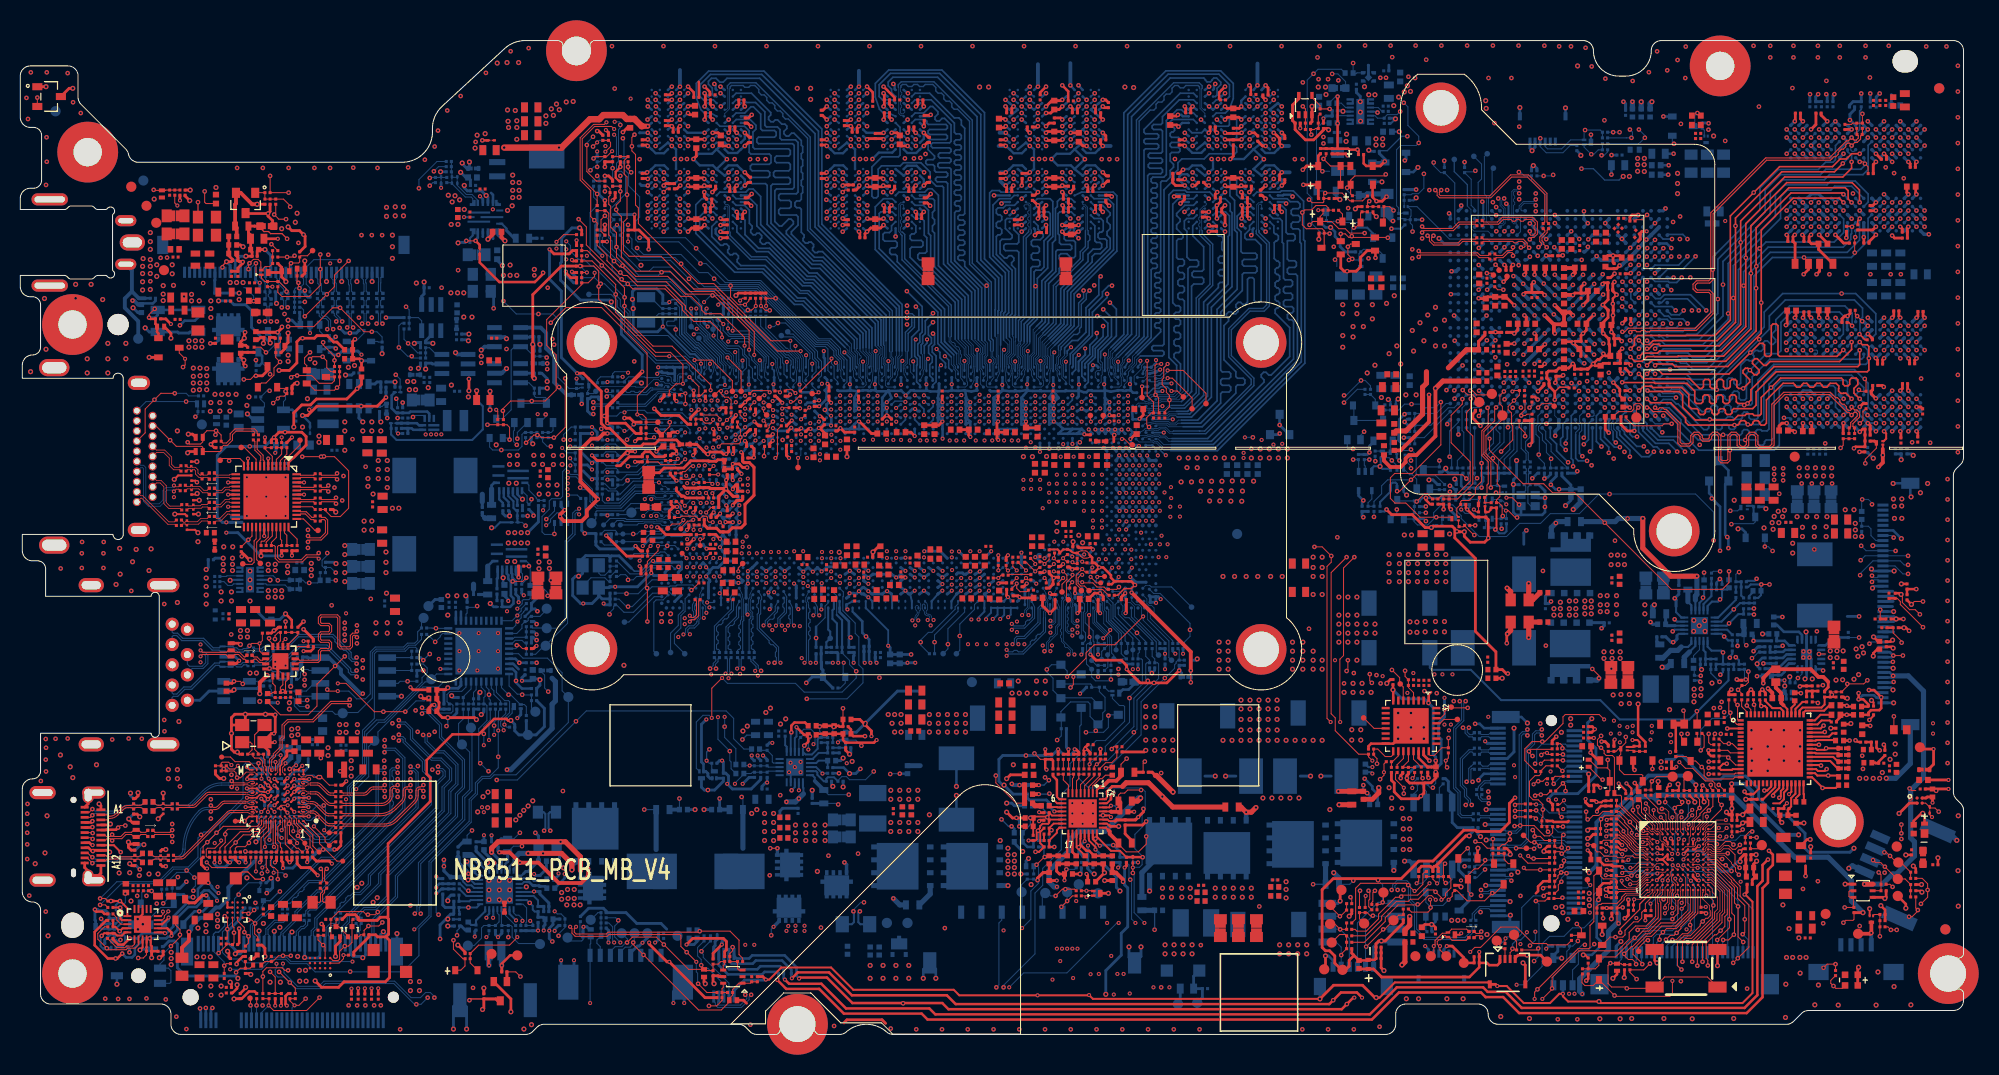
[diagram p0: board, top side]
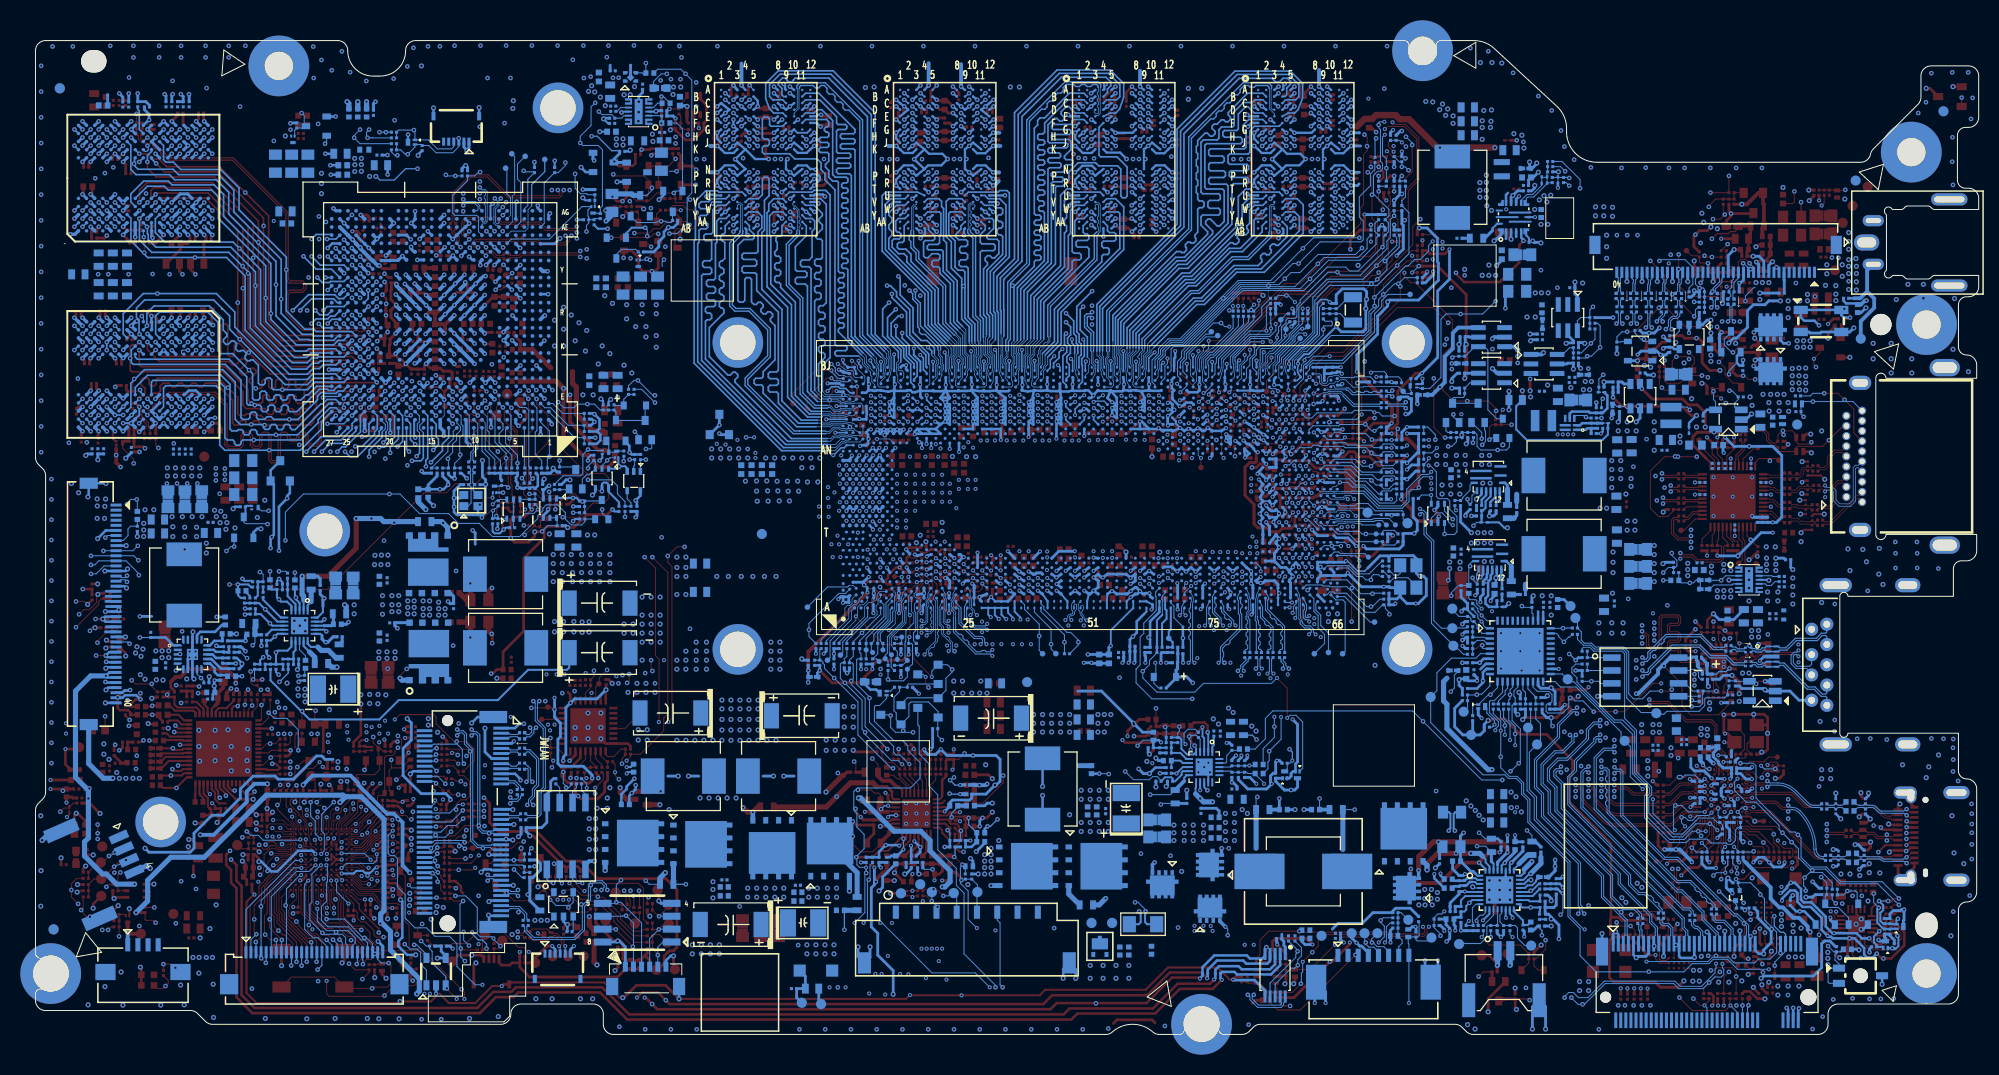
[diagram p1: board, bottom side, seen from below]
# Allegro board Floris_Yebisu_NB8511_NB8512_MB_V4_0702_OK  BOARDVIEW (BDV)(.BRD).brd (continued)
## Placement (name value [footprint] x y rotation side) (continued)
PR634  0201WMF1002TCE~~MCR006YRTF1002~~WR02X1002FAL~~RC0201FR-0710KL  [R0201]  101.22 19.12 0 bottom
PR635  res  [R0402]  99.44 22.81 0 top
PR636  0402WGJ0000TCE+0402WGJ0000TJE~~RC1005J000CS~~RC0402JR-070RL+RC0402JR-130RL~~RM04JTN0  [R0402_0D65]  101.09 22.55 0 top
PR637  0402WGJ0101TCE~~RC0402JR-07100RL~~RM04JTN101~~RC1005J101CS  [R0402]  99.5 21.35 180 top
PR638  0402WGJ0000TCE+0402WGJ0000TJE~~RC1005J000CS~~RC0402JR-070RL+RC0402JR-130RL~~RM04JTN0  [R0402_0D65]  99.5 20.52 180 top
PR639  0603WAF220KT5E~~RC0603FR-072R2L  [R0603]  131.32 23.31 270 top
PR640  res  [R0402]  107.69 15.57 270 top
PR641  res  [R0402]  105.92 17.22 270 top
PR642  res  [R0402]  107.69 17.22 270 top
PR643  0402WGF6800TCE~~RC0402FR-07680RL~~RM04FTN6800  [R0402]  105.03 17.22 90 top
PR644  0603WAF220KT5E~~RC0603FR-072R2L  [R0603]  110.62 12.9 90 bottom
PR645  res  [R0402]  101.47 15.57 270 top
PR646  res  [R0402]  102.36 17.22 270 top
PR647  res  [R0402]  101.47 17.22 270 top
PR648  0402WGF6800TCE~~RC0402FR-07680RL~~RM04FTN6800  [R0402]  104.14 17.22 90 top
PR649  0201WMJ0000TCE+0201WMJ0000TJE~~MCR006YRTJ000~~RC0201JR-070RL+RC0201JR-130RL~~WR02X000PAL  [R0201]  105.41 25.92 270 top
PR650  0402WGF1002TCE~~RM04FTN1002~~RC0402FR-0710KL  [R0402]  99.44 23.7 180 top
PR651  0402WGF2001TCE~~RC1005F202CS~~RC0402FR-072KL~~RM04FTN2001  [R0402]  99.44 24.58 180 top
PR652  0201WMF3302TCE+0201WMF3302TEE~~MCR006YRTF3302~~RC0201FR-0733KL~~WR02X3302FAL  [R0201]  99.74 24.61 0 bottom
PR653  0201WGF1302TCE~~RC0201FR-0713KL  [R0201]  99.57 23.7 0 bottom
PR654  MCR006YRTF1003~~RC0201FR-07100KL~~WR02X1003FAL~~0201WMF1003TCE+0201WMF1003TEE  [R0201]  109.73 17.22 270 bottom
PR655  0201WMJ0101TCE~~MCR006YRTJ101~~RC0201JR_07100RL~~WR02X101 JAL  [R0201]  107.03 27.4 90 top
PR656  0201WMJ0000TCE+0201WMJ0000TJE~~MCR006YRTJ000~~RC0201JR-070RL+RC0201JR-130RL~~WR02X000PAL  [R0201]  105.92 25.92 270 top
PR657  0201WMJ0000TCE+0201WMJ0000TJE~~MCR006YRTJ000~~RC0201JR-070RL+RC0201JR-130RL~~WR02X000PAL  [R0201]  106.42 25.92 270 top
PR658  0201WMF430JTCE~~RC0201FR-0743RL  [R0201]  106.02 27.4 90 top
PR659  SHUNT_LOCAL  [SHUNT_0201]  109.73 17.22 90 top
PR660  0201WMJ0000TCE+0201WMJ0000TJE~~MCR006YRTJ000~~RC0201JR-070RL+RC0201JR-130RL~~WR02X000PAL  [R0201]  101.85 25.92 270 top
PR661  0201WMF1100TCE~~RC0201FR-07110RL  [R0201]  108.41 28.37 0 top
PR662  0201WMJ0000TCE+0201WMJ0000TJE~~MCR006YRTJ000~~RC0201JR-070RL+RC0201JR-130RL~~WR02X000PAL  [R0201]  101.22 19.76 180 top
PR663  0201WMJ0000TCE+0201WMJ0000TJE~~MCR006YRTJ000~~RC0201JR-070RL+RC0201JR-130RL~~WR02X000PAL  [R0201]  101.22 18.49 180 bottom
PR664  0201WMJ0000TCE+0201WMJ0000TJE~~MCR006YRTJ000~~RC0201JR-070RL+RC0201JR-130RL~~WR02X000PAL  [R0201]  100.18 19.12 180 bottom
PR702  0201WMJ0000TCE+0201WMJ0000TJE~~MCR006YRTJ000~~RC0201JR-070RL+RC0201JR-130RL~~WR02X000PAL  [R0201]  42.06 84.25 270 bottom
PR703  SHUNT_LOCAL  [SHUNT_0201]  43.1 84.25 270 bottom
PR704  0603WAJ047JT5E~~RC0603JR-074R7L  [R0603]  49.53 78.51 0 bottom
PR705  0201WMJ0104TCE+0201WMJ0104TEE~~MCR006YRTJ104~~RC0201JR-07100KL~~WR02X104JAL  [R0201]  40.94 84.25 270 bottom
PR706  SHUNT_LOCAL  [SHUNT_0201]  41.5 84.25 270 bottom
PR707  SHUNT_LOCAL  [SHUNT_0201]  42.57 84.25 270 bottom
PR708  0201WMJ0000TCE+0201WMJ0000TJE~~MCR006YRTJ000~~RC0201JR-070RL+RC0201JR-130RL~~WR02X000PAL  [R0201]  42.26 86.08 0 bottom
PR709  0201WMJ0000TCE+0201WMJ0000TJE~~MCR006YRTJ000~~RC0201JR-070RL+RC0201JR-130RL~~WR02X000PAL  [R0201]  42.26 85.57 0 bottom
PR712  0201WMJ0104TCE~~MCR006YRTJ104~~RC0201JR-07100KL~~WR02X104JAL  [R0201]  42.26 85.06 180 bottom
PR814  0603WAJ010JT5E~~RC1608J1R0CS~~RC0603JR-071RL~~RM06JTN1R0  [R0603]  153.26 50.57 180 bottom
PR815  0603WAJ010JT5E~~RC1608J1R0CS~~RC0603JR-071RL~~RM06JTN1R0  [R0603]  164.46 44.52 90 bottom
PR816  0603WAF220KT5E~~RC0603FR-072R2L  [R0603]  161.67 41.48 180 bottom
PR817  0603WAF220KT5E~~RC0603FR-072R2L  [R0603]  170.6 40.52 0 bottom
PR818  0201WMJ0474TCE+0201WMJ0474TEE~~MCR006YRTJ474~~RC0201JR-07470KL~~WR02X474 JAL  [R0201]  169.1 39.41 0 bottom
PR819  0402WGJ0000TCE+0402WGJ0000TJE~~RC1005J000CS~~RC0402JR-070RL+RC0402JR-130RL~~RM04JTN0  [R0402_0D65]  165.02 36.5 90 bottom
PR820  0402WGJ0000TCE+0402WGJ0000TJE~~RC1005J000CS~~RC0402JR-070RL+RC0402JR-130RL~~RM04JTN0  [R0402_0D65]  166.06 44.42 270 bottom
PR821  0201WMF1002TCE~~MCR006YRTF1002~~WR02X1002FAL~~RC0201FR-0710KL  [R0201]  165.11 35.16 270 bottom
PR822  0201WMJ0104TCE~~MCR006YRTJ104~~RC0201JR-07100KL~~WR02X104JAL  [R0201]  167.04 44.41 180 bottom
PR823  0402WGJ0000TCE+0402WGJ0000TJE~~RC1005J000CS~~RC0402JR-070RL+RC0402JR-130RL~~RM04JTN0  [R0402_0D65]  168.52 44.44 270 bottom
PR824  RC0201FR-0720K5L~#~0201WMF2052TCE  [R0201]  170.21 41.98 180 bottom
PR825  0201WMJ0000TJE~#~RC0201JR-130RL~#~MCR006YRTJ000~#~RC0201JR-070RL~#~RC0201JR-070RL/RC0201JR-130RL~#~RC0201JR-130RL/RC0201JR-070RL~#~WR02X000PAL  [R0201]  169.98 44.64 0 bottom
PR826  RC0201FR-074K32L~#~0201WMF4321TEE~#~RC-01W4321FT  [R0201]  169.96 42.79 90 bottom
PR827  RC0201FR-07100RL~~WR02X1000FAL~~0201WMF1000TCE~~MCR006YRTF1000  [R0201]  168.47 36.25 270 bottom
PR828  RC0402FR-07309RL~#~0402WGF3090TCE  [R0402]  171.28 43.74 180 bottom
PR829  0201WMJ0000TJE~#~RC0201JR-130RL~#~MCR006YRTJ000~#~RC0201JR-070RL~#~RC0201JR-070RL/RC0201JR-130RL~#~RC0201JR-130RL/RC0201JR-070RL~#~WR02X000PAL  [R0201]  169.2 44.38 90 bottom
PR830  0201WMF6191TCE~#~RC0201FR-076K19L~#~WR02X6191FAL~#~0201WMF6191TCE+0201WMF6191TEE~#~MCR006YRTF6191  [R0201]  169.2 43.34 270 bottom
PR833  RC0805FR-071R5L~~0805W8F150KT5E~~RM10FTN1R50  [R0805]  147.88 42.85 180 top
PR835  0201WMJ0000TCE+0201WMJ0000TJE~~MCR006YRTJ000~~RC0201JR-070RL+RC0201JR-130RL~~WR02X000PAL  [R0201]  166.8 45.24 90 bottom
PR836  RC0201FR-07100RL~~WR02X1000FAL~~0201WMF1000TCE~~MCR006YRTF1000  [R0201]  169.1 38.85 0 bottom
PR837  0201WMJ0000TCE+0201WMJ0000TJE~~MCR006YRTJ000~~RC0201JR-070RL+RC0201JR-130RL~~WR02X000PAL  [R0201]  168.85 38.06 90 bottom
PR838  0201WMJ0000TCE+0201WMJ0000TJE~~MCR006YRTJ000~~RC0201JR-070RL+RC0201JR-130RL~~WR02X000PAL  [R0201]  169.25 36.51 180 bottom
PR839  RC0201FR-0716K5L~#~0201WMF1652TCE+0201WMF1652TEE  [R0201]  170.51 42.79 270 bottom
PR848  0603WAJ010JT5E~~RC1608J1R0CS~~RC0603JR-071RL~~RM06JTN1R0  [R0603]  163.45 36.57 180 bottom
PR849  0603WAJ010JT5E~~RC1608J1R0CS~~RC0603JR-071RL~~RM06JTN1R0  [R0603]  161.7 37.8 90 bottom
PR850  RC0805FR-071R5L~~0805W8F150KT5E~~RM10FTN1R50  [R0805]  147.88 40.66 180 top
PR852  0201WMF1503TCE+0201WMF1503TEE~~WR02X1503FAL~~MCR006YRTF1503~~RC0201FR-07150KL  [R0201]  165.95 36.49 0 bottom
PR859  0201WMJ0513TCE~~MCR006YRTJ513~~RC0201JR-0751KL~~WR02X513JAL  [R0201]  166.72 36.76 270 bottom
PR860  RC0201FR-07100RL~~WR02X1000FAL~~0201WMF1000TCE~~MCR006YRTF1000  [R0201]  167.93 36.25 90 bottom
PR861  0201WMJ0513TCE~~MCR006YRTJ513~~RC0201JR-0751KL~~WR02X513JAL  [R0201]  169.25 35.98 0 bottom
PR901  MCR006YRTF1003~~RC0201FR-07100KL~~WR02X1003FAL~~0201WMF1003TCE  [R0201]  68.45 26.74 0 bottom
PR902  MCR006YRTF1003~~RC0201FR-07100KL~~WR02X1003FAL~~0201WMF1003TCE  [R0201]  69.34 25.51 90 bottom
PR903  0201WMJ0105TCE~~MCR006YRTJ105~~RC0201JR-071ML~~WR02X105JAL  [R0201]  50.95 63.73 180 bottom
PR904  0201WMJ0000TCE+0201WMJ0000TJE~~MCR006YRTJ000~~RC0201JR-070RL+RC0201JR-130RL~~WR02X000PAL  [R0201]  39.72 66.7 0 bottom
PR905  0402WGJ0000TCE+0402WGJ0000TJE~~RC1005J000CS~~RC0402JR-070RL+RC0402JR-130RL~~RM04JTN0  [R0402_0D65]  43.08 71.55 270 bottom
PR906  0201WMJ0000TCE+0201WMJ0000TJE~~MCR006YRTJ000~~RC0201JR-070RL+RC0201JR-130RL~~WR02X000PAL  [R0201]  47.09 60.37 270 top
PR907  0201WMJ0103TCE+0201WMJ0103TJE~~MCR006YRTJ103~~RC0201JR-0710KL~~WR02X103JAL  [R0201]  50.7 67.13 90 bottom
PR909  0201WMJ0000TCE+0201WMJ0000TJE~~MCR006YRTJ000~~RC0201JR-070RL+RC0201JR-130RL~~WR02X000PAL  [R0201]  38.1 70.13 0 bottom
PR910  0201WMJ0000TCE+0201WMJ0000TJE~~MCR006YRTJ000~~RC0201JR-070RL+RC0201JR-130RL~~WR02X000PAL  [R0201]  50.95 59.1 90 bottom
PR911  SHUNT_LOCAL  [SHUNT_0402]  27.46 43.91 90 bottom
PR912  0201WMJ0000TCE+0201WMJ0000TJE~~MCR006YRTJ000~~RC0201JR-070RL+RC0201JR-130RL~~WR02X000PAL  [R0201]  29.84 45.54 180 bottom
PR913  0402WGJ0000TCE+0402WGJ0000TJE~~RC1005J000CS~~RC0402JR-070RL+RC0402JR-130RL~~RM04JTN0  [R0402_0D65]  29.97 44.78 180 bottom
PR914  0201WMJ0104TCE~~MCR006YRTJ104~~RC0201JR-07100KL~~WR02X104JAL  [R0201]  30.1 46.3 270 bottom
PR915  SHUNT_LOCAL  [SHUNT_0402]  27.46 44.8 90 bottom
PR916  0201WMJ0000TCE+0201WMJ0000TJE~~MCR006YRTJ000~~RC0201JR-070RL+RC0201JR-130RL~~WR02X000PAL  [R0201]  49.83 59.1 90 bottom
PR917  0201WMJ0000TCE+0201WMJ0000TJE~~MCR006YRTJ000~~RC0201JR-070RL+RC0201JR-130RL~~WR02X000PAL  [R0201]  47.65 60.37 270 top
PR918  0201WMJ0000TCE+0201WMJ0000TJE~~MCR006YRTJ000~~RC0201JR-070RL+RC0201JR-130RL~~WR02X000PAL  [R0201]  52.07 59.1 90 bottom
PR919  0201WMJ0000TCE+0201WMJ0000TJE~~MCR006YRTJ000~~RC0201JR-070RL+RC0201JR-130RL~~WR02X000PAL  [R0201]  51.51 59.1 90 bottom
PR920  0201WMJ0000TCE+0201WMJ0000TJE~~MCR006YRTJ000~~RC0201JR-070RL+RC0201JR-130RL~~WR02X000PAL  [R0201]  39.72 67.21 0 bottom
PR921  0201WMJ0000TCE+0201WMJ0000TJE~~MCR006YRTJ000~~RC0201JR-070RL+RC0201JR-130RL~~WR02X000PAL  [R0201]  38.1 69.57 0 bottom
PR930  SHUNT_LOCAL  [SHUNT_0201]  188.31 22.15 90 top
PR1012  0201WMJ0104TCE~~MCR006YRTJ104~~RC0201JR-07100KL~~WR02X104JAL  [R0201]  13.59 70.56 0 top
PR1013  0201WMJ0104TCE~~MCR006YRTJ104~~RC0201JR-07100KL~~WR02X104JAL  [R0201]  15.24 14.42 0 bottom
PR1101  0402WGJ0000TCE+0402WGJ0000TJE~~RC1005J000CS~~RC0402JR-070RL+RC0402JR-130RL~~RM04JTN0  [R0402_0D65]  172.31 35.33 0 bottom
PR1102  0201WMF1002TCE~~MCR006YRTF1002~~WR02X1002FAL~~RC0201FR-0710KL  [R0201]  172.33 37.12 180 bottom
PR1103  0201WMF1002TCE~~MCR006YRTF1002~~WR02X1002FAL~~RC0201FR-0710KL  [R0201]  173.19 36.87 90 bottom
PR1104  0402WGJ0000TCE+0402WGJ0000TJE~~RC1005J000CS~~RC0402JR-070RL+RC0402JR-130RL~~RM04JTN0  [R0402_0D65]  172.85 39.49 180 bottom
PR1105  0201WMF1002TCE~~MCR006YRTF1002~~WR02X1002FAL~~RC0201FR-0710KL  [R0201]  174.79 34.67 180 bottom
PR1107  0201WMF1002TCE~~MCR006YRTF1002~~WR02X1002FAL~~RC0201FR-0710KL  [R0201]  171.82 36.06 180 bottom
PR1108  RC0201FR-0716KL~~0201WMF1602TCE+0201WMF1602TEE  [R0201]  173.1 37.98 270 bottom
PR1109  MCR006YRTF2002~~RC0201FR-0720KL~~0201WMF2002TCE+0201WMF2002TEE~~WR02X2002FAL  [R0201]  172.32 38.23 0 bottom
PR1111  0201WMF1002TCE~~MCR006YRTF1002~~WR02X1002FAL~~RC0201FR-0710KL  [R0201]  172.61 36.33 270 bottom
PR1150  CC0201KRX5R8BB103+CC0201KRX7R8BB103~~C0201X5R103K250NTA~~0201X103K250NT  [C0201]  171.53 37.97 90 bottom
PR1201  0201WMJ0104TCE~~MCR006YRTJ104~~RC0201JR-07100KL~~WR02X104JAL  [R0201]  129.64 90.56 180 bottom
PR1202  0402WGJ0000TCE+0402WGJ0000TJE~~RC1005J000CS~~RC0402JR-070RL+RC0402JR-130RL~~RM04JTN0  [R0402_0D65]  129.48 89.88 0 bottom
PR1203  0402WGJ0000TCE+0402WGJ0000TJE~~RC1005J000CS~~RC0402JR-070RL+RC0402JR-130RL~~RM04JTN0  [R0402_0D65]  131.06 94.8 0 bottom
PR1204  RC1608J000CS~~RC0603JR-070RL~~RM06JTN0~~0603WAJ0000T5E  [R0603]  132.27 88.11 0 bottom
PR1206  0402WGJ0000TCE+0402WGJ0000TJE~~RC1005J000CS~~RC0402JR-070RL+RC0402JR-130RL~~RM04JTN0  [R0402_0D65]  129.46 91.83 0 bottom
PR1207  SHUNT_LOCAL  [SHUNT_0603]  130.63 93.32 90 bottom
PR6157  0201WMJ0106TCE//RC0201JR-0710ML~~RC0201JR-0710ML  [R0201]  14.02 8.4 90 bottom
PRT501  NCP15XH103F03RC  [R0402_NTC_0D55]  87.5 26.11 90 bottom
PRT601  NCP15WF104F03RC~~SDNT1005X104F4250FTF  [R0402_NTC_0D65]  133.48 22.68 0 bottom
PRT602  NCP15WF104F03RC~~SDNT1005X104F4250FTF  [R0402_NTC_0D65]  132.66 26.26 90 bottom
PSH101  SHUNT_LOCAL  [SHUNT_0402]  47.75 12.11 180 top
PSH104  SHUNT_LOCAL  [SHUNT_0805]  15.31 78.94 0 top
PSH105  SHUNT_LOCAL  [SHUNT_0805]  15.31 80.72 0 top
PSH201  SHUNT_LOCAL  [SHUNT_0805]  51.05 44.27 90 top
PSH202  SHUNT_LOCAL  [SHUNT_0805]  52.83 44.27 90 top
PSH203  SHUNT_LOCAL  [SHUNT_0805]  33.6 46.15 180 bottom
PSH204  SHUNT_LOCAL  [SHUNT_0805]  33.6 47.83 180 bottom
PSH205  SHUNT_LOCAL  [SHUNT_0805]  33.6 44.47 180 bottom
PSH206  SHUNT_LOCAL  [SHUNT_0201]  47.27 42.16 180 bottom
PSH306  SHUNT_LOCAL  [SHUNT_0201]  48.77 50.49 180 bottom
PSH401  SHUNT_LOCAL  [SHUNT_0201]  36.84 60.27 180 bottom
PSH402  SHUNT_LOCAL  [SHUNT_0201]  28.57 59.59 270 bottom
PSH403  SHUNT_LOCAL  [SHUNT_0805]  39.5 62.56 0 bottom
PSH404  SHUNT_LOCAL  [SHUNT_0805]  29.59 65.1 0 bottom
PSH501  SHUNT_LOCAL  [SHUNT_0805]  81.02 21.16 180 bottom
PSH502  SHUNT_LOCAL  [SHUNT_0805]  81.02 19.48 180 bottom
PSH601  SHUNT_LOCAL  [SHUNT_0805]  118.36 10.49 270 top
PSH602  SHUNT_LOCAL  [SHUNT_0805]  120.14 10.49 270 top
PSH603  SHUNT_LOCAL  [SHUNT_0805]  121.92 10.49 270 top
PSH706  LOCAL_SHUNT  [SHUNT_0402]  44.3 85.39 270 bottom
PSH707  SHUNT_LOCAL  [SHUNT_0805]  45.01 76.88 180 bottom
PSH708  SHUNT_LOCAL  [SHUNT_0201]  45.31 77.24 90 top
PSH709  SHUNT_LOCAL  [SHUNT_0201]  46.43 88.16 180 top
PSH806  LOCAL_SHUNT  [SHUNT_0805]  160.32 44.27 270 bottom
PSH807  LOCAL_SHUNT  [SHUNT_0805]  158.55 35.45 270 top
PSH808  LOCAL_SHUNT  [SHUNT_0805]  156.87 35.45 270 top
PSH809  LOCAL_SHUNT  [SHUNT_0805]  162.05 44.27 270 bottom
PSH901  SHUNT_LOCAL  [SHUNT_0402]  50.65 66.16 270 bottom
PSH902  SHUNT_LOCAL  [SHUNT_0402]  39.32 65.05 90 bottom
PSH903  SHUNT_LOCAL  [SHUNT_0402]  54.48 63.07 270 bottom
PSH904  SHUNT_LOCAL  [SHUNT_0402]  43.03 69.67 0 bottom
PSH930  SHUNT_LOCAL  [SHUNT_0402]  187.4 26.11 90 top
PSH1101  LOCAL_SHUNT  [SHUNT_0805]  175.26 52.78 90 bottom
PSH1102  LOCAL_SHUNT  [SHUNT_0805]  176.91 52.78 90 bottom
PSH1103  LOCAL_SHUNT  [SHUNT_0805]  178.88 39.43 270 top
PSH1104  LOCAL_SHUNT  [SHUNT_0805]  178.59 52.78 90 bottom
PTP101  40MIL  [TPAD40-OP]  101.09 13.94 180 bottom
PTP102  40MIL  [TPAD40-OP]  98.75 14.04 180 bottom
PTP103  40MIL  [TPAD40-OP]  103.25 14.04 270 bottom
PTP104  40MIL  [TPC1]  51.26 8.91 180 bottom
PTP105  40MIL  [TPAD40-OP]  106.3 13.92 180 bottom
PTP106  40MIL  [TPAD40-OP]  104.39 14.81 180 bottom
PTP107  40MIL  [TPAD40-OP]  87.5 11 180 bottom
PTP108  40MIL  [TPAD40-OP]  85.47 11 180 bottom
PTP109  40MIL  [TPC1]  44.14 8.76 180 bottom
PU101  BQ25710RSNR  [NB_QFN32_4X4X1]  47.25 14.25 180 bottom
PU201  RT6258BGQUF  [NB_QFN12_3X3X0D6]  48.21 47.29 0 bottom
PU301  RT6258CGQUF  [NB_QFN12_3X3X0D6]  48.36 55.01 0 bottom
PU401  SY8843QWC  [NB_QFN7_1D5X1D5X0D9]  40.33 60.14 0 bottom
PU402  RT8096CHGJ6  [NB_TSOT23_6_3D1X1D7X1]  33.4 62.94 180 bottom
PU501  RT6543A  [NB_QFN20_3X3X0D8]  76.39 26.36 270 bottom
PU601  RT3612  [NB_QFN32_4X4X0D8]  104.77 21.79 270 top
PU701  TPS51487XRJER  [NB_VQFN18_3X3X1]  45.87 80.59 90 bottom
PU802  RT8816AGQW  [NB_QFN20_3X3X0D8]  165.61 40.31 270 bottom
PU901  EM5201BJ-45  [NB_SOT23_6_2D9X1D6X1D45]  48.05 65.2 0 bottom
PU902  G2898KD1U  [NB_TDF14_3X2X0D8]  22.65 44.83 270 bottom
PU903  EM5201BJ-45  [NB_SOT23_6_2D9X1D6X1D45]  42.87 66.11 180 bottom
PU904  EM5201BJ-45  [NB_SOT23_6_2D9X1D6X1D45]  48.05 68.76 0 bottom
PU906  EM5201BJ-45  [NB_SOT23_6_2D9X1D6X1D45]  40.53 70.68 270 bottom
PU910  SGM2578YG/TR  [BGA4_0D9X0D9X0D405_0D5]  187.32 23.06 0 top
PU1101  SY8286A  [NB_QFN20_3X3X0D9_0D45_SY8286]  176.17 37.47 180 bottom
PU1201  G2898KDIU  [NB_TDF14_3X2X0D8]  132.16 91 90 bottom
PU1202  WL2831D10-4/TR  [NB_DFN5_1D2X1D2X0D4]  132.96 94.45 180 bottom
QA1  LBSS139DW1T1G  [NB_SOT363_2X1D25X1D1]  181.74 14.17 270 top
QE2  LMN2500N3T5G  [NB_SOT883_1D05X0D65X0D53]  182.56 11.38 180 top
QE3  LBSS139DW1T1G  [NB_SOT363_2X1D25X1D1]  70.28 5.7 90 top
QE4  2N7002~~2N7002LT1G~~L2N7002LT1G  [SOT-23_3_2D9X1D3X1D11]  154.99 9.78 270 top
QL1  2N7002~~2N7002LT1G~~L2N7002LT1G  [SOT-23_3_2D9X1D3X1D11]  14.65 67.71 90 top
QL4  2N7002~~2N7002LT1G~~L2N7002LT1G  [SOT-23_3_2D9X1D3X1D11]  156.77 25.98 0 top
QL6  2N7002~~2N7002LT1G~~L2N7002LT1G  [SOT-23_3_2D9X1D3X1D11]  160.02 25.98 0 top
QL7  2N7002~~2N7002LT1G~~L2N7002LT1G  [SOT-23_3_2D9X1D3X1D11]  11.89 11.86 0 bottom
QL8  2N7002~~2N7002LT1G~~L2N7002LT1G  [SOT-23_3_2D9X1D3X1D11]  15.14 11.86 0 bottom
QL9  LMN2500N3T5G  [NB_SOT883_1D05X0D65X0D53]  158.17 28.18 90 top
QL10  2N7002~~2N7002LT1G~~L2N7002LT1G  [SOT-23_3_2D9X1D3X1D11]  16.25 12.32 180 top
QS1  LMBT3904LT1G  [NB_SOT-23_3_2D9X1D3X1D11]  167.51 55.57 0 bottom
QS2  LMBT3904LT1G  [NB_SOT-23_3_2D9X1D3X1D11]  124.2 60.14 0 bottom
QT1  WNM2046-3/TR  [DFN1006_3_1X0D6X0D5]  49.02 32.33 270 bottom
QT2  WNM3013-3/TR  [NB_SOT-723_3_1D2X0D8X0D55]  23.98 13.69 90 bottom
QT3  WNM3013-3/TR  [NB_SOT-723_3_1D2X0D8X0D55]  23.37 7.34 270 top
QT4  WNM3013-3/TR  [NB_SOT-723_3_1D2X0D8X0D55]  32.71 10.13 270 top
QT5  WNM3013-3/TR  [NB_SOT-723_3_1D2X0D8X0D55]  31.14 10.13 270 top
QU1  LBSS139DW1T1G  [NB_SOT363_2X1D25X1D1]  53.34 51.38 180 bottom
QU2  LMN2500N3T5G  [NB_SOT883_1D05X0D65X0D53]  55.75 63.95 90 bottom
QU4  LMBT3904LT1G  [NB_SOT-23_3_2D9X1D3X1D11]  107.29 31.52 270 bottom
QU5  LMBT3904LT1G  [NB_SOT-23_3_2D9X1D3X1D11]  103.63 35.51 270 bottom
QU6  LMBT3904LT1G  [NB_SOT-23_3_2D9X1D3X1D11]  103.63 32.2 270 bottom
QU7  WNM2046-3/TR  [DFN1006_3_1X0D6X0D5]  108.05 33.65 90 bottom
QV1  LMN2500N3T5G  [NB_SOT883_1D05X0D65X0D53]  136.66 81.31 0 bottom
QV2  LMN2500N3T5G  [NB_SOT883_1D05X0D65X0D53]  141.51 50.86 90 top
QV3  LBSS139DW1T1G  [NB_SOT363_2X1D25X1D1]  144.52 51.8 180 bottom
QV4  LBSS139DW1T1G  [NB_SOT363_2X1D25X1D1]  135.78 54.83 0 bottom
QV5  LMN2500N3T5G  [NB_SOT883_1D05X0D65X0D53]  144.14 52.26 90 top
QV6  LBSS139DW1T1G  [NB_SOT363_2X1D25X1D1]  140.92 51.89 0 bottom
QV7  2N7002~~2N7002LT1G~~L2N7002LT1G  [SOT-23_3_2D9X1D3X1D11]  134.4 59.56 0 bottom
QV8  LMN2500N3T5G  [NB_SOT883_1D05X0D65X0D53]  134.34 57.19 180 bottom
QV9  LMN2500N3T5G  [NB_SOT883_1D05X0D65X0D53]  132.21 76.05 0 bottom
QV10  LMN2500N3T5G  [NB_SOT883_1D05X0D65X0D53]  170.01 51.95 270 bottom
QV11  2N7002~~2N7002LT1G~~L2N7002LT1G  [SOT-23_3_2D9X1D3X1D11]  132.32 85.02 90 bottom
QV12  2N7002~~2N7002LT1G~~L2N7002LT1G  [SOT-23_3_2D9X1D3X1D11]  134.36 77.54 180 bottom
QV14  2N7002~~2N7002LT1G~~L2N7002LT1G  [SOT-23_3_2D9X1D3X1D11]  135.64 85.98 90 bottom
QV17  LMN2500N3T5G  [NB_SOT883_1D05X0D65X0D53]  166.26 88.26 0 bottom
QV18  2N7002~~2N7002LT1G~~L2N7002LT1G  [SOT-23_3_2D9X1D3X1D11]  132.01 81.71 0 bottom
QV19  2N7002~~2N7002LT1G~~L2N7002LT1G  [SOT-23_3_2D9X1D3X1D11]  163.96 89.57 270 bottom
QV20  2N7002~~2N7002LT1G~~L2N7002LT1G  [SOT-23_3_2D9X1D3X1D11]  128.79 82.14 180 bottom
QV21  LMN2500N3T5G  [NB_SOT883_1D05X0D65X0D53]  183.37 58.33 90 top
QV22  2N7002~~2N7002LT1G~~L2N7002LT1G  [SOT-23_3_2D9X1D3X1D11]  171.11 50 0 bottom
QV23  LMN2500N3T5G  [NB_SOT883_1D05X0D65X0D53]  135.43 57.41 270 bottom
QV24  LMN2500N3T5G  [NB_SOT883_1D05X0D65X0D53]  146.37 53.75 180 bottom
QW2  2N7002~~2N7002LT1G~~L2N7002LT1G  [SOT-23_3_2D9X1D3X1D11]  142.77 16.33 0 top
QW3  2N7002~~2N7002LT1G~~L2N7002LT1G  [SOT-23_3_2D9X1D3X1D11]  146.3 15.82 0 top
QX42  PPMT20V3  [NB_SOT23-3_2D9X1D83X1D2]  22.22 81.99 180 top
R16  0201WMJ0104TCE~~MCR006YRTJ104~~RC0201JR-07100KL~~WR02X104JAL  [R0201]  15.75 83 270 top
R17  0402WGJ0000TCE+0402WGJ0000TJE~~RC1005J000CS~~RC0402JR-070RL+RC0402JR-130RL~~RM04JTN0  [R0402_0D65]  136.95 9.98 0 top
R18  0402WGJ0000TCE+0402WGJ0000TJE~~RC1005J000CS~~RC0402JR-070RL+RC0402JR-130RL~~RM04JTN0  [R0402_0D65]  136.95 9.12 0 top
R19  0201WMJ0000TCE+0201WMJ0000TJE~~MCR006YRTJ000~~RC0201JR-070RL+RC0201JR-130RL~~WR02X000PAL  [R0201]  143.13 9.55 0 top
R20  0201WMJ0000TCE+0201WMJ0000TJE~~MCR006YRTJ000~~RC0201JR-070RL+RC0201JR-130RL~~WR02X000PAL  [R0201]  143.13 10.16 0 top
RA3  WR02X102JAL~~RC0201JR-071KL~~0201WMJ0102TCE+0201WMJ0102TJE~~MCR006YRTJ102  [R0201]  176.73 33.04 270 top
RA4  WR02X102JAL~~RC0201JR-071KL~~0201WMJ0102TCE+0201WMJ0102TJE~~MCR006YRTJ102  [R0201]  176.17 34.11 270 top
RA10  0201WMJ0000TCE+0201WMJ0000TJE~~MCR006YRTJ000~~RC0201JR-070RL+RC0201JR-130RL~~WR02X000PAL  [R0201]  167.28 25.68 0 top
RA11  0201WMF220JTCE~~RC0201FR-0722RL~~RM02FTN220  [R0201]  167.28 26.9 0 top
RA13  0201WMF330JTCE~~MCR006YRTF33R0~~RC0201FR-0733RL~~WR02X33R0FAL  [R0201]  169.77 33.25 270 top
RA16  0201WMJ0104TCE~~MCR006YRTJ104~~RC0201JR-07100KL~~WR02X104JAL  [R0201]  163.27 27.66 270 top
RA17  0402WGJ0000TCE+0402WGJ0000TJE~~RC1005J000CS~~RC0402JR-070RL+RC0402JR-130RL~~RM04JTN0  [R0402_0D65]  185.04 26.24 270 top
RA18  0402WGJ0000TCE+0402WGJ0000TJE~~RC1005J000CS~~RC0402JR-070RL+RC0402JR-130RL~~RM04JTN0  [R0402_0D65]  183.36 38.38 90 top
RA19  0402WGJ0000TCE+0402WGJ0000TJE~~RC1005J000CS~~RC0402JR-070RL+RC0402JR-130RL~~RM04JTN0  [R0402_0D65]  174.37 33.73 180 bottom
RA20  0201WMJ0222TCE+0201WMJ0222TJE~#~WR02X222 JAL~#~0201WMJ0222TJE~#~MCR006YRTJ222~#~RC0201JR-072K2L  [R0201]  178.86 30.81 0 top
RA23  RES  [R0402]  181.2 31.52 0 top
RA24  RES  [R0402]  181.2 32.33 0 top
RA32  RC1608J000CS~~RC0603JR-070RL~~RM06JTN0~~0603WAJ0000T5E  [R0603]  162.38 30.59 0 top
RA33  0805W8J0000T5E~~RC0805JR-070RL~~RM10JTN0  [R0805]  174.09 14.75 90 top
RA36  WR02X102JAL~~RC0201JR-071KL~~0201WMJ0102TCE+0201WMJ0102TJE~~MCR006YRTJ102  [R0201]  177.29 34.11 90 top
RA233  0402WGJ0000TCE+0402WGJ0000TJE~~RC1005J000CS~~RC0402JR-070RL+RC0402JR-130RL~~RM04JTN0  [R0402_0D65]  175.13 21.22 270 top
RA234  0201WMJ0000TCE+0201WMJ0000TJE~~MCR006YRTJ000~~RC0201JR-070RL+RC0201JR-130RL~~WR02X000PAL  [R0201]  167.28 29.13 0 top
RA235  0201WMF220JTCE~~RC0201FR-0722RL~~RM02FTN220  [R0201]  167.28 28.57 0 top
RA236  0201WMJ0222TCE+0201WMJ0222TJE~#~WR02X222 JAL~#~0201WMJ0222TJE~#~MCR006YRTJ222~#~RC0201JR-072K2L  [R0201]  177.95 33.53 270 top
RA237  0201WMJ0222TCE+0201WMJ0222TJE~#~WR02X222 JAL~#~0201WMJ0222TJE~#~MCR006YRTJ222~#~RC0201JR-072K2L  [R0201]  179.07 33.53 90 top
RA238  0201WMJ0203TCE~~MCR006YRTJ203~~RC0201JR-0720KL~~WR02X203JAL  [R0201]  178.51 33.53 90 top
RA239  0201WMJ0104TCE~~MCR006YRTJ104~~RC0201JR-07100KL~~WR02X104JAL  [R0201]  168.5 29.59 0 top
RA240  RC0201FR-07100RL~~WR02X1000FAL~~0201WMF1000TCE~~MCR006YRTF1000  [R0201]  183.89 27.76 270 top
RA241  RC0201FR-07100RL~~WR02X1000FAL~~0201WMF1000TCE~~MCR006YRTF1000  [R0201]  182.81 28.83 180 top
RA242  res  [R0201]  184.91 43.25 270 top
RA243  res  [R0201]  186.08 43.1 90 top
RA244  res  [R0201]  184.25 40.97 180 top
RA245  res  [R0201]  184.96 40.1 180 top
RA246  0201WMJ0103TCE+0201WMJ0103TJE~~MCR006YRTJ103~~RC0201JR-0710KL~~WR02X103JAL  [R0201]  183.77 14.81 180 top
RA247  0201WMJ0104TCE~~MCR006YRTJ104~~RC0201JR-07100KL~~WR02X104JAL  [R0201]  180.85 12.27 90 top
RA248  0201WMJ0000TCE+0201WMJ0000TJE~~MCR006YRTJ000~~RC0201JR-070RL+RC0201JR-130RL~~WR02X000PAL  [R0201]  165.61 29.69 180 top
RB44  0201WMJ0000TCE+0201WMJ0000TJE~~MCR006YRTJ000~~RC0201JR-070RL+RC0201JR-130RL~~WR02X000PAL  [R0201]  26.16 39.9 90 top
RB45  0201WMJ0103TCE+0201WMJ0103TJE~~MCR006YRTJ103~~RC0201JR-0710KL~~WR02X103JAL  [R0201]  25.65 33.47 270 top
RB46  0201WMF2212TCE+0201WMF2212TEE~~MCR006YRTF2212~~RC0201FR-0722K1L~~WR02X2212FAL  [R0201]  26.16 33.47 270 top
RB47  0201WMJ0104TCE~~MCR006YRTJ104~~RC0201JR-07100KL~~WR02X104JAL  [R0201]  26.77 39.9 90 top
RB48  0201WMJ0103TCE+0201WMJ0103TJE~~MCR006YRTJ103~~RC0201JR-0710KL~~WR02X103JAL  [R0201]  28.65 38.78 0 top
RB49  0201WMJ0104TCE~~MCR006YRTJ104~~RC0201JR-07100KL~~WR02X104JAL  [R0201]  24.13 39.57 0 top
RB50  0201WMJ0103TCE+0201WMJ0103TJE~~MCR006YRTJ103~~RC0201JR-0710KL~~WR02X103JAL  [R0201]  28.65 38.25 0 top
RB51  0402WGJ0000TCE+0402WGJ0000TJE~~RC1005J000CS~~RC0402JR-070RL+RC0402JR-130RL~~RM04JTN0  [R0402_0D65]  24.41 33.22 90 top
RB52  0201WMJ0103TCE+0201WMJ0103TJE~~MCR006YRTJ103~~RC0201JR-0710KL~~WR02X103JAL  [R0201]  25.65 39.9 90 top
RB363  0201WMJ0000TCE+0201WMJ0000TJE~~MCR006YRTJ000~~RC0201JR-070RL+RC0201JR-130RL~~WR02X000PAL  [R0201]  22.61 36.79 0 top
RB364  0201WMJ0000TCE+0201WMJ0000TJE~~MCR006YRTJ000~~RC0201JR-070RL+RC0201JR-130RL~~WR02X000PAL  [R0201]  22.61 37.4 0 top
RB373  0402WGJ0000TCE+0402WGJ0000TJE~~RC1005J000CS~~RC0402JR-070RL+RC0402JR-130RL~~RM04JTN0  [R0402_0D65]  181.61 51.18 270 bottom
RD1  0201WMJ0471TCE~~MCR006YRTJ471~~RC0201JR-07470RL~~WR02X471JAL  [R0201]  56.89 81.48 270 bottom
RD2  0201WMJ0000TCE+0201WMJ0000TJE~~MCR006YRTJ000~~RC0201JR-070RL+RC0201JR-130RL~~WR02X000PAL  [R0201]  56.54 83.89 270 bottom
RD3  0201WMF2400TCE~~MCR006YRTF2400~~RC0201FR-07240RL~~WR02X2400FAL  [R0201]  68.27 92.66 0 top
RD4  0201WMF2400TCE~~MCR006YRTF2400~~RC0201FR-07240RL~~WR02X2400FAL  [R0201]  66.67 92.4 0 top
RD5  0201WMF2400TCE~~MCR006YRTF2400~~RC0201FR-07240RL~~WR02X2400FAL  [R0201]  86.49 92.15 0 top
RD6  0201WMF2400TCE~~MCR006YRTF2400~~RC0201FR-07240RL~~WR02X2400FAL  [R0201]  84.07 91.77 270 top
RD7  0201WMF2400TCE~~MCR006YRTF2400~~RC0201FR-07240RL~~WR02X2400FAL  [R0201]  103.6 92.05 0 top
RD8  0201WMF2400TCE~~MCR006YRTF2400~~RC0201FR-07240RL~~WR02X2400FAL  [R0201]  100.58 92.4 270 top
RD9  0201WMF2400TCE~~MCR006YRTF2400~~RC0201FR-07240RL~~WR02X2400FAL  [R0201]  121.61 92.68 0 top
RD10  0201WMF2400TCE~~MCR006YRTF2400~~RC0201FR-07240RL~~WR02X2400FAL  [R0201]  118.62 92.15 0 top
RD11  LR122WF500NT2E~~PA2512FKF7W0R005E~~MFL12KR005FT  [NB_RTC0805]  45.51 73.28 0 bottom
RD12  LR122WF500NT2E~~PA2512FKF7W0R005E~~MFL12KR005FT  [NB_RTC0805]  45.51 74.95 0 bottom
RE1  0201WMJ0103TCE+0201WMJ0103TJE~~MCR006YRTJ103~~RC0201JR-0710KL~~WR02X103JAL  [R0201]  160.83 23.85 90 top
RE2  WR02X102JAL~~RC0201JR-071KL~~0201WMJ0102TCE+0201WMJ0102TJE~~MCR006YRTJ102  [R0201]  160.27 23.85 270 top
RE3  0201WMJ0000TCE+0201WMJ0000TJE~~MCR006YRTJ000~~RC0201JR-070RL+RC0201JR-130RL~~WR02X000PAL  [R0201]  170.38 18.87 180 top
RE4  0201WMJ0000TCE+0201WMJ0000TJE~~MCR006YRTJ000~~RC0201JR-070RL+RC0201JR-130RL~~WR02X000PAL  [R0201]  164.08 23.8 270 top
RE6  0201WMJ0000TCE+0201WMJ0000TJE~~MCR006YRTJ000~~RC0201JR-070RL+RC0201JR-130RL~~WR02X000PAL  [R0201]  157.17 13.48 0 top
RE7  RC1608J000CS~~0603WAJ0000T5E~~RM06JTN0~~RC0603JR-070RL+RC0603JR-130RL  [R0603]  176.07 11.71 0 top
RE8  0201WMJ0000TCE+0201WMJ0000TJE~~MCR006YRTJ000~~RC0201JR-070RL+RC0201JR-130RL~~WR02X000PAL  [R0201]  155.9 18.67 90 top
RE13  0201WMJ0000TCE+0201WMJ0000TJE~~MCR006YRTJ000~~RC0201JR-070RL+RC0201JR-130RL~~WR02X000PAL  [R0201]  183.66 10.61 180 top
RE28  0201WMJ0103TCE+0201WMJ0103TJE~~MCR006YRTJ103~~RC0201JR-0710KL~~WR02X103JAL  [R0201]  140.33 24.97 90 bottom
RE29  0201WMJ0103TCE+0201WMJ0103TJE~~MCR006YRTJ103~~RC0201JR-0710KL~~WR02X103JAL  [R0201]  137.92 15.82 90 top
RE30  0201WMJ0103TCE+0201WMJ0103TJE~~MCR006YRTJ103~~RC0201JR-0710KL~~WR02X103JAL  [R0201]  139.85 15.82 90 top
RE31  0402WGJ0000TCE+0402WGJ0000TJE~~RC1005J000CS~~RC0402JR-070RL+RC0402JR-130RL~~RM04JTN0  [R0402_0D65]  161.59 23.95 90 top
RE32  0201WMJ0000TCE+0201WMJ0000TJE~~MCR006YRTJ000~~RC0201JR-070RL+RC0201JR-130RL~~WR02X000PAL  [R0201]  140.61 15.57 180 top
RE33  0402WGJ0000TCE+0402WGJ0000TJE~~RC1005J000CS~~RC0402JR-070RL+RC0402JR-130RL~~RM04JTN0  [R0402_0D65]  170.56 16.46 180 top
RE34  0201WMJ0000TCE+0201WMJ0000TJE~~MCR006YRTJ000~~RC0201JR-070RL+RC0201JR-130RL~~WR02X000PAL  [R0201]  137.79 24.97 90 bottom
RE35  0201WMJ0000TCE+0201WMJ0000TJE~~MCR006YRTJ000~~RC0201JR-070RL+RC0201JR-130RL~~WR02X000PAL  [R0201]  138.68 15.82 90 top
RE37  0201WMJ0000TCE+0201WMJ0000TJE~~MCR006YRTJ000~~RC0201JR-070RL+RC0201JR-130RL~~WR02X000PAL  [R0201]  138.56 24.71 180 bottom
RE48  0201WMJ0000TCE+0201WMJ0000TJE~~MCR006YRTJ000~~RC0201JR-070RL+RC0201JR-130RL~~WR02X000PAL  [R0201]  186.69 15.39 0 top
RE49  0201WMJ0000TCE+0201WMJ0000TJE~~MCR006YRTJ000~~RC0201JR-070RL+RC0201JR-130RL~~WR02X000PAL  [R0201]  186.69 13.56 0 top
RE50  0201WMJ0103TCE+0201WMJ0103TJE~~MCR006YRTJ103~~RC0201JR-0710KL~~WR02X103JAL  [R0201]  186.69 16 180 top
RE51  0201WMJ0103TCE+0201WMJ0103TJE~~MCR006YRTJ103~~RC0201JR-0710KL~~WR02X103JAL  [R0201]  186.69 14.17 180 top
RE53  RC0201FR-07100RL~~WR02X1000FAL~~0201WMF1000TCE~~MCR006YRTF1000  [R0201]  15.24 83 270 top
RE55  RC0201JR-072K2L~~MCR006YRTJ222~~WR02X222 JAL~~0201WMJ0222TCE+0201WMJ0222TJE  [R0201]  68.32 6.04 90 top
RE56  RC0201JR-072K2L~~MCR006YRTJ222~~WR02X222 JAL~~0201WMJ0222TCE+0201WMJ0222TJE  [R0201]  72.13 5.45 270 top
RE57  RC0201JR-072K2L~~MCR006YRTJ222~~WR02X222 JAL~~0201WMJ0222TCE+0201WMJ0222TJE  [R0201]  68.96 3.63 0 top
RE58  RC0201JR-072K2L~~MCR006YRTJ222~~WR02X222 JAL~~0201WMJ0222TCE+0201WMJ0222TJE  [R0201]  69.72 7.69 0 top
RE59  0402WGJ0000TCE+0402WGJ0000TJE~~RC1005J000CS~~RC0402JR-070RL+RC0402JR-130RL~~RM04JTN0  [R0402_0D65]  66.36 10.28 0 bottom
RE60  0402WGJ0000TCE+0402WGJ0000TJE~~RC1005J000CS~~RC0402JR-070RL+RC0402JR-130RL~~RM04JTN0  [R0402_0D65]  66.36 9.47 0 bottom
RE61  0201WMJ0000TCE+0201WMJ0000TJE~~MCR006YRTJ000~~RC0201JR-070RL+RC0201JR-130RL~~WR02X000PAL  [R0201]  70.99 7.19 180 top
RE62  0201WMJ0000TCE+0201WMJ0000TJE~~MCR006YRTJ000~~RC0201JR-070RL+RC0201JR-130RL~~WR02X000PAL  [R0201]  69.72 7.19 180 top
RE63  0201WMJ0000TCE+0201WMJ0000TJE~~MCR006YRTJ000~~RC0201JR-070RL+RC0201JR-130RL~~WR02X000PAL  [R0201]  68.96 4.14 0 top
RE64  0201WMJ0000TCE+0201WMJ0000TJE~~MCR006YRTJ000~~RC0201JR-070RL+RC0201JR-130RL~~WR02X000PAL  [R0201]  70 4.14 0 top
RE65  0201WMJ0103TCE+0201WMJ0103TJE~~MCR006YRTJ103~~RC0201JR-0710KL~~WR02X103JAL  [R0201]  57.53 12.01 180 bottom
RE67  0201WMJ0000TCE+0201WMJ0000TJE~~MCR006YRTJ000~~RC0201JR-070RL+RC0201JR-130RL~~WR02X000PAL  [R0201]  57.53 11 0 bottom
RE68  0402WGJ0000TCE+0402WGJ0000TJE~~RC1005J000CS~~RC0402JR-070RL+RC0402JR-130RL~~RM04JTN0  [R0402_0D65]  159.61 23.54 270 top
RE69  0201WMJ0103TCE+0201WMJ0103TJE~~MCR006YRTJ103~~RC0201JR-0710KL~~WR02X103JAL  [R0201]  55.24 11.38 270 bottom
RE80  0402WGJ0000TCE+0402WGJ0000TJE~~RC1005J000CS~~RC0402JR-070RL+RC0402JR-130RL~~RM04JTN0  [R0402_0D65]  168.78 23.7 270 top
RE81  0201WMJ0103TCE+0201WMJ0103TJE~~MCR006YRTJ103~~RC0201JR-0710KL~~WR02X103JAL  [R0201]  154.63 7.29 270 top
RE86  0201WMJ0103TCE+0201WMJ0103TJE~~MCR006YRTJ103~~RC0201JR-0710KL~~WR02X103JAL  [R0201]  154.63 6.22 270 top
RE87  0201WMJ0000TCE+0201WMJ0000TJE~~MCR006YRTJ000~~RC0201JR-070RL+RC0201JR-130RL~~WR02X000PAL  [R0201]  154.07 6.22 90 top
RE92  RC0201FR-07100RL~~WR02X1000FAL~~0201WMF1000TCE~~MCR006YRTF1000  [R0201]  152.98 9.52 270 top
RE94  0201WMJ0000TCE+0201WMJ0000TJE~~MCR006YRTJ000~~RC0201JR-070RL+RC0201JR-130RL~~WR02X000PAL  [R0201]  166.37 23.8 270 top
RE95  0201WMJ0104TCE~~MCR006YRTJ104~~RC0201JR-07100KL~~WR02X104JAL  [R0201]  160.27 11.96 270 top
RE96  0201WMJ0000TCE+0201WMJ0000TJE~~MCR006YRTJ000~~RC0201JR-070RL+RC0201JR-130RL~~WR02X000PAL  [R0201]  155.75 11.96 180 top
RE98  0201WMJ0000TCE+0201WMJ0000TJE~~MCR006YRTJ000~~RC0201JR-070RL+RC0201JR-130RL~~WR02X000PAL  [R0201]  157.17 19.66 0 top
RE102  0201WMJ0104TCE~~MCR006YRTJ104~~RC0201JR-07100KL~~WR02X104JAL  [R0201]  157.17 18.49 180 top
RE103  0201WMF430JTCE~~RC0201FR-0743RL  [R0201]  157.17 21.99 180 top
RE104  0201WMJ0000TCE+0201WMJ0000TJE~~MCR006YRTJ000~~RC0201JR-070RL+RC0201JR-130RL~~WR02X000PAL  [R0201]  157.17 17.98 180 top
RE108  0201WMJ0224TCE~~MCR006YRTJ224~~RC0201JR-07220KL~~WR02X224 JAL  [R0201]  163.52 23.8 90 top
RE109  0201WMJ0103TCE+0201WMJ0103TJE~~MCR006YRTJ103~~RC0201JR-0710KL~~WR02X103JAL  [R0201]  157.22 11.96 0 top
RE110  0201WMJ0103TCE+0201WMJ0103TJE~~MCR006YRTJ103~~RC0201JR-0710KL~~WR02X103JAL  [R0201]  165.25 23.8 270 top
RE112  RC0201JR-072K2L~~MCR006YRTJ222~~WR02X222 JAL~~0201WMJ0222TCE+0201WMJ0222TJE  [R0201]  155.6 20.29 180 top
RE113  RC0201JR-072K2L~~MCR006YRTJ222~~WR02X222 JAL~~0201WMJ0222TCE+0201WMJ0222TJE  [R0201]  158.85 12.24 180 top
RE114  0201WMJ0103TCE+0201WMJ0103TJE~~MCR006YRTJ103~~RC0201JR-0710KL~~WR02X103JAL  [R0201]  157.22 12.47 0 top
RE115  0201WMJ0000TCE+0201WMJ0000TJE~~MCR006YRTJ000~~RC0201JR-070RL+RC0201JR-130RL~~WR02X000PAL  [R0201]  167.49 23.8 90 top
RE118  0201WMJ0104TCE~~MCR006YRTJ104~~RC0201JR-07100KL~~WR02X104JAL  [R0201]  157.17 15.03 0 top
RE120  0201WMJ0103TCE+0201WMJ0103TJE~~MCR006YRTJ103~~RC0201JR-0710KL~~WR02X103JAL  [R0201]  162.96 23.8 90 top
RE121  0201WMJ0104TCE~~MCR006YRTJ104~~RC0201JR-07100KL~~WR02X104JAL  [R0201]  162.41 23.8 90 top
RE123  0201WMJ0000TCE+0201WMJ0000TJE~~MCR006YRTJ000~~RC0201JR-070RL+RC0201JR-130RL~~WR02X000PAL  [R0201]  170.38 19.43 0 top
RE125  0201WMJ0000TCE+0201WMJ0000TJE~~MCR006YRTJ000~~RC0201JR-070RL+RC0201JR-130RL~~WR02X000PAL  [R0201]  157.17 20.19 180 top
RE127  0201WMJ0103TCE+0201WMJ0103TJE~~MCR006YRTJ103~~RC0201JR-0710KL~~WR02X103JAL  [R0201]  165.81 23.8 270 top
RE134  RC0201JR-072K2L~~MCR006YRTJ222~~WR02X222 JAL~~0201WMJ0222TCE+0201WMJ0222TJE  [R0201]  170.38 18.31 180 top
RE135  RC0201JR-072K2L~~MCR006YRTJ222~~WR02X222 JAL~~0201WMJ0222TCE+0201WMJ0222TJE  [R0201]  164.64 23.8 270 top
RE138  0201WMJ0104TCE~~MCR006YRTJ104~~RC0201JR-07100KL~~WR02X104JAL  [R0201]  183.66 11.22 0 top
RE139  0201WMJ0104TCE~~MCR006YRTJ104~~RC0201JR-07100KL~~WR02X104JAL  [R0201]  157.17 20.72 0 top
RE447  0201WMJ0103TCE+0201WMJ0103TJE~~MCR006YRTJ103~~RC0201JR-0710KL~~WR02X103JAL  [R0201]  135.23 26.08 90 top
RE451  0201WMJ0000TCE+0201WMJ0000TJE~~MCR006YRTJ000~~RC0201JR-070RL+RC0201JR-130RL~~WR02X000PAL  [R0201]  158.75 6.63 90 top
RE452  0201WMJ0000TCE+0201WMJ0000TJE~~MCR006YRTJ000~~RC0201JR-070RL+RC0201JR-130RL~~WR02X000PAL  [R0201]  169.06 19.99 0 top
RE453  0201WMJ0000TCE+0201WMJ0000TJE~~MCR006YRTJ000~~RC0201JR-070RL+RC0201JR-130RL~~WR02X000PAL  [R0201]  166.93 23.8 270 top
RE454  0201WMJ0000TCE+0201WMJ0000TJE~~MCR006YRTJ000~~RC0201JR-070RL+RC0201JR-130RL~~WR02X000PAL  [R0201]  57.53 11.5 0 bottom
RE455  0201WMJ0000TCE+0201WMJ0000TJE~~MCR006YRTJ000~~RC0201JR-070RL+RC0201JR-130RL~~WR02X000PAL  [R0201]  157.17 15.67 0 top
RE456  0201WMJ0331TCE~~MCR006YRTJ331~~RC0201JR-07330RL~~WR02X331JAL  [R0201]  179.03 6.05 270 top
RE457  0201WMJ0103TCE+0201WMJ0103TJE~~MCR006YRTJ103~~RC0201JR-0710KL~~WR02X103JAL  [R0201]  136.9 26.08 90 top
RE458  0201WMJ0103TCE+0201WMJ0103TJE~~MCR006YRTJ103~~RC0201JR-0710KL~~WR02X103JAL  [R0201]  139.32 15.82 90 top
RE459  0201WMJ0000TCE+0201WMJ0000TJE~~MCR006YRTJ000~~RC0201JR-070RL+RC0201JR-130RL~~WR02X000PAL  [R0201]  168.07 23.82 90 top
RE460  0402WGJ0000TCE+0402WGJ0000TJE~~RC1005J000CS~~RC0402JR-070RL+RC0402JR-130RL~~RM04JTN0  [R0402_0D65]  155.29 17.24 0 top
RE461  0201WMJ0000TCE+0201WMJ0000TJE~~MCR006YRTJ000~~RC0201JR-070RL+RC0201JR-130RL~~WR02X000PAL  [R0201]  157.17 21.26 0 top
RE462  0201WMJ0000TCE+0201WMJ0000TJE~~MCR006YRTJ000~~RC0201JR-070RL+RC0201JR-130RL~~WR02X000PAL  [R0201]  157.78 17.09 0 top
RF1  0402WGJ0000TCE+0402WGJ0000TJE~~RC1005J000CS~~RC0402JR-070RL+RC0402JR-130RL~~RM04JTN0  [R0402_0D65]  145.13 35.13 180 top
RF2  0201WMF499JTCE~~MCR006YRTF49R9~~RC0201FR-0749R9L~~WR02X49R9FAL  [R0201]  137.51 26.08 270 top
RF3  0201WMF499JTCE~~MCR006YRTF49R9~~RC0201FR-0749R9L~~WR02X49R9FAL  [R0201]  135.79 26.08 270 top
RF4  0201WMF499JTCE~~MCR006YRTF49R9~~RC0201FR-0749R9L~~WR02X49R9FAL  [R0201]  138.17 26.11 270 top
RF5  0201WMF499JTCE~~MCR006YRTF49R9~~RC0201FR-0749R9L~~WR02X49R9FAL  [R0201]  140.84 28.01 270 top
RF6  0201WMJ0000TCE+0201WMJ0000TJE~~MCR006YRTJ000~~RC0201JR-070RL+RC0201JR-130RL~~WR02X000PAL  [R0201]  134.97 26.9 180 top
RF7  0201WMJ0000TCE+0201WMJ0000TJE~~MCR006YRTJ000~~RC0201JR-070RL+RC0201JR-130RL~~WR02X000PAL  [R0201]  133.22 27.63 180 top
RF8  0402WGJ0000TCE+0402WGJ0000TJE~~RC1005J000CS~~RC0402JR-070RL+RC0402JR-130RL~~RM04JTN0  [R0402_0D65]  145.14 35.98 180 top
RF9  0201WMJ0472TCE~~MCR006YRTJ472~~RC0201JR-074K7L~~WR02X472JAL  [R0201]  137.16 34.41 0 top
RF10  0201WMJ0472TCE~~MCR006YRTJ472~~RC0201JR-074K7L~~WR02X472JAL  [R0201]  137.16 34.97 180 top
RF11  0402WGJ0000TCE+0402WGJ0000TJE~~RC1005J000CS~~RC0402JR-070RL+RC0402JR-130RL~~RM04JTN0  [R0402_0D65]  139.62 25.98 90 top
RI11  0201WMJ0000TCE+0201WMJ0000TJE~~MCR006YRTJ000~~RC0201JR-070RL+RC0201JR-130RL~~WR02X000PAL  [R0201]  18.9 53.86 0 top
RI12  0201WMJ0000TCE+0201WMJ0000TJE~~MCR006YRTJ000~~RC0201JR-070RL+RC0201JR-130RL~~WR02X000PAL  [R0201]  18.9 53.25 0 top
RI13  0201WMJ0000TCE+0201WMJ0000TJE~~MCR006YRTJ000~~RC0201JR-070RL+RC0201JR-130RL~~WR02X000PAL  [R0201]  18.9 52.46 0 top
RI14  0201WMJ0000TCE+0201WMJ0000TJE~~MCR006YRTJ000~~RC0201JR-070RL+RC0201JR-130RL~~WR02X000PAL  [R0201]  18.9 51.85 0 top
RI23  0201WMJ0000TCE+0201WMJ0000TJE~~MCR006YRTJ000~~RC0201JR-070RL+RC0201JR-130RL~~WR02X000PAL  [R0201]  18.9 51.08 0 top
RI24  0201WMJ0000TCE+0201WMJ0000TJE~~MCR006YRTJ000~~RC0201JR-070RL+RC0201JR-130RL~~WR02X000PAL  [R0201]  18.9 50.47 0 top
RI25  0201WMJ0000TCE+0201WMJ0000TJE~~MCR006YRTJ000~~RC0201JR-070RL+RC0201JR-130RL~~WR02X000PAL  [R0201]  18.9 55.36 0 top
RI26  0201WMJ0000TCE+0201WMJ0000TJE~~MCR006YRTJ000~~RC0201JR-070RL+RC0201JR-130RL~~WR02X000PAL  [R0201]  18.9 54.75 0 top
RI33  0201WMF4991TCE~~RC0201FR-074K99L  [R0201]  27.3 47.95 90 top
RI34  0201WMJ0103TCE+0201WMJ0103TJE~~MCR006YRTJ103~~RC0201JR-0710KL~~WR02X103JAL  [R0201]  27.18 60.73 90 bottom
RI40  0201WMJ0104TCE~~MCR006YRTJ104~~RC0201JR-07100KL~~WR02X104JAL  [R0201]  17.78 61.41 180 bottom
RI60  0201WMJ0000TCE+0201WMJ0000TJE~~MCR006YRTJ000~~RC0201JR-070RL+RC0201JR-130RL~~WR02X000PAL  [R0201]  22.99 58.87 90 top
RI61  0201WMJ0000TCE+0201WMJ0000TJE~~MCR006YRTJ000~~RC0201JR-070RL+RC0201JR-130RL~~WR02X000PAL  [R0201]  23.49 58.87 90 top
RI101  0201WMJ0472TCE~~MCR006YRTJ472~~RC0201JR-074K7L~~WR02X472JAL  [R0201]  24.76 58.11 90 top
RI102  0201WMJ0472TCE~~MCR006YRTJ472~~RC0201JR-074K7L~~WR02X472JAL  [R0201]  24.13 58.11 270 top
RI104  0201WMJ0472TCE~~MCR006YRTJ472~~RC0201JR-074K7L~~WR02X472JAL  [R0201]  21.79 47.85 90 top
RI105  MCR006YRTJ222~~RC0201JR-072K2L~~0201WMJ0222TCE+0201WMJ0222TJE~~WR02X222 JAL  [R0201]  19.56 58.49 180 top
RI106  MCR006YRTJ222~~RC0201JR-072K2L~~0201WMJ0222TCE+0201WMJ0222TJE~~WR02X222 JAL  [R0201]  19.56 57.86 180 top
RI142  MCR006YRTJ222~~RC0201JR-072K2L~~0201WMJ0222TCE+0201WMJ0222TJE~~WR02X222 JAL  [R0201]  25.78 47.95 270 top
RI143  MCR006YRTJ222~~RC0201JR-072K2L~~0201WMJ0222TCE+0201WMJ0222TJE~~WR02X222 JAL  [R0201]  24.76 47.95 270 top
RI144  0201WMJ0000TCE+0201WMJ0000TJE~~MCR006YRTJ000~~RC0201JR-070RL+RC0201JR-130RL~~WR02X000PAL  [R0201]  17.83 62.96 0 bottom
RI145  0201WMJ0103TCE+0201WMJ0103TJE~~MCR006YRTJ103~~RC0201JR-0710KL~~WR02X103JAL  [R0201]  23.47 62.86 0 bottom
RI146  0201WMJ0104TCE~~MCR006YRTJ104~~RC0201JR-07100KL~~WR02X104JAL  [R0201]  30.35 51.76 180 top
RI148  0201WMJ0000TCE+0201WMJ0000TJE~~MCR006YRTJ000~~RC0201JR-070RL+RC0201JR-130RL~~WR02X000PAL  [R0201]  29.34 51.76 180 top
RI149  0201WMJ0472TCE~~MCR006YRTJ472~~RC0201JR-074K7L~~WR02X472JAL  [R0201]  26.29 58.11 270 top
RI151  0201WMJ0472TCE~~MCR006YRTJ472~~RC0201JR-074K7L~~WR02X472JAL  [R0201]  23.75 47.95 270 top
RI152  0201WMJ0472TCE~~MCR006YRTJ472~~RC0201JR-074K7L~~WR02X472JAL  [R0201]  24.26 47.95 270 top
RI153  0201WMJ0000TCE+0201WMJ0000TJE~~MCR006YRTJ000~~RC0201JR-070RL+RC0201JR-130RL~~WR02X000PAL  [R0201]  25.78 58.11 90 top
RI154  0201WMJ0103TCE+0201WMJ0103TJE~~MCR006YRTJ103~~RC0201JR-0710KL~~WR02X103JAL  [R0201]  26.29 47.95 270 top
RI155  0201WMJ0103TCE+0201WMJ0103TJE~~MCR006YRTJ103~~RC0201JR-0710KL~~WR02X103JAL  [R0201]  25.27 58.11 90 top
RI156  res  [R0201]  16.03 54.15 0 top
RI157  res  [R0201]  16.03 53.62 0 top
RI158  res  [R0201]  16.18 52.25 0 top
RI159  res  [R0201]  16.18 51.71 0 top
RI160  res  [R0201]  15.64 50.72 0 top
RI161  res  [R0201]  15.64 50.19 0 top
RI162  res  [R0201]  16.1 56.08 0 top
RI163  res  [R0201]  16.1 55.55 0 top
RL1  0201WMF2004TCE+0201WMF2004TEE~#~RC0201FR-072ML~#~0201WMF2004TCE  [R0201]  160.27 28.17 90 top
RL2  res  [R0201]  159.14 28.17 270 top
RL45  WR02X1002FAL~#~RC0201FR-0710KL~#~0201WMF1002TCE+0201WMF1002TEE~#~0201WMF1002TCE~#~MCR006YRTF1002  [R0201]  157.17 28.17 270 top
RL46  0201WMJ0000TCE+0201WMJ0000TJE~~MCR006YRTJ000~~RC0201JR-070RL+RC0201JR-130RL~~WR02X000PAL  [R0201]  14.2 13.76 180 bottom
RL47  0201WMJ0000TCE+0201WMJ0000TJE~~MCR006YRTJ000~~RC0201JR-070RL+RC0201JR-130RL~~WR02X000PAL  [R0201]  14.2 14.32 180 bottom
RL454  0402WGJ0000TCE+0402WGJ0000TJE~~RC1005J000CS~~RC0402JR-070RL+RC0402JR-130RL~~RM04JTN0  [R0402_0D65]  12.95 8.4 0 bottom
RL455  0201WMJ0000TCE+0201WMJ0000TJE~~MCR006YRTJ000~~RC0201JR-070RL+RC0201JR-130RL~~WR02X000PAL  [R0201]  18.59 12.98 90 bottom
RN1  0805W8J0000T5E~~RC0805JR-070RL~~RM10JTN0  [R0805]  15.95 6.68 270 top
RN3  0201WMJ0103TCE+0201WMJ0103TJE~~MCR006YRTJ103~~RC0201JR-0710KL~~WR02X103JAL  [R0201]  23.32 3.78 90 top
RN4  0201WMJ0000TCE+0201WMJ0000TJE~~MCR006YRTJ000~~RC0201JR-070RL+RC0201JR-130RL~~WR02X000PAL  [R0201]  27.13 3.78 90 top
RN5  0201WMJ0103TCE+0201WMJ0103TJE~~MCR006YRTJ103~~RC0201JR-0710KL~~WR02X103JAL  [R0201]  26.59 3.78 270 top
RN8  0201WMJ0000TCE+0201WMJ0000TJE~~MCR006YRTJ000~~RC0201JR-070RL+RC0201JR-130RL~~WR02X000PAL  [R0201]  23.92 3.78 90 top
RN11  0201WMJ0103TCE+0201WMJ0103TJE~~MCR006YRTJ103~~RC0201JR-0710KL~~WR02X103JAL  [R0201]  20.11 5.76 270 top
RN30  0201WMJ0104TCE~~MCR006YRTJ104~~RC0201JR-07100KL~~WR02X104JAL  [R0201]  25.75 3.78 270 top
RN31  0201WMJ0000TCE+0201WMJ0000TJE~~MCR006YRTJ000~~RC0201JR-070RL+RC0201JR-130RL~~WR02X000PAL  [R0201]  24.53 3.78 90 top
RN33  WR02X102JAL~~RC0201JR-071KL~~0201WMJ0102TCE+0201WMJ0102TJE~~MCR006YRTJ102  [R0201]  25.14 3.78 90 top
RN37  0201WMJ0103TCE+0201WMJ0103TJE~~MCR006YRTJ103~~RC0201JR-0710KL~~WR02X103JAL  [R0201]  20.72 7.24 90 top
RO1  0402WGJ0000TCE+0402WGJ0000TJE~~RC1005J000CS~~RC0402JR-070RL+RC0402JR-130RL~~RM04JTN0  [R0402_0D65]  132.03 6.91 90 top
RO2  0201WMJ0332TCE~~MCR006YRTJ332~~RC0201JR-073K3L~~WR02X332JAL  [R0201]  131.06 8.46 0 top
RO3  0201WMJ0332TCE~~MCR006YRTJ332~~RC0201JR-073K3L~~WR02X332JAL  [R0201]  131.06 12.27 0 top
RO4  0201WMJ0332TCE~~MCR006YRTJ332~~RC0201JR-073K3L~~WR02X332JAL  [R0201]  136.4 11.55 270 top
RO5  0201WMF499JTCE~~MCR006YRTF49R9~~RC0201FR-0749R9L~~WR02X49R9FAL  [R0201]  131.06 9.09 180 top
RO6  0201WMF499JTCE~~MCR006YRTF49R9~~RC0201FR-0749R9L~~WR02X49R9FAL  [R0201]  131.06 12.9 180 top
RO7  0201WMF499JTCE~~MCR006YRTF49R9~~RC0201FR-0749R9L~~WR02X49R9FAL  [R0201]  136.65 12.37 180 top
RO8  0201WMF499JTCE~~MCR006YRTF49R9~~RC0201FR-0749R9L~~WR02X49R9FAL  [R0201]  132.08 12.27 270 top
RO9  0201WMJ0000TCE+0201WMJ0000TJE~~MCR006YRTJ000~~RC0201JR-070RL+RC0201JR-130RL~~WR02X000PAL  [R0201]  132.64 12.27 270 top
RO10  0201WMJ0000TCE+0201WMJ0000TJE~~MCR006YRTJ000~~RC0201JR-070RL+RC0201JR-130RL~~WR02X000PAL  [R0201]  131.06 9.73 180 top
RO11  0201WMF499JTCE~~MCR006YRTF49R9~~RC0201FR-0749R9L~~WR02X49R9FAL  [R0201]  131.06 10.36 180 top
RO12  0201WMF499JTCE~~MCR006YRTF49R9~~RC0201FR-0749R9L~~WR02X49R9FAL  [R0201]  133.55 12.82 0 top
RO13  0201WMJ0000TCE+0201WMJ0000TJE~~MCR006YRTJ000~~RC0201JR-070RL+RC0201JR-130RL~~WR02X000PAL  [R0201]  131.06 11 180 top
RO14  0201WMJ0000TCE+0201WMJ0000TJE~~MCR006YRTJ000~~RC0201JR-070RL+RC0201JR-130RL~~WR02X000PAL  [R0201]  133.55 12.29 0 top
RP12  0201WMF4992TCE~~MCR006YRTF4992~~RC0201FR-0749K9L  [R0201]  58.67 51.25 0 bottom
RP13  0201WMF4992TCE~~MCR006YRTF4992~~RC0201FR-0749K9L  [R0201]  57.02 51.25 180 bottom
RP14  0201WMJ0000TCE+0201WMJ0000TJE~~MCR006YRTJ000~~RC0201JR-070RL+RC0201JR-130RL~~WR02X000PAL  [R0201]  146.43 8.71 270 top
RP15  0201WMJ0000TCE+0201WMJ0000TJE~~MCR006YRTJ000~~RC0201JR-070RL+RC0201JR-130RL~~WR02X000PAL  [R0201]  147.83 8.33 180 top
RS1  0201WMJ0103TCE+0201WMJ0103TJE~~MCR006YRTJ103~~RC0201JR-0710KL~~WR02X103JAL  [R0201]  67.44 9.47 90 bottom
RS2  0201WMJ0103TCE+0201WMJ0103TJE~~MCR006YRTJ103~~RC0201JR-0710KL~~WR02X103JAL  [R0201]  68.07 9.47 90 bottom
RS3  0201WMJ0103TCE+0201WMJ0103TJE~~MCR006YRTJ103~~RC0201JR-0710KL~~WR02X103JAL  [R0201]  152.53 8.71 180 bottom
RT1  0201WMJ0104TCE~~MCR006YRTJ104~~RC0201JR-07100KL~~WR02X104JAL  [R0201]  48.51 30.3 0 bottom
RT2  WR02X102JAL~~RC0201JR-071KL~~0201WMJ0102TCE+0201WMJ0102TJE~~MCR006YRTJ102  [R0201]  50.42 40.97 90 bottom
RT3  0201WMJ0104TCE~~MCR006YRTJ104~~RC0201JR-07100KL~~WR02X104JAL  [R0201]  49.91 31.19 270 bottom
RT4  WR02X102JAL~~RC0201JR-071KL~~0201WMJ0102TCE+0201WMJ0102TJE~~MCR006YRTJ102  [R0201]  49.78 40.97 90 bottom
RT5  0402WGJ0000TCE+0402WGJ0000TJE~~RC1005J000CS~~RC0402JR-070RL+RC0402JR-130RL~~RM04JTN0  [R0402_0D65]  40.69 33.12 0 top
RT6  0402WGJ0000TCE+0402WGJ0000TJE~~RC1005J000CS~~RC0402JR-070RL+RC0402JR-130RL~~RM04JTN0  [R0402_0D65]  40.69 33.98 0 top
RT7  0201WMJ0000TCE+0201WMJ0000TJE~~MCR006YRTJ000~~RC0201JR-070RL+RC0201JR-130RL~~WR02X000PAL  [R0201]  50.16 40.21 180 bottom
RT8  0201WMJ0000TCE+0201WMJ0000TJE~~MCR006YRTJ000~~RC0201JR-070RL+RC0201JR-130RL~~WR02X000PAL  [R0201]  50.16 37.49 180 bottom
RT9  0201WMJ0000TCE+0201WMJ0000TJE~~MCR006YRTJ000~~RC0201JR-070RL+RC0201JR-130RL~~WR02X000PAL  [R0201]  39.83 39.44 180 bottom
RT10  0201WMJ0000TCE+0201WMJ0000TJE~~MCR006YRTJ000~~RC0201JR-070RL+RC0201JR-130RL~~WR02X000PAL  [R0201]  39.83 40.08 180 bottom
RT11  0201WMJ0000TCE+0201WMJ0000TJE~~MCR006YRTJ000~~RC0201JR-070RL+RC0201JR-130RL~~WR02X000PAL  [R0201]  44.19 32.33 90 bottom
RT12  0201WMJ0000TCE+0201WMJ0000TJE~~MCR006YRTJ000~~RC0201JR-070RL+RC0201JR-130RL~~WR02X000PAL  [R0201]  43.69 32.33 90 bottom
RT13  0201WMJ0000TCE+0201WMJ0000TJE~~MCR006YRTJ000~~RC0201JR-070RL+RC0201JR-130RL~~WR02X000PAL  [R0201]  46.35 32.33 270 bottom
RT14  0201WMJ0000TCE+0201WMJ0000TJE~~MCR006YRTJ000~~RC0201JR-070RL+RC0201JR-130RL~~WR02X000PAL  [R0201]  46.86 32.33 270 bottom
RT15  0201WMJ0000TCE+0201WMJ0000TJE~~MCR006YRTJ000~~RC0201JR-070RL+RC0201JR-130RL~~WR02X000PAL  [R0201]  47.37 32.33 270 bottom
RT16  0201WMJ0472TCE~~MCR006YRTJ472~~RC0201JR-074K7L~~WR02X472JAL  [R0201]  45.21 32.33 90 bottom
RT17  0201WMJ0103TCE+0201WMJ0103TJE~~MCR006YRTJ103~~RC0201JR-0710KL~~WR02X103JAL  [R0201]  45.72 32.33 270 bottom
RT18  0201WMJ0472TCE~~MCR006YRTJ472~~RC0201JR-074K7L~~WR02X472JAL  [R0201]  50.67 32.92 180 bottom
RT19  0201WMJ0472TCE~~MCR006YRTJ472~~RC0201JR-074K7L~~WR02X472JAL  [R0201]  44.7 32.33 90 bottom
RT20  0201WMJ0472TCE~~MCR006YRTJ472~~RC0201JR-074K7L~~WR02X472JAL  [R0201]  50.16 39.7 180 bottom
RT21  0201WMJ0472TCE~~MCR006YRTJ472~~RC0201JR-074K7L~~WR02X472JAL  [R0201]  43.05 32.33 90 bottom
RT22  0201WMJ0472TCE~~MCR006YRTJ472~~RC0201JR-074K7L~~WR02X472JAL  [R0201]  50.16 38.05 180 bottom
RT23  0201WMJ0104TCE~~MCR006YRTJ104~~RC0201JR-07100KL~~WR02X104JAL  [R0201]  42.31 32.33 90 bottom
RT24  0201WMF220KTCE~~RC0201FR-072R2L  [R0201]  15.24 22.74 180 bottom
RT25  0201WMF220KTCE~~RC0201FR-072R2L  [R0201]  15.24 22.24 180 bottom
RT26  0201WMF220KTCE~~RC0201FR-072R2L  [R0201]  15.24 22.74 180 top
RT27  0201WMF220KTCE~~RC0201FR-072R2L  [R0201]  15.24 22.24 180 top
RT28  0201WMF220KTCE~~RC0201FR-072R2L  [R0201]  14.86 17.16 180 top
RT29  0201WMF220KTCE~~RC0201FR-072R2L  [R0201]  14.86 17.66 180 top
RT30  0201WMF220KTCE~~RC0201FR-072R2L  [R0201]  14.86 17.16 180 bottom
RT31  0201WMF220KTCE~~RC0201FR-072R2L  [R0201]  14.86 17.66 180 bottom
RT32  0201WMJ0105TCE~~MCR006YRTJ105~~RC0201JR-071ML~~WR02X105JAL  [R0201]  24.26 26.87 0 bottom
RT33  0201WMJ0105TCE~~MCR006YRTJ105~~RC0201JR-071ML~~WR02X105JAL  [R0201]  24.64 27.38 0 bottom
RT34  0201WMJ0000TCE+0201WMJ0000TJE~~MCR006YRTJ000~~RC0201JR-070RL+RC0201JR-130RL~~WR02X000PAL  [R0201]  25.53 21.16 270 bottom
RT35  0201WMJ0000TCE+0201WMJ0000TJE~~MCR006YRTJ000~~RC0201JR-070RL+RC0201JR-130RL~~WR02X000PAL  [R0201]  23.49 21.16 270 bottom
RT36  0201WMJ0000TCE+0201WMJ0000TJE~~MCR006YRTJ000~~RC0201JR-070RL+RC0201JR-130RL~~WR02X000PAL  [R0201]  18.67 17.73 270 top
RT37  0201WMJ0000TCE+0201WMJ0000TJE~~MCR006YRTJ000~~RC0201JR-070RL+RC0201JR-130RL~~WR02X000PAL  [R0201]  24.76 17.73 270 top
RT38  0201WMJ0000TCE+0201WMJ0000TJE~~MCR006YRTJ000~~RC0201JR-070RL+RC0201JR-130RL~~WR02X000PAL  [R0201]  24.76 17.73 270 bottom
RT39  0201WMJ0000TCE+0201WMJ0000TJE~~MCR006YRTJ000~~RC0201JR-070RL+RC0201JR-130RL~~WR02X000PAL  [R0201]  24.26 17.73 270 top
RT40  0201WMJ0000TCE+0201WMJ0000TJE~~MCR006YRTJ000~~RC0201JR-070RL+RC0201JR-130RL~~WR02X000PAL  [R0201]  24.26 17.73 270 bottom
RT41  0201WMJ0000TCE+0201WMJ0000TJE~~MCR006YRTJ000~~RC0201JR-070RL+RC0201JR-130RL~~WR02X000PAL  [R0201]  19.81 26.24 90 top
RT42  0201WMJ0000TCE+0201WMJ0000TJE~~MCR006YRTJ000~~RC0201JR-070RL+RC0201JR-130RL~~WR02X000PAL  [R0201]  20.32 26.24 90 top
RT43  0201WMJ0101TCE~~MCR006YRTJ101~~RC0201JR_07100RL~~WR02X101 JAL  [R0201]  28.83 17.73 90 top
RT44  WF04T4751DTL~~TC0250D4751TCE~~RT0402DRD074K75L  [R0402]  27.07 27.35 180 bottom
RT45  0201WMJ0000TCE+0201WMJ0000TJE~~MCR006YRTJ000~~RC0201JR-070RL+RC0201JR-130RL~~WR02X000PAL  [R0201]  18.03 17.73 90 top
RT46  0201WMJ0472TCE~~MCR006YRTJ472~~RC0201JR-074K7L~~WR02X472JAL  [R0201]  20.19 17.73 270 top
RT47  0201WMJ0472TCE~~MCR006YRTJ472~~RC0201JR-074K7L~~WR02X472JAL  [R0201]  25.27 17.73 270 top
RT48  0201WMJ0472TCE~~MCR006YRTJ472~~RC0201JR-074K7L~~WR02X472JAL  [R0201]  25.27 17.73 270 bottom
RT49  0201WMJ0103TCE+0201WMJ0103TJE~~MCR006YRTJ103~~RC0201JR-0710KL~~WR02X103JAL  [R0201]  21.72 17.73 270 top
RT50  0201WMJ0103TCE+0201WMJ0103TJE~~MCR006YRTJ103~~RC0201JR-0710KL~~WR02X103JAL  [R0201]  21.21 17.73 90 top
RT51  0201WMJ0103TCE+0201WMJ0103TJE~~MCR006YRTJ103~~RC0201JR-0710KL~~WR02X103JAL  [R0201]  19.18 17.73 270 top
RT52  0201WMJ0103TCE+0201WMJ0103TJE~~MCR006YRTJ103~~RC0201JR-0710KL~~WR02X103JAL  [R0201]  19.68 17.73 90 top
RT53  0201WMJ0103TCE+0201WMJ0103TJE~~MCR006YRTJ103~~RC0201JR-0710KL~~WR02X103JAL  [R0201]  20.7 17.73 90 top
RT54  0201WMJ0103TCE+0201WMJ0103TJE~~MCR006YRTJ103~~RC0201JR-0710KL~~WR02X103JAL  [R0201]  22.22 17.73 270 top
RT55  0201WMJ0103TCE+0201WMJ0103TJE~~MCR006YRTJ103~~RC0201JR-0710KL~~WR02X103JAL  [R0201]  23.75 17.73 90 top
RT56  0201WMJ0103TCE+0201WMJ0103TJE~~MCR006YRTJ103~~RC0201JR-0710KL~~WR02X103JAL  [R0201]  19.25 26.24 90 top
RT57  0201WMJ0103TCE+0201WMJ0103TJE~~MCR006YRTJ103~~RC0201JR-0710KL~~WR02X103JAL  [R0201]  23.24 17.73 270 bottom
RT58  0201WMJ0103TCE+0201WMJ0103TJE~~MCR006YRTJ103~~RC0201JR-0710KL~~WR02X103JAL  [R0201]  23.75 17.73 90 bottom
RT59  0201WMJ0103TCE+0201WMJ0103TJE~~MCR006YRTJ103~~RC0201JR-0710KL~~WR02X103JAL  [R0201]  26.8 17.73 270 bottom
RT60  0201WMJ0000TCE+0201WMJ0000TJE~~MCR006YRTJ000~~RC0201JR-070RL+RC0201JR-130RL~~WR02X000PAL  [R0201]  22.73 17.73 90 top
RT61  0201WMJ0103TCE+0201WMJ0103TJE~~MCR006YRTJ103~~RC0201JR-0710KL~~WR02X103JAL  [R0201]  27.3 17.73 90 bottom
RT62  0201WMJ0103TCE+0201WMJ0103TJE~~MCR006YRTJ103~~RC0201JR-0710KL~~WR02X103JAL  [R0201]  26.8 17.73 270 top
RT63  0201WMJ0103TCE+0201WMJ0103TJE~~MCR006YRTJ103~~RC0201JR-0710KL~~WR02X103JAL  [R0201]  27.3 17.73 90 top
RT64  0201WMJ0103TCE+0201WMJ0103TJE~~MCR006YRTJ103~~RC0201JR-0710KL~~WR02X103JAL  [R0201]  26.29 17.73 270 top
RT65  0201WMJ0103TCE+0201WMJ0103TJE~~MCR006YRTJ103~~RC0201JR-0710KL~~WR02X103JAL  [R0201]  25.78 17.73 90 top
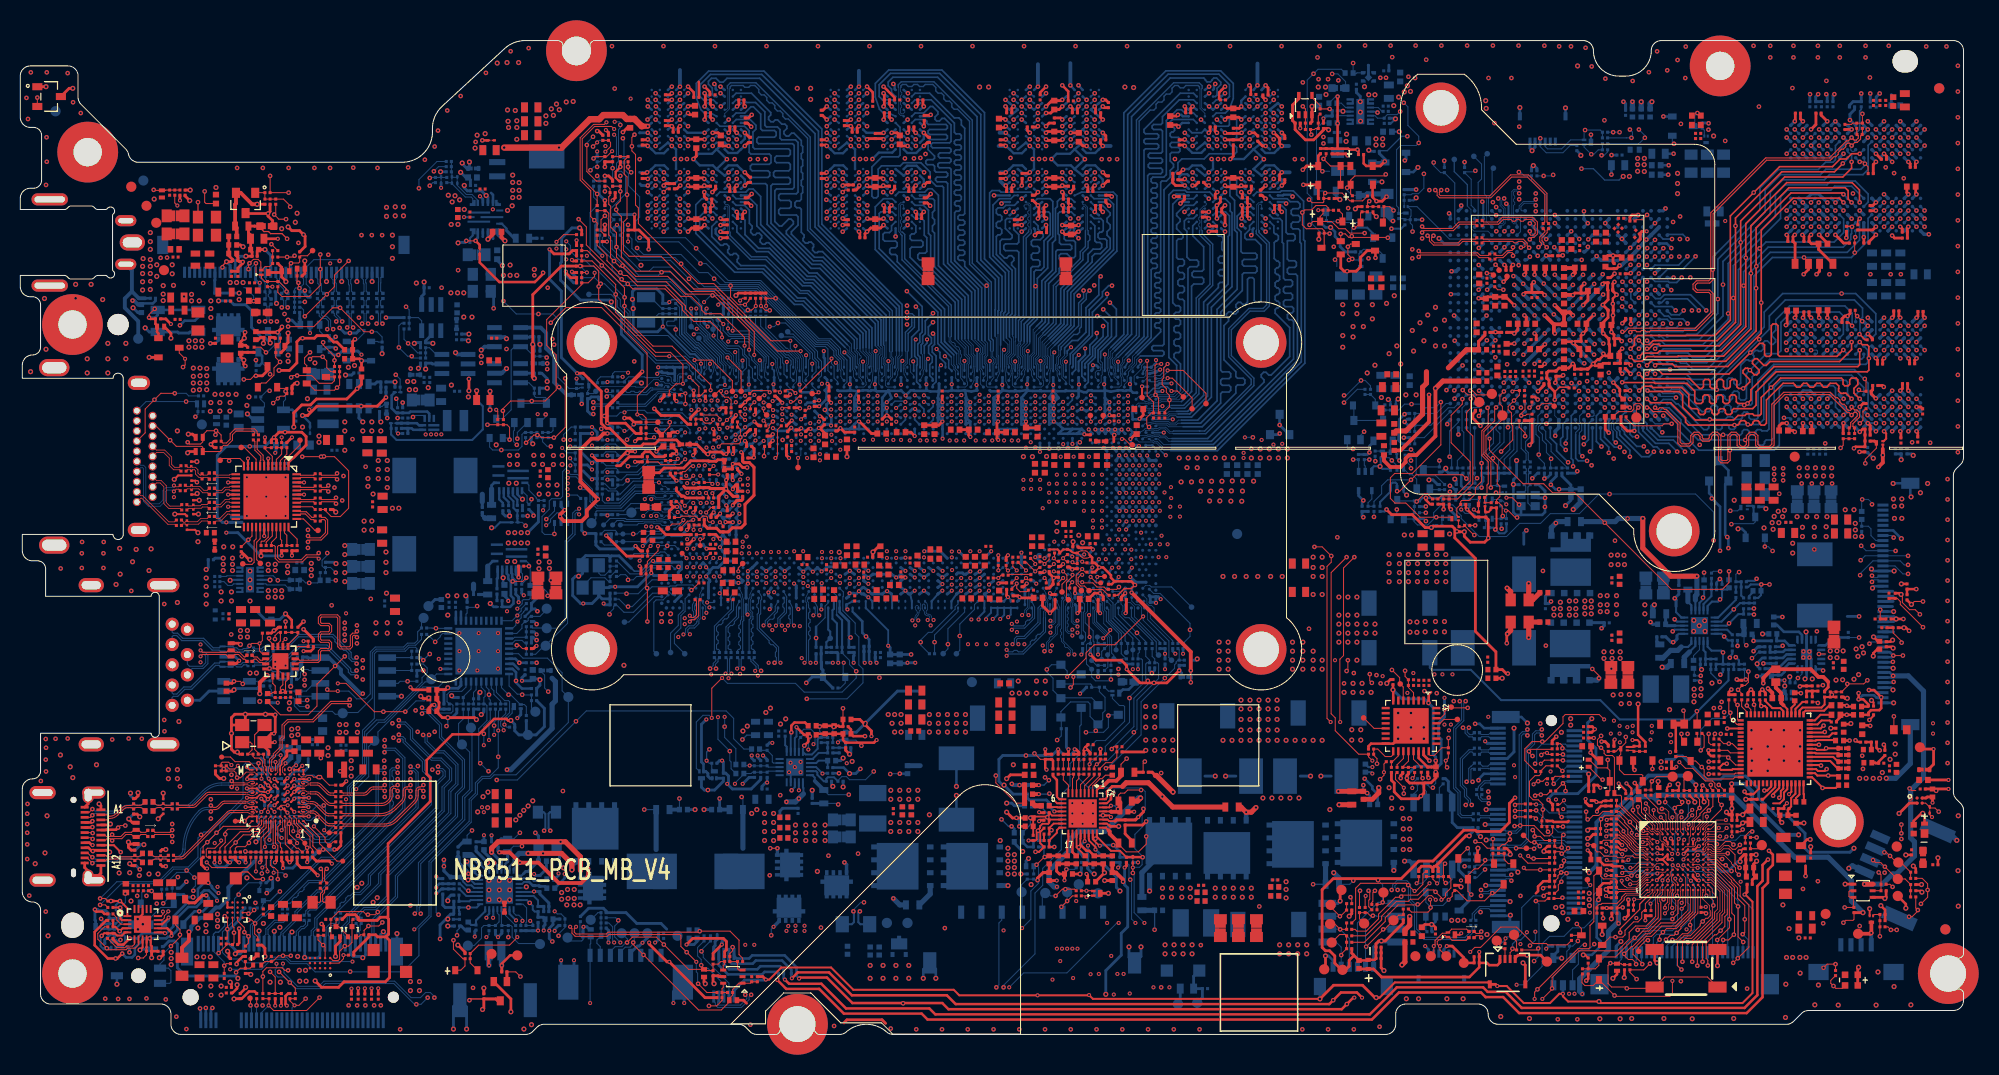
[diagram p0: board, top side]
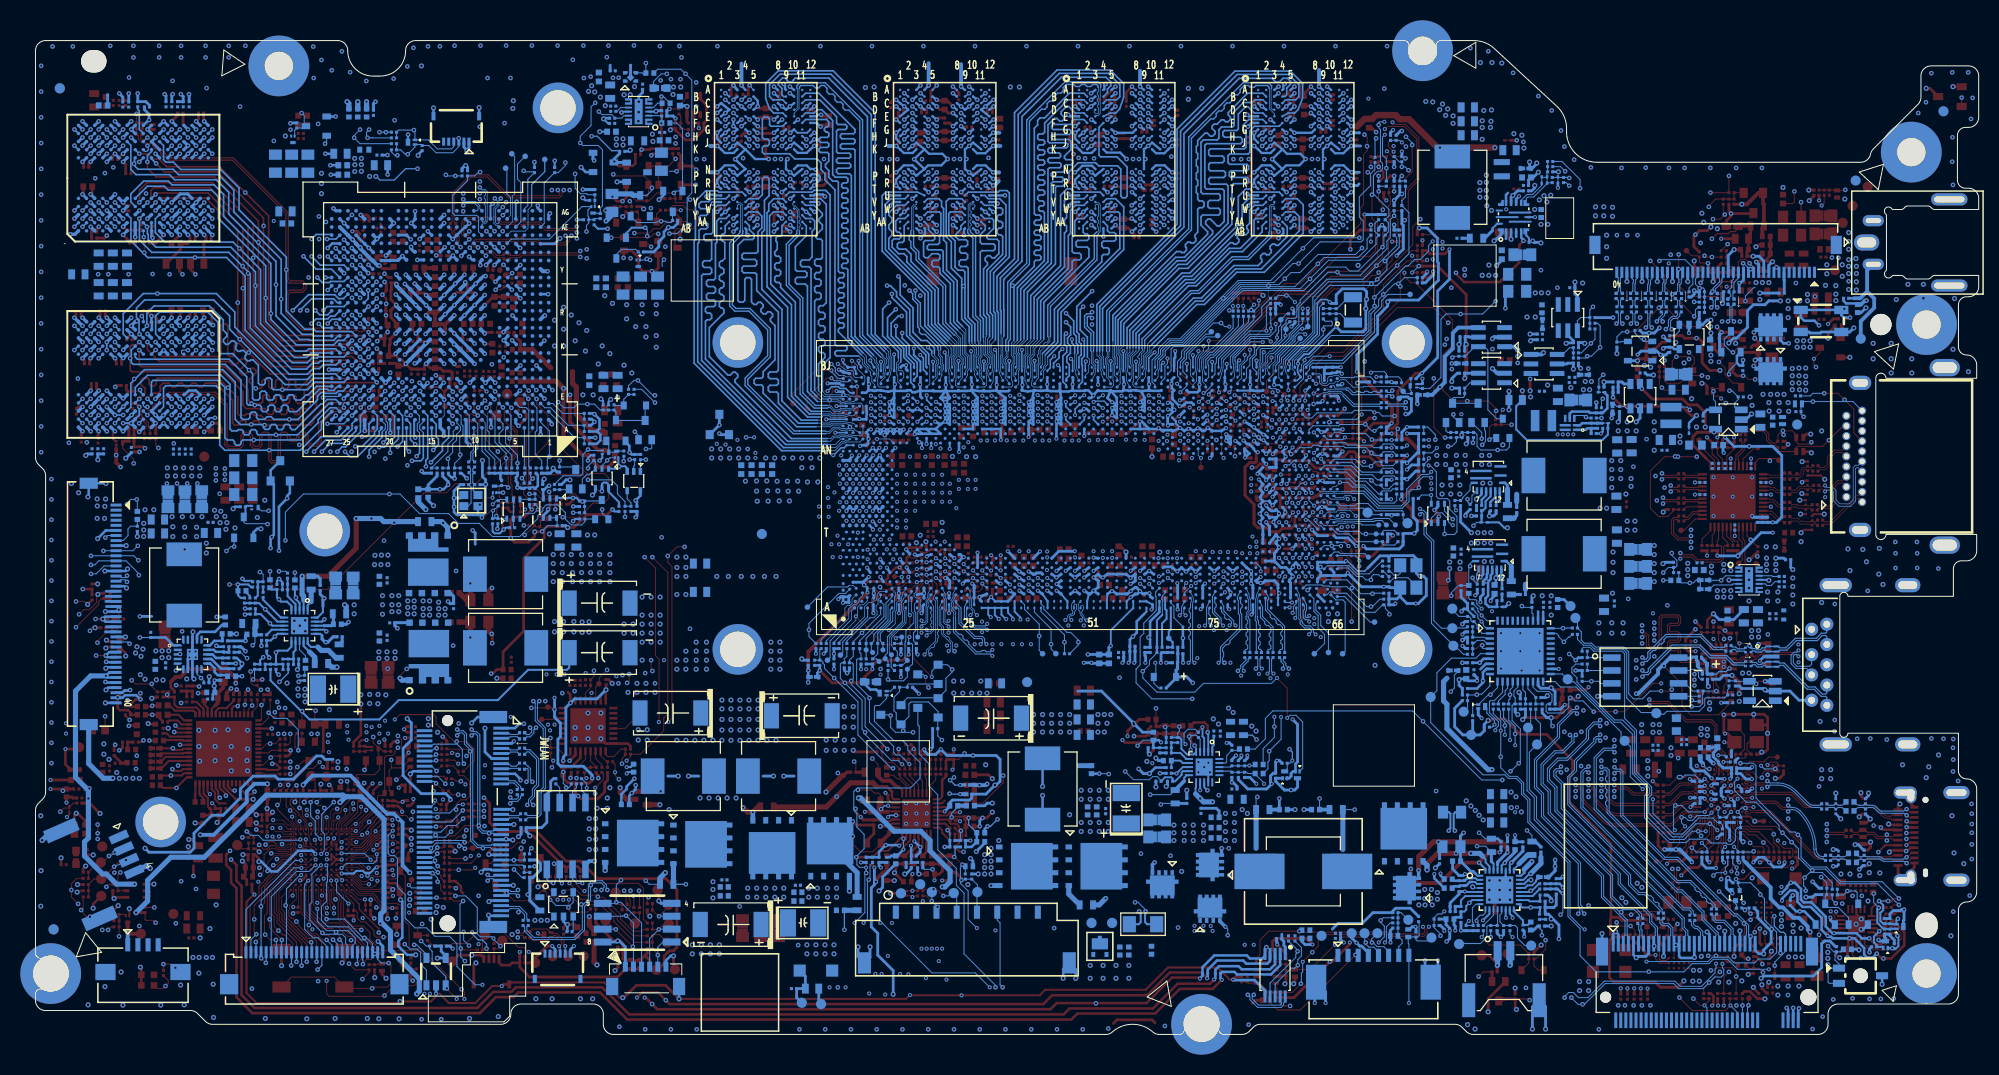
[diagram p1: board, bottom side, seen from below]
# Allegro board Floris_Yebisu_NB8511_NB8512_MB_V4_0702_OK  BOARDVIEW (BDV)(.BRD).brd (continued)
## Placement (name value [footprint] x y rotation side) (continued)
RT66  0201WMJ0000TCE+0201WMJ0000TJE~~MCR006YRTJ000~~RC0201JR-070RL+RC0201JR-130RL~~WR02X000PAL  [R0201]  23.24 17.73 90 top
RT67  0201WMJ0105TCE~~MCR006YRTJ105~~RC0201JR-071ML~~WR02X105JAL  [R0201]  23.21 27.63 0 top
RT68  0201WMJ0000TCE+0201WMJ0000TJE~~MCR006YRTJ000~~RC0201JR-070RL+RC0201JR-130RL~~WR02X000PAL  [R0201]  26.74 35.28 90 bottom
RT69  0201WMJ0000TCE+0201WMJ0000TJE~~MCR006YRTJ000~~RC0201JR-070RL+RC0201JR-130RL~~WR02X000PAL  [R0201]  38.86 37.79 180 bottom
RT70  0201WMJ0000TCE+0201WMJ0000TJE~~MCR006YRTJ000~~RC0201JR-070RL+RC0201JR-130RL~~WR02X000PAL  [R0201]  38.86 36.52 180 bottom
RT71  0201WMJ0000TCE+0201WMJ0000TJE~~MCR006YRTJ000~~RC0201JR-070RL+RC0201JR-130RL~~WR02X000PAL  [R0201]  27.43 33.86 0 bottom
RT72  0201WMJ0000TCE+0201WMJ0000TJE~~MCR006YRTJ000~~RC0201JR-070RL+RC0201JR-130RL~~WR02X000PAL  [R0201]  27.56 33.09 90 bottom
RT73  0201WMJ0000TCE+0201WMJ0000TJE~~MCR006YRTJ000~~RC0201JR-070RL+RC0201JR-130RL~~WR02X000PAL  [R0201]  26.24 35.28 90 bottom
RT74  MCR006YRTJ222~~RC0201JR-072K2L~~0201WMJ0222TCE+0201WMJ0222TJE~~WR02X222 JAL  [R0201]  38.86 37.16 180 bottom
RT75  MCR006YRTJ222~~RC0201JR-072K2L~~0201WMJ0222TCE+0201WMJ0222TJE~~WR02X222 JAL  [R0201]  38.86 35.89 180 bottom
RT76  0201WMJ0332TCE~~MCR006YRTJ332~~RC0201JR-073K3L~~WR02X332JAL  [R0201]  39.11 35.07 270 bottom
RT77  0201WMJ0332TCE~~MCR006YRTJ332~~RC0201JR-073K3L~~WR02X332JAL  [R0201]  27.25 35.28 270 bottom
RT78  0201WMJ0000TCE+0201WMJ0000TJE~~MCR006YRTJ000~~RC0201JR-070RL+RC0201JR-130RL~~WR02X000PAL  [R0201]  25.78 24.97 90 bottom
RT79  0402WGJ0000TCE+0402WGJ0000TJE~~RC1005J000CS~~RC0402JR-070RL+RC0402JR-130RL~~RM04JTN0  [R0402_0D65]  27.05 28.27 180 bottom
RT80  0201WMJ0104TCE~~MCR006YRTJ104~~RC0201JR-07100KL~~WR02X104JAL  [R0201]  24.51 33.47 180 bottom
RT81  RC0402JR-076K8L~~0402WGJ0682TCE~~RC1005J682CS~~RM04JTN682  [R0402]  20.32 34.24 90 top
RT82  0201WMJ0000TCE+0201WMJ0000TJE~~MCR006YRTJ000~~RC0201JR-070RL+RC0201JR-130RL~~WR02X000PAL  [R0201]  24.64 34.62 90 bottom
RT83  0201WMJ0104TCE~~MCR006YRTJ104~~RC0201JR-07100KL~~WR02X104JAL  [R0201]  24 34.62 90 bottom
RT84  0201WMJ0103TCE+0201WMJ0103TJE~~MCR006YRTJ103~~RC0201JR-0710KL~~WR02X103JAL  [R0201]  28.32 17.73 90 top
RT85  0201WMJ0103TCE+0201WMJ0103TJE~~MCR006YRTJ103~~RC0201JR-0710KL~~WR02X103JAL  [R0201]  27.81 17.73 90 top
RT86  0201WMJ0103TCE+0201WMJ0103TJE~~MCR006YRTJ103~~RC0201JR-0710KL~~WR02X103JAL  [R0201]  31.37 19.89 180 top
RT87  0201WMJ0103TCE+0201WMJ0103TJE~~MCR006YRTJ103~~RC0201JR-0710KL~~WR02X103JAL  [R0201]  31.37 19 180 top
RT88  LR122WF500NT2E~~PA2512FKF7W0R005E~~MFL12KR005FT  [NB_RTC0805]  29.72 13.03 180 top
RT89  0201WMJ0000TCE+0201WMJ0000TJE~~MCR006YRTJ000~~RC0201JR-070RL+RC0201JR-130RL~~WR02X000PAL  [R0201]  30.22 14.68 90 top
RT90  0201WMJ0000TCE+0201WMJ0000TJE~~MCR006YRTJ000~~RC0201JR-070RL+RC0201JR-130RL~~WR02X000PAL  [R0201]  29.59 14.68 90 top
RT91  0201WMJ0105TCE~~MCR006YRTJ105~~RC0201JR-071ML~~WR02X105JAL  [R0201]  22.2 8.46 90 top
RT92  0201WMJ0105TCE~~MCR006YRTJ105~~RC0201JR-071ML~~WR02X105JAL  [R0201]  20.06 8.93 0 top
RT93  0201WMF3302TCE+0201WMF3302TEE~~MCR006YRTF3302~~RC0201FR-0733KL~~WR02X3302FAL  [R0201]  23.62 12.47 180 bottom
RT94  RC0201FR-0747KL~~MCR006YRTF473~~WR02X473FAL~~0201WMF4702TCE  [R0201]  21.18 8.86 0 top
RT95  0201WMJ0104TCE~~MCR006YRTJ104~~RC0201JR-07100KL~~WR02X104JAL  [R0201]  23.42 9.07 270 top
RT96  0201WMF3302TCE+0201WMF3302TEE~~MCR006YRTF3302~~RC0201FR-0733KL~~WR02X3302FAL  [R0201]  22.4 12.47 0 bottom
RT97  0201WMJ0104TCE~~MCR006YRTJ104~~RC0201JR-07100KL~~WR02X104JAL  [R0201]  23.98 14.96 180 bottom
RT98  0201WMJ0103TCE+0201WMJ0103TJE~~MCR006YRTJ103~~RC0201JR-0710KL~~WR02X103JAL  [R0201]  32.64 7.82 0 top
RT99  0201WMJ0105TCE~~MCR006YRTJ105~~RC0201JR-071ML~~WR02X105JAL  [R0201]  29.92 10.03 90 top
RT100  0201WMJ0474TCE~~MCR006YRTJ474~~RC0201JR-07470KL~~WR02X474 JAL  [R0201]  22.2 7.44 270 top
RT101  WR02X102JAL~~RC0201JR-071KL~~0201WMJ0102TCE+0201WMJ0102TJE~~MCR006YRTJ102  [R0201]  34.14 9.83 0 top
RT102  0201WMF4992TCE~~MCR006YRTF4992~~RC0201FR-0749K9L  [R0201]  33.07 11.35 0 top
RT103  0201WMJ0000TCE+0201WMJ0000TJE~~MCR006YRTJ000~~RC0201JR-070RL+RC0201JR-130RL~~WR02X000PAL  [R0201]  29.36 10.03 270 top
RT104  0201WMJ0474TCE~~MCR006YRTJ474~~RC0201JR-07470KL~~WR02X474 JAL  [R0201]  22.2 6.27 270 top
RT105  0201WMJ0203TCE~~MCR006YRTJ203~~RC0201JR-0720KL~~WR02X203JAL  [R0201]  24.76 7.44 90 top
RT106  0201WMJ0104TCE~~MCR006YRTJ104~~RC0201JR-07100KL~~WR02X104JAL  [R0201]  30.38 11.35 0 top
RT111  0201WMJ0000TCE+0201WMJ0000TJE~~MCR006YRTJ000~~RC0201JR-070RL+RC0201JR-130RL~~WR02X000PAL  [R0201]  8.89 11.25 0 top
RT112  0201WMJ0000TCE+0201WMJ0000TJE~~MCR006YRTJ000~~RC0201JR-070RL+RC0201JR-130RL~~WR02X000PAL  [R0201]  9.14 9.73 90 top
RT113  0201WMJ0224TCE~~MCR006YRTJ224~~RC0201JR-07220KL~~WR02X224 JAL  [R0201]  11.17 23 90 bottom
RT114  0201WMJ0000TCE+0201WMJ0000TJE~~MCR006YRTJ000~~RC0201JR-070RL+RC0201JR-130RL~~WR02X000PAL  [R0201]  8.89 10.61 0 top
RT115  0201WMJ0224TCE~~MCR006YRTJ224~~RC0201JR-07220KL~~WR02X224 JAL  [R0201]  11.17 21.98 270 bottom
RT116  0201WMJ0000TCE+0201WMJ0000TJE~~MCR006YRTJ000~~RC0201JR-070RL+RC0201JR-130RL~~WR02X000PAL  [R0201]  8.61 9.73 90 top
RT117  0201WMJ0104TCE~~MCR006YRTJ104~~RC0201JR-07100KL~~WR02X104JAL  [R0201]  12.7 8.2 0 top
RT118  0201WMJ0224TCE~~MCR006YRTJ224~~RC0201JR-07220KL~~WR02X224 JAL  [R0201]  11.3 16.9 270 top
RT119  0201WMJ0224TCE~~MCR006YRTJ224~~RC0201JR-07220KL~~WR02X224 JAL  [R0201]  11.3 17.92 90 top
RT120  0201WMJ0000TCE+0201WMJ0000TJE~~MCR006YRTJ000~~RC0201JR-070RL+RC0201JR-130RL~~WR02X000PAL  [R0201]  8.89 13.15 0 top
RT121  0201WMJ0000TCE+0201WMJ0000TJE~~MCR006YRTJ000~~RC0201JR-070RL+RC0201JR-130RL~~WR02X000PAL  [R0201]  8.89 12.52 0 top
RT122  0201WMJ0105TCE~~MCR006YRTJ105~~RC0201JR-071ML~~WR02X105JAL  [R0201]  8.76 11.17 270 bottom
RT123  0201WMJ0105TCE~~MCR006YRTJ105~~RC0201JR-071ML~~WR02X105JAL  [R0201]  8.76 10.13 90 bottom
RT124  0201WMJ0000TCE+0201WMJ0000TJE~~MCR006YRTJ000~~RC0201JR-070RL+RC0201JR-130RL~~WR02X000PAL  [R0201]  12.83 19.52 180 top
RT125  0201WMJ0000TCE+0201WMJ0000TJE~~MCR006YRTJ000~~RC0201JR-070RL+RC0201JR-130RL~~WR02X000PAL  [R0201]  12.83 20.13 180 top
RT126  0201WMJ0103TCE+0201WMJ0103TJE~~MCR006YRTJ103~~RC0201JR-0710KL~~WR02X103JAL  [R0201]  50.16 38.05 180 top
RT127  0201WMJ0472TCE~~MCR006YRTJ472~~RC0201JR-074K7L~~WR02X472JAL  [R0201]  25.27 20.01 90 bottom
RT128  0201WMJ0472TCE~~MCR006YRTJ472~~RC0201JR-074K7L~~WR02X472JAL  [R0201]  23.49 20.14 90 bottom
RT129  0201WMJ0000TCE+0201WMJ0000TJE~~MCR006YRTJ000~~RC0201JR-070RL+RC0201JR-130RL~~WR02X000PAL  [R0201]  47.88 32.33 270 bottom
RT130  0201WMJ0000TCE+0201WMJ0000TJE~~MCR006YRTJ000~~RC0201JR-070RL+RC0201JR-130RL~~WR02X000PAL  [R0201]  27.58 37.21 0 bottom
RT131  0201WMJ0224TCE~~MCR006YRTJ224~~RC0201JR-07220KL~~WR02X224 JAL  [R0201]  11.17 21.98 270 top
RT132  0201WMJ0224TCE~~MCR006YRTJ224~~RC0201JR-07220KL~~WR02X224 JAL  [R0201]  11.17 23 90 top
RT133  0201WMJ0224TCE~~MCR006YRTJ224~~RC0201JR-07220KL~~WR02X224 JAL  [R0201]  11.3 17.92 90 bottom
RT134  0201WMJ0224TCE~~MCR006YRTJ224~~RC0201JR-07220KL~~WR02X224 JAL  [R0201]  11.3 16.9 270 bottom
RT135  0201WMJ0103TCE+0201WMJ0103TJE~~MCR006YRTJ103~~RC0201JR-0710KL~~WR02X103JAL  [R0201]  31.49 11.35 0 top
RU1  RC0201FR-07100RL~~WR02X1000FAL~~0201WMF1000TCE~~MCR006YRTF1000  [R0201]  112.32 61.03 270 top
RU2  RC0201FR-07100RL~~WR02X1000FAL~~0201WMF1000TCE~~MCR006YRTF1000  [R0201]  111.76 61.03 270 top
RU3  RC0201FR-07100RL~~WR02X1000FAL~~0201WMF1000TCE~~MCR006YRTF1000  [R0201]  112.88 61.03 270 top
RU4  RC0201JR-072K2L~~MCR006YRTJ222~~WR02X222 JAL~~0201WMJ0222TCE+0201WMJ0222TJE  [R0201]  69.31 49.81 270 top
RU5  0201WMF1500TCE~~MCR006YRTF1500~~RC0201FR-07150RL  [R0201]  89.91 37.54 180 bottom
RU6  0201WMF1500TCE~~MCR006YRTF1500~~RC0201FR-07150RL  [R0201]  104.77 38.3 90 bottom
RU7  0201WMJ0103TCE+0201WMJ0103TJE~~MCR006YRTJ103~~RC0201JR-0710KL~~WR02X103JAL  [R0201]  76.07 61.8 0 top
RU8  0201WMJ0472TCE~~MCR006YRTJ472~~RC0201JR-074K7L~~WR02X472JAL  [R0201]  67.21 50.77 0 top
RU9  0201WMJ0472TCE~~MCR006YRTJ472~~RC0201JR-074K7L~~WR02X472JAL  [R0201]  67.21 50.24 0 top
RU10  0201WMJ0472TCE~~MCR006YRTJ472~~RC0201JR-074K7L~~WR02X472JAL  [R0201]  57.15 57.1 180 bottom
RU11  0201WMJ0472TCE~~MCR006YRTJ472~~RC0201JR-074K7L~~WR02X472JAL  [R0201]  55.12 74.62 180 top
RU12  0201WMJ0104TCE~~MCR006YRTJ104~~RC0201JR-07100KL~~WR02X104JAL  [R0201]  73.28 60.02 0 top
RU13  0201WMJ0203TCE~~MCR006YRTJ203~~RC0201JR-0720KL~~WR02X203JAL  [R0201]  64.26 50.98 0 top
RU14  0201WMJ0203TCE~~MCR006YRTJ203~~RC0201JR-0720KL~~WR02X203JAL  [R0201]  66.19 50.24 0 top
RU15  0201WMJ0203TCE~~MCR006YRTJ203~~RC0201JR-0720KL~~WR02X203JAL  [R0201]  58.67 57.1 0 bottom
RU16  0201WMJ0203TCE~~MCR006YRTJ203~~RC0201JR-0720KL~~WR02X203JAL  [R0201]  55.12 75.13 0 top
RU17  WR02X102JAL~~RC0201JR-071KL~~0201WMJ0102TCE+0201WMJ0102TJE~~MCR006YRTJ102  [R0201]  114.81 36.65 270 bottom
RU18  0201WMJ0103TCE+0201WMJ0103TJE~~MCR006YRTJ103~~RC0201JR-0710KL~~WR02X103JAL  [R0201]  114.3 36.65 270 bottom
RU19  MCR006YRTF4990~~RC0201FR-07499RL~~WR02X4990FAL~~0201WMF4990TCE  [R0201]  114.17 38.3 90 bottom
RU20  0201WMJ0000TCE+0201WMJ0000TJE~~MCR006YRTJ000~~RC0201JR-070RL+RC0201JR-130RL~~WR02X000PAL  [R0201]  106.93 36.14 270 bottom
RU21  WR02X102JAL~~RC0201JR-071KL~~0201WMJ0102TCE+0201WMJ0102TJE~~MCR006YRTJ102  [R0201]  112.9 38.3 270 bottom
RU22  0201WMJ0510TCE~~MCR006YRTJ510~~RC0201JR-0751RL~~WR02X510JAL  [R0201]  106.3 36.14 270 bottom
RU23  0201WMJ0510TCE~~MCR006YRTJ510~~RC0201JR-0751RL~~WR02X510JAL  [R0201]  109.09 36.78 270 bottom
RU24  0201WMF499JTCE~~MCR006YRTF49R9~~RC0201FR-0749R9L~~WR02X49R9FAL  [R0201]  112.39 38.3 90 bottom
RU25  0201WMJ0000TCE+0201WMJ0000TJE~~MCR006YRTJ000~~RC0201JR-070RL+RC0201JR-130RL~~WR02X000PAL  [R0201]  108.33 38.55 0 bottom
RU26  0201WMF499JTCE~~MCR006YRTF49R9~~RC0201FR-0749R9L~~WR02X49R9FAL  [R0201]  79.3 60.37 90 top
RU27  0201WMJ0510TCE~~MCR006YRTJ510~~RC0201JR-0751RL~~WR02X510JAL  [R0201]  109.73 36.78 90 bottom
RU28  0201WMF499JTCE~~MCR006YRTF49R9~~RC0201FR-0749R9L~~WR02X49R9FAL  [R0201]  58.42 42.36 0 bottom
RU29  0201WMJ0000TCE+0201WMJ0000TJE~~MCR006YRTJ000~~RC0201JR-070RL+RC0201JR-130RL~~WR02X000PAL  [R0201]  109.47 38.55 180 bottom
RU30  0201WMJ0510TCE~~MCR006YRTJ510~~RC0201JR-0751RL~~WR02X510JAL  [R0201]  105.54 38.3 90 bottom
RU31  0201WMJ0000TCE+0201WMJ0000TJE~~MCR006YRTJ000~~RC0201JR-070RL+RC0201JR-130RL~~WR02X000PAL  [R0201]  107.57 36.14 90 bottom
RU32  0201WMJ0103TCE+0201WMJ0103TJE~~MCR006YRTJ103~~RC0201JR-0710KL~~WR02X103JAL  [R0201]  59.94 79.07 90 top
RU33  0201WMJ0000TCE+0201WMJ0000TJE~~MCR006YRTJ000~~RC0201JR-070RL+RC0201JR-130RL~~WR02X000PAL  [R0201]  106.93 38.3 90 bottom
RU34  0201WMJ0510TCE~~MCR006YRTJ510~~RC0201JR-0751RL~~WR02X510JAL  [R0201]  106.3 38.3 270 bottom
RU35  RC0201JR-072K2L~~MCR006YRTJ222~~WR02X222 JAL~~0201WMJ0222TCE+0201WMJ0222TJE  [R0201]  67.46 54.18 270 top
RU36  RC0201JR-072K2L~~MCR006YRTJ222~~WR02X222 JAL~~0201WMJ0222TCE+0201WMJ0222TJE  [R0201]  55.52 52.85 0 bottom
RU37  0201WMF499JTCE~~MCR006YRTF49R9~~RC0201FR-0749R9L~~WR02X49R9FAL  [R0201]  71.5 71.07 90 bottom
RU38  0201WMJ0100TCE~~MCR006YRTJ100~~RC0201JR-0710RL~~WR02X100 JAL  [R0201]  73.53 71.07 90 bottom
RU39  0201WMJ0100TCE~~MCR006YRTJ100~~RC0201JR-0710RL~~WR02X100 JAL  [R0201]  73.02 71.07 90 bottom
RU40  0201WMJ0100TCE~~MCR006YRTJ100~~RC0201JR-0710RL~~WR02X100 JAL  [R0201]  72.52 71.07 90 bottom
RU41  RC0201JR-072K2L~~MCR006YRTJ222~~WR02X222 JAL~~0201WMJ0222TCE+0201WMJ0222TJE  [R0201]  67.61 52.91 180 top
RU42  RC0201JR-072K2L~~MCR006YRTJ222~~WR02X222 JAL~~0201WMJ0222TCE+0201WMJ0222TJE  [R0201]  68.63 52.91 0 top
RU43  0201WMJ0100TCE~~MCR006YRTJ100~~RC0201JR-0710RL~~WR02X100 JAL  [R0201]  72.01 71.07 90 bottom
RU44  0201WMJ0104TCE~~MCR006YRTJ104~~RC0201JR-07100KL~~WR02X104JAL  [R0201]  72.26 61.67 180 top
RU45  RC0201FR-0775KL~~MCR006YRTF7502~~WR02X7502FAL~~0201WMF7502TCE  [R0201]  74.42 63.19 90 top
RU46  RC0201FR-0775KL~~MCR006YRTF7502~~WR02X7502FAL~~0201WMF7502TCE  [R0201]  75.44 63.19 90 top
RU47  0201WMJ0203TCE~~MCR006YRTJ203~~RC0201JR-0720KL~~WR02X203JAL  [R0201]  57.66 86.31 270 bottom
RU48  0201WMJ0472TCE~~MCR006YRTJ472~~RC0201JR-074K7L~~WR02X472JAL  [R0201]  66.93 54.18 270 top
RU49  0201WMJ0472TCE~~MCR006YRTJ472~~RC0201JR-074K7L~~WR02X472JAL  [R0201]  65.25 52.83 90 top
RU50  0201WMJ0472TCE~~MCR006YRTJ472~~RC0201JR-074K7L~~WR02X472JAL  [R0201]  66.37 60.17 180 top
RU51  0201WMJ0104TCE+0201WMJ0104TEE~~MCR006YRTJ104~~RC0201JR-07100KL~~WR02X104JAL  [R0201]  61.47 45.41 180 top
RU52  0201WMJ0104TCE+0201WMJ0104TEE~~MCR006YRTJ104~~RC0201JR-07100KL~~WR02X104JAL  [R0201]  57.45 88.41 90 top
RU53  0201WMJ0104TCE+0201WMJ0104TEE~~MCR006YRTJ104~~RC0201JR-07100KL~~WR02X104JAL  [R0201]  57.45 88.41 90 bottom
RU54  WR02X102JAL~~RC0201JR-071KL~~0201WMJ0102TCE+0201WMJ0102TJE~~MCR006YRTJ102  [R0201]  67.69 49.3 0 top
RU55  0201WMJ0103TCE+0201WMJ0103TJE~~MCR006YRTJ103~~RC0201JR-0710KL~~WR02X103JAL  [R0201]  57.02 48.59 180 bottom
RU56  0201WMJ0103TCE+0201WMJ0103TJE~~MCR006YRTJ103~~RC0201JR-0710KL~~WR02X103JAL  [R0201]  57.02 49.35 180 bottom
RU57  0201WMJ0472TCE~~MCR006YRTJ472~~RC0201JR-074K7L~~WR02X472JAL  [R0201]  56.89 86.31 270 bottom
RU58  0201WMJ0203TCE~~MCR006YRTJ203~~RC0201JR-0720KL~~WR02X203JAL  [R0201]  66.37 60.68 0 top
RU59  0201WMJ0472TCE~~MCR006YRTJ472~~RC0201JR-074K7L~~WR02X472JAL  [R0201]  61.97 46.17 180 top
RU60  0201WMJ0104TCE+0201WMJ0104TEE~~MCR006YRTJ104~~RC0201JR-07100KL~~WR02X104JAL  [R0201]  58.01 88.41 270 top
RU61  0201WMJ0472TCE~~MCR006YRTJ472~~RC0201JR-074K7L~~WR02X472JAL  [R0201]  58.01 88.41 270 bottom
RU62  0201WMJ0203TCE~~MCR006YRTJ203~~RC0201JR-0720KL~~WR02X203JAL  [R0201]  58.55 48.59 0 bottom
RU63  0201WMJ0203TCE~~MCR006YRTJ203~~RC0201JR-0720KL~~WR02X203JAL  [R0201]  58.55 49.35 0 bottom
RU64  0201WMJ0472TCE~~MCR006YRTJ472~~RC0201JR-074K7L~~WR02X472JAL  [R0201]  54.99 59.26 0 bottom
RU65  0201WMF2000TCE~~MCR006YRTF2000~~RC0201FR-072OORL~~WR02X2000FAL  [R0201]  58.67 52.78 180 bottom
RU66  0201WMJ0000TCE+0201WMJ0000TJE~~MCR006YRTJ000~~RC0201JR-070RL+RC0201JR-130RL~~WR02X000PAL  [R0201]  58.67 63.45 180 bottom
RU67  0201WMJ0203TCE~~MCR006YRTJ203~~RC0201JR-0720KL~~WR02X203JAL  [R0201]  54.99 59.89 180 bottom
RU68  0201WMJ0000TCE+0201WMJ0000TJE~~MCR006YRTJ000~~RC0201JR-070RL+RC0201JR-130RL~~WR02X000PAL  [R0201]  58.67 62.94 180 bottom
RU69  0201WMJ0000TCE+0201WMJ0000TJE~~MCR006YRTJ000~~RC0201JR-070RL+RC0201JR-130RL~~WR02X000PAL  [R0201]  58.67 61.8 180 bottom
RU70  0201WMJ0000TCE+0201WMJ0000TJE~~MCR006YRTJ000~~RC0201JR-070RL+RC0201JR-130RL~~WR02X000PAL  [R0201]  58.67 62.3 180 bottom
RU71  0201WMJ0000TCE+0201WMJ0000TJE~~MCR006YRTJ000~~RC0201JR-070RL+RC0201JR-130RL~~WR02X000PAL  [R0201]  143.05 11 90 bottom
RU72  0201WMJ0000TCE+0201WMJ0000TJE~~MCR006YRTJ000~~RC0201JR-070RL+RC0201JR-130RL~~WR02X000PAL  [R0201]  143.56 11 90 bottom
RU73  0201WMF1500TCE~~MCR006YRTF1500~~RC0201FR-07150RL  [R0201]  64.77 63.07 180 top
RU74  0201WMF330JTCE+0201WMF330JTEE~~MCR006YRTF33R0~~RC0201FR-0733RL~~WR02X33R0FAL  [R0201]  65.17 55.09 270 top
RU75  0201WMF330JTCE+0201WMF330JTEE~~MCR006YRTF33R0~~RC0201FR-0733RL~~WR02X33R0FAL  [R0201]  67.97 55.45 270 top
RU76  RC0201FR-07100RL~~WR02X1000FAL~~0201WMF1000TCE~~MCR006YRTF1000  [R0201]  114.68 38.3 90 bottom
RU77  0201WMJ0104TCE~~MCR006YRTJ104~~RC0201JR-07100KL~~WR02X104JAL  [R0201]  54.99 57.35 0 bottom
RU78  0201WMJ0104TCE~~MCR006YRTJ104~~RC0201JR-07100KL~~WR02X104JAL  [R0201]  54.99 56.72 180 bottom
RU79  0201WMJ0103TCE+0201WMJ0103TJE~~MCR006YRTJ103~~RC0201JR-0710KL~~WR02X103JAL  [R0201]  54.99 58.62 0 bottom
RU80  0201WMJ0203TCE~~MCR006YRTJ203~~RC0201JR-0720KL~~WR02X203JAL  [R0201]  54.99 57.99 0 bottom
RU81  0201WMJ0106TCE//RC0201JR-0710ML~~RC0201JR-0710ML  [R0201]  64.01 71.32 90 bottom
RU82  0201WMJ0000TCE+0201WMJ0000TJE~~MCR006YRTJ000~~RC0201JR-070RL+RC0201JR-130RL~~WR02X000PAL  [R0201]  64.64 71.83 270 bottom
RU83  0201WMJ0000TCE+0201WMJ0000TJE~~MCR006YRTJ000~~RC0201JR-070RL+RC0201JR-130RL~~WR02X000PAL  [R0201]  64.64 70.81 90 bottom
RU84  0201WMF330JTCE~~MCR006YRTF33R0~~RC0201FR-0733RL~~WR02X33R0FAL  [R0201]  66.67 70.81 90 bottom
RU85  0201WMJ0000TCE+0201WMJ0000TJE~~MCR006YRTJ000~~RC0201JR-070RL+RC0201JR-130RL~~WR02X000PAL  [R0201]  58.8 45.41 90 bottom
RU86  0201WMJ0000TCE+0201WMJ0000TJE~~MCR006YRTJ000~~RC0201JR-070RL+RC0201JR-130RL~~WR02X000PAL  [R0201]  58.8 46.43 270 bottom
RU87  0201WMF2003TCE~~RC0201FR-07200KL  [R0201]  58.16 45.41 90 bottom
RU88  0201WMF604JTCE~~RC0201FR-0760R4L  [R0201]  58.42 43.51 0 bottom
RU89  0201WMF2702TCE+0201WMF2702TEE~~MCR006YRTF2702~~RC0201FR-0727KL~~WR02X2702FAL  [R0201]  55.12 77.29 180 top
RU90  0201WMJ0103TCE+0201WMJ0103TJE~~MCR006YRTJ103~~RC0201JR-0710KL~~WR02X103JAL  [R0201]  54.86 63.95 270 bottom
RU91  0201WMF2702TCE+0201WMF2702TEE~~MCR006YRTF2702~~RC0201FR-0727KL~~WR02X2702FAL  [R0201]  55.75 64.67 180 bottom
RU92  0201WMJ0472TCE~~MCR006YRTJ472~~RC0201JR-074K7L~~WR02X472JAL  [R0201]  54.99 55.55 180 bottom
RU93  0201WMJ0472TCE~~MCR006YRTJ472~~RC0201JR-074K7L~~WR02X472JAL  [R0201]  54.99 56.18 0 bottom
RU94  0201WMJ0472TCE~~MCR006YRTJ472~~RC0201JR-074K7L~~WR02X472JAL  [R0201]  63.63 56.84 270 top
RU95  0201WMJ0472TCE~~MCR006YRTJ472~~RC0201JR-074K7L~~WR02X472JAL  [R0201]  64.13 56.84 90 top
RU96  0201WMJ0472TCE~~MCR006YRTJ472~~RC0201JR-074K7L~~WR02X472JAL  [R0201]  61.59 56.97 0 top
RU97  0201WMJ0472TCE~~MCR006YRTJ472~~RC0201JR-074K7L~~WR02X472JAL  [R0201]  61.59 56.46 180 top
RU98  0201WMJ0472TCE~~MCR006YRTJ472~~RC0201JR-074K7L~~WR02X472JAL  [R0201]  57.15 54.81 0 bottom
RU99  0201WMJ0472TCE~~MCR006YRTJ472~~RC0201JR-074K7L~~WR02X472JAL  [R0201]  58.67 54.68 180 bottom
RU100  0201WMJ0472TCE~~MCR006YRTJ472~~RC0201JR-074K7L~~WR02X472JAL  [R0201]  58.67 56.46 180 bottom
RU101  0201WMJ0103TCE+0201WMJ0103TJE~~MCR006YRTJ103~~RC0201JR-0710KL~~WR02X103JAL  [R0201]  58.67 59.89 180 bottom
RU102  0201WMJ0472TCE~~MCR006YRTJ472~~RC0201JR-074K7L~~WR02X472JAL  [R0201]  57.15 56.46 0 bottom
RU103  0201WMJ0103TCE+0201WMJ0103TJE~~MCR006YRTJ103~~RC0201JR-0710KL~~WR02X103JAL  [R0201]  55.12 78.86 0 top
RU105  0201WMJ0472TCE~~MCR006YRTJ472~~RC0201JR-074K7L~~WR02X472JAL  [R0201]  57.15 53.79 0 bottom
RU106  0201WMJ0472TCE~~MCR006YRTJ472~~RC0201JR-074K7L~~WR02X472JAL  [R0201]  58.67 53.29 180 bottom
RU107  0201WMJ0472TCE~~MCR006YRTJ472~~RC0201JR-074K7L~~WR02X472JAL  [R0201]  57.15 55.45 0 bottom
RU108  0201WMJ0472TCE~~MCR006YRTJ472~~RC0201JR-074K7L~~WR02X472JAL  [R0201]  58.67 55.45 180 bottom
RU109  0201WMJ0472TCE~~MCR006YRTJ472~~RC0201JR-074K7L~~WR02X472JAL  [R0201]  57.15 54.3 0 bottom
RU110  0201WMJ0472TCE~~MCR006YRTJ472~~RC0201JR-074K7L~~WR02X472JAL  [R0201]  58.67 54.18 180 bottom
RU111  0201WMJ0103TCE+0201WMJ0103TJE~~MCR006YRTJ103~~RC0201JR-0710KL~~WR02X103JAL  [R0201]  57.15 53.29 180 bottom
RU112  0201WMJ0472TCE~~MCR006YRTJ472~~RC0201JR-074K7L~~WR02X472JAL  [R0201]  58.55 80.59 90 bottom
RU113  0201WMJ0203TCE~~MCR006YRTJ203~~RC0201JR-0720KL~~WR02X203JAL  [R0201]  58.55 79.07 270 bottom
RU114  0201WMJ0472TCE~~MCR006YRTJ472~~RC0201JR-074K7L~~WR02X472JAL  [R0201]  59.18 80.59 90 bottom
RU115  0201WMJ0000TCE+0201WMJ0000TJE~~MCR006YRTJ000~~RC0201JR-070RL+RC0201JR-130RL~~WR02X000PAL  [R0201]  58.67 57.86 180 bottom
RU116  0201WMJ0000TCE+0201WMJ0000TJE~~MCR006YRTJ000~~RC0201JR-070RL+RC0201JR-130RL~~WR02X000PAL  [R0201]  57.15 57.86 180 bottom
RU117  0201WMJ0203TCE~~MCR006YRTJ203~~RC0201JR-0720KL~~WR02X203JAL  [R0201]  59.18 79.07 270 bottom
RU118  0201WMJ0472TCE~~MCR006YRTJ472~~RC0201JR-074K7L~~WR02X472JAL  [R0201]  58.42 83.89 90 top
RU119  0201WMJ0103TCE+0201WMJ0103TJE~~MCR006YRTJ103~~RC0201JR-0710KL~~WR02X103JAL  [R0201]  61.47 59.26 180 top
RU120  0201WMJ0103TCE+0201WMJ0103TJE~~MCR006YRTJ103~~RC0201JR-0710KL~~WR02X103JAL  [R0201]  58.67 59.26 180 bottom
RU121  0201WMJ0000TCE+0201WMJ0000TJE~~MCR006YRTJ000~~RC0201JR-070RL+RC0201JR-130RL~~WR02X000PAL  [R0201]  58.67 58.62 180 bottom
RU122  0201WMJ0103TCE+0201WMJ0103TJE~~MCR006YRTJ103~~RC0201JR-0710KL~~WR02X103JAL  [R0201]  61.47 58.75 180 top
RU123  0201WMJ0472TCE~~MCR006YRTJ472~~RC0201JR-074K7L~~WR02X472JAL  [R0201]  58.42 86.31 270 top
RU124  0201WMJ0203TCE~~MCR006YRTJ203~~RC0201JR-0720KL~~WR02X203JAL  [R0201]  59.18 86.31 90 top
RU125  0201WMJ0472TCE~~MCR006YRTJ472~~RC0201JR-074K7L~~WR02X472JAL  [R0201]  59.18 83.89 90 bottom
RU126  0201WMJ0000TCE+0201WMJ0000TJE~~MCR006YRTJ000~~RC0201JR-070RL+RC0201JR-130RL~~WR02X000PAL  [R0201]  76.96 63.19 270 top
RU127  0201WMF330JTCE~~MCR006YRTF33R0~~RC0201FR-0733RL~~WR02X33R0FAL  [R0201]  57.66 83.89 270 top
RU129  0201WMF330JTCE~~MCR006YRTF33R0~~RC0201FR-0733RL~~WR02X33R0FAL  [R0201]  56.89 79.07 270 top
RU130  0201WMJ0000TCE+0201WMJ0000TJE~~MCR006YRTJ000~~RC0201JR-070RL+RC0201JR-130RL~~WR02X000PAL  [R0201]  59.54 86.23 90 bottom
RU131  0201WMF330JTCE~~MCR006YRTF33R0~~RC0201FR-0733RL~~WR02X33R0FAL  [R0201]  58.42 83.89 270 bottom
RU132  0201WMJ0000TCE+0201WMJ0000TJE~~MCR006YRTJ000~~RC0201JR-070RL+RC0201JR-130RL~~WR02X000PAL  [R0201]  59.94 79.07 90 bottom
RU133  0201WMF330JTCE~~MCR006YRTF33R0~~RC0201FR-0733RL~~WR02X33R0FAL  [R0201]  56.89 81.48 270 top
RU134  0201WMF2000TCE~~MCR006YRTF2000~~RC0201FR-072OORL~~WR02X2000FAL  [R0201]  78.31 62.18 90 top
RU135  0201WMF330JTCE~~MCR006YRTF33R0~~RC0201FR-0733RL~~WR02X33R0FAL  [R0201]  69.59 72.59 0 bottom
RU136  0201WMF330JTCE~~MCR006YRTF33R0~~RC0201FR-0733RL~~WR02X33R0FAL  [R0201]  69.04 60.17 0 top
RU137  0201WMF2000TCE~~MCR006YRTF2000~~RC0201FR-072OORL~~WR02X2000FAL  [R0201]  73.66 59.26 270 top
RU138  0201WMF330JTCE~~MCR006YRTF33R0~~RC0201FR-0733RL~~WR02X33R0FAL  [R0201]  70.48 59.89 180 top
RU139  RC0201FR-0771K5L~~0201WMF7152TCE+0201WMF7152TEE  [R0201]  69.59 71.57 0 bottom
RU140  RC0201FR-0775KL~~MCR006YRTF7502~~WR02X7502FAL~~0201WMF7502TCE  [R0201]  69.59 72.08 0 bottom
RU141  0201WMF1130TCE~~RC0201FR-07113RL  [R0201]  58.42 42.92 180 bottom
RU142  RC0201FR-07100RL~~WR02X1000FAL~~0201WMF1000TCE~~MCR006YRTF1000  [R0201]  66.8 42.87 0 top
RU143  0201WMJ0103TCE+0201WMJ0103TJE~~MCR006YRTJ103~~RC0201JR-0710KL~~WR02X103JAL  [R0201]  57.66 86.31 270 top
RU144  0201WMJ0103TCE+0201WMJ0103TJE~~MCR006YRTJ103~~RC0201JR-0710KL~~WR02X103JAL  [R0201]  57.66 83.89 90 bottom
RU145  0201WMJ0203TCE~~MCR006YRTJ203~~RC0201JR-0720KL~~WR02X203JAL  [R0201]  61.62 47.67 180 top
RU146  0201WMJ0103TCE+0201WMJ0103TJE~~MCR006YRTJ103~~RC0201JR-0710KL~~WR02X103JAL  [R0201]  68.32 47.44 180 top
RU147  0201WMJ0103TCE+0201WMJ0103TJE~~MCR006YRTJ103~~RC0201JR-0710KL~~WR02X103JAL  [R0201]  67.18 44.52 180 top
RU150  0201WMJ0472TCE~~MCR006YRTJ472~~RC0201JR-074K7L~~WR02X472JAL  [R0201]  61.62 47.17 0 top
RU151  0201WMJ0000TCE+0201WMJ0000TJE~~MCR006YRTJ000~~RC0201JR-070RL+RC0201JR-130RL~~WR02X000PAL  [R0201]  77.39 61.29 90 top
RU152  0201WMJ0000TCE+0201WMJ0000TJE~~MCR006YRTJ000~~RC0201JR-070RL+RC0201JR-130RL~~WR02X000PAL  [R0201]  58.93 64.59 270 bottom
RU153  0201WMJ0104TCE+0201WMJ0104TEE~~MCR006YRTJ104~~RC0201JR-07100KL~~WR02X104JAL  [R0201]  55.12 74.62 0 bottom
RU154  0201WMJ0472TCE~~MCR006YRTJ472~~RC0201JR-074K7L~~WR02X472JAL  [R0201]  55.12 74.11 180 bottom
RU155  0201WMJ0472TCE+0201WMJ0472TEE~~MCR006YRTJ472~~RC0201JR-074K7L~~WR02X472JAL  [R0201]  55.12 75.77 180 top
RU156  0201WMJ0105TCE~~MCR006YRTJ105~~RC0201JR-071ML~~WR02X105JAL  [R0201]  55.12 76.78 180 top
RU157  0201WMJ0000TCE+0201WMJ0000TJE~~MCR006YRTJ000~~RC0201JR-070RL+RC0201JR-130RL~~WR02X000PAL  [R0201]  80.8 38.17 0 bottom
RU158  0201WMJ0472TCE~~MCR006YRTJ472~~RC0201JR-074K7L~~WR02X472JAL  [R0201]  57.66 79.07 90 top
RU159  0201WMJ0203TCE~~MCR006YRTJ203~~RC0201JR-0720KL~~WR02X203JAL  [R0201]  57.66 81.48 270 bottom
RU160  0201WMJ0104TCE~~MCR006YRTJ104~~RC0201JR-07100KL~~WR02X104JAL  [R0201]  80.01 37.92 90 bottom
RU161  RC0201JR-072K2L~~MCR006YRTJ222~~WR02X222 JAL~~0201WMJ0222TCE+0201WMJ0222TJE  [R0201]  128.27 89.33 0 top
RU162  WR02X102JAL~~RC0201JR-071KL~~0201WMJ0102TCE+0201WMJ0102TJE~~MCR006YRTJ102  [R0201]  79.27 36.65 180 bottom
RU163  0201WMJ0000TCE+0201WMJ0000TJE~~MCR006YRTJ000~~RC0201JR-070RL+RC0201JR-130RL~~WR02X000PAL  [R0201]  128.19 91.01 270 top
RU164  0201WMF604JTCE~~RC0201FR-0760R4L  [R0201]  78.74 38.17 180 bottom
RU165  0201WMJ0104TCE~~MCR006YRTJ104~~RC0201JR-07100KL~~WR02X104JAL  [R0201]  127 89.86 180 top
RU166  0201WMJ0000TCE+0201WMJ0000TJE~~MCR006YRTJ000~~RC0201JR-070RL+RC0201JR-130RL~~WR02X000PAL  [R0201]  80.39 34.16 180 bottom
RU167  0201WMJ0000TCE+0201WMJ0000TJE~~MCR006YRTJ000~~RC0201JR-070RL+RC0201JR-130RL~~WR02X000PAL  [R0201]  127 89.23 0 top
RU169  0201WMJ0104TCE~~MCR006YRTJ104~~RC0201JR-07100KL~~WR02X104JAL  [R0201]  55.12 74.11 0 top
RU170  0201WMJ0104TCE~~MCR006YRTJ104~~RC0201JR-07100KL~~WR02X104JAL  [R0201]  57.15 79.07 270 bottom
RU171  0201WMJ0103TCE+0201WMJ0103TJE~~MCR006YRTJ103~~RC0201JR-0710KL~~WR02X103JAL  [R0201]  68.63 51.97 180 top
RU172  WR02X102JAL~~RC0201JR-071KL~~0201WMJ0102TCE+0201WMJ0102TJE~~MCR006YRTJ102  [R0201]  57.66 79.07 270 bottom
RU173  0201WMJ0104TCE~~MCR006YRTJ104~~RC0201JR-07100KL~~WR02X104JAL  [R0201]  64.44 52.55 180 top
RU174  WR02X102JAL~~RC0201JR-071KL~~0201WMJ0102TCE+0201WMJ0102TJE~~MCR006YRTJ102  [R0201]  47.74 6.17 0 top
RU175  0201WMJ0104TCE~~MCR006YRTJ104~~RC0201JR-07100KL~~WR02X104JAL  [R0201]  67.56 63.19 270 top
RU176  0201WMJ0104TCE~~MCR006YRTJ104~~RC0201JR-07100KL~~WR02X104JAL  [R0201]  58.42 64.59 270 bottom
RU177  0201WMJ0104TCE~~MCR006YRTJ104~~RC0201JR-07100KL~~WR02X104JAL  [R0201]  67.69 70.28 180 bottom
RU178  0201WMJ0104TCE~~MCR006YRTJ104~~RC0201JR-07100KL~~WR02X104JAL  [R0201]  66.17 70.81 90 bottom
RU179  0201WMJ0104TCE~~MCR006YRTJ104~~RC0201JR-07100KL~~WR02X104JAL  [R0201]  67.82 71.07 180 bottom
RU180  0201WMJ0104TCE~~MCR006YRTJ104~~RC0201JR-07100KL~~WR02X104JAL  [R0201]  69.85 61.8 180 top
RU181  0201WMJ0104TCE~~MCR006YRTJ104~~RC0201JR-07100KL~~WR02X104JAL  [R0201]  80.8 37.67 180 bottom
RU182  0201WMF430JTCE~~RC0201FR-0743RL  [R0201]  110.23 36.78 270 bottom
RU183  RC0201FR-07100RL~~WR02X1000FAL~~0201WMF1000TCE~~MCR006YRTF1000  [R0201]  111.89 36.4 270 bottom
RU184  0201WMF560JTCE~~RC0201FR-0756RL~~MCR006YRTF56R0~~WR02X56R0FAL  [R0201]  111.38 36.4 270 bottom
RU185  0201WMJ0000TCE+0201WMJ0000TJE~~MCR006YRTJ000~~RC0201JR-070RL+RC0201JR-130RL~~WR02X000PAL  [R0201]  110.36 38.3 90 bottom
RU186  0201WMJ0000TCE+0201WMJ0000TJE~~MCR006YRTJ000~~RC0201JR-070RL+RC0201JR-130RL~~WR02X000PAL  [R0201]  111.63 38.3 90 bottom
RU187  0201WMJ0000TCE+0201WMJ0000TJE~~MCR006YRTJ000~~RC0201JR-070RL+RC0201JR-130RL~~WR02X000PAL  [R0201]  111 38.3 90 bottom
RU190  0402WGJ0000TCE+0402WGJ0000TJE~~RC1005J000CS~~RC0402JR-070RL+RC0402JR-130RL~~RM04JTN0  [R0402_0D65]  62.36 49.11 90 top
RU191  0402WGJ0000TCE+0402WGJ0000TJE~~RC1005J000CS~~RC0402JR-070RL+RC0402JR-130RL~~RM04JTN0  [R0402_0D65]  63.88 46.43 270 top
RU192  0201WMJ0104TCE~~MCR006YRTJ104~~RC0201JR-07100KL~~WR02X104JAL  [R0201]  68.32 48.33 180 top
RU193  0201WMJ0104TCE~~MCR006YRTJ104~~RC0201JR-07100KL~~WR02X104JAL  [R0201]  73.66 57.99 180 top
RU194  WR02X102JAL~~RC0201JR-071KL~~0201WMJ0102TCE+0201WMJ0102TJE~~MCR006YRTJ102  [R0201]  98.8 44.4 90 top
RU195  WR02X102JAL~~RC0201JR-071KL~~0201WMJ0102TCE+0201WMJ0102TJE~~MCR006YRTJ102  [R0201]  99.06 46.81 270 top
RU196  WR02X102JAL~~RC0201JR-071KL~~0201WMJ0102TCE+0201WMJ0102TJE~~MCR006YRTJ102  [R0201]  100.56 46.86 270 top
RU197  WR02X102JAL~~RC0201JR-071KL~~0201WMJ0102TCE+0201WMJ0102TJE~~MCR006YRTJ102  [R0201]  101.48 45.9 90 top
RU198  WR02X102JAL~~RC0201JR-071KL~~0201WMJ0102TCE+0201WMJ0102TJE~~MCR006YRTJ102  [R0201]  103.3 46.35 90 top
RU199  WR02X102JAL~~RC0201JR-071KL~~0201WMJ0102TCE+0201WMJ0102TJE~~MCR006YRTJ102  [R0201]  102.4 46.4 90 top
RU200  WR02X102JAL~~RC0201JR-071KL~~0201WMJ0102TCE+0201WMJ0102TJE~~MCR006YRTJ102  [R0201]  102.39 45.34 90 top
RU201  WR02X102JAL~~RC0201JR-071KL~~0201WMJ0102TCE+0201WMJ0102TJE~~MCR006YRTJ102  [R0201]  97.53 43.89 0 top
RU202  WR02X102JAL~~RC0201JR-071KL~~0201WMJ0102TCE+0201WMJ0102TJE~~MCR006YRTJ102  [R0201]  96.46 46.5 270 top
RU203  WR02X102JAL~~RC0201JR-071KL~~0201WMJ0102TCE+0201WMJ0102TJE~~MCR006YRTJ102  [R0201]  98.42 46.81 270 top
RU204  WR02X102JAL~~RC0201JR-071KL~~0201WMJ0102TCE+0201WMJ0102TJE~~MCR006YRTJ102  [R0201]  99.64 47.19 270 top
RU205  WR02X102JAL~~RC0201JR-071KL~~0201WMJ0102TCE+0201WMJ0102TJE~~MCR006YRTJ102  [R0201]  97.53 44.52 0 top
RU206  WR02X102JAL~~RC0201JR-071KL~~0201WMJ0102TCE+0201WMJ0102TJE~~MCR006YRTJ102  [R0201]  104.24 46.17 90 top
RU207  WR02X102JAL~~RC0201JR-071KL~~0201WMJ0102TCE+0201WMJ0102TJE~~MCR006YRTJ102  [R0201]  97.89 46.81 270 top
RU208  WR02X102JAL~~RC0201JR-071KL~~0201WMJ0102TCE+0201WMJ0102TJE~~MCR006YRTJ102  [R0201]  95.71 45.01 0 top
RU209  WR02X102JAL~~RC0201JR-071KL~~0201WMJ0102TCE+0201WMJ0102TJE~~MCR006YRTJ102  [R0201]  97.23 46.5 270 top
RU210  0201WMF499JTCE~~MCR006YRTF49R9~~RC0201FR-0749R9L~~WR02X49R9FAL  [R0201]  101.19 44.27 90 top
RU211  0201WMJ0103TCE+0201WMJ0103TJE~~MCR006YRTJ103~~RC0201JR-0710KL~~WR02X103JAL  [R0201]  113.66 38.3 90 bottom
RU212  0201WMJ0510TCE~~MCR006YRTJ510~~RC0201JR-0751RL~~WR02X510JAL  [R0201]  103.76 44.02 180 top
RU213  0201WMJ0103TCE+0201WMJ0103TJE~~MCR006YRTJ103~~RC0201JR-0710KL~~WR02X103JAL  [R0201]  107.64 43.3 0 top
RU214  0201WMJ0103TCE+0201WMJ0103TJE~~MCR006YRTJ103~~RC0201JR-0710KL~~WR02X103JAL  [R0201]  105.46 45.59 0 top
RU215  0201WMJ0103TCE+0201WMJ0103TJE~~MCR006YRTJ103~~RC0201JR-0710KL~~WR02X103JAL  [R0201]  107.31 44.14 90 top
RU216  0201WMJ0103TCE+0201WMJ0103TJE~~MCR006YRTJ103~~RC0201JR-0710KL~~WR02X103JAL  [R0201]  105.46 46.5 0 top
RU217  0201WMJ0510TCE~~MCR006YRTJ510~~RC0201JR-0751RL~~WR02X510JAL  [R0201]  102.11 44.4 0 top
RU218  0201WMJ0000TCE+0201WMJ0000TJE~~MCR006YRTJ000~~RC0201JR-070RL+RC0201JR-130RL~~WR02X000PAL  [R0201]  59.94 86.31 90 top
RU219  0201WMJ0000TCE+0201WMJ0000TJE~~MCR006YRTJ000~~RC0201JR-070RL+RC0201JR-130RL~~WR02X000PAL  [R0201]  44.12 7.47 180 top
RU220  0201WMJ0203TCE~~MCR006YRTJ203~~RC0201JR-0720KL~~WR02X203JAL  [R0201]  44.12 7.97 180 top
RU221  CS02W8F100LTCE  [R0402]  62.99 46.43 270 top
RU222  WR02X102JAL~~RC0201JR-071KL~~0201WMJ0102TCE+0201WMJ0102TJE~~MCR006YRTJ102  [R0201]  66.42 49.28 0 top
RU223  0201WMJ0472TCE~~MCR006YRTJ472~~RC0201JR-074K7L~~WR02X472JAL  [R0201]  64.36 55.34 180 top
RU224  WR02X102JAL~~RC0201JR-071KL~~0201WMJ0102TCE+0201WMJ0102TJE~~MCR006YRTJ102  [R0201]  106.68 34.24 0 bottom
RU225  0201WMJ0103TCE+0201WMJ0103TJE~~MCR006YRTJ103~~RC0201JR-0710KL~~WR02X103JAL  [R0201]  63.75 63.07 180 top
RU226  0201WMJ0104TCE~~MCR006YRTJ104~~RC0201JR-07100KL~~WR02X104JAL  [R0201]  61.47 60.37 0 top
RU227  0201WMJ0104TCE~~MCR006YRTJ104~~RC0201JR-07100KL~~WR02X104JAL  [R0201]  61.47 59.81 0 top
RU228  0201WMJ0000TCE+0201WMJ0000TJE~~MCR006YRTJ000~~RC0201JR-070RL+RC0201JR-130RL~~WR02X000PAL  [R0201]  75.31 60.02 180 top
RU229  0201WMJ0000TCE+0201WMJ0000TJE~~MCR006YRTJ000~~RC0201JR-070RL+RC0201JR-130RL~~WR02X000PAL  [R0201]  67.16 60.91 270 top
RU230  0201WMJ0000TCE+0201WMJ0000TJE~~MCR006YRTJ000~~RC0201JR-070RL+RC0201JR-130RL~~WR02X000PAL  [R0201]  70.74 53.31 270 top
RU231  0201WMJ0000TCE+0201WMJ0000TJE~~MCR006YRTJ000~~RC0201JR-070RL+RC0201JR-130RL~~WR02X000PAL  [R0201]  71.25 53.31 270 top
RU232  0201WMJ0104TCE~~MCR006YRTJ104~~RC0201JR-07100KL~~WR02X104JAL  [R0201]  102.92 30.15 180 bottom
RU233  WR02X102JAL~~RC0201JR-071KL~~0201WMJ0102TCE+0201WMJ0102TJE~~MCR006YRTJ102  [R0201]  99.67 45.08 90 top
RU234  WR02X102JAL~~RC0201JR-071KL~~0201WMJ0102TCE+0201WMJ0102TJE~~MCR006YRTJ102  [R0201]  100.56 45.79 270 top
RU235  WR02X102JAL~~RC0201JR-071KL~~0201WMJ0102TCE+0201WMJ0102TJE~~MCR006YRTJ102  [R0201]  104.24 47.22 90 top
RU236  WR02X102JAL~~RC0201JR-071KL~~0201WMJ0102TCE+0201WMJ0102TJE~~MCR006YRTJ102  [R0201]  99.67 43.81 0 top
RU237  WR02X102JAL~~RC0201JR-071KL~~0201WMJ0102TCE+0201WMJ0102TJE~~MCR006YRTJ102  [R0201]  103.27 47.57 90 top
RU238  WR02X102JAL~~RC0201JR-071KL~~0201WMJ0102TCE+0201WMJ0102TJE~~MCR006YRTJ102  [R0201]  102.26 47.47 0 top
RU239  WR02X102JAL~~RC0201JR-071KL~~0201WMJ0102TCE+0201WMJ0102TJE~~MCR006YRTJ102  [R0201]  97.18 45.29 0 top
RU240  WR02X102JAL~~RC0201JR-071KL~~0201WMJ0102TCE+0201WMJ0102TJE~~MCR006YRTJ102  [R0201]  101.47 47.52 90 top
RV2  0201WMJ0104TCE~~MCR006YRTJ104~~RC0201JR-07100KL~~WR02X104JAL  [R0201]  132.92 51.83 270 bottom
RV3  0201WMJ0000TCE+0201WMJ0000TJE~~MCR006YRTJ000~~RC0201JR-070RL+RC0201JR-130RL~~WR02X000PAL  [R0201]  133.51 51.83 270 bottom
RV4  0201WMF2202TCE+0201WMF2202TEE~~RC0201FR-0722KL~~MCR006YRTF2202~~WR02X2202FAL  [R0201]  128.79 87.1 90 top
RV5  0201WMJ0000TCE+0201WMJ0000TJE~~MCR006YRTJ000~~RC0201JR-070RL+RC0201JR-130RL~~WR02X000PAL  [R0201]  132.23 86.76 0 top
RV6  0201WMJ0000TCE+0201WMJ0000TJE~~MCR006YRTJ000~~RC0201JR-070RL+RC0201JR-130RL~~WR02X000PAL  [R0201]  128.23 87.1 270 top
RV7  0201WMJ0103TCE+0201WMJ0103TJE~~MCR006YRTJ103~~RC0201JR-0710KL~~WR02X103JAL  [R0201]  136.48 83.05 90 bottom
RV9  0201WMJ0103TCE+0201WMJ0103TJE~~MCR006YRTJ103~~RC0201JR-0710KL~~WR02X103JAL  [R0201]  136.56 80.08 270 bottom
RV10  0201WMJ0000TCE+0201WMJ0000TJE~~MCR006YRTJ000~~RC0201JR-070RL+RC0201JR-130RL~~WR02X000PAL  [R0201]  131.38 82.45 90 top
RV11  0201WMJ0000TCE+0201WMJ0000TJE~~MCR006YRTJ000~~RC0201JR-070RL+RC0201JR-130RL~~WR02X000PAL  [R0201]  128.3 82.43 180 top
RV12  0201WMJ0103TCE+0201WMJ0103TJE~~MCR006YRTJ103~~RC0201JR-0710KL~~WR02X103JAL  [R0201]  137.34 80.34 180 bottom
RV13  0201WMJ0000TCE+0201WMJ0000TJE~~MCR006YRTJ000~~RC0201JR-070RL+RC0201JR-130RL~~WR02X000PAL  [R0201]  135.95 80.7 90 bottom
RV15  RC0201FR-075K6L~~0201WMF5601TCE+0201WMF5601TEE  [R0201]  133.41 81.37 270 top
RV16  0201WMF1002TCE~~MCR006YRTF1002~~WR02X1002FAL~~RC0201FR-0710KL  [R0201]  132.86 81.37 90 top
RV17  0201WMJ0000TCE+0201WMJ0000TJE~~MCR006YRTJ000~~RC0201JR-070RL+RC0201JR-130RL~~WR02X000PAL  [R0201]  144.65 49.97 180 bottom
RV18  0201WMJ0000TCE+0201WMJ0000TJE~~MCR006YRTJ000~~RC0201JR-070RL+RC0201JR-130RL~~WR02X000PAL  [R0201]  134.23 81.63 180 top
RV19  RC0201JR-072K2L~~MCR006YRTJ222~~WR02X222 JAL~~0201WMJ0222TCE+0201WMJ0222TJE  [R0201]  142.38 53.57 90 bottom
RV20  RC0201JR-072K2L~~MCR006YRTJ222~~WR02X222 JAL~~0201WMJ0222TCE+0201WMJ0222TJE  [R0201]  146.57 50.61 270 bottom
RV21  0201WMF2491TCE~~RC0201FR-072K49L  [R0201]  159 80.21 0 top
RV22  MCR006YRTF1003~~RC0201FR-07100KL~~WR02X1003FAL~~0201WMF1003TCE+0201WMF1003TEE  [R0201]  128.73 81.28 0 top
RV23  0201WMJ0000TCE+0201WMJ0000TJE~~MCR006YRTJ000~~RC0201JR-070RL+RC0201JR-130RL~~WR02X000PAL  [R0201]  129.77 81.27 0 top
RV24  0201WMJ0000TCE+0201WMJ0000TJE~~MCR006YRTJ000~~RC0201JR-070RL+RC0201JR-130RL~~WR02X000PAL  [R0201]  142.37 52.52 90 bottom
RV25  0201WMJ0103TCE+0201WMJ0103TJE~~MCR006YRTJ103~~RC0201JR-0710KL~~WR02X103JAL  [R0201]  148.1 63.5 0 top
RV26  0201WMJ0000TCE+0201WMJ0000TJE~~MCR006YRTJ000~~RC0201JR-070RL+RC0201JR-130RL~~WR02X000PAL  [R0201]  146 52.37 270 bottom
RV27  0201WMJ0103TCE+0201WMJ0103TJE~~MCR006YRTJ103~~RC0201JR-0710KL~~WR02X103JAL  [R0201]  136.58 56.86 90 bottom
RV28  RC0201JR-072K2L~~MCR006YRTJ222~~WR02X222 JAL~~0201WMJ0222TCE+0201WMJ0222TJE  [R0201]  145.79 55.6 90 bottom
RV29  0201WMJ0103TCE+0201WMJ0103TJE~~MCR006YRTJ103~~RC0201JR-0710KL~~WR02X103JAL  [R0201]  144.12 55.6 270 bottom
RV30  RC0201JR-072K2L~~MCR006YRTJ222~~WR02X222 JAL~~0201WMJ0222TCE+0201WMJ0222TJE  [R0201]  145.24 55.6 90 bottom
RV31  0201WMJ0104TCE~~MCR006YRTJ104~~RC0201JR-07100KL~~WR02X104JAL  [R0201]  145.67 54.38 90 bottom
RV32  0201WMJ0103TCE+0201WMJ0103TJE~~MCR006YRTJ103~~RC0201JR-0710KL~~WR02X103JAL  [R0201]  134.11 51.83 270 bottom
RV33  RC0201JR-072K2L~~MCR006YRTJ222~~WR02X222 JAL~~0201WMJ0222TCE+0201WMJ0222TJE  [R0201]  146.91 55.6 90 bottom
RV34  0201WMJ0103TCE+0201WMJ0103TJE~~MCR006YRTJ103~~RC0201JR-0710KL~~WR02X103JAL  [R0201]  143.47 54.1 270 bottom
RV35  0201WMJ0103TCE+0201WMJ0103TJE~~MCR006YRTJ103~~RC0201JR-0710KL~~WR02X103JAL  [R0201]  145.07 52.18 270 top
RV36  RC0201JR-072K2L~~MCR006YRTJ222~~WR02X222 JAL~~0201WMJ0222TCE+0201WMJ0222TJE  [R0201]  146.35 55.6 90 bottom
RV37  0201WMJ0103TCE+0201WMJ0103TJE~~MCR006YRTJ103~~RC0201JR-0710KL~~WR02X103JAL  [R0201]  144.68 55.6 270 bottom
RV38  0201WMJ0103TCE+0201WMJ0103TJE~~MCR006YRTJ103~~RC0201JR-0710KL~~WR02X103JAL  [R0201]  142.91 54.1 270 bottom
RV40  0201WMJ0000TCE+0201WMJ0000TJE~~MCR006YRTJ000~~RC0201JR-070RL+RC0201JR-130RL~~WR02X000PAL  [R0201]  144.17 52.96 0 top
RV42  0201WMJ0000TCE+0201WMJ0000TJE~~MCR006YRTJ000~~RC0201JR-070RL+RC0201JR-130RL~~WR02X000PAL  [R0201]  143.41 55.6 90 bottom
RV43  0201WMJ0000TCE+0201WMJ0000TJE~~MCR006YRTJ000~~RC0201JR-070RL+RC0201JR-130RL~~WR02X000PAL  [R0201]  140.47 53.97 90 bottom
RV44  0201WMF2003TCE~~RC0201FR-07200KL  [R0201]  139.96 55.7 90 bottom
RV45  0201WMJ0103TCE+0201WMJ0103TJE~~MCR006YRTJ103~~RC0201JR-0710KL~~WR02X103JAL  [R0201]  141.62 53.98 90 bottom
RV46  0201WMJ0103TCE+0201WMJ0103TJE~~MCR006YRTJ103~~RC0201JR-0710KL~~WR02X103JAL  [R0201]  139.95 50.16 180 bottom
RV47  0201WMJ0103TCE+0201WMJ0103TJE~~MCR006YRTJ103~~RC0201JR-0710KL~~WR02X103JAL  [R0201]  141.17 55.6 90 bottom
RV48  0201WMJ0104TCE+0201WMJ0104TEE~~MCR006YRTJ104~~RC0201JR-07100KL~~WR02X104JAL  [R0201]  143.76 61.54 0 top
RV49  RC0201FR-07220KL~~0201WMF0224TCE  [R0201]  135.67 61.82 90 bottom
RV50  0201WMJ0103TCE+0201WMJ0103TJE~~MCR006YRTJ103~~RC0201JR-0710KL~~WR02X103JAL  [R0201]  133.62 57.27 270 bottom
RV51  0402WGJ0000TCE+0402WGJ0000TJE~~RC1005J000CS~~RC0402JR-070RL+RC0402JR-130RL~~RM04JTN0  [R0402_0D65]  144.22 67.52 180 top
RV52  0402WGJ0000TCE+0402WGJ0000TJE~~RC1005J000CS~~RC0402JR-070RL+RC0402JR-130RL~~RM04JTN0  [R0402_0D65]  135.51 57.99 90 top
RV53  0201WMJ0000TCE+0201WMJ0000TJE~~MCR006YRTJ000~~RC0201JR-070RL+RC0201JR-130RL~~WR02X000PAL  [R0201]  144.7 69.23 180 top
RV55  RC0201JR-072K2L~~MCR006YRTJ222~~WR02X222 JAL~~0201WMJ0222TCE+0201WMJ0222TJE  [R0201]  148.35 62.7 270 top
RV56  0201WMJ0103TCE+0201WMJ0103TJE~~MCR006YRTJ103~~RC0201JR-0710KL~~WR02X103JAL  [R0201]  137.74 52.05 0 bottom
RV57  0201WMJ0103TCE+0201WMJ0103TJE~~MCR006YRTJ103~~RC0201JR-0710KL~~WR02X103JAL  [R0201]  148.08 60.53 180 top
RV58  0201WMJ0000TCE+0201WMJ0000TJE~~MCR006YRTJ000~~RC0201JR-070RL+RC0201JR-130RL~~WR02X000PAL  [R0201]  148.92 56.2 90 bottom
RV59  0201WMJ0000TCE+0201WMJ0000TJE~~MCR006YRTJ000~~RC0201JR-070RL+RC0201JR-130RL~~WR02X000PAL  [R0201]  148.34 56.2 270 bottom
RV60  0201WMJ0103TCE+0201WMJ0103TJE~~MCR006YRTJ103~~RC0201JR-0710KL~~WR02X103JAL  [R0201]  149.1 60.91 270 top
RV61  0201WMJ0000TCE+0201WMJ0000TJE~~MCR006YRTJ000~~RC0201JR-070RL+RC0201JR-130RL~~WR02X000PAL  [R0201]  137.74 51.45 0 bottom
RV62  0201WMJ0106TCE//RC0201JR-0710ML~~RC0201JR-0710ML  [R0201]  148.64 55.39 180 bottom
RV63  0201WMJ0103TCE+0201WMJ0103TJE~~MCR006YRTJ103~~RC0201JR-0710KL~~WR02X103JAL  [R0201]  142.44 85.23 90 bottom
RV64  0201WMJ0103TCE+0201WMJ0103TJE~~MCR006YRTJ103~~RC0201JR-0710KL~~WR02X103JAL  [R0201]  149.04 84.91 90 bottom
RV65  0201WMJ0103TCE+0201WMJ0103TJE~~MCR006YRTJ103~~RC0201JR-0710KL~~WR02X103JAL  [R0201]  149.09 62.61 90 top
RV66  40.2R_F  [R0402]  158.08 62.26 90 top
RV67  40.2R_F  [R0402]  156.72 60.91 180 top
RV68  0201WMF604JTCE~~RC0201FR-0760R4L  [R0201]  158.11 60.91 180 top
RV69  0805W8J0240T5E~~RC2012J240CS~~RC0805JR-0724RL~~RM10JTN240  [R0805]  130.3 73.84 270 bottom
RV70  0805W8J0240T5E~~RC2012J240CS~~RC0805JR-0724RL~~RM10JTN240  [R0805]  171.16 53.24 0 bottom
RV71  0805W8J0240T5E~~RC2012J240CS~~RC0805JR-0724RL~~RM10JTN240  [R0805]  129.92 86.05 90 bottom
RV72  0805W8J0240T5E~~RC2012J240CS~~RC0805JR-0724RL~~RM10JTN240  [R0805]  133.7 73.84 270 bottom
RV73  0805W8J0240T5E~~RC2012J240CS~~RC0805JR-0724RL~~RM10JTN240  [R0805]  131.98 73.84 270 bottom
RV74  0805W8J0240T5E~~RC2012J240CS~~RC0805JR-0724RL~~RM10JTN240  [R0805]  171.16 56.59 0 bottom
RV75  0805W8J0240T5E~~RC2012J240CS~~RC0805JR-0724RL~~RM10JTN240  [R0805]  171.16 54.89 0 bottom
RV76  0201WMJ0103TCE+0201WMJ0103TJE~~MCR006YRTJ103~~RC0201JR-0710KL~~WR02X103JAL  [R0201]  131.95 77.16 180 bottom
RV77  0201WMJ0103TCE+0201WMJ0103TJE~~MCR006YRTJ103~~RC0201JR-0710KL~~WR02X103JAL  [R0201]  171.2 52.03 0 bottom
RV78  0201WMJ0103TCE+0201WMJ0103TJE~~MCR006YRTJ103~~RC0201JR-0710KL~~WR02X103JAL  [R0201]  133.78 87.08 180 bottom
RV82  0805W8J0240T5E~~RC2012J240CS~~RC0805JR-0724RL~~RM10JTN240  [R0805]  134.8 81.99 270 bottom
RV83  0805W8J0240T5E~~RC2012J240CS~~RC0805JR-0724RL~~RM10JTN240  [R0805]  167.99 85.86 270 bottom
RV84  0805W8J0240T5E~~RC2012J240CS~~RC0805JR-0724RL~~RM10JTN240  [R0805]  166.38 85.86 270 bottom
RV85  0201WMJ0103TCE+0201WMJ0103TJE~~MCR006YRTJ103~~RC0201JR-0710KL~~WR02X103JAL  [R0201]  165.88 89.62 90 bottom
RV86  0805W8J0240T5E~~RC2012J240CS~~RC0805JR-0724RL~~RM10JTN240  [R0805]  164.78 85.86 270 bottom
RV87  0201WMJ0103TCE+0201WMJ0103TJE~~MCR006YRTJ103~~RC0201JR-0710KL~~WR02X103JAL  [R0201]  128.57 80.26 180 bottom
RV88  0402WGJ0000TCE+0402WGJ0000TJE~~RC1005J000CS~~RC0402JR-070RL+RC0402JR-130RL~~RM04JTN0  [R0402_0D65]  144.24 64.43 180 top
RV89  0201WMJ0000TCE+0201WMJ0000TJE~~MCR006YRTJ000~~RC0201JR-070RL+RC0201JR-130RL~~WR02X000PAL  [R0201]  145.41 73.99 270 top
RV90  0201WMJ0103TCE+0201WMJ0103TJE~~MCR006YRTJ103~~RC0201JR-0710KL~~WR02X103JAL  [R0201]  182.41 68.5 0 top
RV91  0201WMJ0103TCE+0201WMJ0103TJE~~MCR006YRTJ103~~RC0201JR-0710KL~~WR02X103JAL  [R0201]  181.22 79.58 270 top
RV92  0201WMJ0103TCE+0201WMJ0103TJE~~MCR006YRTJ103~~RC0201JR-0710KL~~WR02X103JAL  [R0201]  180.1 79.43 90 top
RV93  0201WMJ0103TCE+0201WMJ0103TJE~~MCR006YRTJ103~~RC0201JR-0710KL~~WR02X103JAL  [R0201]  179.91 70.2 0 top
RV94  0201WMF604JTCE~~RC0201FR-0760R4L  [R0201]  158.01 63.48 180 top
RV95  0201WMF604JTCE~~RC0201FR-0760R4L  [R0201]  158.04 66.17 180 top
RV96  WR02X102JAL~~RC0201JR-071KL~~0201WMJ0102TCE+0201WMJ0102TJE~~MCR006YRTJ102  [R0201]  180.72 71.41 0 top
RV97  WR02X102JAL~~RC0201JR-071KL~~0201WMJ0102TCE+0201WMJ0102TJE~~MCR006YRTJ102  [R0201]  182.29 63.42 180 top
RV98  WR02X102JAL~~RC0201JR-071KL~~0201WMJ0102TCE+0201WMJ0102TJE~~MCR006YRTJ102  [R0201]  182.5 84.88 180 top
RV99  121_0201_1%  [R0201]  182.04 61.96 90 top
RV100  121_0201_1%  [R0201]  181.56 91.73 90 bottom
RV101  0201WMF5490TCE~~RC0201FR-07549RL  [R0201]  181.92 57.7 270 top
RV102  931_0201_1%  [R0201]  182.19 58.51 180 top
RV103  1.33K_0201_1%  [R0201]  182.19 59.1 0 top
RV104  RC0201FR-0740R2L~~0201WMF402JTCE+0201WMF402JTEE  [R0201]  180.35 59 270 top
RV105  0201WMF806JTCE+0201WMF806JTEE~~RC0201FR-0780R6L  [R0201]  180.63 59.81 0 top
RV106  RC0201FR-0740R2L~~0201WMF402JTCE+0201WMF402JTEE  [R0201]  181.12 89.6 90 top
RV107  RC0201FR-0740R2L~~0201WMF402JTCE+0201WMF402JTEE  [R0201]  180.91 59 270 top
RV108  0201WMF806JTCE+0201WMF806JTEE~~RC0201FR-0780R6L  [R0201]  181.4 88.74 0 top
RV109  RC0201FR-0740R2L~~0201WMF402JTCE+0201WMF402JTEE  [R0201]  181.68 89.6 90 top
RV110  0201WMJ0104TCE~~MCR006YRTJ104~~RC0201JR-07100KL~~WR02X104JAL  [R0201]  137.28 61.24 0 bottom
RV111  0201WMJ0104TCE~~MCR006YRTJ104~~RC0201JR-07100KL~~WR02X104JAL  [R0201]  137.28 59.46 0 bottom
RV112  0201WMJ0104TCE~~MCR006YRTJ104~~RC0201JR-07100KL~~WR02X104JAL  [R0201]  140.37 52.54 90 top
RV113  0201WMJ0104TCE~~MCR006YRTJ104~~RC0201JR-07100KL~~WR02X104JAL  [R0201]  137.28 60.68 180 bottom
RV114  0201WMJ0104TCE~~MCR006YRTJ104~~RC0201JR-07100KL~~WR02X104JAL  [R0201]  137.28 60.07 180 bottom
RV115  0201WMJ0104TCE~~MCR006YRTJ104~~RC0201JR-07100KL~~WR02X104JAL  [R0201]  140.92 52.54 270 top
RV116  0201WMJ0104TCE~~MCR006YRTJ104~~RC0201JR-07100KL~~WR02X104JAL  [R0201]  139.82 52.54 90 top
RV117  0201WMJ0104TCE~~MCR006YRTJ104~~RC0201JR-07100KL~~WR02X104JAL  [R0201]  142.29 55.6 90 bottom
RV118  0201WMJ0104TCE~~MCR006YRTJ104~~RC0201JR-07100KL~~WR02X104JAL  [R0201]  137.28 58.24 0 bottom
RV119  0201WMJ0104TCE~~MCR006YRTJ104~~RC0201JR-07100KL~~WR02X104JAL  [R0201]  139.28 52.54 270 top
RV120  0201WMJ0104TCE~~MCR006YRTJ104~~RC0201JR-07100KL~~WR02X104JAL  [R0201]  141.73 55.6 270 bottom
RV121  0201WMJ0104TCE~~MCR006YRTJ104~~RC0201JR-07100KL~~WR02X104JAL  [R0201]  137.28 58.85 180 bottom
RV122  0201WMJ0104TCE~~MCR006YRTJ104~~RC0201JR-07100KL~~WR02X104JAL  [R0201]  152.04 55.6 90 bottom
RV123  0201WMJ0104TCE~~MCR006YRTJ104~~RC0201JR-07100KL~~WR02X104JAL  [R0201]  151.48 55.6 90 bottom
RV124  0201WMJ0104TCE~~MCR006YRTJ104~~RC0201JR-07100KL~~WR02X104JAL  [R0201]  149.76 55.6 90 bottom
RV125  0201WMJ0104TCE~~MCR006YRTJ104~~RC0201JR-07100KL~~WR02X104JAL  [R0201]  152.6 55.6 270 bottom
RV126  0201WMJ0104TCE~~MCR006YRTJ104~~RC0201JR-07100KL~~WR02X104JAL  [R0201]  150.92 55.6 270 bottom
RV127  0201WMJ0104TCE~~MCR006YRTJ104~~RC0201JR-07100KL~~WR02X104JAL  [R0201]  150.32 55.6 270 bottom
RV138  0201WMJ0103TCE+0201WMJ0103TJE~~MCR006YRTJ103~~RC0201JR-0710KL~~WR02X103JAL  [R0201]  142.7 50.2 0 top
RV141  WR02X102JAL~~RC0201JR-071KL~~0201WMJ0102TCE+0201WMJ0102TJE~~MCR006YRTJ102  [R0201]  180.66 78.03 0 top
RV142  0201WMJ0103TCE+0201WMJ0103TJE~~MCR006YRTJ103~~RC0201JR-0710KL~~WR02X103JAL  [R0201]  129.38 87.09 90 top
RV143  0201WMJ0104TCE~~MCR006YRTJ104~~RC0201JR-07100KL~~WR02X104JAL  [R0201]  132.55 56.94 270 bottom
RV147  WR02X103JAL~#~0201WMJ0103TJE~#~MCR006YRTJ103~#~RC0201JR-0710KL  [R0201]  145.59 52.18 270 top
RV244  0201WMJ0000TCE+0201WMJ0000TJE~~MCR006YRTJ000~~RC0201JR-070RL+RC0201JR-130RL~~WR02X000PAL  [R0201]  133.16 63.36 270 bottom
RV245  0201WMJ0000TCE+0201WMJ0000TJE~~MCR006YRTJ000~~RC0201JR-070RL+RC0201JR-130RL~~WR02X000PAL  [R0201]  132.62 63.36 270 bottom
RV248  WR02X103JAL~#~0201WMJ0103TJE~#~MCR006YRTJ103~#~RC0201JR-0710KL  [R0201]  135.13 61.82 90 bottom
RV250  0201WMJ0000TJE~#~RC0201JR-130RL~#~MCR006YRTJ000~#~RC0201JR-070RL~#~RC0201JR-070RL/RC0201JR-130RL~#~RC0201JR-130RL/RC0201JR-070RL~#~WR02X000PAL  [R0201]  134.59 61.82 90 bottom
RV251  0201WMJ0000TCE+0201WMJ0000TJE~~MCR006YRTJ000~~RC0201JR-070RL+RC0201JR-130RL~~WR02X000PAL  [R0201]  142.85 55.6 90 bottom
RW6  0201WMJ0000TCE+0201WMJ0000TJE~~MCR006YRTJ000~~RC0201JR-070RL+RC0201JR-130RL~~WR02X000PAL  [R0201]  151.08 14.55 0 top
RW7  0201WMJ0000TCE+0201WMJ0000TJE~~MCR006YRTJ000~~RC0201JR-070RL+RC0201JR-130RL~~WR02X000PAL  [R0201]  151.08 16.23 0 top
RW8  0201WMJ0000TCE+0201WMJ0000TJE~~MCR006YRTJ000~~RC0201JR-070RL+RC0201JR-130RL~~WR02X000PAL  [R0201]  151.08 19.12 0 top
RW9  0201WMJ0104TCE~~MCR006YRTJ104~~RC0201JR-07100KL~~WR02X104JAL  [R0201]  143.18 17.2 180 bottom
RW10  0201WMF330JTCE+0201WMF330JTEE~~MCR006YRTF33R0~~RC0201FR-0733RL~~WR02X33R0FAL  [R0201]  148.69 22.73 0 top
RW11  0201WMF330JTCE+0201WMF330JTEE~~MCR006YRTF33R0~~RC0201FR-0733RL~~WR02X33R0FAL  [R0201]  151.18 24 0 top
RW12  0201WMJ0000TCE+0201WMJ0000TJE~~MCR006YRTJ000~~RC0201JR-070RL+RC0201JR-130RL~~WR02X000PAL  [R0201]  143.18 17.8 0 bottom
RW13  0201WMF330JTCE+0201WMF330JTEE~~MCR006YRTF33R0~~RC0201FR-0733RL~~WR02X33R0FAL  [R0201]  151.33 27.05 0 top
RW14  0201WMJ0000TCE+0201WMJ0000TJE~~MCR006YRTJ000~~RC0201JR-070RL+RC0201JR-130RL~~WR02X000PAL  [R0201]  151.33 27.61 180 top
RW15  0201WMJ0000TCE+0201WMJ0000TJE~~MCR006YRTJ000~~RC0201JR-070RL+RC0201JR-130RL~~WR02X000PAL  [R0201]  143.66 29.15 180 bottom
RW16  0201WMJ0000TCE+0201WMJ0000TJE~~MCR006YRTJ000~~RC0201JR-070RL+RC0201JR-130RL~~WR02X000PAL  [R0201]  151.33 28.17 180 top
RW18  0201WMJ0000TCE+0201WMJ0000TJE~~MCR006YRTJ000~~RC0201JR-070RL+RC0201JR-130RL~~WR02X000PAL  [R0201]  143.66 29.76 180 bottom
RW21  0201WMJ0000TCE+0201WMJ0000TJE~~MCR006YRTJ000~~RC0201JR-070RL+RC0201JR-130RL~~WR02X000PAL  [R0201]  151.08 16.89 0 top
RW22  0201WMJ0000TCE+0201WMJ0000TJE~~MCR006YRTJ000~~RC0201JR-070RL+RC0201JR-130RL~~WR02X000PAL  [R0201]  151.08 17.45 0 top
RW23  RC0201FR-0775KL~~MCR006YRTF7502~~WR02X7502FAL~~0201WMF7502TCE  [R0201]  141.48 14.45 90 top
RW24  RC1608J000CS~~RC0603JR-070RL~~RM06JTN0~~0603WAJ0000T5E  [R0603]  141.91 12.88 270 bottom
RW25  RC0201FR-0775KL~~MCR006YRTF7502~~WR02X7502FAL~~0201WMF7502TCE  [R0201]  146.35 18.11 270 top
RW26  0201WMJ0000TCE+0201WMJ0000TJE~~MCR006YRTJ000~~RC0201JR-070RL+RC0201JR-130RL~~WR02X000PAL  [R0201]  145.24 18.11 270 top
RW27  0201WMJ0000TCE+0201WMJ0000TJE~~MCR006YRTJ000~~RC0201JR-070RL+RC0201JR-130RL~~WR02X000PAL  [R0201]  145.79 18.11 270 top
RW28  0201WMJ0000TCE+0201WMJ0000TJE~~MCR006YRTJ000~~RC0201JR-070RL+RC0201JR-130RL~~WR02X000PAL  [R0201]  143.64 23.9 270 bottom
RW29  0201WMJ0000TCE+0201WMJ0000TJE~~MCR006YRTJ000~~RC0201JR-070RL+RC0201JR-130RL~~WR02X000PAL  [R0201]  144.14 23.9 270 bottom
RW30  0201WMJ0000TCE+0201WMJ0000TJE~~MCR006YRTJ000~~RC0201JR-070RL+RC0201JR-130RL~~WR02X000PAL  [R0201]  143.66 26.15 180 bottom
RW31  0201WMJ0000TCE+0201WMJ0000TJE~~MCR006YRTJ000~~RC0201JR-070RL+RC0201JR-130RL~~WR02X000PAL  [R0201]  143.66 26.76 180 bottom
RW32  0201WMJ0000TCE+0201WMJ0000TJE~~MCR006YRTJ000~~RC0201JR-070RL+RC0201JR-130RL~~WR02X000PAL  [R0201]  143.66 27.62 180 bottom
RW33  0201WMJ0000TCE+0201WMJ0000TJE~~MCR006YRTJ000~~RC0201JR-070RL+RC0201JR-130RL~~WR02X000PAL  [R0201]  143.66 28.23 180 bottom
RW55  0201WMJ0203TCE~~MCR006YRTJ203~~RC0201JR-0720KL~~WR02X203JAL  [R0201]  151.38 22.68 0 top
RW56  0201WMJ0203TCE~~MCR006YRTJ203~~RC0201JR-0720KL~~WR02X203JAL  [R0201]  151.38 22.15 0 top
RW57  0201WMJ0000TCE+0201WMJ0000TJE~~MCR006YRTJ000~~RC0201JR-070RL+RC0201JR-130RL~~WR02X000PAL  [R0201]  143.18 16.53 0 bottom
RW58  0201WMJ0103TCE+0201WMJ0103TJE~~MCR006YRTJ103~~RC0201JR-0710KL~~WR02X103JAL  [R0201]  151.08 15.67 180 top
RW59  0201WMJ0103TCE+0201WMJ0103TJE~~MCR006YRTJ103~~RC0201JR-0710KL~~WR02X103JAL  [R0201]  151.08 15.11 180 top
RW60  0201WMJ0000TCE+0201WMJ0000TJE~~MCR006YRTJ000~~RC0201JR-070RL+RC0201JR-130RL~~WR02X000PAL  [R0201]  148.69 22.07 0 top
RW61  0201WMJ0000TCE+0201WMJ0000TJE~~MCR006YRTJ000~~RC0201JR-070RL+RC0201JR-130RL~~WR02X000PAL  [R0201]  151.38 20.5 0 top
RW62  0201WMJ0000TCE+0201WMJ0000TJE~~MCR006YRTJ000~~RC0201JR-070RL+RC0201JR-130RL~~WR02X000PAL  [R0201]  148.69 21.46 0 top
RW63  0201WMJ0000TCE+0201WMJ0000TJE~~MCR006YRTJ000~~RC0201JR-070RL+RC0201JR-130RL~~WR02X000PAL  [R0201]  151.33 26.49 0 top
RW64  0201WMJ0000TCE+0201WMJ0000TJE~~MCR006YRTJ000~~RC0201JR-070RL+RC0201JR-130RL~~WR02X000PAL  [R0201]  150.32 20.5 0 top
RW66  0201WMJ0000TCE+0201WMJ0000TJE~~MCR006YRTJ000~~RC0201JR-070RL+RC0201JR-130RL~~WR02X000PAL  [R0201]  149.71 25.93 0 top
RW67  0201WMJ0103TCE+0201WMJ0103TJE~~MCR006YRTJ103~~RC0201JR-0710KL~~WR02X103JAL  [R0201]  150.32 21.05 0 top
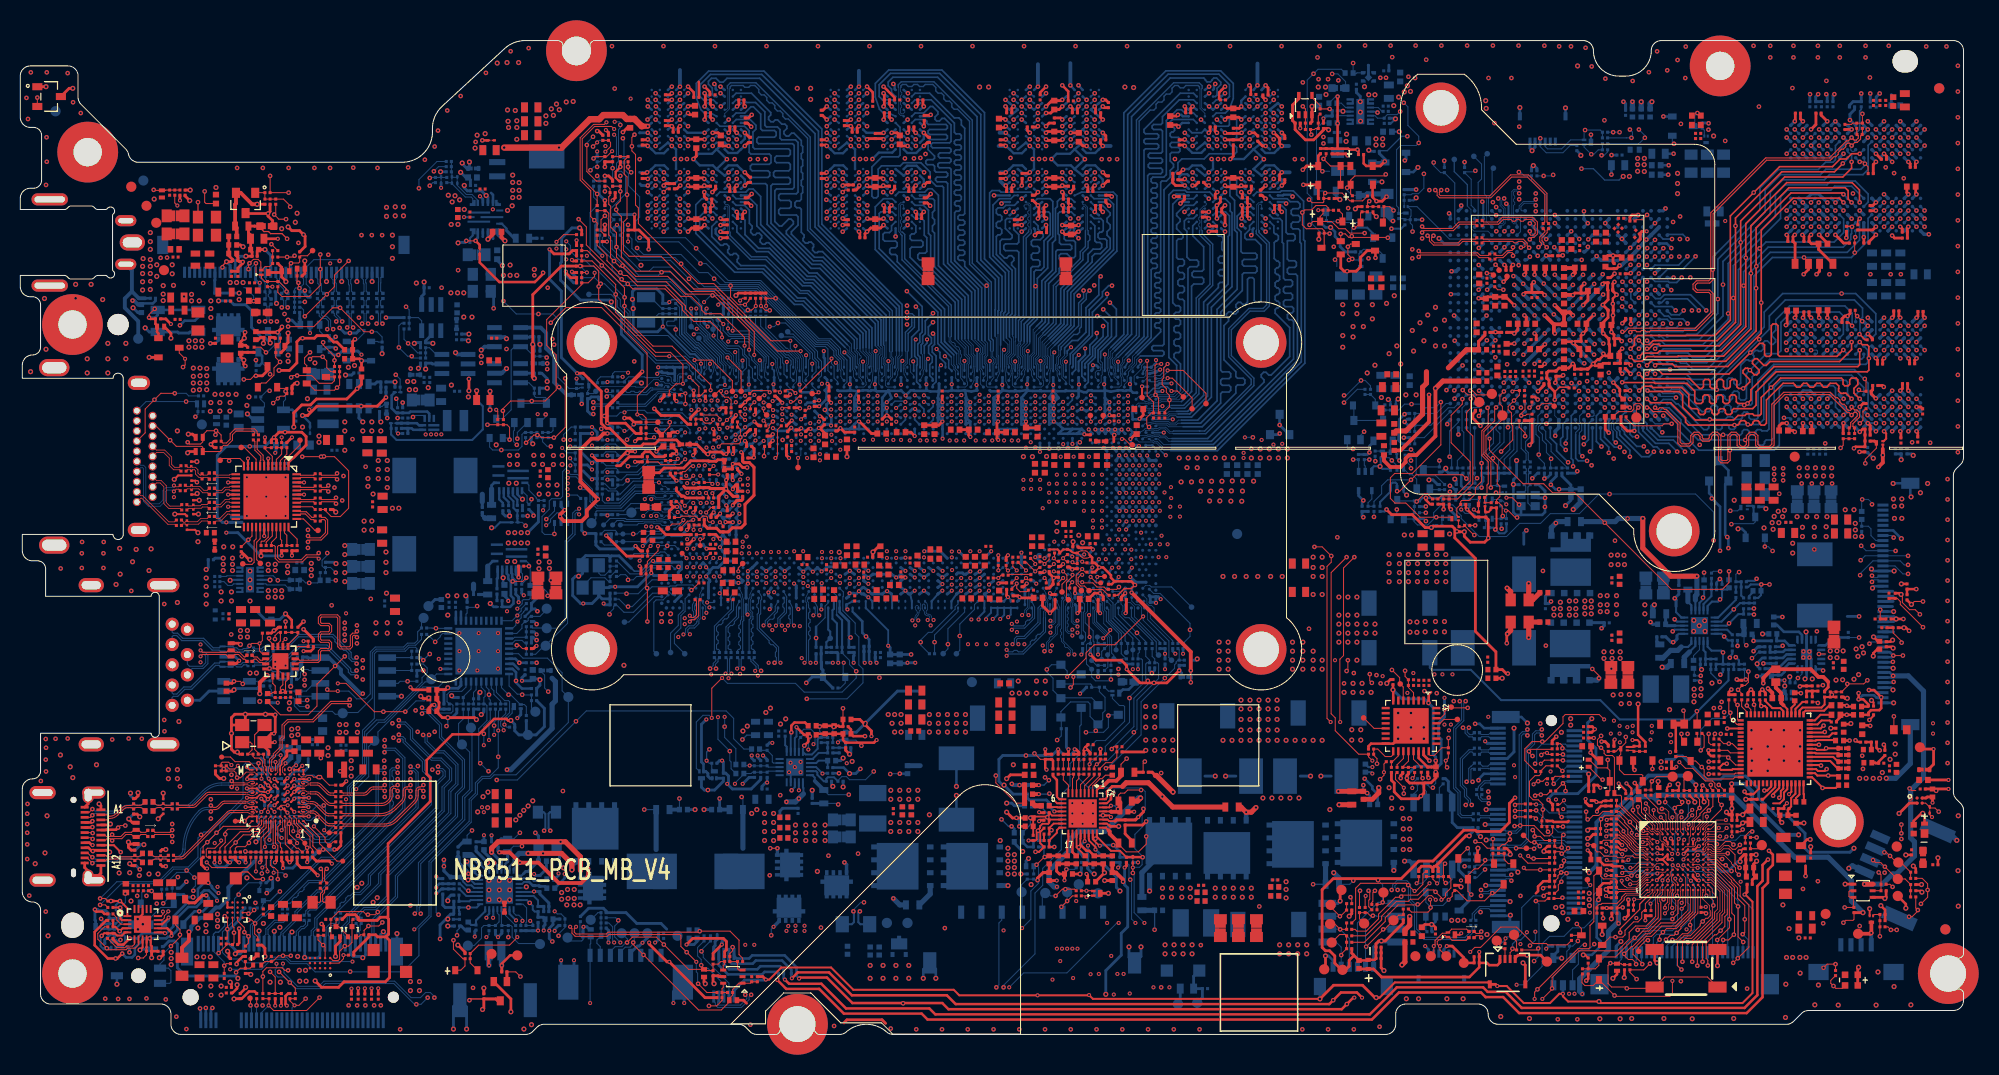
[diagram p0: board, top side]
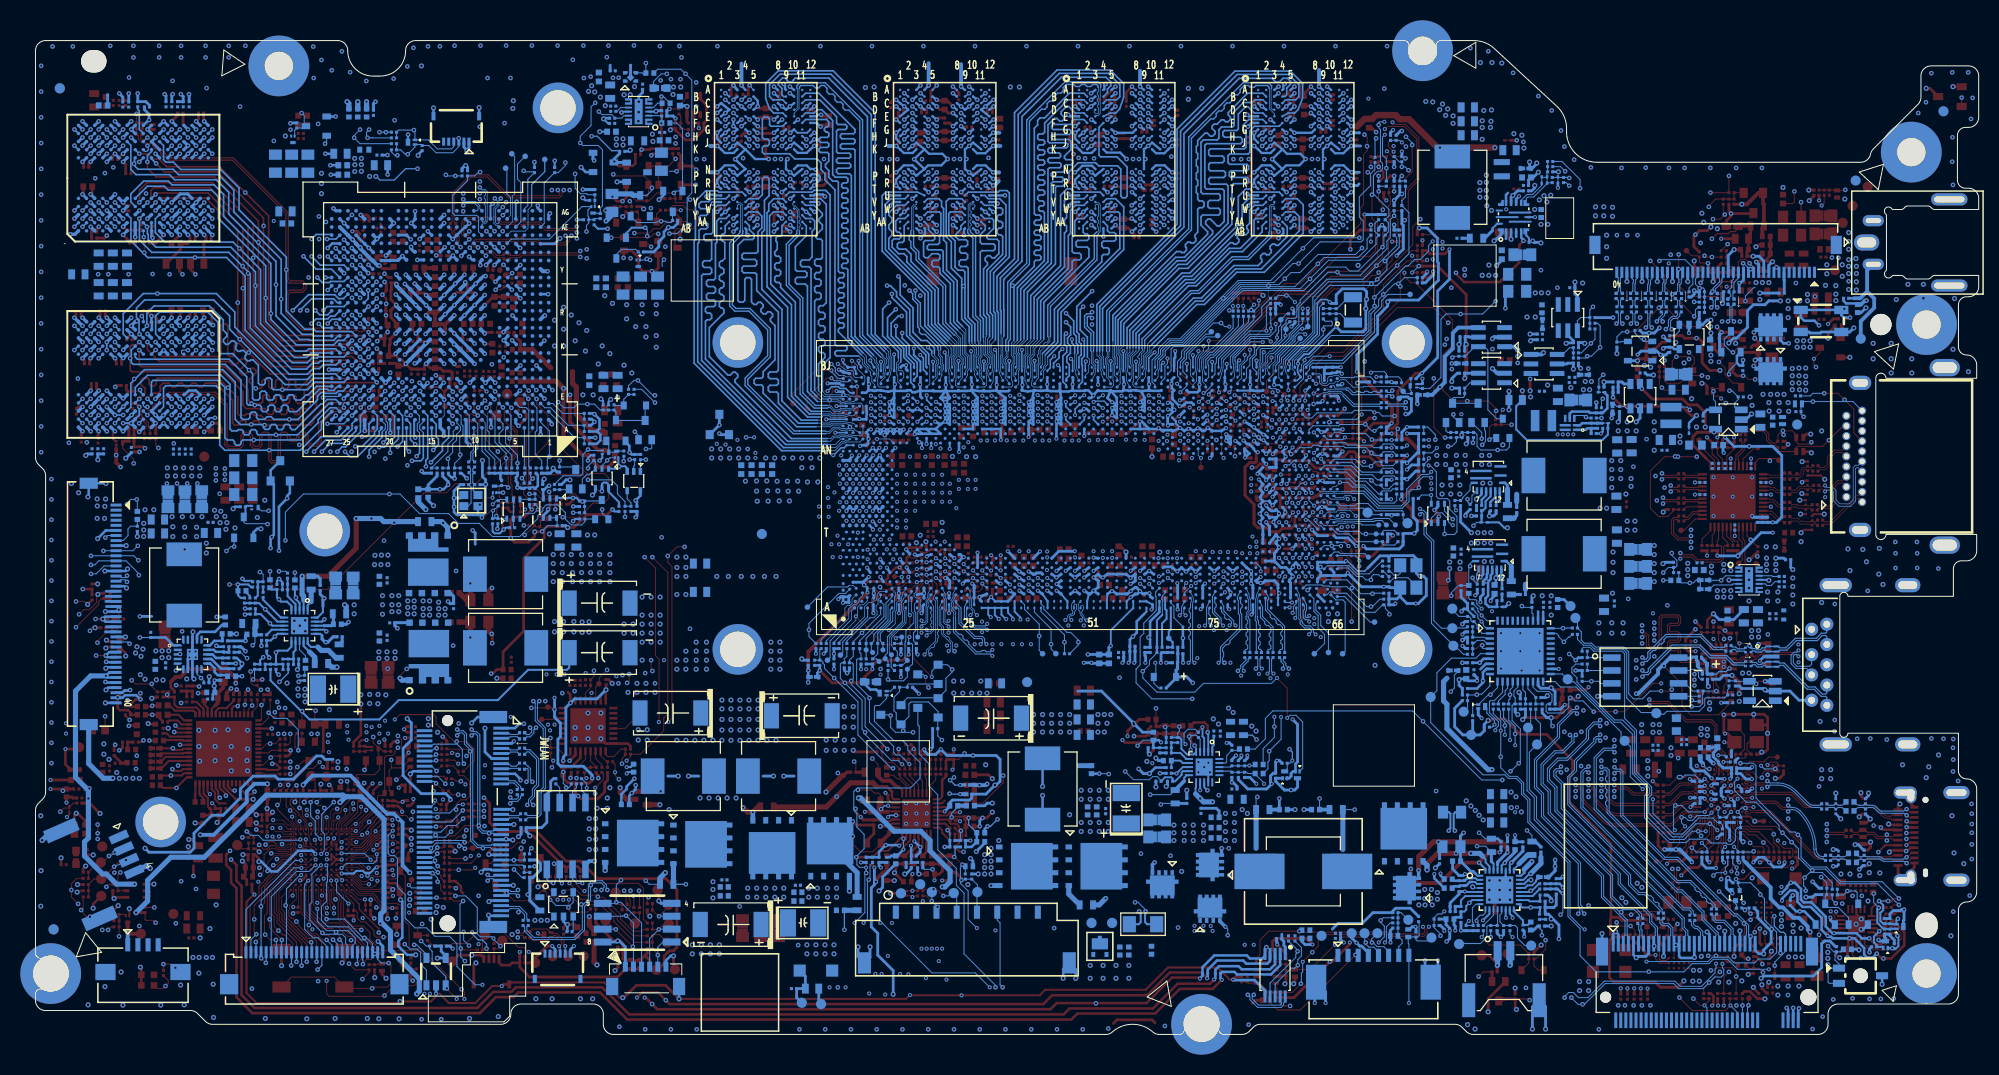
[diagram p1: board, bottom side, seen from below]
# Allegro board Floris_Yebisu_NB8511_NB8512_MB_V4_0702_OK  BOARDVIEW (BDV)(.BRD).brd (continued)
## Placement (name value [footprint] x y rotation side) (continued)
RW68  0201WMJ0000TCE+0201WMJ0000TJE~~MCR006YRTJ000~~RC0201JR-070RL+RC0201JR-130RL~~WR02X000PAL  [R0201]  143.46 15.72 90 bottom
RW69  0201WMJ0104TCE~~MCR006YRTJ104~~RC0201JR-07100KL~~WR02X104JAL  [R0201]  142.9 15.72 270 bottom
RW70  0201WMJ0103TCE+0201WMJ0103TJE~~MCR006YRTJ103~~RC0201JR-0710KL~~WR02X103JAL  [R0201]  138.99 10.13 180 bottom
RW71  0201WMF220JTCE~~RC0201FR-0722RL~~RM02FTN220  [R0201]  150.87 25.22 0 top
RW72  0201WMJ0103TCE+0201WMJ0103TJE~~MCR006YRTJ103~~RC0201JR-0710KL~~WR02X103JAL  [R0201]  152.42 25.45 0 top
RW73  0201WMJ0000TCE+0201WMJ0000TJE~~MCR006YRTJ000~~RC0201JR-070RL+RC0201JR-130RL~~WR02X000PAL  [R0201]  151.05 13.92 0 top
RW74  0201WMJ0000TCE+0201WMJ0000TJE~~MCR006YRTJ000~~RC0201JR-070RL+RC0201JR-130RL~~WR02X000PAL  [R0201]  151 13.41 0 top
RX4  0201WMJ0000TCE+0201WMJ0000TJE~~MCR006YRTJ000~~RC0201JR-070RL+RC0201JR-130RL~~WR02X000PAL  [R0201]  26.39 72.82 90 bottom
RX5  0201WMJ0000TCE+0201WMJ0000TJE~~MCR006YRTJ000~~RC0201JR-070RL+RC0201JR-130RL~~WR02X000PAL  [R0201]  25.78 72.82 90 bottom
RX11  0805W8J0000T5E~~RC0805JR-070RL~~RM10JTN0  [R0805]  17.52 70.3 90 top
RX12  0201WMJ0104TCE~~MCR006YRTJ104~~RC0201JR-07100KL~~WR02X104JAL  [R0201]  30.48 67.51 90 bottom
RX16  0201WMJ0104TCE~~MCR006YRTJ104~~RC0201JR-07100KL~~WR02X104JAL  [R0201]  28.57 72.97 90 bottom
RX17  0201WMJ0103TCE+0201WMJ0103TJE~~MCR006YRTJ103~~RC0201JR-0710KL~~WR02X103JAL  [R0201]  27.3 71.19 0 bottom
RX18  0201WMJ0104TCE~~MCR006YRTJ104~~RC0201JR-07100KL~~WR02X104JAL  [R0201]  27.56 74.8 180 top
RX19  0201WMJ0000TCE+0201WMJ0000TJE~~MCR006YRTJ000~~RC0201JR-070RL+RC0201JR-130RL~~WR02X000PAL  [R0201]  24.74 72.26 90 bottom
RX20  0201WMJ0000TCE+0201WMJ0000TJE~~MCR006YRTJ000~~RC0201JR-070RL+RC0201JR-130RL~~WR02X000PAL  [R0201]  24.13 72.26 90 bottom
RX21  0201WMJ0000TCE+0201WMJ0000TJE~~MCR006YRTJ000~~RC0201JR-070RL+RC0201JR-130RL~~WR02X000PAL  [R0201]  27.3 72.21 180 bottom
RX22  0201WMJ0104TCE~~MCR006YRTJ104~~RC0201JR-07100KL~~WR02X104JAL  [R0201]  27.3 73.23 180 bottom
RX23  0201WMJ0000TCE+0201WMJ0000TJE~~MCR006YRTJ000~~RC0201JR-070RL+RC0201JR-130RL~~WR02X000PAL  [R0201]  24.38 73.99 90 top
RX24  0201WMJ0000TCE+0201WMJ0000TJE~~MCR006YRTJ000~~RC0201JR-070RL+RC0201JR-130RL~~WR02X000PAL  [R0201]  25.14 77.29 180 top
RX25  0201WMJ0000TCE+0201WMJ0000TJE~~MCR006YRTJ000~~RC0201JR-070RL+RC0201JR-130RL~~WR02X000PAL  [R0201]  27.3 71.7 180 bottom
RX105  0201WMJ0000TCE+0201WMJ0000TJE~~MCR006YRTJ000~~RC0201JR-070RL+RC0201JR-130RL~~WR02X000PAL  [R0201]  31.24 64.84 180 top
RX242  0201WMJ0000TCE+0201WMJ0000TJE~~MCR006YRTJ000~~RC0201JR-070RL+RC0201JR-130RL~~WR02X000PAL  [R0201]  32.88 72.82 90 bottom
RX243  0201WMJ0000TCE+0201WMJ0000TJE~~MCR006YRTJ000~~RC0201JR-070RL+RC0201JR-130RL~~WR02X000PAL  [R0201]  32.27 72.82 90 bottom
RX244  0201WMJ0000TCE+0201WMJ0000TJE~~MCR006YRTJ000~~RC0201JR-070RL+RC0201JR-130RL~~WR02X000PAL  [R0201]  31.39 72.82 90 bottom
RX245  0201WMJ0000TCE+0201WMJ0000TJE~~MCR006YRTJ000~~RC0201JR-070RL+RC0201JR-130RL~~WR02X000PAL  [R0201]  30.78 72.82 90 bottom
RX897  0402WGJ0000TCE+0402WGJ0000TJE~~RC1005J000CS~~RC0402JR-070RL+RC0402JR-130RL~~RM04JTN0  [R0402_0D65]  32.38 66.62 0 top
RX898  0201WMJ0000TCE+0201WMJ0000TJE~~MCR006YRTJ000~~RC0201JR-070RL+RC0201JR-130RL~~WR02X000PAL  [R0201]  25.14 76.65 180 top
RX899  0201WMF330JTCE+0201WMF330JTEE~~MCR006YRTF33R0~~RC0201FR-0733RL~~WR02X33R0FAL  [R0201]  25.4 73.99 90 top
RX900  RC1608J000CS~~RC0603JR-070RL~~RM06JTN0~~0603WAJ0000T5E  [R0603]  21.84 79.71 0 top
RX901  RM04JTN471~~0402WGJ0471TCE~~RC1005J471CS~~RC0402JR-07470RL  [R0402]  23.11 77.39 180 top
RX902  0201WMJ0104TCE~~MCR006YRTJ104~~RC0201JR-07100KL~~WR02X104JAL  [R0201]  24.38 83 0 top
RX904  0201WMJ0000TCE+0201WMJ0000TJE~~MCR006YRTJ000~~RC0201JR-070RL+RC0201JR-130RL~~WR02X000PAL  [R0201]  29.31 72.82 90 bottom
RX905  0201WMJ0000TCE+0201WMJ0000TJE~~MCR006YRTJ000~~RC0201JR-070RL+RC0201JR-130RL~~WR02X000PAL  [R0201]  29.92 72.82 90 bottom
RX906  0402WGJ0000TCE+0402WGJ0000TJE~~RC1005J000CS~~RC0402JR-070RL+RC0402JR-130RL~~RM04JTN0  [R0402_0D65]  20.95 77.85 0 top
RX907  0402WGJ0000TCE+0402WGJ0000TJE~~RC1005J000CS~~RC0402JR-070RL+RC0402JR-130RL~~RM04JTN0  [R0402_0D65]  20.95 78.69 0 top
RX908  0201WMJ0103TCE+0201WMJ0103TJE~~MCR006YRTJ103~~RC0201JR-0710KL~~WR02X103JAL  [R0201]  30.48 68.65 270 bottom
RX909  0201WMJ0000TCE+0201WMJ0000TJE~~MCR006YRTJ000~~RC0201JR-070RL+RC0201JR-130RL~~WR02X000PAL  [R0201]  33.73 72.82 90 bottom
RX910  0201WMJ0000TCE+0201WMJ0000TJE~~MCR006YRTJ000~~RC0201JR-070RL+RC0201JR-130RL~~WR02X000PAL  [R0201]  34.34 72.82 90 bottom
RX911  0201WMJ0000TCE+0201WMJ0000TJE~~MCR006YRTJ000~~RC0201JR-070RL+RC0201JR-130RL~~WR02X000PAL  [R0201]  35.76 72.82 90 bottom
RX912  0201WMJ0000TCE+0201WMJ0000TJE~~MCR006YRTJ000~~RC0201JR-070RL+RC0201JR-130RL~~WR02X000PAL  [R0201]  35.15 72.82 90 bottom
RX913  0201WMJ0000TCE+0201WMJ0000TJE~~MCR006YRTJ000~~RC0201JR-070RL+RC0201JR-130RL~~WR02X000PAL  [R0201]  156.29 87.83 180 bottom
RX914  0201WMJ0000TCE+0201WMJ0000TJE~~MCR006YRTJ000~~RC0201JR-070RL+RC0201JR-130RL~~WR02X000PAL  [R0201]  156.29 88.41 180 bottom
RX915  0201WMJ0000TCE+0201WMJ0000TJE~~MCR006YRTJ000~~RC0201JR-070RL+RC0201JR-130RL~~WR02X000PAL  [R0201]  156.29 87.22 180 bottom
RX916  0201WMF330JTCE+0201WMF330JTEE~~MCR006YRTF33R0~~RC0201FR-0733RL~~WR02X33R0FAL  [R0201]  156.29 88.96 180 bottom
RX917  0402WGJ0000TCE+0402WGJ0000TJE~~RC1005J000CS~~RC0402JR-070RL+RC0402JR-130RL~~RM04JTN0  [R0402_0D65]  160.74 90.86 90 bottom
RX918  0402WGJ0000TCE+0402WGJ0000TJE~~RC1005J000CS~~RC0402JR-070RL+RC0402JR-130RL~~RM04JTN0  [R0402_0D65]  159.86 90.86 90 bottom
RX919  0201WMJ0104TCE~~MCR006YRTJ104~~RC0201JR-07100KL~~WR02X104JAL  [R0201]  35.69 68.02 90 bottom
RX920  0201WMJ0103TCE+0201WMJ0103TJE~~MCR006YRTJ103~~RC0201JR-0710KL~~WR02X103JAL  [R0201]  33.65 69.42 180 bottom
RX921  0201WMJ0103TCE+0201WMJ0103TJE~~MCR006YRTJ103~~RC0201JR-0710KL~~WR02X103JAL  [R0201]  27.56 76.91 270 top
RX922  0201WMJ0000TCE+0201WMJ0000TJE~~MCR006YRTJ000~~RC0201JR-070RL+RC0201JR-130RL~~WR02X000PAL  [R0201]  31.24 65.35 0 top
RX923  0201WMJ0000TCE+0201WMJ0000TJE~~MCR006YRTJ000~~RC0201JR-070RL+RC0201JR-130RL~~WR02X000PAL  [R0201]  31.24 65.86 0 top
RX924  0402WGJ0000TCE+0402WGJ0000TJE~~RC1005J000CS~~RC0402JR-070RL+RC0402JR-130RL~~RM04JTN0  [R0402_0D65]  32.38 67.51 180 top
RX925  0402WGJ0000TCE+0402WGJ0000TJE~~RC1005J000CS~~RC0402JR-070RL+RC0402JR-130RL~~RM04JTN0  [R0402_0D65]  33.65 65.22 270 top
RX926  0201WMJ0104TCE~~MCR006YRTJ104~~RC0201JR-07100KL~~WR02X104JAL  [R0201]  25.19 82.12 270 top
SHE1  SHUNT_LOCAL  [SHUNT_0603]  187.65 16.89 180 top
SHE2  SHUNT_LOCAL  [SHUNT_0402]  179.42 26.24 90 top
SHE3  SHUNT_LOCAL  [SHUNT_0402]  179.42 26.9 90 top
SHE4  SHUNT_LOCAL  [SHUNT_0402]  179.42 27.56 90 top
SHE5  SHUNT_LOCAL  [SHUNT_0402]  179.42 28.22 90 top
SHI01  SHUNT_LOCAL  [SHUNT_0402]  19.18 47.83 180 top
SHT1  SHUNT_LOCAL  [SHUNT_0402]  52.2 35.89 90 bottom
SHU1  SHUNT_LOCAL  [SHUNT_0603]  108.71 34.77 270 bottom
SHU2  SHUNT_LOCAL  [SHUNT_0402]  65.15 58.19 90 top
SHU3  SHUNT_LOCAL  [SHUNT_0603]  61.59 52.02 90 top
SHU4  SHUNT_LOCAL  [SHUNT_0805]  61.97 54.68 270 top
SHU5  SHUNT_LOCAL  [SHUNT_0402]  69.44 55.75 180 top
SHU6  SHUNT_LOCAL  [SHUNT_0805]  89.53 75.26 270 top
SHU7  SHUNT_LOCAL  [SHUNT_0805]  103.12 75.26 270 top
SHU8  SHUNT_LOCAL  [SHUNT_0402]  106.98 58.49 270 top
SHU9  SHUNT_LOCAL  [SHUNT_0402]  115.31 35.25 90 bottom
SHX1  SHUNT_LOCAL  [SHUNT_0603]  24.38 71.19 270 top
SHX9  SHUNT_LOCAL  [SHUNT_0603]  24.89 79.7 270 top
SW3  TS43-2JL  [NB_SW4_4D5X3D2X2D6]  15.55 70.35 180 bottom
SW4  DT-1106  [NB_SW3_3D4X3X4]  11.66 5.79 90 bottom
SW5  TSKB-2L  [NB_SW4_5D2X5D2X1D7]  164.29 6.53 180 top
TH1  hole_2d8_6_p  [HOLE_2D8_6_P]  6.65 87 180 bottom
TH5  hole_2d8_6_p  [HOLE_2D8_6_P]  167.65 95.5 180 bottom
TH8  hole_3d5_6_p  [HOLE_3D5_6_P]  76.65 1 0 top
TH10  hole_3d5_6_p  [HOLE_3D5_6_P]  190.15 6 180 bottom
TH12  hole_2d8_6_p  [HOLE_2D8_6_P]  5.15 6 180 bottom
TH13  hole_2d8_6_p  [HOLE_2D8_6_P]  5.15 70 180 bottom
TH14  hole_2d8_6_p  [HOLE_2D8_6_P]  54.85 97 180 bottom
TP1  20MIL  [ICTPAD_C20]  105.66 36.88 180 bottom
TP2  20MIL  [ICTPAD_C20]  108.08 37.92 180 bottom
TP3  20MIL  [ICTPAD_C20]  109.73 37.92 180 bottom
TP4  20MIL  [ICTPAD_C20]  105.66 36.01 180 bottom
TP5  20MIL  [ICTPAD_C20]  106.65 36.98 180 bottom
TP6  20MIL  [ICTPAD_C20]  106.22 39.19 180 bottom
TP7  20MIL  [ICTPAD_C20]  104.65 39.19 180 bottom
TP8  20MIL  [ICTPAD_C20]  108.46 36.78 180 bottom
TP9  20MIL  [ICTPAD_C20]  109.09 37.67 180 bottom
TP10  20MIL  [ICTPAD_C20]  107.85 37.06 180 bottom
TP11  20MIL  [ICTPAD_C20]  107.24 37.44 180 bottom
TP12  20MIL  [ICTPAD_C20]  106.55 44.52 0 top
TP13  20MIL  [ICTPAD_C20]  106.93 45.16 0 top
TP141  40MIL  [CMP_40]  64.82 9.73 180 bottom
TP142  40MIL  [CMP_40]  60.58 9.98 180 bottom
TP143  40MIL  [CMP_40]  59.31 9.98 180 bottom
TP144  40MIL  [CMP_40]  61.85 9.98 180 bottom
TP145  40MIL  [CMP_40]  137.59 7.72 0 top
TP146  40MIL  [CMP_40]  140.64 7.72 0 top
TP147  40MIL  [CMP_40]  139.11 7.72 0 top
TP148  40MIL  [CMP_40]  142.37 7.06 0 top
TP149  40MIL  [CMP_40]  56.26 11.3 180 bottom
TP150  40MIL  [CMP_40]  53.97 9.55 180 bottom
TP151  40MIL  [CMP_40]  178.05 11.88 0 top
TP154  40MIL  [CMP_40]  181.25 9.93 0 top
TP176  20MIL  [TPAD22-OP]  22.65 3.58 0 top
TP177  20MIL  [ICTPAD_C20]  67.05 48.21 0 top
TP178  20MIL  [ICTPAD_C20]  58.42 50.24 180 bottom
TP179  20MIL  [ICTPAD_C20]  59.18 50.24 180 bottom
TP180  20MIL  [ICTPAD_C20]  63.85 49.91 0 top
TP181  20MIL  [ICTPAD_C20]  57.53 50.24 180 bottom
TP182  20MIL  [ICTPAD_C20]  65.15 49.86 0 top
TP183  20MIL  [ICTPAD_C20]  59.43 48.59 180 bottom
TP184  20MIL  [ICTPAD_C20]  59.43 49.35 180 bottom
TP185  20MIL  [ICTPAD_C20]  60.2 47.06 180 bottom
TP186  20MIL  [ICTPAD_C20]  65.28 47.44 0 top
TP188  40MIL  [CMP_40]  49.02 7.8 0 top
TP190  40MIL  [CMP_40]  46.48 7.95 0 top
TP191  40MIL  [CMP_40]  13.41 80.03 0 top
TP192  40MIL  [CMP_40]  12.14 84.2 180 bottom
TP193  40MIL  [CMP_40]  14.17 75.36 0 top
TP194  40MIL  [CMP_40]  11.63 68.6 180 bottom
TP195  40MIL  [CMP_40]  12.44 81.71 0 top
TPE1  40MIL  [TPAD40-OP]  171.75 18.67 0 top
TPE2  40MIL  [TPAD40-OP]  164.46 25.47 0 top
TPE6  40MIL  [TPAD40-OP]  146.18 61.03 0 top
TPE7  40MIL  [TPAD40-OP]  145.13 63.17 0 top
TPE8  40MIL  [TPAD40-OP]  143.89 62.35 0 top
TPE9  40MIL  [TPAD40-OP]  159.38 60.83 0 top
TPE101  40MIL  [TPAD40-OP]  185.07 18.53 0 top
TPE102  40MIL  [TPAD40-OP]  185.22 16.96 0 top
TPE103  40MIL  [TPAD40-OP]  185.17 15.33 0 top
TPE104  40MIL  [TPAD40-OP]  185.17 13.65 0 top
TPE105  20MIL  [TPAD22-OP]  155.19 18.62 90 top
TPE106  20MIL  [TPAD22-OP]  159.61 8.2 0 top
TPF1  20MIL  [TPAD22-OP]  136.09 34.57 270 top
TPF2  20MIL  [TPAD22-OP]  132.48 31.21 270 top
TPF3  20MIL  [TPAD22-OP]  141.73 31.06 270 top
TPF4  20MIL  [TPAD22-OP]  141.12 32.28 270 top
TPI3  20MIL  [TPAD22-OP]  27.58 58.6 180 top
TPI5  20MIL  [TPAD22-OP]  21.79 57.88 180 top
TPI6  20MIL  [TPAD22-OP]  19.71 56.61 180 top
TPI7  20MIL  [TPAD22-OP]  29.36 49.71 180 top
TPI8  20MIL  [TPAD22-OP]  23.67 46.45 180 top
TPI9  20MIL  [TPAD22-OP]  21.94 46.4 180 top
TPP10  40MIL  [TPAD40-OP]  56.34 50.42 180 bottom
TPP11  40MIL  [TPAD40-OP]  60.27 51.46 180 bottom
TPP12  40MIL  [TPAD40-OP]  128.6 6.42 0 top
TPP13  40MIL  [TPAD40-OP]  145.62 9.24 0 top
TPP14  40MIL  [TPAD40-OP]  147.32 9.83 0 top
TPP15  40MIL  [TPAD40-OP]  150.57 7.19 0 top
TPT1  40MIL  [CMP_40]  50.06 29.54 180 bottom
TPT2  40MIL  [CMP_40]  40.26 42.24 180 bottom
TPT3  40MIL  [CMP_40]  50.8 31.82 180 bottom
TPT4  40MIL  [CMP_40]  51.92 41.98 180 bottom
TPT5  40MIL  [CMP_40]  54.05 33.27 180 bottom
TPT6  20MIL  [ICTPAD_C20]  19.86 27.35 180 top
TPT7  20MIL  [ICTPAD_C20]  31.8 17.09 180 top
TPT8  20MIL  [ICTPAD_C20]  29.46 17.98 180 top
TPT9  20MIL  [ICTPAD_C20]  28.07 18.87 0 top
TPT10  20MIL  [ICTPAD_C20]  30.48 19.89 0 top
TPT11  20MIL  [ICTPAD_C20]  26.59 19 0 top
TPT12  20MIL  [ICTPAD_C20]  30.48 18.62 0 top
TPT13  20MIL  [ICTPAD_C20]  21.21 21.03 0 top
TPT14  40MIL  [CMP_40]  51.92 40.05 180 bottom
TPT15  40MIL  [CMP_40]  51.81 38.33 180 bottom
TPT16  40MIL  [CMP_40]  44.45 30.25 180 bottom
TPT17  40MIL  [CMP_40]  43.56 28.6 180 bottom
TPT18  40MIL  [CMP_40]  34.92 28.95 180 bottom
TPT19  40MIL  [CMP_40]  40.54 35.02 180 bottom
TPT20  40MIL  [CMP_40]  31.8 31.67 180 bottom
TPT21  40MIL  [CMP_40]  39.77 41.07 180 bottom
TPU1  20MIL  [TPAD22-OP]  106.81 61.03 0 top
TPU2  20MIL  [TPAD22-OP]  114.7 62.86 0 top
TPU3  20MIL  [TPAD22-OP]  110.63 62.81 0 top
TPU4  20MIL  [TPAD22-OP]  105.54 61.03 0 top
TPU6  20MIL  [TPAD22-OP]  72.87 62.71 0 top
TPU7  20MIL  [TPAD22-OP]  73.84 62 0 top
TPU8  20MIL  [TPAD22-OP]  56.77 63.42 180 bottom
TPU9  20MIL  [TPAD22-OP]  57.15 62.71 180 bottom
TPU10  20MIL  [TPAD22-OP]  75.06 68.91 180 bottom
TPU11  20MIL  [TPAD22-OP]  75.69 69.29 180 bottom
TPU12  20MIL  [TPAD22-OP]  78.1 63.19 0 top
TPU13  20MIL  [TPAD22-OP]  66.17 69.8 180 bottom
TPU14  20MIL  [TPAD22-OP]  68.83 70.48 180 bottom
TPU15  20MIL  [TPAD22-OP]  68.5 63.07 0 top
TPU16  20MIL  [TPAD22-OP]  73.61 61.08 0 top
TPU17  20MIL  [TPAD22-OP]  66.93 68.65 180 bottom
TPU18  20MIL  [TPAD22-OP]  70.23 63.42 0 top
TPU20  20MIL  [TPAD22-OP]  68.32 69.54 180 bottom
TPU21  20MIL  [TPAD22-OP]  62.89 60.37 0 top
TPU22  20MIL  [TPAD22-OP]  56.08 72.97 180 bottom
TPU23  20MIL  [TPAD22-OP]  71.09 63.42 0 top
TPU24  20MIL  [TPAD22-OP]  79.88 39.06 180 bottom
TPU25  20MIL  [TPAD22-OP]  116.94 62.2 0 top
TPU26  20MIL  [TPAD22-OP]  115.57 61.69 0 top
TPU27  20MIL  [TPAD22-OP]  112.27 37.41 180 bottom
TPU28  20MIL  [TPAD22-OP]  113.54 36.9 90 bottom
TPU29  20MIL  [TPAD22-OP]  103.38 42.87 0 top
TPU30  20MIL  [TPAD22-OP]  109.68 58.14 0 top
TPU31  20MIL  [TPAD22-OP]  102.74 43.63 0 top
TPU32  20MIL  [TPAD22-OP]  91.02 37.55 180 bottom
TPU33  20MIL  [TPAD22-OP]  92.33 37.54 180 bottom
TPU34  20MIL  [TPAD22-OP]  76.71 55.9 0 top
TPU35  20MIL  [TPAD22-OP]  71.25 46.43 0 top
TPU36  20MIL  [TPAD22-OP]  59.59 40.66 180 bottom
TPU37  20MIL  [TPAD22-OP]  65.53 37.54 180 bottom
TPU38  20MIL  [TPAD22-OP]  62.74 37.54 180 bottom
TPU39  20MIL  [TPAD22-OP]  64.13 37.67 180 bottom
TPU40  20MIL  [TPAD22-OP]  115.52 42.14 180 bottom
TPU72  20MIL  [TPAD22-OP]  28.83 77.29 0 top
TPU73  20MIL  [TPAD22-OP]  104.65 43.76 0 top
TPU74  20MIL  [TPAD22-OP]  105.41 43.76 0 top
TPV1  20MIL  [TPAD22-OP]  143.36 86.59 180 bottom
TPV2  20MIL  [TPAD22-OP]  144.68 86.84 180 bottom
TPV3  20MIL  [TPAD22-OP]  145.29 85.42 180 bottom
TPV4  20MIL  [TPAD22-OP]  141.43 86.28 180 bottom
TPV5  20MIL  [TPAD22-OP]  151.28 61.95 0 top
TPV6  20MIL  [TPAD22-OP]  146.63 74.75 0 top
TPV7  20MIL  [TPAD22-OP]  145.29 74.88 0 top
TPV8  20MIL  [TPAD22-OP]  145.84 75.36 0 top
TPW1  20MIL  [TPAD22-OP]  148.54 18.36 0 top
TPW2  20MIL  [TPAD22-OP]  148.26 19.63 0 top
TPW3  20MIL  [TPAD22-OP]  154.56 15.26 0 top
TPWC1  40MIL  [TPAD40-OP]  116.08 3.12 180 bottom
TPWC2  40MIL  [TPAD40-OP]  114.17 2.99 180 bottom
UA2  CX8402  [NB_QFN60_7X7X0D9]  173.07 28.17 0 top
UB6  APL3524QBI  [QFN16_3X3X0D65_0D5]  25.65 36.8 90 top
UD1  K4F6E3S4HM-MGCJ  [NB_BGA200_15X10X1D2_0D65]  66.67 86.31 180 bottom
UD2  K4F6E3S4HM-MGCJ  [NB_BGA200_15X10X1D2_0D65]  84.33 86.31 180 bottom
UD3  K4F6E3S4HM-MGCJ  [NB_BGA200_15X10X1D2_0D65]  101.98 86.31 180 bottom
UD4  K4F6E3S4HM-MGCJ  [NB_BGA200_15X10X1D2_0D65]  119.63 86.31 180 bottom
UE1  IT5571  [NB_BGA128_7X7X0D95_0D5]  163.47 17.24 0 top
UE2  XM25QH40BJIGT  [NB_SOP8_5D38X5D33X2D16]  139.32 19.57 180 bottom
UF15  NPCT750AABYX  [NB_QFN32_5X5X0D8_0D5_NPCT75X]  137.16 30.43 270 top
UI1  SGM2576  [NB_SOT23-5_3D7X1D8X1D47]  24.69 60.63 0 bottom
UI2  PS8409A  [NB_QFN48_6X6X0D9_0D4]  24.26 53.03 270 top
UO1  W25Q128JVSIQT  [NB_SOIC-208-8_5D33X5D33X2D16]  132.31 11.02 90 bottom
US1  NCT7719W  [NB_MSOP10_3X31D1]  69.39 5.84 270 bottom
US4  G753T11U  [NB_TSOT23-5_2D9X1D6X0D9]  152.14 6.2 180 bottom
UT1  CYPD5126-40LQXIT  [NB_QFN40_6X6X0D6_0D5]  45.21 37.79 180 bottom
UT2  BB_RETIMER  [NB_BGA105_6X6X0D826]  25.4 23.57 180 top
UT3  W25Q80DVSSIGT  [NB_SOP8_5D38X5D33X2D16]  32.89 35.25 270 bottom
UT4  SGM2576  [NB_SOT23-5_3D7X1D8X1D47]  21.33 33.86 0 bottom
UT5  WS4683C-16/TR  [NB_BGA16_2D05X2D05X0D6_0D5]  21.18 12.27 270 top
UT6  KTS1677EVH-TR  [NB_BGA15_2D56X1D54X0D6_0D5]  29.56 7.03 90 top
UT7  TPD6S300RUKR  [NB_QFN20_3X3X0D8]  12.06 10.87 0 top
UU1  ICL_U_IP_EXT_WW20  [NB_BGA1526_50X25X1D26_ICL_U42]  87.63 53.92 180 bottom
UU2  74AUP1G07GW  [NB_SOT353_2X1D25X1D1]  126.74 91.64 0 top
UV1  74LVC1G08GW  [NB_SOT23-5_2X1D25X1D1]  132.65 54.57 0 bottom
UV2  U_GPU_GB2C_64  [BGA595_23X23X2D1_0D8]  151.74 70.51 0 bottom
UV3  K4G80325FB-HC28  [BGA170_15X12D5X1D2_0D8]  181.01 65.08 270 bottom
UV4  K4G80325FB-HC28  [BGA170_15X12D5X1D2_0D8]  181.01 84.44 90 bottom
UW1  G517F1T13U  [NB_SOT23_5_2D95X1D6X1D4]  139.57 12.82 90 bottom
UX1  G517F1T13U  [NB_SOT23_5_2D95X1D6X1D4]  28.57 68.78 270 bottom
UX2  G517F1T13U  [NB_SOT23_5_2D95X1D6X1D4]  33.4 67.38 0 bottom
VCC_SPIO1  40MIL  [TPAD40-OP]  130.4 6.37 90 top
WIFI_BOSS  4*2.1-M2  [HOLE_3D5_5_T]  179.31 20.95 180 bottom
XT1  X3S025000BI1H-HS  [NB_XTAL4_3D2X2D5X0D8]  22.99 29.66 0 top
YU1  Q13FC1350000200  [XTAL2_3D2X1D5X0D9]  61.72 71.45 90 bottom
YU2  X3S038400BA1H-HS  [XTAL4_3D2X2D5X0D8]  56.26 45.16 270 bottom
YV1  X2V027000BA1HA-HU  [NB_XTAL4_2D05X1D65X0D8]  148.71 52.64 180 bottom

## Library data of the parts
+1.35VGS1 = TESTPAD_CIR: room: PWR-GPU GDDR
+V1P8SX = TP: room: PWR_LOADSWITCH
+V5P0SX_HDMI_F = TESTPAD_CIR: room: HDMI
+VCCIN1 = TESTPAD_CIR: room: PWR_VCCIN
+VCCIN_AUX1 = TESTPAD_CIR: room: PWR_VCCIN_AUX
C8 CE25 = cap: room: HALL
C9 = cap: room: FP
C10 = CAP: room: FP
CA8 CA11-CA18 CA23-CA28 CA31 CA32 CA34-CA38 CA56-CA82 CI103 PC152 = cap: room: CODEC
CB32 CB390 CB392-CB395 CB398 CB399 CB404 = cap: room: USB3P1_AOU
CB33-CB36 CB38 = CAP: room: USB3P1_AOU
CB413 = CAP: room: DB
CB414 CB415 = cap: room: WIRELESS_CHARGER
CD1 CU13 CU33-CU36 CU38 CU39 CU52 CU54 CU67-CU80 CU83-CU94 CU101-CU103 CU114-CU137 CU148 CU149 CU152-CU169 = CAP: room: SOC
CD2-CD9 = CAP: room: LPDDR4-CHA
CD10-CD17 = CAP: room: LPDDR4-CHB
CD18-CD27 CD38-CD43 CD50-CD57 CD66-CD74 CD84-CD88 CD94-CD100 = cap: room: LPDDR4-CHA
CD28-CD37 CD44-CD49 CD58-CD65 CD75-CD83 CD89-CD93 CD101-CD107 PC657-PC659 = cap: room: LPDDR4-CHB
CE7-CE9 = cap: room: KB_BL
CE14 CE37 CE40 CE42 CE376-CE378 = cap: room: EC
CE18 CE26 CE32-CE36 CE38 CE39 CE43 CE46 CE52 CE53 CE374 CE375 = CAP: room: EC
CE19-CE21 = CAP: room: FAN
CE22 = cap: room: FAN
CE23 CE45 CE54 = cap: room: TOUCH_PAD
CE24 CE44 CE55 = CAP: room: TOUCH_PAD
CE373 = cap: room: KB_CONN
CF1-CF3 CF8 CF11 = CAP: room: TPM
CF9 CF10 CF12 = cap: room: TPM
CHK1 = EXC14CE900U: room: FP
CHKB25-CHKB27 = EXC14CE900U: room: USB3P1_AOU
CHKI1 CHKI5-CHKI7 = EXC14CE900U: room: HDMI
CHKW1 = EXC14CE900U: room: WIFI
CHKX1 CHKX2 CHKX5-CHKX9 = EXC14CE900U: room: EDP
CI1 CI61-CI68 CI104 CI106-CI116 CI118 CI119 = CAP: room: HDMI
CI20 CI105 CI117 CI120 = cap: room: HDMI
CL1 CL32 CL33 = cap: room: LOGIC
CLKO1 CSO1 GND_SPIO1 IOO1 IOO2 MISOO1 MOSIO1 VCC_SPIO1 = TP: room: SPI
CN1-CN5 CN7-CN13 CN15 CN16 CN18 CN19 = cap: room: SSD
CN6 CN17 = CAP: room: SSD
CO1 CO2 CP3 = CAP: room: SPI
CP1 = cap: room: DEBUG
CP2 = CAP: room: DEBUG
CPU_BOSS1-CPU_BOSS4 GPU_BOSS1 GPU_BOSS2 WIFI_BOSS = THERM_HOLE: room: BOSS
CS1 CS3 = CAP: room: THERMAL_SENSOR
CS2 CS17 = cap: room: THERMAL_SENSOR
CT1-CT17 CT26-CT29 CT32 CT33 CT38 CT39 CT46 CT51 CT52 CT55 CT56 CT58-CT61 CT66 CT67 CT74-CT78 CT81-CT83 PC150 PC151 PC153 PC180 PC182 = cap: room: TYPEC
CT18-CT25 = cap: signal model: CAP_C0201_C0201X5R224M6R3NTJ~_1_C0201X5R224M6R3NTJ~~GRM033R60J224ME15D~~CC0201MRX5R5BB224; room: TYPEC
CT30 CT31 CT34-CT37 CT40-CT45 CT47 CT48 CT50 CT54 CT72 CT73 CT79 CT80 = CAP: room: TYPEC
CT57 = PSBD1DF40V3H: room: TYPEC
CT62-CT65 CT68-CT71 = cap: signal model: CAP_C0402_XXXXXX__xxxxxx; room: TYPEC
CU1-CU11 CU14-CU32 CU37 CU40-CU51 CU53 CU55-CU66 CU81 CU82 CU95-CU100 CU104-CU113 CU138-CU147 CU150 CU151 CU170 CU171 PC405 PC412 = cap: room: SOC
CV1 CV2 CV5-CV16 CV18-CV20 CV22 CV23 CV26 CV27 CV32 CV43 CV44 CV49-CV51 CV53-CV56 CV61-CV64 CV68-CV85 CV97-CV105 CV108 CV111-CV115 CV192 CV195 CV197-CV199 CV201-CV209 = cap: room: GPU
CV3 CV4 CV17 CV21 CV24 CV25 CV28-CV31 CV33-CV37 CV41 CV42 CV45-CV48 CV52 CV57-CV60 CV86-CV96 CV106 CV107 CV109 CV110 CV116 CV117 CV187 CV193 CV194 CV196 CV200 PC1 = CAP: room: GPU
CV118 CV119 CV124-CV144 CV147-CV169 CV174-CV177 = cap: room: VRAM
CV120-CV123 CV145 CV146 CV170 CV171 CV178 CV179 = CAP: room: VRAM
CW3-CW5 CW9-CW13 = CAP: room: WIFI
CW6 CW8 CW14-CW16 = cap: room: WIFI
CX1-CX3 CX5-CX9 CX13-CX16 CX21 CX22 CX886 CX888-CX892 CX895 CX896 = CAP: room: EDP
CX4 CX10 CX17 CX18 CX284 CX885 CX887 CX893 CX894 CX897 CX898 = cap: room: EDP
DA2 PD907 = LBAT54AWT1G: room: CODEC
DE3 = DIODE SCHOTTKY_5: room: FAN
DE5 = RB500V-40_0: room: EC
DE6 = RB500V-40_1: room: EC
DL2 DL3 = PSBD2FD40V01: room: LOGIC
DO1 = RB521C30: room: SPI
DT1 = RB521C30: room: TYPEC
DU1 DU3 = RB500V-40_0: room: SOC
DU2 = BAT54CW_SOT323-3_0: room: SOC
DV1-DV4 DV6 DV7 DV16 = RB500V-40_0: room: GPU
DV5 DV8 DV11 = LBAT54AWT1G: room: GPU
DV9 DV14 = BAT54CW_SOT323-3_0: room: GPU
DWC1 = SCHOTTKY: room: WIRELESS_CHARGER
DX1 = LBAT54AWT1G: room: EDP
EDB3 EDB5 = ESD9N5BM_2TR: room: USB3P1_AOU
ESD1 = ESD5342N-3_TR: room: FP
ESD2 ESD3 = ESD5342N-3_TR: room: EDP
ESDB25 = ESD5411N: room: USB3P1_AOU
ESDB34 = ESDA6V8UD-10: room: USB3P1_AOU
ESDE4-ESDE7 = ESD5451R_2_TR: room: TOUCH_PAD
ESDE44 = PESDTC5VB_5: room: KB_CONN
ESDE45 = PESDTC5VB_5: room: HALL
ESDI1-ESDI4 = ESD9N5BM_2TR: room: HDMI
ESDI7-ESDI14 ESDT2-ESDT5 ESDT8-ESDT11 = PESD5V0H1BSF: room: TYPEC
ESDL46 = PESDTC5VB_5: room: LOGIC
ESDT1 = ESD5401N-2-TR: room: TYPEC
ESDT6 ESDT7 = ESD5342N-3_TR: room: TYPEC
ESDT12 ESDT13 = ESD9N5BM_2TR: room: TYPEC
ESDX1 ESDX2 = ESD5451R_2_TR: room: EDP
FBA1 FBA5 = bead: room: CODEC
FBA2 = FB: room: CODEC
FBA4 = UPZ1608E181: room: CODEC
FBE2 = bead: room: EC
FBI5 = bead: room: HDMI
FBT2 = bead: room: TYPEC
J1 = ZIF39B_20: room: FP
J3001 = 50208-00601-001: room: SPI
JB8 = MINI USB_5: room: USB3P1_AOU
JDB1 = FPC-50PIN_1: room: DB
JE3 = SPK_1: room: FAN
JE4 = 50503-00801-001: room: TOUCH_PAD
JE7 = 50690-02841-001: room: KB_CONN
JI1 = W-HDMI-CH162-025: room: HDMI
JKBL1 = 51614-00401-002: room: KB_BL
JKBL3 = ZIF39B_20: room: EDP
JP2 = FPC-4PIN_0: room: DEBUG
JRTCU1 = 11255W90-2P-S-5A-HF: room: SOC
JSSD1 = 40-42547-067B1RHF-HQ: room: SSD
JT1 = 40-42500-A1400RHF-HQ_0: room: TYPEC
JW1 = ngff_key-e_0: room: WIFI
JX1 = FPC-50PIN_1: room: EDP
LEDE2 = LTST-C195TBKFKT_0: room: DEBUG
LT1 = ind: room: TYPEC
LT2 = EXC14CE900U: room: TYPEC
LU1 = ind: room: SOC
LV1 LV3 = bead: room: GPU
MR1 = AH1902_1: room: HALL
PBTE1 = TESTPAD_CIR: room: EC
PC101-PC104 PC106-PC115 PC118-PC120 PC122 PC128-PC130 PC134 PC136-PC140 PC143-PC146 PC154 = cap: room: PWR_CHARGER
PC105 PC117 PC121 PC123 PC124 PC127 PC131 PC133 PC141 PC142 PC155 = CAP: room: PWR_CHARGER
PC125 PC126 PC132 PC135 = cap: room: PWR-DCIN
PC201 PC204-PC209 PC211 PC213-PC216 PC220 = cap: room: PWR-3P3VA
PC210 = CAP: room: PWR-3P3VA
PC301 PC302 PC305 PC306 PC309-PC314 PC316-PC319 = cap
PC308 = CAP
PC320 = CAP: room: POWER_5VA
PC401-PC404 PC406 = cap: room: PWR-V1P8A
PC410 PC411 PC413-PC415 = cap: room: PWR-V1P2HDMI
PC501 PC506 PC510 = CAP: room: PWR_VCCIN_AUX
PC502-PC505 PC507-PC509 PC511-PC522 PC530 PC1215 = cap: room: PWR_VCCIN_AUX
PC601-PC603 PC606 PC607 PC609 PC611-PC613 PC615-PC620 PC622-PC631 PC640 PC641 = cap: room: PWR_VCCIN
PC604 PC605 PC608 PC621 = CAP: room: PWR_VCCIN
PC656 PC969-PC972 = cap: room: MS@Power-VCCIO
PC701 PC704 PC705 PC708-PC712 PC714 PC716-PC718 PC720 PC721 PC730 = cap: room: PWR-LPDDR4
PC702 PC703 PC715 PC719 = CAP: room: PWR-LPDDR4
PC818 PC856 = CAP: room: PWR-GPU CORE
PC819-PC825 PC827 PC828 PC830 PC833 PC834 PC836 PC837 PC844 PC855 PC857-PC860 PC863-PC865 PC867 PC868 PC887 PC888 = cap: room: PWR-GPU CORE
PC901-PC903 PC905-PC907 PC909 PC912 PC914 PC916 PC930 PC975-PC978 = cap: room: PWR_LOADSWITCH
PC904 PC908 PC910 PC911 PC913 PC915 PC931 PC932 = CAP: room: PWR_LOADSWITCH
PC1101 PC1102 PR1150 = CAP: room: PWR-GPU GDDR
PC1103-PC1110 PC1120-PC1124 PC11258 = cap: room: PWR-GPU GDDR
PC1150 PR1101-PR1105 PR1107-PR1109 PR1111 = res: room: PWR-GPU GDDR
PC1201 PC1205 PC1209-PC1211 = cap: room: PWR-GPU LOADSWITCH
PC1202-PC1204 PC1208 PC1212-PC1214 = CAP: room: PWR-GPU LOADSWITCH
PCS501 PCS502 = tcap: room: PWR_VCCIN_AUX
PCS601 PCS602 PCS604 PCS606 = tcap: room: PWR_VCCIN
PCS801 PCS802 PCS804 = tcap: room: PWR-GPU CORE
PD904 PD906 = BAT54CW_SOT323-3_0: room: PWR_LOADSWITCH
PDT1 PDT2 = SCHOTTKY: room: TYPEC
PESD104 = ESD5401N-2-TR: room: PWR-DCIN
PESD105 = ESD5451R_2_TR: room: PWR_CHARGER
PESD106 = ESD5342N-3_TR: room: PWR_CHARGER
PESD107 = PTVSHC3N15VU: room: PWR_CHARGER
PFB101 PFB102 = UPZ1608U220-6R0TF: room: PWR-DCIN
PJ101 = CON6_BAT_HDR_2: room: PWR_CHARGER
PJ102 = 30706-11202-001: room: PWR-DCIN
PL101 = L7368_2.2uH_8A_M: room: PWR_CHARGER
PL102 PL201 = ind_0: room: PWR-3P3VA
PL301 = ind_0
PL401 = ind: room: PWR-V1P8A
PL402 = ind: room: PWR-V1P2HDMI
PL501 = IND: room: PWR_VCCIN_AUX
PL601 PL602 = IND: room: PWR_VCCIN
PL701 PL702 = ind: room: PWR-LPDDR4
PL802 PL803 = IND: room: PWR-GPU CORE
PL1101 = ind: room: PWR-GPU GDDR
PQ101 = AONR21357_0: room: PWR_CHARGER
PQ103 = MDV1528URH_2: room: PWR_CHARGER
PQ105 PQ107 PQ108 = AON7534: room: PWR_CHARGER
PQ110 PQ111 = AONR21357_0: room: TYPEC
PQ112 PQ114 = L2N7002LT1G_2N7002LT1G_2N7002: room: TYPEC
PQ501 = PK6D0BA: room: PWR_VCCIN_AUX
PQ502 = PK664BA: room: PWR_VCCIN_AUX
PQ601 PQ604 = PK6D0BA: room: PWR_VCCIN
PQ602 PQ603 = PK664BA: room: PWR_VCCIN
PQ801 PQ802 = AON6982: room: PWR-GPU CORE
PQ901 PQ902 = WNM2046-3-TR: room: PWR_LOADSWITCH
PR1 RV2 RV3 RV5-RV7 RV9-RV13 RV16-RV18 RV21-RV27 RV29 RV31 RV32 RV34 RV35 RV37 RV38 RV40 RV42-RV47 RV49 RV50 RV53 RV56-RV65 RV68-RV78 RV82-RV87 RV89-RV95 RV110-RV127 RV138 RV142 RV143 RV147 RV248 RV250 RV251 = res: room: GPU
PR105 PR107 PR108 PR110-PR112 PR115-PR117 PR120-PR123 PR125 PR126 PR128 PR129 PR131 PR134-PR138 PR160 PR162 PR163 = res: room: PWR_CHARGER
PR106 PR165 = NB_RES_PMR: room: PWR_CHARGER
PR130 PR161 = res: signal model: RES_R0201_0201WMJ0000TCE+0201_1_0201WMJ0000TCE+0201WMJ0000TJE~~MCR006YRTJ000~~RC0201JR-070RL+RC0201JR-130RL~~WR02X000PAL; room: PWR_CHARGER
PR132 PR133 = res: room: PWR-DCIN
PR141 PR166-PR170 PR185-PR187 RT1-RT6 RT16-RT23 RT32 RT33 RT43 RT44 RT46-RT59 RT61-RT65 RT67 RT76 RT77 RT79-RT81 RT83-RT87 RT91-RT102 RT104-RT106 RT113 RT115 RT117-RT119 RT122 RT123 RT126-RT135 = res: room: TYPEC
PR164 PR413 PR911 PR915 PSH101 = SHUNT_LOCAL_3: room: PWR_CHARGER
PR188 PR1012 PR1013 PR6157 RL2 RL45 = res: room: LOGIC
PR201-PR205 = res: room: PWR-3P3VA
PR301 PR302 PR306 = res
PR305 PR307 = res: room: PWR_5VA
PR401-PR404 PR415 = res: room: PWR-V1P8A
PR410-PR412 = res: room: PWR-V1P2HDMI
PR414 PR703 PR706 PR707 PSH201-PSH206 = SHUNT_LOCAL_3: room: PWR-3P3VA
PR501-PR511 PR513-PR532 PR625 = res: room: PWR_VCCIN_AUX
PR601-PR617 PR619 PR620 PR623 PR624 PR626-PR656 PR658 PR661-PR664 = res: room: PWR_VCCIN
PR618 PR621 PR622 = RES: room: PWR_VCCIN
PR657 PR660 = res: room: PWR_VCCIN; signal model: RES_R0201_0201WMJ0000TCE+0201_1_0201WMJ0000TCE+0201WMJ0000TJE~~MCR006YRTJ000~~RC0201JR-070RL+RC0201JR-130RL~~WR02X000PAL
PR659 PR930 = SHUNT_LOCAL_3: room: PWR-3P3VA; signal model: RES_R0201_0201WMJ0000TCE+0201_1_0201WMJ0000TCE+0201WMJ0000TJE~~MCR006YRTJ000~~RC0201JR-070RL+RC0201JR-130RL~~WR02X000PAL
PR702 PR704 PR708 PR709 PR712 = res: room: PWR-LPDDR4
PR705 = RES: room: PWR-LPDDR4
PR814-PR827 PR829 PR830 PR833 PR836 PR848-PR850 PR852 PR859-PR861 = res: room: PWR-GPU CORE
PR828 PR839 = R0402_1.5M_1/16W_F: room: PWR-GPU CORE
PR835 PR837 PR838 = res: signal model: RES_R0201_0201WMJ0000TCE+0201_1_0201WMJ0000TCE+0201WMJ0000TJE~~MCR006YRTJ000~~RC0201JR-070RL+RC0201JR-130RL~~WR02X000PAL; room: PWR-GPU CORE
PR901-PR906 PR909 PR910 PR913 PR914 PR916-PR921 = res: room: PWR_LOADSWITCH
PR907 = res: room: MS@Power-VCCIO
PR912 = res: room: PWR_LOADSWITCH; signal model: RES_R0201_0201WMJ0000TCE+0201_1_0201WMJ0000TCE+0201WMJ0000TJE~~MCR006YRTJ000~~RC0201JR-070RL+RC0201JR-130RL~~WR02X000PAL
PR1201-PR1204 PR1206 = res: room: PWR-GPU LOADSWITCH
PR1207 SHE1 = SHUNT_LOCAL_3: room: FAN
PRT501 = ntc: room: PWR_VCCIN_AUX
PRT601 PRT602 = ntc: room: PWR_VCCIN
PSH104 PSH105 = SHUNT_LOCAL_3: room: PWR-DCIN
PSH306 = SHUNT_LOCAL_3
PSH401 PSH403 = SHUNT_LOCAL_3: room: PWR-V1P8A
PSH402 PSH404 = SHUNT_LOCAL_3: room: PWR-V1P2HDMI
PSH501 PSH502 = SHUNT_LOCAL_3: room: PWR_VCCIN_AUX
PSH601-PSH603 = SHUNT_LOCAL_3: room: PWR_VCCIN
PSH706 = LOCAL_SHUNT_1: room: PWR-LPDDR4
PSH707-PSH709 = SHUNT_LOCAL_3: room: PWR-LPDDR4
PSH806-PSH809 = LOCAL_SHUNT_1: room: PWR-GPU CORE
PSH901-PSH904 PSH930 = SHUNT_LOCAL_3: room: PWR_LOADSWITCH
PSH1101-PSH1104 = LOCAL_SHUNT_1: room: PWR-GPU GDDR
PTP101-PTP109 = TP: room: PWR_CHARGER
PU101 = BQ25700_1: room: PWR_CHARGER
PU201 = RT6258B: room: PWR-3P3VA
PU301 = RT6258C_0
PU401 = SY8843QWC_1: room: PWR-V1P8A
PU402 = RT8096C: room: PWR-V1P2HDMI
PU501 = RT6543A: room: PWR_VCCIN_AUX
PU601 = RT3612: room: PWR_VCCIN
PU701 = TPS51486_0: room: PWR-LPDDR4
PU802 = RT8811A_0: room: PWR-GPU CORE
PU901 PU903 PU904 PU906 = EM5201BJ-45_0: room: PWR_LOADSWITCH
PU902 = G5016KD1U_0: room: PWR_LOADSWITCH
PU910 = SGM2578: room: PWR_LOADSWITCH
PU1101 = SY8286A_1: room: PWR-GPU GDDR
PU1201 = G5016KD1U_0: room: PWR-GPU LOADSWITCH
PU1202 = WL2831: room: PWR-GPU LOADSWITCH
QA1 = WNMD2078_6TR: room: CODEC
QE2 = WNM2046-3_TR: room: KB_BL
QE3 = WNMD2078_6TR: room: TOUCH_PAD
QE4 = L2N7002LT1G_2N7002LT1G_2N7002: room: EC
QL1 QL4 QL6-QL8 QL10 = L2N7002LT1G_2N7002LT1G_2N7002: room: LOGIC
QL9 = WNM2046-3_TR: room: LOGIC
QS1 QS2 = LMBT3904LT1G: room: THERMAL_SENSOR
QT1-QT5 QU7 = WNM2046-3-TR: room: TYPEC
QU1 = WNMD2078_6TR: room: SOC
QU2 = WNM2046-3_TR: room: SOC
QU4-QU6 = LMBT3904LT1G: room: SOC
QV1 QV2 QV5 QV8-QV10 QV17 QV23 QV24 = WNM2046-3_TR: room: GPU
QV3 QV4 QV6 = WNMD2078_6TR: room: GPU
QV7 QV11 QV12 QV14 QV18-QV20 QV22 = L2N7002LT1G_2N7002LT1G_2N7002: room: GPU
QV21 = WNM2046-3_TR: room: VRAM
QW2 QW3 = L2N7002LT1G_2N7002LT1G_2N7002: room: WIFI
QX42 = PPMT20V3: room: EDP
R16 RE53 = res: room: HALL
R17 R18 = RES: room: FP
R19 R20 = res: room: FP
RA3 RA4 RA11 RA13 RA16-RA20 RA32 RA33 RA36 RA233 RA235-RA248 = res: room: CODEC
RA10 RA234 = res: signal model: RES_R0201_0201WMJ0000TCE+0201_1_0201WMJ0000TCE+0201WMJ0000TJE~~MCR006YRTJ000~~RC0201JR-070RL+RC0201JR-130RL~~WR02X000PAL; room: CODEC
RA23 RA24 = RES: room: CODEC
RB44 RB45 RB47-RB50 RB52 = res: room: USB3P1_AOU
RB46 RB51 = RES: room: USB3P1_AOU
RB363 RB364 = res: signal model: RES_R0201_0201WMJ0000TCE+0201_1_0201WMJ0000TCE+0201WMJ0000TJE~~MCR006YRTJ000~~RC0201JR-070RL+RC0201JR-130RL~~WR02X000PAL; room: USB3P1_AOU
RB373 = RES: room: DB
RD1 RD2 RU1-RU3 RU5-RU19 RU21-RU24 RU27 RU30 RU32 RU34 RU38-RU40 RU43 RU44 RU47-RU50 RU54-RU59 RU61-RU65 RU67 RU73 RU76-RU88 RU90 RU92-RU103 RU105-RU127 RU129-RU138 RU141-RU147 RU150-RU152 RU154 RU156-RU160 RU162-RU167 RU169-RU184 RU190-RU209 RU211-RU240 = res: room: SOC
RD3-RD6 = res: room: LPDDR4-CHA
RD7-RD10 = res: room: LPDDR4-CHB
RD11 = NB_RES_PMR: room: LPDDR4
RD12 = NB_RES_PMR: room: LPDDR4X
RE1-RE4 RE6 RE8 RE28-RE30 RE81 RE86 RE87 RE92 RE94-RE96 RE98 RE102-RE104 RE108-RE110 RE114 RE115 RE118 RE120 RE121 RE123 RE125 RE127 RE139 RE452 RE453 RE455 RE458 RE459 RE461 RE462 = res: room: EC
RE7 = RES: room: KB_BL
RE13 RE138 = res: room: KB_BL
RE31 RE33 RE68 RE80 RE112 RE113 RE134 RE135 RE460 = RES: room: EC
RE32 RE34 RE35 RE37 = res: signal model: RES_R0201_0201WMJ0000TCE+0201_1_0201WMJ0000TCE+0201WMJ0000TJE~~MCR006YRTJ000~~RC0201JR-070RL+RC0201JR-130RL~~WR02X000PAL; room: EC
RE48-RE51 = res: room: FAN
RE55-RE60 = RES: room: TOUCH_PAD
RE61-RE65 RE67 RE69 RE454 = res: room: TOUCH_PAD
RE447 RE457 RF1 RF6-RF11 = res: room: TPM
RE451 = res: signal model: RES_R0201_0201WMJ0000TCE+0201_1_0201WMJ0000TCE+0201WMJ0000TJE~~MCR006YRTJ000~~RC0201JR-070RL+RC0201JR-130RL~~WR02X000PAL; room: KB_CONN
RE456 RP12-RP15 = res: room: DEBUG
RF2-RF5 = RES: room: TPM
RI11-RI14 RI23-RI26 RI60 RI61 RI144 RI148 RI153 = res: signal model: RES_R0201_0201WMJ0000TCE+0201_1_0201WMJ0000TCE+0201WMJ0000TJE~~MCR006YRTJ000~~RC0201JR-070RL+RC0201JR-130RL~~WR02X000PAL; room: HDMI
RI33 RI34 RI40 RI101 RI102 RI104 RI145 RI146 RI149 RI151 RI152 RI154-RI163 = res: room: HDMI
RI105 RI106 RI142 RI143 = RES: room: HDMI
RL1 RL454 = RES: room: LOGIC
RL46 RL47 RL455 = res: signal model: RES_R0201_0201WMJ0000TCE+0201_1_0201WMJ0000TCE+0201WMJ0000TJE~~MCR006YRTJ000~~RC0201JR-070RL+RC0201JR-130RL~~WR02X000PAL; room: LOGIC
RN1 RN3-RN5 RN8 RN11 RN30 RN33 RN37 = res: room: SSD
RN31 = res: signal model: RES_R0201_0201WMJ0000TCE+0201_1_0201WMJ0000TCE+0201WMJ0000TJE~~MCR006YRTJ000~~RC0201JR-070RL+RC0201JR-130RL~~WR02X000PAL; room: SSD
RO1 = RES: room: SPI
RO2-RO4 = res: room: SPI
RO5-RO8 RO11 RO12 = RES: signal model: RES_R0201_0201WMF499JTCE~~MCR00_0201WMF499JTCE~~MCR006YRTF49R9~~RC0201FR-0749R9L~~WR02X49R9FAL; room: SPI
RO9 RO10 RO13 RO14 = res: signal model: RES_R0201_0201WMJ0000TCE+0201WM_0201WMJ0000TCE+0201WMJ0000TJE~~MCR006YRTJ000~~RC0201JR-070RL+RC0201JR-130RL~~WR02X000PAL; room: SPI
RS1-RS3 = res: room: THERMAL_SENSOR
RT7-RT15 RT34-RT42 RT45 RT60 RT66 RT68-RT73 RT78 RT82 RT89 RT90 RT103 RT111 RT112 RT114 RT116 RT120 RT121 RT124 RT125 = res: signal model: RES_R0201_0201WMJ0000TCE+0201_1_0201WMJ0000TCE+0201WMJ0000TJE~~MCR006YRTJ000~~RC0201JR-070RL+RC0201JR-130RL~~WR02X000PAL; room: TYPEC
RT24-RT31 = res: signal model: RES_R0201_0201WMF220KTCE~~RC020_0201WMF220KTCE~~RC0201FR-072R2L; room: TYPEC
RT74 RT75 = RES: room: TYPEC
RT88 = NB_RES_PMR: room: TYPEC
RU4 RU26 RU28 RU35-RU37 RU41 RU42 RU45 RU46 RU51-RU53 RU60 RU74 RU75 RU89 RU91 RU139 RU140 RU153 RU155 RU161 RU210 = RES: room: SOC
RU20 RU25 RU29 RU31 RU33 RU66 RU68-RU72 RU185-RU187 = res: signal model: RES_R0201_0201WMJ0000TCE+0201_1_0201WMJ0000TCE+0201WMJ0000TJE~~MCR006YRTJ000~~RC0201JR-070RL+RC0201JR-130RL~~WR02X000PAL; room: SOC
RV4 RV15 RV19 RV20 RV28 RV30 RV33 RV36 RV48 RV51 RV52 RV55 RV88 = RES: room: GPU
RV66 RV67 = R0402_0R_0.0625W_J: room: GPU
RV96-RV98 RV101 RV104-RV109 RV141 = res: room: VRAM
RV99 RV100 RV102 RV103 = R: room: VRAM
RV244 RV245 = res: signal model: RES_R0201_0201WMJ0000TCE+0201_1_0201WMJ0000TCE+0201WMJ0000TJE~~MCR006YRTJ000~~RC0201JR-070RL+RC0201JR-130RL~~WR02X000PAL; room: GPU
RW6-RW9 RW12 RW14-RW16 RW18 RW21 RW22 RW24 RW26 RW27 RW55-RW64 RW66-RW74 = res: room: WIFI
RW10 RW11 RW13 RW23 RW25 = RES: room: WIFI
RW28-RW33 = res: signal model: RES_R0201_0201WMJ0000TCE+0201_1_0201WMJ0000TCE+0201WMJ0000TJE~~MCR006YRTJ000~~RC0201JR-070RL+RC0201JR-130RL~~WR02X000PAL; room: WIFI
RX4 RX5 RX11 RX12 RX16-RX25 RX105 RX898 RX900-RX902 RX908 RX913-RX915 RX919-RX923 RX926 = res: room: EDP
RX242-RX245 RX904 RX905 RX909-RX912 = res: signal model: RES_R0201_0201WMJ0000TCE+0201_1_0201WMJ0000TCE+0201WMJ0000TJE~~MCR006YRTJ000~~RC0201JR-070RL+RC0201JR-130RL~~WR02X000PAL; room: EDP
RX897 RX899 RX906 RX907 RX916-RX918 RX924 RX925 = RES: room: EDP
SHE2-SHE5 = SHUNT_LOCAL_0: room: CODEC
SHI01 = SHUNT_LOCAL_3: room: HDMI
SHT1 = SHUNT_LOCAL_3: room: TYPEC
SHU1 SHU2 SHU5 SHU8 SHU9 = SHUNT_LOCAL_3: room: SOC
SHU3 SHU4 SHU6 SHU7 = SHUNT_LOCAL_0: room: SOC
SHX1 SHX9 = SHUNT_LOCAL_2: room: EDP
SW3-SW5 = TSKB-2L: room: LOGIC
TH1 TH5 TH8 TH10 TH12-TH14 = THERM_HOLE: room: HOLE
TP1-TP13 TP177-TP186 TPU1-TPU4 TPU6-TPU18 TPU20-TPU40 TPU73 TPU74 = TP: room: SOC
TP141-TP144 TP149 TP150 = TP: room: TOUCH_PAD
TP145-TP148 TP188 TP190-TP195 = TP: room: FP
TP151 TP154 = TP: room: KB_BL
TP176 = TP: room: SSD
TPE1 TPE2 TPE105 TPE106 = TP: room: EC
TPE6-TPE9 TPV1-TPV8 = TP: room: GPU
TPE101-TPE104 = TP: room: FAN
TPF1-TPF4 = TP: room: TPM
TPI3 TPI5-TPI9 = TP: room: HDMI
TPP10-TPP15 = TP: room: DEBUG
TPT1-TPT21 = TP: room: TYPEC
TPU72 = TP: room: EDP
TPW1-TPW3 = TP: room: WIFI
TPWC1 TPWC2 = TP: room: WIRELESS_CHARGER
UA2 = ALC880-LQFP48_6: room: CODEC
UB6 = TPS2546RTER_QFN16_4X4: room: USB3P1_AOU
UD1 UD2 = LPDDR4: room: LPDDR4-CHA
UD3 UD4 = LPDDR4: room: LPDDR4-CHB
UE1 = IT8512_4: room: EC
UE2 = W25X10CLSNIG: room: EC
UF15 = TPM SLB9655_1: room: TPM
UI1 = WS4603E-5-TR: room: HDMI
UI2 = PS8203_2: room: HDMI
UO1 = W25Q128JVSIQ: room: SPI
US1 = NCT7719W: room: THERMAL_SENSOR
US4 = G753TO1U: room: THERMAL_SENSOR
UT1 = RTS5400_QFN68_6: room: TYPEC
UT2 = BB_RETIMER_0: room: TYPEC
UT3 = W25Q80JVSSIQ: room: TYPEC
UT4 = WS4603E-5-TR: room: TYPEC
UT5 = NX5P3290_1: room: TYPEC
UT6 = NX20P5090UK_0: room: TYPEC
UT7 = TPD6S300RUKR: room: TYPEC
UU1 = ICL_U_IP_EXT_WW20: room: SOC
UU2 = 74AUP1G07GW: room: SOC
UV1 = MC74VHC1G08DFT2G_SC70-5: room: GPU
UV2 = U_GPU_GB2C_64: room: GPU
UV3 UV4 = H5GQ1H24AFR-T2L_BGA170_8: User Part Number: *; room: VRAM
UW1 = SY6288C20AAC: room: WIFI
UX1 UX2 = SY6288C20AAC: room: EDP
XT1 = CRYSTAL_4: room: TYPEC
YU1 = Q13FC1350000400: room: SOC
YU2 = X3S038400BA1H-HS: room: SOC
YV1 = CRYSTAL_4: room: GPU

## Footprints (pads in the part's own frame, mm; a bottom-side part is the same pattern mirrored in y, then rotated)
B0402_0D55
  rect 0.5x0.6 smd: 1(-0.45,0) 2(0.45,0)
B0603_0D95
  rect 0.76x0.9 smd: 1(-0.635,0) 2(0.635,0)
BGA4_0D9X0D9X0D405_0D5
  round 0.33 smd: A1(-0.25,0.25) A2(0.25,0.25) B1(-0.25,-0.25) B2(0.25,-0.25)
BGA170_15X12D5X1D2_0D8
  round 0.35 smd: A1(-5.2,6.4) A2(-4.4,6.4) A3(-3.6,6.4) A4(-2.8,6.4) A5(-2,6.4) A10(2,6.4) A11(2.8,6.4) A12(3.6,6.4) A13(4.4,6.4) A14(5.2,6.4) B1(-5.2,5.6) B2(-4.4,5.6) B3(-3.6,5.6) B4(-2.8,5.6) B5(-2,5.6) B10(2,5.6) B11(2.8,5.6) B12(3.6,5.6) B13(4.4,5.6) B14(5.2,5.6) C1(-5.2,4.8) C2(-4.4,4.8) C3(-3.6,4.8) C4(-2.8,4.8) C5(-2,4.8) C10(2,4.8) C11(2.8,4.8) C12(3.6,4.8) C13(4.4,4.8) C14(5.2,4.8) D1(-5.2,4) D2(-4.4,4) D3(-3.6,4) D4(-2.8,4) D5(-2,4) D10(2,4) D11(2.8,4) D12(3.6,4) D13(4.4,4) D14(5.2,4) E1(-5.2,3.2) E2(-4.4,3.2) E3(-3.6,3.2) E4(-2.8,3.2) E5(-2,3.2) E10(2,3.2) E11(2.8,3.2) E12(3.6,3.2) E13(4.4,3.2) E14(5.2,3.2) F1(-5.2,2.4) F2(-4.4,2.4) F3(-3.6,2.4) F4(-2.8,2.4) F5(-2,2.4) F10(2,2.4) F11(2.8,2.4) F12(3.6,2.4) F13(4.4,2.4) F14(5.2,2.4) G1(-5.2,1.6) G2(-4.4,1.6) G3(-3.6,1.6) G4(-2.8,1.6) G5(-2,1.6) G10(2,1.6) G11(2.8,1.6) G12(3.6,1.6) G13(4.4,1.6) G14(5.2,1.6) H1(-5.2,0.8) H2(-4.4,0.8) H3(-3.6,0.8) H4(-2.8,0.8) H5(-2,0.8) H10(2,0.8) H11(2.8,0.8) H12(3.6,0.8) H13(4.4,0.8) H14(5.2,0.8) J1(-5.2,0) J2(-4.4,0) J3(-3.6,0) J4(-2.8,0) J5(-2,0) J10(2,0) J11(2.8,0) J12(3.6,0) J13(4.4,0) J14(5.2,0) K1(-5.2,-0.8) K2(-4.4,-0.8) K3(-3.6,-0.8) K4(-2.8,-0.8) K5(-2,-0.8) K10(2,-0.8) K11(2.8,-0.8) K12(3.6,-0.8) K13(4.4,-0.8) K14(5.2,-0.8) L1(-5.2,-1.6) L2(-4.4,-1.6) L3(-3.6,-1.6) L4(-2.8,-1.6) L5(-2,-1.6) L10(2,-1.6) L11(2.8,-1.6) L12(3.6,-1.6) L13(4.4,-1.6) L14(5.2,-1.6) M1(-5.2,-2.4) M2(-4.4,-2.4) M3(-3.6,-2.4) M4(-2.8,-2.4) M5(-2,-2.4) M10(2,-2.4) M11(2.8,-2.4) M12(3.6,-2.4) M13(4.4,-2.4) M14(5.2,-2.4) N1(-5.2,-3.2) N2(-4.4,-3.2) N3(-3.6,-3.2) N4(-2.8,-3.2) N5(-2,-3.2) N10(2,-3.2) N11(2.8,-3.2) N12(3.6,-3.2) N13(4.4,-3.2) N14(5.2,-3.2) P1(-5.2,-4) P2(-4.4,-4) P3(-3.6,-4) P4(-2.8,-4) P5(-2,-4) P10(2,-4) P11(2.8,-4) P12(3.6,-4) P13(4.4,-4) P14(5.2,-4) R1(-5.2,-4.8) R2(-4.4,-4.8) R3(-3.6,-4.8) R4(-2.8,-4.8) R5(-2,-4.8) R10(2,-4.8) R11(2.8,-4.8) R12(3.6,-4.8) R13(4.4,-4.8) R14(5.2,-4.8) T1(-5.2,-5.6) T2(-4.4,-5.6) T3(-3.6,-5.6) T4(-2.8,-5.6) T5(-2,-5.6) T10(2,-5.6) T11(2.8,-5.6) T12(3.6,-5.6) T13(4.4,-5.6) T14(5.2,-5.6) U1(-5.2,-6.4) U2(-4.4,-6.4) U3(-3.6,-6.4) U4(-2.8,-6.4) U5(-2,-6.4) U10(2,-6.4) U11(2.8,-6.4) U12(3.6,-6.4) U13(4.4,-6.4) U14(5.2,-6.4)
BGA595_23X23X2D1_0D8
  round 0.38 smd: A2(-9.9,10.7) A3(-9.1,10.7) A4(-8.3,10.7) A6(-6.6,10.7) A7(-5.8,10.7) A9(-4.12,10.7) A10(-3.32,10.7) A12(-1.64,10.7) A13(-0.84,10.7) A15(0.84,10.7) A16(1.64,10.7) A18(3.32,10.7) A19(4.12,10.7) A21(5.8,10.7) A22(6.6,10.7) A24(8.3,10.7) A25(9.1,10.7) A26(9.9,10.7) AA1(-10.7,-5.8) AA2(-9.9,-5.8) AA3(-9.1,-5.8) AA4(-8.3,-5.8) AA5(-7.5,-5.8) AA6(-6.66,-5.8) AA7(-5.8,-5.8) AA8(-4.96,-5.8) AA9(-4.12,-5.86) AA10(-3.32,-5.86) AA12(-1.64,-5.86) AA13(-0.84,-5.86) AA14(0,-5.86) AA15(0.84,-5.86) AA16(1.64,-5.86) AA18(3.32,-5.86) AA19(4.12,-5.86) AA20(4.96,-5.8) AA21(5.8,-5.8) AA22(6.66,-5.8) AA23(7.5,-5.8) AA24(8.3,-5.8) AA25(9.1,-5.8) AA26(9.9,-5.8) AA27(10.7,-5.8) AB1(-10.7,-6.6) AB2(-9.9,-6.6) AB3(-9.1,-6.6) AB4(-8.3,-6.6) AB5(-7.5,-6.6) AB6(-6.6,-6.6) AB7(-5.8,-6.66) AB8(-4.96,-6.66) AB9(-4.12,-6.66) AB10(-3.32,-6.66) AB11(-2.48,-6.66) AB12(-1.64,-6.66) AB13(-0.84,-6.66) AB14(0,-6.66) AB15(0.84,-6.66) AB16(1.64,-6.66) AB17(2.48,-6.66) AB18(3.32,-6.66) AB19(4.12,-6.66) AB20(4.96,-6.66) AB21(5.8,-6.66) AB22(6.6,-6.6) AB23(7.5,-6.6) AB24(8.3,-6.6) AB25(9.1,-6.6) AB26(9.9,-6.6) AB27(10.7,-6.6) AC2(-9.9,-7.45) AC3(-9.1,-7.45) AC4(-8.3,-7.45) AC5(-7.45,-7.45) AC6(-6.6,-7.5) AC7(-5.8,-7.5) AC8(-4.96,-7.5) AC9(-4.12,-7.5) AC10(-3.32,-7.5) AC11(-2.48,-7.5) AC12(-1.64,-7.5) AC13(-0.84,-7.5) AC14(0,-7.5) AC15(0.84,-7.5) AC16(1.64,-7.5) AC17(2.48,-7.5) AC18(3.32,-7.5) AC19(4.12,-7.5) AC20(4.96,-7.5) AC21(5.8,-7.5) AC22(6.6,-7.5) AC23(7.45,-7.45) AC24(8.3,-7.45) AC25(9.1,-7.45) AC26(9.9,-7.45) AD1(-10.7,-8.3) AD2(-9.9,-8.3) AD3(-9.1,-8.3) AD4(-8.3,-8.3) AD5(-7.45,-8.3) AD6(-6.6,-8.3) AD7(-5.8,-8.3) AD8(-4.96,-8.3) AD9(-4.12,-8.3) AD10(-3.32,-8.3) AD11(-2.48,-8.3) AD12(-1.64,-8.3) AD13(-0.84,-8.3) AD14(0,-8.3) AD15(0.84,-8.3) AD16(1.64,-8.3) AD17(2.48,-8.3) AD18(3.32,-8.3) AD19(4.12,-8.3) AD20(4.96,-8.3) AD21(5.8,-8.3) AD22(6.6,-8.3) AD23(7.45,-8.3) AD24(8.3,-8.3) AD25(9.1,-8.3) AD26(9.9,-8.3) AD27(10.7,-8.3) AE1(-10.7,-9.1) AE2(-9.9,-9.1) AE3(-9.1,-9.1) AE4(-8.3,-9.1) AE5(-7.45,-9.1) AE6(-6.6,-9.1) AE7(-5.8,-9.1) AE8(-4.96,-9.1) AE9(-4.12,-9.1) AE10(-3.32,-9.1) AE11(-2.48,-9.1) AE12(-1.64,-9.1) AE13(-0.84,-9.1) AE14(0,-9.1) AE15(0.84,-9.1) AE16(1.64,-9.1) AE17(2.48,-9.1) AE18(3.32,-9.1) AE19(4.12,-9.1) AE20(4.96,-9.1) AE21(5.8,-9.1) AE22(6.6,-9.1) AE23(7.45,-9.1) AE24(8.3,-9.1) AE25(9.1,-9.1) AE26(9.9,-9.1) AE27(10.7,-9.1) AF1(-10.7,-9.9) AF2(-9.9,-9.9) AF3(-9.1,-9.9) AF4(-8.3,-9.9) AF5(-7.45,-9.9) AF6(-6.6,-9.9) AF7(-5.8,-9.9) AF8(-4.96,-9.9) AF9(-4.12,-9.9) AF10(-3.32,-9.9) AF11(-2.48,-9.9) AF12(-1.64,-9.9) AF13(-0.84,-9.9) AF14(0,-9.9) AF15(0.84,-9.9) AF16(1.64,-9.9) AF17(2.48,-9.9) AF18(3.32,-9.9) AF19(4.12,-9.9) AF20(4.96,-9.9) AF21(5.8,-9.9) AF22(6.6,-9.9) AF23(7.45,-9.9) AF24(8.3,-9.9) AF25(9.1,-9.9) AF26(9.9,-9.9) AF27(10.7,-9.9) AG2(-9.9,-10.7) AG3(-9.1,-10.7) AG4(-8.3,-10.7) AG6(-6.6,-10.7) AG7(-5.8,-10.7) AG9(-4.12,-10.7) AG10(-3.32,-10.7) AG12(-1.64,-10.7) AG13(-0.84,-10.7) AG15(0.84,-10.7) AG16(1.64,-10.7) AG18(3.32,-10.7) AG19(4.12,-10.7) AG21(5.8,-10.7) AG22(6.6,-10.7) AG24(8.3,-10.7) AG25(9.1,-10.7) AG26(9.9,-10.7) B1(-10.7,9.9) B2(-9.9,9.9) B3(-9.1,9.9) B4(-8.3,9.9) B5(-7.45,9.9) B6(-6.6,9.9) B7(-5.8,9.9) B8(-4.96,9.9) B9(-4.12,9.9) B10(-3.32,9.9) B11(-2.48,9.9) B12(-1.64,9.9) B13(-0.84,9.9) B14(0,9.9) B15(0.84,9.9) B16(1.64,9.9) B17(2.48,9.9) B18(3.32,9.9) B19(4.12,9.9) B20(4.96,9.9) B21(5.8,9.9) B22(6.6,9.9) B23(7.45,9.9) B24(8.3,9.9) B25(9.1,9.9) B26(9.9,9.9) B27(10.7,9.9) C1(-10.7,9.1) C2(-9.9,9.1) C3(-9.1,9.1) C4(-8.3,9.1) C5(-7.45,9.1) C6(-6.6,9.1) C7(-5.8,9.1) C8(-4.96,9.1) C9(-4.12,9.1) C10(-3.32,9.1) C11(-2.48,9.1) C12(-1.64,9.1) C13(-0.84,9.1) C14(0,9.1) C15(0.84,9.1) C16(1.64,9.1) C17(2.48,9.1) C18(3.32,9.1) C19(4.12,9.1) C20(4.96,9.1) C21(5.8,9.1) C22(6.6,9.1) C23(7.45,9.1) C24(8.3,9.1) C25(9.1,9.1) C26(9.9,9.1) C27(10.7,9.1) D1(-10.7,8.3) D2(-9.9,8.3) D3(-9.1,8.3) D4(-8.3,8.3) D5(-7.45,8.3) D6(-6.6,8.3) D7(-5.8,8.3) D8(-4.96,8.3) D9(-4.12,8.3) D10(-3.32,8.3) D11(-2.48,8.3) D12(-1.64,8.3) D13(-0.84,8.3) D14(0,8.3) D15(0.84,8.3) D16(1.64,8.3) D17(2.48,8.3) D18(3.32,8.3) D19(4.12,8.3) D20(4.96,8.3) D21(5.8,8.3) D22(6.6,8.3) D23(7.45,8.3) D24(8.3,8.3) D25(9.1,8.3) D26(9.9,8.3) D27(10.7,8.3) E2(-9.9,7.45) E3(-9.1,7.45) E4(-8.3,7.45) E5(-7.45,7.45) E6(-6.6,7.5) E7(-5.8,7.5) E8(-4.96,7.5) E9(-4.12,7.5) E10(-3.32,7.5) E11(-2.48,7.5) E12(-1.64,7.5) E13(-0.84,7.5) E14(0,7.5) E15(0.84,7.5) E16(1.64,7.5) E17(2.48,7.5) E18(3.32,7.5) E19(4.12,7.5) E20(4.96,7.5) E21(5.8,7.5) E22(6.6,7.5) E23(7.45,7.45) E24(8.3,7.45) E25(9.1,7.45) E26(9.9,7.45) F1(-10.7,6.6) F2(-9.9,6.6) F3(-9.1,6.6) F4(-8.3,6.6) F5(-7.5,6.6) F6(-6.6,6.6) F7(-5.8,6.66) F8(-4.96,6.66) F9(-4.12,6.66) F10(-3.32,6.66) F11(-2.48,6.66) F12(-1.64,6.66) F13(-0.84,6.66) F14(0,6.66) F15(0.84,6.66) F16(1.64,6.66) F17(2.48,6.66) F18(3.32,6.66) F19(4.12,6.66) F20(4.96,6.66) F21(5.8,6.66) F22(6.6,6.6) F23(7.5,6.6) F24(8.3,6.6) F25(9.1,6.6) F26(9.9,6.6) F27(10.7,6.6) G1(-10.7,5.8) G2(-9.9,5.8) G3(-9.1,5.8) G4(-8.3,5.8) G5(-7.5,5.8) G6(-6.66,5.8) G7(-5.8,5.8) G8(-4.96,5.8) G9(-4.12,5.86) G10(-3.32,5.86) G12(-1.64,5.86) G13(-0.84,5.86) G14(0,5.86) G15(0.84,5.86) G16(1.64,5.86) G18(3.32,5.86) G19(4.12,5.86) G20(4.96,5.8) G21(5.8,5.8) G22(6.66,5.8) G23(7.5,5.8) G24(8.3,5.8) G25(9.1,5.8) G26(9.9,5.8) G27(10.7,5.8) H2(-9.9,4.96) H3(-9.1,4.96) H4(-8.3,4.96) H5(-7.5,4.96) H6(-6.66,4.96) H22(6.66,4.96) H23(7.5,4.96) H24(8.3,4.96) H25(9.1,4.96) H26(9.9,4.96) J1(-10.7,4.12) J2(-9.9,4.12) J3(-9.1,4.12) J4(-8.3,4.12) J5(-7.5,4.12) J6(-6.66,4.12) J7(-5.86,4.12) J21(5.86,4.12) J22(6.66,4.12) J23(7.5,4.12) J24(8.3,4.12) J25(9.1,4.12) J26(9.9,4.12) J27(10.7,4.12) K1(-10.7,3.32) K2(-9.9,3.32) K3(-9.1,3.32) K4(-8.3,3.32) K5(-7.5,3.32) K6(-6.66,3.32) K7(-5.86,3.32) K21(5.86,3.32) K22(6.66,3.32) K23(7.5,3.32) K24(8.3,3.32) K25(9.1,3.32) K26(9.9,3.32) K27(10.7,3.32) L2(-9.9,2.48) L3(-9.1,2.48) L4(-8.3,2.48) L5(-7.5,2.48) L6(-6.66,2.48) L22(6.66,2.48) L23(7.5,2.48) L24(8.3,2.48) L25(9.1,2.48) L26(9.9,2.48) M1(-10.7,1.64) M2(-9.9,1.64) M3(-9.1,1.64) M4(-8.3,1.64) M5(-7.5,1.64) M6(-6.66,1.64) M7(-5.86,1.64) M21(5.86,1.64) M22(6.66,1.64) M23(7.5,1.64) M24(8.3,1.64) M25(9.1,1.64) M26(9.9,1.64) M27(10.7,1.64) N1(-10.7,0.84) N2(-9.9,0.84) N3(-9.1,0.84) N4(-8.3,0.84) N5(-7.5,0.84) N6(-6.66,0.84) N7(-5.86,0.84) N21(5.86,0.84) N22(6.66,0.84) N23(7.5,0.84) N24(8.3,0.84) N25(9.1,0.84) N26(9.9,0.84) N27(10.7,0.84) P2(-9.9,0) P3(-9.1,0) P4(-8.3,0) P5(-7.5,0) P6(-6.66,0) P22(6.66,0) P23(7.5,0) P24(8.3,0) P25(9.1,0) P26(9.9,0) R1(-10.7,-0.84) R2(-9.9,-0.84) R3(-9.1,-0.84) R4(-8.3,-0.84) R5(-7.5,-0.84) R6(-6.66,-0.84) R7(-5.86,-0.84) R21(5.86,-0.84) R22(6.66,-0.84) R23(7.5,-0.84) R24(8.3,-0.84) R25(9.1,-0.84) R26(9.9,-0.84) R27(10.7,-0.84) T1(-10.7,-1.64) T2(-9.9,-1.64) T3(-9.1,-1.64) T4(-8.3,-1.64) T5(-7.5,-1.64) T6(-6.66,-1.64) T7(-5.86,-1.64) T21(5.86,-1.64) T22(6.66,-1.64) T23(7.5,-1.64) T24(8.3,-1.64) T25(9.1,-1.64) T26(9.9,-1.64) T27(10.7,-1.64) U2(-9.9,-2.48) U3(-9.1,-2.48) U4(-8.3,-2.48) U5(-7.5,-2.48) U6(-6.66,-2.48) U22(6.66,-2.48) U23(7.5,-2.48) U24(8.3,-2.48) U25(9.1,-2.48) U26(9.9,-2.48) V1(-10.7,-3.32) V2(-9.9,-3.32) V3(-9.1,-3.32) V4(-8.3,-3.32) V5(-7.5,-3.32) V6(-6.66,-3.32) V7(-5.86,-3.32) V21(5.86,-3.32) V22(6.66,-3.32) V23(7.5,-3.32) V24(8.3,-3.32) V25(9.1,-3.32) V26(9.9,-3.32) V27(10.7,-3.32) W1(-10.7,-4.12) W2(-9.9,-4.12) W3(-9.1,-4.12) W4(-8.3,-4.12) W5(-7.5,-4.12) W6(-6.66,-4.12) W7(-5.86,-4.12) W21(5.86,-4.12) W22(6.66,-4.12) W23(7.5,-4.12) W24(8.3,-4.12) W25(9.1,-4.12) W26(9.9,-4.12) W27(10.7,-4.12) Y2(-9.9,-4.96) Y3(-9.1,-4.96) Y4(-8.3,-4.96) Y5(-7.5,-4.96) Y6(-6.66,-4.96) Y22(6.66,-4.96) Y23(7.5,-4.96) Y24(8.3,-4.96) Y25(9.1,-4.96) Y26(9.9,-4.96)
  round 0.4 smd: K10(-4,4) K11(-3,4) K12(-2,4) K13(-1,4) K14(0,4) K15(1,4) K16(2,4) K17(3,4) K18(4,4) L10(-4,3) L11(-3,3) L12(-2,3) L13(-1,3) L14(0,3) L15(1,3) L16(2,3) L17(3,3) L18(4,3) M10(-4,2) M11(-3,2) M12(-2,2) M13(-1,2) M14(0,2) M15(1,2) M16(2,2) M17(3,2) M18(4,2) N10(-4,1) N11(-3,1) N12(-2,1) N13(-1,1) N14(0,1) N15(1,1) N16(2,1) N17(3,1) N18(4,1) P10(-4,0) P11(-3,0) P12(-2,0) P13(-1,0) P14(0,0) P15(1,0) P16(2,0) P17(3,0) P18(4,0) R10(-4,-1) R11(-3,-1) R12(-2,-1) R13(-1,-1) R14(0,-1) R15(1,-1) R16(2,-1) R17(3,-1) R18(4,-1) T10(-4,-2) T11(-3,-2) T12(-2,-2) T13(-1,-2) T14(0,-2) T15(1,-2) T16(2,-2) T17(3,-2) T18(4,-2) U10(-4,-3) U11(-3,-3) U12(-2,-3) U13(-1,-3) U14(0,-3) U15(1,-3) U16(2,-3) U17(3,-3) U18(4,-3) V10(-4,-4) V11(-3,-4) V12(-2,-4) V13(-1,-4) V14(0,-4) V15(1,-4) V16(2,-4) V17(3,-4) V18(4,-4)
C0201
  rect 0.305x0.305 smd: 1(-0.254,0) 2(0.254,0)
C0201_0D4
  rect 0.305x0.305 smd: 1(-0.254,0) 2(0.254,0)
C0402
  rect 0.5x0.55 smd: 1(-0.394,0) 2(0.394,0)
C0402_0D6
  rect 0.5x0.55 smd: 1(-0.394,0) 2(0.394,0)
C0402_0D8
  rect 0.575x0.615 smd: 1(-0.437,0) 2(0.437,0)
C0402_0D55
  rect 0.5x0.55 smd: 1(-0.394,0) 2(0.394,0)
C0402_0D65
  rect 0.575x0.615 smd: 1(-0.437,0) 2(0.437,0)
C0603
  rect 0.58x0.89 smd: 1(-0.66,0) 2(0.66,0)
C0603_L
  rect 0.68x0.99 smd: 1(-0.66,0) 2(0.66,0)
CMP_40
  round 1 smd: 1(0,0)
DFN1006_3_1X0D6X0D5
  rect 0.25x0.42 smd: 1(-0.2,-0.34) 2(0.2,-0.34)
  rect 0.7x0.42 smd: 3(0,0.34)
DFN1006_3_1X0D6X0D5_ESD5324N
  rect 0.25x0.45 smd: 1(0.225,-0.34) 2(-0.225,-0.34)
  rect 0.7x0.45 smd: 3(0,0.34)
DIODE_2D75X1D8X1D1
  rect 1.2x1.2 smd: 1(-1.6,0) 2(1.6,0)
EMI_0D85X0D65X0D5
  rect 0.305x0.305 smd: 1(-0.305,0.254) 2(0.305,0.254) 3(0.305,-0.254) 4(-0.305,-0.254)
HOLE_2D8_6_P
  round 6 hole 2.8: 1(0,0)
HOLE_3D5_5_T
  round 5 hole 3.5: 1(0,0)
HOLE_3D5_6_P
  round 6 hole 3.5: 1(0,0)
ICTPAD_C20
  round 0.508 smd: 1(0,0)
L0402
  rect 0.5x0.55 smd: 1(-0.394,0) 2(0.394,0)
L2016_1
  rect 0.6x1.6 smd: 1(-0.7,0) 2(0.7,0)
L2520_1D05
  rect 0.85x2.1 smd: 1(-0.825,0) 2(0.825,0)
NB_B0805_1D05
  rect 0.914x1.422 smd: 1(-1.016,0) 2(1.016,0)
NB_BAT8_21X6D4X2D26_2
  rect 0.6x1.3 smd: 1(-7,2.712) 2(-5,2.712) 3(-3,2.712) 4(-1,2.712) 5(1,2.712) 6(3,2.712) 7(5,2.712) 8(7,2.712)
  rect 1.3x2.1 smd: 9(10.1,-2.288) 10(-10.1,-2.288)
NB_BGA15_2D56X1D54X0D6_0D5
  round 0.25 smd: A1(-0.5,-1) A2(0,-1) A3(0.5,-1) B1(-0.5,-0.5) B2(0,-0.5) B3(0.5,-0.5) C1(-0.5,0) C2(0,0) C3(0.5,0) D1(-0.5,0.5) D2(0,0.5) D3(0.5,0.5) E1(-0.5,1) E2(0,1) E3(0.5,1)
NB_BGA16_2D05X2D05X0D6_0D5
  round 0.25 smd: A1(-0.75,0.75) A2(-0.25,0.75) A3(0.25,0.75) A4(0.75,0.75) B1(-0.75,0.25) B2(-0.25,0.25) B3(0.25,0.25) B4(0.75,0.25) C1(-0.75,-0.25) C2(-0.25,-0.25) C3(0.25,-0.25) C4(0.75,-0.25) D1(-0.75,-0.75) D2(-0.25,-0.75) D3(0.25,-0.75) D4(0.75,-0.75)
NB_BGA105_6X6X0D826
  oval 0.325x0.175 smd: A1(-2.53,2.53) A12(2.53,2.53) B1(-2.53,2.07) B12(2.53,2.07) C1(-2.53,1.61) C12(2.53,1.61) D1(-2.53,1.15) D12(2.53,1.15) E1(-2.53,0.69) E12(2.53,0.69) F1(-2.53,0.23) F12(2.53,0.23) G1(-2.53,-0.23) G12(2.53,-0.23) H1(-2.53,-0.69) H12(2.53,-0.69) J1(-2.53,-1.15) J12(2.53,-1.15) K1(-2.53,-1.61) K12(2.53,-1.61) L1(-2.53,-2.07) L12(2.53,-2.07) M1(-2.53,-2.53) M12(2.53,-2.53)
  oval 0.175x0.325 smd: A2(-2.07,2.53) A3(-1.61,2.53) A4(-1.15,2.53) A5(-0.69,2.53) A6(-0.23,2.53) A7(0.23,2.53) A8(0.69,2.53) A9(1.15,2.53) A10(1.61,2.53) A11(2.07,2.53) M2(-2.07,-2.53) M3(-1.61,-2.53) M4(-1.15,-2.53) M5(-0.69,-2.53) M6(-0.23,-2.53) M7(0.23,-2.53) M8(0.69,-2.53) M9(1.15,-2.53) M10(1.61,-2.53) M11(2.07,-2.53)
  round 0.225 smd: B2(-2.07,2.07) B3(-1.61,2.07) B4(-1.15,2.07) B5(-0.69,2.07) B6(-0.23,2.07) B7(0.23,2.07) B8(0.69,2.07) B9(1.15,2.07) B10(1.61,2.07) B11(2.07,2.07) C2(-2.07,1.61) C3(-1.3,1.3) C5(-0.65,1.3) C6(0,1.3) C7(0.65,1.3) C9(1.3,1.3) C11(2.07,1.61) D2(-2.07,1.15) D11(2.07,1.15) E2(-2.07,0.69) E3(-1.3,0.65) E5(-0.65,0.65) E6(0,0.65) E7(0.65,0.65) E9(1.3,0.65) E11(2.07,0.69) F2(-2.07,0.23) F3(-1.3,0) F5(-0.65,0) F6(0,0) F7(0.65,0) F9(1.3,0) F11(2.07,0.23) G2(-2.07,-0.23) G3(-1.3,-0.65) G5(-0.65,-0.65) G6(0,-0.65) G7(0.65,-0.65) G9(1.3,-0.65) G11(2.07,-0.23) H2(-2.07,-0.69) H11(2.07,-0.69) J2(-2.07,-1.15) J3(-1.3,-1.3) J5(-0.65,-1.3) J6(0,-1.3) J7(0.65,-1.3) J9(1.3,-1.3) J11(2.07,-1.15) K2(-2.07,-1.61) K11(2.07,-1.61) L2(-2.07,-2.07) L3(-1.61,-2.07) L4(-1.15,-2.07) L5(-0.69,-2.07) L6(-0.23,-2.07) L7(0.23,-2.07) L8(0.69,-2.07) L9(1.15,-2.07) L10(1.61,-2.07) L11(2.07,-2.07)
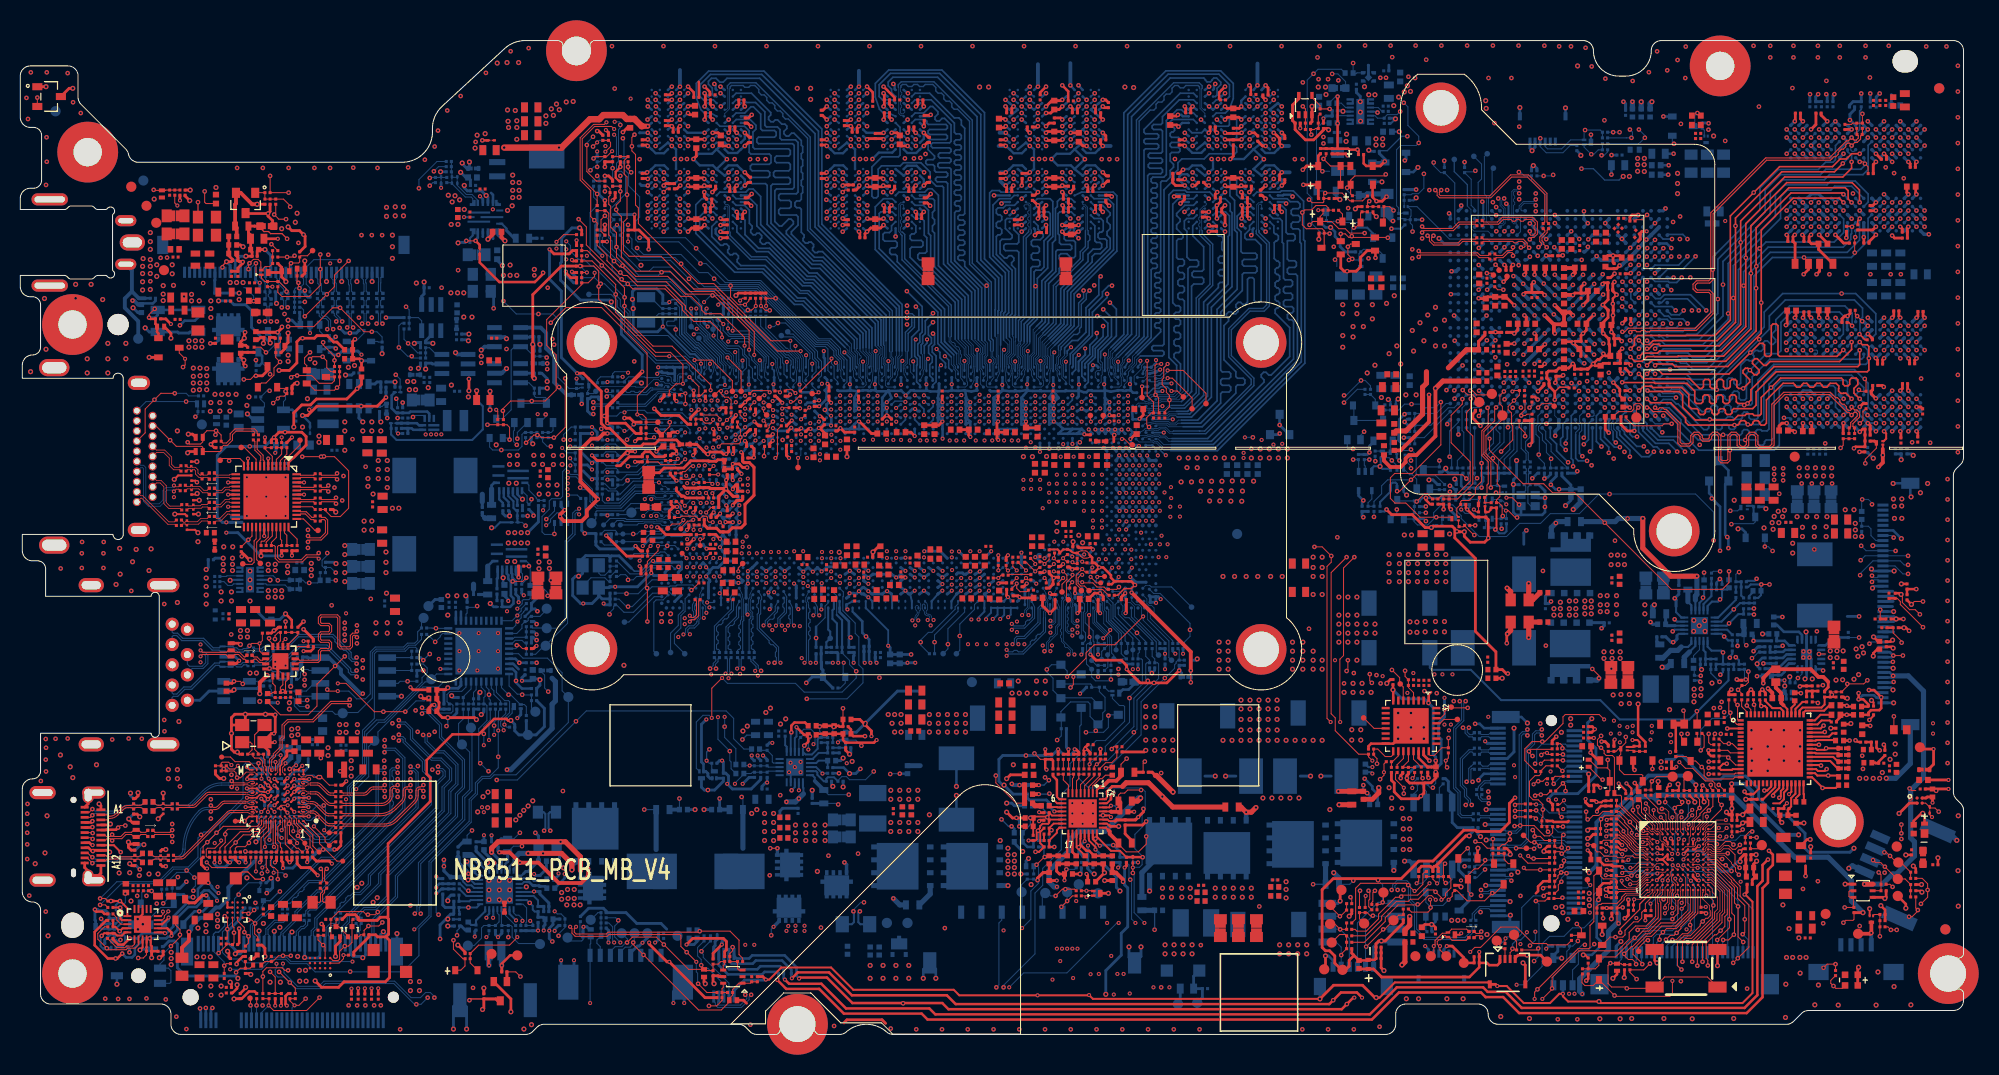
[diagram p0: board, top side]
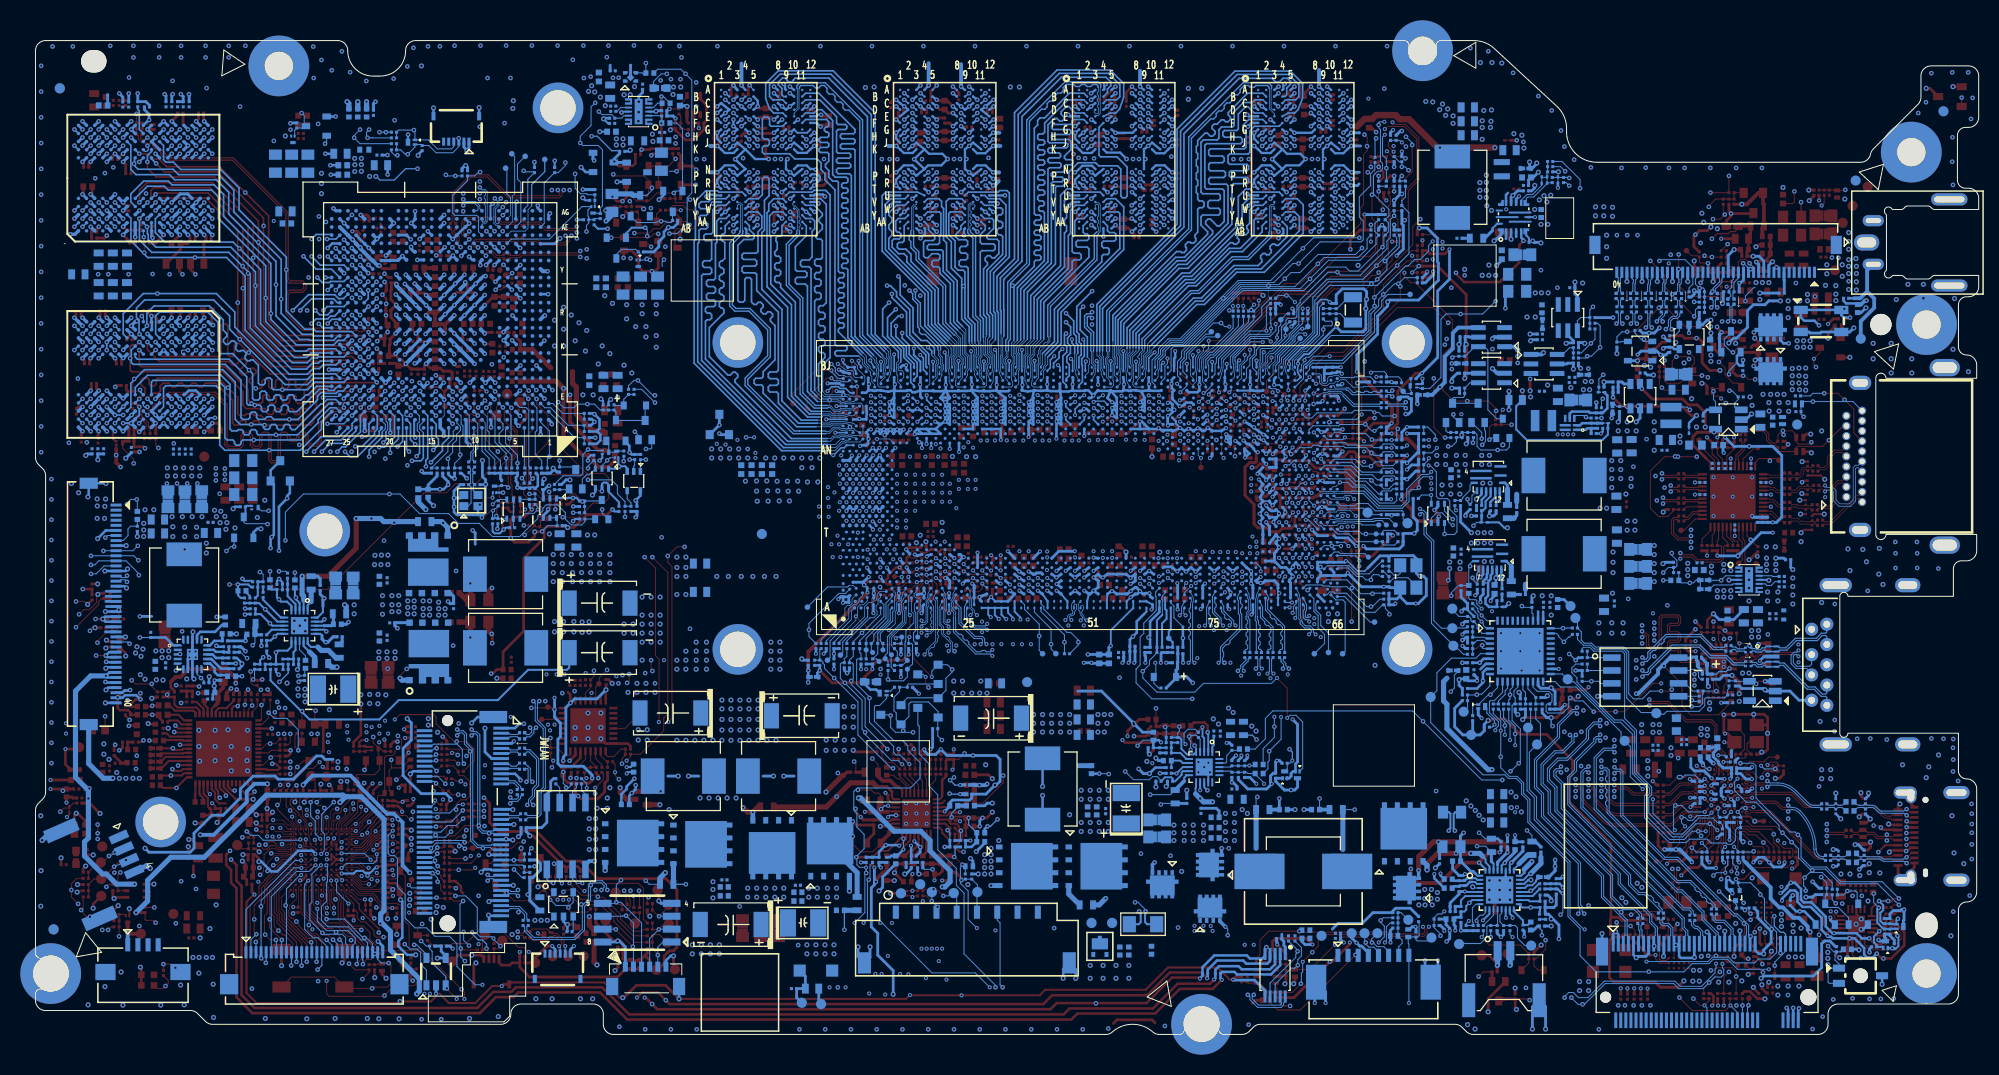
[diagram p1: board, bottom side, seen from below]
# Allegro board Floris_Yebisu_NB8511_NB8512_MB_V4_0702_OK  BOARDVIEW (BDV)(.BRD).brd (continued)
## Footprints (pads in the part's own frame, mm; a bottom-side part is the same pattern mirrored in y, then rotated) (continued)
NB_BGA128_7X7X0D95_0D5
  round 0.25 smd: A1(-3,3) A2(-2.5,3) A3(-2,3) A4(-1.5,3) A5(-1,3) A6(-0.5,3) A7(0,3) A8(0.5,3) A9(1,3) A10(1.5,3) A11(2,3) A12(2.5,3) A13(3,3) B1(-3,2.5) B2(-2.5,2.5) B3(-2,2.5) B4(-1.5,2.5) B5(-1,2.5) B6(-0.5,2.5) B7(0,2.5) B8(0.5,2.5) B9(1,2.5) B10(1.5,2.5) B11(2,2.5) B12(2.5,2.5) B13(3,2.5) C1(-3,2) C2(-2.5,2) C12(2.5,2) C13(3,2) D1(-3,1.5) D2(-2.5,1.5) D4(-1.5,1.5) D5(-1,1.5) D6(-0.5,1.5) D7(0,1.5) D8(0.5,1.5) D9(1,1.5) D10(1.5,1.5) D12(2.5,1.5) D13(3,1.5) E1(-3,1) E2(-2.5,1) E4(-1.5,1) E5(-1,1) E6(-0.5,1) E7(0,1) E8(0.5,1) E9(1,1) E10(1.5,1) E12(2.5,1) E13(3,1) F1(-3,0.5) F2(-2.5,0.5) F4(-1.5,0.5) F5(-1,0.5) F9(1,0.5) F10(1.5,0.5) F12(2.5,0.5) F13(3,0.5) G1(-3,0) G2(-2.5,0) G4(-1.5,0) G5(-1,0) G9(1,0) G10(1.5,0) G12(2.5,0) G13(3,0) H1(-3,-0.5) H2(-2.5,-0.5) H4(-1.5,-0.5) H5(-1,-0.5) H9(1,-0.5) H10(1.5,-0.5) H12(2.5,-0.5) H13(3,-0.5) J1(-3,-1) J2(-2.5,-1) J4(-1.5,-1) J5(-1,-1) J6(-0.5,-1) J7(0,-1) J8(0.5,-1) J9(1,-1) J10(1.5,-1) J12(2.5,-1) J13(3,-1) K1(-3,-1.5) K2(-2.5,-1.5) K4(-1.5,-1.5) K5(-1,-1.5) K6(-0.5,-1.5) K7(0,-1.5) K8(0.5,-1.5) K9(1,-1.5) K10(1.5,-1.5) K12(2.5,-1.5) K13(3,-1.5) L1(-3,-2) L2(-2.5,-2) L12(2.5,-2) L13(3,-2) M1(-3,-2.5) M2(-2.5,-2.5) M3(-2,-2.5) M4(-1.5,-2.5) M5(-1,-2.5) M6(-0.5,-2.5) M7(0,-2.5) M8(0.5,-2.5) M9(1,-2.5) M10(1.5,-2.5) M11(2,-2.5) M12(2.5,-2.5) M13(3,-2.5) N1(-3,-3) N2(-2.5,-3) N3(-2,-3) N4(-1.5,-3) N5(-1,-3) N6(-0.5,-3) N7(0,-3) N8(0.5,-3) N9(1,-3) N10(1.5,-3) N11(2,-3) N12(2.5,-3) N13(3,-3)
NB_BGA200_15X10X1D2_0D65
  round 0.25 smd: A1(-4.4,6.825) A2(-3.6,6.825) A3(-2.8,6.825) A4(-2,6.825) A5(-1.2,6.825) A8(1.2,6.825) A9(2,6.825) A10(2.8,6.825) A11(3.6,6.825) A12(4.4,6.825) AA1(-4.4,-6.175) AA2(-3.6,-6.175) AA3(-2.8,-6.175) AA4(-2,-6.175) AA5(-1.2,-6.175) AA8(1.2,-6.175) AA9(2,-6.175) AA10(2.8,-6.175) AA11(3.6,-6.175) AA12(4.4,-6.175) AB1(-4.4,-6.825) AB2(-3.6,-6.825) AB3(-2.8,-6.825) AB4(-2,-6.825) AB5(-1.2,-6.825) AB8(1.2,-6.825) AB9(2,-6.825) AB10(2.8,-6.825) AB11(3.6,-6.825) AB12(4.4,-6.825) B1(-4.4,6.175) B2(-3.6,6.175) B3(-2.8,6.175) B4(-2,6.175) B5(-1.2,6.175) B8(1.2,6.175) B9(2,6.175) B10(2.8,6.175) B11(3.6,6.175) B12(4.4,6.175) C1(-4.4,5.525) C2(-3.6,5.525) C3(-2.8,5.525) C4(-2,5.525) C5(-1.2,5.525) C8(1.2,5.525) C9(2,5.525) C10(2.8,5.525) C11(3.6,5.525) C12(4.4,5.525) D1(-4.4,4.875) D2(-3.6,4.875) D3(-2.8,4.875) D4(-2,4.875) D5(-1.2,4.875) D8(1.2,4.875) D9(2,4.875) D10(2.8,4.875) D11(3.6,4.875) D12(4.4,4.875) E1(-4.4,4.225) E2(-3.6,4.225) E3(-2.8,4.225) E4(-2,4.225) E5(-1.2,4.225) E8(1.2,4.225) E9(2,4.225) E10(2.8,4.225) E11(3.6,4.225) E12(4.4,4.225) F1(-4.4,3.575) F2(-3.6,3.575) F3(-2.8,3.575) F4(-2,3.575) F5(-1.2,3.575) F8(1.2,3.575) F9(2,3.575) F10(2.8,3.575) F11(3.6,3.575) F12(4.4,3.575) G1(-4.4,2.925) G2(-3.6,2.925) G3(-2.8,2.925) G4(-2,2.925) G5(-1.2,2.925) G8(1.2,2.925) G9(2,2.925) G10(2.8,2.925) G11(3.6,2.925) G12(4.4,2.925) H1(-4.4,2.275) H2(-3.6,2.275) H3(-2.8,2.275) H4(-2,2.275) H5(-1.2,2.275) H8(1.2,2.275) H9(2,2.275) H10(2.8,2.275) H11(3.6,2.275) H12(4.4,2.275) J1(-4.4,1.625) J2(-3.6,1.625) J3(-2.8,1.625) J4(-2,1.625) J5(-1.2,1.625) J8(1.2,1.625) J9(2,1.625) J10(2.8,1.625) J11(3.6,1.625) J12(4.4,1.625) K1(-4.4,0.975) K2(-3.6,0.975) K3(-2.8,0.975) K4(-2,0.975) K5(-1.2,0.975) K8(1.2,0.975) K9(2,0.975) K10(2.8,0.975) K11(3.6,0.975) K12(4.4,0.975) N1(-4.4,-0.975) N2(-3.6,-0.975) N3(-2.8,-0.975) N4(-2,-0.975) N5(-1.2,-0.975) N8(1.2,-0.975) N9(2,-0.975) N10(2.8,-0.975) N11(3.6,-0.975) N12(4.4,-0.975) P1(-4.4,-1.625) P2(-3.6,-1.625) P3(-2.8,-1.625) P4(-2,-1.625) P5(-1.2,-1.625) P8(1.2,-1.625) P9(2,-1.625) P10(2.8,-1.625) P11(3.6,-1.625) P12(4.4,-1.625) R1(-4.4,-2.275) R2(-3.6,-2.275) R3(-2.8,-2.275) R4(-2,-2.275) R5(-1.2,-2.275) R8(1.2,-2.275) R9(2,-2.275) R10(2.8,-2.275) R11(3.6,-2.275) R12(4.4,-2.275) T1(-4.4,-2.925) T2(-3.6,-2.925) T3(-2.8,-2.925) T4(-2,-2.925) T5(-1.2,-2.925) T8(1.2,-2.925) T9(2,-2.925) T10(2.8,-2.925) T11(3.6,-2.925) T12(4.4,-2.925) U1(-4.4,-3.575) U2(-3.6,-3.575) U3(-2.8,-3.575) U4(-2,-3.575) U5(-1.2,-3.575) U8(1.2,-3.575) U9(2,-3.575) U10(2.8,-3.575) U11(3.6,-3.575) U12(4.4,-3.575) V1(-4.4,-4.225) V2(-3.6,-4.225) V3(-2.8,-4.225) V4(-2,-4.225) V5(-1.2,-4.225) V8(1.2,-4.225) V9(2,-4.225) V10(2.8,-4.225) V11(3.6,-4.225) V12(4.4,-4.225) W1(-4.4,-4.875) W2(-3.6,-4.875) W3(-2.8,-4.875) W4(-2,-4.875) W5(-1.2,-4.875) W8(1.2,-4.875) W9(2,-4.875) W10(2.8,-4.875) W11(3.6,-4.875) W12(4.4,-4.875) Y1(-4.4,-5.525) Y2(-3.6,-5.525) Y3(-2.8,-5.525) Y4(-2,-5.525) Y5(-1.2,-5.525) Y8(1.2,-5.525) Y9(2,-5.525) Y10(2.8,-5.525) Y11(3.6,-5.525) Y12(4.4,-5.525)
NB_BGA1526_50X25X1D26_ICL_U42
  round 0.356 smd: A3(-24.365,-10.767) A48(-24.365,11.405) A49(-23.905,11.865) B2(-23.816,-11.309) C1(-23.255,-11.865) DW1(23.905,-11.865) DW2(24.365,-11.405) DW48(24.365,11.405) DW49(23.905,11.865)
  round 0.33 smd: A4(-24.365,-10.117) A47(-24.365,10.755) B3(-23.723,-10.666) B48(-23.737,11.237) C2(-23.172,-11.22) C49(-23.255,11.865) D1(-22.605,-11.865) DE12(17.032,-6.31) DE13(17.032,-5.48) DE15(17.032,-4.65) DE17(17.032,-3.82) DE18(17.032,-2.99) DE20(17.032,-2.16) DE22(17.032,-1.33) DE23(17.032,-0.5) DE26(17.032,0.33) DE28(17.032,1.16) DE29(17.032,1.99) DE31(17.032,2.82) DE33(17.032,3.65) DF12(17.682,-6.31) DF13(17.682,-5.48) DF15(17.682,-4.65) DF17(17.682,-3.82) DF18(17.682,-2.99) DF20(17.682,-2.16) DF22(17.682,-1.33) DF23(17.682,-0.5) DF26(17.682,0.33) DF28(17.682,1.16) DF29(17.682,1.99) DF31(17.682,2.82) DF33(17.682,3.65) DG12(18.332,-6.31) DG13(18.332,-5.48) DG15(18.332,-4.65) DG17(18.332,-3.82) DG18(18.332,-2.99) DG20(18.332,-2.16) DG22(18.332,-1.33) DG23(18.332,-0.5) DG26(18.332,0.33) DG28(18.332,1.16) DG29(18.332,1.99) DG31(18.332,2.82) DG33(18.332,3.65) DU1(23.255,-11.865) DU49(23.255,11.865) DV2(23.737,-11.237) DV48(23.737,11.237) DW3(24.365,-10.755) DW47(24.365,10.755)
  round 0.305 smd: A5(-24.365,-9.467) A7(-24.365,-8.658) A33(-24.365,3.593) A43(-24.365,8.707) A44(-24.365,9.455) A46(-24.365,10.105) AA12(-14.312,-6.127) AA35(-14.311,4.855) AA37(-14.311,5.778) AA45(-14.246,9.59) AA47(-14.246,10.861) AB3(-13.923,-10.893) AB5(-13.923,-9.905) AB6(-13.855,-9.189) AB7(-13.855,-8.539) AB9(-13.855,-7.889) AB10(-13.855,-7.239) AB11(-13.855,-6.589) AB13(-13.855,-5.665) AB34(-13.853,4.393) AB36(-13.853,5.316) AB38(-13.853,6.24) AB39(-13.853,6.89) AB41(-13.853,7.54) AB42(-13.853,8.19) AB43(-13.853,8.84) AB45(-13.626,9.915) AB47(-13.626,10.565) AC3(-13.249,-10.565) AC5(-13.249,-9.915) AC12(-13.397,-6.127) AC35(-13.396,4.855) AC37(-13.396,5.778) AC45(-12.995,9.59) AC46(-12.995,10.241) AD3(-12.686,-10.89) AD4(-12.686,-10.24) AD6(-12.94,-9.189) AD7(-12.94,-8.539) AD9(-12.94,-7.889) AD10(-12.94,-7.239) AD11(-12.94,-6.589) AD34(-12.938,4.393) AD35(-12.481,4.855) AD36(-12.938,5.316) AD37(-12.481,5.778) AD38(-12.938,6.24) AD39(-12.938,6.89) AD41(-12.938,7.54) AD42(-12.938,8.19) AD43(-12.938,8.84) AE3(-12.123,-10.565) AE5(-12.123,-9.915) AE6(-12.025,-9.189) AE7(-12.025,-8.539) AE9(-12.025,-7.889) AE11(-12.025,-6.965) AE36(-12.023,5.316) AE38(-12.023,6.24) AE39(-12.023,6.89) AE41(-12.023,7.54) AE42(-12.023,8.19) AE43(-12.023,8.84) AE45(-12.364,9.915) AE47(-12.364,10.565) AF10(-11.567,-7.427) AF37(-11.566,5.778) AF45(-11.744,9.59) AF47(-11.744,10.861) AG3(-11.449,-10.893) AG5(-11.449,-9.905) AG6(-11.11,-9.189) AG7(-11.11,-8.539) AG9(-11.11,-7.889) AG11(-11.11,-6.965) AG36(-11.108,5.316) AG38(-11.108,6.24) AG39(-11.108,6.89) AG41(-11.108,7.54) AG42(-11.108,8.19) AG43(-11.108,8.84) AG45(-11.124,9.915) AG47(-11.124,10.565) AH10(-10.652,-7.427) AH37(-10.651,5.778) AH45(-10.493,9.59) AH46(-10.493,10.241) AJ3(-10.195,-10.489) AJ5(-10.195,-9.839) AJ6(-10.195,-9.189) AJ7(-10.195,-8.539) AJ9(-10.195,-7.889) AJ11(-10.195,-6.965) AJ36(-10.193,5.316) AJ38(-10.193,6.24) AJ39(-10.193,6.89) AJ41(-10.193,7.54) AJ42(-10.193,8.19) AJ43(-10.193,8.84) AK10(-9.737,-7.427) AK37(-9.736,5.778) AK45(-9.862,9.915) AK47(-9.862,10.565) AL3(-9.28,-10.489) AL5(-9.28,-9.839) AL6(-9.28,-9.189) AL7(-9.28,-8.539) AL9(-9.28,-7.889) AL11(-9.28,-6.965) AL36(-9.278,5.316) AL38(-9.278,6.24) AL39(-9.278,6.89) AL41(-9.278,7.54) AL42(-9.278,8.19) AL43(-9.278,8.84) AL45(-9.242,9.59) AL47(-9.242,10.861) AM10(-8.822,-7.427) AM37(-8.821,5.778) AM45(-8.622,9.915) AM47(-8.622,10.565) AN3(-8.365,-10.489) AN5(-8.365,-9.839) AN6(-8.365,-9.189) AN7(-8.365,-8.539) AN9(-8.365,-7.889) AN11(-8.365,-6.965) AN36(-8.363,5.316) AN38(-8.363,6.24) AN39(-8.363,6.89) AN41(-8.363,7.54) AN42(-8.363,8.19) AN43(-8.363,8.84) AN45(-7.991,9.59) AN46(-7.991,10.241) AP10(-7.907,-7.427) AP37(-7.906,5.778) AR3(-7.45,-10.489) AR5(-7.45,-9.839) AR6(-7.45,-9.189) AR7(-7.45,-8.539) AR9(-7.45,-7.889) AR10(-6.992,-7.427) AR11(-7.45,-6.965) AR36(-7.448,5.316) AR37(-6.991,5.778) AR38(-7.448,6.24) AR39(-7.448,6.89) AR41(-7.448,7.54) AR42(-7.448,8.19) AR43(-7.448,8.84) AR45(-7.36,9.915) AR47(-7.36,10.565) AT3(-6.535,-10.489) AT5(-6.535,-9.839) AT6(-6.535,-9.189) AT7(-6.535,-8.539) AT9(-6.535,-7.889) AT11(-6.535,-6.965) AT36(-6.533,5.316) AT38(-6.533,6.24) AT39(-6.533,6.89) AT41(-6.533,7.54) AT42(-6.533,8.19) AT43(-6.533,8.84) AT45(-6.74,9.59) AT47(-6.74,10.861) AU10(-6.077,-7.427) AU37(-6.076,5.778) AU45(-6.12,9.915) AU47(-6.12,10.565) AV3(-5.62,-10.489) AV5(-5.62,-9.839) AV6(-5.62,-9.189) AV7(-5.62,-8.539) AV9(-5.62,-7.889) AV11(-5.62,-6.965) AV36(-5.618,5.316) AV38(-5.618,6.24) AV39(-5.618,6.89) AV41(-5.618,7.54) AV42(-5.618,8.19) AV43(-5.618,8.84) AV45(-5.489,9.59) AV46(-5.489,10.241) AW10(-5.162,-7.427) AW37(-5.161,5.778) AY3(-4.705,-10.489) AY5(-4.705,-9.839) AY6(-4.705,-9.189) AY7(-4.705,-8.539) AY9(-4.705,-7.889) AY11(-4.705,-6.965) AY36(-4.703,5.316) AY38(-4.703,6.24) AY39(-4.703,6.89) AY41(-4.703,7.54) AY42(-4.703,8.19) AY43(-4.703,8.84) AY45(-4.858,9.915) AY47(-4.858,10.565) B4(-23.723,-10.016) B7(-23.715,-8.658) B33(-23.715,3.593) B43(-23.715,8.707) B45(-23.577,9.956) B47(-23.737,10.587) BA10(-4.247,-7.427) BA37(-4.246,5.778) BA45(-4.238,9.59) BA47(-4.238,10.861) BB3(-3.79,-10.489) BB5(-3.79,-9.839) BB6(-3.79,-9.189) BB7(-3.79,-8.539) BB9(-3.79,-7.889) BB11(-3.79,-6.965) BB36(-3.788,5.316) BB38(-3.788,6.24) BB39(-3.788,6.89) BB41(-3.788,7.54) BB42(-3.788,8.19) BB43(-3.788,8.84) BB45(-3.618,9.915) BB47(-3.618,10.565) BC10(-3.332,-7.427) BC37(-3.331,5.778) BD3(-2.875,-10.489) BD5(-2.875,-9.839) BD6(-2.875,-9.189) BD7(-2.875,-8.539) BD9(-2.875,-7.889) BD11(-2.875,-6.965) BD36(-2.873,5.316) BD38(-2.873,6.24) BD39(-2.873,6.89) BD41(-2.873,7.54) BD42(-2.873,8.19) BD43(-2.873,8.84) BD45(-2.987,9.59) BD46(-2.987,10.241) BE10(-2.417,-7.427) BE37(-2.416,5.778) BE45(-2.356,9.915) BE47(-2.356,10.565) BF3(-1.96,-10.489) BF5(-1.96,-9.839) BF6(-1.96,-9.189) BF7(-1.96,-8.539) BF9(-1.96,-7.889) BF10(-1.502,-7.427) BF11(-1.96,-6.965) BF36(-1.958,5.316) BF37(-1.501,5.778) BF38(-1.958,6.24) BF39(-1.958,6.89) BF41(-1.958,7.54) BF42(-1.958,8.19) BF43(-1.958,8.84) BF45(-1.736,9.59) BF47(-1.736,10.861) BG3(-1.045,-10.489) BG5(-1.045,-9.839) BG6(-1.045,-9.189) BG7(-1.045,-8.539) BG9(-1.045,-7.889) BG11(-1.045,-6.965) BG36(-1.043,5.316) BG38(-1.043,6.24) BG39(-1.043,6.89) BG41(-1.043,7.54) BG42(-1.043,8.19) BG43(-1.043,8.84) BG45(-1.116,9.915) BG47(-1.116,10.565) BH10(-0.587,-7.427) BH37(-0.586,5.778) BJ3(-0.13,-10.489) BJ5(-0.13,-9.839) BJ6(-0.13,-9.189) BJ7(-0.13,-8.539) BJ9(-0.13,-7.889) BJ11(-0.13,-6.965) BJ36(-0.128,5.316) BJ38(-0.128,6.24) BJ39(-0.128,6.89) BJ41(-0.128,7.54) BJ42(-0.128,8.19) BJ43(-0.128,8.84) BJ45(-0.485,9.59) BJ46(-0.485,10.241) BL10(0.328,-7.427) BL37(0.33,5.778) BL45(0.146,9.915) BL47(0.146,10.565) BM3(0.786,-10.489) BM5(0.786,-9.839) BM6(0.786,-9.189) BM7(0.786,-8.539) BM9(0.786,-7.889) BM11(0.786,-6.965) BM36(0.787,5.316) BM38(0.787,6.24) BM39(0.787,6.89) BM41(0.787,7.54) BM42(0.787,8.19) BM43(0.787,8.84) BM45(0.766,9.59) BM47(0.766,10.861) BN10(1.243,-7.427) BN37(1.245,5.778) BN45(1.386,9.915) BN47(1.386,10.565) BP3(1.701,-10.489) BP5(1.701,-9.839) BP6(1.701,-9.189) BP7(1.701,-8.539) BP9(1.701,-7.889) BP11(1.701,-6.965) BP36(1.702,5.316) BP38(1.702,6.24) BP39(1.702,6.89) BP41(1.702,7.54) BP42(1.702,8.19) BP43(1.702,8.84) BR10(2.158,-7.427) BR37(2.16,5.778) BR45(2.017,9.59) BR46(2.017,10.241) BT3(2.616,-10.489) BT5(2.616,-9.839) BT6(2.616,-9.189) BT7(2.616,-8.539) BT9(2.616,-7.889) BT11(2.616,-6.965) BT36(2.617,5.316) BT38(2.617,6.24) BT39(2.617,6.89) BT41(2.617,7.54) BT42(2.617,8.19) BT43(2.617,8.84) BT45(2.648,9.915) BT47(2.648,10.565) BU10(3.073,-7.427) BU37(3.075,5.778) BU45(3.268,9.59) BU47(3.268,10.861) BV3(3.531,-10.489) BV5(3.531,-9.839) BV6(3.531,-9.189) BV7(3.531,-8.539) BV9(3.531,-7.889) BV11(3.531,-6.965) BV36(3.532,5.316) BV38(3.532,6.24) BV39(3.532,6.89) BV41(3.532,7.54) BV42(3.532,8.19) BV43(3.532,8.84) BV45(3.888,9.915) BV47(3.888,10.565) BW3(4.446,-10.489) BW5(4.446,-9.839) BW6(4.446,-9.189) BW7(4.446,-8.539) BW9(4.446,-7.889) BW10(3.988,-7.427) BW11(4.446,-6.965) BW36(4.447,5.316) BW37(3.99,5.778) BW38(4.447,6.24) BW39(4.447,6.89) BW41(4.447,7.54) BW42(4.447,8.19) BW43(4.447,8.84) BY10(4.903,-7.427) BY37(4.905,5.778) BY45(4.519,9.59) BY46(4.519,10.241) C3(-23.079,-10.577) C5(-23.079,-9.927) C6(-23.393,-9.332) C7(-23.065,-8.658) C8(-23.39,-8.095) C9(-23.065,-7.532) C11(-23.393,-6.858) C12(-23.065,-6.184) C13(-23.39,-5.621) C14(-23.065,-5.058) C16(-23.393,-4.384) C33(-23.065,3.593) C34(-23.361,4.176) C35(-23.065,4.795) C38(-23.065,6.077) C39(-23.361,6.73) C40(-23.065,7.383) C43(-23.065,8.707) C44(-23.359,9.336) C47(-23.087,10.479) C48(-23.087,11.234) CA3(5.361,-10.489) CA5(5.361,-9.839) CA6(5.361,-9.189) CA7(5.361,-8.539) CA9(5.361,-7.889) CA11(5.361,-6.965) CA36(5.362,5.316) CA38(5.362,6.24) CA39(5.362,6.89) CA41(5.362,7.54) CA42(5.362,8.19) CA43(5.362,8.84) CA45(5.15,9.915) CA47(5.15,10.565) CB10(5.818,-7.427) CB37(5.82,5.778) CB45(5.77,9.59) CB47(5.77,10.861) CC3(6.149,-10.893) CC5(6.149,-9.905) CC6(6.276,-9.189) CC7(6.276,-8.539) CC9(6.276,-7.889) CC11(6.276,-6.965) CC36(6.277,5.316) CC38(6.277,6.24) CC39(6.277,6.89) CC41(6.277,7.54) CC42(6.277,8.19) CC43(6.277,8.84) CC45(6.39,9.915) CC47(6.39,10.565) CD3(6.823,-10.565) CD5(6.823,-9.915) CD10(6.733,-7.427) CE3(7.386,-10.89) CE4(7.386,-10.24) CE6(7.191,-9.189) CE7(7.191,-8.539) CE9(7.191,-7.889) CE11(7.191,-6.965) CE34(7.192,4.29) CE35(7.192,4.94) CE37(7.192,5.59) CE38(7.192,6.24) CE39(7.192,6.89) CE41(7.192,7.54) CE42(7.192,8.19) CE43(7.192,8.84) CE45(7.021,9.59) CE46(7.021,10.241) CF3(7.949,-10.565) CF5(7.949,-9.915) CF10(7.648,-7.427) CF33(7.65,3.828) CF45(7.652,9.915) CF47(7.652,10.565) CG6(8.106,-9.189) CG7(8.106,-8.539) CG9(8.106,-7.889) CG11(8.106,-6.965) CG32(8.107,3.366) CG34(8.107,4.29) CG35(8.107,4.94) CG37(8.107,5.59) CG38(8.107,6.24) CG39(8.107,6.89) CG41(8.107,7.54) CG42(8.107,8.19) CG43(8.107,8.84) CG45(8.272,9.59) CG47(8.272,10.861) CH3(8.623,-10.893) CH5(8.623,-9.905) CH10(8.563,-7.427) CH33(8.689,3.828) CH45(8.892,9.915) CH47(8.892,10.565) CJ3(9.297,-10.565) CJ5(9.297,-9.915) CJ6(9.021,-9.189) CJ7(9.021,-8.539) CJ9(9.021,-7.889) CJ11(9.021,-6.965) CJ32(9.272,3.366) CJ34(9.272,4.29) CJ35(9.272,4.94) CJ37(9.272,5.59) CJ38(9.272,6.24) CJ39(9.272,6.89) CJ41(9.272,7.54) CJ42(9.272,8.19) CJ43(9.272,8.84) CK3(9.86,-10.89) CK4(9.86,-10.24) CK6(9.936,-9.189) CK7(9.936,-8.539) CK9(9.936,-7.889) CK10(9.478,-7.427) CK11(9.936,-6.965) CK33(9.73,3.828) CK45(9.523,9.59) CK46(9.523,10.241) CL3(10.423,-10.565) CL5(10.423,-9.915) CL10(10.393,-7.427) CL32(10.187,3.366) CL34(10.187,4.29) CL35(10.187,4.94) CL37(10.187,5.59) CL38(10.187,6.24) CL39(10.187,6.89) CL41(10.187,7.54) CL42(10.187,8.19) CL43(10.187,8.84) CL45(10.154,9.915) CL47(10.154,10.565) CM6(10.851,-9.189) CM7(10.851,-8.539) CM9(10.851,-7.889) CM11(10.851,-6.965) CM33(10.645,3.828) CM45(10.774,9.59) CM47(10.774,10.861) CN3(11.097,-10.893) CN5(11.097,-9.905) CN10(11.308,-7.427) CN32(11.102,3.366) CN34(11.102,4.29) CN35(11.102,4.94) CN37(11.102,5.59) CN38(11.102,6.24) CN39(11.102,6.89) CN41(11.102,7.54) CN42(11.102,8.19) CN43(11.102,8.84) CN45(11.394,9.915) CN47(11.394,10.565) CP3(11.771,-10.565) CP5(11.771,-9.915) CP6(11.766,-9.189) CP7(11.766,-8.539) CP9(11.766,-7.889) CP11(11.766,-6.965) CP33(11.56,3.828) CR3(12.334,-10.89) CR4(12.334,-10.24) CR10(12.223,-7.427) CR32(12.017,3.366) CR34(12.017,4.29) CR35(12.017,4.94) CR37(12.017,5.59) CR38(12.017,6.24) CR39(12.017,6.89) CR41(12.017,7.54) CR42(12.017,8.19) CR43(12.017,8.84) CR45(12.025,9.59) CR46(12.025,10.241) CT3(12.897,-10.565) CT5(12.897,-9.915) CT6(12.681,-9.189) CT7(12.681,-8.539) CT9(12.681,-7.889) CT11(12.681,-6.965) CT32(12.932,3.366) CT33(12.475,3.828) CT34(12.932,4.29) CT35(12.932,4.94) CT37(12.932,5.59) CT38(12.932,6.24) CT39(12.932,6.89) CT41(12.932,7.54) CT42(12.932,8.19) CT43(12.932,8.84) CT45(12.656,9.915) CT47(12.656,10.565) CU10(13.138,-7.427) CU33(13.39,3.828) CU45(13.276,9.59) CU47(13.276,10.861) CV3(13.571,-10.893) CV5(13.571,-9.905) CV6(13.596,-9.189) CV7(13.596,-8.539) CV9(13.596,-7.889) CV11(13.596,-6.965) CV32(13.847,3.366) CV34(13.847,4.29) CV35(13.847,4.94) CV37(13.847,5.59) CV38(13.847,6.24) CV39(13.847,6.89) CV41(13.847,7.54) CV42(13.847,8.19) CV43(13.847,8.84) CV45(13.896,9.915) CV47(13.896,10.565) CW3(14.245,-10.565) CW5(14.245,-9.915) CW10(14.053,-7.427) CW33(14.305,3.828) CY3(14.808,-10.89) CY4(14.808,-10.24) CY6(14.511,-9.189) CY7(14.511,-8.539) CY9(14.511,-7.889) CY11(14.511,-6.965) CY32(14.762,3.366) CY34(14.762,4.29) CY35(14.762,4.94) CY37(14.762,5.59) CY38(14.762,6.24) CY39(14.762,6.89) CY41(14.762,7.54) CY42(14.762,8.19) CY43(14.762,8.84) CY45(14.527,9.59) CY46(14.527,10.241) D2(-22.522,-11.22) D4(-22.459,-10.381) D7(-22.415,-8.658) D8(-22.74,-8.095) D9(-22.415,-7.532) D12(-22.415,-6.184) D13(-22.74,-5.621) D14(-22.415,-5.058) D33(-22.415,3.593) D35(-22.415,4.795) D36(-22.741,5.424) D38(-22.415,6.077) D40(-22.415,7.383) D42(-22.741,8.036) D43(-22.415,8.707) D44(-22.492,9.354) D47(-22.545,10.866) D49(-22.605,11.865) DA3(15.371,-10.565) DA5(15.371,-9.915) DA6(15.426,-9.189) DA7(15.426,-8.539) DA9(15.426,-7.889) DA10(14.968,-7.427) DA11(15.426,-6.965) DA33(15.22,3.828) DA45(15.158,9.915) DA47(15.158,10.565) DB10(15.883,-7.427) DB32(15.677,3.366) DB34(15.677,4.29) DB35(15.677,4.94) DB37(15.677,5.59) DB38(15.677,6.24) DB39(15.677,6.89) DB41(15.677,7.54) DB42(15.677,8.19) DB43(15.677,8.84) DB45(15.778,9.59) DB47(15.778,10.861) DC3(16.045,-10.893) DC5(16.045,-9.905) DC6(16.341,-9.189) DC7(16.341,-8.539) DC9(16.341,-7.889) DC11(16.341,-6.965) DC33(16.135,3.828) DC45(16.398,9.915) DC47(16.398,10.565) DD3(16.719,-10.565) DD5(16.719,-9.915) DD34(16.592,4.29) DD35(16.592,4.94) DD37(16.592,5.59) DD38(16.592,6.24) DD39(16.592,6.89) DD41(16.592,7.54) DD42(16.592,8.19) DD43(16.592,8.84) DE3(17.282,-10.89) DE4(17.282,-10.24) DE6(17.256,-9.189) DE7(17.256,-8.539) DE9(17.256,-7.889) DE10(17.256,-7.239) DE45(17.029,9.59) DE46(17.029,10.241) DF3(17.845,-10.565) DF5(17.845,-9.915) DF34(17.507,4.29) DF35(17.507,4.94) DF37(17.507,5.59) DF38(17.507,6.24) DF39(17.507,6.89) DF41(17.507,7.54) DF42(17.507,8.19) DF43(17.507,8.84) DF45(17.66,9.915) DF47(17.66,10.565) DG6(18.171,-9.189) DG7(18.171,-8.539) DG9(18.171,-7.889) DG10(18.171,-7.239) DG34(18.332,4.476) DG36(18.332,5.391) DG38(18.332,6.306) DG40(18.332,7.221) DG42(18.332,8.136) DG44(18.332,9.051) DG47(18.288,10.861) DH3(18.519,-10.893) DH5(18.519,-9.905) DH45(18.871,9.915) DH47(18.871,10.565) DJ3(19.193,-10.565) DJ5(19.193,-9.915) DJ6(18.982,-9.249) DJ8(18.982,-8.334) DJ10(18.982,-7.419) DJ11(18.982,-6.504) DJ13(18.982,-5.589) DJ15(18.982,-4.674) DJ17(18.982,-3.759) DJ19(18.982,-2.844) DJ21(18.982,-1.929) DJ22(18.982,-1.014) DJ24(18.982,-0.099) DJ27(18.982,0.816) DJ29(18.982,1.731) DJ31(18.982,2.646) DJ33(18.982,3.561) DJ34(18.982,4.476) DJ36(18.982,5.391) DJ38(18.982,6.306) DJ40(18.982,7.221) DJ42(18.982,8.136) DJ44(18.982,9.051) DK3(19.756,-10.89) DK4(19.756,-10.24) DK6(19.632,-9.249) DK8(19.632,-8.334) DK10(19.632,-7.419) DK11(19.632,-6.504) DK13(19.632,-5.589) DK15(19.632,-4.674) DK17(19.632,-3.759) DK19(19.632,-2.844) DK21(19.632,-1.929) DK22(19.632,-1.014) DK24(19.632,-0.099) DK27(19.632,0.816) DK29(19.632,1.731) DK31(19.632,2.646) DK33(19.632,3.561) DK34(19.632,4.476) DK36(19.632,5.391) DK38(19.632,6.306) DK40(19.632,7.221) DK42(19.632,8.136) DK44(19.632,9.051) DK46(19.524,10.24) DL3(20.319,-10.565) DL5(20.319,-9.915) DL6(20.282,-9.249) DL8(20.282,-8.334) DL10(20.282,-7.419) DL11(20.282,-6.504) DL13(20.282,-5.589) DL15(20.282,-4.674) DL17(20.282,-3.759) DL19(20.282,-2.844) DL21(20.282,-1.929) DL22(20.282,-1.014) DL24(20.282,-0.099) DL27(20.282,0.816) DL29(20.282,1.731) DL31(20.282,2.646) DL33(20.282,3.561) DL34(20.282,4.476) DL36(20.282,5.391) DL38(20.282,6.306) DL40(20.282,7.221) DL42(20.282,8.136) DL44(20.282,9.051) DL45(20.177,9.915) DL47(20.177,10.565) DN3(20.993,-10.893) DN5(20.993,-9.905) DN6(20.932,-9.249) DN8(20.932,-8.334) DN10(20.932,-7.419) DN11(20.932,-6.504) DN13(20.932,-5.589) DN15(20.932,-4.674) DN17(20.932,-3.759) DN19(20.932,-2.844) DN21(20.932,-1.929) DN22(20.932,-1.014) DN24(20.932,-0.099) DN27(20.932,0.816) DN29(20.932,1.731) DN31(20.932,2.646) DN33(20.932,3.561) DN34(20.932,4.476) DN36(20.932,5.391) DN38(20.932,6.306) DN40(20.932,7.221) DN42(20.932,8.136) DN44(20.932,9.051) DN47(21.305,10.565) DP1(21.667,-11.865) DP3(21.667,-10.565) DP5(21.667,-9.915) DP6(21.582,-9.249) DP8(21.582,-8.334) DP10(21.582,-7.419) DP11(21.582,-6.504) DP13(21.582,-5.589) DP15(21.582,-4.674) DP17(21.582,-3.759) DP19(21.582,-2.844) DP21(21.582,-1.929) DP22(21.582,-1.014) DP24(21.582,-0.099) DP27(21.582,0.816) DP29(21.582,1.731) DP31(21.582,2.646) DP33(21.582,3.561) DP34(21.582,4.476) DP36(21.582,5.391) DP38(21.582,6.306) DP40(21.582,7.221) DP42(21.582,8.136) DP44(21.582,9.051) DP45(21.629,9.915) DR5(22.316,-9.948) DR47(21.955,10.565) DR48(21.955,11.215) DR49(21.955,11.865) DT1(22.605,-11.865) DT2(22.437,-11.237) DT3(22.437,-10.587) DT6(22.415,-9.306) DT7(22.74,-8.67) DT8(22.415,-8.017) DT10(22.415,-7.36) DT11(22.415,-6.703) DT12(22.74,-6.05) DT14(22.415,-5.397) DT15(22.415,-4.74) DT16(22.415,-4.083) DT18(22.74,-3.43) DT19(22.415,-2.777) DT20(22.415,-2.12) DT22(22.415,-1.463) DT23(22.74,-0.81) DT24(22.415,-0.157) DT27(22.415,0.5) DT28(22.415,1.157) DT29(22.74,1.81) DT30(22.415,2.463) DT32(22.415,3.12) DT33(22.415,3.777) DT34(22.74,4.43) DT36(22.415,5.083) DT37(22.415,5.74) DT38(22.415,6.397) DT40(22.74,7.05) DT41(22.415,7.703) DT42(22.415,8.36) DT44(22.416,9.026) DT45(22.48,9.676) DT47(22.527,10.906) DT49(22.605,11.865) DU2(23.087,-11.237) DU3(23.087,-10.587) DU6(23.065,-9.323) DU10(23.39,-7.36) DU15(23.39,-4.74) DU20(23.39,-2.12) DU27(23.39,0.5) DU32(23.39,3.12) DU37(23.39,5.74) DU42(23.39,8.36) DU44(23.066,9.026) DU45(23.13,9.676) DU47(23.084,10.566) DU48(23.087,11.236) DV3(23.737,-10.587) DV4(23.41,-10.023) DV6(23.715,-9.426) DV44(23.716,9.026) DV45(23.733,9.936) DV47(23.734,10.586) DW4(24.365,-10.105) DW6(24.365,-9.426) DW44(24.366,9.026) DW46(24.365,10.105) E1(-21.955,-11.865) E3(-21.994,-10.836) E5(-22.002,-9.87) E6(-22.4,-9.332) E11(-22.4,-6.858) E16(-22.4,-4.384) E34(-22.091,4.176) E36(-22.091,5.424) E39(-22.091,6.73) E42(-22.091,8.036) E46(-22.394,10.226) E48(-22.101,11.43) F6(-21.697,-9.282) F8(-21.697,-8.367) F10(-21.697,-7.452) F11(-21.697,-6.537) F13(-21.697,-5.622) F15(-21.697,-4.707) F17(-21.765,-3.728) F33(-21.765,3.593) F45(-21.874,9.59) F47(-21.89,10.809) G1(-21.379,-11.542) G3(-21.346,-10.893) G5(-21.346,-9.905) G6(-21.047,-9.282) G8(-21.047,-8.367) G10(-21.047,-7.452) G11(-21.047,-6.537) G13(-21.047,-5.622) G15(-21.047,-4.707) G17(-21.115,-3.728) G33(-21.115,3.593) G34(-21.344,4.404) G36(-21.344,5.319) G38(-21.173,6.24) G39(-21.173,6.89) G41(-21.173,7.54) G42(-21.173,8.19) G43(-21.173,8.84) G45(-21.259,9.915) G47(-21.259,10.565) G48(-21.314,11.215) G49(-21.314,11.865) H1(-20.671,-11.865) H3(-20.671,-10.565) H5(-20.671,-9.915) H17(-20.465,-3.728) H33(-20.465,3.593) H34(-20.694,4.404) H36(-20.694,5.319) H45(-20.641,9.59) H46(-20.641,10.24) J3(-20.108,-10.89) J4(-20.108,-10.24) J6(-20.397,-9.282) J8(-20.397,-8.367) J10(-20.397,-7.452) J11(-20.397,-6.537) J13(-20.397,-5.622) J15(-20.397,-4.707) J16(-20.003,-4.185) J18(-20.003,-3.27) J20(-20.003,-2.355) J22(-20.003,-1.44) J23(-20.003,-0.525) J26(-20.003,0.39) J28(-20.003,1.305) J30(-20.003,2.22) J32(-20.003,3.135) J34(-20.044,4.404) J36(-20.044,5.319) J38(-20.258,6.24) J39(-20.258,6.89) J41(-20.258,7.54) J42(-20.258,8.19) J43(-20.258,8.84) J45(-19.988,9.915) J47(-19.988,10.565) K3(-19.545,-10.565) K5(-19.545,-9.915) K6(-19.747,-9.282) K8(-19.747,-8.367) K10(-19.747,-7.452) K11(-19.747,-6.537) K13(-19.747,-5.622) K15(-19.541,-4.643) K17(-19.541,-3.728) K19(-19.541,-2.813) K21(-19.541,-1.898) K23(-19.541,-0.983) K24(-19.541,-0.068) K27(-19.541,0.848) K29(-19.541,1.763) K31(-19.541,2.678) K33(-19.541,3.593) L6(-19.097,-9.282) L8(-19.097,-8.367) L10(-19.097,-7.452) L11(-19.097,-6.537) L13(-19.097,-5.622) L34(-19.394,4.404) L36(-19.394,5.319) L38(-19.343,6.24) L39(-19.343,6.89) L41(-19.343,7.54) L42(-19.343,8.19) L43(-19.343,8.84) L45(-19.335,9.59) L47(-19.335,10.861) M3(-18.871,-10.893) M5(-18.871,-9.905) M6(-18.447,-9.282) M8(-18.447,-8.367) M10(-18.447,-7.452) M11(-18.447,-6.537) M13(-18.447,-5.622) M34(-18.744,4.404) M36(-18.744,5.319) M38(-18.428,6.24) M39(-18.428,6.89) M41(-18.428,7.54) M42(-18.428,8.19) M43(-18.428,8.84) M45(-18.682,9.915) M47(-18.682,10.565) N3(-18.197,-10.565) N5(-18.197,-9.915) N34(-18.094,4.404) N36(-18.094,5.319) N45(-18.029,9.59) N46(-18.029,10.24) P3(-17.634,-10.89) P4(-17.634,-10.24) P6(-17.797,-9.282) P8(-17.797,-8.367) P10(-17.797,-7.452) P11(-17.797,-6.537) P13(-17.797,-5.622) P38(-17.513,6.24) P39(-17.513,6.89) P41(-17.513,7.54) P42(-17.513,8.19) P43(-17.513,8.84) R3(-17.071,-10.565) R5(-17.071,-9.915) R12(-17.057,-6.127) R35(-17.056,4.855) R37(-17.056,5.778) R45(-17.376,9.915) R47(-17.376,10.565) T6(-16.6,-9.189) T7(-16.6,-8.539) T9(-16.6,-7.889) T10(-16.6,-7.239) T11(-16.6,-6.589) T13(-16.6,-5.665) T34(-16.598,4.393) T36(-16.598,5.316) T38(-16.598,6.24) T39(-16.598,6.89) T41(-16.598,7.54) T42(-16.598,8.19) T43(-16.598,8.84) T45(-16.748,9.59) T47(-16.748,10.861) U3(-16.397,-10.893) U5(-16.397,-9.905) U12(-16.142,-6.127) U35(-16.141,4.855) U37(-16.141,5.778) U45(-16.128,9.915) U47(-16.128,10.565) V3(-15.723,-10.565) V5(-15.723,-9.915) V6(-15.685,-9.189) V7(-15.685,-8.539) V9(-15.685,-7.889) V10(-15.685,-7.239) V11(-15.685,-6.589) V13(-15.685,-5.665) V34(-15.683,4.393) V36(-15.683,5.316) V38(-15.683,6.24) V39(-15.683,6.89) V41(-15.683,7.54) V42(-15.683,8.19) V43(-15.683,8.84) V45(-15.497,9.59) V46(-15.497,10.241) W3(-15.16,-10.89) W4(-15.16,-10.24) W12(-15.227,-6.127) W35(-15.226,4.855) W37(-15.226,5.778) Y3(-14.597,-10.565) Y5(-14.597,-9.915) Y6(-14.77,-9.189) Y7(-14.77,-8.539) Y9(-14.77,-7.889) Y10(-14.77,-7.239) Y11(-14.77,-6.589) Y13(-14.77,-5.665) Y34(-14.768,4.393) Y36(-14.768,5.316) Y38(-14.768,6.24) Y39(-14.768,6.89) Y41(-14.768,7.54) Y42(-14.768,8.19) Y43(-14.768,8.84) Y45(-14.866,9.915) Y47(-14.866,10.565)
  oval 0.33x0.254 smd: A9(-24.365,-7.532) A11(-24.043,-6.858) A12(-24.365,-6.184) A14(-24.365,-5.058) A16(-24.043,-4.384) A36(-24.041,5.424) A38(-24.365,6.077) A39(-24.041,6.73) A40(-24.365,7.383) A42(-24.041,8.036) B9(-23.715,-7.532) B12(-23.715,-6.184) B14(-23.715,-5.058) B38(-23.715,6.077) B40(-23.715,7.383) C36(-23.391,5.424) C42(-23.391,8.036) DU7(23.39,-8.67) DU8(23.065,-8.017) DU11(23.065,-6.703) DU12(23.39,-6.05) DU14(23.065,-5.397) DU16(23.065,-4.083) DU18(23.39,-3.43) DU19(23.065,-2.777) DU22(23.065,-1.463) DU23(23.39,-0.81) DU24(23.065,-0.157) DU28(23.065,1.157) DU29(23.39,1.81) DU30(23.065,2.463) DU33(23.065,3.777) DU34(23.39,4.43) DU36(23.065,5.083) DU38(23.065,6.397) DU40(23.39,7.05) DU41(23.065,7.703) DV8(23.715,-8.017) DV11(23.715,-6.703) DV14(23.715,-5.397) DV16(23.715,-4.083) DV19(23.715,-2.777) DV22(23.715,-1.463) DV24(23.715,-0.157) DV28(23.715,1.157) DV30(23.715,2.463) DV33(23.715,3.777) DV36(23.715,5.083) DV38(23.715,6.397) DV41(23.715,7.703) DW7(24.04,-8.67) DW8(24.365,-8.017) DW10(24.04,-7.36) DW11(24.365,-6.703) DW12(24.04,-6.05) DW14(24.365,-5.397) DW15(24.04,-4.74) DW16(24.365,-4.083) DW18(24.04,-3.43) DW19(24.365,-2.777) DW20(24.04,-2.12) DW22(24.365,-1.463) DW23(24.04,-0.81) DW24(24.365,-0.157) DW27(24.04,0.5) DW28(24.365,1.157) DW29(24.04,1.81) DW30(24.365,2.463) DW32(24.04,3.12) DW33(24.365,3.777) DW34(24.04,4.43) DW36(24.365,5.083) DW37(24.04,5.74) DW38(24.365,6.397) DW40(24.04,7.05) DW41(24.365,7.703) DW42(24.04,8.36)
  round 0.406 smd: A17(-24.365,-3.728) A19(-24.365,-2.813) A21(-24.365,-1.898) A23(-24.365,-0.983) A24(-24.365,-0.068) A27(-24.365,0.848) A29(-24.365,1.763) A31(-24.365,2.678) B17(-23.715,-3.728) B19(-23.715,-2.813) B21(-23.715,-1.898) B23(-23.715,-0.983) B24(-23.715,-0.068) B27(-23.715,0.848) B29(-23.715,1.763) B31(-23.715,2.678) C17(-23.065,-3.728) C19(-23.065,-2.813) C21(-23.065,-1.898) C23(-23.065,-0.983) C24(-23.065,-0.068) C27(-23.065,0.848) C29(-23.065,1.763) C31(-23.065,2.678) D17(-22.415,-3.728) D19(-22.415,-2.813) D21(-22.415,-1.898) D23(-22.415,-0.983) D24(-22.415,-0.068) D27(-22.415,0.848) D29(-22.415,1.763) D31(-22.415,2.678) F19(-21.765,-2.813) F21(-21.765,-1.898) F23(-21.765,-0.983) F24(-21.765,-0.068) F27(-21.765,0.848) F29(-21.765,1.763) F31(-21.765,2.678) G19(-21.115,-2.813) G21(-21.115,-1.898) G23(-21.115,-0.983) G24(-21.115,-0.068) G27(-21.115,0.848) G29(-21.115,1.763) G31(-21.115,2.678) H19(-20.465,-2.813) H21(-20.465,-1.898) H23(-20.465,-0.983) H24(-20.465,-0.068) H27(-20.465,0.848) H29(-20.465,1.763) H31(-20.465,2.678)
  oval 0.305x0.203 smd: A34(-24.011,4.176) A35(-24.365,4.795) B35(-23.715,4.795)
  oval 0.203x0.305 smd: AA49(-14.246,11.511) AB48(-13.626,11.215) AB49(-13.626,11.865) AC47(-12.995,10.891) AC49(-12.995,11.541) AE48(-12.364,11.215) AE49(-12.364,11.865) AF49(-11.744,11.511) AG48(-11.124,11.215) AG49(-11.124,11.865) AH1(-10.706,-11.865) AH2(-10.706,-11.215) AH47(-10.493,10.891) AH49(-10.493,11.541) AJ1(-10.056,-11.865) AJ2(-10.056,-11.215) AK48(-9.862,11.215) AK49(-9.862,11.865) AL1(-9.406,-11.865) AL2(-9.406,-11.215) AL49(-9.242,11.511) AM1(-8.756,-11.865) AM2(-8.756,-11.215) AM48(-8.622,11.215) AM49(-8.622,11.865) AN1(-8.106,-11.865) AN2(-8.106,-11.215) AN47(-7.991,10.891) AN49(-7.991,11.541) AR1(-7.456,-11.865) AR2(-7.456,-11.215) AR48(-7.36,11.215) AR49(-7.36,11.865) AT1(-6.806,-11.865) AT2(-6.806,-11.215) AT49(-6.74,11.511) AU1(-6.156,-11.865) AU2(-6.156,-11.215) AU48(-6.12,11.215) AU49(-6.12,11.865) AV1(-5.506,-11.865) AV2(-5.506,-11.215) AV47(-5.489,10.891) AV49(-5.489,11.541) AY1(-4.856,-11.865) AY2(-4.856,-11.215) AY48(-4.858,11.215) AY49(-4.858,11.865) BA1(-4.206,-11.865) BA2(-4.206,-11.215) BA49(-4.238,11.511) BB1(-3.556,-11.865) BB2(-3.556,-11.215) BB48(-3.618,11.215) BB49(-3.618,11.865) BD1(-2.906,-11.865) BD2(-2.906,-11.215) BD47(-2.987,10.891) BD49(-2.987,11.541) BE1(-2.256,-11.865) BE2(-2.256,-11.215) BE48(-2.356,11.215) BE49(-2.356,11.865) BF1(-1.606,-11.865) BF2(-1.606,-11.215) BF49(-1.736,11.511) BG48(-1.116,11.215) BG49(-1.116,11.865) BH1(-0.956,-11.865) BH2(-0.956,-11.215) BJ1(-0.306,-11.865) BJ2(-0.306,-11.215) BJ47(-0.485,10.891) BJ49(-0.485,11.541) BL1(0.344,-11.865) BL2(0.344,-11.215) BL48(0.146,11.215) BL49(0.146,11.865) BM1(0.994,-11.865) BM2(0.994,-11.215) BM49(0.766,11.511) BN48(1.386,11.215) BN49(1.386,11.865) BP1(1.644,-11.865) BP2(1.644,-11.215) BR1(2.294,-11.865) BR2(2.294,-11.215) BR47(2.017,10.891) BR49(2.017,11.541) BT1(2.944,-11.865) BT2(2.944,-11.215) BT48(2.648,11.215) BT49(2.648,11.865) BU49(3.268,11.511) BV1(3.594,-11.865) BV2(3.594,-11.215) BV48(3.888,11.215) BV49(3.888,11.865) BW1(4.244,-11.865) BW2(4.244,-11.215) BY1(4.894,-11.865) BY2(4.894,-11.215) BY47(4.519,10.891) BY49(4.519,11.541) CA48(5.15,11.215) CA49(5.15,11.865) CB1(5.544,-11.865) CB2(5.544,-11.215) CB49(5.77,11.511) CC48(6.39,11.215) CC49(6.39,11.865) CE47(7.021,10.891) CE49(7.021,11.541) CF48(7.652,11.215) CF49(7.652,11.865) CG49(8.272,11.511) CH48(8.892,11.215) CH49(8.892,11.865) CK47(9.523,10.891) CK49(9.523,11.541) CL48(10.154,11.215) CL49(10.154,11.865) CM49(10.774,11.511) CN48(11.394,11.215) CN49(11.394,11.865) CR47(12.025,10.891) CR49(12.025,11.541) CT48(12.656,11.215) CT49(12.656,11.865) CU49(13.276,11.511) CV48(13.896,11.215) CV49(13.896,11.865) CY47(14.527,10.891) CY49(14.527,11.541) DA48(15.158,11.215) DA49(15.158,11.865) DB49(15.778,11.511) DC48(16.398,11.215) DC49(16.398,11.865) DE47(17.029,10.891) DE49(17.029,11.541) DF48(17.66,11.215) DF49(17.66,11.865) T49(-16.748,11.511) U48(-16.128,11.215) U49(-16.128,11.865) V47(-15.497,10.891) V49(-15.497,11.541) Y48(-14.866,11.215) Y49(-14.866,11.865)
  oval 0.254x0.33 smd: AB1(-13.923,-11.543) AC1(-13.249,-11.865) AC2(-13.249,-11.215) AE1(-12.123,-11.865) AE2(-12.123,-11.215) AG1(-11.449,-11.543) CC1(6.149,-11.543) CD1(6.823,-11.865) CD2(6.823,-11.215) CF1(7.949,-11.865) CF2(7.949,-11.215) CH1(8.623,-11.543) CJ1(9.297,-11.865) CJ2(9.297,-11.215) CL1(10.423,-11.865) CL2(10.423,-11.215) CN1(11.097,-11.543) CP1(11.771,-11.865) CP2(11.771,-11.215) CT1(12.897,-11.865) CT2(12.897,-11.215) CV1(13.571,-11.543) CW1(14.245,-11.865) CW2(14.245,-11.215) DA1(15.371,-11.865) DA2(15.371,-11.215) DC1(16.045,-11.543) DD1(16.719,-11.865) DD2(16.719,-11.215) DF1(17.845,-11.865) DF2(17.845,-11.215) DG49(18.288,11.511) DH1(18.519,-11.543) DH48(18.871,11.215) DH49(18.871,11.865) DJ1(19.193,-11.865) DJ2(19.193,-11.215) DK47(19.524,10.89) DK49(19.524,11.54) DL1(20.319,-11.865) DL2(20.319,-11.215) DL48(20.177,11.215) DL49(20.177,11.865) DM47(20.741,10.89) DM49(20.741,11.54) DN1(20.993,-11.543) DN48(21.305,11.215) DN49(21.305,11.865) DP2(21.667,-11.215) H2(-20.671,-11.215) H47(-20.641,10.89) H49(-20.641,11.54) J48(-19.988,11.215) J49(-19.988,11.865) K1(-19.545,-11.865) K2(-19.545,-11.215) L49(-19.335,11.54) M1(-18.871,-11.543) M48(-18.682,11.215) M49(-18.682,11.865) N1(-18.197,-11.865) N2(-18.197,-11.215) N47(-18.029,10.89) N49(-18.029,11.54) R1(-17.071,-11.865) R2(-17.071,-11.215) R48(-17.376,11.215) R49(-17.376,11.865) U1(-16.397,-11.543) V1(-15.723,-11.865) V2(-15.723,-11.215) Y1(-14.597,-11.865) Y2(-14.597,-11.215)
NB_CON2_7D65X5D5X1D9_1D25
  rect 0.8x1.9 smd: 1(-0.625,0) 2(0.625,0)
  rect 1.3x3.35 smd: 3(-3.475,-4.875) 4(3.475,-4.875)
NB_CON4_4X3D05X1_0D5
  rect 0.3x0.8 smd: 1(-0.75,0) 2(-0.25,0) 3(0.25,0) 4(0.75,0)
  rect 0.4x0.8 smd: 5(-1.75,-2.5) 6(1.75,-2.5)
NB_CON4_8D9X5D35X2_1
  rect 0.5x1.301 smd: 1(-1.5,0) 2(-0.5,0) 3(0.5,0) 4(1.5,0)
  rect 2x1.6 smd: 5(-3.7,-2.68) 6(3.7,-2.68)
NB_CON4_10D15X4D5X1D9_1D25
  rect 0.8x1.9 smd: 1(-1.875,0) 2(-0.625,0) 3(0.625,0) 4(1.875,0)
  rect 1.3x3.4 smd: 5(-4.725,-4.95) 6(4.725,-4.95)
NB_CON6_5X3D05X1_0D5
  rect 0.3x0.8 smd: 1(-1.25,0) 2(-0.75,0) 3(-0.25,0) 4(0.25,0) 5(0.75,0) 6(1.25,0)
  rect 0.4x0.8 smd: 7(-2.25,-2.5) 8(2.25,-2.5)
NB_CON6_6D98X2D7X1D8_0D8
  rect 0.5x1 smd: 1(0,0) 2(0.8,0) 3(1.6,0) 4(2.4,0) 5(3.2,0) 6(4,0)
  rect 1.2x1.7 smd: 7(-1.3,-1.95) 8(5.3,-1.95)
NB_CON8_12D7X5D8X3D6_1
  rect 0.5x1.301 smd: 1(-3.5,0) 2(-2.5,0) 3(-1.5,0) 4(-0.5,0) 5(0.5,0) 6(1.5,0) 7(2.5,0) 8(3.5,0)
  rect 2x3.45 smd: 9(-5.65,-2.65) 10(5.65,-2.65)
NB_CON28_17D6X4D9X2_0D5
  rect 0.3x1.2 smd: 1(-6.75,0) 2(-6.25,0) 3(-5.75,0) 4(-5.25,0) 5(-4.75,0) 6(-4.25,0) 7(-3.75,0) 8(-3.25,0) 9(-2.75,0) 10(-2.25,0) 11(-1.75,0) 12(-1.25,0) 13(-0.75,0) 14(-0.25,0) 15(0.25,0) 16(0.75,0) 17(1.25,0) 18(1.75,0) 19(2.25,0) 20(2.75,0) 21(3.25,0) 22(3.75,0) 23(4.25,0) 24(4.75,0) 25(5.25,0) 26(5.75,0) 27(6.25,0) 28(6.75,0)
  rect 1.8x2 smd: 29(-8.4,-3.15) 30(8.4,-3.15)
NB_CON40_24D1X4D5X1D5_0D5
  rect 0.3x1.1 smd: 1(-9.75,1.41) 2(-9.25,1.41) 3(-8.75,1.41) 4(-8.25,1.41) 5(-7.75,1.41) 6(-7.25,1.41) 7(-6.75,1.41) 8(-6.25,1.41) 9(-5.75,1.41) 10(-5.25,1.41) 11(-4.75,1.41) 12(-4.25,1.41) 13(-3.75,1.41) 14(-3.25,1.41) 15(-2.75,1.41) 16(-2.25,1.41) 17(-1.75,1.41) 18(-1.25,1.41) 19(-0.75,1.41) 20(-0.25,1.41) 21(0.25,1.41) 22(0.75,1.41) 23(1.25,1.41) 24(1.75,1.41) 25(2.25,1.41) 26(2.75,1.41) 27(3.25,1.41) 28(3.75,1.41) 29(4.25,1.41) 30(4.75,1.41) 31(5.25,1.41) 32(5.75,1.41) 33(6.25,1.41) 34(6.75,1.41) 35(7.25,1.41) 36(7.75,1.41) 37(8.25,1.41) 38(8.75,1.41) 39(9.25,1.41) 40(9.75,1.41)
  rect 1.1x1.8 smd: 41(-11.9,-1.29) 42(11.9,-1.29)
NB_CT2_7D3X4D3X2
  rect 1.5x2.5 smd: 1(3,0) 2(-3,0)
NB_DC5_12D2X6D8X5D2
  oval 1.6x2.5 hole 1x1.9: 1(0,6.187)
  oval 1.1x2.1 hole 0.5x1.5: 2(2.15,5.537) 3(-2.15,5.537)
  oval 1.2x3.6 hole 0.6x3: 4(4.25,-1.963) 5(-4.25,-1.963)
NB_DFN5_1D2X1D2X0D4
  custom 0.088x0.088 smd: 1(-0.51,-0.437) 2(0.51,-0.437) 3(0.51,0.363) 4(-0.51,0.363)
  custom 0.188x0.188 smd: 5(0,-0.037)
NB_DFN5_5D55X5D2X1
  rect 0.5x0.65 smd: 1(-1.905,-2.75) 2(-0.635,-2.75) 3(0.635,-2.75) 4(1.905,-2.75)
  custom 1.15x1.15 smd: 5(0,0.74)
NB_DIODE2_1D05X0D65X0D55
  rect 0.55x0.65 smd: 1(-0.425,0) 2(0.425,0)
NB_DIODE2_1D7X1D25X1_JX
  rect 0.8x0.6 smd: 1(1.05,0) 2(-1.05,0)
NB_DIODE2_2D5X1D25X1_JX
  rect 0.6x0.8 smd: 1(1.1,0) 2(-1.1,0)
NB_EMI4_0D64X0D57X0D38
  rect 0.3x0.23 smd: 1(-0.275,-0.225) 2(-0.275,0.225) 3(0.275,0.225) 4(0.275,-0.225)
NB_EMI10_2D5X1X0D65
  rect 0.2x0.6 smd: 1(-1.001,-0.399) 2(-0.5,-0.399) 4(0.5,-0.399) 5(1.001,-0.399) 6(1.001,0.399) 7(0.5,0.399) 9(-0.5,0.399) 10(-1.001,0.399)
  rect 0.4x1.4 smd: 3(0,0)
NB_ESD2_1X0D6X0D4_JX
  rect 0.4x0.6 smd: 1(-0.35,0) 2(0.35,0)
NB_ESD3_2D3X2D1X0D65
  rect 0.4x0.5 smd: 1(-0.65,0) 2(0.65,0)
  custom 0.338x0.338 smd: 3(0,-1.175)
NB_FBP1608_2_1D6X0D8X0D55
  rect 0.85x0.76 smd: 1(0.375,0)
  rect 0.41x0.68 smd: 2(-0.595,0)
NB_HDMI23_15X13D85X6D95_CH178
  round 0.8 hole 0.55: 1(-4.5,-1.55) 2(-4,0) 3(-3.5,-1.55) 4(-3,0) 5(-2.5,-1.55) 6(-2,0) 7(-1.5,-1.55) 8(-1,0) 9(-0.5,-1.55) 10(0,0) 11(0.5,-1.55) 12(1,0) 13(1.5,-1.55) 14(2,0) 15(2.5,-1.55) 16(3,0) 17(3.5,-1.55) 18(4,0) 19(4.5,-1.55)
  oval 1.4x2.2 hole 0.8x1.6: 20(-7.25,-1.35) 21(7.25,-1.35)
  oval 1.7x3 hole 1.1x2.4: 22(-8.75,-9.7) 23(8.75,-9.7)
NB_L2_7D3X6D8X3
  rect 2.35x3.5 smd: 1(-3.025,0) 2(3.025,0)
NB_L2_11D5X10D3X3
  rect 4.1x3.5 smd: 1(-4.75,0) 2(4.75,0)
NB_L0603
  rect 0.6x0.95 smd: 1(-0.6,0) 2(0.6,0)
NB_LED4_1D6X1D5X0D55
  rect 0.65x0.65 smd: 1(-0.525,0.625) 2(0.525,0.625) 3(0.525,-0.625) 4(-0.525,-0.625)
NB_MOS10_6X5X0D8
  rect 0.65x0.63 smd: 1(-1.905,-2.835) 2(-0.635,-2.835) 3(0.635,-2.835) 4(1.905,-2.835) 5(1.905,2.835) 6(0.635,2.835) 7(-0.635,2.835) 8(-1.905,2.835) 10(0.6,-1.7)
  rect 4x2.7 smd: 9(0,0.77)
NB_MSOP10_3X31D1
  rect 1.2x0.3 smd: 1(-2.1,1) 2(-2.1,0.5) 3(-2.1,0) 4(-2.1,-0.5) 5(-2.1,-1) 6(2.1,-1) 7(2.1,-0.5) 8(2.1,0) 9(2.1,0.5) 10(2.1,1)
NB_NGFF75_21D9X6D4X2D65_M1
  round 1.1 hole 1.1 unplated: (-10,0)
  round 1.6 hole 1.6 unplated: (10,0)
  rect 0.3x1.55 smd: 1(-9.25,5.275) 2(-9,-2.275) 3(-8.75,5.275) 4(-8.5,-2.275) 5(-8.25,5.275) 6(-8,-2.275) 7(-7.75,5.275) 8(-7.5,-2.275) 9(-7.25,5.275) 10(-7,-2.275) 11(-6.75,5.275) 12(-6.5,-2.275) 13(-6.25,5.275) 14(-6,-2.275) 15(-5.75,5.275) 16(-5.5,-2.275) 17(-5.25,5.275) 18(-5,-2.275) 19(-4.75,5.275) 20(-4.5,-2.275) 21(-4.25,5.275) 22(-4,-2.275) 23(-3.75,5.275) 24(-3.5,-2.275) 25(-3.25,5.275) 26(-3,-2.275) 27(-2.75,5.275) 28(-2.5,-2.275) 29(-2.25,5.275) 30(-2,-2.275) 31(-1.75,5.275) 32(-1.5,-2.275) 33(-1.25,5.275) 34(-1,-2.275) 35(-0.75,5.275) 36(-0.5,-2.275) 37(-0.25,5.275) 38(0,-2.275) 39(0.25,5.275) 40(0.5,-2.275) 41(0.75,5.275) 42(1,-2.275) 43(1.25,5.275) 44(1.5,-2.275) 45(1.75,5.275) 46(2,-2.275) 47(2.25,5.275) 48(2.5,-2.275) 49(2.75,5.275) 50(3,-2.275) 51(3.25,5.275) 52(3.5,-2.275) 53(3.75,5.275) 54(4,-2.275) 55(4.25,5.275) 56(4.5,-2.275) 57(4.75,5.275) 58(5,-2.275) 67(7.25,5.275) 68(7.5,-2.275) 69(7.75,5.275) 70(8,-2.275) 71(8.25,5.275) 72(8.5,-2.275) 73(8.75,5.275) 74(9,-2.275) 75(9.25,5.275)
  rect 1.2x2.75 smd: 76(-10.35,4.5) 77(10.35,4.5)
NB_NGFF75_21D85X6D4X2D3_0D5
  round 1.1 hole 1.1 unplated: (-10,0)
  round 1.6 hole 1.6 unplated: (10,0)
  rect 0.3x1.55 smd: 1(-9.25,5.275) 2(-9,-2.275) 3(-8.75,5.275) 4(-8.5,-2.275) 5(-8.25,5.275) 6(-8,-2.275) 7(-7.75,5.275) 8(-7.5,-2.275) 9(-7.25,5.275) 10(-7,-2.275) 11(-6.75,5.275) 12(-6.5,-2.275) 13(-6.25,5.275) 14(-6,-2.275) 15(-5.75,5.275) 16(-5.5,-2.275) 17(-5.25,5.275) 18(-5,-2.275) 19(-4.75,5.275) 20(-4.5,-2.275) 21(-4.25,5.275) 22(-4,-2.275) 23(-3.75,5.275) 32(-1.5,-2.275) 33(-1.25,5.275) 34(-1,-2.275) 35(-0.75,5.275) 36(-0.5,-2.275) 37(-0.25,5.275) 38(0,-2.275) 39(0.25,5.275) 40(0.5,-2.275) 41(0.75,5.275) 42(1,-2.275) 43(1.25,5.275) 44(1.5,-2.275) 45(1.75,5.275) 46(2,-2.275) 47(2.25,5.275) 48(2.5,-2.275) 49(2.75,5.275) 50(3,-2.275) 51(3.25,5.275) 52(3.5,-2.275) 53(3.75,5.275) 54(4,-2.275) 55(4.25,5.275) 56(4.5,-2.275) 57(4.75,5.275) 58(5,-2.275) 59(5.25,5.275) 60(5.5,-2.275) 61(5.75,5.275) 62(6,-2.275) 63(6.25,5.275) 64(6.5,-2.275) 65(6.75,5.275) 66(7,-2.275) 67(7.25,5.275) 68(7.5,-2.275) 69(7.75,5.275) 70(8,-2.275) 71(8.25,5.275) 72(8.5,-2.275) 73(8.75,5.275) 74(9,-2.275) 75(9.25,5.275)
  rect 1.2x2.75 smd: 76(-10.35,4.5) 77(10.35,4.5)
NB_PCAP3528_2D0
  rect 1.6x2.7 smd: 1(1.5,0) 2(-1.5,0)
NB_QFN7_1D5X1D5X0D9
  rect 0.7x0.25 smd: 1(-0.65,0.525) 2(-0.65,0.075)
  rect 0.25x0.7 smd: 3(-0.45,-0.6) 4(0,-0.6) 5(0.45,-0.6)
  rect 1.1x0.25 smd: 6(0.45,0.075) 7(0.45,0.525)
NB_QFN12_3X3X0D6
  rect 0.7x0.25 smd: 1(-1.4,0.62) 6(1.4,0.62)
  rect 1.2x0.25 smd: 2(-1.2,-0.1) 3(-1.2,-1)
  rect 2.13x0.25 smd: 4(0.735,-0.55) 5(0.735,0.17)
  rect 0.25x0.7 smd: 7(1.125,1.4) 8(0.675,1.4) 9(0.225,1.4) 10(-0.225,1.4) 11(-0.675,1.4) 12(-1.125,1.4)
NB_QFN20_3X3X0D8
  rect 0.8x0.2 smd: 1(-1.5,0.8) 2(-1.5,0.4) 3(-1.5,0) 4(-1.5,-0.4) 5(-1.5,-0.8) 11(1.5,-0.8) 12(1.5,-0.4) 13(1.5,0) 14(1.5,0.4) 15(1.5,0.8)
  rect 0.2x0.8 smd: 6(-0.8,-1.5) 7(-0.4,-1.5) 8(0,-1.5) 9(0.4,-1.5) 10(0.8,-1.5) 16(0.8,1.5) 17(0.4,1.5) 18(0,1.5) 19(-0.4,1.5) 20(-0.8,1.5)
  rect 1.7x1.7 smd: 21(0,0)
NB_QFN20_3X3X0D9_0D45_SY8286
  custom 0.062x0.062 smd: 1(-1.45,0.9) 5(-1.45,-0.9) 6(-0.9,-1.45) 10(0.9,-1.45) 11(1.45,-0.9) 15(1.45,0.9) 16(0.9,1.45) 20(-0.9,1.45)
  rect 0.8x0.25 smd: 2(-1.45,0.45) 3(-1.45,0) 4(-1.45,-0.45) 12(1.45,-0.45) 13(1.45,0) 14(1.45,0.45)
  rect 0.25x0.8 smd: 7(-0.45,-1.45) 8(0,-1.45) 9(0.45,-1.45) 17(0.45,1.45) 18(0,1.45) 19(-0.45,1.45)
  rect 1.1x1.1 smd: 21(0,0)
NB_QFN32_4X4X0D8
  rect 0.8x0.2 smd: 1(-2,1.4) 2(-2,1) 3(-2,0.6) 4(-2,0.2) 5(-2,-0.2) 6(-2,-0.6) 7(-2,-1) 8(-2,-1.4) 17(2,-1.4) 18(2,-1) 19(2,-0.6) 20(2,-0.2) 21(2,0.2) 22(2,0.6) 23(2,1) 24(2,1.4)
  rect 0.2x0.8 smd: 9(-1.4,-2) 10(-1,-2) 11(-0.6,-2) 12(-0.2,-2) 13(0.2,-2) 14(0.6,-2) 15(1,-2) 16(1.4,-2) 25(1.4,2) 26(1,2) 27(0.6,2) 28(0.2,2) 29(-0.2,2) 30(-0.6,2) 31(-1,2) 32(-1.4,2)
  rect 2.8x2.8 smd: 33(0,0)
NB_QFN32_4X4X1
  custom 0.05x0.05 smd: 1(-1.9,1.4) 8(-1.9,-1.4) 9(-1.4,-1.9) 16(1.4,-1.9) 17(1.9,-1.4) 24(1.9,1.4) 25(1.4,1.9) 32(-1.4,1.9)
  rect 0.6x0.2 smd: 2(-1.9,1) 3(-1.9,0.6) 4(-1.9,0.2) 5(-1.9,-0.2) 6(-1.9,-0.6) 7(-1.9,-1) 18(1.9,-1) 19(1.9,-0.6) 20(1.9,-0.2) 21(1.9,0.2) 22(1.9,0.6) 23(1.9,1)
  rect 0.2x0.6 smd: 10(-1,-1.9) 11(-0.6,-1.9) 12(-0.2,-1.9) 13(0.2,-1.9) 14(0.6,-1.9) 15(1,-1.9) 26(1,1.9) 27(0.6,1.9) 28(0.2,1.9) 29(-0.2,1.9) 30(-0.6,1.9) 31(-1,1.9)
  rect 2.7x2.7 smd: 33(0,0)
NB_QFN32_5X5X0D8_0D5_NPCT75X
  rect 0.8x0.25 smd: 1(-2.5,1.75) 2(-2.5,1.25) 3(-2.5,0.75) 4(-2.5,0.25) 5(-2.5,-0.25) 6(-2.5,-0.75) 7(-2.5,-1.25) 8(-2.5,-1.75) 17(2.5,-1.75) 18(2.5,-1.25) 19(2.5,-0.75) 20(2.5,-0.25) 21(2.5,0.25) 22(2.5,0.75) 23(2.5,1.25) 24(2.5,1.75)
  rect 0.25x0.8 smd: 9(-1.75,-2.5) 10(-1.25,-2.5) 11(-0.75,-2.5) 12(-0.25,-2.5) 13(0.25,-2.5) 14(0.75,-2.5) 15(1.25,-2.5) 16(1.75,-2.5) 25(1.75,2.5) 26(1.25,2.5) 27(0.75,2.5) 28(0.25,2.5) 29(-0.25,2.5) 30(-0.75,2.5) 31(-1.25,2.5) 32(-1.75,2.5)
  rect 3.5x3.5 smd: 33(0,0)
NB_QFN40_6X6X0D6_0D5
  rect 0.8x0.25 smd: 1(-3,2.25) 2(-3,1.75) 3(-3,1.25) 4(-3,0.75) 5(-3,0.25) 6(-3,-0.25) 7(-3,-0.75) 8(-3,-1.25) 9(-3,-1.75) 10(-3,-2.25) 21(3,-2.25) 22(3,-1.75) 23(3,-1.25) 24(3,-0.75) 25(3,-0.25) 26(3,0.25) 27(3,0.75) 28(3,1.25) 29(3,1.75) 30(3,2.25)
  rect 0.25x0.8 smd: 11(-2.25,-3) 12(-1.75,-3) 13(-1.25,-3) 14(-0.75,-3) 15(-0.25,-3) 16(0.25,-3) 17(0.75,-3) 18(1.25,-3) 19(1.75,-3) 20(2.25,-3) 31(2.25,3) 32(1.75,3) 33(1.25,3) 34(0.75,3) 35(0.25,3) 36(-0.25,3) 37(-0.75,3) 38(-1.25,3) 39(-1.75,3) 40(-2.25,3)
  rect 4.6x4.6 smd: 41(0,0)
NB_QFN48_6X6X0D9_0D4
  rect 0.85x0.22 smd: 1(-3,2.2) 2(-3,1.8) 3(-3,1.4) 4(-3,1) 5(-3,0.6) 6(-3,0.2) 7(-3,-0.2) 8(-3,-0.6) 9(-3,-1) 10(-3,-1.4) 11(-3,-1.8) 12(-3,-2.2) 25(3,-2.2) 26(3,-1.8) 27(3,-1.4) 28(3,-1) 29(3,-0.6) 30(3,-0.2) 31(3,0.2) 32(3,0.6) 33(3,1) 34(3,1.4) 35(3,1.8) 36(3,2.2)
  rect 0.22x0.85 smd: 13(-2.2,-3) 14(-1.8,-3) 15(-1.4,-3) 16(-1,-3) 17(-0.6,-3) 18(-0.2,-3) 19(0.2,-3) 20(0.6,-3) 21(1,-3) 22(1.4,-3) 23(1.8,-3) 24(2.2,-3) 37(2.2,3) 38(1.8,3) 39(1.4,3) 40(1,3) 41(0.6,3) 42(0.2,3) 43(-0.2,3) 44(-0.6,3) 45(-1,3) 46(-1.4,3) 47(-1.8,3) 48(-2.2,3)
  rect 4.5x4.5 smd: 49(0,0)
NB_QFN60_7X7X0D9
  rect 0.6x0.25 smd: 1(-3.4,2.8) 2(-3.4,2.4) 3(-3.4,2) 4(-3.4,1.6) 5(-3.4,1.2) 6(-3.4,0.8) 7(-3.4,0.4) 8(-3.4,0) 9(-3.4,-0.4) 10(-3.4,-0.8) 11(-3.4,-1.2) 12(-3.4,-1.6) 13(-3.4,-2) 14(-3.4,-2.4) 15(-3.4,-2.8) 31(3.403,-2.8) 32(3.403,-2.4) 33(3.403,-2) 34(3.403,-1.6) 35(3.403,-1.2) 36(3.403,-0.8) 37(3.403,-0.4) 38(3.403,0) 39(3.403,0.4) 40(3.403,0.8) 41(3.403,1.2) 42(3.403,1.6) 43(3.403,2) 44(3.403,2.4) 45(3.403,2.8)
  rect 0.25x0.6 smd: 16(-2.8,-3.4) 17(-2.4,-3.4) 18(-2,-3.4) 19(-1.6,-3.4) 20(-1.2,-3.4) 21(-0.8,-3.4) 22(-0.4,-3.4) 23(0,-3.4) 24(0.4,-3.4) 25(0.8,-3.4) 26(1.2,-3.4) 27(1.6,-3.4) 28(2,-3.4) 29(2.4,-3.4) 30(2.8,-3.4) 46(2.8,3.4) 47(2.4,3.4) 48(2,3.4) 49(1.6,3.4) 50(1.2,3.4) 51(0.8,3.4) 52(0.4,3.4) 53(0,3.4) 54(-0.4,3.4) 55(-0.8,3.4) 56(-1.2,3.4) 57(-1.6,3.4) 58(-2,3.4) 59(-2.4,3.4) 60(-2.8,3.4)
  rect 5.5x5.5 smd: 61(0,0)
NB_RTC0805
  rect 1.016x1.27 smd: 1(-0.889,0) 2(0.889,0)
  rect 0.26x0.26 smd: 3(-0.511,0) 4(0.511,0)
NB_RTC1206_0D9
  rect 1.3x1.6 smd: 1(-1.35,0) 2(1.35,0)
  rect 0.26x0.26 smd: 3(-0.83,0) 4(0.83,0)
NB_SOD962_0D625X0D325X0D32
  rect 0.254x0.254 smd: 1(-0.225,0) 2(0.225,0)
NB_SOD-923_2_0D8X0D6X0D43
  rect 0.4x0.5 smd: 1(-0.45,0) 2(0.45,0)
NB_SOIC-208-8_5D33X5D33X2D16
  rect 0.7x1.75 smd: 1(-1.905,-3.4) 2(-0.635,-3.4) 3(0.635,-3.4) 4(1.905,-3.4) 5(1.905,3.4) 6(0.635,3.4) 7(-0.635,3.4) 8(-1.905,3.4)
NB_SON5_3D1X3D1X0D9
  rect 0.35x0.5 smd: 1(-0.975,-1.4) 2(-0.325,-1.4) 3(0.325,-1.4) 4(0.975,-1.4)
  custom 0.57x0.57 smd: 5(0,0)
NB_SOP8_5D38X5D33X2D16
  rect 0.65x1.75 smd: 1(-1.905,-3.295) 2(-0.635,-3.295) 3(0.635,-3.295) 4(1.905,-3.295) 5(1.905,3.295) 6(0.635,3.295) 7(-0.635,3.295) 8(-1.905,3.295)
NB_SOT23-3_2D9X1D83X1D2
  rect 0.8x1 smd: 1(-0.95,-1.001) 2(0.95,-1.001) 3(0,0.998)
NB_SOT23-5_2X1D25X1D1
  rect 0.35x0.7 smd: 1(-0.65,-0.95) 2(0,-0.95) 3(0.65,-0.95) 4(0.65,0.95) 5(-0.65,0.95)
NB_SOT23-5_3D7X1D8X1D47
  rect 1.27x0.66 smd: 1(-1.27,0.94) 2(-1.27,0) 3(-1.27,-0.965) 4(1.27,-0.965) 5(1.27,0.94)
NB_SOT23_5_2D95X1D6X1D4
  rect 0.8x0.55 smd: 1(-1.2,0.95) 2(-1.2,0) 3(-1.2,-0.95) 4(1.2,-0.95) 5(1.2,0.95)
NB_SOT23_6_2D9X1D6X1D45
  rect 1.45x0.5 smd: 1(-1.289,0.94) 2(-1.289,0) 3(-1.289,-0.94) 4(1.289,-0.94) 5(1.289,0) 6(1.289,0.94)
NB_SOT323_2D4X2D2X1
  rect 0.6x0.8 smd: 1(-0.65,-0.951) 2(0.65,-0.951) 3(0,0.949)
NB_SOT353_2X1D25X1D1
  rect 0.35x0.7 smd: 1(-0.65,-0.95) 2(0,-0.95) 3(0.65,-0.95) 4(0.65,0.95) 5(-0.65,0.95)
NB_SOT363_2X1D25X1D1
  rect 0.3x0.6 smd: 1(-0.65,-0.95) 2(0,-0.95) 3(0.65,-0.95) 4(0.65,0.95) 5(0,0.95) 6(-0.65,0.95)
NB_SOT883_1D05X0D65X0D53
  rect 0.2x0.3 smd: 1(-0.17,-0.32) 2(0.17,-0.32)
  rect 0.54x0.32 smd: 3(0,0.32)
NB_SOT-23_3_2D9X1D3X1D11
  rect 0.8x0.9 smd: 1(0.95,1) 2(-0.95,1) 3(0,-1)
NB_SOT-723_3_1D2X0D8X0D55
  rect 0.5x0.4 smd: 1(0.5,-0.4) 2(0.5,0.4)
  rect 0.5x0.5 smd: 3(-0.5,0)
NB_SW3_3D4X3X4
  round 1.45 hole 1.45 unplated: (0,0)
  rect 0.7x1.2 smd: 1(0.75,2.125) 2(-0.75,2.125) 3(0,-2.125)
NB_SW4_4D5X3D2X2D6
  rect 1.4x0.825 smd: 1(-2,1.088) 2(2,1.088) 3(-2,-1.088) 4(2,-1.088)
NB_SW4_5D2X5D2X1D7
  rect 1.8x1.1 smd: 1(-3.1,1.85) 2(3.1,1.85) 3(-3.1,-1.85) 4(3.1,-1.85)
NB_TDF14_3X2X0D8
  rect 0.2x0.7 smd: 1(-1.2,-1) 2(-0.8,-1) 3(-0.4,-1) 4(0,-1) 5(0.4,-1) 6(0.8,-1) 7(1.2,-1) 8(1.2,1) 9(0.8,1) 10(0.4,1) 11(0,1) 12(-0.4,1) 13(-0.8,1) 14(-1.2,1)
  rect 2.5x0.8 smd: 15(0,0)
NB_TSOT23-5_2D9X1D6X0D9
  rect 0.6x1 smd: 1(-0.95,-1.35) 2(0,-1.35) 3(0.95,-1.35) 4(0.95,1.35) 5(-0.95,1.35)
NB_TSOT23_3_2D92X1D65X0D9
  rect 0.7x1 smd: 1(-0.975,-1.163) 2(0.975,-1.163) 3(0,1.163)
NB_TSOT23_6_3D1X1D7X1
  rect 0.6x1 smd: 1(-0.95,-1.2) 2(0,-1.2) 3(0.95,-1.2) 4(0.95,1.2) 5(0,1.2) 6(-0.95,1.2)
NB_TYPE_C24_8D94X8D45X3D74
  round 0.6 hole 0.6 unplated: (-3.6,-2)
  oval 0.85x0.5 hole 0.85x0.5 unplated: (3.6,-2.001)
  oval 1.2x2.3 hole 0.6x1.9: 1(-4.32,0) 3(4.32,0)
  oval 1.6x1.1 hole 1.25x0.7: 2(-4.07,-0.56) 4(4.07,-0.56)
  oval 1.3x2.6 hole 0.7x2: 5(-4.317,-5.052) 6(4.318,-5.052)
  rect 0.27x0.9 smd: A1(-2.625,0.7) A2(-2.125,0.7) A3(-1.625,0.7) A4(-1.125,0.7) A5(-0.625,0.7) A6(-0.125,0.7) A7(0.375,0.7) A8(0.875,0.7) A9(1.375,0.7) A10(1.875,0.7) A11(2.375,0.7) A12(2.875,0.7)
  rect 0.27x0.8 smd: B1(2.625,-0.9) B2(2.125,-0.9) B3(1.625,-0.9) B4(1.125,-0.9) B5(0.625,-0.9) B6(0.125,-0.9) B7(-0.375,-0.9) B8(-0.875,-0.9) B9(-1.375,-0.9) B10(-1.875,-0.9) B11(-2.375,-0.9) B12(-2.875,-0.9)
NB_USB9_16D37X13D1X7
  round 1.3 hole 0.7: 1(3.5,1.5) 2(1,1.5) 3(-1,1.5) 4(-3.5,1.5) 5(-4,0) 6(-2,0) 7(0,0) 8(2,0) 9(4,0)
  oval 1.4x3.2 hole 0.8x2.6: 10(7.85,-0.88) 11(-7.85,-0.88)
  oval 1.4x2.5 hole 0.8x1.9: 12(7.85,-7.98) 13(-7.85,-7.98)
NB_VQFN18_3X3X1
  custom 0.145x0.145 smd: 1(-1.4,1.25) 6(-1.4,-1.25) 10(1.4,-1.25) 15(1.4,1.25)
  rect 0.6x0.25 smd: 2(-1.4,0.75) 3(-1.4,0.25) 4(-1.4,-0.25) 5(-1.4,-0.75) 11(1.4,-0.75) 12(1.4,-0.25) 13(1.4,0.25) 14(1.4,0.75)
  rect 0.2x2.238 smd: 7(-0.45,-0.646) 9(0.45,-0.646)
  rect 0.2x0.7 smd: 8(0,-1.415) 16(0.65,1.415) 18(-0.65,1.415)
  rect 0.2x2.243 smd: 17(0,0.644)
NB_XTAL4_2D05X1D65X0D8
  rect 0.9x0.8 smd: 1(-0.7,-0.55) 2(0.7,-0.55) 3(0.7,0.55) 4(-0.7,0.55)
NB_XTAL4_3D2X2D5X0D8
  rect 1.4x1.2 smd: 1(-1.1,-0.848) 2(1.1,-0.848) 3(1.1,0.848) 4(-1.1,0.848)
QFN16_3X3X0D65_0D5
  rect 0.3x0.7 smd: 1(-0.76,-1.45) 2(-0.26,-1.45) 3(0.24,-1.45) 4(0.74,-1.45) 9(0.74,1.45) 10(0.24,1.45) 11(-0.26,1.45) 12(-0.76,1.45)
  rect 0.7x0.3 smd: 5(1.45,-0.75) 6(1.45,-0.25) 7(1.45,0.25) 8(1.45,0.75) 13(-1.45,0.75) 14(-1.45,0.25) 15(-1.45,-0.25) 16(-1.45,-0.75)
  rect 1.6x1.6 smd: 17(0,0)
R0201
  rect 0.305x0.305 smd: 1(-0.254,0) 2(0.254,0)
R0402
  rect 0.5x0.55 smd: 1(-0.394,0) 2(0.394,0)
R0402_0D65
  rect 0.5x0.55 smd: 1(-0.394,0) 2(0.394,0)
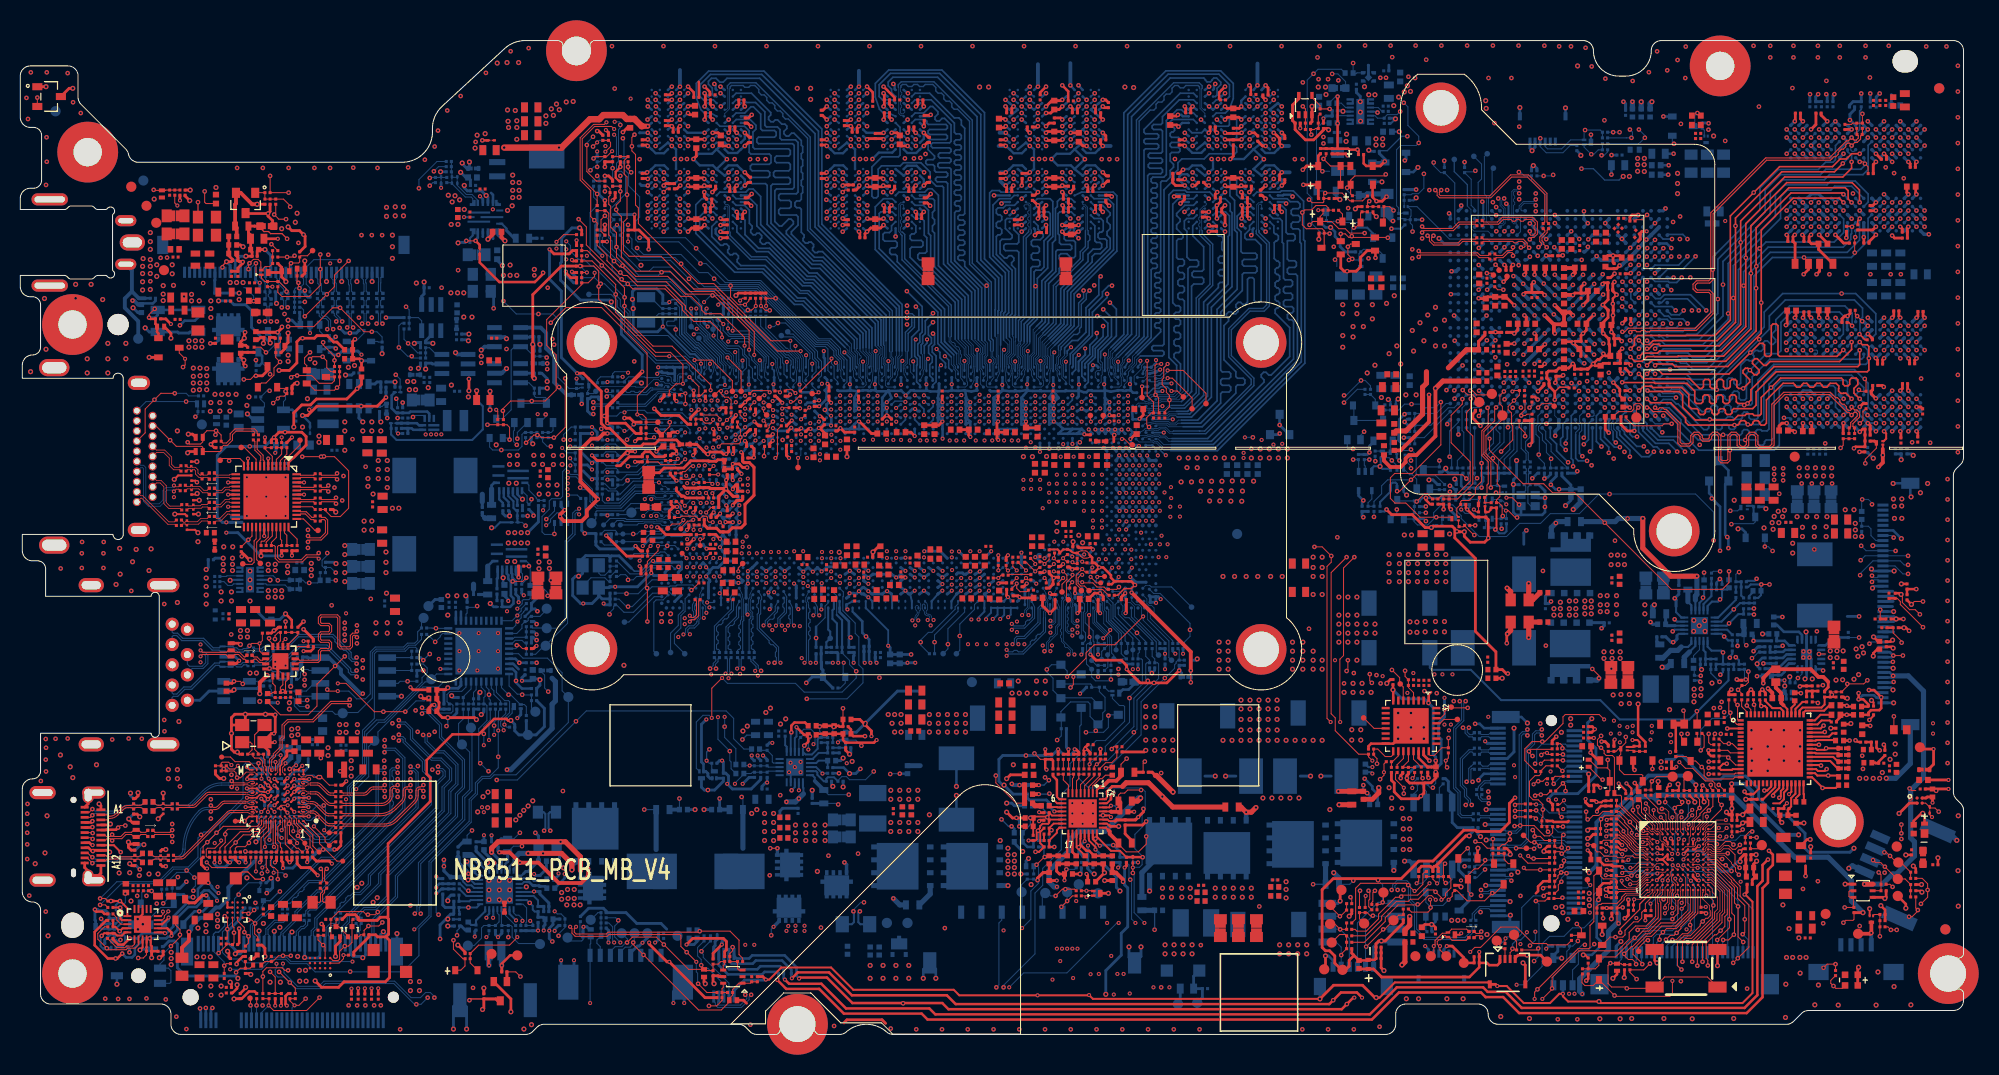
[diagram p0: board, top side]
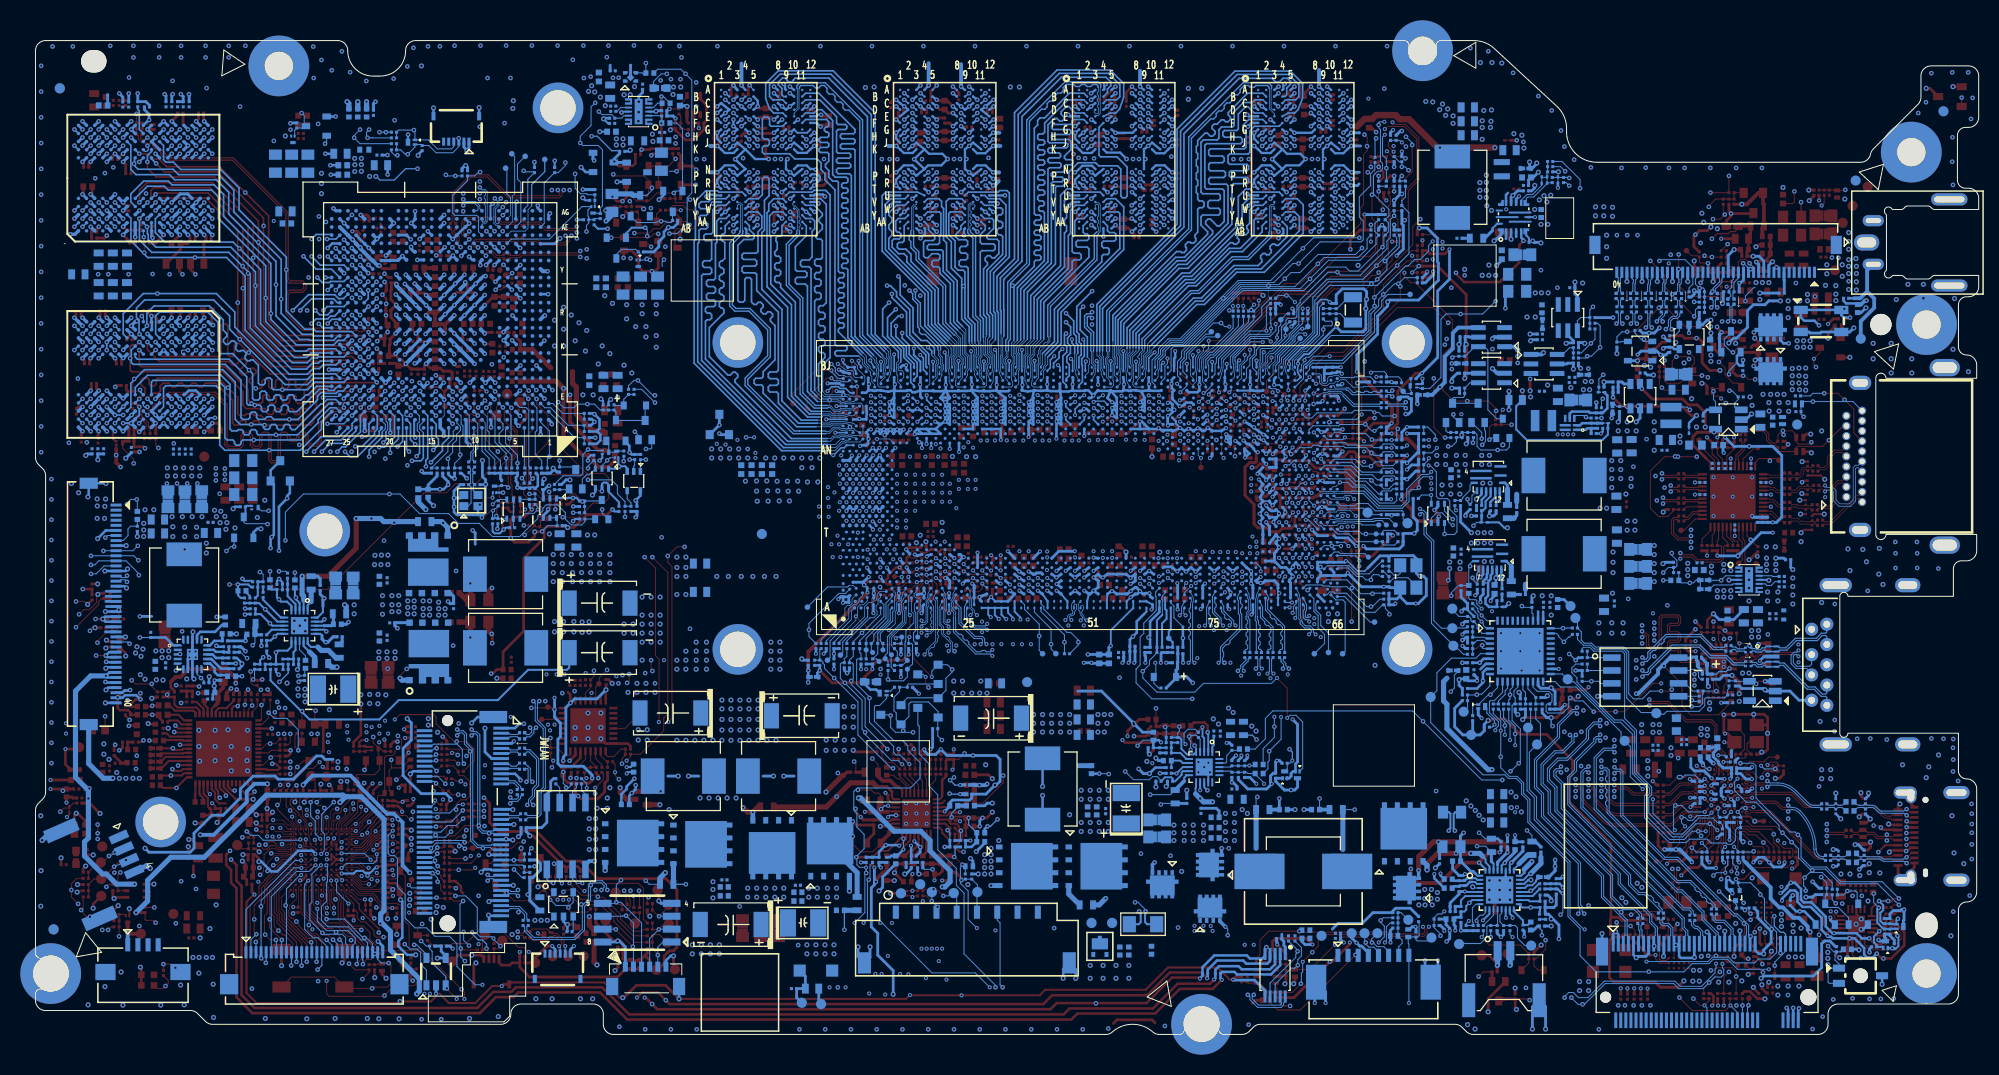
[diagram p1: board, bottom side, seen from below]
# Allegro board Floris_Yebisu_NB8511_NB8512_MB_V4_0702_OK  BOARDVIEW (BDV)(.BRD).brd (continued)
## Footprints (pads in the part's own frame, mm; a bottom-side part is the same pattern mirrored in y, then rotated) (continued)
R0402_NTC_0D55
  rect 0.5x0.55 smd: 1(-0.394,0) 2(0.394,0)
R0402_NTC_0D65
  rect 0.5x0.55 smd: 1(-0.394,0) 2(0.394,0)
R0603
  rect 0.58x0.9 smd: 1(-0.66,0) 2(0.66,0)
R0603_1
  rect 0.58x0.9 smd: 1(-0.66,0) 2(0.66,0)
R0805
  rect 1.016x1.27 smd: 1(-0.889,0) 2(0.889,0)
SHUNT_0201
  custom 0.062x0.062 smd: 1(-0.267,0) 2(0.267,0)
SHUNT_0402
  custom 0.127x0.127 smd: 1(0,0) 2(0,-0.766)
SHUNT_0603
  custom 0.191x0.191 smd: 1(0,0) 2(0,-1.15)
SHUNT_0805
  custom 0.318x0.318 smd: 1(-0.7,0) 2(0.7,0)
SOT-23_3_2D9X1D3X1D11
  rect 0.599x0.851 smd: 1(0.95,1.026) 2(-0.95,1.026) 3(0,-1.026)
SOT-323_3_2X1D25X1
  rect 0.65x0.9 smd: 1(0.65,0.95) 2(-0.65,0.95)
  rect 0.7x0.9 smd: 3(0,-0.95)
TPAD22-OP
  round 0.559 smd: 1(0,0)
TPAD40-OP
  round 1.016 smd: 1(0,0)
TPC1
  round 1 smd: 1(0,0)
TVS2_1D01X0D61X0D4
  rect 0.4x0.6 smd: 1(-0.35,0) 2(0.35,0)
TVS2_1D02X0D585X0D5
  rect 0.4x0.7 smd: 1(-0.35,0) 2(0.35,0)
TVS2_1X0D5X0D6
  rect 0.45x0.6 smd: 1(-0.375,0) 2(0.375,0)
TVS_1X0D6X0D55
  rect 0.4x0.5 smd: 1(-0.45,0) 2(0.45,0)
unnamed
  oval 2.2x2.5 hole 2.2x2.5 unplated: (0,0)
unnamed#2
  round 1.016 smd: 1(0,0)
XTAL2_3D2X1D5X0D9
  rect 1x1.8 smd: 1(-1.25,0) 2(1.25,0)
XTAL4_3D2X2D5X0D8
  rect 1.4x1.2 smd: 1(-1.1,-0.8) 2(1.1,-0.8) 3(1.1,0.8) 4(-1.1,0.8)

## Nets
1.0VGS_EN_N: QV17.1(G) QV19.3 RV85.1
1.35VGS_BOOT: PC1101.1 PU1101.1(BS)
1.35VGS_BYP: PC1108.1 PR1104.1 PU1101.15(BYP)
1.35VGS_EN: PC1107.1 PR1101.2 PU1101.11(EN)
1.35VGS_FB: PC1150.1 PR1108.2 PR1109.2 PU1101.14(FB)
1.35VGS_ILMT: PR1102.1 PR1103.2 PU1101.13(ILMT)
1.35VGS_IN: PC1103.1 PC1104.1 PC1105.1 PC1106.1 PSH1103.2(B[0]) PU1101.2(VIN1) PU1101.3(VIN2) PU1101.4(VIN3) PU1101.5(VIN4)
1.35VGS_MODE: PR1107.1 PR1111.2 PU1101.12(MODE)
1.35VGS_PG: CV199.1 DV11.1(ANODE) PR1105.1 PU1101.9(PG)
1.35VGS_PHASE: PC1101.2 PL1101.1 PU1101.6(LX1) PU1101.19(LX2) PU1101.20(LX3)
1.35VGS_VCC: PC1102.1 PU1101.17(VCC)
1V8_3V3_MAINEN: QV6.2(G1) RV25.1 UV2.F9(GPIO4)
1V8MAINEN_33: DV3.1 DV5.1(ANODE) DV8.1(ANODE) PR1.2 QV6.3(D1) RV45.1
5V_VCC: PC214.1 PU201.9(VCC)
+1.0VGS: CV1.1 CV2.1 CV3.1 CV4.1 CV5.1 CV15.2 CV16.1 CV207.1 CV208.1 PC1203.1 PC1215.1 PU1202.1(VOUT) RV83.2 RV84.2 RV86.2 UV2.AA22(PEX_DVDD_1) UV2.AB23(PEX_DVDD_2) UV2.AC24(PEX_DVDD_3) UV2.AD25(PEX_DVDD_4) UV2.AE26(PEX_DVDD_5) UV2.AE27(PEX_DVDD_6)
+1.0VGS_EN: CV34.1 DV8.3 DV14.2 PR1203.1 QV19.1 RV22.2 RV23.1
+1.35VGS: +1.35VGS1.1(A) CV49.1 CV50.1 CV51.1 CV52.1 CV53.2 CV54.2 CV55.2 CV56.2 CV57.1 CV58.1 CV59.1 CV60.1 CV61.2 CV62.2 CV63.2 CV64.2 CV122.1 CV123.1 CV124.2 CV125.2 CV126.2 CV127.2 CV128.2 CV129.2 CV130.2 CV131.2 CV132.1 CV133.1 CV134.1 CV135.1 CV136.1 CV137.1 CV138.1 CV139.2 CV140.2 CV141.2 CV142.2 CV143.2 CV144.2 CV145.1 CV146.1 CV147.2 CV148.2 CV149.2 CV150.2 CV151.2 CV152.2 CV153.2 CV154.2 CV155.1 CV156.1 CV157.1 CV158.1 CV159.1 CV160.2 CV161.2 CV162.2 CV163.2 CV164.2 CV165.2 CV166.2 CV167.2 CV168.2 CV169.2 CV170.1 CV171.1 CV174.2 CV175.2 CV176.2 CV177.2 CV178.1 CV179.1 PSH1101.2(B[0]) PSH1102.2(B[0]) PSH1104.2(B[0]) RV66.2 RV70.2 RV74.2 RV75.2 RV90.2 RV91.2 RV94.2 RV95.2 RV101.2 RV141.1 UV2.B26(FBVDDQ_01) UV2.C25(FBVDDQ_02) UV2.E23(FBVDDQ_03) UV2.E26(FBVDDQ_04) UV2.F14(FBVDDQ_05) UV2.F21(FBVDDQ_06) UV2.G13(FBVDDQ_07) UV2.G14(FBVDDQ_08) UV2.G15(FBVDDQ_09) UV2.G16(FBVDDQ_10) UV2.G18(FBVDDQ_11) UV2.G19(FBVDDQ_12) UV2.G20(FBVDDQ_13) UV2.G21(FBVDDQ_14) UV2.H24(FBVDDQ_15) UV2.H26(FBVDDQ_16) UV2.J21(FBVDDQ_17) UV2.K21(FBVDDQ_18) UV2.L22(FBVDDQ_19) UV2.L24(FBVDDQ_20) UV2.L26(FBVDDQ_21) UV2.M21(FBVDDQ_22) UV2.N21(FBVDDQ_23) UV2.R21(FBVDDQ_24) UV2.T21(FBVDDQ_25) UV2.V21(FBVDDQ_26) UV2.W21(FBVDDQ_27) UV3.B1(VDDQ1) UV3.B3(VDDQ9) UV3.B12(VDDQ21) UV3.B14(VDDQ31) UV3.C5(VDD5) UV3.C10(VDD7) UV3.D1(VDDQ2) UV3.D3(VDDQ10) UV3.D11(VDD9) UV3.D12(VDDQ22) UV3.D14(VDDQ32) UV3.E5(VDDQ17) UV3.E10(VDDQ19) UV3.F1(VDDQ3) UV3.F3(VDDQ11) UV3.F12(VDDQ23) UV3.F14(VDDQ33) UV3.G1(VDD1) UV3.G2(VDDQ7) UV3.G4(VDD3) UV3.G11(VDD10) UV3.G13(VDDQ29) UV3.G14(VDD13) UV3.H3(VDDQ12) UV3.H12(VDDQ24) UV3.K3(VDDQ13) UV3.K12(VDDQ25) UV3.L1(VDD2) UV3.L2(VDDQ8) UV3.L4(VDD4) UV3.L11(VDD11) UV3.L13(VDDQ30) UV3.L14(VDD14) UV3.M1(VDDQ4) UV3.M3(VDDQ14) UV3.M12(VDDQ26) UV3.M14(VDDQ34) UV3.N5(VDDQ18) UV3.N10(VDDQ20) UV3.P1(VDDQ5) UV3.P3(VDDQ15) UV3.P11(VDD12) UV3.P12(VDDQ27) UV3.P14(VDDQ35) UV3.R5(VDD6) UV3.R10(VDD8) UV3.T1(VDDQ6) UV3.T3(VDDQ16) UV3.T12(VDDQ28) UV3.T14(VDDQ36) UV4.B1(VDDQ1) UV4.B3(VDDQ9) UV4.B12(VDDQ21) UV4.B14(VDDQ31) UV4.C5(VDD5) UV4.C10(VDD7) UV4.D1(VDDQ2) UV4.D3(VDDQ10) UV4.D11(VDD9) UV4.D12(VDDQ22) UV4.D14(VDDQ32) UV4.E5(VDDQ17) UV4.E10(VDDQ19) UV4.F1(VDDQ3) UV4.F3(VDDQ11) UV4.F12(VDDQ23) UV4.F14(VDDQ33) UV4.G1(VDD1) UV4.G2(VDDQ7) UV4.G4(VDD3) UV4.G11(VDD10) UV4.G13(VDDQ29) UV4.G14(VDD13) UV4.H3(VDDQ12) UV4.H12(VDDQ24) UV4.K3(VDDQ13) UV4.K12(VDDQ25) UV4.L1(VDD2) UV4.L2(VDDQ8) UV4.L4(VDD4) UV4.L11(VDD11) UV4.L13(VDDQ30) UV4.L14(VDD14) UV4.M1(VDDQ4) UV4.M3(VDDQ14) UV4.M12(VDDQ26) UV4.M14(VDDQ34) UV4.N5(VDDQ18) UV4.N10(VDDQ20) UV4.P1(VDDQ5) UV4.P3(VDDQ15) UV4.P11(VDD12) UV4.P12(VDDQ27) UV4.P14(VDDQ35) UV4.R5(VDD6) UV4.R10(VDD8) UV4.T1(VDDQ6) UV4.T3(VDDQ16) UV4.T12(VDDQ28) UV4.T14(VDDQ36)
+1.35VGS_OUT: PC1109.1 PC1110.1 PC1120.1 PC1121.1 PC1122.1 PC1123.1 PC1124.1 PC11258.1 PL1101.2 PR1109.1 PR1150.2 PSH1101.1(A[0]) PSH1102.1(A[0]) PSH1104.1(A[0])
+AVCC: CE36.1 CE37.1 FBE2.2 RE33.2 UE1.E9(AVCC)
+V1P0S_VCCST: CU40.1 CU97.1 CU98.1 QU7.3(D) RU21.2 RU24.1 RU162.1 RU182.2 RU183.2 RU184.2 SHU1.2(B[0]) UU1.CB1(VCCST)
+V1P1U_VDDQ: CD2.1 CD6.1 CD10.1 CD14.1 CD18.2 CD19.2 CD20.2 CD21.2 CD22.2 CD23.2 CD24.2 CD25.2 CD26.1 CD27.1 CD28.2 CD29.2 CD30.2 CD31.2 CD32.2 CD33.2 CD34.2 CD35.2 CD36.1 CD37.1 CD66.2 CD67.2 CD68.2 CD69.2 CD70.2 CD71.2 CD72.2 CD73.2 CD74.1 CD75.2 CD76.2 CD77.2 CD78.2 CD79.2 CD80.2 CD81.2 CD82.2 CD83.1 PC708.1 PC709.1 PC710.1 PC711.1 PC712.1 PC714.1 PC715.1 PC906.1 PL701.2 PR905.1 PSH708.1(A[0]) PU701.1(VLDOIN) PU906.2(VIN) RD3.2 RD4.2 RD5.2 RD6.2 RD7.2 RD8.2 RD9.2 RD10.2 RD11.1 SHU6.1(A[0]) SHU7.1(A[0]) UD1.A4(VDD2_24) UD1.A9(VDD2_23) UD1.AB4(VDD2_22) UD1.AB9(VDD2_21) UD1.F5(VDD2_20) UD1.F8(VDD2_19) UD1.G2(ODT_CA_A) UD1.H1(VDD2_18) UD1.H5(VDD2_17) UD1.H8(VDD2_16) UD1.H12(VDD2_15) UD1.K1(VDD2_14) UD1.K3(VDD2_13) UD1.K10(VDD2_12) UD1.K12(VDD2_11) UD1.N1(VDD2_10) UD1.N3(VDD2_9) UD1.N10(VDD2_8) UD1.N12(VDD2_7) UD1.R1(VDD2_6) UD1.R5(VDD2_5) UD1.R8(VDD2_4) UD1.R12(VDD2_3) UD1.T2(ODT_CA_B) UD1.U5(VDD2_2) UD1.U8(VDD2_1) UD2.A4(VDD2_24) UD2.A9(VDD2_23) UD2.AB4(VDD2_22) UD2.AB9(VDD2_21) UD2.F5(VDD2_20) UD2.F8(VDD2_19) UD2.G2(ODT_CA_A) UD2.H1(VDD2_18) UD2.H5(VDD2_17) UD2.H8(VDD2_16) UD2.H12(VDD2_15) UD2.K1(VDD2_14) UD2.K3(VDD2_13) UD2.K10(VDD2_12) UD2.K12(VDD2_11) UD2.N1(VDD2_10) UD2.N3(VDD2_9) UD2.N10(VDD2_8) UD2.N12(VDD2_7) UD2.R1(VDD2_6) UD2.R5(VDD2_5) UD2.R8(VDD2_4) UD2.R12(VDD2_3) UD2.T2(ODT_CA_B) UD2.U5(VDD2_2) UD2.U8(VDD2_1) UD3.A4(VDD2_24) UD3.A9(VDD2_23) UD3.AB4(VDD2_22) UD3.AB9(VDD2_21) UD3.F5(VDD2_20) UD3.F8(VDD2_19) UD3.G2(ODT_CA_A) UD3.H1(VDD2_18) UD3.H5(VDD2_17) UD3.H8(VDD2_16) UD3.H12(VDD2_15) UD3.K1(VDD2_14) UD3.K3(VDD2_13) UD3.K10(VDD2_12) UD3.K12(VDD2_11) UD3.N1(VDD2_10) UD3.N3(VDD2_9) UD3.N10(VDD2_8) UD3.N12(VDD2_7) UD3.R1(VDD2_6) UD3.R5(VDD2_5) UD3.R8(VDD2_4) UD3.R12(VDD2_3) UD3.T2(ODT_CA_B) UD3.U5(VDD2_2) UD3.U8(VDD2_1) UD4.A4(VDD2_24) UD4.A9(VDD2_23) UD4.AB4(VDD2_22) UD4.AB9(VDD2_21) UD4.F5(VDD2_20) UD4.F8(VDD2_19) UD4.G2(ODT_CA_A) UD4.H1(VDD2_18) UD4.H5(VDD2_17) UD4.H8(VDD2_16) UD4.H12(VDD2_15) UD4.K1(VDD2_14) UD4.K3(VDD2_13) UD4.K10(VDD2_12) UD4.K12(VDD2_11) UD4.N1(VDD2_10) UD4.N3(VDD2_9) UD4.N10(VDD2_8) UD4.N12(VDD2_7) UD4.R1(VDD2_6) UD4.R5(VDD2_5) UD4.R8(VDD2_4) UD4.R12(VDD2_3) UD4.T2(ODT_CA_B) UD4.U5(VDD2_2) UD4.U8(VDD2_1)
+V1P2_HDMI: FBI5.1 PC410.1 PC413.1 PC414.1 PC1205.1 PL402.2 PSH402.2(B[0]) PU1202.4(VIN)
+V1P2S_HDMI: CI105.2 CI106.1 CI107.1 CI108.1 CI109.1 CI110.1 CI111.1 CI112.1 CI113.2 CI114.2 CI119.2 FBI5.2 UI2.6(VDD12_1) UI2.11(VDDA12) UI2.15(VDDTX12_1) UI2.18(VDDTX12_2) UI2.30(VDD12_2) UI2.43(VDDRX12_1) UI2.46(VDDRX12_2)
+V1P05A_BYPASS_R: RU192.2 UU1.DJ15(VCC_V1P05EXT_1P05)
+V1P8_AON_EN_N: QV11.1 QV14.3 RV78.1
+V1P8_V3P3_AON: CV17.1 CV36.2 CV109.1 CV110.1 CV111.2 CV112.1 CV204.1 PC1201.1 PC1208.1 PC1212.1 PR1204.1 PU1201.1(IN1_1) PU1201.2(IN1_2) PU1201.8(OUT2_1) PU1201.9(OUT2_2) QV5.1(G) RV9.2 RV17.1 RV19.2 RV20.2 RV25.2 RV28.1 RV29.2 RV30.1 RV31.2 RV33.1 RV34.2 RV35.2 RV36.1 RV37.2 RV38.2 RV55.1 RV71.2 RV110.1 RV111.1 RV112.1 RV116.1 RV117.1 RV118.1 RV122.1 RV123.1 RV124.1 RV147.2 UV1.5(VCC) UV2.G10(1V8_AON_1) UV2.G12(1V8_AON_2)
+V1P8_V3P3_MAIN: CV10.2 CV11.1 CV12.1 CV18.2 CV19.2 CV20.2 CV21.1 CV22.1 CV23.1 CV25.1 CV29.1 CV197.1 CV198.1 CV205.1 CV206.1 LV1.1 LV3.1 PC1202.1 PC1204.1 PR1204.2 PU1201.13(OUT1_1) PU1201.14(OUT1_2) RV7.2 RV82.2 RV88.2 UV2.AA8(PEX_PLL_HVDD_1) UV2.AA9(PEX_PLL_HVDD_2) UV2.AA10(PEX_HVDD_1) UV2.AA12(PEX_HVDD_2) UV2.AA13(PEX_HVDD_3) UV2.AA16(PEX_HVDD_4) UV2.AA18(PEX_HVDD_5) UV2.AA19(PEX_HVDD_6) UV2.AA20(PEX_HVDD_7) UV2.AA21(PEX_HVDD_8) UV2.AB22(PEX_HVDD_9) UV2.AC23(PEX_HVDD_10) UV2.AD24(PEX_HVDD_11) UV2.AE25(PEX_HVDD_12) UV2.AF26(PEX_HVDD_13) UV2.AF27(PEX_HVDD_14)
+V1P8A: PC402.1 PC404.1 PC406.1 PC902.1 PC930.1 PC1214.1 PL401.2 PR501.1 PR502.1 PR1207.2(B[0]) PSH401.2(B[0]) PU903.2(VIN) PU910.A2(VIN) RE460.1 RU64.2 RU77.2 RU79.2 RU80.2 RU92.1 RU94.1 RU96.1 RU98.1 RU102.1 RU105.1 RU107.1 RU109.1 RW55.1 RW56.1 SHU3.1(A[0])
+V1P8A_ESPI: CE38.1 RE460.2 UE1.J5(VCC)
+V1P8SX: +V1P8SX.1 FBA1.1 PSH930.2(B[0]) RA233.2 RA236.1
+V1P8U: CD3.1 CD7.1 CD11.1 CD15.1 CD38.2 CD39.2 CD40.2 CD41.2 CD42.1 CD43.1 CD44.2 CD45.2 CD46.2 CD47.2 CD48.1 CD49.1 CD84.2 CD85.2 CD86.2 CD87.2 CD88.1 CD89.2 CD90.2 CD91.2 CD92.2 CD93.1 PC717.1 PC718.1 PL702.2 PSH709.1(A[0]) UD1.F1(VDD1_8) UD1.F12(VDD1_7) UD1.G4(VDD1_6) UD1.G9(VDD1_5) UD1.T4(VDD1_4) UD1.T9(VDD1_3) UD1.U1(VDD1_2) UD1.U12(VDD1_1) UD2.F1(VDD1_8) UD2.F12(VDD1_7) UD2.G4(VDD1_6) UD2.G9(VDD1_5) UD2.T4(VDD1_4) UD2.T9(VDD1_3) UD2.U1(VDD1_2) UD2.U12(VDD1_1) UD3.F1(VDD1_8) UD3.F12(VDD1_7) UD3.G4(VDD1_6) UD3.G9(VDD1_5) UD3.T4(VDD1_4) UD3.T9(VDD1_3) UD3.U1(VDD1_2) UD3.U12(VDD1_1) UD4.F1(VDD1_8) UD4.F12(VDD1_7) UD4.G4(VDD1_6) UD4.G9(VDD1_5) UD4.T4(VDD1_4) UD4.T9(VDD1_3) UD4.U1(VDD1_2) UD4.U12(VDD1_1)
+V1P8VGS_EN: CV31.1 PR1.1 PR1202.1 QV20.1 RV10.1 RV11.1
+V1P8VGS_EN_N: QV18.1 QV20.3 RV87.1
+V3.3DX_RT_TCP1: FBT2.1 UT4.1(OUT)
+V3P3_CAM_CONN: CX284.1 CX887.1 JX1.11 RX900.2 RX901.2 SHX9.2(B[0])
+V3P3_DISPLAY: RX17.2 SHX1.1(A[0]) UX1.1(OUT)
+V3P3_DISPLAY_CONN: CX3.1 CX4.1 CX10.1 CX14.1 CX15.2 JX1.8 JX1.9 SHX1.2(B[0])
+V3P3_DVDD_IO: CA27.1 CA28.1 CA34.1 CA65.1 CA66.1 CA67.1 FBA5.2 RA239.1 UA2.3(HDA_VDDIO) UA2.13(DVDDIO) UA2.19(DVDDIO3) UA2.55(DVDDIO2)
+V3P3_MIC: CX21.2 CX895.1 JX1.10 RX906.1 RX907.1
+V3P3_MIC_DB: CX892.2 CX896.1 JKBL3.6 RX917.1 RX918.1
+V3P3_TOUCH: CE23.1 CE24.1 JE4.1 RE59.1 RE60.1 RE65.1 RE69.1 TP141.1
+V3P3_TPM: CF1.1 CF2.1 CF8.1 CF9.2 RE447.1 RE457.1 RF1.2 RF8.2 RF9.2 RF11.1 UF15.1(VSB)
+V3P3_TS: CX9.2 JX1.7 RX897.1 RX921.1 UX2.1(OUT)
+V3P3_WLAN: CW3.1 CW4.1 CW5.2 CW6.2 CW11.1 CW12.1 CW13.2 CW14.2 JW1.2(3V3[1]) JW1.4(3V3[2]) JW1.72(3V3[3]) JW1.74(3V3[4]) RW9.2 RW24.2 RW58.2 RW59.2 RW67.2 RW69.2 RW72.2 UW1.1(OUT)
+V3P3A: CE52.1 CE53.1 CP1.1 CP2.1 CT54.1 CU33.1 CX13.1 DO1.2 JDB1.6 JP2.1 LEDE2.3 LEDE2.4 PC913.1 PC969.1 PC970.1 PC971.1 PC972.1 PR137.2 PR203.2 PR302.2 PR411.2 PR508.1 PR511.1 PR654.2 PR901.2 PR902.2 PR907.2 PSH203.2(B[0]) PSH204.2(B[0]) PSH205.2(B[0]) PSH404.1(A[0]) PU901.5(VBIAS) PU902.6(IN2_1) PU902.7(IN2_2) PU903.5(VBIAS) PU904.5(VBIAS) PU906.5(VBIAS) RE57.1 RE58.1 RE60.2 RE80.1 RE109.1 RE110.1 RF8.1 RL45.1 RN37.2 RO1.1 RP12.1 RP13.1 RT6.1 RT20.1 RT22.1 RT46.2 RT47.2 RT48.2 RT49.2 RT51.2 RT54.2 RT73.1 RT80.2 RT95.2 RT126.1 RT127.1 RT128.1 RU155.2 RU161.2 RU220.2 RV32.2 RV46.2 RV248.2 RW23.2 RW24.1 RX906.2 RX917.2 SHU4.1(A[0]) SHU5.2(B[0]) UT4.5(IN) UU2.5(VCC) UW1.5(IN) UX1.5(IN)
+V3P3A_EC: CE14.1 CE18.1 CE26.1 CE32.1 CE33.1 CE34.1 CE35.1 CE39.1 DE6.1 FBE2.1 PQ114.3 PR134.2 PR163.2 QT3.3(D) R16.2 RE28.2 RE29.2 RE30.2 RE31.2 RE33.1 RE80.2 RE81.1 RE102.1 RE108.2 RE118.1 RE120.2 RE127.2 RE134.2 RE135.2 RE139.1 RE458.2 UE1.D4(VSTBY1) UE1.D5(VSTBY2) UE1.D10(VSTBY3) UE1.E4(VSTBY(PLL)) UE1.K4(VSTBY4) UE1.K10(VSTBY5) UE2.8(VCC)
+V3P3A_PCH: CU53.1 CU54.1 RU4.2 RU7.2 RU8.2 RU9.2 RU10.2 RU11.2 RU35.2 RU36.2 RU41.2 RU42.2 RU47.2 RU48.2 RU49.2 RU50.2 RU51.2 RU55.2 RU56.2 RU118.2 RU123.2 RU143.2 RU144.2 RU145.2 RU154.2 RU158.2 RU169.1 RU170.1 RU171.1 RU172.1 RU226.1 RU230.2 SHU4.2(B[0]) UU1.DB34(VCCSPI) UU1.DC33(VCCPRIM_3P3_1) UU1.DF23(VCCPRIM_3P3_2) UU1.DG26(VCCPRIM_3P3_3) UU1.DG28(VCCPRIM_3P3_4)
+V3P3A_SPI_FLASH: CO1.1 CO2.1 CP3.1 DO1.1 J3001.1 RE68.1 RO1.2 RO2.2 RO3.2 RO4.2 RU52.2 RU53.2 UO1.8(VCC) VCC_SPIO1.1
+V3P3A_TCP: DT1.1 RT74.1 RT75.1 RT76.1 RT77.1 RT130.2 UT3.8(VCC)
+V3P3A_VDDD_PD: CT3.1 CT4.1 CT5.1 CT67.1 RT1.2 RT2.1 RT3.2 RT18.1 RT98.2 RT101.2 RT102.2 RT117.2 RT135.2 TPT1.1 UT1.31(VDDD) UT1.32(VDDIO) UT7.10(VPWR)
+V3P3A_VSYS_PD: CT6.1 CT7.1 RT5.2 RT6.2 RT16.1 RT19.1 RT21.1 UT1.19(VSYS)
+V3P3S_SSD1: CN1.1 CN4.1 CN5.1 CN6.1 CN7.1 CN15.1 CN16.1 CN17.1 CN18.1 CN19.1 JSSD1.2(3P3V_2) JSSD1.4(3P3V_4) JSSD1.12(3P3V_12) JSSD1.14(3P3V_14) JSSD1.16(3P3V_16) JSSD1.18(3P3V_18) JSSD1.70(3P3V_70) JSSD1.72(3P3V_72) JSSD1.74(3P3V_74) RN1.2 RN3.2 RN11.2 RN30.2
+V3P3SX: CE52.2 CE53.2 CS1.1 CS3.1 CX885.1 PC915.1 PC1213.1 PR628.2 PR821.2 PR1102.2 PR1104.2 PR1105.2 PR1107.2 PU902.8(OUT2_1) PU902.9(OUT2_2) PU1202.2(BIAS) QE3.2(G1) QE3.5(G1) QU1.2(G1) QU1.5(G1) QW2.1 QX42.2(S) RA32.1 RE50.1 RE51.1 RE55.1 RE56.1 RE59.2 RE112.2 RE113.2 RF1.1 RN1.1 RS1.2 RS2.2 RS3.2 RT57.2 RU32.2 RU101.2 RU103.2 RU111.2 RU112.2 RU114.2 RU119.2 RU120.2 RU227.1 RV15.2 RV27.2 RV45.2 RV49.2 RV56.2 RX900.1 RX907.2 RX918.2 RX924.2 SHI01.1(A[0]) US1.1(VDD) US4.4(VCC)
+V3P3SX_AUD: FBA5.1 RA16.1 RA32.2
+V3P3SX_HDMI: CI104.1 CI115.2 CI116.1 CI118.1 RI101.2 RI142.2 RI143.2 RI151.2 RI152.2 RI154.2 RI155.2 SHI01.2(B[0]) UI2.1(VDD33_1) UI2.24(VDD33_2)
+V5P0_AVDD5: CA32.1 CA56.1 CA57.1 FBA4.1(FB1) UA2.41(AVDD5)
+V5P0_FPS: C9.2 C10.1 J1.6 R17.2 R18.2 TP145.1
+V5P0A: CB34.1 CB35.1 FBA4.2(FB2) JDB1.1 JDB1.2 JDB1.3 JDB1.4 PC310.1 PC311.1 PC312.1 PC313.1 PC314.1 PC316.1 PC317.1 PC716.1 PC720.1 PC909.1 PC910.1 PC1211.1 PL301.2 PR519.2 PR531.2 PR601.2 PR603.1 PSH306.2(B[0]) PSH403.1(A[0]) PSH706.1(A[0]) PU701.13(VCC_5V) PU902.1(IN1_1) PU902.2(IN1_2) PU902.4(VBIAS) PU1201.4(VBIAS) R17.1 RB48.2 RB49.2 RB52.2 RT88.1 RV76.2 RV77.2 RV78.2 RV85.2 RV87.2 SHT1.1(A[0]) UB6.1(IN)
+V5P0A_FAN: CE20.1 CE21.1 DE3.1 JE3.1 SHE1.2(B[0]) TPE101.1
+V5P0A_LX: PC308.2 PL301.1 PU301.2(LX1) PU301.3(LX2)
+V5P0A_TYPEC: CT55.1 CT56.1 CT58.1 CT59.1 RT88.2 RT94.2 UT5.A1(VIN1) UT5.A2(VIN2)
+V5P0A_USB_AOU1: CB32.1 CB33.1 CB390.1 CB393.1 CB395.1 CB398.1 CB399.1 CB404.1 ESDB25.1(-) JB8.1(VBUS) UB6.12(OUT)
+V5P0SX: CE19.1 PC911.1 PR816.2 PU902.13(OUT1_1) PU902.14(OUT1_2) R18.1 RA33.1 RE7.1 RI34.1 RX925.2 SHE1.1(A[0]) UI1.5(IN)
+V5P0SX_AUD: CA11.1 CA12.1 FBA2.1(FB1) RA33.2
+V5P0SX_HDMI: +V5P0SX_HDMI_F.1(A) CI1.1 CI20.1 ESDI1.1 JI1.18(+5V) RI105.2 RI106.2 UI1.1(OUT)
+V5P0SX_KB_BL: CE7.1 CE8.1 JKBL1.2 JKBL1.4 RE7.2 TP151.1
+VBAT: PC106.1 PC143.1 PESD107.3 PJ101.7 PJ101.8 PR165.2 PTP107.1 PTP108.1
+VBAT_R: PC107.1 PQ101.5(D1) PR165.1
+VBATA_BKLT_IN: CX16.1 CX17.1 CX18.1 JX1.1 JX1.2 JX1.3 JX1.4 RX11.2
+VBUS_TYPEC: CT57.1 CT60.1 CT74.1 CT75.1 CT76.1 CT77.1 CT78.1 CT81.1 ESDT1.1 JT1.A4(VBUS1) JT1.A9(VBUS2) JT1.B4(VBUS3) JT1.B9(VBUS4) RT99.2 RT100.1 UT1.22(VBUS) UT5.C2(VBUS1) UT5.D1(VBUS2) UT5.D2(VBUS3) UT6.B2(VBUS1) UT6.C2(VBUS2) UT6.D2(VBUS3) UT6.E1(VBUS4) UT6.E2(VBUS5)
+VBUS_TYPEC1_P1: DWC1.1(C) PC101.1 PC110.1 PC122.1 PC144.1 PC145.1 PC146.1 PDT1.1(C) PDT2.1(C) PQ110.5(D1) PR106.1 PR170.2
+VBUS_TYPEC_PP_HV: PDT1.2(A) PDT2.2(A) UT6.A1(VINT1) UT6.B1(VINT2) UT6.C1(VINT3) UT6.D1(VINT4)
+VBUS_WC: CB414.1 CB415.1 DWC1.2(A) TPWC1.1
+VCC0P9_LC_TCP1: CT37.1 UT2.J3(VCC0P9_LC)
+VCC0P9_LVR_TCP1: CT47.1 CT48.1 UT2.L6(VCC0P9_LVR) UT2.M6(VCC0P9_LVR_SENSE)
+VCC0P9_SVR_TCP1_PHASE: LT1.1 UT2.L1(SVR_IND[1]) UT2.M1(SVR_IND[2])
+VCC0V9_SVR_TCP1: CT38.1 CT39.1 CT40.1 CT41.1 CT42.1 CT43.1 CT44.1 CT45.1 CT46.1 CT82.1 CT83.1 LT1.2 UT2.E3(VCC0P9_SVR_PA_ANA[1]) UT2.E9(VCC0P9_SVR_PB_ANA[1]) UT2.F6(VCC0P9_SVR[1]) UT2.G3(VCC0P9_SVR_PA_ANA[2]) UT2.G6(VCC0P9_SVR[2]) UT2.G9(VCC0P9_SVR_PB_ANA[2])
+VCC1P05_OUT_FET: PC901.1 PC905.1 PU901.2(VIN) PU904.2(VIN) RU222.1 UU1.BY2(VCC1P05_1) UU1.CB2(VCC1P05_2) UU1.CC1(VCC1P05_3)
+VCC1P05_OUT_PCH: UU1.DF29(VCCPRIM_1P05_3) UU1.DF31(VCCPRIM_1P05_4) UU1.DG29(VCCPRIM_1P05_2) UU1.DG31(VCCPRIM_1P05_1)
+VCC1P05_OUT_SFR: CU56.1 CU57.1 UU1.CD1(VCCPLL_2) UU1.CD2(VCCPLL_1)
+VCC1P8A: CU101.1 CU102.1 CU103.1 CU104.1 CU105.1 PSH902.2(B[0]) UU1.BG9(VCC1P8A_1) UU1.BJ9(VCC1P8A_2) UU1.BM9(VCC1P8A_3) UU1.BW1(VCC1P8A_4) UU1.BW2(VCC1P8A_5)
+VCC3P3_ANA_TCP0: CT31.1 UT2.L2(VCC3P3_ANA)
+VCC3P3_LC_TCP1: CT30.1 RT84.1 RT85.1 RT86.1 RT87.1 UT2.E5(VCC3P3_LC)
+VCC3P3_LDO_OUT: CE25.1 DU2.2 MR1.1(VCC) PC215.1 PR1013.2 PU201.11(LDO3) RA247.1 RE1.1 RE31.1 RT5.1
+VCC3V3_SX_TCP1: CT32.1 CT33.1 CT34.1 CT35.1 CT36.1 FBT2.2 RT56.1 RT59.2 RT62.2 RT64.2 RT68.1 RT79.1 UT2.E6(VCC3P3_SX) UT2.J5(VCC3P3_SVR) UT2.M4(VCC_SVR_IN_1) UT2.M5(VCC_SVR_IN_2)
+VCC3V3A_S0_TCP1: CT50.1 CT51.1 CT52.1 RT79.2 UT2.J7(VCC3P3A)
+VCCA_CLKLDO_1P8: CU42.1 LU1.1 RU190.1 RU191.1 RU221.1 UU1.DW15(VCCA_CLKLDO_1P8)
+VCCDPHY_1P24: CU49.1 UU1.DW32(VCCDPHY_1P24)
+VCCDSW_1P05: CU50.1 UU1.DD34(VCCDSW_1P05)
+VCCFPGM: CU58.1 SHU8.2(B[0]) UU1.AB34(VCCSTG_OUT_7) UU1.R35(VCCSTG_OUT_3) UU1.T34(VCCSTG_OUT_5) UU1.U35(VCCSTG_OUT_6) UU1.V34(VCCSTG_OUT_4)
+VCCIN: +VCCIN1.1(A) CU59.1 CU60.1 CU61.1 CU62.1 CU63.1 CU64.1 CU65.1 CU66.1 CU67.1 CU68.1 CU69.1 CU70.1 CU71.1 CU72.1 CU73.1 CU74.1 CU75.1 CU76.1 CU77.1 CU78.1 CU79.1 CU80.1 CU81.1 CU82.1 CU83.1 CU84.1 CU85.1 CU86.1 CU87.1 CU88.1 CU89.1 CU90.1 CU91.1 CU92.1 CU93.1 CU94.1 CU95.1 CU96.1 CU162.1 CU163.1 CU164.1 PC612.2 PC613.2 PC616.2 PC617.2 PCS604.1 PCS606.1 PL601.2 PL602.2 PR630.1 PR641.2 PR643.1 PR646.2 PR648.1 UU1.A19(VCCIN_1) UU1.A21(VCCIN_17) UU1.A23(VCCIN_28) UU1.A24(VCCIN_39) UU1.A27(VCCIN_50) UU1.A29(VCCIN_61) UU1.AA12(VCCIN_72) UU1.AB1(VCCIN_83) UU1.AB13(VCCIN_94) UU1.AC12(VCCIN_2) UU1.B19(VCCIN_8) UU1.B23(VCCIN_9) UU1.B27(VCCIN_10) UU1.B29(VCCIN_11) UU1.BN10(VCCIN_12) UU1.BP9(VCCIN_14) UU1.BP11(VCCIN_13) UU1.BR10(VCCIN_15) UU1.BT9(VCCIN_18) UU1.BT11(VCCIN_16) UU1.BU10(VCCIN_19) UU1.BV9(VCCIN_21) UU1.BV36(VCCIN_20) UU1.BW9(VCCIN_24) UU1.BW10(VCCIN_22) UU1.BW36(VCCIN_23) UU1.BY10(VCCIN_25) UU1.C19(VCCIN_26) UU1.C23(VCCIN_27) UU1.C27(VCCIN_29) UU1.C29(VCCIN_30) UU1.CA9(VCCIN_32) UU1.CA36(VCCIN_31) UU1.CB10(VCCIN_33) UU1.CC9(VCCIN_36) UU1.CC11(VCCIN_34) UU1.CC36(VCCIN_35) UU1.CD10(VCCIN_37) UU1.CE11(VCCIN_38) UU1.CE34(VCCIN_40) UU1.CE35(VCCIN_41) UU1.CF10(VCCIN_42) UU1.CF33(VCCIN_43) UU1.CG11(VCCIN_44) UU1.CG34(VCCIN_45) UU1.CG35(VCCIN_46) UU1.CH10(VCCIN_47) UU1.CJ11(VCCIN_49) UU1.CJ34(VCCIN_51) UU1.CJ35(VCCIN_52) UU1.CK10(VCCIN_53) UU1.CL34(VCCIN_55) UU1.CL35(VCCIN_56) UU1.CN34(VCCIN_57) UU1.CN35(VCCIN_58) UU1.CP33(VCCIN_59) UU1.CR34(VCCIN_60) UU1.CR35(VCCIN_62) UU1.CT33(VCCIN_63) UU1.CT34(VCCIN_64) UU1.CT35(VCCIN_65) UU1.CU33(VCCIN_66) UU1.D19(VCCIN_67) UU1.D21(VCCIN_68) UU1.D23(VCCIN_69) UU1.D24(VCCIN_70) UU1.D27(VCCIN_71) UU1.D29(VCCIN_73) UU1.F19(VCCIN_74) UU1.F21(VCCIN_75) UU1.F23(VCCIN_76) UU1.F24(VCCIN_77) UU1.F27(VCCIN_78) UU1.F29(VCCIN_79) UU1.G1(VCCIN_80) UU1.G19(VCCIN_81) UU1.G23(VCCIN_82) UU1.G27(VCCIN_84) UU1.G29(VCCIN_85) UU1.H19(VCCIN_86) UU1.H23(VCCIN_87) UU1.H27(VCCIN_88) UU1.H29(VCCIN_89) UU1.J18(VCCIN_90) UU1.J20(VCCIN_91) UU1.J22(VCCIN_92) UU1.J23(VCCIN_93) UU1.J26(VCCIN_95) UU1.J28(VCCIN_96) UU1.J30(VCCIN_48) UU1.J32(VCCIN_54) UU1.K17(VCCIN_97) UU1.K19(VCCIN_98) UU1.K21(VCCIN_99) UU1.K23(VCCIN_100) UU1.K24(VCCIN_101) UU1.K27(VCCIN_102) UU1.K29(VCCIN_6) UU1.K31(VCCIN_7) UU1.M1(VCCIN_103) UU1.U1(VCCIN_104) UU1.V13(VCCIN_3) UU1.W12(VCCIN_4) UU1.Y13(VCCIN_5)
+VCCIN_AUX: +VCCIN_AUX1.1(A) CU108.1 CU109.1 CU110.1 CU111.1 CU112.1 CU113.1 CU114.1 CU115.1 CU116.1 CU117.1 CU118.1 CU119.1 CU120.1 CU121.1 CU122.1 CU123.1 CU124.1 CU125.1 CU126.1 CU127.1 CU128.1 CU129.1 CU130.1 CU131.1 CU132.1 CU133.1 CU134.1 CU135.1 CU136.1 CU137.1 CU138.1 CU139.1 CU140.1 CU141.1 CU165.1 CU166.1 CU167.1 PC504.2 PC505.2 PC511.1 PC512.1 PC513.1 PC514.1 PC515.1 PC516.1 PC530.1 PCS502.1 PL501.2 PR515.2 PR517.2 PR518.2 PR520.1 PRT501.2 UU1.AH1(VCCIN_AUX_1) UU1.AJ1(VCCIN_AUX_12) UU1.AL1(VCCIN_AUX_23) UU1.AM1(VCCIN_AUX_31) UU1.AN1(VCCIN_AUX_32) UU1.AT9(VCCIN_AUX_34) UU1.AT11(VCCIN_AUX_33) UU1.AU10(VCCIN_AUX_35) UU1.AV9(VCCIN_AUX_36) UU1.AW10(VCCIN_AUX_2) UU1.AY9(VCCIN_AUX_4) UU1.AY11(VCCIN_AUX_3) UU1.BA10(VCCIN_AUX_5) UU1.BB9(VCCIN_AUX_6) UU1.CH1(VCCIN_AUX_7) UU1.CK11(VCCIN_AUX_8) UU1.CL10(VCCIN_AUX_9) UU1.CM11(VCCIN_AUX_10) UU1.CN1(VCCIN_AUX_11) UU1.CN10(VCCIN_AUX_13) UU1.CP11(VCCIN_AUX_14) UU1.CR10(VCCIN_AUX_15) UU1.CT11(VCCIN_AUX_16) UU1.CU10(VCCIN_AUX_17) UU1.CV1(VCCIN_AUX_18) UU1.CV11(VCCIN_AUX_19) UU1.CW10(VCCIN_AUX_20) UU1.CY11(VCCIN_AUX_21) UU1.DC1(VCCIN_AUX_22) UU1.DC11(VCCIN_AUX_28) UU1.DE12(VCCIN_AUX_29) UU1.DF12(VCCIN_AUX_30) UU1.P13(VCCIN_AUX_24) UU1.R12(VCCIN_AUX_25) UU1.T13(VCCIN_AUX_26) UU1.U12(VCCIN_AUX_27)
+VCCIN_AUX_VCC: PC503.1 PR531.1 PU501.15(PVCC) PU501.16(VCC)
+VCCIN_VIN: PC618.1 PC619.1 PC620.1 PC622.1 PC623.1 PC624.1 PC625.1 PC626.1 PC627.1 PC628.1 PC629.1 PC630.1 PCS601.1 PCS602.1 PQ601.5(D1) PQ604.5(D1) PR602.1 PSH601.1(A[0]) PSH602.1(A[0]) PSH603.1(A[0])
+VCCIO_OUT: RU213.2 RU214.2 RU215.2 RU216.2 RU233.2 RU234.2 RU235.2 RU236.2 RU237.2 RU238.2 RU239.2 RU240.2 UU1.AD7(VCCIO_OUT)
+VCCLDOSTD_OUT_0P85: CU41.1 UU1.DW37(VCCLDOSTD_0P85)
+VCCPGPPR: CU171.1 RU230.1 RU231.1 UU1.DF26(VCCPGPPR)
+VCCPRIM_1P8: CU46.1 CU47.1 CU48.1 LU1.2 RU190.2 RU231.2 SHU3.2(B[0]) UU1.DD35(VCCPRIM_1P8_1) UU1.DF15(VCCPRIM_1P8_2) UU1.DF17(VCCPRIM_1P8_3) UU1.DF18(VCCPRIM_1P8_4) UU1.DF20(VCCPRIM_1P8_5) UU1.DF34(VCCPRIM_1P8_9) UU1.DG17(VCCPRIM_1P8_6) UU1.DG18(VCCPRIM_1P8_7) UU1.DG20(VCCPRIM_1P8_8)
+VCCPRTC_3P3: CU51.1 CU52.1 SHU2.2(B[0]) UU1.DG33(VCCRTC)
+VCCRTC: CU37.1 DU2.3 PR1012.2 PR6157.2 RU89.2 RU91.2 RU156.2 SHU2.1(A[0])
+VCCSFR_OC: CU106.1 CU107.1 PR905.2 PSH904.2(B[0]) UU1.CG38(VCCPLL_OC_1) UU1.CG41(VCCPLL_OC_2) UU1.CG42(VCCPLL_OC_3) UU1.CG49(VCCPLL_OC_4)
+VCCST: PC656.1 PR655.2 PR658.2 PR661.2 PSH901.2(B[0]) SHU1.1(A[0])
+VCCSTG_IO: CU99.1 CU100.1 PSH903.2(B[0]) UU1.BY1(VCCSTG)
+VCCSTG_OUT_FUSE: SHU8.1(A[0]) UU1.F33(VCCSTG_OUT_1) UU1.G33(VCCSTG_OUT_2)
+VCCSTG_OUT_LGC: CU55.1 SHU9.1(A[0]) UU1.E5(VCCSTG_OUT_LGC)
+VCCSTG_TERM: RU17.2 RU18.2 RU23.2 RU27.1 RU30.1 SHU9.2(B[0])
+VDD: CV106.1 CV107.1 CV108.2 CV113.1 CV200.1 CV201.1 CV202.1 RV88.1 UV2.G8(VDD18_1) UV2.G9(VDD18_2)
+VDDQ_CPU: CU142.1 CU143.1 CU144.1 CU145.1 CU146.1 CU147.1 CU148.1 CU149.1 CU150.1 CU151.1 CU152.1 CU153.1 CU154.1 CU155.1 CU156.1 CU157.1 CU158.1 CU159.1 CU160.1 CU161.1 RD1.2 SHU6.2(B[0]) SHU7.2(B[0]) UU1.AA37(VDDQ_1) UU1.AA49(VDDQ_12) UU1.AB36(VDDQ_23) UU1.AC35(VDDQ_34) UU1.AC37(VDDQ_43) UU1.AD35(VDDQ_44) UU1.AD36(VDDQ_45) UU1.AE36(VDDQ_46) UU1.AF49(VDDQ_47) UU1.AG36(VDDQ_2) UU1.AJ36(VDDQ_3) UU1.AL36(VDDQ_4) UU1.AL49(VDDQ_5) UU1.AN36(VDDQ_6) UU1.AP37(VDDQ_7) UU1.AR36(VDDQ_8) UU1.AR37(VDDQ_9) UU1.AT36(VDDQ_10) UU1.AT49(VDDQ_11) UU1.AV36(VDDQ_13) UU1.AW37(VDDQ_14) UU1.AY36(VDDQ_15) UU1.BA37(VDDQ_16) UU1.BA49(VDDQ_17) UU1.BB36(VDDQ_18) UU1.BD36(VDDQ_19) UU1.BE37(VDDQ_20) UU1.BF36(VDDQ_21) UU1.BF37(VDDQ_22) UU1.BF49(VDDQ_24) UU1.BG36(VDDQ_25) UU1.BJ36(VDDQ_26) UU1.BL37(VDDQ_27) UU1.BM49(VDDQ_28) UU1.BN37(VDDQ_29) UU1.BP38(VDDQ_30) UU1.BP39(VDDQ_31) UU1.BR37(VDDQ_32) UU1.BT38(VDDQ_33) UU1.BU37(VDDQ_35) UU1.BU49(VDDQ_36) UU1.CA39(VDDQ_37) UU1.CB49(VDDQ_38) UU1.L38(VDDQ_39) UU1.L49(VDDQ_40) UU1.N36(VDDQ_41) UU1.T49(VDDQ_42)
+VDDQ_LP4X: CD4.1 CD8.1 CD12.1 CD16.1 CD50.2 CD51.2 CD52.2 CD53.2 CD54.2 CD55.2 CD56.1 CD57.1 CD58.2 CD59.2 CD60.2 CD61.2 CD62.2 CD63.2 CD64.1 CD65.1 CD94.2 CD95.2 CD96.2 CD97.2 CD98.2 CD99.2 CD100.1 CD101.2 CD102.2 CD103.2 CD104.2 CD105.2 CD106.2 CD107.1 RD11.2 RD12.2 UD1.AA3(VDDQ_20) UD1.AA5(VDDQ_19) UD1.AA8(VDDQ_18) UD1.AA10(VDDQ_17) UD1.B3(VDDQ_16) UD1.B5(VDDQ_15) UD1.B8(VDDQ_14) UD1.B10(VDDQ_13) UD1.D1(VDDQ_12) UD1.D5(VDDQ_11) UD1.D8(VDDQ_10) UD1.D12(VDDQ_9) UD1.F3(VDDQ_8) UD1.F10(VDDQ_7) UD1.U3(VDDQ_6) UD1.U10(VDDQ_5) UD1.W1(VDDQ_4) UD1.W5(VDDQ_3) UD1.W8(VDDQ_2) UD1.W12(VDDQ_1) UD2.AA3(VDDQ_20) UD2.AA5(VDDQ_19) UD2.AA8(VDDQ_18) UD2.AA10(VDDQ_17) UD2.B3(VDDQ_16) UD2.B5(VDDQ_15) UD2.B8(VDDQ_14) UD2.B10(VDDQ_13) UD2.D1(VDDQ_12) UD2.D5(VDDQ_11) UD2.D8(VDDQ_10) UD2.D12(VDDQ_9) UD2.F3(VDDQ_8) UD2.F10(VDDQ_7) UD2.U3(VDDQ_6) UD2.U10(VDDQ_5) UD2.W1(VDDQ_4) UD2.W5(VDDQ_3) UD2.W8(VDDQ_2) UD2.W12(VDDQ_1) UD3.AA3(VDDQ_20) UD3.AA5(VDDQ_19) UD3.AA8(VDDQ_18) UD3.AA10(VDDQ_17) UD3.B3(VDDQ_16) UD3.B5(VDDQ_15) UD3.B8(VDDQ_14) UD3.B10(VDDQ_13) UD3.D1(VDDQ_12) UD3.D5(VDDQ_11) UD3.D8(VDDQ_10) UD3.D12(VDDQ_9) UD3.F3(VDDQ_8) UD3.F10(VDDQ_7) UD3.U3(VDDQ_6) UD3.U10(VDDQ_5) UD3.W1(VDDQ_4) UD3.W5(VDDQ_3) UD3.W8(VDDQ_2) UD3.W12(VDDQ_1) UD4.AA3(VDDQ_20) UD4.AA5(VDDQ_19) UD4.AA8(VDDQ_18) UD4.AA10(VDDQ_17) UD4.B3(VDDQ_16) UD4.B5(VDDQ_15) UD4.B8(VDDQ_14) UD4.B10(VDDQ_13) UD4.D1(VDDQ_12) UD4.D5(VDDQ_11) UD4.D8(VDDQ_10) UD4.D12(VDDQ_9) UD4.F3(VDDQ_8) UD4.F10(VDDQ_7) UD4.U3(VDDQ_6) UD4.U10(VDDQ_5) UD4.W1(VDDQ_4) UD4.W5(VDDQ_3) UD4.W8(VDDQ_2) UD4.W12(VDDQ_1)
+VDDQ_TX: PSH707.2(B[0]) RD12.1
AGND_CHG: PC103.2 PC104.2 PC112.2 PC113.1 PC114.2 PC115.2 PC117.1 PC118.2 PC119.2 PC127.1 PC128.2 PC133.2 PC154.2 PR112.1 PR117.1 PR121.1 PSH101.1(A[0]) PU101.5(ENZ_OTG) PU101.14(CMPIN) PU101.15(CMPOUT)
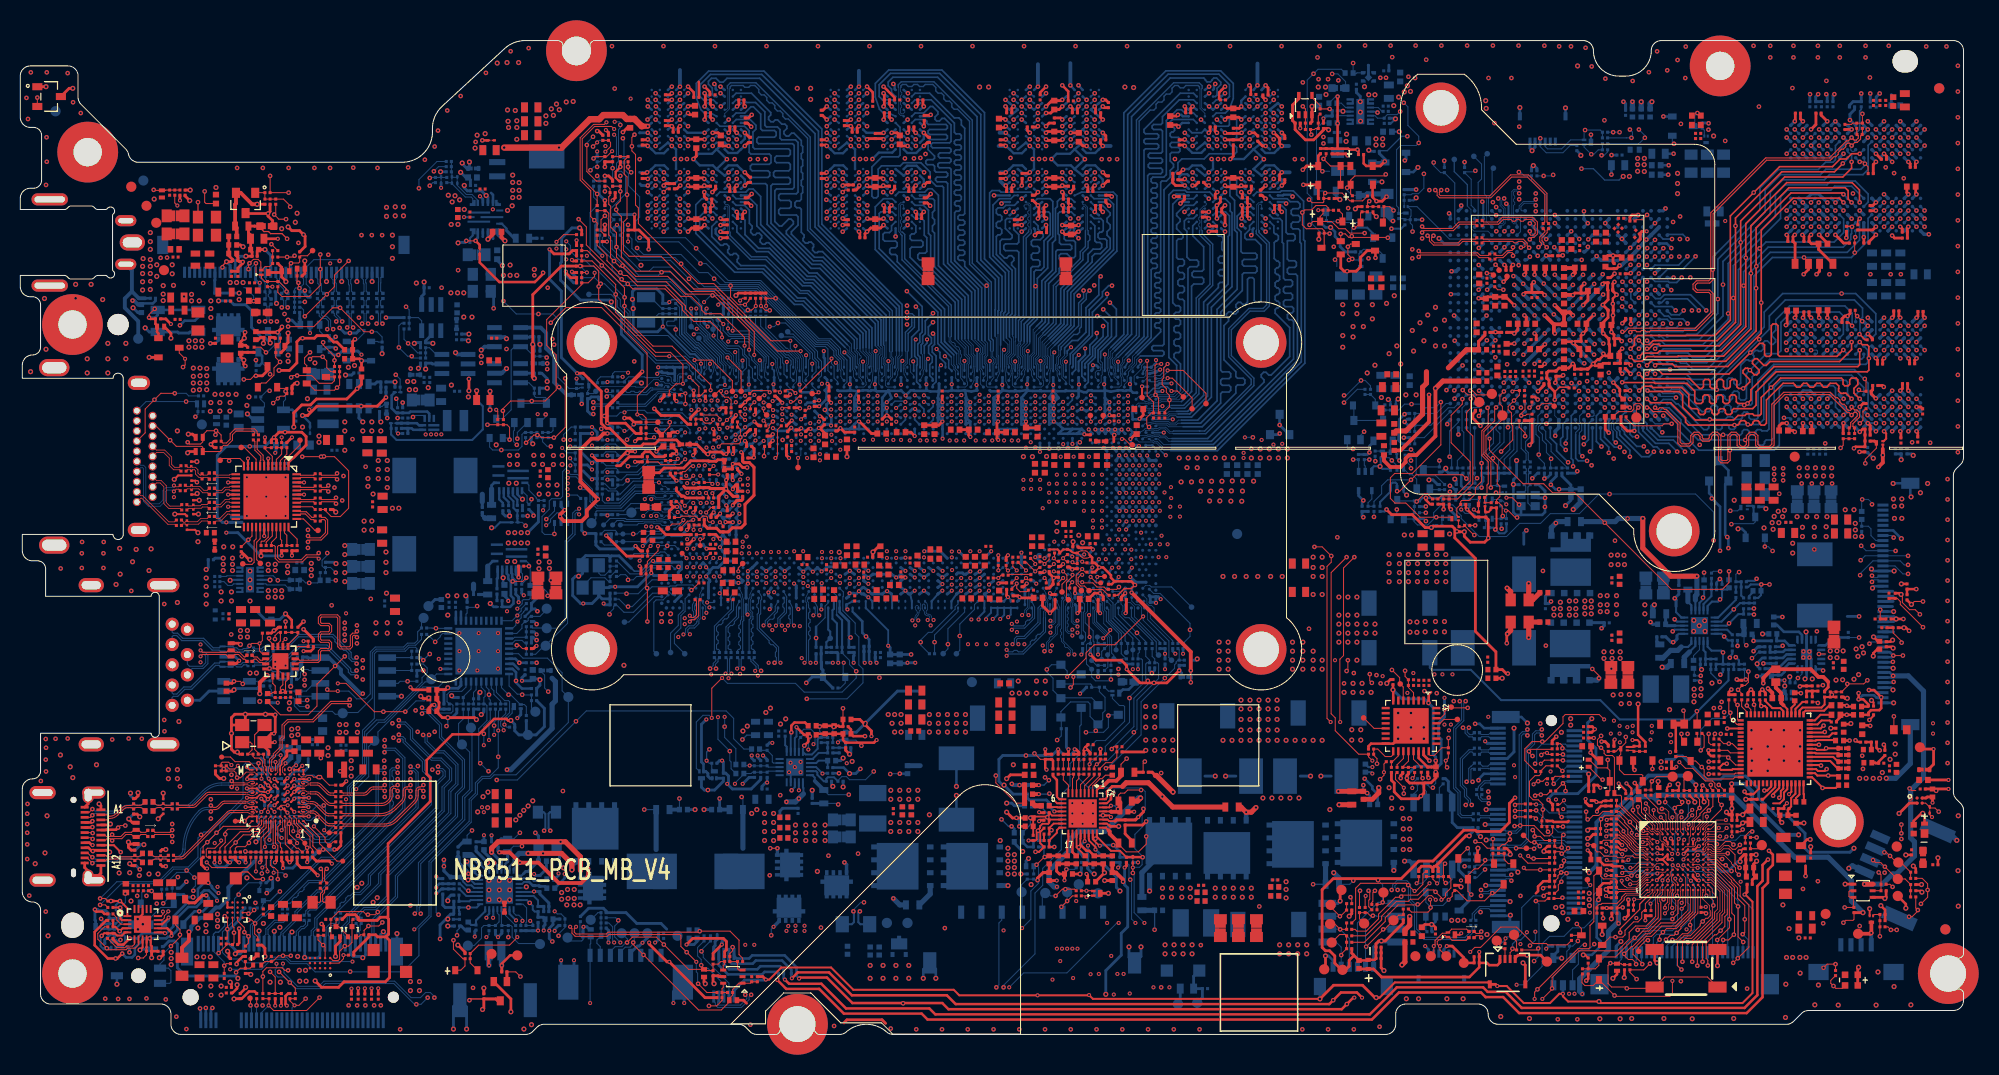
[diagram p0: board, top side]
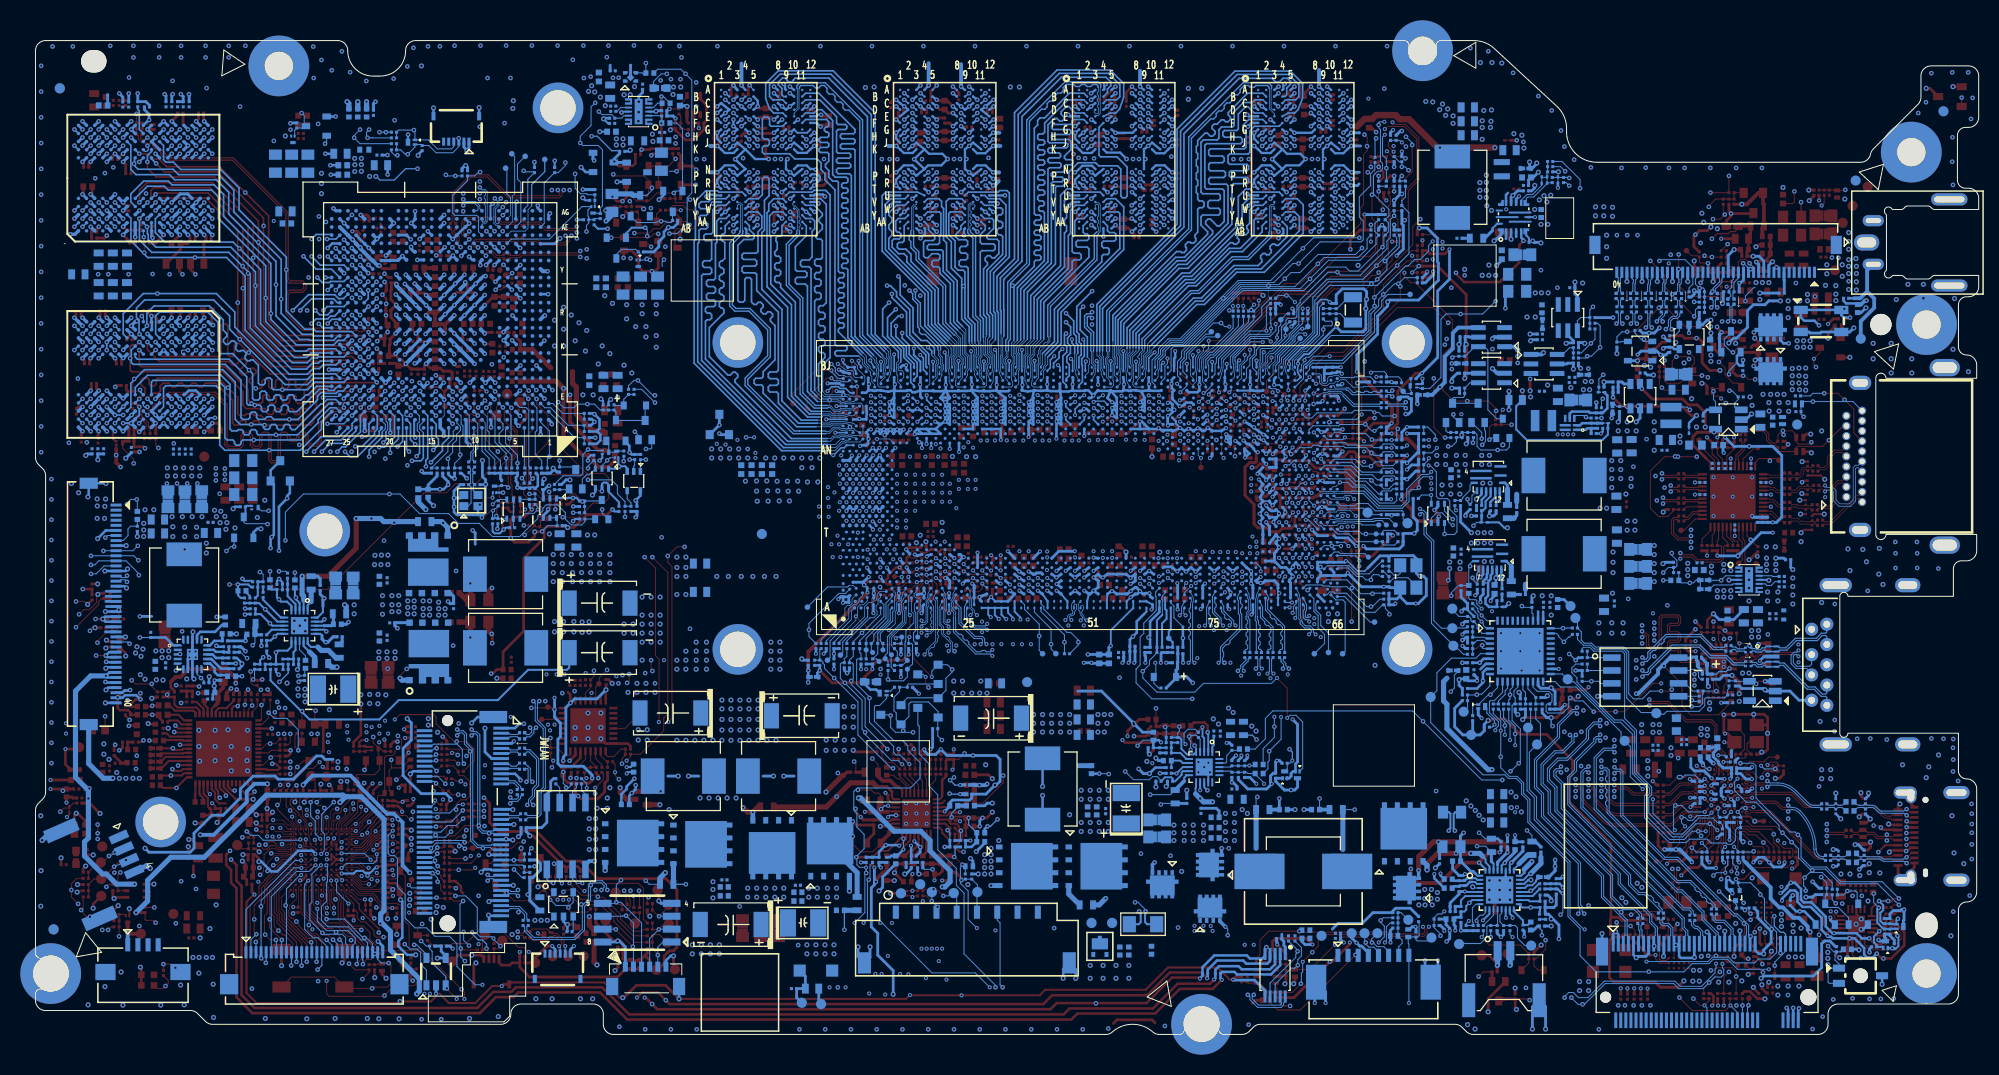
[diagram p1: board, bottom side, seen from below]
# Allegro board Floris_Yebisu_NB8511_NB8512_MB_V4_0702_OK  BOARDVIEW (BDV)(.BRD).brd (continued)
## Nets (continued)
GND: C8.2 C9.1 C10.2 CA8.2 CA11.2 CA12.2 CA13.2 CA14.2 CA16.2 CA17.2 CA18.2 CA23.2 CA24.2 CA25.2 CA26.2 CA27.2 CA28.2 CA31.2 CA34.2 CA35.2 CA36.2 CA37.2 CA38.2 CA58.2 CA59.2 CA61.2 CA62.2 CA63.2 CA64.2 CA65.2 CA66.2 CA67.2 CA75.2 CA76.2 CA77.2 CA82.2 CB32.2 CB33.2 CB34.2 CB35.2 CB36.2 CB38.1 CB390.2 CB393.2 CB395.2 CB398.2 CB399.2 CB404.2 CB413.1 CB414.2 CB415.2 CD1.2 CD2.2 CD3.2 CD4.2 CD5.2 CD6.2 CD7.2 CD8.2 CD9.2 CD10.2 CD11.2 CD12.2 CD13.2 CD14.2 CD15.2 CD16.2 CD17.2 CD18.1 CD19.1 CD20.1 CD21.1 CD22.1 CD23.1 CD24.1 CD25.1 CD26.2 CD27.2 CD28.1 CD29.1 CD30.1 CD31.1 CD32.1 CD33.1 CD34.1 CD35.1 CD36.2 CD37.2 CD38.1 CD39.1 CD40.1 CD41.1 CD42.2 CD43.2 CD44.1 CD45.1 CD46.1 CD47.1 CD48.2 CD49.2 CD50.1 CD51.1 CD52.1 CD53.1 CD54.1 CD55.1 CD56.2 CD57.2 CD58.1 CD59.1 CD60.1 CD61.1 CD62.1 CD63.1 CD64.2 CD65.2 CD66.1 CD67.1 CD68.1 CD69.1 CD70.1 CD71.1 CD72.1 CD73.1 CD74.2 CD75.1 CD76.1 CD77.1 CD78.1 CD79.1 CD80.1 CD81.1 CD82.1 CD83.2 CD84.1 CD85.1 CD86.1 CD87.1 CD88.2 CD89.1 CD90.1 CD91.1 CD92.1 CD93.2 CD94.1 CD95.1 CD96.1 CD97.1 CD98.1 CD99.1 CD100.2 CD101.1 CD102.1 CD103.1 CD104.1 CD105.1 CD106.1 CD107.2 CE7.2 CE8.2 CE9.2 CE14.2 CE18.2 CE19.2 CE20.2 CE21.2 CE22.2 CE23.2 CE24.2 CE25.2 CE26.2 CE32.2 CE33.2 CE34.2 CE35.2 CE36.2 CE37.2 CE38.2 CE39.2 CE40.2 CE42.2 CE43.2 CE44.2 CE45.2 CE46.2 CE54.2 CE55.2 CE373.2 CE374.2 CE375.2 CE376.2 CE377.2 CE378.2 CF1.2 CF2.2 CF3.2 CF8.2 CF9.1 CF10.1 CF11.2 CF12.1 CI1.2 CI20.2 CI103.2 CI104.2 CI105.1 CI106.2 CI107.2 CI108.2 CI109.2 CI110.2 CI111.2 CI112.2 CI113.1 CI114.1 CI115.1 CI116.2 CI118.2 CI119.1 CI120.2 CL1.2 CL32.2 CL33.2 CN1.2 CN4.2 CN5.2 CN6.2 CN7.2 CN15.2 CN16.2 CN17.2 CN18.2 CN19.2 CO1.2 CO2.2 CP1.2 CP2.2 CP3.2 CPU_BOSS1.1 CPU_BOSS2.1 CPU_BOSS3.1 CPU_BOSS4.1 CS1.2 CS3.2 CT1.2 CT2.2 CT3.2 CT4.2 CT5.2 CT6.2 CT7.2 CT8.1 CT9.2 CT10.2 CT11.2 CT12.2 CT13.2 CT14.2 CT15.2 CT16.2 CT17.2 CT26.2 CT27.2 CT28.2 CT29.2 CT30.2 CT31.2 CT32.2 CT33.2 CT34.2 CT35.2 CT36.2 CT37.2 CT38.2 CT39.2 CT40.2 CT41.2 CT42.2 CT43.2 CT44.2 CT45.2 CT46.2 CT47.2 CT48.2 CT50.2 CT51.2 CT52.2 CT54.2 CT55.2 CT56.2 CT58.2 CT59.2 CT60.2 CT61.2 CT66.2 CT67.2 CT72.2 CT73.2 CT74.2 CT75.2 CT76.2 CT77.2 CT78.2 CT79.2 CT80.2 CT81.2 CT82.2 CT83.2 CU1.2 CU2.2 CU3.2 CU4.2 CU5.2 CU6.2 CU7.2 CU8.2 CU9.2 CU10.2 CU11.2 CU13.1 CU14.2 CU15.2 CU16.2 CU17.2 CU18.2 CU19.2 CU20.2 CU21.2 CU22.2 CU31.2 CU32.2 CU33.2 CU34.2 CU35.2 CU36.2 CU37.2 CU38.2 CU39.2 CU40.2 CU41.2 CU42.2 CU43.2 CU44.2 CU45.2 CU46.2 CU47.2 CU48.2 CU49.2 CU50.2 CU51.2 CU52.2 CU53.2 CU54.2 CU55.2 CU56.2 CU57.2 CU58.2 CU59.2 CU60.2 CU61.2 CU62.2 CU63.2 CU64.2 CU65.2 CU66.2 CU67.2 CU68.2 CU69.2 CU70.2 CU71.2 CU72.2 CU73.2 CU74.2 CU75.2 CU76.2 CU77.2 CU78.2 CU79.2 CU80.2 CU81.2 CU82.2 CU83.2 CU84.2 CU85.2 CU86.2 CU87.2 CU88.2 CU89.2 CU90.2 CU91.2 CU92.2 CU93.2 CU94.2 CU95.2 CU96.2 CU97.2 CU98.2 CU99.2 CU100.2 CU101.2 CU102.2 CU103.2 CU104.2 CU105.2 CU106.2 CU107.2 CU108.2 CU109.2 CU110.2 CU111.2 CU112.2 CU113.2 CU114.2 CU115.2 CU116.2 CU117.2 CU118.2 CU119.2 CU120.2 CU121.2 CU122.2 CU123.2 CU124.2 CU125.2 CU126.2 CU127.2 CU128.2 CU129.2 CU130.2 CU131.2 CU132.2 CU133.2 CU134.2 CU135.2 CU136.2 CU137.2 CU138.2 CU139.2 CU140.2 CU141.2 CU142.2 CU143.2 CU144.2 CU145.2 CU146.2 CU147.2 CU148.2 CU149.2 CU150.2 CU151.2 CU152.2 CU153.2 CU154.2 CU155.2 CU156.2 CU157.2 CU158.2 CU159.2 CU160.2 CU161.2 CU162.2 CU163.2 CU164.2 CU165.2 CU166.2 CU167.2 CU168.2 CU169.2 CU170.2 CU171.2 CV1.2 CV2.2 CV3.2 CV4.2 CV5.2 CV10.1 CV11.2 CV12.2 CV15.1 CV16.2 CV17.2 CV18.1 CV19.1 CV20.1 CV21.2 CV22.2 CV23.2 CV24.2 CV25.2 CV28.2 CV29.2 CV30.2 CV31.2 CV32.2 CV33.2 CV34.2 CV35.1 CV36.1 CV37.2 CV41.2 CV42.2 CV43.2 CV44.2 CV45.2 CV46.2 CV47.2 CV48.1 CV49.2 CV50.2 CV51.2 CV52.2 CV53.1 CV54.1 CV55.1 CV56.1 CV57.2 CV58.2 CV59.2 CV60.2 CV61.1 CV62.1 CV63.1 CV64.1 CV68.2 CV69.2 CV70.2 CV71.2 CV72.2 CV73.2 CV74.2 CV75.2 CV76.2 CV77.2 CV78.2 CV79.2 CV80.1 CV81.1 CV82.1 CV83.1 CV84.1 CV85.2 CV86.2 CV87.2 CV88.2 CV89.2 CV90.2 CV91.2 CV92.2 CV93.2 CV94.2 CV95.2 CV96.2 CV97.2 CV98.2 CV99.2 CV100.2 CV101.2 CV102.2 CV103.2 CV104.2 CV105.2 CV106.2 CV107.2 CV108.1 CV109.2 CV110.2 CV111.1 CV112.2 CV113.2 CV114.2 CV115.1 CV116.2 CV117.2 CV118.2 CV119.2 CV120.2 CV121.2 CV122.2 CV123.2 CV124.1 CV125.1 CV126.1 CV127.1 CV128.1 CV129.1 CV130.1 CV131.1 CV132.2 CV133.2 CV134.2 CV135.2 CV136.2 CV137.2 CV138.2 CV139.1 CV140.1 CV141.1 CV142.1 CV143.1 CV144.1 CV145.2 CV146.2 CV147.1 CV148.1 CV149.1 CV150.1 CV151.1 CV152.1 CV153.1 CV154.1 CV155.2 CV156.2 CV157.2 CV158.2 CV159.2 CV160.1 CV161.1 CV162.1 CV163.1 CV164.1 CV165.1 CV166.1 CV167.1 CV168.1 CV169.1 CV170.2 CV171.2 CV174.1 CV175.1 CV176.1 CV177.1 CV178.2 CV179.2 CV187.2 CV192.1 CV193.2 CV194.2 CV195.1 CV196.2 CV197.2 CV198.2 CV199.2 CV200.2 CV201.2 CV202.2 CV203.2 CV204.2 CV205.2 CV206.2 CV207.2 CV208.2 CV209.2 CW3.2 CW4.2 CW5.1 CW6.1 CW8.2 CW11.2 CW12.2 CW13.1 CW14.1 CW15.2 CW16.1 CX3.2 CX4.2 CX9.1 CX10.2 CX13.2 CX14.2 CX15.1 CX16.2 CX17.2 CX18.2 CX21.1 CX22.2 CX284.2 CX887.2 CX892.1 CX893.2 CX894.2 CX895.2 CX896.2 CX897.2 CX898.2 DE3.2 EDB3.2 EDB5.2 ESD1.3 ESD2.3 ESD3.3 ESDB25.2(+) ESDB34.3 ESDE4.2 ESDE5.2 ESDE6.2 ESDE7.2 ESDE44.2 ESDE45.2 ESDI1.2 ESDI2.2 ESDI3.2 ESDI4.2 ESDI7.2(K2) ESDI8.2(K2) ESDI9.2(K2) ESDI10.2(K2) ESDI11.2(K2) ESDI12.2(K2) ESDI13.2(K2) ESDI14.2(K2) ESDL46.2 ESDT1.2 ESDT2.2(K2) ESDT3.2(K2) ESDT4.2(K2) ESDT5.2(K2) ESDT6.3 ESDT7.3 ESDT8.2(K2) ESDT9.2(K2) ESDT10.2(K2) ESDT11.2(K2) ESDT12.2 ESDT13.2 ESDX1.2 ESDX2.2 GND_SPIO1.1 GPU_BOSS1.1 GPU_BOSS2.1 J1.3 J1.7(GND0) J1.8(GND1) J3001.6 J3001.7 J3001.8 JB8.4(GND4) JB8.7(GND7) JB8.10(GND10) JB8.11(GND11) JB8.12(GND12) JB8.13(GND13) JDB1.9 JDB1.14 JDB1.17 JDB1.22 JDB1.27 JDB1.41(GND2) JDB1.42(GND1) JE3.4 JE3.5(G1) JE3.6(G2) JE4.4 JE4.9(GND0) JE4.10(GND1) JE7.28 JE7.29(MTG1) JE7.30(MTG2) JI1.2(DATA2G) JI1.5(DATA1G) JI1.8(DATA0G) JI1.11(CLKG) JI1.17(DDC/CEC_GND) JI1.20(SHELL-1) JI1.21(SHELL-2) JI1.22(SHELL-3) JI1.23(SHELL-4) JKBL1.5 JKBL1.6 JKBL3.1 JKBL3.2 JKBL3.7(GND0) JKBL3.8(GND1) JP2.4 JP2.5(SH1) JP2.6(SH2) JRTCU1.2 JRTCU1.3(MTG1) JRTCU1.4(MTG2) JSSD1.1(CONFIG_3) JSSD1.3(GND_3) JSSD1.9(GND_9) JSSD1.15(GND_15) JSSD1.21(CONFIG_0) JSSD1.27(GND_27) JSSD1.33(GND_33) JSSD1.39(GND_39) JSSD1.45(GND_45) JSSD1.51(GND_51) JSSD1.57(GND_57) JSSD1.71(GND_71) JSSD1.73(GND_73) JSSD1.75(CONFIG_2) JSSD1.76(MTG1) JSSD1.77(MTG2) JT1.1(GND5) JT1.2(GND6) JT1.3(GND7) JT1.4(GND8) JT1.5(GND9) JT1.6(GND10) JT1.A1(GND1) JT1.A12(GND2) JT1.B1(GND3) JT1.B12(GND4) JW1.1(GND[1]) JW1.7(GND[2]) JW1.13(GND[3]) JW1.18(GND[4]) JW1.19(GND[5]) JW1.33(GND[6]) JW1.39(GND[7]) JW1.45(GND[8]) JW1.51(GND[9]) JW1.57(GND[10]) JW1.63(GND[11]) JW1.69(GND[12]) JW1.75(GND[13]) JW1.76 JW1.77 JX1.12 JX1.15 JX1.18 JX1.21 JX1.26 JX1.29 JX1.32 JX1.35 JX1.38 JX1.41(GND2) JX1.42(GND1) MR1.3(GND) PC1.2 PC101.2 PC105.2 PC106.2 PC107.2 PC108.2 PC109.2 PC110.2 PC111.2 PC120.1 PC122.2 PC124.1 PC125.2 PC126.2 PC129.2 PC130.2 PC132.2 PC134.2 PC135.2 PC136.2 PC137.2 PC138.2 PC139.2 PC140.2 PC141.2 PC142.2 PC143.2 PC144.2 PC145.2 PC146.2 PC150.2 PC152.2 PC153.2 PC155.2 PC182.2 PC201.2 PC204.2 PC205.2 PC206.2 PC207.2 PC208.2 PC209.2 PC213.2 PC214.2 PC215.2 PC216.2 PC220.2 PC301.2 PC302.2 PC305.2 PC306.2 PC309.2 PC310.2 PC311.2 PC312.2 PC313.2 PC314.2 PC316.2 PC317.2 PC319.2 PC320.2 PC401.2 PC402.2 PC403.2 PC404.2 PC406.2 PC410.2 PC411.2 PC413.2 PC414.2 PC415.2 PC502.2 PC503.2 PC504.1 PC506.2 PC510.1 PC511.2 PC512.2 PC513.2 PC514.2 PC515.2 PC516.2 PC517.2 PC518.2 PC519.2 PC520.2 PC521.2 PC522.2 PC530.2 PC601.2 PC602.2 PC603.1 PC604.2 PC606.1 PC607.1 PC611.2 PC613.1 PC615.2 PC617.1 PC618.2 PC619.2 PC620.2 PC622.2 PC623.2 PC624.2 PC625.2 PC626.2 PC627.2 PC628.2 PC629.2 PC630.2 PC631.2 PC641.2 PC656.2 PC657.1 PC658.1 PC659.1 PC701.2 PC703.2 PC704.2 PC705.2 PC708.2 PC709.2 PC710.2 PC711.2 PC712.2 PC714.2 PC715.2 PC716.2 PC717.2 PC718.2 PC719.2 PC720.2 PC721.2 PC730.2 PC819.2 PC820.2 PC821.2 PC822.2 PC823.2 PC824.2 PC825.2 PC827.2 PC828.2 PC830.1 PC833.2 PC834.2 PC836.2 PC837.2 PC855.1 PC857.2 PC858.2 PC859.2 PC860.2 PC864.2 PC865.2 PC901.2 PC902.2 PC903.2 PC904.2 PC905.2 PC906.2 PC907.2 PC908.2 PC909.2 PC910.2 PC911.2 PC912.2 PC913.2 PC914.2 PC915.2 PC916.2 PC930.2 PC931.2 PC932.2 PC969.2 PC970.2 PC971.2 PC972.2 PC975.2 PC976.2 PC977.2 PC978.2 PC1102.2 PC1103.2 PC1104.2 PC1105.2 PC1106.2 PC1107.2 PC1108.2 PC1109.2 PC1110.2 PC1120.2 PC1121.2 PC1122.2 PC1123.2 PC1124.2 PC1201.2 PC1202.2 PC1203.2 PC1204.2 PC1205.2 PC1208.2 PC1209.2 PC1210.2 PC1211.2 PC1212.2 PC1213.2 PC1214.2 PC1215.2 PC11258.2 PCS501.2 PCS502.2 PCS601.2 PCS602.2 PCS604.2 PCS606.2 PCS801.2 PCS802.2 PCS804.2 PESD104.2 PESD105.1 PESD106.3 PESD107.1 PESD107.2 PJ101.1 PJ101.2 PJ101.9 PJ101.10 PJ102.2 PJ102.4 PJ102.5 PQ105.1(S1) PQ105.2(S2) PQ105.3(S3) PQ108.1(S1) PQ108.2(S2) PQ108.3(S3) PQ502.1(S1) PQ502.2(S2) PQ502.3(S3) PQ602.1(S1) PQ602.2(S2) PQ602.3(S3) PQ603.1(S1) PQ603.2(S2) PQ603.3(S3) PQ801.5(S2[1]) PQ801.6(S2[2]) PQ801.7(S2[3]) PQ802.5(S2[1]) PQ802.6(S2[2]) PQ802.7(S2[3]) PQ901.2(S) PQ902.2(S) PR138.1 PR167.1 PR168.1 PR169.2 PR188.1 PR205.1 PR307.1 PR404.1 PR410.1 PR415.1 PR503.1 PR504.1 PR507.1 PR509.1 PR521.2 PR527.1 PR624.1 PR625.1 PR626.1 PR627.1 PR631.1 PR637.2 PR712.2 PR822.1 PR836.2 PR852.1 PR860.1 PR903.1 PR914.1 PR1103.1 PR1108.1 PR1111.1 PR1201.2 PSH101.2(B[0]) PTP105.1 PTP106.1 PU101.27(PGND) PU101.33(PAD) PU201.4(PGND) PU201.8(AGND) PU301.4(PGND) PU301.8(AGND) PU401.7(GND) PU402.2(GND) PU501.14(PGND) PU501.21(AGND) PU601.33(GND) PU701.3(AGND) PU701.9(PGND) PU701.16(PGND_VDD1) PU802.21(GND) PU901.1(GND) PU902.11(GND) PU902.15(GPND) PU903.1(GND) PU904.1(GND) PU906.1(GND) PU910.B1(GND) PU1101.7(GND1) PU1101.8(GND2) PU1101.18(GND3) PU1101.21(GND4) PU1201.11(GND) PU1201.15(GPND) PU1202.5(GND) QA1.1(S1) QA1.4(S1) QE2.2(S) QE4.2 QL1.2 QL4.2 QL6.2 QL7.2 QL8.2 QL9.2(S) QL10.2 QT1.2(S) QT2.2(S) QT5.2(S) QU2.2(S) QV4.1(S1) QV4.4(S1) QV6.1(S1) QV6.4(S1) QV7.2 QV8.2(S) QV9.2(S) QV10.2(S) QV11.2 QV12.2 QV14.2 QV17.2(S) QV18.2 QV19.2 QV20.2 QV21.2(S) QV22.2 QV23.2(S) QV24.2(S) RA4.1 RA17.2 RA18.2 RA19.2 RB45.2 RB46.2 RB47.2 RB50.2 RE86.2 RE95.2 RE114.1 RE121.2 RE138.2 RF10.1 RI33.1 RI40.1 RI102.1 RI104.1 RI144.2 RI145.1 RI146.1 RI149.1 RL2.1 RL454.1 RN5.1 RN33.1 RT4.2 RT17.2 RT23.1 RT32.1 RT33.1 RT43.1 RT45.1 RT50.1 RT52.1 RT53.1 RT55.1 RT58.1 RT61.1 RT63.1 RT65.1 RT78.1 RT81.1 RT83.1 RT91.1 RT92.1 RT96.1 RT97.1 RT103.1 RT104.2 RT105.2 RT106.1 RT113.2 RT115.2 RT118.2 RT119.2 RT122.1 RT123.1 RT131.2 RT132.2 RT133.2 RT134.2 RU1.2 RU2.2 RU3.2 RU6.1 RU12.1 RU13.1 RU14.1 RU15.1 RU16.1 RU22.2 RU26.1 RU28.1 RU34.2 RU44.1 RU45.1 RU46.1 RU54.2 RU57.1 RU58.1 RU59.1 RU60.1 RU61.1 RU62.1 RU63.1 RU65.2 RU67.1 RU73.2 RU76.1 RU78.1 RU88.1 RU90.1 RU93.2 RU95.2 RU97.2 RU99.2 RU100.2 RU106.2 RU108.2 RU110.2 RU113.1 RU117.1 RU122.2 RU124.1 RU134.1 RU137.2 RU139.1 RU140.1 RU141.2 RU146.1 RU147.1 RU150.1 RU153.1 RU159.1 RU160.1 RU165.1 RU173.2 RU175.2 RU176.2 RU177.2 RU178.2 RU179.2 RU180.2 RU181.2 RU192.1 RU193.1 RU194.1 RU195.1 RU196.1 RU197.1 RU198.1 RU199.1 RU200.1 RU201.1 RU202.1 RU203.1 RU204.1 RU205.1 RU206.1 RU207.1 RU208.1 RU209.1 RU210.1 RU211.1 RU212.1 RU217.1 RU223.2 RU225.2 RU232.1 RV2.2 RV12.1 RV21.1 RV44.1 RV47.1 RV48.1 RV57.1 RV60.2 RV63.2 RV64.2 RV65.2 RV67.2 RV68.2 RV92.1 RV93.1 RV96.1 RV97.1 RV98.1 RV99.2 RV100.2 RV103.2 RV113.2 RV114.2 RV115.2 RV119.2 RV120.2 RV121.2 RV125.2 RV126.2 RV127.2 RV142.1 RV143.1 RW25.1 RW70.1 RX12.1 RX16.1 RX18.1 RX22.1 RX901.1 RX908.2 RX919.1 RX920.2 SW3.3 SW3.4 SW4.3 SW5.3 SW5.4 TH1.1 TH5.1 TH8.1 TH10.1 TH12.1 TH13.1 TH14.1 TP144.1 TP148.1 TP190.1 TP192.1 TP195.1 TPE104.1 TPP12.1 TPP15.1 TPT2.1 TPT13.1 TPU9.1 TPWC2.1 UA2.61(EP_GND) UB6.14(GND) UB6.17(GND_PAD) UD1.A3(VSS_1) UD1.A10(VSS_57) UD1.AB3(VSS_56) UD1.AB5(VSS_55) UD1.AB8(VSS_54) UD1.AB10(VSS_53) UD1.C1(VSS_52) UD1.C3(DMI0_A) UD1.C5(VSS_51) UD1.C8(VSS_50) UD1.C10(DMI1_A) UD1.C12(VSS_49) UD1.D2(VSS_48) UD1.D4(VSS_47) UD1.D9(VSS_46) UD1.D11(VSS_45) UD1.E1(VSS_44) UD1.E5(VSS_43) UD1.E8(VSS_42) UD1.E12(VSS_41) UD1.G1(VSS_40) UD1.G3(VSS_39) UD1.G5(VSS_38) UD1.G8(VSS_37) UD1.G10(VSS_36) UD1.G12(VSS_35) UD1.J1(VSS_34) UD1.J3(VSS_33) UD1.J10(VSS_32) UD1.J12(VSS_31) UD1.K2(VSS_30) UD1.K4(VSS_29) UD1.K9(VSS_28) UD1.K11(VSS_27) UD1.N2(VSS_26) UD1.N4(VSS_25) UD1.N9(VSS_24) UD1.N11(VSS_23) UD1.P1(VSS_22) UD1.P3(VSS_21) UD1.P10(VSS_20) UD1.P12(VSS_19) UD1.T1(VSS_18) UD1.T3(VSS_17) UD1.T5(VSS_16) UD1.T8(VSS_15) UD1.T10(VSS_14) UD1.T12(VSS_13) UD1.V1(VSS_12) UD1.V5(VSS_11) UD1.V8(VSS_10) UD1.V12(VSS_9) UD1.W2(VSS_8) UD1.W4(VSS_7) UD1.W9(VSS_6) UD1.W11(VSS_5) UD1.Y1(VSS_4) UD1.Y3(DMI0_B) UD1.Y5(VSS_3) UD1.Y8(VSS_2) UD1.Y10(DMI1_B) UD1.Y12(VSS_58) UD2.A3(VSS_1) UD2.A10(VSS_57) UD2.AB3(VSS_56) UD2.AB5(VSS_55) UD2.AB8(VSS_54) UD2.AB10(VSS_53) UD2.C1(VSS_52) UD2.C3(DMI0_A) UD2.C5(VSS_51) UD2.C8(VSS_50) UD2.C10(DMI1_A) UD2.C12(VSS_49) UD2.D2(VSS_48) UD2.D4(VSS_47) UD2.D9(VSS_46) UD2.D11(VSS_45) UD2.E1(VSS_44) UD2.E5(VSS_43) UD2.E8(VSS_42) UD2.E12(VSS_41) UD2.G1(VSS_40) UD2.G3(VSS_39) UD2.G5(VSS_38) UD2.G8(VSS_37) UD2.G10(VSS_36) UD2.G12(VSS_35) UD2.J1(VSS_34) UD2.J3(VSS_33) UD2.J10(VSS_32) UD2.J12(VSS_31) UD2.K2(VSS_30) UD2.K4(VSS_29) UD2.K9(VSS_28) UD2.K11(VSS_27) UD2.N2(VSS_26) UD2.N4(VSS_25) UD2.N9(VSS_24) UD2.N11(VSS_23) UD2.P1(VSS_22) UD2.P3(VSS_21) UD2.P10(VSS_20) UD2.P12(VSS_19) UD2.T1(VSS_18) UD2.T3(VSS_17) UD2.T5(VSS_16) UD2.T8(VSS_15) UD2.T10(VSS_14) UD2.T12(VSS_13) UD2.V1(VSS_12) UD2.V5(VSS_11) UD2.V8(VSS_10) UD2.V12(VSS_9) UD2.W2(VSS_8) UD2.W4(VSS_7) UD2.W9(VSS_6) UD2.W11(VSS_5) UD2.Y1(VSS_4) UD2.Y3(DMI0_B) UD2.Y5(VSS_3) UD2.Y8(VSS_2) UD2.Y10(DMI1_B) UD2.Y12(VSS_58) UD3.A3(VSS_1) UD3.A10(VSS_57) UD3.AB3(VSS_56) UD3.AB5(VSS_55) UD3.AB8(VSS_54) UD3.AB10(VSS_53) UD3.C1(VSS_52) UD3.C3(DMI0_A) UD3.C5(VSS_51) UD3.C8(VSS_50) UD3.C10(DMI1_A) UD3.C12(VSS_49) UD3.D2(VSS_48) UD3.D4(VSS_47) UD3.D9(VSS_46) UD3.D11(VSS_45) UD3.E1(VSS_44) UD3.E5(VSS_43) UD3.E8(VSS_42) UD3.E12(VSS_41) UD3.G1(VSS_40) UD3.G3(VSS_39) UD3.G5(VSS_38) UD3.G8(VSS_37) UD3.G10(VSS_36) UD3.G12(VSS_35) UD3.J1(VSS_34) UD3.J3(VSS_33) UD3.J10(VSS_32) UD3.J12(VSS_31) UD3.K2(VSS_30) UD3.K4(VSS_29) UD3.K9(VSS_28) UD3.K11(VSS_27) UD3.N2(VSS_26) UD3.N4(VSS_25) UD3.N9(VSS_24) UD3.N11(VSS_23) UD3.P1(VSS_22) UD3.P3(VSS_21) UD3.P10(VSS_20) UD3.P12(VSS_19) UD3.T1(VSS_18) UD3.T3(VSS_17) UD3.T5(VSS_16) UD3.T8(VSS_15) UD3.T10(VSS_14) UD3.T12(VSS_13) UD3.V1(VSS_12) UD3.V5(VSS_11) UD3.V8(VSS_10) UD3.V12(VSS_9) UD3.W2(VSS_8) UD3.W4(VSS_7) UD3.W9(VSS_6) UD3.W11(VSS_5) UD3.Y1(VSS_4) UD3.Y3(DMI0_B) UD3.Y5(VSS_3) UD3.Y8(VSS_2) UD3.Y10(DMI1_B) UD3.Y12(VSS_58) UD4.A3(VSS_1) UD4.A10(VSS_57) UD4.AB3(VSS_56) UD4.AB5(VSS_55) UD4.AB8(VSS_54) UD4.AB10(VSS_53) UD4.C1(VSS_52) UD4.C3(DMI0_A) UD4.C5(VSS_51) UD4.C8(VSS_50) UD4.C10(DMI1_A) UD4.C12(VSS_49) UD4.D2(VSS_48) UD4.D4(VSS_47) UD4.D9(VSS_46) UD4.D11(VSS_45) UD4.E1(VSS_44) UD4.E5(VSS_43) UD4.E8(VSS_42) UD4.E12(VSS_41) UD4.G1(VSS_40) UD4.G3(VSS_39) UD4.G5(VSS_38) UD4.G8(VSS_37) UD4.G10(VSS_36) UD4.G12(VSS_35) UD4.J1(VSS_34) UD4.J3(VSS_33) UD4.J10(VSS_32) UD4.J12(VSS_31) UD4.K2(VSS_30) UD4.K4(VSS_29) UD4.K9(VSS_28) UD4.K11(VSS_27) UD4.N2(VSS_26) UD4.N4(VSS_25) UD4.N9(VSS_24) UD4.N11(VSS_23) UD4.P1(VSS_22) UD4.P3(VSS_21) UD4.P10(VSS_20) UD4.P12(VSS_19) UD4.T1(VSS_18) UD4.T3(VSS_17) UD4.T5(VSS_16) UD4.T8(VSS_15) UD4.T10(VSS_14) UD4.T12(VSS_13) UD4.V1(VSS_12) UD4.V5(VSS_11) UD4.V8(VSS_10) UD4.V12(VSS_9) UD4.W2(VSS_8) UD4.W4(VSS_7) UD4.W9(VSS_6) UD4.W11(VSS_5) UD4.Y1(VSS_4) UD4.Y3(DMI0_B) UD4.Y5(VSS_3) UD4.Y8(VSS_2) UD4.Y10(DMI1_B) UD4.Y12(VSS_58) UE1.D6(VSS1) UE1.E10(AVSS) UE1.F5(VSS2) UE1.G4(VSS3) UE1.G5(VSS4) UE1.H5(VSS5) UE2.4(VSS) UF15.16(GND1) UF15.23(GND2) UF15.33(EPAD) UI1.2(GND) UI2.49(EPAD) UO1.4(VSS) US1.6(GND) US4.2(GND) UT1.41(EPAD) UT2.A11(PA_MONDC) UT2.B1(VSS_ANA_1) UT2.B2(FUSE_VQPS_64) UT2.B11(TEST_EN) UT2.B12(VSS_ANA_2) UT2.D1(VSS_ANA_3) UT2.D2(VSS_ANA_6) UT2.D11(VSS_ANA_4) UT2.D12(VSS_ANA_5) UT2.F1(VSS_ANA_7) UT2.F2(VSS_ANA_8) UT2.F3(VSS_ANA_9) UT2.F5(VSS_1) UT2.F7(VSS_2) UT2.F9(VSS_ANA_10) UT2.F11(VSS_ANA_11) UT2.F12(VSS_ANA_12) UT2.G5(VSS_3) UT2.G7(VSS_4) UT2.H1(VSS_ANA_13) UT2.H2(VSS_ANA_14) UT2.H11(VSS_ANA_15) UT2.H12(VSS_ANA_16) UT2.J9(VSS_ANA_17) UT2.K1(VSS_ANA_18) UT2.K2(VSS_ANA_19) UT2.K11(VSS_ANA_20) UT2.K12(VSS_ANA_21) UT2.L12(MONDC_SVR) UT2.M2(SVR_VSS[1]) UT2.M3(SVR_VSS[2]) UT2.M12(TEST_EDM) UT3.4(VSS) UT4.2(GND) UT5.B3(GND01) UT5.C3(GND02) UT5.D3(GND03) UT6.C3(GND1) UT6.D3(GND2) UT6.E3(GND3) UT7.8(GND1) UT7.13(GND2) UT7.18(GND3) UT7.21(TPAD) UU1.A3(VSS_72) UU1.A11(VSS_1) UU1.A16(VSS_429) UU1.A17(VSS_61) UU1.A31(VSS_83) UU1.A34(VSS_94) UU1.A36(VSS_105) UU1.A39(VSS_116) UU1.A42(VSS_127) UU1.A44(VSS_138) UU1.A46(VSS_2) UU1.A48(VSS_13) UU1.A49(VSS_24) UU1.AA45(VSS_35) UU1.AA47(VSS_46) UU1.AB3(VSS_57) UU1.AB5(VSS_64) UU1.AB6(VSS_65) UU1.AB11(VSS_56) UU1.AB38(VSS_58) UU1.AB39(VSS_59) UU1.AB41(VSS_60) UU1.AB42(VSS_62) UU1.AB43(VSS_63) UU1.AC45(VSS_66) UU1.AC49(VSS_67) UU1.AD10(VSS_68) UU1.AD11(VSS_69) UU1.AD34(VSS_70) UU1.AD37(VSS_71) UU1.AE6(VSS_73) UU1.AF37(VSS_74) UU1.AF45(VSS_75) UU1.AF47(VSS_76) UU1.AG1(VSS_77) UU1.AG3(VSS_79) UU1.AG5(VSS_86) UU1.AG9(VSS_87) UU1.AG11(VSS_78) UU1.AG38(VSS_80) UU1.AG39(VSS_81) UU1.AG41(VSS_82) UU1.AG42(VSS_84) UU1.AG43(VSS_85) UU1.AH2(VSS_88) UU1.AH37(VSS_89) UU1.AH45(VSS_90) UU1.AH49(VSS_91) UU1.AJ2(VSS_92) UU1.AJ3(VSS_93) UU1.AK37(VSS_95) UU1.AL2(VSS_96) UU1.AL6(VSS_99) UU1.AL45(VSS_97) UU1.AL47(VSS_98) UU1.AM2(VSS_100) UU1.AM37(VSS_101) UU1.AN2(VSS_102) UU1.AN6(VSS_111) UU1.AN38(VSS_103) UU1.AN39(VSS_104) UU1.AN41(VSS_106) UU1.AN42(VSS_107) UU1.AN43(VSS_108) UU1.AN45(VSS_109) UU1.AN49(VSS_110) UU1.AR1(VSS_112) UU1.AR2(VSS_114) UU1.AR3(VSS_115) UU1.AR7(VSS_117) UU1.AR9(VSS_118) UU1.AR11(VSS_113) UU1.AT3(VSS_119) UU1.AT5(VSS_122) UU1.AT6(VSS_123) UU1.AT7(VSS_124) UU1.AT45(VSS_120) UU1.AT47(VSS_121) UU1.AU37(VSS_125) UU1.AV3(VSS_128) UU1.AV7(VSS_136) UU1.AV11(VSS_126) UU1.AV38(VSS_129) UU1.AV39(VSS_130) UU1.AV41(VSS_131) UU1.AV42(VSS_132) UU1.AV43(VSS_133) UU1.AV45(VSS_134) UU1.AV49(VSS_135) UU1.AY3(VSS_137) UU1.AY7(VSS_139) UU1.B2(VSS_141) UU1.B3(VSS_144) UU1.B17(VSS_140) UU1.B21(VSS_142) UU1.B24(VSS_143) UU1.B31(VSS_145) UU1.B48(VSS_146) UU1.BA1(VSS_147) UU1.BA2(VSS_148) UU1.BA45(VSS_3) UU1.BA47(VSS_4) UU1.BB3(VSS_6) UU1.BB7(VSS_7) UU1.BB11(VSS_5) UU1.BC37(VSS_8) UU1.BD3(VSS_9) UU1.BD5(VSS_18) UU1.BD6(VSS_19) UU1.BD7(VSS_20) UU1.BD38(VSS_10) UU1.BD39(VSS_11) UU1.BD41(VSS_12) UU1.BD42(VSS_14) UU1.BD43(VSS_15) UU1.BD45(VSS_16) UU1.BD46(NC/D\D\R\0\_\A\L\E\R\T\_\N\) UU1.BD49(VSS_17) UU1.BE1(VSS_21) UU1.BE2(VSS_22) UU1.BF3(VSS_23) UU1.BF7(VSS_27) UU1.BF45(VSS_25) UU1.BF47(VSS_26) UU1.BG3(VSS_28) UU1.BG7(VSS_30) UU1.BG41(VSS_29) UU1.BH37(VSS_31) UU1.BJ1(VSS_32) UU1.BJ2(VSS_33) UU1.BJ3(VSS_34) UU1.BJ7(VSS_40) UU1.BJ41(VSS_36) UU1.BJ43(VSS_37) UU1.BJ45(VSS_38) UU1.BJ49(VSS_39) UU1.BM3(VSS_42) UU1.BM5(VSS_45) UU1.BM6(VSS_47) UU1.BM7(VSS_48) UU1.BM11(VSS_41) UU1.BM45(VSS_43) UU1.BM47(VSS_44) UU1.BP1(VSS_49) UU1.BP2(VSS_50) UU1.BP3(VSS_51) UU1.BP7(VSS_53) UU1.BP43(VSS_52) UU1.BR45(VSS_54) UU1.BR49(VSS_55) UU1.BT3(VSS_149) UU1.BT7(VSS_154) UU1.BT39(VSS_150) UU1.BT41(VSS_151) UU1.BT42(VSS_152) UU1.BT43(VSS_153) UU1.BU45(VSS_155) UU1.BU47(VSS_156) UU1.BV1(VSS_157) UU1.BV2(VSS_159) UU1.BV3(VSS_160) UU1.BV7(VSS_161) UU1.BV11(VSS_158) UU1.BW3(VSS_162) UU1.BW5(VSS_164) UU1.BW6(VSS_165) UU1.BW7(VSS_166) UU1.BW37(VSS_163) UU1.BY37(VSS_167) UU1.BY45(VSS_168) UU1.BY49(VSS_169) UU1.C6(VSS_181) UU1.C11(VSS_170) UU1.C13(VSS_171) UU1.C14(VSS_172) UU1.C16(VSS_428) UU1.C17(VSS_173) UU1.C21(VSS_174) UU1.C24(VSS_175) UU1.C31(VSS_176) UU1.C34(VSS_177) UU1.C39(VSS_178) UU1.C48(VSS_179) UU1.C49(VSS_180) UU1.CA3(VSS_182) UU1.CA7(VSS_187) UU1.CA38(VSS_183) UU1.CA41(VSS_184) UU1.CA42(VSS_185) UU1.CA43(VSS_186) UU1.CB37(VSS_188) UU1.CB45(VSS_189) UU1.CB47(VSS_190) UU1.CC3(VSS_191) UU1.CC7(VSS_192) UU1.CE9(VSS_196) UU1.CE37(VSS_193) UU1.CE45(VSS_194) UU1.CE49(VSS_195) UU1.CG9(VSS_202) UU1.CG37(VSS_197) UU1.CG39(VSS_198) UU1.CG43(VSS_199) UU1.CG45(VSS_200) UU1.CG47(VSS_201) UU1.CH3(VSS_203) UU1.CH5(VSS_204) UU1.CJ9(VSS_207) UU1.CJ37(VSS_205) UU1.CJ42(VSS_206) UU1.CK9(VSS_210) UU1.CK45(VSS_208) UU1.CK49(VSS_209) UU1.CL37(VSS_211) UU1.CL42(VSS_212) UU1.CL49(VSS_213) UU1.CM9(VSS_216) UU1.CM45(VSS_214) UU1.CM47(VSS_215) UU1.CN3(VSS_217) UU1.CN5(VSS_220) UU1.CN37(VSS_218) UU1.CN39(VSS_219) UU1.CP9(VSS_221) UU1.CR32(VSS_222) UU1.CR37(VSS_223) UU1.CR45(VSS_224) UU1.CR49(VSS_225) UU1.CT9(VSS_229) UU1.CT37(VSS_226) UU1.CT39(VSS_227) UU1.CT42(VSS_228) UU1.CU45(VSS_230) UU1.CU47(VSS_231) UU1.CU49(VSS_232) UU1.CV3(VSS_233) UU1.CV5(VSS_236) UU1.CV9(VSS_237) UU1.CV34(VSS_234) UU1.CV35(VSS_235) UU1.CY9(VSS_241) UU1.CY41(VSS_238) UU1.CY45(VSS_239) UU1.CY49(VSS_240) UU1.D13(VSS_242) UU1.D17(VSS_243) UU1.D31(VSS_244) UU1.D44(VSS_245) UU1.D49(VSS_246) UU1.DA9(VSS_249) UU1.DA10(VSS_247) UU1.DA33(VSS_248) UU1.DB32(VSS_250) UU1.DB35(VSS_251) UU1.DB38(VSS_252) UU1.DB45(VSS_253) UU1.DB47(VSS_254) UU1.DB49(VSS_255) UU1.DC3(VSS_256) UU1.DC5(VSS_258) UU1.DC6(VSS_259) UU1.DC49(VSS_257) UU1.DD37(VSS_260) UU1.DD42(VSS_261) UU1.DE6(VSS_274) UU1.DE10(VSS_262) UU1.DE13(VSS_263) UU1.DE15(VSS_427) UU1.DE17(VSS_264) UU1.DE18(VSS_265) UU1.DE20(VSS_266) UU1.DE22(VSS_267) UU1.DE23(VSS_268) UU1.DE26(VSS_269) UU1.DE28(VSS_270) UU1.DE29(VSS_271) UU1.DE33(VSS_272) UU1.DE45(VSS_273) UU1.DF13(VSS_275) UU1.DF22(VSS_276) UU1.DF28(VSS_277) UU1.DF33(VSS_278) UU1.DF35(VSS_279) UU1.DF39(VSS_280) UU1.DG6(VSS_288) UU1.DG10(VSS_281) UU1.DG12(VSS_282) UU1.DG13(VSS_283) UU1.DG15(VSS_284) UU1.DG22(VSS_285) UU1.DG23(VSS_286) UU1.DG47(VSS_287) UU1.DH1(VSS_289) UU1.DH3(VSS_290) UU1.DH5(VSS_292) UU1.DH45(VSS_291) UU1.DJ19(VSS_293) UU1.DJ21(VSS_294) UU1.DJ27(VSS_295) UU1.DJ31(VSS_296) UU1.DJ33(VSS_297) UU1.DJ36(VSS_298) UU1.DJ42(VSS_299) UU1.DK3(VSS_300) UU1.DK4(VSS_301) UU1.DK6(VSS_303) UU1.DK8(VSS_304) UU1.DK49(VSS_302) UU1.DL10(VSS_305) UU1.DL13(VSS_306) UU1.DL44(VSS_307) UU1.DL47(VSS_308) UU1.DM47(VSS_309) UU1.DN15(VSS_310) UU1.DN19(VSS_311) UU1.DN24(VSS_312) UU1.DN31(VSS_313) UU1.DN36(VSS_314) UU1.DN42(VSS_315) UU1.DP45(VSS_316) UU1.DR49(VSS_317) UU1.DT1(VSS_318) UU1.DT3(VSS_323) UU1.DT6(VSS_328) UU1.DT7(VSS_329) UU1.DT8(VSS_330) UU1.DT10(VSS_319) UU1.DT15(VSS_320) UU1.DT20(VSS_321) UU1.DT27(VSS_322) UU1.DT32(VSS_324) UU1.DT37(VSS_325) UU1.DT42(VSS_326) UU1.DT49(VSS_327) UU1.DU1(VSS_331) UU1.DU2(VSS_334) UU1.DU7(VSS_341) UU1.DU10(VSS_332) UU1.DU15(VSS_333) UU1.DU20(VSS_335) UU1.DU27(VSS_336) UU1.DU32(VSS_337) UU1.DU37(VSS_338) UU1.DU47(VSS_432) UU1.DU48(VSS_339) UU1.DU49(VSS_340) UU1.DV2(VSS_342) UU1.DV8(VSS_345) UU1.DV44(VSS_343) UU1.DV48(VSS_344) UU1.DW1(VSS_346) UU1.DW2(VSS_348) UU1.DW7(VSS_355) UU1.DW10(VSS_347) UU1.DW20(VSS_349) UU1.DW27(VSS_350) UU1.DW44(VSS_351) UU1.DW46(VSS_352) UU1.DW48(VSS_353) UU1.DW49(VSS_354) UU1.E6(VSS_361) UU1.E11(VSS_356) UU1.E34(VSS_357) UU1.E36(VSS_358) UU1.E39(VSS_359) UU1.E42(VSS_360) UU1.F8(VSS_366) UU1.F11(VSS_362) UU1.F31(VSS_363) UU1.F45(VSS_364) UU1.F47(VSS_365) UU1.G3(VSS_369) UU1.G5(VSS_373) UU1.G21(VSS_367) UU1.G24(VSS_368) UU1.G31(VSS_370) UU1.G36(VSS_371) UU1.G49(VSS_372) UU1.H17(VSS_374) UU1.H21(VSS_375) UU1.H24(VSS_376) UU1.H31(VSS_377) UU1.H33(VSS_378) UU1.H36(VSS_379) UU1.H45(VSS_380) UU1.H49(VSS_381) UU1.J6(VSS_386) UU1.J10(VSS_382) UU1.J13(VSS_383) UU1.J15(VSS_430) UU1.J16(VSS_384) UU1.J36(VSS_385) UU1.K8(VSS_389) UU1.K11(VSS_387) UU1.K15(VSS_431) UU1.K33(VSS_388) UU1.L36(VSS_390) UU1.L39(VSS_391) UU1.L41(VSS_392) UU1.L42(VSS_393) UU1.L43(VSS_394) UU1.L45(VSS_395) UU1.L47(VSS_396) UU1.M3(VSS_398) UU1.M5(VSS_400) UU1.M10(VSS_397) UU1.M36(VSS_399) UU1.M49(NC/D\D\R\1\_\A\L\E\R\T\_\N\) UU1.N45(VSS_401) UU1.N49(VSS_402) UU1.P8(VSS_405) UU1.P11(VSS_403) UU1.P41(VSS_404) UU1.R3(VSS_406) UU1.R37(VSS_407) UU1.T11(VSS_408) UU1.T36(VSS_409) UU1.T41(VSS_410) UU1.T43(VSS_411) UU1.T45(VSS_412) UU1.T47(VSS_413) UU1.U3(VSS_414) UU1.U5(VSS_416) UU1.U37(VSS_415) UU1.V9(VSS_421) UU1.V11(VSS_417) UU1.V36(VSS_418) UU1.V45(VSS_419) UU1.V49(VSS_420) UU1.W37(VSS_422) UU1.Y9(VSS_426) UU1.Y36(VSS_423) UU1.Y38(VSS_424) UU1.Y43(VSS_425) UU2.3(GND) UV1.3(GND) UV2.A2(GND_001) UV2.A26(GND_002) UV2.AA7(GND_F) UV2.AB7(GND_H) UV2.AB11(GND_003) UV2.AB14(GND_004) UV2.AB17(GND_005) UV2.AB20(GND_006) UV2.AB24(GND_007) UV2.AC2(GND_008) UV2.AC5(GND_011) UV2.AC8(GND_012) UV2.AC22(GND_009) UV2.AC26(GND_010) UV2.AD12(GND_013) UV2.AD13(GND_014) UV2.AD15(GND_015) UV2.AD16(GND_016) UV2.AD18(GND_017) UV2.AD19(GND_018) UV2.AD21(GND_019) UV2.AD22(GND_020) UV2.AE11(GND_021) UV2.AE14(GND_022) UV2.AE17(GND_023) UV2.AE20(GND_024) UV2.AF1(GND_025) UV2.AF5(GND_031) UV2.AF8(GND_032) UV2.AF11(GND_026) UV2.AF14(GND_027) UV2.AF17(GND_028) UV2.AF20(GND_029) UV2.AF23(GND_030) UV2.AG2(GND_033) UV2.AG26(GND_034) UV2.B1(GND_035) UV2.B5(GND_042) UV2.B8(GND_043) UV2.B11(GND_036) UV2.B14(GND_037) UV2.B17(GND_038) UV2.B20(GND_039) UV2.B23(GND_040) UV2.B27(GND_041) UV2.E2(GND_047) UV2.E5(GND_051) UV2.E8(GND_052) UV2.E11(GND_044) UV2.E14(GND_045) UV2.E17(GND_046) UV2.E20(GND_048) UV2.E22(GND_049) UV2.E25(GND_050) UV2.H2(GND_053) UV2.H5(GND_056) UV2.H23(GND_054) UV2.H25(GND_055) UV2.K11(GND_057) UV2.K13(GND_058) UV2.K15(GND_059) UV2.K17(GND_060) UV2.L2(GND_066) UV2.L5(GND_069) UV2.L10(GND_061) UV2.L12(GND_062) UV2.L14(GND_063) UV2.L16(GND_064) UV2.L18(GND_065) UV2.L23(GND_067) UV2.L25(GND_068) UV2.M11(GND_070) UV2.M13(GND_071) UV2.M15(GND_072) UV2.M17(GND_073) UV2.N10(GND_074) UV2.N12(GND_075) UV2.N14(GND_076) UV2.N16(GND_077) UV2.N18(GND_078) UV2.P2(GND_083) UV2.P5(GND_086) UV2.P11(GND_079) UV2.P13(GND_080) UV2.P15(GND_081) UV2.P17(GND_082) UV2.P23(GND_084) UV2.P26(GND_085) UV2.R10(GND_087) UV2.R12(GND_088) UV2.R14(GND_089) UV2.R16(GND_090) UV2.R18(GND_091) UV2.T11(GND_092) UV2.T13(GND_093) UV2.T15(GND_094) UV2.T17(GND_095) UV2.U2(GND_101) UV2.U5(GND_104) UV2.U10(GND_096) UV2.U12(GND_097) UV2.U14(GND_098) UV2.U16(GND_099) UV2.U18(GND_100) UV2.U23(GND_102) UV2.U26(GND_103) UV2.V11(GND_105) UV2.V13(GND_106) UV2.V15(GND_107) UV2.V17(GND_108) UV2.Y2(GND_109) UV2.Y5(GND_112) UV2.Y23(GND_110) UV2.Y26(GND_111) UV3.A1(VSSQ1) UV3.A3(VSSQ9) UV3.A12(VSSQ23) UV3.A14(VSSQ31) UV3.B5(VSS3) UV3.B10(VSS7) UV3.C1(VSSQ2) UV3.C3(VSSQ10) UV3.C4(VSSQ15) UV3.C11(VSSQ21) UV3.C12(VSSQ24) UV3.C14(VSSQ32) UV3.D10(VSS8) UV3.E1(VSSQ3) UV3.E3(VSSQ11) UV3.E12(VSSQ25) UV3.E14(VSSQ33) UV3.F5(VSSQ17) UV3.F10(VSSQ19) UV3.G5(VSS4) UV3.G10(VSS9) UV3.H1(VSS1) UV3.H2(VSSQ7) UV3.H13(VSSQ29) UV3.H14(VSS13) UV3.K1(VSS2) UV3.K2(VSSQ8) UV3.K13(VSSQ30) UV3.K14(VSS14) UV3.L5(VSS5) UV3.L10(VSS10) UV3.M5(VSSQ18) UV3.M10(VSSQ20) UV3.N1(VSSQ4) UV3.N3(VSSQ12) UV3.N12(VSSQ26) UV3.N14(VSSQ34) UV3.P10(VSS11) UV3.R1(VSSQ5) UV3.R3(VSSQ13) UV3.R4(VSSQ16) UV3.R11(VSSQ22) UV3.R12(VSSQ27) UV3.R14(VSSQ35) UV3.T5(VSS6) UV3.T10(VSS12) UV3.U1(VSSQ6) UV3.U3(VSSQ14) UV3.U12(VSSQ28) UV3.U14(VSSQ36) UV4.A1(VSSQ1) UV4.A3(VSSQ9) UV4.A12(VSSQ23) UV4.A14(VSSQ31) UV4.B5(VSS3) UV4.B10(VSS7) UV4.C1(VSSQ2) UV4.C3(VSSQ10) UV4.C4(VSSQ15) UV4.C11(VSSQ21) UV4.C12(VSSQ24) UV4.C14(VSSQ32) UV4.D10(VSS8) UV4.E1(VSSQ3) UV4.E3(VSSQ11) UV4.E12(VSSQ25) UV4.E14(VSSQ33) UV4.F5(VSSQ17) UV4.F10(VSSQ19) UV4.G5(VSS4) UV4.G10(VSS9) UV4.H1(VSS1) UV4.H2(VSSQ7) UV4.H13(VSSQ29) UV4.H14(VSS13) UV4.K1(VSS2) UV4.K2(VSSQ8) UV4.K13(VSSQ30) UV4.K14(VSS14) UV4.L5(VSS5) UV4.L10(VSS10) UV4.M5(VSSQ18) UV4.M10(VSSQ20) UV4.N1(VSSQ4) UV4.N3(VSSQ12) UV4.N12(VSSQ26) UV4.N14(VSSQ34) UV4.P10(VSS11) UV4.R1(VSSQ5) UV4.R3(VSSQ13) UV4.R4(VSSQ16) UV4.R11(VSSQ22) UV4.R12(VSSQ27) UV4.R14(VSSQ35) UV4.T5(VSS6) UV4.T10(VSS12) UV4.U1(VSSQ6) UV4.U3(VSSQ14) UV4.U12(VSSQ28) UV4.U14(VSSQ36) UW1.2(GND) UX1.2(GND) UX2.2(GND) WIFI_BOSS.1 XT1.2 XT1.4 YU2.2(GND1) YU2.4(GND2) YV1.2 YV1.4
GNDS_SENSE: TPE8.1 UV2.F3(GNDS_SENSE)
PVIN_VPP: PC703.1 PC721.1 PSH706.2(B[0]) PU701.14(PVIN_VDD1)
SGNDA_C: SHE3.1(A[0]) UA2.36(SGNDA)
SGNDB_C: SHE4.1(A[0]) UA2.37(SGNDB)
V1P2A_EN: PC415.1 PR413.2(B[0]) PU402.1(EN)
V1P2A_FB: PC412.1 PR410.2 PR412.1 PU402.6(FB)
V1P2A_LX: PL402.1 PU402.3(LX)
V1P2A_PGOOD: PR411.1 PU402.5(PG)
V1P8_SNS: PSH709.2(B[0]) PU701.12(VDD1SNS)
V1P8A_EN: PC401.1 PR401.2 PR414.2(B[0]) PU401.4(EN)
V1P8A_FB: PC405.1 PR403.1 PR404.2 PU401.1(FB)
V1P8A_FB_R: PC405.2 PR403.2 PSH401.1(A[0]) PU401.2(OUT)
V1P8A_LX: PL401.1 PU401.6(LX)
V1P8A_PGOOD: PR402.1 PR530.1 PU401.3(PG)
V3P3A_BOOT: PR201.1 PU201.1(BOOT)
V3P3A_BOOT_R: PC210.1 PR201.2
V3P3A_FB: PC211.2 PSH206.1(A[0]) PU201.10(VOUT)
V3P3A_FF: PR204.1 PU201.12(FF)
V3P3A_FF_R: PC211.1 PR204.2
V3P3A_IN: PC201.1 PC204.1 PC207.1 PC220.1 PSH201.2(B[0]) PSH202.2(B[0]) PU201.5(VIN)
V3P3A_LX: PC210.2 PL201.1 PU201.2(LX1) PU201.3(LX2)
V3P3A_OUT: PC205.1 PC206.1 PC208.1 PC209.1 PC213.1 PL201.2 PSH203.1(A[0]) PSH204.1(A[0]) PSH205.1(A[0]) PSH206.2(B[0])
V3P3A_PGOOD: PR203.1 PR401.1 PU201.7(PGOOD) QL6.1 RE96.1
V3P3A_PGOOD_EC: CE377.1 RE96.2 UE1.M1(LPCPD#/GPE6)
V3P3A_VCCD_PD: CT8.2 UT1.33(VCCD)
V3P3SX_EN: PR911.2(B[0]) PU902.5(EN2)
V5P0A_BST: PR301.1 PU301.1(BOOT)
V5P0A_BST_R: PC308.1 PR301.2
V5P0A_EN: PR305.2 PR307.2 PU301.6(EN)
V5P0A_FB: PC318.2 PC320.1 PSH306.1(A[0]) PU301.10(VOUT)
V5P0A_FF: PR306.1 PU301.9(FF)
V5P0A_FF_R: PC318.1 PR306.2
V5P0A_LDO: PC309.1 PU301.12(LDO5)
V5P0A_PGOOD: PR302.1 PR402.2 PR513.2 PR705.2 PU301.7(PGOOD) RE6.1
V5P0A_PGOOD_R: CE376.1 RE6.2 UE1.L2(PLTRST#/ECSMI#/GPD4)
V5P0A_VCC: PC319.1 PU301.11(VCC)
V5P0SX_EN: PR915.2(B[0]) PU902.3(EN1)
VBUS_C_CTRL: QT4.2(S) RT101.1 UT1.12(VBUS_C_CTRL)
VBUS_P_CTRL: QT1.1(G) RT3.1 UT1.11(VBUS_P_CTRL)
VBUS_P_CTRL_R: QT1.3(D) RT1.1 RT91.2 UT5.B4(EN)
VCC_DDR_PWROK: PR702.1 PR705.1 PR706.1(A[0]) UE1.G10(ADC0/GPI0)
VCC_VCCIN_SENSE_N: PR638.2 UU1.G17(VSSIN_SENSE)
VCC_VCCIN_SENSE_P: PR629.2 UU1.F17(VCCIN_SENSE)
VCCIN_AUX_BST: PR506.2 PU501.10(BOOT)
VCCIN_AUX_BST1_R: PC501.1 PR506.1
VCCIN_AUX_COMP: PC507.1 PC509.1 PU501.5(COMP)
VCCIN_AUX_EN: PC506.1 PR530.2 PU501.19(EN)
VCCIN_AUX_FB: PC508.1 PC509.2 PR522.2 PR524.1 PU501.6(FB)
VCCIN_AUX_FSW: PR519.1 PR521.1 PU501.9(FSWSEL)
VCCIN_AUX_HG: PR510.2 PU501.11(UG)
VCCIN_AUX_HG_R: PQ501.4(G1) PR510.1
VCCIN_AUX_ISEN_R: PR516.2 PR517.1 PRT501.1
VCCIN_AUX_ISENSEP: PC505.1 PR514.2 PR516.1 PR520.2 PR532.1
VCCIN_AUX_ISN: PR515.1 PU501.3(ISENSEN)
VCCIN_AUX_ISP: PR514.1 PU501.2(ISENSEP)
VCCIN_AUX_LG: PQ502.4(G1) PU501.13(LG)
VCCIN_AUX_PG: PR513.1 PU501.4(PG) RE8.1
VCCIN_AUX_PG_R: CE378.1 RE8.2 UE1.G2(ALERT#/SERIRQ/GPM6)
VCCIN_AUX_PHASE: PC501.2 PL501.1 PQ501.1(S1) PQ501.2(S2) PQ501.3(S3) PQ502.5(D1) PR532.2 PU501.12(PH)
VCCIN_AUX_RGND: PR526.1 PR527.2 PU501.7(RGND)
VCCIN_AUX_VCCSENSE: PR525.2 UU1.BF9(VCCIN_AUX_VCCSENSE)
VCCIN_AUX_VIN: PC517.1 PC518.1 PC519.1 PC520.1 PC521.1 PC522.1 PCS501.1 PQ501.5(D1) PSH501.1(A[0]) PSH502.1(A[0])
VCCIN_AUX_VOUT_R: PC510.2 PR518.1 PR523.2 PR524.2 PR525.1 PU501.8(VOUT)
VCCIN_AUX_VSSSENSE: PR526.2 UU1.BD9(VCCIN_AUX_VSSSENSE)
VCCIN_BOOT1: PR605.1 PU601.25(BOOT1)
VCCIN_BOOT1_R: PC605.1 PR605.2
VCCIN_BOOT2: PR613.1 PU601.1(BOOT2)
VCCIN_BOOT2_R: PC621.1 PR613.2
VCCIN_COMP: PR632.1 PR662.1 PU601.15(COMP)
VCCIN_COMP_R1: PR632.2 PR633.1
VCCIN_FB: PC608.2 PR633.2 PR634.2 PR663.1 PU601.16(FB)
VCCIN_IMON: PR636.2 PU601.11(IMON)
VCCIN_IMON_R: PR635.2 PR636.1
VCCIN_ISEN1N: PR643.2 PU601.19(ISEN1N)
VCCIN_ISEN1P: PC612.1 PR641.1 PR642.1 PU601.20(ISEN1P)
VCCIN_ISEN2N: PR648.2 PU601.18(ISEN2N)
VCCIN_ISEN2P: PC616.1 PR646.1 PR647.1 PU601.17(ISEN2P)
VCCIN_LGATE1: PQ603.4(G1) PU601.28(LGATE1)
VCCIN_LGATE2: PQ602.4(G1) PU601.30(LGATE2)
VCCIN_PH1_SNUB: PC611.1 PR639.1
VCCIN_PH2_SNUB: PC615.1 PR644.1
VCCIN_PHASE1: PC605.2 PL601.1 PQ603.5(D1) PQ604.1(S1) PQ604.2(S2) PQ604.3(S3) PR639.2 PR640.2 PU601.27(PHASE1)
VCCIN_PHASE2: PC621.2 PL602.1 PQ601.1(S1) PQ601.2(S2) PQ601.3(S3) PQ602.5(D1) PR644.2 PR645.2 PU601.31(PHASE2)
VCCIN_PIN_TSEN_H: PR612.1 PR615.2
VCCIN_PIN_TSEN_L: PR623.1 PR627.2
VCCIN_PINSET_TSEN: PR615.1 PR619.1 PR623.2 PRT601.1
VCCIN_PVCC: PC604.1 PR603.2 PU601.29(PVCC)
VCCIN_SENSE_R_N: PC640.2 PC641.1 PR637.1 PR638.1 PU601.13(RGND)
VCCIN_TSEN: PR619.2 PRT601.2 PU601.21(TSEN)
VCCIN_UGATE1: PR606.1 PU601.26(UGATE1)
VCCIN_UGATE1_R: PQ604.4(G1) PR606.2
VCCIN_UGATE2: PR614.1 PU601.32(UGATE2)
VCCIN_UGATE2_R: PQ601.4(G1) PR614.2
VCCIN_VCC: PC602.1 PR601.1 PU601.10(VCC)
VCCIN_VIDALERT_N: PC659.2 PR657.1 PR661.1 RU184.1 RU187.1
VCCIN_VIDALERT_N_R: RU187.2 UU1.H1(V\I\D\A\L\E\R\T\)
VCCIN_VIDSCK: PC657.2 PR649.1 PR658.1 RU182.1 RU185.1
VCCIN_VIDSCK_R: RU185.2 UU1.H2(VIDSCK)
VCCIN_VIDSOUT: PC658.2 PR655.1 PR656.1 RU183.1 RU186.1
VCCIN_VIDSOUT_R: RU186.2 UU1.H3(VIDSOUT)
VCCIN_VR_VIN: PC601.1 PR602.2 PU601.22(VIN)
VCCIN_VREF: PR608.1 PR609.2 PR610.2 PR611.2 PR612.2 PR653.1 PRT602.1 PU601.12(VREF06)
VCCIN_VREF_R: PC606.2 PR608.2
VCCIN_VRHOT: PR607.2 PU601.2(VRHOT)
VCCIN_VSEN: PC609.2 PC631.1 PC640.1 PR629.1 PR630.2 PR664.2 PU601.14(VSEN)
VCCSENSE_VGA: PC888.2 PR838.1 UV2.F2(VDD_SENSE)
VCCST_EN: PC977.1 PD904.3 PD906.3 PR903.2 PU901.6(ON)
VCCST_OVERRIDE: PQ902.1(G) RU157.2 RU181.1 UU1.CE4(VCCST_OVERRIDE)
VCCST_OVERRIDE_R: PD906.2 PQ901.3(D) PR901.1
VCCSTG_EN: PC975.1 PD907.3 PR907.1 PR920.1 PR921.1 PU904.6(ON)
VCCSTPWRGOOD_TCSS: RU157.1 UU1.CE3(VCCSTPWRGOOD_TCSS)
VDDQ_BST: PR704.1 PU701.18(BST)
VDDQ_BST_R: PC702.1 PR704.2
VDDQ_EN: PR703.2(B[0]) PU701.11(VDD_EN)
VDDQ_PG: PR706.2(B[0]) PU701.8(PGOOD)
VDDQ_SW: PC702.2 PL701.1 PU701.17(SW)
VDDQREF: PC701.1 PU701.6(VDDQREF)
VDDQSNS: PC719.1 PSH707.1(A[0]) PU701.2(VDDQ) PU701.4(VDDQSNS)
VSSSENSE_VGA: PR837.1 UV2.F1(GND_SENSE)
1P8VSX: PC931.1 PC932.1 PSH930.1(A[0]) PU910.A1(VOUT)
3P3VA_EN: PR202.1 QU4.3 RE102.2 RE104.2 RL47.1 RV245.1
3P3VA_EN_EC: RE104.1 UE1.J4(GPH7)
5P0VA_EN: PR305.1 QU5.3 UE1.A9(ID3/GPH3)
+FBA_VREFC: CV118.1 CV119.1 RV101.1 RV102.2 RV103.1 UV3.J14(VREFC) UV4.J14(VREFC)
+PLLVDD: CV43.1 CV44.1 LV1.2 RV51.2 RV52.2 RV53.2
+VADP: PC126.1 PC132.1 PC180.1 PFB101.2(FB2) PFB102.2(FB2) PQ111.5(D1) PR166.2 PR170.1 PR186.2
+VADP_CONN: PC125.1 PESD104.1 PFB101.1(FB1) PFB102.1(FB1) PR132.2 PR133.2 PSH104.2(B[0]) PSH105.2(B[0])
+VCON_IN: CT1.1 CT2.1 SHT1.2(B[0]) UT1.8(VCONN_V5V)
+VCP_VDD1P8: CA61.1 CA62.1 RA233.1 UA2.28(CP_VDD18)
+VGA_CORE: CV68.1 CV69.1 CV70.1 CV71.1 CV72.1 CV73.1 CV74.1 CV75.1 CV76.1 CV77.1 CV78.1 CV79.1 CV80.2 CV81.2 CV82.2 CV83.2 CV84.2 CV85.1 CV86.1 CV87.1 CV88.1 CV89.1 CV90.1 CV91.1 CV92.1 CV93.1 CV94.1 CV95.1 CV96.1 CV97.1 CV98.1 CV99.1 CV100.1 CV101.1 CV102.1 CV103.1 CV104.1 CV105.1 CV209.1 PC833.1 PC834.1 PC836.1 PC837.1 PCS801.1 PCS802.1 PL802.2 PL803.2 PR827.2 RV69.2 RV72.2 RV73.2 RV89.1 UV2.G1(XVDD_1) UV2.G2(XVDD_2) UV2.G3(XVDD_3) UV2.G4(XVDD_4) UV2.G5(XVDD_5) UV2.G6(XVDD_6) UV2.G7(XVDD_7) UV2.H3(XVDD_8) UV2.H4(XVDD_9) UV2.H6(XVDD_10) UV2.J1(XVDD_11) UV2.J2(XVDD_12) UV2.J3(XVDD_13) UV2.J4(XVDD_14) UV2.J5(XVDD_15) UV2.J6(XVDD_16) UV2.J7(XVDD_17) UV2.K1(XVDD_18) UV2.K2(XVDD_19) UV2.K3(XVDD_20) UV2.K4(XVDD_21) UV2.K5(XVDD_22) UV2.K6(XVDD_23) UV2.K7(XVDD_24) UV2.K10(VDD_001) UV2.K12(VDD_002) UV2.K14(VDD_003) UV2.K16(VDD_004) UV2.K18(VDD_005) UV2.L3(XVDD_25) UV2.L4(XVDD_26) UV2.L11(VDDS_1) UV2.L13(VDD_006) UV2.L15(VDD_007) UV2.L17(VDDS_2) UV2.M1(XVDD_27) UV2.M2(XVDD_28) UV2.M3(XVDD_29) UV2.M4(XVDD_30) UV2.M5(XVDD_31) UV2.M7(XVDD_32) UV2.M10(VDD_008) UV2.M12(VDD_009) UV2.M14(VDDS_3) UV2.M16(VDD_010) UV2.M18(VDD_011) UV2.N1(XVDD_33) UV2.N2(XVDD_34) UV2.N3(XVDD_35) UV2.N4(XVDD_36) UV2.N5(XVDD_37) UV2.N7(XVDD_38) UV2.N11(VDD_012) UV2.N13(VDD_013) UV2.N15(VDD_014) UV2.N17(VDD_015) UV2.P3(XVDD_39) UV2.P4(XVDD_40) UV2.P6(XVDD_41) UV2.P10(VDDS_4) UV2.P12(VDDS_5) UV2.P14(VDD_016) UV2.P16(VDDS_6) UV2.P18(VDDS_7) UV2.R1(XVDD_42) UV2.R2(XVDD_43) UV2.R3(XVDD_44) UV2.R4(XVDD_45) UV2.R5(XVDD_46) UV2.R6(XVDD_47) UV2.R7(XVDD_48) UV2.R11(VDD_017) UV2.R13(VDD_018) UV2.R15(VDD_019) UV2.R17(VDD_020) UV2.T1(XVDD_49) UV2.T2(XVDD_50) UV2.T3(XVDD_51) UV2.T4(XVDD_52) UV2.T5(XVDD_53) UV2.T6(XVDD_54) UV2.T7(XVDD_55) UV2.T10(VDD_021) UV2.T12(VDD_022) UV2.T14(VDDS_8) UV2.T16(VDD_023) UV2.T18(VDD_024) UV2.U3(XVDD_56) UV2.U4(XVDD_57) UV2.U6(XVDD_58) UV2.U11(VDDS_9) UV2.U13(VDD_025) UV2.U15(VDD_026) UV2.U17(VDDS_10) UV2.V1(XVDD_59) UV2.V2(XVDD_60) UV2.V3(XVDD_61) UV2.V4(XVDD_62) UV2.V5(XVDD_63) UV2.V6(XVDD_64) UV2.V10(VDD_027) UV2.V12(VDD_028) UV2.V14(VDD_029) UV2.V16(VDD_030) UV2.V18(VDD_031) UV2.W1(XVDD_66) UV2.W2(XVDD_67) UV2.W3(XVDD_68) UV2.W4(XVDD_69)
+VGA_CORE_EN_N: QV9.1(G) QV12.3 RV76.1
+VNN_BYPASS_R: RU193.2 UU1.CY34(VCC_VNNEXT_1P05)
+VPVDD: CA13.1 CA14.1 CA17.1 CA18.1 FBA2.2(FB2) UA2.23(PVDD5_LEFT) UA2.26(PVDD5_RIGHT)
+VSTBY_FSPI: RE68.2 UE1.E6(VFSPI)
+VSYS: PC108.1 PC109.1 PC136.1 PC137.1 PC138.1 PC139.1 PC140.1 PC301.1 PC302.1 PC305.1 PC306.1 PC704.1 PC705.1 PC730.1 PCS804.1 PQ101.1(S1) PQ101.2(S2) PQ101.3(S3) PQ107.5(D1) PR505.2 PSH201.1(A[0]) PSH202.1(A[0]) PSH501.2(B[0]) PSH502.2(B[0]) PSH601.2(B[0]) PSH602.2(B[0]) PSH603.2(B[0]) PSH806.2(B[0]) PSH807.2(B[0]) PSH808.2(B[0]) PSH809.2(B[0]) PSH1103.1(A[0]) PU101.22(VSYS) PU301.5(VIN) PU701.7(PVIN) RL1.2 RX11.1
A4WP_PRESENT: RU77.1 RU78.2 UU1.DL27(GPP_F19/A4WP_PRESENT)
ADP_DET_GND: PJ102.3 PR187.1 TP194.1
ADP_IN_EN: PC150.1 PQ114.1 PR166.1 PR167.2
ADP_PRESENT: PC152.1 PQ114.2 PR169.1 UE1.C2(GPC4)
ALLSYSPWRGD: PR604.1 UE1.B9(PS2DAT2/GPF5)
AUD_GND: CA32.2 CA35.1 CA36.1 CA37.1 CA56.2 CA57.2 CA68.2 CA69.2 CA74.2 CA78.2 CA79.2 CA80.2 CA81.2 JDB1.29 JDB1.33 JDB1.37 JDB1.40 RA17.1 RA18.1 RA19.1 UA2.39(VREF_DAC)
AUDIO_NC: RA239.2 UA2.4(NC1) UA2.5(NC2)
BATT_IN_L: PESD105.2 PR136.1 RE108.1 UE1.B7(ID6/GPH6)
BATT_PRES_N: PJ101.5 PR136.2 PR137.1 PTP102.1
BB_TCP0_FLASH_BUSY_N: RT49.1 RT50.2 UT2.A9(FLASH_BUSY_N)
BB_TCP0_FLASH_CLK: RT71.1 UT2.C7(EE_CLK)
BB_TCP0_FLASH_CLK_R: RT71.2 UT3.6(SCLK)
BB_TCP0_FLASH_CS_N: RT69.1 UT2.B6(EE_CS_N)
BB_TCP0_FLASH_CS_N_R: RT69.2 RT74.2 UT3.1(CS*)
BB_TCP0_FLASH_DI: RT72.1 UT2.C6(EE_DI)
BB_TCP0_FLASH_DI_R: RT72.2 UT3.5(SI/IO0)
BB_TCP0_FLASH_DO: RT70.1 UT2.B4(EE_DO)
BB_TCP0_FLASH_DO_R: RT70.2 RT75.2 UT3.2(SO/IO1)
BB_TCP0_FLASH_HOLD_N: RT77.2 UT3.7(IO3/HOLD*)
BB_TCP0_FLASH_MSTR_SLV: RT62.1 RT63.2 UT2.A5(POC_GPIO_11)
BB_TCP0_FLASH_SHARE_EN: RT59.1 RT61.2 UT2.A4(POC_GPIO_10)
BB_TCP0_FLASH_WP_N: RT76.2 UT3.3(IO2/WP*)
BB_TCP0_GPIO_5: RT53.2 UT2.B9(POC_GPIO_5)
BB_TCP0_GPIO_6: RT57.1 RT58.2 UT2.A8(POC_GPIO_6)
BB_TCP0_GPIO_12: RT64.1 RT65.2 UT2.A6(POC_GPIO_12)
BB_TCP0_RBIAS: RT44.1 UT2.L4(RBIAS)
BB_TCP0_RESET_N: RT41.2 RT56.2 TPT5.1 UT1.6(SWD_IO/AR_RST#/GPIO)
BB_TCP0_RSENSE: RT44.2 UT2.L5(RSENSE)
BB_TCP0_TCK: RT85.2 TPT11.1 UT2.B5(TCK)
BB_TCP0_TDI: RT84.2 TPT9.1 UT2.A3(TDI)
BB_TCP0_TDO: RT87.2 TPT12.1 UT2.C5(TDO)
BB_TCP0_TMS: RT86.2 TPT10.1 UT2.C3(TMS)
BB_TCP1_LS_EN: RT9.2 RT80.1 RT82.1 TPT20.1
BB_TCP1_LS_EN_R: RT82.2 RT83.2 UT4.4(EN)
BB_TCP2_TEST_PWR_GOOD: RT43.2 UT2.B3(TEST_PWR_GOOD)
BC_PROCHOT_N: DU3.1 PR162.1 RT129.2 RU219.1 RU220.1 RU228.2
BC_PROCHOT_N_PD: RT15.1 RT129.1 UT1.13(I2C_SCL_SCB4/UV_OCP_TRIP/GPIO)
BI_GATE: ESDL46.1 PR1012.1 QL1.1 QL8.1 RL455.1 SW3.1 SW3.2
BI_GATE_N: PJ101.6 QL1.3
BT_OFF_N_WIFI: JW1.54(W_DISABLE2_N) RW7.2 RW58.1
BT_RF_KILL_N: RW7.1 UU1.DP15(GPP_E22/DDPA_CTRLCLK/PCIE_LNK_D)
BT_WAKE_N_SOC: RW66.1 UU1.CN43(GPP_B5/ISH_I2C0_SDA)
CAM_PWR_ON_EC: RX926.2 UE1.F12(ADC6/DSR1#/GPI6)
CAM_PWR_ON_SOC: RU132.2 RX902.2
CAM_PWR_ON_SOC_R: RU132.1 UU1.CC47(GPP_G3/SD_DATA2)
CAM_USB_N_CONN_R: CHKX5.3 CX898.1 JX1.17 RX19.2
CAM_USB_P_CONN_R: CHKX5.4 CX897.1 JX1.16 RX20.2
CATERR_SOC_N: RU24.2 UU1.J4(C\A\T\E\R\R\_\N\)
CFG0: RU194.2 RU233.1 UU1.AG6(CFG_0)
CFG1: RU195.2 RU234.1 UU1.AE7(CFG_1)
CFG2: RU203.2 UU1.AG7(CFG_2)
CFG3: RU196.2 RU240.1 UU1.AD9(CFG_3)
CFG4: RU204.2 UU1.AE9(CFG_4)
CFG5: RU197.2 UU1.AB9(CFG_5)
CFG6: RU205.2 UU1.AJ6(CFG_6)
CFG7: RU200.2 UU1.AB7(CFG_7)
CFG8: RU206.2 RU235.1 UU1.V10(CFG_8)
CFG9: RU201.2 RU236.1 UU1.AJ5(CFG_9)
CFG10: RU198.2 RU237.1 UU1.Y10(CFG_10)
CFG11: RU207.2 UU1.AJ7(CFG_11)
CFG12: RU199.2 RU238.1 UU1.AB10(CFG_12)
CFG13: RU208.2 RU239.1 UU1.AL7(CFG_13)
CFG14: RU202.2 UU1.AL9(CFG_14)
CFG15: RU209.2 UU1.AJ9(CFG_15)
CFG_RCOMP: RU210.2 UU1.AD6(CFG_RCOMP)
CHG_ACN: PC121.2 PC127.2 PR108.1 PU101.2(ACN)
CHG_ACOK: PR131.1 PR138.2 PU101.4(CHRG_OK) RE139.2 UE1.E1(GPC6)
CHG_ACP: PC117.2 PC121.1 PR107.1 PU101.3(ACP)
CHG_BATDRV#: PR164.1(A[0]) PU101.21(BATDRV#)
CHG_BATDRV#_R: PQ101.4(G1) PR164.2(B[0])
CHG_BTST1: PR128.2 PU101.30(BTST1)
CHG_BTST1_R: PC131.2 PR128.1
CHG_BTST2: PR125.1 PU101.25(BTST2)
CHG_BTST2_R: PC123.1 PR125.2
CHG_CELL_BATPRES: PR117.2 PR120.1 PU101.18(CELL_BATPRES)
CHG_COMP1: PC154.1 PR115.2 PU101.16(COMP1)
CHG_COMP1_R: PC113.2 PR115.1
CHG_COMP2: PC114.1 PR116.2 PU101.17(COMP2)
CHG_COMP2_R: PC115.1 PR116.1
CHG_HG1: PQ103.4(G1) PU101.31(HIDRV1)
CHG_HIDRV2: PQ107.4(G1) PU101.24(HIDRV2)
CHG_IADPT: PC112.1 PR121.2 PU101.8(IADPT) UE1.G12(ADC2/GPI2)
CHG_IBAT: PC118.1 PU101.9(IBAT) UE1.G13(ADC1/GPI1)
CHG_ILIM_HIZ: PC133.1 PR111.1 PR112.2 PU101.6(ILIM_HIZ)
CHG_LG1: PC129.1 PQ105.4(G1) PU101.29(LODRV1)
CHG_LODRV2: PC120.2 PQ108.4(G1) PU101.26(LODRV2)
CHG_MOD1_P1: UB6.6(CLT1) UE1.F10(ADC5/DCD1#/GPI5)
CHG_MOD2_P1: RB52.1 RE98.1 UB6.7(CLT2)
CHG_MOD3_P1: UB6.8(CLT3) UE1.E13(ADC7/CTS1#/GPI7)
CHG_PROCHOT#: PR162.2 PU101.11(PROCHOT#)
CHG_PSYS: PC607.2 PR631.2 PR660.1 PU101.10(PSYS)
CHG_REGN: PC111.1 PR110.1 PR131.2 PU101.28(REGN)
CHG_SCL: PC141.1 PR161.2 PTP109.1 PU101.13(SCL)
CHG_SDA: PC142.1 PR130.2 PTP104.1 PU101.12(SDA)
CHG_SNB1: PC130.1 PR160.1
CHG_SNB2: PC134.1 PR105.1
CHG_SRN: PR122.2 PU101.19(SRN)
CHG_SRN_R: PC102.2 PC104.1 PR122.1 PR165.4
CHG_SRP: PR123.2 PU101.20(SRP)
CHG_SRP_R: PC102.1 PC103.1 PR123.1 PR165.3
CHG_SW1: PC131.1 PL101.1 PL102.1 PQ103.1(S1) PQ103.2(S2) PQ103.3(S3) PQ105.5(D1) PR160.2 PU101.32(SW1)
CHG_SW2: PC123.2 PL101.2 PL102.2 PQ107.1(S1) PQ107.2(S2) PQ107.3(S3) PQ108.5(D1) PR105.2 PU101.23(SW2)
CHG_VBUS: PC128.1 PR126.1 PU101.1(VBUS)
CHG_VDDA: PC119.1 PR110.2 PR111.2 PR120.2 PU101.7(VDDA)
CLK_REQ_GPU_N: QV1.2(S) RV9.1 RV12.2 RV13.1 UV2.AC6(PEX_CLKREQ*)
CLNK_CLK_CONN: JW1.42(CLINK_CLK) RW62.2
CLNK_CLK_SOC: RW62.1 UU1.DV19(CL_CLK)
CLNK_DATA_CONN: JW1.40(CLINK_DATA) RW61.2
CLNK_DATA_SOC: RW61.1 UU1.DW19(CL_DATA)
CLNK_RESET_CONN: JW1.38(CLINK_RESET) RW60.2
CLNK_RESET_SOC: RW60.1 UU1.DT19(C\L\_\R\S\T\_\N\)
CNV_BRI_DT: JW1.36(UART_RTS/BRI_DT) RU75.2 RW56.2
CNV_BRI_DT_SOC: RU64.1 RU67.2 RU75.1 UU1.DL31(GPP_F0/CNV_BRI_DT/U\A\R\T\0\_\R)
CNV_BRI_RSP: JW1.22(UART_RX/BRI_RSP) RW11.2
CNV_BRI_RSP_SOC: RU79.1 RW11.1 UU1.DL29(GPP_F1/CNV_BRI_RSP/UART0_RXD)
CNV_MFUART2_RXD: RW14.2 UU1.CV47(GPP_A10/I2S2_RXD)
CNV_MODEM_CLKREQ: CU169.1 RU139.2 RW13.1 UU1.CT47(GPP_A9/I2S2_TXD/MODEM_CLKREQ)
CNV_RF_RESET_N: RU140.2 RW16.2 UU1.CT48(GPP_A8/I2S2_SFRM/C\N\V\_\R\F\_\)
CNV_RF_RST: CW16.2 JW1.10(PCM_SYNC/LCP_RSTN) RW16.1
CNV_RGI_DT: JW1.32(UART_TX/RGI_DT) RU74.2 RW55.2
CNV_RGI_DT_SOC: RU74.1 RU223.1 UU1.DP31(GPP_F2/CNV_RGI_DT/UART0_TXD)
CNV_RGI_RSP: JW1.34(UART_CTS/RGI_RSP) RW10.2
CNV_RGI_RSP_SOC: RU80.1 RW10.1 UU1.DN29(GPP_F3/CNV_RGI_RSP/U\A\R\T\0\_\)
CNV_WR_CLK_CON_DN: JW1.21(WGR_CLKN) RW28.1
CNV_WR_CLK_CON_DP: JW1.23(WGR_CLKP) RW29.1
CNV_WR_CLK_DN: RW28.2 UU1.DK44(CNV_WR_CLKN)
CNV_WR_CLK_DP: RW29.2 UU1.DJ44(CNV_WR_CLKP)
CNV_WR_D0_CON_DN: JW1.15(WGR_D0N) RW31.1
CNV_WR_D0_CON_DP: JW1.17(WGR_D0P) RW30.1
CNV_WR_D1_CON_DN: JW1.9(WGR_D1N) RW33.1
CNV_WR_D1_CON_DP: JW1.11(WGR_D1P) RW32.1
CNV_WR_LANE0_DN: RW31.2 UU1.DP44(CNV_WR_D0N)
CNV_WR_LANE0_DP: RW30.2 UU1.DN44(CNV_WR_D0P)
CNV_WR_LANE1_DN: RW33.2 UU1.DG42(CNV_WR_D1N)
CNV_WR_LANE1_DP: RW32.2 UU1.DG44(CNV_WR_D1P)
CNV_WT_CLK_DN: JW1.71(WT_CLKN) RU71.2
CNV_WT_CLK_DN_R: RU71.1 UU1.DL42(CNV_WT_CLKN)
CNV_WT_CLK_DP: JW1.73(WT_CLKP) RU72.2
CNV_WT_CLK_DP_R: RU72.1 UU1.DK42(CNV_WT_CLKP)
CNV_WT_LANE0_DN: JW1.65(WT_D0N) RU66.2
CNV_WT_LANE0_DN_R: RU66.1 UU1.DV45(CNV_WT_D0N)
CNV_WT_LANE0_DP: JW1.67(WT_D0P) RU68.2
CNV_WT_LANE0_DP_R: RU68.1 UU1.DU45(CNV_WT_D0P)
CNV_WT_LANE1_DN: JW1.59(WT_D1N) RU69.2
CNV_WT_LANE1_DN_R: RU69.1 UU1.DU44(CNV_WT_D1N)
CNV_WT_LANE1_DP: JW1.61(WT_D1P) RU70.2
CNV_WT_LANE1_DP_R: RU70.1 UU1.DT44(CNV_WT_D1P)
CNV_WT_RCOMP: RU73.1 UU1.DT45(CNV_WT_RCOMP)
CNVI_EN_N: RW27.1 UU1.DT33(GPP_D15/ISH_UART0_RTS_N/GSPI2_C)
CODEC_EAPD: DA2.3 RA16.2 UA2.15(EAPD)
CORE+PLLVDD: CV41.1 CV42.1 RV51.1 UV2.L6(XS_PLLVDD) UV2.M6(SP_PLLVDD)
CPU_C10_GATE_N: PR904.1 PR906.1 PR909.1 RU226.2 RU227.2 TPU21.1 UE1.M7(PWM6/SSCK/GPA6) UU1.DU40(GPP_H18/C\P\U\_\C\1\0\_\G\A\T\E)
CPU_POPI_RCOMP: RU26.2 UU1.CJ41(PROC_POPIRCOMP)
CPU_PROCHOT_EC: QE4.1 RE95.1 UE1.M3(SMDAT4/L80LLAT/GPE7)
CPU_PROCHOT_N: DU3.2 PR607.1 RE92.2 RU17.1 RU18.1 RU19.1 RU219.2
CPU_PWM_FAN: RE49.2 UE1.M6(PWM2/GPA2)
CPU_TACHO_FAN: CE42.1 RE48.2 UE1.M11(TACH0A/GPD6)
CSI_COMP: RU76.2 UU1.B4(CSI_RCOMP)
DBG_PMODE: RU54.1 RU222.2 TP177.1 UU1.DL15(DBG_PMODE)
DC_JACK_IN: PJ102.1 PSH104.1(A[0]) PSH105.1(A[0]) TP191.1 TP193.1
DCIN_EN_8409A: RI149.2 UI2.3(DCIN_ENB)
DDI1_DDC_SCL: RI142.1 UI2.34(SCL_SRC/AUXP) UU1.DL40(GPP_H16/DDPB_CTRLCLK)
DDI1_DDC_SDA: RI143.1 UI2.33(SDA_SRC/AUXN) UU1.DP42(GPP_H17/DDPB_CTRLDATA)
DDI1_HPD: RI146.2 RI148.1 UU1.CV42(GPP_A18/DDSP_HPDB/DISP_MISCB)
DDI1_HPD_LV: RI148.2 UI2.40(HPD_SRC)
DDI1_TX0_DN: CI61.2 UU1.AE3(DDIB_TXN_0)
DDI1_TX0_DP: CI62.2 UU1.AE5(DDIB_TXP_0)
DDI1_TX1_DN: CI63.2 UU1.AE2(DDIB_TXN_1)
DDI1_TX1_DP: CI64.2 UU1.AE1(DDIB_TXP_1)
DDI1_TX2_DN: CI65.2 UU1.AC5(DDIB_TXN_2)
DDI1_TX2_DP: CI66.2 UU1.AC3(DDIB_TXP_2)
DDI1_TX3_DN: CI67.2 UU1.AC1(DDIB_TXN_3)
DDI1_TX3_DP: CI68.2 UU1.AC2(DDIB_TXP_3)
DDR_1P8A_SW: PL702.1 PU701.15(SW_VDD1)
DDR_RCOMP_0: RU1.1 UU1.D47(DDR_RCOMP_0)
DDR_RCOMP_1: RU2.1 UU1.E46(DDR_RCOMP_1)
DDR_RCOMP_2: RU3.1 UU1.C47(DDR_RCOMP_2)
DGPU_PROCHOT_EC: QV24.1(G) UE1.B13(DAC4/DCD0#/GPJ4)
DISP_RCOMP: RU6.2 UU1.R2(DISP_RCOMP)
DMIC1_CLK: CX893.1 ESD2.2 JX1.13 RX24.2 RX898.2
DMIC1_CLK_AUDIO: RA10.1 RX24.1
DMIC1_CLK_R: RA10.2 UA2.14(PORTC_DMIC_CLK/AMIC_R/GPIO2)
DMIC1_DATA: ESD2.1 JX1.14 RX23.2 RX899.2
DMIC1_DATA_AUDIO: RA11.1 RX23.1
DMIC1_DATA_R: CA26.1 RA11.2 UA2.12(PORTC_DMIC_DATA/AMIC_L/GPIO3)
DMIC2_CLK: CX894.1 ESD3.2 JKBL3.3 RX913.2 RX915.2
DMIC2_CLK_AUDIO: RA234.1 RX913.1
DMIC2_CLK_R: RA234.2 UA2.8(PORTH_DMIC_CLK/MUSIC_REQ/SPDIF/)
DMIC2_DATA: ESD3.1 JKBL3.4 RX914.2 RX916.2
DMIC2_DATA_AUDIO: RA235.1 RX914.1
DMIC2_DATA_R: CA63.1 RA235.2 UA2.9(PORTH_DMIC_DATA/SPKR_MUTE#/SPDI)
DRAM_RESET_N: RD1.1 RD2.2 UU1.DK47(D\R\A\M\_\R\E\S\E\T\_\N\)
DRAM_RESET_N_R: CD1.1 CD5.1 CD9.1 CD13.1 CD17.1 RD2.1 UD1.T11(RESET_N) UD2.T11(RESET_N) UD3.T11(RESET_N) UD4.T11(RESET_N)
DSW_PWROK: CU170.1 RU152.2 UU1.DR48(DSW_PWROK)
DSW_PWROK_EC: DL2.1 DL3.1 QL4.3 RU152.1 UE1.B12(EGCLK/GPE3)
EC_BEEP: RA3.2 UE1.N6(PWM3/GPA3)
EC_DEBUG_CLK: RE3.1 RE134.1 TPE1.1
EC_DEBUG_DATA: RE4.1 RE135.1 TPE2.1
EC_EDP_BKLT_EN: RX21.1 UE1.D13(TACH2B/GPJ1)
EC_FLASH_SPI_CLK: RE37.1 RO9.1 UE1.B5(FSCK)
EC_FLASH_SPI_CS0_N: RE32.1 RO10.1 UE1.A7(FSCE#)
EC_FLASH_SPI_MISO: RE35.2 RO13.1 UE1.A6(FMISO)
EC_FLASH_SPI_MOSI: RE34.2 RO14.1 UE1.B6(FMOSI)
EC_IMVP_PWRGD: CE46.1 PR659.1(A[0]) QU7.1(G) RE452.1 UE1.A13(EGAD/GPE1)
EC_ME_UNLOCK: RU125.2 UE1.C12(DAC5/RIG0#/GPJ5)
EC_MUTE_N: DA2.2 UE1.E12(TACH2A/GPJ0)
EC_OVT_N: RV244.1 UE1.N7(GINT/CTS0#/GPD5)
EC_PWRSW: RE2.2 UE1.A5(PWRSW/GPE4)
EC_RTCRST: QU2.1(G) RE125.2 RU90.2
EC_SCI_N: DE5.1 RE81.2 RE86.1 RE87.2 UE1.N4(ECSCI#/GPD3)
EC_SLP_S0_CS_N: RE459.2 RI153.2 RU51.1 RU59.2 UU1.DT12(GPP_E6)
EC_SLP_SX_N: PR413.1(A[0]) PR912.1 PR914.2 PR930.1(A[0]) UE1.B8(ID4/GPH4)
EC_STRAP: RE120.1 RE121.1 UE1.E7(SSCE0#/GPG2)
EC_USB2P0_EN: JDB1.7 UE1.D2(CTX0/TMA0/GPB2)
EC_USBPWR1_EN: RB44.2 UE1.E2(SSCE1#/GPG0)
EC_USBPWR1_EN_R: CB36.1 RB44.1 RB47.1 UB6.5(EN)
EC_VCCST_PWRGD: DU1.1 RU166.1 UE1.N8(RTS1#/GPE5)
EC_VCCSTG_EN: PR910.1 PR919.1 UE1.C13(DAC3/TACH1B/GPJ3)
EC_VDDQ_EN: PR709.1 UE1.A8(ID5/GPH5)
EC_VPP_EN: TPE106.1 UE1.D8(CLKRUN#/ID0/GPH0)
EC_WRST_N: CE40.1 DE6.2 RE118.2 RL46.1 UE1.L1(WRST#)
EDP_AUX_C_DN: CHKX7.1 CX8.2 RX904.1
EDP_AUX_C_DP: CHKX7.2 CX7.2 RX905.1
EDP_AUX_CONN_DN: CHKX7.4 JX1.27 RX904.2
EDP_AUX_CONN_DP: CHKX7.3 JX1.28 RX905.2
EDP_AUX_SOC_DN: CX8.1 UU1.W4(DDIA_AUX_N)
EDP_AUX_SOC_DP: CX7.1 UU1.W3(DDIA_AUX_P)
EDP_BKLT_EN: RX25.1 UE1.D12(DAC2/TACH0B/GPJ2) UU1.DL19(EDP_BKLTEN)
EDP_BKLT_LS_EN: CX22.1 JX1.24 RX17.1 RX21.2 RX22.2 RX25.2
EDP_BKLT_PWM: JX1.25 RX16.2 UU1.DU19(EDP_BKLTCTL)
EDP_HPD: ESDX1.1 JX1.23 RX18.2 UU1.DW11(GPP_E14/DPPE_HPDA/DISP_MISCA)
EDP_TX0_C_DN: CHKX6.1 CX6.2 RX245.1
EDP_TX0_C_DP: CHKX6.2 CX5.2 RX244.1
EDP_TX0_CONN_DN: CHKX6.4 JX1.30 RX245.2
EDP_TX0_CONN_DP: CHKX6.3 JX1.31 RX244.2
EDP_TX0_SOC_DN: CX6.1 UU1.Y5(DDIA_TXN_0)
EDP_TX0_SOC_DP: CX5.1 UU1.Y3(DDIA_TXP_0)
EDP_TX1_C_DN: CHKX1.1 CX2.2 RX243.1
EDP_TX1_C_DP: CHKX1.2 CX1.2 RX242.1
EDP_TX1_CONN_DN: CHKX1.4 JX1.33 RX243.2
EDP_TX1_CONN_DP: CHKX1.3 JX1.34 RX242.2
EDP_TX1_SOC_DN: CX2.1 UU1.Y1(DDIA_TXN_1)
EDP_TX1_SOC_DP: CX1.1 UU1.Y2(DDIA_TXP_1)
EDP_TX2_C_DN: CHKX9.1 CX888.2 RX909.1
EDP_TX2_C_DP: CHKX9.2 CX891.2 RX910.1
EDP_TX2_CONN_DN: CHKX9.4 JX1.36 RX909.2
EDP_TX2_CONN_DP: CHKX9.3 JX1.37 RX910.2
EDP_TX2_SOC_DN: CX888.1 UU1.V2(DDIA_TXN_2)
EDP_TX2_SOC_DP: CX891.1 UU1.V1(DDIA_TXP_2)
EDP_TX3_C_DN: CHKX8.1 CX890.2 RX912.1
EDP_TX3_C_DP: CHKX8.2 CX889.2 RX911.1
EDP_TX3_CONN_DN: CHKX8.4 JX1.39 RX912.2
EDP_TX3_CONN_DP: CHKX8.3 JX1.40 RX911.2
EDP_TX3_SOC_DN: CX890.1 UU1.V3(DDIA_TXN_3)
EDP_TX3_SOC_DP: CX889.1 UU1.V5(DDIA_TXP_3)
EDP_VDD_EN: RX12.2 UU1.DN21(EDP_VDDEN) UX1.4(EN)
EMMC_RCOMP: RU65.1 UU1.DU28(EMMC_RCOMP)
EN_VGA: DV6.2 PC1.1 PR820.1 QV12.1 RV16.1
EN_VGA_R: DV5.3 DV14.1(ANODE) RV15.1 RV16.2 RV18.2
EQ_8409A: RI101.1 RI102.2 UI2.5(EQ)
ESPI_CLK: RU37.1 UU1.CR47(GPP_A5/ESPI_CLK)
ESPI_CLK_EC: CU5.1 RU37.2 UE1.K2(ESCK/LPCCLK/GPM4)
ESPI_CS_N: RU45.2 UE1.H1(ECS#/LFRAME#/GPM5) UU1.CT45(GPP_A4/E\S\P\I\_\C\S\_\N\)
ESPI_IO0: RU38.1 UU1.CN45(GPP_A0/ESPI_IO0)
ESPI_IO0_EC: CU4.1 RU38.2 UE1.K1(EIO0/LAD0/GPM0)
ESPI_IO1: RU39.1 UU1.CN48(GPP_A1/ESPI_IO1)
ESPI_IO1_EC: CU3.1 RU39.2 UE1.J2(EIO1/LAD1/GPM1)
ESPI_IO2: RU40.1 UU1.CN49(GPP_A2/ESPI_IO2)
ESPI_IO2_EC: CU2.1 RU40.2 UE1.J1(EIO2/LAD2/GPM2)
ESPI_IO3: RU43.1 UU1.CN47(GPP_A3/ESPI_IO3)
ESPI_IO3_EC: CU1.1 RU43.2 UE1.H2(EIO3/LAD3/GPM3)
ESPI_RESET: RU46.2 UE1.M4(ERST#/LPCRST#/GPD2) UU1.CR46(GPP_A6/E\S\P\I\_\R\E\S\E\T\_\N\)
FAN_PWM_CTL_R: CE22.1 JE3.3 RE49.1 RE51.2 TPE103.1
FAN_TACHO_R: JE3.2 RE48.1 RE50.2 TPE102.1
FB_GC6_EN: QV4.2(G1) QV8.1(G) RV47.2 UV2.B2(GPIO1)
FB_GC6_EN_R: DV9.2 QV4.3(D1) RV27.1 UU1.DT36(GPP_D3/ISH_GP3)
FB_PLLAVDD: CV114.1 CV115.2 CV116.1 CV117.1 CV187.1 CV203.1 LV3.2 UV2.F16(FB_PLL_AVDD_1) UV2.H22(FB_REFPLL_AVDD) UV2.P22(FB_PLL_AVDD_2)
FBA_A0_A10_H: UV2.J25(FBA_CMD26) UV4.K4(A8/A7                  A10/A0)
FBA_A0_A10_L: UV2.G23(FBA_CMD10) UV3.H4(A10/A0                A8/A7)
FBA_A1_A9_H: UV2.J24(FBA_CMD27) UV4.K5(A11/A6                A9/A1)
FBA_A1_A9_L: UV2.G24(FBA_CMD11) UV3.H5(A9/A1                  A11/A6)
FBA_A2_BA0_H: UV2.K24(FBA_CMD18) UV4.K11(BA2/A4               BA0/A2)
FBA_A2_BA0_L: UV2.E24(FBA_CMD2) UV3.H11(BA0/A2               BA2/A4)
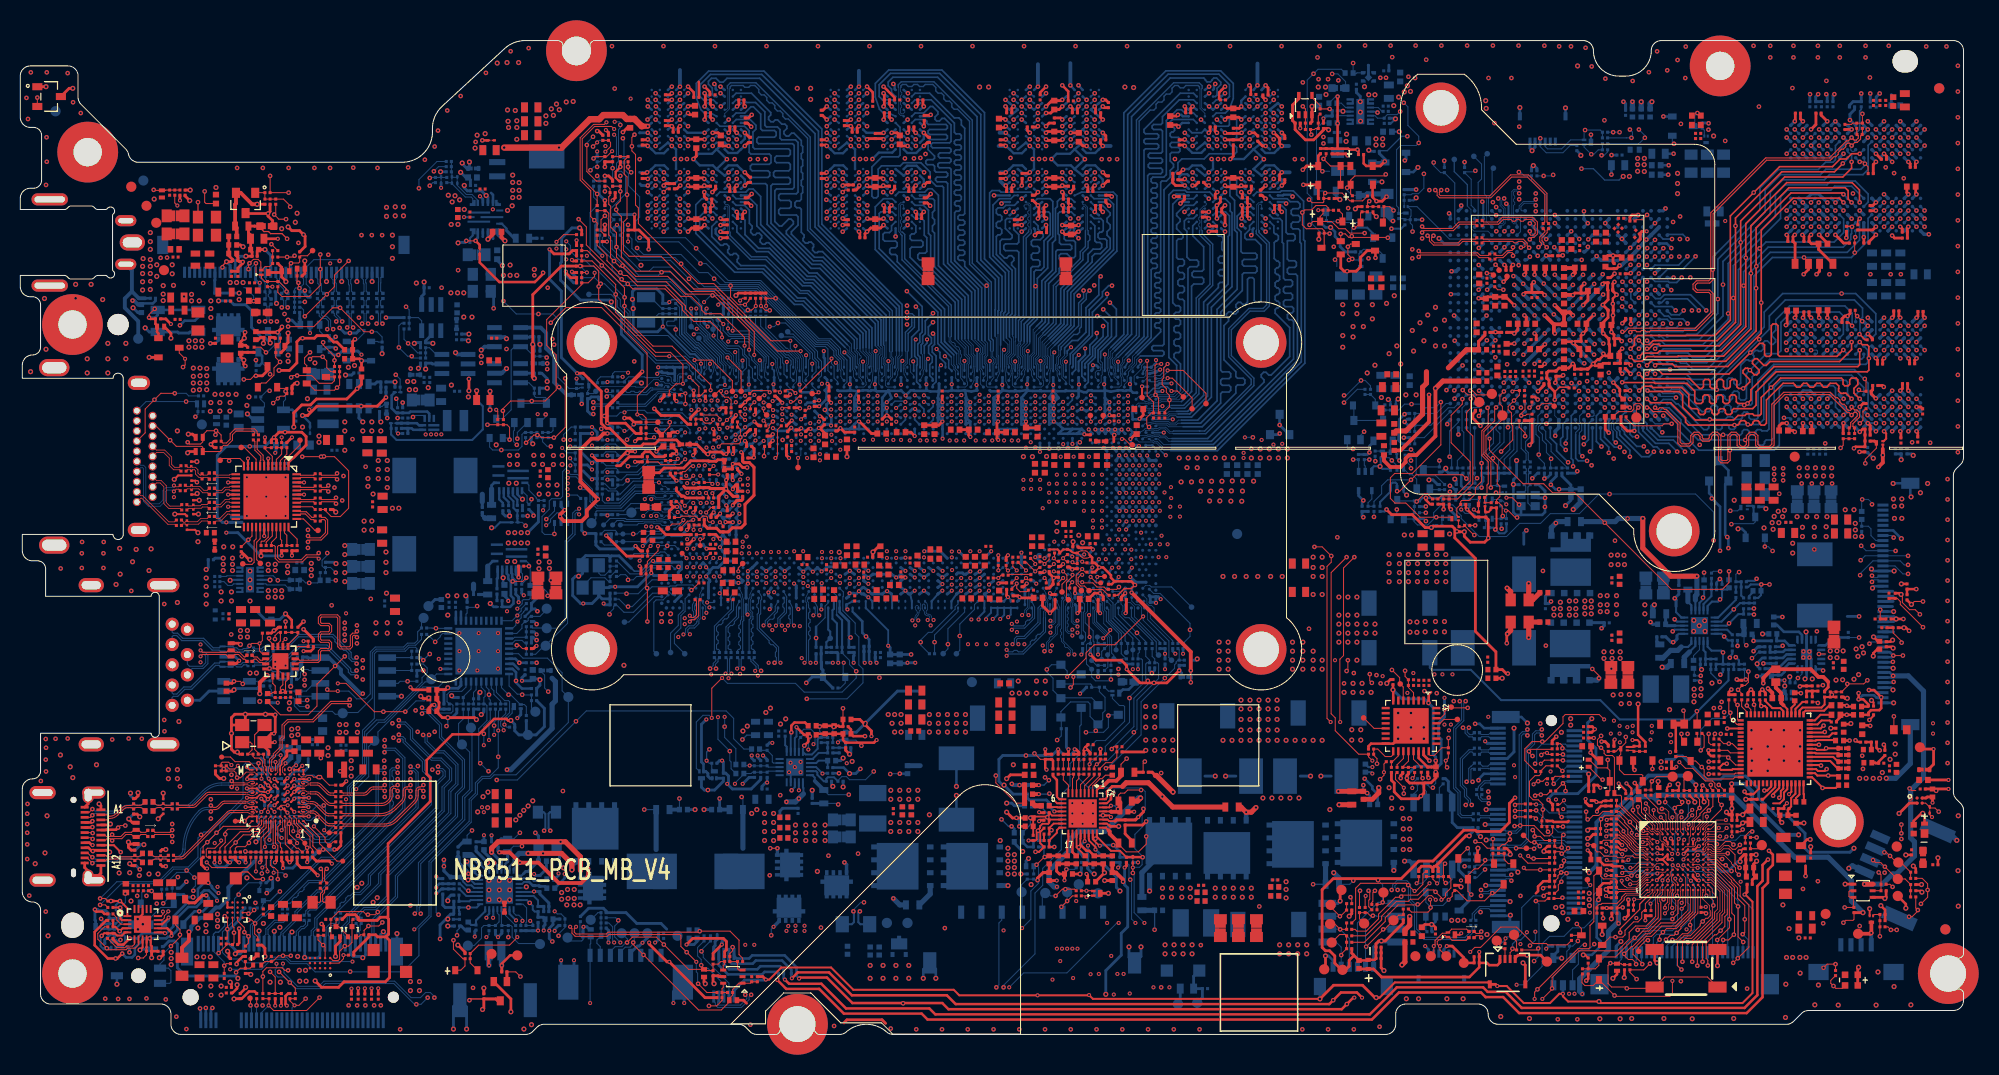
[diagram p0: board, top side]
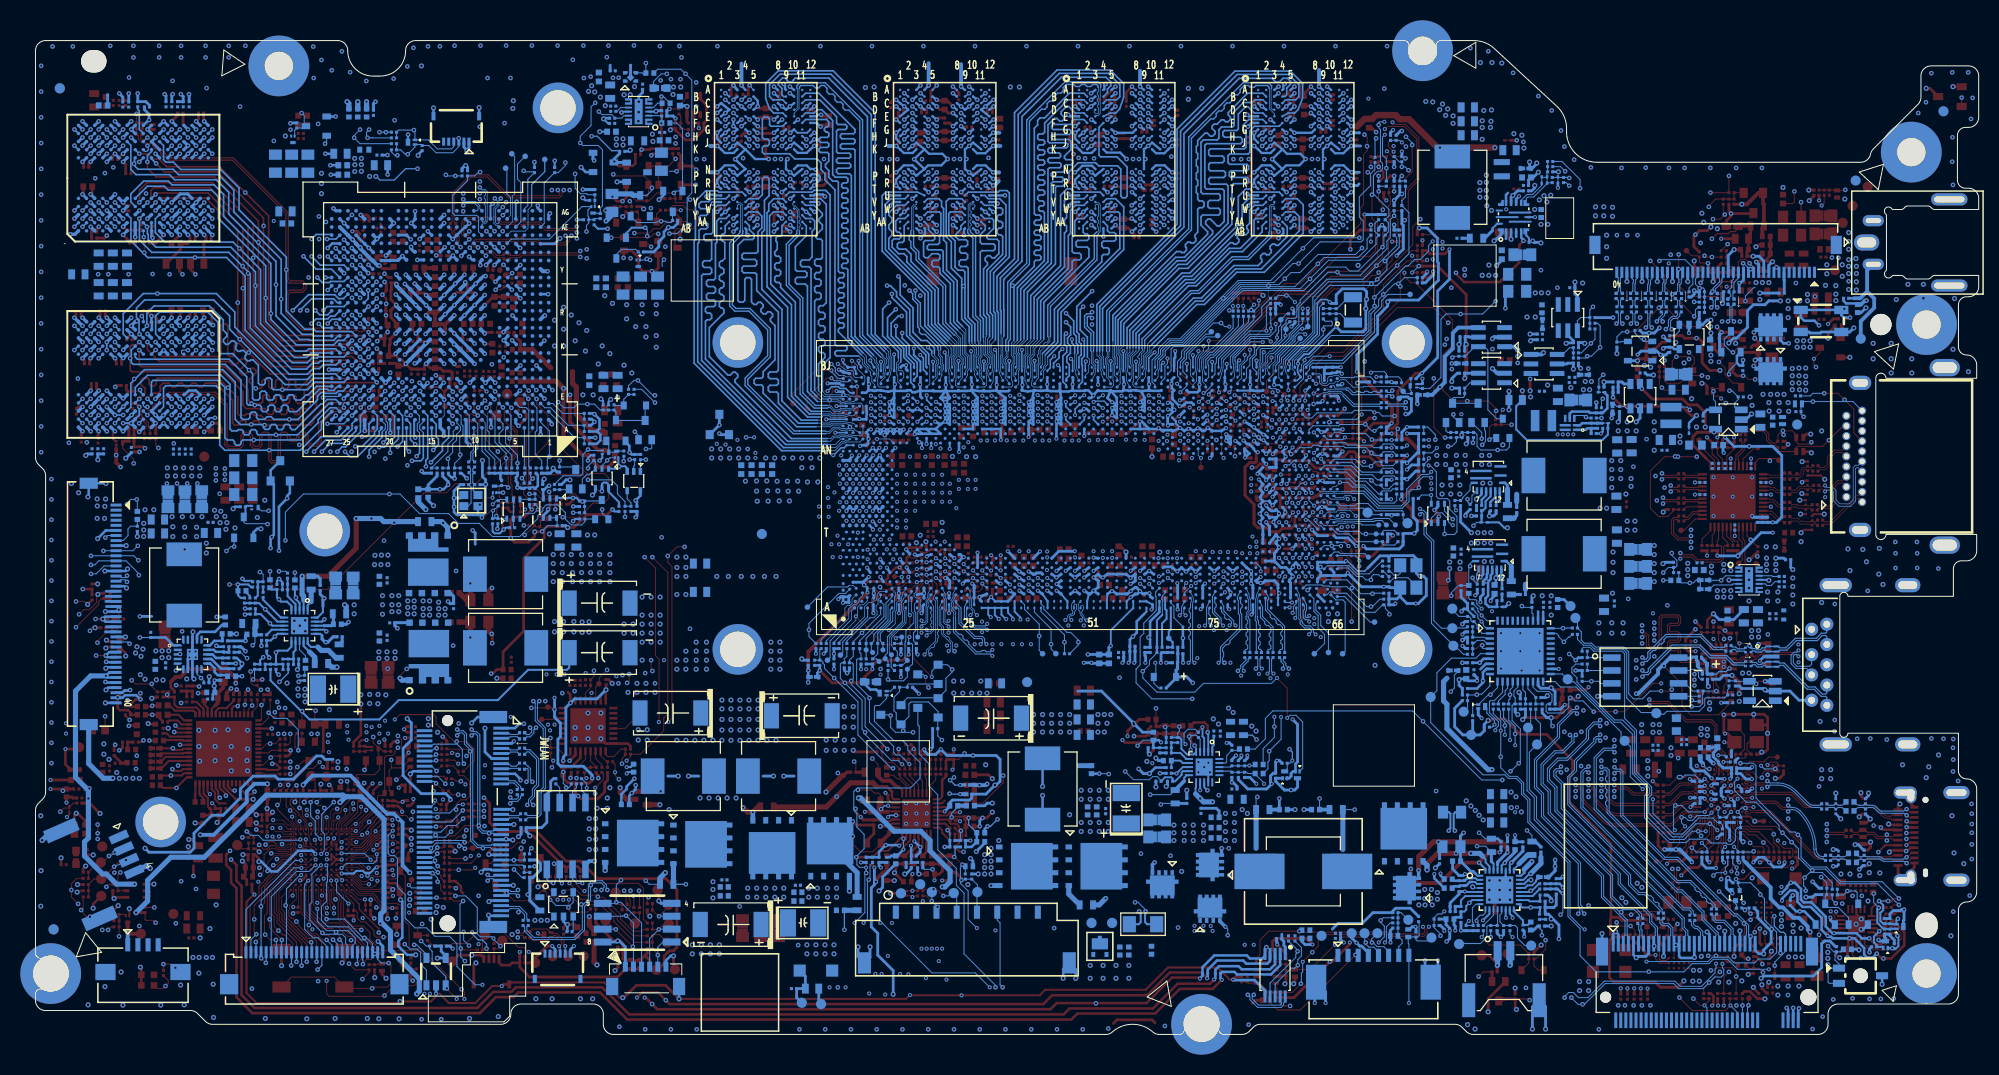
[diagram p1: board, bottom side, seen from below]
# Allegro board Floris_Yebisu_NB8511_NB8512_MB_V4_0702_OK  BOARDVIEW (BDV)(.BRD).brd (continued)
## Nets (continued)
FBA_A3_BA3_H: UV2.M23(FBA_CMD17) UV4.K10(BA1/A5               BA3/A3)
FBA_A3_BA3_L: UV2.C26(FBA_CMD1) UV3.H10(BA3/A3               BA1/A5)
FBA_A4_BA2_H: UV2.K23(FBA_CMD19) UV4.H11(BA0/A2               BA2/A4)
FBA_A4_BA2_L: UV2.F24(FBA_CMD3) UV3.K11(BA2/A4               BA0/A2)
FBA_A5_BA1_H: UV2.M27(FBA_CMD20) UV4.H10(BA3/A3               BA1/A5)
FBA_A5_BA1_L: UV2.D27(FBA_CMD4) UV3.K10(BA1/A5               BA3/A3)
FBA_A6_A11_H: UV2.K26(FBA_CMD23) UV4.H5(A9/A1                  A11/A6)
FBA_A6_A11_L: UV2.F26(FBA_CMD7) UV3.K5(A11/A6                A9/A1)
FBA_A7_A8_H: UV2.M25(FBA_CMD22) UV4.H4(A10/A0                A8/A7)
FBA_A7_A8_L: UV2.F25(FBA_CMD6) UV3.K4(A8/A7                  A10/A0)
FBA_A12_RFU_H: UV2.J23(FBA_CMD25) UV4.J5(A12/RFU/NC)
FBA_A12_RFU_L: UV2.G22(FBA_CMD9) UV3.J5(A12/RFU/NC)
FBA_ABI_H: UV2.K22(FBA_CMD24) UV4.J4(ABI#)
FBA_ABI_L: UV2.F23(FBA_CMD8) UV3.J4(ABI#)
FBA_CAS_H: UV2.J26(FBA_CMD31) UV4.G3(RAS#                 CAS#)
FBA_CAS_L: UV2.G26(FBA_CMD15) UV3.L3(CAS#                 RAS#)
FBA_CKE_H: RV91.1 UV2.J27(FBA_CMD30) UV4.J3(CKE#)
FBA_CKE_L: RV90.1 UV2.G27(FBA_CMD14) UV3.J3(CKE#)
FBA_CLK0: RV104.1 RV105.1 UV2.D24(FBA_CLK0) UV3.J12(CK)
FBA_CLK0_N: RV105.2 RV107.1 UV2.D25(FBA_CLK0*) UV3.J11(CK#)
FBA_CLK1: RV106.1 RV108.1 UV2.N22(FBA_CLK1) UV4.J12(CK)
FBA_CLK1_N: RV108.2 RV109.1 UV2.M22(FBA_CLK1*) UV4.J11(CK#)
FBA_CS_H: UV2.M24(FBA_CMD16) UV4.L12(WE#                   CS#)
FBA_CS_L: UV2.C27(FBA_CMD0) UV3.G12(CS#                    WE#)
FBA_D0: UV2.E18(FBA_D0) UV3.B4(DQ26              DQ2)
FBA_D1: UV2.F18(FBA_D1) UV3.A2(DQ25              DQ1)
FBA_D2: UV2.E16(FBA_D2) UV3.E2(DQ29              DQ5)
FBA_D3: UV2.F17(FBA_D3) UV3.A4(DQ24              DQ0)
FBA_D4: UV2.D20(FBA_D4) UV3.B2(DQ27              DQ3)
FBA_D5: UV2.D21(FBA_D5) UV3.E4(DQ28              DQ4)
FBA_D6: UV2.F20(FBA_D6) UV3.F2(DQ31              DQ7)
FBA_D7: UV2.E21(FBA_D7) UV3.F4(DQ30              DQ6)
FBA_D8: UV2.E15(FBA_D8) UV3.A11(DQ16              DQ8)
FBA_D9: UV2.D15(FBA_D9) UV3.A13(DQ17              DQ9)
FBA_D10: UV2.F15(FBA_D10) UV3.B11(DQ18           DQ10)
FBA_D11: UV2.F13(FBA_D11) UV3.B13(DQ19           DQ11)
FBA_D12: UV2.C13(FBA_D12) UV3.E11(DQ20           DQ12)
FBA_D13: UV2.B13(FBA_D13) UV3.E13(DQ21           DQ13)
FBA_D14: UV2.E13(FBA_D14) UV3.F11(DQ22           DQ14)
FBA_D15: UV2.D13(FBA_D15) UV3.F13(DQ23           DQ15)
FBA_D16: UV2.B15(FBA_D16) UV3.U13(DQ9             DQ17)
FBA_D17: UV2.C16(FBA_D17) UV3.T13(DQ11           DQ19)
FBA_D18: UV2.A13(FBA_D18) UV3.N13(DQ13           DQ21)
FBA_D19: UV2.A15(FBA_D19) UV3.N11(DQ12           DQ20)
FBA_D20: UV2.B18(FBA_D20) UV3.M11(DQ14           DQ22)
FBA_D21: UV2.A18(FBA_D21) UV3.M13(DQ15           DQ23)
FBA_D22: UV2.A19(FBA_D22) UV3.T11(DQ10           DQ18)
FBA_D23: UV2.C19(FBA_D23) UV3.U11(DQ8             DQ16)
FBA_D24: UV2.B24(FBA_D24) UV3.T4(DQ2             DQ26)
FBA_D25: UV2.C23(FBA_D25) UV3.M2(DQ7             DQ31)
FBA_D26: UV2.A25(FBA_D26) UV3.N4(DQ4             DQ28)
FBA_D27: UV2.A24(FBA_D27) UV3.U4(DQ0             DQ24)
FBA_D28: UV2.A21(FBA_D28) UV3.N2(DQ5             DQ29)
FBA_D29: UV2.B21(FBA_D29) UV3.M4(DQ6             DQ30)
FBA_D30: UV2.C20(FBA_D30) UV3.U2(DQ1             DQ25)
FBA_D31: UV2.C21(FBA_D31) UV3.T2(DQ3             DQ27)
FBA_D32: UV2.R22(FBA_D32) UV4.U4(DQ0             DQ24)
FBA_D33: UV2.R24(FBA_D33) UV4.U2(DQ1             DQ25)
FBA_D34: UV2.T22(FBA_D34) UV4.T4(DQ2             DQ26)
FBA_D35: UV2.R23(FBA_D35) UV4.T2(DQ3             DQ27)
FBA_D36: UV2.N25(FBA_D36) UV4.N4(DQ4             DQ28)
FBA_D37: UV2.N26(FBA_D37) UV4.N2(DQ5             DQ29)
FBA_D38: UV2.N23(FBA_D38) UV4.M4(DQ6             DQ30)
FBA_D39: UV2.N24(FBA_D39) UV4.M2(DQ7             DQ31)
FBA_D40: UV2.V23(FBA_D40) UV4.U11(DQ8             DQ16)
FBA_D41: UV2.V22(FBA_D41) UV4.U13(DQ9             DQ17)
FBA_D42: UV2.T23(FBA_D42) UV4.M11(DQ14           DQ22)
FBA_D43: UV2.U22(FBA_D43) UV4.T11(DQ10           DQ18)
FBA_D44: UV2.Y24(FBA_D44) UV4.N11(DQ12           DQ20)
FBA_D45: UV2.AA24(FBA_D45) UV4.T13(DQ11           DQ19)
FBA_D46: UV2.Y22(FBA_D46) UV4.M13(DQ15           DQ23)
FBA_D47: UV2.AA23(FBA_D47) UV4.N13(DQ13           DQ21)
FBA_D48: UV2.AD27(FBA_D48) UV4.B13(DQ19           DQ11)
FBA_D49: UV2.AB25(FBA_D49) UV4.A11(DQ16              DQ8)
FBA_D50: UV2.AD26(FBA_D50) UV4.B11(DQ18           DQ10)
FBA_D51: UV2.AC25(FBA_D51) UV4.A13(DQ17              DQ9)
FBA_D52: UV2.AA27(FBA_D52) UV4.E11(DQ20           DQ12)
FBA_D53: UV2.AA26(FBA_D53) UV4.E13(DQ21           DQ13)
FBA_D54: UV2.W26(FBA_D54) UV4.F11(DQ22           DQ14)
FBA_D55: UV2.Y25(FBA_D55) UV4.F13(DQ23           DQ15)
FBA_D56: UV2.R26(FBA_D56) UV4.A4(DQ24              DQ0)
FBA_D57: UV2.T25(FBA_D57) UV4.B2(DQ27              DQ3)
FBA_D58: UV2.N27(FBA_D58) UV4.A2(DQ25              DQ1)
FBA_D59: UV2.R27(FBA_D59) UV4.B4(DQ26              DQ2)
FBA_D60: UV2.V26(FBA_D60) UV4.E4(DQ28              DQ4)
FBA_D61: UV2.V27(FBA_D61) UV4.E2(DQ29              DQ5)
FBA_D62: UV2.W27(FBA_D62) UV4.F4(DQ30              DQ6)
FBA_D63: UV2.W25(FBA_D63) UV4.F2(DQ31              DQ7)
FBA_DBI0: UV2.D19(FBA_DQM0) UV3.D2(DBI0#                DBI3#)
FBA_DBI1: UV2.D14(FBA_DQM1) UV3.D13(DBI1#                DBI2#)
FBA_DBI2: UV2.C17(FBA_DQM2) UV3.P13(DBI2#                DBI1#)
FBA_DBI3: UV2.C22(FBA_DQM3) UV3.P2(DBI3#                DBI0#)
FBA_DBI4: UV2.P24(FBA_DQM4) UV4.P2(DBI3#                DBI0#)
FBA_DBI5: UV2.W24(FBA_DQM5) UV4.P13(DBI2#                DBI1#)
FBA_DBI6: UV2.AA25(FBA_DQM6) UV4.D13(DBI1#                DBI2#)
FBA_DBI7: UV2.U25(FBA_DQM7) UV4.D2(DBI0#                DBI3#)
FBA_EDC0: UV2.E19(FBA_DQS_WP0) UV3.C2(EDC0                EDC3)
FBA_EDC1: UV2.C15(FBA_DQS_WP1) UV3.C13(EDC1                EDC2)
FBA_EDC2: UV2.B16(FBA_DQS_WP2) UV3.R13(EDC2                EDC1)
FBA_EDC3: UV2.B22(FBA_DQS_WP3) UV3.R2(EDC3                EDC0)
FBA_EDC4: UV2.R25(FBA_DQS_WP4) UV4.R2(EDC3                EDC0)
FBA_EDC5: UV2.W23(FBA_DQS_WP5) UV4.R13(EDC2                EDC1)
FBA_EDC6: UV2.AB26(FBA_DQS_WP6) UV4.C13(EDC1                EDC2)
FBA_EDC7: UV2.T26(FBA_DQS_WP7) UV4.C2(EDC0                EDC3)
FBA_RAS_H: UV2.K27(FBA_CMD28) UV4.L3(CAS#                 RAS#)
FBA_RAS_L: UV2.F27(FBA_CMD12) UV3.G3(RAS#                 CAS#)
FBA_RST_H: RV92.2 UV2.K25(FBA_CMD29) UV4.J2(RESET#)
FBA_RST_L: RV93.2 UV2.G25(FBA_CMD13) UV3.J2(RESET#)
FBA_WCK01: UV2.D18(FBA_WCK01) UV3.D4(WCK01              WCK23)
FBA_WCK01_N: UV2.C18(FBA_WCK01*) UV3.D5(WCK01#           WCK23#)
FBA_WCK23: UV2.D17(FBA_WCK23) UV3.P4(WCK23              WCK01)
FBA_WCK23_N: UV2.D16(FBA_WCK23*) UV3.P5(WCK23#           WCK01#)
FBA_WCK45: UV2.T24(FBA_WCK45) UV4.P4(WCK23              WCK01)
FBA_WCK45_N: UV2.U24(FBA_WCK45*) UV4.P5(WCK23#           WCK01#)
FBA_WCK67: UV2.V24(FBA_WCK67) UV4.D4(WCK01              WCK23)
FBA_WCK67_N: UV2.V25(FBA_WCK67*) UV4.D5(WCK01#           WCK23#)
FBA_WE_H: UV2.M26(FBA_CMD21) UV4.G12(CS#                    WE#)
FBA_WE_L: UV2.D26(FBA_CMD5) UV3.L12(WE#                   CS#)
FBVDDQ_PWR_EN: DV9.3 PR1101.1 QV22.1 RV44.2
FBVDDQ_PWR_EN_N: QV10.1(G) QV22.3 RV77.1
FLASH_SPI_CLK: RF3.2 RO8.1 RU44.2 UU1.DB42(SPI0_CLK)
FLASH_SPI_CLK_EC: RE37.2 UE2.6(SCLK)
FLASH_SPI_CLK_IC: CLKO1.1 J3001.2 RO8.2 RO9.2 UO1.6(SCLK)
FLASH_SPI_CLK_TPM: RF3.1 UF15.19(SCLK)
FLASH_SPI_CS0_N: RO5.1 UU1.DB43(S\P\I\0\_\C\S\0\_\N\)
FLASH_SPI_CS0_N_EC: RE30.1 RE32.2 UE2.1(CS*)
FLASH_SPI_CS0_N_IC: CSO1.1 J3001.5 RO2.1 RO5.2 RO10.2 UO1.1(CS*)
FLASH_SPI_CS2_N: RF2.2 UU1.DB41(S\P\I\0\_\C\S\2\_\N\)
FLASH_SPI_CS2_N_TPM: CF12.2 RE457.2 RF2.1 UF15.20(SCS#/GPIO5)
FLASH_SPI_HOLD_N_EC: RE28.1 UE2.7(IO3/HOLD*)
FLASH_SPI_IO2: RO6.1 RU53.1 RU61.2 UU1.DF42(SPI0_IO2)
FLASH_SPI_IO2_IC: IOO1.1 RO3.1 RO6.2 UO1.3(IO2/WP*)
FLASH_SPI_IO3: RO7.1 RU52.1 RU60.2 UU1.DD41(SPI0_IO3)
FLASH_SPI_IO3_IC: IOO2.1 RO4.1 RO7.2 UO1.7(IO3/HOLD*)
FLASH_SPI_MISO: RF5.2 RO11.1 UU1.DF43(SPI0_MISO)
FLASH_SPI_MISO_EC: RE35.1 RE458.1 UE2.2(SO/IO1)
FLASH_SPI_MISO_IC: J3001.4 MISOO1.1 RO11.2 RO13.2 UO1.2(SO/IO1)
FLASH_SPI_MISO_TPM: RF5.1 UF15.24(MISO)
FLASH_SPI_MOSI: RF4.2 RO12.1 RU47.1 RU57.2 UU1.DD43(SPI0_MOSI)
FLASH_SPI_MOSI_EC: RE34.1 UE2.5(SI/IO0)
FLASH_SPI_MOSI_IC: J3001.3 MOSIO1.1 RO12.2 RO14.2 UO1.5(SI/IO0)
FLASH_SPI_MOSI_TPM: RF4.1 UF15.21(MOSI/GPIO7)
FLASH_SPI_WP_N_EC: RE29.1 UE2.3(IO2/WP*)
GPD11: TPU23.1 UU1.DF48(GPD11/LANPHYPC/DSWLDO_MON)
GPIO3_TPM: TPF1.1 UF15.6(GPIO3)
GPIO4_TPM: TPF2.1 UF15.13(GPIO4)
GPIO9: RV147.1 TPE6.1 UV2.F8(GPIO9)
GPJ6: RE125.1 UE1.F2(GPJ6)
GPP_D10: RU11.1 RU16.2 UU1.DL34(GPP_D10/ISH_SPI_CLK/DDP3_CTRLDA)
GPP_D12: RU10.1 RU15.2 UU1.DL33(GPP_D12/ISH_SPI_MOSI/DDP4_CTRLD)
GPP_E1: TP179.1 UU1.DT18(GPP_E1/SPI1_IO2)
GPP_E2: TP178.1 UU1.DW18(GPP_E2/SPI1_IO3)
GPP_E3: TP185.1 UU1.DV11(GPP_E3/CPU_GP0)
GPP_E7: TP186.1 UU1.DT11(GPP_E7/CPU_GP1)
GPP_E8: TP180.1 UU1.DU16(GPP_E8/S\A\T\A\L\E\D\_\N\/\S\P\)
GPP_E12: TP181.1 UU1.DU18(GPP_E12/SPI1_MISO/BK2/SBK2)
GPP_E13: TP182.1 UU1.DT16(GPP_E13/SPI1_MOSI/BK3/SBK3)
GPP_E21: RU9.1 RU14.2 UU1.DP17(GPP_E21/DDP2_CTRLDATA/TBT_LSX1_)
GPPC_B0_CORE_VID0_R: PD904.1(ANODE) PR502.2 PR504.2 PR511.2 PR528.2 PU501.18(VID0)
GPPC_B0_CORE_VID_0: PR528.1 UU1.CL38(GPP_B0/CORE_VID0)
GPPC_B1_CORE_VID1_R: PD904.2 PR501.2 PR503.2 PR508.2 PR529.2 PU501.17(VID1)
GPPC_B1_CORE_VID_1: PR529.1 UU1.CJ38(GPP_B1/CORE_VID1)
GPPC_B2_VRALERT_N: RU228.1 UU1.CN38(GPP_B2/V\R\A\L\E\R\T\_\N\)
GPPC_B18_GSPI0_MOSI: RU114.1 RU117.2 UU1.CF48(GPP_B18/GSPI0_MOSI)
GPPC_B23_SML1_ALERT_N: RU123.1 RU124.2 RU218.2 UU1.CL48(GPP_B23/S\M\L\1\A\L\E\R\T\_\N\/)
GPPC_B_14_SPKR: RA36.2 RU112.1 RU113.2 UU1.CH47(GPP_B14/SPKR/TIME_SYNC1/G\S\P\I)
GPPC_C2_SMBALERT_N: RU48.1 UU1.DL24(GPP_C2/S\M\B\A\L\E\R\T\_\N\)
GPPC_C5_SML0ALERT_N: RU49.1 UU1.DP22(GPP_C5/S\M\L\0\A\L\E\R\T\_\N\)
GPSI1_CLK: TPU10.1 UU1.CL47(GPP_B20/GSPI1_CLK)
GPSI1_MISO: TPU12.1 UU1.CK46(GPP_B21/GSPI1_MISO)
GPSI1_MOSI: TPU11.1 UU1.CK47(GPP_B22/GSPI1_MOSI)
GPU_EVENT_N: CV196.1 QV5.3(D) RU111.1 RV40.1 UU1.DV24(GPP_C14/U\A\R\T\1\_\R\T\S\_\N\/)
GPU_EVENT_N_R: QV5.2(S) RV35.1 RV40.2 UV2.D6(GPIO2)
GPU_PEX_RST_HOLD_N: RV37.1 UV2.B7(GPIO23)
GPU_PG_Q: RU116.2 RV61.2
GPU_PG_Q_R: CV192.2 DV11.3 RV56.1 RV61.1
GPU_PWREN: DV1.2 DV2.1 DV4.1 DV5.2 DV8.2 RU119.1 RU122.1 RV4.1 UU1.DU36(GPP_D0/ISH_GP0)
GPU_PWREN_18AON: CV28.1 PR1206.1 QV14.1 RV4.2 RV5.1 RV6.1 RV142.2
GPU_PWROK: DV7.2 DV11.2 PR819.1 PR821.1 QV23.1(G) RU115.2 RV22.1 RV43.2
GPU_PWROK_R: RU115.1 RU116.1 UU1.DW34(GPP_D18/ISH_GP5)
H_VCCST_PWRGD: RU164.2 UU1.CF2(VCCST_PWRGD)
HDA_BCLK: CA31.1 RU127.1 UA2.58(HDA_BCLK)
HDA_BCLK_R: CU19.1 RU127.2 UU1.CY46(GPP_R0/HDA_BCLK/I2S0_SCLK)
HDA_RST_N: CA64.1 RA246.1 RA248.1 RU133.1 UA2.2(HDA_RESET)
HDA_RST_N_R: CU21.1 RU133.2 UU1.DA47(GPP_R4/H\D\A\_\R\S\T\_\N\)
HDA_SDI: CA23.1 CU22.1 RA13.1 UU1.CV45(GPP_R3/HDA_SDI0/I2S0_RXD)
HDA_SDI_IC: RA13.2 UA2.60(HDA_SDI)
HDA_SDO: CA25.1 RU131.1 UA2.1(HDA_SDO)
HDA_SDO_R: CU20.1 RU118.1 RU125.1 RU131.2 UU1.CY47(GPP_R2/HDA_SDO/I2S0_TXD)
HDA_SYNC: CA24.1 RU129.1 UA2.59(HDA_SYNC)
HDA_SYNC_R: CU18.1 RU129.2 UU1.CV49(GPP_R1/HDA_SYNC/I2S0_SFRM)
HDMI_CLK_CONN_DN: CHKI7.2 CI117.1 ESDI13.1(K1) RI25.1 RI162.2
HDMI_CLK_CONN_DN_R: JI1.12(CLK-) RI162.1
HDMI_CLK_CONN_DP: CHKI7.1 CI117.2 ESDI14.1(K1) RI26.1 RI163.2
HDMI_CLK_CONN_DP_R: JI1.10(CLK+) RI163.1
HDMI_CLK_DN: CHKI7.3 RI25.2 UI2.13(OUT_CKN)
HDMI_CLK_DP: CHKI7.4 RI26.2 UI2.14(OUT_CKP)
HDMI_CLK_LV_DN: CI67.1 UI2.48(IN_CKN)
HDMI_CLK_LV_DP: CI68.1 UI2.47(IN_CKP)
HDMI_DDC_SCL: ESDI2.1 JI1.15(SCL) RI61.2 RI105.1
HDMI_DDC_SCL_8409A: RI61.1 UI2.7(SCL_SNK)
HDMI_DDC_SDA: ESDI4.1 JI1.16(SDA) RI60.2 RI106.1
HDMI_DDC_SDA_8409A: RI60.1 UI2.8(SDA_SNK)
HDMI_HPD: ESDI3.1 JI1.19(HP_DET) RI40.2 UI2.21(HPD_SNK)
HDMI_ID_8409A: RI152.1 UI2.32(HDMI_ID)
HDMI_PDB_8409A: RI153.1 RI155.1 UI2.4(PDB)
HDMI_TX0_CONN_DN: CHKI1.2 ESDI11.1(K1) RI11.1 RI156.2
HDMI_TX0_CONN_DN_R: JI1.9(DATA0-) RI156.1
HDMI_TX0_CONN_DP: CHKI1.1 ESDI12.1(K1) RI12.1 RI157.2
HDMI_TX0_CONN_DP_R: JI1.7(DATA0+) RI157.1
HDMI_TX0_DN: CHKI1.3 RI11.2 UI2.16(OUT_D0N)
HDMI_TX0_DP: CHKI1.4 RI12.2 UI2.17(OUT_D0P)
HDMI_TX0_LV_DN: CI65.1 UI2.45(IN_D0N)
HDMI_TX0_LV_DP: CI66.1 UI2.44(IN_D0P)
HDMI_TX1_CONN_DN: CHKI6.2 ESDI7.1(K1) RI13.1 RI158.2
HDMI_TX1_CONN_DN_R: JI1.6(DATA1-) RI158.1
HDMI_TX1_CONN_DP: CHKI6.1 ESDI8.1(K1) RI14.1 RI159.2
HDMI_TX1_CONN_DP_R: JI1.4(DATA1+) RI159.1
HDMI_TX1_DN: CHKI6.3 RI13.2 UI2.19(OUT_D1N)
HDMI_TX1_DP: CHKI6.4 RI14.2 UI2.20(OUT_D1P)
HDMI_TX1_LV_DN: CI63.1 UI2.42(IN_D1N)
HDMI_TX1_LV_DP: CI64.1 UI2.41(IN_D1P)
HDMI_TX2_CONN_DN: CHKI5.2 ESDI9.1(K1) RI23.1 RI160.2
HDMI_TX2_CONN_DN_R: JI1.3(DATA2-) RI160.1
HDMI_TX2_CONN_DP: CHKI5.1 ESDI10.1(K1) RI24.1 RI161.2
HDMI_TX2_CONN_DP_R: JI1.1(DATA2+) RI161.1
HDMI_TX2_DN: CHKI5.3 RI23.2 UI2.22(OUT_D2N)
HDMI_TX2_DP: CHKI5.4 RI24.2 UI2.23(OUT_D2P)
HDMI_TX2_LV_DN: CI61.1 UI2.39(IN_D2N)
HDMI_TX2_LV_DP: CI62.1 UI2.38(IN_D2P)
HGNDA: CA70.2 JDB1.30 JDB1.31 JDB1.32 SHE2.2(B[0]) SHE3.2(B[0])
HGNDA_C: SHE2.1(A[0]) UA2.35(HGNDA)
HGNDB: CA71.2 JDB1.34 JDB1.35 JDB1.36 QA1.6(D1) SHE4.2(B[0]) SHE5.2(B[0])
HGNDB_C: SHE5.1(A[0]) UA2.38(HGNDB)
HPD_P1: RT23.2 RU12.2 UT1.18(HPD) UU1.CV39(GPP_A19/DDSP_HPD1/DISP_MISC1)
HPOUT_JD_EC: RE455.2 UE1.H4(KBRST#/GPB6)
HPOUT_L: CA72.2 RA20.2 RA23.1 UA2.33(PORTA_L)
HPOUT_L_CON: CA78.1 JDB1.38 RA23.2
HPOUT_R: CA73.2 RA24.1 UA2.34(PORTA_R)
HPOUT_R_CON: CA79.1 JDB1.39 RA24.2
HW_ID0: RU92.2 RU93.1 UU1.DP27(GPP_F8/EMMC_DATA0)
HW_ID1: RU94.2 RU95.1 UU1.DU30(GPP_F9/EMMC_DATA1)
HW_ID2: RU96.2 RU97.1 UU1.DT30(GPP_F10/EMMC_DATA2)
HW_ID3: RU98.2 RU99.1 UU1.DT29(GPP_F11/EMMC_DATA3)
HW_ID4: RU100.1 RU102.2 UU1.DV30(GPP_F12/EMMC_DATA4)
HW_ID5: RU105.2 RU106.1 UU1.DU29(GPP_F13/EMMC_DATA5)
HW_ID6: RU107.2 RU108.1 UU1.DW30(GPP_F14/EMMC_DATA6)
HW_ID7: RU109.2 RU110.1 UU1.DW29(GPP_F15/EMMC_DATA7)
I2C_ADDR_8409A: RI151.1 UI2.31(I2C_ADDR)
I2C_PD_INT_N: RT46.1 UT2.A10(I2C_INT)
I2C_PD_SCL: CT27.1 RT35.1 UT2.C9(I2C_SCL)
I2C_PD_SDA: CT26.1 RT34.1 UT2.E7(I2C_SDA)
I2C_PD_SOC_INT_N: RT126.2 RU151.2 RU218.1 UT1.5(I2C_INT_AR/GPIO)
I2C_PD_SOC_INT_N_R: RU151.1 UU1.CL39(GPP_B11/P\M\C\A\L\E\R\T\)
I2CB_SCL: RV28.2 UV2.C9(I2CB_SCL)
I2CB_SDA: RV30.2 UV2.C8(I2CB_SDA)
I2CC_SCL: RV33.2 UV2.A9(I2CC_SCL)
I2CC_SDA: RV36.2 UV2.B9(I2CC_SDA)
ILIM_HI1: RB46.1 UB6.16(ILIM_HI)
ILIM_LO1: RB45.1 UB6.15(ILIM_LO)
ILIM_SEL1: RB48.1 RB50.1 RE123.2 UB6.4(ILIM_SEL)
IMVP9_SET1: PR616.1 PR620.2 PU601.8(SET1)
IMVP9_SET2: PR617.1 PR621.2 PU601.7(SET2)
IMVP9_SET3: PR618.1 PR622.2 PU601.6(SET3)
IMVP9_VRON: PC603.2 PR604.2 PR654.1 PU601.23(VRON)
INPUT3VSEL: RU153.2 RU154.1 UU1.DN49(INPUT3VSEL)
JSENSE_AB: CA74.1 JDB1.28 RA237.2 RA238.2 RE455.1
JSENSE_IC: RA236.2 RA237.1 RA238.1 UA2.47(JSENSE)
KB_BL_LED: RE13.1 UE1.K6(SMCLK5/PWM4/GPA4)
KB_CTL_FB: JKBL1.1 QE2.3(D) TP154.1
LAN_WAKE_N: RU172.2 UU1.DE47(GPD_2/L\A\N\_\W\A\K\E\_\N\)
LDO_VDD_1P2: CI103.1 UA2.51(LDO_VDD_CORE)
LDO_VDD_1P6: CA68.1 UA2.49(LDO_AVDD)
LED2_N: JW1.16(LED2_N) RW63.2
LED_CHG_FULL_N: JDB1.11 UE1.K7(PWM7/RIG1#/GPA7)
LED_CHG_N: JDB1.10 UE1.N5(PWM1/GPA1)
LED_PWR_ON: JDB1.13 RE456.1 UE1.J6(SMDAT5/PWM5/GPA5)
LED_PWR_STANDBY: JDB1.12 UE1.M5(PWM0/GPA0)
LID_INT_N: DX1.1(ANODE) RE53.2 UE1.B11(PS2DAT0/TMB1/GPF1)
LID_OPEN_INT: C8.1 ESDE45.1 MR1.2(OUTPUT) R16.1 RE53.1
M.2_BT_PCMCLK: JW1.8(PCM_CLK) RU135.1
M.2_BT_PCMIN: JW1.12(PCM_IN) RW14.1
M.2_BT_PCMOUT_CLKREQ: JW1.14(PCM_OUT/CLKREQ0) RW13.2
M_A_CK_DDR0_DN: UD1.J9(CK_C_A) UD1.P9(CK_C_B) UU1.BL48(DDRA_CLK_N/DDR0_CLK_N_0)
M_A_CK_DDR0_DP: UD1.J8(CK_T_A) UD1.P8(CK_T_B) UU1.BL47(DDRA_CLK_P/DDR0_CLK_P_0)
M_A_CK_DDR1_DN: UD2.J9(CK_C_A) UD2.P9(CK_C_B) UU1.BF42(DDRB_CLK_N/DDR0_CLK_N_1)
M_A_CK_DDR1_DP: UD2.J8(CK_T_A) UD2.P8(CK_T_B) UU1.BF43(DDRB_CLK_P/DDR0_CLK_P_1)
M_A_DQ_0[0]: UD1.Y4(DQ6_B) UU1.CA48(DDRA_DQ0_0/DDR0_DQ0_0)
M_A_DQ_0[1]: UD1.V4(DQ5_B) UU1.CA47(DDRA_DQ0_1/DDR0_DQ0_1)
M_A_DQ_0[2]: UD1.AA4(DQ7_B) UU1.CA49(DDRA_DQ0_2/DDR0_DQ0_2)
M_A_DQ_0[3]: UD1.V2(DQ2_B) UU1.BV49(DDRA_DQ0_3/DDR0_DQ0_3)
M_A_DQ_0[4]: UD1.AA2(DQ0_B) UU1.CA45(DDRA_DQ0_4/DDR0_DQ0_4)
M_A_DQ_0[5]: UD1.Y2(DQ1_B) UU1.BV47(DDRA_DQ0_5/DDR0_DQ0_5)
M_A_DQ_0[6]: UD1.U4(DQ4_B) UU1.BV45(DDRA_DQ0_6/DDR0_DQ0_6)
M_A_DQ_0[7]: UD1.U2(DQ3_B) UU1.BV48(DDRA_DQ0_7/DDR0_DQ0_7)
M_A_DQ_1[0]: UD1.Y9(DQ14_B) UU1.CC42(DDRA_DQ1_0/DDR0_DQ1_0)
M_A_DQ_1[1]: UD1.V9(DQ13_B) UU1.CC39(DDRA_DQ1_1/DDR0_DQ1_1)
M_A_DQ_1[2]: UD1.AA9(DQ15_B) UU1.CC43(DDRA_DQ1_2/DDR0_DQ1_2)
M_A_DQ_1[3]: UD1.U11(DQ11_B) UU1.CE38(DDRA_DQ1_3/DDR0_DQ1_3)
M_A_DQ_1[4]: UD1.U9(DQ12_B) UU1.CC38(DDRA_DQ1_4/DDR0_DQ1_4)
M_A_DQ_1[5]: UD1.V11(DQ10_B) UU1.CE39(DDRA_DQ1_5/DDR0_DQ1_5)
M_A_DQ_1[6]: UD1.Y11(DQ9_B) UU1.CE42(DDRA_DQ1_6/DDR0_DQ1_6)
M_A_DQ_1[7]: UD1.AA11(DQ8_B) UU1.CE43(DDRA_DQ1_7/DDR0_DQ1_7)
M_A_DQ_2[0]: UD1.F2(DQ3_A) UU1.BT48(DDRA_DQ2_0/DDR0_DQ2_0)
M_A_DQ_2[1]: UD1.C2(DQ1_A) UU1.BT47(DDRA_DQ2_1/DDR0_DQ2_1)
M_A_DQ_2[2]: UD1.E2(DQ2_A) UU1.BT49(DDRA_DQ2_2/DDR0_DQ2_2)
M_A_DQ_2[3]: UD1.B4(DQ7_A) UU1.BN49(DDRA_DQ2_3/DDR0_DQ2_3)
M_A_DQ_2[4]: UD1.F4(DQ4_A) UU1.BT45(DDRA_DQ2_4/DDR0_DQ2_4)
M_A_DQ_2[5]: UD1.E4(DQ5_A) UU1.BN47(DDRA_DQ2_5/DDR0_DQ2_5)
M_A_DQ_2[6]: UD1.B2(DQ0_A) UU1.BN45(DDRA_DQ2_6/DDR0_DQ2_6)
M_A_DQ_2[7]: UD1.C4(DQ6_A) UU1.BN48(DDRA_DQ2_7/DDR0_DQ2_7)
M_A_DQ_3[0]: UD1.C11(DQ9_A) UU1.BV42(DDRA_DQ3_0/DDR0_DQ3_0)
M_A_DQ_3[1]: UD1.E11(DQ10_A) UU1.BV39(DDRA_DQ3_1/DDR0_DQ3_1)
M_A_DQ_3[2]: UD1.B11(DQ8_A) UU1.BV43(DDRA_DQ3_2/DDR0_DQ3_2)
M_A_DQ_3[3]: UD1.F9(DQ12_A) UU1.BW38(DDRA_DQ3_3/DDR0_DQ3_3)
M_A_DQ_3[4]: UD1.F11(DQ11_A) UU1.BV38(DDRA_DQ3_4/DDR0_DQ3_4)
M_A_DQ_3[5]: UD1.E9(DQ13_A) UU1.BW39(DDRA_DQ3_5/DDR0_DQ3_5)
M_A_DQ_3[6]: UD1.C9(DQ14_A) UU1.BW42(DDRA_DQ3_6/DDR0_DQ3_6)
M_A_DQ_3[7]: UD1.B9(DQ15_A) UU1.BW43(DDRA_DQ3_7/DDR0_DQ3_7)
M_A_DQ_4[0]: UD2.Y4(DQ6_B) UU1.AY48(DDRB_DQ0_0/DDR0_DQ4_0)
M_A_DQ_4[1]: UD2.V4(DQ5_B) UU1.AY47(DDRB_DQ0_1/DDR0_DQ4_1)
M_A_DQ_4[2]: UD2.AA4(DQ7_B) UU1.AY49(DDRB_DQ0_2/DDR0_DQ4_2)
M_A_DQ_4[3]: UD2.U4(DQ4_B) UU1.AU45(DDRB_DQ0_3/DDR0_DQ4_3)
M_A_DQ_4[4]: UD2.AA2(DQ0_B) UU1.AY45(DDRB_DQ0_4/DDR0_DQ4_4)
M_A_DQ_4[5]: UD2.Y2(DQ1_B) UU1.AU47(DDRB_DQ0_5/DDR0_DQ4_5)
M_A_DQ_4[6]: UD2.U2(DQ3_B) UU1.AU48(DDRB_DQ0_6/DDR0_DQ4_6)
M_A_DQ_4[7]: UD2.V2(DQ2_B) UU1.AU49(DDRB_DQ0_7/DDR0_DQ4_7)
M_A_DQ_5[0]: UD2.Y9(DQ14_B) UU1.AY42(DDRB_DQ1_0/DDR0_DQ5_0)
M_A_DQ_5[1]: UD2.U9(DQ12_B) UU1.AY38(DDRB_DQ1_1/DDR0_DQ5_1)
M_A_DQ_5[2]: UD2.AA9(DQ15_B) UU1.AY43(DDRB_DQ1_2/DDR0_DQ5_2)
M_A_DQ_5[3]: UD2.V11(DQ10_B) UU1.BB39(DDRB_DQ1_3/DDR0_DQ5_3)
M_A_DQ_5[4]: UD2.V9(DQ13_B) UU1.AY39(DDRB_DQ1_4/DDR0_DQ5_4)
M_A_DQ_5[5]: UD2.U11(DQ11_B) UU1.BB38(DDRB_DQ1_5/DDR0_DQ5_5)
M_A_DQ_5[6]: UD2.Y11(DQ9_B) UU1.BB42(DDRB_DQ1_6/DDR0_DQ5_6)
M_A_DQ_5[7]: UD2.AA11(DQ8_B) UU1.BB43(DDRB_DQ1_7/DDR0_DQ5_7)
M_A_DQ_6[0]: UD2.F2(DQ3_A) UU1.AR48(DDRB_DQ2_0/DDR0_DQ6_0)
M_A_DQ_6[1]: UD2.C2(DQ1_A) UU1.AR47(DDRB_DQ2_1/DDR0_DQ6_1)
M_A_DQ_6[2]: UD2.E2(DQ2_A) UU1.AR49(DDRB_DQ2_2/DDR0_DQ6_2)
M_A_DQ_6[3]: UD2.B2(DQ0_A) UU1.AM45(DDRB_DQ2_3/DDR0_DQ6_3)
M_A_DQ_6[4]: UD2.F4(DQ4_A) UU1.AR45(DDRB_DQ2_4/DDR0_DQ6_4)
M_A_DQ_6[5]: UD2.E4(DQ5_A) UU1.AM47(DDRB_DQ2_5/DDR0_DQ6_5)
M_A_DQ_6[6]: UD2.C4(DQ6_A) UU1.AM48(DDRB_DQ2_6/DDR0_DQ6_6)
M_A_DQ_6[7]: UD2.B4(DQ7_A) UU1.AM49(DDRB_DQ2_7/DDR0_DQ6_7)
M_A_DQ_7[0]: UD2.C9(DQ14_A) UU1.AT42(DDRB_DQ3_0/DDR0_DQ7_0)
M_A_DQ_7[1]: UD2.E9(DQ13_A) UU1.AT39(DDRB_DQ3_1/DDR0_DQ7_1)
M_A_DQ_7[2]: UD2.B11(DQ8_A) UU1.AR43(DDRB_DQ3_2/DDR0_DQ7_2)
M_A_DQ_7[3]: UD2.F9(DQ12_A) UU1.AT38(DDRB_DQ3_3/DDR0_DQ7_3)
M_A_DQ_7[4]: UD2.F11(DQ11_A) UU1.AR38(DDRB_DQ3_4/DDR0_DQ7_4)
M_A_DQ_7[5]: UD2.E11(DQ10_A) UU1.AR39(DDRB_DQ3_5/DDR0_DQ7_5)
M_A_DQ_7[6]: UD2.C11(DQ9_A) UU1.AR42(DDRB_DQ3_6/DDR0_DQ7_6)
M_A_DQ_7[7]: UD2.B9(DQ15_A) UU1.AT43(DDRB_DQ3_7/DDR0_DQ7_7)
M_A_DQS_0_DN: UD1.V3(DQS0_C_B) UU1.BY47(DDRA_DQSN_0/DDR0_DQSN_0)
M_A_DQS_0_DP: UD1.W3(DQS0_T_B) UU1.BY46(DDRA_DQSP_0/DDR0_DQSP_0)
M_A_DQS_1_DN: UD1.V10(DQS1_C_B) UU1.CC41(DDRA_DQSN_1/DDR0_DQSN_1)
M_A_DQS_1_DP: UD1.W10(DQS1_T_B) UU1.CE41(DDRA_DQSP_1/DDR0_DQSP_1)
M_A_DQS_2_DN: UD1.E3(DQS0_C_A) UU1.BR47(DDRA_DQSN_2/DDR0_DQSN_2)
M_A_DQS_2_DP: UD1.D3(DQS0_T_A) UU1.BR46(DDRA_DQSP_2/DDR0_DQSP_2)
M_A_DQS_3_DN: UD1.E10(DQS1_C_A) UU1.BV41(DDRA_DQSN_3/DDR0_DQSN_3)
M_A_DQS_3_DP: UD1.D10(DQS1_T_A) UU1.BW41(DDRA_DQSP_3/DDR0_DQSP_3)
M_A_DQS_4_DN: UD2.V3(DQS0_C_B) UU1.AV46(DDRB_DQSN_0/DDR0_DQSN_4)
M_A_DQS_4_DP: UD2.W3(DQS0_T_B) UU1.AV47(DDRB_DQSP_0/DDR0_DQSP_4)
M_A_DQS_5_DN: UD2.V10(DQS1_C_B) UU1.AY41(DDRB_DQSN_1/DDR0_DQSN_5)
M_A_DQS_5_DP: UD2.W10(DQS1_T_B) UU1.BB41(DDRB_DQSP_1/DDR0_DQSP_5)
M_A_DQS_6_DN: UD2.E3(DQS0_C_A) UU1.AN46(DDRB_DQSN_2/DDR0_DQSN_6)
M_A_DQS_6_DP: UD2.D3(DQS0_T_A) UU1.AN47(DDRB_DQSP_2/DDR0_DQSP_6)
M_A_DQS_7_DN: UD2.E10(DQS1_C_A) UU1.AR41(DDRB_DQSN_3/DDR0_DQSN_7)
M_A_DQS_7_DP: UD2.D10(DQS1_T_A) UU1.AT41(DDRB_DQSP_3/DDR0_DQSP_7)
M_A_LP4_CAA0: UD1.H2(CA0_A) UD1.R2(CA0_B) UU1.BG48(DDRA_CA0/DDR0_MA5)
M_A_LP4_CAA1: UD1.J2(CA1_A) UD1.P2(CA1_B) UU1.BE47(DDRA_CA1/DDR0_MA9)
M_A_LP4_CAA2: UD1.H9(CA2_A) UD1.R9(CA2_B) UU1.BE45(DDRA_CA2/DDR0_MA6)
M_A_LP4_CAA3: UD1.H10(CA3_A) UD1.R10(CA3_B) UU1.BG47(DDRA_CA3/DDR0_MA8)
M_A_LP4_CAA4: UD1.H11(CA4_A) UD1.R11(CA4_B) UU1.BG45(DDRA_CA4/DDR0_MA7)
M_A_LP4_CAA5: UD1.J11(CA5_A) UD1.P11(CA5_B) UU1.BB49(DDRA_CA5/DDR0_BG0)
M_A_LP4_CAB0: UD2.H2(CA0_A) UD2.R2(CA0_B) UU1.BM39(DDRB_CA0/DDR0_MA13)
M_A_LP4_CAB1: UD2.J2(CA1_A) UD2.P2(CA1_B) UU1.BJ42(DDRB_CA1/D\D\R\0\_\M\A\1\5\C\A\)
M_A_LP4_CAB2: UD2.H9(CA2_A) UD2.R9(CA2_B) UU1.BG43(DDRB_CA2/D\D\R\0\_\M\A\1\4\W\E\)
M_A_LP4_CAB3: UD2.H10(CA3_A) UD2.R10(CA3_B) UU1.BM41(DDRB_CA3/D\D\R\0\_\M\A\1\6\R\A\)
M_A_LP4_CAB4: UD2.H11(CA4_A) UD2.R11(CA4_B) UU1.BM43(DDRB_CA4/DDR0_BA0)
M_A_LP4_CAB5: UD2.J11(CA5_A) UD2.P11(CA5_B) UU1.BG38(DDRB_CA5/DDR0_MA2)
M_A_LP4_CKE_A0: UD1.J4(CKE_A) UD1.P4(CKE_B) UU1.BG49(DDRA_CKE0/DDR0_CKE0)
M_A_LP4_CKE_A1: UD1.J5(NC_J5) UD1.P5(NC_P5) UU1.BJ47(DDRA_CKE1/NC)
M_A_LP4_CKE_B0: UD2.J4(CKE_A) UD2.P4(CKE_B) UU1.BF38(DDRB_CKE0/NC)
M_A_LP4_CKE_B1: UD2.J5(NC_J5) UD2.P5(NC_P5) UU1.BF41(DDRB_CKE1/DDR0_CKE1)
M_A_LP4_CS_A_R0_N: UD1.H4(CS_A) UD1.R4(CS_B) UU1.BM38(DDRA_CS_0/DDR0_CS_N_0)
M_A_LP4_CS_A_R1_N: UD1.H3(NC_H3) UD1.R3(NC_R3) UU1.BM42(DDRA_CS_1/NC)
M_A_LP4_CS_B_R0_N: UD2.H4(CS_A) UD2.R4(CS_B) UU1.BP42(DDRB_CS_0/NC)
M_A_LP4_CS_B_R1_N: UD2.H3(NC_H3) UD2.R3(NC_R3) UU1.BG42(DDRB_CS_1/DDR0_CS_N_1)
M_B_CK_DDR0_DN: UD3.J9(CK_C_A) UD3.P9(CK_C_B) UU1.Y48(DDRC_CLK_N/DDR1_CLK_N_0)
M_B_CK_DDR0_DP: UD3.J8(CK_T_A) UD3.P8(CK_T_B) UU1.Y47(DDRC_CLK_P/DDR1_CLK_P_0)
M_B_CK_DDR1_DN: UD4.J9(CK_C_A) UD4.P9(CK_C_B) UU1.M43(DDRD_CLK_N/DDR1_CLK_N_1)
M_B_CK_DDR1_DP: UD4.J8(CK_T_A) UD4.P8(CK_T_B) UU1.M42(DDRD_CLK_P/DDR1_CLK_P_1)
M_B_DQ_0[0]: UD3.U11(DQ11_B) UU1.AK48(DDRC_DQ0_0/DDR1_DQ0_0)
M_B_DQ_0[1]: UD3.U9(DQ12_B) UU1.AK45(DDRC_DQ0_1/DDR1_DQ0_1)
M_B_DQ_0[2]: UD3.V11(DQ10_B) UU1.AK49(DDRC_DQ0_2/DDR1_DQ0_2)
M_B_DQ_0[3]: UD3.V9(DQ13_B) UU1.AG47(DDRC_DQ0_3/DDR1_DQ0_3)
M_B_DQ_0[4]: UD3.Y11(DQ9_B) UU1.AK47(DDRC_DQ0_4/DDR1_DQ0_4)
M_B_DQ_0[5]: UD3.AA11(DQ8_B) UU1.AG45(DDRC_DQ0_5/DDR1_DQ0_5)
M_B_DQ_0[6]: UD3.Y9(DQ14_B) UU1.AG48(DDRC_DQ0_6/DDR1_DQ0_6)
M_B_DQ_0[7]: UD3.AA9(DQ15_B) UU1.AG49(DDRC_DQ0_7/DDR1_DQ0_7)
M_B_DQ_1[0]: UD3.E9(DQ13_A) UU1.AJ38(DDRC_DQ1_0/DDR1_DQ1_0)
M_B_DQ_1[1]: UD3.C9(DQ14_A) UU1.AL39(DDRC_DQ1_1/DDR1_DQ1_1)
M_B_DQ_1[2]: UD3.F9(DQ12_A) UU1.AJ39(DDRC_DQ1_2/DDR1_DQ1_2)
M_B_DQ_1[3]: UD3.C11(DQ9_A) UU1.AL43(DDRC_DQ1_3/DDR1_DQ1_3)
M_B_DQ_1[4]: UD3.B9(DQ15_A) UU1.AL38(DDRC_DQ1_4/DDR1_DQ1_4)
M_B_DQ_1[5]: UD3.E11(DQ10_A) UU1.AJ42(DDRC_DQ1_5/DDR1_DQ1_5)
M_B_DQ_1[6]: UD3.B11(DQ8_A) UU1.AL42(DDRC_DQ1_6/DDR1_DQ1_6)
M_B_DQ_1[7]: UD3.F11(DQ11_A) UU1.AJ43(DDRC_DQ1_7/DDR1_DQ1_7)
M_B_DQ_2[0]: UD3.V2(DQ2_B) UU1.AB49(DDRC_DQ2_0/DDR1_DQ2_0)
M_B_DQ_2[1]: UD3.U2(DQ3_B) UU1.AB48(DDRC_DQ2_1/DDR1_DQ2_1)
M_B_DQ_2[2]: UD3.AA4(DQ7_B) UU1.AE49(DDRC_DQ2_2/DDR1_DQ2_2)
M_B_DQ_2[3]: UD3.V4(DQ5_B) UU1.AE47(DDRC_DQ2_3/DDR1_DQ2_3)
M_B_DQ_2[4]: UD3.Y4(DQ6_B) UU1.AE48(DDRC_DQ2_4/DDR1_DQ2_4)
M_B_DQ_2[5]: UD3.Y2(DQ1_B) UU1.AB47(DDRC_DQ2_5/DDR1_DQ2_5)
M_B_DQ_2[6]: UD3.U4(DQ4_B) UU1.AB45(DDRC_DQ2_6/DDR1_DQ2_6)
M_B_DQ_2[7]: UD3.AA2(DQ0_B) UU1.AE45(DDRC_DQ2_7/DDR1_DQ2_7)
M_B_DQ_3[0]: UD3.B4(DQ7_A) UU1.AD38(DDRC_DQ3_0/DDR1_DQ3_0)
M_B_DQ_3[1]: UD3.C4(DQ6_A) UU1.AD39(DDRC_DQ3_1/DDR1_DQ3_1)
M_B_DQ_3[2]: UD3.E4(DQ5_A) UU1.AE39(DDRC_DQ3_2/DDR1_DQ3_2)
M_B_DQ_3[3]: UD3.E2(DQ2_A) UU1.AE43(DDRC_DQ3_3/DDR1_DQ3_3)
M_B_DQ_3[4]: UD3.F4(DQ4_A) UU1.AE38(DDRC_DQ3_4/DDR1_DQ3_4)
M_B_DQ_3[5]: UD3.C2(DQ1_A) UU1.AD43(DDRC_DQ3_5/DDR1_DQ3_5)
M_B_DQ_3[6]: UD3.B2(DQ0_A) UU1.AD42(DDRC_DQ3_6/DDR1_DQ3_6)
M_B_DQ_3[7]: UD3.F2(DQ3_A) UU1.AE42(DDRC_DQ3_7/DDR1_DQ3_7)
M_B_DQ_4[0]: UD4.C9(DQ14_A) UU1.J48(DDRD_DQ0_0/DDR1_DQ4_0)
M_B_DQ_4[1]: UD4.B11(DQ8_A) UU1.J45(DDRD_DQ0_1/DDR1_DQ4_1)
M_B_DQ_4[2]: UD4.B9(DQ15_A) UU1.J49(DDRD_DQ0_2/DDR1_DQ4_2)
M_B_DQ_4[3]: UD4.C11(DQ9_A) UU1.G47(DDRD_DQ0_3/DDR1_DQ4_3)
M_B_DQ_4[4]: UD4.E9(DQ13_A) UU1.J47(DDRD_DQ0_4/DDR1_DQ4_4)
M_B_DQ_4[5]: UD4.F11(DQ11_A) UU1.G45(DDRD_DQ0_5/DDR1_DQ4_5)
M_B_DQ_4[6]: UD4.E11(DQ10_A) UU1.G48(DDRD_DQ0_6/DDR1_DQ4_6)
M_B_DQ_4[7]: UD4.F9(DQ12_A) UU1.E48(DDRD_DQ0_7/DDR1_DQ4_7)
M_B_DQ_5[0]: UD4.B2(DQ0_A) UU1.J38(DDRD_DQ1_0/DDR1_DQ5_0)
M_B_DQ_5[1]: UD4.F2(DQ3_A) UU1.G39(DDRD_DQ1_1/DDR1_DQ5_1)
M_B_DQ_5[2]: UD4.E2(DQ2_A) UU1.G38(DDRD_DQ1_2/DDR1_DQ5_2)
M_B_DQ_5[3]: UD4.F4(DQ4_A) UU1.G42(DDRD_DQ1_3/DDR1_DQ5_3)
M_B_DQ_5[4]: UD4.C2(DQ1_A) UU1.J39(DDRD_DQ1_4/DDR1_DQ5_4)
M_B_DQ_5[5]: UD4.B4(DQ7_A) UU1.J42(DDRD_DQ1_5/DDR1_DQ5_5)
M_B_DQ_5[6]: UD4.E4(DQ5_A) UU1.G43(DDRD_DQ1_6/DDR1_DQ5_6)
M_B_DQ_5[7]: UD4.C4(DQ6_A) UU1.J43(DDRD_DQ1_7/DDR1_DQ5_7)
M_B_DQ_6[0]: UD4.U11(DQ11_B) UU1.B43(DDRD_DQ2_0/DDR1_DQ6_0)
M_B_DQ_6[1]: UD4.U9(DQ12_B) UU1.D43(DDRD_DQ2_1/DDR1_DQ6_1)
M_B_DQ_6[2]: UD4.V11(DQ10_B) UU1.A43(DDRD_DQ2_2/DDR1_DQ6_2)
M_B_DQ_6[3]: UD4.V9(DQ13_B) UU1.C40(DDRD_DQ2_3/DDR1_DQ6_3)
M_B_DQ_6[4]: UD4.Y11(DQ9_B) UU1.C43(DDRD_DQ2_4/DDR1_DQ6_4)
M_B_DQ_6[5]: UD4.AA11(DQ8_B) UU1.D40(DDRD_DQ2_5/DDR1_DQ6_5)
M_B_DQ_6[6]: UD4.Y9(DQ14_B) UU1.B40(DDRD_DQ2_6/DDR1_DQ6_6)
M_B_DQ_6[7]: UD4.AA9(DQ15_B) UU1.A40(DDRD_DQ2_7/DDR1_DQ6_7)
M_B_DQ_7[0]: UD4.U2(DQ3_B) UU1.B35(DDRD_DQ3_0/DDR1_DQ7_0)
M_B_DQ_7[1]: UD4.U4(DQ4_B) UU1.D35(DDRD_DQ3_1/DDR1_DQ7_1)
M_B_DQ_7[2]: UD4.V2(DQ2_B) UU1.A35(DDRD_DQ3_2/DDR1_DQ7_2)
M_B_DQ_7[3]: UD4.AA2(DQ0_B) UU1.D38(DDRD_DQ3_3/DDR1_DQ7_3)
M_B_DQ_7[4]: UD4.Y2(DQ1_B) UU1.C35(DDRD_DQ3_4/DDR1_DQ7_4)
M_B_DQ_7[5]: UD4.V4(DQ5_B) UU1.C38(DDRD_DQ3_5/DDR1_DQ7_5)
M_B_DQ_7[6]: UD4.Y4(DQ6_B) UU1.B38(DDRD_DQ3_6/DDR1_DQ7_6)
M_B_DQ_7[7]: UD4.AA4(DQ7_B) UU1.A38(DDRD_DQ3_7/DDR1_DQ7_7)
M_B_DQS_0_DN: UD3.V10(DQS1_C_B) UU1.AH46(DDRC_DQSN_0/DDR1_DQSN_0)
M_B_DQS_0_DP: UD3.W10(DQS1_T_B) UU1.AH47(DDRC_DQSP_0/DDR1_DQSP_0)
M_B_DQS_1_DN: UD3.E10(DQS1_C_A) UU1.AJ41(DDRC_DQSN_1/DDR1_DQSN_1)
M_B_DQS_1_DP: UD3.D10(DQS1_T_A) UU1.AL41(DDRC_DQSP_1/DDR1_DQSP_1)
M_B_DQS_2_DN: UD3.V3(DQS0_C_B) UU1.AC47(DDRC_DQSN_2/DDR1_DQSN_2)
M_B_DQS_2_DP: UD3.W3(DQS0_T_B) UU1.AC46(DDRC_DQSP_2/DDR1_DQSP_2)
M_B_DQS_3_DN: UD3.E3(DQS0_C_A) UU1.AE41(DDRC_DQSN_3/DDR1_DQSN_3)
M_B_DQS_3_DP: UD3.D3(DQS0_T_A) UU1.AD41(DDRC_DQSP_3/DDR1_DQSP_3)
M_B_DQS_4_DN: UD4.E10(DQS1_C_A) UU1.H47(DDRD_DQSN_0/DDR1_DQSN_4)
M_B_DQS_4_DP: UD4.D10(DQS1_T_A) UU1.H46(DDRD_DQSP_0/DDR1_DQSP_4)
M_B_DQS_5_DN: UD4.E3(DQS0_C_A) UU1.G41(DDRD_DQSN_1/DDR1_DQSN_5)
M_B_DQS_5_DP: UD4.D3(DQS0_T_A) UU1.J41(DDRD_DQSP_1/DDR1_DQSP_5)
M_B_DQS_6_DN: UD4.V10(DQS1_C_B) UU1.C42(DDRD_DQSN_2/DDR1_DQSN_6)
M_B_DQS_6_DP: UD4.W10(DQS1_T_B) UU1.D42(DDRD_DQSP_2/DDR1_DQSP_6)
M_B_DQS_7_DN: UD4.V3(DQS0_C_B) UU1.D36(DDRD_DQSN_3/DDR1_DQSN_7)
M_B_DQS_7_DP: UD4.W3(DQS0_T_B) UU1.C36(DDRD_DQSP_3/DDR1_DQSP_7)
M_B_LP4_CAA0: UD3.H2(CA0_A) UD3.R2(CA0_B) UU1.R49(DDRC_CA0/DDR1_MA5)
M_B_LP4_CAA1: UD3.J2(CA1_A) UD3.P2(CA1_B) UU1.R47(DDRC_CA1/DDR1_MA9)
M_B_LP4_CAA2: UD3.H9(CA2_A) UD3.R9(CA2_B) UU1.U49(DDRC_CA2/DDR1_MA6)
M_B_LP4_CAA3: UD3.H10(CA3_A) UD3.R10(CA3_B) UU1.M45(DDRC_CA3/DDR1_MA8)
M_B_LP4_CAA4: UD3.H11(CA4_A) UD3.R11(CA4_B) UU1.M47(DDRC_CA4/DDR1_MA7)
M_B_LP4_CAA5: UD3.J11(CA5_A) UD3.P11(CA5_B) UU1.R45(DDRC_CA5/DDR1_BG0)
M_B_LP4_CAB0: UD4.H2(CA0_A) UD4.R2(CA0_B) UU1.Y41(DDRD_CA0/DDR1_MA13)
M_B_LP4_CAB1: UD4.J2(CA1_A) UD4.P2(CA1_B) UU1.Y42(DDRD_CA1/D\D\R\1\_\M\A\1\5\C\A\)
M_B_LP4_CAB2: UD4.H9(CA2_A) UD4.R9(CA2_B) UU1.V41(DDRD_CA2/D\D\R\1\_\M\A\1\4\W\E\)
M_B_LP4_CAB3: UD4.H10(CA3_A) UD4.R10(CA3_B) UU1.V47(DDRD_CA3/D\D\R\1\_\M\A\1\6\R\A\)
M_B_LP4_CAB4: UD4.H11(CA4_A) UD4.R11(CA4_B) UU1.T38(DDRD_CA4/DDR1_BA0)
M_B_LP4_CAB5: UD4.J11(CA5_A) UD4.P11(CA5_B) UU1.U48(DDRD_CA5/DDR1_MA2)
M_B_LP4_CKE_A0: UD3.J4(CKE_A) UD3.P4(CKE_B) UU1.U45(DDRC_CKE0/DDR1_CKE0)
M_B_LP4_CKE_A1: UD3.J5(NC_J5) UD3.P5(NC_P5) UU1.V46(DDRC_CKE1/NC)
M_B_LP4_CKE_B0: UD4.J4(CKE_A) UD4.P4(CKE_B) UU1.M41(DDRD_CKE0/NC)
M_B_LP4_CKE_B1: UD4.J5(NC_J5) UD4.P5(NC_P5) UU1.P43(DDRD_CKE1/DDR1_CKE1)
M_B_LP4_CS_A_R0_N: UD3.H4(CS_A) UD3.R4(CS_B) UU1.V42(DDRC_CS_0/DDR1_CS_N_0)
M_B_LP4_CS_A_R1_N: UD3.H3(NC_H3) UD3.R3(NC_R3) UU1.V39(DDRC_CS_1/NC)
M_B_LP4_CS_B_R0_N: UD4.H4(CS_A) UD4.R4(CS_B) UU1.Y39(DDRD_CS_0/NC)
M_B_LP4_CS_B_R1_N: UD4.H3(NC_H3) UD4.R3(NC_R3) UU1.T39(DDRD_CS_1/DDR1_CS_N_1)
MBP0_N: RU214.1 TPU73.1 UU1.T9(BPM_N_0)
MBP1_N: RU213.1 TPU74.1 UU1.T7(BPM_N_1)
MBP2_N: RU216.1 UU1.T10(BPM_N_2)
MBP3_N: RU215.1 UU1.T6(BPM_N_3)
MEM_VREF: QV21.1(G) RV48.2 UV2.C5(GPIO10)
MICBIAS_B: RA20.1 UA2.44(MICBIAS_B)
MIPI60_CFG_STB0_DN: RU212.2 UU1.V6(CFG_16)
MIPI60_CFG_STB0_DP: TPU29.1 UU1.V7(CFG_17)
MIPI60_CFG_STB1_DN: RU217.2 UU1.Y6(CFG_18)
MIPI60_CFG_STB1_DP: TPU31.1 UU1.Y7(CFG_19)
MIPI60_CPU_JTAG_TCLK: RU20.1 RU22.1 TP1.1 UU1.P3(PROC_TCK)
MIPI60_CPU_JTAG_TDI: RU25.1 TP2.1 UU1.K5(PROC_TDI)
MIPI60_CPU_JTAG_TDO: RU27.2 RU29.1 TP3.1 UU1.K3(PROC_TDO)
MIPI60_CPU_JTAG_TMS: RU30.2 RU31.1 TP4.1 UU1.P4(PROC_TMS)
MIPI60_CPU_JTAG_TRST_N: RU33.1 TP5.1 UU1.N1(P\R\O\C\_\T\R\S\T\_\N\)
MIPI60_PCH_JTAG_TCLK: TP7.1 UU1.R5(PCH_TCK)
MIPI60_PCH_JTAG_TDI: RU23.1 RU25.2 TP8.1 UU1.K1(PCH_TDI)
MIPI60_PCH_JTAG_TDO: RU29.2 TP9.1 UU1.K2(PCH_TDO)
MIPI60_PCH_JTAG_TMS: RU31.2 TP10.1 UU1.N3(PCH_TMS)
MIPI60_PCH_JTAG_TRST_N: RU33.2 RU34.1 TP6.1 UU1.N5(P\C\H\_\T\R\S\T\_\N\)
MIPI60_PCH_JTAGX: RU20.2 TP11.1 UU1.N2(PCH_JTAGX)
MIPI60_PRDY_N: TP12.1 UU1.P6(P\R\O\C\_\P\R\D\Y\_\N\)
MIPI60_PREQ_N: TP13.1 UU1.M6(P\R\O\C\_\P\R\E\Q\_\N\)
NTCN: PR650.1 PR653.2
NTCP: PR651.1 PR652.2
NVJTAG_SEL: RV64.1 UV2.AD9(NVJTAG_SEL)
OVERT_N: CV33.1 QV2.2(S) RV29.1 UV2.A6(OVERT)
OVT_N: DV14.3 DV16.1 QV2.3(D) QV7.3 RV49.1 RV248.1 RV250.1
PCBEEP: CA15.1 UA2.48(PC_BEEP)
PCH_DMIC1_CLK0: CU15.1 RU136.2 RX898.1
PCH_DMIC1_DATA0: CU14.1 RX899.1 UU1.DG34(GPP_S7/SNDW4_DATA/DMIC_DATA0)
PCH_DMIC2_CLK1: CU16.1 RU138.1 RX915.1
PCH_DMIC2_DATA1: CU17.1 RX916.1 UU1.DD39(GPP_S5/SNDW3_DATA/DMIC_DATA1)
PCH_GPU_RST_N: CU13.2 RU121.2 RV143.2 UV1.2(IN2)
PCH_GPU_RST_N_R: RU120.1 RU121.1 UU1.DV36(GPP_D1/ISH_GP1)
PCH_POPI_RCOMP: RU28.2 UU1.DU3(PCH_OPIRCOMP)
PCH_PWROK: CU38.1 DL2.2 RE452.2 RU175.1 UU1.DN47(PCH_PWROK)
PCH_SMB1_CLK: QU1.3(D1) RU35.1 UU1.DK27(GPP_C0/SMBCLK)
PCH_SMB1_DATA: QU1.6(D1) RU36.1 UU1.DP24(GPP_C1/SMBDATA)
PCH_WLAN_OFF_N: RW6.1 UU1.CH49(GPP_B15/G\S\P\I\0\_\C\S\0\_\N\)
PCIE13_CRX_DTX_N: JSSD1.5(PERN3) UU1.CG7(PCIE13_RXN)
PCIE13_CRX_DTX_P: JSSD1.7(PERP3) UU1.CG6(PCIE13_RXP)
PCIE13_CTX_DRX_N: CN2.1 UU1.CT3(PCIE13_TXN)
PCIE13_CTX_DRX_N_C: CN2.2 JSSD1.11(PETN3)
PCIE13_CTX_DRX_P: CN3.1 UU1.CT5(PCIE13_TXP)
PCIE13_CTX_DRX_P_C: CN3.2 JSSD1.13(PETP3)
PCIE14_CRX_DTX_N: JSSD1.17(PERN2) UU1.CE6(PCIE14_RXN)
PCIE14_CRX_DTX_P: JSSD1.19(PERP2) UU1.CE7(PCIE14_RXP)
PCIE14_CTX_DRX_N: CN8.1 UU1.CT2(PCIE14_TXN)
PCIE14_CTX_DRX_N_C: CN8.2 JSSD1.23(PETN2)
PCIE14_CTX_DRX_P: CN9.1 UU1.CT1(PCIE14_TXP)
PCIE14_CTX_DRX_P_C: CN9.2 JSSD1.25(PETP2)
PCIE15_CRX_DTX_N: JSSD1.29(PERN1) UU1.CC5(PCIE15_RXN/SATA1B_RXN)
PCIE15_CRX_DTX_P: JSSD1.31(PERP1) UU1.CC6(PCIE15_RXP/SATA1B_RXP)
PCIE15_CTX_DRX_N: CN10.1 UU1.CR3(PCIE15_TXN/SATA1B_TXN)
PCIE15_CTX_DRX_N_C: CN10.2 JSSD1.35(PETN1)
PCIE15_CTX_DRX_P: CN11.1 UU1.CR4(PCIE15_TXP/SATA1B_TXP)
PCIE15_CTX_DRX_P_C: CN11.2 JSSD1.37(PETP1)
PCIE16_SATA_CRX_DTX_N: JSSD1.43(PERP0/SATA_BN) UU1.CA6(PCIE16_RXN/SATA2_RXN)
PCIE16_SATA_CRX_DTX_P: JSSD1.41(PERN0/SATA_BP) UU1.CA5(PCIE16_RXP/SATA2_RXP)
PCIE16_SATA_CTX_DRX_N: CN12.1 UU1.CP1(PCIE16_TXN/SATA2_TXN)
PCIE16_SATA_CTX_DRX_N_C: CN12.2 JSSD1.47(PETN0/SATA_AN)
PCIE16_SATA_CTX_DRX_P: CN13.1 UU1.CP2(PCIE16_TXP/SATA2_TXP)
PCIE16_SATA_CTX_DRX_P_C: CN13.2 JSSD1.49(PETP0/SATA_AP)
PCIE_CLKREQ_VGA_N: QV1.3(D) RU103.1 RV13.2 UU1.DK33(GPP_D5/S\R\C\C\L\K\R\E\Q\0\_\N\)
PCIE_CRX_C_GTX_N0: CV7.2 UV2.AB9(PEX_TX0*)
PCIE_CRX_C_GTX_N1: CV9.2 UV2.AC10(PEX_TX1*)
PCIE_CRX_C_GTX_N2: CV14.2 UV2.AC11(PEX_TX2*)
PCIE_CRX_C_GTX_N3: CV27.2 UV2.AB12(PEX_TX3*)
PCIE_CRX_C_GTX_P0: CV6.2 UV2.AC9(PEX_TX0)
PCIE_CRX_C_GTX_P1: CV8.2 UV2.AB10(PEX_TX1)
PCIE_CRX_C_GTX_P2: CV13.2 UV2.AD11(PEX_TX2)
PCIE_CRX_C_GTX_P3: CV26.2 UV2.AC12(PEX_TX3)
PCIE_CRX_GTX_N0: CV7.1 UU1.DA6(PCIE5_RXN/USB31_5_RXN)
PCIE_CRX_GTX_N1: CV9.1 UU1.CY7(PCIE6_RXN/USB31_6_RXN)
PCIE_CRX_GTX_N2: CV14.1 UU1.CV7(PCIE7_RXN)
PCIE_CRX_GTX_N3: CV27.1 UU1.CT6(PCIE8_RXN)
PCIE_CRX_GTX_P0: CV6.1 UU1.DA7(PCIE5_RXP/USB31_5_RXP)
PCIE_CRX_GTX_P1: CV8.1 UU1.CY6(PCIE6_RXP/USB31_6_RXP)
PCIE_CRX_GTX_P2: CV13.1 UU1.CV6(PCIE7_RXP)
PCIE_CRX_GTX_P3: CV26.1 UU1.CT7(PCIE8_RXP)
PCIE_CTX_GRX_N0: CU27.2 UV2.AG7(PEX_RX0*)
PCIE_CTX_GRX_N0_C: CU27.1 UU1.DE4(PCIE5_TXN/USB31_5_TXN)
PCIE_CTX_GRX_N1: CU29.2 UV2.AE7(PEX_RX1*)
PCIE_CTX_GRX_N1_C: CU29.1 UU1.DD1(PCIE6_TXN/USB31_6_TXN)
PCIE_CTX_GRX_N2: CU23.1 UV2.AF9(PEX_RX2*)
PCIE_CTX_GRX_N2_C: CU23.2 UU1.DD3(PCIE7_TXN)
PCIE_CTX_GRX_N3: CU25.1 UV2.AG10(PEX_RX3*)
PCIE_CTX_GRX_N3_C: CU25.2 UU1.DA3(PCIE8_TXN)
PCIE_CTX_GRX_P0: CU28.2 UV2.AG6(PEX_RX0)
PCIE_CTX_GRX_P0_C: CU28.1 UU1.DE3(PCIE5_TXP/USB31_5_TXP)
PCIE_CTX_GRX_P1: CU30.2 UV2.AF7(PEX_RX1)
PCIE_CTX_GRX_P1_C: CU30.1 UU1.DD2(PCIE6_TXP/USB31_6_TXP)
PCIE_CTX_GRX_P2: CU24.1 UV2.AE9(PEX_RX2)
PCIE_CTX_GRX_P2_C: CU24.2 UU1.DD5(PCIE7_TXP)
PCIE_CTX_GRX_P3: CU26.1 UV2.AG9(PEX_RX3)
PCIE_CTX_GRX_P3_C: CU26.2 UU1.DA5(PCIE8_TXP)
PCIE_RCOMP_N: RU142.2 UU1.DN1(PCIE_RCOMPN)
PCIE_RCOMP_P: RU142.1 UU1.DN3(PCIE_RCOMPP)
PCIE_REFCLK_GFX_DN: UU1.CJ3(CLKOUT_PCIE_N0) UV2.AD8(PEX_REFCLK*)
PCIE_REFCLK_GFX_DP: UU1.CJ5(CLKOUT_PCIE_P0) UV2.AE8(PEX_REFCLK)
PCIE_REFCLK_SSD_DN: JSSD1.53(REFCLKN) UU1.CJ2(CLKOUT_PCIE_N4)
PCIE_REFCLK_SSD_DP: JSSD1.55(REFCLKP) UU1.CJ1(CLKOUT_PCIE_P4)
PCIE_REFCLK_WLAN_DN: JW1.49(REFCLKN0) UU1.CK3(CLKOUT_PCIE_N3)
PCIE_REFCLK_WLAN_DP: JW1.47(REFCLKP0) UU1.CK4(CLKOUT_PCIE_P3)
PCIE_SSD1_WAKE_N: JSSD1.54(PEWAKE*) TP176.1
PCIE_SSD_CLKREQ1: JSSD1.52(CLKREQ*) RN3.1 UU1.DN40(GPP_H10/S\R\C\C\L\K\R\E\Q\4\_\N)
PCIE_WLAN_CLK_REQ_N: QW2.2 RU101.1 RW12.1 UU1.DP36(GPP_D8/S\R\C\C\L\K\R\E\Q\3\_\N\)
PCIE_WLAN_CLK_REQ_N_C: JW1.53(CLKREQ0_N) QW2.3 RW9.1 RW12.2
PCIE_WLAN_RX_DN: JW1.43(PERN0) UU1.CM7(PCIE10_RXN)
PCIE_WLAN_RX_DP: JW1.41(PERP0) UU1.CM6(PCIE10_RXP)
PCIE_WLAN_TX_DN: CW9.1 UU1.CY3(PCIE10_TXN)
PCIE_WLAN_TX_DN_C: CW9.2 JW1.37(PETN0)
PCIE_WLAN_TX_DP: CW10.1 UU1.CY4(PCIE10_TXP)
PCIE_WLAN_TX_DP_C: CW10.2 JW1.35(PETP0)
PCIE_WLAN_WAKE_N_R: JW1.55(PEWAKE0_N) RW57.2 RW68.2 RW69.1
PECI_EC: RE103.1 UE1.B1(PECI/SMCLK2/GPF6)
PECI_SOC: RE103.2 UU1.CD5(PECI)
PEX_TERMP: RV21.2 UV2.AF25(PEX_TERMP)
PLT_RST_N: CU34.1 CV24.1 RF7.2 RN8.2 RT66.1 RU161.1 RU163.2 RU167.2 RW21.1 UV1.1(IN1)
PLT_RST_N_SSD: JSSD1.50(PERST*) RN8.1 RN31.1
PLT_RST_SOC_N: RU165.2 RU167.1 UU1.CM49(GPP_B13/P\L\T\R\S\T\_\N\) UU2.2(A)
PLT_RST_VGA_N: CV195.2 RV3.2 RV50.2 RV138.2 UV2.AC7(PEX_RST*)
PM_AC_PRESENT: RE109.2 RE114.2 UE1.N1(RI1#/GPD0) UU1.DE46(GPD1/ACPRESENT)
PM_BATLOW_N: RU170.2 UU1.DH48(GPD0/B\A\T\L\O\W\_\N\)
PM_PWRBTN_R_N: RE110.2 TPU16.1 UE1.D9(PS2CLK2/GPF4) UU1.CY42(GPD3/P\W\R\B\T\N\_\N\)
PM_SYSRST_N: RU171.2 UU1.DK19(S\Y\S\_\R\E\S\E\T\_\N\)
PORTB_L: CA72.1 UA2.45(PORTB_L)
PORTB_R: CA73.1 UA2.46(PORTB_R)
PORTD_A: RA241.1 UA2.42(PORTD_A)
PORTD_B: RA240.1 UA2.43(PORTD_B)
POST_DEBUG_CLK: RP14.1 RW73.1 UE1.A4(RXD/SIN0/GPB0)
POST_DEBUG_CLK_R: JP2.2 RP14.2 TPP13.1
POST_DEBUG_DATA: RP15.1 RW74.1 UE1.A3(TXD/SOUT0/GPB1)
POST_DEBUG_DATA_R: JP2.3 RP15.2 TPP14.1
PP_TPM: RF9.1 RF10.2 UF15.4(PP/GPIO6)
PRE_8409A: RI104.2 UI2.27(PRE)
PROCHOT_EC_N: QE4.3 RE92.1
PROCHOT_SOC_N: RU19.2 UU1.C3(P\R\O\C\H\O\T\_\N\)
PROCPWRGD: CU32.1 RU160.2 TPU24.1 UU1.CF1(PROCPWRGD)
PSI_VGA: PR835.2 RV34.1 RV42.1
PSI_VGA_R: RV42.2 UV2.A4(GPIO6)
PWR_BUTTON_N: PBTE1.1(A) RE1.2 RE2.1 RE451.1
PWR_BUTTON_N_KB: CE373.1 ESDE44.1 JE7.27 RE451.2 SW5.1 SW5.2
PWR_LEVEL: QV24.3(D) RV31.1 UV2.D7(GPIO12)
REMOTE1+: CS2.1 QS1.1 QS1.3 US1.2(D1+)
REMOTE1-: CS2.2 QS1.2 US1.3(D1-)
REMOTE2+: CS17.1 QS2.1 QS2.3 US1.4(D2+)
REMOTE2-: CS17.2 QS2.2 US1.5(D2-)
RESETB_8409A: CI120.1 RI154.1 UI2.35(RESETB)
RETIMER_FORCE_PWR: RT10.2 RT36.2 TPT21.1 UU1.CR39(GPP_B4/CPU_GP3)
RIPQ_N_SOC: RF6.2 UU1.CC48(GPP_G1/SD_DATA0)
RIPQ_N_TPM: RE447.2 RF6.1 UF15.18(PIRQ#/GPIO2)
ROM_SCLK: RV124.2 RV127.1 UV2.C12(ROM_SCLK)
ROM_SI: RV123.2 RV126.1 UV2.B12(ROM_SI)
ROM_SO: RV122.2 RV125.1 UV2.A12(ROM_SO)
RSMRST_N_EC: CU39.1 DL3.2 QU6.3 RU176.1 UE1.A1(RING#/PWRFAIL#/CK32KOUT/LPCRST#) UU1.DG49(R\S\M\R\S\T\_\N\)
RSVD_2: UU1.A33(RSVD_2)
RSVD_3: UU1.B33(RSVD_3)
RSVD_74: UU1.W35(RSVD_74)
RSVD_75: UU1.AA35(RSVD_75)
RSVD_76: UU1.Y34(RSVD_76)
RT_TCP0_I2C0_SCL: RT39.2 UU1.DT23(GPP_C17/I2C0_SCL)
RT_TCP0_I2C0_SDA: RT40.2 UU1.DT24(GPP_C16/I2C0_SDA)
RTC_RST_N: CU10.1 QU2.3(D) RU91.1 TPU8.1 UU1.DT47(R\T\C\R\S\T\_\N\)
RTC_VCC: JRTCU1.1 RU174.1 TP188.1
SATA1_DEVSLP: RN4.2 UU1.CV48(GPP_A11/DEVSLP2)
SATA1_DEVSLP_CON: JSSD1.38(DEVSLP) RN4.1 RN5.2
SCANIN0: JE7.8 UE1.J12(KSI0/STB#)
SCANIN1: JE7.7 UE1.J13(KSI1/AFD#)
SCANIN2: JE7.6 UE1.J9(KSI2/INIT#)
SCANIN3: JE7.5 UE1.H12(KSI3/SLIN#)
SCANIN4: JE7.4 UE1.H9(KSI4)
SCANIN5: JE7.3 UE1.H10(KSI5)
SCANIN6: JE7.2 UE1.H13(KSI6)
SCANIN7: JE7.1 UE1.G9(KSI7)
SCANOUT0: JE7.26 UE1.M8(KSO0/PD0)
SCANOUT1: JE7.25 UE1.J7(KSO1/PD1)
SCANOUT2: JE7.24 UE1.N9(KSO2/PD2)
SCANOUT3: JE7.23 UE1.M9(KSO3/PD3)
SCANOUT4: JE7.22 UE1.K8(KSO4/PD4)
SCANOUT5: JE7.21 UE1.J8(KSO5/PD5)
SCANOUT6: JE7.20 UE1.N10(KSO6/PD6)
SCANOUT7: JE7.19 UE1.M10(KSO7/PD7)
SCANOUT8: JE7.18 UE1.N11(KSO8/ACK#)
SCANOUT9: JE7.17 UE1.K9(KSO9/BUSY)
SCANOUT10: JE7.16 UE1.N12(KSO10/PE)
SCANOUT11: JE7.15 UE1.N13(KSO11/ERR#)
SCANOUT12: JE7.14 UE1.M13(KSO12/SLCT)
SCANOUT13: JE7.13 UE1.L12(KSO13)
SCANOUT14: JE7.12 UE1.L13(KSO14)
SCANOUT15: JE7.11 UE1.K12(KSO15)
SCANOUT16: JE7.10 UE1.K13(KSO16/SMOSI/GPC3)
SCANOUT17: JE7.9 UE1.J10(KSO17/SMISO/GPC5)
SCL_TPM: TPF4.1 UF15.30(SCL/GPIO1)
SD3_RCOMP: RU134.2 UU1.CJ43(SD3_RCOMP)
SDA_TPM: TPF3.1 UF15.29(SDA/GPIO0)
SET1_HR1: PR609.1 PR616.2
SET1_HR2: PR620.1 PR624.2
SET2_HR1: PR610.1 PR617.2
SET2_HR2: PR621.1 PR625.2
SET3_HR1: PR611.1 PR618.2
SET3_HR2: PR622.1 PR626.2
SKTOCC_N: TPU40.1 UU1.C5(S\K\T\O\C\C\_\N\)
SLP_A_N: TPU17.1 UU1.DH47(GPD6/S\L\P\_\A\_\N\)
SLP_LAN_N: TPU22.1 UU1.DN48(S\L\P\_\L\A\N\_\N\)
SLP_S0_N: PR917.1 RE115.2 RU169.2 UU1.CL45(GPP_B12/S\L\P\_\S\0\_\N\)
SLP_S0_N_EC: RE115.1 RE459.1 UE1.A12(EGCS#/GPE2)
SLP_S3_N: PR913.1 PR916.1 PR918.1 RE462.1 RU178.1 TPU13.1 UU1.DF47(GPD4/S\L\P\_\S\3\_\N\)
SLP_S3_N_EC: RE462.2 UE1.F4(DTR1#/SBUSY/GPG1/ID7)
SLP_S4_N: PR708.1 RE461.1 RU179.1 TPU14.1 UU1.DC48(GPD5/S\L\P\_\S\4\_\N\)
SLP_S4_N_EC: RE461.2 UE1.D1(DSR0#/GPG6)
SLP_S5_N: RT42.2 RU180.1 TPU15.1 UU1.DF45(GPD10/S\L\P\_\S\5\_\N\)
SLP_SUS_N: PR414.1(A[0]) PR415.2 TPU18.1 UU1.DM49(S\L\P\_\S\U\S\_\N\)
SLP_WLAN_N: RU177.1 RW26.1 TPU20.1 UU1.DE49(GPD9/S\L\P\_\W\L\A\N\_\N\)
SM_BAT_CLK: PC155.1 PESD106.2 PR135.1 PR161.1 PR163.1 UE1.B3(SMCLK1/GPC1)
SM_BAT_DATA: PC105.1 PESD106.1 PR129.1 PR130.1 PR134.1 UE1.B2(SMDAT1/GPC2)
SM_BATT_SCL: PJ101.4 PR135.2 PTP101.1
SM_BATT_SDA: PJ101.3 PR129.2 PTP103.1
SM_INTRUDER_N: CU31.1 RU156.1 RU225.1 UU1.DR47(I\N\T\R\U\D\E\R\_\N\)
SMB_EC_SCLK: CE375.1 QU1.4(S1) QV3.3(D1) RE113.1 RV24.1 UE1.M2(PWUREQ#/BBO/SMCLK2ALT/GPC7) US1.10(SCLK) US4.1(SCLK)
SMB_EC_SCLK3_R: RE3.2 RE123.1 UE1.E8(CRX1/SIN1/SMCLK3/GPH1/ID1)
SMB_EC_SDATA: CE374.1 QU1.1(S1) QV3.6(D1) RE112.1 RV26.1 UE1.C1(SMDAT2/PECIRQT#/GPF7) US1.9(SDA) US4.5(SDA)
SMB_EC_SDATA3_R: RE4.2 UE1.D7(CTX1/SOUT1/GPH2/SMDAT3/ID2)
SMB_TYPEC_SCLK: RT12.1 TPT17.1 UE1.B4(SMCLK0/GPB3)
SMB_TYPEC_SDATA: RT11.1 TPT16.1 UE1.A2(SMDAT0/GPB4)
SMBUS_CLK0: RT37.2 RU41.1 UU1.DK24(GPP_C3/SML0CLK)
SMBUS_DAT0: RT38.2 RU42.1 UU1.DJ24(GPP_C4/SML0DATA)
SNDW_RCOMP: RU137.1 UU1.CV38(SNDW_RCOMP)
SNK_PS_ACK: RT13.2 RT98.1 UT6.A2(ACK)
SOC_BT_PCMCLK: RU135.2 UU1.CT49(GPP_A7/I2S2_SCLK)
SOC_SCI_N: DE5.2 RE87.1 RU32.1 UU1.CR38(GPP_B3/CPU_GP2)
SPI1_CLK: RU55.1 RU62.2 TP183.1 UU1.DV16(GPP_E11/SPI1_CLK/BK1/SBK1)
SPI1_CS0_N: RU56.1 RU63.2 TP184.1 UU1.DW16(GPP_E10/SPI1_CS_N/BK0/SBK0)
SPKL_N1: JDB1.20 JDB1.21 RA243.1 UA2.24(PROTGLEFT-)
SPKL_P1: JDB1.18 JDB1.19 RA242.1 UA2.22(PORTGLEFT+)
SPKR_N1: JDB1.23 JDB1.24 RA244.1 UA2.25(PROTGRIGHT-)
SPKR_P1: JDB1.25 JDB1.26 RA245.1 UA2.27(PROTGRIGHT+)
SRC_PS_FLT_N: RT15.2 RT95.1 UT5.A4(#FLT)
SRC_PS_FO: RT14.2 RT92.2 RT94.1 UT5.C4(FO)
SRC_PS_FO_OVP_TRIP: RT13.1 RT14.1 UT1.14(I2C_SDA_SCB4/OVP_TRIP)
SRTC_RST_N: CU11.1 RU89.1 UU1.DK46(S\R\T\C\R\S\T\_\N\)
SSD1_DET: JSSD1.69(CONFIG_1) RN11.1 RN37.1 RU126.2 UU1.CR43(GPP_A13/SATAXPCIE2/SATAGP2)
SSD1_DET_R: RU126.1 UU1.CE46(GPP_G6/SD_CLK)
SSD_RST_N: RN30.1 RN31.2 RN33.2 UU1.DK22(GPP_C12/UART1_RXD/ISH_UART1_RXD)
STATUS_N_U1: RB49.1 RE94.1 RE127.1 UB6.9(STATUS#)
STATUS_N_U1_R: RE94.2 UE1.A10(PS2CLK1/DTR0#/GPF2)
STRAP0: RV110.2 RV113.1 UV2.D1(STRAP0)
STRAP1: RV111.2 RV114.1 UV2.D2(STRAP1)
STRAP2: RV112.2 RV115.1 UV2.E4(STRAP2)
STRAP3: RV116.2 RV119.1 UV2.E3(STRAP3)
STRAP4: RV117.2 RV120.1 UV2.D3(STRAP4)
STRAP5: RV118.2 RV121.1 UV2.C1(STRAP5)
SUS_CLK: RU84.1 UU1.DF49(GPD8/SUSCLK)
SUS_CLK_WLAN: RU84.2 RW8.1
SUSCLK_WLAN: CW8.1 JW1.50(SUSCLK) RW8.2
SWD_CLK_CCG5_I2C_CFG_EC: RT2.2 RT4.1 TPT4.1 UT1.2(SWD_CLK/I2C_CFG_EC/GPIO)
SYS_PEX_RST_MON_N: RV2.1 RV3.1 RV38.1 RV251.1 UV1.4(OUT)
SYS_PEX_RST_MON_N_R: RV251.2 UV2.D5(GPIO16)
SYS_PWROK: CU36.1 RU173.1 TPE105.1 UE1.G1(GPJ7) UU1.DP19(SYS_PWROK)
TBT_LSX0_RXD: RT33.2 RU8.1 RU13.2 UT2.L7(PA_LSRX_SBU2) UU1.DK17(GPP_E19/DDP1_CTRLDATA/TBT_LSX0_)
TBT_LSX0_TXD: RT32.2 UT2.M7(PA_LSTX_SBU1) UU1.DL17(GPP_E18/DDP1_CTRLCLK/TBT_LSX0_T)
TC_RETIMER_FORCE_PWR: RT36.1 RT51.1 RT52.2 UT2.B10(FORCE_PWR)
TCH_EN_EC: RX922.1 UE1.N2(SMCLK4/L80HLAT/BAO/GPE0)
TCH_EN_SOC: RX923.1 UU1.CH45(GPP_B19/G\S\P\I\1\_\C\S\0\_\N\)
TCP0_ATEST_N: TPT8.1 UT2.A2(ATEST_N)
TCP0_ATEST_P: TPT7.1 UT2.A1(ATEST_P)
TCP0_AUX_DN: UT2.M8(PA_AUX_N) UU1.AY5(TCP0_AUX_N)
TCP0_AUX_DP: UT2.L8(PA_AUX_P) UU1.AY6(TCP0_AUX_P)
TCP0_CC1_CONN: CT79.1 ESDT6.2 JT1.A5(CC1) RT111.2 RT114.2 UT7.4(C_CC1)
TCP0_CC1_PD: CT16.1 RT111.1 UT1.9(CC1) UT7.12(CC1)
TCP0_CC2_CONN: CT80.1 ESDT6.1 JT1.B5(CC2) RT112.2 RT116.2 UT7.5(C_CC2)
TCP0_CC2_PD: CT17.1 RT112.1 UT1.7(CC2) UT7.11(CC2)
TCP0_RESET_N: RT41.1 RT42.1 UT2.L11(RESET_N)
TCP0_RT_TX0_DN: RT27.1 UT2.G11(BSSTXN1)
TCP0_RT_TX0_DN_C: CT69.1 ESDT3.1(K1) RT27.2
TCP0_RT_TX0_DN_CONN: CT69.2 JT1.A3(TX1-) RT131.1
TCP0_RT_TX0_DP: RT26.1 UT2.G12(BSSTXP1)
TCP0_RT_TX0_DP_C: CT68.1 ESDT2.1(K1) RT26.2
TCP0_RT_TX0_DP_CONN: CT68.2 JT1.A2(TX1+) RT132.1
TCP0_RT_TX1_DN: RT31.1 UT2.E11(BSSTXN2)
TCP0_RT_TX1_DN_C: CT71.1 ESDT9.1(K1) RT31.2
TCP0_RT_TX1_DN_CONN: CT71.2 JT1.B3(TX2-) RT133.1
TCP0_RT_TX1_DP: RT30.1 UT2.E12(BSSTXP2)
TCP0_RT_TX1_DP_C: CT70.1 ESDT8.1(K1) RT30.2
TCP0_RT_TX1_DP_CONN: CT70.2 JT1.B2(TX2+) RT134.1
TCP0_RT_TXRX0_DN: RT25.1 UT2.J11(BSSRXN1)
TCP0_RT_TXRX0_DN_C: CT63.1 ESDT5.1(K1) RT25.2
TCP0_RT_TXRX0_DN_CONN: CT63.2 JT1.B10(RX1-) RT115.1
TCP0_RT_TXRX0_DP: RT24.1 UT2.J12(BSSRXP1)
TCP0_RT_TXRX0_DP_C: CT62.1 ESDT4.1(K1) RT24.2
TCP0_RT_TXRX0_DP_CONN: CT62.2 JT1.B11(RX1+) RT113.1
TCP0_RT_TXRX1_DN: RT29.1 UT2.C11(BSSRXN2)
TCP0_RT_TXRX1_DN_C: CT65.1 ESDT11.1(K1) RT29.2
TCP0_RT_TXRX1_DN_CONN: CT65.2 JT1.A10(RX2-) RT119.1
TCP0_RT_TXRX1_DP: RT28.1 UT2.C12(BSSRXP2)
TCP0_RT_TXRX1_DP_C: CT64.1 ESDT10.1(K1) RT28.2
TCP0_RT_TXRX1_DP_CONN: CT64.2 JT1.A11(RX2+) RT118.1
TCP0_SBU1: RT120.1 UT2.M10(BSBU1) UT7.15(SBU1)
TCP0_SBU1_CONN: CT72.1 ESDT7.2 JT1.A8(SBU1) RT120.2 RT122.2 UT7.1(C_SBU1)
TCP0_SBU2: RT121.1 UT2.L10(BSBU2) UT7.14(SBU2)
TCP0_SBU2_CONN: CT73.1 ESDT7.1 JT1.B8(SBU2) RT121.2 RT123.2 UT7.2(C_SBU2)
TCP0_THERMDA: TPT6.1 UT2.M11(THERMDA)
TCP0_TX0_C_DN: CT18.2 UT2.J2(ASSRXN1)
TCP0_TX0_C_DP: CT19.2 UT2.J1(ASSRXP1)
TCP0_TX0_DN: CT18.1 UU1.BB5(TCP0_TX_N0)
TCP0_TX0_DP: CT19.1 UU1.BB6(TCP0_TX_P0)
TCP0_TX1_C_DN: CT23.2 UT2.C2(ASSRXN2)
TCP0_TX1_C_DP: CT22.2 UT2.C1(ASSRXP2)
TCP0_TX1_DN: CT23.1 UU1.AV6(TCP0_TX_N1)
TCP0_TX1_DP: CT22.1 UU1.AV5(TCP0_TX_P1)
TCP0_TXRX0_C_DN: CT21.2 UT2.G2(ASSTXN1)
TCP0_TXRX0_C_DP: CT20.2 UT2.G1(ASSTXP1)
TCP0_TXRX0_DN: CT21.1 UU1.BH2(TCP0_TXRX_N0)
TCP0_TXRX0_DP: CT20.1 UU1.BH1(TCP0_TXRX_P0)
TCP0_TXRX1_C_DN: CT25.2 UT2.E2(ASSTXN2)
TCP0_TXRX1_C_DP: CT24.2 UT2.E1(ASSTXP2)
TCP0_TXRX1_DN: CT25.1 UU1.BF1(TCP0_TXRX_N1)
TCP0_TXRX1_DP: CT24.1 UU1.BF2(TCP0_TXRX_P1)
TCP_RETIMER_PERST_N: RT60.1 RU158.1 RU159.2 UU1.DC47(GPD7)
TCP_RETIMER_PERST_N_R: RT54.1 RT55.2 RT60.2 RT66.2 UT2.B8(PERST_N)
TCP_SMBUS_SCL: RT37.1 RT39.1 RT47.1 UT2.A7(SMBUS_SCL)
TCP_SMBUS_SDA: RT38.1 RT40.1 RT48.1 UT2.B7(SMBUS_SDA)
TCRCOMP_DN: RU5.1 UU1.AY1(TC_RCOMP_N)
TCRCOMP_DP: RU5.2 UU1.AY2(TC_RCOMP_P)
THERMTRIP_SOC_N: QU4.2 QU5.2 QU6.2 RU21.1 UU1.E3(T\H\R\M\T\R\I\P\_\N\)
TOUCHPAD_EN: CE55.1 ESDE4.1 JE4.8 RE69.2 TP150.1 UE1.N3(RI2#/GPD1)
TOUCHPAD_I2C_CLK: RE61.1 UU1.DU23(GPP_C19/I2C1_SCL)
TOUCHPAD_I2C_CLK_C: CE44.1 ESDE6.1 JE4.6 QE3.4(S1) RE55.2 RE62.2 TP143.1
TOUCHPAD_I2C_SDA: RE63.1 UU1.DW23(GPP_C18/I2C1_SDA)
TOUCHPAD_I2C_SDA_C: CE45.1 ESDE7.1 JE4.5 QE3.1(S1) RE56.2 RE64.2 TP142.1
TOUCHPAD_INT_C: CE54.1 ESDE5.1 JE4.7 RE65.2 RE67.1 RE454.1 TP149.1
TOUCHPAD_INT_N: RE67.2 UU1.CC45(GPP_G0/SD_CMD)
TOUCHPAD_INT_N_EC: RE454.2 UE1.M12(TACH1A/TMA1/GPD7)
TP_+V_D4CH0_CA_VREF: TPU2.1 UU1.C44(DDR0_VREF_CA)
TP_+V_D4CH1_CA_VREF: TPU1.1 UU1.M38(RSVD_73)
TP_+V_LPCH0_DQ_VREF: TPU3.1 UU1.B45(DDR1_VREF_CA)
TP_DDR_VTT_CTRL: TPU4.1 UU1.M39(DDR_VTT_CTL)
TP_PWR_ON: RX919.2 UE1.B10(PS2DAT1/RTS0#/GPF3) UX2.4(EN)
TS_EN: DX1.3 ESDX2.1 JX1.22 RX105.2 RX921.2 TPU72.1
TYPEC_I2C_INT_EC: RT16.2 RT17.1 UE1.E5(CRX0/GPC0) UT1.15(I2C_INT_EC)
TYPEC_PD_CSN: CT14.1 RT90.2 UT1.40(CSN)
TYPEC_PD_CSP: CT15.1 RT89.2 UT1.1(CSP)
TYPEC_PD_RETIMER_CLK: RT35.2 RT128.2 TPT19.1 UT1.21(I2C_SCL_SCB3/VSEL1/GPIO)
TYPEC_PD_RETIMER_DAT: RT34.2 RT127.2 TPT18.1 UT1.20(I2C_SDA_SCB3/VSEL2/GPIO)
TYPEC_PD_SCLK: CT10.1 RT12.2 RT21.2 UT1.17(I2C_SCL_SCB1_EC)
TYPEC_PD_SDA: CT11.1 RT11.2 RT19.2 UT1.16(I2C_SDA_SCB1_EC)
TYPEC_PD_SOC_CLK: RT8.1 TPT15.1 UU1.DN22(GPP_C6/SML1CLK/SUSWARN_N/SUSPWR)
TYPEC_PD_SOC_CLK_R: CT13.1 RT8.2 RT22.2 UT1.4(I2C_SCL_SCB2_AR/GPIO)
TYPEC_PD_SOC_DAT: RT7.1 TPT14.1 UU1.DL22(GPP_C7/SML1DATA/S\U\S\A\C\K\_\N)
TYPEC_PD_SOC_DAT_R: CT12.1 RT7.2 RT20.2 UT1.3(I2C_SDA_SCB2_AR/GPIO)
TYPEC_PRESENT: QT3.2(S) RT105.1 UE1.F9(ADC3/GPI3)
TYPEC_PWR_EN: QT5.1(G) RT106.2 UE1.F13(ADC4/GPI4)
TYPEC_PWR_LIMIT: QT2.1(G) RE453.1 RT97.2
TYPEC_PWR_LIMIT_R: RE453.2 UE1.A11(PS2CLK0/CEC/TMB0/GPF0)
U42_L_U43E_Z: RU211.2 UU1.D4(RSVD_78)
UART2_RXD: RP12.2 TPP11.1 UU1.DT22(GPP_C20/UART2_RXD)
UART2_TXD: RP13.2 TPP10.1 UU1.DW22(GPP_C21/UART2_TXD)
UART_BT_WAKE_N: JW1.20(UART_WAKE_N) RW71.2 RW72.1
UART_BT_WAKE_N_SOC: RW71.1 UU1.DL38(GPP_H19/TIME_SYNC0)
UART_RX_P1: RT10.1 UT1.30(UART_RX)
UART_TX_P1: RT9.1 UT1.29(UART_TX)
USB2_COMP: RU141.1 UU1.DN5(USB2_COMP)
USB2_OTG_ID: RU147.2 UU1.DL6(USB_ID)
USB2_P1_DN: UB6.2(DM_OUT) UU1.DN8(USB2N_1)
USB2_P1_DN_R: CHKB25.2 RB363.2 UB6.11(DM_IN)
USB2_P1_DP: UB6.3(DP_OUT) UU1.DP8(USB2P_1)
USB2_P1_DP_R: CHKB25.1 RB364.2 UB6.10(DP_IN)
USB2_P3_TYPEC_DN: LT2.2 RT124.1 UU1.DP13(USB2N_3)
USB2_P3_TYPEC_DN_CON: ESDT12.1 JT1.A7(D-) JT1.B7(D-_1) LT2.3 RT124.2
USB2_P3_TYPEC_DP: LT2.1 RT125.1 UU1.DN13(USB2P_3)
USB2_P3_TYPEC_DP_CON: ESDT13.1 JT1.A6(D+) JT1.B6(D+_1) LT2.4 RT125.2
USB2_P4_DN: JDB1.15 UU1.DK10(USB2N_4)
USB2_P4_DP: JDB1.16 UU1.DJ10(USB2P_4)
USB2_P5_DN_FP: CHK1.3 ESD1.1 J1.4 R19.1 TP146.1
USB2_P5_DP_FP: CHK1.4 ESD1.2 J1.5 R20.1 TP147.1
USB2_P5_FP_DN: CHK1.2 R19.2 UU1.DL5(USB2N_5)
USB2_P5_FP_DP: CHK1.1 R20.2 UU1.DL3(USB2P_5)
USB2_P9_TS_DN: CHKX2.2 RX4.1 UU1.DL2(USB2N_9)
USB2_P9_TS_DN_R: CHKX2.3 JX1.20 RX4.2
USB2_P9_TS_DP: CHKX2.1 RX5.1 UU1.DL1(USB2P_9)
USB2_P9_TS_DP_R: CHKX2.4 JX1.19 RX5.2
USB2_P10_BT_DN: CHKW1.4 RW15.2 UU1.DP10(USB2N_10)
USB2_P10_BT_DN_WIFI: CHKW1.1 JW1.5(USB_DN) RW15.1
USB2_P10_BT_DP: CHKW1.3 RW18.2 UU1.DN10(USB2P_10)
USB2_P10_BT_DP_WIFI: CHKW1.2 JW1.3(USB_DP) RW18.1
USB2_VBUSSENSE: RU146.2 UU1.DL11(USB_VBUSSENSE)
USB2P0_OC_N: CB413.2 JDB1.8 RB373.2
USB3_P1_RX_DN: CHKB26.1 UU1.DJ8(PCIE1_RXN/USB31_1_RXN)
USB3_P1_RX_DP: CHKB26.2 UU1.DJ6(PCIE1_RXP/USB31_1_RXP)
USB3_P1_TX_DN: CB392.1 UU1.DJ2(PCIE1_TXN/USB31_1_TXN)
USB3_P1_TX_DN_C: CB392.2 CHKB27.1
USB3_P1_TX_DP: CB394.1 UU1.DJ1(PCIE1_TXP/USB31_1_TXP)
USB3_P1_TX_DP_C: CB394.2 CHKB27.2
USB3_RXN1_R: CHKB26.4 ESDB34.5 ESDB34.6 JB8.5(SSRX-)
USB3_RXP1_R: CHKB26.3 ESDB34.4 ESDB34.7 JB8.6(SSRX+)
USB3_TXN1_R: CHKB27.4 ESDB34.2 ESDB34.9 JB8.8(SSTX-)
USB3_TXP1_R: CHKB27.3 ESDB34.1 ESDB34.10 JB8.9(SSTX+)
USB_OC0: RB51.1 RU145.1 RU150.2 UU1.DW14(GPP_E9/U\S\B\_\O\C\0\_\N\)
USB_OC0_CH_R: CB38.2 RB51.2 UB6.13(FAULT#)
USB_OC1_N: RU7.1 UU1.CR41(GPP_A14/USB_OC1_N/DDSP_HPD3/DIS)
USB_OC2: RU143.1 TPU7.1 UU1.CT41(GPP_A15/USB_OC2_N/DDSP_HPD4/DIS)
USB_OC3: RB373.1 RU144.1 UU1.CT43(GPP_A16/U\S\B\_\O\C\3\_\N\)
USB_P7_CAM_N: CHKX5.2 RX19.1 UU1.DP11(USB2N_6)
USB_P7_CAM_P: CHKX5.1 RX20.1 UU1.DN11(USB2P_6)
USBP6_DN_CONN: CHKB25.3 EDB5.1 JB8.2(DM) RB363.1
USBP6_DP_CONN: CHKB25.4 EDB3.1 JB8.3(DP) RB364.1
VCORE: CE43.1 UE1.K5(VCORE)
VGA__CORE_LG1: PC864.1 PQ801.8(G2) PU802.19(LGATE1)
VGA_CORE1_IN: PC819.1 PC820.1 PC821.1 PC822.1 PQ801.2(D1[1]) PQ801.3(D1[2]) PQ801.4(D1[3]) PQ801.10(D1[4]) PR817.2 PSH806.1(A[0]) PSH809.1(A[0])
VGA_CORE2_IN: PC857.1 PC858.1 PC859.1 PC860.1 PQ802.2(D1[1]) PQ802.3(D1[2]) PQ802.4(D1[3]) PQ802.10(D1[4]) PSH807.1(A[0]) PSH808.1(A[0])
VGA_CORE_BOOT1: PR815.1 PU802.1(BOOT1)
VGA_CORE_BOOT1_R: PC818.1 PR815.2
VGA_CORE_BOOT2: PR849.1 PU802.15(BOOT2)
VGA_CORE_BOOT2_R: PC856.1 PR849.2
VGA_CORE_EN: PR820.2 PU802.3(EN)
VGA_CORE_LG2: PC865.1 PQ802.8(G2) PU802.17(LGATE2)
VGA_CORE_PGOOD: PR819.2 PU802.13(PGOOD)
VGA_CORE_PHASE1: PC818.2 PL802.1 PQ801.9(S1/D2) PR833.2 PU802.20(PHASE1)
VGA_CORE_PHASE2: PC856.2 PL803.1 PQ802.9(S1/D2) PR850.2 PU802.16(PHASE2)
VGA_CORE_PSI: PC827.1 PR822.2 PR835.1 PU802.4(PSI)
VGA_CORE_PVCC: PC824.1 PR816.1 PU802.18(PVCC)
VGA_CORE_PWM_VID: PR823.1 UV2.C6(GPIO0)
VGA_CORE_REFADJ: PR830.2 PU802.6(REFADJ)
VGA_CORE_REFADJ_R: PR829.1 PR830.1
VGA_CORE_REFADJ_R2: PC867.1 PR825.1 PR826.2 PR829.2
VGA_CORE_REFIN: PC868.1 PR826.1 PR839.2 PU802.7(REFIN)
VGA_CORE_REFIN_R: PR828.2 PR839.1
VGA_CORE_RGND: PC844.1 PC867.2 PC868.2 PR828.1 PR836.1 PR837.2 PU802.10(RGND)
VGA_CORE_SNB1: PC830.2 PR833.1
VGA_CORE_SNB2: PC855.2 PR850.1
VGA_CORE_SS: PC823.1 PC887.1 PR852.2 PR859.1 PU802.12(OCSET/SS)
VGA_CORE_TON: PR818.1 PU802.9(TON)
VGA_CORE_TON_R: PC825.1 PR817.1 PR818.2
VGA_CORE_UG1: PR814.1 PU802.2(UGATE1)
VGA_CORE_UG1_R: PQ801.1(G1) PR814.2
VGA_CORE_UG2: PR848.1 PU802.14(UGATE2)
VGA_CORE_UG2_R: PQ802.1(G1) PR848.2
VGA_CORE_VID: PC828.1 PR823.2 PU802.5(VID)
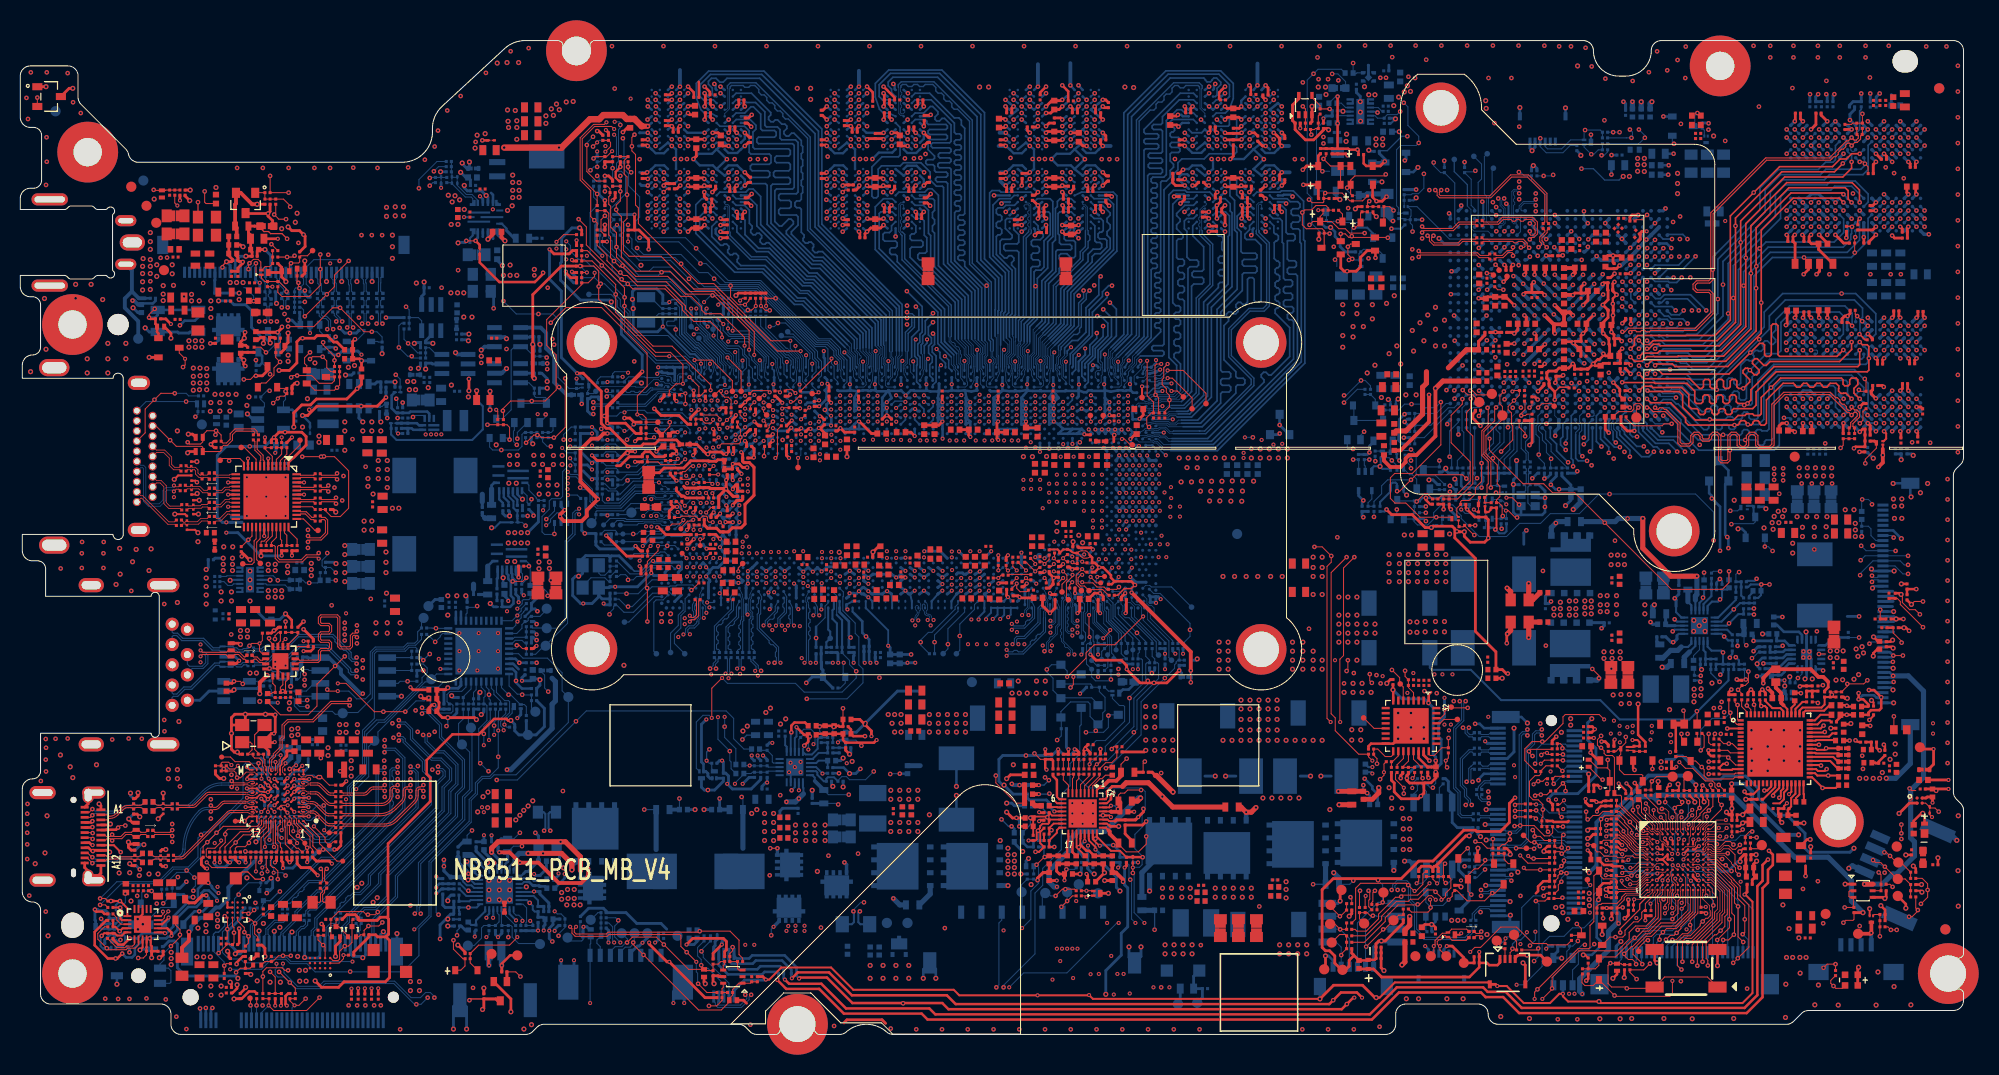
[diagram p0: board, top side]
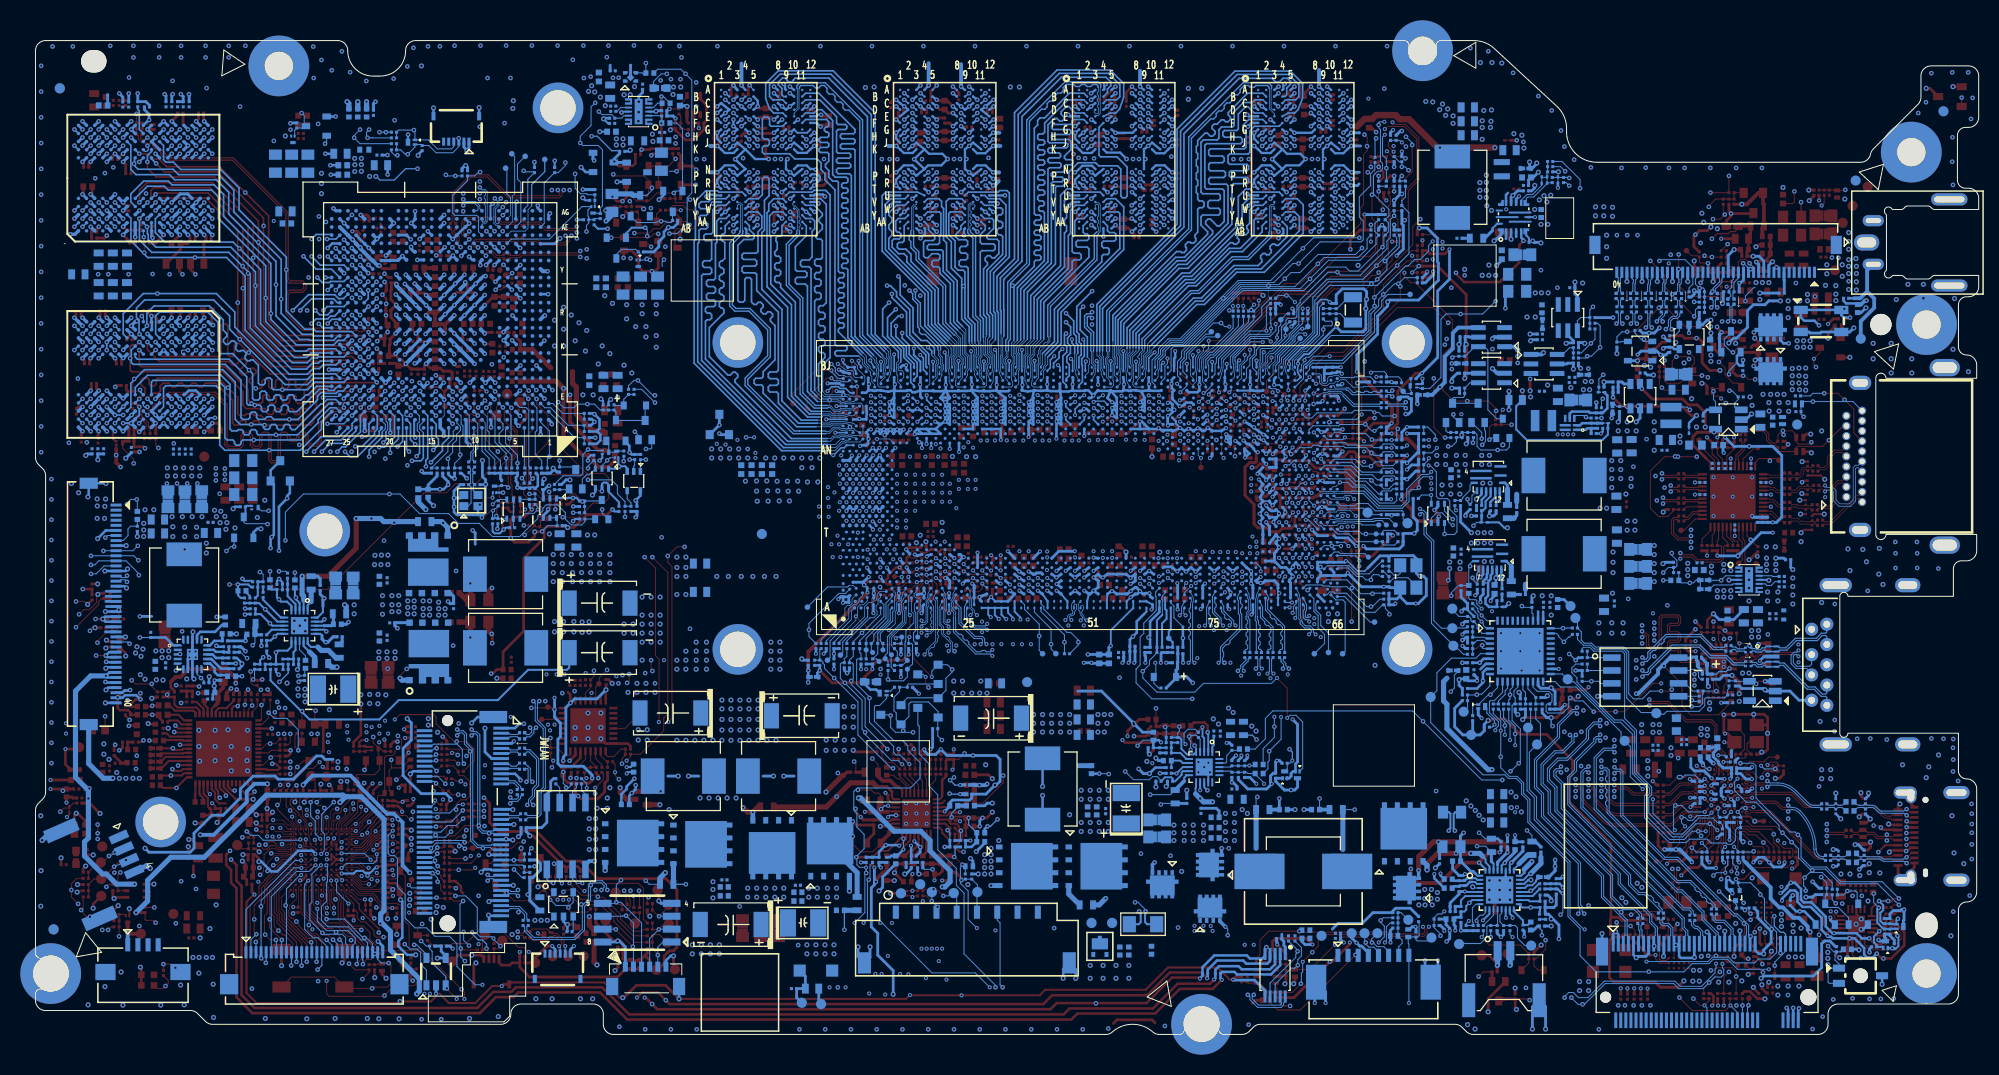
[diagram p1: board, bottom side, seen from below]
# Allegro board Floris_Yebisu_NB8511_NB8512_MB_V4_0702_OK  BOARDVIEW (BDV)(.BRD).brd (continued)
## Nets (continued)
VGA_CORE_VREF: PC844.2 PR824.2 PU802.8(VREF)
VGA_CORE_VREF_R: PR824.1 PR825.2
VGA_CORE_VSNS: PC863.2 PC887.2 PR827.1 PR838.2 PR860.2 PR861.1 PU802.11(VSNS)
VGA_SMB_CK2: CV193.1 QV3.4(S1) RV19.1 RV24.2 UV2.D9(I2CS_SCL)
VGA_SMB_DA2: CV194.1 QV3.1(S1) RV20.1 RV26.2 UV2.D8(I2CS_SDA)
VR_PSYS: PR660.2 PU601.9(PSYS)
VR_READY: PR628.1 PR659.2(B[0]) PU601.24(VR_READY)
VR_SVID_ALERT_N: PR657.2 PU601.3(ALERT)
VR_SVID_DATA: PR656.2 PU601.4(VDIO)
VR_SVID_VCLK: PR649.2 PU601.5(VCLK)
VREFP: CA69.1 UA2.40(VREFP)
VTT_EN: PR702.2 PR707.2(B[0]) PU701.10(VDDQ_EN)
WAKE_PCH_N: RU155.1 RW57.1 UU1.DL45(W\A\K\E\_\N\)
WAKE_PCIE_N_SOC: RU130.2 RU229.1 RW68.1
WAKE_PCIE_N_SOC_H2: RU50.1 RU58.2 RU229.2 UU1.DJ38(GPP_H2/CNV_BT_I2S_SDO)
WAKE_PCIE_N_SOC_R: RU130.1 UU1.CC49(GPP_G2/SD_DATA1)
WLAN_COEX1: JW1.48(COEX1) TPW1.1
WLAN_COEX2: JW1.46(COEX2) TPW2.1
WLAN_COEX3: JW1.44(COEX3) RW64.2
WLAN_OFF_N_WIFI: JW1.56(W_DISABLE1_N) RW6.2 RW59.1
WLAN_RST_N: RW22.1 UU1.DL21(GPP_C10/U\A\R\T\0\_\R\T\S\_\N\)
WLAN_RST_R_N: CW15.1 JW1.52(PERST0_N) RW21.2 RW22.2
XCLK_BIASREF: RU88.2 UU1.DU6(XCLK_BIASREF)
XRES_PD: CT9.1 RT18.2 TPT3.1 UT1.10(XRES)
XTAL_32K_SOC_IN: RU82.1 UU1.DL48(RTCX1)
XTAL_32K_SOC_OUT: RU83.1 UU1.DL49(RTCX2)
XTAL_38P4M_SOC_IN: RU85.1 UU1.DW8(XTAL_IN)
XTAL_38P4M_SOC_OUT: RU86.1 UU1.DU8(XTAL_OUT)
XTAL_IN: CV47.1 RV58.1 RV62.1 YV1.1
XTAL_OUT: CV48.2 RV59.2 RV62.2 YV1.3
XTAL_TCP0_25MHZ_IN: CT28.1 RT67.1 UT2.L9(XTAL_25_IN) XT1.1
XTAL_TCP0_25MHZ_OUT: CT29.1 RT67.2 UT2.M9(XTAL_25_OUT) XT1.3
XTALOUT: RV55.2 RV60.1 UV2.C10(XTAL_OUTBUFF)
XTALSSIN: RV57.2 UV2.A10(XTAL_SSIN)
ZQ0_CHA_0: RD3.1 UD1.A5(ZQ_A)
ZQ0_CHA_1: RD5.1 UD2.A5(ZQ_A)
ZQ0_CHB_0: RD7.1 UD3.A5(ZQ_A)
ZQ0_CHB_1: RD9.1 UD4.A5(ZQ_A)
ZQ1_CHA_0: RD4.1 UD1.A8(NC_A8)
ZQ1_CHA_1: RD6.1 UD2.A8(NC_A8)
ZQ1_CHB_0: RD8.1 UD3.A8(NC_A8)
ZQ1_CHB_1: RD10.1 UD4.A8(NC_A8)
N22527524: CV30.1 QV1.1(G) RV7.1
N22528692: QV3.2(G1) QV3.5(G1) RV17.2
N22791316: CV32.1 QV2.1(G) RV138.1
N22799047: QV17.3(D) RV83.1 RV84.1 RV86.1
N24199060: CV120.1 RV104.2 RV107.2
N24199064: RV97.2 UV3.J10(SEN)
N24199148: RV96.2 UV3.J1(MF)
N24199191: RV99.1 UV3.J13(ZQ)
N24199421: CV121.1 RV106.2 RV109.2
N24199628: RV141.2 UV4.J1(MF)
N24199642: RV98.2 UV4.J10(SEN)
N24200206: QV21.3(D) RV102.1
N26347975: QE3.3(D1) RE58.2 RE61.2 RE62.1
N26347977: QE3.6(D1) RE57.2 RE63.2 RE64.1
N26542555: DU2.1(ANODE) RU174.2
N27472427: RU163.1 UU2.4(Y)
N28124431: CU35.1 DU1.2 RU162.2 RU164.1 RU166.2
N28274141: PC502.1 PR505.1 PR507.2 PU501.20(VSYS)
N28274396: PC508.2 PR523.1
N28274400: PC507.2 PR522.1
N28274553: PR509.2 PU501.1(CS_DSI)
N28605202: PR635.1 PR650.2 PR651.2
N28625550: PR634.1 PR664.1
N28767371: QV10.3(D) RV70.1 RV74.1 RV75.1
N28895297: RV100.1 UV4.J13(ZQ)
N29341220: PC903.1 PC904.1 PSH902.1(A[0]) PU903.4(VOUT)
N29341240: PC976.1 PR904.2 PR920.2 PU903.6(ON)
N29341270: PC907.1 PC908.1 PSH904.1(A[0]) PU906.4(VOUT)
N29341288: PC978.1 PR909.2 PR921.2 PU906.6(ON)
N29343591: PQ901.1(G) PQ902.3(D) PR902.1
N29655416: PD907.1(ANODE) PR906.2 PR917.2
N29997405: CV35.2 UV2.AE2(TS_VREF)
N31718510: PSH901.1(A[0]) PU901.4(VOUT)
N31870830: QV7.1 QV8.3(D) QV23.3(D) RV50.1
N32026426: DV2.2 RV6.2
N32026428: DV1.1 RV5.2
N32026933: QV4.5(G1) QV4.6(D1) RV32.1
N32027968: DV7.1 RV23.2
N32028000: DV4.2 RV11.2
N32150852: CV37.1 DV9.1(ANODE) RV43.1
N32261981: QV9.3(D) RV69.1 RV72.1 RV73.1
N32264097: QV18.3 RV82.1
N32655790: TPV5.1 UV2.D12(ROM_CS*)
N32655853: RV65.1 UV2.D11(BUFRST*)
N32655965: RV63.1 UV2.AG4(JTAG_TRST*)
N32656019: TPV4.1 UV2.AD6(JTAG_TMS)
N32656021: TPV3.1 UV2.AF6(JTAG_TDO)
N32656023: TPV2.1 UV2.AE6(JTAG_TDI)
N32656025: TPV1.1 UV2.AE5(JTAG_TCK)
N32684902: RV94.1 UV2.F22(FBA_CMD34)
N32684905: RV95.1 UV2.J22(FBA_CMD35)
N32687502: CV45.1 RV53.1 UV2.N6(VID_PLLVDD)
N32687710: CV46.1 RV52.1 UV2.F11(GPCPLL_AVDD)
N32710606: RV67.1 UV2.C24(FB_CAL_PU_GND)
N32710608: RV66.1 UV2.D22(FB_CAL_PD_VDDQ)
N32710622: RV68.1 UV2.B25(FB_CAL_TERM_GND)
N32724071: TPE7.1 UV2.F4(VDDS_SENSE)
N32724132: TPE9.1 UV2.D23(FB_VREF)
N33004911: QV6.5(G1) QV6.6(D1) RV46.1
N33087941: RV89.2 UV2.V7(XVDD_65)
N33091607: QV11.3 RV71.1
N33196202: RV59.1 UV2.B10(XTAL_OUT)
N33196257: RV58.2 UV2.C11(XTAL_IN)
N33504961: DV3.2 RV10.2
N33775058: QW3.3 RW23.1 UW1.4(EN)
N33775085: QW3.2 RW26.2
N33775093: QW3.1 RW25.2 RW27.2
N36191271: CE9.1 QE2.1(G) RE13.2 RE138.1
N37658617: RS3.1 US4.3(ALERT#)
N37868722: RS1.1 US1.8(ALERT#)
N37868745: RS2.1 US1.7(TCRIT#)
N38294621: CX885.2 CX886.1 QX42.1(G) RX902.1 RX926.1
N38294628: CX886.2 QX42.3(D) SHX9.1(A[0])
N38297214: CF3.1 CF11.1 RF11.2 UF15.8(VHIO_1) UF15.22(VHIO_2)
N38298094: CF10.2 RF7.1 UF15.17(PLTRST#)
N38347014: RX908.1 UX1.3(ISET)
N38465677: PC135.1 PR132.1 PR133.1
N39299522: RE98.2 UE1.F1(GA20/GPB5)
N39375181: RI145.2 UI1.3(ISET)
N39375197: RI34.2 UI1.4(EN)
N39375277: JI1.13(CEC) RI144.1
N39472168: CA58.1 UA2.32(CP_VPOS)
N39472180: CA59.1 UA2.31(CP_VNEG)
N39472192: CA60.1 UA2.29(FLY_P)
N39472194: CA60.2 UA2.30(FLY_N)
N39472299: CA8.1 FBA1.2 UA2.50(VDD18)
N39472656: CA15.2 CA16.1 RA3.1 RA4.2 RA36.1
N39502644: DV16.2 RV244.2 RV245.2 RV250.2
N39574877: CL33.1 PR1013.1 QL7.1 QL8.3
N39574885: QL7.3 RL46.2 RL47.2
N39761277: PR1207.1(A[0]) PU1201.6(IN2_1) PU1201.7(IN2_2)
N39761295: PR1201.1 PR1202.2 PU1201.3(EN1)
N39761303: PR1206.2 PU1201.5(EN2)
N39761317: PC1209.1 PU1201.10(CT2)
N39761321: PC1210.1 PU1201.12(CT1)
N39868508: CL32.1 QL4.1 QL6.3 QL9.3(D) RL45.2
N39868516: CL1.1 QL9.1(G) RL1.1 RL2.2
N39869128: RX920.1 UX2.3(ISET)
N39869300: RX897.2 RX924.1 RX925.1 UX2.5(IN)
N39890653: PC1150.2 PR1150.1
N40069304: LEDE2.1 RE456.2
N40080399: DX1.2 RX105.1 RX922.2 RX923.2
N40120205: RW63.1 RW64.1 RW66.2 RW67.1
N40277661: PR6157.1 QL10.1 RL454.2 SW4.1 SW4.2
N40277712: QL10.3 RL455.2
N40346045: DV6.1 RV18.1
N40380306: PC863.1 PR859.2
N40380331: PC888.1 PR861.2
N40381802: PR1203.2 PU1202.3(EN)
N40385596: PC124.2 PQ103.5(D1) PR106.2 PR126.2
N40407372: PR106.3 PR107.2
N40407375: PR106.4 PR108.2
N40602816: RW70.2 UW1.3(ISET)
N40716824: CA38.1 RA242.2
N40854310: CA70.1 CA80.1 RA240.2
N40854356: CA71.1 CA81.1 RA241.2
N40860467: CA75.1 RA243.2
N40860733: CA76.1 RA244.2
N40860762: CA77.1 RA245.2
N40874129: PC403.1 PSH403.2(B[0]) PU401.5(IN)
N40897573: RT45.2 UT2.A12(PB_MONDC)
N40898959: DT1.2 RT68.2 RT73.2 RT130.1
N40901167: RT116.1 UT7.6(RPD_G2)
N40901169: RT114.1 UT7.7(RPD_G1)
N40901256: CT66.1 UT7.3(VBIAS)
N40901274: RT117.1 UT7.9(FLT_N)
N40903466: RT93.2 RT96.2 UT5.A3(ILIM)
N40903472: QT2.3(D) RT93.1
N40903516: QT4.3(D) RT102.1 UT6.A3(EN#)
N40903561: CT57.2 UT5.B1(VCP1) UT5.B2(VCP2) UT5.C1(VCP3)
N40903738: RT99.1 RT103.2 UT6.B3(OVLO)
N40903809: QT4.1(G) QT5.3(D) RT135.1
N40903829: CT61.1 UT5.D4(CAP)
N40903856: QT3.1(G) RT100.2 RT104.1
N40906352: RT78.2 UT2.J6(VSS_PRE_DRV)
N40907251: RU4.1 UU1.DJ17(GPP_E23/DDPA_CTRLDATA/BK4/SBK4)
N40908692: TPU6.1 UU1.CY43(GPP_A20/DDSP_HPD2/DISP_MISC2)
N40937500: CU7.1 RU81.1 RU83.2 YU1.1
N40937502: CU6.1 RU81.2 RU82.2 YU1.2
N40940127: CU9.1 RU86.2 RU87.2 YU2.1
N40940131: CU8.1 RU85.2 RU87.1 YU2.3
N40949670: RU138.2 UU1.DF38(GPP_S4/SNDW3_CLK/DMIC_CLK1)
N40950306: RU136.1 UU1.DG36(GPP_S6/SNDW4_CLK/DMIC_CLK0)
N40973835: PR652.1 PRT602.2
N40976884: PR640.1 PR642.2
N40976890: PR645.1 PR647.2
N40993976: PC912.1 PU902.10(CT2)
N40993990: PR911.1(A[0]) PR912.2 PR913.2 PR915.1(A[0])
N40994072: PC914.1 PU902.12(CT1)
N41005148: PC608.1 PR662.2
N41005333: PC609.1 PR663.2
N41026409: CU43.1 CU44.1 RU191.2 RU221.2
N41030628: CU45.1 SHU5.1(A[0]) UU1.DE31(VCCDSW_3P3)
N41033122: PC216.1 PR202.2 PR205.2 PU201.6(EN)
N41095610: TPU30.1 UU1.L34(RSVD_10)
N41104686: TPU32.1 UU1.AV1(RSVD_TP_17)
N41104706: TPU33.1 UU1.AT2(RSVD_TP_18)
N41104726: TPU37.1 UU1.DP3(RSVD_67)
N41104746: TPU39.1 UU1.DT2(RSVD_68)
N41108249: TPU25.1 UU1.A47(RSVD_TP_1)
N41108283: TPU26.1 UU1.B47(RSVD_TP_2)
N41108311: TPU28.1 UU1.C1(RSVD_57)
N41108321: TPU27.1 UU1.E1(RSVD_58)
N41108351: TPU34.1 UU1.CM33(TP_3)
N41108361: TPU35.1 UU1.DB10(TP_4)
N41108391: TPU36.1 UU1.DW3(RSVD_TP_7)
N41108401: TPU38.1 UU1.DV3(RSVD_TP_8)
N41320762: RI33.2 UI2.36(REXT)
N41326466: TPI3.1 UI2.2(TESTMODEB)
N41327429: TPI5.1 UI2.9(HDMI_CEC)
N41327451: TPI6.1 UI2.12(CEC_EN)
N41327606: TPI7.1 UI2.37(POWERSW)
N41327626: TPI8.1 UI2.29(CSCL)
N41327646: TPI9.1 UI2.28(CSDA)
N41360860: JW1.58(A4WP_I2C_DATA) RW73.2
N41360887: JW1.68(CLKREQ1_N) RW74.2
N41385128: RT88.3 RT89.1
N41385208: RT88.4 RT90.1
N41494285: RT81.2 UT4.3(ISET)
N41496626: PQ112.3 PR185.1
N41496656: PC151.1 PQ110.1(S1) PQ110.2(S2) PQ110.3(S3) PQ111.1(S1) PQ111.2(S2) PQ111.3(S3) PR141.2
N41496684: PC151.2 PC180.2 PQ110.4(G1) PQ111.4(G1) PR141.1 PR185.2
N41496697: PC182.1 PQ112.2 PR187.2 PR188.2
N41496710: PC153.1 PQ112.1 PR168.2 PR186.1
N41922986: CA82.1 QA1.5(G1) RA246.2
N41923012: QA1.2(G1) QA1.3(D1) RA247.2
N41976979: PC916.1 PD907.2 PR910.2 PR916.2
N41981897: PD906.1(ANODE) PR918.2 PR919.2
N41989686: CU168.1 QU4.1 QU5.1 QU6.1 RU224.1 RU232.2
N42059320: PC411.1 PSH404.2(B[0]) PU402.4(VIN)
N42059324: PC412.2 PR412.2 PSH402.1(A[0])
N42101806: JW1.64(REFCLK0) TPW3.1
N42165106: PR930.2(B[0]) PU910.B2(EN)
N42348537: PSH708.2(B[0]) PU701.5(VDD2SNS)
N42351508: PR703.1(A[0]) PR707.1(A[0]) PR708.2 PR709.2 PR712.1
N42409129: PSH903.1(A[0]) PU904.4(VOUT)
N42672218: QU7.2(S) RU224.2
N42735417: DA2.1(ANODE) RA248.2
N399470060: TPV8.1 UV2.Y6(IFP_IOVDD_2)
N399470061: TPV7.1 UV2.W6(IFP_IOVDD_1)
N399470062: TPV6.1 UV2.W7(IFPAB_PLLVDD)

Pads without a net: J1 1 2; JDB1 5; JE4 2 3; JI1 14; JKBL1 3; JKBL3 5; JSSD1 6 8 10 20 22 24 26 28 30 32 34 36 40 42 44 46 48 56 58 67 68; JW1 6 60 62 66 70; JX1 5 6; LEDE2 2; NOREF#3 1; NOREF#5 1; NOREF#7 1; NOREF#8 1; NOREF#9 1; NOREF#10 1; PU901 3; PU903 3; PU904 3; PU906 3; PU1101 10 16; RD11 3 4; RD12 3 4; UA2 6 7 10 11 16 17 18 20 21 52 53 54 56 57; UD1 A1 A2 A11 A12 AA1 AA12 AB1 AB2 AB11 AB12 B1 B12 G11 K5 K8 N5 N8; UD2 A1 A2 A11 A12 AA1 AA12 AB1 AB2 AB11 AB12 B1 B12 G11 K5 K8 N5 N8; UD3 A1 A2 A11 A12 AA1 AA12 AB1 AB2 AB11 AB12 B1 B12 G11 K5 K8 N5 N8; UD4 A1 A2 A11 A12 AA1 AA12 AB1 AB2 AB11 AB12 B1 B12 G11 K5 K8 N5 N8; UF15 2 3 5 7 9 10 11 12 14 15 25 26 27 28 31 32; UI2 10 25 26; UT1 23 24 25 26 27 28 34 35 36 37 38 39; UT2 L3; UT7 16 17 19 20; UU1 A4 A5 A7 A9 A12 A14 AD3 AD4 AE11 AF10 AH10 AJ11 AK10 AL3 AL5 AL11 AM10 AN3 AN5 AN7 AN9 AN11 AP10 AR5 AR6 AR10 AT1 AU1 AU2 AV2 B7 B9 B12 B14 BB1 BB2 BB45 BB47 BB48 BC10 BD1 BD2 BD11 BD47 BE10 BE48 BE49 BF5 BF6 BF10 BF11 BF39 BG5 BG6 BG11 BG39 BH10 BJ5 BJ6 BJ11 BJ38 BJ39 BJ46 BL1 BL2 BL10 BL45 BL49 BM1 BM2 BM36 BP5 BP6 BP36 BP41 BR1 BR2 BT1 BT2 BT5 BT6 BT36 BV5 BV6 BW11 C2 C7 C8 C9 C12 C33 CA11 CD3 CE47 CF3 CF5 CF45 CF47 CF49 CG32 CH33 CH48 CJ6 CJ7 CJ32 CJ39 CK6 CK7 CK33 CL1 CL2 CL3 CL5 CL32 CL41 CL43 CN32 CN41 CN42 CP3 CP5 CP6 CP7 CR42 CT32 CT38 CV32 CV37 CV41 CV43 CW1 CW2 CW3 CW5 CW33 CY32 CY35 CY37 CY38 CY39 D1 D2 D7 D8 D9 D12 D14 D33 DA1 DA2 DA11 DA45 DA48 DA49 DB37 DB39 DC7 DC9 DC45 DD38 DE7 DE9 DF1 DF2 DF3 DF5 DF37 DF41 DG7 DG9 DG38 DG40 DH49 DJ3 DJ5 DJ11 DJ13 DJ22 DJ29 DJ34 DJ40 DK11 DK13 DK15 DK21 DK29 DK31 DK34 DK36 DK38 DK40 DL8 DL36 DN6 DN17 DN27 DN33 DN34 DN38 DP1 DP2 DP5 DP6 DP21 DP29 DP33 DP34 DP38 DP40 DR5 DT14 DT28 DT34 DT38 DT40 DT41 DU11 DU12 DU14 DU22 DU24 DU33 DU34 DU38 DU41 DU42 DV4 DV6 DV14 DV22 DV28 DV33 DV38 DV41 DV47 DW4 DW6 DW12 DW24 DW28 DW33 DW36 DW38 DW40 DW41 DW42 DW47 E16 F6 F10 F13 F15 G6 G8 G10 G11 G13 G15 G34 H5 H34 J3 J8 J11 J34 K6 K10 K13 L6 L8 L10 L11 L13 M8 M11 M13 M34 M48 N34 N46 N47 P10 P38 P39 P42 R1 R48 T42 U47 V38 V43 Y11 Y45 Y49; UU2 1; UV2 A3 A7 A16 A22 AA1 AA2 AA3 AA4 AA5 AA6 AA14 AA15 AB1 AB2 AB3 AB4 AB5 AB6 AB8 AB13 AB15 AB16 AB18 AB19 AB21 AB27 AC3 AC4 AC13 AC14 AC15 AC16 AC17 AC18 AC19 AC20 AC21 AD1 AD2 AD3 AD4 AD5 AD7 AD10 AD14 AD17 AD20 AD23 AE1 AE3 AE4 AE10 AE12 AE13 AE15 AE16 AE18 AE19 AE21 AE22 AE23 AE24 AF2 AF3 AF4 AF10 AF12 AF13 AF15 AF16 AF18 AF19 AF21 AF22 AF24 AG3 AG12 AG13 AG15 AG16 AG18 AG19 AG21 AG22 AG24 AG25 B3 B4 B6 B19 C2 C3 C4 C7 C14 D4 D10 E6 E7 E9 E10 E12 F5 F6 F7 F10 F12 F19 P25 T27 W5 W22 Y3 Y4; UV3 A5 A10 U5 U10; UV4 A5 A10 U5 U10

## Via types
v1: diameter 0.457, hole 0.203, TOP to BOTTOM, 2280 vias
v2: diameter 0.406, hole 0.203, TOP to BOTTOM, 1592 vias
v3: diameter 0.457, hole 0.229, TOP to BOTTOM, 637 vias
v4: diameter 0.508, hole 0.254, TOP to BOTTOM, 1394 vias

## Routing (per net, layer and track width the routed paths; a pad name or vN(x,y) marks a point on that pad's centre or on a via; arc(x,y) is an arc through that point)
1.0VGS_EN_N: length 3.3
  BOTTOM w0.102: QV17.1 166.09,89.16 RV85.1 165.18,89.37 QV19.3 165.15,89.73 165.15,90.6 v3(165.4,90.85)
1.35VGS_BOOT: length 4.1
  BOTTOM w0.102: PC1101.1 v3(181.35,39.14)
  BOTTOM w0.254: PU1101.1 178.05,38.37 178.81,39.14 PC1101.1
1.35VGS_BYP: length 2.4
  BOTTOM w0.254: PU1101.15 174.45,38.37 174.01,38.81 PC1108.1 173.23,39.06 173.24,39.08 PR1104.1
1.35VGS_EN: length 2.8
  BOTTOM w0.254: PR1101.2 172.81,35.43 PC1107.1 173.68,35.43 173.99,35.74 173.99,36.12 174.44,36.57 PU1101.11
1.35VGS_FB: length 2.8
  BOTTOM w0.254: PR1109.2 172.58,38.22 PC1150.1 173.07,37.69 PR1108.2 173.1,37.72 173.86,37.72 174.06,37.92 PU1101.14
1.35VGS_ILMT: length 2.3
  BOTTOM w0.254: PR1102.1 PR1103.2 173.85,37.12 174.19,37.47 PU1101.13
1.35VGS_IN: length 0.7
  TOP w0.102: 178.05,37.51 v3(177.39,37.51)
  vias: v4(178.51,37.82) v4(178.51,37.16) v4(179.17,37.82) v4(179.17,37.16) v4(179.78,37.82)
1.35VGS_MODE: length 3
  BOTTOM w0.254: PR1107.1 172.09,36.07 PR1111.2 173.36,36.07 174.31,37.02 PU1101.12
1.35VGS_PG: length 63
  ART06 w0.102: v1(167,48.71) 170.18,48.71 172.21,46.68 172.21,41.86 169.92,39.57 169.92,37.92 170.43,37.41 173.1,37.41 175.32,35.19 v1(175.32,35.15)
  BOTTOM w0.102: v1(167,48.71) 167,51.51 165.23,53.29 v3(156.74,53.29) 155.7,53.29 153.77,51.36 150.9,51.36 149.93,50.39 147.88,50.39 146.58,49.1 143.89,49.1 142.11,50.87 142.11,51.15 141.6,51.66 141.6,51.89 141.27,52.22 140.16,52.22 139.39,51.46 139.39,50.82 138.81,50.24 137.79,50.24 137.46,50.57 CV199.1 136.47,50.82 DV11.1 ; PU1101.9 175.72,35.54 v1(175.32,35.15) 175.05,34.87 PR1105.1
1.35VGS_PHASE: length 6.1
  ART06 w0.508: v1(177.8,35.89) 177.8,36.14 177.82,36.16 177.82,39.12 v1(177.19,39.75)
  BOTTOM w0.254: v1(177.8,35.89) 177.67,36.02 PU1101.6
  BOTTOM w0.279: 180.19,41.22 v3(181.35,41.22)
1.35VGS_VCC: length 3.7
  BOTTOM w0.254: PC1102.1 173.26,40.38 173.94,39.7 175.41,39.7 175.72,39.39 PU1101.17
1V8_3V3_MAINEN: length 16.2
  TOP w0.102: v1(146.05,57.48) 147.19,58.62 147.19,60.02 147.06,60.14 147.06,61.29 146.74,61.61 146.74,61.93 v3(147.32,62.51) 147.84,63.03 RV25.1 147.26,63.5 v2(147.16,63.4)
  ART06 w0.102: v1(141,53.51) 141.95,53.51 143.13,54.68 143.13,55.19 143.89,55.95 144.52,55.95 v1(146.05,57.48)
  BOTTOM w0.102: v1(141,53.51) 140.92,53.43 QV6.2 ; UV2.F9 v2(147.16,63.4)
1V8MAINEN_33: length 48.1
  TOP w0.254: v1(133.65,76.58) 133.65,77.25 DV5.1 ; DV3.1 133.37,83.75 PR1.2 133.37,82.55 v1(133.75,82.17)
  TOP w0.279: DV8.1 130.23,75.59 130.56,75.26 v3(130.86,75.26) 131.75,75.26 132.18,75.69 132.18,76.63 132.84,77.29 DV5.1 ; v3(134.75,82.6) 134.31,82.17 v1(133.75,82.17)
  ART06 w0.254: v1(133.75,82.17) 132.84,81.25 132.84,79.58 133.65,78.76 v1(133.65,76.58)
  ART06 w0.279: v1(133.65,76.58) 133.65,76.45 132.33,75.13 132.33,70.43 131.95,70.05 131.95,69.42 132.33,69.03 132.33,64.72 133.6,63.45 133.6,62.56 137.92,58.24 141.12,58.24 142.14,57.22 142.14,54.48 141.76,54.1 v1(140.99,54.1)
  BOTTOM w0.254: QV6.3 141.57,53.67 RV45.1 141.47,53.73 141.1,54.1 v1(140.99,54.1)
5V_VCC: length 1.7
  BOTTOM w0.254: PC214.1 48.87,44.7 48.51,45.06 48.51,45.41 48.43,45.49 PU201.9
+1.0VGS: length 7.2
  TOP w0.279: v1(157.73,75.82) 157.42,75.51 CV15.2 156.54,75.51 CV3.1
  BOTTOM w0.33: v1(160.37,78.38) 160.37,78.35 160.04,78.01 UV2.AC24
  BOTTOM w0.381: UV2.AE26 UV2.AD25 160.4,78.38 v1(160.37,78.38) ; UV2.AC24 159.67,77.6 v1(159.61,77.6) 159.61,77.49 UV2.AB23 158.44,76.31 UV2.AA22 157.9,75.82 v1(157.73,75.82)
  vias: v1(163.01,80.11) v1(163.7,80.66) v3(163.78,89.79) v4(136.5,92.94) v4(136.8,93.55) v4(137.11,92.99) v4(144.52,92.07) v4(144.57,91.31) v4(163.45,84.91) v4(163.45,83.91) v4(163.45,82.91)
+1.0VGS_EN: length 96.4
  TOP w0.102: RV23.1 129.51,81.28 RV22.2 128.99,81.52 128.78,81.73 127.79,81.73 127.35,81.3 126.69,81.3 v3(126.44,81.05) 126.44,79.83 126.82,79.45 128.4,79.45 128.6,79.25 CV34.1 ; DV8.3 128.6,77.84 CV34.1 ; CV34.1 129.08,79.01 v1(129.13,78.97)
  ART05 w0.102: v1(163.09,87.83) 161.64,86.38 161.64,85.52 160.17,84.05 149.3,84.05 148.33,85.01 136.57,85.01 134.75,83.18 134.75,81.02 133.75,80.03 130.53,80.03 129.46,78.97 v1(129.13,78.97)
  ART06 w0.102: v1(129.13,78.97) 129.13,78.03 127.63,76.53 127.63,65.1 129.54,63.19 129.54,59.64 v1(131.44,57.73)
  BOTTOM w0.102: PR1203.1 130.29,95.17 127.99,95.17 v3(127.54,94.73) 126.92,94.1 126.92,82.95 127.38,82.5 127.38,79.96 128.37,78.97 v1(129.13,78.97) ; v1(163.09,87.83) 162.93,87.99 QV19.1 ; DV14.2 130.88,57.83 130.98,57.73 v1(131.44,57.73)
+1.35VGS: length 107.2
  TOP w0.229: v1(157.06,72.04) 157.06,72.57 v1(157.43,72.94) ; v1(157.12,64.27) 157.76,63.63 RV94.2 157.76,62.98 RV66.2
  TOP w0.279: v1(183.79,63.85) 183.65,63.99 CV143.2 ; v1(186.21,82.84) 186.06,82.99 CV178.1 ; CV56.2 157.25,68.54 CV57.1 ; CV56.2 157.18,69 v1(156.93,69.26) 156.92,69.27 CV52.1 157.08,70.12 v1(157.08,70.91) 157.1,70.93 CV64.2 157.1,72.01 v1(157.06,72.04) ; CV56.2 157.7,68.61 v1(157.94,68.37) ; v1(187.01,70.67) 187.16,70.82 CV130.2 ; v1(175.81,90.04) 175.57,90.28 CV165.2 ; CV148.2 186.39,85.86 v1(186.21,86.04) ; v1(175.01,59.41) 174.88,59.55 CV170.1 ; v1(185.41,79.64) 185.61,79.45 CV163.2 ; CV162.2 184.86,78.53 v1(184.61,78.77) ; v1(175.01,78.84) 174.83,78.66 CV161.2 175.04,77.99 CV157.1 ; RV91.2 182.7,79.33 v1(183.01,79.64) ; CV127.2 176.41,70.88 v1(176.61,70.67) ; CV151.2 v1(183.01,86.84) ; CV122.1 175.13,70.79 v1(175.01,70.67) ; v1(176.61,89.24) 177.1,89.73 CV150.2 ; CV123.1 178.24,70.7 v1(178.22,70.67) ; CV54.2 156.84,74.62 v1(157.23,75.02) ; v1(179.01,78.84) 179.82,78.03 RV141.1 ; CV126.2 185.63,63.69 v1(185.41,63.48) ; CV131.2 185.28,70.81 v1(185.41,70.67) ; v1(183.01,81.24) 182.99,81.22 CV153.2 ; CV129.2 183.68,66.54 v1(183.81,66.68) ; CV159.1 177.36,77.4 CV146.1 176.65,77.97 CV176.2 176.42,78.65 v1(176.61,78.84) ; RV90.2 182.66,68.63 v1(182.21,69.07) ; CV152.2 182.33,78.16 v1(183.01,78.84) ; v1(176.61,60.27) 176.67,60.21 CV171.1 ; v1(157.22,74.2) 157.05,74.03 CV53.2 157.05,73.32 v1(157.43,72.94) ; CV125.2 186.33,66.56 v1(186.22,66.67) ; CV58.1 RV95.2 157.79,66.82 CV59.1 157.69,67.33 v1(157.99,67.63) ; v1(151.39,64.26) 151.46,64.33 CV63.2 152.06,64.9 v1(152.16,65) ; RV101.2 v1(181.39,57.44)
  BOTTOM w0.127: UV2.E26 161.79,62.91 163.19,62.91 v1(163.29,62.8)
  BOTTOM w0.165: UV3.C5 v1(175.81,67.47)
  BOTTOM w0.254: UV4.L11 UV4.K12 ; UV2.H24 159.87,65.72 v1(159.64,65.95) ; v1(151.39,64.26) 151.74,63.92 UV2.F14 ; UV4.L4 v1(179.81,81.24) ; UV3.G4 179.42,67.88 v1(179.81,68.27) ; v1(185.42,69.08) 185.01,68.68 UV3.P3 ; UV3.M12 v1(182.99,61.9) UV3.L11 ; UV2.L26 161.64,68.01 v1(161.24,67.61) ; UV3.G11 UV3.H12 ; UV2.E23 v1(159.61,62.64)
  BOTTOM w0.279: UV4.B14 v1(187.01,90.04) ; UV4.G14 v1(182.21,90.04) ; UV4.T12 v1(175.01,88.44) ; UV4.N10 v1(177.41,86.84) ; UV4.F14 v1(183.81,90.04) ; UV4.M14 v1(179.01,90.04) UV4.L14 ; UV4.K12 v1(179.81,88.44) ; UV4.D14 v1(185.41,89.24) ; UV4.G11 v1(183.01,86.84) ; UV4.C10 v1(186.21,86.04) ; UV4.F12 v1(183.81,88.44) ; v1(176.61,81.24) 177,80.84 UV4.P3 ; UV4.H12 v1(182.21,88.44) ; UV4.T1 v1(175.01,78.84) ; UV4.T14 v1(175.81,90.04) ; v1(183.01,78.84) UV4.G1 ; UV4.E10 v1(184.61,86.04) ; UV4.P14 v1(176.61,89.24) ; UV4.L13 v1(179.01,89.24) ; UV4.R10 v1(175.81,86.84) ; UV4.M12 v1(179.01,88.44) ; UV4.G13 v1(183.01,88.44)
  BOTTOM w0.292: UV4.B12 v1(187.01,87.64) ; UV3.G14 v1(179.01,60.27) 178.62,59.88 UV3.F14 ; UV3.D1 v1(176.61,70.67) ; UV3.T3 v1(186.22,68.28) ; UV3.E10 177.81,63.07 v1(177.41,62.67) 177.02,62.28 UV3.D11 ; UV3.D3 v1(176.61,69.07) ; UV3.B1 v1(175.01,70.67) ; UV3.F3 v1(178.21,69.07) ; v1(186.21,59.47) 186.61,59.87 UV3.T14 ; v1(176.61,60.27) UV3.D14 ; UV3.R5 v1(186.22,66.67) ; v1(183.01,59.47) 183.41,59.87 UV3.M14 ; UV3.B3 v1(175.01,69.07) ; UV3.B12 v1(175.01,61.87) ; v1(185.41,87.64) UV4.D12 ; UV3.D12 v1(176.61,61.87) ; UV3.P11 v1(184.62,62.66) ; v1(178.2,67.47) UV3.E5 ; v1(183.81,66.68) UV3.N5 ; v1(184.61,63.48) UV3.N10 ; UV3.L4 v1(182.99,67.49) ; UV4.D11 v1(185.41,86.84)
  BOTTOM w0.305: v1(178.21,78.84) 178.61,79.24 UV4.M1 ; v1(183.01,79.64) UV4.G2 ; UV3.G2 v1(179.04,69.85) ; UV4.L2 179.41,80.04 v1(179.01,79.64) ; UV4.L1 179.41,79.24 v1(179.01,78.84) ; UV4.P12 v1(176.61,87.64) UV4.P11 ; UV4.T3 175.02,81.24 v1(175.01,81.24) ; UV4.B3 v1(187.01,80.44) ; v1(159.64,67.61) 160.04,68.01 UV2.L24 ; UV4.R5 176.65,82.88 177.37,82.88 UV4.N5 178.22,82.03 v1(178.22,82.03) ; v1(185.41,81.24) 185.01,80.84 UV4.D3 ; v1(183.81,82.84) UV4.E5 ; UV4.C5 185.81,82.44 v1(186.21,82.84) ; UV3.K12 181.81,61.45 v1(182.19,61.07) 182.58,60.68 UV3.L13 ; UV3.P1 185.02,70.28 v1(185.41,70.67) ; v1(183.01,80.44) 183.41,80.84 ; v1(176.61,78.84) 177.01,79.24 UV4.P1 ; UV3.G1 v1(179.03,70.66) ; UV3.C10 v1(176.61,62.67) ; v1(181.41,81.24) UV4.H3 ; UV3.F1 v1(178.22,70.67) ; v1(183.01,81.24) UV4.G4 ; UV4.M3 v1(179.01,80.44)
  BOTTOM w0.315: 183.41,80.84 UV4.F3
  BOTTOM w0.33: v1(187.01,70.67) 186.62,70.28 UV3.T1 ; UV3.L14 v1(183.01,59.47) ; v1(180.61,69.07) 180.61,69.07 UV3.H3 ; v1(183.81,70.67) 183.42,70.28 UV3.M1 ; UV3.K3 181.82,68.68 v1(182.21,69.07) 182.61,69.47 UV3.L2 ; UV3.P12 v1(185.41,61.88) ; UV3.R10 185.81,63.08 v1(185.41,63.48) ; UV4.K3 v1(180.61,80.44) ; UV3.F12 v1(179.04,61.05) UV3.G13 179.42,60.68 v1(179.81,61.07) 180.21,61.47 UV3.H12 ; UV3.P14 185.01,59.87 v1(184.61,59.47) ; UV3.L1 v1(182.21,70.67) ; UV3.M3 183.42,68.68 v1(183.81,69.07)
  BOTTOM w0.356: 161.25,61 v1(161.25,61.01) ; 161.25,61 UV2.C25 ; 161.25,61 UV2.B26 ; UV2.G21 157.54,64.69 v1(157.12,64.27) 156.7,64.69 UV2.G20 ; UV2.H26 161.64,65.55 162.25,65.55 v1(162.7,65.56)
  vias: v1(154.53,64.41) v1(155.47,64.3) v1(156.67,65.25) v1(172.97,55.8) v1(172.97,55.24) v1(172.97,54.68) v1(173.86,55.83) v1(173.86,55.22) v1(173.86,54.63) v1(175.69,54.33) v1(176.69,54.33) v1(177.69,54.33) v1(178.01,58.28) v1(178.69,54.33) v1(183.98,85.5) v1(184.8,84.93) v1(185.76,84.42) v1(186.58,58.39) v1(187.01,61.07) v1(187.47,64.67) v1(188.36,58.34) v3(173.48,53.31)
+1.35VGS_OUT: length 16.6
  ART06 w0.279: v4(175.77,50.01) 174.65,50.01 172.97,48.33 172.97,41.98 170.43,39.44 170.43,38.3 v1(170.94,37.79)
  BOTTOM w0.254: PR1150.2 172.05,38.22 PR1109.1
  BOTTOM w0.279: PR1150.2 171.37,38.22 v1(170.94,37.79)
  vias: v3(176.93,47.83) v4(174.8,48.44) v4(174.8,47.47) v4(175.23,51.05) v4(175.77,49.1) v4(176.2,51.05) v4(176.93,50.01) v4(176.93,49.1) v4(177.16,51.05) v4(178.1,50.06) v4(178.1,49.1) v4(178.18,51.05)
+AVCC: length 10.8
  TOP w0.203: UE1.E9 164.47,18.23 v2(164.04,17.8)
  TOP w0.279: v4(169.62,17.04) 169.62,17.35 170,17.73 CE37.1 CE36.1 170.18,16.47 RE33.2 170.17,15.64 FBE2.2
  BOTTOM w0.254: v4(169.62,17.04) 169.37,17.04 168.4,16.08 167.79,16.08 165.75,18.12 164.33,18.12 164.04,17.83 v2(164.04,17.8)
+V1P0S_VCCST: length 12.1
  BOTTOM w0.203: UU1.CB1 82.08,41.69 82.29,41.48
  BOTTOM w0.254: RU182.2 v2(110.23,36.01) ; CU40.1 v2(112.9,37.54) RU21.2 RU24.1 ; SHU1.2 109.86,34.55 109.32,34.01 108.75,34.01 QU7.3 ; RU183.2 111.89,35.91 v1(111.61,35.63) 111.38,35.86 RU184.2 ; 82.29,41.48 83.04,40.73 83.04,39.61 v3(83.41,39.24) 83.72,38.94 CU97.1 CU98.1 83.72,36.78 v2(83.84,36.65)
  BOTTOM w0.279: v2(80.14,36.65) RU162.1
  vias: v2(109.73,36.01)
+V1P1U_VDDQ: length 196.7
  TOP w0.254: 66.93,93.93 RD4.2 ; PSH708.1 45.31,76.12 47.24,74.19 50.75,74.19 51.56,75 v1(51.56,75.11)
  TOP w0.279: v1(120.42,89.56) 120.21,89.35 CD81.2 ; v1(102.76,83.06) 102.87,82.95 CD28.2 ; v1(70.66,83.71) 70.48,83.53 CD21.2 ; CD24.2 67.56,90.28 v1(67.49,90.21) ; v1(85.14,88.26) 85.06,88.34 CD66.2 83.59,88.34 v1(83.51,88.26) ; v1(70.66,88.91) 70.48,89.08 CD18.2 ; CD6.1 79.43,84.91 v1(79.52,85.01) ; v1(89.11,87.61) 89.46,87.96 CD73.2 ; v1(88.31,88.91) 88.14,89.08 CD71.2 ; v1(79.54,87.61) 79.44,87.7 CD69.2 ; v1(67.46,83.06) 67.46,82.6 CD23.2 ; CD79.2 120.52,82.95 v1(120.42,83.06) ; v1(118.82,84.36) 118.92,84.46 CD83.1 120.32,84.46 v1(120.42,84.36) ; CD2.1 61.73,84.91 v1(61.83,85.01) ; 100.71,79.07 100.33,79.07 v1(100.07,78.81) ; v1(85.11,84.36) 85.01,84.46 CD74.1 83.61,84.46 v1(83.51,84.36) ; CD22.2 61.79,87.7 v1(61.89,87.61) ; v1(97.19,83.71) 97.28,83.62 CD34.2 ; v1(117.22,79.16) 117.25,79.19 CD76.2 ; v1(102.79,88.26) 102.69,88.16 CD36.1 101.27,88.16 v1(101.17,88.26) ; v1(67.46,84.36) 67.36,84.46 CD26.1 65.96,84.46 v1(65.86,84.36) ; v1(71.46,85.01) 71.94,84.53 CD20.2 ; v1(102.76,84.36) 102.66,84.46 CD37.1 101.27,84.46 v1(101.16,84.36) ; v1(82.71,79.16) 82.8,79.07 CD68.2 ; v1(97.19,87.61) 97.1,87.7 CD32.2 ; CD77.2 114.76,84.27 v1(114.85,84.36) ; v1(101.16,89.56) 101.47,89.86 CD33.2 ; v1(106.77,87.61) 106.55,87.82 CD35.2 ; CD29.2 107.12,84.66 v1(106.77,85.01) ; v1(85.14,90.21) 85.22,90.28 CD72.2 ; v1(105.96,83.71) 105.79,83.53 CD31.2 ; v1(71.46,87.61) 71.81,87.96 CD25.2 ; CD70.2 88.14,83.53 v1(88.31,83.71) ; v1(67.49,88.26) 67.48,88.27 CD27.1 65.87,88.27 v1(65.86,88.26) ; v1(118.82,88.26) 118.86,88.21 CD80.2 120.4,88.21 v1(120.45,88.26) ; v1(97.19,85.01) 97.1,84.91 CD10.1 ; CD75.2 114.32,84.91 v1(114.68,85.27) ; v1(123.62,88.91) 123.64,88.91 124.2,88.35 CD78.2 124.2,87.82 v1(124.42,87.61) ; CD82.2 124.2,84.79 v1(124.42,85.01) ; CD14.1 114.75,87.7 v1(114.85,87.61) ; v1(69.06,78.51) 69.11,78.56 CD19.2
  TOP w0.381: v4(47.8,78.25) 47.45,78.6 PC715.1
  GND02 w0.254: v1(51.56,75.11) 52.17,75.71 59.08,75.71 59.69,76.32 64.16,76.32 64.82,75.66 98.3,75.66 100.07,77.44 v1(100.07,78.81)
  BOTTOM w0.229: UD4.H8 v1(118.82,88.26) ; UD4.N3 122.8,85.7 123.67,85.7 UD4.N1 v1(124.42,85.01) ; UD3.H8 v1(101.16,88.26) ; UD4.H5 v1(120.45,88.26) ; v1(86.1,93.72) 86.23,93.6 86.23,93.23 UD2.A4 ; UD3.F5 v1(102.76,89.56) ; v1(79.52,85.01) 79.54,85.01 UD2.N12 80.29,85.7 81.16,85.7 UD2.N10 ; UD2.R8 v1(83.51,84.36) ; UD2.H5 v1(85.14,88.26) ; UD4.A9 117.73,93.23 117.73,93.6 v1(117.85,93.72) ; UD1.AB4 68.58,79.39 68.58,78.99 v1(69.06,78.51) ; UD3.K10 98.79,86.89 97.97,86.89 UD3.K12 v1(97.19,87.61) ; UD4.AB4 121.54,79.39 121.54,78.94 v1(121.41,78.81) ; UD2.F8 v1(83.51,89.56) ; UD1.U8 v1(65.86,83.06) ; UD3.R1 v1(105.96,83.71) UD3.T2 ; UD3.K3 105.14,86.92 106.01,86.92 UD3.K1 v1(106.76,87.61) ; UD2.R12 v1(79.54,83.71) ; UD4.A4 v1(122.02,93.58) ; v1(97.19,85.01) UD3.N12 97.94,85.7 98.81,85.7 UD3.N10 ; v1(114.68,85.27) 114.7,85.27 114.77,85.33 UD4.N12 115.59,85.69 116.48,85.69 UD4.N10 ; UD2.H8 v1(83.51,88.26) ; v1(100.07,78.81) 100.07,79.39 UD3.AB9 ; UD1.R12 v1(61.89,83.71) ; UD2.AB9 v1(82.71,79.16) ; UD1.F5 v1(67.49,90.21) ; UD2.AB4 v1(86.33,78.69) ; v1(79.54,87.61) UD2.K12 80.32,86.89 81.14,86.89 UD2.K10 ; UD1.H12 v1(61.89,88.91) ; UD4.R5 v1(120.42,84.36) ; v1(114.85,87.61) UD4.K12 115.59,86.93 116.48,86.93 UD4.K10 ; UD1.T2 v1(70.66,83.71) UD1.R1 ; UD4.T2 v1(123.62,83.71) UD4.R1 ; UD2.K3 87.49,86.92 88.36,86.92 UD2.K1 v1(89.11,87.61) ; UD1.AB9 v1(65.06,79.16) ; UD3.A4 v1(103.56,93.58) ; v1(89.14,85.01) 89.13,85.01 89.11,85.01 UD2.N1 88.4,85.66 87.45,85.66 UD2.N3 ; UD4.F8 v1(118.02,90.21) ; UD1.A4 68.58,93.23 68.58,93.6 v1(68.45,93.72) ; UD3.U8 v1(101.19,83.06) ; UD2.F5 v1(85.14,90.21) ; UD1.H5 v1(67.49,88.26) ; UD1.R5 v1(67.46,84.36) ; UD1.G2 v1(70.66,88.91) UD1.H1 ; UD3.A9 v1(100.36,93.46) ; UD1.U5 v1(67.46,83.06) ; UD4.H1 v1(123.62,88.91) UD4.G2 ; v1(61.89,87.61) UD1.K12 62.66,86.89 63.48,86.89 UD1.K10 ; UD3.R12 v1(97.19,83.71) ; UD2.R1 v1(88.31,83.71) UD2.T2 ; UD1.N3 69.84,85.7 70.71,85.7 UD1.N1 v1(71.46,85.01) ; UD2.H12 v1(79.54,88.91) ; UD2.R5 v1(85.11,84.36) ; UD1.K3 69.84,86.92 70.71,86.92 UD1.K1 v1(71.46,87.61) ; UD4.R12 v1(114.85,84.36) ; v1(65.06,93.46) UD1.A9 ; UD2.U8 v1(83.51,83.06) ; UD4.H12 v1(114.85,88.91) ; UD3.N3 105.14,85.7 106.01,85.7 UD3.N1 v1(106.76,85.01) ; UD1.N10 63.51,85.7 62.64,85.7 UD1.N12 61.89,85.01 61.86,85.01 v1(61.83,85.01) ; UD4.K3 122.8,86.92 123.67,86.92 UD4.K1 v1(124.42,87.61) ; UD3.H12 v1(97.19,88.91) ; UD4.AB9 v1(117.22,79.16) ; UD1.F8 v1(65.86,89.56) ; UD2.G2 v1(88.31,88.91) UD2.H1 ; v1(102.76,83.06) UD3.U5 ; UD1.H8 v1(65.86,88.26) ; UD4.R8 v1(118.82,84.36) ; UD4.F5 v1(120.42,89.56) ; UD4.U5 v1(120.42,83.06) ; UD3.G2 v1(105.96,88.91) UD3.H1 ; UD3.F8 v1(101.16,89.56) ; UD2.U5 v1(85.11,83.06) ; UD2.A9 v1(82.71,93.46) ; v1(104.36,78.51) 103.91,78.96 103.91,79.41 UD3.AB4 ; UD3.H5 v1(102.79,88.26) ; UD3.R8 v1(101.16,84.36) ; UD3.R5 v1(102.76,84.36) ; UD4.U8 v1(118.82,83.06) ; UD1.R8 v1(65.86,84.36)
  BOTTOM w0.279: v1(61.83,85.01) 61.09,85.01 ; v1(61.89,83.71) 61.27,83.71 61.11,83.87 ; 61.09,88.9 61.1,88.91 v1(61.89,88.91) ; v1(61.89,87.61) 60.96,87.61
  BOTTOM w0.305: v4(47.8,78.25) 47.7,78.25 47.12,78.83 PU701.1
  BOTTOM w0.381: v1(97.19,88.91) 96.58,88.91 ; v1(97.19,87.61) 96.49,87.61 ; 96.65,84.15 97.09,83.71 v1(97.19,83.71) ; v1(124.42,87.61) 125.12,87.61 ; v1(97.19,85.01) 96.62,85.01 ; v1(103.56,93.58) 103.56,95.77 ; v1(106.77,87.61) 107.54,87.61 ; v1(122.02,93.58) 122.02,95.73 ; v1(100.36,93.46) 100.36,95.67 ; v1(124.42,85.01) 125.19,85.01 ; v1(65.06,93.46) 65.06,95.1 ; v1(82.71,93.46) 82.71,95.02
  vias: v3(41.55,73.63) v3(58.62,93.27) v4(42.47,73.12) v4(43.13,73.12) v4(43.74,73.12) v4(51.84,90.57) v4(51.84,89.84) v4(52.37,91.26) v4(52.58,90.62) v4(52.88,91.74) v4(53.16,91.18) v4(53.85,91.95) v4(54.53,92) v4(76.63,93.29) v4(77.95,93.29) v4(77.95,92.2) v4(94.61,93.42) v4(95.5,93.42) v4(108.94,93.42) v4(109.8,93.37)
+V1P2_HDMI:
  vias: v1(134.14,94.33) v1(134.69,94.33) v3(29.94,57) v4(29.46,59) v4(29.46,58.39)
+V1P2S_HDMI: length 5.4
  TOP w0.203: UI2.15 v2(20.5,54.43) ; UI2.6 v2(24.46,56.79) ; UI2.18 v2(20.5,53.23) ; UI2.43 v2(27.99,53.23) ; UI2.46 v2(27.99,54.43) ; UI2.11 v2(22.46,56.79) ; v2(24.06,49.15) UI2.30
  vias: v3(20.6,56.56)
+V1P05A_BYPASS_R: length 0.5
  BOTTOM w0.279: UU1.DJ15 v2(68.35,48.84)
+V1P8_AON_EN_N: length 6
  BOTTOM w0.127: RV78.1 134.1,87.14 134.82,87.14 136.24,88.57 v3(136.8,88.57)
  BOTTOM w0.279: QV11.1 133.36,85.98 QV14.3 134.61,86.29 134.04,86.86 RV78.1
+V1P8_V3P3_AON: length 75.4
  TOP w0.203: QV5.1 144.46,51.59 CV36.2 144.8,51.51 145.01,51.71 145.01,51.86 RV35.2 RV147.2 145.59,49.91 v1(145.48,49.79)
  TOP w0.254: v1(140.37,51.78) RV112.1 RV116.1
  ART03 w0.279: v1(132.46,52.65) 132.97,52.65 134.62,51 137.16,51 138.68,49.48 139.44,49.48 140.37,50.41 v1(140.37,51.78)
  ART06 w0.279: v4(130.76,88.06) 130.76,87.63 131.44,86.94 131.44,86.05 134.75,82.75 134.75,79.93 v1(135.23,79.45) 136.12,78.56 136.12,71.8 135.25,70.94 135.25,67.64 135.63,67.26 135.63,65.61 137.16,64.08 137.16,61.92 136.52,61.28 v1(136.52,61.16)
  BOTTOM w0.203: RV34.2 143.39,53.92 142.99,53.92 RV38.2 142.8,53.95 142.51,53.95 RV19.2 ; v1(135.23,79.45) 136.18,79.45 RV9.2 ; RV20.2 146.57,49.62 146.37,49.42 145.85,49.42 v1(145.48,49.79) 145.3,49.97 RV17.1
  BOTTOM w0.254: UV1.5 132,53.12 v1(132.46,52.65) 132.33,52.53 CV17.1 ; RV110.1 136.6,61.24 v1(136.52,61.16) 136.03,60.66 136.03,59.76 136.24,59.55 136.24,59.46 ; RV34.2 143.76,53.84 143.84,53.92 v1(144.12,53.92) 144.12,54.4 144.27,54.56 144.27,54.94 144.12,55.09 RV29.2 RV37.2 RV30.1 RV28.1 ; RV28.1 145.79,54.76 RV31.2 ; RV28.1 RV36.1 RV33.1 ; CV204.1 CV112.1 ; CV204.1 v3(151.76,53.76) 151.39,53.76 v1(150.95,54.2) ; CV204.1 152.93,54.18 ; RV118.1 136.27,58.24 135.93,58.58 135.93,59.15 136.24,59.46 ; RV19.2 142.11,54.09 142.11,55.17 RV117.1 ; 136.24,59.46 RV111.1 ; v1(149.12,54.84) 149.63,55.34 RV124.1
  BOTTOM w0.279: v1(150.95,54.2) 150.95,54.51 151.48,55.04 RV123.1 ; 152.93,54.18 152.04,55.06 RV122.1
  BOTTOM w0.305: UV2.G10 v1(148.81,64.26) ; UV2.G12 v1(149.7,64.26)
  vias: v4(130.81,88.77) v4(132.99,92.66) v4(133.6,92.66)
+V1P8_V3P3_MAIN: length 48.4
  TOP w0.279: v1(147.21,75.88) 147.04,75.7 CV29.1 ; CV10.2 150.51,76.78 v1(150.49,76.8)
  TOP w0.381: v4(139.57,63.7) 139.57,59 137.69,57.12 136.95,57.12 136.62,56.79 136.62,56.44 136.14,55.95 135.11,55.95 134.49,56.58 LV1.1
  TOP w0.508: v4(139.57,63.7) 140.3,64.43 RV88.2
  ART06 w0.508: v1(135.38,80.21) 136.65,78.94 136.65,66.62 v4(139.57,63.7)
  BOTTOM w0.254: v1(158.78,77.56) UV2.AC23 UV2.AD24 ; UV2.AE25 v1(161.22,80) UV2.AF26 ; UV2.AA10 148.58,76.37 v1(148.89,76.69)
  BOTTOM w0.279: UV2.AA21 UV2.AA20 155.92,76.31 UV2.AA19 ; v1(158.78,77.56) UV2.AB22 ; UV2.AA8 v1(147.21,75.88) ; UV2.AA18 155.09,76.37 v1(155.47,76.75) ; UV2.AA16 v1(153.99,76.37)
  BOTTOM w0.305: UV2.AA13 v1(150.49,76.8) UV2.AA12 ; UV2.AA19 v1(155.47,76.75) ; v1(147.78,75.85) 147.78,76.21 UV2.AA9 ; RV7.2 v1(137.67,83.31)
  BOTTOM w0.508: RV82.2 134.8,80.79 v1(135.38,80.21)
  vias: v3(149.91,88.36) v4(133.7,88.31) v4(133.7,87.7) v4(134.36,88.31) v4(134.36,87.7) v4(159.51,86.38) v4(159.51,85.77) v4(159.51,85.11) v4(160.17,86.38) v4(160.16,85.76) v4(160.17,85.09)
+V1P8A: length 261.6
  TOP w0.254: RW56.1 RW55.1 150.72,23.09 v1(150.72,23.14)
  TOP w0.279: 58.8,56.08 59.18,56.08 60.07,56.97 RU96.1 61.34,57.18 61.62,57.46 62.12,57.46 62.61,56.97 63.5,56.97 RU94.1 ; v2(188.59,22.86) PC930.1 188.06,23.42 187.95,23.31 PU910.A2 ; PC406.1 v4(45.01,63.47) ; v3(44.24,64.64) v4(44.24,63.47) ; v2(154.58,18.16) 154.9,17.84 RE460.1
  ART03 w0.279: v4(157.1,33.47) 155.52,33.47 154.99,32.94 v4(154.99,31.14)
  PWR04 w0.279: v1(150.72,23.14) 150.72,23.09 151.03,22.78 151.03,20.6 152.91,18.72 153.77,18.72 154.33,18.16 v2(154.58,18.16)
  ART05 w0.279: v2(188.59,22.86) 189.51,23.77 189.51,37.39 186.18,40.71 185.55,40.71 185.29,40.46 181.86,40.46 179.96,38.55 178.31,38.55 177.8,38.05 177.8,37.54 176.66,36.4 173.1,36.4 172.53,35.82 170.88,35.82 169.54,34.49 168.53,34.49 165.48,31.44 158.24,31.44 157.1,32.59 v4(157.1,33.47) 154.61,33.47 153.63,34.45 141.39,34.45 140.76,35.07 140.76,35.74 140.41,36.09 138.94,36.09 135.57,39.46 135.57,41.72 131.82,45.48 130.4,45.48 128.9,46.97 128.9,47.57 126.11,50.37 126.11,77.54 129.61,81.05 129.61,89.56 129.18,89.99 129.18,92.25 128.78,92.66 v4(128.78,92.68) ; v4(46.94,58.14) 47.5,57.58 47.5,45.92 46.94,45.36 46.94,42.06 46.35,41.48 46.35,30.93 45.16,29.74 45.16,28.32 45.51,27.96 51.48,27.96 53.82,25.63 67.84,25.63 69.21,24.25 70.79,24.25 v2(71.25,24.71) 72.52,25.98 72.52,26.77 72.13,27.15 v2(72.13,27.51)
  BOTTOM w0.203: PSH401.2 PC404.1 36.57,59.15 37.11,58.62 44.58,58.62 45.62,59.66 45.62,61.95 PC406.1
  BOTTOM w0.279: v1(150.72,23.14) 150.72,23.29 151.18,23.75 153.62,23.75 155.4,25.52 155.4,28.22 154.58,29.03 154.58,30.73 v4(154.99,31.14) ; RU98.1 56.51,54.81 56.44,54.73 v2(56.39,54.73) 56.34,54.73 55.52,55.55 55.24,55.55 ; RU98.1 RU109.1 RU105.1 ; RU98.1 RU107.1 RU102.1 56.51,56.46 v2(56.39,56.33) 55.37,57.35 55.24,57.35 55.24,59.26 v2(56.39,59.26) ; PR501.1 71.88,25.35 v2(71.25,24.71) ; PR502.1 72.13,27.25 v2(72.13,27.51)
  vias: v4(44.19,62.86) v4(128.01,93.42) v4(128.73,93.42)
+V1P8A_ESPI: length 7.7
  TOP w0.076: v2(161.45,15.87) 161.58,16 162.23,16 UE1.J5
  TOP w0.254: v2(157.99,16.48) 157.88,16.58 157.07,16.58 CE38.1 156.94,16.71 156.18,16.71 155.69,17.21 RE460.2
  BOTTOM w0.203: v2(161.45,15.87) 160.27,15.87 160.02,16.13 159.36,16.13 159.15,15.92 158.65,15.92 158.09,16.48 v2(157.99,16.48)
+V1P8SX: length 62.9
  TOP w0.279: PSH930.2 188.69,26.64 v2(188.69,28.14) 187.53,28.14 +V1P8SX.1 ; v4(175.91,20.85) 175.88,20.83 RA233.2 ; RA236.1 177.95,33.88 178.31,34.24 178.31,34.77
  TOP w0.381: 178.31,34.77 177.82,35.25 177.34,35.25 176.58,36.01 FBA1.1 172.76,36.01 171.9,35.15 v1(171.9,34.63)
  PWR04 w0.254: v1(171.9,34.63) 171.65,34.63 171.24,34.22 171.24,33.5 170.99,33.25 169.11,33.25 168.86,32.99 168.86,32.28 169.85,31.29 169.85,25.32 173.16,22.01 174.74,22.01 v4(175.91,20.85)
  ART05 w0.279: v2(188.69,28.14) 189.1,28.55 189.1,35.63 184.91,39.82 182.12,39.82 180.34,38.05 180.34,37.03 179.96,36.65 177.67,36.65 176.91,35.89 173.16,35.89 v1(171.9,34.63)
+V1P8U: length 56.9
  TOP w0.279: v1(72.08,89.51) 71.73,89.86 CD41.2 ; CD11.1 100.29,89.48 v1(100.36,89.56) ; CD44.2 107.52,82.75 v1(107.64,82.62) ; v1(89.11,89.56) 89.15,89.6 CD84.2 ; v1(103.56,83.06) 103.88,83.38 CD47.2 ; CD15.1 117.85,89.07 v1(118.02,88.91) ; v1(100.36,83.06) 100.06,82.75 CD45.2 ; v1(85.94,88.91) 86.48,88.91 CD88.1 ; v1(65.09,83.71) 64.77,83.39 CD39.2 ; v1(106.76,90.21) 106.55,90.42 CD46.2 ; CD91.2 121.41,83.25 v1(121.22,83.06) ; v1(89.79,82.88) 89.41,82.5 CD87.2 ; v1(68.29,88.91) 68.83,88.91 CD42.1 ; v1(114.22,89.51) 114.05,89.68 CD93.1 ; CD48.1 97.07,90.3 v1(97.16,90.21) ; CD3.1 64.9,89.39 v1(65.06,89.56) ; CD86.2 82.42,83.26 82.74,83.58 v1(82.74,83.71) ; CD7.1 82.55,89.39 v1(82.71,89.56) ; v1(85.91,83.06) 86.23,83.38 CD85.2 ; v1(68.26,83.06) 68.58,83.38 CD38.2 ; v1(103.59,88.91) 103.6,88.9 CD49.1 ; v1(118.05,83.06) 117.85,82.87 CD89.2 ; CD90.2 121.73,88.91 v1(121.25,88.91) ; v1(72.13,82.88) 71.75,82.5 CD40.2 ; v1(113.79,82.62) CD92.2
  TOP w0.508: 61.34,89.56 v1(61.89,89.56)
  TOP w0.635: v4(47.72,87.45) v3(53.13,87.45) 53.39,87.45 56.18,90.24 57.1,90.24 57.5,90.65 59.43,90.65 59.81,90.27 CD43.1 60.57,90.27 61.29,89.56 61.34,89.56
  BOTTOM w0.229: v1(107.64,82.62) 107.54,82.73 UD3.U1 ; v1(125.47,82.62) 125.3,82.8 124.61,82.8 124.54,82.73 UD4.U1 ; UD3.G4 v1(103.59,88.91) ; v1(89.11,89.56) UD2.F1 ; UD2.G9 v1(82.71,89.56) ; UD2.T9 v1(82.74,83.71) ; UD4.T9 v1(118.05,83.06) ; UD1.G9 v1(65.06,89.56) ; v1(96.04,82.73) UD3.U12 ; UD1.U12 v1(61.89,83.06) ; v1(113.79,82.62) 113.99,82.83 114.78,82.83 114.88,82.73 UD4.U12 ; UD3.G9 v1(100.36,89.56) ; UD3.T4 v1(103.56,83.06) ; v1(89.79,82.88) 89.64,82.73 UD2.U1 ; UD1.U1 71.99,82.73 v1(72.13,82.88) ; UD2.F12 v1(79.54,89.56) ; UD1.F12 v1(61.89,89.56) ; UD4.F1 v1(124.42,90.21) ; UD3.F12 v1(97.16,90.21) ; UD1.T4 v1(68.26,83.06) ; UD4.G9 v1(118.02,88.91) ; v1(79.54,83.08) 79.54,83.06 UD2.U12 ; UD1.F1 71.71,89.88 v1(72.08,89.51) ; v1(114.22,89.51) 114.59,89.88 UD4.F12 ; UD1.G4 v1(68.29,88.91) ; UD3.F1 v1(106.76,90.21) ; UD2.G4 v1(85.94,88.91) ; UD2.T4 v1(85.91,83.06) ; UD1.T9 v1(65.09,83.71) ; v1(121.22,83.06) UD4.T4 ; v1(121.25,88.91) UD4.G4 ; UD3.T9 v1(100.36,83.06)
+V1P8VGS_EN: length 16.3
  TOP w0.102: RV11.1 128.55,82.1 128.47,82.01 127.4,82.01 v3(127.1,82.32) ; RV11.1 128.55,82.83 v1(128.69,82.97) 130.36,82.97 131.14,82.19 RV10.1 132.38,82.19 PR1.1 ; RV11.1 CV31.1
  BOTTOM w0.102: PR1202.1 128.41,89.88 127.84,89.31 QV20.1 128.5,83.17 v1(128.69,82.97)
+V1P8VGS_EN_N: length 5.5
  BOTTOM w0.102: QV20.3 128.82,81.09 RV87.1 128.82,80.19 128.95,80.06 129.39,80.06 129.51,80.19 v3(129.94,80.19) 130.27,80.19 130.4,80.06 132.33,80.06 QV18.1
+V3.3DX_RT_TCP1:
  vias: v3(25.14,31.52)
+V3P3_CAM_CONN: length 10.6
  TOP w0.127: v3(26.31,78.46) 25.8,78.97 24.69,78.97 24.48,79.17 24.03,79.17 23.74,79.46 SHX9.2
  TOP w0.279: SHX9.2 23.11,79.7 23.11,79.71 RX900.2 22.5,79.04 22.71,78.84 CX284.1 22.71,78.36 22.72,78.34 RX901.2 22.72,77.29 22.86,77.15 CX887.1 v4(22.25,76.73)
  BOTTOM w0.279: JX1.11 21.2,76.27 21.66,76.73 v4(22.25,76.73)
+V3P3_DISPLAY: length 2.6
  BOTTOM w0.279: RX17.2 27.56,70.56 27.62,70.49 UX1.1 27.25,69.98 26.8,70.43 v4(26.41,70.43)
  vias: v3(26.06,71.04)
+V3P3_DISPLAY_CONN: length 1.8
  BOTTOM w0.102: 22.05,73.63 22.2,73.63 23.01,72.82 v3(23.01,72.31)
  vias: v4(20.7,74.14) v4(21.33,74.14) v4(21.97,74.14)
+V3P3_DVDD_IO: length 21.5
  TOP w0.102: FBA5.2 165.38,31.85 v3(165.35,31.87)
  TOP w0.203: v1(170.05,23.95) 170.05,23.9 170.25,23.7 CA28.1 170.94,23.7 171.47,24.23 UA2.19 ; UA2.55 172.27,32.18 172.07,32.38 v1(171.7,32.38) 171.61,32.48 171.61,32.93 CA65.1 ; v1(168.35,30.17) UA2.3 ; v1(168.3,26.69) 167.94,26.69 CA67.1 167.74,26.08 168.81,26.08 168.89,26.17 UA2.13
  ART06 w0.508: v1(171.7,32.38) 171.7,32.34 170.83,31.47 169.66,31.47 v1(168.35,30.17) 168.3,30.12 v1(168.3,26.69) 168.7,26.69 170.05,25.35 v1(170.05,23.95)
+V3P3_MIC: length 5.1
  TOP w0.127: v3(19.94,75.64) 19.94,75.79 v4(20.34,76.2)
  TOP w0.279: RX907.1 RX906.1 20.56,77.85 CX895.1 20.56,76.79 20.95,76.4 CX21.2 20.83,76.2 v4(20.34,76.2)
  BOTTOM w0.279: JX1.10 20.7,75.84 v4(20.34,76.2)
+V3P3_MIC_DB:
  vias: v3(156.23,90.14)
+V3P3_TOUCH: length 9.8
  BOTTOM w0.279: RE69.1 56.06,12.44 57.5,12.44 57.78,12.16 RE65.1 59.74,12.01 60.81,10.94 63.19,10.94 63.75,10.39
+V3P3_TPM: length 22.7
  TOP w0.254: 139.14,33.75 138.91,33.52 UF15.1
  TOP w0.279: RE457.1 136.9,25.68 136.75,25.52 v1(136.75,25.27) 136.75,25.07 137.03,24.79 138.35,24.79 138.43,24.71 ; RF11.1 139.62,25.3 139.14,24.81 138.53,24.81 138.43,24.71 ; RE447.1 135.23,25.07 135.51,24.79 135.51,23.92 136.19,23.24 137.87,23.24 v3(138.14,23.51) 138.43,23.8 138.43,24.71
  BOTTOM w0.279: v1(136.75,25.27) 136.75,25.58 137.62,26.44 139.85,26.44 140.13,26.72 140.13,29.11 139.88,29.36 139.88,30.71 140.46,31.29 v3(140.46,32.05) v2(140.46,33.2)
+V3P3_TS: length 5.9
  TOP w0.279: RX921.1 28.09,77.7 28.09,78.71 v3(27.94,78.86) 27.54,79.26 26.78,79.26 v4(26.41,79.63)
  BOTTOM w0.279: CX9.2 19.18,74.37 19.2,74.39 JX1.7
  vias: v4(25.78,79.45) v4(32.36,65.78) v4(32.97,65.96)
+V3P3_WLAN: length 11.7
  TOP w0.254: RW58.2 RW59.2 150.21,15.11 149.69,14.59 149.69,14.13 149.48,13.92 ; 152.7,21.05 152.6,20.95 151.23,20.95 151.13,21.05 RW67.2
  BOTTOM w0.305: RW9.2 142.22,17.2 141.86,16.84 141.86,16.2 142.59,15.47 RW69.2 142.9,13.21 RW24.2
  vias: v1(147.95,13.66) v3(144.02,12.06) v4(141.17,11.25) v4(141.78,11.25) v4(142.39,11.25) v4(151.43,12.52) v4(151.99,29.79) v4(152.04,12.62) v4(152.14,12.01) v4(152.63,11.35) v4(152.91,31.14) v4(152.91,30.5)
+V3P3A: length 473.6
  TOP w0.203: RE110.1 v4(165.25,24.61)
  TOP w0.254: 142.92,5.66 143.89,6.63 CP2.1 ; CP2.1 144.65,7.06 144.88,6.83 145.68,6.83 145.93,7.08 JP2.1 ; CP2.1 CP1.1 v2(143.89,8.14) ; RT51.2 19.18,16.99 v2(19.15,16.96)
  TOP w0.279: RE109.1 156.97,11.45 v4(156.92,11.4) ; v4(43.15,8.81) 43.18,8.79 43.2,8.79 43.86,8.13 RU220.2 ; RT6.1 38.73,33.98 v2(38.48,34.24) ; v2(25.12,16.96) 25.27,17.12 RT47.2 ; SHU4.1 63.03,55.38 63.5,55.85 65.43,55.85 66.14,56.56 67.87,56.56 67.92,56.51 68.63,56.51 68.78,56.66 69.29,56.66 SHU5.2 ; RL45.1 157.17,29 v2(157.25,29.08) ; RT95.2 23.82,8.81 24.13,8.51 v4(24.13,7.69) ; v1(146.71,35.58) 146.56,35.58 146.16,35.98 RF8.1 145.53,37.72 143.51,39.75 143.51,46.94 141.48,48.97 141.48,49.86 141.22,50.11 139.29,50.11 v4(139.16,49.98) 138.56,49.98 137.29,51.25 135.25,51.25 v1(134.75,51.76) ; 142.92,5.66 134.26,5.66 133.47,6.46 DO1.2 132.08,6.46 RO1.1 ; RT126.1 50.59,38.05 50.86,38.31 v2(50.91,38.31) ; v2(62.02,9.07) 62.02,8.91 63.78,7.16 v2(64.01,7.16) 67.54,3.63 RE57.1 ; RX906.2 21.72,77.85 21.89,77.67 v4(21.97,77.67) ; RW23.2 141.93,14.7 v4(142.09,14.55) ; v2(20.67,16.96) 20.47,16.96 20.19,17.24 RT46.2 ; RN37.2 20.57,7.64 20.57,8.07 v4(20.45,8.2) ; CE53.1 CE52.1 163.17,26.24 v2(163.32,26.39) ; RU155.2 53.36,75.77 50.54,72.95 v4(50.54,68.04) ; RE58.1 69.47,8.18 69.64,8.35 69.64,9.17 69.34,9.47 66.32,9.47 v2(65.71,8.86) ; UU2.5 126.09,92.26 125.47,91.64 125.47,90.12 CU33.1 125.73,89.23 126.74,88.21 127.56,88.21 128.52,89.18 RU161.2 128.9,89.33 v4(129.03,89.2) ; LEDE2.4 LEDE2.3 181.22,6.54 v4(181.3,6.63) ; RE80.1 v4(168.78,24.71) ; RT49.2 RT54.2 v2(22.22,16.96)
  TOP w0.381: v4(50.7,64.69) 50.54,64.84 v4(50.54,68.04) ; v4(24.33,35.41) 23.62,34.69 v4(23.62,33.6)
  ART03 w0.254: v1(134.75,51.76) 134.62,51.89 134.62,62.3 v4(134.92,62.61)
  ART03 w0.279: v2(65.71,8.86) 63.6,8.86 63.35,8.61 62.38,8.61 62.02,8.96 v2(62.02,9.07) ; v2(22.22,16.96) 23.24,17.98 v4(23.24,19) ; v4(20.45,8.2) 20.7,8.46 23.37,8.46 v4(24.13,7.69)
  ART03 w0.508: v4(175.39,19.68) 175.77,19.3 175.77,18.31 176.58,17.5 182.12,17.5 ; v4(185.52,48.89) 189.29,45.12 189.29,43.63 189.25,43.6 189.25,24.64 182.12,17.5 ; 182.12,17.5 182.68,16.94 182.68,15.95 183.31,15.31 184.78,15.31 185.29,14.81 185.29,12.77 183.64,11.12 183.64,8.96 v4(181.3,6.63) ; v4(50.7,64.69) 41.04,64.69 40.13,65.61 v4(39.98,65.61)
  ART05 w0.254: v4(156.92,11.4) 156.92,11.33 156.54,10.94 154.81,10.94 154.13,11.63 154.13,15.34 v4(154.73,15.95)
  ART05 w0.279: v4(21.97,77.67) 22.6,77.67 24.26,76.02 24.26,72.24 25.91,70.58 25.91,67.49 v4(26.41,66.98) ; v2(143.89,8.14) 143.89,8.96 143.25,9.6 143.25,12.77 142.09,13.94 v4(142.09,14.55) v2(142.09,15.19) ; v2(25.78,19.38) 25.78,17.63 v2(25.12,16.96) 24.51,16.96 23.24,18.23 v4(23.24,19) 23.24,21.03 22.86,21.41 22.86,26.85 23.52,27.51 24.64,27.51 25.65,28.52 25.65,30.81 v4(23.62,32.84)
  ART05 w0.381: v4(23.62,33.6) v4(23.62,32.84)
  ART06 w0.279: v4(129.03,89.2) 129.94,88.29 129.94,86.79 134.26,82.47 134.26,81.94 133.23,80.9 133.23,79.77 134.24,78.76 134.24,76.4 132.84,75 132.84,70.3 133.21,69.93 133.21,69.41 132.97,69.16 132.97,65.86 134.92,63.9 v4(134.92,62.61) ; v2(64.01,7.16) 63.14,6.3 51.05,6.3 48.77,8.58 44.14,8.58 43.91,8.81 v4(43.15,8.81) 42.92,8.58 36.07,8.58 30.78,13.87 27.73,13.87 25.12,16.48 v2(25.12,16.96) ; v2(22.22,16.96) 22.22,16.58 21.59,15.95 21.59,13.66 23.24,12.01 23.62,12.01 24.51,11.12 24.51,10.49 24.13,10.11 v4(24.13,7.69)
  ART06 w0.508: v4(160.91,91.97) 168.98,91.97 170.43,93.42 188.65,93.42 189.84,92.23 189.84,57.88 188.85,56.89 188.85,52.22 v4(185.52,48.89)
  BOTTOM w0.203: RV248.2 135.13,62.4 v4(134.92,62.61) ; RV32.2 134.55,51.57 v1(134.75,51.76)
  BOTTOM w0.254: JDB1.6 184.71,49.7 v4(185.52,48.89)
  BOTTOM w0.279: PU903.5 40.64,66.11 40.56,66.19 PC970.1 v4(39.98,65.61) ; v2(50.93,39.44) 50.67,39.7 RT20.1 ; v2(72.72,27.51) 72.72,27.33 73.02,27.02 PR511.1 ; RT128.1 23.49,19.25 v4(23.24,19) ; v2(65.71,8.86) 66.44,8.86 66.75,9.17 RE60.2 ; v4(40.69,68.15) 40.64,68.2 40,68.2 PC971.1 39.98,68.4 40.53,68.95 PU906.5 ; v2(25.12,16.96) 25.27,17.12 RT47.2 ; PR907.2 50.7,67.89 v4(50.54,68.04) 50.65,68.15 PC969.1 50.29,68.81 50.24,68.76 PU904.5 ; RT126.1 50.63,38.05 50.9,38.31 v2(50.91,38.31) ; v2(49.66,43.3) 49.45,43.51 PR203.2 ; PR654.2 v2(110.23,16.96) ; v2(19.15,16.96) 19.15,16.79 19.43,16.51 20.22,16.51 v2(20.67,16.96) 21.17,17.47 21.72,17.47 v2(22.22,16.96) ; RT127.1 25.4,19.76 v2(25.78,19.38) ; v4(139.16,49.98) 139.34,50.16 RV46.2 ; v4(24.33,35.41) 25.17,35.41 25.55,35.02 RT73.1 ; PR508.1 73.02,25.14 72.08,24.2 70.23,24.2 v2(69.72,24.71) 69.85,24.84 69.85,25.49 69.57,25.77 PR902.2 69.34,26.87 v2(69.21,27) 68.96,27 PR901.2 ; PR411.2 32.69,65.02 v4(32.08,65.02) ; v4(50.7,64.69) PC972.1 PU901.5 ; v1(50.62,51.15) 50.62,51.31 PR302.2 ; RP13.1 57.81,51.25 57.88,51.18 v2(57.91,51.18) 57.94,51.18 58.01,51.25 RP12.1 ; PR137.2 v4(98.68,15.82)
  BOTTOM w0.381: v4(154.73,15.95) 155.45,16.66 155.45,20.9 156.31,21.77 156.98,21.77 159.8,24.58 159.8,24.75 160.58,25.52 164.34,25.52 v4(165.25,24.61) ; v4(168.78,24.71) 170.05,24.71 170.81,23.95 170.81,22.93 174.06,19.68 v4(175.39,19.68)
  BOTTOM w0.508: RX917.2 160.74,91.79 v4(160.91,91.97)
  vias: v3(30.71,42.31) v4(24.46,43.76) v4(24.46,43.13) v4(25.14,43.76) v4(25.14,43.13) v4(25.78,43.76) v4(25.78,43.13) v4(26.41,66.37) v4(29.06,66.22) v4(32,48.21) v4(32,47.32) v4(32,46.43) v4(32,45.54) v4(32,44.65)
+V3P3A_EC: length 275.2
  TOP w0.102: v1(23.24,64.95) 23.06,64.95 22.71,64.59 v3(22.05,64.59)
  TOP w0.203: RE31.2 161.51,24.42 161.51,24.93 v4(161.53,24.95) ; UE1.K4 161.93,15.74 v2(161.4,15.21) ; v2(155.45,22.93) 155.5,22.88 155.95,22.88 156.11,23.04 CE33.1 156.87,23.04 PR134.2 ; RE120.2 RE108.2 163.57,24.1 163.57,24.61 v4(163.5,24.69) ; v2(165,19.23) 164.97,19.2 UE1.D10 ; v2(157.64,24.75) 158.34,24.05 PR163.2 ; v4(154.15,7.85) 154.33,7.85 RE81.1 ; v2(161.46,18.42) 161.63,18.24 UE1.E4 UE1.D4 ; RE127.2 165.96,23.39 165.96,23.16 166.06,23.06 v4(166.06,22.93) ; v2(156.41,20.62) 156.51,20.72 RE139.1 ; RE135.2 165.12,23.06 165.12,22.93 v4(165.15,22.91) ; v4(169.59,18.02) 169.61,18.02 169.91,18.31 RE134.2 ; v2(162.2,19.33) 162.2,19.23 162.47,18.96 UE1.D5 ; v2(158.32,18.21) 157.83,18.21 157.55,18.49 RE102.1
  TOP w0.254: v4(155.65,13.28) 155.71,13.35 DE6.1 155.71,14.51 156.11,14.91 156.79,14.91 RE118.1 ; UE1.K10 164.97,15.58 165.36,15.19 v2(165.54,15.19)
  TOP w0.279: v1(23.24,64.95) 23.87,64.95 24.38,65.45 PQ114.3 ; RE30.2 139.85,16.43 139.7,16.58 ; RE29.2 137.92,16.3 138.2,16.58 139.06,16.58 139.32,16.33 ; CE34.1 170.81,15.24 FBE2.1 170.95,15.75 RE33.1 170.95,16.8 v4(171.24,17.09) ; RE80.2 168.78,22.81 168.81,22.78 v4(168.81,22.27) ; 139.7,16.58 139.7,16.71 142.57,19.58 v4(142.9,19.58) ; 139.7,16.58 139.44,16.58 139.32,16.46 139.32,16.33 ; R16.2 v2(15.75,82.24) ; v1(22.73,7.47) 22.99,7.47 QT3.3 ; CE35.1 CE18.1 155.57,24.58 v2(155.83,24.33) ; v2(155.45,22.93) 155.32,23.06 CE39.1 ; 139.32,16.33 RE458.2
  TOP w0.305: v4(168.81,22.27) CE26.1 ; CE26.1 CE32.1 ; CE26.1 168.53,21.66 v4(168.27,21.92)
  ART05 w0.279: v1(23.24,64.95) 23.24,65.22 23.75,65.73 23.75,67.26 22.99,68.02 22.99,74.24 21.13,76.1 21.13,76.78 18.03,79.88 16.58,79.88 14.98,81.48 14.98,81.96 15.26,82.24 v2(15.75,82.24)
  ART06 w0.203: v4(154.15,7.85) 152.63,6.32 138.7,6.32 137.43,7.59 132.97,7.59 131.6,6.22 116.18,6.22 113.92,3.96 110.97,3.96 110.13,4.8 103.78,4.8 100.43,8.15 83.35,8.15 82.79,7.59 66.06,7.59 63.88,5.41 49.78,5.41 47.88,7.31 34.85,7.31 33.81,8.35 29.82,8.35 28.5,7.03 27.48,7.03 27.05,6.6 27.05,6.14 26.64,5.74 24.31,5.74 22.73,7.31 v1(22.73,7.47) 22.73,10.23 21.08,11.88 21.08,23.06 21.89,23.87 21.89,26.77 21.69,26.97 20.22,26.97 19.56,27.63 19.56,31.19 20.62,32.26 20.62,39.88 21.46,40.71 21.46,48.33 21.21,48.59 21.21,59.28 23.24,61.31 v1(23.24,64.95)
  BOTTOM w0.254: v4(155.65,13.28) 155.47,13.1 155.47,9.57 155.87,9.18 155.87,8.71 155,7.85 v4(154.15,7.85)
  BOTTOM w0.279: v4(142.9,19.58) 142.9,19.66 143.25,20.01 CE14.1 141.73,20.39 141.22,20.9 UE2.8 141.22,23.7 140.84,24.08 140.84,24.94 140.56,25.22 RE28.2
+V3P3A_PCH: length 61.8
  TOP w0.279: v2(61.09,46.17) 61.21,46.05 RU51.2 ; RU118.2 58.42,84.27 58.04,84.66 v1(57.66,84.66) ; v2(53.81,75.22) 53.81,75.09 54.28,74.62 RU11.2 RU169.1 ; RU145.2 61.17,47.67 v2(60.68,48.16) ; RU123.2 RU143.2 v1(57.66,85.54) ; v2(60.63,57.48) 59.82,57.48 58.93,56.59 56.89,56.59 v2(56.39,57.1) ; v2(76.91,61.73) 76.84,61.8 RU7.2 ; 64.72,53.92 64.72,53.62 RU49.2 65.45,53.08 65.63,52.91 RU41.2 ; CU54.1 71.25,57.27 v2(71.1,57.41) ; v1(62.53,61.69) 63.19,61.03 64.97,61.03 65.83,60.17 RU50.2 ; v1(59.59,60.78) 60.12,60.78 60.53,60.37 RU226.1 ; RU158.2 v1(57.66,79.83) ; RU8.2 RU9.2
  TOP w0.305: RU171.1 RU42.2 68.88,53.07 v2(69.61,53.8) ; CU54.1 71.25,56.51 71.37,56.39 71.91,56.39 72.36,55.93 72.36,53.16 71.47,52.27 71.47,50.34 71.09,49.96 70.23,49.96 69.82,49.55 RU4.2 69.04,49.55 68.68,49.91 67.79,49.91 RU9.2 ; 65.43,54.05 65.61,53.87 66.88,53.87 RU48.2 RU35.2 67.94,53.92 68.04,53.83 69.58,53.83 v2(69.61,53.8) ; v2(69.61,53.8) 69.61,53.75 70.31,53.06 RU230.2 ; v2(69.61,53.8) 69.62,53.8 v2(69.62,54.66) 69.72,54.76 CU53.1
  BOTTOM w0.203: v2(69.61,53.8) 69.29,54.21 UU1.DG26 ; v2(69.62,54.66) UU1.DG28 ; v2(71.1,57.41) 71.38,57.51 UU1.DC33
  BOTTOM w0.254: v2(72.51,58.57) 72.15,58.21 UU1.DB34 71.95,58.21 71.8,58.06 UU1.DC33
  BOTTOM w0.279: UU1.DF23 69.61,53.75 v2(69.61,53.8) ; RU170.1 RU158.2 v1(57.66,79.83) ; RU144.2 v1(57.66,84.66) ; RU36.2 55.78,51.03 55.37,50.62 55.37,49.71 v3(55.67,49.4) 56.72,49.4 RU56.2 RU55.2 56.77,48.26 57.15,47.88 60.39,47.88 v2(60.68,48.16) ; v2(53.81,75.22) 53.81,74.89 54.58,74.11 RU169.1 ; RU10.2 v2(56.39,57.1) ; RU143.2 v1(57.66,85.54)
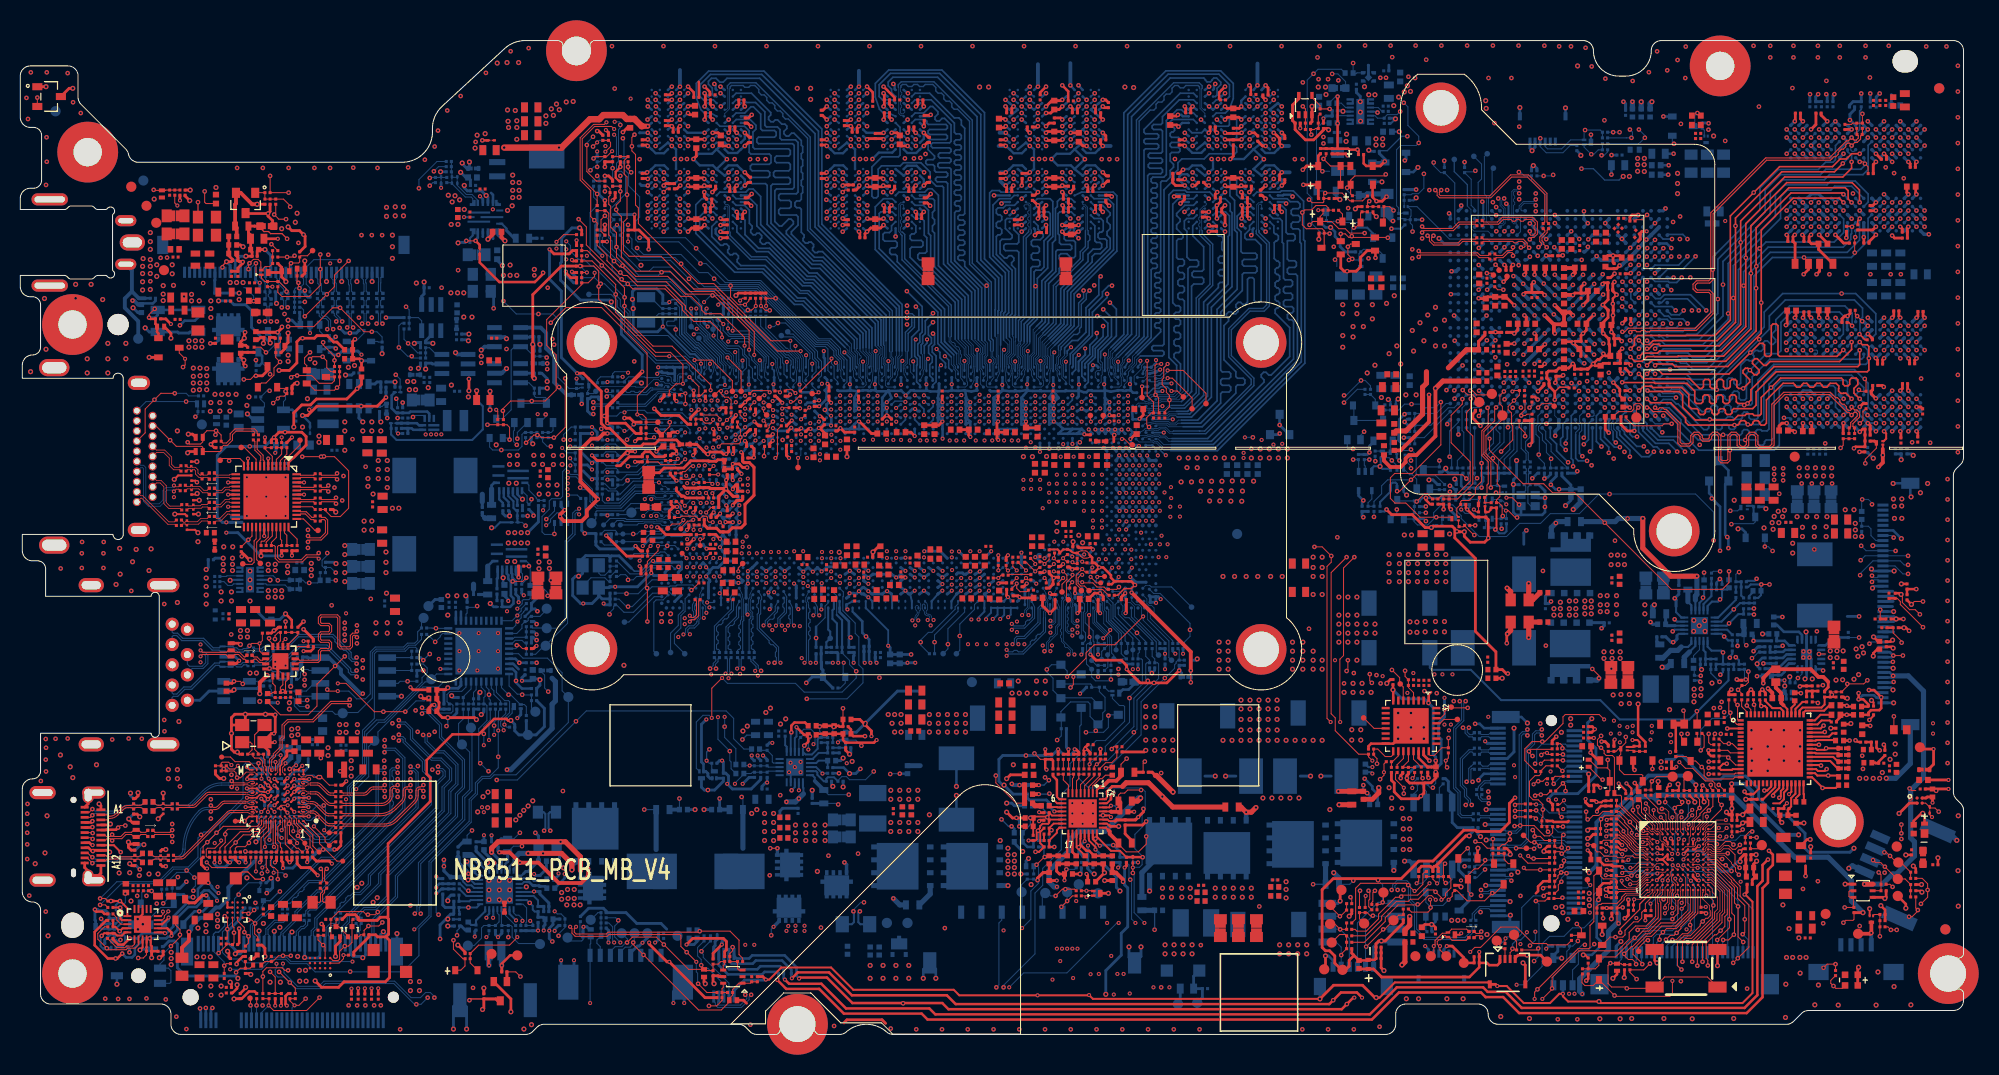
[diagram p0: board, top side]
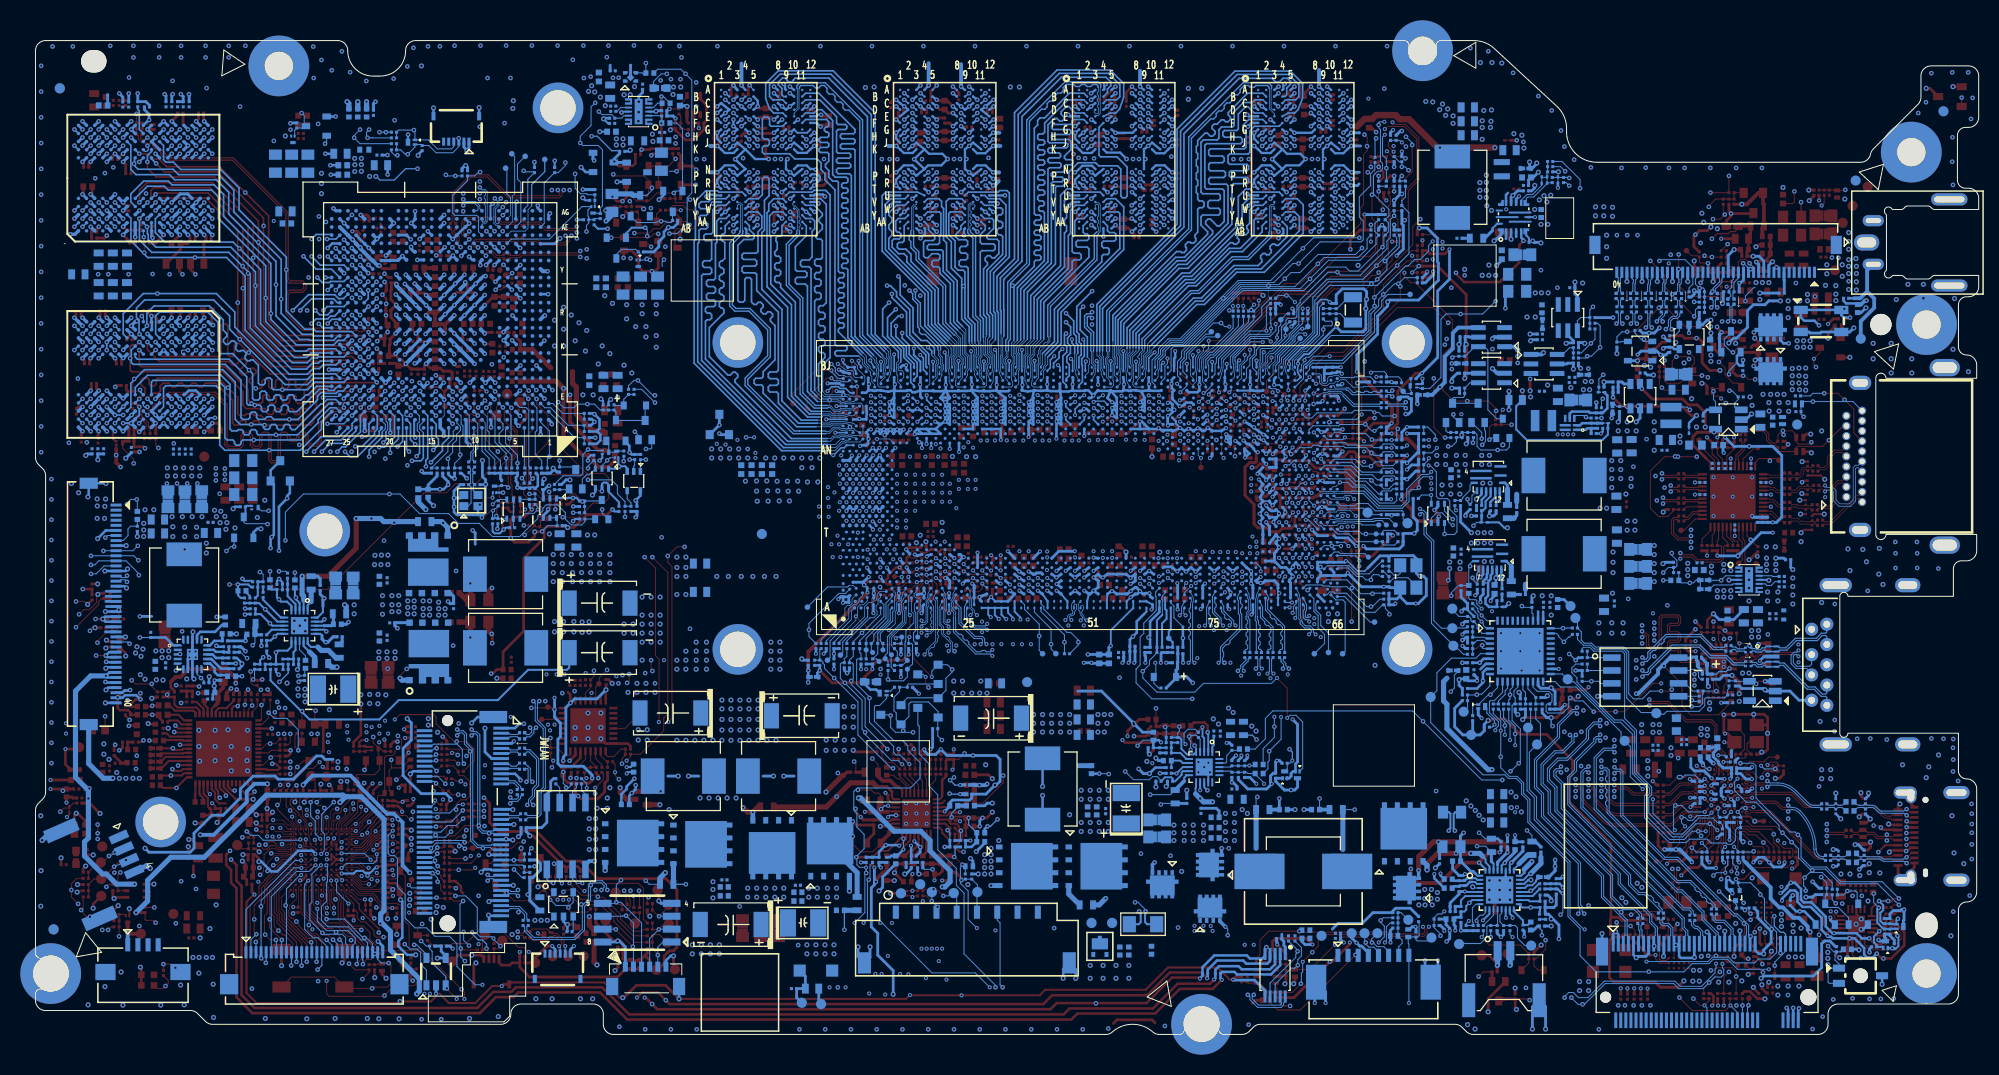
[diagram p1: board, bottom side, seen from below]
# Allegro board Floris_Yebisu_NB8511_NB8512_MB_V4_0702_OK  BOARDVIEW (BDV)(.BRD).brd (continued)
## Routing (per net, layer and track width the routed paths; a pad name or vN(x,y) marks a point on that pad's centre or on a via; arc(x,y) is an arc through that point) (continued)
+V3P3A_SPI_FLASH: length 255.5
  TOP w0.254: CP3.1 CO2.1 CO1.1 133.57,7.36 DO1.1 132.89,7.3 RO1.2 ; RE68.1 159.46,24.09 159.46,24.56 v1(159.23,24.79)
  TOP w0.279: 131.47,7.85 131.32,8.01 RO2.2 ; 131.47,7.85 131.47,7.73 131.06,7.31 131.06,6.73 130.71,6.37 VCC_SPIO1.1 130.3,6.37 129.64,7.03 129.64,7.74 129.13,8.25 128.73,8.25 128.4,8.58 128.4,14.27 129.49,15.36 136.19,15.36 137.92,17.09 139.32,17.09 142.37,20.14 143.51,20.14 143.63,20.01 145.97,20.01 146.86,20.9 146.86,22.78 v1(147.42,23.34) ; 131.47,7.85 RO1.2 ; v1(56.89,89.08) 57.05,89.08 RU52.2 ; CP3.1 133.7,8.94 133.98,9.22 v4(134.24,9.22) 134.62,9.22 136.4,11 RO4.2 ; RO3.2 131.32,11.91 v4(131.06,11.66)
  ART05 w0.279: v4(134.24,9.22) 134.24,9.34 131.95,11.63 131.09,11.63 v4(131.06,11.66) 130.53,11.12 129.67,11.12 128.78,10.23 112.52,10.23 111.25,11.5 105.92,11.5 105.66,11.25 85.48,11.25 82.92,13.82 82.92,19.33 78.7,23.54 72.44,23.54 71.58,22.68 68.22,22.68 67.1,23.8 52.65,23.8 50.87,25.58 46.71,25.58 46.53,25.4 45.29,25.4 43.05,27.63 43.05,34.72 42.82,34.95 42.82,37.28 38.89,41.22 35.05,41.22 33.65,42.62 33.65,49.1 32.64,50.11 32.64,56.44 35.2,59 35.81,59 36.54,59.73 38.26,59.73 39.83,61.29 44.09,61.29 44.73,60.65 47.47,60.65 48.61,61.8 48.61,66.93 51.36,69.67 52.75,69.67 57.28,74.19 57.28,75.64 56.39,76.53 56.39,88.21 56.89,88.72 v1(56.89,89.08)
  ART06 w0.279: v1(147.42,23.34) 148.18,24.1 150.06,24.1 150.16,24 152.58,24 153.69,25.12 154.84,25.12 155.7,25.98 158.08,25.98 159.23,24.83 v1(159.23,24.79)
  BOTTOM w0.279: RU52.2 57.05,89.08 v1(56.89,89.08) ; J3001.1 133.48,8.63 134.06,9.22 v4(134.24,9.22) 134.34,9.12 UO1.8
+V3P3A_TCP: length 20.4
  ART05 w0.254: v1(39.75,35.89) v1(39.75,36.9)
  ART06 w0.381: v1(33.78,33.6) 36.96,33.6 39.24,35.89 v1(39.75,35.89)
  BOTTOM w0.127: v1(39.75,36.9) 40.36,37.51 v3(40.38,37.51)
  BOTTOM w0.254: RT76.1 RT75.1 v1(39.75,35.89) ; RT74.1 39.5,37.16 v1(39.75,36.9)
  BOTTOM w0.305: RT77.1 27.25,35.81 27.7,36.26 DT1.1 27.7,36.77 27.84,36.9 RT130.2 28.29,37.21 28.4,37.11 29.55,37.11 UT3.8
  BOTTOM w0.381: UT3.8 30.43,37.16 31.62,35.96 31.62,35.56 33.58,33.6 v1(33.78,33.6)
+V3P3A_VDDD_PD: length 104
  TOP w0.203: UT7.10 12.86,8.8 12.95,8.71
  TOP w0.254: 13.59,8.2 RT117.2 12.95,8.71 ; v4(48.39,30.96) 48.11,30.96 47.95,31.11 46.73,31.11 45.21,29.59 42.62,29.59 40.08,27.05 40.08,25.68 40.43,25.32 40.43,22.98 36.27,18.82 36.27,11.66 36.17,11.55
  TOP w0.279: RT117.2 v4(12.95,7.57) ; RT98.2 32.89,8.13 34.39,9.62 RT101.2 35.05,9.83 35.25,9.62 36.07,9.62 ; 36.07,9.62 36.32,9.88 36.32,11.4 36.17,11.55 35.51,11.55 35.2,11.25 33.42,11.25 RT102.2 33.32,11.53 33.04,11.81 32.21,11.81 RT135.2 ; 36.07,9.62 36.42,9.27 36.42,5.61 36,5.19 31.94,5.19 31.39,4.65 29.72,4.65 v4(29.08,5.28)
  ART03 w0.279: v4(42.16,41.35) 47.62,41.35 v2(48,41.73) ; v4(12.95,7.57) 14.6,5.92 20.95,5.92 21.46,6.42 23.24,6.42 23.96,5.7 26.58,5.7 26.66,5.78 28.59,5.78 v4(29.08,5.28)
  ART05 w0.279: v1(50.93,40.46) 50.59,40.13 48.82,40.13 48.39,40.56 48.39,41.35 v2(48,41.73) 47.62,41.35 47.62,32.59 48.39,31.82 v4(48.39,30.96)
  BOTTOM w0.254: UT1.32 43.46,41.7 ; UT1.31 42.96,41.69
  BOTTOM w0.279: TPT1.1 50.87,29.54 51.69,30.35 51.69,32.15 RT18.1 ; TPT1.1 49.17,29.54 48.77,29.94 RT1.2 48.77,30.58 v4(48.39,30.96) ; TPT1.1 49.91,29.69 RT3.2 ; RT2.1 50.67,40.71 v1(50.93,40.46)
+V3P3A_VSYS_PD: length 15.3
  TOP w0.279: v4(44.98,31.05) 44.79,31.24 v4(42.16,31.24) 41.63,31.24 41.08,31.79 CT6.1 41.08,32.01 41.3,32.23 41.3,32.74 41.08,32.95 RT5.2 RT6.2 41.11,34.01 41.98,34.01 v4(42.16,34.19)
  BOTTOM w0.127: v3(42.04,30.4) 42.16,30.53 v4(42.16,31.24)
  BOTTOM w0.279: RT16.1 RT19.1 44.7,31.33 v4(44.98,31.05) ; RT21.1 43.05,31.7 42.59,31.23 42.19,31.23 42.19,31.24 v4(42.16,31.24) ; CT7.1 41.78,33.8 v4(42.16,34.19) 42.21,34.14 43.18,34.14 43.46,34.41 UT1.19
+V3P3S_SSD1: length 7
  TOP w0.254: CN1.1 21.84,3.53 22.55,4.24 23.11,4.24 RN3.2 ; v2(25.7,2.84) 25.75,2.89 RN30.2
  TOP w0.279: CN1.1 21.11,3.53 v4(21.08,3.5)
  BOTTOM w0.254: JSSD1.72 v1(18.3,2.61) ; v1(17.73,2.56) 17.8,2.49 JSSD1.74 ; v1(18.95,2.61) 18.8,2.47 JSSD1.70
  vias: v1(32.38,2.87) v1(33.22,2.87) v1(34.03,2.87) v1(34.9,2.87) v1(35.56,2.87) v3(18.82,3.88) v4(17.73,4.77) v4(18.79,4.77) v4(19.81,4.77) v4(19.81,3.88)
+V3P3SX: length 393.2
  TOP w0.203: v4(133.74,80.64) 133.41,80.97 RV15.2 ; v4(187.55,14.03) 187.4,14.17 RE51.1
  TOP w0.254: RE50.1 186.94,16.36 v4(186.7,16.6) ; RE112.2 154.73,20.29 v4(154.58,20.14)
  TOP w0.279: 60.58,79.32 v2(60.58,80.85) ; 60.58,79.32 RU32.2 ; 60.58,79.32 61.01,79.32 61.97,78.36 v1(61.97,77.42) ; v4(25.53,65.48) 26.54,65.48 27.28,66.22 27.28,68.3 27.63,68.65 v3(27.84,68.65) 29,68.65 29.26,68.91 30.27,68.91 30.91,68.27 31.23,68.27 RX924.2 ; v4(55.17,79.52) 55.37,79.32 RU103.2 ; v2(108.91,16.46) 109.09,16.63 PR628.2 ; QW2.1 143.72,18.32 v4(143.76,18.36) ; v4(68.43,5) 68.32,5.1 RE55.1 68.83,5.79 68.92,5.7 QE3.5 ; CX885.1 v4(23.37,81.86) ; v1(158.24,11.45) 158.29,11.45 158.6,11.76 RE113.2 ; v2(57.91,60.27) 59.69,60.27 60.7,59.26 RU119.2 RU227.1 ; RF1.1 v4(146.15,35.13)
  TOP w0.381: v4(16.64,10.11) 16.64,9.24 15.95,8.56 RN1.1 ; v2(57.91,59.26) 57.53,59.26 57.02,58.75 56.34,58.75 55.24,57.66 55.24,54.51 v2(56.97,52.78) 55.88,51.69 55.88,51.13 55.37,50.62 53.62,50.62 53.24,51 v2(53.24,51.08) 53.24,51.25 v2(53.69,51.71) ; v4(23.37,81.86) 22.86,81.86 21.73,82.99 QX42.2 21.27,81.93 21.18,81.84 RX900.1 21.35,79.54 RX907.2 ; v2(61.34,65.35) 57.86,61.87 57.86,60.32 v2(57.91,60.27)
  ART03 w0.381: v4(187.55,14.03) 187.08,14.03 186.7,14.41 v4(186.7,16.6)
  ART03 w0.508: v4(58.29,72.24) 58.25,72.19 53.6,72.19 52.55,71.14 46.99,71.14 45.67,72.46 40.69,72.46 v4(39.06,74.09) ; v4(135.89,62.66) 135.89,60.14 136.4,59.64 136.6,59.64 137.79,58.44 137.79,57.22 v1(137.16,56.59) 137.29,56.59 137.79,56.08 137.79,52.57 138.3,52.06 v1(138.62,52.06)
  ART05 w0.279: v4(171.83,39.49) 171.96,39.37 171.96,37.54 171.3,36.88 v4(171.3,36.55) 167.79,36.55 166.11,34.87 165.79,34.87 v1(165.69,34.77) 165.83,34.77 166.29,34.31 166.29,33.14 165.17,32.03 v4(162.66,32.03) 161.8,32.03 159.61,34.21 154.68,34.21 153.97,34.92 146.35,34.92 v4(146.15,35.13) ; v1(61.97,77.42) 61.97,75.66 58.55,72.24 v4(58.29,72.24)
  ART05 w0.381: v4(180.85,18.36) 182.88,18.36 184.64,16.6 v4(186.7,16.6) ; 153.41,10.74 153.67,10.49 157.02,10.49 157.99,11.45 v1(158.24,11.45) ; v4(143.76,18.36) 144.14,18.36 145.41,17.09 151.38,17.09 151.51,17.22 153.41,17.22
  ART05 w0.508: v4(159.86,91.96) 159.29,91.39 155.62,91.39 151.38,95.63 133.78,95.63 132.57,94.42 v4(132.57,93.46) 130.96,91.84 130.3,91.84 129.79,91.34 129.79,90.42 130.15,90.07 130.15,84.23 v4(133.74,80.64) ; v1(138.62,52.06) 139.14,52.06 140.33,50.87 143.89,50.87 144.27,50.49 146.56,50.49 146.94,50.11 157.61,50.11 164.59,43.13 166.62,43.13 170.25,39.49 v4(171.83,39.49)
  ART05 w0.762: 149.4,6.17 150.67,6.17 v4(152.02,7.52) 152.02,7.54 152.68,8.2 152.68,8.89 153.41,9.62 153.41,19.38 154.18,20.14 v4(154.58,20.14)
  ART06 w0.279: v4(171.3,36.55) 171.3,36.29 171.96,35.63 174.16,35.63 v4(174.51,35.28) ; v1(137.16,56.59) 138.76,56.59 140.58,54.77 v4(141.48,54.77)
  ART06 w0.508: v4(133.74,80.64) 133.74,80.03 135.13,78.64 135.13,73.99 134.11,72.97 134.11,71.07 134.24,70.94 134.24,65.61 135.89,63.95 v4(135.89,62.66) ; v4(27.3,80.97) 28.7,79.58 37.23,79.58 39.06,77.75 v4(39.06,74.09)
  BOTTOM w0.203: PR821.2 165.56,34.91 v1(165.69,34.77) ; v4(135.89,62.66) 135.87,62.66 135.67,62.46 RV49.2 ; v1(137.16,56.59) 137.16,56.84 136.88,57.12 RV27.2
  BOTTOM w0.254: PR1105.2 174.54,35.25 v4(174.51,35.28) ; PR1102.2 171.8,37.12 171.3,36.62 v4(171.3,36.55) 171.3,36.33 PR1107.2 ; RV56.2 138.61,52.05 v1(138.62,52.06)
  BOTTOM w0.279: RU112.2 RU114.2 v2(60.58,80.85) ; US1.1 68.39,8.62 68.53,8.76 68.53,9.17 68.73,9.37 CS1.1 68.73,9.88 ; v2(56.97,52.78) 56.89,52.85 RU111.2 ; v4(55.17,79.52) 54.4,79.52 53.39,78.51 53.39,76.17 53.29,76.07 53.29,74.37 55.24,72.41 58.11,72.41 v4(58.29,72.24) 58.29,71.83 59.28,70.84 59.28,69.06 61.34,67 v2(61.34,65.35) ; v4(141.48,54.77) 141.62,54.62 RV45.2 ; v2(57.91,59.26) RU120.2 RU101.2 58.29,59.89 v2(57.91,60.27) ; v2(53.69,51.71) 53.67,51.74 53.64,51.74 53.34,52.04 QU1.5 ; v2(53.24,51.08) 53.34,50.98 QU1.2 ; v4(152.02,7.52) 151.99,7.55 US4.4 151.19,7.76 151.64,8.2 CS3.1 RS3.2 ; 23.04,17.02 23.24,17.22 RT57.2 ; v2(108.91,16.46) 108.91,14.75 109.22,14.45 109.22,10.61 108.58,9.98 108.58,7.82 107.06,6.3 v4(107.06,3.96) ; 162.3,27.12 163.09,27.12 163.42,27.45 163.93,27.45 166.22,25.17 167.71,25.17 168.02,25.47 170.18,25.47 171.45,24.2 171.45,23.31 173.15,21.61 174.24,21.61 176.02,19.83 176.02,18.35 176.4,17.97 180.45,17.97 v4(180.85,18.36) ; v4(171.83,39.49) PR1104.2
  BOTTOM w0.381: 23.04,17.02 20.52,14.5 20.52,13.38 19.66,12.52 19.3,12.52 18.29,11.5 17.73,11.5 16.86,10.64 16.86,10.34 v4(16.64,10.11)
  BOTTOM w0.508: RX918.2 v4(159.86,91.96)
  vias: v2(71.5,8.84) v2(72.39,8.84) v4(14.6,26.11) v4(14.6,25.22) v4(14.88,8.1) v4(14.88,7.49) v4(14.88,6.88) v4(15.49,26.11) v4(15.49,25.22) v4(19.81,43.63) v4(19.81,42.75) v4(20.06,48.08) v4(20.83,43.63) v4(20.83,42.75) v4(20.95,48.08) v4(161.82,26.9) v4(161.84,26.27)
+V3P3SX_AUD: length 5.2
  TOP w0.102: v3(164.03,31.93) 164.11,31.85 FBA5.1
  TOP w0.254: RA32.2 163.27,30.36 RA16.1
  TOP w0.508: FBA5.1 163.06,30.6 RA32.2
+V3P3SX_HDMI: length 32.4
  TOP w0.203: 26.92,56.84 26.46,56.38 UI2.1
  TOP w0.279: v2(25.02,58.87) 25.53,59.38 v3(26.11,59.38) 27.76,59.38 28.19,58.95 28.19,58.11 26.92,56.84 ; v2(25.02,58.87) 24.76,58.62 RI101.2 ; v2(25.02,58.87) 25.27,58.62 RI155.2 ; RI154.2 RI142.2 v2(25.78,47.22) ; RI143.2 RI152.2 RI151.2 v4(23.75,47.19)
  BOTTOM w0.279: v2(25.78,47.22) 25.75,47.19 v4(23.75,47.19) 21.46,49.48 v2(20.32,49.48) ; CI118.1 CI116.1 CI115.2 v2(20.32,50.49) 19.94,50.49 19.43,51 19.43,57.1 20.32,57.99 v3(22.63,57.99) 24.13,57.99 v2(25.02,58.87)
+V5P0_AVDD5: length 4
  TOP w0.102: FBA4.1 v3(184.78,31.37)
  TOP w0.203: UA2.41 178.39,29.37 178.71,29.69 CA57.1
+V5P0_FPS: length 0.9
  BOTTOM w0.254: v2(138.56,8.71) 138.9,8.37 J1.6
+V5P0A: length 215.9
  TOP w0.279: RB49.2 24.76,39.57 v1(25.02,39.82) 25.12,39.82 25.45,40.15 RB52.2 ; v1(27.94,39.95) 28.9,38.99 RB48.2
  TOP w0.508: v4(110.49,23.31) 110.18,23.01 PR603.1 ; v4(137.03,11.63) 137.03,10.77 136.56,10.3 R17.1
  ART03 w0.254: v4(132.99,87.2) 132.99,84.46 129.23,80.7 v4(129.23,79.58)
  ART03 w0.279: v4(81.15,24.41) 80.49,25.07 75.54,25.07 v4(72.64,22.17)
  ART03 w0.508: v4(97.94,26.59) 97.94,25.96 99.44,24.46 99.44,20.52 100.28,19.68 100.28,15.36 v4(99.69,14.78)
  ART05 w0.254: v4(187.4,53.41) 187.4,55.78 189.86,58.24 189.86,89.86 186.23,93.49 171.52,93.49 167.87,89.84 v1(166.51,89.84)
  ART05 w0.279: v4(132.99,87.2) 132.99,88.06 130.45,90.6 v4(130.45,91.03) 131.24,91.03 131.67,91.46 132.74,91.46 133.07,91.79 133.63,91.79 135.63,93.8 135.63,94.03 136.73,95.12 150.98,95.12 155.4,90.7 160.75,90.7 161.14,91.08 165.27,91.08 v1(166.51,89.84)
  ART06 w0.203: v4(46.48,49.96) 45.41,51.03 36.32,51.03 34.8,52.55 v4(34.8,53.29)
  ART06 w0.254: v4(172.16,51.84) 172.92,51.84 173.88,52.79 v4(184.74,52.79)
  BOTTOM w0.203: PU902.4 24.61,44.83 v4(24.64,44.8) ; v4(130.45,91.03) 130.48,91 PU1201.4 ; v4(46.48,49.96) 46.78,49.96 47.32,50.49 PSH306.2
  BOTTOM w0.254: v4(132.99,87.2) 133.11,87.08 RV78.2 ; 129.67,78.69 129.67,79.14 v4(129.23,79.58) 128.73,79.58 128.31,79.99 RV87.2 ; v4(172.16,51.84) 171.97,52.03 RV77.2
  BOTTOM w0.279: 129.67,78.69 130.17,78.18 130.17,77.67 130.68,77.16 RV76.2 ; v4(43.58,85.93) 43.58,85.85 44.04,85.39 PSH706.1 v4(44.3,86.03) ; PC1211.1 130.39,91.09 v4(130.45,91.03) ; v1(166.51,89.84) 166.47,89.88 RV85.2 ; PC716.1 45.49,83.18 v4(45.95,82.73) 46.12,82.55 PU701.13 ; PR519.2 v4(81.15,24.41)
  BOTTOM w0.508: 52.45,35.13 52.78,34.8 52.78,32.89 52.45,32.56 52.45,30.17 48.39,26.11 v1(48,26.11) ; v2(102.23,14.55) 101.96,14.55 101.45,15.06 101.45,16.13 103.43,18.11 103.43,19.12 104.34,20.04 106.98,20.04 110.26,23.31 v4(110.49,23.31)
  vias: v1(28.04,35.53) v1(28.04,34.97) v1(28.04,34.41) v2(188.64,30.68) v2(188.64,29.66) v3(34.06,55.98) v4(24.46,46.35) v4(24.46,45.74) v4(25.14,46.35) v4(25.14,45.74) v4(26.36,46.17) v4(26.36,45.54) v4(33.22,14.5) v4(33.68,14.91) v4(34.29,54.81) v4(34.29,54.05) v4(34.8,13.03) v4(35.2,13.48) v4(35.3,56.59) v4(35.3,55.7) v4(35.3,54.81) v4(36.19,56.59) v4(36.19,55.7) v4(36.19,54.81) v4(36.19,53.92) v4(38.38,63.57) v4(38.99,63.57) v4(72.13,21.79) v4(184.81,52.07) v4(184.84,50.88) v4(185.56,52.8) v4(185.55,52.11) v4(185.57,50.89)
+V5P0A_FAN: length 0.9
  TOP w0.102: v1(185.52,19.83) v3(185.52,20.7)
  vias: v1(185.52,19.28)
+V5P0A_LX: length 1.3
  BOTTOM w0.305: 45.57,52.52 PC308.2
  BOTTOM w0.508: 45.57,53.26 45.57,52.52
+V5P0A_TYPEC: length 5.5
  TOP w0.254: v1(21.59,10.44) 21.59,9.01 RT94.2
  ART03 w0.254: v1(23.19,12.98) 22.15,12.98 21.59,12.42 v1(21.59,10.44)
  vias: v3(24.31,13.94)
+V5P0A_USB_AOU1:
  vias: v3(20.8,39.44) v4(21.72,39.82) v4(21.72,39.19) v4(22.4,39.82) v4(22.4,39.19) v4(22.65,35.63) v4(23.29,35.63)
+V5P0SX: length 53.4
  TOP w0.279: RX925.2 33.65,64.11 v3(33.22,63.68) 32.21,62.66 29.21,62.66 28.62,62.08 27.76,62.08 26.97,61.29 v4(26.97,59.89)
  TOP w0.508: v4(136.27,6.86) 136.56,7.15 R18.1
  ART03 w0.279: v4(173.84,12.77) 173.1,13.51 173.1,21.16 170.69,23.57 170.69,24.58 168.91,26.36 168.91,26.87 168.27,27.51 165.48,27.51 165.1,27.89 165.1,29.74 164.67,30.17 163.29,30.17 162.76,29.64 v4(162.76,29.54)
  ART06 w0.279: v4(162.76,29.54) 162.76,29.74 163.45,30.43 163.45,36.27 161.42,38.3 161.42,42.11 v4(161.16,42.36)
  BOTTOM w0.279: PC911.1 19.2,46.96 v4(20.01,46.96)
  BOTTOM w0.508: PR816.2 161.01,42.21 v4(161.16,42.36)
  vias: v3(21.84,47.14) v4(20.01,46.35) v4(20.01,45.74) v4(20.93,46.96) v4(20.93,46.35) v4(20.93,45.74) v4(27.84,59.89) v4(174.19,7.59) v4(174.8,7.59) v4(175.51,7.59) v4(176.12,7.59)
+V5P0SX_AUD: length 1
  TOP w0.279: 176.07,16.63 v3(176.07,15.62)
+V5P0SX_HDMI: length 1.3
  TOP w0.254: RI106.2 19.12,57.86 v1(18.79,58.19) 19.1,58.49 RI105.2
  vias: v3(19.25,59.13)
+V5P0SX_KB_BL:
  vias: v1(177.81,10.96) v3(181.4,10.69)
+VBAT_R:
  vias: v3(78.97,10.54)
+VBATA_BKLT_IN:
  vias: v3(16.15,72.77) v4(16.89,72.97) v4(16.89,72.34) v4(17.65,72.34)
+VBUS_TYPEC: length 53.6
  TOP w0.203: UT5.D1 UT5.D2 UT5.C2
  TOP w0.254: JT1.A4 8.8,20.66 v4(8.89,20.75) ; RT100.1 21.94,7.69 21.33,7.08 v1(21.33,6.93) ; v1(7.16,18.08) 7.06,18.08 6.74,18.41 JT1.B4 ; v1(29.72,10.89) 29.92,10.69 RT99.2 ; v1(7.11,21.03) 6.99,20.91 JT1.B9
  TOP w0.279: v1(7.16,18.08) 7.24,18.16 JT1.A9 8.64,18.16 v4(8.81,17.98)
  ART03 w0.254: v1(29.72,10.89) 29.72,7.91 v4(28.13,6.32)
  ART03 w0.279: v2(19.45,14.55) 23.87,14.55 24.59,13.84 28.7,13.84 31.7,16.84 31.7,17.17 36.57,22.04 36.57,27.25 38.23,28.9 40.82,28.9 43.33,31.42 43.33,34.14 v2(41.43,36.04)
  BOTTOM w0.254: UT1.22 v2(41.43,36.04)
  vias: v3(16.41,16.18) v4(9.75,15.92) v4(10.79,15.95) v4(11.73,15.67) v4(12.7,15.82) v4(13.59,15.82) v4(27.52,6.32) v4(27.56,5.26) v4(28.19,5.26)
+VBUS_TYPEC1_P1:
  vias: v3(87.07,3.07) v4(17.07,65.71) v4(17.07,64.89) v4(17.07,64.23) v4(17.07,63.52) v4(17.68,63.57) v4(17.73,65.71) v4(17.73,64.95) v4(17.73,64.23) v4(18.39,65.66) v4(18.39,64.95) v4(18.39,64.23) v4(18.39,63.57) v4(19.2,63.12) v4(19.86,63.12) v4(20.52,63.12) v4(21.28,63.12) v4(23.37,5.28) v4(24.64,5.15) v4(25.65,5.15) v4(38.48,5.21) v4(38.48,4.33) v4(39.37,5.21) v4(39.37,4.33) v4(48.87,21.16) v4(49.27,21.61) v4(49.66,22.1) v4(50.09,22.53) v4(50.54,23.04)
+VBUS_TYPEC_PP_HV:
  vias: v3(32.54,6.2)
+VBUS_WC: length 4.5
  BOTTOM w0.279: DWC1.2 115.72,5.74 CB415.1 CB414.1 116.58,3.63 TPWC1.1
+VCC0P9_LC_TCP1: length 3.5
  TOP w0.203: UT2.J3 v2(27.02,25.19)
  BOTTOM w0.102: v3(29.56,25.37) 29.16,25.37 28.95,25.58 27.99,25.58 27.51,25.09 CT37.1
  BOTTOM w0.254: CT37.1 27.25,24.97 v2(27.02,25.19)
+VCC0P9_LVR_TCP1: length 3.4
  TOP w0.152: 26.01,27.18 25.78,26.95 25.78,26.62 25.63,26.47 UT2.M6 UT2.L6
  TOP w0.279: 26.01,27.18 26.29,27.45 26.29,27.94 CT47.1 27.02,27.96 CT48.1
+VCC0P9_SVR_TCP1_PHASE: length 0.5
  TOP w0.152: UT2.L1 UT2.M1
+VCC0V9_SVR_TCP1: length 6.7
  TOP w0.203: UT2.G9 23.82,24.49 v2(23.69,24.49) ; UT2.G6 v2(25.07,24.54) ; UT2.E9 v2(23.77,23.24) ; UT2.F6 v2(25.07,23.24) ; UT2.G3 v2(27.02,24.54) ; UT2.E3 v2(27.02,23.24)
  BOTTOM w0.279: v2(25.07,24.54) UT2.G6 CT42.1 UT2.F6 v2(25.07,23.24) ; CT41.1 CT46.1 27.12,23.34 v2(27.02,23.24) ; CT45.1 27.11,24.46 v2(27.02,24.54) ; CT43.1 23.37,24.17 v2(23.69,24.49)
  vias: v3(31.54,25.96) v4(32.64,27) v4(32.64,26.24) v4(32.64,25.47)
+VCC1P05_OUT_FET: length 65.8
  TOP w0.279: v2(62.81,50.01) 62.94,50.01 63.67,49.28 RU222.1
  PWR04 w0.279: 60.63,49.02 61.09,49.48 62.53,49.48 62.81,49.76 v2(62.81,50.01)
  PWR04 w0.508: v2(81.58,41.91) 80.39,40.71 77.67,40.71 77.29,41.09 73.15,41.09 72.77,40.71 70.81,40.71 67.61,43.91 62.2,43.91 60.04,46.07 60.04,48.44 60.63,49.02 60.63,53.74 58.16,56.21 57.76,56.21 57.2,56.77 57.2,60.02 56.69,60.53 55.62,60.53 53.95,62.2 51.41,62.2 v4(47.95,65.66) v4(47.95,68.6)
  BOTTOM w0.191: UU1.BY2 UU1.CB2 UU1.CC1
  BOTTOM w0.254: UU1.CC1 81.48,42.01 v2(81.58,41.91)
  BOTTOM w0.381: v4(47.95,68.6) 47.8,68.76 PU904.2 ; v4(47.95,65.66) 47.5,65.2 PU901.2
  vias: v3(47.95,67.59)
+VCC1P05_OUT_PCH: length 2.1
  BOTTOM w0.305: UU1.DF31 UU1.DG31 UU1.DG29 UU1.DF29
+VCC1P05_OUT_SFR: length 5.6
  BOTTOM w0.203: 80.81,41.95 UU1.CD1 UU1.CD2
  BOTTOM w0.254: 80.81,41.95 80.81,41.64 81.72,40.73 81.72,39.3 v3(81.89,39.14) 81.72,38.97 CU56.1 CU57.1
+VCC1P8A: length 10
  BOTTOM w0.178: v2(85.6,38.33) 85.6,39.84 UU1.BW1 UU1.BW2
  BOTTOM w0.279: UU1.BM9 v2(87.3,45.71) ; UU1.BG9 v2(89.13,45.71) ; UU1.BJ9 v2(88.22,45.71) ; v2(85.6,38.33) 85.79,38.14 CU101.1 CU103.1 v3(87.86,37.47)
  vias: v4(38.2,64.39) v4(38.81,64.39)
+VCC3P3_ANA_TCP0: length 4.2
  TOP w0.076: UT2.L2 27.71,25.4 28.14,25.4 28.27,25.52 28.78,25.52
  TOP w0.102: CT31.1 30.48,24.58 29.69,25.37 v3(29.41,25.37) 28.93,25.37 28.78,25.52
+VCC3P3_LC_TCP1: length 14.4
  TOP w0.203: v2(26.37,23.19) 26.1,22.92 UT2.E5
  TOP w0.254: RT85.1 RT84.1 ; RT86.1 RT87.1 31.62,18.62 31.24,18.23 v1(30.99,18.23)
  TOP w0.279: RT84.1 28.32,17.02 v2(28.29,16.99)
  ART05 w0.254: v2(26.37,23.19) 26.41,23.19 26.99,22.62
  ART05 w0.381: v2(28.29,16.99) RT85.1 27.81,22.04 27.43,22.43 27.18,22.43 26.99,22.62
  BOTTOM w0.254: v2(26.37,23.19) 26.37,23.19 CT30.1
  BOTTOM w0.381: v2(28.29,16.99) 28.29,17.04 29.49,18.23 v3(29.87,18.23) v1(30.99,18.23)
+VCC3P3_LDO_OUT: length 359.4
  TOP w0.102: v3(179.8,11.02) 180.03,11.25 180.74,11.25 180.85,11.35 RA247.1
  TOP w0.279: DU2.2 46.69,5.19 48.39,3.5 v4(48.39,2.23) ; RA247.1 v4(181.74,12.01) ; CE25.1 v4(16.76,83.26) ; MR1.1 v4(2.54,93.45) ; RT5.1 39.72,33.12 v4(39.5,33.35)
  ART03 w0.279: v4(47.62,45.03) 47.62,43 46.61,41.98 41.02,41.98 39.24,40.21 39.24,34.62 39.5,34.36 v4(39.5,33.35) 38.99,32.84 36.55,32.84 34.49,30.78 34.49,29.03 34.44,28.98 34.44,23.72 28.75,18.03 28.75,16.79 26.62,14.65 24.74,14.65 23.95,15.44 v4(22.35,15.44) ; v4(2.54,93.45) 3.68,92.31 3.68,85.54 5.46,83.77 16.25,83.77 v4(16.76,83.26)
  ART03 w0.381: v4(16.76,83.26) 17.27,82.75 17.27,74.47 14.1,71.3 14.1,67.38 16.13,65.35 16.13,61.26 15.49,60.63 v4(15.49,59.51)
  PWR04 w0.508: v1(16.38,15.06) 18.41,15.06 19.3,15.95 21.84,15.95 v4(22.35,15.44) 22.35,12.98 23.16,12.16 25.75,12.16 29.72,8.2 29.72,3.25 30.76,2.21 42.42,2.21 43.28,3.07 47.55,3.07 v4(48.39,2.23) 72.41,2.23 73.91,3.73 78.74,3.73 80.29,2.18 133.83,2.18 135.89,4.24 144.98,4.24 146.61,2.61 153.41,2.61 154.05,3.25 v2(154.05,3.99)
  ART06 w0.508: v1(16.38,15.06) 16.61,15.29 16.61,16.58 16.61,31.32 18.67,33.37 18.67,40.59 17.52,41.73 17.52,45.54 15.87,47.19 15.87,55.32 15.49,55.7 v4(15.49,59.51)
  BOTTOM w0.254: PU201.11 47.53,45.12 v4(47.62,45.03) 47.62,44.45 PC215.1
  BOTTOM w0.279: v1(16.38,15.06) 15.75,14.42 PR1013.2
  BOTTOM w0.508: v2(154.05,3.99) 154.05,4.01 153.8,4.26 153.8,5.48 156.64,8.33 156.64,10.15 157.61,11.12 157.61,11.88 157.27,12.21 157.27,21.21 159.51,23.44 161.06,23.44 161.11,23.39 ; 161.11,23.39 v4(161.62,22.88) ; 161.11,23.39 161.32,23.59 168.88,23.59 175,17.47 178.31,17.47 180.59,15.19 180.59,13.15 v4(181.74,12.01)
+VCC3V3_SX_TCP1: length 51.8
  TOP w0.203: UT2.E6 v2(25.07,22.59)
  TOP w0.279: RT56.1 19.25,25.65 19.66,25.25 v4(20.06,25.25) ; RT62.2 26.8,17.19 v2(26.57,16.96) 26.29,17.24 RT64.2 ; v2(26.35,25.27) 26.05,24.97 UT2.J5
  ART03 w0.279: v4(30.35,27.51) 28.49,25.65 26.72,25.65 v2(26.35,25.27) 25.59,26.03 23.19,26.03 22.91,25.75 22.91,23.09 22.71,22.88 ; 22.71,22.88 23.16,22.43 24.91,22.43 v2(25.07,22.59) ; 22.71,22.88 21.49,22.88 20.06,24.31 v4(20.06,25.25)
  ART05 w0.279: v2(25.07,22.59) 23.65,22.59 23.24,23 23.24,25.47 23.75,25.98 25.14,25.98 25.65,26.49 25.65,26.87 26.18,27.4 26.18,30.57 27.07,31.47 27.07,33.91 v4(26.67,34.31)
  ART06 w0.279: v2(26.57,16.96) 26.67,17.07 26.67,17.6 25.27,19 25.27,19.25 23.29,21.23 23.29,22.21 23.67,22.59 v2(25.07,22.59)
  BOTTOM w0.279: CT36.1 25.03,22.55 v2(25.07,22.59) ; RT68.1 26.74,34.39 v4(26.67,34.31) ; 28.4,27.2 28.4,26.34 28.04,25.98 27.07,25.98 26.36,25.27 v2(26.35,25.27) ; RT62.2 26.8,17.19 v2(26.57,16.96)
  vias: v3(29.64,27.25) v4(30.35,28.27)
+VCC3V3A_S0_TCP1: length 5.9
  TOP w0.178: UT2.J7 24.51,25.11 v2(24.51,25.22)
  BOTTOM w0.279: v2(24.51,25.22) 24.38,25.35 CT51.1 CT50.1 25.22,26.29 25.65,26.72 25.65,26.87 26.15,27.37 26.15,27.77 25.78,28.14 CT52.1 26.22,28.34 26.29,28.27 RT79.2
+VCCA_CLKLDO_1P8: length 2.6
  BOTTOM w0.254: UU1.DW15 63.38,48.97 62.2,48.97 v2(61.4,48.16)
  vias: v3(63.8,48.18)
+VCCDPHY_1P24: length 1.9
  TOP w0.279: CU49.1 63.24,57.99 v2(62.74,57.48)
  BOTTOM w0.279: v2(62.74,57.48) 63.17,57.04 UU1.DW32
+VCCDSW_1P05: length 1.2
  TOP w0.279: CU50.1 71.63,58.37 v2(71.47,58.52)
  BOTTOM w0.305: UU1.DD34 71.16,58.21 v2(71.47,58.52)
+VCCFPGM: length 2.1
  BOTTOM w0.203: UU1.AB34 v2(101.48,57.74) ; UU1.T34 v2(104.23,57.83) ; UU1.V34 v2(103.31,57.83) ; UU1.U35 v2(103.77,58.23)
  vias: v2(102.4,57.78) v2(102.85,58.21) v3(104.49,58.39)
+VCCIN: length 110.3
  TOP w0.279: CU164.1 109.09,41.62 v2(109.01,41.54) ; PC617.2 106.06,15.07 v4(106.93,15.95) 106.81,16.08 PC612.2 106.8,16.83 PR641.2 PR643.1 ; CU91.1 100.82,42.27 v2(101.55,41.54) 102.06,42.04 CU162.1 ; v2(106.5,41.54) 106.3,41.74 CU163.1 ; PR648.1 103.25,16.83 PC616.2 103.25,16.83 PR646.2 102.21,16.67 102.21,16.1 102.49,15.82 PC613.2 v2(102.98,15.2) ; CU67.1 104.49,41.76 v2(104.27,41.54)
  ART03 w0.203: v4(118.87,25.47) 118.51,25.12 118.51,24.2 113.94,19.63 109.6,19.63 106.93,16.96 103.88,16.96 102.79,15.87 102.79,15.39 v2(102.98,15.2)
  ART03 w0.279: v4(127.25,25.47) 127.48,25.25 127.48,19.6 123.73,15.85 110.77,15.85 110.5,15.58 107.3,15.58 v4(106.93,15.95)
  ART06 w0.279: v4(98.86,18.04) 100,18.04 100.33,18.36 100.33,19.89 99.69,20.52 99.69,27.76 100.96,29.03 105.92,29.03 110.74,33.86 110.74,38.43 111,38.68 v4(118.24,38.68)
  BOTTOM w0.152: UU1.AB1 v2(101.55,41.54)
  BOTTOM w0.203: UU1.M1 v2(106.5,41.54)
  BOTTOM w0.254: UU1.G1 v2(109.01,41.54) ; UU1.U1 104.14,42.27 104.14,41.67 v2(104.27,41.54)
  BOTTOM w0.279: 119.89,25.47 v4(118.87,25.47) ; 126.24,25.47 v4(127.25,25.47) ; v2(82.71,45.72) 82.71,45.72 82.27,46.03 ; UU1.BW9 83.63,45.72 v2(83.64,45.72) ; v4(98.86,18.04) 98.03,18.87 PR630.1
  vias: v1(75.18,58.62) v2(76.06,58.53) v2(76.98,58.53) v2(77,59.16) v2(77.94,59.17) v2(77.94,58.53) v2(78.75,59.17) v2(78.76,58.53) v2(79.07,47.57) v2(79.06,46.96) v2(80,59.14) v2(80.06,58.51) v2(79.98,47.57) v2(79.98,46.96) v2(80.87,57.66) v2(80.89,58.53) v2(80.89,46.96) v2(82.27,58.62) v2(83.18,58.64) v2(84.1,58.64) v2(85.47,47.65) v2(85.47,46.99) v2(86.38,47.65) v2(86.38,46.99) v2(98.93,54.68) v2(98.93,53.79) v2(99.69,54.68) v2(99.69,53.79) v2(100.58,54.68) v2(100.58,53.79) v2(100.84,51.89) v2(101.47,54.3) v2(101.47,53.41) v2(101.47,52.52) v2(101.98,48.59) v2(102.23,55.19) v2(102.23,54.3) v2(102.23,53.41) v2(102.23,52.52) v2(102.87,48.59) v2(103.12,55.19) v2(103.12,54.3) v2(103.12,53.41) v2(103.12,52.52) v2(104.01,55.19) v2(104.01,54.3) v2(104.01,53.41) v2(104.01,52.52) v2(104.9,55.19) v2(104.9,54.3) v2(104.9,53.41) v2(104.9,52.52) v2(104.9,51.64) v2(105.79,55.19) v2(105.79,54.3) v2(105.79,53.41) v2(105.79,52.52) v2(105.79,51.64) v2(105.79,50.67) v2(105.79,49.98) v2(106.68,55.19) v2(106.68,54.3) v2(106.68,53.41) v2(106.68,52.52) v2(106.68,51.64) v2(106.68,50.67) v2(106.68,49.98) v2(108.41,56.11) v2(108.42,55.23) v2(108.42,54.31) v2(108.42,52.48) v2(108.4,50.62) v2(109.07,54.31) v2(109.07,52.48) v2(109.09,56.11) v2(109.09,55.19) v2(109.73,56.11) v2(109.72,55.23) v2(109.72,54.31) v2(109.72,53.4) v2(109.72,52.48) v2(109.72,51.62) v2(110.36,56.11) v2(110.36,55.19) v2(110.37,54.31) v2(110.37,53.4) v2(110.37,52.48) v2(110.37,51.62) v2(110.37,50.65) v2(111,56.11) v2(111.02,55.23) v2(111.02,54.31) v2(111,52.5) v2(111.02,50.65) v2(111.63,55.19) v2(111.67,54.31) v2(111.67,52.48) v2(111.67,50.65) v2(111.68,56.11) v2(112.32,55.23) v2(112.32,54.31) v2(112.32,52.48) v2(112.39,56.11) v2(112.39,51.64) v2(112.85,53.45) v2(113.42,52.03) v2(113.42,51.04) v2(113.48,53.97) v2(113.5,52.89) v2(114.37,52.05) v2(114.37,51.06) v3(127.1,40) v4(80.77,47.55) v4(114.49,54.48) v4(115.07,55.89) v4(115.51,54.48) v4(116.07,55.88) v4(116.39,53.57) v4(116.48,54.56) v4(117.29,52.61) v4(117.42,53.57) v4(117.49,54.55) v4(118.24,37.79) v4(118.24,36.9) v4(118.24,36.01) v4(118.3,52.61) v4(118.44,53.6) v4(118.51,54.55) v4(118.62,45.16) v4(118.62,29) v4(119.12,38.68) v4(119.12,37.79) v4(119.12,36.9) v4(119.12,36.01) v4(119.44,53.6) v4(119.39,52.59) v4(119.53,54.58) v4(119.51,29) v4(119.76,45.16) v4(120.47,52.58) v4(120.39,32.97) v4(120.39,32.1) v4(120.39,31.06) v4(120.39,30.02) v4(120.39,29) v4(120.54,54.58) v4(120.54,53.58) v4(120.9,45.16) v4(121.28,32.97) v4(121.28,32.1) v4(121.28,31.06) v4(121.28,30.02) v4(121.28,29) v4(121.63,54.56) v4(122.05,45.16) v4(122.17,32.97) v4(122.17,32.1) v4(122.17,31.06) v4(122.17,30.02) v4(122.17,29) v4(122.55,23.31) v4(123.06,32.97) v4(123.06,32.1) v4(123.06,31.06) v4(123.06,30.02) v4(123.06,29) v4(123.32,45.16) v4(123.44,23.31) v4(123.95,32.97) v4(123.95,32.1) v4(123.95,31.06) v4(123.95,30.02) v4(123.95,29) v4(124.33,23.31) v4(124.46,45.16) v4(124.84,29) v4(125.22,23.31) v4(125.47,38.68) v4(125.47,37.79) v4(125.47,36.9) v4(125.47,36.01) v4(125.73,29) v4(126.11,23.31) v4(126.49,38.68) v4(126.49,37.79) v4(126.49,36.9) v4(126.49,36.01) v4(126.62,29) v4(127.51,37.79) v4(127.51,36.9) v4(127.51,36.01) v4(127.51,29) v4(128.4,36.9) v4(128.4,36.01) v4(128.4,29)
+VCCIN_AUX: length 40.7
  TOP w0.254: PR515.2 78.61,29.65 PR520.1 79.37,29.65 PC505.2 81.13,29.65 PR517.2 81.14,29.04 PC530.1 84.2,28.78 v2(84.45,29.03)
  TOP w0.279: CU111.1 103.81,48.56 v4(103.83,48.59)
  ART06 w0.254: v4(92.33,24.46) 92.07,24.2 91.01,24.2 88.47,26.74 86.49,26.74 84.45,28.78 v2(84.45,29.03)
  BOTTOM w0.191: v2(96.65,40.97) 97.03,41.36 97.03,42.06 ; v2(95.91,40.97) 95.96,40.97 96.38,41.39 96.38,42.06 ; 98.33,42.06 97.68,42.06 ; 97.68,42.06 97.03,42.06 ; 97.68,42.06 97.68,41.4 v2(97.43,41.15) ; 96.38,42.06 95.73,42.06 95.73,41.58 95.25,41.09 v2(95.25,40.94) ; 96.38,42.06 97.03,42.06
  BOTTOM w0.254: PL501.2 v4(92.33,24.46) ; v2(73.91,41.93) 74.06,42.08 UU1.CV1 ; v2(76.73,41.93) 76.53,42.14 UU1.CN1 ; UU1.CH1 v2(79.01,41.91) ; v2(71.73,41.4) 71.58,41.54 UU1.DC1
  BOTTOM w0.279: 88.85,33.86 86.51,33.86 v3(83.36,30.71) 82.46,29.8 PR518.2
  BOTTOM w0.483: 87.5,26.5 88.76,26.5
  vias: v2(71.14,47.44) v2(71.25,48.59) v2(71.25,48.08) v2(71.63,49.1) v2(71.88,48.08) v2(71.88,47.44) v2(72.64,47.44) v2(73.28,47.57) v2(74.04,47.57) v2(74.8,47.57) v2(75.56,47.57) v2(76.33,47.65) v2(77.21,47.65) v2(91.87,47.62) v2(91.87,47.04) v2(91.9,45.79) v2(93.47,38.48) v2(93.7,47.65) v2(93.8,40.92) v2(94.36,38.48) v2(94.61,47.65) v2(95.25,38.48) v2(96.39,38.48) v4(89.66,31.54) v4(89.66,30.68) v4(89.66,29.82) v4(90.55,31.54) v4(90.55,30.68) v4(90.55,29.82) v4(91.44,31.54) v4(91.44,30.68) v4(91.44,29.82) v4(92.33,31.54) v4(92.33,30.68) v4(92.33,29.82) v4(93.22,31.54) v4(93.22,30.68) v4(93.22,29.82) v4(104.39,49.22) v4(104.77,48.49)
+VCCIN_AUX_VCC:
  vias: v3(74.95,23.59)
+VCCIN_VIN: length 13.9
  ART06 w0.279: v4(108.46,14.15) 109.75,14.15 110.46,13.43 111.96,13.43 112.88,12.52 116.84,12.52 v4(117.85,13.54)
  BOTTOM w0.279: PR602.1 108.1,15.53 108.1,14.5 v4(108.46,14.15)
  vias: v3(122.2,12.62) v4(117.85,14.42) v4(118.74,14.42) v4(118.74,13.54) v4(119.63,14.42) v4(119.63,13.54) v4(120.52,14.42) v4(120.52,13.54) v4(121.41,14.42) v4(121.41,13.54)
+VCCIO_OUT: length 19.9
  TOP w0.102: RU233.2 99.64,45.36 99.34,45.36 98.42,45.36 97.51,45.36 RU239.2 ; 105.57,47.15 arc(105.36,47.01) 105.11,46.96 104.9,46.96 arc(104.8,46.98) 104.72,47.04 104.57,47.18 104.57,47.19 104.29,47.47 RU235.2 104.28,47.51 arc(104.47,47.64) 104.7,47.69 105.08,47.69 arc(105.14,47.67) 105.19,47.64 105.39,47.44 arc(105.44,47.36) 105.46,47.27
  TOP w0.152: RU213.2 108.23,43.3 108.89,43.96 109.57,43.96 v3(109.93,44.32)
  TOP w0.203: RU235.2 104.09,47.47 arc(103.83,47.52) 103.61,47.67 103.58,47.7 arc(103.44,47.79) RU237.2 102.87,47.83 RU238.2 102.51,47.62 102.31,47.83 101.52,47.83 RU240.2
  TOP w0.254: 105.46,47.27 105.71,47.01 RU216.2 105.97,46.5 v2(106.42,46.05) ; 107.92,44.68 107.64,44.4 RU215.2 ; 107.92,44.68 109.57,44.68 v3(109.93,44.32) ; 107.92,44.68 107.57,45.03 107.57,45.29 106.81,46.05 v2(106.42,46.05) ; RU234.2 100.9,45.54 v2(101.02,45.66) ; RU214.2 105.96,45.59 v2(106.42,46.05)
  BOTTOM w0.254: UU1.AD7 100.85,45.55 v2(101.02,45.66)
+VCCLDOSTD_OUT_0P85: length 3.2
  TOP w0.102: v3(64.06,60.37) 64.06,59.97 63.23,59.14 CU41.1
  TOP w0.381: CU41.1 62.74,59.62 v2(62.74,59.66)
  BOTTOM w0.203: UU1.DW37 63.58,59.66 v2(62.74,59.66)
+VCCPGPPR: length 2.4
  TOP w0.305: v2(70.27,53.76) 70.27,53.87 70.58,54.18 CU171.1 RU230.1 RU231.1
  BOTTOM w0.305: v2(70.27,53.76) 70.27,53.93 UU1.DF26
+VCCPRIM_1P8: length 12
  TOP w0.279: CU46.1 70.03,51.13 v2(70.27,51.36) ; v2(71.48,59.14) 71.48,59.17 71.95,59.64 CU47.1 ; v2(70.27,50.51) 69.57,50.51 v2(69.55,50.52) ; CU48.1 68.63,50.98 v2(69.02,51.36)
  TOP w0.305: v2(70.27,52.17) 70.27,52.24 70.69,52.65 71.12,52.65 71.25,52.78 RU231.2
  BOTTOM w0.203: v2(69.55,50.52) 69.56,50.44 UU1.DG17 ; UU1.DF34 70.51,58.6 v2(70.54,58.6) 70.57,58.6 70.59,58.62 70.8,58.62 UU1.DD35 71.45,59.15 v2(71.48,59.14)
  BOTTOM w0.254: v2(69.55,50.52) 69.55,50.63 69.3,50.89 UU1.DG18 ; UU1.DG18 69.35,50.99 69.89,50.99 UU1.DF18 69.95,51.02 70.27,51.34 v2(70.27,51.36) ; UU1.DG18 69.02,51.21 v2(69.02,51.36) 69.02,51.48 UU1.DG20 69.43,51.62 69.81,51.62 UU1.DF20 70.27,52.09 v2(70.27,52.17) ; v2(70.27,50.51) 70.27,50.43 UU1.DF17
  BOTTOM w0.279: UU1.DF17 UU1.DF15
  vias: v2(61.72,50.09) v2(62.24,50.07)
+VCCPRTC_3P3: length 5.5
  TOP w0.279: SHU2.2 CU52.1 66.72,58.19 67.69,57.22 v3(67.82,57.22) 68.02,57.43 69.14,57.43 69.33,57.23 v2(69.62,57.23) 69.85,57.46 CU51.1
  BOTTOM w0.279: UU1.DG33 69.3,57.56 v2(69.62,57.23)
+VCCRTC: length 193.5
  TOP w0.127: CU37.1 44.42,3.5 v3(44.3,3.38)
  TOP w0.279: v2(54.91,65.2) 55.52,65.2 57.3,63.42 57.3,60.25 57.78,59.76 58.14,59.76 59.92,57.99 61.21,57.99 61.45,58.23 62.6,58.23 62.99,58.62 64.72,58.62 SHU2.1 ; 13.84,70.56 14.35,70.56 v2(14.86,70.05) ; v4(45.59,2.46) 45.72,2.59 CU37.1 ; RU156.2 RU89.2 54.46,77.29 54.14,76.97 52.64,76.97 v2(52.2,77.42)
  TOP w0.305: DU2.3 47.1,3.31 46.91,3.5 CU37.1
  ART03 w0.381: v2(52.2,77.42) 51.33,77.42 50.95,77.04 42.67,77.04 39.62,80.08 v4(27.13,80.08)
  ART06 w0.279: v4(27.13,80.08) 27.09,80.12 25.51,80.12 24.84,79.45 22.35,79.45 16.38,73.48 16.38,71.57 v2(14.86,70.05) 14.22,69.42 14.22,66.24 15.85,64.62 15.85,60.81 17.27,59.38 17.27,57.07 16.89,56.69 16.89,48.08 18.84,46.12 18.84,42.25 19.72,41.37 19.72,33.26 17.4,30.93 17.4,14.81 17.7,14.5 17.7,13.31 16.97,12.57 16.97,11.81 17.27,11.5 18.41,11.5 18.92,11 18.92,9.22 19.3,8.84 19.3,6.42 20.06,5.66 21.33,5.66 v4(21.46,5.53) 22.05,5.53 22.73,4.85 22.73,4.01 21.97,3.25 21.97,2.61 22.53,2.05 45.18,2.05 v4(45.59,2.46)
  BOTTOM w0.279: PR6157.2 14.12,8.66 14.68,9.22 15.21,9.22 15.49,8.94 15.49,6.58 16.3,5.76 21.23,5.76 v4(21.46,5.53) ; v2(52.2,77.42) 52.2,74.47 53.36,73.3 53.36,66.75 v2(54.91,65.2) 54.96,65.15 55.01,65.15 RU91.2
+VCCSFR_OC: length 6.6
  TOP w0.279: 79.75,62.94 79.75,62.5 v2(79.97,62.28)
  BOTTOM w0.203: UU1.CG49 79.36,65.86 79.35,65.87
  BOTTOM w0.254: v2(79.25,67.38) 79.25,66.75 79.35,66.65 79.35,65.87 ; v2(79.97,62.28) 79.69,62.28 UU1.CG42 UU1.CG41 ; UU1.CG41 79.52,61.35 79.87,61 v2(79.96,61) ; UU1.CG41 79.65,61.59 79.93,61.59 v2(79.97,61.62)
  BOTTOM w0.279: UU1.CG38 79.84,60.16 v2(79.96,60.04) 79.99,60.07 79.99,60.98 v2(79.96,61)
  vias: v1(50.7,74.85) v3(79.35,61.59) v4(43.74,70.74) v4(44.55,70.74) v4(50.7,75.44) v4(61.21,75.84)
+VCCST: length 86
  ART05 w1.016: 72.67,24.97 71.17,23.47 68.81,23.47 67.56,24.71 53.29,24.71 51,27 45.13,27 44.02,28.12 44.02,31.9 44.22,32.1 44.22,38.08 43.65,38.66 42.57,38.66 38.99,42.24 35.94,42.24 34.92,43.25 34.92,48.59 35.61,49.27 35.61,51.08 33.4,53.29 33.4,56.03 35.2,57.83 37.49,57.83 39.93,60.27 43.94,60.27 44.35,59.87 47.95,59.87 49.99,61.9
  vias: v1(51.97,66.16) v1(51.97,65.61) v1(108.3,36.04) v2(81.51,26.74) v2(108.3,35.48) v3(106.07,29.94) v4(82.04,26.92)
+VCCSTG_IO: length 29.2
  ART05 w0.508: v4(59.54,36.4) 58.93,37.01 58.93,43 58.11,43.82 58.11,47.27 57.61,47.77 56.72,47.77 55.5,48.99 55.5,50.54 55.77,50.81 55.77,52.51 55.37,52.91 v1(55.37,62.18)
  BOTTOM w0.381: v1(55.37,62.18) 55.37,62.94 PSH903.2
  vias: v3(84.73,35.18)
+VCCSTG_OUT_FUSE: length 2.1
  TOP w0.279: v3(107.9,59.1) 107.85,59.05 107.85,58.44
  BOTTOM w0.203: UU1.F33 v2(109.07,57.84) ; UU1.G33 v2(108.42,57.84)
  BOTTOM w0.254: v2(109.07,57.84) UU1.G33
+VCCSTG_OUT_LGC: length 13
  TOP w0.102: v1(115.44,35.89) v3(115.44,34.72)
  TOP w0.381: v1(115.44,35.89) 115.44,37.73 v2(109.6,43.57)
  BOTTOM w0.254: SHU9.1 115.44,35.38 v1(115.44,35.89) CU55.1 ; v2(109.6,43.57) 109.63,43.6 UU1.E5
+VCCSTG_TERM: length 14.1
  TOP w0.279: v2(105.54,37.46) 106.09,36.9 108.58,36.9 109.12,36.37 v2(109.12,36.01) 109.12,35.99 110.44,34.67 v3(111.81,34.67) 113.08,34.67 v1(114.3,35.89)
  BOTTOM w0.254: v2(109.12,36.01) 109.09,36.04 RU23.2 RU27.1 ; RU17.2 RU18.2 v1(114.3,35.89) 114.55,35.64 SHU9.2
  BOTTOM w0.279: RU30.1 v2(105.54,37.46)
+VDD: length 1.9
  BOTTOM w0.279: UV2.G9 147.62,64.6 v1(147.27,64.25) 146.8,64.71 UV2.G8 146.76,64.71 v1(146.31,64.27)
+VDDQ_CPU: length 54.4
  ART03 w0.279: v2(81.28,67.26) 80.64,67.89 78.62,67.89 73.67,72.84 71.63,72.84 70.86,73.61 65.86,73.61 62.69,76.78 v2(57.4,76.78)
  BOTTOM w0.12: UU1.AL49 96.87,67.35 v2(97.03,67.51) ; UU1.AF49 v2(99.37,67.38)
  BOTTOM w0.152: v2(81.28,67.26) 81.86,66.68 UU1.CB49 ; v2(94.37,67.51) UU1.AT49 ; v2(89.53,66.62) 89.36,66.45 UU1.BF49 ; v2(101.98,67.26) 101.87,67.15 UU1.AA49 ; UU1.BA49 91.57,65.73 91.57,66.49 v2(91.18,66.88) ; v2(106.96,67.05) UU1.L49 ; UU1.BM49 86.86,66.29 v2(86.99,66.42) ; UU1.BU49 v2(84.36,67.38)
  BOTTOM w0.203: UU1.CA39 82.46,60.81 v2(82.72,61.07) ; UU1.T49 104.38,66.35 105.03,67 v2(105.03,67.64)
  BOTTOM w0.254: UU1.L38 107.36,60.39 v2(107.42,60.42) ; v2(105.37,59.66) 105.72,59.24 UU1.N36
  BOTTOM w0.279: v2(57.4,76.78) 56.74,77.44 56.74,79.78 56.89,79.93 RD1.2
  vias: v2(85.46,60.44) v2(85.47,58.62) v2(86.1,58.62) v2(86.39,60.42) v2(86.87,58.62) v2(87.73,58.58) v2(88.76,58.58) v2(89.41,58.57) v2(90.17,58.57) v2(91.67,58.57) v2(92.33,58.57) v2(93.09,58.57) v2(94.23,58.57) v2(95.1,58.57) v2(95.86,58.57) v2(97.03,58.57) v2(97.79,58.57) v2(98.42,58.57) v2(99.19,57.86) v2(99.66,58.4) v2(100.11,57.89) v3(95.3,73.84) v3(100.12,73.78)
+VDDQ_LP4X: length 76
  TOP w0.279: v1(114.85,91.51) 114.93,91.42 CD16.1 ; v1(101.17,91.51) 101.74,92.08 CD64.1 102.68,92.08 v1(102.76,92.16) ; CD63.2 102.87,81.68 v1(102.79,81.76) ; v1(71.46,91.51) 71.37,91.59 CD4.1 ; CD94.2 85.22,81.68 v1(85.14,81.76) ; v1(124.42,81.11) 124.2,81.32 CD101.2 ; v1(103.56,91.51) 103.76,91.32 103.76,90.88 ; CD57.1 65.92,91.57 v1(65.86,91.51) ; CD105.2 122.47,82.75 v1(122.82,82.41) ; v1(97.16,91.51) 97.28,91.39 CD60.2 ; v1(106.76,91.51) 106.89,91.39 CD12.1 ; v1(89.11,91.51) 89.03,91.59 CD8.1 ; v1(81.11,79.81) 81.13,79.83 CD97.2 ; CD99.2 81.82,90.12 v1(81.91,90.21) ; v1(83.54,80.46) 83.6,80.39 CD100.1 85.08,80.39 v1(85.14,80.46) ; v1(64.26,92.81) 64.11,92.66 CD53.2 ; v1(104.36,79.81) 104.32,79.76 CD65.1 102.81,79.76 v1(102.76,79.81) ; v1(106.76,81.11) 106.55,81.32 CD62.2 ; v1(120.45,81.76) 120.52,81.68 CD102.2 120.52,80.53 v1(120.45,80.46) ; CD96.2 79.17,91.13 v1(79.54,91.51) ; v1(67.49,80.46) 67.42,80.39 CD56.1 65.95,80.39 v1(65.89,80.46) ; CD104.2 117.08,80.59 v1(117.22,80.46) ; v1(85.14,92.81) 85.22,92.73 CD95.2 85.22,91.58 v1(85.14,91.51) ; v1(71.46,81.11) 71.25,80.89 CD55.2 ; v1(64.26,90.21) 64.17,90.12 CD50.2 ; v1(67.49,91.51) 67.56,91.58 CD52.2 67.56,92.73 v1(67.49,92.81) ; v1(67.49,81.76) 67.56,81.68 CD54.2 ; CD98.2 88.9,80.89 v1(89.11,81.11) ; v1(69.06,79.81) 69.08,79.83 CD51.2 ; v1(120.42,91.51) 120.23,91.32 CD107.1 119.01,91.32 v1(118.82,91.51) ; v1(122.82,92.16) 122.55,92.42 122.55,92.63 ; v1(118.82,81.76) 118.49,81.43 CD103.2 118.82,80.77 v1(118.82,79.81) ; v1(101.16,80.46) 100.96,80.66 100.96,81.56 v1(101.16,81.76) ; CD61.2 98.74,79.83 v1(98.76,79.81)
  BOTTOM w0.229: UD3.B3 v1(105.16,92.16) ; UD3.F10 v1(98.76,90.21) ; UD1.W12 v1(61.89,81.11) ; UD4.D12 v1(114.85,91.51) ; UD3.AA5 v1(102.76,79.81) ; UD4.B5 120.42,92.07 v1(120.42,91.51) UD4.D5 ; UD4.U3 v1(122.82,82.41) ; UD2.U10 v1(81.11,82.41) ; v1(124.42,81.11) 124.42,81.11 UD4.W1 ; UD4.W12 114.84,81.11 v1(114.82,81.11) ; UD2.AA3 v1(87.51,80.46) ; UD3.W5 v1(102.79,81.76) ; UD1.W1 v1(71.46,81.11) ; UD4.AA5 v1(120.45,80.46) ; UD3.AA10 v1(98.76,79.81) ; UD1.B10 v1(64.26,92.81) ; UD3.U10 v1(98.76,82.41) ; UD3.AA3 v1(104.36,79.81) ; UD3.D8 v1(101.17,91.51) ; UD3.B5 v1(102.76,92.16) ; UD2.AA5 v1(85.14,80.46) ; UD4.D8 v1(118.82,91.51) ; UD1.D8 v1(65.86,91.51) ; UD3.D1 v1(106.76,91.51) ; UD2.F3 v1(87.51,90.21) ; UD1.D5 v1(67.49,91.51) ; UD4.W8 v1(118.82,81.76) ; UD3.W12 v1(97.19,81.11) ; UD3.D5 v1(103.56,91.51) ; UD3.D12 v1(97.16,91.51) ; UD3.F3 v1(105.16,90.21) ; UD2.B5 v1(85.14,92.81) ; UD4.D1 v1(124.42,90.86) ; UD3.B10 v1(98.76,92.16) ; UD1.AA3 v1(69.06,79.81) ; UD4.F3 v1(122.02,90.21) ; v1(65.86,92.81) UD1.B8 ; UD1.AA8 v1(65.89,80.46) ; UD4.B3 v1(122.82,92.16) ; UD1.D12 v1(61.89,91.51) ; UD3.U3 v1(105.16,82.41) ; UD2.W1 v1(89.11,81.11) ; UD2.D12 v1(79.54,91.51) ; UD2.D8 v1(83.51,91.51) ; UD3.W8 v1(101.16,81.76) ; UD4.B8 v1(118.82,92.81) ; UD1.B5 v1(67.49,92.81) ; UD4.AA10 v1(117.22,80.46) ; UD1.W8 v1(65.89,81.11) ; UD2.U3 v1(87.51,82.41) ; UD2.W5 v1(85.14,81.76) ; UD2.D5 v1(85.14,91.51) ; UD1.AA5 v1(67.49,80.46) ; UD4.W5 v1(120.45,81.76) ; UD2.B3 v1(87.54,92.16) ; UD1.W5 v1(67.49,81.76) ; UD1.B3 v1(69.06,92.81) ; UD3.AA8 v1(101.16,80.46) ; UD1.U10 v1(63.46,82.41) ; UD2.W12 v1(79.54,81.11) ; UD1.F10 v1(64.26,90.21) ; UD3.W1 v1(106.76,81.11) ; UD2.F10 v1(81.91,90.21) ; UD1.D1 v1(71.46,91.51) ; UD2.AA8 v1(83.54,80.46) ; UD1.AA10 v1(63.46,79.81) ; UD4.F10 v1(116.45,90.21) ; UD1.F3 v1(69.86,90.21) ; UD2.B10 v1(81.91,92.81) ; UD2.AA10 v1(81.11,79.81) ; UD3.B8 v1(101.17,92.81) ; UD4.B10 v1(117.25,92.81) ; UD2.W8 v1(83.54,81.11) ; UD1.U3 v1(69.86,82.41) ; UD2.B8 v1(83.51,92.81) ; UD4.AA3 v1(122.82,79.81) ; UD2.D1 v1(89.11,91.51) ; UD4.U10 v1(117.22,82.41) ; UD4.AA8 v1(118.82,79.81)
  BOTTOM w0.279: v3(46.68,71.6) 46.68,73 RD11.2
  vias: v4(47.65,74.85) v4(48.31,74.85) v4(48.97,74.85)
+VDDQ_TX:
  vias: v3(43.18,75.36)
AGND_CHG: length 20
  BOTTOM w0.191: v2(50.67,14.09) 50.62,14.05 PU101.5
  BOTTOM w0.203: PU101.14 46.65,11.52 v2(46.63,11.5) ; PU101.15 46.25,11.91 45.97,11.63 v2(45.97,11.5)
  BOTTOM w0.279: PC103.2 41.22,15.36 v2(41.02,15.57) ; PC154.2 44.83,10.17 v2(44.83,9.65) ; PC119.2 v2(51.06,10.25) 51.05,10.23 PC112.2 PR121.1 PC118.2 ; v2(50.67,14.09) PC117.1 51.24,13.85 52.13,12.96 PR112.1 PC133.2 ; PC113.1 v4(42.16,10.69) ; PC114.2 42.76,11.91 PC115.2 42.44,11.86 42.16,11.58 v4(42.16,11.38) 41.98,11.38 41.4,10.79 v3(41.4,9.42) ; PC114.2 41.91,12.52 41.67,12.76 PC104.2 ; PC114.2 PR117.1 ; v2(50.67,15.82) 50.82,15.67 PC127.1 51.89,16.32 PC128.2
GND: length 2143.8
  TOP w0.152: v2(27.81,26.49) 27.79,26.49 27.47,26.17 UT2.M2 UT2.M3 ; v2(22.22,22.42) UT2.D12 UT2.D11 ; v2(28.49,25.18) UT2.K1 UT2.K2 ; v2(22.35,26.36) 22.61,26.1 UT2.M12 ; 151.34,63.36 151.8,63.83 152.67,63.83 CV117.2 ; v2(28.42,22.42) UT2.D1 UT2.D2 ; v2(22.35,23.34) UT2.F12 UT2.F11 23.33,23.35 23.61,23.64 23.93,23.64 24,23.57 UT2.F9 ; UT2.L12 22.64,25.64 22.38,25.37 v2(22.38,25.18) UT2.K12 UT2.K11 ; UT2.B2 UT2.B1 v2(28.45,21.5) ; UT2.F2 UT2.F1 v2(28.46,23.34) ; v2(22.35,24.26) UT2.H12 UT2.H11 23.64,23.95 24,23.95 24.06,23.89 v2(24.42,23.89) ; v4(22.1,21.03) 22.57,21.5 UT2.B12 UT2.B11 UT2.A11 ; UT2.H2 UT2.H1
  TOP w0.203: v2(14.63,11.53) 14.63,11.5 13.99,10.87 UT7.13 ; v4(15.24,51.31) 16.25,51.31 ESDI9.2 ; QV21.2 183.77,58.5 184.02,58.75 184.02,59.27 v1(183.81,59.47) ; ESDT2.2 v4(14.1,23.79) ; v4(11.58,11.38) 12.06,11.86 UT7.18 ; ESD1.3 141.96,9.83 v2(142.11,9.98) ; v2(27.02,23.92) 26.7,23.59 UT2.F3 ; v2(156.46,16.23) 156.51,16.18 CE38.2 ; v4(17.45,53.34) 17.35,53.24 ESDI12.2 ; UT2.F5 26.05,23.59 v2(26.37,23.92) ; v4(133.73,3.63) 134.06,3.63 135.56,5.13 144.74,5.13 JP2.5 ; v4(11.81,8.33) 12.06,8.58 UT7.8 ; CA62.2 173.94,22.51 v2(174.23,22.8) ; v2(159,29.03) 159.5,29.03 159.7,28.83 CL1.2 RL2.1 159.07,28.35 QL9.2 ; UE1.D6 162.97,19.12 162.79,19.3 v2(162.79,19.33) ; ESDT3.2 v4(13.6,21.27) ; v2(165.56,18.56) 165.48,18.56 165.16,18.24 UE1.E10 ; QE2.2 v4(182.39,12.4) ; v1(162.68,24.61) 162.41,24.33 RE121.2 ; ESDI11.2 17.27,54.6 v1(17.42,54.46) ; v4(17.52,49.48) 17.24,49.76 ESDI10.2 ; v2(162.91,17.27) 162.89,17.24 UE1.G5 UE1.F5 UE1.G4 UE1.H5 ; UT2.F7 24.75,23.52 v2(24.42,23.19) 24.1,23.52 UT2.F9 ; v2(158.41,24.75) 158.9,24.25 PC155.2 ; v2(24.42,23.89) UT2.G7 24.75,24.26 v2(24.45,24.56) 24.41,24.56 UT2.J9 ; CE32.2 CE26.2 v4(169.87,21.66) ; v4(128.18,3.5) 105.79,3.5 v2(105.41,3.88) 105.38,3.86 v2(100.33,3.86) 92.61,3.86 92.06,4.41 82.16,4.41 79.96,6.6 75.06,6.6 73.86,5.41 v2(73.53,5.41) ; ESDI14.2 15.57,55.12 v4(15.19,54.73) ; v2(170.05,13.79) 170.13,13.79 170.84,13.08 170.84,4.08 169.85,3.1 155.85,3.1 v4(155.7,3.25) 152.65,3.25 152.14,3.76 v2(152.14,4.01) 151.79,4.01 150.87,3.1 148.28,3.1 146.6,4.77 v2(145.67,4.77) ; CE42.2 166.16,12.03 v1(166.26,11.94) ; v4(169.87,20.85) 169.57,20.55 CE46.2 ; ESDI13.2 v4(17.42,56.48) ; UT2.G5 v2(26.37,24.54) ; ESDI7.2 v4(17.65,52.67) ; ESDI8.2 v4(17.57,51.31)
  TOP w0.229: v1(59.18,85.54) 59.18,85.52 58.72,85.06 58.72,84.48 59.05,84.15 CU20.2
  TOP w0.254: CN19.2 20.83,5.03 v4(20.7,5.15) ; CI103.2 172.11,33.7 v1(171.8,34.01) 171.55,33.75 CA65.2 ; CV32.2 142.41,49.57 v4(142.42,49.56) ; CA24.2 170.38,33.7 v1(170.69,34.01) 170.94,33.75 CA31.2 ; v1(141.09,51.79) 140.92,51.96 RV115.2 ; CE21.2 186.74,21.05 187.49,21.8 v4(187.63,21.8) 187.81,21.63 DE3.2 ; v4(135.89,29.16) 135.41,28.68 UF15.16 133.22,28.68 132.97,28.42 CF10.1 ; TP148.1 CP2.2 CP1.2 ; RE138.2 CE9.2 183.91,12.29 v4(183.5,12.7) ; v1(27.94,40.71) CB36.2 ; RT104.2 22.63,6.02 v4(22.73,5.92) ; v2(160.27,11.25) RE95.2 ; v2(27.94,37.79) 28.65,37.79 28.9,38.05 RB50.2 ; RN33.1 v2(25.14,2.84) ; CV33.2 142.57,51.9 v2(142.7,51.76) 143.45,51.02 CV196.2 144.52,51.02 CV36.1 ; CN16.2 v2(34.64,4.54) ; CA13.2 170.48,22.27 v4(169.87,21.66) ; UE1.G4 v2(161.46,17.24) ; v1(149.65,62.61) 149.39,62.87 RV65.2 ; CA16.2 RA4.1 175.56,34.36 v1(175.51,34.31) ; CT66.2 8.3,11.88 8.08,12.11 7.49,12.11 7.36,12.24 v1(7.36,12.32) ; v4(170.18,23.19) CA28.2 CA14.2 ; v1(154.44,5.3) 154.63,5.49 RE86.2 ; v4(131.67,81.4) 131.89,81.63 PC1.2 ; v4(156.41,14.3) 156.61,14.5 CE40.2 ; SW5.3 v4(167.39,6.78) ; CE22.2 v4(187.51,14.78) ; v1(159.21,26.08) 159.07,26.22 QL6.2 ; CE373.2 158.21,5.64 v4(158.19,5.61) ; CN1.2 22.22,4.57 v4(22.22,4.65) ; CA17.2 169.97,20.95 v4(169.87,20.85) ; v2(46.24,6.81) 46.18,6.88 46.18,7.64 TP190.1 ; v4(157.07,5.53) 157.48,5.94 ESDE44.2 ; SW5.4 161.19,7.29 v4(161.42,7.06) ; CN18.2 v2(33.32,4.54) ; RV119.2 139.04,52.29 138.63,52.7 v1(138.63,52.91) ; CA11.2 176.22,19.23 v4(176.53,19.23) ; v1(156.13,67.12) 156.13,66.95 155.74,66.57 155.57,66.57 v1(155.13,66.12) ; v4(26.16,41.48) 26.77,40.87 RB47.2 ; CA37.2 184.45,38.73 184.61,38.88 v4(184.66,38.88) ; CA62.2 CA18.2 173.38,21.78 CA61.2 173.54,21.09 v4(173.73,20.9) ; CN5.2 v2(35.3,4.54) ; CE19.2 v4(189.13,17.42) ; CV31.2 130.04,82.43 v4(130.15,82.32) ; CE375.2 v1(158.6,13.28) ; v1(168.76,34.01) 168.5,33.75 CA64.2 ; CA67.2 v1(166.52,26.29) ; CW15.2 150.32,18.01 v4(150.26,18.06) 150.26,18.2 150.63,18.56 CW8.2 ; RV60.2 149.1,58.37 v1(148.84,58.11) ; v4(21.38,4.9) 21.38,4.54 20.93,4.09 CN7.2 ; RA18.2 183.2,38.77 v4(182.78,39.2) ; v2(155.19,29.23) CW12.2 ; CA63.2 v1(166.5,28.01) 166.5,27.71 166.75,27.45 CA26.2 ; CN17.2 v2(33.98,4.54) ; CN6.2 v2(32.66,4.52) ; RW25.1 146.58,18.36 146.95,17.99 v4(146.95,17.75) ; C9.1 138.5,10.84 v4(139.19,10.84) 139.29,10.84 139.57,10.56 C10.2 ; v2(26.29,2.84) 26.16,2.97 26.16,3.78 26.41,4.04 RN5.1 ; v4(156.02,9.85) QE4.2 ; TPE104.1 185.96,12.86 v4(185.96,12.45) ; CA75.2 v4(185.52,44.42) ; v2(155.5,21.97) 155.5,22.12 155.9,22.53 CE33.2 PC105.2 ; CA12.2 v4(176.58,18.51) ; CE20.2 v4(185.96,17.7)
  TOP w0.279: CU105.2 87.25,45.11 v2(87.3,45.06) ; PR624.1 PR625.1 v2(103.38,28.12) ; v4(171.19,17.73) CE37.2 CE36.2 ; PR626.1 104.9,28.01 v2(105.03,28.14) ; CE34.2 170.31,14.04 v2(170.05,13.79) ; 78.31,61.92 78.77,61.92 v2(78.79,61.94) ; CU107.2 80.61,59.51 v2(80.89,59.79) 81.29,59.38 CU146.2 ; CT28.2 21.64,27.63 21.44,27.84 v4(21.41,27.84) 21.11,27.84 20.83,28.12 v4(20.83,29.69) 20.83,30.45 ; PC931.2 v2(190.17,25.09) ; v1(150.36,68.05) 149.88,67.57 CV75.2 ; v2(57.76,89.18) 58.01,88.92 RU60.1 ; v1(98.76,80.46) 98.64,80.34 CD61.1 ; 115.44,90.88 115.44,91.33 v1(115.62,91.51) ; v4(28.06,76.27) ESDX1.2 28.06,75.05 RX18.1 ; CX887.2 23.37,77.25 RX901.1 v4(24.13,77.39) ; 72.52,61.67 72.52,61.23 72.41,61.13 v2(72.41,61.11) ; CU158.2 109.97,59.2 v2(109.48,58.72) ; CV151.1 184.06,86.6 v1(183.81,86.84) ; v2(74.21,58.55) 73.91,58.25 RU193.1 ; v1(138.97,26.99) 138.97,26.99 138.41,27.55 UF15.23 ; CU93.2 v4(81.53,56.97) ; CU22.2 71.83,62.68 v2(71.49,62.34) 71.07,61.92 CU17.2 ; CU51.2 70.36,57.31 v2(70.27,57.23) ; TPT13.1 v4(22.1,21.03) ; PR167.1 26.1,67.63 PC150.2 26.41,68.23 v4(26.41,69.16) ; v1(118.82,88.91) 118.88,88.85 120.39,88.85 v1(120.45,88.91) ; RT131.2 11.52,21.73 v4(11.78,21.46) ; v1(114.17,90.68) 114.05,90.55 CD93.2 ; v1(149.27,74.17) 149.08,73.98 CV81.1 ; CU162.2 101.68,43.38 v2(101.55,43.51) ; CD59.1 104.27,91.41 v1(104.36,91.51) ; CV10.1 152.09,76.78 v1(152.13,76.82) ; PR205.1 v1(49.15,45.08) ; v2(110.39,60.71) 110.75,61.07 CU149.2 ; CD24.1 68.07,90.43 v1(68.29,90.21) ; CD97.1 81.23,80.34 v1(81.11,80.46) ; CV170.2 173.46,60 173.74,60.27 v1(174.21,60.27) ; RV103.2 CV119.2 182.44,60.05 v1(182.21,60.27) ; v1(174.13,69.94) 174.26,70.07 CV122.2 ; CV4.2 157.76,76.78 157.1,76.78 v1(157.09,76.8) ; v1(144.01,60.01) 143.25,60.77 143.25,61.16 143.51,61.41 RV48.1 ; CV161.1 174.33,78.73 v1(174.21,78.84) ; CT29.2 24.51,27.94 24.08,28.36 XT1.2 ; RE114.1 v2(156.46,12.47) CE377.2 ; v1(153.13,72.91) 153.33,73.11 CV83.1 ; v2(58.42,82.24) 58.67,82.5 CU19.2 ; 70.23,55.19 70.23,54.7 v2(70.27,54.66) ; ESDT13.2 11.08,20.87 v4(10.7,21.25) ; v2(105.03,28.14) 105.03,28.29 PC656.2 ; v2(105.03,28.14) 105.18,28.14 105.51,27.81 PC657.1 ; CD48.2 97.06,89.43 v1(97.19,89.56) ; PC613.1 v4(104.52,15.82) ; CU36.2 66.6,51.69 v2(66.37,51.47) ; RT119.2 10.95,18.17 10.67,18.45 v4(10.67,18.97) 10.86,18.77 ESDT12.2 ; UT2.H2 27.39,24.26 27.05,23.92 v2(27.02,23.92) ; v1(69.86,87.61) 69.25,87.61 CD42.2 ; CV153.1 182.7,81.73 v1(183.01,82.04) ; 78.84,59.79 79.37,59.26 CU92.2 ; 78.84,59.79 v2(78.75,59.79) ; 78.84,59.79 78.97,59.79 RU26.1 ; CD70.1 87.63,83.59 v1(87.51,83.71) ; CD78.1 124.71,88.61 v1(124.42,88.91) ; CD55.1 70.74,81.03 v1(70.66,81.11) ; CD13.2 99.47,84.91 v1(99.56,85.01) ; v1(151.48,29.36) 151.08,28.95 CW16.1 ; CD79.1 121.03,81.95 v1(121.22,81.76) 121.03,81.57 CD102.1 121.03,80.65 v1(121.22,80.46) ; CV19.1 159.76,78.4 159.76,78.86 CV18.1 159.95,79.19 v2(160.4,79.19) ; CD30.1 101.22,79.76 v1(101.16,79.81) ; v2(29.34,15.69) 28.57,16.46 27.68,16.46 27.3,16.84 RT63.1 ; RI146.1 30.86,51.76 v4(31.11,51.51) ; v2(145.67,4.77) 145.5,4.94 JP2.5 ; EDB3.2 21.57,38.57 21.69,38.45 v4(21.72,38.45) ; v4(134.77,34.62) 134.77,34.64 135.13,35 CF11.2 ; CD10.2 97.15,84.4 v1(97.19,84.36) ; RU122.2 60.93,58.75 60.68,58.49 v2(60.63,58.49) ; v1(175.81,60.27) 175.8,60.26 CV171.2 ; 89.15,90.62 89.73,90.62 v1(89.79,90.68) ; CW13.1 155.04,30.35 v2(155.29,30.1) 154.99,29.79 CW14.1 ; v1(72.13,90.68) 71.83,90.37 CD41.1 ; RU12.1 72.82,60.02 v2(72.4,60.44) ; CT31.2 31.77,24.58 v2(32.15,24.97) ; CD53.1 64.25,92.15 v1(64.26,92.16) ; RU200.1 102.01,45.08 v2(101.93,45.01) ; RV60.2 148.97,60.53 RV57.1 ; CV55.1 158.76,75 v1(158.83,75.07) ; 69.98,83.13 69.98,83.59 v1(69.86,83.71) ; CU54.2 72.31,56.84 v2(72.35,56.89) 72.35,57.77 CU50.2 ; v2(21.59,16.96) 21.49,16.96 21.21,17.24 RT50.1 RT53.1 ; CE45.2 73.24,5.7 v2(73.53,5.41) ; v1(97.96,91.51) 97.79,91.33 CD60.1 ; v1(187.02,66.67) 186.83,66.48 CV125.1 ; v1(181.81,78.62) 181.82,78.61 CV152.1 ; RT43.1 29.21,17.09 30.48,17.09 v2(30.73,16.84) ; CV81.1 149.6,73.17 CV84.1 150.08,73.17 v1(150.34,72.91) ; CV81.1 148.44,73.17 v1(148.26,72.99) ; CV94.2 148.49,75.05 v1(148.34,74.91) ; v4(21.21,7.95) 21.46,8.2 RT91.1 ; CV116.2 158.83,70.06 v1(158.85,70.05) ; CV99.2 149.51,68.95 v1(149.34,69.12) ; v2(54.4,75.21) 54.49,75.13 RU16.1 ; ESDI4.2 16.64,57.48 v4(16.51,57.35) ; CD3.2 64.39,89.43 v1(64.26,89.56) 64.21,89.61 CD50.1 ; v1(177.41,78.84) 178.23,78.02 CV146.2 ; v2(77.94,59.72) 77.73,59.72 CU62.2 ; v2(96.46,44.46) 96.52,44.52 RU205.1 ; v2(60.63,56.46) RU97.2 ; CV29.2 146.53,75.72 v1(146.37,75.88) ; 75.44,62.94 75.77,62.94 v2(75.93,63.1) ; v1(120.42,90.21) 120.18,90.44 CD107.2 119.05,90.44 v1(118.82,90.21) ; v2(96.44,60.44) 96.32,60.32 CU160.2 ; v4(27.3,64.21) 27.07,64.21 26.8,63.93 26.8,63.19 ; ESDT10.2 13.99,16.58 v1(14.35,16.58) ; v4(23.98,68.15) 24.03,68.2 PR168.1 23.7,68.73 23.48,68.51 PC153.2 ; CV130.1 187.66,70.82 v1(187.81,70.67) ; TP148.1 142.37,7.57 141.22,8.71 v2(140.69,8.71) ; JT1.3 7.95,15.91 JT1.A12 ; CV92.2 153.04,68.31 v1(153.18,68.18) ; v1(169.29,35.01) 169.37,34.92 CA23.2 ; v2(101.93,62.34) 101.85,62.42 101.85,62.94 ; PC604.2 v2(109.85,21.96) ; v2(108.97,43.51) 108.58,43.12 CU164.2 ; 64.41,52.02 64.01,51.61 RU13.1 ; 64.41,52.02 64.18,52.25 RU173.2 ; 64.41,52.02 v2(64.77,52.02) ; CU64.2 84.07,47.55 v4(84.1,47.57) 84.66,48.14 CU74.2 ; 71.63,3.07 71.32,3.38 ESDE7.2 ; CV150.1 177.61,90.65 v1(178.21,90.04) ; v2(82.72,62.34) 82.68,62.38 82.68,62.94 ; v1(153.18,68.18) 153.35,68.34 CV85.2 153.92,68.92 v1(154.13,69.12) 154.45,69.45 CV70.2 154.45,70.23 v1(155.19,70.97) ; v1(153.18,68.18) 153.76,67.6 CV79.2 153.91,67.44 CV80.1 ; v2(74.21,59.18) 74.03,59 RU137.2 ; v1(105.96,91.51) 106.04,91.43 CD46.1 ; v1(69.06,80.46) 69.18,80.34 CD51.1 ; ESDX2.2 25.66,75.13 ESD2.3 ; ESDX2.2 25.79,74.69 26.2,74.28 v4(26.2,74.23) ; ESDX2.2 25.79,75.63 CX893.2 ; v1(187.01,61.87) 187.43,61.87 CV128.1 ; v1(122.82,87.61) 122.52,87.61 CD90.1 ; CD11.2 99.31,89.16 v1(99.56,88.91) ; v1(63.46,83.71) 63.64,83.89 CD5.2 CD39.1 ; CU41.2 64.28,59.39 v2(64.83,59.39) ; v2(23.62,16.96) 23.75,17.09 RT55.1 ; RI104.1 22.58,46.81 v4(22.65,46.81) ; UB6.14 25.4,35.99 v2(25.14,36.24) ; v4(22.2,31.57) 22.2,30.79 21.92,30.51 XT1.4 20.89,30.51 20.83,30.45 ; v4(22.2,31.57) v4(24.18,31.57) 24.86,31.57 25.14,31.29 25.14,29.79 v2(25.02,29.66) 24.76,29.66 24.08,28.99 XT1.2 ; v4(22.2,31.57) 21.16,31.57 20.83,31.24 20.83,30.45 ; CV126.1 186.14,63.56 v1(186.21,63.48) ; v2(82.72,60.44) 82.76,60.44 83.95,59.26 CU159.2 ; v1(106.76,92.16) 107.05,92.16 CD12.2 ; CD101.1 123.7,81.19 v1(123.62,81.11) ; RV96.1 180.46,71.09 v1(180.21,70.84) 179.94,70.84 179.66,70.56 RV93.1 ; CV129.1 183.17,66.52 v1(182.99,66.69) ; PC406.2 v4(46.33,63.42) ; CV169.1 187.14,59.35 v1(187.01,59.47) ; v2(104.03,43.51) 104.01,43.52 RU212.1 ; v1(154.25,74.03) 153.93,73.71 CV83.1 ; CU160.2 96.32,58.75 v2(96.45,58.62) ; CU160.2 CU161.2 ; CT6.2 40.29,32.19 40.6,32.5 v2(40.83,32.5) ; RI33.1 CI120.2 v2(26.8,47.22) ; CD73.1 89.55,88.47 v1(89.11,88.91) ; CD68.1 83.31,78.96 v1(83.51,79.16) 83.87,79.52 CD100.2 84.85,79.52 v1(85.14,79.81) ; v2(57.78,49.2) 59.82,47.17 RU150.1 ; v1(79.54,90.21) 79.12,90.62 CD96.1 ; CV83.1 154.39,73.11 CV101.2 154.61,72.39 v1(154.14,71.92) ; v1(65.86,83.71) 65.98,83.58 CD26.2 67.33,83.58 v1(67.46,83.71) 67.53,83.64 CD38.1 ; v2(66.42,63.49) 66.42,63.49 CU38.2 ; CD7.2 82.04,89.43 v1(81.91,89.56) 81.86,89.61 CD99.1 ; CD75.1 CD77.1 113.66,83.99 113.94,83.71 v1(114.85,83.71) ; v2(90.95,62.34) 90.93,62.36 90.93,62.94 ; CU67.2 105.92,43.51 v2(106.5,43.51) 106.81,43.2 CU163.2 ; CD91.1 120.49,83.64 v1(120.42,83.71) 120.29,83.58 CD83.2 118.94,83.58 v1(118.82,83.71) ; CE378.2 157.58,19.02 157.94,18.67 v2(157.99,18.67) ; v1(187.01,86.04) 186.9,85.93 CV148.1 ; v1(65.86,90.86) 66.02,90.7 CD57.2 ; v2(66.36,57.12) 66.55,57.31 CU52.2 ; v2(96.44,62.33) 96.44,62.34 96.44,62.94 ; CE374.2 155.14,19.73 154.73,19.33 v4(154.58,19.33) ; PC659.1 110.84,27.86 v4(111,28.01) ; v1(102.76,79.16) 103.04,78.88 CD65.2 103.95,78.88 104.23,79.16 v1(104.36,79.16) ; RU197.1 101.48,45.47 v2(101.93,45.01) ; CV131.1 184.77,70.83 v1(184.61,70.67) ; v2(54.4,76.37) 54.5,76.27 CU31.2 ; CD32.1 97.15,88.21 v1(97.19,88.26) ; RU59.1 v2(62.23,45.5) ; CD63.1 103.38,81.57 v1(103.56,81.76) 103.38,81.95 CD28.1 ; RU14.1 65.94,49.94 v2(65.75,49.76) ; v1(186.21,79.64) 186.11,79.55 CV163.1 CV162.1 ; ESDL46.2 14.86,69.13 v4(14.86,68.65) ; CU33.2 v2(126.24,89.35) ; CD94.1 85.72,81.57 v1(85.91,81.76) ; v4(70.58,72.87) 70.81,73.1 CU5.2 CU1.2 CU2.2 CU3.2 CU4.2 ; v1(66.39,86.32) 66.67,86.61 CD27.2 ; v1(68.29,91.51) 68.07,91.73 CD52.1 ; v4(97.28,25.22) 97.66,25.6 PC602.2 ; 81.23,1.14 81.53,1.45 84.99,1.45 85.34,1.09 ; v1(105.96,81.11) 106.04,81.19 CD62.1 ; CV157.2 176.36,75.43 v1(175.88,74.96) ; RU202.1 v2(96.46,47.25) ; RV67.2 156.32,59.67 v1(156.66,59.33) ; CU154.2 CU155.2 93.54,59.08 v2(93.7,58.92) ; v2(21.59,36.85) 21.31,36.58 EDB5.2 ; CD85.1 85.18,83.64 v1(85.11,83.71) 84.99,83.58 CD74.2 83.64,83.58 v1(83.51,83.71) ; CU46.2 69.72,52.07 v2(69.62,52.17) ; v2(64.72,62.45) 64.51,62.66 RU73.2 ; v1(157.09,76.8) 157.09,76.12 CV15.1 ; v1(157.09,76.8) 156.55,76.8 CV3.2 ; CD20.1 71.77,84.02 v1(71.46,83.71) ; v1(136.14,25.27) 136.14,25.52 136.35,25.73 CF12.1 ; RU210.1 101.47,44.02 RU217.1 101.85,44.93 v2(101.93,45.01) ; CA82.2 184.02,13.54 v4(183.89,13.41) 183.78,13.52 QA1.4 ; v4(13.71,7.57) 13.82,7.57 14.1,7.85 CT67.2 ; CU58.2 105,59.13 v2(104.94,59.19) ; RU165.1 127.39,90 UU2.3 v4(127.39,91.51) ; v1(69.06,79.16) 69.15,79.07 CD19.1 ; v2(75.15,62.28) 74.5,62.94 74.42,62.94 ; v1(89.11,83.71) 89.43,84.02 CD67.1 ; CU15.2 RU180.2 69.14,61.8 v2(68.96,61.62) ; v4(128.06,78.41) 128.09,78.43 CV34.2 ; v2(76.04,59.83) 75.69,59.48 CU59.2 ; v4(128.73,7.74) 128.73,6.55 TPP12.1 ; v1(156.13,67.12) 156.33,66.92 CV59.2 156.74,66.99 CV57.2 156.67,68.05 CV56.1 156.64,68.61 v1(156.13,69.12) 156.04,69.21 CV52.2 156.04,70.14 156.59,70.69 CV64.1 156.59,71.43 v1(156.08,71.94) 156.6,72.46 156.6,73.39 CV53.1 156.55,74.07 CV54.1 156.17,74.11 v1(156.06,74) ; v1(67.49,79.81) 67.2,79.52 CD56.2 66.22,79.52 v1(65.86,79.16) ; CU142.2 85.56,61.05 v2(85.46,61.05) 85.38,61.05 CU145.2 ; CD49.2 104.81,87.61 v1(105.17,87.61) ; RV21.1 158.75,80.59 158.95,80.8 v1(159.57,80.8) ; v2(63.09,62.5) 63.5,62.91 RU225.2 ; CD106.1 123.06,93.34 v1(122.82,93.58) ; JT1.2 6.69,22.75 JT1.B12 ; v2(18.41,16.36) 18.26,16.36 17.86,16.75 17.86,17.3 RT45.1 ; CD4.2 70.86,91.68 v1(70.69,91.51) ; CV143.1 182.69,63.57 RV97.1 182.54,63.18 v1(183,62.72) ; v4(21.08,33.98) 20.94,33.84 RT81.1 ; v1(89.74,81.71) 89.46,81.99 CD87.1 ; CU49.2 64.72,57.58 v2(64.72,57.26) 64.3,57.26 RU95.2 ; CV178.2 186.93,82.91 v1(187.01,82.84) ; v1(85.94,90.21) 85.72,90.43 CD72.1 ; CD104.1 117.21,81.1 v1(117.22,81.11) ; CX284.2 v2(25.4,78.46) ; v2(66.42,48.83) 65.95,48.36 CU42.2 ; v1(101.16,83.71) 101.29,83.58 CD37.2 102.64,83.58 v1(102.76,83.71) 102.83,83.64 CD47.1 ; RU124.1 v1(59.18,85.54) ; v1(85.94,91.51) 85.72,91.73 CD95.1 ; v1(114.85,88.26) 114.8,88.21 CD14.2 ; ESDT11.2 13.99,18.23 v4(14.35,18.23) ; v2(97.41,43.13) 97.28,43.25 RU201.1 ; CD15.2 117.35,89.04 v1(117.22,88.91) ; CU91.2 98.63,43.05 v2(98.55,43.13) 98.42,43.25 CU110.2 ; v1(107.39,81.71) 107.06,82.04 CD44.1 ; CD66.1 85.08,88.85 v1(85.14,88.91) ; CE44.2 68.32,8 v2(69.19,8.86) ; 69.98,89.48 69.98,89.02 v1(69.86,88.91) ; v1(124.42,83.71) 124.71,84 CD82.1 ; v1(61.89,88.26) 61.84,88.21 CD22.1 ; RV92.1 180.1,78.57 v1(180.09,78.55) ; CV36.1 144.78,50.76 v3(144.78,48.94) 144.78,48.89 144.42,48.54 143,48.54 142.42,49.12 v4(142.42,49.56) ; CD45.1 99.88,82.24 v1(100.36,81.76) 100.46,81.67 CD58.1 100.46,80.55 v1(100.36,80.46) ; v4(133.73,3.63) 133.6,3.63 132.38,4.85 129.52,4.85 v4(128.18,3.5) ; v1(180.61,89.24) 179.97,89.24 CV121.2 ; v4(156.41,14.3) 156.72,13.99 CE376.2 ; v1(150.34,66.12) 150.08,65.86 CV209.2 ; v2(88.21,59.01) 87.84,59.38 CU152.2 ; v1(79.54,88.26) 79.49,88.21 CD69.1 ; RI149.1 v2(26.8,58.87) ; v1(143.83,72.59) 143.86,72.56 CV69.2 144.7,72.73 CV72.2 CV74.2 146.52,72.73 v1(147.34,71.91) ; CU60.2 CU61.2 75.56,57.1 v2(75.82,56.84) ; PC530.2 81.41,28.01 v4(81.79,27.63) ; v1(117.22,83.71) 117.02,83.71 CD17.2 ; v1(122.82,83.71) 122.37,83.26 CD105.1 ; CV58.2 156.09,66.17 CV60.2 155.31,65.94 v1(155.13,66.12) 154.64,65.63 CV61.1 154.55,65.61 CV62.1 CV187.2 153.29,65.96 v1(153.13,66.12) 152.71,65.71 CV71.2 151.76,65.71 CV63.1 150.72,65.41 CV110.2 150.56,64.72 CV111.1 150.78,64.5 CV46.2 150.78,63.92 151.34,63.36 v1(151.34,62.59) ; RV142.1 129.38,86.83 CV28.2 130.76,86.83 v1(130.91,86.69) ; RV99.2 181.75,62.21 v1(181.41,61.87) ; v1(177.41,70.67) 177.37,70.72 CV123.2 ; 67.56,62.94 67.56,62.5 v2(67.58,62.48) ; CX4.2 CX15.1 21.46,75.56 21.92,76.02 21.92,76.15 v1(21.94,76.17) 21.92,76.17 21.87,76.22 21.56,76.22 CX21.1 21.46,76.63 21.35,76.74 CX895.2 ; CD89.1 118.36,82.1 v1(118.02,81.76) 117.98,81.72 CD103.1 117.98,80.49 v1(118.02,80.46) ; 57.66,81.73 v1(57.66,82.24) ; v4(185.29,21.79) 186.31,22.81 PU910.B1 ; CV159.2 177.45,75.26 v1(177.15,74.96) ; v4(10.79,16.84) 10.98,16.65 RT118.2 ; CU111.2 104.4,47.99 105.62,47.99 v2(105.79,47.83) ; CU153.2 99.21,59.82 CU157.2 99.19,60.44 v2(99.19,60.44) ; RU198.1 103.49,46.1 v2(103.75,45.84) 103.83,45.92 RU206.1 ; CE39.2 154.71,22.55 154.38,22.88 v2(154.38,23.21) ; v1(155.95,28.88) 156.31,28.88 156.61,28.57 CL32.2 ; v2(105.15,15.82) 105.27,15.71 PC617.1 ; v1(147.34,69.12) 147.69,69.47 CV90.2 ; CU144.2 107.49,61.01 v2(107.42,61.07) ; v1(114.43,81.94) 114.81,82.32 CD92.1 ; v4(67.56,5) 67.56,5.03 67.44,5.15 ESDE6.2 ; v1(87.51,87.61) 86.91,87.61 CD88.2 ; CD31.1 105.28,83.59 v1(105.16,83.71) ; v4(16.57,59.19) 16.98,59.19 ESDI2.2 ; PR631.1 PC607.1 v2(101.09,28.12) ; 82.17,83.77 81.17,83.77 v1(81.11,83.71) ; PC932.2 PC930.2 v2(190.17,24.2) ; v1(79.54,84.36) 79.5,84.4 CD6.2 ; v1(117.22,79.81) 117.32,79.7 117.98,79.7 ; v1(102.79,88.91) 102.67,89.03 CD36.2 101.29,89.03 v1(101.16,88.91) ; v2(25.91,16.41) 25.91,16.96 25.78,17.09 RT65.1 ; CA25.2 CA64.2 ; CD8.2 88.52,91.68 v1(88.34,91.51) ; CD98.1 88.39,81.03 v1(88.31,81.11) ; v1(101.17,90.86) 101.63,90.86 CD64.2 102.46,91.2 v1(102.76,91.51) ; v1(183.01,86.04) 182.75,85.78 RV98.1 ; CD33.1 102.6,90.37 v1(102.76,90.21) ; CV141.1 185.47,59.41 v1(185.41,59.47) ; CD80.1 119.63,86.61 v1(119.35,86.32) ; v4(7.77,22.73) 7.95,22.55 JT1.A1 ; QA1.1 v4(179.97,14.82) ; v2(100.48,21.03) 100.58,21.13 PC631.2 ; v1(175.01,90.04) 175.07,90.09 CV165.1 ; RU194.1 98.94,44.14 v2(99.26,44.46) ; v1(158.82,65.13) 158.3,65.65 CV115.1 ; v4(31.09,7.69) 31.09,8.71 31.54,9.16 QT5.2 ; JP2.4 147.43,7.54 147.71,7.82 v4(148.61,7.82) 149.93,7.82 TPP15.1 ; CF3.2 138.81,25.47 138.89,25.4 v1(138.89,25.3) ; XT1.2 24.13,28.78 25.04,28.78 v2(25.09,28.83) ; CD40.1 71.8,81.99 v1(72.08,81.71) ; CP3.2 CO2.2 CO1.2 134.21,6.58 v4(134.49,6.3) ; v2(77.01,59.78) 76.85,59.61 CU63.2 ; CD29.1 107.21,84.15 v1(106.77,83.71) ; QL1.2 v4(12.71,66.76) ; v1(97.94,83.71) 97.94,83.68 97.79,83.53 CD34.1 ; v2(71.13,55.27) 70.74,55.67 CU45.2 ; v2(19.68,16.96) RT52.1 ; PESD106.3 v4(107.31,13.92) ; v1(179.81,60.27) 179.78,60.24 CV120.2 ; RT132.2 11.34,23.25 11.62,23.53 v4(11.62,23.84) ; CU34.2 v2(128.52,90.32) ; v1(175.81,70.67) 175.9,70.76 CV127.1 ; v4(130.17,13.15) 130.17,14.12 GND_SPIO1.1 ; CD25.1 71.9,88.47 v1(71.46,88.91) ; v2(97.41,47.25) 97.23,47.07 RU209.1 ; v2(100.48,21.92) 100.53,21.87 PC641.2 ; CD71.1 87.63,89.02 v1(87.51,88.91) ; PR637.2 97.85,21.35 v4(97.28,21.92) ; CD35.1 107.06,88.61 v1(106.77,88.91) ; RV68.2 157.86,60.14 158.49,59.51 v1(159.19,59.51) ; CW11.2 154.92,27.85 v2(154.85,27.79) 155.63,27.01 QL4.2 ; CE35.2 CE18.2 v4(154.68,25.68) ; v2(66.9,61.62) 66.11,60.83 RU58.1 ; 68.2,82.37 68.2,81.82 v1(68.26,81.76) 68.07,81.57 CD54.1 ; CU48.2 68.12,51.22 v2(68.38,51.48) ; 72.52,59.64 72.52,59.63 72.52,59.23 v2(72.42,59.13) ; v1(106.53,28.14) PC658.1 ; CU14.2 68.43,59.6 v2(68.32,59.7) ; v1(59.43,88.97) 59.86,89.4 CD43.2 ; RU199.1 102.61,46.15 v2(102.85,46.38) ; CD2.2 61.84,84.4 v1(61.89,84.36) ; v2(54.86,78.31) CU11.2 ; v4(16.71,82.22) 16.25,82.67 CE25.2 ; JP2.6 148.43,6.83 v4(148.21,7.06) ; v2(79.61,64.16) 79.75,64.01 CU106.2 ; v2(57.86,78.18) CU18.2 ; CU148.2 CU156.2 90.59,60.07 v2(90.95,60.44) ; CE43.2 RE95.2 ; RI102.1 v2(24.13,58.87) ; CU16.2 70.23,60.6 70.57,60.94 v2(70.57,61.07) ; CV176.1 175.91,78.68 v1(175.76,78.84) ; JT1.4 6.69,16.12 6.35,16.46 JT1.B1 ; RU223.2 64.11,55.22 v2(64.73,54.6) ; v2(69,48.87) 68.57,49.3 RU54.2 ; v4(5.18,93.29) 4.82,93.29 MR1.3 ; v2(67.69,47.9) 68.5,47.9
  TOP w0.305: CV45.2 147.24,69.23 v1(147.34,69.12) ; CU37.2 v4(45.72,4.57) ; CV97.2 148.53,70.72 v1(148.34,70.91)
  TOP w0.381: CV100.2 153.12,72.92 v1(153.13,72.91) ; v1(151.34,71.91) 152.04,71.21 CV68.2 ; v1(153.13,74.91) 153.31,75.09 CV78.2 153.28,75.57 CV77.2 ; CV68.2 152.83,71.21 v1(153.13,70.91) ; CV68.2 CV76.2 151.29,70.03 151.26,69.99 ; PC715.2 46.58,78.87 v4(46.12,78.41) ; v1(150.34,74.91) 150.39,74.96 CV88.2 ; CA8.2 172.79,33.69 v1(172.37,34.11) ; v1(150.34,70.91) 151.26,69.99 151.26,69.99 ; 151.26,69.99 151.26,69.21 v1(151.34,69.12)
  TOP w0.483: PC611.2 133.35,23.19 133.98,23.82 v4(133.98,24.33)
  ART03 w0.152: v1(160.46,77.54) 160.46,77.73 160.78,78.05 160.78,78.69 160.9,78.81
  ART03 w0.279: v4(175.45,55.07) 174.35,53.97 170.34,53.97 v4(169.04,52.67) 169.03,52.67 166.83,50.47 163.95,50.47 GPU_BOSS1.1 161.12,51.64 155.95,51.64 153.8,53.79 153.16,53.79 151.64,55.32 151.64,58.78 v1(151.39,59.03) ; v4(178.65,55.87) 179.45,55.06 183.39,55.06 184.15,55.83 186.18,55.83 187.32,56.97 187.32,59.17 v1(187.01,59.47) 188.47,60.93 188.47,70.05 187.84,70.67 v1(187.81,70.67) 187.81,72.1 185.47,74.44 v1(185.47,74.96) 185.47,75.21 188.23,77.97 v1(188.23,78.9) 188.48,79.15 188.48,90.35 186.51,92.33 183.84,92.33 v1(183.39,92.78) v1(182.45,92.78) v1(181.56,92.78) 181.49,92.71 v1(178.91,92.71) v1(178.11,92.71) v1(177.31,92.71) v1(176.51,92.71) 171.89,92.71 168.39,89.21 v1(166.5,89.21) 166.5,87.7 164.08,85.29 164.08,81.99 160.9,78.81
  ART06 w0.254: v2(108.62,59.65) 108.61,59.66 v2(107.97,59.66) v2(107.32,59.66) v2(106.67,59.66) v2(106.02,59.66) ; v2(74.21,59.18) v2(74.21,58.55) ; v2(104.94,59.19) 104.74,59.39 88.6,59.39 v2(88.21,59.01) 87.89,59.33 80.46,59.33 80.21,59.59 78.96,59.59 v2(78.75,59.79) 78.68,59.72 v2(77.94,59.72) 77.07,59.72 v2(77.01,59.78) 76.96,59.83 v2(76.04,59.83) ; v2(71.13,55.27) 71,55.15 v2(71,54.72) 71,52.25 v2(70.92,52.17) v2(70.92,51.34) v2(70.92,50.51) ; v4(152.4,52.14) 152.78,51.76 v4(153.16,51.76) 160.99,51.76 GPU_BOSS1.1
  ART06 w0.279: v4(152.4,52.14) 151,53.54 150.92,53.54 150.32,54.15 v1(150.32,54.81) ; v2(104.94,59.19) 105.55,59.19 v2(106.02,59.66)
  ART06 w0.381: v4(175.45,55.87) 175.45,55.89 174.75,56.59 172.72,56.59 169.04,52.91 v4(169.04,52.67)
  ART06 w0.508: v4(175.45,55.87) v4(176.25,55.87) v4(177.05,55.87) v4(177.85,55.87) v4(178.65,55.87) 181.4,58.62 183.77,58.62 184.66,57.73 186.82,57.73 189.1,60.02 189.1,89.95 187.79,91.26 179.2,91.26 178.21,90.28 v1(178.21,90.04) ; v1(150.32,54.81) 150.11,54.81 148.51,56.41 148.51,57.78 v1(148.84,58.11)
  GND07 w0.279: TH8.1 74.08,1 ; TH8.1 78.95,1 ; TH8.1 76.65,3.32 ; TH10.1 187.75,6 ; TH10.1 190.15,8.42 ; TH10.1 190.15,3.66 ; TH14.1 57.12,97 ; TH14.1 54.85,94.95 ; TH14.1 52.35,97
  BOTTOM w0.076: 95.08,43.43 UU1.AR3 ; v1(151.34,62.59) 151.34,61.01 UV2.B14
  BOTTOM w0.102: v2(112.01,42.56) 111.99,42.57
  BOTTOM w0.145: v1(161.94,59.38) 161.64,59.68 UV2.A26
  BOTTOM w0.152: v2(90.8,65.99) 90.62,65.8 UU1.BD49 ; 60.26,45.98 60.56,45.68 61.25,45.68 62.25,46.68 v2(62.41,46.68) ; UU1.A36 v2(112.77,59.35) ; v2(75.6,66.32) UU1.CR49 ; UU1.AV49 v2(93.12,66.42) ; UU1.BJ49 88.11,66.32 v2(88.06,66.37) ; v2(109.32,66.46) 109.32,66.46 UU1.G49 ; UU1.A42 112.61,61.96 v2(112.65,61.96) ; v2(69.49,64.04) 68.96,64.04 UU1.DH45 ; UU1.CY49 73.1,66.31 v2(72.93,66.48) ; UU1.AN49 95.62,66.41 v2(95.62,66.41) ; UU1.CE49 80.61,66.06 v2(80.43,66.23) ; UU1.DK49 67.95,65.62 67.95,66.05 v2(68.02,66.12) 68.02,66.47 66.76,67.73 66.58,67.73 65.24,69.07 65.24,72.1 64.87,72.46 64.26,72.46 v2(64.01,72.21) ; v2(112.98,57.12) 112.92,57.12 112.19,57.85 111.88,57.85 UU1.A34 UU1.C34 ; UU1.BR49 v2(85.61,66.39) ; UU1.A39 111.67,60.65 v2(113.66,60.65) ; v2(67.13,66.14) 67.13,66.12 67.11,66.08 67.12,66.06 67.1,66.03 67.19,65.52 67.18,65.36 67.07,65.09 66.89,64.91 UU1.DM47 67.21,64.49 UU1.DL47 ; v2(78.11,66.14) UU1.CK49 ; v2(77.5,66.98) 77.5,65.81 77.47,65.79 ; v2(74.17,66.11) 74.17,65.62 UU1.CU49 UU1.CU47 ; v2(98.12,66.37) UU1.AH49 ; UU1.H49 v2(108.27,66.33) ; v2(112.01,66.49) 112.01,66.26 111.84,66.09 111.84,66.09 UU1.A49 UU1.C49 110.88,65.55 110.76,65.42 110.76,65.2 UU1.C48 ; UU1.V49 v2(103.13,66.33) ; UU1.D49 110.23,65.89 110.47,66.13 v2(110.47,66.42) ; UU1.AG1 UU1.AG3 ; UU1.AC49 v2(100.62,66.41) ; v2(83.11,66.35) UU1.BY49 ; UU1.DE22 UU1.DF22
  BOTTOM w0.165: v1(183.01,61.08) v1(183.81,61.08) ; v1(162.84,70.09) 162.42,70.51 UV2.P26 ; v1(184.62,68.27) v1(184.62,67.47)
  BOTTOM w0.178: UD4.G12 115.56,88.91 116.51,88.91 UD4.G10 ; v2(75.93,63.1) 75.93,63.18 UU1.CR45
  BOTTOM w0.191: UU1.DH1 UU1.DH3 69.11,43.38 v2(68.98,43.51) 69.11,43.64 UU1.DH5 ; UU1.AY3 UU1.BA2 UU1.BA1 ; v2(75.82,25.85) 75.99,25.68 PU501.14 ; UU1.BP3 UU1.BP2 UU1.BP1 ; v2(94.51,40.92) 94.51,41.12 95.08,41.69 UU1.AR2 ; UU1.BV1 UU1.BV2 v2(83.64,43.11) ; UU1.BJ1 UU1.BJ2 UU1.BJ3 ; UU1.BD3 UU1.BE2 UU1.BE1 ; v2(97.41,43.13) 97.03,42.75 UU1.AL2 ; PU1201.11 133.76,91 v1(133.86,90.9)
  BOTTOM w0.203: UU1.DB49 UU1.DB47 ; UV4.K2 UV4.K1 ; v1(146.1,49.87) 146.05,49.92 CV194.2 ; v1(156.66,59.33) 156.66,60.58 UV2.B20 ; CU7.2 v2(63.37,69.8) 66.09,67.08 66.52,67.08 67.13,66.47 v2(67.13,66.14) ; QV4.1 134.33,55.78 v4(134.1,56.01) ; RV12.1 v1(138.25,80.34) ; PC1204.2 135.18,89.83 v4(135.62,90.28) ; UU1.DB45 71.88,63.49 73.08,63.49 UU1.CY45 ; CV193.2 142.92,51.98 v2(142.7,51.76) ; QV24.2 v1(145.54,53.43) ; QV4.4 136.43,53.48 v4(136.72,53.19) ; UV3.K13 181.41,61.08 v1(181.41,61.87) ; UV2.AF5 144.29,82.02 v1(144.19,82.12) ; PU902.11 20.75,44.83 v4(20.7,44.78) ; UU1.CG39 79.19,60.48 79.19,60.25 78.75,59.82 v2(78.75,59.79) ; PC828.2 167.84,44.71 167.63,44.91 v1(167.62,44.91) 167.3,44.58 PR822.1 PC827.2 ; UV2.B17 154.3,60.53 154.3,58.95 v1(154.2,58.84) ; CT15.2 50.42,41.86 RT4.2 ; PR836.2 169.37,38.84 v1(169.37,38.31) ; v4(134.1,56.01) 134.08,56.03 133.5,56.03 133.3,55.83 UV1.3 ; v4(134.1,56.01) 134.17,56.07 QV8.2 ; 37.72,59.26 v2(37.26,59.26) 37.08,59.43 PC404.2 ; v1(138.63,50.62) 138.43,50.82 CV199.2 ; CV30.2 137.42,82.25 v4(137.67,82.5) ; PC823.2 PR852.1 165.7,36.1 v4(165.82,35.98) ; v1(167.67,35.47) 167.93,35.74 PR860.1 ; UU1.AJ2 97.68,42.85 v2(97.41,43.13) ; QV6.1 140.2,52.91 v1(138.63,52.91) 138.3,52.91 CV192.1 ; UV2.AF8 146.78,81.71 146.57,81.91 v1(146.56,81.91) ; v1(182.21,60.27) v1(183.01,60.27) ; v1(154.91,88.72) ESD3.3 ; v1(140.44,86.15) 140.45,86.14 CV35.1 ; QU2.2 54.95,64.12 54.86,64.21 v2(54.86,64.67) ; QV23.2 135.75,56.85 v1(136.02,56.59) ; v4(136,89.02) 136,89.01 PC1202.2 ; PU101.27 46.65,15.57 ; RV63.2 v1(142.44,86.02) ; 71.23,65.79 v2(71.23,66.45)
  BOTTOM w0.229: UD2.G10 v1(81.91,89.56) ; UD1.G1 v1(71.46,88.91) 71.46,88.32 UD1.J1 ; UD2.W9 v1(82.71,81.11) UD2.Y8 ; UD4.J12 v1(114.85,88.26) ; UD1.V5 v1(68.26,81.76) UD1.W4 ; UD3.N2 v1(105.16,85.01) UD3.P3 UD3.N4 ; UD4.T1 v1(124.42,83.71) 124.42,84.3 UD4.P1 ; v1(114.43,81.94) 114.57,82.08 UD4.V12 ; UU1.AL2 UU1.AM2 UU1.AN2 ; UD1.G3 v1(69.86,88.91) ; UD4.C5 v1(121.22,91.51) ; UD3.K4 v1(105,86.31) UD3.N4 ; UD3.K4 103.54,86.84 102.21,86.84 v1(101.69,86.32) 102.31,85.7 103.61,85.7 UD3.N4 ; UD3.K4 UD3.J3 v1(105.16,87.61) UD3.K2 ; UD1.E1 71.99,90.53 v1(72.13,90.68) ; UD1.G8 65.8,88.91 v1(67.49,88.91) UD1.G5 ; v1(122.82,88.91) UD4.G3 v1(122.82,89.56) v1(122.82,90.21) ; v1(106.76,92.16) UD3.C1 v1(105.96,91.51) UD3.D2 UD3.E1 ; UD1.V8 v1(65.89,81.76) ; UD2.E12 v1(79.54,90.21) ; UD3.G10 v1(99.56,88.91) ; UD2.D9 v1(82.71,91.51) UD2.C8 ; v1(89.79,90.68) 89.64,90.53 UD2.E1 ; UD1.Y8 v1(65.06,81.11) UD1.W9 ; UD4.A10 v1(117.25,93.46) ; UD4.W4 v1(121.22,81.76) UD4.V5 ; UD1.E8 v1(65.86,90.86) ; UD2.V5 v1(85.91,81.76) UD2.W4 ; UD2.N2 v1(87.51,85.01) UD2.P3 UD2.N4 ; v1(84.04,86.32) 84.67,86.95 86,86.95 UD2.K4 ; UD1.N4 v1(69.69,86.31) UD1.K4 ; UD1.N4 68.31,85.7 67.01,85.7 v1(66.39,86.32) 66.91,86.84 68.23,86.84 UD1.K4 ; UD1.N4 UD1.P3 v1(69.86,85.01) UD1.N2 ; UD3.E12 UD3.D11 v1(97.96,91.51) UD3.C12 v1(97.16,92.16) ; UD3.W2 v1(105.96,81.11) UD3.Y1 ; ESDT3.2 v4(13.6,21.27) ; v1(96.77,81.94) 96.92,82.08 UD3.V12 ; UD4.AB8 v1(118.82,79.16) ; UD4.D4 v1(122.02,91.51) UD4.C3 ; UD1.Y1 v1(70.66,81.11) UD1.W2 ; UD1.T12 v1(62.66,83.71) ; UD4.E12 114.65,90.53 114.5,90.68 v1(114.17,90.68) ; UD2.C3 v1(87.54,91.51) UD2.D2 ; UD3.Y3 v1(104.36,80.46) ; UD2.P1 89.11,84.3 v1(89.11,83.71) UD2.T1 ; v1(117.22,83.71) 117.21,83.68 UD4.T10 ; UD3.T10 v1(99.59,83.71) ; ESDT10.2 13.99,16.58 v1(14.35,16.58) ; UD2.T5 v1(85.11,83.71) ; v1(124.84,81.94) 124.69,82.08 UD4.V1 ; UD2.A10 v1(81.91,93.46) ; UD1.G12 v1(62.66,88.91) ; UD4.Y10 v1(117.22,81.11) ; UD4.K9 v1(117.22,87.61) UD4.J10 UD4.K11 ; UD3.D4 v1(104.36,91.51) UD3.C3 ; v4(49.53,52.78) 49.5,52.78 49.03,53.25 PU301.8 ; UD3.AB8 v1(101.16,79.81) ; UD4.C8 v1(118.02,91.51) UD4.D9 v1(117.25,91.51) UD4.C10 ; UD2.W2 v1(88.31,81.11) UD2.Y1 ; UD3.V8 v1(100.36,81.76) UD3.W9 ; UD4.K4 v1(122.65,86.31) UD4.N4 UD4.P3 v1(122.82,85.01) UD4.N2 ; UD4.K4 120.67,86.32 v1(119.35,86.32) ; UD4.K4 UD4.J3 v1(122.82,87.61) UD4.K2 ; UD1.Y3 v1(69.06,80.46) ; UD2.E8 v1(83.51,90.86) ; UD2.G1 v1(89.11,88.91) 89.11,88.32 UD2.J1 ; UD3.G8 v1(101.16,88.91) ; UD3.V1 107.02,82.08 v1(107.39,81.71) ; UD1.C10 v1(64.26,92.16) ; UD4.T3 v1(122.82,83.71) ; UD3.J1 106.77,88.32 v1(106.77,88.91) UD3.G1 ; UD2.N9 82.33,86.18 v1(82.18,86.32) 82.33,86.46 UD2.K9 v1(81.91,87.61) UD2.J10 UD2.K11 ; UD4.Y5 v1(121.22,80.46) ; UD1.E12 61.89,90.21 v1(61.86,90.21) ; v1(105.16,89.56) UD3.G3 v1(105.16,88.91) ; UD1.AB5 v1(67.49,79.81) ; v1(97.19,84.36) UD3.P12 ; UD4.N11 UD4.P10 v1(117.22,85.01) UD4.N9 117.63,86.18 v1(117.49,86.32) ; UD2.E5 v1(85.94,90.21) ; UD1.J12 v1(61.89,88.26) ; UD1.C1 v1(70.69,91.51) UD1.D2 ; UD1.V1 71.71,82.08 v1(72.08,81.71) ; UD1.T5 v1(67.46,83.71) ; UD2.G12 v1(80.31,88.91) ; UD2.J3 v1(87.51,87.61) UD2.K2 ; UD3.AB5 v1(102.76,79.16) ; UD1.AB8 v1(65.86,79.16) ; UD1.G10 v1(64.26,89.56) ; UD3.K11 UD3.J10 v1(99.56,87.61) UD3.K9 99.98,86.46 v1(99.84,86.32) 99.98,86.18 UD3.N9 v1(99.56,85.01) UD3.P10 UD3.N11 ; UD4.P12 115.1,84.82 114.53,84.82 114.3,84.59 114.3,84.26 v1(114.85,83.71) UD4.T12 ; v1(97.94,83.71) 97.94,83.68 UD3.T12 ; UD3.Y5 v1(103.56,80.46) ; UD1.W11 v1(62.69,81.11) ; UD3.C5 v1(102.76,91.51) ; UD4.G10 v1(117.22,88.91) ; UD3.E8 v1(101.17,90.86) ; UD4.E5 v1(120.42,90.21) ; UD3.G12 v1(97.19,89.56) ; UD2.C10 v1(81.91,92.16) ; UD4.W9 v1(118.02,81.76) UD4.V8 ; UD3.A10 v1(99.56,93.46) ; UD2.Y10 v1(81.11,80.46) ; UD1.C5 v1(68.29,91.51) UD1.D4 ; UD2.P10 v1(81.13,85.01) UD2.N11 ; UD1.V12 v1(61.89,81.76) ; UD3.P1 106.77,84.3 v1(106.77,83.71) UD3.T1 ; UD4.E8 v1(118.82,90.21) ; v1(79.5,82.3) 79.65,82.32 UD2.V12 ; UD1.T3 v1(69.86,83.71) ; UD1.K2 v1(69.86,87.61) UD1.J3 UD1.K4 ; UD3.C10 v1(99.56,91.51) UD3.D9 v1(100.36,91.51) UD3.C8 ; UD1.D11 v1(62.69,91.51) ; ESDT2.2 v4(14.1,23.79) ; UD4.G5 v1(120.45,88.91) ; UD1.T10 v1(63.46,83.71) ; UD2.AB10 v1(81.11,79.16) ; UD1.E5 v1(68.29,90.21) ; UD1.Y5 v1(68.26,80.46) ; UD4.Y12 115.62,81.11 v1(115.65,81.11) 115.65,81.13 UD4.W11 ; UD3.AB3 v1(104.36,79.16) ; UD2.AB8 v1(83.51,79.16) ; UD3.E5 v1(102.76,90.21) ; UD2.W11 v1(80.34,81.11) ; UD1.C12 v1(61.89,92.16) ; UD4.Y3 v1(122.82,80.46) ; UD1.P10 v1(63.47,85.01) UD1.N11 ; UD4.E1 v1(123.62,90.86) ; UD3.G5 v1(102.79,88.91) ; UD4.G1 v1(124.42,88.91) 124.42,88.32 UD4.J1 ; UD2.Y5 v1(85.91,80.46) ; UD3.Y8 v1(100.36,80.46) ; UD4.T8 v1(118.82,83.71) ; UD1.AB3 v1(69.06,79.16) ; UD2.A3 v1(87.54,92.81) ; UD3.A3 v1(104.36,93.58) ; UD2.V8 v1(83.54,81.76) ; UD3.T3 v1(105.16,83.71) ; UD2.G8 83.45,88.91 v1(85.14,88.91) UD2.G5 ; UD4.C1 v1(124.42,91.51) ; UD1.T1 v1(71.46,83.71) 71.46,84.3 UD1.P1 ; UD2.V1 89.36,82.08 v1(89.74,81.71) ; UD2.T12 v1(80.31,83.71) ; UD2.AB5 v1(85.14,79.81) ; UD2.D11 v1(80.34,91.51) ; v1(61.89,84.36) UD1.P12 ; v1(79.54,84.36) UD2.P12 ; UD1.N9 64.67,86.18 v1(64.53,86.32) 64.67,86.46 UD1.K9 v1(64.26,87.61) UD1.J10 UD1.K11 ; UD1.AB10 v1(63.46,79.16) ; UD3.J12 v1(97.19,88.26) ; UD4.G8 v1(118.82,88.91) ; UD1.Y10 v1(63.46,80.46) ; UD2.D4 v1(85.94,91.51) UD2.C5 ; UD2.T3 v1(87.51,83.71) ; UD3.W11 v1(97.96,81.11) UD3.Y12 ; UD1.Y12 v1(61.89,80.46) ; UD2.G3 v1(87.51,88.91) ; v4(14.35,18.23) 13.99,18.23 ESDT11.2 ; UD4.D11 v1(115.62,91.51) UD4.C12 ; UD1.T8 v1(65.86,83.71) ; UD2.J12 v1(79.54,88.26) ; UD4.Y1 v1(123.62,81.11) UD4.W2 ; UD4.AB3 v1(122.82,79.16) ; UD4.Y8 v1(118.02,80.46) ; UD1.A3 v1(69.06,93.46) ; UD4.AB10 v1(117.22,79.81) ; UD2.T10 v1(81.11,83.71) ; UD3.W4 v1(103.56,81.76) UD3.V5 ; UD2.AB3 v1(87.51,79.81) ; UD3.T8 v1(101.16,83.71) ; UD3.AB10 v1(98.76,79.16) ; UD1.C8 v1(65.06,91.51) UD1.D9 ; UD4.T5 v1(120.42,83.71) ; UD1.A10 v1(64.26,93.46) ; UD1.C3 v1(69.09,91.51) ; UD3.Y10 v1(98.76,80.46) ; UD2.C1 v1(88.34,91.51) ; UD2.Y12 v1(79.54,80.46) ; UD3.T5 v1(102.76,83.71) ; UD2.Y3 v1(87.51,81.11) ; UD4.AB5 v1(120.45,79.81) ; UD2.T8 v1(83.51,83.71) ; UD2.C12 v1(79.54,92.16)
  BOTTOM w0.254: v4(184.71,54.33) 184.73,54.35 JDB1.41 186.4,53.08 v4(186.48,53.01) ; UV2.AD13 150.89,78.81 v1(150.49,78.42) UV2.AD12 149.3,79.61 UV2.AE11 149.23,79.61 v1(148.88,79.97) 148.88,80.04 UV2.AF11 ; v2(67.58,62.48) 67.58,62.74 UU1.DL44 ; UV2.AB11 v1(149.65,76.78) ; UU1.CY41 72.51,61.11 v2(72.41,61.11) ; UU1.DU47 64.54,65.15 UU1.DU48 63.89,65.16 UU1.DV48 63.82,65.23 63.36,65.23 UU1.DW48 63,65.33 v2(62.82,65.14) ; UU1.G21 108.78,52.02 v2(109.07,51.62) ; UU1.AN42 v2(96.44,62.33) UU1.AN43 ; UU1.AN42 UU1.AN43 ; UU1.AN42 UU1.AN41 ; UU1.AN42 v2(96.44,61.7) UU1.AN41 ; UU1.AV45 93.8,63.4 UU1.AT45 94.34,63.54 94.34,64.02 v2(94.31,64.04) 94.34,64.07 94.34,64.75 UU1.AT47 ; UU1.AV45 92.56,63.46 92.37,63.46 UU1.BA45 ; UU1.AV45 93.19,63.46 93.3,62.84 UU1.AV43 ; UV3.H2 180.17,69.52 180.17,70.23 UV3.H1 v1(180.21,70.84) ; UU1.DT42 64.89,62.28 v2(64.72,62.45) ; v2(107.97,59.66) UU1.J36 v2(107.32,59.66) ; v2(107.97,59.66) 108.61,59.66 v2(108.62,59.65) ; v2(107.97,59.66) UU1.H36 v2(108.62,59.65) ; v2(107.97,59.66) v2(107.32,59.66) ; v4(139.93,78.49) 140.45,77.96 UV2.AC2 ; UU1.AG41 v2(99.19,61.07) ; UU1.AG41 UU1.AG39 ; UU1.AG41 v2(99.19,61.71) ; UU1.AG41 UU1.AG42 ; v2(99.19,61.07) v2(99.19,61.71) ; v2(99.19,61.07) v2(99.19,60.44) ; v2(99.19,61.07) UU1.AG39 ; UV2.U5 v1(143.83,72.59) ; UU1.H21 108.13,52.02 v2(108.42,51.62) ; UU1.L41 UU1.L39 v2(107.42,61.07) v2(107.42,61.71) ; UU1.L41 UU1.L42 ; UU1.L41 v2(107.42,61.71) ; UU1.AV39 UU1.AV38 93.7,60.44 ; UU1.AV39 93.7,60.44 ; UU1.AV39 v2(93.7,61.07) ; UU1.AV39 UU1.AV41 ; UU1.DE33 70.6,57.56 70.28,57.25 70.27,57.25 ; v2(109.07,53.4) 108.74,53.72 UU1.G24 ; v2(107.32,59.66) v2(106.67,59.66) ; v2(107.32,59.66) UU1.L36 v2(106.67,59.66) ; v4(182.78,39.2) 182.78,39.2 JDB1.27 ; v1(153.75,78.44) UV2.AD16 ; QV22.2 170.16,49.49 169.8,49.86 v4(169.42,49.86) ; UU1.CA42 UU1.CA43 ; UU1.CA42 82.49,61.91 v2(82.72,61.71) 82.72,61.71 UU1.CA41 UU1.CA42 ; UU1.CA42 v2(82.72,62.34) UU1.CA43 ; UU1.CA43 82.6,63.43 ; CV203.2 v1(156.94,86.71) ; v1(180.09,78.55) 180.21,78.68 UV4.K1 ; UU1.H33 v2(107.77,57.84) ; UU1.BA45 91.5,63.43 90.69,63.43 UU1.BD45 ; UU1.BA45 v2(91.87,64.11) UU1.BA47 ; v4(182.67,44.02) 182.86,44.2 JDB1.17 ; PC401.2 v1(37.72,62.3) ; v2(93.7,58.92) UU1.AU37 93.7,60.44 ; UU1.T36 104.89,59.24 v2(104.94,59.19) 104.94,59.45 UU1.R37 ; UU1.T36 104.23,59.24 103.84,59.24 UU1.V36 ; UU1.T36 UU1.R37 ; UU1.CT39 74.54,60.96 74.28,60.96 v2(74.25,60.99) ; v2(99.19,60.44) 98.91,60.16 UU1.AG38 UU1.AG39 ; v2(99.19,60.44) UU1.AF37 UU1.AD37 ; v2(99.19,60.44) UU1.AG39 ; v2(68.32,57.87) 68.65,57.48 ; 68.65,57.48 UU1.DJ33 ; 68.65,57.48 68.34,56.99 v2(68.35,56.98) 68.34,56.96 68.35,56.95 68.35,56.93 UU1.DJ31 ; UU1.BF47 89.32,64.73 89.32,64.53 v2(89.37,64.1) UU1.BF45 ; UU1.T45 104.88,63.33 105.16,63.33 105.35,63.51 UU1.N45 105.71,63.46 106.91,63.46 UU1.L45 ; UU1.T45 104.38,62.91 UU1.T43 ; UU1.T45 104.32,63.46 103.18,63.46 UU1.V45 103.04,63.43 102.29,63.43 UU1.AA45 ; UU1.T45 v2(104.41,64.09) 104.38,64.13 UU1.T47 ; UU1.DF28 69.95,54.99 v2(70.27,54.66) 70.27,54.76 UU1.DE28 70.79,55.27 v2(71.13,55.27) 71.13,55.38 UU1.DE29 ; PU201.8 48.88,45.35 v1(49.15,45.08) ; v2(62.77,64.15) 62.89,64.03 UU1.DW46 ; UV4.M5 v1(179.02,82.03) 179.02,82.05 UV4.L5 ; J3001.8 v4(128.18,3.5) ; JSSD1.21 31.05,7.73 v4(31.09,7.69) ; JSSD1.39 26.55,9.86 v4(26.8,10.11) ; UU1.DG22 v2(69.62,52.17) 69.95,52.5 UU1.DF22 ; RV126.2 150.92,55.22 150.65,54.94 150.44,54.94 v1(150.32,54.81) RV127.2 ; 70.27,57.25 70.26,57.25 69.95,57.56 UU1.DF33 ; 70.27,57.25 v2(70.27,57.23) ; UU1.AF47 v2(99.3,64.11) 99.3,63.58 UU1.AF45 ; UU1.BD45 90.5,63.4 89.76,63.4 UU1.BF45 ; UU1.BD45 UU1.BD43 ; v4(147.7,16) 147.42,16.28 146.76,16.28 146.68,16.2 JW1.57 ; v2(80.89,59.79) 80.97,59.7 81.46,59.7 UU1.CB37 ; UU1.DJ19 68.65,51.1 68.45,51.3 68.45,51.41 v2(68.38,51.48) 68.37,51.61 68.65,51.96 UU1.DJ21 ; JW1.51 146.9,17.7 v4(146.95,17.75) ; v2(106.67,59.66) UU1.M36 v2(106.02,59.66) v2(106.67,59.66) ; 147.99,51.23 148.01,51.25 YV1.2 ; 147.99,51.23 147.51,51.23 147.26,51.48 v4(147.26,54.24) 147.28,54.21 CV48.1 ; 147.99,51.23 150.1,51.23 150.38,51.51 150.38,52.01 v1(150.37,52.02) ; UV3.D10 176.96,63.08 176.54,63.49 175.83,63.49 UV3.B10 v1(175.81,62.67) ; UU1.DB35 72.22,59.13 v2(72.42,59.13) ; v4(176.02,35.06) 176.17,35.21 PU1101.8 ; v2(66.9,61.62) 66.7,61.83 UU1.DN42 ; UU1.AG42 UU1.AG43 ; UU1.AG42 v2(99.19,61.71) ; UU1.AG42 v2(99.19,62.34) ; UU1.AG43 v2(99.19,62.34) ; UU1.AG43 UU1.AF45 ; UU1.CT42 75,62.27 75.07,62.25 v2(75.15,62.28) ; v2(99.19,62.34) v2(99.19,61.71) ; UU1.AL45 96.78,63.42 95.71,63.42 UU1.AN45 ; UU1.AL45 v2(96.85,64.05) 96.85,64.16 96.87,64.18 UU1.AL47 ; UU1.AL45 96.54,63.19 UU1.AN43 ; UU1.AL45 97.53,63.43 98.04,63.43 UU1.AH45 98.2,63.44 98.58,63.44 99.33,63.54 UU1.AF45 ; UU1.CG47 79.58,64.56 79.58,64.19 v2(79.61,64.16) 79.58,64.12 79.58,63.73 UU1.CG45 79.52,63.35 UU1.CG43 79.52,62.65 78.81,61.94 v2(78.79,61.94) 78.77,61.93 78.38,62.06 UU1.CJ42 78.16,62.3 77.63,62.3 77.44,62.11 ; UU1.DU32 64.43,57.24 64.69,57.24 v2(64.72,57.26) 64.74,57.24 65.02,57.24 UU1.DT32 ; JSSD1.33 28.05,7.81 28.04,7.8 v4(28.04,7.59) 28.09,7.54 29.36,7.54 29.55,7.73 JSSD1.27 ; v1(154.64,78.4) UV2.AD18 UV2.AD19 ; UU1.L45 v2(106.89,64.11) 106.96,64.18 UU1.L47 ; UU1.L45 107.55,63.38 UU1.H45 108.71,63.51 108.76,63.46 109.05,63.46 109.1,63.51 UU1.F45 ; UU1.L45 UU1.L43 ; v2(101.93,61.71) UU1.AB42 ; v2(101.93,61.71) UU1.AB41 ; v2(101.93,61.71) v2(101.93,61.07) ; v2(101.93,61.71) v2(101.93,62.34) ; UU1.AB42 UU1.AB41 ; UU1.AB42 v2(101.93,62.34) ; v2(93.7,62.34) v2(93.69,61.73) ; v2(93.7,62.34) UU1.AV42 ; v2(93.7,62.34) UU1.AV43 ; v2(93.69,61.73) UU1.AV42 ; v2(93.69,61.73) v2(93.7,61.07) ; v2(93.69,61.73) UU1.AV41 ; UU1.BD42 v2(90.95,62.34) ; UU1.BD42 UU1.BD41 ; UU1.BD42 v2(90.95,61.71) ; UU1.BD42 UU1.BD43 ; v2(90.95,62.34) UU1.BD43 ; v2(90.95,62.34) v2(90.95,61.71) ; v2(101.93,62.34) UU1.Y43 ; v2(101.93,62.34) UU1.AB43 ; UU1.Y43 102.36,62.8 101.52,62.8 UU1.AB43 ; UU1.Y43 UU1.AA45 ; UU1.AA45 UU1.AB43 ; UU1.AA45 v2(101.87,64.04) UU1.AA47 ; UU1.AA45 101.81,63.44 100.69,63.44 UU1.AC45 100.56,63.45 99.86,63.45 99.4,63.48 UU1.AF45 ; JW1.33 144.6,22.2 v4(144.57,22.17) ; UU1.A44 112.58,63.38 v2(112.65,63.45) ; v2(105.59,61.71) UU1.P41 v2(104.68,61.71) UU1.T41 ; v2(71.49,62.34) 71.49,62.34 UU1.DD42 ; v2(111.67,53.4) 111.34,53.72 UU1.B24 ; v2(75.82,56.84) 75.61,57.05 UU1.CR32 ; J3001.6 129.48,7.29 129.02,7.74 v4(128.73,7.74) ; UU1.W37 UU1.Y36 UU1.V36 ; UU1.W37 UU1.U37 ; UU1.W37 UU1.Y38 v2(101.93,60.44) ; UU1.BD41 v2(90.95,61.07) ; UU1.BD41 UU1.BD39 ; UU1.BD41 v2(90.95,61.71) ; UU1.U37 UU1.V36 ; UU1.U37 UU1.R37 ; v1(143.48,30.63) 143.94,30.63 144.37,30.2 JW1.1 ; v2(68.79,54.28) 68.79,54.34 68.65,54.49 UU1.DJ27 ; v1(176.61,80.44) 176.21,80.83 UV4.R3 176.21,80.84 ; v2(101.93,60.44) v2(101.93,61.07) ; v2(101.93,60.44) UU1.AB39 ; v2(101.93,60.44) 101.48,60.16 UU1.AB38 UU1.AB39 ; v1(146.37,77.63) 146.41,77.63 UV2.AC8 ; UU1.AN41 v2(96.44,61.07) UU1.AN39 ; UU1.AN41 UU1.AN39 ; v2(93.7,61.07) UU1.AV41 ; 82.6,63.43 UU1.BY45 83.57,63.51 83.62,63.46 83.86,63.46 83.92,63.51 UU1.BU45 ; 82.6,63.43 UU1.CB45 ; UU1.CU47 74.35,64.18 v2(74.28,64.11) 74.28,63.58 UU1.CU45 ; v2(66.36,57.12) 66.35,56.99 UU1.DN31 ; JW1.69 146.84,13.2 146.94,13.1 v4(146.93,13.1) ; v2(90.95,60.44) UU1.BD39 ; v2(90.95,60.44) UU1.BC37 v2(90.96,58.75) ; v2(90.95,60.44) v2(90.95,61.07) ; v2(90.95,60.44) UU1.BD38 UU1.BD39 ; UU1.BD39 v2(90.95,61.07) ; UU1.CK45 77.91,63.32 77.05,63.32 UU1.CM45 76.87,63.53 76.87,64.07 v2(76.85,64.08) UU1.CM47 ; UU1.DE45 70.65,63.46 71.52,63.46 71.57,63.51 UU1.DB45 71.85,63.51 v2(71.85,64.08) 71.85,64.08 UU1.DB47 ; v1(173.78,41.17) PC1102.2 ; UU1.BW37 UU1.BY37 ; UU1.BY37 UU1.CB37 ; UU1.BY37 82.72,60.43 v2(82.72,60.44) 82.54,60.44 UU1.CA38 81.81,59.7 UU1.CB37 ; v4(182.57,45.9) 182.77,45.7 JDB1.14 v4(184.81,45.7) ; UU1.AB41 v2(101.93,61.07) ; UU1.AB41 UU1.AB39 ; v2(111.02,53.4) 110.69,53.72 UU1.C24 ; UU1.M49 106.11,65.99 v2(105.79,65.99) 105.79,65.59 UU1.N49 ; UU1.BJ41 87.97,61.68 v2(88.25,61.68) 88.3,61.68 88.51,61.46 UU1.BG41 ; v2(74.21,58.55) v2(74.21,59.18) 73.79,58.89 UU1.CV35 ; v2(74.21,58.55) 73.79,58.24 UU1.CV34 UU1.CV35 ; v2(74.21,58.55) 73.79,58.86 UU1.CV35 ; v2(87.31,63) 87.82,63.51 UU1.BJ45 88.16,63.46 89.32,63.46 UU1.BF45 ; v2(87.31,63) 87.31,63.06 UU1.BM45 86.81,63.46 85.66,63.46 UU1.BR45 ; v2(87.31,63) 87.31,62.98 87.53,62.76 UU1.BJ43 ; 67.38,26.67 PQ902.2 ; JSSD1.57 22.05,8.31 21.69,7.95 v4(21.21,7.95) ; v2(66.37,51.47) UU1.DN19 ; v2(113.92,37.54) 113.66,37.79 RU211.1 ; JDB1.9 v4(182.71,48.2) ; v4(181.61,49.1) CB413.1 ; UU1.AV42 UU1.AV41 ; UU1.AV42 UU1.AV43 ; UU1.DF39 v2(70.57,61.07) ; UU1.BT39 UU1.BT41 UU1.BT42 ; v1(171.91,36.58) PR1111.1 173.15,36.58 PR1103.1 ; UU1.DF35 70.4,59.14 v2(70.54,59.14) 70.54,59.15 UU1.DD37 71.47,59.79 v2(71.49,59.88) 71.55,59.87 71.93,60.16 UU1.DB38 v2(72.4,60.44) ; UV2.U2 v1(141.1,72.99) ; v2(108.62,59.65) 108.96,59.24 UU1.G36 ; JSSD1.1 36.05,9.89 v4(35.81,10.13) 35.55,9.87 JSSD1.3 ; CU40.2 v2(112.9,36.01) ; RU76.1 v2(114.68,37.54) ; UU1.H24 108.09,53.72 v2(108.42,53.4) ; v1(143.81,25.07) 143.81,25.17 144.35,25.7 JW1.19 ; UU1.BT42 UU1.BT43 UU1.BR45 ; UU1.BT42 v2(85.46,62.34) UU1.BP43 UU1.BR45 ; v1(162.83,77.54) 162.38,77.99 161.66,77.99 UV2.AC26 ; UU1.BU45 84.45,63.42 85.52,63.42 UU1.BR45 ; UU1.BU45 v2(84.29,64.11) UU1.BU47 ; UU1.DN36 66.97,59.59 v2(66.97,59.69) ; v2(66.35,53.39) 66.35,53.48 UU1.DN24 ; RV113.2 136.78,60.68 136.53,60.42 v1(136.53,60.4) 136.86,60.07 RV114.2 ; v1(123.62,90.86) UD4.D2 UD4.C1 ; v2(113.54,64.19) 112.36,64.19 112.19,64.03 UU1.A46 ; UU1.AN39 v2(96.44,60.44) UU1.AN38 UU1.AN39 ; v4(24.74,15.42) 24.28,14.96 RT97.1 ; UU1.DE17 70.92,50.43 v2(70.92,50.51) UU1.DE18 v2(70.92,51.34) UU1.DE20 v2(70.92,52.17) UU1.DE22 70.9,52.98 70.59,53.38 UU1.DE23 70.92,53.83 UU1.DE26 v2(71,54.72) ; v1(141.46,68.41) UV2.L2 ; UU1.DT20 65,52.02 v2(64.77,52.02) 64.45,52.02 UU1.DU20 UU1.DW20 ; JW1.75 146.91,11.7 v4(146.96,11.76) ; v1(161.25,62.7) 160.88,63.06 UV2.E25 ; UU1.CB45 81.84,63.53 81.84,64.06 81.82,64.08 v2(81.82,64.11) 81.86,64.15 UU1.CB47 ; UU1.CB45 81.54,63.46 80.65,63.46 UU1.CE45 ; UU1.E34 109.53,58.28 109.53,58.66 v2(109.48,58.72) 109.53,58.77 109.53,59.16 UU1.E36 109.47,59.64 v2(109.27,59.66) ; v4(89.06,5.53) 89.06,6.42 PJ101.9 90.3,6.46 v4(90.3,5.53) ; v2(96.45,58.62) 96.45,59 UU1.AM37 UU1.AK37 UU1.AH37 ; JKBL3.8 v4(152.4,91.36) ; UU1.B48 UU1.A48 ; CV11.2 v1(162.53,84.77) ; v4(153.91,86.68) 153.91,86.75 CX894.2 ; RW70.1 139.19,10.18 v4(139.19,10.84) 139.29,10.84 139.57,11.12 UW1.2 ; UU1.DG47 69.49,64.63 v2(69.49,64.04) ; v4(33.78,7.57) 34.05,7.84 JSSD1.9 ; v2(68.96,61.62) 68.96,61.74 UU1.DJ42 ; v4(130.15,82.32) 129.74,82.72 QV20.2 ; 65.67,65.79 64.37,65.79 ; QV14.2 137.38,85.03 v4(137.84,85.49) ; UU1.CG37 79.48,59.5 v2(78.75,59.79) 78.36,59.54 UU1.CJ37 78,59.73 v2(77.94,59.72) 77.81,59.75 UU1.CL37 77.02,59.78 v2(77.01,59.78) 76.85,59.78 76.58,59.51 UU1.CN37 76.35,59.51 v2(76.04,59.83) 75.62,59.56 UU1.CR37 75.59,59.51 75.58,59.51 UU1.CT37 ; v2(63.09,62.5) 63.14,62.55 63.14,62.82 UU1.DW44 UU1.DV44 ; UU1.DT27 65.03,54.6 v2(64.73,54.6) 64.7,54.6 64.52,54.42 UU1.DU27 UU1.DW27 ; PR712.2 v4(41.45,85.06) ; v4(154.68,25.68) 154.41,25.95 JW1.18 ; v1(173.81,38.33) 173.71,38.23 PR1108.1 ; v1(154.22,81.17) UV2.AF17 ; v2(101.93,61.07) UU1.AB39 ; CV114.2 v1(156.92,84.78) ; JDB1.22 v4(184.76,41.7) ; v2(85.46,61.05) v2(85.46,61.78) ; v2(66.42,63.49) 66.35,63.49 UU1.DP45 ; PR627.1 104.65,15.95 v4(104.52,15.82) ; RU160.1 CU32.2 ; v4(25.05,10.18) JSSD1.45 ; QV11.2 v4(134.29,84.07) ; QV19.2 v1(162.05,90.51) ; v2(88.21,59.01) UU1.BH37 ; v2(76.07,61.11) 76.23,61.11 UU1.CN39 ; v2(68.32,59.7) UU1.DJ36 ; UU1.L43 v2(107.42,62.34) ; UU1.L43 UU1.L42 ; UU1.L42 v2(107.42,62.34) ; v2(107.42,62.34) v2(107.42,61.71) ; UU1.DT37 65.14,59.66 64.95,59.46 64.91,59.46 v2(64.83,59.39) 64.8,59.41 64.68,59.41 64.67,59.42 64.48,59.42 UU1.DU37 ; UV2.AE17 v1(154.59,79.99) ; JW1.76 148.04,31.3 v4(148.64,30.71) ; v4(176.12,39.7) 176.17,39.65 PU1101.18 ; QV7.2 133.45,58.41 133.08,58.04 133.08,57.41 v1(133.06,57.39) 132.86,57.19 RV143.1 CV24.2 ; v2(100.57,57.45) UU1.AD34 ; UU1.K33 v2(106.84,57.84) ; JW1.45 144.6,19.2 v4(144.57,19.17) ; JSSD1.51 v4(23.55,10.21) ; v4(174.02,34.36) 173.97,34.31 RA19.2 174.16,33.54 CA36.2 ; PU701.3 v4(46.12,78.41) ; UU1.F47 109.52,64.21 v2(109.44,64.13) 109.5,64.06 UU1.F45 ; CV25.2 v1(162.57,85.71) ; v2(140.69,8.71) 140.69,8.68 140.4,8.4 J1.3 ; UV2.AD15 v1(152.96,79.2) ; v1(144.64,68.44) UV2.L5 ; JSSD1.76 v4(37.15,9.95) ; UV2.E2 v1(141.46,62.69) ; RV121.2 v1(136.45,58.85) ; UU1.C39 110.44,60.65 v2(110.39,60.71) 110.34,60.66 110.06,60.66 UU1.E39 109.66,61.33 109.66,61.44 UU1.E42 ; JKBL3.7 v4(147.9,91.39) ; UU1.F45 109.74,63.28 UU1.D44 ; SW4.3 v4(9.53,4.95) ; JW1.63 v4(144.53,14.7) ; UU1.BM47 v2(86.86,64.07) ; v4(144.47,20.7) JW1.39 ; UV2.P5 v1(144.61,70.89) ; CV12.2 v1(163.06,86.84) ; 71.95,57.29 UU1.DA33 72.41,57.64 72.36,56.9 v2(72.35,56.89) 72.35,56.89 UU1.DB32 71.95,57.29
  BOTTOM w0.279: UU1.BD7 v2(90.95,45.06) UU1.BB7 ; CX22.2 RX22.1 27.94,73.23 v1(28.07,73.35) 28.07,73 28.34,72.72 RX16.1 ; UU1.DA10 UU1.DA9 71.77,45.7 v2(71.76,45.68) 71.74,45.66 71.74,45.13 v2(71.76,45.11) 71.74,45.08 71.74,44.48 v2(71.76,44.46) 71.58,44.28 UU1.DC5 UU1.DC3 ; CE24.2 CE23.2 62.94,9.34 62.66,9.07 v2(62.61,9.07) ; UU1.H31 v2(108.38,57.11) UU1.G31 ; v2(57.78,49.2) 57.94,49.35 RU63.1 RU62.1 ; JX1.12 21.7,75.93 v1(21.94,76.17) ; QV6.4 141.57,51.16 141.09,51.64 v1(141.09,51.79) ; v4(17.04,13.54) 16.38,13.54 16.13,13.79 CL33.2 ; v1(50.93,38.88) 50.85,38.88 50.57,39.16 CT12.2 CT13.2 ; CE14.2 143.76,19.76 v4(144.02,19.5) ; v1(178.91,92.71) 178.78,92.58 CV132.2 ; 67.38,26.67 67.18,26.87 67.18,30.58 v2(67.66,31.06) ; v4(33.78,7.57) 33.65,7.69 32.83,7.69 32.55,7.97 JSSD1.15 ; CU39.2 57.83,64.26 v2(57.91,64.34) RU176.2 ; RU160.1 RU181.2 80.64,37.56 80.64,36.68 v2(80.67,36.65) ; v4(147.32,30.2) 147.32,27.86 146.66,27.2 JW1.13 ; UU1.DK3 UU1.DK4 67.87,44.55 68,44.67 UU1.DK6 68,44.8 v2(67.64,45.16) 67.64,45.23 UU1.DK8 68,45.71 ; v2(78.47,36.65) 78.48,36.67 CU35.2 ; UV4.H13 v1(182.21,89.24) UV4.H14 ; v4(51.97,64.39) 51.97,64.67 51.43,65.2 PC972.2 ; v4(10.87,23.8) 10.87,23.56 RT132.2 ; v2(45.73,19.64) PC111.2 45.72,19 44.96,19 ; PC309.2 47.6,51.36 47.83,51.13 v4(48.26,51.13) 48.26,51.53 PC319.2 ; v2(64.01,72.21) 63.88,72.08 CU6.2 63.37,72.92 62.77,73.52 60.65,73.52 60.37,73.25 v4(60.37,72.49) 60.45,72.41 v4(60.45,71.57) 60.45,69.54 60.7,69.29 62.86,69.29 v2(63.37,69.8) ; QL7.2 11.41,10.36 v4(11.61,10.36) ; UU1.CV5 73.78,43.6 73.79,43.58 v2(73.79,43.58) 73.79,43.3 UU1.CV3 ; UU1.AD11 100.44,47.33 100.18,47.06 ; v1(140.73,60.18) 140.73,60.31 UV2.B1 ; RX920.2 33.15,69.16 v1(32.51,69.16) 32,69.16 v1(31.49,69.67) ; PC503.2 73.15,24.46 73.53,24.84 v2(73.66,24.84) PR503.1 ; v1(174.21,78.84) UV4.U1 v1(175.01,79.64) ; v4(109.35,8.63) 109.35,7.61 PJ101.10 110.53,7.69 v4(110.53,8.63) ; v4(61.26,64.23) 61.16,64.34 CU170.2 ; RT63.1 27.3,16.84 26.87,16.41 v2(25.91,16.41) ; v2(83.64,43.11) UU1.BW3 82.99,43.43 v2(82.71,43.71) ; PC320.2 v1(50.04,51.13) ; v1(9.88,9.32) 9.76,9.2 ESDT6.3 9.19,9.5 9.29,9.6 CT73.2 RT123.1 8.76,9.75 8.33,9.32 CT80.2 ; PC214.2 48.87,43.41 49.15,43.13 v2(49.15,42.62) ; 56.89,86.56 v2(56.89,87.07) ; UV2.B8 146.72,60.56 v1(146.72,59.87) ; JW1.7 144.68,28.7 v2(144.47,28.91) ; UU1.BT42 v2(85.46,61.78) UU1.BT41 ; CV195.1 149.58,85.39 149.3,85.67 v4(149.22,85.67) 149.04,85.49 RV64.2 ; ESDB34.3 21.18,37.26 v2(21.59,36.85) ; v2(82.71,43.71) 83.09,44.08 UU1.BW5 83.63,43.76 v2(83.64,43.71) 83.69,43.71 83.96,43.43 UU1.BV3 UU1.BT3 85.41,43.72 v2(85.49,43.71) 85.52,43.71 UU1.BP3 ; v2(82.71,43.71) 82.44,43.43 82.27,43.43 82.19,43.51 v2(81.79,43.51) 81.7,43.17 UU1.CC3 ; RT55.1 23.75,17.09 v2(23.62,16.96) ; 58.16,47.06 58.01,47.22 55.76,47.22 55.46,46.91 YU2.4 55.46,45.48 55.17,45.18 v4(55.07,45.18) 54.76,45.18 54.48,44.9 54.48,43.28 55.27,42.49 v2(55.52,42.49) 56.39,42.49 57.06,43.16 57.06,43.27 ; 58.16,47.06 58.29,47.19 59.05,47.19 60.26,45.98 ; 58.16,47.06 CU9.2 ; v2(67.79,69.8) 67.44,70.15 RU177.2 ; PQ902.2 67.6,25.94 67.82,25.73 67.82,25.47 68.03,25.26 PQ901.2 ; UU1.BT39 v2(85.46,61.05) ; UU1.CE9 80.36,46.11 79.6,46.11 UU1.CG9 79.05,45.66 v2(79.03,45.66) 79.03,45.68 UU1.CJ9 78.61,46.01 v2(78.17,45.63) 77.72,46.03 UU1.CK9 77.67,46.03 77.23,45.65 v2(77.23,45.63) 77.2,45.63 76.78,46.01 UU1.CM9 ; v4(182.75,56.82) 182.75,56.82 CV144.1 ; JE4.4 60.2,8.05 60.86,8.71 61.03,8.71 v2(61.36,9.04) 61.85,9.52 TP144.1 ; UU1.Y9 102.42,46.12 v2(102.85,46.38) ; UV4.U12 v1(174.21,88.44) ; UU1.BG7 v2(89.13,45.06) UU1.BF7 ; CV47.2 149.76,54.21 150.38,53.59 v1(150.38,52.91) ; UV4.A14 v1(187.01,89.24) ; QT1.2 49.36,31.53 v2(49.02,31.19) ; UU1.V9 103.35,45.95 103.73,45.83 v2(103.75,45.84) ; v4(18.34,45.84) 18.54,46.05 PC911.2 ; UV4.R12 v1(175.81,87.64) ; TPU9.1 57,62.86 56.31,62.86 56.13,62.68 CU10.2 55.95,61.47 56.25,61.17 v1(56.51,61.17) ; v1(162.04,61.01) 162.43,60.61 UV2.B27 ; v2(57.76,89.18) 58.01,88.92 RU60.1 ; CT9.2 CT16.2 51.25,34.43 v4(51.25,34.97) 51.15,35.07 CT1.2 50.35,34.87 v2(49.48,34.87) 49.48,35.18 49.76,35.46 CT2.2 ; RU88.1 RU141.2 ; RU141.2 58.14,42.95 57.38,42.95 57.06,43.27 ; RU141.2 RU28.1 57.66,42.36 v2(57.53,42.49) ; v4(147.57,56.59) 147.57,55.01 147.26,54.7 v4(147.26,54.24) ; PC142.2 47.5,9.98 v2(47.12,9.6) 46.86,9.85 PC141.2 ; RU22.2 v2(106.3,35.25) ; v1(142.11,81.73) 142.11,81.49 UV2.AG2 ; PR307.1 51.1,50.54 v4(50.04,49.48) ; v2(87.3,43.76) 87.62,43.43 UU1.BJ3 v2(88.21,43.76) ; v2(87.3,43.76) UU1.BM5 UU1.BM6 v2(87.3,45.06) UU1.BM7 86.52,45.06 v2(86.38,45.06) UU1.BP7 UU1.BT7 UU1.BV7 83.65,45.06 v2(83.64,45.01) 83.63,45.06 UU1.BW7 UU1.BW6 83.61,44.43 v2(83.64,44.43) ; v2(87.3,43.76) UU1.BM3 ; RL454.1 11.89,8.4 v4(11.81,8.33) ; PC1205.2 134.97,95.58 ; UU1.DV8 63.59,45.58 UU1.DW7 ; UU1.E34 110.26,58.1 v2(110.33,58.03) ; UU1.BD5 90.5,44.09 v2(90.94,44.41) 90.5,44.72 UU1.BD6 ; UV4.K13 v1(180.61,89.24) UV4.K14 ; v2(95.53,43.75) 95.52,43.69 95.08,43.43 ; RX919.1 v4(35.69,67.13) ; v4(33.78,60.4) 33.4,60.78 PU402.2 ; 23.75,27.25 24,27 24,26.87 ; v2(57.91,57.07) 57.94,57.1 RU15.1 RU100.2 ; PR504.1 73.66,27.1 v2(73.25,27.51) ; v1(31.1,68.79) 30.71,68.4 RX908.2 ; PC719.2 47.04,76.32 v4(47.55,75.82) ; JX1.26 v4(28.7,74.24) ; v2(69.19,8.86) 69.19,9.07 69.24,9.12 CS1.2 ; v2(105.73,46.05) 105.73,46.03 UU1.P8 ; UV2.B5 144.29,60.29 v1(144.01,60.01) ; v2(26.37,23.92) 26.15,23.7 CT30.2 ; UU1.DU15 UU1.DT15 65.21,49.22 v2(65.75,49.76) ; PR138.1 53.08,10.74 52.7,10.36 v2(52.7,10.21) ; v1(140.91,80.96) 141.04,80.84 UV2.AF1 ; UU1.C6 UU1.E6 v2(109.47,45.11) ; UV4.B10 v1(187.01,86.04) ; v1(177.41,88.44) UV4.N12 v1(178.21,88.44) ; UU1.DN15 66.7,49.11 v2(66.42,48.83) ; UV2.AB14 v1(151.29,77.62) ; UX1.2 v2(28.57,69.16) ; RV125.2 153.36,55.34 v1(153.56,55.54) ; UU1.AB11 v2(101.02,46.96) ; v4(53.59,16.42) PC124.1 ; v2(25.14,57.35) 25.21,57.42 CI105.1 ; v2(108.33,46.86) 108.08,46.48 UU1.J10 ; v2(108.28,16.46) 108.46,16.63 PC603.1 PC601.2 ; PC1213.2 131.77,92.89 132.15,92.5 v4(132.15,91.97) ; v2(89.15,47.65) 90.73,47.65 UU1.BB11 ; v2(128.52,90.32) 128.77,90.56 PR1201.2 129.38,90.57 PC1211.2 ; 55.24,56.72 55.24,56.18 55.27,56.16 55.93,56.16 v2(56.39,55.7) ; JX1.38 v4(34.7,74.24) ; 76.71,22.3 75.18,22.3 74.92,22.03 PC138.2 ; v2(67.69,47.9) 67.35,48.24 UU1.DL13 ; v2(106.38,46.86) 106.13,46.48 UU1.M10 ; 70.37,46.68 69.46,46.68 ; 69.46,46.68 69.46,46.67 68.83,46.05 68.33,46.05 68,45.71 ; 69.46,46.68 69.46,47.45 UU1.DG12 v2(69,48.04) UU1.DG13 69.3,48.57 v2(69,48.87) UU1.DG15 UU1.DF13 ; 68,45.71 v2(67.64,46.07) 67.64,46.21 UU1.DL10 67.04,46.2 v2(67.04,46.07) ; v2(103.38,28.12) 103.17,28.32 RU232.1 ; v2(28.49,25.18) 28.27,24.97 CT37.2 ; TPT2.1 40.91,42.89 CT3.2 ; UU1.AB5 101.48,44.08 UU1.AB6 101.76,45.01 v2(101.93,45.01) ; UU1.AN6 v2(95.54,44.36) ; PU1101.7 176.62,37.02 PU1101.21 ; UV4.N14 v1(178.21,90.04) ; CV37.2 139.77,54.23 139.32,54.68 v4(138.94,54.68) ; v4(38.86,68.15) 38.94,68.22 PC971.2 PC976.2 ; v4(81.15,27.25) 80.9,27 PR527.1 ; UV4.G10 v1(183.01,86.04) ; 55.24,59.89 v2(56.39,59.89) 56.89,59.38 CU13.1 ; v1(150.38,52.91) 149.7,52.91 YV1.4 ; v1(150.38,52.91) 150.38,52.03 v1(150.37,52.02) ; v4(24.74,15.42) 24.89,15.26 24.89,14.47 24.61,14.19 QT2.2 ; UU1.Y38 v2(102.92,60.42) ; UV4.L10 v1(179.81,86.84) ; ESDE4.2 56.14,10.35 55.88,10.61 v2(55.55,10.61) 55.5,10.56 CE55.2 ; UU1.F31 v2(109.03,57.11) ; 184.53,92.66 184.53,92.65 CV145.2 ; CT36.2 24.1,22.91 24.38,23.19 v2(24.42,23.19) ; UU1.DU48 64.54,65.62 64.37,65.79 v2(62.92,65.79) ; v2(22.35,26.36) 22.48,26.24 23.82,26.24 CT50.2 CT51.2 23.49,25.73 22.94,25.18 v2(22.38,25.18) ; UV2.AF17 154.22,80.37 v1(154.59,79.99) ; CT8.1 44.07,43.13 v4(43.94,43.25) ; v2(92.58,47.62) UU1.AV11 ; JKBL3.1 148.9,87.4 149.1,87.2 ; RT33.1 24.38,28.01 ; v4(149.1,87.14) 149.1,87.2 ; 149.1,87.2 149.4,87.49 JKBL3.2 ; CT46.2 v2(28.46,23.34) ; RT83.1 23.62,34.36 23.37,34.11 21.21,34.11 v4(21.08,33.98) 20.95,33.86 UT4.2 18.62,33.86 17.71,32.95 JB8.4 ; UV4.M10 v1(178.21,86.84) ; v2(22.35,24.26) 22.66,23.95 CT43.2 ; UU1.C31 110.71,56.69 v2(110.41,57.11) ; RV120.2 RV47.1 140.87,55.34 140.59,55.62 v4(140.59,55.83) 140.21,55.45 RV44.1 ; v2(70.82,45.11) UU1.DC6 71.15,44.56 70.82,44.52 v2(70.82,44.52) 70.58,44.52 UU1.DE6 UU1.DG6 69.11,44.38 UU1.DH5 ; v2(108.42,51.62) 108.42,51.7 UU1.G21 ; UU1.K8 v2(107.68,46.02) ; UV4.F10 v1(183.81,86.84) ; v1(177.31,92.71) 177.08,92.48 CV149.1 CV133.2 ; UU1.AT6 94.17,44.73 v2(94.63,45.01) 95.08,45.37 UU1.AR7 ; v2(96.46,44.46) 96.57,44.45 UU1.AL6 ; UV2.H5 v1(143.82,65.97) ; v4(127.39,91.51) 127.46,91.58 PC1214.2 ; v4(43.18,78.05) 43.23,78.1 PC701.2 ; CX898.2 25.19,73.17 25.19,72.16 v4(25.27,72.08) ; v2(73.53,5.41) 73.48,5.36 71.42,5.36 70.39,4.32 US1.6 ; UU1.AT7 94.17,45.38 v2(94.63,45.66) 95.08,46.02 UU1.AR9 ; 100.18,47.06 100.56,46.68 UU1.AD10 ; 100.18,47.06 v2(100.1,47.06) ; UU1.J6 v2(108.33,45.11) ; UV4.C12 v1(185.41,88.44) ; v4(35.56,60.4) 35.43,60.53 PC415.2 ; v2(62.41,46.68) 62.53,46.56 UU1.DW10 UU1.DU10 UU1.DT10 UU1.DT8 64.89,45.58 UU1.DT7 ; v2(14.63,11.53) 14.63,11.28 QL8.2 ; v2(104.93,47.33) 104.7,47.2 UU1.T11 ; RT131.2 v4(10.7,21.25) ; v2(22.35,51.13) 22.22,51 CI118.2 CI116.2 CI115.1 ; UU1.DW7 62.48,45.25 v2(62.23,45.5) 60.87,44.14 v2(58.67,44.14) CU8.2 58.08,44.06 YU2.2 57.06,43.27 ; UU1.DW7 UU1.DU7 UU1.DT7 ; PC134.2 v4(67.44,22.17) ; UU1.AT3 94.6,43.7 v2(94.61,43.76) ; RU117.1 59.18,79.5 v2(58.85,79.83) 58.55,79.52 RU113.1 ; RU179.2 67.56,71.45 v2(67.69,71.57) ; PC970.2 39.47,65.89 v4(39.27,65.68) ; v4(130.17,13.15) 129.94,12.93 UO1.4 ; v2(27.02,23.92) 27.05,23.92 27.08,23.95 CT45.2 ; PC1210.2 135.56,90.35 v4(135.62,90.28) ; UV4.P10 v1(176.61,86.84) UV4.R11 ; v4(99.44,17.35) 99.2,17.1 PESD105.1 ; v4(185.5,56.67) CV139.1 CV166.1 ; CT41.2 28.06,22.78 v2(28.42,22.42) ; v2(25.4,32.71) CT54.2 ; v4(43.43,85.01) 43.94,84.5 PC703.2 44.4,84.27 PC721.2 ; US4.2 v2(152.14,4.01) ; 82.27,45.38 81.81,45.71 v2(81.81,45.72) 81.81,45.71 UU1.CC7 ; PU1101.8 PU1101.21 ; PU1101.21 PU1101.18 ; v2(92.8,43.76) 92.34,43.43 UU1.AY3 ; JW1.77 146.91,11 146.91,11.7 ; v2(79.04,44.5) 79.04,44.47 79.01,44.44 UU1.CH5 UU1.CH3 ; CB390.2 24.15,40.91 PC913.2 25.6,40.91 v4(26.16,41.48) ; v4(11.12,71.65) 11.59,71.18 PC182.2 ; v2(82.19,36.65) 82.17,36.68 82.17,37.28 82.23,37.35 CU57.2 CU56.2 ; RU108.2 v2(57.91,55.45) ; UU1.C21 110.69,51.94 v2(111.02,51.62) 111.02,51.7 UU1.B21 111.67,51.7 v2(111.67,51.62) ; CV164.1 176.49,92.7 v1(176.51,92.71) ; SW3.3 16.74,69.27 16.64,69.16 15.62,69.16 15.52,69.27 SW3.4 12.72,69.27 v4(12.32,69.67) ; PC977.2 PR903.1 v4(51.97,63.73) ; v4(12.19,18.72) 11.89,18.72 11.34,18.17 RT119.2 ; v2(33.65,67.03) 33.3,67.38 UX2.2 31.75,67.38 v1(31.37,67) 30.86,67 30.61,67.26 RX12.1 ; UV4.D10 v1(184.61,86.84) ; v1(178.11,92.71) 178.21,92.62 CV147.1 ; RU106.2 RU65.2 v2(57.96,52.78) ; v1(11.78,16.28) 11.42,16.65 RT118.2 ; CB415.2 114.4,3.22 TPWC2.1 ; UU1.BJ7 v2(88.22,45.06) ; UV2.Y5 v1(143.83,75.88) ; RU34.2 v2(106.3,37.46) ; v2(46.48,19.63) 46.48,19 ; UU1.AB3 101.55,43.03 v2(101.55,43.51) ; CX9.1 v4(21.59,73.1) ; RT78.1 26.21,24.71 v2(26.37,24.54) ; UU1.CT37 v2(74.23,59.79) ; 57.66,81.73 v1(57.66,82.24) 57.1,82.8 CD1.2 ; UU1.A3 112.24,43.15 v2(112.47,42.92) ; UU1.A3 111.99,42.57 111.95,42.61 UU1.B2 111.44,43.16 UU1.B3 111.36,43.26 111.46,43.15 UU1.A3 ; PC969.2 51.15,68.15 v4(51.26,68.04) PC975.2 ; UU1.BF3 v2(89.12,43.76) UU1.BG3 ; UU1.DT7 65.21,44.93 UU1.DT6 ; UU1.AY7 92.46,45.51 92.93,45.51 93.06,45.38 UU1.AV7 v2(93.7,45.66) ; PR410.1 v4(36.96,64.34) PR415.1 ; CT11.2 45.21,33.6 v4(45.34,33.73) ; PC1108.2 v1(170.94,38.81) 170.94,39.3 PC825.2 ; UU1.AR11 95.08,46.97 v2(95.76,47.65) ; UV2.AA7 v1(146.37,75.88) ; v2(83.28,36.65) 83.21,36.73 CU98.2 CU97.2 ; CT72.2 RT122.1 8.76,11.88 8.43,12.21 7.72,12.21 7.62,12.32 v1(7.36,12.32) 7.36,11.28 7.43,11.21 ESDT7.3 ; PC506.2 73.89,28.75 v2(74.17,28.75) ; CV154.1 v1(182.45,92.78) ; v2(99.26,44.46) 99.07,44.25 UU1.AG5 UU1.AG3 ; v4(21.21,7.95) 21.21,8.33 20.47,9.07 20.47,10.18 21.79,11.5 21.79,12.11 RT96.1 ; UU1.DT3 UU1.DU2 ; v4(116.08,37.03) 115.95,36.9 CU55.2 ; UU1.AG9 UU1.AG11 v2(98.74,47.51) ; UU1.CN3 UU1.CN5 76.53,44.24 v2(76.31,44.46) ; RU6.1 104.77,37.59 v2(104.65,37.46) ; UU1.CY9 v2(73.57,45.68) UU1.CV9 ; UU1.BD46 UU1.BD45 ; v2(93.7,43.76) UU1.AV3 ; v4(152.4,52.14) 152.93,52.68 CV204.2 ; v2(54.4,75.21) 54.4,75.08 RU153.1 ; UU1.BD3 90.5,43.44 v2(90.94,43.76) ; v4(44.19,68.4) 44.09,68.5 PC907.2 ; v2(104.03,43.51) UU1.U5 ; v2(104.03,43.51) UU1.U3 ; v2(104.03,43.51) UU1.R3 ; v2(54.61,7.31) 54.61,5.71 JE4.10 53.34,5.86 v2(53.34,7.31) ; v4(31.14,46.43) 31.11,46.43 30.99,46.56 PR914.1 ; UD4.A3 v1(122.82,93.58) ; CT27.2 CT26.2 24.89,20.52 24.57,20.2 v2(24.57,19.19) ; v4(43.79,83.72) 43.79,83.49 44.09,83.18 PC716.2 ; v4(44.02,0.53) 44.02,2.71 JRTCU1.4 42.72,2.75 v4(42.72,0.53) ; UU1.A31 UU1.B31 111.36,56.69 111.12,57.02 v2(111.13,57.08) ; 132.94,95.58 132.96,95.56 PU1202.5 ; v2(40.83,32.5) 41.25,32.08 CT7.2 RT23.1 ; PC916.2 50.39,58.39 v4(50.54,58.24) ; CV160.1 183.04,92.43 v1(183.39,92.78) ; UV2.A2 v1(141.84,59.16) ; UV4.E14 v1(183.81,89.24) ; CU99.2 CU100.2 84.33,36.78 v2(84.45,36.65) ; 46.65,15.57 47.03,15.19 v4(47.24,15.19) ; UU1.BV11 v4(84.1,47.57) ; v4(45.46,31.54) 45.72,31.8 RT17.2 ; UV4.E12 v1(184.61,87.64) ; CT10.2 42.72,33.22 v4(42.54,33.4) ; UU1.G5 v2(108.97,43.51) UU1.G3 ; v2(69.64,53.01) 69.3,53.36 UU1.DG23 ; v4(26.41,69.16) 26.41,68.78 26.49,68.7 CX13.2 ; v4(97.28,22.81) 97.79,22.81 98.04,22.55 PC606.1 ; v4(46.33,61.59) PC406.2 v4(46.33,63.42) ; PC1107.2 v2(173.99,34.92) 174.02,34.89 v4(174.02,34.36) ; v4(22.4,61.19) 22.96,60.63 UI1.2 ; CT42.2 24.48,23.95 v2(24.42,23.89) ; UV4.U3 v1(174.21,80.44) ; v2(48.13,42.75) 48.13,42.87 47.75,43.25 PC215.2 ; v2(88.26,36.65) v2(87.5,36.65) 87.44,36.59 CU103.2 CU101.2 ; UU1.CT9 v2(75.4,45.68) UU1.CP9 ; v4(24.13,77.39) 24.7,76.82 JX1.18 ; v2(57.91,54.71) 57.94,54.68 RU99.2 RU110.2 ; UU1.AJ3 v2(98.55,43.13) 98.47,42.79 UU1.AH2 ; CX897.2 v2(23.62,74.11) 23.48,74.11 23.2,74.39 JX1.15 ; UV2.AC5 143.87,77.55 v1(143.85,77.55) ; v2(150.49,8.46) 150.75,8.71 CS3.2 ; v4(157.86,9.17) 157.4,8.71 JE7.28 ; CT79.2 10.77,8.43 v1(10.77,8.1) ; v2(64.41,3.1) 64.41,4.21 JE4.9 65.48,5.02 v2(65.48,3.1) ; UV4.T10 v1(175.01,86.84) ; v2(68.83,71.96) 68.96,72.08 RU140.1 RU139.1 CU169.2 ; JX1.32 v4(31.7,74.24) ; PC510.1 81.91,27.76 v4(81.79,27.63) ; CT17.2 v1(50.93,36.65) ; v2(58.01,9.07) 58.01,9.57 58.03,9.59 ESDE5.2 58.03,10.24 CE54.2 ; UU1.AT5 v2(94.61,44.36) ; UV4.B5 v1(187.01,82.84) ; CU168.2 v2(104.52,33.6) ; UU1.V11 103.7,47.21 v2(103.75,47.12) ; PC216.2 51.05,43.13 CT14.2 CT15.2 50.77,41.96 v1(51,41.73) ; v4(80.14,24.46) 80.01,24.58 PR521.2 ; UU1.AN2 UU1.AR3 ; PC908.2 v4(44.24,69.06) ; UU1.A48 v2(112.42,65.55) ; UV2.E5 v1(143.87,63.48) ; UU1.DE13 UU1.DE15 UU1.DE17 ; v1(181.56,92.78) RV100.2 180.76,91.98 180.4,91.62 CV118.2 ; v2(100.2,44.45) 99.92,44.73 UU1.AE6 ; UU1.BM11 v2(87.3,47.01) ; v2(80.89,59.79) UU1.CE37 80.36,59.59 79.6,59.59 UU1.CG37 ; CV168.1 186.54,57.24 v4(186.69,57.1) ; UV4.A12 v1(187.01,88.44) ; UU1.F8 v2(109.63,46.02) ; UV2.H2 v1(142.25,65.97) ; UV4.U14 v1(175.01,90.04) ; UU1.M3 v2(106.5,43.51) UU1.M5 ; UV4.R14 v1(175.81,89.24) ; RU178.2 v2(66.17,71.57) ; UT3.4 v4(37.59,33.35) ; JX1.35 v4(33.2,74.24) ; v1(132.46,51) 132.33,51.13 CV17.2 RV2.2 ; JX1.29 v4(30.2,74.24) ; v2(91.87,43.76) UU1.BB3 ; PU906.1 39.59,72.78 39.83,73.02 PC906.2 v4(39.83,74.19) ; JX1.21 v4(26.2,74.23) ; UV4.C14 v1(185.41,90.04) ; v4(66.55,22.17) PC130.2 ; UU1.P11 v2(105.79,47.83) ; UU1.D31 v2(109.68,57.11) ; PC978.2 v1(36.07,70.69)
  BOTTOM w0.292: v1(186.21,86.84) UV4.C11 ; v1(175.81,69.07) UV3.C3 176.21,68.67 v1(175.81,68.27) UV3.C4 ; UV3.A1 174.28,69.94 v1(174.13,69.94)
  BOTTOM w0.305: UV3.A12 174.61,61.47 v1(175.02,61.05) ; v1(162.26,81.45) 162.03,81.21 UV2.AG26 ; UV2.L25 160.5,68.37 160.48,68.37 v1(160.44,68.41) ; v1(146.37,77.63) 146.37,77.61 UV2.AB7 ; v1(177.41,79.64) UV4.N1 177.81,79.24 v1(177.41,78.84) ; v1(177.41,69.87) 177.81,70.27 ; v1(161.23,73.4) UV2.U26 ; UV3.G5 179.03,67.46 v1(179,67.46) ; UV2.U23 159.39,73.15 159.64,73.39 v1(159.64,73.41) ; UV2.M11 v1(148.34,68.12) ; UV4.C4 v1(186.21,82.04) ; v1(148.84,58.11) 149.18,58.45 149.18,60.54 UV2.B11 ; UV2.AB20 v1(157.09,76.8) ; v1(158.11,91.97) 158.32,91.76 CX892.1 ; UV2.H23 159.24,65.55 v1(158.82,65.13) ; v1(160.78,40.66) 161,40.45 PC824.2 ; v1(159.63,75.87) UV2.Y23 v1(158.83,75.07) ; v1(184.61,70.67) 184.22,70.28 UV3.N1 v1(184.61,69.87) ; UV3.T5 v1(187.02,66.67) ; v1(154.61,77.66) 154.61,77.47 154.31,77.17 UV2.AB17 ; v1(175.81,81.24) UV4.R4 ; v1(158.85,70.05) 159.24,70.44 UV2.P23 ; UV3.C11 176.21,62.27 v1(175.81,61.87) ; v1(151.34,62.59) 151.4,62.65 151.4,62.68 UV2.E14 ; UV2.AB24 160.23,77.31 160.23,77.32 v1(160.46,77.54) ; v1(154.59,62.64) UV2.E17 ; UV3.R1 v1(186.21,69.87) ; UV3.E1 v1(177.41,70.67) ; 176.21,80.84 v1(175.81,80.44)
  BOTTOM w0.33: UV3.L5 v1(182.99,66.69) 183.03,66.69 UV3.M5 ; v1(157.96,78.44) 157.59,78.81 UV2.AD21 ; v1(157.96,78.44) UV2.AD22 ; v1(157.96,78.44) 158.34,78.07 UV2.AC22 ; UV4.C3 v1(186.21,81.24) ; UV4.F5 183.41,82.44 v1(183.01,82.04) UV4.G5 ; v1(184.61,61.88) 184.21,61.48 UV3.N12 184.21,61.48 v1(183.81,61.08) ; UV3.T10 186.61,63.08 v1(186.21,63.48) ; v1(183.81,59.47) 184.21,59.87 UV3.N14 ; v1(179.83,62.67) 179.81,62.67 UV3.G10 ; v1(184.61,80.44) UV4.E3 184.21,80.84 v1(184.61,81.24) ; UV3.K1 v1(182.21,69.87) 182.21,69.87 UV3.K2 ; UV3.H13 180.21,60.67 v1(179.81,60.27) UV3.H14 ; v1(151.35,80) UV2.AE14 ; UV4.A1 187.75,78.9 v1(188.23,78.9) ; UV4.T5 175.41,82.43 v1(175.81,82.04) 176.2,81.64 UV4.R4 ; v1(187.01,69.87) 187.41,70.27 UV3.U1 187.42,70.28 v1(187.81,70.67) ; UV4.R1 175.81,78.84 175.75,78.84 175.75,78.84 v1(175.76,78.84) ; 177.81,70.27 177.81,70.27 UV3.E1 ; v1(175.81,61.87) UV3.C12 ; v1(174.21,61.87) 174.61,61.48 UV3.A12 ; UV3.U3 v1(187,68.27) ; UV3.A14 174.61,59.88 v1(174.21,60.27) ; v1(185.41,60.27) UV3.R14 185.81,59.87 v1(185.41,59.47) ; UV3.M10 183.05,62.72 v1(183,62.72) 182.97,62.72 UV3.L10 ; UV2.AE20 v1(156.31,80) 156.31,80.03 UV2.AF20 ; UV3.R12 v1(186.21,61.07) ; UV3.C14 v1(175.81,60.27) ; UV3.R4 185.82,67.88 v1(186.22,67.48) ; UV3.R3 v1(185.42,68.28) ; UV3.K14 182.21,60.27 v1(182.21,60.27) UV3.K13 ; v1(187.01,59.47) 187.41,59.87 UV3.U14 ; UV3.F5 178.99,67.46 v1(179,67.46) ; UV4.A3 v1(187.81,80.44) ; UV3.C1 v1(175.81,70.67) ; UV4.H2 UV4.H1 v1(181.81,78.62) ; UV3.N3 v1(184.62,68.27) ; v1(186.21,79.64) 186.21,79.64 UV4.C1 ; v1(178.21,62.67) 178.21,62.68 UV3.F10 ; UV3.P10 v1(185.38,62.71) UV3.R11 v1(186.21,61.87) ; v1(178.21,80.44) UV4.N3 177.8,80.84 v1(177.41,81.24) ; UV3.E14 v1(177.41,60.27) ; UV3.U12 v1(187.01,61.87) ; v1(174.15,68.22) UV3.A3 ; v1(177.41,68.28) UV3.E3 ; v1(184.61,79.64) 184.21,79.24 UV4.E1 ; UV3.B5 v1(175.01,67.47) ; UV3.E12 v1(178.21,61.07)
  BOTTOM w0.356: v1(158.76,68.44) 158.85,68.44 159.24,68.05 UV2.L23 ; UV2.Y26 v1(161.22,75.06) ; UV2.E11 149.65,62.62 v1(149.65,62.61) ; UV2.E8 v1(146.39,62.63) ; UV2.E20 156.32,63.39 v1(156.3,63.39) ; v1(158.76,62.64) 158.39,63.01 UV2.E22 ; UV2.AF14 v1(151.35,80.8) ; v1(159.57,80.8) 159.19,80.41 UV2.AF23 ; v1(151.39,59.03) 151.39,59.49 151.74,59.83 UV2.B14 ; UV2.H25 160.84,65.53 v1(161.24,65.13) ; v1(159.19,59.51) UV2.B23
  BOTTOM w0.381: v1(155.13,66.12) UV2.K17 UV2.L16 153.18,68.07 v1(153.18,68.18) 153.07,68.18 UV2.M15 ; UV2.N18 v1(156.13,69.12) ; v1(148.34,66.12) UV2.K11 UV2.L12 150.27,68.05 v1(150.36,68.05) 150.36,68.14 UV2.M13 ; v1(148.26,72.99) UV2.T11 ; UE2.4 137.41,16.71 137.03,17.09 v4(136.52,17.09) ; PU903.1 43.1,67.05 v4(42.92,67.23) ; UV2.K15 v1(153.13,66.12) ; UV2.L14 v1(151.34,67.12) ; UV2.V15 v1(153.13,74.91) ; UV2.N10 v1(147.34,69.12) ; UV2.R18 156.08,71.86 v1(156.08,71.94) ; UV2.V17 v1(155.13,74.91) ; UV2.R16 v1(154.14,71.92) UV2.T17 UV2.U18 156.06,73.83 v1(156.06,74) ; UV2.T15 v1(153.13,72.91) ; UV2.P2 141.46,70.89 v1(141.41,70.89) ; UV2.P17 v1(155.19,70.97) ; UV2.L18 v1(156.13,67.12) ; UV2.N12 v1(149.34,69.12) ; UV2.N14 v1(151.34,69.12) ; UV2.M17 155.17,68.08 v1(155.26,68.08) ; UV2.U14 v1(151.34,73.91) ; UV2.L10 v1(147.34,67.12) ; UV2.U10 v1(147.34,73.91) ; UV2.K13 v1(150.34,66.12) ; UV2.P13 v1(150.34,70.91) ; UV2.U12 149.27,73.98 v1(149.27,74.17) ; UV2.V13 v1(150.34,74.91) ; UV2.R14 v1(151.34,71.91) ; UV2.N16 v1(154.13,69.12) ; UV2.Y2 141.61,75.25 v1(141.16,75.25) ; UV2.P11 v1(148.34,70.91) ; PU904.1 45.79,67.82 v4(45.46,67.49) ; UV2.T13 v1(150.34,72.91) ; UV2.U16 v1(154.25,74.03) ; UV2.V11 v1(148.34,74.91) ; v1(149.3,71.91) 149.34,71.91 UV2.R12 ; UV2.R10 v1(147.34,71.91) ; UV2.P15 v1(153.13,70.91)
  BOTTOM w0.508: JRTCU1.2 46.2,6.85 v2(46.24,6.81) ; JE3.5 190.03,20.1 v4(190.99,19.14) ; v4(180.34,16.38) 180.69,16.63 JE3.4 ; v4(184.03,25.26) 184.96,25.26 186.4,26.7 JDB1.42 ; v4(153.16,51.76) 153.89,52.5 CV112.2 ; v1(159,91.97) CX896.2
  vias: v1(0.61,92.35) v1(0.76,90.27) v1(0.71,22.73) v1(0.68,21.77) v1(0.68,20.75) v1(0.68,19.89) v1(0.68,18.74) v1(0.68,17.29) v1(0.89,13.69) v1(1.04,94.87) v1(2.03,24.99) v1(2.54,83.77) v1(2.51,29.13) v1(2.54,28.27) v1(2.51,27.1) v1(2.54,25.93) v1(2.51,12.11) v1(2.61,94.87) v1(2.59,88.47) v1(2.61,86.05) v1(3.48,29.16) v1(3.99,45.95) v1(4.67,94.79) v1(4.67,29.18) v1(5.21,91.92) v1(5.97,90.85) v1(6.07,47.44) v1(6.07,46) v1(6.09,48.56) v1(8.23,48.56) v1(8.2,47.44) v1(8.2,46) v1(8.38,3.53) v1(9.07,29.08) v1(9.65,3.5) v1(10.69,29.18) v1(10.77,3.5) v1(10.95,43.74) v1(11.53,13.66) v1(11.99,29.16) v1(12.44,13.66) v1(12.44,3.55) v1(13.46,12.9) v1(13.84,76.58) v1(14.2,42.44) v1(14.2,31.01) v1(14.22,29.89) v1(14.35,3.45) v1(14.48,76.6) v1(14.98,20.74) v1(14.98,18.98) v1(15.39,1.75) v1(16.38,0.53) v1(18.79,23.19) v1(18.79,21.28) v1(20.83,25.6) v1(21.38,85.44) v1(23.56,70.3) v1(23.92,85.44) v1(23.9,2.86) v1(25.31,70.3) v1(26.46,85.44) v1(28.37,49.76) v1(28.37,47.98) v1(29,85.44) v1(30.55,85.44) v1(30.99,53.92) v1(31.75,52.65) v1(31.88,55.06) v1(32,40.6) v1(32,38.85) v1(32.84,85.47) v1(33.2,40.34) v1(33.2,38.56) v1(33.4,70.69) v1(33.78,36.9) v1(33.78,36.14) v1(33.78,35) v1(34.67,70.69) v1(35.23,85.44) v1(35.94,29.03) v1(35.89,27) v1(35.95,25.18) v1(35.95,23.42) v1(36.7,30.68) v1(36.8,29.26) v1(37.22,27) v1(37.22,25.18) v1(37.22,23.42) v1(37.46,0.51) v1(38.25,85.49) v1(38.49,25.18) v1(38.49,23.42) v1(38.99,31.95) v1(39.19,29.84) v1(39.22,26.46) v1(39.76,25.18) v1(39.76,23.42) v1(39.9,86.26) v1(40.64,26.11) v1(40.87,87.55) v1(40.87,29.84) v1(41.2,89.13) v1(42.11,91.11) v1(43.43,92.53) v1(44.91,88.01) v1(45.92,94.82) v1(48.36,96.95) v1(50.14,97.25) v1(58.35,97.45) v1(63.43,97.45) v1(68.51,97.45) v1(71.98,86.31) v1(72.01,0.96) v1(73.59,97.45) v1(78.67,97.45) v1(80.26,0.84) v1(83.75,97.45) v1(85.85,0.58) v1(87.45,71.86) v1(87.45,70.01) v1(88.14,86.38) v1(88.36,0.51) v1(88.83,97.45) v1(90.9,0.51) v1(93.44,0.51) v1(93.91,97.45) v1(95.98,0.51) v1(98.52,0.51) v1(98.99,97.45) v1(101.06,0.51) v1(103.6,0.51) v1(104.07,97.45) v1(104.39,72.84) v1(105.92,73.86) v1(106.14,0.51) v1(106.65,86.31) v1(108.68,0.51) v1(109.15,97.45) v1(111.22,0.51) v1(113.76,0.51) v1(114.23,97.45) v1(116.3,0.51) v1(119.31,97.45) v1(124.39,97.45) v1(126.44,0.51) v1(128.14,97.46) v1(128.52,88.49) v1(128.52,87.86) v1(128.98,0.51) v1(130.07,97.45) v1(131.52,0.51) v1(132.63,97.51) v1(132.97,76.53) v1(134.06,0.76) v1(135.15,97.5) v1(136.42,14.25) v1(136.9,94.43) v1(137.29,77.42) v1(137.29,76.53) v1(137.56,94.31) v1(137.62,97.51) v1(138.26,78.49) v1(138.97,83.26) v1(140.16,97.51) v1(140.72,83.26) v1(141.37,32.87) v1(142.7,97.51) v1(144.78,23.95) v1(145.24,97.51) v1(145.24,82.06) v1(145.47,66.77) v1(145.57,79.2) v1(146.64,66.08) v1(147.76,97.5) v1(147.84,89.51) v1(147.83,84.1) v1(147.83,82.35) v1(149.46,82.92) v1(149.46,81.17) v1(149.91,30.66) v1(150.31,97.49) v1(151.64,1.5) v1(151.77,97.44) v1(152.94,97.43) v1(153.57,1.5) v1(154.38,97.29) v1(154.97,56.12) v1(154.98,95.45) v1(156.33,94.25) v1(157.15,56.78) v1(158.21,57.45) v1(159.02,94.02) v1(160.48,57.47) v1(160.62,94.88) v1(161.43,96.94) v1(162.43,95.07) v1(162.56,57.46) v1(163.45,96.09) v1(163.62,76.7) v1(163.68,78.43) v1(164.26,97.41) v1(164.21,94.31) v1(164.71,74.64) v1(164.86,71.39) v1(165.63,58.14) v1(167.03,32.18) v1(167.64,32.23) v1(167.71,29.64) v1(167.79,32.79) v1(168.04,31.77) v1(170.94,97.48) v1(172.59,97.48) v1(172.59,96.34) v1(174.88,97.48) v1(174.88,96.34) v1(175.86,37.77) v1(175.85,37.17) v1(176.45,37.75) v1(176.46,37.17) v1(177.29,97.48) v1(177.29,96.34) v1(178.42,74.96) v1(179.45,97.48) v1(179.45,96.34) v1(180.11,74.98) v1(180.75,82.92) v1(181.99,97.48) v1(181.99,96.34) v1(182.47,74.96) v1(184.28,97.48) v1(184.47,74.96) v1(187.97,97.42) v1(189.97,97.42) v1(190.08,54.75) v1(190.08,52.75) v1(190.08,50.75) v1(190.08,48.75) v1(190.08,46.75) v1(190.08,44.75) v1(190.08,42.75) v1(190.08,40.75) v1(190.08,38.75) v1(190.08,36.75) v1(190.08,34.75) v1(190.08,32.75) v1(190.08,30.75) v1(190.08,28.75) v1(190.08,26.75) v1(191.09,95.51) v1(191.09,92.97) v1(191.09,90.43) v1(191.09,87.89) v1(191.09,85.35) v1(191.09,82.81) v1(191.09,80.27) v1(191.09,77.73) v1(191.09,75.19) v1(191.09,72.65) v1(191.09,70.11) v1(191.09,67.57) v1(191.09,65.03) v1(191.09,62.49) v1(191.09,59.95) v1(191.09,57.41) v2(15.15,52.98) v2(17.78,38.45) v2(17.78,36.7) v2(21.38,24.24) v2(22.35,54.94) v2(22.35,53.03) v2(24.26,54.94) v2(24.26,53.03) v2(24.26,51.13) v2(25.14,36.75) v2(26.16,54.94) v2(26.16,53.03) v2(26.16,51.13) v2(26.16,36.37) v2(39.98,59.16) v2(40.51,59.17) v2(41.02,59.17) v2(41.53,59.17) v2(43.31,39.57) v2(43.31,37.79) v2(43.31,35.89) v2(45.08,35.89) v2(45.21,39.57) v2(45.21,37.79) v2(45.54,22.4) v2(45.72,21.92) v2(46.61,81.36) v2(47.12,39.57) v2(47.12,37.79) v2(47.12,36.07) v2(64.9,39.19) v2(65.53,41.04) v2(65.53,40.46) v2(65.77,54.36) v2(68.15,35.51) v2(69.6,58.85) v2(69.85,35.13) v2(70.99,35.56) v2(71.75,54.81) v2(71.75,54.18) v2(71.75,53.54) v2(72.64,45.64) v2(72.74,35.38) v2(73.8,36.65) v2(74.17,39.88) v2(75.42,39.88) v2(75.56,10.21) v2(75.74,10.69) v2(75.97,26.79) v2(76.39,26.36) v2(76.45,10.72) v2(76.45,10.21) v2(76.88,40.26) v2(76.96,26.87) v2(76.96,25.85) v2(77.07,37.11) v2(77.34,10.72) v2(77.34,10.21) v2(77.6,56.84) v2(78.87,57.22) v2(78.87,56.61) v2(87.3,47.65) v2(88.26,40.33) v2(89.13,47.04) v2(89.79,40.33) v2(97.27,38.48) v2(98.3,40.71) v2(98.3,39.67) v2(99.03,38.48) v2(100.84,38.35) v2(101.6,39.62) v2(101.75,38.35) v2(102.23,8.46) v2(102.61,56.97) v2(102.74,8.46) v2(103.25,8.46) v2(103.76,22.81) v2(103.76,21.79) v2(103.76,20.77) v2(103.76,8.46) v2(103.88,56.97) v2(104.14,13.15) v2(104.27,39.62) v2(104.27,8.46) v2(104.77,22.81) v2(104.77,21.79) v2(104.77,20.77) v2(105.41,56.97) v2(105.79,22.81) v2(105.79,21.79) v2(105.79,20.77) v2(106.93,47.83) v2(107.06,46.86) v2(107.41,48.81) v2(107.68,47.83) v2(108.27,48.8) v2(108.38,49.78) v2(108.33,46.05) v2(108.96,48.79) v2(108.96,47.83) v2(109.57,47.8) v2(109.57,46.86) v2(109.74,50.65) v2(110.54,49.48) v2(110.54,47.06) v2(111.5,48.33) v2(112.19,57.1) v2(112.27,47.06) v2(112.39,48.33) v2(112.56,49.18) v2(113.03,47.06) v2(113.16,48.33) v2(139.47,35.51) v2(140.26,35.51) v2(141.25,35.51) v2(168.15,80.21) v3(32.76,58.7) v3(127.94,96.34) v3(135.3,96.37) v3(138.66,96.11) v3(144.8,94.31) v3(145.39,89.86) v3(171.47,91.49) v3(174.78,93.32) v3(178.13,94.03) v3(182.42,94.36) v3(188.95,24.03) v4(1.01,65.35) v4(1.47,16.84) v4(2.39,72.57) v4(2.44,17.9) v4(2.54,67.56) v4(2.64,21.56) v4(2.74,9.73) v4(3.96,27.56) v4(4.93,26.39) v4(5.18,25.32) v4(5.46,73.96) v4(5.46,72.59) v4(6.6,66.62) v4(6.6,65.22) v4(6.98,73.96) v4(7.52,26.59) v4(8.13,72.46) v4(8.63,68.15) v4(8.63,66.62) v4(8.63,65.22) v4(9.45,44.37) v4(9.8,47.93) v4(9.85,45.39) v4(10.41,68.15) v4(10.41,66.62) v4(10.92,13.15) v4(11.07,46.61) v4(11.43,47.83) v4(12.09,10.87) v4(12.7,45.74) v4(12.9,47.88) v4(13.21,82.37) v4(14.1,73.84) v4(14.1,73) v4(14.1,72.36) v4(15.11,73.86) v4(15.49,42.59) v4(15.64,30.86) v4(17.42,7.64) v4(17.52,48.59) v4(17.52,10.49) v4(18.08,7.64) v4(18.34,45.01) v4(18.34,44.17) v4(18.34,43.33) v4(18.34,42.44) v4(18.31,10.79) v4(18.31,10.13) v4(18.74,61.44) v4(18.74,7.64) v4(18.79,62.3) v4(19.3,83.51) v4(19.45,11.86) v4(19.45,11.25) v4(19.45,10.64) v4(19.68,62.3) v4(19.68,61.47) v4(20.67,61.47) v4(20.7,62.3) v4(21.59,72.46) v4(22.35,62.03) v4(22.55,62.86) v4(22.65,45.69) v4(22.65,44.83) v4(22.65,44.02) v4(22.65,42.75) v4(23.98,10.94) v4(25.6,10.56) v4(26.54,32.71) v4(26.54,32.08) v4(26.77,30.1) v4(26.77,29.46) v4(27.35,7.69) v4(27.38,30.17) v4(27.38,29.56) v4(28.32,62.68) v4(28.7,46.45) v4(28.7,45.84) v4(28.7,45.23) v4(31.49,30.55) v4(31.49,29.79) v4(32,60.4) v4(32,59.51) v4(32,57.6) v4(32.13,30.55) v4(32.13,29.79) v4(33.25,30.55) v4(33.25,29.79) v4(33.78,59.51) v4(33.91,50.62) v4(33.91,49.73) v4(34.67,60.4) v4(34.67,59.51) v4(34.67,50.62) v4(34.67,49.73) v4(35.08,40.59) v4(35.08,39.57) v4(35.56,59.51) v4(36.19,40.59) v4(36.19,39.57) v4(36.7,78.81) v4(36.7,77.67) v4(36.7,76.53) v4(36.7,51.89) v4(37.34,51.89) v4(37.46,40.59) v4(37.46,39.57) v4(40.23,63.78) v4(42.16,43.25) v4(42.21,82.75) v4(42.52,64.03) v4(42.59,82.09) v4(42.87,82.7) v4(43.05,43.25) v4(43.33,82.29) v4(43.79,81.35) v4(44.85,87.4) v4(45.06,88.67) v4(45.11,21.94) v4(45.46,66.88) v4(45.64,23.44) v4(45.85,88.82) v4(46.12,23.9) v4(46.1,22.36) v4(46.23,15.19) v4(46.23,14.25) v4(46.23,13.28) v4(47.04,95.78) v4(47.25,14.25) v4(47.24,13.28) v4(48,95.83) v4(48.05,91.16) v4(48.05,81.25) v4(48.11,90.04) v4(48.16,89.43) v4(48.13,49.48) v4(48.13,48.46) v4(48.26,57.1) v4(48.26,56.21) v4(48.26,15.19) v4(48.27,14.25) v4(48.26,13.28) v4(48.31,75.87) v4(48.56,84.73) v4(48.56,84.02) v4(48.56,83.23) v4(48.56,82.52) v4(48.51,81.71) v4(48.77,49.48) v4(48.77,48.46) v4(48.82,91.11) v4(48.97,90.09) v4(48.97,89.43) v4(48.97,88.26) v4(49.02,57.1) v4(49.02,56.21) v4(49.15,95.83) v4(49.2,84) v4(49.2,83.23) v4(49.2,82.55) v4(49.4,49.48) v4(49.4,48.46) v4(49.67,0.53) v4(50.04,48.46) v4(50.42,0.96) v4(50.65,57.1) v4(50.65,56.21) v4(51.51,57.1) v4(51.51,56.21) v4(52.58,57.08) v4(52.58,56.2) v4(53.44,57.1) v4(53.44,56.21) v4(53.39,13.99) v4(53.39,13.33) v4(53.97,14.3) v4(53.9,12.77) v4(54.02,13.41) v4(54.63,14.3) v4(54.63,13.41) v4(54.61,12.77) v4(55.22,12.77) v4(63.24,41.48) v4(63.24,40.71) v4(64.13,41.48) v4(64.13,40.71) v4(73.4,21.79) v4(73.4,20.9) v4(73.4,20.01) v4(73.4,19.12) v4(73.53,31.75) v4(73.99,32.18) v4(74.29,21.79) v4(74.29,20.9) v4(74.29,20.01) v4(74.29,19.12) v4(74.98,30.6) v4(75.49,31.11) v4(83.82,6.8) v4(83.82,5.53) v4(85.09,6.8) v4(85.09,5.53) v4(85.6,31.54) v4(85.85,24.08) v4(85.85,23.19) v4(85.98,30.68) v4(86.23,31.54) v4(86.23,29.82) v4(86.36,6.8) v4(86.36,5.53) v4(86.74,24.08) v4(86.74,23.19) v4(86.87,31.54) v4(86.87,30.68) v4(86.87,29.82) v4(87.63,24.08) v4(87.63,23.19) v4(87.63,6.8) v4(87.63,5.53) v4(88.52,24.08) v4(88.52,23.19) v4(96.65,19.12) v4(97.41,18.36) v4(97.41,17.73) v4(97.41,17.09) v4(97.41,16.46) v4(97.41,15.82) v4(97.81,33.65) v4(98.04,17.73) v4(98.04,17.09) v4(98.04,16.46) v4(98.04,15.82) v4(98.42,34.85) v4(98.52,33.65) v4(98.93,56.97) v4(99.31,33.65) v4(99.82,56.97) v4(100.23,34.85) v4(100.2,33.65) v4(101.09,34.85) v4(101.09,33.65) v4(101.22,57) v4(102.23,50.49) v4(102.23,49.6) v4(111,32.33) v4(111,31.32) v4(111,30.3) v4(111,29.03) v4(111.89,32.33) v4(111.89,31.32) v4(111.89,30.3) v4(111.89,29.03) v4(111.89,28.01) v4(112.65,14.42) v4(112.65,13.54) v4(112.77,29.03) v4(112.77,28.01) v4(112.9,8.84) v4(112.9,7.95) v4(113.54,14.42) v4(113.54,13.54) v4(113.66,29.03) v4(113.66,28.01) v4(113.79,8.84) v4(113.79,7.95) v4(114.3,56.84) v4(114.55,14.42) v4(114.55,13.54) v4(114.68,8.84) v4(114.68,7.95) v4(115.19,56.84) v4(115.39,14.42) v4(115.39,13.54) v4(115.57,8.84) v4(115.57,7.95) v4(116.08,56.84) v4(116.97,56.84) v4(117.85,56.84) v4(118.74,56.84) v4(119.63,56.84) v4(121.41,56.84) v4(122.3,57.73) v4(122.3,56.84) v4(123.19,57.73) v4(123.19,56.84) v4(124.08,57.73) v4(124.08,56.84) v4(124.2,8.84) v4(124.2,7.95) v4(124.84,15.06) v4(124.84,14.3) v4(124.84,13.46) v4(124.97,57.73) v4(124.97,56.84) v4(125.09,8.84) v4(125.09,7.95) v4(125.98,8.84) v4(125.98,7.95) v4(126.87,8.84) v4(126.87,7.95) v4(127.51,47.06) v4(127.51,46.05) v4(127.51,45.16) v4(127.51,43.38) v4(128.4,47.06) v4(128.4,46.05) v4(128.4,45.16) v4(128.4,43.38) v4(130.05,43.13) v4(130.05,41.35) v4(130.05,40.46) v4(130.05,39.57) v4(130.05,38.68) v4(130.55,33.73) v4(130.94,43.13) v4(130.94,41.35) v4(130.94,40.46) v4(130.94,39.57) v4(130.94,38.68) v4(131.32,30.05) v4(131.32,29.03) v4(131.44,34.62) v4(131.44,33.73) v4(131.82,43.13) v4(131.82,41.35) v4(131.82,40.46) v4(131.82,39.57) v4(131.82,38.68) v4(131.82,36.9) v4(132.16,90.95) v4(132.18,90.06) v4(132.21,30.05) v4(132.21,29.03) v4(132.33,34.62) v4(132.33,33.73) v4(132.71,40.46) v4(132.71,39.57) v4(133.22,33.73) v4(133.6,40.46) v4(133.6,39.57) v4(134.24,62.81) v4(135,24.33) v4(135.25,23.31) v4(135.25,22.3) v4(135.46,91.58) v4(135.94,92.43) v4(135.89,31.7) v4(135.89,30.27) v4(136.27,22.3) v4(136.4,21.28) v4(136.4,20.27) v4(136.4,19.25) v4(136.4,18.23) v4(136.5,49.25) v4(136.65,63.07) v4(136.7,3.52) v4(137.03,21.28) v4(137.03,20.27) v4(137.03,19.25) v4(137.03,18.23) v4(137.16,31.7) v4(137.16,30.27) v4(137.16,29.16) v4(137.21,49.25) v4(137.67,63.07) v4(137.91,3.52) v4(138.43,30.27) v4(138.43,29.16) v4(139.57,67.89) v4(140.46,67.89) v4(140.7,3.52) v4(140.97,49.35) v4(142.3,3.52) v4(144.65,9.85) v4(146.01,1.77) v4(148.84,1.57) v4(151.26,41.98) v4(151.26,41.35) v4(151.89,42.62) v4(151.89,41.98) v4(151.89,41.35) v4(152.78,42.75) v4(152.78,41.98) v4(152.78,41.35) v4(153.41,42.75) v4(153.41,41.98) v4(153.41,41.35) v4(153.59,95.5) v4(154.3,42.75) v4(154.3,42.11) v4(154.3,41.48) v4(154.73,13.92) v4(154.73,13.31) v4(154.76,12.7) v4(154.94,42.75) v4(154.94,42.11) v4(154.94,41.48) v4(155.83,43.27) v4(155.83,42.36) v4(155.83,41.69) v4(155.78,1.55) v4(156.5,43.27) v4(156.5,42.36) v4(156.5,41.69) v4(157.43,43.27) v4(157.43,42.36) v4(157.43,41.44) v4(157.78,1.55) v4(158.93,1.57) v4(162.1,1.57) v4(164.89,1.55) v4(165.06,40.83) v4(165.04,39.75) v4(165.08,34.05) v4(165.06,32.8) v4(165.1,33.42) v4(165.59,40.31) v4(165.77,34.08) v4(165.74,33.41) v4(166.12,40.79) v4(166.15,39.75) v4(166.84,34.64) v4(167,88.59) v4(168.98,1.57) v4(169.77,50.98) v4(170.74,29.99) v4(170.74,28.17) v4(170.74,26) v4(170.79,27) v4(171.97,49.95) v4(172.34,28.4) v4(172.34,26) v4(172.46,27.1) v4(172.67,30.05) v4(172.78,50.47) v4(172.87,49.81) v4(172.97,51.08) v4(173.38,51.58) v4(173.44,50.46) v4(173.81,51.06) v4(173.94,29.99) v4(173.94,28.4) v4(173.94,27) v4(173.99,51.69) v4(174.13,4.95) v4(174.09,1.67) v4(174.45,10.44) v4(175.46,26.95) v4(175.41,9.52) v4(175.54,29.99) v4(175.54,28.4) v4(175.54,6.04) v4(176.25,55.07) v4(176.73,35.06) v4(177.05,55.07) v4(176.99,2.92) v4(177.34,4.87) v4(177.85,55.07) v4(178.65,55.07) v4(179.07,34.94) v4(179.3,2.89) v4(179.73,34.97) v4(179.98,51.74) v4(180.85,51.74) v4(180.85,35.02) v4(180.97,50.39) v4(180.98,49.75) v4(180.98,49.11) v4(181.06,38.01) v4(181.24,37.28) v4(181.3,35.48) v4(181.41,25.25) v4(181.64,38.23) v4(181.78,37.62) v4(182.04,25.26) v4(182.74,25.25) v4(183.03,2.89) v4(183.21,6.16) v4(183.38,25.25) v4(183.64,25.83) v4(184.8,4.72) v4(186.46,2.92) v4(188.11,54.33) v4(191.13,21.56) v4(191.11,16.15) v4(191.13,12.65)
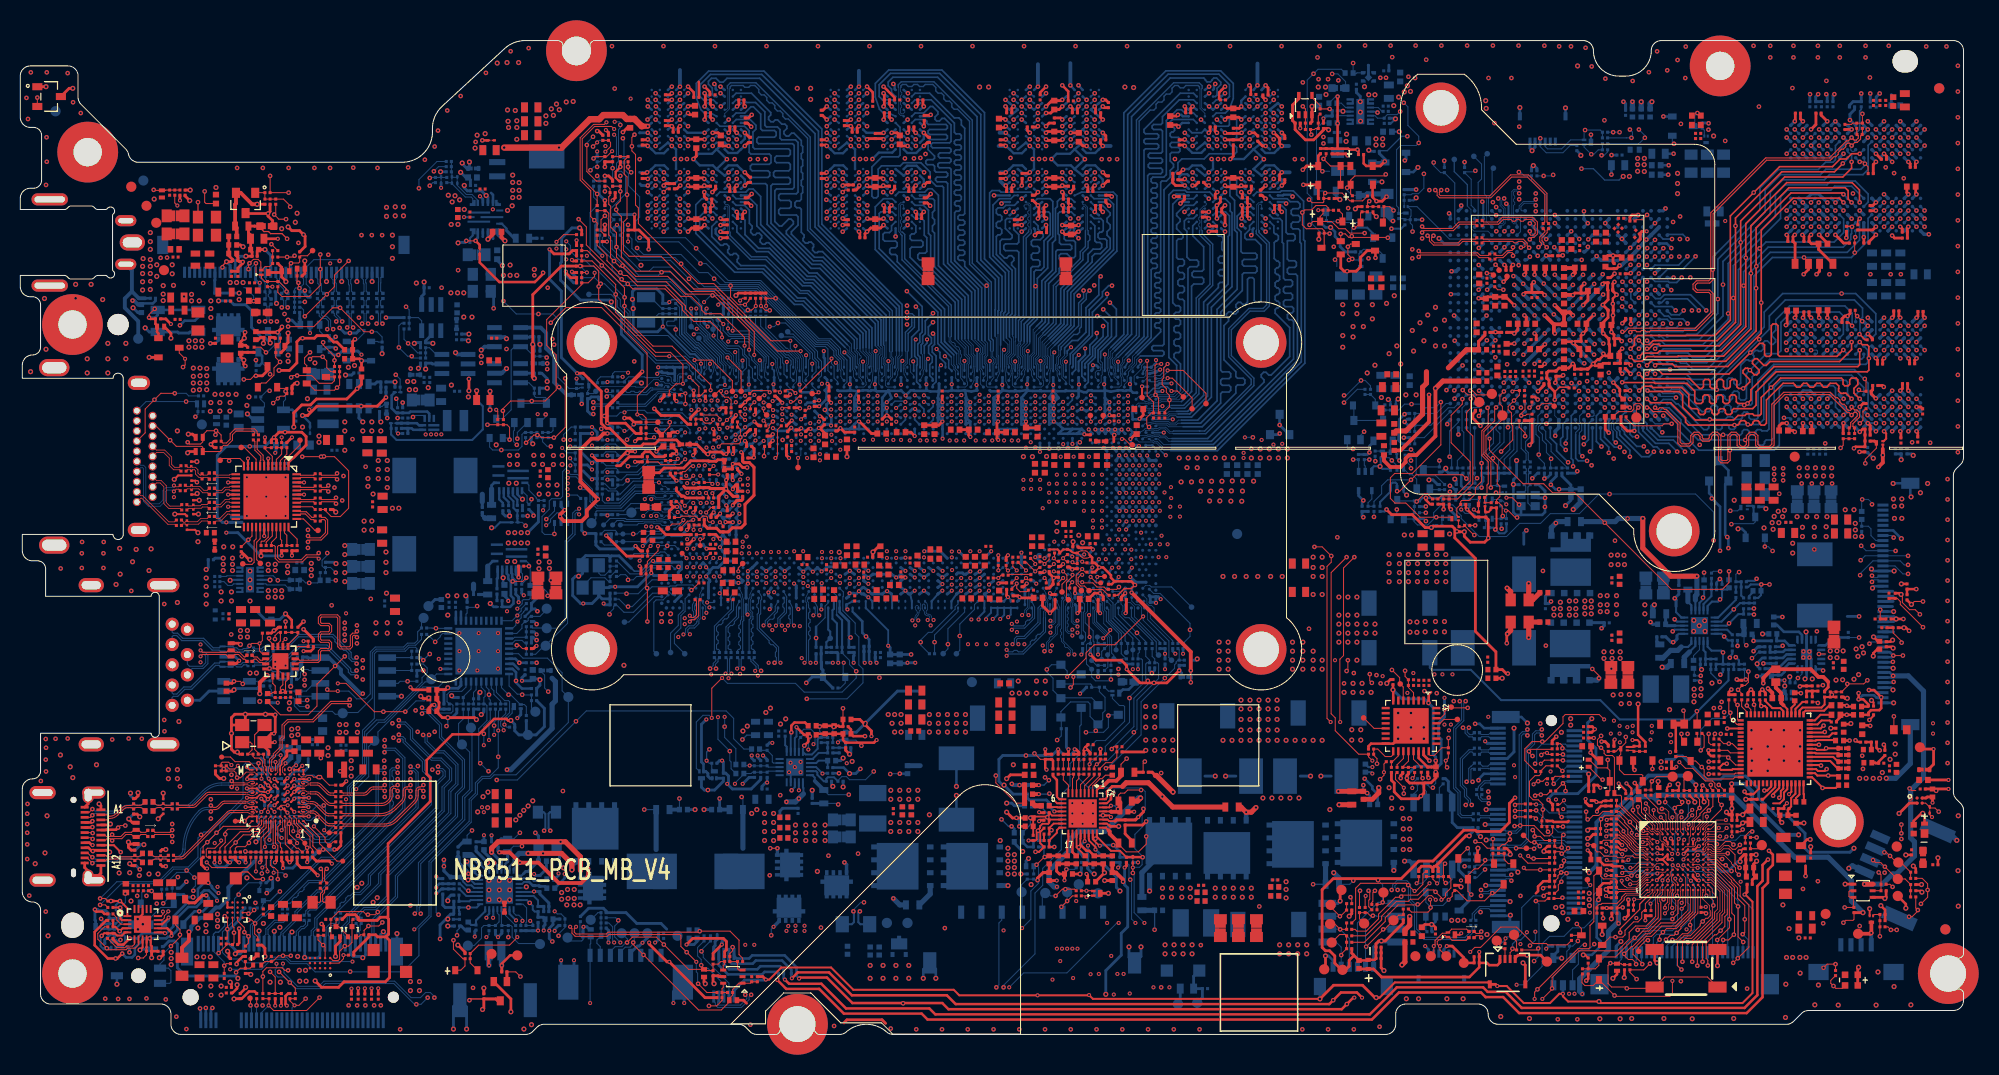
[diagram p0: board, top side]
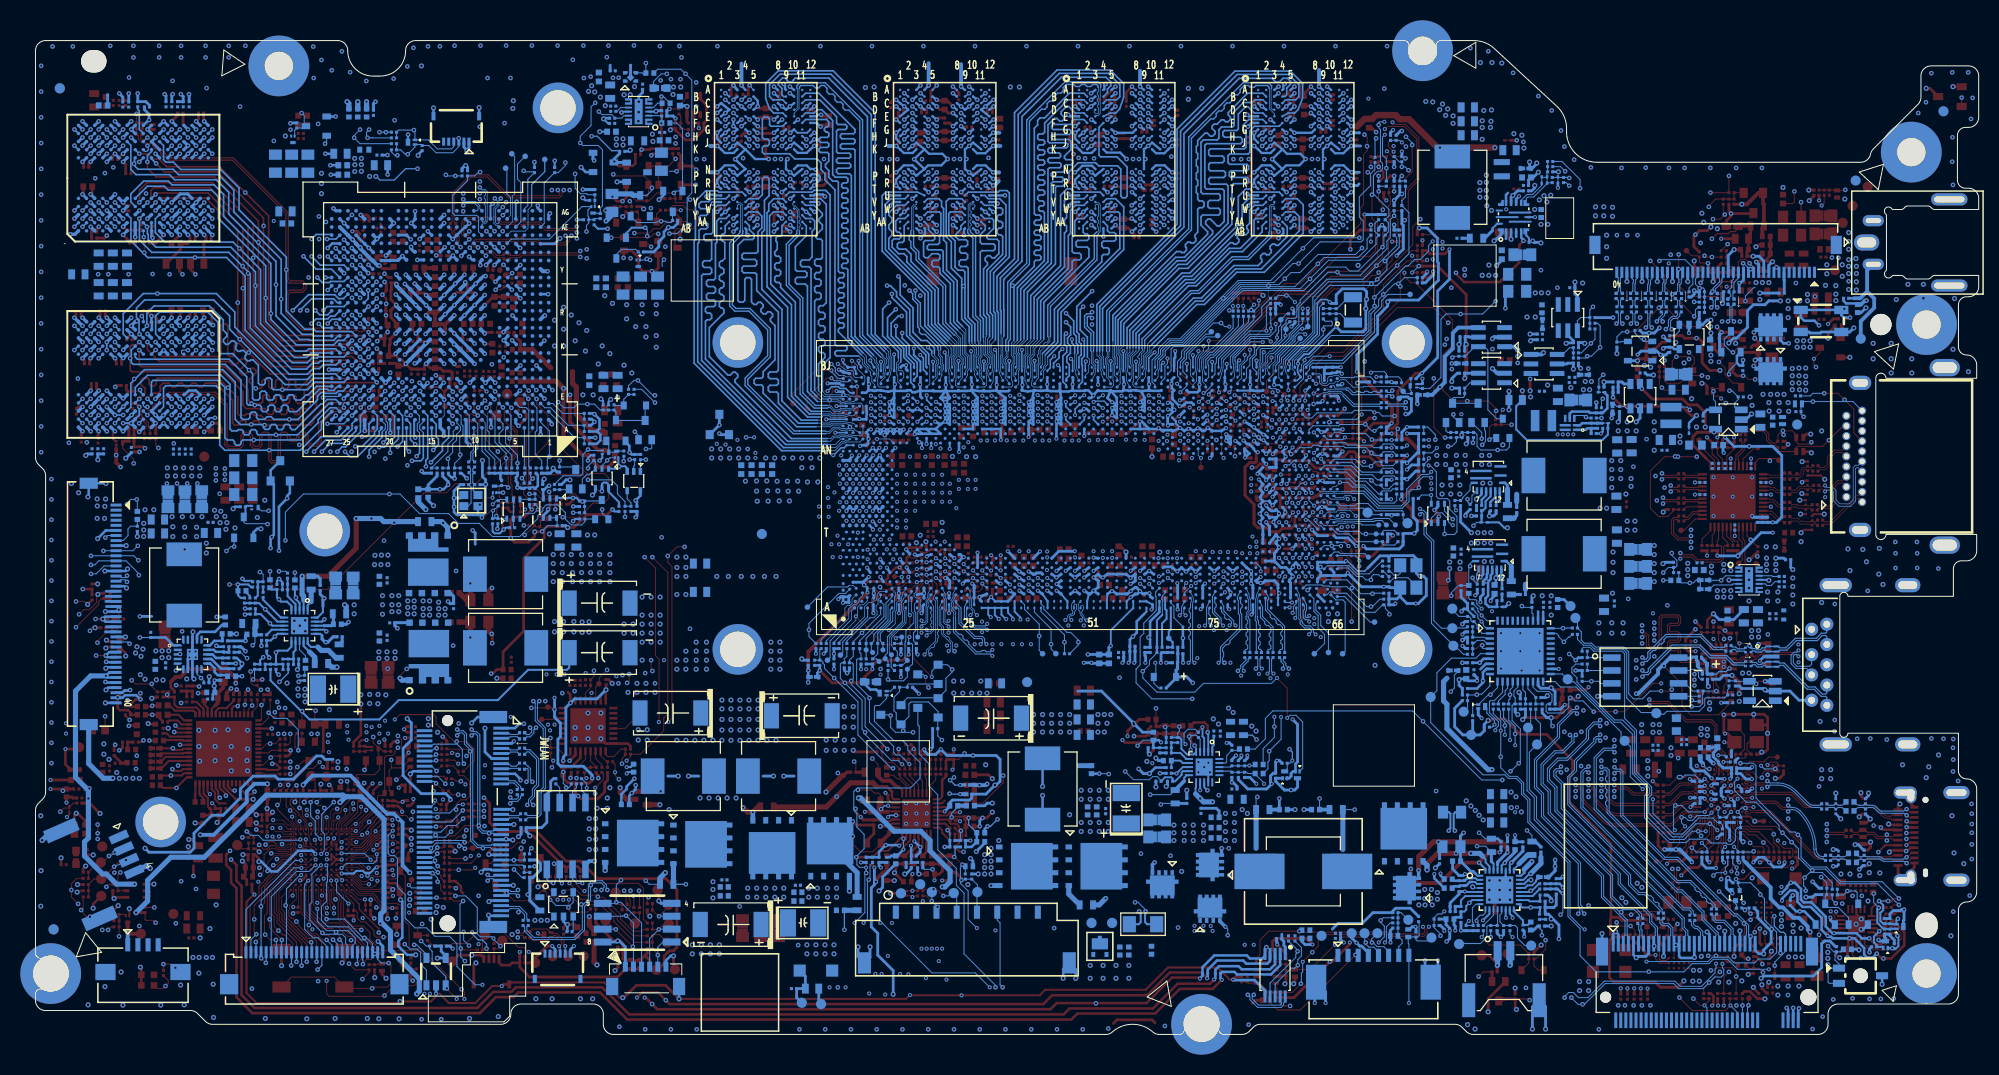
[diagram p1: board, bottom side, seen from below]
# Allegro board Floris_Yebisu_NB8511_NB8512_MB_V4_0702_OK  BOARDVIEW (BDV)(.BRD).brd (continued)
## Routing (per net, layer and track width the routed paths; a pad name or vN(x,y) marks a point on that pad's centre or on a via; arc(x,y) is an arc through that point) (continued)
GNDS_SENSE: length 2.7
  TOP w0.102: v1(142.26,63.54) 142.73,63.07 143.25,63.07 143.51,62.81 143.51,62.74 TPE8.1
  BOTTOM w0.102: UV2.F3 v1(142.26,63.54)
PVIN_VPP: length 1.1
  BOTTOM w0.254: PU701.14 46.62,82.79 46.43,82.98
SGNDA_C: length 3.1
  TOP w0.203: SHE3.1 179.27,26.9 178.8,27.37 UA2.36
SGNDB_C: length 3
  TOP w0.203: SHE4.1 179.27,27.71 177.09,27.71 177.03,27.77 UA2.37
V1P2A_EN: length 1.9
  BOTTOM w0.102: PU402.1 34.74,61.74 34.92,61.92 PC415.1 35.69,61.92 35.84,62.08 PR413.2
V1P2A_FB: length 2.3
  BOTTOM w0.279: PU402.6 34.98,64.14 35.18,64.34 PR410.2 PR412.1 PC412.1
V1P2A_LX: length 2
  BOTTOM w0.102: PL402.1 28.76,61.86 v3(28.5,61.59)
V1P8_SNS: length 7
  TOP w0.254: PSH709.2 v1(45.57,88.16)
  ART03 w0.381: v1(45.57,88.16) 45.57,85.93 45.34,85.7 v2(45.34,82.65)
  BOTTOM w0.254: v2(45.34,82.65) 45.62,82.37 PU701.12
V1P8A_EN: length 6.2
  BOTTOM w0.249: 40.33,61.21 PU401.4
  BOTTOM w0.254: PR414.2 36.62,63 36.62,61.74 37.08,61.29 PR401.2 PC401.1 38.35,61.29 38.48,61.41 40.13,61.41 40.33,61.21
V1P8A_FB: length 2.7
  BOTTOM w0.249: PR403.1 38.61,59.76 38.75,59.62 PU401.1
  BOTTOM w0.279: PR404.2 PR403.1 PC405.1
V1P8A_FB_R: length 2.7
  BOTTOM w0.249: PR403.2 39.11,60.27 39.32,60.07 PU401.2
  BOTTOM w0.279: PR403.2 PC405.2 PSH401.1
V1P8A_PGOOD: length 84
  ART05 w0.102: v1(38.73,60.88) 38.25,60.4 36.57,60.4 36.17,59.99 34.39,59.99 34.19,59.79 34.19,58.6 32.35,56.76 32.35,49.93 33.27,49 33.27,42.36 34.42,41.22 34.42,39.57 35.18,38.81 40.69,38.81 42.26,37.23 42.26,35.15 41.73,34.62 41.73,28.42 45.06,25.09 v1(46.99,25.09)
  BOTTOM w0.102: PR402.1 38.63,60.78 v1(38.73,60.88) 38.89,61.03 39.75,61.03 39.88,60.9 PU401.3 ; PR530.1 71.37,28.14 70.36,29.16 70.36,31.16 69.62,31.9 55.83,31.9 v3(54.8,30.88) 49.02,25.09 v1(46.99,25.09)
V3P3A_BOOT: length 2.4
  BOTTOM w0.254: 46.1,46.17 46.6,46.67 PU201.1
  BOTTOM w0.508: PR201.1 46.1,46.17
V3P3A_BOOT_R: length 0.9
  BOTTOM w0.305: PR201.2 PC210.1
V3P3A_FB: length 5.5
  BOTTOM w0.254: PU201.10 47.98,45.43 48.13,45.29 48.13,44.9 48.39,44.65 48.39,43.25 48.64,43 48.64,42.49 48.31,42.16 PSH206.1 47.52,42.17 PC211.2
V3P3A_FF: length 2
  BOTTOM w0.254: PR204.1 47.01,44.93 47.08,45 PU201.12
V3P3A_FF_R: length 0.7
  BOTTOM w0.254: PC211.1 PR204.2
V3P3A_IN: length 1.2
  BOTTOM w0.127: v4(52.18,45.95) 52.18,44.92 v3(52.32,44.78)
  vias: v4(48.03,46.63) v4(48.77,46.63) v4(51.15,46.58) v4(51.15,45.92) v4(52.18,46.58)
V3P3A_LX: length 1
  BOTTOM w0.279: 44.7,43.89 PC210.2
  BOTTOM w0.508: 44.7,44.4 44.7,43.89
V3P3A_OUT: length 11.4
  ART03 w0.279: v4(46.35,42.49) 40.26,42.49 39.24,43.51 v4(36.12,43.51)
  BOTTOM w0.254: v4(46.35,42.49) 46.68,42.16 PSH206.2
  vias: v3(34.57,42.95) v4(36.07,47.57) v4(36.07,46.56) v4(36.07,45.54)
V3P3A_PGOOD: length 250.2
  TOP w0.102: v1(49.91,45.03) 49.55,44.68 v3(48.56,44.68) ; RE96.1 156,11.81 156.11,11.71 v1(156.11,11.45) ; QL6.1 v1(160.97,26.17)
  ART03 w0.089: v1(49.91,45.03) 50.09,45.03 50.75,45.69 50.75,46.91 51.51,47.67 51.51,48.99 52.63,50.11 52.63,51.74 53.03,52.14 53.52,52.14 54.4,53.03 54.4,54.58 54.61,54.79 54.61,59.26 51.43,62.43 39.37,62.43 39.11,62.68 v1(37.08,62.68) ; v2(107.59,7.74) 108,7.34 110.28,7.34 110.59,7.03 115.26,7.03 116.2,6.09 132.71,6.09 134.01,7.39 135.13,7.39 135.68,7.95 137.56,7.95 138.17,7.34 145.87,7.34 147.8,9.27 148.13,9.27 148.33,9.07 152.4,9.07 154.33,11 155.32,11 155.73,11.4 156.06,11.4 v1(156.11,11.45) 156.21,11.45 156.72,10.94 158.29,10.94 159.38,9.85 159.76,9.85 160.65,10.74 160.65,12.01 160.4,12.27 160.4,14.04 160.62,14.26 160.62,17.13 161.03,17.55 161.03,21.28 161.44,21.69 161.44,22.4 161.16,22.68 161.16,23.64 160.53,24.28 160.53,25.22 160.97,25.66 v1(160.97,26.17)
  ART05 w0.102: v1(37.08,62.68) 36.7,62.3 33.53,62.3 32.43,61.21 32.43,59.31 30.5,57.38 30.5,56.87 29.16,55.52 29.16,51.18 30.25,50.09 30.25,43.1 30.38,42.97 30.38,38.78 31.49,37.67 33.78,37.67 34.87,36.57 34.87,16.63 37.97,13.54 37.97,11.85 38.35,11.48 40.16,11.48 41.25,10.39 41.25,9.83 42.97,8.1 55.38,8.1 57.31,10.03 73.13,10.03 73.74,9.42 88.54,9.42 88.73,9.23 106.1,9.23 v2(107.59,7.74)
  BOTTOM w0.102: v1(49.91,45.03) 49.91,44.85 PR203.1 49.45,44.83 49.53,44.9 49.53,45.41 49.33,45.61 PU201.7 ; v1(37.08,62.68) 37.21,62.56 PR401.1
V3P3A_PGOOD_EC: length 6.6
  TOP w0.076: 158.32,13.92 159.65,13.92 UE1.M1
  TOP w0.102: RE96.2 CE377.1 155.5,12.62 155.7,12.82 155.9,12.82 156,12.93 157.48,12.93 157.94,13.38 157.94,13.53 158.32,13.92
V3P3A_VCCD_PD: length 2.4
  BOTTOM w0.102: UT1.33 43.96,41.44 44.07,41.55 CT8.2 44.93,42.11 v3(45.06,42.24)
V3P3SX_EN: length 3.3
  BOTTOM w0.102: PR911.2 26.52,43.91 26.11,44.32 24.33,44.32 24.22,44.43 PU902.5
V5P0A_BST: length 2.5
  BOTTOM w0.254: 46.48,53.79 46.48,54.14 46.73,54.39 PU301.1
  BOTTOM w0.508: 46.48,53.79 PR301.1
V5P0A_BST_R: length 1.3
  BOTTOM w0.305: PC308.1 45.57,51.18 45.79,50.95
  BOTTOM w0.508: 45.79,50.95 45.85,50.9 PR301.2
V5P0A_EN: length 3
  BOTTOM w0.102: PU301.6 49.93,54.39 50.16,54.17 50.16,53.67 50.89,52.94 50.89,52.87 PR307.2 PR305.2
V5P0A_FB: length 4.5
  BOTTOM w0.102: PSH306.1 49.5,50.49 v3(49.83,50.16)
  BOTTOM w0.203: PU301.10 48.13,53.08 48.64,52.58 48.64,51.92 48.89,51.66 PC318.2 PC320.1 49.02,50.87 49.03,50.86 PSH306.1
V5P0A_FF: length 1.6
  BOTTOM w0.229: PR306.1 49.02,52.73 48.58,53.16 PU301.9
V5P0A_FF_R: length 0.5
  BOTTOM w0.279: PC318.1 PR306.2
V5P0A_LDO: length 1.6
  BOTTOM w0.229: PU301.12 47.23,52.76 47.6,52.4 PC309.1
V5P0A_PGOOD: length 210.4
  TOP w0.102: RE6.1 156.56,13.48 v2(156.39,13.66)
  ART03 w0.089: v1(37.21,60.78) 36.5,61.49 36.5,65.33 36.83,65.66 v1(38.5,65.66)
  ART05 w0.102: v2(156.39,13.66) 155.45,14.6 155.45,20.55 155.04,20.95 153.46,20.95 152.53,20.01 151.81,20.01 151.43,20.39 148.59,20.39 148.23,20.04 144.47,20.04 144.02,20.5 142.85,20.5 141.98,19.63 141.98,17.98 139.34,15.34 139.34,14.45 137.11,12.21 129.49,12.21 128.09,10.82 112.35,10.82 111.37,11.8 105.8,11.8 105.54,11.54 85.6,11.54 83.21,13.94 83.21,27.33 81.35,29.18 78.79,29.18 v2(78.23,28.62) 78.18,28.57 78.18,27.71 78.03,27.56 77.37,27.56 77.04,27.89 60.68,27.89 52.7,35.86 52.7,48.77 51.41,50.06 51.41,51.15 50.42,52.14 v1(50.42,52.78) ; v1(38.5,65.66) 37.69,66.47 37.69,79.07 38.94,80.31 38.94,82.24 v1(40.38,83.69)
  ART06 w0.102: v1(38.5,65.66) 39.47,66.62 40.94,66.62 43.48,64.08 45.21,64.08 45.69,63.6 45.69,61.62 47.47,59.84 48.64,59.84 49.48,59 49.48,57.78 49.99,57.27 49.99,53.21 v1(50.42,52.78)
  BOTTOM w0.102: v1(40.38,83.69) 40.69,84 PR705.2 ; 37.72,60.78 v1(37.21,60.78) ; v1(50.42,52.78) 50.42,52.52 PR302.1 49.99,52.45 49.99,53.11 PU301.7 ; v2(78.23,28.62) 78.38,28.78 78.38,29.69 77.98,30.1 77.26,30.1 PR513.2
V5P0A_PGOOD_R: length 4.6
  TOP w0.076: UE1.L2 160.72,14.99 160.37,14.99 159.47,14.09 158.24,14.09
  TOP w0.102: RE6.2 CE376.1 157.58,13.99 157.68,14.09 158.24,14.09
V5P0A_VCC: length 1.7
  BOTTOM w0.229: PC319.1 48.16,52.5 47.68,52.97 PU301.11
V5P0SX_EN: length 3.2
  BOTTOM w0.102: PU902.3 24.95,45.23 v3(25.4,44.78) 26.67,44.78 PR915.2
VBUS_C_CTRL: length 33.9
  TOP w0.102: v1(35.71,11.05) 35.35,10.69 v3(34.34,10.69) 33.91,10.26 33.91,9.85 RT101.1 33.58,9.83 33.38,9.63 QT4.2
  ART03 w0.089: v1(35.71,11.05) 35.71,13.03 37.08,14.4 37.08,18.97 43.03,24.91 43.03,25.73 45.36,28.06 46.18,28.06 47.67,29.56 v2(47.67,29.99)
  BOTTOM w0.102: UT1.12 46.96,33.73 47.78,32.92 48.16,32.92 48.26,32.81 48.26,31.73 47.37,30.84 47.37,30.43 47.67,30.12 v2(47.67,29.99)
VBUS_P_CTRL: length 4.7
  BOTTOM w0.102: RT3.1 49.91,32.33 49.71,32.53 QT1.1 49.33,32.53 48.36,33.5 v3(48.16,33.5) 47.46,34.2 UT1.11
VBUS_P_CTRL_R: length 43
  TOP w0.102: UT5.B4 21.43,11.2 22.1,10.54 v1(22.1,10.08) v3(22.5,9.67) 22.5,9.01 RT91.2
  ART03 w0.089: v2(47.75,30.55) 47.14,30.55 46.45,29.87 45.9,29.87 42.16,26.13 42.16,25.22 35.74,18.8 35.74,18.14 29.36,11.76 23.32,11.76 22.68,12.39 22.27,12.39 22.1,12.21 v1(22.1,10.08)
  BOTTOM w0.102: QT1.3 48.51,32.16 48.51,31.7 47.75,30.93 v2(47.75,30.55) 48,30.3 RT1.1
VCC_DDR_PWROK: length 236
  TOP w0.076: UE1.G10 165.42,17.69 v2(165.45,17.69)
  ART03 w0.089: v1(38.48,12.72) 38.48,7.87 43.48,2.87 47.23,2.87 47.89,3.53 70.25,3.53 71.23,4.51 72.38,4.51 72.9,3.99 89.73,3.99 90.14,3.58 98.87,3.58 101.46,6.17 103.3,6.17 103.88,6.75 106.86,6.75 107.08,6.53 109.57,6.53 109.87,6.23 114.68,6.23 115.61,5.31 134.08,5.31 135.23,6.45 148.77,6.45 149.38,7.06 152.14,7.06 153.35,8.27 154.37,8.27 154.68,7.95 157.61,7.95 159.03,6.53 161.49,6.53 161.95,6.98 161.95,7.76 162.04,7.85 162.05,7.85 163.32,9.12 163.32,10.28 163.45,10.41 163.45,10.49 164.59,11.63 164.59,14.04 165.12,14.58 165.12,15.42 165.07,15.47 165.07,17.31 v2(165.45,17.69)
  ART05 w0.102: v1(38.48,12.72) 38.48,13.41 35.13,16.76 35.13,36.7 33.91,37.92 31.53,37.92 30.58,38.87 30.58,43.15 30.45,43.28 30.45,50.26 29.36,51.36 29.36,55.34 30.76,56.74 30.76,57.3 32.64,59.18 32.64,61.03 33.53,61.92 37.97,61.92 38.1,62.05 38.1,62.51 36.47,64.13 36.47,65.5 37.49,66.52 37.49,79.27 38.58,80.36 38.58,83.56 39.47,84.45 v1(40.38,84.45)
  BOTTOM w0.102: PR702.1 41.51,84.5 PR706.1 41.49,84.5 PR705.1 40.43,84.5 v1(40.38,84.45)
VCC_VCCIN_SENSE_N: length 41
  TOP w0.254: PR638.2 v1(98.52,20.52)
  ART06 w0.203: v1(98.52,20.52) 98.32,20.72 98.32,21.05 98.85,21.59 98.85,28.57 100.2,29.92 104.01,29.92 107.44,33.35 107.44,37.67 110.11,40.33 110.11,42.24 111.63,43.76 111.63,47.44 109.73,49.35 109.73,49.95 v2(109.09,50.59)
  BOTTOM w0.203: UU1.G17 108.96,50.55 v2(109.09,50.59)
  BOTTOM w0.254: v1(98.52,20.52) 98.52,21.08 v3(98.25,21.36)
VCC_VCCIN_SENSE_P: length 40.6
  ART06 w0.203: v2(109.06,49.78) 109.06,49.51 111.28,47.3 111.28,43.91 109.75,42.39 109.75,40.48 107.08,37.81 107.08,33.5 103.86,30.27 100.05,30.27 98.5,28.72 98.5,21.73 97.97,21.2 97.97,20.72 v1(97.76,20.52)
  BOTTOM w0.127: v1(97.76,20.52) 97.46,20.52 v3(96.77,21.21)
  BOTTOM w0.254: PR629.2 98.03,20.27 97.78,20.52 v1(97.76,20.52) ; v2(109.06,49.78) 109.06,49.86 UU1.F17
VCCIN_AUX_BST: length 4.8
  BOTTOM w0.102: PR506.2 79.7,23.64 v3(81.71,23.64)
  BOTTOM w0.191: 78.36,24.99 78.36,25.32 78.12,25.56 PU501.10
  BOTTOM w0.381: PR506.2 78.36,24.99
VCCIN_AUX_BST1_R: length 2.6
  BOTTOM w0.102: v3(80.67,22.68) 80.57,22.78 PR506.1
  BOTTOM w0.292: PC501.1 PR506.1
VCCIN_AUX_COMP: length 4.9
  BOTTOM w0.102: v3(78.84,30.35) 78.84,29.89 78.99,29.74 PC509.1
  BOTTOM w0.191: PC507.1 PC509.1 78.83,29.28 78.64,29.09 78.64,28.17 78.08,27.61 77.44,27.61 PU501.5
VCCIN_AUX_EN: length 2.9
  BOTTOM w0.102: PU501.19 74.27,26.76 74.17,26.87 74.17,27.51 PC506.1 73.04,28.01 PR530.2
VCCIN_AUX_FB: length 3.6
  BOTTOM w0.191: PC509.2 PR522.2 PR524.1 PC508.1 78.74,27.76 78.14,27.16 PU501.6
VCCIN_AUX_FSW: length 8
  BOTTOM w0.102: PR519.1 80.64,25.04 81.02,25.42 81.48,25.42 81.79,25.12 83.36,25.12 v3(84.17,25.93)
  BOTTOM w0.191: PU501.9 78.47,25.96 78.61,25.82 78.61,25.6 79.25,24.97 PR521.1 79.5,25.22 79.63,25.35 80.25,25.35 PR519.1
VCCIN_AUX_HG: length 20.4
  ART03 w0.508: v1(75.56,22.93) 76.73,21.77 79.91,21.77 82.8,18.87 82.8,16.71 v1(86.1,13.41)
  BOTTOM w0.191: PU501.11 77.19,24.36 77.24,24.31 77.24,23.72
  BOTTOM w0.508: v1(86.1,13.41) 86.74,12.77 PR510.2 ; 77.24,23.72 v3(76.78,23.26) 76.45,22.93 v1(75.56,22.93)
VCCIN_AUX_HG_R: length 2.3
  BOTTOM w0.508: PR510.1 89.74,13.85 PQ501.4
VCCIN_AUX_ISEN_R: length 9.7
  TOP w0.254: v1(83.31,29.41) 82.15,29.41 PR517.1 81.93,30.07 PR516.2
  ART06 w0.254: v1(86.74,25.71) 85.74,25.71 83.31,28.14 v1(83.31,29.41)
  BOTTOM w0.102: v3(85.8,25.68) 85.84,25.71 v1(86.74,25.71)
  BOTTOM w0.254: PRT501.1 v1(86.74,25.71)
VCCIN_AUX_ISENSEP: length 4.5
  TOP w0.102: PR532.1 v3(81.14,32.15)
  TOP w0.254: PR532.1 PR516.1 80.8,30.35 80.71,30.44 PC505.1 PR520.2 PR514.2
VCCIN_AUX_ISN: length 5.2
  TOP w0.254: v3(77.32,28.48) 77.71,28.86 PR515.1 77.32,29.54 v2(76.55,30.3)
  BOTTOM w0.191: PU501.3 76.39,29.22 76.55,29.39 v2(76.55,30.3)
VCCIN_AUX_ISP: length 4.5
  TOP w0.254: v1(76.05,29.79) 76.05,30.45 76.35,30.76 77.39,30.76 PR514.1
  BOTTOM w0.191: PU501.2 75.99,29.58 76.05,29.64 v1(76.05,29.79)
VCCIN_AUX_LG: length 29.6
  ART03 w0.508: v4(97.41,14.68) 96.7,14.68 95.68,13.66 88.01,13.66 84.2,17.47 84.2,20.01 81.43,22.78 76.86,22.78 76.07,23.57 v1(76.07,24.08)
  BOTTOM w0.191: v1(76.07,24.08) 76.39,24.39 PU501.13
  BOTTOM w0.483: PQ502.4 v4(97.41,14.68)
VCCIN_AUX_PG: length 108.4
  TOP w0.102: RE8.1 156.16,18.41 156.41,18.16 v2(156.41,18.06)
  ART05 w0.102: v2(77.72,28.09) 77.72,28.62 78.48,29.39 81.44,29.39 83.41,27.41 83.41,14.02 85.69,11.75 105.46,11.75 105.71,12 111.46,12 112.43,11.02 128.01,11.02 129.4,12.42 136.9,12.42 138.53,14.04 138.53,15.16 141.48,18.11 141.48,19.63 143.05,21.21 146.61,21.21 146.81,21 148.03,21 148.18,20.85 151,20.85 151.1,20.95 152.65,20.95 152.91,21.21 155.19,21.21 155.65,20.75 155.65,18.62 156.21,18.06 v2(156.41,18.06)
  BOTTOM w0.102: v2(77.72,28.09) 77.72,28.93 77.87,29.08 v3(77.87,29.39) 77.77,29.49 77.16,29.49 PR513.1 76.79,29.11 PU501.4
VCCIN_AUX_PG_R: length 6.3
  TOP w0.076: UE1.G2 160.72,17.49 160.33,17.49
  TOP w0.102: 160.33,17.49 160.12,17.7 159.36,17.7 158.49,18.56 158.49,18.67 158.04,19.12 157.94,19.12 157.68,19.38 157.27,19.38 CE378.1 156.79,19.15 156.13,19.15 RE8.2
VCCIN_AUX_PHASE: length 32.2
  TOP w0.279: v2(83.95,29.41) 83.95,29.92 v3(83.3,30.57) 82.8,31.06 PR532.2
  ART03 w0.508: v4(89.66,21.66) 89.28,22.04 84.58,22.04 82.83,23.8 78.38,23.8 v4(78.1,24.08) v2(76.79,24.08)
  ART06 w0.254: v2(83.95,29.41) 83.95,28.39 86.1,26.24 88.26,26.24 90.8,23.7 92.2,23.7 v4(92.33,23.57)
  BOTTOM w0.191: PU501.12 v2(76.79,24.08)
  BOTTOM w0.254: v4(92.33,23.57) PL501.1
  BOTTOM w0.305: PC501.2 v4(78.1,24.08)
VCCIN_AUX_RGND: length 2.5
  BOTTOM w0.191: PR526.1 79.63,27 78.74,27 78.5,26.76 PU501.7
VCCIN_AUX_VCCSENSE: length 28.5
  PWR04 w0.203: v1(80.74,25.75) 81.18,26.18 82.5,26.18 82.8,26.49 82.8,28.02 82.19,28.63 82.19,30.83 84.83,33.47 87.12,33.47 90.93,37.28 90.93,41.22 89.89,42.26 89.89,45.56 v2(90.05,45.71)
  BOTTOM w0.254: PR525.2 v1(80.74,25.75)
  BOTTOM w0.279: UU1.BF9 v2(90.05,45.71)
VCCIN_AUX_VIN:
  vias: v3(82.62,17.83) v4(85.85,20.9) v4(85.85,20.01) v4(86.74,20.9) v4(86.74,20.01) v4(87.63,20.9) v4(87.63,20.01) v4(88.52,20.9) v4(88.52,20.01)
VCCIN_AUX_VOUT_R: length 10.4
  ART03 w0.254: v2(80.64,28.8) 80.64,28.47 79.12,26.95 v2(79.12,25.73)
  BOTTOM w0.102: PR518.1 82.41,29.02 v3(82.95,28.47)
  BOTTOM w0.191: PR524.2 PR523.2 PC510.2 ; PU501.8 78.48,26.36 v2(79.12,25.73) 79.14,25.75 PR525.1
  BOTTOM w0.254: PC510.2 PR518.1 80.86,29.02 v2(80.64,28.8)
VCCIN_AUX_VSSSENSE: length 30.8
  PWR04 w0.203: v2(90.96,45.71) 90.72,45.71 90.25,45.24 90.25,42.41 91.29,41.37 91.29,37.14 87.27,33.12 84.98,33.12 82.55,30.69 82.55,28.78 83.16,28.17 83.16,26.34 82.54,25.73 v4(81.79,25.73)
  BOTTOM w0.254: v4(81.79,25.73) 81.2,26.31 PR526.2
  BOTTOM w0.279: UU1.BD9 v2(90.96,45.71) ; v3(82.85,26.18) 82.4,25.73 v4(81.79,25.73)
VCCIN_BOOT1: length 6.6
  TOP w0.102: v3(111.05,19.53) 111.05,18.77 110.28,18.01 109.07,18.01 108.3,18.77 PR605.1
  TOP w0.191: 107.31,20.14 107.06,20.39 PU601.25
  TOP w0.381: 107.31,20.14 107.44,20.01 107.44,19.78 108.3,18.92 PR605.1
VCCIN_BOOT1_R: length 4.3
  TOP w0.279: PR605.2 109.62,19.12 108.96,19.78 PC605.1 110.69,20.65 v3(111.05,21)
VCCIN_BOOT2: length 5.2
  TOP w0.102: v3(109.12,27.2) 108.56,26.64 PR613.1
  TOP w0.191: 106.49,24.39 106.17,24.08 PU601.1
  TOP w0.381: PR613.1 108.56,25.47 108.1,25.02 107.34,25.02 106.72,24.39 106.49,24.39
VCCIN_BOOT2_R: length 2
  TOP w0.102: v3(110.91,26.91) 110.74,26.74 PC621.1
  TOP w0.305: PC621.1 PR613.2
VCCIN_COMP: length 2.1
  TOP w0.191: PR662.1 PR632.1 101.92,20.79 PU601.15
VCCIN_COMP_R1: length 3.2
  TOP w0.191: PR633.1 100.59,18.86 100.59,19.97 PR632.2
  TOP w0.203: PR633.1 100.48,18.01 v3(100.12,18.01)
VCCIN_FB: length 5.4
  TOP w0.191: PU601.16 102.48,20.39 102.23,20.14 102.23,19.89 PC608.2 PR633.2 v1(101.98,18.49)
  BOTTOM w0.102: v3(101.7,20.14) 101.47,19.91 PC608.2
  BOTTOM w0.254: v1(101.98,18.49) PR633.2 PC608.2
VCCIN_IMON: length 1.4
  TOP w0.191: PU601.11 102.27,22.39 102.23,22.43 101.61,22.43 PR636.2
VCCIN_IMON_R: length 1
  TOP w0.508: PR635.2 100.09,22.55 PR636.1
VCCIN_ISEN1N: length 2.5
  TOP w0.191: PU601.19 104.17,18.47 PR643.2
VCCIN_ISEN1P: length 4.7
  TOP w0.191: PU601.20 104.57,19.3 104.55,19.28 104.55,18.71
  TOP w0.254: 104.55,18.71 105.15,18.11 105.42,18.11 PR641.1 105.92,17.61 PC612.1 107.69,17.61 PR642.1
VCCIN_ISEN2N: length 2.3
  TOP w0.191: 103.77,18.87 PU601.18
  TOP w0.254: PR648.2 103.77,17.98 103.77,18.87
VCCIN_ISEN2P: length 5.6
  TOP w0.102: v3(100.23,16.74) 101.1,17.61 PR647.1
  TOP w0.191: 103.37,19.12 PU601.17
  TOP w0.254: 103.37,19.12 103.25,19 PC616.1 102.36,17.61 PR646.1 PR647.1
VCCIN_LGATE1: length 34.5
  TOP w0.191: v2(107.57,21.44) 107.41,21.59 PU601.28
  ART06 w0.508: v4(135.46,16.17) 131.16,16.17 129.79,14.81 128.52,14.81 127.25,16.08 112.06,16.08 109.12,19.02 108.61,19.02 107.57,20.06 v2(107.57,21.44)
  BOTTOM w0.127: v3(106.78,21.61) 107.39,21.61 v2(107.57,21.44)
  BOTTOM w0.508: PQ603.4 v4(135.46,16.17)
VCCIN_LGATE2: length 15.2
  TOP w0.191: v2(107.57,22.55) 107.41,22.39 PU601.30
  ART06 w0.508: v2(107.57,22.55) 107.19,22.55 106.58,21.94 106.58,19.48 107.57,18.49 107.57,16.2 108.58,15.19 110.34,15.19 v4(111.38,14.15)
  BOTTOM w0.127: v3(108.25,22.22) 107.92,22.55 v2(107.57,22.55)
  BOTTOM w0.508: PQ602.4 v4(111.38,14.15)
VCCIN_PH1_SNUB: length 2.5
  TOP w0.483: PC611.1 PR639.1 v3(130,23.97)
VCCIN_PH2_SNUB: length 3.2
  BOTTOM w0.127: PC615.1 v3(111.87,10.32)
  BOTTOM w0.508: PC615.1 PR644.1
VCCIN_PHASE1: length 57
  TOP w0.191: 107.97,21.03 107.39,21.03 107.23,21.19 PU601.27
  TOP w0.279: PR640.2 v4(106.94,15.17) ; v3(110.77,22.25) 110.77,21.94 v2(110.26,21.44)
  TOP w0.305: v2(110.26,21.44) 109.98,21.16 PC605.2 108.1,21.16 107.97,21.03
  TOP w0.508: PR639.2 v4(130.07,22.65)
  ART03 w0.279: v4(128.27,25.47) 128.01,25.22 128.01,19.38 123.95,15.31 111.12,15.31 110.86,15.05 107.07,15.05 v4(106.94,15.17)
  ART05 w0.508: v4(129.16,22.17) 128.78,21.79 122.43,21.79 121.28,22.93 119.51,22.93 118.01,21.44 v2(110.26,21.44)
  BOTTOM w0.279: v4(128.27,25.47) 129.28,25.47
VCCIN_PHASE2: length 40.9
  TOP w0.191: 107.57,23.19 107.17,22.79 PU601.31
  TOP w0.279: PR645.2 v2(102.22,15.17) ; v2(107.82,23.82) 107.57,23.57 107.57,23.19
  TOP w0.305: 111.95,25.54 111.63,25.85 PC621.2
  TOP w0.508: v4(113.69,23.9) 112.05,25.54 111.95,25.54
  ART03 w0.203: v2(102.22,15.17) 102.44,15.39 102.44,16.02 103.74,17.32 106.78,17.32 109.45,19.99 113.8,19.99 118.16,24.35 118.16,25.17 v4(117.85,25.47)
  ART03 w0.508: v4(113.69,23.9) 111.55,23.9 111.25,24.2 108.2,24.2 v2(107.82,23.82)
  BOTTOM w0.279: v4(117.85,25.47) 116.84,25.47
  BOTTOM w0.508: PR644.2 110.62,15.95 113.28,18.62 PQ602.5
  vias: v3(112.52,25.78)
VCCIN_PIN_TSEN_H: length 0.5
  BOTTOM w0.254: PR612.1 PR615.2
VCCIN_PIN_TSEN_L: length 1.6
  BOTTOM w0.102: v3(103.17,16.28) 103.99,16.28 PR627.2
  BOTTOM w0.254: PR623.1 PR627.2
VCCIN_PINSET_TSEN: length 38.1
  ART03 w0.203: v1(132.46,24.58) 132.33,24.71 131.57,24.71 129.67,26.62 117.22,26.62 115.82,25.22 107.95,25.22 106.86,24.13 106.86,20.17 v2(105.31,18.62)
  BOTTOM w0.254: v2(105.31,18.62) 105.28,18.59 PR615.1 PR623.2 ; PRT601.1 133.08,23.56 v3(132.84,23.8) 132.46,24.18 v1(132.46,24.58)
VCCIN_PVCC: length 5.8
  TOP w0.102: v3(110.54,24.1) 109.22,24.1 108.91,23.8 108.51,23.8 108.3,23.59 PR603.2
  TOP w0.191: 107.57,21.99 PU601.29
  TOP w0.381: PC604.1 107.6,21.96 107.57,21.99
  TOP w0.483: PR603.2 108.44,22.87 PC604.1
VCCIN_SENSE_R_N: length 5
  TOP w0.191: PC640.2 PR638.1 PR637.1 100.04,21.49 101.29,21.49 101.47,21.66 PC641.1 101.75,21.59 PU601.13
VCCIN_TSEN: length 39.7
  TOP w0.191: PU601.21 v2(104.97,19.05)
  ART03 w0.203: v2(104.97,19.05) 105.23,19.05 106.5,20.32 106.5,24.27 107.8,25.58 115.67,25.58 117.07,26.97 129.81,26.97 131.72,25.07 132.43,25.07 v1(132.59,25.22)
  BOTTOM w0.254: PR619.2 104.39,17.98 v3(104.39,18.46) 104.39,18.47 v2(104.97,19.05) ; v1(132.59,25.22) 133.35,24.46 133.35,24.2 133.87,23.68 PRT601.2
VCCIN_UGATE1: length 27.7
  TOP w0.191: PU601.26 107.2,20.79 107.39,20.6 107.44,20.6
  TOP w0.279: v4(108.33,20.52) 107.52,20.52 107.44,20.6
  ART06 w0.508: v4(108.33,20.52) 109.73,20.52 112.9,17.35 128.14,17.35 v4(129.54,15.95)
  BOTTOM w0.102: PR606.1 131.11,14.81 v3(131.47,15.16)
  BOTTOM w0.508: v4(129.54,15.95) 130.06,15.43 PR606.1
VCCIN_UGATE1_R: length 3.3
  BOTTOM w0.127: PR606.2 v3(127.51,14.81)
  BOTTOM w0.508: PR606.2 128.73,14.81 PQ604.4
VCCIN_UGATE2: length 14.1
  TOP w0.191: PU601.32 107,23.19 107.19,23.38 107.19,23.7
  TOP w0.279: 107.19,23.7 107.19,23.95 107.69,24.46 108.71,24.46
  TOP w0.508: 108.71,24.46 109.07,24.81 111.28,24.81 v3(112.64,23.45) 113.66,22.43 PR614.1
VCCIN_UGATE2_R: length 2.9
  TOP w0.508: PR614.2 120.39,22.43 v1(120.9,21.92) 121.41,21.92 v3(121.87,22.37)
  BOTTOM w0.457: PQ601.4 v1(120.9,21.92)
VCCIN_VCC: length 0.9
  TOP w0.191: 101.98,23.06 102.25,22.79 PU601.10
  vias: v3(101.06,25.35)
VCCIN_VIDALERT_N: length 15.8
  TOP w0.102: PR657.1 107.05,26.79 107.64,26.79 108.15,27.3 PC659.2 PR661.1 107.85,28.37 107.64,28.17 v1(107.64,28.14)
  BOTTOM w0.102: RU187.1 111,37.28 111.38,36.9 RU184.1 111.12,36.65 111,36.52 111,35.07 v3(111.2,34.87) 111.2,34.52 109.83,33.14 109.83,30.35 107.64,28.17 v1(107.64,28.14)
VCCIN_VIDALERT_N_R: length 4.6
  BOTTOM w0.102: 108.3,42.06 108.3,41.43 v3(110.13,39.6) 111,38.73 RU187.2
VCCIN_VIDSCK: length 15.8
  TOP w0.102: PR658.1 PC657.2 105.51,26.9 105.46,26.85 v2(105.46,26.64) 105.41,26.59 PR649.1
  BOTTOM w0.102: v2(105.46,26.64) 106.37,27.56 106.78,27.56 107.01,27.79 107.01,28.39 109.4,30.78 v3(109.4,33.17) 109.4,33.27 110.67,34.54 110.67,36.93 110.56,37.03 RU182.1 110.23,37.54 110.36,37.67 RU185.1
VCCIN_VIDSCK_R: length 5.3
  BOTTOM w0.102: UU1.H2 107.97,42.38 107.97,41.2 110.36,38.81 RU185.2
VCCIN_VIDSOUT: length 16.6
  TOP w0.102: PR655.1 PC658.2 106.53,26.9 106.27,26.64 v2(106.17,26.64) 106.12,26.64 105.92,26.44 PR656.1
  BOTTOM w0.102: RU186.1 111.63,37.28 111.89,37.03 RU183.1 112.16,36.65 112.27,36.55 112.27,35.1 110.13,32.97 110.13,30.1 v3(109.83,29.79) 109.83,29.59 107.24,27 106.53,27 v2(106.17,26.64)
VCCIN_VIDSOUT_R: length 6.5
  BOTTOM w0.076: 108.96,41.09 108.65,41.41 108.65,41.68 108.75,41.78 108.75,42.24 108.55,42.44 108.55,42.85 108.3,43.1 UU1.H3
  BOTTOM w0.102: RU186.2 111.63,38.81 109.35,41.09 108.96,41.09
VCCIN_VR_VIN: length 4.9
  TOP w0.191: v2(106.04,18.23) 106.04,18.49 105.4,19.13 105.4,19.26 105.37,19.29 PU601.22
  BOTTOM w0.102: v2(106.04,18.23) v3(106.04,19.3)
  BOTTOM w0.254: 107.69,17.47 107.39,17.47 107.25,17.61 PR602.2 106.67,17.61 v2(106.04,18.23)
VCCIN_VREF: length 71.6
  TOP w0.191: PU601.12 101.98,21.99 v2(101.98,21.99)
  TOP w0.279: v2(103.99,28.12) 104.11,28.12 104.39,27.84 PR611.2 PR610.2 ; PR609.2 v2(102.36,28.12)
  ART03 w0.203: v2(133.35,25.73) 133.22,25.85 132.71,25.85 130.96,27.61 116.05,27.61 114.81,26.36 109.6,26.36 109.17,26.79 106.98,26.79 106.27,26.08 105,26.08 104.34,26.74 100.28,26.74 99.77,27.25 96.9,27.25 96.37,26.72 96.37,25.25 v4(97.03,24.58)
  ART06 w0.508: v4(105.92,15.82) 105.92,16.71 101.98,20.64 v2(101.98,21.99)
  BOTTOM w0.203: v2(133.35,25.73) 133.21,25.87 PRT602.1
  BOTTOM w0.254: PR612.2 105.28,16.33 105.79,15.82 v4(105.92,15.82)
  BOTTOM w0.279: v2(103.99,28.12) 103.99,27.96 103.63,27.61 102.87,27.61 v2(102.36,28.12) 101.75,27.51 v3(99.19,27.51) 96.9,27.51 96.52,27.12 96.52,24.97 96.9,24.58 v4(97.03,24.58) 97.92,23.7 PR653.1 99.31,23.31 99.51,23.12 101.2,23.12 101.48,22.84 PR608.1 101.48,22.49 v2(101.98,21.99)
VCCIN_VREF_R: length 2.3
  BOTTOM w0.127: v3(101.29,21.41) 101.29,21.82 100.7,22.41 PR608.2
  BOTTOM w0.381: PR608.2 PC606.2
VCCIN_VRHOT: length 3.1
  TOP w0.102: PR607.2 107.02,25.56 106.68,25.22 106.48,25.22 105.77,24.51 PU601.2
VCCIN_VSEN: length 10
  TOP w0.191: PU601.14 101.53,21.19 PC631.1 101.47,20.88 101.37,20.77 100.81,20.77 100.58,20.55 100.58,20.38 100.25,20.04 100.25,19.23 100.14,19.12 PC640.1 v2(99.44,19.12)
  BOTTOM w0.127: v3(99.62,21.36) 99.62,20.69 PR629.1
  BOTTOM w0.254: v2(99.44,19.12) PR664.2 PC609.2 99.32,18.49 PR630.2 PR629.1
VCCSENSE_VGA: length 45.9
  ART03 w0.203: v1(169.19,37.2) 169.06,37.33 169.06,37.87 168.89,38.04 168.89,39.74 157.88,50.75 147.95,50.75 147.29,51.41 147.29,53.44 145.02,55.71 145.02,57.6 140.99,61.63 140.99,63.07 v1(141.43,63.51)
  BOTTOM w0.203: v1(141.43,63.51) 141.84,63.91 UV2.F2 ; v1(169.19,37.2) 169.5,36.89 PR838.1 169.51,36.51 PC888.2
VCCST_EN: length 6.6
  BOTTOM w0.102: PU901.6 50.16,64.26 PR903.2 PC977.1 50.7,62.96 50.85,62.81 51.79,62.81 51.89,62.71 PD906.3 PD904.3
VCCST_OVERRIDE: length 35.1
  TOP w0.102: v2(68.2,31.21) 68.2,34.14 v2(69.21,35.15)
  BOTTOM w0.102: v2(68.2,31.21) 67.94,31.47 67.33,31.47 66.67,30.81 66.67,26.25 PQ902.1 ; v2(69.21,35.15) 69.75,34.62 76.45,34.62 77.32,33.75 81.05,33.75 82.45,35.15 v3(82.45,35.81) 81.79,36.47 81.79,36.88 81.05,37.61 RU181.1 ; UU1.CE4 80.24,43.53 80.52,43.25 80.52,43.15 80.57,43.1 80.57,42.93 80.52,42.87 80.52,41.37
  BOTTOM w0.203: RU181.1 RU157.2 81.05,40.84 80.52,41.37
VCCST_OVERRIDE_R: length 50.6
  ART05 w0.102: v1(51.81,61.14) 51.81,61.03 51.05,60.27 51.05,54.68 50.04,53.67 50.04,52.4 49.53,51.89 49.53,51 49.91,50.62 50.54,50.62 51.69,49.48 51.69,44.98 52.47,44.19 52.47,35.74 61.21,27 v2(67.69,27)
  BOTTOM w0.102: PD906.2 51.81,60.91 v1(51.81,61.14) ; v2(67.69,27) 67.94,26.74 PR901.1 68.2,26.19 PQ901.3
  BOTTOM w0.127: v2(67.69,27) 67.69,27.84 v3(67.97,28.12)
VCCSTG_EN: length 29.5
  ART03 w0.089: v1(38.25,68.15) 38.76,67.64 42.06,67.64 42.37,67.94 45.67,67.94 46.78,66.82 51.84,66.82 v1(51.92,66.75)
  BOTTOM w0.102: PR921.1 37.84,68.55 v1(38.25,68.15) 39.19,67.21 PR920.1 ; PD907.3 47.53,60.71 48.41,61.59 48.41,67.49 48.74,67.82 PU904.6 49.71,67.82 50.65,66.88 PR907.1 PC975.1 51.79,66.88 v1(51.92,66.75)
VCCSTPWRGOOD_TCSS: length 5.1
  BOTTOM w0.203: UU1.CE3 80.24,41.96 80.1,41.82 80.1,40.98 80.54,40.54 RU157.1
VDDQ_BST: length 2.3
  BOTTOM w0.203: 47.95,79.27 47.95,79.47 47.49,79.94 PU701.18
  BOTTOM w0.305: PR704.1 48.72,78.51 47.95,79.27
VDDQ_BST_R: length 0.8
  BOTTOM w0.305: PC702.1 PR704.2
VDDQ_EN: length 3.2
  BOTTOM w0.102: PR703.2 43.1,83.72 43.99,82.83 44.55,82.83 45.12,82.26 PU701.11
VDDQ_PG: length 5.7
  ART03 w0.254: v2(41.5,83.49) 41.42,83.41 41.42,81.83 42.66,80.59 v2(43.76,80.59)
  BOTTOM w0.203: PU701.8 v2(43.76,80.59)
  BOTTOM w0.254: PR706.2 v2(41.5,83.49)
VDDQREF: length 1.2
  BOTTOM w0.203: PC701.1 44.35,78.51 44.62,78.78 PU701.6
VDDQSNS: length 1.3
  BOTTOM w0.254: PU701.4 45.62,78.67 45.62,78.66 ; PU701.2 46.62,78.47 46.63,78.46
VSSSENSE_VGA: length 45.2
  ART03 w0.203: v1(168.6,37.15) 168.75,37.3 168.75,37.72 168.58,37.88 168.58,39.54 157.76,50.37 147.83,50.37 146.99,51.2 146.99,53.24 144.72,55.51 144.72,57.48 140.66,61.54 v1(140.66,63.54)
  BOTTOM w0.203: PR837.1 168.85,37.52 168.6,37.27 v1(168.6,37.15) ; UV2.F1 v1(140.66,63.54)
1P8VSX: length 0.7
  TOP w0.102: 186.94,24.05 186.54,24.05 v3(186.33,24.25)
3P3VA_EN: length 319.9
  TOP w0.102: RE104.2 RE102.2 156.72,18.49 v2(156.41,18.79) ; v2(130.17,30.81) 130.15,30.83 130.15,37.01 130.5,37.36 130.5,46 v1(131.57,47.06)
  ART03 w0.089: v2(49.02,41.98) 48.89,41.98 47.88,40.97 43.05,40.97 40.13,38.05 40.13,33.35 39.16,32.38 36.73,32.38 34.8,30.45 34.8,28.9 34.75,28.85 34.75,23.39 29.16,17.8 29.16,16.74 26.72,14.3 24.64,14.3 23.95,14.98 17.88,14.98 v1(17.07,14.17)
  ART05 w0.102: v2(156.41,18.79) 156.06,19.15 156.06,22.93 155.7,23.29 155.24,23.29 153.11,25.42 151.79,25.42 151.37,25.84 151.37,26.38 149.24,28.51 134.73,28.51 132.38,30.86 130.22,30.86 v2(130.17,30.81) 129.82,31.16 127.23,31.16 125,33.39 112.9,33.39 112.24,32.74 110.77,32.74 109.47,31.44 v1(107.31,31.44)
  ART06 w0.102: v2(108.33,11) 109.12,11 109.57,10.54 110.18,10.54 110.39,10.74 110.39,11.05 110.69,11.35 111.1,11.35 112.11,10.34 128.56,10.34 129.27,11.05 136.06,11.05 136.46,10.64 137.38,10.64 137.99,11.25 140.26,11.25 140.87,10.64 143.63,10.64 143.8,10.82 147.65,10.82 148.59,11.76 149.52,11.76 153.24,15.48 153.24,16.46 154.28,17.5 155.04,17.5 156.34,18.79 v2(156.41,18.79) ; v1(130.55,62.3) 130.81,62.05 130.81,59.76 132.26,58.32 132.26,55.12 131.57,54.43 v1(131.57,47.06) ; v1(17.07,14.17) 16.53,13.64 16.53,10.92 17.14,10.31 17.14,8.84 16.89,8.58 16.89,7.44 18.16,6.17 19.05,6.17 20.32,4.9 20.32,3.63 22.22,1.72 46.07,1.72 48.25,3.91 69.29,3.91 70.23,4.85 94.46,4.85 95.17,4.14 97.33,4.14 97.53,4.34 v2(97.53,4.65)
  BOTTOM w0.102: v2(108.33,11) 108.15,11 103.22,6.07 98.96,6.07 v2(97.53,4.65) ; v3(105.1,29.79) 106.83,29.79 107.31,30.27 v1(107.31,31.44) 107.39,31.52 QU4.3 ; RL47.1 14.45,14.98 15.44,15.97 16.66,15.97 v3(17.17,15.47) 17.27,15.36 17.27,14.65 17.07,14.45 v1(17.07,14.17) ; RV245.1 131.86,63.61 v1(130.55,62.3) ; v2(49.02,41.98) 49.5,42.47 49.5,42.77 49.6,42.87 50.16,42.87 50.29,43 PR202.1
3P3VA_EN_EC: length 5.6
  TOP w0.076: UE1.J4 161.63,16.24 v2(161.46,16.41)
  TOP w0.102: RE104.1 157.66,17.98 157.86,17.78 v2(157.99,17.78)
  BOTTOM w0.102: v2(161.46,16.41) 161.01,16.86 158.32,16.86 157.99,17.19 v2(157.99,17.78)
5P0VA_EN: length 279.7
  TOP w0.076: UE1.A9 164.47,20.63 v2(164.54,20.7)
  TOP w0.102: v2(103.86,35.25) 103.86,34.49 v3(103.58,34.21)
  ART03 w0.089: v2(164.54,20.7) 164.56,20.7 165.99,19.28 165.99,14.91 164.97,13.89 164.97,11.63 163.57,10.23 163.57,9.09 162.32,7.84 162.32,7.04 161.62,6.33 158.95,6.33 157.53,7.76 155.14,7.76 154.83,7.45 152.8,7.45 152.22,6.87 149.45,6.87 148.82,6.23 135.32,6.23 134.19,5.1 115.54,5.1 114.6,6.04 109.75,6.04 109.47,6.32 106.93,6.32 106.7,6.55 103.98,6.55 103.39,5.97 101.53,5.97 98.95,3.39 90.06,3.39 89.69,3.76 72.82,3.76 72.26,4.32 71.35,4.32 69.77,2.74 48,2.74 47.29,2.03 44.05,2.03 38.1,7.98 38.1,18.56 50.42,30.88 50.42,35.86 50.11,36.17 50.11,42.31 50.65,42.85 50.65,43.66 49.53,44.78 49.53,45.44 49.83,45.74 50.39,45.74 50.54,45.9 50.54,47.01 51.31,47.77 51.31,49.1 52.42,50.21 52.42,51.03 52.07,51.38 51.86,51.38 v2(51.56,51.69)
  ART05 w0.102: v2(103.86,35.25) 104.21,35.61 107.16,35.61 108.58,37.03 114.76,37.03 118.59,40.87 125.19,40.87 127.1,38.96 127.1,35.66 128.19,34.57 129.33,34.57 129.77,34.14 133.45,34.14 134.03,33.55 135.56,33.55 136.27,34.26 137.46,34.26 138.48,33.25 139.19,33.25 140.08,32.36 143.81,32.36 143.99,32.53 152.4,32.53 153.62,31.32 153.62,26.16 155.09,24.69 156.23,24.69 159.46,21.46 160.53,21.46 161.72,20.27 164.11,20.27 v2(164.54,20.7)
  BOTTOM w0.102: v2(103.86,35.25) 104.11,35.51 QU5.3 ; v2(51.56,51.69) 51.66,51.79 PR305.1
+FBA_VREFC: length 54.4
  TOP w0.254: v3(180.85,57.8) 181,57.95 RV101.1 181.93,57.97 RV102.2 RV103.1 CV119.1 181.7,59.69 v1(181.42,59.42)
  ART05 w0.381: v1(181.42,59.42) 182.98,57.86 186.92,57.86 188.97,59.92 188.97,88.96 186.66,91.27 181.55,91.27 v1(180.45,90.17)
  BOTTOM w0.254: UV4.J14 180.49,90.17 v1(180.45,90.17)
  BOTTOM w0.279: v1(180.45,90.17) 180.45,90.73 180.91,91.19 CV118.1
  BOTTOM w0.305: v1(181.42,59.42) 181.01,59.83 UV3.J14
+PLLVDD: length 13.6
  TOP w0.305: RV53.2 144.45,68.96 143.83,68.34 RV51.2
  TOP w0.508: 140.84,65.73 142.62,67.52 RV51.2 ; CV44.1 135.69,59.51 136.65,59.51 138.3,61.16 138.3,63.83 138.68,64.21 138.68,65.35
+VADP: length 8.9
  TOP w0.279: PR166.2 25.07,68.73 PR186.2 24.59,68.32 24.65,68.26 v4(24.65,68.18)
  BOTTOM w0.279: v4(19.56,72.34) 20.7,72.34 21.08,71.96 22.22,71.96 22.81,71.37 22.81,69.72 23.87,68.65 24.18,68.65 v4(24.65,68.18)
  vias: v3(18.03,74.09) v4(18.79,72.34) v4(18.79,71.57) v4(18.79,70.69)
+VADP_CONN: length 1.5
  TOP w0.127: PR132.2 v3(17.52,82.06)
+VCON_IN: length 3.5
  BOTTOM w0.102: v3(52.07,33.8) 51.71,34.16 51.71,35.43 51.43,35.71 SHT1.2
  BOTTOM w0.254: UT1.8 48.62,36.54 49.15,36.01
+VCP_VDD1P8: length 4.3
  TOP w0.203: CA62.1 174.65,22.48 174.65,23.31 175.07,23.74 UA2.28
  TOP w0.254: RA233.1 CA61.1 174.33,22.16 CA62.1
+VGA_CORE: length 72.1
  TOP w0.254: CV98.1 147.32,68.1 v1(147.34,68.12)
  TOP w0.279: CV94.1 149.36,74.93 v1(149.34,74.91)
  BOTTOM w0.203: PR827.2 168.47,34.91 164.62,31.06 157.73,31.06 155.83,32.97 146.05,32.97 143.06,35.95 139.23,35.95 139.02,36.16 PCS801.1
  BOTTOM w0.279: v1(156.11,72.96) 155.74,72.59 UV2.T18 ; UV2.V5 v1(143.83,73.43) ; UV2.V6 v1(144.67,73.43)
  BOTTOM w0.305: UV2.V18 156.07,74.85 v1(156.07,74.96) ; v1(149.34,74.91) UV2.V12 150.22,74.03 v1(150.25,74.03) 150.25,74 UV2.U13 v1(151.34,72.91) UV2.T14 ; UV2.K16 154.08,66.17 v1(154.25,66.17) ; UV2.K14 v1(151.34,66.12) ; UV2.M18 v1(156.13,68.12) ; UV2.M10 v1(147.34,68.12) ; v1(155.23,74) UV2.U17 UV2.T16 v1(153.13,71.91) UV2.R15 ; v1(147.34,72.91) UV2.T10 v1(148.34,71.91) UV2.R11 v1(149.34,70.91) UV2.P12 ; UV2.V16 v1(154.13,74.91) ; UV2.P14 v1(151.25,71) UV2.R13 v1(150.34,71.91) UV2.T12 UV2.U11 v1(148.23,74.02) UV2.V10 147.47,74.78 v1(147.26,74.78) ; UV2.N13 v1(150.34,69.12) UV2.M12 UV2.L11 v1(148.24,67.02) ; UV2.L15 153.12,67.13 v1(153.12,67.03) ; UV2.M14 v1(151.34,68.12) ; UV2.P16 v1(154.13,70.91) ; UV2.P10 v1(147.34,70.91) ; UV2.M16 UV2.L17 v1(155.21,67.04) ; UV2.N11 v1(148.34,69.12) ; UV2.K12 v1(149.34,66.12) ; v1(150.36,67.06) 150.36,67.14 UV2.L13 ; v1(156.07,70.96) 156.07,70.85 UV2.P18 ; UV2.N17 v1(155.19,69.06) ; UV2.V14 v1(151.34,74.91) ; UV2.N15 v1(153.18,69.07) ; UV2.R17 v1(155.13,71.91) ; UV2.U15 v1(153.13,73.91)
  vias: v3(129.89,49.02) v4(130.43,71.96) v4(130.43,71.07) v4(130.43,68.91) v4(130.43,67.76) v4(131.44,69.8) v4(131.44,68.78) v4(131.82,71.96) v4(131.82,71.07) v4(132.46,69.8) v4(132.84,65.22) v4(133.35,71.96) v4(133.35,70.56) v4(133.6,65.99) v4(134.75,72.08) v4(135,67.13) v4(135,47.32) v4(135,46.43) v4(135,45.54) v4(135,44.65) v4(135.51,72.84) v4(135.76,67.89) v4(136.02,47.32) v4(136.02,46.43) v4(136.02,45.54) v4(136.02,44.65) v4(136.14,66.11) v4(136.9,47.32) v4(136.9,46.43) v4(136.9,45.54) v4(136.9,44.65) v4(137.06,40.69) v4(137.06,39.67) v4(137.29,69.42) v4(137.41,67.38) v4(137.74,40.66) v4(137.74,39.65) v4(137.79,47.32) v4(137.79,46.43) v4(137.79,45.54) v4(137.79,44.65) v4(138.05,70.18) v4(138.43,68.4) v4(138.56,40.71) v4(138.56,39.7) v4(138.68,45.54) v4(138.68,44.65) v4(138.81,70.94) v4(138.81,47.32) v4(138.81,46.43) v4(139.57,71.7) v4(139.57,69.54) v4(139.57,40.71) v4(139.57,39.7) v4(139.7,47.32) v4(139.7,46.43) v4(139.7,45.54) v4(139.7,44.65) v4(140.46,70.43) v4(140.46,40.71) v4(140.46,39.7) v4(140.59,47.32) v4(140.59,46.43) v4(140.59,45.54) v4(140.59,44.65)
+VGA_CORE_EN_N: length 4.7
  BOTTOM w0.102: v3(131.04,76.37) QV9.1 132.04,76.99 RV76.1 132.46,77.42 133.86,77.42 134.36,76.91 QV12.3
+VNN_BYPASS_R: length 1.5
  TOP w0.102: v3(73.35,57.02) 73.35,57.27 73.4,57.33 RU193.2
  BOTTOM w0.279: UU1.CY34 v2(73.32,58.52)
+VPVDD: length 5.1
  TOP w0.203: CA14.1 171.89,23.19 173.07,24.37 UA2.23 ; UA2.26 174.27,24.18 173.94,23.85 173.94,23.19 173.53,22.79 172.87,22.79
+VSTBY_FSPI: length 6.7
  TOP w0.076: UE1.E6 162.72,18.49 162.34,18.49 162.21,18.62 162.21,18.84 162.07,18.99 161.93,18.99 161.71,19.21 161.71,19.87 161.59,19.99 161.37,19.99 161.21,20.14 161.21,20.6 160.27,21.54 160.25,21.54
  TOP w0.102: 160.25,21.54 159.89,21.89 159.89,22.87 RE68.2
+VSYS: length 44.9
  TOP w0.254: RL1.2 160.27,28.83 159.56,29.54 v4(159.56,32.59)
  ART05 w0.381: v4(44.17,15.24) 44.17,13.15 45.06,12.27 50.95,12.27 51.71,11.5 55.62,11.5 58.42,14.3 76.83,14.3 v4(78.61,16.08)
  BOTTOM w0.203: PU101.22 44.81,14.85 44.42,15.24 v4(44.17,15.24)
  vias: v3(79.7,17.63) v4(16.64,68.4) v4(16.64,67.76) v4(17.27,68.4) v4(17.27,67.76) v4(17.91,68.4) v4(17.91,67.76) v4(36.12,81.56) v4(36.12,80.67) v4(36.98,81.61) v4(36.98,80.72) v4(37.79,81.61) v4(37.79,80.72) v4(42.5,79.87) v4(43.17,79.88) v4(48.18,54.35) v4(48.92,54.35) v4(51.18,54.18) v4(51.18,53.29) v4(52.07,54.18) v4(52.07,53.29) v4(52.93,54.18) v4(52.93,53.29) v4(71.27,29.92) v4(71.7,30.4) v4(76.45,20.65) v4(76.45,19.89) v4(76.45,19.12) v4(77.47,20.65) v4(77.47,19.89) v4(77.47,19.12) v4(78.36,20.65) v4(78.36,19.89) v4(78.36,19.12) v4(79.37,20.65) v4(79.37,19.89) v4(79.37,19.12) v4(157.87,33.53) v4(157.88,32.61) v4(158.69,33.53) v4(158.7,32.64) v4(159.56,33.5) v4(160.22,42.36) v4(160.22,41.48)
A4WP_PRESENT: length 18.2
  ART06 w0.102: v2(53.44,57.83) 53.8,57.83 54.15,57.48 54.3,57.48 55.32,56.46 55.32,56.16 56.13,55.34 56.79,55.34 57.28,55.83 58.06,55.83 58.37,55.52 61.06,55.52 61.39,55.85 63.09,55.85 63.22,55.73 65.63,55.73 65.91,55.45 66.7,55.45 v2(67.05,55.09)
  BOTTOM w0.102: v2(53.44,57.83) 53.92,57.35 RU77.1 RU78.2 ; v2(67.05,55.09) 67.35,54.8 UU1.DL27
ADP_DET_GND: length 10.5
  BOTTOM w0.254: 12.32,72.59 PR187.1
  BOTTOM w0.381: 11.01,73.26 11.01,75.33 PJ102.3 ; 11.01,73.26 10.31,72.56 10.31,71.65 11.63,70.33 TP194.1 ; 11.01,73.26 11.68,72.59 12.32,72.59
ADP_IN_EN: length 6.4
  TOP w0.102: PR166.1 25.65,68.26 PC150.1 25.19,67.8 PR167.2 25.19,66.74 v3(25.62,66.32) 25.02,65.71 25.02,65.02 24.23,64.23 23.77,64.23 23.43,63.89 PQ114.1
ADP_PRESENT: length 204.7
  TOP w0.076: v2(161.46,18.97) 161.19,19.24 UE1.C2
  TOP w0.102: PQ114.2 25.45,63.7 PC152.1 PR169.1 26.03,62.94 25.63,62.94 v2(25.4,62.71) v3(24.94,62.25)
  ART03 w0.089: v2(147.95,8.91) 148,8.86 152.46,8.86 154.34,10.74 157.86,10.74 159.07,9.53 159.83,9.53 161.27,10.98 161.27,14.59 161.03,14.82 161.03,16.58 161.29,16.84 161.69,16.84 161.9,17.04 161.9,18.53 v2(161.46,18.97)
  ART05 w0.102: v2(147.95,8.91) 146.61,7.57 142.45,7.57 141.92,8.1 131.21,8.1 129.69,6.58 116.66,6.58 114.32,4.24 110.83,4.24 109.89,5.18 105.13,5.18 104.09,6.22 101.77,6.22 101.28,6.7 88.96,6.7 87.86,7.8 66.11,7.8 63.9,5.59 48.94,5.59 48.73,5.79 42.43,5.79 39.39,8.84 35.74,8.84 32.26,12.32 32.26,15.19 32.64,15.57 32.64,20.9 31.01,22.53 31.01,28.55 30.3,29.26 30.3,35.3 28.32,37.28 28.32,41.09 27.81,41.6 27.81,43.96 27.15,44.63 27.15,47.37 26.8,47.72 26.8,56.72 25.4,58.11 v2(25.4,62.71)
ALLSYSPWRGD: length 72.7
  TOP w0.076: UE1.B9 164.47,19.9 164.22,20.15 164.22,20.38 164.19,20.42 164.19,20.9 v2(164.89,21.61)
  ART06 w0.102: v2(164.89,21.61) 165.03,21.48 165.03,20.58 164.72,20.27 161.75,20.27 160.62,21.4 157.82,21.4 156.87,20.44 156.87,19.38 156.64,19.15 156.03,19.15 155.8,18.92 155.8,18.62 154.94,17.75 154.23,17.75 153.03,16.56 153.03,15.56 149.67,12.2 148.52,12.2 147.34,11.02 143.72,11.02 143.54,10.84 140.97,10.84 140.36,11.45 137.9,11.45 137.29,10.84 136.55,10.84 136.14,11.25 129.19,11.25 128.48,10.54 112.22,10.54 111.2,11.55 110.54,11.55 v2(109.98,11)
  BOTTOM w0.102: PR604.1 109.35,16.71 109.35,15.39 v3(109.47,15.26) 109.6,15.14 109.6,11.38 v2(109.98,11)
AUD_GND: length 11.7
  TOP w0.203: UA2.39 v1(177.39,28.57) ; CA79.2 182.78,32.74 v4(182.57,32.94) ; CA68.2 175.58,33.69 v1(175.61,33.65) ; v1(181,29) 181.1,28.9 181.2,28.9 181.28,28.83 CA81.2 ; CA78.2 182.78,31.42 v1(182.37,31.01)
  TOP w0.254: CA56.2 180.48,30.59 v4(180.54,30.66) ; v4(184.71,38.1) 184.58,38.22 CA37.1 ; 179.96,33.14 v4(180.19,33.14) ; CA57.2 v4(178.56,30.2) ; v4(182.75,37.31) 182.75,37.59 183.14,37.98 RA18.1 ; CA32.2 182.29,30.48 182.34,30.43 v1(182.45,30.43) ; v1(180.41,28.98) CA69.2
  TOP w0.279: 179.96,33.14 179.83,33.27 CA74.2
  BOTTOM w0.254: JDB1.40 184.75,32.7 v4(184.76,32.7) ; JDB1.33 184.62,36.2 v4(184.71,36.11) ; JDB1.37 184.48,34.2 v4(184.7,33.98)
  vias: v3(178.66,33.5) v4(184.4,27.12) v4(184.91,28.65) v4(184.91,27.63)
BATT_IN_L: length 89.6
  TOP w0.076: 163.29,21.77 163.29,21.13 163.22,21.06 163.22,19.99 UE1.B7
  TOP w0.102: RE108.1 163.52,23.29 v1(163.9,22.91) 163.9,22.71 163.78,22.58 163.42,22.58 v3(163.17,22.32) 163.17,21.89 163.29,21.77
  ART05 w0.102: v2(107.19,11) 106.68,10.49 v2(98.8,10.49)
  ART06 w0.102: v2(107.19,11) 108.02,11.83 111.38,11.83 112.47,10.74 128.4,10.74 129.79,12.14 135.63,12.14 136.73,11.05 137.21,11.05 137.82,11.66 145.74,11.66 146.18,11.22 147.17,11.22 148.44,12.49 149.63,12.49 151.33,14.2 151.33,15.01 151.76,15.44 152.14,15.44 152.53,15.82 152.53,17.05 153.11,17.64 153.11,19.33 154.39,20.61 155.3,20.61 156.29,21.6 160.81,21.6 161.83,20.58 163.63,20.58 164.36,21.31 164.36,22.45 v1(163.9,22.91)
  BOTTOM w0.102: v2(98.8,10.49) 99.67,11.35 99.67,14.15 100.43,14.91 100.43,16.48 100.33,16.58 PESD105.2 PR136.1
BATT_PRES_N: length 4.1
  BOTTOM w0.102: PR136.2 PR137.1 98.75,14.75 PTP102.1 98.79,14 PJ101.5
BB_TCP0_FLASH_BUSY_N: length 5.5
  TOP w0.102: RT49.1 RT50.2 21.21,18.36 21.36,18.51 22.17,18.51 v3(22.55,18.89) 22.55,19.07 23.24,19.76 23.62,19.76 24.25,20.39 UT2.A9
BB_TCP0_FLASH_CLK: length 15.9
  TOP w0.102: UT2.C7 v2(25.07,21.94)
  ART05 w0.102: v2(25.07,21.94) 25.65,22.52 25.65,25.6 26.54,26.49 26.54,27.63 28.32,29.41 v1(28.32,32.33)
  BOTTOM w0.102: v1(28.32,32.33) 27.53,32.33 27.25,32.61 27.25,33.53 27.18,33.6 RT71.1 v3(25.88,33.86)
BB_TCP0_FLASH_CLK_R: length 2.2
  BOTTOM w0.102: UT3.6 28.97,34.62 28.2,33.86 RT71.2
BB_TCP0_FLASH_CS_N: length 31.7
  TOP w0.076: UT2.B6 25.86,21.27 25.86,20.22 v2(25.78,20.14)
  BOTTOM w0.102: RT69.1 39.11,38.05 38.99,38.17 38.35,38.17 37.97,37.79 35.18,37.79 34.92,37.54 34.92,31.16 33.75,29.99 33.75,25.9 32.26,24.4 32.26,23.64 32.54,23.36 32.54,21.82 30.2,19.48 29.2,19.48 27.9,20.77 v3(26.52,20.77) 26.41,20.77 v2(25.78,20.14)
BB_TCP0_FLASH_CS_N_R: length 3.1
  BOTTOM w0.102: RT69.2 RT74.2 UT3.1
BB_TCP0_FLASH_DI: length 14.1
  TOP w0.102: UT2.C6 25.72,22.59 v2(26.37,22.59)
  ART05 w0.102: v1(28.29,32.97) 28.7,32.56 28.7,29.5 26.74,27.55 26.74,26.41 25.86,25.52 25.86,22.7 25.96,22.59 v2(26.37,22.59)
  BOTTOM w0.102: v1(28.29,32.97) 28.17,32.84 RT72.1
BB_TCP0_FLASH_DI_R: length 2
  BOTTOM w0.102: RT72.2 UT3.5
BB_TCP0_FLASH_DO: length 28.3
  TOP w0.076: UT2.B4 26.78,21.27 26.78,20.66 26.92,20.52 v2(26.92,20.04)
  BOTTOM w0.102: v2(26.92,20.04) v3(27.66,20.04) 28.24,20.04 29.06,19.23 30.45,19.23 32.76,21.54 32.76,23.44 32.46,23.75 32.46,24.31 33.96,25.81 33.96,29.84 35.13,31.01 35.89,31.01 39.62,34.74 39.62,35.18 40.13,35.68 40.13,36.14 39.75,36.52 RT70.1
BB_TCP0_FLASH_DO_R: length 3.1
  BOTTOM w0.102: RT70.2 RT75.2 UT3.2
BB_TCP0_FLASH_HOLD_N: length 3.1
  BOTTOM w0.102: UT3.7 28.5,35.89 28.4,35.99 27.94,35.99 27.63,35.68 27.63,35.23 27.43,35.02 RT77.2
BB_TCP0_FLASH_MSTR_SLV: length 3.9
  TOP w0.102: UT2.A5 26.09,20.47 26.13,20.42 26.13,18.77 26.8,18.11 RT62.1 RT63.2
BB_TCP0_FLASH_SHARE_EN: length 5.3
  TOP w0.102: UT2.A4 26.55,19.75 27.3,19 v2(27.3,18.87)
  BOTTOM w0.102: v2(27.3,18.87) 26.8,18.36 RT59.1 RT61.2 27.86,17.98 v3(28.29,18.41)
BB_TCP0_FLASH_WP_N: length 3
  BOTTOM w0.102: RT76.2 v3(38.2,34.82) 37.46,34.82 37.26,34.62 UT3.3
BB_TCP0_GPIO_5: length 5.7
  TOP w0.076: 24.02,20.77 24.02,21.27 UT2.B9
  TOP w0.102: 24.02,20.77 24.02,20.54 23.49,20.01 23.04,20.01 22.71,19.68 21.99,19.68 v3(21.24,18.93) 20.7,18.39 RT53.2
BB_TCP0_GPIO_6: length 5
  TOP w0.102: v2(24.13,18.49) 24.13,19.33 24.71,19.91 UT2.A8
  BOTTOM w0.102: v3(22.2,18.06) 22.27,17.98 RT57.1 RT58.2 23.75,18.11 v2(24.13,18.49)
BB_TCP0_GPIO_12: length 3.8
  TOP w0.102: RT64.1 RT65.2 25.78,18.36 25.65,18.49 25.65,18.87 25.4,19.12 25.4,20.48 25.63,20.71 UT2.A6
BB_TCP0_RBIAS: length 3
  TOP w0.076: UT2.L4 26.78,25.87 26.78,26.29 26.87,26.38
  TOP w0.102: v2(27.2,26.54) 27.02,26.54 26.87,26.38
  BOTTOM w0.102: v2(27.2,26.54) 26.85,26.18 v3(26.57,26.18)
  BOTTOM w0.381: RT44.1 27.47,26.99 27.2,26.72 v2(27.2,26.54)
BB_TCP0_RESET_N: length 86.6
  TOP w0.102: v2(20.83,26.57) 20.55,26.85 19.91,26.85 19.81,26.74 RT41.2 RT56.2
  ART06 w0.102: v2(20.83,26.57) 20.62,26.36 20.57,26.36 19.56,25.35 19.56,21.03 20.32,20.27 20.32,16.2 20.57,15.95 20.57,9.47 21.72,8.33 21.72,6.68 21.46,6.42 v2(20.7,6.42)
  BOTTOM w0.102: v2(20.7,6.42) 23.78,6.42 24.77,7.41 26.18,7.41 26.61,6.98 28.27,6.98 29.08,6.17 37.72,6.17 39.32,7.77 39.32,10.44 40.51,11.63 40.51,16.96 44.47,20.93 44.47,23.09 45.08,23.7 45.08,24.71 45.62,25.25 46.38,25.25 46.73,25.6 48.89,25.6 54.05,30.76 TPT5.1 53.44,33.88 53.44,35.66 51.99,37.11 49.58,37.11 49.14,37.54 UT1.6
BB_TCP0_RSENSE: length 2.2
  TOP w0.076: UT2.L5 25.86,25.87 25.86,26.31 25.91,26.36
  TOP w0.102: 25.91,26.36 26.16,26.62 v2(26.16,26.74)
  BOTTOM w0.381: v2(26.16,26.74) 26.21,26.74 26.68,27.21 RT44.2
BB_TCP0_TCK: length 4.4
  TOP w0.076: TPT11.1 26.32,19.27 26.32,21.27 UT2.B5
  TOP w0.102: TPT11.1 27.23,18.36 27.43,18.36 RT85.2
BB_TCP0_TDI: length 3.6
  TOP w0.102: RT84.2 28.32,18.36 28.07,18.62 TPT9.1 27.38,19.56 v3(27.38,19.58) 27.38,20.41 27.01,20.78 UT2.A3
BB_TCP0_TDO: length 8.3
  TOP w0.102: RT87.2 30.86,19 TPT12.1 30.06,19.03 30.06,19.42 v2(28.95,20.52)
  TOP w0.203: UT2.C5 26.05,22.17 v2(26.35,21.87)
  BOTTOM w0.102: v2(28.95,20.52) 29.31,20.88 v3(29.31,21.41) 28.95,21.41 28.65,21.1 28.24,21.1 27.76,21.59 26.63,21.59 v2(26.35,21.87)
BB_TCP0_TMS: length 7.4
  TOP w0.102: RT86.2 TPT10.1 30.22,19.89 v2(29.97,20.14)
  TOP w0.203: UT2.C3 v2(27.02,21.94)
  BOTTOM w0.102: v2(29.97,20.14) 30.1,20.27 30.1,22.4 v3(29.92,22.58) 29.28,22.58 28.65,21.94 v2(27.02,21.94)
BB_TCP1_LS_EN: length 23.1
  BOTTOM w0.102: RT82.1 24.64,34.11 24.76,33.98 RT80.1 25.04,33.2 26.92,33.2 27.02,33.09 27.02,32.41 27.57,31.86 30.77,31.86 31.06,31.57 31.7,31.57 TPT20.1 31.87,31.74 33.29,31.74 34.72,33.17 34.72,37.62 35.09,38 37.89,38 38.27,38.38 38.99,38.38 39.57,38.96 RT9.2
BB_TCP1_LS_EN_R: length 2.1
  BOTTOM w0.102: UT4.4 23.95,34.82 RT83.2 RT82.2
BB_TCP2_TEST_PWR_GOOD: length 4.3
  TOP w0.076: UT2.B3 27.24,21.27 27.24,20.9
  TOP w0.102: RT43.2 28.83,18.23 28.57,18.49 28.57,19.49 27.24,20.82 27.24,20.9
BC_PROCHOT_N: length 114.6
  TOP w0.102: RU228.2 74.67,59.64 74.67,57.05 v2(74.47,56.84) ; v2(49.02,9.6) 49.02,9.57 48.26,8.81 45.21,8.81 RU220.1 RU219.1 44.37,7.06 DU3.1
  ART05 w0.102: v2(47.14,29.97) 47.14,31.54 46.73,31.95 46.73,41.22 47.62,42.11 47.62,44.14 49.38,45.9 49.38,46.38 50.87,47.88 50.87,49.43 50.29,50.01 49.66,50.01 48.87,50.8 48.87,51.21 48.66,51.42 48.66,53.35 49.4,54.08 49.4,54.56 48.77,55.19 48.13,55.19 47.85,55.47 47.85,59.1 47.95,59.2 49.07,59.2 v2(51.03,61.16)
  ART06 w0.102: v2(74.47,56.84) 74.04,56.84 72.9,57.99 72.9,59.26 72.64,59.51 70.36,59.51 70.1,59.26 70.1,58.49 68.96,57.35 67.44,57.35 67,57.78 66.85,57.78 66.2,58.43 61.91,58.43 61.47,58.87 60.32,58.87 59.69,58.24 57.5,58.24 56.92,58.82 56.18,58.82 55.14,59.87 52.27,59.87 51.03,61.11 v2(51.03,61.16) ; v2(38.86,10.36) 39.5,9.73 43.84,9.73 44.35,9.22 48.64,9.22 v2(49.02,9.6)
  BOTTOM w0.102: PR162.1 48.86,9.76 v2(49.02,9.6) ; v2(38.86,10.36) 38.95,10.36 40.31,11.71 40.31,17.05 44.27,21.01 44.27,23.17 44.88,23.78 44.88,24.8 45.53,25.45 46.29,25.45 47.14,26.29 v3(47.14,27.38) v2(47.14,29.97) 47.14,30.9 47.88,31.64 RT129.2
BC_PROCHOT_N_PD: length 3.1
  BOTTOM w0.102: RT129.1 RT15.1 47.37,32.87 46.71,33.53 46.71,33.89 46.46,34.14 UT1.13
BI_GATE: length 76.9
  TOP w0.102: v3(13.26,71.55) 12.7,70.99 v1(12.7,70.69)
  TOP w0.254: v1(12.7,70.69) 12.83,70.56 PR1012.1 13.33,70.05 13.49,69.89 ESDL46.1 13.49,69.26 13.63,69.12 QL1.1
  ART06 w0.254: v1(15.75,69.92) 15.75,65.73 16.28,65.2 16.28,60.89 17.78,59.4 17.78,57.07 18.16,56.69 18.16,47.44 19.25,46.35 19.25,42.36 20.09,41.53 20.09,32.99 17.91,30.81 17.91,15.95 18.81,15.05 18.81,13.29 v1(17.65,12.14)
  BOTTOM w0.254: v1(15.75,69.92) 16.2,70.38 17.22,70.38 17.55,70.71 SW3.1 SW3.2 13.55,70.94 13.3,70.69 v1(12.7,70.69) ; RL455.1 18.01,12.14 v1(17.65,12.14) 17.19,12.14 16.09,11.03 QL8.1
BI_GATE_N: length 154.7
  TOP w0.102: v3(16.05,65.81) 16.25,66.01 v2(16.25,66.62) 15.68,67.2 QL1.3
  ART06 w0.102: v2(16.25,66.62) 16.64,66.24 16.64,60.93 18.29,59.28 18.29,57.86 18.79,57.35 18.79,47.32 19.56,46.56 19.56,44.78 20.37,43.96 20.37,32.64 18.29,30.55 18.29,17.85 18.79,17.35 18.79,16.08 19.94,14.93 19.94,8.8 19.59,8.46 19.59,6.64 20.19,6.04 21.97,6.04 24.64,3.38 25.4,3.38 25.53,3.25 31.77,3.25 32.15,3.63 35.46,3.63 36.42,2.66 41.43,2.66 43.97,5.2 46.3,5.2 47.39,4.11 68.76,4.11 70.69,6.04 94.87,6.04 v1(96.26,4.65)
  BOTTOM w0.102: v1(96.26,4.65) 96.52,4.9 96.52,11 96.79,11.27 PJ101.6
BT_OFF_N_WIFI: length 3.5
  TOP w0.102: v3(152.25,17.14) 152.25,16.86 v1(151.99,16.6) 151.68,16.29 151.39,16.29 RW7.2 RW58.1
  BOTTOM w0.102: JW1.54 152.34,16.95 v1(151.99,16.6)
BT_RF_KILL_N: length 113.4
  TOP w0.102: RW7.1 v3(149.91,16.23) 148.49,16.23 v2(148.28,16.43)
  ART05 w0.102: v1(133.75,35.43) 133.75,36.04 131.42,38.38 131.42,40.71 131.24,40.89 128.7,40.89 126.19,43.41 117.04,43.41 114.98,41.35 111.43,41.35 110.67,42.11 101.27,42.11 101.06,41.91 96.65,41.91 96.06,41.32 87.53,41.32 87.02,40.82 79.65,40.82 79.4,40.56 77.67,40.56 76.94,41.3 73.08,41.3 72.59,41.78 71.09,41.78 69.78,43.09 69.78,44.92 67.99,46.71 67.99,47.24 67.77,47.47 67.51,47.47 66.6,48.38 66.21,48.38 v2(65.77,48.83)
  ART06 w0.102: v2(148.28,16.43) 146.4,16.43 145.82,15.85 142.47,15.85 141.65,16.66 141.65,27.44 139.62,29.48 139.62,31.16 137.31,33.47 137.31,33.8 136.9,34.21 136.5,34.21 135,35.71 134.03,35.71 v1(133.75,35.43)
  BOTTOM w0.102: UU1.DP15 66.05,49.11 v2(65.77,48.83)
BT_WAKE_N_SOC: length 130
  TOP w0.102: v2(156.21,31.06) 155.73,31.54 152.37,31.54 152.14,31.32 152.14,30.66 150.37,28.88 v3(150.11,28.88) 149.1,28.88 148.38,28.17 148.38,27 RW66.1
  ART05 w0.102: v2(156.21,31.06) 156.13,31.06 153.08,34.11 141.02,34.11 140.26,34.87 139.6,34.87 135.28,39.19 135.28,41.6 131.7,45.18 130.27,45.18 128.8,46.66 114.73,46.66 113.64,45.57 105.64,45.57 104.95,46.25 104.27,46.25 104.21,46.2 103.35,46.2 103.17,46.02 99.87,46.02 99.59,45.74 99.59,45.57 99.39,45.36 99.05,45.36 99.02,45.39 95.63,45.39 95.1,44.85 95.1,43.48 94.92,43.3 84.68,43.3 83.92,44.07 81.74,44.07 81.53,43.86 77.09,43.86 76.76,44.19 76.76,45.64 76.1,46.3 71.63,46.3 70.61,47.32 70.61,48.62 73.02,51.03 73.02,56.21 74.8,57.99 75.18,57.99 75.56,58.37 75.56,58.75 76.53,59.71 76.53,62 v2(76.91,62.38)
  BOTTOM w0.102: UU1.CN43 v2(76.91,62.38)
CAM_PWR_ON_EC: length 230.8
  TOP w0.076: UE1.F12 166.12,17.74 166.37,17.99 166.67,17.99 166.8,17.86 v1(168.4,17.86)
  TOP w0.102: v3(26.21,80.39) 25.5,80.39 v1(25.04,80.85) 25.19,81 RX926.2
  ART03 w0.089: v1(168.4,17.86) 167.69,17.86 167.33,17.5 167.33,10.23 164.79,7.69 163.76,7.69 163.38,7.31 163.38,6.69 161.68,4.99 157.01,4.99 155.5,6.49 153.2,6.49 152.62,5.92 149.85,5.92 149.21,5.28 135.76,5.28 134.57,4.09 113.89,4.09 v2(113.33,4.65)
  ART05 w0.102: v2(113.33,4.65) 112.6,5.38 105.28,5.38 104.19,6.47 101.9,6.47 101.47,6.91 89.04,6.91 87.95,8 66.03,8 63.84,5.81 48.99,5.81 48.82,5.99 42.55,5.99 39.51,9.04 35.86,9.04 32.51,12.39 32.51,15.06 32.89,15.44 32.89,21.03 31.27,22.65 31.27,28.62 30.5,29.39 30.5,35.48 28.52,37.46 28.52,41.27 28.07,41.73 28.07,44.02 27.4,44.68 27.4,47.44 27,47.85 27,56.89 26.16,57.73 26.16,59.13 25.78,59.51 25.78,64.72 27.18,66.11 27.18,71.9 25.4,73.68 25.4,77.95 25.04,78.31 v1(25.04,80.85)
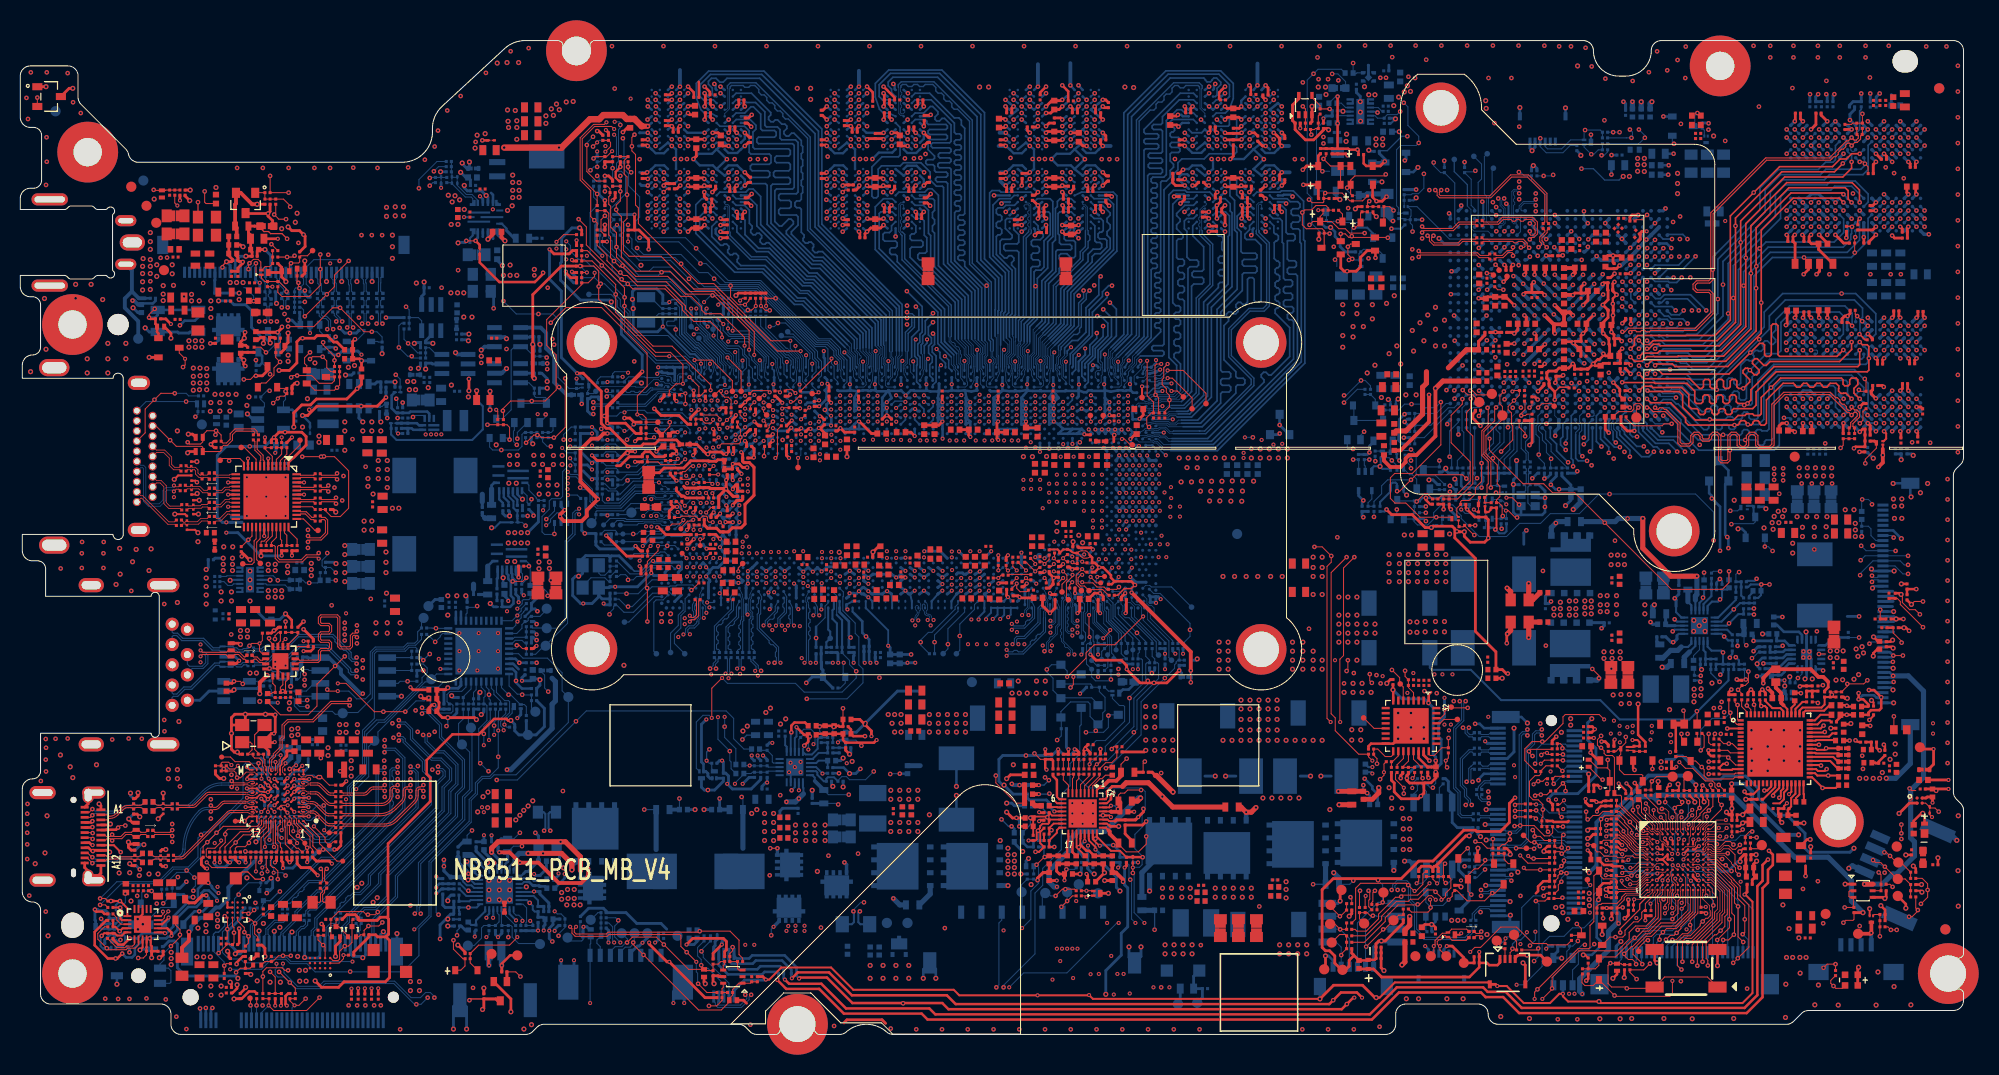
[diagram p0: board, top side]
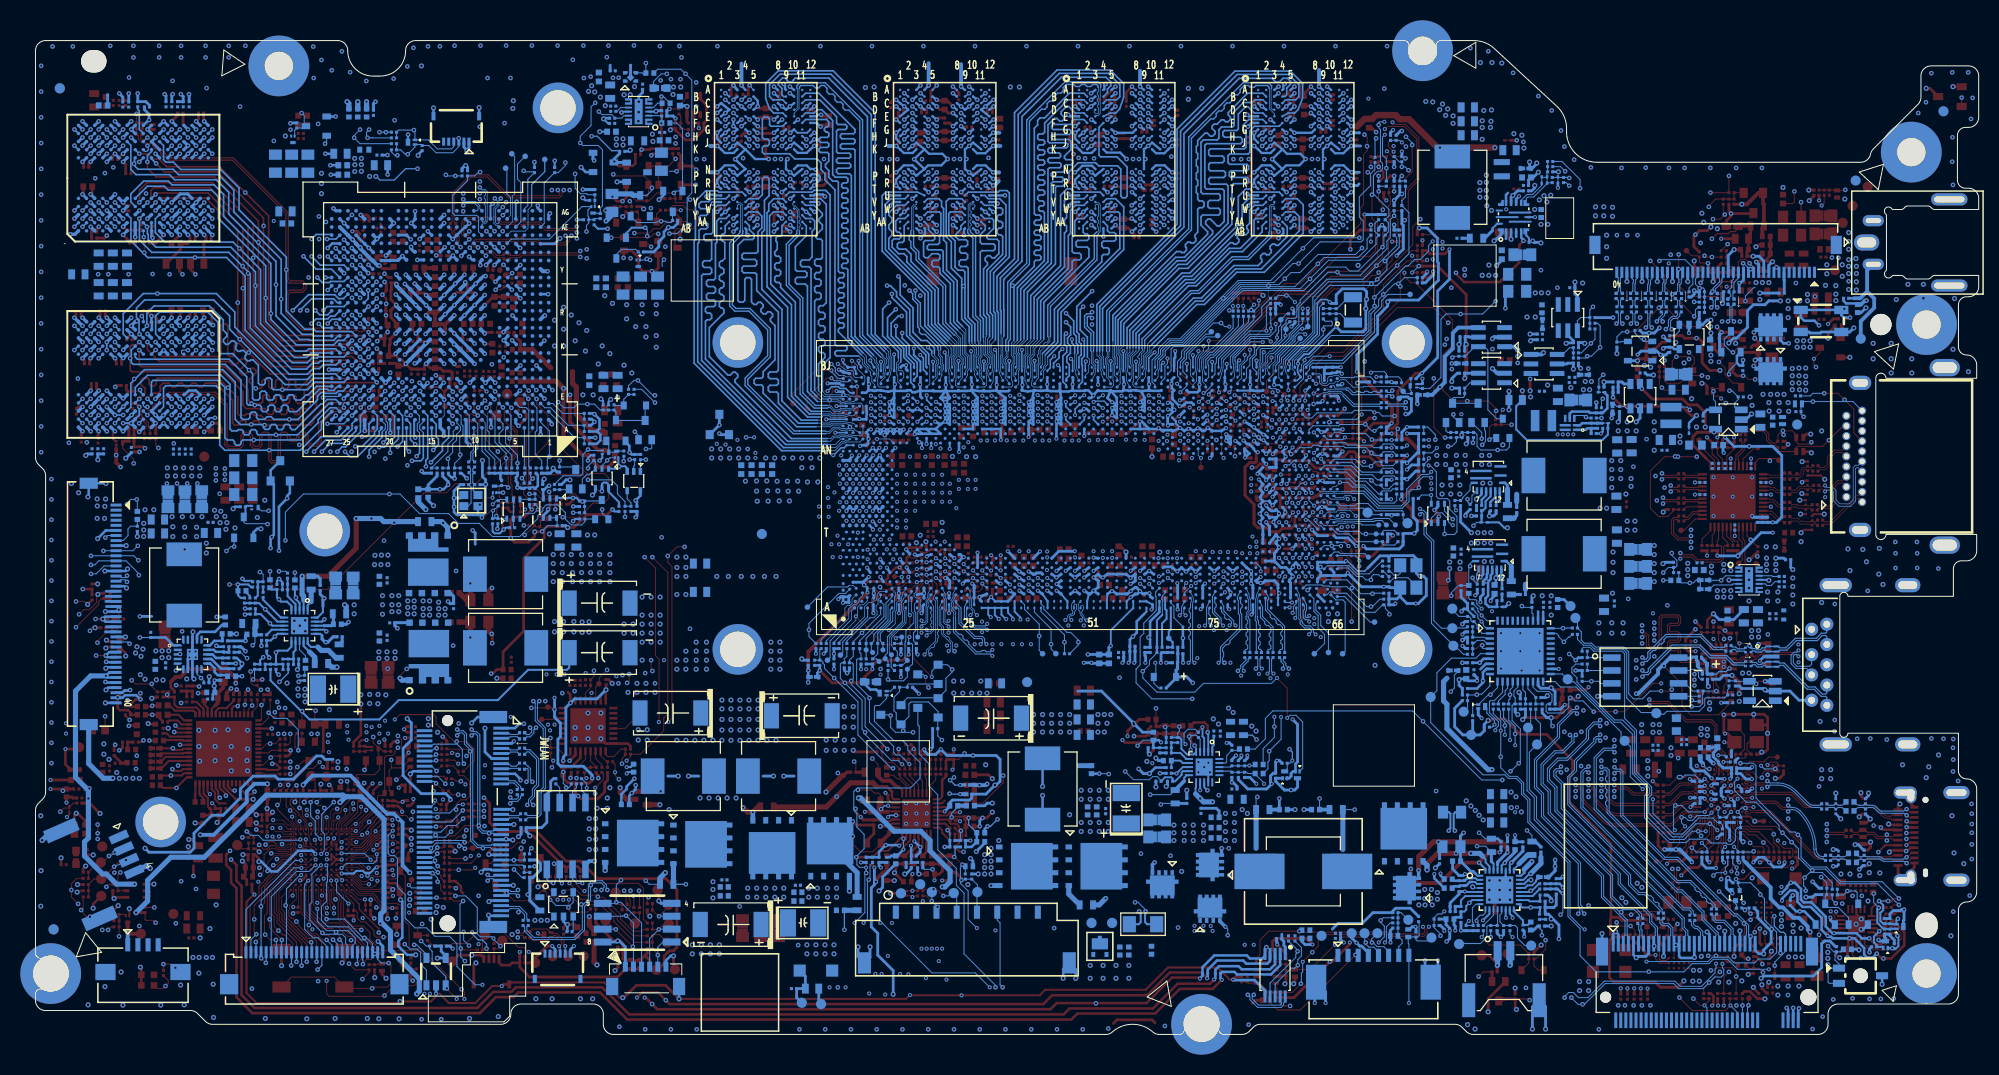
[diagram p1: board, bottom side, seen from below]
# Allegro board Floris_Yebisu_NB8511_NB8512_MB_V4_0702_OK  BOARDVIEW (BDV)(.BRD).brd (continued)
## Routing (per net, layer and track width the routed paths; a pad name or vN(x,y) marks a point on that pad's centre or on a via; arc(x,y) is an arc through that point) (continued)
CAM_PWR_ON_SOC: length 55.6
  TOP w0.102: v1(24.64,84.66) RX902.2 v3(26.46,83)
  ART05 w0.102: v1(24.64,84.66) 38.91,84.66 47.95,93.7 57.76,93.7 59.05,92.4 59.05,87.83 59.56,87.32 59.56,81.86 59.94,81.48 v1(59.94,79.83)
  BOTTOM w0.102: RU132.2 v1(59.94,79.83)
CAM_PWR_ON_SOC_R: length 28.9
  BOTTOM w0.076: 80.68,66.51 80.82,66.36 80.82,65.59 80.93,65.43 80.93,64.88 81.04,64.68 UU1.CC47
  BOTTOM w0.102: 80.68,66.51 80.67,66.51 80.24,66.94 80.24,67.38 79.6,68.02 78.48,68.02 72.77,73.73 67.44,73.73 v3(65.18,75.99) 64.56,76.6 61.21,76.6 60.32,77.49 60.32,78.43 RU132.1
CAM_USB_N_CONN_R: length 3
  BOTTOM w0.102: JX1.17 24.2,74.48 24.36,74.31 24.36,73.68 24.64,73.4 CX898.1 24.64,73.12 24.45,72.94 24.45,72.8 CHKX5.3
CAM_USB_P_CONN_R: length 2.9
  BOTTOM w0.102: JX1.16 23.7,74.57 24.15,74.12 24.15,73.24 CX897.1 24.13,73.17 24.24,73.06 24.24,72.62 CHKX5.4
CATERR_SOC_N: length 7.6
  BOTTOM w0.076: 111.89,39.19 109.9,41.17 109.9,42.16 109.48,42.58 109.23,42.58 108.82,42.79 108.72,42.88 108.58,43.47 108.37,43.68 UU1.J4
  BOTTOM w0.102: 111.89,39.19 112.39,38.68 RU24.2
CFG0: length 1.6
  TOP w0.102: RU233.1 99.37,44.83 v2(99.19,45.01) 98.83,44.65 RU194.2
  BOTTOM w0.076: UU1.AG6 99.02,44.9 v2(99.19,45.01)
CFG1: length 2.6
  TOP w0.102: RU234.1 100.49,46.05 v2(100.1,45.66) 99.21,46.56 RU195.2
  BOTTOM w0.076: v2(100.1,45.66) 99.93,45.55 UU1.AE7
CFG2: length 1.7
  TOP w0.102: RU203.2 98.42,46.52 v2(99.19,45.76)
  BOTTOM w0.076: v2(99.19,45.76) 99.19,45.75 99.17,45.64 UU1.AG7
CFG3: length 2.2
  TOP w0.102: RU240.1 101.47,46.84 v2(101.02,46.38) 100.8,46.61 RU196.2
  BOTTOM w0.076: UU1.AD9 100.59,46.12 v2(101.02,46.38)
CFG4: length 1.3
  TOP w0.102: v2(100.1,46.38) 100.1,46.48 RU204.2
  BOTTOM w0.076: v2(100.1,46.38) 100.08,46.29 UU1.AE9
CFG5: length 1.1
  TOP w0.102: RU197.2 101.7,46.15 v2(101.93,46.38)
  BOTTOM w0.076: UU1.AB9 101.5,46.12 v2(101.93,46.38)
CFG6: length 1.2
  TOP w0.102: v2(98.27,45.01) 97.79,44.52 RU205.2
  BOTTOM w0.076: v2(98.27,45.01) 98.1,44.9 UU1.AJ6
CFG7: length 1
  TOP w0.102: v2(101.93,45.66) 102,45.59 RU200.2
  BOTTOM w0.076: v2(101.93,45.66) 101.76,45.55 UU1.AB7
CFG8: length 1.5
  TOP w0.102: v2(103.77,46.57) 103.91,46.43 RU206.2 RU235.1
  BOTTOM w0.102: v2(103.77,46.57) 103.76,46.57 103.72,46.55 UU1.V10
CFG9: length 3.2
  TOP w0.102: RU201.2 97.79,43.97 v2(98.27,44.46) 98.27,43.99 98.6,43.66 99.26,43.66 RU236.1
  BOTTOM w0.076: v2(98.27,44.46) 98.28,44.45 98.25,44.34 UU1.AJ5
CFG10: length 1.7
  TOP w0.102: RU237.1 103.21,47.32 v2(102.85,46.96) 103.2,46.61 RU198.2
  BOTTOM w0.076: v2(102.85,46.96) 102.68,46.85 UU1.Y10
CFG11: length 1.6
  TOP w0.102: RU207.2 97.89,46.14 v2(98.27,45.76)
  BOTTOM w0.076: v2(98.27,45.76) 98.28,45.75 98.25,45.64 UU1.AJ7
CFG12: length 1.7
  TOP w0.102: RU199.2 102.23,46.66 v2(101.93,46.96) 102,47.03 RU238.1
  BOTTOM w0.076: v2(101.93,46.96) 101.76,46.85 UU1.AB10
CFG13: length 1.7
  TOP w0.102: RU208.2 v2(96.46,45.01) 96.74,45.29 RU239.1
  BOTTOM w0.102: UU1.AL7 v2(96.46,45.01)
CFG14: length 1
  TOP w0.102: RU202.2 v2(96.46,45.76)
  BOTTOM w0.102: UU1.AL9 96.57,45.75 v2(96.46,45.76)
CFG15: length 1.1
  TOP w0.102: v2(97.41,45.74) 97.23,45.92 RU209.2
  BOTTOM w0.102: UU1.AJ9 97.49,45.74 v2(97.41,45.74)
CFG_RCOMP: length 1.1
  TOP w0.102: RU210.2 101.19,44.83 v2(101.02,45.01)
  BOTTOM w0.076: v2(101.02,45.01) 100.85,44.9 UU1.AD6
CHG_ACN: length 3
  BOTTOM w0.191: 49.89,15.41 49.62,15.41 49.46,15.25 PU101.2
  BOTTOM w0.254: PR108.1 51.78,15.16 PC127.2 50.73,15.16 PC121.2 50.67,15.19 50.45,15.41 49.89,15.41
CHG_ACOK: length 129.6
  TOP w0.076: UE1.E1 160.28,18.44 159.51,18.44
  TOP w0.102: 159.51,18.44 159.1,18.84 159.1,18.92 158.11,19.91 v2(158.11,20.04) 158.11,20.17 157.55,20.72 RE139.2
  ART03 w0.089: v4(49.91,14.55) 49.91,14.32 52.09,12.14 v2(52.7,12.14)
  ART06 w0.102: v1(53.08,9.73) 53.72,9.73 53.85,9.6 56.74,9.6 56.94,9.8 72.82,9.8 73.43,9.19 82.29,9.19 82.95,9.85 89.75,9.85 90.77,10.87 105.33,10.87 109.32,6.88 131.33,6.88 132.7,8.25 141.02,8.25 141.46,8.7 147.1,8.7 147.67,9.27 148.13,9.27 148.46,8.94 151.61,8.94 153.8,11.12 153.8,13.97 154.18,14.35 155.75,14.35 156.31,14.91 156.67,14.91 157.53,15.77 157.53,18.72 158.11,19.3 v2(158.11,20.04)
  BOTTOM w0.102: v4(49.91,14.55) 49.81,14.45 PU101.4 ; v2(52.7,12.14) 52.96,11.88 53.34,11.88 53.72,11.5 PR131.1 PR138.2 53.72,10.54 53.08,9.9 v1(53.08,9.73)
CHG_ACP: length 3.1
  BOTTOM w0.191: PU101.3 49.49,14.85 49.69,15.04 49.93,15.04
  BOTTOM w0.254: PR107.1 51.75,14.6 PC117.2 51.17,14.68 PC121.1 50.54,14.68 50.18,15.04 49.93,15.04
CHG_BATDRV#: length 2.5
  BOTTOM w0.191: PU101.21 44.76,14.45 44.5,14.7 44.04,14.7 43.66,15.09 43.66,15.19 PR164.1
CHG_BATDRV#_R: length 43.6
  ART05 w0.508: v1(81.28,16.96) 81.02,17.22 50.93,17.22 50.01,16.3 45.62,16.3 45.49,16.43 42.57,16.43 v1(41.78,17.22)
  BOTTOM w0.305: v1(41.78,17.22) v3(41.78,16.58) 41.78,16.13 42.39,15.52 PR164.2
  BOTTOM w0.343: PQ101.4 81.49,16.75 v1(81.28,16.96)
CHG_BTST1: length 3.6
  BOTTOM w0.102: PR128.2 48.65,18.56 v3(49.48,18.56)
  BOTTOM w0.191: PU101.30 47.85,16.84 48,16.99
  BOTTOM w0.305: PR128.2 48.06,17.05 48,16.99
CHG_BTST1_R: length 2.5
  BOTTOM w0.102: PR128.1 48.69,19.3 v3(49.27,19.89)
  BOTTOM w0.254: 47.12,19 47.42,19.3 PR128.1
CHG_BTST2: length 2.5
  BOTTOM w0.191: PU101.25 45.85,16.28 45.34,16.79
  BOTTOM w0.305: 45.34,16.79 45.34,16.84
  BOTTOM w0.508: PR125.1 44.47,17.7 45.34,16.84
CHG_BTST2_R: length 2.4
  BOTTOM w0.102: v3(44.55,20.11) 44.07,19.63 PR125.2
  BOTTOM w0.305: PR125.2 43.71,19.02 PC123.1
CHG_CELL_BATPRES: length 2.7
  BOTTOM w0.191: PR120.1 PR117.2 44.3,13.13 44.41,13.25 PU101.18
CHG_COMP1: length 2.8
  BOTTOM w0.203: PR115.2 44.47,10.79 PC154.1 44.94,11.24 45.85,12.14 PU101.16
CHG_COMP1_R: length 2
  BOTTOM w0.127: PC113.2 43.32,10.48 43.08,10.23 v3(43.08,9.78)
  BOTTOM w0.279: PC113.2 43.48,10.69 43.88,10.3 PR115.1
CHG_COMP2: length 2.9
  BOTTOM w0.191: PU101.17 45.02,12.52 v3(44.19,12.52) PC114.1 43.27,12.18 43.32,12.13 PR116.2
CHG_COMP2_R: length 0.6
  BOTTOM w0.191: PR116.1 PC115.1
CHG_HG1: length 9.3
  TOP w0.508: v4(54.4,16.23) 54.4,16.84 53.39,17.85 v3(51.56,17.85) v4(50.09,17.85)
  BOTTOM w0.191: 48.92,17.57 48.64,17.28 48.64,16.96 48.25,16.58 PU101.31
  BOTTOM w0.508: PQ103.4 54.4,16.68 v4(54.4,16.23) ; v4(50.09,17.85) 49.21,17.85 48.92,17.57
CHG_HIDRV2: length 34.9
  TOP w0.102: v1(74.67,18.36) v3(73.97,18.36)
  ART05 w0.508: v1(44.07,17.04) 45.77,18.74 53.85,18.74 54.23,18.36 v1(74.67,18.36)
  BOTTOM w0.191: PU101.24 45.13,15.65 44.83,15.95
  BOTTOM w0.305: 44.83,16.28 44.83,15.95
  BOTTOM w0.33: PQ107.4 v1(74.67,18.36)
  BOTTOM w0.508: v1(44.07,17.04) 44.83,16.28
CHG_IADPT: length 143.5
  TOP w0.076: UE1.G12 166.22,17.49 167.44,17.49 167.64,17.29 v1(167.84,17.29)
  ART03 w0.089: v1(167.84,17.29) 167.64,17.09 167.64,15.31 168.4,14.55 168.4,9.09 166.88,7.57 166.88,6.55 165.12,4.8 156.93,4.8 155.42,6.3 153.27,6.3 152.7,5.73 149.93,5.73 149.25,5.05 148.22,5.05 147.51,4.34 145.59,4.34 144.84,5.09 135.85,5.09 133.73,2.97 114.2,2.97 v1(112.52,4.65)
  ART06 w0.102: v2(50.29,11.2) 50.04,10.94 50.04,9.73 52.07,7.69 61.72,7.69 62.51,8.48 82.61,8.48 83.14,9.01 105.36,9.01 107.9,6.47 110.69,6.47 v1(112.52,4.65)
  BOTTOM w0.102: PU101.8 49.58,12.85 49.93,12.49 49.93,11.1 49.87,11.03 PR121.2 PC112.1 50.56,10.93 v2(50.29,11.2)
CHG_IBAT: length 143.4
  TOP w0.102: v3(168.77,16.12) v1(168.2,16.69) 168.15,16.74 167.84,16.74 167.33,17.24 UE1.G13
  ART03 w0.089: v2(111.76,4.65) 113.64,2.77 133.8,2.77 135.93,4.9 144.74,4.9 145.51,4.13 147.69,4.13 148.41,4.85 149.32,4.85 150.01,5.53 152.78,5.53 153.35,6.11 155.35,6.11 156.85,4.61 166.08,4.61 168.02,6.55 168.02,8.07 168.65,8.71 168.65,14.68 168.2,15.14 v1(168.2,16.69)
  ART06 w0.102: v2(111.76,4.65) 111,5.41 105.51,5.41 102.87,8.05 101.75,8.05 100.99,8.81 83.22,8.81 82.67,8.25 62.91,8.25 61.59,6.93 52.27,6.93 49.53,9.67 v2(49.53,11.2)
  BOTTOM w0.102: PU101.9 48.65,12 48.89,11.76 49.17,11.76 49.53,11.4 v2(49.53,11.2) 49.53,11.12 49.36,10.96 PC118.1
CHG_ILIM_HIZ: length 3.8
  BOTTOM w0.191: PU101.6 50.64,13.65 51.06,13.22 PR111.1
  BOTTOM w0.279: PC133.1 PR112.2 PR111.1
CHG_LG1: length 14.9
  TOP w0.508: v1(55.24,16.18) 55.24,17.53 53.77,19 v3(53.29,19) 47.12,19 46.48,18.36 v2(46.48,17.96)
  BOTTOM w0.191: PU101.29 47.45,16.71
  BOTTOM w0.305: PC129.1 v2(46.48,17.96) 47.45,16.98 47.45,16.71
  BOTTOM w0.343: PQ105.4 v1(55.24,16.18)
CHG_LODRV2: length 38.1
  ART03 w0.381: v1(46.1,16.94) 46.1,17.12 46.43,17.45 47.19,17.45 47.29,17.35
  ART03 w0.508: v2(74.29,10.61) 73.61,11.3 57.05,11.3 55.78,10.03 53.92,10.03 52.7,11.25 52.2,11.25 49.3,14.15 49.3,15.97 47.93,17.35 47.29,17.35
  BOTTOM w0.102: v2(74.29,10.61) 74.06,10.39 v3(74.06,9.78)
  BOTTOM w0.203: v1(46.1,16.94) 46.25,16.79 PU101.26
  BOTTOM w0.305: v1(46.1,16.94) 44.96,18.08 PC120.2
  BOTTOM w0.343: v2(74.29,10.61) 74.84,11.16 PQ108.4
CHG_MOD1_P1: length 196
  TOP w0.076: 168.16,18.63 168.03,18.63 167.62,18.21 167.04,18.21 166.76,18.49 166.36,18.49 166.23,18.36 166.23,18.13 166.1,18.01 166.07,18.01 165.84,18 165.76,18.08 165.35,18.08 165.28,18.01 165.23,18.01 UE1.F10
  TOP w0.102: 168.16,18.63 168.49,18.63 168.86,18.26 169.16,18.26 v1(169.59,18.69) ; UB6.6 25.9,38.73 v2(26.16,38.99)
  ART03 w0.089: v2(101.8,5.41) 102.52,4.69 109.68,4.69 112.14,2.23 133.83,2.23 136.12,4.52 144.59,4.52 145.35,3.75 147.92,3.75 148.64,4.47 149.48,4.47 150.16,5.15 152.93,5.15 153.51,5.73 155.19,5.73 156.69,4.23 166.97,4.23 168.53,5.79 168.53,7.31 169.16,7.95 169.16,14.71 168.78,15.09 168.78,16.02 169.16,16.41 169.16,18.26 v1(169.59,18.69)
  ART05 w0.102: v2(26.16,38.99) 26.16,38.49 29.69,34.96 29.69,22.71 31.88,20.52 31.88,15.95 31.49,15.57 31.49,12.09 35.36,8.23 38.96,8.23 42,5.18 48.48,5.18 48.73,4.93 64.1,4.93 65.52,6.34 67.05,6.34 67.9,7.19 80.82,7.19 81.91,6.09 101.03,6.09 101.72,5.41 v2(101.8,5.41)
CHG_MOD2_P1: length 176.9
  TOP w0.102: v2(156.42,19.53) 156.44,19.53 156.57,19.66 RE98.1 ; UB6.7 25.4,38.56 25.65,38.81 RB52.1 25.45,39.65 25.12,39.32 v1(25.12,38.99)
  ART03 w0.089: v2(149.43,10.13) 149.43,11.12 151.33,13.03 152.7,13.03 152.96,13.28 152.96,13.99 154.23,15.26 156.63,15.26 156.92,15.56 156.92,18.92 156.42,19.42 v2(156.42,19.53)
  ART05 w0.102: v1(25.12,38.99) 25.38,38.99 29.49,34.88 29.49,22.53 31.62,20.39 31.62,16.08 31.24,15.69 31.24,12.02 35.24,8.02 38.84,8.02 41.88,4.98 48.4,4.98 48.68,4.7 64.16,4.7 65.61,6.14 67.17,6.14 68.02,6.98 80.69,6.98 82.6,5.08 92,5.08 92.45,5.53 100.89,5.53 101.65,4.77 109.72,4.77 110.66,3.83 114.49,3.83 116.82,6.17 129.86,6.17 131.38,7.69 141.75,7.69 142.28,7.16 147.29,7.16 149.43,9.29 v2(149.43,10.13)
  BOTTOM w0.102: v3(148.89,8.76) 149.43,9.29 v2(149.43,10.13)
CHG_MOD3_P1: length 194.9
  TOP w0.076: UE1.E13 166.69,18.24 166.9,18.03 167.69,18.03 167.97,18.31 168.52,18.31
  TOP w0.102: UB6.8 24.9,38.49 24.53,38.86 v1(24.53,39.06) ; v1(169.57,16.43) 169.11,16.89 169.11,17.72 168.52,18.31
  ART03 w0.089: v2(109.42,4.04) 109.47,3.99 109.88,3.99 112.01,1.85 133.73,1.85 136.21,4.33 144.51,4.33 145.28,3.56 148,3.56 148.72,4.28 149.56,4.28 150.21,4.93 155.72,4.93 156.61,4.04 167.16,4.04 169.42,6.3 169.42,14.72 169.04,15.11 169.04,15.9 v1(169.57,16.43)
  ART05 w0.102: v1(24.53,39.06) 24.74,38.86 24.74,38.66 27.43,35.96 27.43,34.27 27.77,33.93 28.4,33.93 29.26,33.08 29.26,22.37 31.37,20.27 31.37,16.2 30.99,15.82 30.99,11.98 35.14,7.82 38.72,7.82 42.37,4.16 63.92,4.16 65.69,5.93 67.29,5.93 68.14,6.78 80.57,6.78 82.51,4.85 92.06,4.85 92.54,5.33 100.8,5.33 101.56,4.57 108.89,4.57 v2(109.42,4.04)
CHG_PROCHOT#: length 2
  BOTTOM w0.102: PU101.11 47.85,11.75 PR162.2
CHG_PSYS: length 73.9
  TOP w0.102: PC607.2 100.61,27.12 v3(100.02,27.71)
  TOP w0.254: PR660.1 101.85,27 PR631.2 PC607.2 101.09,26.24 v2(101.22,26.11)
  ART03 w0.203: v2(101.22,26.11) 101.09,25.98 101.09,15.19 96.39,10.49 v1(91.18,10.49)
  ART06 w0.203: v1(91.18,10.49) 90.3,9.6 83.06,9.6 82.4,8.94 73.32,8.94 72.71,9.55 57.35,9.55 57.02,9.22 51.31,9.22 50.54,9.98 50.54,10.36 50.8,10.61 50.8,11.4 50.59,11.61 49.25,11.61 v2(48.89,11.25)
  BOTTOM w0.203: v2(48.89,11.25) 48.25,11.89 PU101.10
CHG_REGN: length 15.3
  ART03 w0.191: v2(52.17,10.23) 52.17,10.39 48.77,13.79 48.77,15.82 47.75,16.84 46.81,16.84 v1(46.73,16.91)
  BOTTOM w0.203: v1(46.73,16.91) 46.78,16.91 47.05,16.65 PU101.28
  BOTTOM w0.279: v3(52.47,9.17) 52.17,9.47 v2(52.17,10.23) 52.17,10.46 52.54,10.83 PR110.1 PR131.2
  BOTTOM w0.305: PC111.1 45.73,17.99 46.73,16.99 v1(46.73,16.91)
CHG_SCL: length 6
  BOTTOM w0.102: PTP109.1 44.75,8.76 45.49,9.5 45.49,10.51 45.72,10.74 PR161.2 PC141.1 47.22,11.1 47.22,11.78 47.05,11.95 PU101.13
CHG_SDA: length 6.7
  BOTTOM w0.102: PU101.12 47.45,10.79 PC142.1 PR130.2 48.39,10.74 48.51,10.61 48.51,9.6 49.15,8.96 51.2,8.96 PTP104.1
CHG_SNB1: length 2.1
  BOTTOM w0.102: PC130.1 v3(65.01,23.26)
  BOTTOM w0.381: PC130.1 PR160.1
CHG_SNB2: length 2.1
  BOTTOM w0.279: PC134.1 v3(68.97,23.26)
  BOTTOM w0.381: PC134.1 PR105.1
CHG_SRN: length 2.3
  BOTTOM w0.191: PU101.19 43.99,13.65 PR122.2
CHG_SRN_R: length 52
  ART05 w0.203: v1(82.8,12.14) 82.8,12.24 82.27,12.77 81.79,12.77 80.64,11.63 57.41,11.63 55.05,9.27 50.49,9.27 49.29,10.46 44.98,10.46 43.07,12.37 41.55,12.37 41.02,12.9 v2(41.02,13.92)
  BOTTOM w0.102: v2(41.02,13.92) 41.02,12.04 v3(41.25,11.81)
  BOTTOM w0.203: v1(82.8,12.14) 82.65,11.99 82.65,11.07 82.85,10.87 PR165.4
  BOTTOM w0.254: PR122.1 PC102.2 PC104.1 41.53,14.35 41.1,13.92 v2(41.02,13.92)
CHG_SRP: length 2.4
  BOTTOM w0.191: PR123.2 43.38,14.86 44.07,14.17 v3(44.19,14.17) 44.32,14.05 PU101.20
CHG_SRP_R: length 51.8
  ART05 w0.203: v1(82.17,12.14) 81.79,12.14 80.92,11.28 57.55,11.28 55.19,8.91 50.34,8.91 49.15,10.11 44.83,10.11 42.92,12.01 41.4,12.01 40.51,12.9 40.51,14.17 40.82,14.48 v2(41.02,14.48)
  BOTTOM w0.102: v3(83.21,13.03) 82.9,13.03 82.17,12.29 v1(82.17,12.14)
  BOTTOM w0.203: PR165.3 82.01,10.87 82.22,11.07 82.22,12.09 v1(82.17,12.14)
  BOTTOM w0.254: v2(41.02,14.48) 41.02,14.55 41.32,14.86 PC103.1 PC102.1 PR123.1
CHG_SW1: length 17.8
  TOP w0.381: v1(56.01,16.33) 56.01,15.62 55.32,14.93 53.11,14.93 51.1,16.94 v1(49.27,16.94) 48.26,17.96 v2(47.24,17.96)
  BOTTOM w0.102: PR160.2 v3(61.54,22.17)
  BOTTOM w0.203: v1(49.27,16.94) 48.65,16.32 PU101.32
  BOTTOM w0.305: PC131.1 47.12,18.08 v2(47.24,17.96)
  BOTTOM w0.508: PR160.2 62.71,18.23
CHG_SW2: length 39.5
  ART05 w0.381: v1(44.19,15.85) 44.22,15.82 44.45,15.82 44.52,15.75 49.86,15.75 50.67,14.93 56.01,14.93 56.77,15.69 v1(73.91,15.69)
  BOTTOM w0.102: v3(71.14,23.42) 71.27,23.29 PR105.2
  BOTTOM w0.191: v1(44.19,15.85) 44.22,15.82 44.32,15.82 44.89,15.25 PU101.23
  BOTTOM w0.305: PC123.2 43.18,17.47
  BOTTOM w0.508: PR105.2 71.27,18.36 ; 43.18,17.47 43.18,16.86 v1(44.19,15.85)
CHG_VBUS: length 5.5
  BOTTOM w0.191: 49.62,15.84 49.43,15.65 PU101.1
  BOTTOM w0.279: 49.62,15.84 49.85,16.08 50.09,16.08 PC128.1 51.12,17.11 PR126.1 51.12,19.57 v3(50.8,19.89)
CHG_VDDA: length 17.7
  ART05 w0.279: v4(42.16,13.19) 43.15,13.19 45.44,10.89 47.78,10.89 48.64,11.76 50.54,11.76 51.62,10.68 v2(51.62,10.25)
  BOTTOM w0.191: PU101.7 49.97,13.25 v3(50.24,12.98) 50.54,12.67 50.54,12.3 50.73,12.11 PR111.2
  BOTTOM w0.279: v4(42.16,13.19) 42.16,13.42 42.49,13.74 PR120.2 ; PR111.2 PC119.1 51.57,11.55 PR110.2 51.75,10.81 51.62,10.68 v2(51.62,10.25)
CLK_REQ_GPU_N: length 13.7
  BOTTOM w0.102: RV12.2 RV9.1 136.45,80.45 RV13.1 ; RV12.2 137.09,80.63 137.16,80.7 137.16,81.3 QV1.2 137.74,81.63 140.94,78.43 144.72,78.43 UV2.AC6 ; RV12.2 137.09,80 137.31,79.78 v3(137.31,79.17)
CLNK_CLK_CONN: length 5
  TOP w0.102: RW62.2 149.3,21.46 v1(149.48,21.28)
  BOTTOM w0.102: JW1.42 151.67,19.95 151.03,20.6 150.16,20.6 v1(149.48,21.28)
CLNK_CLK_SOC: length 117.3
  TOP w0.102: v1(147.42,21.46) RW62.1
  ART03 w0.089: v1(147.42,21.46) 146.76,22.12 146.76,24.05 144.5,26.31 141.5,26.31 141.07,25.88 135.79,25.88 133.09,28.58 133.09,28.93 132.54,29.49 130.45,29.49 130.38,29.41 115.66,29.41 114.67,28.42 110.36,28.42 110.26,28.52 95.2,28.52 94.94,28.78 85.06,28.78 84.85,28.57 82.75,28.57 81.66,29.66 77.54,29.66 75.94,28.06 73.76,28.06 73.58,28.24 65.38,28.24 61.71,31.91 61.71,38.47 61.23,38.95 61.23,41.02 61.73,41.52 61.73,45.54 61.94,45.76 61.94,46.91 62.36,47.32 62.61,47.32 63.5,48.21 63.5,50.37 v2(62.74,51.13)
  BOTTOM w0.076: v2(62.74,51.13) 62.97,50.89 63.29,50.89 arc(63.4,50.91) 63.5,50.97 63.67,51.14 UU1.DV19
CLNK_DATA_CONN: length 1.7
  TOP w0.102: RW61.2 v1(152.14,20.5)
  BOTTOM w0.102: JW1.40 152.19,20.45 v1(152.14,20.5)
CLNK_DATA_SOC: length 122
  TOP w0.102: RW61.1 151.13,19.89 150.82,19.58 150.32,19.58 149.3,20.6 v3(147.93,20.6) 147.42,20.6 v1(147.37,20.55)
  ART03 w0.089: v2(62.2,51.13) 62.23,51.1 62.23,51.05 62.66,50.62 62.86,50.62 63.24,50.24 63.24,49.35 62.51,48.61 62.51,47.85 61.73,47.07 61.73,45.86 61.54,45.67 61.54,41.64 61.04,41.14 61.04,38.86 61.52,38.37 61.52,31.74 65.21,28.05 73.49,28.05 73.73,27.81 76.25,27.81 77.85,29.41 81.53,29.41 82.56,28.38 84.93,28.38 85.14,28.59 94.83,28.59 95.25,28.17 100.43,28.17 100.84,27.76 110.13,27.76 110.32,27.57 114.22,27.57 115.22,28.57 132.83,28.57 135.73,25.68 141.17,25.68 141.59,26.1 144.41,26.1 146.54,23.96 146.54,21.68 146.96,21.26 146.96,20.95 v1(147.37,20.55)
  BOTTOM w0.076: v2(62.2,51.13) 62.23,51.15 62.23,51.2 62.51,51.48 62.92,51.48 UU1.DW19
CLNK_RESET_CONN: length 4.8
  TOP w0.102: RW60.2 148.97,22.1 v1(149.5,22.1)
  BOTTOM w0.102: JW1.38 150.65,20.95 v1(149.5,22.1)
CLNK_RESET_SOC: length 111.3
  TOP w0.102: RW60.1 147.45,22.07 v1(147.42,22.04) ; v1(133.09,35.53) 133.09,34.87 v3(133.3,34.67)
  ART05 w0.102: v2(64.84,51.51) 64.92,51.43 64.92,50.31 65.15,50.09 65.15,44.78 66.04,43.89 69.19,43.89 69.34,43.74 69.34,42.9 71.52,40.71 71.93,40.71 73.15,39.49 81.13,39.49 81.79,40.15 87.22,40.15 87.81,39.57 91.41,39.57 91.92,40.08 96.57,40.08 97.22,40.73 97.52,40.73 97.97,41.17 98.45,41.17 98.75,40.87 100.94,40.87 101.24,41.17 104.7,41.17 105.1,40.76 106.47,40.76 106.88,41.17 110.23,41.17 110.82,40.59 115.44,40.59 117.52,42.67 126.03,42.67 129.64,39.06 129.64,37.56 130.91,36.29 132.33,36.29 v1(133.09,35.53)
  ART06 w0.102: v1(147.42,22.04) 146.76,22.71 146.76,24.36 146.15,24.97 146.15,29.13 143.76,31.52 140.61,31.52 138.94,33.2 138.94,34.06 137.97,35.02 137.97,35.74 137.72,35.99 133.55,35.99 v1(133.09,35.53)
  BOTTOM w0.076: UU1.DT19 64.92,51.5 v2(64.84,51.51)
CNV_BRI_DT: length 131.2
  TOP w0.102: v2(68.83,55.22) 68.81,55.19 RU75.2 ; v1(152.02,21.44) 151.76,21.69 151.76,22.02 RW56.2
  ART03 w0.089: v2(68.83,55.22) 68.25,55.22 66.9,53.87 65.02,53.87 64.39,53.24 64.39,51.33 64.77,50.95 64.77,47.95 63.7,46.89 63.7,40.36 63.27,39.93 63.27,33.07 66.49,29.84 70.05,29.84 71.07,30.86 72.03,30.86 72.39,30.5 74.22,30.5 75.49,31.77 84.83,31.77 85.04,31.98 93.57,31.98 95.12,30.43 95.58,30.43 95.91,30.1 108.96,30.1 110.64,31.77 115.42,31.77 117.1,33.45 125.22,33.45 126.19,32.48 133.14,32.48 134.57,31.06 134.57,29.08 135.94,27.71 144.98,27.71 146.94,25.75 147.7,25.75 148.03,25.42 148.03,24.76 148.69,24.1 149.91,24.1 150.21,23.8 152.14,23.8 152.65,23.29 152.65,22.07 v1(152.02,21.44)
  BOTTOM w0.102: v1(152.02,21.44) 152.04,21.44 152.06,21.45 JW1.36
CNV_BRI_DT_SOC: length 21
  TOP w0.102: RU75.1 68.02,55.7 v2(68.37,56.06)
  ART06 w0.102: v1(53.59,58.65) 53.95,59 54.48,59 55.78,57.71 56.92,57.71 57.17,57.45 59.79,57.45 60.32,57.99 66.13,57.99 66.77,57.35 67.08,57.35 v2(68.37,56.06)
  BOTTOM w0.102: v2(68.37,56.06) 68.27,56.16 67.97,56.16 67.56,56.57 UU1.DL31 ; RU64.1 RU67.2 54.33,59.89 53.59,59.15 v1(53.59,58.65)
CNV_BRI_RSP: length 3.1
  TOP w0.102: v3(152.4,24) 152.4,24.51 v1(152.14,24.76) 151.43,24.05 RW11.2
  BOTTOM w0.102: v1(152.14,24.76) 152.33,24.95 JW1.22
CNV_BRI_RSP_SOC: length 139.5
  TOP w0.102: v1(149.4,23.54) 149.5,23.64 v3(149.96,23.64) 150.57,23.64 RW11.1
  ART03 w0.089: v1(149.4,23.54) 148.72,23.54 144.85,27.4 135.76,27.4 134.21,28.95 134.21,30.83 132.92,32.13 125.73,32.13 125.32,32.53 116.74,32.53 114.96,30.76 110.34,30.76 109.37,29.79 95.76,29.79 95.43,30.12 94.87,30.12 93.88,31.11 85.14,31.11 84.83,31.42 76.47,31.42 74.95,29.89 71.98,29.89 71.55,29.46 66.37,29.46 62.96,32.86 62.96,40.23 62.84,40.36 62.84,44.12 63.45,44.73 63.45,46.89 64.59,48.03 64.59,50.85 64.18,51.25 64.18,53.49 65.43,54.73 67.26,54.73 67.51,54.99 v2(67.51,56.11)
  ART06 w0.102: v2(67.51,56.11) 67.56,56.16 67.56,56.3 67.41,56.46 66.09,56.46 65.96,56.33 64.01,56.33 63.47,56.87 59.74,56.87 59.54,56.66 57.5,56.66 56.69,57.48 55.37,57.48 v2(54.23,58.62)
  BOTTOM w0.102: UU1.DL29 67.35,55.94 v2(67.51,56.11) ; RU79.1 v2(54.23,58.62)
CNV_MFUART2_RXD: length 141.1
  TOP w0.102: RW14.2 150.72,27.61 v2(150.57,27.76) 150.21,27.76 v3(150.01,27.56)
  ART05 w0.102: v2(150.57,27.76) 149.35,28.98 149.35,30.76 148.41,31.7 144.37,31.7 144.22,31.54 139.49,31.54 138.91,32.13 134.26,32.13 134.01,32.38 129.59,32.38 128.83,33.14 127.64,33.14 125.81,34.97 111.07,34.97 110.59,34.49 109.9,34.49 108.66,33.25 102,33.25 101.5,32.74 96.8,32.74 94.56,34.97 72.34,34.97 71.93,35.38 71.93,36.08 71.41,36.6 66.46,36.6 64.08,38.99 64.08,39.62 64.59,40.13 64.59,41.73 63.27,43.05 63.27,48.59 62.81,49.04 62.18,49.04 60.75,50.47 60.75,55.78 60.26,56.27 60.26,61.86 60.96,62.56 60.96,63.35 62.33,64.72 63.22,64.72 65.63,67.13 67.21,67.13 68.76,68.68 68.76,68.88 68.96,69.09 69.44,69.09 69.62,68.91 69.98,68.91 v2(70.61,68.27)
  BOTTOM w0.076: UU1.CV47 73.43,64.79 73.33,65.78 73.33,66.39 73.35,66.41
  BOTTOM w0.102: v2(70.61,68.27) 70.64,68.3 71.8,68.3 73.35,66.75 73.35,66.41
CNV_MODEM_CLKREQ: length 152
  TOP w0.102: RW13.1 150.32,27.05 v2(149.96,26.69)
  ART05 w0.102: v2(149.96,26.69) 149.58,27.07 148.85,27.07 148.47,27.45 143.91,27.45 142.95,26.49 135.39,26.49 133.51,28.37 131.01,28.37 129.54,29.84 126.48,29.84 125.87,30.45 113.05,30.45 112.14,29.54 110.59,29.54 110.36,29.77 95.78,29.77 93.44,32.1 79.88,32.1 79.5,31.72 74.98,31.72 74.17,30.91 72.9,30.91 71.73,32.08 66.02,32.08 59.82,38.28 59.82,44.78 59,45.59 59,48.48 57.02,50.46 57.02,52.12 56.61,52.52 56.61,53.72 57.1,54.2 57.1,60.88 57.22,61.01 57.22,61.69 58.38,62.85 58.38,65.34 61.67,68.63 64.74,68.63 66.5,70.38 68.22,70.38 68.98,69.62 v2(69.8,69.62)
  BOTTOM w0.076: 74.49,66.31 74.52,66.28 74.52,65.76 74.8,64.65 UU1.CT47
  BOTTOM w0.102: 74.49,66.31 74.49,66.48 71.94,69.03 70,69.03 69.8,69.24 v2(69.8,69.62) 69.8,70.08 69.82,70.1 69.82,71.02 CU169.1 RU139.2
CNV_RF_RESET_N: length 151
  TOP w0.102: v1(149.15,27.45) 148.79,27.81 v3(148.79,27.91) 148.79,28.01 148.89,28.12 151.03,28.12 RW16.2
  ART05 w0.102: v2(70.25,69.39) 70.05,69.19 69.72,69.19 69.57,69.34 68.96,69.34 68.12,70.18 66.67,70.18 64.87,68.37 61.9,68.37 58.7,65.17 58.7,62.86 57.43,61.59 57.43,60.83 57.33,60.73 57.33,50.44 59.21,48.57 59.21,45.69 60.04,44.85 60.04,38.47 66.23,32.28 71.91,32.28 72.97,31.21 74.12,31.21 74.88,31.98 79.35,31.98 79.68,32.31 93.62,32.31 95.91,30.02 110.49,30.02 110.72,29.79 112.06,29.79 112.93,30.66 125.96,30.66 126.57,30.05 129.64,30.05 131.11,28.57 133.65,28.57 134.71,27.51 143.3,27.51 143.53,27.73 148.87,27.73 v1(149.15,27.45)
  BOTTOM w0.076: UU1.CT48 74.83,65.28 74.7,65.78 74.7,66.6
  BOTTOM w0.102: 74.7,66.6 71.93,69.36 70.28,69.36 v2(70.25,69.39) 70.25,71.68 RU140.2
CNV_RF_RST: length 2.7
  TOP w0.102: RW16.1 CW16.2 151.89,28.67 152.09,28.47 v1(152.09,28.22)
  BOTTOM w0.102: v1(152.09,28.22) 152.3,28.22 152.56,27.95 JW1.10
CNV_RGI_DT: length 128.1
  TOP w0.102: RW55.2 151.84,22.68 v2(152.25,23.09) ; v2(66.38,55.09) 66.02,54.73 65.28,54.73 RU74.2
  ART03 w0.089: v2(152.25,23.09) 151.79,22.63 150.57,22.63 150.14,23.06 148.77,23.06 144.8,27.02 141.22,27.02 140.79,26.59 136.15,26.59 133.86,28.89 133.86,30.45 132.54,31.77 125.7,31.77 125.6,31.67 116.43,31.67 114.55,29.79 110.28,29.79 109.95,29.46 95.63,29.46 95.3,29.79 94.44,29.79 93.98,30.25 85.34,30.25 84.63,30.96 76.6,30.96 75.23,29.59 72.57,29.59 72.13,29.16 66.17,29.16 62.63,32.69 62.63,39.75 62.58,39.8 62.58,44.37 63.19,44.98 63.19,46.89 64.39,48.08 64.39,50.67 64.01,51.05 64.01,54.84 64.62,55.45 66.02,55.45 v2(66.38,55.09)
  BOTTOM w0.102: JW1.32 152.63,22.45 152.25,22.83 v2(152.25,23.09)
CNV_RGI_DT_SOC: length 2.7
  TOP w0.102: RU223.1 RU74.1 65.33,55.5 65.58,55.5 66.12,56.03 v2(66.36,56.03)
  BOTTOM w0.102: UU1.DP31 66.05,56.35 v2(66.36,56.03)
CNV_RGI_RSP: length 4.7
  TOP w0.102: v2(149.5,22.68) 149.45,22.73 RW10.2
  BOTTOM w0.102: v2(149.5,22.68) 149.96,22.68 150.8,21.84 152.58,21.84 152.69,21.95 JW1.34
CNV_RGI_RSP_SOC: length 137.8
  TOP w0.102: v1(147.42,22.63) 147.52,22.73 RW10.1
  ART03 w0.089: v2(66.93,56.09) 66.49,55.65 64.46,55.65 63.78,54.96 63.78,50.95 64.13,50.59 64.13,48.21 62.94,47.01 62.94,45.11 62.28,44.45 62.28,39.29 62.33,39.24 62.33,32.38 65.86,28.85 72.46,28.85 72.85,29.23 76.1,29.23 77.26,30.4 84.48,30.4 85.49,29.39 95.2,29.39 95.43,29.16 110.21,29.16 110.54,29.49 114.91,29.49 115.92,30.5 128.22,30.5 129.08,31.37 132.28,31.37 133.5,30.15 133.5,28.8 136.02,26.29 140.92,26.29 141.35,26.72 144.65,26.72 147.83,23.54 147.83,23.04 v1(147.42,22.63)
  ART06 w0.102: v2(54.23,57.99) 55.5,56.72 56.67,56.72 57.07,56.31 58.37,56.31 58.65,56.03 60.83,56.03 61.14,56.33 63.24,56.33 63.6,55.98 65.83,55.98 66.14,55.67 66.52,55.67 v2(66.93,56.09)
  BOTTOM w0.102: RU80.1 v2(54.23,57.99) ; UU1.DN29 66.7,55.85 v2(66.93,56.09)
CNV_WR_CLK_CON_DN: length 2.6
  BOTTOM w0.102: RW28.1 143.8,24.32 143.8,24.45 144.37,25.02 144.93,25.02 145.11,25.2 JW1.21
CNV_WR_CLK_CON_DP: length 2.2
  BOTTOM w0.102: RW29.1 144.02,24.28 144.02,24.36 144.46,24.8 144.97,24.8 145.07,24.7 JW1.23
CNV_WR_CLK_DN: length 189.8
  ART03 w0.102: v1(144.83,22.78) 145.07,23.02 145.19,23.02 145.34,22.88 145.34,22.52 145.2,22.38 145.2,22.03 145.08,21.92 145.08,21.66 145.2,21.55 145.2,21.22 145.08,21.1 145.08,20.9 145.2,20.79 145.2,20.46 145.08,20.34 145.08,20.09 145.2,19.97 145.2,19.64 145.08,19.53 145.08,19.12 145.2,19.01 145.2,18.43 144.84,18.07 144.18,18.07 143.19,17.08 143.19,16.67 142.44,15.92 141.78,15.92 141.21,15.35 141.21,14.79 140.47,14.06 138.95,14.06 137.21,12.32 135.79,12.32 135.24,11.77 134.05,11.77 133.49,11.21 132.24,11.21 130.96,9.93 129.79,9.93 128.71,11.01 111.9,11.01 111.49,10.6 101.53,10.6 98.56,7.63 89.98,7.63 88.68,8.93 81.95,8.93 80.55,7.53 67.6,7.53 67.37,7.76 66.42,7.76 65.45,6.78 48.66,6.78 47.88,7.57 45.34,7.57 43.53,9.37 43.53,14.04 42.8,14.78 42.8,18.34 45.11,20.65 46.79,20.65 47.6,21.46 47.6,21.92 53.96,28.28 53.96,36.03 53.39,36.6 53.39,40.13 54.58,41.32 54.58,47.65 57.4,50.47 57.4,51.43 57.58,51.61 57.58,52.98 57.91,53.31 58.37,53.31 59.48,54.43 59.48,58.29 61.97,60.78 61.97,62.15 63.41,63.59 65.67,63.59 66.03,63.94 68.21,63.94 68.49,63.66 68.49,62.82 v2(68.17,62.51)
  BOTTOM w0.089: UU1.DK44 68.25,62.97 68.38,62.85 68.38,62.71 v2(68.17,62.51)
  BOTTOM w0.102: v1(144.83,22.78) 144.63,22.98 144.12,22.98 143.81,23.29 143.81,23.47 RW28.2
CNV_WR_CLK_DP: length 190.3
  ART03 w0.102: v2(68.78,62.5) 68.71,62.57 68.71,63.75 68.3,64.16 65.94,64.16 65.58,63.8 63.32,63.8 61.76,62.24 61.76,60.87 59.27,58.38 59.27,54.52 58.28,53.53 57.82,53.53 57.36,53.07 57.36,51.7 57.19,51.52 57.19,50.56 54.37,47.74 54.37,41.41 53.17,40.22 53.17,36.51 53.74,35.94 53.74,28.37 47.38,22.01 47.38,21.55 46.7,20.86 45.02,20.86 42.58,18.43 42.58,14.69 43.32,13.95 43.32,9.28 45.25,7.35 47.79,7.35 48.58,6.56 65.54,6.56 66.51,7.54 67.28,7.54 67.51,7.31 80.64,7.31 82.04,8.71 88.59,8.71 89.89,7.41 98.65,7.41 101.62,10.39 111.58,10.39 111.99,10.79 128.62,10.79 129.7,9.71 131.05,9.71 132.33,11 133.58,11 134.14,11.55 135.33,11.55 135.88,12.1 137.3,12.1 139.04,13.84 140.56,13.84 141.43,14.7 141.43,15.26 141.87,15.71 142.53,15.71 143.41,16.58 143.41,16.99 144.27,17.85 144.93,17.85 145.41,18.34 145.41,22.29 145.55,22.43 145.55,22.97 145.28,23.24 144.96,23.24 v1(144.83,23.37)
  BOTTOM w0.102: RW29.2 144.02,23.53 144.02,23.38 144.21,23.2 144.66,23.2 v1(144.83,23.37) ; UU1.DJ44 v2(68.78,62.5)
CNV_WR_D0_CON_DN: length 2
  BOTTOM w0.102: RW31.1 144.22,26.45 144.74,26.45 144.99,26.7 JW1.15
CNV_WR_D0_CON_DP: length 1.9
  BOTTOM w0.102: RW30.1 144,26.24 144.77,26.24 144.81,26.2 JW1.17
CNV_WR_D1_CON_DN: length 1.9
  BOTTOM w0.102: JW1.9 144.97,28.2 144.82,28.06 144.09,28.06 RW33.1
CNV_WR_D1_CON_DP: length 2
  BOTTOM w0.102: RW32.1 144.14,27.84 144.8,27.84 144.94,27.7 JW1.11
CNV_WR_LANE0_DN: length 189.9
  ART03 w0.102: v1(142.64,24.91) 142.9,24.66 142.9,23.75 143.72,22.92 143.72,21.88 141.16,19.31 141.16,17.03 141.02,16.89 140.46,16.89 140.36,16.99 140.36,18.96 140.13,19.18 139.25,19.18 138.97,18.91 138.97,16.27 138.21,15.5 138.21,14.29 136.92,12.99 135.24,12.99 134.78,12.53 132.6,12.53 131.21,11.15 129.69,11.15 129.13,11.71 111.76,11.71 111.38,12.09 107.08,12.09 106.37,11.38 101.29,11.38 98.37,8.46 90.22,8.46 88.99,9.69 81.06,9.69 79.66,8.29 68.84,8.29 68.68,8.46 66.13,8.46 65.59,7.91 49.11,7.91 48.73,8.29 45.55,8.29 44.19,9.65 44.19,14.45 43.52,15.12 43.52,18.07 45.48,20.03 47.28,20.03 48.26,21 48.26,21.66 54.66,28.06 54.66,36.24 54.05,36.85 54.05,39.77 55.54,41.26 57.19,41.26 58.13,42.2 58.13,47.81 57.4,48.54 57.4,49.45 58.62,50.67 58.62,52.6 60.2,54.18 60.2,56.61 60.45,56.87 61.01,56.87 61.57,57.43 61.57,59.15 63.75,61.34 63.75,62.15 64.41,62.81 65.15,62.81 65.33,62.63 65.86,62.63 66.14,62.91 66.56,62.91 66.66,62.81 66.66,62.61 66.53,62.48 v2(66.43,62.48)
  BOTTOM w0.076: v2(66.43,62.48) 66.47,62.52 66.47,62.79 66.38,62.88 66.38,63.05 66.28,63.15 66.15,63.15 66.05,63.05 UU1.DP44
  BOTTOM w0.102: v1(142.64,24.91) 142.85,25.12 142.85,26.22 143.08,26.45 143.1,26.45 RW31.2
CNV_WR_LANE0_DP: length 190.2
  ART03 w0.102: v1(143.23,24.91) 143.11,24.8 143.11,23.84 143.94,23.01 143.94,21.79 141.37,19.22 141.37,16.94 141.11,16.67 140.37,16.67 140.14,16.9 140.14,18.87 140.04,18.97 139.34,18.97 139.19,18.82 139.19,16.18 138.43,15.42 138.43,14.2 137.01,12.77 135.33,12.77 134.87,12.32 132.69,12.32 131.3,10.93 129.6,10.93 129.04,11.49 111.67,11.49 111.29,11.87 107.17,11.87 106.46,11.16 101.38,11.16 98.46,8.24 90.13,8.24 88.9,9.47 81.15,9.47 79.75,8.07 68.76,8.07 68.59,8.24 66.22,8.24 65.67,7.69 49.02,7.69 48.64,8.07 45.46,8.07 43.98,9.56 43.98,14.36 43.31,15.03 43.31,18.16 45.39,20.24 47.19,20.24 48.04,21.09 48.04,21.75 54.44,28.15 54.44,36.15 53.83,36.76 53.83,39.86 55.45,41.48 57.1,41.48 57.91,42.29 57.91,47.72 57.19,48.45 57.19,49.54 58.41,50.76 58.41,52.69 59.98,54.27 59.98,56.7 60.36,57.08 60.92,57.08 61.35,57.52 61.35,59.24 63.54,61.43 63.54,62.24 64.32,63.03 65.24,63.03 65.42,62.85 65.77,62.85 66.05,63.13 66.65,63.13 66.88,62.9 66.88,62.65 v2(67.01,62.52)
  BOTTOM w0.076: v2(67.01,62.52) 66.7,62.83 UU1.DN44
  BOTTOM w0.102: RW30.2 143.32,26.24 143.17,26.24 143.06,26.13 143.06,25.08 v1(143.23,24.91)
CNV_WR_LANE1_DN: length 190.5
  ART03 w0.076: 65.99,61.95 66.01,61.95 66.04,61.97 69.01,61.97 69.29,62.26 69.29,62.87 69.38,62.95 69.56,62.95 69.65,62.86 v2(69.65,62.45)
  ART03 w0.102: 65.99,61.95 65.78,61.95 65.02,61.19 65.02,60.27 62.67,57.92 62.52,57.92 62.13,57.53 62.13,56.56 60.91,55.34 60.91,53.87 59.26,52.22 59.26,49.32 58.82,48.89 58.82,44.93 59.27,44.49 59.27,43.34 58.9,42.97 58.9,30.07 47.81,18.98 45.58,18.98 44.83,18.23 44.83,11.1 45.46,10.46 45.46,9.47 45.91,9.03 48.87,9.03 49.37,8.53 56.61,8.53 57.9,9.81 72.71,9.81 73.59,8.93 79.03,8.93 80.55,10.45 89.24,10.45 90.51,9.18 98.08,9.18 101,12.1 106.08,12.1 106.77,12.79 111.75,12.79 112.13,12.41 129.32,12.41 129.49,12.57 131.06,12.57 131.77,13.28 133.45,13.28 133.86,13.69 136.45,13.69 136.84,14.08 136.84,15.5 137.86,16.52 137.86,21.74 138.08,21.97 138.66,21.97 138.89,21.74 138.89,20.61 138.99,20.51 139.38,20.51 139.48,20.61 139.48,21.84 139.71,22.07 140.23,22.07 140.46,21.84 140.46,20.8 140.6,20.66 140.92,20.66 141.12,20.86 141.12,21.55 141.35,21.78 142.45,21.78 142.84,22.16 142.84,22.36 v1(142.56,22.63)
  BOTTOM w0.089: UU1.DG42 69.3,62.37 69.39,62.45 v2(69.65,62.45)
  BOTTOM w0.102: v1(142.56,22.63) 142.68,22.75 142.68,22.76 142.81,22.88 142.81,23.07 142.43,23.45 142.43,24.14 142.02,24.55 142.02,27.21 142.89,28.08 143.25,28.08 RW33.2
CNV_WR_LANE1_DP: length 190.6
  ART03 w0.076: 65.99,62.16 66,62.16 66.03,62.14 68.94,62.14 69.13,62.32 69.13,62.93 69.31,63.12 69.44,63.12 v2(69.64,63.32)
  ART03 w0.102: 65.99,62.16 65.69,62.16 64.81,61.28 64.81,60.36 62.58,58.14 62.43,58.14 61.91,57.62 61.91,56.65 60.69,55.43 60.69,53.96 59.04,52.31 59.04,49.41 58.61,48.98 58.61,44.84 59.05,44.4 59.05,43.43 58.68,43.06 58.68,30.16 47.72,19.2 45.49,19.2 44.61,18.32 44.61,11.01 45.25,10.38 45.25,9.38 45.82,8.81 48.78,8.81 49.28,8.32 56.7,8.32 57.99,9.6 72.62,9.6 73.51,8.71 79.12,8.71 80.64,10.23 89.15,10.23 90.42,8.96 98.17,8.96 101.09,11.88 106.17,11.88 106.86,12.57 111.66,12.57 112.04,12.19 129.41,12.19 129.58,12.35 131.15,12.35 131.86,13.07 133.54,13.07 133.95,13.47 136.54,13.47 137.06,13.99 137.06,15.42 138.07,16.43 138.07,21.65 138.17,21.75 138.57,21.75 138.67,21.65 138.67,20.52 138.9,20.29 139.47,20.29 139.7,20.52 139.7,21.75 139.8,21.85 140.14,21.85 140.24,21.75 140.24,20.71 140.51,20.44 141.01,20.44 141.34,20.77 141.34,21.46 141.44,21.56 142.54,21.56 143.05,22.07 143.05,22.53 v1(143.15,22.63)
  BOTTOM w0.089: v2(69.64,63.32) UU1.DG44
  BOTTOM w0.102: v1(143.15,22.63) 143.03,22.75 143.03,23.16 142.64,23.54 142.64,24.23 142.24,24.64 142.24,27.12 142.97,27.86 143.17,27.86 RW32.2
CNV_WT_CLK_DN: length 3.6
  BOTTOM w0.102: RU71.2 143.2,11.4 143.2,11.9 143.91,12.62 144.98,12.62 145.06,12.7 JW1.71
CNV_WT_CLK_DN_R: length 184.1
  ART03 w0.102: v2(67.57,61.63) 67.68,61.63 67.81,61.49 67.81,61.35 67.71,61.25 66.56,61.25 66.18,60.87 66.18,58.89 65.85,58.56 64.53,58.56 63.69,57.72 63.69,57.11 61.47,54.89 61.47,53.82 59.66,52.02 59.66,49.12 59.23,48.69 59.23,45.36 59.68,44.92 59.68,42.91 59.32,42.56 59.32,37.47 59.98,36.81 59.98,33.79 59.85,33.67 59.55,33.67 59.32,33.44 59.32,32.95 59.55,32.73 59.88,32.73 59.98,32.62 59.98,30.54 48,18.56 46.05,18.56 45.25,17.76 45.25,11.31 46.07,10.49 48.84,10.49 50.37,8.96 56.39,8.96 57.66,10.23 73,10.23 73.9,9.33 78.85,9.33 80.64,11.12 89.15,11.12 90.64,9.64 97.32,9.64 100.2,12.52 105.79,12.52 106.46,13.19 111.92,13.19 112.3,12.81 125.7,12.81 125.93,13.04 125.93,15.15 126.03,15.25 126.43,15.25 126.53,15.15 126.53,13.09 126.79,12.82 127.23,12.82 127.46,13.05 127.46,15.1 127.56,15.2 127.9,15.2 128,15.1 128,13.42 128.24,13.18 128.79,13.18 129.03,13.42 129.03,14.74 129.13,14.84 135.23,14.84 135.33,14.74 135.33,14.32 v1(135.25,14.25)
  BOTTOM w0.102: UU1.DL42 v2(67.57,61.63) ; RU71.1 143.19,10.6 143.19,10.27 142.49,9.57 138.53,9.57 137.72,10.39 137.72,12.72 137.12,13.32 137.12,14.79 136.75,15.16 135.76,15.16 135.35,14.75 135.35,14.34 v1(135.25,14.25)
CNV_WT_CLK_DP: length 3.3
  BOTTOM w0.102: JW1.73 145.05,12.2 144.84,12.41 144,12.41 143.41,11.81 143.41,11.4 RU72.2
CNV_WT_CLK_DP_R: length 184.3
  ART03 w0.102: v2(68.27,61.62) 68.13,61.62 68.03,61.51 68.03,61.26 67.8,61.03 66.65,61.03 66.39,60.78 66.39,58.8 65.94,58.34 64.62,58.34 63.9,57.63 63.9,57.02 61.68,54.8 61.68,53.73 59.88,51.93 59.88,49.03 59.45,48.6 59.45,45.45 59.89,45.01 59.89,42.82 59.54,42.47 59.54,37.56 60.2,36.9 60.2,33.7 59.94,33.45 59.64,33.45 59.54,33.35 59.54,33.04 59.64,32.94 59.97,32.94 60.2,32.71 60.2,30.45 48.09,18.35 46.14,18.35 45.46,17.68 45.46,11.4 46.16,10.7 48.93,10.7 50.46,9.18 56.3,9.18 57.57,10.45 73.09,10.45 73.99,9.55 78.76,9.55 80.55,11.34 89.24,11.34 90.73,9.85 97.23,9.85 100.11,12.74 105.7,12.74 106.37,13.41 112.01,13.41 112.39,13.03 125.61,13.03 125.72,13.13 125.72,15.24 125.94,15.47 126.52,15.47 126.74,15.24 126.74,13.18 126.88,13.04 127.14,13.04 127.24,13.14 127.24,15.19 127.47,15.41 127.99,15.41 128.22,15.19 128.22,13.51 128.33,13.4 128.7,13.4 128.81,13.51 128.81,14.83 129.04,15.06 135.32,15.06 135.55,14.83 135.55,14.54 v1(135.84,14.25)
  BOTTOM w0.102: UU1.DK42 v2(68.27,61.62) ; v1(135.84,14.25) 135.57,14.52 135.57,14.66 135.85,14.95 136.66,14.95 136.9,14.7 136.9,13.23 137.5,12.63 137.5,10.3 138.44,9.36 142.58,9.36 143.41,10.18 143.41,10.59 RU72.1
CNV_WT_LANE0_DN: length 181.4
  ART03 w0.102: v1(57.84,63.48) 58.04,63.28 58.38,63.28 58.63,63.03 58.63,62.7 58.72,62.61 58.72,62.28 58.63,62.19 58.63,61.86 58.72,61.77 58.72,61.44 58.63,61.35 58.63,61.02 58.72,60.93 58.72,60.6 58.63,60.51 58.63,60.18 58.77,60.04 58.77,54.68 58.04,53.95 57.58,53.95 56.58,52.94 56.58,50.71 53.96,48.09 53.96,41.59 52.75,40.38 52.75,36.22 53.2,35.77 53.2,28.48 46.94,22.22 46.94,21.92 46.32,21.3 44.69,21.3 41.27,17.88 41.27,16.81 42.01,16.08 42.01,14.55 42.9,13.66 42.9,10.26 42.26,9.62 42.26,8.71 44.84,6.13 65.95,6.13 66.46,6.64 67.37,6.64 67.63,6.89 80.93,6.89 82.33,8.29 88.43,8.29 89.74,6.98 98.85,6.98 101.85,9.98 111.76,9.98 112.16,10.39 128.17,10.39 129.25,9.31 131.3,9.31 132.58,10.59 133.75,10.59 134.17,11.01 135.6,11.01 135.85,11.26 136.69,11.26 137.2,10.75 137.86,10.75 138.06,10.96 138.06,12.14 138.29,12.37 138.81,12.37 139.04,12.14 139.04,11.61 139.14,11.5 139.39,11.5 139.58,11.69 139.58,12.46 139.9,12.77 141.12,12.77 141.43,13.08 141.43,13.78 141.65,14.01 142.16,14.01 142.39,13.78 142.39,12.74 142.49,12.63 142.9,12.63 143,12.74 143,13.79 143.27,14.06 143.88,14.06 v1(144.06,14.24)
  BOTTOM w0.102: JW1.65 144.88,14.2 144.78,14.09 144.21,14.09 v1(144.06,14.24) ; v1(57.84,63.48) 58.02,63.3 58.27,63.3 RU66.2
CNV_WT_LANE0_DN_R: length 5.7
  BOTTOM w0.076: UU1.DV45 63.77,63.99 63.63,63.99 63.55,63.91 63.55,63.81 63.48,63.73 62.39,63.73 62.37,63.75 62.35,63.75
  BOTTOM w0.102: RU66.1 59.07,63.3 59.31,63.3 59.43,63.42 59.71,63.42 59.83,63.3 60.12,63.3 60.24,63.42 60.52,63.42 60.65,63.3 60.93,63.3 61.05,63.42 61.34,63.42 61.46,63.3 61.7,63.3 62.15,63.75 62.35,63.75
CNV_WT_LANE0_DP: length 181.2
  ART03 w0.102: v1(57.84,62.9) 58.01,63.07 58.29,63.07 RU68.2 58.42,60.07 58.56,59.93 58.56,54.77 57.95,54.16 57.49,54.16 56.36,53.03 56.36,50.8 53.74,48.18 53.74,41.68 52.54,40.47 52.54,36.13 52.98,35.68 52.98,28.57 46.72,22.31 46.72,22.01 46.23,21.51 44.6,21.51 41.06,17.97 41.06,16.72 41.79,15.99 41.79,14.46 42.68,13.57 42.68,10.35 42.05,9.71 42.05,8.62 44.75,5.92 66.04,5.92 66.55,6.42 67.46,6.42 67.71,6.68 81.02,6.68 82.42,8.07 88.34,8.07 89.65,6.77 98.94,6.77 101.94,9.76 111.85,9.76 112.25,10.17 128.08,10.17 129.16,9.09 131.39,9.09 132.67,10.37 133.84,10.37 134.26,10.79 135.68,10.79 135.94,11.05 136.6,11.05 137.11,10.54 137.95,10.54 138.28,10.87 138.28,12.05 138.38,12.15 138.72,12.15 138.82,12.05 138.82,11.52 139.05,11.29 139.48,11.29 139.8,11.61 139.8,12.37 139.99,12.56 141.21,12.56 141.64,12.99 141.64,13.69 141.74,13.79 142.07,13.79 142.17,13.69 142.17,12.65 142.4,12.42 142.99,12.42 143.22,12.65 143.22,13.7 143.36,13.84 143.88,13.84 v1(144.06,13.66)
  BOTTOM w0.102: JW1.67 145.07,13.7 144.89,13.88 144.28,13.88 v1(144.06,13.66) ; RU68.2 58.27,63.08 58.02,63.08 v1(57.84,62.9)
CNV_WT_LANE0_DP_R: length 5.8
  BOTTOM w0.076: 62.35,63.54 62.37,63.54 62.4,63.57 64.47,63.57 UU1.DU45
  BOTTOM w0.102: 62.35,63.54 62.24,63.54 61.79,63.08 59.07,63.08 RU68.1
CNV_WT_LANE1_DN: length 181.8
  ART03 w0.102: v1(56.51,61.76) 56.65,61.9 57,61.9 57.19,61.71 57.19,54.87 55.71,53.4 55.71,51.12 53.12,48.52 53.12,42.07 51.9,40.85 51.9,35.85 52.31,35.44 52.31,28.81 46.51,23.01 45.08,23.01 40.3,18.22 40.3,13.73 41.39,12.63 41.39,8.32 44.43,5.27 66.36,5.27 66.75,5.66 68.37,5.66 68.63,5.92 81.53,5.92 82.93,7.31 88.01,7.31 89.27,6.06 99.2,6.06 102.21,9.07 112.22,9.07 112.53,9.38 127.7,9.38 128.74,8.34 131.66,8.34 132.98,9.66 134.71,9.66 134.91,9.87 139.18,9.87 140.29,10.98 140.29,11.14 140.92,11.76 144.57,11.76 146.95,14.13 147.61,14.13 147.94,14.46 147.94,15.2 147.56,15.58 147.22,15.58 v1(147.06,15.74)
  BOTTOM w0.102: v1(56.51,61.76) 56.7,61.95 58.27,61.95 RU69.2 ; v1(147.06,15.74) 146.88,15.57 146.48,15.57 146.35,15.7 JW1.59
CNV_WT_LANE1_DN_R: length 6.4
  BOTTOM w0.076: 62.71,62.95 62.71,62.98 62.95,63.23 64.09,63.23 64.19,63.13 64.45,63.13 64.56,63.02 UU1.DU44
  BOTTOM w0.102: RU69.1 59.07,61.94 61.69,61.94 62.71,62.95
CNV_WT_LANE1_DP: length 181.1
  ART03 w0.102: v1(147.06,15.16) 147.26,15.36 147.47,15.36 147.72,15.11 147.72,14.55 147.52,14.35 146.86,14.35 144.49,11.97 140.83,11.97 140.08,11.22 140.08,11.07 139.09,10.08 134.82,10.08 134.62,9.88 132.89,9.88 131.57,8.56 128.83,8.56 127.79,9.6 112.44,9.6 112.13,9.28 102.12,9.28 99.11,6.27 89.36,6.27 88.1,7.53 82.84,7.53 81.44,6.13 68.54,6.13 68.29,5.88 66.66,5.88 66.27,5.48 44.52,5.48 41.6,8.4 41.6,12.72 40.51,13.82 40.51,18.13 45.17,22.79 46.59,22.79 52.53,28.72 52.53,35.53 52.12,35.94 52.12,40.76 53.34,41.98 53.34,48.44 55.93,51.03 55.93,53.31 57.4,54.79 57.4,61.8 57.08,62.11 56.74,62.11 v1(56.51,62.34)
  BOTTOM w0.102: v1(147.06,15.16) 146.87,15.35 146.54,15.35 146.39,15.2 JW1.61 ; RU70.2 58.28,62.16 56.69,62.16 v1(56.51,62.34)
CNV_WT_LANE1_DP_R: length 7
  BOTTOM w0.076: 62.55,63.1 62.59,63.1 62.6,63.12 62.88,63.4 64.16,63.4 64.26,63.29 64.61,63.29 UU1.DT44
  BOTTOM w0.102: 62.55,63.1 61.6,62.15 59.08,62.15 RU70.1
CNV_WT_RCOMP: length 2.3
  TOP w0.102: v3(65.6,62.17) v2(65.6,63.21) 65.16,63.21 RU73.1
  BOTTOM w0.076: v2(65.6,63.21) 65.48,63.32 65.43,63.32 UU1.DT45
CNVI_EN_N: length 128
  TOP w0.102: v3(146.91,19.83) v1(146.91,19.23) 146.41,18.72 146.15,18.72 RW27.1
  ART03 w0.089: v2(65.56,57.35) 65.23,57.01 65.23,56.41 64.97,56.16 64.21,56.16 62.63,54.58 62.63,53.57 62.86,53.34 62.86,52.45 61.8,51.38 61.8,50.86 61.34,50.4 61.34,49.17 61.75,48.77 61.75,47.98 61.47,47.7 61.47,45.92 61.24,45.69 61.24,41.73 60.82,41.32 60.82,38.59 61.31,38.11 61.31,31.56 65.01,27.86 73.4,27.86 73.71,27.56 76.38,27.56 77.98,29.16 81.41,29.16 82.37,28.19 85.01,28.19 85.16,28.34 94.77,28.34 95.15,27.96 100.28,27.96 100.68,27.56 109.98,27.56 110.16,27.38 114.3,27.38 115.29,28.37 132.76,28.37 134.99,26.15 134.99,25.66 135.79,24.86 140.76,24.86 141.78,25.88 144.32,25.88 146.35,23.85 146.35,21.47 146.65,21.17 146.65,20.17 146.91,19.91 v1(146.91,19.23)
  BOTTOM w0.102: v2(65.56,57.35) UU1.DT33
CODEC_EAPD: length 7.8
  TOP w0.102: UA2.15 169.67,25.37 169.11,25.37 168.93,25.19 166.39,25.19 166.06,25.52 166.06,26.13 v3(165.83,26.37) 165.23,26.96 DA2.3 164.3,27.4 RA16.2
CORE+PLLVDD: length 1.2
  BOTTOM w0.305: UV2.M6 145.44,68.45 v1(145.47,68.45) 145.42,68.44 UV2.L6
CPU_C10_GATE_N: length 266.5
  TOP w0.076: UE1.M7 163.47,14.93 163.23,15.17 v2(163.23,15.36)
  TOP w0.102: PR906.1 47.09,61.44 v2(46.94,61.59) ; RU226.2 61.72,60.78 61.36,61.14 v2(60.86,61.14) 60.86,62.96 61.82,63.93 61.82,67.18 57.33,71.68 53.82,71.68 v1(52.32,70.18) ; RU226.2 RU227.2 ; RU226.2 TPU21.1
  ART05 w0.102: v1(52.32,70.18) 51.31,70.18 46.94,65.81 v2(46.94,61.59) 46.53,61.19 45.67,61.19 44.96,61.9 39.34,61.9 38.94,61.49 33.86,61.49 33.09,60.73 33.09,58.11 29.77,54.79 29.77,51.71 32.76,48.71 32.76,42.11 33.86,41.02 33.86,39.37 34.92,38.3 40.56,38.3 41.83,37.03 41.83,35.41 41.32,34.9 41.32,28.14 45.03,24.43 50.95,24.43 52.23,23.15 64.32,23.15 66.06,21.41 71.12,21.41 72.39,22.68 74.29,22.68 74.67,22.3 79.25,22.3 82.42,19.12 82.42,13.61 85.49,10.54 89,10.54 89.66,9.88 94.08,9.88 94.89,10.69 97.69,10.69 98.52,9.85 107.31,9.85 109.7,7.47 127.5,7.47 128.74,8.71 135.99,8.71 138.68,11.4 140,11.4 141.37,12.77 141.37,16.58 142.29,17.5 142.29,19.58 142.9,20.19 144.02,20.19 144.42,19.78 148.44,19.78 148.69,20.04 149.76,20.04 150.32,19.48 152.5,19.48 153.77,20.75 154.89,20.75 155.19,20.44 155.19,14.35 156.26,13.28 156.72,13.28 157.88,12.11 159.05,12.11 161.24,14.3 162.25,14.3 163.23,15.27 v2(163.23,15.36)
  ART06 w0.102: v1(38.61,66.88) 41.55,66.88 43.99,64.44 45.97,64.44 47.14,63.27 47.14,61.8 v2(46.94,61.59)
  BOTTOM w0.102: UU1.DU40 63.92,60.65 61.34,60.65 v2(60.86,61.14) ; PR909.1 37.59,70.13 37.34,69.87 v3(37.34,67.74) 38.2,66.88 v1(38.61,66.88) 38.78,66.7 PR904.1
CPU_POPI_RCOMP: length 1.3
  TOP w0.279: v2(78.86,60.96) 78.97,60.96 RU26.2
  BOTTOM w0.279: UU1.CJ41 78.36,61.46 v2(78.86,60.96)
CPU_PROCHOT_EC: length 9.3
  TOP w0.075: UE1.M3 161.22,14.49 161.22,14.04
  TOP w0.076: 161.03,13.66 161.03,13.85 161.22,14.04
  TOP w0.102: QE4.1 156.79,9.6 v3(157.33,9.6) 158.05,9.6 158.27,9.82 158.27,10.26 159.1,11.1 159.54,11.1 159.92,11.47 159.92,12.04 160.09,12.21 RE95.1 160.27,12.9 161.03,13.66
CPU_PROCHOT_N: length 158.7
  TOP w0.102: v1(42.72,9.29) 42.72,8.4 43.66,7.47 RU219.2 43.86,6.75 43.44,6.33 DU3.2 ; v2(143,8.14) 143.44,8.58 144.02,8.58 146.02,10.59 147.57,10.59 149.2,8.96 150.52,8.96 150.65,8.84 152.55,8.84 RE92.2 ; PR607.1 107.17,26.35 v1(107.07,26.25)
  ART03 w0.089: v2(96.98,10.26) 97.05,10.26 101.45,14.65 101.45,20.62 102.49,21.66 102.49,24.58 103,25.09 105.92,25.09 v1(107.07,26.25)
  ART05 w0.102: v1(42.72,9.29) 43.61,9.29 44.4,8.51 55.17,8.51 57.15,10.49 73.51,10.49 74.14,9.85 88.92,9.85 89.1,9.67 95.63,9.67 96.21,10.26 v2(96.98,10.26) 97.46,10.26 98.08,9.64 106.97,9.64 109.35,7.26 127.58,7.26 128.83,8.51 137.21,8.51 137.82,9.12 142.02,9.12 v2(143,8.14)
  BOTTOM w0.102: RU19.1 114.3,37.92 RU18.1 ; RU18.1 114.17,36.9 113.99,36.73 113.99,36.6 113.84,36.45 113.84,36.1 v3(112.88,35.14) 110.54,32.8 110.54,29.54 107.25,26.25 v1(107.07,26.25) ; RU18.1 RU17.1
CPU_PWM_FAN: length 33.7
  TOP w0.076: UE1.M6 162.72,14.49 162.72,14.07 162.69,14.03 162.69,12.93 162.56,12.8 162.56,12.29 v2(162.2,11.94)
  TOP w0.102: RE49.2 186.94,12.47 v1(187.15,12.27) 187.15,12.16 186.59,11.61 v3(186.28,11.61)
  ART06 w0.102: v1(187.15,12.27) 184.45,9.57 177.52,9.57 176.95,10.15 175.17,10.15 174.88,9.85 170.69,9.85 170.18,10.36 169.42,10.36 168.91,9.85 163.83,9.85 162.2,11.48 v2(162.2,11.94)
CPU_TACHO_FAN: length 28.8
  TOP w0.076: v2(166.23,12.57) 166.2,12.54 CE42.1 165.72,12.58 165.72,14.49 UE1.M11
  TOP w0.102: v1(187.45,12.88) 188.11,13.54 v3(188.11,14.25) 188.11,14.86 187.58,15.39 RE48.2
  ART06 w0.102: v1(187.45,12.88) 185.14,12.88 183.67,11.4 167.4,11.4 v2(166.23,12.57)
CSI_COMP: length 7.7
  BOTTOM w0.076: 111.36,43.89 UU1.B4
  BOTTOM w0.102: 111.36,43.89 111.77,43.48 112.42,43.48 115.36,40.54 v3(115.36,39.9) 115.36,39.24 RU76.2
DBG_PMODE: length 2.7
  TOP w0.102: RU222.2 66.99,49.28 67,49.3 RU54.1 67.44,48.93 67.33,48.83 v2(67.05,48.83) TP177.1
  BOTTOM w0.102: UU1.DL15 67.35,49.11 67.07,48.83 v2(67.05,48.83)
DC_JACK_IN:
  vias: v1(12.83,74.27) v4(12.06,75.74) v4(12.06,75.03) v4(12.06,74.22) v4(12.06,73.4) v4(12.11,76.5) v4(12.83,79.07) v4(12.83,78.18) v4(12.83,77.42) v4(12.83,76.4) v4(12.83,75.74) v4(12.83,75.03) v4(12.83,73.45) v4(13.46,75.89) v4(13.46,74.75) v4(14.98,75.89) v4(14.98,75)
DCIN_EN_8409A: length 2.1
  TOP w0.102: RI149.2 26.29,57.22 25.66,56.59 UI2.3
DDI1_DDC_SCL: length 79
  TOP w0.102: UI2.34 25.66,48.84 25.78,48.71 RI142.1 25.47,48.21 25.37,48.11 25.37,47.03 25.59,46.81 27.72,46.81 28.2,47.29 29.25,47.29 v1(29.43,47.47)
  ART03 w0.089: v1(52.47,68.58) 52.42,68.53 52.42,68.48 51.5,67.55 47.13,67.55 44.83,69.85 38.94,69.85 37.45,71.33 30.92,71.33 29.5,69.91 29.5,65.39 32.47,62.42 32.47,59.06 29.78,56.37 29.78,49.79 30.01,49.57 30.01,47.56 29.77,47.32 29.58,47.32 v1(29.43,47.47)
  ART06 w0.102: v2(67.69,60.67) 66.46,60.67 65.78,61.34 65.11,61.34 64.8,61.64 64.56,61.64 63.75,62.46 63.75,62.66 63.17,63.24 60.02,63.24 57.58,65.68 55.12,65.68 53.93,66.88 53.12,66.88 52.25,67.75 52.25,68.35 v1(52.47,68.58)
  BOTTOM w0.089: v2(67.69,60.67) 67.68,60.67 67.35,61 UU1.DL40
DDI1_DDC_SDA: length 76.5
  TOP w0.102: v2(29.43,46.91) 29.28,47.06 28.29,47.06 27.81,46.58 25.5,46.58 25.14,46.94 25.14,48.11 25.04,48.21 RI143.1 24.76,48.51 25.26,49 UI2.33
  ART03 w0.089: v1(52.65,68.02) 52.56,67.93 52.18,67.93 51.59,67.33 47.04,67.33 44.74,69.63 38.85,69.63 37.36,71.12 31.01,71.12 29.72,69.82 29.72,65.48 32.69,62.51 32.69,58.97 30,56.28 30,49.88 30.22,49.66 30.22,47.47 29.86,47.1 29.6,47.1 29.43,46.94 v2(29.43,46.91)
  ART06 w0.102: v1(52.65,68.02) 52.65,67.66 53.21,67.1 54.02,67.1 55.22,65.91 57.67,65.91 60.11,63.47 63.26,63.47 63.98,62.75 63.98,62.55 64.66,61.87 64.9,61.87 65.19,61.58 v2(66.18,61.58)
  BOTTOM w0.089: v2(66.18,61.58) 66.17,61.58 66.05,61.71 UU1.DP42
DDI1_HPD: length 94.6
  TOP w0.102: v1(27.81,56.97) v3(29.67,56.97) 30.99,56.97 32.38,55.57 32.38,51.89 31.56,51.06 30.67,51.06 30.1,51.64 RI146.2 RI148.1
  ART03 w0.089: v2(73.32,62.32) 73.42,62.32 74.29,63.19 74.29,63.45 73.58,64.16 73.58,67.1 70.05,70.63 69.06,70.63 68.78,70.36 65.89,70.36 64.67,71.58 64.67,72.06 63.15,73.58 57.7,73.58 57.37,73.25 53.01,73.25 52.33,72.58 51.19,72.58 50.44,73.33 46.58,73.33 45.59,74.32 41.96,74.32 41,75.28 36.34,75.28 35.86,75.77 34.54,75.77 32.26,78.05 v1(27.43,78.05)
  ART05 w0.102: v1(27.81,56.97) 27.18,57.6 27.18,59 26.41,59.76 26.41,64.67 27.66,65.91 27.66,71.27 28.52,72.13 28.52,72.39 28.17,72.74 28.04,72.74 27.05,73.73 27.05,74.37 26.16,75.26 26.16,76.78 v1(27.43,78.05)
  BOTTOM w0.102: v2(73.32,62.32) 73.58,62.32 UU1.CV42
DDI1_HPD_LV: length 1.9
  TOP w0.102: UI2.40 28.81,52.03 RI148.2
DDI1_TX0_DN: length 117.4
  TOP w0.102: CI61.2 29.74,50.98 30.06,50.98 30.31,50.73 30.31,49.39 29.68,48.75 28.56,48.75 v1(28.38,48.57)
  ART06 w0.102: v1(28.38,48.57) 28.55,48.75 29.16,48.75 29.86,48.05 29.86,44.89 28.97,44 28.97,36.13 29.45,35.65 29.45,31.94 30.21,31.18 30.21,29.25 30.91,28.55 30.91,23.37 36.01,18.27 42.5,18.27 42.96,18.73 43.95,18.73 45.24,20.03 46.8,20.03 52.35,25.58 64.64,25.58 65.47,26.4 71.17,26.4 71.68,26.91 73.52,26.91 75.12,28.51 76.66,28.51 83.52,35.37 93.64,35.37 94.19,35.93 97.97,35.93 99.71,37.66 99.71,38.77 99.24,39.24 99.24,41.15 v2(99.44,41.35)
  BOTTOM w0.076: UU1.AE3 99.75,43.24 99.62,43.1 99.5,42.87 99.5,42.04 99.23,41.77 99.23,41.56 v2(99.44,41.35)
DDI1_TX0_DP: length 117.4
  TOP w0.102: CI62.2 29.74,50.77 29.97,50.77 30.1,50.64 30.1,49.48 29.59,48.97 28.56,48.97 v1(28.38,49.15)
  ART06 w0.102: v1(28.38,49.15) 28.57,48.96 29.25,48.96 30.07,48.14 30.07,44.8 29.18,43.91 29.18,36.22 29.67,35.74 29.67,32.03 30.43,31.26 30.43,29.33 31.13,28.64 31.13,23.46 36.1,18.49 42.42,18.49 42.87,18.95 43.86,18.95 45.15,20.24 46.71,20.24 52.26,25.79 64.55,25.79 65.38,26.62 71.08,26.62 71.59,27.12 73.43,27.12 75.03,28.72 76.57,28.72 83.43,35.58 93.55,35.58 94.11,36.14 97.88,36.14 98.95,37.21 98.95,37.35 99.16,37.57 99.31,37.57 99.49,37.75 99.49,38.68 99.02,39.15 99.02,39.58 98.88,39.72 98.88,39.99 99.02,40.13 99.02,40.39 98.88,40.53 98.88,40.8 99.02,40.94 99.02,41.13 v2(98.8,41.35)
  BOTTOM w0.076: UU1.AE5 99.47,43.73 99.47,43.18 99.33,42.91 99.33,42.11 99.06,41.84 99.06,41.61 v2(98.8,41.35)
DDI1_TX1_DN: length 114.5
  TOP w0.102: CI63.2 29.74,52.74 30.95,52.74 v1(31.14,52.92)
  ART06 w0.102: v2(97.79,39.9) 97.6,40.09 93.94,40.09 91.51,37.67 82.65,37.67 81.81,36.83 81.81,36.4 77.84,32.42 76.16,32.42 74.13,30.39 72.86,30.39 71.73,29.26 70.69,29.26 70.2,28.78 65.1,28.78 63.76,27.44 51.24,27.44 46.59,22.79 45.32,22.79 43.48,20.95 42.37,20.95 41.59,20.18 37.01,20.18 34.45,22.74 34.45,30.95 33.65,31.75 32.3,31.75 31.7,32.35 31.7,36.46 30.83,37.33 30.83,41.64 33.2,44 33.2,48.81 31.31,50.7 30.86,50.7 30.4,51.15 30.4,52.48 30.65,52.73 30.95,52.73 v1(31.14,52.92)
  BOTTOM w0.102: v2(97.79,39.9) 97.95,40.07 99.05,40.07 100.04,41.06 100.04,42.14 UU1.AE2
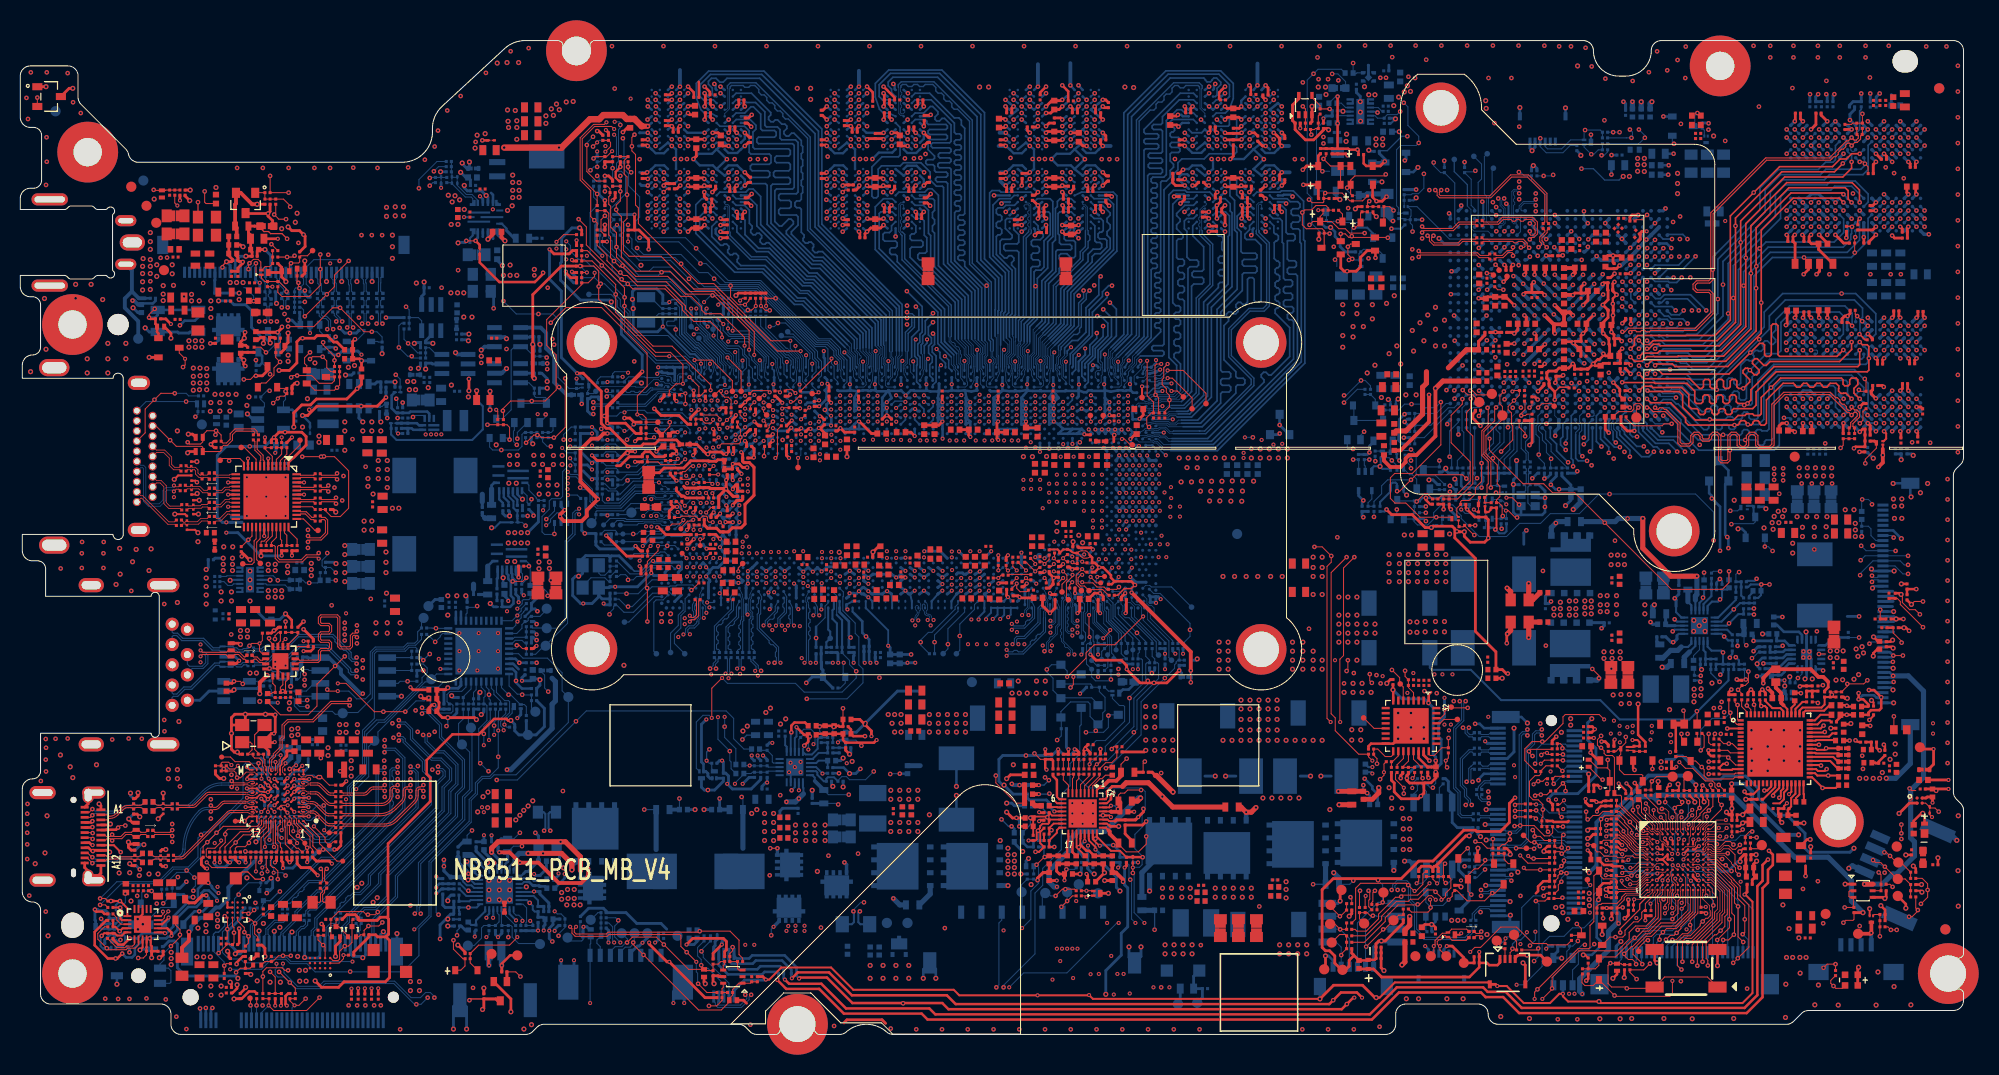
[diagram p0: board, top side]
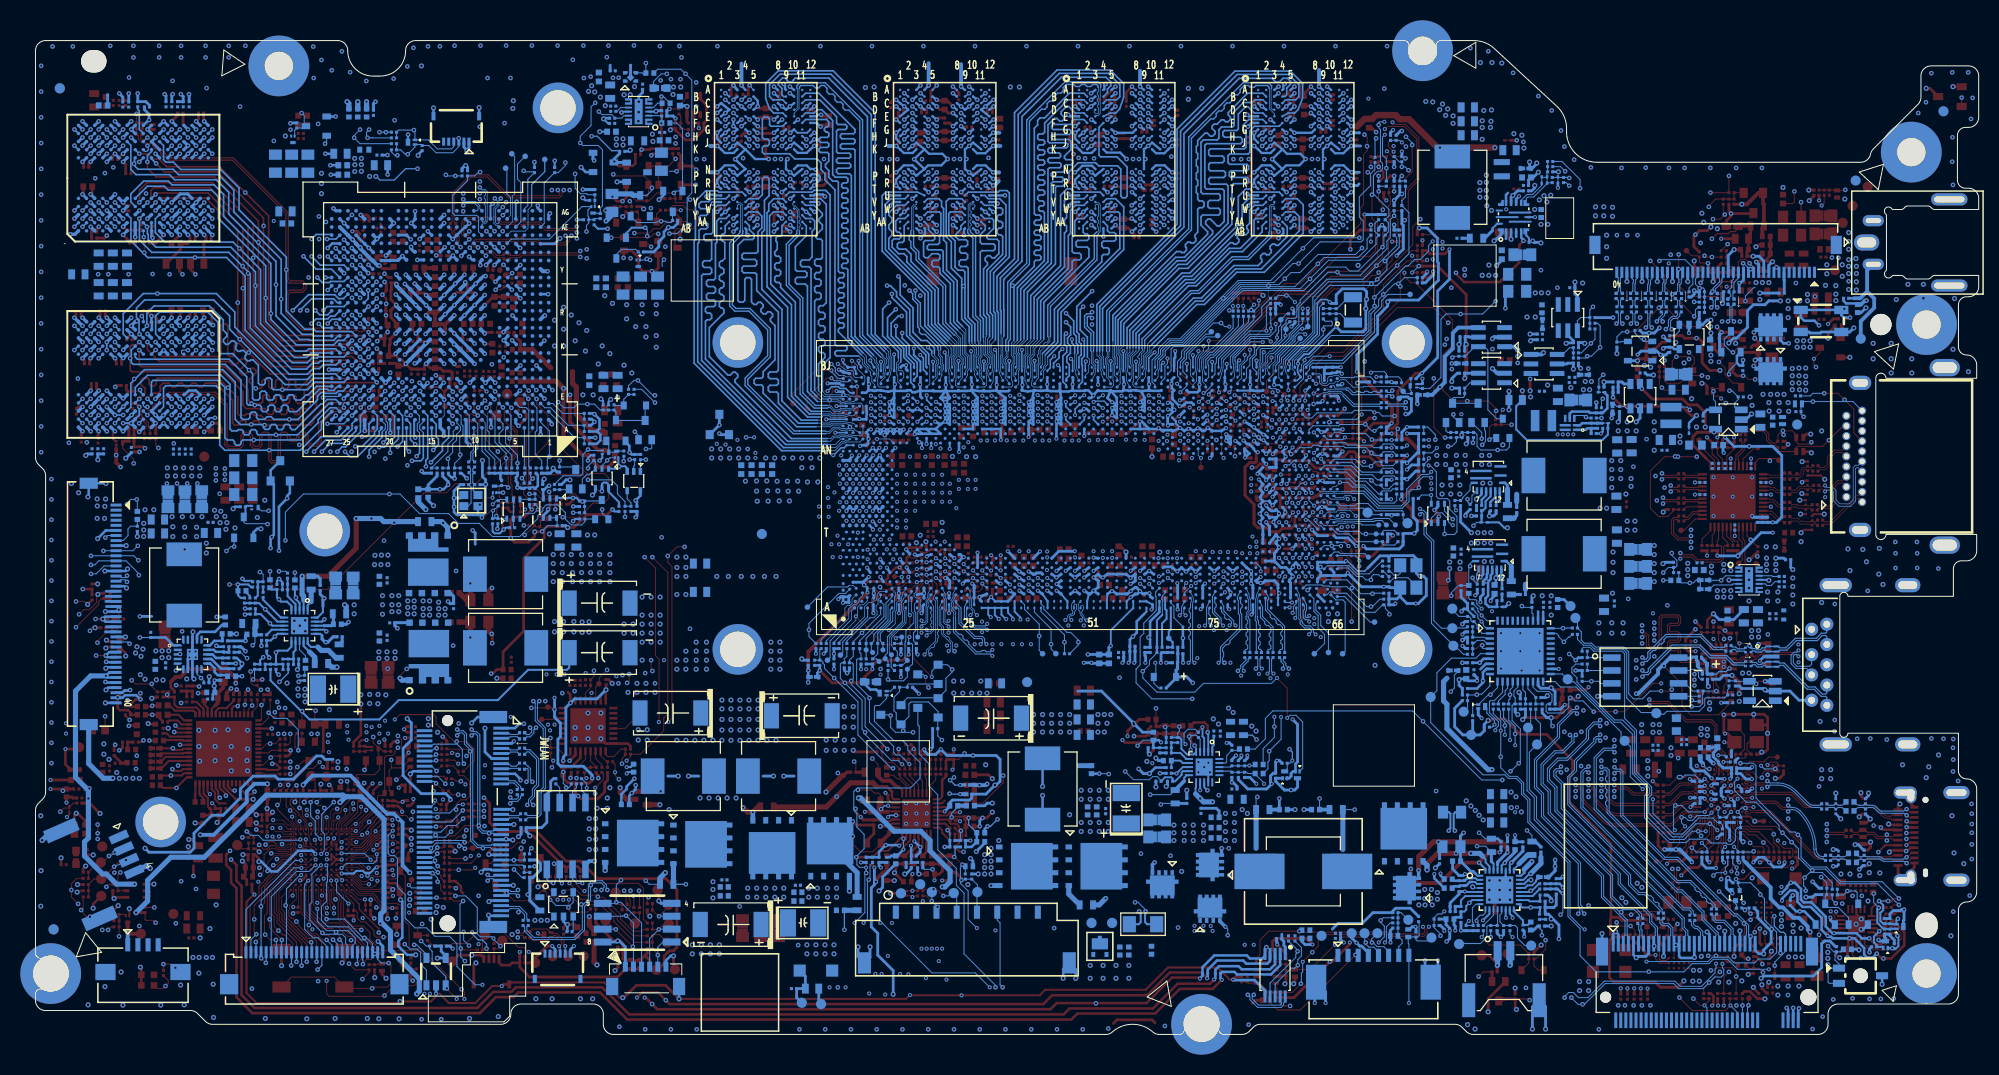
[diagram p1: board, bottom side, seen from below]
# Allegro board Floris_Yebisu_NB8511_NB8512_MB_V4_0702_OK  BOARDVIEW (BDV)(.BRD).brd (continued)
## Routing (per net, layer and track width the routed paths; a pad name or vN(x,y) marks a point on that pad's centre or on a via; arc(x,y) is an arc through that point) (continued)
DDI1_TX1_DP: length 114.4
  TOP w0.102: CI64.2 29.74,52.52 30.95,52.52 v1(31.14,52.34)
  ART06 w0.102: v2(97.79,40.49) 97.61,40.31 97.29,40.31 97.14,40.46 96.89,40.46 96.73,40.31 96.48,40.31 96.33,40.46 96.07,40.46 95.92,40.31 95.67,40.31 95.51,40.46 95.26,40.46 95.11,40.31 94.85,40.31 94.7,40.46 94.45,40.46 94.29,40.31 93.85,40.31 93.6,40.05 93.42,40.05 93.22,39.86 93.22,39.68 93.02,39.48 92.85,39.48 92.65,39.28 92.65,39.1 92.45,38.9 92.27,38.9 92.07,38.71 92.07,38.53 91.42,37.88 82.56,37.88 81.6,36.92 81.6,36.49 81.33,36.22 81.13,36.22 80.94,36.04 80.94,35.83 80.76,35.65 80.56,35.65 80.37,35.46 80.37,35.26 80.18,35.07 79.98,35.07 79.79,34.89 79.79,34.68 79.61,34.5 79.41,34.5 79.22,34.31 79.22,34.11 77.75,32.64 76.07,32.64 74.04,30.6 72.77,30.6 71.64,29.47 70.6,29.47 70.11,28.99 65.01,28.99 63.68,27.66 51.15,27.66 46.5,23.01 45.23,23.01 43.39,21.17 42.28,21.17 41.5,20.39 37.1,20.39 34.67,22.82 34.67,31.04 33.74,31.96 32.39,31.96 31.91,32.44 31.91,36.55 31.05,37.42 31.05,41.55 33.41,43.91 33.41,48.9 33.12,49.19 33.12,49.37 32.93,49.57 32.74,49.57 32.55,49.76 32.55,49.95 32.35,50.14 32.17,50.14 31.97,50.34 31.97,50.52 31.78,50.72 31.59,50.72 31.4,50.91 30.95,50.91 30.62,51.24 30.62,52.39 30.74,52.52 30.96,52.52 v1(31.14,52.34)
  BOTTOM w0.102: v2(97.79,40.49) 97.99,40.28 98.96,40.28 99.14,40.46 99.14,40.67 99.32,40.85 99.53,40.85 99.82,41.15 99.82,41.99 99.75,42.06
DDI1_TX2_DN: length 118.8
  TOP w0.102: v1(30.38,54.12) 30.19,53.94 29.74,53.94 CI65.2
  ART06 w0.102: v1(30.38,54.12) 30.19,53.93 29.98,53.93 29.67,53.62 29.67,50.92 30.58,50.01 30.88,50.01 32.56,48.33 32.56,44.55 30.21,42.2 30.21,36.92 30.71,36.42 30.71,32.45 32.17,30.99 32.48,30.99 32.59,30.88 32.59,29.21 33.63,28.17 33.63,22.67 36.76,19.54 41.9,19.54 42.67,20.32 43.74,20.32 44.7,21.27 46.28,21.27 51.83,26.82 64.06,26.82 65.3,28.06 70.46,28.06 70.97,28.57 72.08,28.57 73.28,29.77 75.28,29.77 77.16,31.65 78.03,31.65 82.88,36.49 82.88,36.82 83.09,37.03 92.58,37.03 93.08,37.53 97.09,37.53 v2(97.28,37.34)
  BOTTOM w0.076: 101.12,41.05 101.12,41.07 101.09,41.09 101.09,41.6 101.35,41.86 101.35,42.19 101.3,42.24 101.3,42.52 101.33,42.55 101.36,42.77 101.16,43.12 101.16,43.47 UU1.AC5
  BOTTOM w0.102: v2(97.28,37.34) 97.46,37.51 98.93,37.51 101.12,39.7 101.12,41.05
DDI1_TX2_DP: length 118.7
  TOP w0.102: v1(30.38,53.54) 30.19,53.72 29.74,53.72 CI66.2
  ART06 w0.102: v2(97.28,37.92) 97.1,37.74 96.81,37.74 96.66,37.89 96.4,37.89 96.25,37.74 96,37.74 95.85,37.89 95.59,37.89 95.44,37.74 95.18,37.74 95.03,37.89 94.78,37.89 94.63,37.74 94.37,37.74 94.22,37.89 93.97,37.89 93.81,37.74 92.99,37.74 92.49,37.25 83,37.25 82.66,36.91 82.66,36.58 77.95,31.86 77.07,31.86 75.19,29.98 73.19,29.98 71.99,28.79 70.88,28.79 70.37,28.28 65.21,28.28 63.97,27.04 51.74,27.04 46.19,21.49 44.61,21.49 43.66,20.53 42.58,20.53 41.81,19.76 36.85,19.76 33.84,22.76 33.84,28.26 32.8,29.3 32.8,30.97 32.57,31.2 32.26,31.2 30.92,32.54 30.92,36.51 30.43,37.01 30.43,42.11 30.85,42.54 31.06,42.54 31.24,42.72 31.24,42.93 31.43,43.11 31.63,43.11 31.82,43.3 31.82,43.5 32,43.69 32.21,43.69 32.39,43.87 32.39,44.08 32.78,44.46 32.78,48.42 32.68,48.52 32.68,48.72 32.5,48.91 32.29,48.91 32.11,49.09 32.11,49.3 31.92,49.48 31.72,49.48 31.53,49.67 31.53,49.87 31.35,50.06 31.14,50.06 30.97,50.23 30.67,50.23 29.88,51.01 29.88,52.67 30.02,52.81 30.02,53.11 29.88,53.25 29.88,53.53 30.07,53.72 30.2,53.72 v1(30.38,53.54)
  BOTTOM w0.076: UU1.AC3 100.88,43.28 101.18,42.73 101.17,42.63 101.13,42.59 101.13,42.17 101.18,42.12 101.18,41.95 100.93,41.69 100.93,41.09 100.9,41.07 100.9,41.05
  BOTTOM w0.102: 100.9,41.05 100.9,39.79 100.57,39.46 100.37,39.46 100.18,39.27 100.18,39.07 100,38.89 99.8,38.89 99.61,38.7 99.61,38.5 98.84,37.73 98.43,37.73 98.29,37.87 98.02,37.87 97.88,37.73 97.47,37.73 v2(97.28,37.92)
DDI1_TX3_DN: length 119.4
  TOP w0.102: v1(31.24,55.32) 31.06,55.14 29.74,55.14 CI67.2
  ART06 w0.102: v2(98.44,38.48) 98.25,38.29 98.25,37.37 97.46,36.57 93.68,36.57 93.1,35.99 83.26,35.99 76.41,29.14 73.75,29.14 72.52,27.91 71.22,27.91 70.74,27.43 65.58,27.43 64.35,26.2 52.09,26.2 46.54,20.65 44.96,20.65 43.71,19.4 42.75,19.4 42.25,18.91 36.38,18.91 32.54,22.75 32.54,23.42 31.53,24.42 31.53,28.83 30.83,29.53 30.83,31.43 30.07,32.2 30.07,36.09 29.59,36.57 29.59,43.48 30.48,44.37 30.48,48.94 29.03,50.38 29.03,54.03 30.13,55.13 31.05,55.13 v1(31.24,55.32)
  BOTTOM w0.102: v2(98.44,38.48) 98.26,38.66 98.26,38.94 98.36,39.04 99.08,39.04 100.58,40.54 100.58,41.96 100.68,42.06 100.88,42.06
DDI1_TX3_DP: length 119.3
  TOP w0.102: v1(31.24,54.74) 31.06,54.92 29.74,54.92 CI68.2
  ART06 w0.102: v1(31.24,54.74) 31.06,54.92 30.22,54.92 29.25,53.94 29.25,50.47 30.69,49.02 30.69,44.28 29.81,43.39 29.81,36.66 30.29,36.18 30.29,32.29 31.05,31.52 31.05,29.62 31.75,28.92 31.75,24.51 32.75,23.51 32.75,22.84 36.47,19.12 42.16,19.12 42.66,19.62 43.62,19.62 44.87,20.86 46.45,20.86 52,26.41 64.26,26.41 65.49,27.65 70.65,27.65 71.13,28.13 72.43,28.13 73.66,29.36 76.32,29.36 83.17,36.21 93.01,36.21 93.59,36.79 93.9,36.79 94.01,36.9 94.3,36.9 94.42,36.79 94.71,36.79 94.82,36.9 95.12,36.9 95.23,36.79 95.52,36.79 95.64,36.9 95.93,36.9 96.04,36.79 96.34,36.79 96.45,36.9 96.74,36.9 96.86,36.79 97.37,36.79 98.04,37.46 98.04,38.3 v2(97.86,38.48)
  BOTTOM w0.102: v2(97.86,38.48) 98.04,38.66 98.04,39.03 98.27,39.25 98.99,39.25 100.37,40.62 100.37,42.04 100.88,42.56 UU1.AC2
DDR_RCOMP_0: length 8.6
  TOP w0.102: v2(112.52,66.11) 112.06,66.11 111.91,65.96 111.91,63.12 v3(111.96,63.07) 112.27,62.76 112.27,61.34 RU1.1
  BOTTOM w0.076: v2(112.52,66.11) 111.72,65.52 111.57,65.48 111.12,65.48 111,65.35 111,64.97 110.81,64.79 UU1.D47
DDR_RCOMP_1: length 10.2
  TOP w0.102: v2(111.13,66.42) 111.13,62.98 111.76,62.35 RU2.1 111.55,61.29 111.1,60.83 111.1,60.12 v3(111.33,59.89)
  BOTTOM w0.076: v2(111.13,66.42) 111.08,66.42 110.57,65.92 110.57,65.62 109.85,64.9 109.85,64.32 UU1.E46
DDR_RCOMP_2: length 8.9
  TOP w0.102: RU3.1 112.88,61.44 113.33,61.9 v3(113.33,62.56) 113.33,63.01 113.03,63.32 113.03,63.68 112.62,64.08 112.62,64.59 112.77,64.74 112.77,65.73 v2(113.16,66.11)
  BOTTOM w0.076: 112.27,64.97 111.86,64.97 111.73,64.84 111.25,64.84 110.81,64.4 UU1.C47
  BOTTOM w0.102: 112.27,64.97 112.39,64.97 112.77,65.35 112.77,65.73 v2(113.16,66.11)
DGPU_PROCHOT_EC: length 52.1
  TOP w0.076: v2(168.29,20.36) 167.92,19.99 167.37,19.99 167.13,19.74 UE1.B13
  TOP w0.102: v2(146.57,52.92) 147.15,52.92 v3(147.83,52.25)
  ART03 w0.089: v2(168.29,20.36) 167.73,20.91 167.73,22.48 166.27,23.94 164.93,23.94 164.23,24.64 164.23,29.44 v1(164.44,29.64)
  ART06 w0.102: v2(146.57,52.92) 146.94,52.56 146.94,51 147.32,50.62 156.64,50.62 164.08,43.17 164.08,29.99 v1(164.44,29.64)
  BOTTOM w0.102: QV24.1 146.54,52.95 v2(146.57,52.92)
DISP_RCOMP: length 4.5
  BOTTOM w0.076: UU1.R2 104.96,42.44 104.96,41.73
  BOTTOM w0.102: RU6.2 105.05,38.83 105.05,39.61 104.84,39.82 104.84,41.6 104.96,41.73
DMIC1_CLK: length 6.6
  TOP w0.102: RX24.2 RX898.2 CX893.1 24.59,75.71 24.15,75.71 ESD2.2 23.72,75.42 23.72,76.16 23.46,76.43 22.99,76.43 v1(22.6,76.05) 22.5,75.94 v3(22.5,75.46)
  BOTTOM w0.102: JX1.13 22.2,75.64 v1(22.6,76.05)
DMIC1_CLK_AUDIO: length 281.1
  TOP w0.102: RA10.1 v1(166.52,25.68) ; v1(24.76,77.92) RX24.1
  ART03 w0.089: v2(25.91,6.98) 25.55,7.34 25.32,7.34 24.98,7.68 24.98,7.91 23.84,9.05 21.17,9.05 20.53,9.69 20.53,11.85 19.86,12.52 18.64,12.52 18.34,12.82 17.12,12.82 15.98,13.96 15.98,15.61 17.65,17.28 17.65,21.03 18.29,21.66 18.29,24.2 18.61,24.53 18.61,25.85 19.39,26.63 19.39,27.11 20.42,28.14 20.42,30.45 22.05,32.08 25.27,32.08 25.91,31.44 28.32,31.44 29.72,32.84 29.72,36.34 31.46,38.08 32.29,38.08 32.65,38.44 32.65,41 32.48,41.17 29.39,41.17 25.91,44.65 25.91,46.48 25.36,47.03 25.36,47.44 26.29,48.37 26.29,50.62 26.67,51 26.67,55.83 26.41,56.08 26.41,57.35 25.39,58.37 25.39,59.76 26.41,60.78 26.41,63.5 26.25,63.66 26.25,65.77 25.97,66.05 25.97,70.55 24.73,71.79 24.73,72.93 25.22,73.43 25.22,74.55 24.56,75.21 24.56,77.72 v1(24.76,77.92) ; v1(166.52,25.68) 166.46,25.61 166.46,25.31 166.55,25.22 166.88,25.22 167.09,25.44 168.95,25.44 169.42,24.97 169.42,23.31 171.96,20.77 171.96,4.26 170.22,2.52 153.13,2.52 152.91,2.74 152.91,3.85 v2(152.75,4.01)
  ART06 w0.102: v1(40.84,3.63) 42.9,5.69 46.96,5.69 48,4.65 65.78,4.65 67.82,6.68 83.06,6.68 83.69,7.31 98.52,7.31 102.72,3.12 114.37,3.12 116.6,5.36 147.78,5.36 147.95,5.53 151.23,5.53 v2(152.75,4.01)
  BOTTOM w0.102: v2(25.91,6.98) 25.91,6.55 26.01,6.45 26.01,6.07 27.33,4.75 29.44,4.75 29.94,5.26 36.92,5.26 38.55,3.63 39.47,3.63 39.98,4.14 40.43,4.14 40.84,3.73 v1(40.84,3.63)
DMIC1_CLK_R: length 2.2
  TOP w0.102: RA10.2 169.06,25.68 169.15,25.77 UA2.14
DMIC1_DATA: length 6.3
  TOP w0.102: v3(26.26,73.25) 26.26,73.48 25.5,74.24 RX899.2 RX23.2 24.13,74.24 23.79,74.58 ESD2.1 23.34,74.91 23.24,75.01 v1(23.24,76.05)
  BOTTOM w0.102: v1(23.24,76.05) 23.21,76.02 23.16,76.02 22.7,75.56 JX1.14
DMIC1_DATA_AUDIO: length 278.2
  TOP w0.102: RX23.1 v2(24.86,73.73) ; RA11.1 v1(166.52,26.9)
  ART03 w0.089: v2(25.27,6.97) 25.27,7.08 24.76,7.59 24.76,7.82 23.75,8.84 21.08,8.84 20.32,9.6 20.32,11.76 19.81,12.27 18.54,12.27 18.24,12.57 17.05,12.57 15.77,13.85 15.77,15.7 17.44,17.37 17.44,21.12 18.07,21.75 18.07,24.29 18.39,24.62 18.39,25.94 19.18,26.72 19.18,27.2 20.22,28.24 20.22,30.6 21.91,32.29 25.36,32.29 26,31.66 28.23,31.66 29.5,32.93 29.5,36.43 31.37,38.3 32.26,38.3 32.43,38.48 32.43,40.79 32.24,40.98 29.27,40.98 25.69,44.56 25.69,46.39 25.14,46.94 25.14,47.53 25.78,48.17 25.78,57.35 24.64,58.49 24.64,59.31 26.2,60.87 26.2,63.41 26.03,63.57 26.03,65.61 25.75,65.89 25.75,70.46 24.51,71.7 24.51,73.38 v2(24.86,73.73) ; v1(166.52,26.9) 165.99,26.36 165.99,25.47 166.24,25.22 166.46,25 166.97,25 167.18,25.22 168.86,25.22 169.2,24.88 169.2,23.23 171.74,20.69 171.74,4.35 170.13,2.74 153.22,2.74 153.13,2.83 153.13,3.85 v2(153.29,4.01)
  ART06 w0.102: v1(40.18,3.63) 42.47,5.92 47.06,5.92 48.1,4.87 65.69,4.87 67.72,6.91 82.96,6.91 83.6,7.54 99.01,7.54 103.12,3.43 114.35,3.43 116.51,5.59 147.6,5.59 147.78,5.76 151.53,5.76 v2(153.29,4.01)
  BOTTOM w0.102: v1(40.18,3.63) 39.52,2.97 v3(39.06,2.97) 38.89,2.97 36.84,5.02 30.09,5.02 29.59,4.52 27.18,4.52 26.03,5.66 25.4,5.66 25.14,5.92 25.14,6.42 25.27,6.55 v2(25.27,6.97)
DMIC1_DATA_R: length 3.1
  TOP w0.102: UA2.12 169.19,26.57 v3(168.45,27.3) 168.3,27.45 CA26.1 RA11.2
DMIC2_CLK: length 8.6
  BOTTOM w0.102: JKBL3.3 149.9,87.54 150.49,86.94 152.14,86.94 152.86,87.65 CX894.1 153.62,87.76 ESD3.2 154.23,87.5 v3(154.94,86.79) 155.19,86.79 155.63,87.22 RX915.2 RX913.2
DMIC2_CLK_AUDIO: length 123
  TOP w0.102: RA234.1 167.03,29.54 v1(167.13,29.64)
  ART03 w0.089: v1(167.13,29.64) 168.13,30.64 171.22,30.64 172.93,32.35 172.93,34.59 172.77,34.75 172.77,48.39 174.62,50.24 174.62,51.13 175.13,51.64 178.81,51.64 179.45,51 180.97,51 181.86,50.11 185.82,50.11 189.36,53.64 189.36,55.45 190.49,56.58 190.49,92.29 188.54,94.24 184.8,94.24 183.59,95.45 171.02,95.45 168.12,92.56 162.96,92.56 v1(159.64,89.23)
  BOTTOM w0.102: RX913.1 159.64,87.83 v3(160.22,88.41) 160.26,88.46 160.26,88.6 v1(159.64,89.23)
DMIC2_CLK_R: length 2.5
  TOP w0.102: RA234.2 167.99,28.67 v3(168.5,28.67) 168.86,28.67 169.37,28.17 UA2.8
DMIC2_DATA: length 8.1
  BOTTOM w0.102: JKBL3.4 150.4,87.55 150.62,87.32 152.02,87.32 152.9,88.21 ESD3.1 154.23,89.08 v3(154.33,89.18) 155.83,89.18 RX916.2 RX914.2
DMIC2_DATA_AUDIO: length 123.3
  TOP w0.102: v1(166.52,29.64) 166.52,28.78 166.72,28.57 RA235.1
  ART03 w0.089: v1(166.52,29.64) 167.72,30.83 171.09,30.83 172.74,32.48 172.74,34.46 172.57,34.63 172.57,48.56 174.37,50.37 174.37,51.25 175,51.89 178.94,51.89 179.55,51.28 181.07,51.28 181.99,50.37 185.72,50.37 189.1,53.74 189.1,55.52 190.29,56.71 190.29,92.15 188.41,94.03 184.7,94.03 183.54,95.2 171.07,95.2 168.22,92.35 163.29,92.35 159.79,88.85 159.13,88.85 v1(158.75,89.23)
  BOTTOM w0.102: RX914.1 158.38,88.41 158.39,88.41 v3(158.9,88.41) 159,88.52 159,88.97 v1(158.75,89.23)
DMIC2_DATA_R: length 2.8
  TOP w0.102: RA235.2 CA63.1 168.4,28.01 168.65,27.77 UA2.9
DRAM_RESET_N: length 27.2
  BOTTOM w0.076: 68.37,66.28 68.37,66.07 68.31,65.89 68.31,65.76 68.39,65.46 68.34,65.32 UU1.DK47
  BOTTOM w0.102: RD2.2 56.54,82.57 56.89,82.22 56.89,81.73 56.2,81.04 56.2,76.97 v3(57.35,75.82) 59.31,73.86 64.01,73.86 65.48,72.39 65.48,69.18 66.68,67.97 66.84,67.97 68.37,66.44 68.37,66.28
DRAM_RESET_N_R: length 69.2
  TOP w0.102: v1(63.46,83.06) 63.79,83.39 CD5.1 ; v1(81.11,83.06) 81.31,83.26 CD9.1
  TOP w0.279: CD13.1 98.8,83.74 v1(98.77,83.71) ; v1(115.62,83.71) 115.89,83.71 CD17.1
  GND02 w0.102: v1(56.89,84.66) 57.66,83.89 60.2,83.89 61.47,82.62 62.1,82.62 62.36,82.88 63.12,82.88 63.3,83.06 v1(63.46,83.06) 65.1,83.06 65.66,82.5 68.58,82.5 68.96,82.88 70.74,82.88 71.25,82.37 78.74,82.37 79.07,82.7 79.96,82.7 80.32,83.06 v1(81.11,83.06) 82.88,83.06 83.31,82.62 86.87,82.62 87.12,82.88 88.52,82.88 89.08,82.32 97.38,82.32 v1(98.77,83.71) 99.85,82.62 104.39,82.62 104.65,82.88 106.3,82.88 107.06,82.12 114.03,82.12 v1(115.62,83.71)
  BOTTOM w0.102: UD3.T11 98.77,83.69 v1(98.77,83.71) ; RD2.1 CD1.1 57.1,84.45 v1(56.89,84.66) ; UD2.T11 v1(81.11,83.06) ; UD1.T11 v1(63.46,83.06) ; UD4.T11 v1(115.62,83.71)
DSW_PWROK: length 8.4
  BOTTOM w0.076: UU1.DR48 64.99,65.14 64.81,64.96 64.81,64.67 64.84,64.64 64.84,64.39 64.66,64.2 64.37,64.2 64.2,64.37 64.2,64.74 64.08,64.86 63.76,64.86 63.65,64.97 63.14,64.97 62.93,64.77 62.86,64.77
  BOTTOM w0.102: 62.86,64.77 61.64,64.77 61.57,64.84 59.99,64.84 59.59,64.44 CU170.1 RU152.2
DSW_PWROK_EC: length 156
  TOP w0.076: v2(168.22,21.14) 167.26,21.14 166.76,20.65 166.5,20.65 166.23,20.37 166.23,20.12 165.97,19.87 UE1.B12
  TOP w0.102: 156.51,26.29 156.77,26.03 QL4.3 156.77,24.05 DL3.1 ; 156.51,26.29 155.55,26.29 154.74,27.09 DL2.1 ; 156.51,26.29 156.56,26.34 v1(156.56,27.07)
  ART05 w0.102: v2(59.41,64.84) 59.41,62.94 58.27,61.8 58.27,55.39 58.77,54.89 58.77,49.57 59.61,48.73 59.61,45.92 60.45,45.08 60.45,38.83 66.49,32.79 74.83,32.79 75.18,32.43 78.94,32.43 79.3,32.79 93.9,32.79 96.16,30.53 110.16,30.53 110.54,30.91 112.19,30.91 112.98,31.7 125.49,31.7 126.74,30.45 132.48,30.45 135.02,27.91 142.95,27.91 143.2,28.17 149.29,28.17 150.92,26.53 v2(150.92,25.93)
  ART06 w0.102: v2(168.22,21.14) 168.03,21.14 167.56,21.61 167.56,23.21 166.32,24.46 166.32,24.91 166.14,25.09 165.99,25.09 163.88,27.2 162.23,27.2 161.97,27.45 156.94,27.45 v1(156.56,27.07) 156.46,26.97 153.64,26.97 153.26,26.59 151.59,26.59 v2(150.92,25.93)
  BOTTOM w0.102: v2(59.41,64.84) RU152.1
EC_BEEP: length 41.9
  TOP w0.076: v2(162.92,12.49) 162.86,12.55 162.86,13.94 162.97,14.05 UE1.N6
  TOP w0.102: v1(177.29,32.69) 177.19,32.79 RA3.2
  ART03 w0.089: v1(175.82,14.35) 175.18,14.35 174.5,15.03 174.5,21.79 173.78,22.5 172.9,22.5 171.45,23.95 171.45,28.27 172.34,29.16 172.59,29.16 173.23,29.79 173.23,30.05 175.87,32.69 v1(177.29,32.69)
  ART06 w0.102: v2(162.92,12.49) 163.52,11.88 164.03,11.88 165.12,12.98 166.55,12.98 167.64,11.88 172.29,11.88 174.75,14.35 v1(175.82,14.35)
EC_DEBUG_CLK: length 1.8
  TOP w0.102: RE3.1 RE134.1 171.4,18.31 TPE1.1
EC_DEBUG_DATA: length 2.1
  TOP w0.102: RE135.1 RE4.1 164.08,25.09 TPE2.1
EC_EDP_BKLT_EN: length 225.3
  TOP w0.076: UE1.D13 166.81,18.74 167.17,18.39 167.54,18.39 167.9,18.76
  TOP w0.102: 167.9,18.76 168.17,19.02 168.65,19.02 v1(168.96,18.72)
  ART03 w0.089: v1(168.96,18.72) 168.96,16.58 168.55,16.18 168.55,15.05 168.91,14.69 168.91,8.07 168.27,7.44 168.27,6.04 166.65,4.42 156.77,4.42 155.27,5.92 153.43,5.92 152.85,5.34 150.09,5.34 149.4,4.66 148.56,4.66 147.85,3.94 145.43,3.94 144.66,4.71 136.03,4.71 133.74,2.42 112.36,2.42 109.88,4.9 106.6,4.9 v2(105.56,5.94)
  ART05 w0.102: v2(105.56,5.94) 104.82,6.68 102.11,6.68 101.67,7.11 89.13,7.11 88.03,8.2 65.94,8.2 63.75,6.02 49.08,6.02 48.9,6.2 42.69,6.2 39.64,9.24 35.99,9.24 32.76,12.47 32.76,14.93 33.15,15.31 33.15,21.16 31.52,22.78 31.52,28.66 30.71,29.47 30.71,35.66 28.73,37.64 28.73,41.96 28.32,42.36 28.32,44.09 27.63,44.78 27.63,47.52 27.2,47.95 27.2,57.07 26.41,57.86 26.41,59.26 26.16,59.51 26.16,64.77 27.46,66.06 27.46,71.63 v1(28.07,72.24)
  BOTTOM w0.102: v1(28.07,72.24) 28.04,72.21 RX21.1
EC_FLASH_SPI_CLK: length 64.7
  TOP w0.075: 162.22,20.09 162.47,19.84 UE1.B5
  TOP w0.076: 162.22,20.98 162.22,20.09
  TOP w0.102: v2(132.69,13.66) 132.64,13.61 RO9.1 ; v2(161.8,21.41) 162.22,20.98
  ART05 w0.102: v2(152.17,22.22) 151.64,22.22 151.48,22.07 151.48,21.87 151.36,21.74 151.13,21.74 151.03,21.85 151.03,22.58 150.92,22.68 150.67,22.68 150.57,22.58 150.57,21.49 150.47,21.39 150.21,21.39 150.11,21.49 150.11,23.04 150.01,23.14 148.89,23.14 148.28,23.75 146.96,23.75 144.91,21.69 142.77,21.69 140.87,19.78 140.87,18.62 137.06,14.81 137.06,14.15 136.57,13.66 v2(132.69,13.66)
  ART06 w0.102: v1(139.32,24.33) 139.9,23.75 139.9,16.53 138.53,15.16 138.53,14.91 138.12,14.5 137.26,14.5 137.06,14.3 137.06,14.09 136.7,13.74 132.76,13.74 v2(132.69,13.66) ; v2(152.17,22.22) 152.75,22.22 154.33,23.8 156.82,23.8 157.05,23.57 161.03,23.57 161.29,23.31 162.43,23.31 162.63,23.11 162.63,21.99 162.05,21.41 v2(161.8,21.41)
  BOTTOM w0.102: v3(139.6,25.88) 139.6,24.76 139.32,24.48 v1(139.32,24.33) 139.06,24.33 138.81,24.58 RE37.1
EC_FLASH_SPI_CS0_N: length 51.9
  TOP w0.076: UE1.A7 163.47,21.62 v1(163.83,21.97)
  TOP w0.102: RE32.1 141.1,15.34 141.1,14.45 140.56,13.92 140.56,13.59 140.26,13.28 v2(140.16,13.28) 140.16,13.48 v3(139.58,14.06) 139.39,14.25 138.78,14.25 137.87,13.33 137.11,13.33 136.9,13.13 135.74,13.13 134.26,11.66 134.26,11.3 132.69,9.73 RO10.1
  ART06 w0.102: v1(163.83,21.97) 163.83,22.02 163.5,22.35 163.5,23.57 162.89,24.18 161.57,24.18 161.39,24.36 157.48,24.36 156.31,25.52 155.88,25.52 154.99,24.64 153.86,24.64 152.77,23.54 150.32,23.54 149.86,23.09 149.25,23.09 148.79,22.63 148.79,18.21 149.2,17.8 149.2,16.63 147.22,14.65 146.81,14.65 145.97,15.49 143.74,15.49 141.91,13.66 140.69,13.66 140.31,13.28 v2(140.16,13.28)
EC_FLASH_SPI_MISO: length 50.3
  TOP w0.075: 162.97,20.41 UE1.A6
  TOP w0.076: v2(162.94,21.41) 162.94,21.17 162.97,21.14 162.97,20.41
  TOP w0.102: RE35.2 138.58,16.08 138.33,15.82 138.33,14.81 137.67,14.15 v2(137.51,14.15) 137.46,14.15 v3(136.89,14.72) 136.7,14.91 132.18,14.91 131.7,14.42 131.7,11.38 RO13.1
  ART06 w0.102: v2(162.94,21.41) 162.94,21.61 163.12,21.79 163.12,23.42 162.71,23.82 161.42,23.82 161.24,24 157.27,24 156.56,24.71 155.65,24.71 155.22,24.28 154.13,24.28 152.55,22.71 152.04,22.71 150.62,21.28 150.62,20.75 150.26,20.39 150.26,18.69 149.55,17.98 149.55,16.48 147.37,14.3 146.66,14.3 145.82,15.14 143.99,15.14 141.98,13.13 141.32,13.13 141.1,12.9 138.45,12.9 137.51,13.84 v2(137.51,14.15)
EC_FLASH_SPI_MOSI: length 66.4
  TOP w0.076: UE1.B6 162.72,19.99 162.72,21.12 162.58,21.26 162.58,21.94 162.28,22.25 v1(161.9,22.25)
  TOP w0.102: RO14.1 132.99,12.6 132.99,13.23 133.09,13.33 133.09,14.04 v1(132.97,14.17)
  ART06 w0.102: v1(161.9,22.25) 161.52,22.25 160.58,23.19 156.75,23.19 156.62,23.31 155.07,23.31 152.78,21.03 151.89,21.03 151.64,20.77 151.64,20.07 150.82,19.25 150.82,17.85 150.11,17.14 150.11,16.53 147.47,13.89 146.56,13.89 146.4,13.74 146.4,13.1 146.28,12.98 146.07,12.98 145.95,13.1 145.95,14.3 145.84,14.4 145.59,14.4 145.49,14.3 145.49,12.88 145.39,12.77 145.13,12.77 145.03,12.88 145.03,14.09 144.93,14.2 144.68,14.2 144.57,14.09 144.57,12.82 144.42,12.67 143.71,12.67 143.61,12.77 143.61,13.28 143.51,13.38 143.25,13.38 143.15,13.28 143.15,12.77 143.05,12.67 141.88,12.67 141.76,12.55 137.6,12.55 136.59,13.55 133.23,13.55 132.97,13.28 132.46,13.28 132.33,13.41 132.33,13.82 132.69,14.17 v1(132.97,14.17) 133.68,14.88 136.73,14.88 137.41,15.57 137.77,15.57 138.96,16.76 138.96,22.63 v2(137.29,24.31)
  BOTTOM w0.102: RE34.2 137.77,25.22 137.29,24.74 v2(137.29,24.31)
EC_IMVP_PWRGD: length 104
  TOP w0.076: UE1.A13 166.73,20.24 167.24,20.75 168.6,20.75 CE46.1
  TOP w0.102: v3(109.73,15.92) v2(109.73,16.46) PR659.1 ; v2(168.81,19.53) RE452.1 CE46.1
  ART06 w0.102: v2(168.81,19.53) 168.4,19.12 167.51,19.12 167.38,19.25 166.62,19.25 165.99,19.89 161.75,19.89 160.44,21.19 158.02,21.19 157.22,20.39 157.22,19.43 156.77,18.97 156.77,17.8 156.56,17.6 155.5,17.6 155.19,17.29 154.38,17.29 153.44,16.36 153.44,15.39 149.42,11.38 148.59,11.38 147.83,10.61 143.89,10.61 143.71,10.44 136.38,10.44 135.97,10.84 129.36,10.84 128.65,10.13 111.73,10.13 v2(110.87,11)
  BOTTOM w0.102: QU7.1 107.71,33.13 108.41,32.43 108.81,32.43 108.91,32.33 108.91,30.88 107.01,28.98 106.12,28.98 105.61,28.47 105.61,28.01 104.42,26.82 104.42,25.25 105.36,24.31 110.59,24.31 110.95,23.95 110.95,22.12 110.64,21.82 110.64,20.44 109.93,19.73 109.93,18.31 110.64,17.6 110.64,16.74 110.39,16.48 109.75,16.48 v2(109.73,16.46) 109.73,16.08 109.85,15.95 109.85,12.01 v2(110.87,11)
EC_ME_UNLOCK: length 197.8
  TOP w0.076: UE1.C12 165.97,19.32 166.22,19.57 166.22,19.88 166.34,19.99 167.09,19.99 167.36,20.27 167.38,20.27 167.49,20.37 v2(167.51,20.37)
  ART05 w0.102: v1(59.18,84.66) 58.8,84.27 58.8,81.1 58.42,80.72 58.42,74.47 53.19,69.24 53.19,59 53.08,58.9 53.08,58.11 52.58,57.6 52.37,57.6 52.12,57.35 52.12,55.01 52.5,54.63 52.5,52.98 52.88,52.6 52.88,50.16 53.19,49.86 53.19,36.09 60.88,28.39 76.58,28.39 78.08,29.89 84.26,29.89 85.6,28.55 95.27,28.55 96.16,27.66 98.25,27.66 100.99,24.91 100.99,18.11 103.93,15.16 105.36,15.16 107.54,12.98 110.28,12.98 110.86,12.41 111.62,12.41 112.6,11.43 126.72,11.43 130.4,15.11 136.09,15.11 139.72,18.74 139.72,20.52 142.64,23.44 143.09,23.44 146.18,26.54 v2(147.32,26.54)
  ART06 w0.102: v2(167.51,20.37) 167.31,20.57 167.31,23.14 166.5,23.95 165.1,23.95 164.72,24.33 164.72,24.97 163.9,25.78 160.7,25.78 159.23,27.25 157.43,27.25 156.87,26.69 153.67,26.69 152.45,25.47 148.69,25.47 147.62,26.54 v2(147.32,26.54)
  BOTTOM w0.102: RU125.2 v1(59.18,84.66)
EC_MUTE_N: length 16.1
  TOP w0.076: UE1.E12 165.97,18.39 166.22,18.63 166.22,18.83 166.38,18.99 167.11,18.99 v1(167.33,18.77)
  TOP w0.102: DA2.2 164.09,29.02 163.83,29.28 v1(163.83,29.64)
  ART03 w0.089: v1(163.83,29.64) 163.83,29.28 163.99,29.13 163.99,24.35 164.75,23.58 166.32,23.58 166.88,23.02 166.88,20.39 167.18,20.09 167.18,18.92 v1(167.33,18.77)
EC_OVT_N: length 91.7
  TOP w0.076: v2(163.4,13.69) 163.47,13.76 UE1.N7
  ART05 w0.102: v2(163.4,13.69) 164.39,14.68 165.61,14.68 166.24,15.31 166.24,16.84 168.53,19.12 168.91,19.12 169.04,19.25 169.64,19.25 170.31,19.91 170.31,21.82 169.31,22.81 166.88,22.81 165.86,23.82 165.06,23.82 163.16,25.73 161.52,25.73 161.42,25.83 161.42,28.43 v2(160.78,29.06)
  ART06 w0.102: v2(160.78,29.06) 160.48,29.37 160.48,30.76 161.42,31.7 161.42,35 159.05,37.36 159.05,43.33 156.08,46.3 156.08,48.97 155.42,49.63 147.5,49.63 147.09,49.22 143.64,49.22 142.75,50.11 140.54,50.11 139.9,49.48 138.94,49.48 138.5,49.91 133.64,49.91 132.84,50.71 132.84,51.51 132.08,52.27 132.08,53.41 132.46,53.79 132.46,58.49 131.19,59.76 131.19,62.38 v1(130.55,63.01)
  BOTTOM w0.102: RV244.1 133.16,63.96 132.64,64.49 v3(132.23,64.49) 130.76,63.01 v1(130.55,63.01)
EC_PWRSW: length 4.6
  TOP w0.076: 162.14,21.83 162.3,21.66 162.3,21.16 162.47,20.99 UE1.A5
  TOP w0.102: RE2.2 160.27,23.51 161.49,22.29 161.49,21.97 161.63,21.83 162.14,21.83
EC_RTCRST: length 284.2
  TOP w0.102: RE125.2 156.51,20.19 v2(156.41,20.09)
  ART06 w0.102: v1(47.65,72.31) 45.67,72.31 37.77,80.21 28.95,80.21 27.68,81.48 26.34,81.48 24.64,79.78 21.92,79.78 16,73.86 16,72.21 13.84,70.05 13.84,65.86 14.86,64.84 14.86,61.03 16.08,59.81 16.08,57.02 16.38,56.72 16.38,47.44 17.93,45.9 17.93,42.21 19.3,40.84 19.3,33.33 17.02,31.04 17.02,14.93 16.13,14.04 16.13,7.82 18.34,5.61 18.97,5.61 19.3,5.28 19.3,3.76 21.59,1.47 46.1,1.47 48.33,3.71 69.37,3.71 70.31,4.65 93.09,4.65 95.12,2.61 114.65,2.61 116.81,4.77 144.65,4.77 145.03,4.39 147.06,4.39 v2(147.57,4.9)
  BOTTOM w0.102: v1(47.65,72.31) 48.92,71.04 v3(51.1,71.04) 52.53,71.04 53.03,70.53 53.03,64.79 54.13,63.7 RU90.2 55.12,63.7 55.2,63.78 QU2.1 ; v2(147.57,4.9) 148.28,4.9 150.09,6.7 150.09,8.94 150.82,9.67 152.25,9.67 153.08,10.51 154.23,10.51 155.19,11.48 155.19,13.79 155.95,14.55 155.95,17.35 156.26,17.65 156.67,17.65 156.87,17.85 156.87,19.63 v2(156.41,20.09)
EC_SCI_N: length 13.8
  TOP w0.076: 161.8,13.03 161.69,13.13 161.69,13.55 161.97,13.83 UE1.N4
  TOP w0.102: RE86.1 155.34,6.47 155.69,6.82 DE5.1 155.69,7.54 155.79,7.64 157.33,7.64 v3(159.21,9.53) 159.37,9.53 160.02,10.18 160.6,10.18 161.8,11.38 161.8,13.03 ; RE86.1 RE87.2 ; RE86.1 RE81.2
EC_SLP_S0_CS_N: length 185.4
  TOP w0.102: RE459.2 168.04,24.08 v1(167.51,24.61) ; v2(62.89,48.16) 62.89,47.68 61.85,46.63 61.85,46.43 61.72,46.3 RU59.2 RU51.1 61.72,44.12 v3(61.82,44.02) 61.85,43.99 v1(61.85,40.71) ; RI153.2 v2(25.78,58.87)
  ART03 w0.089: v2(32.13,41.53) 32.1,41.53 31.98,41.65 29.69,41.65 26.82,44.52 26.82,46.66 26.41,47.06 26.41,47.83 26.8,48.21 26.8,50.37 27.21,50.79 27.21,56.12 26.91,56.43 26.91,57.74 v2(25.78,58.87)
  ART05 w0.102: v1(61.85,40.71) 61.85,38.68 66.93,33.6 94.26,33.6 96.52,31.34 102.23,31.34 102.77,31.87 109.52,31.87 110.59,32.94 112.11,32.94 112.77,33.6 125.12,33.6 127.3,31.42 132.28,31.42 134.11,29.59 143.1,29.59 144.78,31.26 v2(144.78,31.32)
  ART06 w0.102: v2(62.89,48.16) 62.33,47.6 60.3,47.6 59.27,48.63 53.43,48.63 51.89,47.09 50.47,47.09 48.92,45.54 47.5,45.54 46.73,44.78 46.73,44.12 44.47,41.86 32.46,41.86 v2(32.13,41.53) ; v1(167.51,24.61) 166.9,25.22 166.37,25.22 164.18,27.4 162.41,27.4 162.15,27.66 156.46,27.66 155.98,27.18 154.04,27.18 152.59,28.62 147.47,28.62 v2(144.78,31.32)
  BOTTOM w0.102: UU1.DT12 64.55,48.21 62.94,48.21 v2(62.89,48.16)
EC_SLP_SX_N: length 239.4
  TOP w0.076: v2(163.84,21.41) 163.72,21.29 163.72,20 UE1.B8
  TOP w0.102: PR930.1 188.31,21.66 v2(188.54,21.44)
  ART03 w0.089: v2(108.81,5.97) 109.01,5.76 114.61,5.76 115.47,4.9 134.26,4.9 135.41,6.04 148.9,6.04 149.53,6.68 152.3,6.68 152.88,7.26 154.91,7.26 155.22,7.57 157.45,7.57 158.87,6.14 161.7,6.14 162.51,6.96 162.51,7.76 163.83,9.08 163.83,9.85 v2(164.34,10.36) 165.16,11.19 165.16,13.81 166.25,14.9 166.25,19.34 164.92,20.67 164.92,20.95 164.56,21.31 163.95,21.31 v2(163.84,21.41) ; v1(31.11,45.54) 31.54,45.97 31.54,50.16 33.12,51.74 33.12,56.44 36.19,59.51 v1(36.19,60.78)
  ART05 w0.102: v2(164.34,10.36) 165.23,10.36 169.67,14.81 v2(169.67,15.06) ; v2(108.81,5.97) 108.81,7.24 106.61,9.44 88.81,9.44 88.62,9.62 73.83,9.62 73.22,10.23 57.23,10.23 55.3,8.3 43.08,8.3 41.6,9.78 41.6,10.67 35.38,16.89 35.38,36.83 34.03,38.17 31.56,38.17 30.78,38.95 30.78,43.24 30.66,43.36 30.66,45.08 v1(31.11,45.54)
  ART06 w0.102: v2(169.67,15.06) 171.45,15.06 173.99,17.6 182.24,17.6 185.67,21.03 188.14,21.03 v2(188.54,21.44)
  BOTTOM w0.102: PR413.1 36.12,60.86 v1(36.19,60.78) ; PR914.2 29.92,46.05 29.77,46.2 29.77,46.76 30.27,47.27 v3(30.27,47.47) ; PR914.2 30.61,46.05 v1(31.11,45.54) ; PR914.2 PR912.1
EC_STRAP: length 7.5
  TOP w0.076: v2(163.47,17.8) UE1.E7
  TOP w0.102: v1(162.23,22.91) 162.23,23.37 RE121.1 RE120.1
  BOTTOM w0.102: v2(163.47,17.8) 163.17,18.11 163.17,19.78 163.42,20.04 163.42,21.71 v1(162.23,22.91)
EC_USB2P0_EN: length 73.2
  TOP w0.076: UE1.D2 160.97,18.83 160.73,19.07 160.73,19.43 160.66,19.49 159.61,19.49 v2(159.43,19.68)
  ART03 w0.076: v1(184.76,48.99) 185.16,49.4 185.72,49.4 189.69,45.44 189.69,22.02 185.52,17.85 185.52,17.6 v1(183.87,15.95)
  ART06 w0.102: v1(183.87,15.95) 179.33,15.95 178.05,14.68 177.04,14.68 176.02,15.69 173.99,15.69 171.68,13.38 168.06,13.38 167.15,14.3 162.69,14.3 162.24,14.74 161.35,14.74 161.03,15.06 161.03,19 160.65,19.38 159.97,19.38 159.67,19.68 v2(159.43,19.68)
  BOTTOM w0.102: JDB1.7 184.55,49.2 v1(184.76,48.99)
EC_USBPWR1_EN: length 183.2
  TOP w0.076: v2(160.02,18.97) 160.04,18.99 160.56,18.99 160.72,18.83 160.72,18.49 UE1.E2
  TOP w0.102: RB44.2 v1(26.16,40.71)
  ART03 w0.089: v2(159.38,11.48) 158.72,12.14 157.81,12.14 156.92,13.03 156.08,13.03 155.45,12.39 155.45,11.77 154.86,11.19 154.25,11.19 152.38,9.32 148.94,9.32 148.59,9.67 v2(148.59,10.08)
  ART05 w0.102: v2(148.59,10.08) 148.59,8.96 146.99,7.36 142.37,7.36 141.83,7.9 131.3,7.9 129.77,6.37 116.74,6.37 114.4,4.04 110.75,4.04 109.81,4.98 103,4.98 102.21,5.76 101.65,5.76 101.12,6.3 82.03,6.3 80.94,7.39 67.78,7.39 66.93,6.54 65.44,6.54 64.05,5.15 48.79,5.15 48.56,5.38 42.12,5.38 39.08,8.43 35.53,8.43 31.75,12.22 31.75,15.44 32.13,15.82 32.13,20.65 29.89,22.88 29.89,35.05 26.54,38.4 26.54,40.33 v1(26.16,40.71)
  ART06 w0.102: v2(160.02,18.97) 160.32,18.67 160.32,14.4 160.02,14.09 160.02,12.11 v2(159.38,11.48)
  BOTTOM w0.127: v3(147.17,8.46) 147.17,8.91 147.57,9.32 147.98,9.32 148.59,9.93 v2(148.59,10.08)
EC_USBPWR1_EN_R: length 3
  TOP w0.102: UB6.5 26.4,38.42 27.38,39.39 CB36.1 RB47.1 RB44.1
EC_VCCST_PWRGD: length 113
  TOP w0.076: v2(163.85,12.98) 163.97,13.1 UE1.N8
  ART05 w0.102: v2(81.21,36.65) 81.59,36.27 94.77,36.27 96.59,34.44 101.42,34.44 101.85,34.87 108.33,34.87 108.76,35.3 108.76,36.24 109.29,36.78 114.98,36.78 118.84,40.64 125.12,40.64 126.9,38.86 126.9,35.56 128.12,34.34 129.26,34.34 130.27,33.32 135.71,33.32 136.45,34.06 137.21,34.06 138.28,32.99 139.09,32.99 139.93,32.15 143.91,32.15 144.09,32.33 152.32,32.33 153.41,31.23 153.41,25.98 155.45,23.95 156.64,23.95 159.33,21.26 160.42,21.26 161.8,19.89 161.8,19.17 162.43,18.54 162.43,16.51 163.12,15.82 163.93,15.82 164.13,15.62 164.13,14.81 163.47,14.15 163.17,14.15 162.91,13.89 162.91,13.57 163.56,12.93 163.8,12.93 v2(163.85,12.98)
  BOTTOM w0.102: RU166.1 80.88,34.16 81.36,34.64 DU1.1 81.16,35.46 81.16,36.6 v2(81.21,36.65)
EC_VCCSTG_EN: length 175.1
  TOP w0.076: UE1.C13 167.42,19.24 167.49,19.17 167.94,19.17
  TOP w0.102: 167.94,19.17 v2(168.27,19.5)
  ART05 w0.102: v2(147.42,25.37) 145.64,25.37 144.02,23.76 144.02,22.49 143.71,22.17 142.39,22.17 140.33,20.11 140.33,18.78 136.41,14.86 131.16,14.86 127.53,11.22 112.52,11.22 111.54,12.2 105.63,12.2 105.37,11.95 85.77,11.95 83.61,14.11 83.61,27.5 81.47,29.64 78.33,29.64 76.83,28.14 60.75,28.14 52.96,35.94 52.96,49.55 52.65,49.86 52.65,52.12 51.59,53.19 51.59,54.94 51.92,55.27 51.92,57.58 v1(52.32,57.99)
  ART06 w0.102: v2(147.42,25.37) 147.47,25.32 147.52,25.32 147.57,25.27 152.55,25.27 153.77,26.49 157.07,26.49 157.63,27.05 159.15,27.05 160.62,25.58 163.6,25.58 164.21,24.97 164.21,24.2 164.72,23.7 166.37,23.7 167.03,23.04 167.03,20.24 167.38,19.89 168.02,19.89 168.27,19.63 v2(168.27,19.5)
  BOTTOM w0.102: v1(52.32,57.99) 51.97,57.99 51.51,58.44 PR919.1 PR910.1
EC_VDDQ_EN: length 235.6
  TOP w0.076: UE1.A8 163.97,21.05 164.45,21.52 164.45,21.7 v2(164.89,22.15)
  ART03 w0.089: v2(164.89,22.15) 165.25,21.79 165.25,20.62 166.45,19.42 166.45,14.84 165.35,13.73 165.35,10.58 164.08,9.31 164.08,9.01 162.71,7.64 162.71,6.82 161.83,5.95 158.79,5.95 158.13,6.61 156.59,6.61 156.14,7.07 152.96,7.07 152.38,6.49 149.61,6.49 148.98,5.85 135.49,5.85 134.33,4.7 115.41,4.7 114.56,5.55 108.62,5.55 v2(108.2,5.97)
  ART05 w0.102: v2(108.2,5.97) 105.14,9.03 88.64,9.03 88.45,9.22 73.66,9.22 73.05,9.83 57.39,9.83 55.46,7.9 42.87,7.9 40.89,9.88 40.89,10.39 40,11.28 38.26,11.28 37.72,11.82 37.72,13.41 34.62,16.51 34.62,33.91 34.03,34.49 33.4,34.49 32.76,35.13 32.76,35.89 30.17,38.48 30.17,42.8 30.04,42.93 30.04,49.91 28.95,51 28.95,55.67 30.25,56.96 30.25,57.58 31.6,58.92 31.6,60.93 37.23,66.57 37.23,79.42 38.35,80.54 38.35,83.67 39.8,85.11 v1(40.79,85.11)
  BOTTOM w0.102: v1(40.79,85.11) 41.25,85.57 PR709.1
EC_VPP_EN: length 14.6
  TOP w0.102: v2(164.1,19.19) 163.97,19.07 UE1.D8 ; v1(160.53,9.29) 160.35,9.29 159.61,8.56 TPE106.1
  ART03 w0.089: v2(164.1,19.19) 164.07,19.17 164.07,18.75 164.62,18.21 164.62,16.1 164.13,15.62 164.13,13.84 163.45,13.15 163.45,11.28 163.12,10.94 162,10.94 160.75,9.7 160.75,9.52 v1(160.53,9.29)
EC_WRST_N: length 170
  TOP w0.076: 158.34,14.3 158.37,14.27 159.38,14.27 160.35,15.24 UE1.L1
  TOP w0.102: 158.34,14.3 157.63,14.3 CE40.1 RE118.2 157.43,15.21 157.3,15.34 156.13,15.34 155.85,15.62 155.85,16.01 DE6.2 155.19,15.63 155.19,11.12 154.81,10.74 154.81,8.58 154.68,8.46 153.63,8.46 v3(149.63,4.45) 149.35,4.17 v2(149.35,3.5)
  ART06 w0.102: v1(14.1,12.93) 14.45,12.93 15.42,11.96 15.42,7.74 18.13,5.02 18.13,4.26 21.43,0.96 48.36,0.96 49.45,2.05 71.93,2.05 73.91,4.04 91.39,4.04 93.68,1.75 114.76,1.75 117.06,4.05 144.33,4.05 144.88,3.5 v2(149.35,3.5)
  BOTTOM w0.102: RL46.1 14.45,13.28 v1(14.1,12.93)
EDP_AUX_C_DN: length 0.9
  BOTTOM w0.102: RX904.1 29.48,72.39 29.48,71.9 CX8.2
EDP_AUX_C_DP: length 1
  BOTTOM w0.102: RX905.1 29.7,72.34 29.7,71.9 CX7.2
EDP_AUX_CONN_DN: length 2.3
  BOTTOM w0.102: JX1.27 29.2,74.63 29.34,74.49 29.34,74.06 29.48,73.92 29.48,73.24 RX904.2
EDP_AUX_CONN_DP: length 2.3
  BOTTOM w0.102: RX905.2 29.7,73.3 29.7,74.01 29.56,74.15 29.56,74.46 29.7,74.61 JX1.28
EDP_AUX_SOC_DN: length 164.1
  ART06 w0.102: v1(30.27,69.54) 30.45,69.36 30.45,69.2 29.15,67.89 28.19,67.89 27.41,67.11 27.41,66.48 24.38,63.45 24.38,60.91 22.9,59.42 22.9,49.39 23.09,49.2 23.09,45.89 23.79,45.2 23.79,39.99 23.89,39.89 23.89,38.82 24.04,38.67 24.04,36.33 24.78,35.6 24.78,31.84 25.47,31.14 25.47,28.45 24.5,27.47 24.5,26.43 25.63,25.3 25.63,21.71 26.69,20.65 26.97,20.65 30.1,17.52 31.79,17.52 35.28,14.03 39.23,14.03 39.95,13.31 41.43,13.31 41.76,13.64 44.55,13.64 45.59,14.68 45.59,15.31 45.92,15.64 49.65,15.64 50.15,15.15 50.99,15.15 52.73,16.89 52.73,17.29 54.66,19.22 54.66,22.12 54.98,22.44 66.05,22.44 66.28,22.67 74.45,22.67 74.87,22.25 79.99,22.25 82.8,25.06 82.8,27.3 82.51,27.6 82.51,29.75 84.88,32.13 94.56,32.13 95.07,31.62 101.93,31.62 104.52,34.21 104.52,35.81 103.76,36.57 103.76,37.25 v2(103.97,37.46)
  BOTTOM w0.076: v2(103.97,37.46) 103.76,37.67 103.76,37.92 102.87,38.81 102.87,42.72 103.07,42.92 103.07,43.13 UU1.W4
  BOTTOM w0.102: CX8.1 29.48,71.1 29.48,70.85 29.73,70.6 30.13,70.6 30.39,70.34 30.39,69.66 v1(30.27,69.54)
EDP_AUX_SOC_DP: length 164
  ART06 w0.102: v2(103.38,37.46) 103.54,37.3 103.54,36.48 103.75,36.27 103.75,36.07 103.94,35.89 104.14,35.89 104.3,35.72 104.3,34.3 104.12,34.12 103.97,34.12 103.76,33.91 103.76,33.76 103.55,33.55 103.4,33.55 103.19,33.34 103.19,33.18 101.84,31.84 95.16,31.84 94.65,32.34 84.8,32.34 82.29,29.84 82.29,27.51 82.59,27.21 82.59,25.15 79.9,22.46 74.96,22.46 74.54,22.88 66.19,22.88 65.96,22.65 54.89,22.65 54.44,22.21 54.44,19.31 52.51,17.38 52.51,16.98 50.9,15.36 50.24,15.36 49.74,15.86 45.83,15.86 45.38,15.4 45.38,14.77 44.46,13.85 41.67,13.85 41.34,13.52 40.04,13.52 39.32,14.25 35.37,14.25 31.88,17.74 30.19,17.74 27.06,20.86 26.77,20.86 25.84,21.8 25.84,25.39 24.71,26.52 24.71,27.38 25.69,28.36 25.69,31.23 24.99,31.93 24.99,35.68 24.26,36.42 24.26,38.76 24.1,38.91 24.1,39.98 24,40.08 24,45.29 23.3,45.98 23.3,49.29 23.11,49.48 23.11,59.33 24.6,60.82 24.6,63.36 25.28,64.04 25.51,64.04 25.68,64.21 25.68,64.44 25.86,64.62 26.09,64.62 26.26,64.79 26.26,65.02 26.43,65.19 26.66,65.19 26.83,65.36 26.83,65.59 27.01,65.77 27.23,65.77 27.41,65.94 27.41,66.17 27.63,66.39 27.63,67.02 28.28,67.68 29.24,67.68 29.54,67.97 29.72,67.97 29.92,68.17 29.92,68.35 30.11,68.55 30.3,68.55 30.49,68.74 30.49,68.93 30.67,69.11 30.67,69.35 v1(30.86,69.54)
  BOTTOM w0.076: UU1.W3 102.79,42.87 102.7,42.78 102.7,40.05 102.59,39.94 102.59,39.75 102.7,39.63 102.7,39.44 102.59,39.33 102.59,39.14 102.7,39.02 102.7,38.74 102.98,38.46 102.98,38.26 103.1,38.14 103.3,38.14 103.59,37.85 103.59,37.67 v2(103.38,37.46)
  BOTTOM w0.102: v1(30.86,69.54) 30.61,69.8 30.61,70.43 30.22,70.81 29.82,70.81 29.7,70.94 29.7,71.1 CX7.1
EDP_BKLT_EN: length 201
  TOP w0.076: v2(167.64,19.53) 167.6,19.49 166.38,19.49 166.21,19.32 166.21,19.09 165.97,18.86 UE1.D12
  TOP w0.102: v1(32.38,76.27) 30.99,74.88 30.99,73.73 v3(30.23,72.98) v1(28.07,70.81)
  ART03 w0.089: v2(150.57,24.71) 149.63,25.65 149.27,25.65 147.93,27 147.11,27 145.59,28.52 137.01,28.52 136.5,29.03 136.5,29.33 136.19,29.64 135.79,29.64 135.38,30.05 135.38,31.62 133.7,33.3 126.74,33.3 125.73,34.31 116.74,34.31 115.62,33.2 110.69,33.2 108.41,30.91 96.42,30.91 96.09,31.24 95.58,31.24 94.05,32.76 84.5,32.76 84.33,32.59 75.18,32.59 73.91,31.32 73.02,31.32 72.64,31.7 70.43,31.7 69.39,30.66 66.83,30.66 64.08,33.4 64.08,39.56 64.77,40.26 64.77,41.86 64.26,42.36 64.26,46.68 65.41,47.83 65.41,49.91 65.68,50.19 66.37,50.19 67.1,50.92 v2(67.1,51.49)
  ART06 w0.102: v2(150.57,24.71) 150.98,24.31 152.37,24.31 154.35,26.29 158.18,26.29 158.81,25.66 160.24,25.66 160.54,25.37 163.42,25.37 163.96,24.84 163.96,24.08 164.64,23.39 166.29,23.39 166.75,22.93 166.75,20.04 167.26,19.53 v2(167.64,19.53) ; v1(32.38,76.27) 32.76,75.89 34.44,75.89 36.15,74.18 38.23,74.18 41.4,71.01 41.4,69.52 45.16,65.76 45.46,65.76 49.25,61.97 49.25,60.5 52.12,57.63 52.12,55.19 52.53,54.79 52.53,53.01 53.19,52.35 53.59,52.35 54.05,51.89 54.05,51.05 54.38,50.72 55.8,50.72 56.61,51.53 63.96,51.53 64.39,51.1 66.71,51.1 v2(67.1,51.49)
  BOTTOM w0.102: UU1.DL19 67.1,51.33 v2(67.1,51.49) ; v1(28.07,70.81) 27.94,70.94 27.94,71.45 27.68,71.7 RX25.1
EDP_BKLT_LS_EN: length 4.6
  BOTTOM w0.102: RX17.1 RX25.2 RX21.2 CX22.1 RX22.2 27.05,73.48 27.18,73.61 27.18,73.61 27.56,73.61 27.94,73.99 27.94,74.5 27.7,74.73 JX1.24
EDP_BKLT_PWM: length 56.7
  ART06 w0.102: v1(31.49,76.27) 32.13,75.64 34.4,75.64 36.07,73.98 38.14,73.98 41.18,70.94 41.18,68.31 44.09,65.4 45.46,65.4 49.02,61.85 49.02,60.37 51.92,57.48 51.92,55.5 51.66,55.24 51.66,53.11 52.68,52.09 52.68,50.82 52.98,50.52 56.23,50.52 56.54,50.82 61.14,50.82 v2(61.44,51.13)
  BOTTOM w0.076: UU1.DU19 64.2,51.51 63.37,51.51 63.19,51.69 62,51.69 v2(61.44,51.13)
  BOTTOM w0.102: v1(31.49,76.27) 31.37,76.4 28.95,76.4 28.2,75.65 JX1.25 28.2,73.98 28.57,73.61 RX16.2
EDP_HPD: length 79.2
  TOP w0.102: ESDX1.1 27.31,74.81 RX18.2 27.3,74.24 v1(27.43,74.11) 27.43,73.68 v3(27.53,73.58)
  ART03 w0.089: v1(27.43,74.11) 28.07,74.11 30.17,72.01 37.89,72.01 39.57,70.33 45.11,70.33 46.4,69.03 53.41,69.03 55.22,70.84 57.86,70.84 58.81,69.88 58.81,68.94 60.67,67.08 62.13,67.08 62.3,67.26 67.74,67.26 70.69,64.31 70.69,63.4 70.94,63.14 70.94,62.15 70.66,61.87 70.43,61.87 69.34,60.78 69.34,60.37 69.11,60.14 68.15,60.14 67.97,59.97 67.97,58.85 67,57.88 64.82,57.88 64.36,57.43 64.36,56.77 62.41,54.82 62.41,53.23 62.61,53.03 62.61,52.61 61.89,51.89 61.67,51.89 61.09,51.31 61.09,48.47 61.03,48.41 61.03,46.76 v2(61.09,46.71)
  BOTTOM w0.102: v1(27.43,74.11) 27.2,74.35 JX1.23 ; v2(61.09,46.71) 61.09,46.81 61.47,47.19 61.97,47.19 62,47.22 UU1.DW11
EDP_TX0_C_DN: length 0.9
  BOTTOM w0.102: CX6.2 30.95,71.9 30.95,72.39 CHKX6.1
EDP_TX0_C_DP: length 1
  BOTTOM w0.102: CHKX6.2 31.17,72.34 31.17,71.9 CX5.2
EDP_TX0_CONN_DN: length 2.3
  BOTTOM w0.102: CHKX6.4 30.95,73.24 30.95,73.97 30.84,74.08 30.84,74.41 30.7,74.55 JX1.30
EDP_TX0_CONN_DP: length 2.3
  BOTTOM w0.102: CHKX6.3 31.17,73.3 31.17,74.06 31.06,74.17 31.06,74.41 31.2,74.55 JX1.31
EDP_TX0_SOC_DN: length 150.9
  ART06 w0.102: v2(101.6,40.8) 101.42,40.62 101.03,40.62 100.19,39.78 100.19,37.54 98.16,35.52 94.48,35.52 93.92,34.96 83.71,34.96 76.85,28.1 75.33,28.1 73.7,26.48 72.54,26.48 72.03,25.97 65.62,25.97 64.82,25.17 52.83,25.17 51.34,23.68 51.34,22.21 49.38,20.24 48.77,20.24 47.76,19.24 45.27,19.24 44.36,18.32 43.22,18.32 42.75,17.85 35.7,17.85 30.47,23.09 30.47,26.77 29.7,27.54 29.7,30.97 29.04,31.63 29.04,35.42 28.56,35.9 28.56,44.74 28.27,45.03 28.27,47.5 27.95,47.81 27.95,49.98 28.61,50.64 28.61,55.08 32.65,59.12 32.65,62.9 36.42,66.67 36.42,68.15 37.32,69.05 37.32,71.31 36.59,72.04 32.33,72.04 31.35,71.07 31.35,70.5 v1(31.16,70.3)
  BOTTOM w0.076: v2(101.6,40.8) 101.6,40.66 101.67,40.59 101.82,40.59 101.95,40.72 101.95,41.7 101.81,41.84 101.81,42.91 101.95,43.18 101.95,43.46 UU1.Y5
  BOTTOM w0.102: v1(31.16,70.3) 31.33,70.47 31.33,70.55 30.97,70.91 30.97,71.08 CX6.1
EDP_TX0_SOC_DP: length 150.9
  ART06 w0.102: v1(31.75,70.3) 31.57,70.48 31.57,70.98 32.42,71.83 36.5,71.83 37.11,71.22 37.11,69.14 36.21,68.23 36.21,66.76 32.43,62.99 32.43,59.21 28.4,55.17 28.4,50.73 27.73,50.07 27.73,47.72 28.05,47.41 28.05,44.94 28.34,44.65 28.34,35.81 28.83,35.33 28.83,31.54 29.49,30.88 29.49,27.45 30.25,26.68 30.25,23 35.61,17.64 42.84,17.64 43.31,18.11 44.45,18.11 45.36,19.02 47.85,19.02 48.86,20.03 49.46,20.03 51.56,22.12 51.56,23.59 52.92,24.95 64.91,24.95 65.71,25.75 72.12,25.75 72.62,26.26 73.79,26.26 75.42,27.89 76.94,27.89 83.8,34.74 94.01,34.74 94.57,35.3 94.94,35.3 95.09,35.15 95.34,35.15 95.5,35.3 95.75,35.3 95.9,35.15 96.16,35.15 96.31,35.3 96.56,35.3 96.71,35.15 96.97,35.15 97.12,35.3 97.37,35.3 97.53,35.15 97.78,35.15 97.93,35.3 98.25,35.3 100.4,37.45 100.4,38.78 100.56,38.93 100.56,39.19 100.4,39.34 100.4,39.69 100.61,39.9 100.79,39.9 100.99,40.1 100.99,40.27 101.12,40.4 101.41,40.4 v2(101.6,40.21)
  BOTTOM w0.076: UU1.Y3 101.97,42.87 101.97,41.91 102.12,41.77 102.12,40.65 101.89,40.42 101.67,40.42 101.6,40.35 v2(101.6,40.21)
  BOTTOM w0.102: CX5.1 31.18,71.11 31.18,70.99 31.54,70.63 31.54,70.51 v1(31.75,70.3)
EDP_TX1_C_DN: length 0.9
  BOTTOM w0.102: CX2.2 32.43,71.9 32.43,72.41 CHKX1.1
EDP_TX1_C_DP: length 1
  BOTTOM w0.102: CHKX1.2 32.64,72.33 32.64,71.9 CX1.2
EDP_TX1_CONN_DN: length 2.2
  BOTTOM w0.102: CHKX1.4 32.44,73.24 32.44,73.88 32.37,73.95 32.37,74.38 32.2,74.55 JX1.33
EDP_TX1_CONN_DP: length 2.2
  BOTTOM w0.102: JX1.34 32.7,74.55 32.59,74.44 32.59,74.04 32.66,73.97 32.66,73.3 CHKX1.3
EDP_TX1_SOC_DN: length 151.6
  ART06 w0.102: v1(101.01,37.79) 101.29,37.51 101.29,36.99 101.09,36.79 100.9,36.79 100.71,36.6 100.71,36.41 100.51,36.22 100.33,36.22 100.13,36.02 100.13,35.84 99.94,35.64 99.75,35.64 99.56,35.45 99.56,35.26 99.36,35.07 99.18,35.07 98.98,34.87 98.98,34.69 98.62,34.33 84.11,34.33 78.85,29.07 78.85,28.5 77.82,27.47 75.6,27.47 73.72,25.59 72.55,25.59 72.3,25.33 65.9,25.33 65.11,24.55 53.53,24.55 52.12,23.14 52.12,22.02 49.68,19.58 49.17,19.58 48.19,18.6 45.65,18.6 44.71,17.66 43.73,17.66 42.88,16.81 35.73,16.81 29.78,22.76 29.78,26.44 28.98,27.24 28.98,30.58 27.89,31.67 27.89,33.27 27.52,33.64 27.52,41.11 27.89,41.48 27.89,44.52 27.65,44.77 27.65,47.22 27.29,47.58 27.29,50.21 27.39,50.31 27.39,58.02 28.92,59.55 28.92,62.21 29.55,62.85 31.3,62.85 34.55,66.11 34.55,67.24 36.69,69.38 36.69,70.97 36.33,71.33 32.98,71.33 32.42,70.78 32.42,69.89 v1(32.24,69.71)
  BOTTOM w0.076: 102.23,42.06 102.36,41.92 102.36,40.46 102.11,40.21 102.11,39.55 101.77,39.22 101.62,39.22 101.48,39.07 101.48,38.93 101.22,38.66 101.22,38 v1(101.01,37.79)
  BOTTOM w0.102: v1(32.24,69.71) 32.43,69.89 32.43,71.1 CX2.1
EDP_TX1_SOC_DP: length 151.6
  ART06 w0.102: v1(32.83,69.71) 32.64,69.9 32.64,70.69 33.07,71.12 36.24,71.12 36.47,70.88 36.47,69.47 34.34,67.33 34.34,66.2 31.21,63.07 29.46,63.07 28.7,62.3 28.7,59.64 27.18,58.11 27.18,50.4 27.07,50.3 27.07,47.49 27.43,47.13 27.43,44.68 27.67,44.43 27.67,41.56 27.3,41.2 27.3,33.55 27.67,33.18 27.67,31.58 28.76,30.49 28.76,27.15 29.56,26.35 29.56,22.67 35.64,16.6 42.97,16.6 43.82,17.45 44.8,17.45 45.74,18.39 48.28,18.39 49.26,19.37 49.77,19.37 52.33,21.93 52.33,23.05 53.62,24.33 65.2,24.33 65.99,25.12 72.39,25.12 72.64,25.37 73.81,25.37 75.69,27.25 77.91,27.25 79.07,28.41 79.07,28.98 84.2,34.11 98.71,34.11 101.5,36.9 101.5,37.7 v2(101.59,37.79)
  BOTTOM w0.076: v2(101.59,37.79) 101.38,38 101.38,38.59 102.27,39.48 102.27,40.14 102.53,40.39 102.53,42.09 UU1.Y2
  BOTTOM w0.102: v1(32.83,69.71) 32.64,69.89 32.64,71.1 CX1.1
EDP_TX2_C_DN: length 0.9
  BOTTOM w0.102: RX909.1 33.9,72.39 33.9,71.9 CX888.2
EDP_TX2_C_DP: length 1
  BOTTOM w0.102: CX891.2 34.12,71.9 34.12,72.34 RX910.1
EDP_TX2_CONN_DN: length 2.2
  BOTTOM w0.102: RX909.2 33.9,73.24 33.9,73.99 33.84,74.05 33.84,74.41 33.7,74.55 JX1.36
EDP_TX2_CONN_DP: length 2.3
  BOTTOM w0.102: RX910.2 34.12,73.3 34.12,74.08 34.06,74.14 34.06,74.41 34.2,74.55 JX1.37
EDP_TX2_SOC_DN: length 159.5
  ART06 w0.102: v1(33.72,70.09) 33.83,69.98 33.83,68.65 33.51,68.34 30.9,68.34 30.36,67.8 30.36,66.64 26.34,62.62 26.34,61.97 23.53,59.17 23.53,58.12 23.79,57.87 23.79,56.37 24.94,55.22 24.94,47.18 25.58,46.55 25.58,44.65 26.21,44.02 26.21,42.7 25.19,41.69 25.19,40.76 25.53,40.43 25.53,37.76 25.56,37.72 25.56,35.55 25.4,35.38 25.4,33.57 25.86,33.11 25.86,31.72 26.11,31.47 26.11,28.88 26.54,28.45 26.54,26.31 27.61,25.25 27.61,21.02 29.84,18.79 31.54,18.79 35.4,14.93 42.04,14.93 42.54,14.42 44.35,14.42 44.83,14.91 44.83,15.53 45.57,16.28 49.99,16.28 51.46,17.75 52.02,17.75 53.9,19.63 53.9,22.27 54.68,23.06 65.76,23.06 66.15,23.45 74.29,23.45 75.44,24.61 79.3,24.61 80.26,25.57 80.26,26.08 80.64,26.46 80.64,27.73 81.37,28.46 81.37,29.5 84.63,32.76 94.94,32.76 95.45,32.26 101.68,32.26 102.72,33.29 102.72,35.6 103,35.88 103,39.29 103.22,39.52 103.57,39.52 v2(103.76,39.33)
  BOTTOM w0.076: UU1.V2 103.08,42.19 103.08,39.81 103.35,39.54 103.68,39.54 103.76,39.47 v2(103.76,39.33)
  BOTTOM w0.102: CX888.1 33.9,71.1 33.9,70.27 v1(33.72,70.09)
EDP_TX2_SOC_DP: length 159.4
  ART06 w0.102: v1(34.3,70.09) 34.05,69.84 34.05,69.68 34.19,69.54 34.19,69.28 34.05,69.14 34.05,68.56 33.6,68.12 30.99,68.12 30.58,67.71 30.58,66.55 26.55,62.53 26.55,61.88 26.26,61.59 26.26,61.36 26.09,61.19 25.86,61.19 25.69,61.02 25.69,60.79 25.51,60.62 25.29,60.62 25.11,60.44 25.11,60.22 24.94,60.04 24.71,60.04 24.54,59.87 24.54,59.64 24.36,59.47 24.14,59.47 23.75,59.08 23.75,58.21 24,57.96 24,56.46 25.16,55.31 25.16,47.27 25.79,46.64 25.79,44.74 26.43,44.1 26.43,42.61 25.41,41.6 25.41,40.85 25.74,40.52 25.74,37.85 25.78,37.81 25.78,35.46 25.61,35.29 25.61,33.66 26.07,33.2 26.07,31.81 26.33,31.56 26.33,28.97 26.76,28.53 26.76,26.4 27.82,25.33 27.82,21.11 29.92,19.01 31.63,19.01 35.49,15.15 42.12,15.15 42.63,14.64 44.26,14.64 44.61,15 44.61,15.62 45.48,16.49 49.9,16.49 51.37,17.97 51.93,17.97 53.68,19.72 53.68,22.36 54.59,23.28 65.67,23.28 66.06,23.67 74.2,23.67 75.35,24.83 79.22,24.83 80.05,25.66 80.05,26.16 80.43,26.55 80.43,27.82 81.15,28.55 81.15,29.59 84.54,32.98 95.03,32.98 95.54,32.47 101.59,32.47 102.5,33.38 102.5,34.02 102.33,34.19 102.33,34.43 102.5,34.6 102.5,34.84 102.33,35 102.33,35.24 102.5,35.41 102.5,35.69 102.78,35.97 102.78,39.38 103.13,39.74 103.58,39.74 v2(103.76,39.92)
  BOTTOM w0.076: v2(103.76,39.92) 103.76,39.78 103.68,39.71 103.42,39.71 103.25,39.88 103.25,40.16 103.35,40.26 103.35,40.46 103.25,40.56 103.25,40.77 103.35,40.87 103.35,41.07 103.25,41.17 103.25,41.37 103.35,41.48 103.35,41.68 103.25,41.78 103.25,41.95 103.35,42.06
  BOTTOM w0.102: CX891.1 34.12,71.1 34.12,70.27 v1(34.3,70.09)
EDP_TX3_C_DN: length 0.9
  BOTTOM w0.102: CHKX8.1 35.32,72.39 35.32,71.9 CX890.2
EDP_TX3_C_DP: length 1
  BOTTOM w0.102: CHKX8.2 35.54,72.34 35.54,71.9 CX889.2
EDP_TX3_CONN_DN: length 2.2
  BOTTOM w0.102: JX1.39 35.2,74.73 35.34,74.59 35.34,74.2 35.32,74.19 35.32,73.24 CHKX8.4
EDP_TX3_CONN_DP: length 2.2
  BOTTOM w0.102: JX1.40 35.7,74.76 35.56,74.62 35.56,74.11 35.54,74.1 35.54,73.3 CHKX8.3
EDP_TX3_SOC_DN: length 154.4
  ART06 w0.102: v2(104.27,40.22) 104.09,40.4 103.04,40.4 102.37,39.74 102.37,36.46 101.81,35.9 101.81,33.29 101.4,32.88 95.83,32.88 95.32,33.39 84.36,33.39 79.97,29 79.97,27.16 78.04,25.23 75.17,25.23 74.05,24.11 65.9,24.11 65.48,23.7 54.2,23.7 53.24,22.73 53.24,19.89 51.85,18.5 49.62,18.5 48.47,17.36 45.75,17.36 44.76,16.37 44.03,16.37 43.62,15.96 35.37,15.96 28.93,22.4 28.93,25.93 28,26.86 28,30.21 27.04,31.18 27.04,32.93 26.02,33.94 26.02,35.04 26.68,35.7 26.68,41.59 26.99,41.9 26.99,44.18 26.81,44.36 26.81,46.42 26.61,46.62 26.44,46.62 26.2,46.86 26.2,50.46 26.55,50.81 26.55,58.18 26.2,58.53 26.2,60.11 27.09,61 27.09,62.39 30.72,66.02 31.3,66.02 32.97,67.69 33.75,67.69 35.32,69.25 35.32,69.91 v1(35.14,70.09)
  BOTTOM w0.076: v2(104.27,40.22) 104.27,40.36 104.19,40.43 103.91,40.43 103.66,40.69 103.66,42.12 103.61,42.17 103.61,42.59 103.66,42.64 103.66,42.77 103.35,43.31 UU1.V3
  BOTTOM w0.102: v1(35.14,70.09) 35.32,70.27 35.32,71.1 CX890.1
EDP_TX3_SOC_DP: length 154.5
  ART06 w0.102: v2(104.27,40.81) 104.07,40.62 102.95,40.62 102.16,39.82 102.16,36.55 101.6,35.99 101.6,33.38 101.31,33.09 95.92,33.09 95.41,33.6 84.27,33.6 79.75,29.09 79.75,27.25 77.95,25.45 75.08,25.45 73.96,24.33 65.81,24.33 65.39,23.91 54.11,23.91 53.02,22.82 53.02,19.97 51.76,18.72 49.53,18.72 48.38,17.57 45.66,17.57 44.67,16.58 43.94,16.58 43.53,16.18 35.46,16.18 29.14,22.49 29.14,26.02 28.22,26.95 28.22,30.3 27.25,31.26 27.25,33.02 26.24,34.03 26.24,34.95 26.9,35.61 26.9,41.5 27.2,41.81 27.2,44.27 27.02,44.45 27.02,46.5 26.7,46.83 26.53,46.83 26.41,46.94 26.41,50.37 26.77,50.72 26.77,58.27 26.41,58.62 26.41,60.02 27.3,60.91 27.3,62.3 30.81,65.81 31.39,65.81 33.06,67.47 33.84,67.47 35.53,69.16 35.53,69.9 v1(35.72,70.09)
  BOTTOM w0.076: v2(104.27,40.81) 104.27,40.67 104.19,40.6 103.98,40.6 103.82,40.76 103.82,42.19 103.77,42.24 103.77,42.52 103.82,42.57 103.82,42.81 103.63,43.15 103.63,43.24 103.63,43.24 103.63,43.47 UU1.V5
  BOTTOM w0.102: v1(35.72,70.09) 35.54,70.27 35.54,71.1 CX889.1
EDP_VDD_EN: length 49.6
  ART03 w0.089: v1(45.46,66.22) 41.2,66.22 40.08,67.33 37.69,67.33 36.88,68.15 31.62,68.15 v1(31.11,67.64)
  ART06 w0.102: v2(66.37,52.41) 66.25,52.52 64.13,52.52 63.35,51.74 56.51,51.74 55.7,50.92 54.51,50.92 54.3,51.13 54.3,51.99 53.44,52.85 53.44,55.04 53.03,55.45 53.03,57.93 52.58,58.39 51.94,58.39 49.58,60.75 49.58,62.1 v1(45.46,66.22)
  BOTTOM w0.102: v2(66.37,52.41) 66.7,52.08 UU1.DN21
  BOTTOM w0.254: UX1.4 30.04,67.58 30.22,67.76 RX12.2 30.99,67.76 v1(31.11,67.64)
EMMC_RCOMP: length 6.6
  BOTTOM w0.102: RU65.1 59.18,52.78 60.58,54.18 61.47,54.18 62.08,54.79 64.11,54.79 64.4,55.08 UU1.DU28
EN_VGA: length 70.7
  TOP w0.102: RV16.1 PC1.1 132.19,80.98 DV6.2 131.68,79.55 v1(131.52,79.55)
  ART06 w0.102: v1(166.06,45.54) 165.94,45.67 162.16,45.67 156.78,51.05 147.55,51.05 147.34,51.26 147.34,53.11 146.91,53.54 146.2,53.54 145.45,52.79 140.96,52.79 139.83,53.92 136.9,53.92 134.11,56.72 134.11,60.65 132.59,62.18 132.59,63.09 129.67,66.01 129.67,74.5 131.82,76.65 131.82,79.25 v1(131.52,79.55)
  BOTTOM w0.102: v1(131.52,79.55) 131.32,79.35 v3(131.32,78.71) ; v1(166.06,45.54) PR820.1
  BOTTOM w0.203: QV12.1 133.41,78.98 132.84,79.55 v1(131.52,79.55)
EN_VGA_R: length 30.9
  TOP w0.102: v1(133.04,82.17) 132.86,81.98 RV16.2 RV15.1 RV18.2 ; v3(131.37,76.48) 130.94,76.91 v1(130.94,77.67) 131.2,77.94 DV5.3
  ART03 w0.076: v1(133.04,82.17) 133.04,82.06 130.94,79.96 v1(130.94,77.67)
  ART06 w0.102: v1(130.94,77.67) 128.9,75.64 128.9,65.61 131.82,62.68 131.82,60.14 v1(132.54,59.43)
  BOTTOM w0.102: DV14.1 132.18,59.07 v1(132.54,59.43)
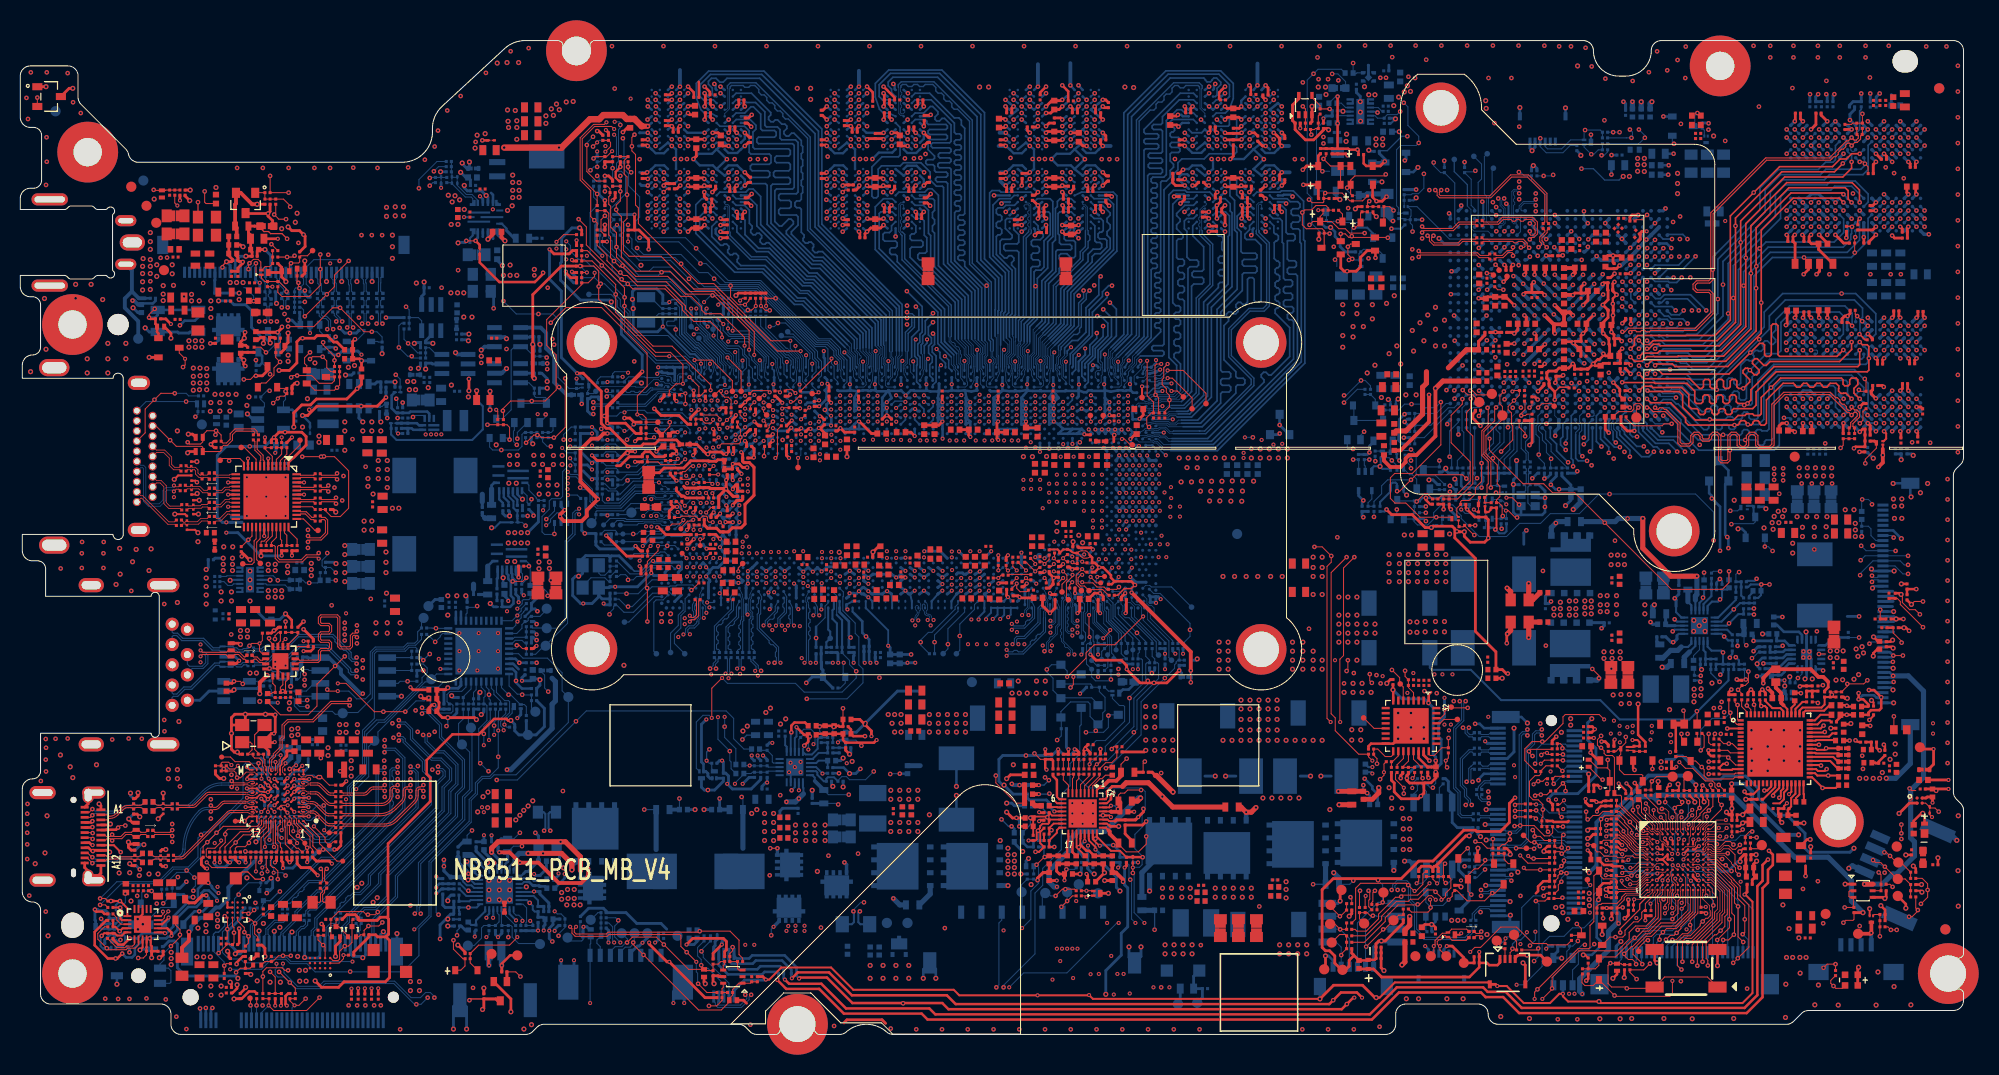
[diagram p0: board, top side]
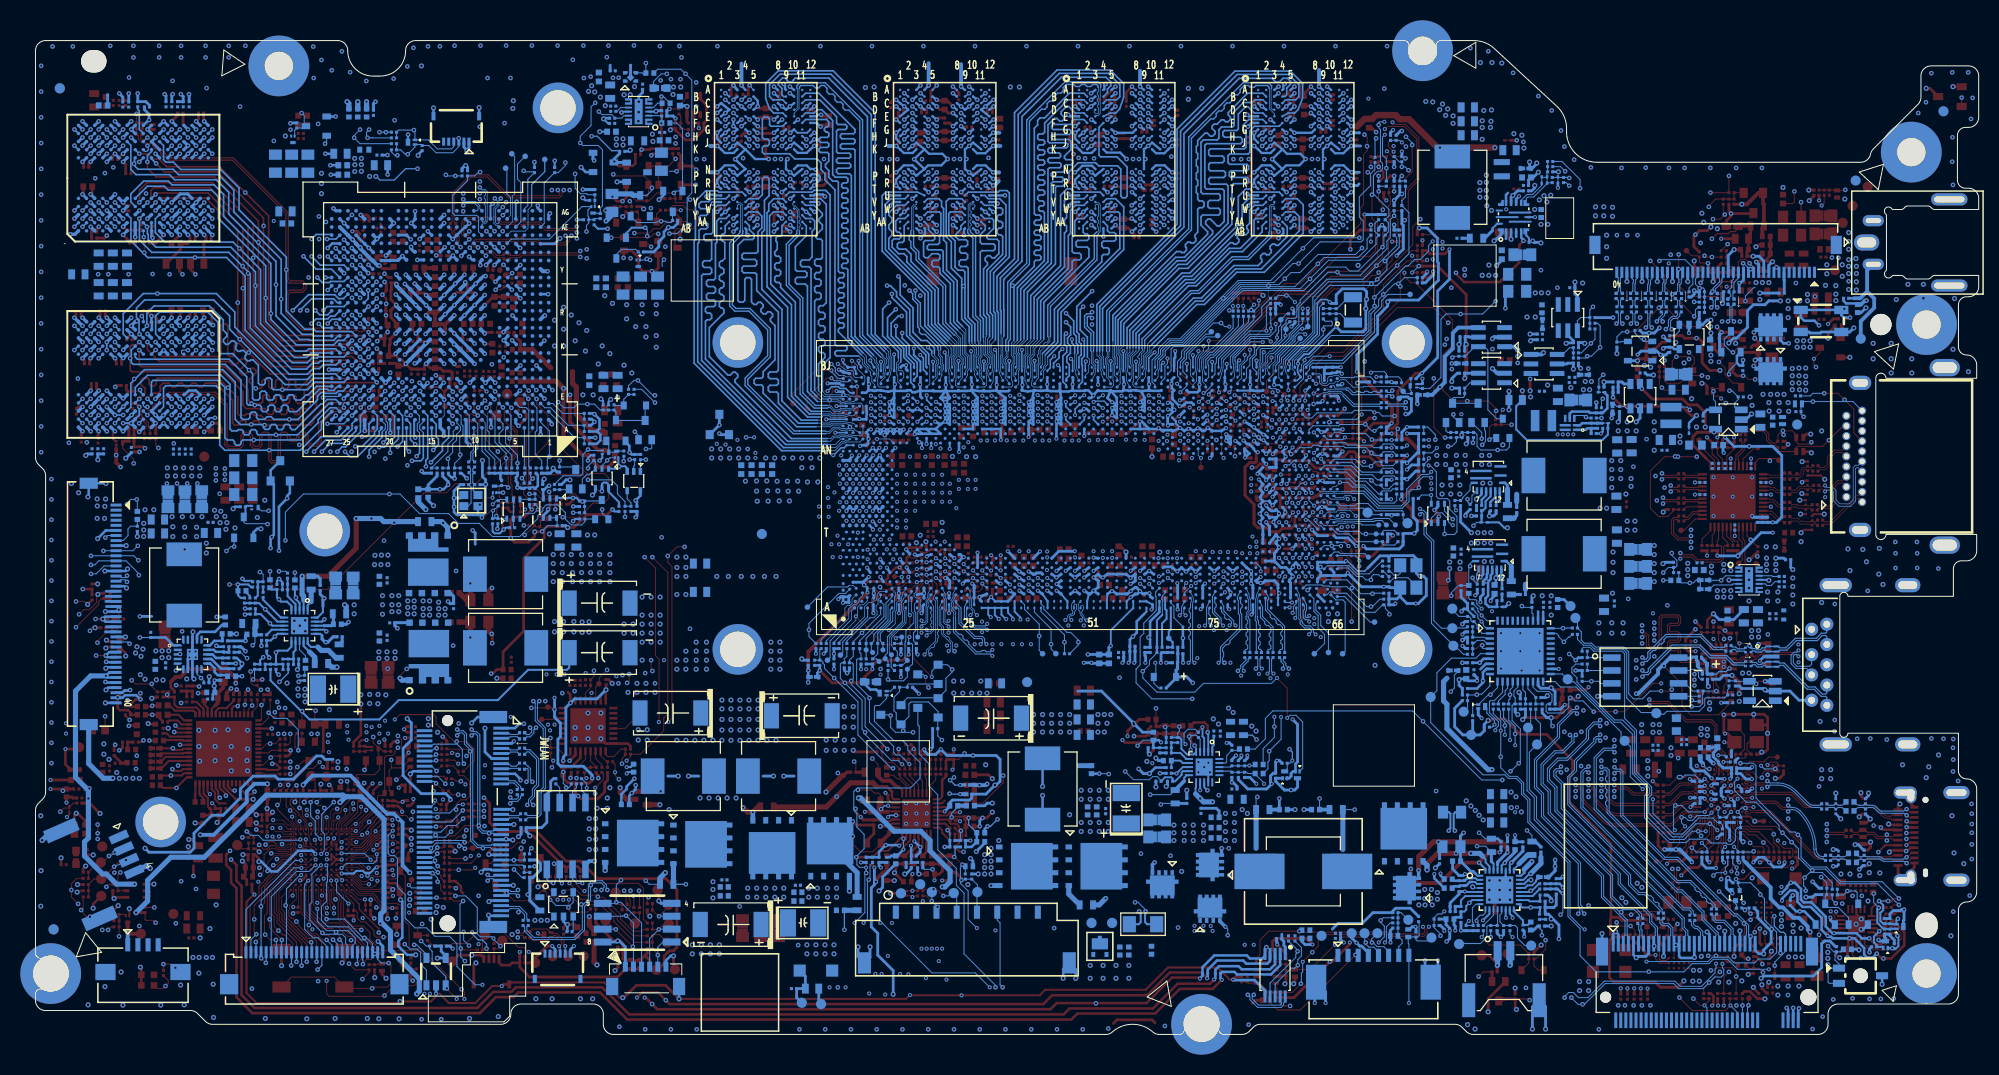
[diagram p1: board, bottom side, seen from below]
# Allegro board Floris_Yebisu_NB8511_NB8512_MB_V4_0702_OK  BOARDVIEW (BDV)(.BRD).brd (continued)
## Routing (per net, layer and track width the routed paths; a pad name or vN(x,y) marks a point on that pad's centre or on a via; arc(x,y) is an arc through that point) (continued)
EQ_8409A: length 2.8
  TOP w0.102: RI101.1 RI102.2 24.13,57.73 24.86,57 UI2.5
ESPI_CLK: length 7.7
  BOTTOM w0.102: UU1.CR47 75.32,65.1 75.32,66.1 75.19,66.23 75.19,66.74 71.5,70.44 RU37.1
ESPI_CLK_EC: length 141.4
  TOP w0.076: UE1.K2 160.72,15.49 160.36,15.49 159.32,14.45 158.47,14.45 158.32,14.6
  TOP w0.102: CU5.1 71.22,72.59 v2(70.99,72.36) ; 158.32,14.6 158.24,14.6 157.94,14.91 v2(157.94,15.16)
  ART03 w0.089: v2(70.99,72.36) 71.09,72.46 73.67,72.46 81.23,64.9 81.23,63.75 81.43,63.55 81.43,60.12 81.72,59.83 83.75,59.83 87.03,56.55 106.39,56.55 107.31,57.48 112.9,57.48 113.41,57.99 118.11,57.99 119,58.87 v2(120.78,58.87) ; v2(156.87,29.66) 156.87,27.96 157.12,27.71 157.12,26.62 156.79,26.29 156.79,24.23 157.12,23.9 157.12,19.38 157.35,19.15 157.35,15.75 v2(157.94,15.16)
  ART06 w0.102: v2(156.87,29.66) 156.34,29.66 155.32,30.68 154.29,30.68 152.99,31.98 144.37,31.98 144.07,32.28 141.12,32.28 140.87,32.53 140.87,33.45 140.26,34.06 139.65,34.06 138.48,35.23 138.48,36.04 138.05,36.47 133.02,36.47 132.15,37.34 130.12,37.34 129.16,38.3 129.16,41.6 127.96,42.8 127.96,43.56 127.51,44.02 127.06,44.02 126.36,44.71 126.36,54.05 125.09,55.32 121.16,55.32 120.09,56.39 120.09,58.19 v2(120.78,58.87)
  BOTTOM w0.102: RU37.2 70.99,71.83 v2(70.99,72.36) ; v2(120.78,58.87) v3(121.56,58.87)
ESPI_CS_N: length 136.8
  TOP w0.076: UE1.H1 159.72,16.74 159.05,16.08 158.14,16.08 v2(157.99,15.92)
  TOP w0.102: RU45.2 74.8,63.45 v2(74.93,63.32)
  ART03 w0.089: v2(74.93,63.32) 74.93,62.99 74.75,62.81 74.75,60.32 74.9,60.18 76.36,60.18 76.58,60.4 76.58,60.78 76.83,61.03 78.1,61.03 78.38,61.31 79.09,61.31 79.22,61.19 79.22,58.14 82.04,55.32 100.96,55.32 101.62,54.66 114.02,54.66 114.35,54.99 119.78,54.99 119.87,55.08 119.87,55.36 119.96,55.45 120.14,55.45 120.22,55.36 120.22,55.08 120.31,54.99 120.49,54.99 120.58,55.08 120.58,55.36 120.67,55.45 120.85,55.45 120.94,55.36 120.94,55.08 121.02,54.99 121.2,54.99 121.29,55.08 121.29,55.36 121.38,55.45 121.56,55.45 121.65,55.36 121.65,55.08 121.74,54.99 121.96,54.99 122.05,55.08 122.05,55.99 121.96,56.08 120.74,56.08 120.65,56.17 v2(120.65,56.84) ; v2(157.99,15.92) 157.78,15.92 157.55,16.15 157.55,19.25 157.33,19.48 157.33,24.05 157.02,24.36 157.02,25.27 157.76,26.01 v2(157.76,28.8)
  ART06 w0.102: v2(157.76,28.8) 157.68,28.88 157.68,29.18 157.25,29.61 157.25,29.89 156.59,30.55 156.59,31.39 156.43,31.54 154.11,31.54 153.19,32.46 144.6,32.46 143.61,33.45 141.83,33.45 140.71,34.57 139.85,34.57 138.99,35.43 138.99,36.24 138.26,36.97 134.22,36.97 133.37,37.82 130.32,37.82 129.64,38.5 129.64,41.8 128.9,42.54 128.9,43.74 128.14,44.5 127.26,44.5 126.85,44.91 126.85,54.25 125.22,55.88 121.61,55.88 v2(120.65,56.84)
  BOTTOM w0.102: UU1.CT45 74.97,63.36 v2(74.93,63.32)
ESPI_IO0: length 8.5
  BOTTOM w0.076: UU1.CN45 76.23,64.04 76.56,64.37 76.56,65.4 76.67,65.78 76.67,66.35 76.62,66.41 76.62,66.71 75.67,67.66
  BOTTOM w0.102: 75.67,67.66 75.54,67.66 73.53,69.67 RU38.1
ESPI_IO0_EC: length 136
  TOP w0.076: UE1.K1 160.37,15.74 159.43,14.81 v2(158.77,14.81)
  TOP w0.102: v2(73.56,71.83) 73.56,72.57 CU4.1 v3(74.5,72.59)
  ART03 w0.089: v2(124.46,58.24) 124.18,58.52 122.83,58.52 122.55,58.24 119.05,58.24 118.44,57.63 114.2,57.63 113.66,57.1 113.66,56.97 113.23,56.54 106.88,56.54 106.5,56.16 84.17,56.16 81.07,59.26 80.9,59.26 80.5,59.66 80.5,62.5 80.44,62.56 80.44,63.37 80.52,63.45 80.52,65.11 73.8,71.83 v2(73.56,71.83) ; v2(158.77,14.81) 158.77,14.83 158.88,14.93 158.88,15.95 159.17,16.24 159.17,18.7 158.49,19.38 158.49,23.7 158.85,24.05 158.85,25.41 158.54,25.72 158.54,30.25 v2(158.49,30.3)
  ART06 w0.102: v2(158.49,30.3) 158.49,30.77 156.81,32.46 154.49,32.46 153.57,33.37 144.99,33.37 140.48,37.88 134.6,37.88 133.14,39.34 133.14,41.55 132.31,42.39 132.31,43.41 131.21,44.51 130.92,44.51 129.13,46.29 129.13,56.16 127.15,58.14 124.56,58.14 v2(124.46,58.24)
  BOTTOM w0.102: v2(73.56,71.83) 73.56,71.35 RU38.2
ESPI_IO1: length 7.3
  BOTTOM w0.076: UU1.CN48 76.35,65.25 76.48,65.71 76.48,66.24 76.45,66.27 76.45,66.62 76.07,67.01
  BOTTOM w0.102: 76.07,67.01 75.82,67.26 75.59,67.26 73.02,69.82 RU39.1
ESPI_IO1_EC: length 138.9
  TOP w0.076: UE1.J2 160.72,15.99 160.37,15.99 159.43,15.06 159.03,15.06 158.77,15.31 v2(158.49,15.31)
  TOP w0.102: CU3.1 73.05,72.57 v2(73.05,71.83) 73.48,71.4 v3(73.91,71.4)
  ART03 w0.089: v2(158.49,15.31) 158.49,15.57 158.44,15.62 158.44,16.63 158.04,17.04 158.04,17.29 158.7,17.96 158.7,18.46 157.53,19.63 157.53,24.2 157.27,24.46 157.27,25.22 158.11,26.06 158.11,29.28 v2(157.73,29.66) ; v2(73.05,71.83) 73.43,71.45 73.78,71.45 80.34,64.89 80.34,63.65 80.26,63.57 80.26,62.48 80.32,62.43 80.32,59.45 80.77,59 81.02,59 84.1,55.93 107.21,55.93 107.38,55.76 112.7,55.76 113.84,56.9 113.84,56.99 114.3,57.45 118.87,57.45 119.4,57.99 121.16,57.99 v1(121.41,57.73)
  ART06 w0.102: v1(121.41,57.73) 121.82,57.33 121.82,56.44 122.15,56.11 126.9,56.11 127.07,55.93 127.07,45.01 127.35,44.73 128.24,44.73 129.54,43.42 129.54,42.49 130.5,41.53 130.5,38.48 130.94,38.05 133.46,38.05 134.32,37.2 138.75,37.2 139.9,36.04 139.9,35.28 140.23,34.95 140.84,34.95 142.09,33.7 143.69,33.7 144.7,32.69 153.29,32.69 154.2,31.77 156.52,31.77 156.82,31.48 156.82,30.65 157.73,29.73 v2(157.73,29.66)
  BOTTOM w0.102: RU39.2 73.05,71.35 v2(73.05,71.83)
ESPI_IO2: length 6.7
  BOTTOM w0.102: RU40.1 72.52,70.01 75.52,67 75.76,67 76.23,66.53 76.23,65.79
ESPI_IO2_EC: length 143.1
  TOP w0.076: UE1.J1 160.29,16.24 159.66,15.62 v2(159.48,15.62)
  TOP w0.102: CU2.1 72.54,72.57 v2(72.54,71.83) 72.14,71.42 v3(71.75,71.42)
  ART03 w0.089: v2(159,29.79) 160.02,30.81 161.11,30.81 161.87,30.05 161.87,28.34 160.35,26.82 160.35,25.8 160.09,25.55 160.09,23.21 159.92,23.04 159.92,21.87 160.58,21.21 160.58,18.16 159.97,17.55 159.97,16.13 159.48,15.64 v2(159.48,15.62) ; v2(123.59,58.16) 122.98,58.16 122.78,57.96 122.78,57.58 122.5,57.3 121.21,57.3 120.78,57.73 119.89,57.73 119.22,57.06 119.22,56.62 118.93,56.33 114.68,56.33 113.92,55.58 107.31,55.58 107.16,55.73 83.54,55.73 81.15,58.11 79.88,58.11 79.58,58.42 79.58,63.52 80.01,63.95 80.01,64.97 74.04,70.94 73.43,70.94 v2(72.54,71.83)
  ART06 w0.102: v2(123.59,58.16) 123.59,57.58 123.87,57.3 127.67,57.3 128.9,56.06 128.9,46.2 131.39,43.71 131.39,42.42 132.23,41.58 132.23,39.29 132.36,39.16 132.99,39.16 134.51,37.65 140.38,37.65 144.89,33.14 153.48,33.14 154.39,32.23 156.71,32.23 158.11,30.83 158.11,30.02 158.34,29.79 v2(159,29.79)
  BOTTOM w0.102: RU40.2 72.54,71.35 v2(72.54,71.83)
ESPI_IO3: length 8.2
  BOTTOM w0.102: UU1.CN47 76.23,64.51 75.94,64.8 75.94,65.96 76.02,66.04 76.02,66.42 75.69,66.75 75.51,66.75 72.01,70.25 RU43.1
ESPI_IO3_EC: length 140.9
  TOP w0.076: v2(158.8,16.43) 159.05,16.43 159.62,16.99 160.72,16.99 UE1.H2
  TOP w0.102: v3(70.05,73.84) 70.05,72.72 70.81,71.96 v2(71.47,71.96) 71.85,72.34 71.85,72.44 CU1.1
  ART03 w0.089: v2(158.8,16.43) 158.95,16.58 158.95,18.51 157.73,19.73 157.73,20.39 158.04,20.7 158.04,25.12 158.33,25.41 158.33,29.58 157.73,30.17 v2(157.73,30.43) ; v2(122.43,58.62) 122.3,58.49 119.05,58.49 118.36,57.81 114.12,57.81 113.41,57.1 113.41,56.97 113.16,56.72 106.8,56.72 106.45,56.36 86.94,56.36 83.66,59.64 81.66,59.64 81.25,60.05 81.25,63.47 81.05,63.68 81.05,64.83 78.64,67.24 73.67,72.21 71.73,72.21 v2(71.47,71.96)
  ART06 w0.102: v2(122.43,58.62) 122.71,58.34 122.71,56.56 122.93,56.33 127.5,56.33 128.29,55.54 128.29,47.95 127.91,47.57 127.91,45.77 128.06,45.62 128.57,45.62 130.5,43.69 130.5,42.42 131.34,41.58 131.34,38.4 131.47,38.28 133.56,38.28 134.41,37.42 139.33,37.42 140.76,35.99 140.76,35.43 142.19,34.01 143.7,34.01 144.8,32.92 153.38,32.92 154.3,32 156.62,32 157.73,30.89 v2(157.73,30.43)
  BOTTOM w0.102: v2(71.47,71.96) 71.85,71.57 71.85,71.47 RU43.2
ESPI_RESET: length 144.5
  TOP w0.076: 161.54,12.9 161.49,12.95 161.49,13.68 161.72,13.91 161.72,14.49 UE1.M4
  TOP w0.102: v1(159.51,10.31) 159.64,10.44 160.48,10.44 161.54,11.5 161.54,12.9 ; RU46.2 75.56,63.57 76.12,63.57 v2(76.45,63.24)
  ART03 w0.089: v1(159.51,10.31) 159.89,10.69 159.89,13.92 160.37,14.4 160.37,17.55 160.78,17.96 160.78,21.77 160.73,21.82 160.73,23.64 160.3,24.08 160.3,25.42 160.58,25.7 160.58,26.59 162.1,28.12 162.1,30.15 161.19,31.06 159.66,31.06 v2(159.03,30.43) ; v2(76.45,63.24) 76.45,61.67 76.83,61.29 77.98,61.29 78.18,61.49 79.17,61.49 79.4,61.26 79.4,58.24 82.12,55.52 101.01,55.52 101.69,54.84 113.95,54.84 114.28,55.17 118.72,55.17 120.11,56.56 120.11,56.82 v2(120.65,57.35)
  ART06 w0.102: v2(120.65,57.35) 120.65,57.73 121.92,59 123.57,59 123.82,58.75 126.11,58.75 126.24,58.62 127.35,58.62 129.36,56.61 129.36,46.42 130.95,44.83 131.39,44.83 132.64,43.58 132.64,42.38 134.01,41.01 134.01,38.8 134.69,38.11 140.57,38.11 145.08,33.6 153.67,33.6 154.58,32.69 157,32.69 159.03,30.66 v2(159.03,30.43)
  BOTTOM w0.102: v2(76.45,63.24) 76.38,63.24 75.6,64.02 UU1.CR46
FAN_PWM_CTL_R: length 7.5
  TOP w0.102: v3(182.73,17.19) 182.98,16.94 183.49,16.94 v1(183.89,16.54) 183.89,16.53 185.1,15.33 TPE103.1 185.88,15.33 CE22.1 RE51.2 RE49.1
  BOTTOM w0.102: v1(183.89,16.54) 183.88,16.55 JE3.3
FAN_TACHO_R: length 5.7
  TOP w0.102: RE48.1 RE50.2 185.48,16.96 TPE102.1 185.05,16.96 v1(184.4,17.6) 184.05,17.96 v3(183.84,17.96)
  BOTTOM w0.102: JE3.2 184.34,17.6 v1(184.4,17.6)
FB_GC6_EN: length 13
  ART06 w0.102: v1(135.27,56.6) 135.63,56.97 v1(140.97,56.97)
  BOTTOM w0.102: RV47.2 141.17,56.77 v1(140.97,56.97) 140.97,59.51 141.84,60.38 UV2.B2 ; QV8.1 135,56.87 v1(135.27,56.6) 135.27,56.59 135.78,56.08 QV4.2
FB_GC6_EN_R: length 175
  ART03 w0.089: v1(130,94.08) 129.73,93.82 127.71,93.82 125.81,95.72 61.57,95.72 58.89,93.04 58.89,92.55 57.28,90.93 57.28,86.81 58.04,86.05 58.04,81.86 58.11,81.79 58.11,79.52 55.34,76.76 54.3,76.76 54.19,76.65 54.07,76.65 v2(53.85,76.43)
  ART06 w0.102: v2(53.85,76.43) 53.39,75.97 53.39,73.43 50.14,70.18 50.14,64.54 51.61,63.07 56.82,63.07 58.06,61.82 61.64,61.82 63.45,60.02 64.92,60.02 v2(65.57,59.36) ; v1(130,94.08) 130.43,93.65 130.43,91.87 129.36,90.8 129.36,90.17 128.6,89.41 128.6,89 129.03,88.57 129.03,87.12 132.21,83.94 132.21,76.53 129.92,74.24 129.92,66.11 132.84,63.19 132.84,62.3 134.36,60.78 134.36,56.84 135.38,55.83 v1(137.16,55.83)
  BOTTOM w0.102: v2(65.57,59.36) UU1.DT36 ; v1(137.16,55.83) 137.16,56.03 RV27.1 136.43,56.46 QV4.3 137.02,55.19 137.29,55.19 137.72,54.76 DV9.2
FB_PLLAVDD: length 8.2
  TOP w0.279: CV115.2 157.79,65.34 v1(157.99,65.15) ; CV116.1 158.33,70.45 v1(158,70.12)
  BOTTOM w0.127: v3(153.97,85.37) 155.14,85.37 156.26,84.25 157.68,84.25 158.04,84.6 v4(158.09,84.6)
  BOTTOM w0.305: v1(152.99,64.23) 153.36,63.85 UV2.F16 v1(153.78,64.26) ; v1(158,70.12) 158.4,70.51 UV2.P22
  BOTTOM w0.381: UV2.H22 v1(157.99,65.15)
  vias: v4(158.7,84.6)
FBA_A0_A10_H: length 32.9
  TOP w0.165: v1(161.24,65.97) 161.37,66.11 162.94,66.11 163.19,65.86 168.4,65.86 171.7,69.16 v3(171.7,72.16) 171.7,79.32 174.85,82.47 179.38,82.47 v1(179.81,82.04)
  BOTTOM w0.165: v1(161.24,65.97) 161.24,65.99 UV2.J25 ; UV4.K4 v1(179.81,82.04)
FBA_A0_A10_L: length 33.5
  TOP w0.165: v1(159.64,65.13) 160.12,64.65 164.66,64.65 165.61,63.7 165.83,63.7 166,63.87 166,64.42 166.16,64.59 166.49,64.59 166.66,64.42 166.66,63.87 166.82,63.7 167.15,63.7 167.32,63.87 167.32,64.42 167.48,64.59 167.81,64.59 167.98,64.42 167.98,63.87 168.14,63.7 168.48,63.7 168.64,63.87 168.64,64.42 168.81,64.59 169.14,64.59 169.3,64.42 169.3,63.87 169.47,63.7 v3(169.92,63.7) 170.56,64.34 170.56,64.57 169.91,65.23 169.91,65.46 170.14,65.69 170.37,65.69 171.03,65.04 171.26,65.04 171.5,65.27 171.5,65.51 170.84,66.16 170.84,66.39 171.07,66.63 171.31,66.63 171.96,65.97 172.2,65.97 172.58,66.36 179.44,66.36 180.61,67.53 v1(180.61,68.27)
  BOTTOM w0.165: UV2.G23 159.24,64.73 v1(159.64,65.13) ; v1(180.61,68.27) 180.61,68.27 UV3.H4
FBA_A1_A9_H: length 33.7
  TOP w0.165: v1(160.44,65.97) 160.96,66.49 163.19,66.49 163.31,66.38 168.2,66.38 171.19,69.37 v3(171.19,73.58) 171.19,79.53 174.64,82.98 179.68,82.98 v1(179.81,82.84)
  BOTTOM w0.165: UV4.K5 v1(179.81,82.84) ; UV2.J24 160.04,66.37 v1(160.44,65.97)
FBA_A1_A9_L: length 29.5
  TOP w0.165: v1(160.44,65.13) 160.85,65.55 161.52,65.55 161.95,65.12 168.51,65.12 v3(170.63,67.24) 171.54,68.15 171.87,68.15 172.03,67.98 172.03,67.03 172.2,66.86 172.53,66.86 172.69,67.03 172.69,69.89 172.86,70.05 173.19,70.05 173.35,69.89 173.35,67.03 173.52,66.86 179.17,66.86 v1(179.8,67.49)
  BOTTOM w0.165: v1(160.44,65.13) 160.04,64.73 UV2.G24 ; v1(179.8,67.49) UV3.H5
FBA_A2_BA0_H: length 36.2
  TOP w0.165: v1(160.44,67.61) 160.63,67.61 161.08,68.06 161.58,68.06 161.74,67.9 167.57,67.9 169.67,70 v3(169.67,78.1) 169.67,80.21 174.01,84.55 179.75,84.55 180.61,85.41 180.61,86.04 v1(180.61,86.04)
  BOTTOM w0.165: v1(180.61,86.04) 180.61,86.04 180.61,86.66 180.21,87.06 UV4.K11 ; UV2.K24 160.04,67.21 v1(160.44,67.61)
FBA_A2_BA0_L: length 28.8
  TOP w0.165: v1(180.61,62.68) 180.05,63.24 179.82,63.24 179.79,63.21 179.56,63.21 179.33,63.44 179.33,63.68 179.35,63.7 179.35,63.94 179.08,64.21 178.5,64.21 178.34,64.04 178.34,63.99 178.17,63.83 177.84,63.83 177.68,63.99 177.68,64.04 177.51,64.21 177.18,64.21 177.02,64.04 177.02,63.99 176.85,63.83 176.52,63.83 176.36,63.99 176.36,64.04 176.19,64.21 175.86,64.21 175.7,64.04 175.7,63.99 175.53,63.83 175.2,63.83 175.03,63.99 175.03,64.04 174.87,64.21 173.86,64.21 172.21,62.56 172.21,60.27 172.02,60.08 171.7,60.08 171.54,60.25 171.54,60.36 171.37,60.53 171.04,60.53 170.87,60.36 170.87,60.25 170.71,60.08 170.38,60.08 170.21,60.25 170.21,60.36 170.05,60.53 169.72,60.53 169.55,60.36 169.55,60.25 169.39,60.08 v3(169.06,60.08) 164.52,60.08 164.24,60.37 164.24,60.81 162.76,62.29 160.81,62.29 v1(160.44,62.66)
  BOTTOM w0.165: v1(160.44,62.66) UV2.E24 ; v1(180.61,62.68) UV3.H11
FBA_A3_BA3_H: length 35.1
  TOP w0.102: v1(159.64,68.43) 160.06,68.01 160.64,68.01 160.67,68.04
  TOP w0.165: v1(179.75,85.88) 178.92,85.06 173.72,85.06 169.16,80.5 v3(169.16,79.73) 169.16,70.21 167.36,68.41 161.04,68.41 160.67,68.04
  BOTTOM w0.165: v1(179.75,85.88) 180.21,86.35 UV4.K10 ; UV2.M23 159.24,68.83 v1(159.64,68.43)
FBA_A3_BA3_L: length 27.5
  BOTTOM w0.165: UV2.C26 162.01,61.79 162.6,61.79 163.78,60.61 163.78,60.32 165.48,58.62 v3(170.13,58.62) 171.2,58.62 171.36,58.46 171.36,58.28 171.53,58.11 171.86,58.11 172.02,58.28 172.02,58.46 172.19,58.62 172.76,58.62 172.97,58.84 172.97,63.81 173.66,64.5 180.05,64.5 180.21,64.33 UV3.H10
FBA_A4_BA2_H: length 38.1
  TOP w0.165: v1(158.82,67.61) 159.19,67.99 159.19,68.58 159.53,68.92 167.14,68.92 168.65,70.43 168.65,80.71 v3(170.96,83.01) 173.51,85.57 178.72,85.57 179.48,86.33 180.1,86.33 180.62,86.84 181.41,86.84 v1(181.41,86.84)
  BOTTOM w0.165: v1(158.82,67.61) 159.05,67.38 UV2.K23 ; UV4.H11 v1(181.41,86.84)
FBA_A4_BA2_L: length 30.1
  TOP w0.165: v1(160.48,63.49) 160.58,63.4 163.62,63.4 163.95,63.07 163.95,61.84 165.2,60.59 168.97,60.59 169.42,61.03 170.09,61.03 170.24,61.19 170.85,61.19 171,61.03 171.54,61.03 171.7,61.2 171.7,62.81 v3(172.67,63.78) 173.61,64.72 179.6,64.72 179.77,64.55 179.77,64.12 179.93,63.95 180.26,63.95 180.43,64.12 180.43,64.55 180.59,64.72 181.06,64.72 181.23,64.55 181.23,64.08 180.85,63.7 180.85,63.24 v1(181.41,62.67)
  BOTTOM w0.165: UV3.K11 v1(181.41,62.67) ; v1(160.48,63.49) 160.46,63.49 160.29,63.66 UV2.F24
FBA_A5_BA1_H: length 31.6
  BOTTOM w0.165: UV4.H10 181.88,86.37 181.88,85.66 181.53,85.31 178.07,85.31 177.54,84.78 173.61,84.78 172.08,83.26 172.08,81.1 167.42,76.43 v3(167.42,72.51) 167.42,71.1 165.35,69.03 164.39,69.03 164.23,68.87 UV2.M27
FBA_A5_BA1_L: length 27.7
  BOTTOM w0.165: UV2.D27 162.7,62.21 165.78,59.13 v3(167.94,59.13) 169.67,59.13 169.83,59.29 169.83,59.47 170,59.64 170.33,59.64 170.49,59.47 170.49,59.29 170.66,59.13 170.99,59.13 171.16,59.29 171.16,59.47 171.32,59.64 171.65,59.64 171.78,59.51 172.27,59.51 172.46,59.7 172.46,64.12 173.35,65 180.6,65 181.81,63.79 UV3.K10
FBA_A6_A11_H: length 32.1
  BOTTOM w0.165: UV4.H5 180.61,83.64 178.94,83.64 178.56,83.26 174.28,83.26 173.61,82.59 173.61,80.46 168.95,75.8 v3(168.95,72.62) 168.95,70.3 166.03,67.38 164.92,67.38 164.7,67.61 162.05,67.61 UV2.K26
FBA_A6_A11_L: length 27.3
  BOTTOM w0.165: UV3.K5 181.81,66.8 181.6,66.58 172.55,66.58 170.81,64.84 170.81,62.21 170.65,62.05 v3(170.03,62.05) 169.54,62.05 169.37,61.88 169.37,61.58 169.21,61.41 168.88,61.41 168.71,61.58 168.71,61.88 168.54,62.05 168.21,62.05 168.05,61.88 168.05,61.58 167.88,61.41 167.55,61.41 167.39,61.58 167.39,61.88 167.22,62.05 166.89,62.05 166.73,61.88 166.73,61.58 166.56,61.41 165.86,61.41 163.66,63.62 162.86,63.62 162.76,63.51 162.24,63.51 161.84,63.91 UV2.F26
FBA_A7_A8_H: length 34.9
  BOTTOM w0.165: UV2.M25 161.27,68.44 161.79,68.44 162.23,68 165.93,68 168.44,70.51 v3(168.44,71.09) 168.44,76.01 173.1,80.68 173.1,82.83 174.03,83.77 178.18,83.77 178.56,84.15 180.97,84.15 182.24,82.88 182.24,82.07 UV4.H4
FBA_A7_A8_L: length 30.5
  BOTTOM w0.165: UV2.F25 161.3,63.45 161.77,63.45 162.01,63.21 163.09,63.21 163.16,63.29 163.48,63.29 163.83,62.94 163.83,62.58 165.76,60.65 v3(166.62,60.65) 168.15,60.65 168.4,60.91 168.81,60.91 169.07,60.65 169.68,60.65 169.84,60.82 169.84,61.2 170.01,61.36 170.34,61.36 170.5,61.2 170.5,60.82 170.67,60.65 171.22,60.65 171.38,60.82 171.38,64.53 172.93,66.07 182.01,66.07 182.2,66.26 182.2,67.49 UV3.K4
FBA_A12_RFU_H: length 37.5
  TOP w0.165: v1(159.64,66.8) 160.02,67.18 161.47,67.18 161.68,67.39 167.78,67.39 170.18,69.79 v3(170.18,76.58) 170.18,79.95 174.22,83.99 180.66,83.99 181.38,83.27 181.38,82.07 v1(181.41,82.04)
  BOTTOM w0.165: v1(159.64,66.8) UV2.J23 ; UV4.J5 v1(181.41,82.04)
FBA_A12_RFU_L: length 33.5
  TOP w0.165: v1(157.98,64.3) 158.01,64.28 161.15,64.28 161.23,64.2 164.38,64.2 165.14,63.44 165.14,62.38 165.31,62.22 165.78,62.22 165.94,62.38 165.94,62.89 166.11,63.06 166.44,63.06 166.6,62.89 166.6,62.38 166.77,62.22 167.1,62.22 167.26,62.38 167.26,62.89 167.43,63.06 167.76,63.06 167.92,62.89 167.92,62.38 168.09,62.22 168.42,62.22 168.58,62.38 168.58,62.89 168.75,63.06 169.08,63.06 169.24,62.89 169.24,62.38 169.41,62.22 v3(170.35,62.22) 170.69,62.56 170.69,63.57 172.97,65.85 181.22,65.85 181.41,66.05 v1(181.41,67.47)
  BOTTOM w0.165: UV2.G22 v1(157.98,64.3) ; UV3.J5 181.41,67.47 v1(181.41,67.47)
FBA_ABI_H: length 37.2
  TOP w0.165: v1(180.61,82.04) 180.27,82.38 180.27,83.21 179.99,83.48 174.43,83.48 170.69,79.74 v3(170.69,75.05) 170.69,69.58 167.99,66.89 163.51,66.89 163.46,66.84 160.42,66.84 159.96,66.38 159.21,66.38 v1(158.8,66.79)
  BOTTOM w0.165: UV4.J4 v1(180.61,82.04) ; v1(158.79,66.79) UV2.K22
FBA_ABI_L: length 33.6
  TOP w0.165: v1(181.41,68.27) 181.68,68.01 182.15,68.01 182.32,67.84 v3(182.32,66.67) 182.32,65.51 182.15,65.34 173.18,65.34 171.19,63.36 171.19,62.05 170.85,61.71 168.99,61.71 168.82,61.54 168.82,61.3 168.66,61.13 168.33,61.13 168.16,61.3 168.16,61.54 168,61.71 167.67,61.71 167.5,61.54 167.5,61.3 167.34,61.13 167.01,61.13 166.84,61.3 166.84,61.54 166.68,61.71 166.35,61.71 166.18,61.54 166.18,61.3 166.02,61.13 165.69,61.13 165.52,61.3 165.52,61.54 165.36,61.71 164.81,61.71 164.56,61.96 164.56,63.08 163.85,63.79 161.01,63.79 160.88,63.92 160.1,63.92 v1(159.66,63.49)
  BOTTOM w0.165: v1(159.66,63.49) UV2.F23 ; v1(181.41,68.27) 181.41,68.27 UV3.J4
FBA_CAS_H: length 32.4
  BOTTOM w0.165: UV4.G3 182.24,80.47 182.24,78.26 180.59,76.61 v3(175.92,76.61) 172.8,76.61 170.98,74.79 170.98,69.46 166.62,65.1 164.84,65.1 164.29,65.66 163.65,65.66 163.29,66.02 162.01,66.02 UV2.J26
FBA_CAS_L: length 29.5
  BOTTOM w0.165: UV2.G26 162.05,65.13 164.3,65.13 164.84,64.59 166.83,64.59 171.99,69.76 171.99,71.23 173.82,73.06 v3(179.63,73.06) 181.02,73.06 183,71.07 183,69.06 UV3.L3
FBA_CKE_H: length 31
  TOP w0.165: RV91.1 181.22,80.24 v1(181.41,80.44)
  BOTTOM w0.165: UV2.J27 163.55,66.39 163.76,66.18 164.34,66.18 164.92,65.61 166.41,65.61 170.47,69.67 170.47,75 v3(171.22,75.74) 172.59,77.12 180.18,77.12 181.39,78.33 181.39,80.42 v1(181.41,80.44) UV4.J3
FBA_CKE_L: length 28.3
  TOP w0.165: v1(181.39,69.05) 181.94,68.5 RV90.1
  BOTTOM w0.165: UV2.G27 164.21,64.71 164.84,64.08 167.04,64.08 v3(171.5,68.55) 172.5,69.55 172.5,70.85 174.07,72.42 180.89,72.42 181.69,71.62 181.69,70.71 181.44,70.45 181.44,69.1 v1(181.39,69.05) UV3.J3
FBA_CLK0: length 42.3
  TOP w0.114: v1(160.44,61.81) 160.63,61.81 161.03,61.41 162.23,61.41 163.47,60.18 163.47,58.32 163.78,58.01 164.64,58.01 164.98,58.35 164.98,58.95 165.18,59.15 165.46,59.15 165.66,58.95 165.66,58.74 165.91,58.49 166.56,58.49 166.8,58.74 166.8,58.95 167.01,59.15 167.29,59.15 167.49,58.95 167.49,56.61 167.74,56.36 168.39,56.36 168.63,56.61 168.63,58.95 168.83,59.15 169.12,59.15 169.32,58.95 169.32,58.09 169.65,57.76 170.13,57.76 170.46,58.09 170.46,58.95 170.66,59.15 170.95,59.15 171.15,58.95 171.15,58.09 171.48,57.76 172.62,57.76 172.97,58.11 172.97,62.05 174.01,63.09 178.41,63.09 180.19,61.31 180.37,61.31 v1(180.61,61.07) 180.89,61.35 181.05,61.35 181.17,61.22 181.17,60.98 180.52,60.33 180.52,59.95 RV105.1 180.35,59.78 RV104.1
  BOTTOM w0.102: v1(160.44,61.81) UV2.D24
  BOTTOM w0.112: UV3.J12 v1(180.61,61.07)
FBA_CLK0_N: length 42.8
  TOP w0.114: v1(161.24,61.81) 161.4,61.64 161.53,61.64 161.69,61.8 161.99,61.8 162.14,61.64 162.33,61.64 163.7,60.27 163.7,58.41 163.87,58.24 164.55,58.24 164.75,58.44 164.75,59.05 165.08,59.38 165.56,59.38 165.89,59.05 165.89,58.84 166,58.72 166.46,58.72 166.58,58.84 166.58,59.05 166.91,59.38 167.38,59.38 167.72,59.05 167.72,56.7 167.83,56.59 168.29,56.59 168.4,56.7 168.4,59.05 168.74,59.38 169.21,59.38 169.55,59.05 169.55,58.19 169.75,57.99 170.03,57.99 170.23,58.19 170.23,59.05 170.57,59.38 171.04,59.38 171.38,59.05 171.38,58.19 171.58,57.99 172.52,57.99 172.74,58.21 172.74,62.14 173.92,63.32 178.51,63.32 179.04,62.79 179.22,62.79 179.45,62.55 179.45,62.38 179.69,62.14 179.86,62.14 180.1,61.91 180.1,61.73 180.29,61.54 180.5,61.54 180.61,61.66 v1(180.61,61.87) 180.91,61.58 181.14,61.58 181.4,61.31 181.4,60.89 180.75,60.23 180.75,59.95 RV105.2 180.91,59.78 RV107.1
  BOTTOM w0.102: v1(161.24,61.81) 161.31,61.88 161.31,62.15 161.15,62.3 160.92,62.3 UV2.D25
  BOTTOM w0.112: 180.9,61.87 181.01,61.99 UV3.J11
  BOTTOM w0.114: v1(180.61,61.87) 180.9,61.87
FBA_CLK1: length 42.2
  TOP w0.114: v1(158,69.28) 158.23,69.28 158.6,69.64 165.2,69.64 166.72,71.17 166.72,72.97 166.52,73.17 165.31,73.17 164.97,73.5 164.97,73.98 165.31,74.31 166.52,74.31 166.72,74.51 166.72,81.02 172.14,86.43 178.43,86.43 180.11,88.11 180.28,88.11 v1(180.61,88.44) 180.87,88.19 181.07,88.19 181.27,88.38 181.27,88.61 RV108.1 181.12,88.77 RV106.1
  BOTTOM w0.102: v1(158,69.28) 158.4,69.67 UV2.N22
  BOTTOM w0.114: UV4.J12 v1(180.61,88.44)
FBA_CLK1_N: length 42.8
  TOP w0.114: RV109.1 181.68,88.77 RV108.2 181.5,88.59 181.5,88.29 181.17,87.96 180.93,87.96 v1(180.61,87.64) 180.61,87.68 180.42,87.88 180.2,87.88 180.03,87.71 180.03,87.53 179.8,87.3 179.62,87.3 179.29,86.97 179.29,86.79 179.06,86.56 178.88,86.56 178.53,86.21 172.24,86.21 166.95,80.92 166.95,74.42 166.62,74.08 165.4,74.08 165.2,73.88 165.2,73.6 165.4,73.4 166.62,73.4 166.95,73.06 166.95,71.07 165.29,69.42 160.8,69.42 160.67,69.29 160.34,69.29 160.22,69.42 159.89,69.42 159.76,69.29 159.43,69.29 159.3,69.42 158.91,69.42 158.8,69.3 v1(158.8,69.25)
  BOTTOM w0.102: UV2.M22 158.69,68.87 158.8,68.98 v1(158.8,69.25)
  BOTTOM w0.114: v1(180.61,87.64) 180.53,87.56 180.53,87.22 180.68,87.07 180.84,87.07 UV4.J11
FBA_CS_H: length 32.5
  BOTTOM w0.165: UV2.M24 160.47,69.31 163.96,69.31 164.2,69.54 165.1,69.54 166.91,71.36 v3(166.91,75.41) 166.91,76.64 171.58,81.31 171.58,83.47 173.4,85.29 177.33,85.29 178.05,86.01 178.79,86.01 179.02,86.24 179.02,87.65 UV4.L12
FBA_CS_L: length 26.9
  BOTTOM w0.165: UV3.G12 179.02,61.86 179.02,63.74 178.81,63.96 173.86,63.96 173.48,63.58 173.48,58.11 172.97,57.6 v3(168.6,57.6) 165.53,57.6 163.45,59.69 163.45,60.4 UV2.C27
FBA_D0: length 26.3
  ART06 w0.102: 173.63,68.25 174.03,68.65 174.63,68.65 v1(175.01,68.27)
  ART06 w0.14: v1(155.45,62.62) 155.45,61.54 156.39,60.6 159.1,60.6 159.92,59.79 163.07,59.79 165.75,62.47 167.85,62.47 173.63,68.25
  BOTTOM w0.165: v1(155.45,62.62) UV2.E18 ; UV3.B4 v1(175.01,68.27)
FBA_D1: length 25.8
  ART06 w0.14: v1(155.45,63.46) 155.89,63.02 155.89,62 155.85,61.96 155.85,61.65 156.61,60.88 159.38,60.88 160.12,60.14 162.2,60.14 165.12,63.07 167.79,63.07 173.79,69.06 v1(174.19,69.06)
  BOTTOM w0.165: UV2.F18 v1(155.45,63.46) ; v1(174.19,69.06) UV3.A2
FBA_D2: length 31.5
  ART06 w0.102: 177.82,70.87 177.82,70.86 177.82,70.27 v1(178.21,69.87)
  ART06 w0.14: 177.82,70.87 177.82,71.04 176.83,72.04 173.53,72.04 166.97,65.48 163.45,65.48 161.87,63.9 158.57,63.9 157.69,63.03 156.93,63.03 156.74,63.22 156.74,63.6 156.5,63.84 155.64,63.84 155.62,63.86 154.14,63.86 v1(153.73,63.45)
  BOTTOM w0.165: v1(178.21,69.87) 178.21,69.87 UV3.E2 ; UV2.E16 153.38,63.01 153.73,63.37 v1(153.73,63.45)
FBA_D3: length 27.1
  ART06 w0.14: v1(174.21,67.47) 173.49,67.47 167.92,61.9 165.89,61.9 162.94,58.95 160.96,58.95 160.53,59.38 159.89,59.38 158.93,60.35 156.13,60.35 155.08,61.4 155.08,62.34 155.01,62.41 155.01,63.07 v1(154.63,63.45)
  BOTTOM w0.165: UV2.F17 154.62,63.45 v1(154.63,63.45) ; UV3.A4 174.21,67.48 v1(174.21,67.47)
FBA_D4: length 23.4
  ART06 w0.102: 161.42,61.41 157.52,61.41 v1(157.12,61.81)
  ART06 w0.14: 161.42,61.41 161.59,61.41 161.99,61.81 161.99,62.16 163.93,64.11 167.54,64.11 173.87,70.43 174.46,70.43 v1(175.02,69.87)
  BOTTOM w0.165: UV3.B2 v1(175.02,69.87) ; UV2.D20 157.1,61.81 v1(157.12,61.81)
FBA_D5: length 28.2
  ART06 w0.102: v1(178.21,68.27) 177.01,69.48 177.01,70.81
  ART06 w0.14: v1(157.12,62.61) 158.1,62.61 158.56,63.08 160.78,63.08 161.15,63.45 162.02,63.45 163.6,65.02 167.16,65.02 173.72,71.58 176.39,71.58 177.01,70.96 177.01,70.81
  BOTTOM w0.165: v1(178.21,68.27) 178.21,68.27 UV3.E4 ; v1(157.12,62.61) 157.52,62.21 UV2.D21
FBA_D6: length 31.7
  ART06 w0.14: v1(156.28,64.25) 156.74,64.72 161.41,64.72 161.67,64.97 161.67,65.86 162.67,66.86 164.23,66.86 164.69,66.39 166.59,66.39 168.37,68.17 168.37,68.18 173.15,72.95 177.39,72.95 179.47,70.88 179.47,69.53 179.02,69.08 v1(179.03,69.08)
  BOTTOM w0.165: v1(156.28,64.25) 156.68,63.85 UV2.F20 ; UV3.F2 179,69.08 v1(179.03,69.08)
FBA_D7: length 30.6
  ART06 w0.14: v1(178.99,68.3) 178.62,68.67 178.62,68.89 178.62,68.89 178.62,69.26 178.62,69.26 178.62,69.69 178.62,69.69 178.62,70.06 178.62,70.06 178.62,70.49 178.62,70.5 178.62,70.83 178.62,70.85 176.98,72.5 173.34,72.5 166.78,65.93 164.25,65.93 163.82,66.37 162.81,66.37 162.24,65.8 162.24,64.91 161.68,64.35 158.61,64.35 157.7,63.44 v1(157.17,63.44)
  BOTTOM w0.165: v1(178.99,68.3) 178.99,68.25 UV3.F4 ; v1(157.17,63.44) 157.54,63.07 UV2.E21
FBA_D8: length 31.8
  ART06 w0.14: v1(174.21,62.67) 172.67,62.67 165.83,55.83 156.75,55.83 155.61,56.97 154.68,56.97 154.23,57.43 153.72,57.43 153.34,57.8 153.34,58.68 152.57,59.45 152.57,63.02 152.18,63.41 v1(152.16,63.41)
  BOTTOM w0.165: v1(174.21,62.67) 174.61,62.28 UV3.A11 ; v1(152.16,63.41) 152.18,63.41 152.36,63.23 UV2.E15
FBA_D9: length 33.8
  ART06 w0.14: v1(173.94,60.8) 172.74,60.8 166.39,54.46 153.99,54.46 151.21,57.23 151.21,58.27 150.96,58.52 150.96,59.29 151.4,59.73 151.4,61.86 v1(152.16,62.61)
  BOTTOM w0.165: UV2.D15 152.56,62.21 v1(152.16,62.61) ; v1(173.94,60.8) 174.49,60.8 UV3.A13
FBA_D10: length 33.3
  ART06 w0.14: v1(175.01,62.67) 174.5,63.19 172.54,63.19 165.64,56.28 156.89,56.28 155.19,57.99 154.68,57.99 154.48,57.78 153.92,57.78 153.67,58.04 153.67,58.92 152.86,59.74 152.86,63.56 v1(152.15,64.26)
  BOTTOM w0.165: v1(152.15,64.26) 152.17,64.26 UV2.F15 ; v1(175.01,62.67) UV3.B11
FBA_D11: length 36
  ART06 w0.14: v1(150.49,63.38) 150.93,62.94 150.93,62.17 150.96,62.14 150.96,59.86 150.64,59.54 150.64,57.2 153.85,54 166.74,54 172.27,59.54 174.27,59.54 v1(175.01,60.27)
  BOTTOM w0.165: UV3.B13 175.41,60.67 v1(175.01,60.27) ; v1(150.49,63.38) 150.49,63.45 UV2.F13
FBA_D12: length 39.8
  ART06 w0.102: 177.82,60.1 177.82,61.47 v1(177.41,61.87)
  ART06 w0.14: 177.82,60.1 177.82,60.04 176.15,58.37 172.4,58.37 167.11,53.08 153.74,53.08 150,56.82 150,60.48 v1(150.52,60.99)
  BOTTOM w0.165: UV3.E11 177.81,62.27 v1(177.41,61.87) ; UV2.C13 150.9,61.37 v1(150.52,60.99)
FBA_D13: length 36.5
  ART06 w0.102: 177,60.14 177,60.66 v1(177.41,61.07)
  ART06 w0.14: 177,60.14 177,59.98 175.89,58.87 172.26,58.87 166.93,53.54 153.8,53.54 150.3,57.04 150.3,60 v1(150.52,60.21)
  BOTTOM w0.165: v1(150.52,60.21) 150.9,60.59 UV2.B13 ; v1(177.41,61.07) UV3.E13
FBA_D14: length 44.4
  ART06 w0.102: 178.6,60.14 178.6,61.49 v1(178.21,61.87)
  ART06 w0.14: 178.6,60.14 178.6,59.54 176.41,57.35 172.67,57.35 167.49,52.17 153.57,52.17 149.3,56.44 149.3,60.83 150.11,61.64 150.11,62.21 v1(150.52,62.61)
  BOTTOM w0.165: UV2.E13 150.52,62.63 v1(150.52,62.61) ; UV3.F11 178.21,61.88 v1(178.21,61.87)
FBA_D15: length 40.3
  ART06 w0.14: v1(178.21,60.27) 178.21,59.83 176.25,57.86 172.54,57.86 167.3,52.63 153.69,52.63 149.67,56.65 149.67,60.73 150.52,61.58 v1(150.52,61.81)
  BOTTOM w0.165: UV3.F13 178.61,60.67 v1(178.21,60.27) ; UV2.D13 150.9,62.19 v1(150.52,61.81)
FBA_D16: length 46
  ART03 w0.102: 186.58,59.21 186.63,59.26 186.63,59.89 v1(187.01,60.27)
  ART03 w0.14: 186.58,59.21 184.75,57.38 184.05,57.38 183.06,56.39 171.85,56.39 167.65,52.18 156.3,52.18 153.92,54.56 153.36,54.56 152.22,55.7 152.22,57.44 v1(152.42,57.64)
  BOTTOM w0.165: UV3.U13 187.41,60.67 v1(187.01,60.27) ; v1(152.42,57.64) 151.91,58.14 151.91,58.72 152.13,58.94 152.13,60.17 UV2.B15
FBA_D17: length 44.8
  ART03 w0.102: 185.82,59.35 185.82,59.91 186.18,60.27 v1(186.21,60.27)
  ART03 w0.14: 185.82,59.35 185.82,59.28 184.27,57.73 182.88,57.73 181.99,56.84 171.65,56.84 167.43,52.63 156.49,52.63 154.11,55 153.48,55 152.91,55.57 152.91,55.77 v1(153.14,56.01)
  BOTTOM w0.165: v1(186.21,60.27) 186.61,60.67 UV3.T13 ; v1(153.14,56.01) 153.14,56.62 152.97,56.8 152.97,61 UV2.C16
FBA_D18: length 41.5
  ART03 w0.102: v1(184.61,60.27) 184.2,59.86 184.2,59.25
  ART03 w0.14: v1(152.65,56.42) 153.39,56.42 156.74,53.07 167.22,53.07 171.37,57.22 178.66,57.22 179.3,57.86 182.46,57.86 182.93,58.32 183.41,58.32 184.2,59.12 184.2,59.25
  BOTTOM w0.165: UV3.N13 v1(184.61,60.27) ; UV2.A13 150.9,58.84 151.52,58.22 151.52,57.55 v1(152.65,56.42)
FBA_D19: length 39.2
  ART03 w0.14: v1(152.42,58.27) 152.91,57.78 154.48,57.78 154.58,57.88 155.07,57.88 155.27,57.68 155.27,57.53 157.95,54.85 166.25,54.85 173.48,62.08 173.48,62.68 174.06,63.26 179.04,63.26 179.16,63.14 183.19,63.14 183.65,62.68 v1(183.81,62.68)
  BOTTOM w0.165: v1(152.42,58.27) 152.42,58.57 152.58,58.73 UV2.A15 ; v1(183.81,62.68) UV3.N11
FBA_D20: length 40.4
  ART03 w0.102: 184.2,62.88 184.2,62.27 v1(183.81,61.88)
  ART03 w0.14: 184.2,62.88 183.76,63.32 183.64,63.32 182.98,63.98 173.76,63.98 172.99,63.21 172.99,62.25 166.04,55.29 158.01,55.29 155.07,58.24 154.25,58.24 v1(154.2,58.19)
  BOTTOM w0.165: v1(154.2,58.19) 154.67,58.65 154.67,60.22 UV2.B18 ; UV3.M11 v1(183.81,61.88)
FBA_D21: length 39.6
  ART03 w0.102: v1(183.81,60.27) 183.41,59.87 183.41,59.31
  ART03 w0.14: v1(154.81,57.48) 154.76,57.43 153.78,57.43 153.62,57.26 153.62,56.78 156.89,53.52 167,53.52 171.22,57.73 178.31,57.73 179.02,58.45 181.78,58.45 182.23,58.9 183.27,58.9 183.41,59.04 183.41,59.31
  BOTTOM w0.165: UV2.A18 155.06,57.72 v1(154.81,57.48) ; v1(183.81,60.27) UV3.M13
FBA_D22: length 38.8
  ART03 w0.102: 185.82,63.66 185.82,63.07 v1(186.21,62.67)
  ART03 w0.14: 185.82,63.66 184.99,64.48 173.63,64.48 172.59,63.45 172.59,62.56 165.75,55.71 158.84,55.71 157.35,57.2 156.82,57.2 v1(156.67,57.35)
  BOTTOM w0.165: v1(156.67,57.35) 156.67,57.91 155.86,58.72 UV2.A19 ; v1(186.21,62.67) UV3.T11
FBA_D23: length 41.7
  ART03 w0.14: v1(155.94,57.97) 156.63,57.97 157.07,57.53 157.53,57.53 158.9,56.16 165.56,56.16 172.23,62.83 172.23,63.6 173.6,64.97 185.4,64.97 187.01,63.35 v1(187.01,62.67)
  BOTTOM w0.165: UV3.U11 v1(187.01,62.67) ; v1(155.94,57.97) 155.44,58.47 155.44,61 UV2.C19
FBA_D24: length 37.6
  ART03 w0.102: 186.63,66.46 186.63,67.1 v1(187.02,67.48)
  ART03 w0.14: v1(164.18,57.46) 164.6,57.05 165.17,57.05 169.82,61.69 169.82,61.89 169.51,62.2 169.51,62.4 169.71,62.59 169.9,62.59 170.21,62.28 170.41,62.28 170.61,62.48 170.61,62.68 170.3,62.99 170.3,63.19 170.5,63.38 170.69,63.38 171.01,63.07 171.2,63.07 171.34,63.21 171.34,64.48 171.68,64.82 171.93,64.82 172.2,65.09 172.2,65.34 172.77,65.91 184.13,65.91 184.27,66.05 184.27,66.1 184.41,66.24 184.69,66.24 184.83,66.1 184.83,66.05 184.97,65.91 186.22,65.91 186.63,66.33 186.63,66.46
  BOTTOM w0.165: UV3.T4 186.62,67.88 v1(187.02,67.48) ; UV2.B24 160.43,60.22 160.43,59.69 161.5,58.61 163.03,58.61 v1(164.18,57.46)
FBA_D25: length 38.7
  ART03 w0.14: v1(161.88,57.46) 162.66,58.24 163.45,58.24 169.54,64.33 169.54,65.95 171.73,68.15 173.54,68.15 173.68,68.29 173.68,68.55 173.54,68.69 172.81,68.69 172.67,68.83 172.67,69.11 172.81,69.25 173.54,69.25 173.68,69.39 173.68,70.1 175.05,71.47 181.9,71.47 182.18,71.19 182.46,71.19 182.74,71.47 183.12,71.47 183.26,71.33 183.26,70.43 v1(183.81,69.87)
  BOTTOM w0.165: UV2.C23 159.6,61 159.6,59.4 161.07,57.93 161.41,57.93 v1(161.88,57.46) ; UV3.M2 183.42,69.48 v1(183.81,69.87)
FBA_D26: length 36
  ART03 w0.102: 182.82,67.09 183.42,67.09 v1(183.81,67.48)
  ART03 w0.14: 182.82,67.09 182.57,67.09 182.03,66.55 171.63,66.55 171.43,66.35 171.43,66.16 171.71,65.88 171.71,65.69 171.51,65.49 171.31,65.49 171.04,65.76 170.84,65.76 170.65,65.57 170.65,64.18 168.65,62.17 168.65,61.98 168.96,61.67 168.96,61.47 168.76,61.27 168.57,61.27 168.26,61.58 168.06,61.58 167.86,61.38 167.86,61.19 168.17,60.88 168.17,60.68 167.97,60.48 167.78,60.48 167.47,60.79 167.27,60.79 167.07,60.59 167.07,60.4 167.38,60.09 167.38,59.89 167.18,59.69 166.99,59.69 166.68,60 166.48,60 166.28,59.8 166.28,59.61 166.59,59.3 166.59,59.1 166.39,58.9 166.2,58.9 165.89,59.21 165.69,59.21 165.41,58.93 165.41,58.68 165.14,58.41 164.89,58.41 164.57,58.09 164.57,57.84 v1(164.95,57.46)
  BOTTOM w0.165: UV2.A25 161.14,59.51 161.7,58.95 163.46,58.95 v1(164.95,57.46) ; v1(183.81,67.48) UV3.N4
FBA_D27: length 35.3
  ART03 w0.14: v1(163.41,57.46) 164.27,56.6 165.36,56.6 171.72,62.96 171.72,63.81 173.36,65.45 186.53,65.45 187.42,66.34 187.42,67.08 v1(187.82,67.48)
  BOTTOM w0.165: UV2.A24 160.04,59.53 161.28,58.29 162.59,58.29 v1(163.41,57.46) ; UV3.U4 187.42,67.88 v1(187.82,67.48)
FBA_D28: length 38.4
  ART03 w0.102: 184.22,70.76 184.22,69.47 v1(184.62,69.07)
  ART03 w0.14: 184.22,70.76 184.22,71.05 183.32,71.95 174.85,71.95 169.06,66.17 169.06,64.62 163.07,58.62 162.28,58.62 v1(161.12,57.46)
  BOTTOM w0.165: v1(184.62,69.07) UV3.N2 ; v1(161.12,57.46) 160.63,56.97 159.9,56.97 157.75,59.12 157.75,59.48 157.54,59.69 UV2.A21
FBA_D29: length 41.9
  ART03 w0.14: v1(183.81,68.27) 183.41,68.27 183.27,68.41 183.27,69.02 183.13,69.16 182.85,69.16 182.71,69.02 182.71,68.41 182.57,68.27 182.12,68.27 181.99,68.15 181.99,67.26 181.77,67.04 181.03,67.04 180.89,67.18 180.89,67.63 180.75,67.76 180.47,67.76 180.33,67.63 180.33,67.18 180.19,67.04 177.81,67.04 177.67,67.18 177.67,67.63 177.53,67.76 177.25,67.76 177.11,67.63 177.11,67.18 176.97,67.04 173.62,67.04 173.48,67.18 173.48,67.5 173.34,67.64 173.06,67.64 172.92,67.5 172.92,67.18 172.78,67.04 172.5,67.04 172.36,67.18 172.36,67.5 172.22,67.64 171.94,67.64 171.8,67.5 171.8,67.18 171.66,67.04 171.35,67.04 170.05,65.73 170.05,64.21 163.73,57.88 163.22,57.88 162.96,57.63 162.96,57.25 162.69,56.97 v1(158.75,56.97)
  BOTTOM w0.107: UV2.B21 157.54,60.54 157.15,60.15 157.15,59.72 157.45,59.42 157.45,59.38
  BOTTOM w0.165: v1(158.75,56.97) 158.75,57.6 157.45,58.9 157.45,59.38 ; v1(183.81,68.27) 183.42,67.88 UV3.M4
FBA_D30: length 46.9
  ART03 w0.102: 187.42,70.76 187.42,70.27 v1(187.81,69.87)
  ART03 w0.14: v1(157.76,57.91) 157.17,57.91 156.92,58.16 156.92,58.57 158.88,60.53 162.13,60.53 167.13,65.53 167.13,66.96 174.05,73.88 184.8,73.88 187.42,71.27 187.42,70.76
  BOTTOM w0.165: UV3.U2 187.42,69.48 v1(187.81,69.87) ; UV2.C20 156.24,60.96 156.24,58.89 157.22,57.91 v1(157.76,57.91)
FBA_D31: length 43.5
  ART03 w0.102: v1(187.01,69.07) 186.61,69.48 186.61,70.04
  ART03 w0.14: v1(157.35,58.37) 159.18,60.2 162.23,60.2 162.75,60.72 163,60.72 167.59,65.31 167.59,66.74 174.25,73.4 184.33,73.4 186.61,71.13 186.61,70.04
  BOTTOM w0.107: UV2.C21 157.08,60.96 157.08,60.46 156.91,60.29 156.91,59.64 157.09,59.46 157.09,59.38
  BOTTOM w0.165: 157.09,59.38 157.09,58.63 v1(157.35,58.37) ; UV3.T2 v1(187.01,69.07)
FBA_D32: length 22.2
  ART06 w0.14: v1(174.21,81.24) 173.75,81.24 172.57,80.05 172.57,78.87 165.98,72.28 161.86,72.28 161.52,71.94 159.27,71.94 159,72.21 158.41,72.21 v1(157.98,71.77)
  BOTTOM w0.165: v1(157.98,71.77) 158.21,71.54 UV2.R22 ; UV4.U4 v1(174.21,81.24)
FBA_D33: length 20.3
  ART06 w0.14: v1(159.64,70.93) 160.04,71.34 162.54,71.34 162.99,70.88 166.4,70.88 173.73,78.22 173.73,79.16 v1(174.21,79.64)
  BOTTOM w0.165: UV4.U2 v1(174.21,79.64) ; v1(159.64,70.93) 160.04,71.33 UV2.R24
FBA_D34: length 23.1
  ART06 w0.14: v1(158,72.57) 159.02,72.57 159.37,72.22 161.06,72.22 161.48,72.64 164.07,72.64 164.14,72.71 165.76,72.71 172.11,79.06 172.11,80.23 173.91,82.04 v1(175.01,82.04)
  BOTTOM w0.165: v1(175.01,82.04) 175.02,82.04 UV4.T4 ; v1(158,72.57) 158.4,72.17 UV2.T22
FBA_D35: length 22.1
  ART06 w0.102: 174,80.85 174.6,80.85 v1(175.01,80.44)
  ART06 w0.14: v1(158.82,71.77) 158.94,71.65 162,71.65 162.17,71.82 166.17,71.82 173.02,78.68 173.02,79.87 174,80.85
  BOTTOM w0.165: UV2.R23 159.05,71.54 v1(158.82,71.77) ; UV4.T2 v1(175.01,80.44)
FBA_D36: length 25.6
  ART06 w0.102: 177.81,78.69 177.81,80.85 v1(178.2,81.25)
  ART06 w0.14: 177.81,78.69 177.81,78.57 176.04,76.8 174.9,76.8 166.66,68.56 162.35,68.56 161.24,69.68 v1(161.24,70.09)
  BOTTOM w0.165: UV2.N25 160.84,69.69 v1(161.24,70.09) ; UV4.N4 v1(178.2,81.25)
FBA_D37: length 22.8
  ART06 w0.102: v1(177.41,80.45) 177.01,80.05 177.01,78.69
  ART06 w0.14: 177.01,78.69 177.01,78.53 175.85,77.37 174.83,77.37 166.58,69.13 162.55,69.13 162.01,69.67 v1(162.01,70.09)
  BOTTOM w0.165: v1(177.41,80.45) UV4.N2 ; UV2.N26 161.64,69.72 v1(162.01,70.09)
FBA_D38: length 29.4
  ART06 w0.14: v1(179.01,81.24) 179.48,80.77 179.48,78.72 176.61,75.85 175.21,75.85 166.97,67.6 161.97,67.6 159.64,69.93 v1(159.64,70.09)
  BOTTOM w0.165: UV2.N23 159.24,69.69 v1(159.64,70.09) ; v1(179.01,81.24) UV4.M4
FBA_D39: length 25.9
  ART06 w0.102: 178.61,78.63 178.61,79.24 v1(178.21,79.64)
  ART06 w0.14: v1(160.44,70.09) 160.44,69.8 162.16,68.08 166.82,68.08 175.07,76.32 176.38,76.32 178.61,78.55 178.61,78.63
  BOTTOM w0.165: UV4.M2 178.61,80.04 v1(178.21,79.64) ; UV2.N24 160.44,70.07 v1(160.44,70.09)
FBA_D40: length 24.6
  ART06 w0.102: 160.65,73.83 159.24,73.83 v1(158.84,74.24)
  ART06 w0.14: 160.65,73.83 165.46,73.83 167.76,76.13 167.76,80.39 v1(174.21,86.84)
  BOTTOM w0.165: v1(158.84,74.24) 158.84,74.23 UV2.V23 ; UV4.U11 v1(174.21,86.84)
FBA_D41: length 26.7
  ART06 w0.14: v1(158.01,74.22) 158.01,74.89 158.61,75.48 159.05,75.48 159.22,75.66 159.22,76.1 159.41,76.28 161.36,76.28 161.38,76.3 161.39,76.3 161.63,76.53 161.63,76.87 161.62,76.88 161.62,76.89 161.85,77.11 163.27,77.11 163.45,77.29 165.1,77.29 165.53,77.72 165.53,81.45 173.52,89.44 174.01,89.44 v1(174.21,89.24)
  BOTTOM w0.165: UV4.U13 v1(174.21,89.24) ; UV2.V22 v1(158.01,74.22)
FBA_D42: length 30
  ART06 w0.102: 160.59,73.03 159.18,73.03 v1(158.84,73.37)
  ART06 w0.14: 160.59,73.03 160.75,73.03 160.83,72.95 163.89,72.95 164.13,73.19 165.47,73.19 171.45,79.17 171.45,80.72 177.04,86.31 178.56,86.31 178.79,86.53 178.79,87.07 v1(178.21,87.64)
  BOTTOM w0.165: UV4.M11 v1(178.21,87.64) ; v1(158.84,73.37) 158.84,72.55 UV2.T23
FBA_D43: length 27.3
  ART06 w0.102: v1(158.01,73.38) 158.42,73.8 158.42,74.48 158.58,74.64 159.83,74.64
  ART06 w0.14: v1(175.01,87.64) 173.66,87.64 166.85,80.83 166.85,76.5 165.5,75.15 162.5,75.15 161.94,74.59 161.09,74.59 160.7,74.99 160.18,74.99 159.83,74.64
  BOTTOM w0.165: UV4.T11 v1(175.01,87.64) ; v1(158.01,73.38) UV2.U22
FBA_D44: length 26.9
  ART06 w0.102: v1(177.41,87.64) 177.01,88.04 177.01,88.62 176.78,88.85 174.01,88.85
  ART06 w0.14: 174.01,88.85 173.57,88.85 165.93,81.21 165.93,76.86 165.3,76.22 162.14,76.22 161.79,75.87 v1(160.43,75.87)
  BOTTOM w0.165: v1(160.43,75.87) UV2.Y24 ; UV4.N11 v1(177.41,87.64)
FBA_D45: length 23.7
  ART06 w0.102: v1(160.41,76.69) 160.61,76.69 161.05,77.13 161.42,77.13 161.65,77.35 161.65,77.71 161.83,77.89
  ART06 w0.14: 161.83,77.89 161.91,77.98 164.77,77.98 165.08,78.28 165.08,81.64 173.38,89.95 174.31,89.95 v1(175.01,89.24)
  BOTTOM w0.165: v1(160.41,76.69) UV2.AA24 ; UV4.T13 v1(175.01,89.24)
FBA_D46: length 30
  ART06 w0.14: v1(178.21,89.24) 177.67,89.78 177.67,90.7 177.37,91 173.14,91 164.17,82.03 164.17,80.17 163.57,79.58 161.8,79.58 160.81,78.59 160.81,78.2 160.57,77.96 160.55,77.96 160.54,77.96 160.24,77.96 160.03,77.74 160.03,77.37 159.78,77.12 159.33,77.12 158.81,76.6 v1(158.81,75.89)
  BOTTOM w0.165: UV4.M13 v1(178.21,89.24) ; UV2.Y22 v1(158.81,75.89)
FBA_D47: length 27.2
  ART06 w0.102: v1(159.63,76.71) 159.85,76.71 160.27,77.12 160.66,77.12 160.86,77.32 160.86,77.75 161.04,77.93
  ART06 w0.14: 161.04,77.93 161.42,77.93 162.56,79.07 164.08,79.07 164.56,79.54 164.56,81.77 173.37,90.58 176.78,90.58 176.96,90.4 176.96,89.69 v1(177.41,89.24)
  BOTTOM w0.165: UV2.AA23 v1(159.63,76.71) ; UV4.N13 v1(177.41,89.24)
FBA_D48: length 33.6
  ART03 w0.14: v1(186.21,89.24) 186.21,89.24 186.21,90.34 185.7,90.85 182.27,90.85 182.06,91.06 172.95,91.06 166.01,84.11 166.01,80.35 164.42,78.77 v1(164.42,78.43)
  BOTTOM w0.165: v1(164.42,78.43) 163.97,78.88 162.5,78.88 UV2.AD27 ; UV4.B13 v1(186.21,89.24)
FBA_D49: length 39
  ART03 w0.102: v1(187.81,87.64) 187.42,88.03 187.42,89.35
  ART03 w0.14: v1(161.24,77.52) 163.05,79.33 163.66,79.33 165.04,80.71 165.04,84.55 172.36,91.87 182.27,91.87 182.6,91.54 186.13,91.54 187.42,90.25 187.42,89.35
  BOTTOM w0.165: UV4.A11 v1(187.81,87.64) ; UV2.AB25 161.02,77.3 v1(161.24,77.52)
FBA_D50: length 36.7
  ART03 w0.14: v1(162.9,78.43) 163.34,78.87 163.84,78.87 165.52,80.56 165.52,84.33 172.65,91.45 182.18,91.45 182.45,91.18 185.88,91.18 186.61,90.45 186.61,88.04 v1(186.21,87.64)
  BOTTOM w0.165: UV4.B11 v1(186.21,87.64) ; UV2.AD26 162.02,78.43 v1(162.9,78.43)
FBA_D51: length 37.8
  ART03 w0.14: v1(161.22,78.35) 162.55,79.68 163.38,79.68 164.56,80.86 164.56,84.76 172.07,92.28 182.5,92.28 182.88,91.89 186.31,91.89 187.97,90.23 187.97,89.4 v1(187.81,89.24)
  BOTTOM w0.165: UV4.A13 v1(187.81,89.24) ; v1(161.22,78.35) UV2.AC25
FBA_D52: length 30.6
  ART03 w0.14: v1(162.82,76.7) 163.25,76.28 165.46,76.28 169.23,80.05 169.23,83.83 172.64,87.24 178.59,87.24 178.73,87.1 178.73,86.98 178.87,86.84 179.15,86.84 179.29,86.98 179.29,87.1 179.43,87.24 180.14,87.24 180.28,87.1 180.28,86.98 180.42,86.84 180.7,86.84 180.84,86.98 180.84,87.1 180.98,87.24 181.75,87.24 181.89,87.1 181.89,86.98 182.03,86.84 182.31,86.84 182.45,86.98 182.45,87.1 182.59,87.24 183.41,87.24 v1(183.81,87.64)
  BOTTOM w0.165: UV4.E11 v1(183.81,87.64) ; UV2.AA27 v1(162.82,76.7)
FBA_D53: length 33.1
  ART03 w0.14: v1(162.04,76.7) 162.88,75.86 165.72,75.86 169.67,79.81 169.67,83.64 172.47,86.44 184.03,86.44 184.21,86.62 UV4.E13 v1(184.61,89.24)
  BOTTOM w0.165: UV4.E13 v1(184.61,89.24) ; v1(162.04,76.7) 162.02,76.7 UV2.AA26
FBA_D54: length 33.5
  ART03 w0.14: v1(165.22,76.73) 168.78,80.29 168.78,81.55 168.64,81.69 168.04,81.69 167.9,81.83 167.9,82.11 168.04,82.25 168.64,82.25 168.78,82.39 168.78,82.67 168.64,82.81 168.04,82.81 167.9,82.95 167.9,83.23 168.04,83.37 168.64,83.37 168.78,83.51 168.78,84.08 172.74,88.04 179.09,88.04 179.23,87.9 179.23,87.84 179.37,87.7 179.65,87.7 179.79,87.84 179.79,87.9 179.93,88.04 181.37,88.04 181.51,87.9 181.51,87.84 181.65,87.7 181.93,87.7 182.07,87.84 182.07,87.9 182.21,88.04 182.61,88.04 v1(183.01,87.64)
  BOTTOM w0.165: UV2.W26 162.46,75.46 163.95,75.46 v1(165.22,76.73) ; UV4.F11 v1(183.01,87.64)
FBA_D55: length 32
  ART03 w0.14: v1(183.01,89.24) 182.61,88.84 172.84,88.84 167.45,83.46 167.45,81.32 167.59,81.18 168.11,81.18 168.27,81.02 168.27,80.76 168.13,80.62 167.59,80.62 167.45,80.48 167.45,79.57 165.07,77.18 164.88,77.18 v1(164.42,76.73)
  BOTTOM w0.165: v1(164.42,76.73) 163.56,75.86 161.22,75.86 UV2.Y25 ; UV4.F13 v1(183.01,89.24)
FBA_D56: length 33.6
  ART03 w0.102: v1(187.81,81.24) 187.41,80.84 187.41,79.53
  ART03 w0.14: 187.41,79.53 187.41,78.9 184.53,76.02 174.83,76.02 168.2,69.39 165.14,69.39 v1(164.43,70.09)
  BOTTOM w0.165: v1(164.43,70.09) 163.97,70.56 162.82,70.56 162.55,70.83 162.16,70.83 UV2.R26 ; v1(187.81,81.24) UV4.A4
FBA_D57: length 32
  ART03 w0.14: v1(163.26,71.39) 164.12,70.53 165.22,70.53 165.88,69.87 168,69.87 174.63,76.5 184.37,76.5 187.01,79.14 v1(187.01,79.64)
  BOTTOM w0.165: v1(163.26,71.39) 162.88,71.77 161.22,71.77 UV2.T25 ; UV4.B2 v1(187.01,79.64)
FBA_D58: length 31.7
  ART03 w0.14: v1(187.81,79.64) 187.81,78.54 184.81,75.54 175.03,75.54 168.4,68.91 164.88,68.91 v1(163.71,70.07)
  BOTTOM w0.165: v1(163.71,70.07) 163.32,69.67 UV2.N27 ; v1(187.81,79.64) UV4.A2
FBA_D59: length 31.3
  ART03 w0.102: 186.61,79.45 186.61,80.84 v1(187.01,81.24)
  ART03 w0.14: v1(164.06,71.39) 164.5,70.95 165.4,70.95 165.99,70.35 167.8,70.35 174.43,76.98 184.22,76.98 186.61,79.37 186.61,79.45
  BOTTOM w0.165: UV2.R27 162.83,70.96 163.62,70.96 v1(164.06,71.39) ; UV4.B4 v1(187.01,81.24)
FBA_D60: length 31.6
  ART03 w0.102: 182.8,81.64 183.41,81.64 v1(183.81,81.24)
  ART03 w0.14: v1(162.03,73.4) 162.49,73.86 163.19,73.86 163.85,73.21 166.51,73.21 172.11,78.81 172.11,82.06 173.86,83.82 181.87,83.82 182.49,83.19 182.49,81.82 182.67,81.64 182.8,81.64
  BOTTOM w0.165: v1(162.03,73.4) 161.64,73.79 UV2.V26 ; UV4.E4 184.21,81.64 v1(183.81,81.24)
FBA_D61: length 31.6
  ART03 w0.102: 182.78,80.04 183.42,80.04 v1(183.81,79.64)
  ART03 w0.14: v1(162.83,73.4) 163.51,72.72 166.71,72.72 172.59,78.61 172.59,81.86 174.06,83.33 181.59,83.33 181.98,82.94 181.98,80.7 182.64,80.04 182.78,80.04
  BOTTOM w0.165: UV4.E2 v1(183.81,79.64) ; UV2.V27 162.44,73.79 v1(162.83,73.4)
FBA_D62: length 30
  ART03 w0.14: v1(183.81,82.04) 183.41,82.45 183.41,83.19 182.35,84.25 173.61,84.25 171.63,82.26 171.63,79.01 166.31,73.69 164,73.69 v1(163.05,74.63)
  BOTTOM w0.165: v1(183.81,82.04) 183.41,81.64 UV4.F4 ; v1(163.05,74.63) 162.44,74.63 UV2.W27
FBA_D63: length 34.3
  ART03 w0.102: v1(183.81,80.44) 184.22,80.85 184.22,82.12
  ART03 w0.14: v1(163.85,74.63) 164.32,74.17 166.11,74.17 171.14,79.21 171.14,82.46 173.39,84.71 182.55,84.71 184.22,83.04 184.22,82.12
  BOTTOM w0.165: UV2.W25 161.22,74.25 162.54,74.25 162.64,74.15 163.36,74.15 v1(163.85,74.63) ; v1(183.81,80.44) 183.41,80.04 UV4.F2
FBA_DBI0: length 25.9
  ART06 w0.102: v1(176.61,69.87) 176.21,69.47 174.83,69.47
  ART06 w0.14: 174.83,69.47 173.55,69.47 167.73,63.65 165.25,63.65 162.13,60.53 160.27,60.53 159.64,61.16 156.93,61.16 v1(156.28,61.81)
  BOTTOM w0.165: v1(176.61,69.87) UV3.D2 ; UV2.D19 156.26,61.81 v1(156.28,61.81)
FBA_DBI1: length 34.6
  ART06 w0.102: v1(176.61,61.07) 176.21,60.67 174.79,60.67
  ART06 w0.14: v1(152.16,61.85) 151.72,61.41 151.72,60.62 151.79,60.54 151.79,57.57 152.27,57.1 152.78,57.1 154.96,54.91 166.2,54.91 172.6,61.31 174.07,61.31 174.71,60.67 174.79,60.67
  BOTTOM w0.165: v1(176.61,61.07) UV3.D13 ; v1(152.16,61.85) 151.8,62.21 UV2.D14
FBA_DBI2: length 40.2
  ART03 w0.102: v1(184.61,61.08) 184.2,61.48 183.52,61.48
  ART03 w0.14: 183.52,61.48 181.93,61.48 180.21,59.76 176.02,59.76 175.13,58.87 171.02,58.87 166.55,54.4 157.82,54.4 155.21,57.02 v1(154.06,57.02)
  BOTTOM w0.102: UV3.P13 v1(184.61,61.08)
  BOTTOM w0.107: UV2.C17 153.79,60.99 153.79,60.4 154,60.2 154,59.54 153.77,59.32 153.77,59.07
  BOTTOM w0.165: 153.77,59.07 153.77,57.31 v1(154.06,57.02)
FBA_DBI3: length 39.2
  ART03 w0.102: v1(185.41,69.87) 185,70.29 185,70.94
  ART03 w0.14: v1(160.12,57.99) 161.08,58.95 162.76,58.95 168.62,64.81 168.62,66.41 174.65,72.43 183.71,72.43 185,71.14 185,70.94
  BOTTOM w0.165: UV3.P2 185.02,69.48 v1(185.41,69.87) ; v1(160.12,57.99) 159.42,57.99 158.21,59.2 158.21,59.42 157.94,59.7 157.94,61.02 UV2.C22
FBA_DBI4: length 22.7
  ART06 w0.14: v1(176.61,79.64) 176.2,79.23 176.2,78.61 175.47,77.88 174.69,77.88 166.45,69.64 162.59,69.64 162.42,69.81 162.42,70.3 162.19,70.53 160.84,70.53 v1(160.44,70.93)
  BOTTOM w0.165: UV2.P24 160.04,70.53 v1(160.44,70.93) ; UV4.P2 177.01,80.04 v1(176.61,79.64)
FBA_DBI5: length 27.4
  ART06 w0.102: 174.72,87.23 176.05,87.23 176.22,87.4 176.22,88.05 v1(176.61,88.44)
  ART06 w0.14: v1(159.63,74.23) 159.84,74.23 160.28,74.67 160.6,74.67 161.04,74.22 165.21,74.22 167.31,76.32 167.31,80.64 173.99,87.32 174.63,87.32 174.72,87.23
  BOTTOM w0.102: UV4.P13 v1(176.61,88.44)
  BOTTOM w0.165: UV2.W24 v1(159.63,74.23)
FBA_DBI6: length 33.9
  ART03 w0.14: v1(161.22,76.7) 161.64,77.12 163.15,77.12 163.56,77.53 164.78,77.53 166.97,79.72 166.97,83.68 172.94,89.64 184.87,89.64 185.01,89.5 UV4.D13 v1(184.61,88.44)
  BOTTOM w0.165: UV2.AA25 161.22,76.7 v1(161.22,76.7) ; UV4.D13 v1(184.61,88.44)
FBA_DBI7: length 30.3
  ART03 w0.102: v1(185.41,80.44) 185,80.03 185,79.48 184.99,79.48 184.99,79.47 184.79,79.27 184.78,79.27 184.77,79.26 184.48,79.26
  ART03 w0.14: v1(166.28,71.39) 166.35,71.32 167.4,71.32 174.03,77.95 183.03,77.95 184.34,79.26 184.48,79.26
  BOTTOM w0.165: UV2.U25 161.27,72.56 161.75,72.56 162.13,72.94 164.73,72.94 v1(166.28,71.39) ; v1(185.41,80.44) 185.01,80.04 UV4.D2
FBA_EDC0: length 25.4
  ART06 w0.102: v1(156.3,62.59) 156.68,62.21 157.31,62.21 ; 175.41,70.81 175.41,70.28 v1(175.81,69.87)
  ART06 w0.14: 157.31,62.21 157.33,62.23 161.42,62.23 163.75,64.56 167.35,64.56 173.91,71.12 175.2,71.12 175.41,70.92 175.41,70.81
  BOTTOM w0.165: UV2.E19 155.88,63.01 v1(156.3,62.59) ; UV3.C2 v1(175.81,69.87)
FBA_EDC1: length 33.2
  ART06 w0.102: v1(175.82,61.07) 176.23,61.48 176.23,62.01 175.95,62.29 173.97,62.29
  ART06 w0.14: v1(152.16,61.01) 152.16,59.29 152.93,58.52 152.93,57.54 155.09,55.37 166.01,55.37 172.93,62.29 173.97,62.29
  BOTTOM w0.165: UV3.C13 v1(175.82,61.07) ; UV2.C15 152.56,61.41 v1(152.16,61.01)
FBA_EDC2: length 41.1
  ART03 w0.102: v1(185.42,61.07) 185.02,60.67 182.83,60.67 182.63,60.47 182.63,60.44 182.63,60.11
  ART03 w0.14: 182.63,60.11 182.63,60.02 181.54,58.94 175.98,58.94 175.41,58.37 171.19,58.37 166.79,53.96 157.72,53.96 155.12,56.56 v1(154.52,56.56)
  BOTTOM w0.107: 153.4,59.16 153.4,59.35 153.76,59.71 153.76,60.05 153.38,60.44 UV2.B16
  BOTTOM w0.165: 153.4,59.16 153.4,56.82 153.66,56.56 v1(154.52,56.56) ; UV3.R13 v1(185.42,61.07)
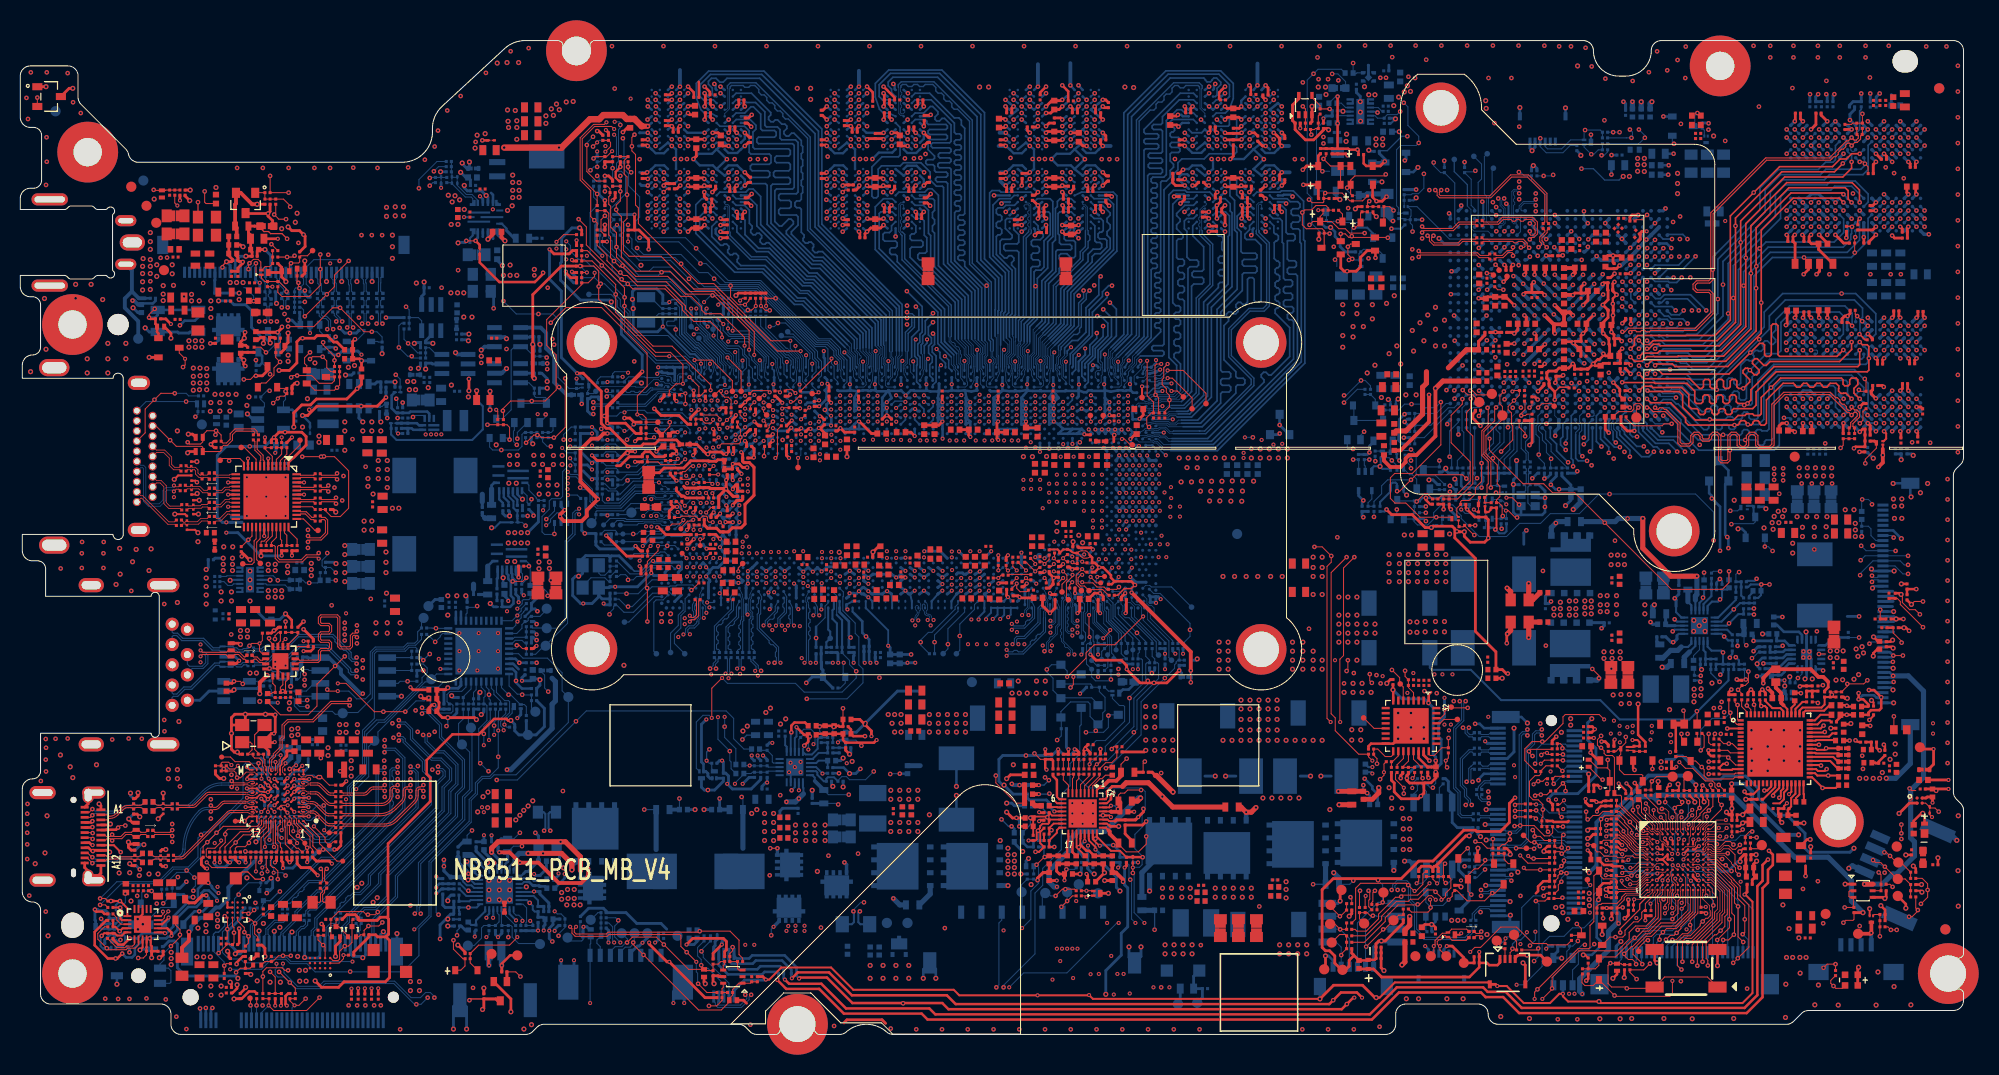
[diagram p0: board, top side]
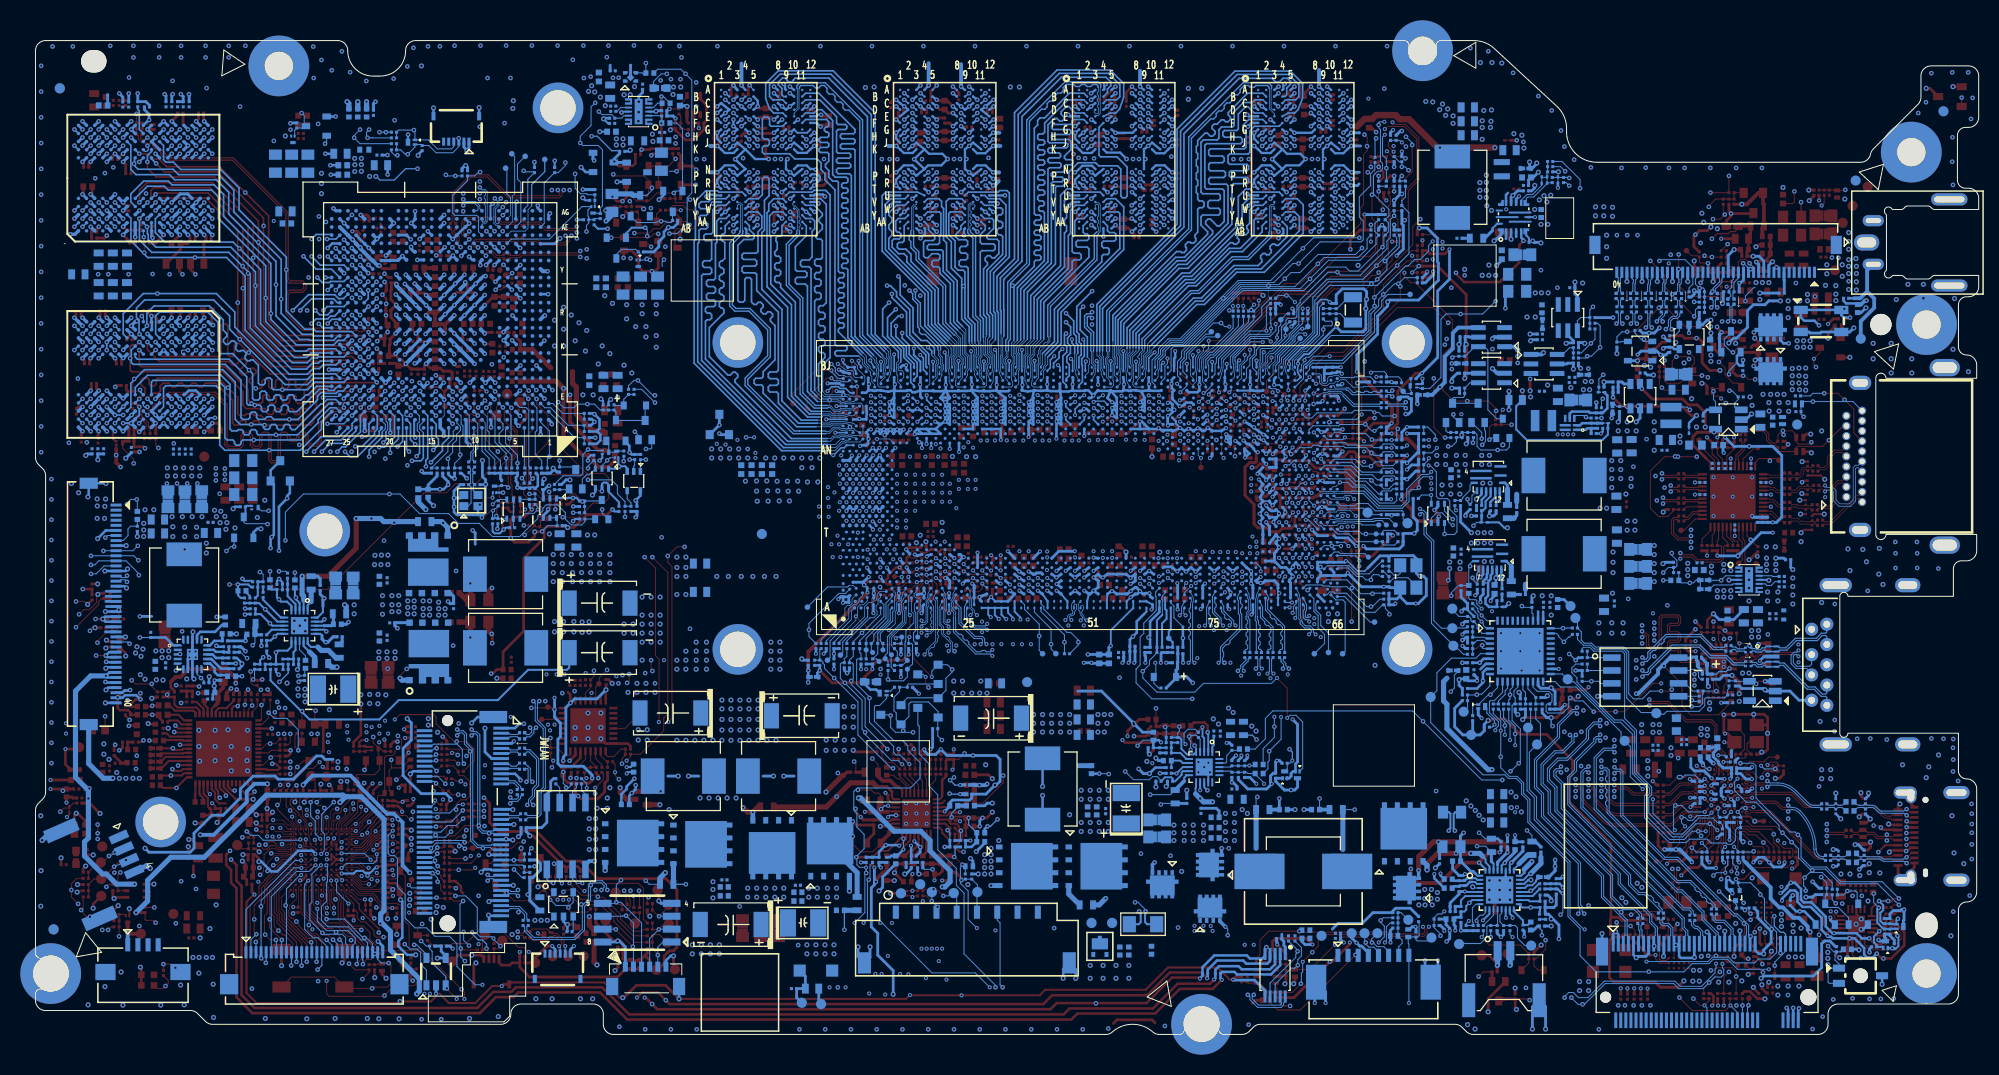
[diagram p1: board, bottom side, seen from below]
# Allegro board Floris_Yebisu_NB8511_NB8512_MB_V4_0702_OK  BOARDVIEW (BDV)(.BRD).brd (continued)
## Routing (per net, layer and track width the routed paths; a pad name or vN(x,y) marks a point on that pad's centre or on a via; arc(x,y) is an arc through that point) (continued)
FBA_EDC3: length 39.1
  ART03 w0.102: 185.82,70 185.82,69.47 v1(186.21,69.07)
  ART03 w0.14: v1(159.45,58.94) 160.3,59.79 163.09,59.79 168.12,64.81 168.12,66.58 174.45,72.92 183.99,72.92 185.82,71.09 185.82,70
  BOTTOM w0.165: UV2.B22 158.77,60.18 158.77,59.17 159,58.94 v1(159.45,58.94) ; v1(186.21,69.07) UV3.R2
FBA_EDC4: length 20.1
  ART06 w0.102: 174.62,78.45 174.62,79.06 174.8,79.25 175.42,79.25 v1(175.81,79.64)
  ART06 w0.14: 174.62,78.45 166.59,70.43 164.97,70.43 164.87,70.53 162.71,70.53 162.31,70.93 v1(161.24,70.93)
  BOTTOM w0.165: UV2.R25 161.24,70.95 v1(161.24,70.93) ; v1(175.81,79.64) 176.21,80.04 UV4.R2
FBA_EDC5: length 25.4
  ART06 w0.102: v1(175.81,88.44) 175.41,88.03 174.67,88.03
  ART06 w0.14: 174.67,88.03 174.6,87.96 173.33,87.96 166.39,81.02 166.39,76.68 165.42,75.71 162.24,75.71 162.04,75.51 160.91,75.51 160.82,75.43 160.03,75.43 v1(159.63,75.03)
  BOTTOM w0.165: v1(159.63,75.03) UV2.W23 ; UV4.R13 v1(175.81,88.44)
FBA_EDC6: length 34.8
  ART03 w0.14: v1(162.04,77.52) 162.5,77.98 164.6,77.98 166.49,79.87 166.49,83.89 173.19,90.6 181.89,90.6 182.04,90.45 185.6,90.45 185.81,90.23 UV4.C13 v1(186.21,88.44)
  BOTTOM w0.165: UV4.C13 v1(186.21,88.44) ; v1(162.04,77.52) UV2.AB26
FBA_EDC7: length 30.4
  ART03 w0.102: 185.8,79.32 185.8,80.03 v1(186.21,80.44)
  ART03 w0.14: 185.8,79.32 183.94,77.47 174.23,77.47 167.6,70.84 166.09,70.84 v1(165.54,71.39)
  BOTTOM w0.165: v1(165.54,71.39) 165.54,71.42 164.42,72.54 162.25,72.54 161.87,72.15 UV2.T26 ; v1(186.21,80.44) UV4.C2
FBA_RAS_H: length 27.7
  BOTTOM w0.165: UV2.K27 164.47,67.19 164.92,66.75 166.11,66.75 169.45,70.09 169.45,75.42 v3(171.54,77.5) 172.17,78.14 178.9,78.14 179.83,79.07 179.83,80.42 UV4.L3
FBA_RAS_L: length 29.7
  BOTTOM w0.165: UV3.G3 179.8,69.06 179.8,70.85 179.42,71.23 174.66,71.23 173.64,70.21 173.64,67.42 173.35,67.13 172.21,67.13 v3(170.58,65.5) 170.24,65.16 170.24,62.72 170.08,62.56 169.69,62.56 169.52,62.72 169.52,63.26 169.36,63.42 169.03,63.42 168.86,63.26 168.86,62.72 168.7,62.56 168.29,62.56 168.12,62.72 168.12,62.9 167.96,63.07 167.63,63.07 167.46,62.9 167.46,62.72 167.3,62.56 166.97,62.56 166.8,62.72 166.8,62.9 166.64,63.07 166.31,63.07 166.14,62.9 166.14,62.72 165.98,62.56 165.48,62.56 164.97,63.07 164.77,63.07 163.92,63.91 UV2.F27
FBA_RST_H: length 30.7
  TOP w0.165: RV92.2 180.6,79.69 v1(180.65,79.64)
  BOTTOM w0.165: UV4.J2 180.65,79.68 v1(180.65,79.64) 180.61,79.6 180.61,78.96 180.53,78.88 180.53,78.38 179.77,77.63 172.38,77.63 169.96,75.21 v3(169.96,73.84) 169.96,69.88 166.32,66.24 164.84,66.24 164.39,66.7 163.88,66.7 163.77,66.81 161.22,66.81 UV2.K25
FBA_RST_L: length 31.5
  TOP w0.165: v1(180.66,69.88) 180.34,70.2 RV93.2
  BOTTOM w0.165: UV2.G25 161.23,64.32 164.07,64.32 164.82,63.57 v3(167.31,63.57) 168.18,63.57 168.34,63.74 168.34,64.55 168.51,64.72 168.84,64.72 169,64.55 169,64.22 169.17,64.06 169.51,64.06 169.67,64.22 169.67,65.99 170.2,66.51 170.43,66.51 170.51,66.43 170.75,66.43 170.98,66.66 170.98,66.9 170.9,66.98 170.9,67.21 171.13,67.45 171.36,67.45 171.45,67.36 171.68,67.36 171.91,67.6 171.91,67.83 171.83,67.91 171.83,68.15 172.07,68.39 172.31,68.39 172.64,68.05 172.88,68.05 173.11,68.29 173.11,68.52 172.77,68.86 172.77,69.09 173.14,69.45 173.14,70.47 174.5,71.83 179.96,71.83 180.66,71.12 v1(180.66,69.88) 180.66,69.83 UV3.J2
FBA_WCK01: length 34
  ART06 w0.114: v1(154.64,61.81) 154.46,61.63 154.25,61.63 153.93,61.31 153.93,60.91 155.06,59.78 157.74,59.78 159.24,58.28 159.75,58.28 159.93,58.46 160.51,58.46 160.82,58.15 163.92,58.15 166.33,60.56 167.62,60.56 172.32,65.26 173.59,65.26 173.94,65.61 173.94,66.03 174.19,66.28 174.53,66.28 174.78,66.03 174.78,65.61 175.12,65.27 175.89,65.27 177.3,66.69 177.3,67.75 177.01,68.04 176.85,68.04 v1(176.62,68.27)
  BOTTOM w0.102: v1(154.64,61.81) 154.65,61.81 UV2.D18
  BOTTOM w0.112: UV3.D4 v1(176.62,68.27)
FBA_WCK01_N: length 34
  ART06 w0.114: v1(176.62,67.47) 176.62,67.69 176.74,67.82 176.92,67.82 177.09,67.66 177.09,66.77 175.8,65.49 175.21,65.49 175,65.7 175,66.12 174.62,66.49 174.1,66.49 173.73,66.12 173.73,65.7 173.5,65.48 172.23,65.48 167.53,60.78 166.24,60.78 163.83,58.37 160.91,58.37 160.6,58.67 159.84,58.67 159.66,58.49 159.33,58.49 157.83,59.99 155.15,59.99 154.15,61 154.15,61.23 154.33,61.41 154.51,61.41 154.64,61.29 v1(154.64,61.06)
  BOTTOM w0.102: v1(154.64,61.06) 154.75,60.95 155.1,60.95 155.21,61.06 155.21,61.26 UV2.C18
  BOTTOM w0.112: v1(176.62,67.47) 176.69,67.47 176.7,67.47 177.17,67.47 177.25,67.39 177.25,67.16 177.16,67.08 UV3.D5
FBA_WCK23: length 41.6
  ART06 w0.114: v1(185.42,67.47) 185.51,67.38 185.51,67.2 185.38,67.07 184.88,67.07 184.74,66.94 184.49,66.94 184.25,66.69 184.25,66.44 182.39,64.59 172.74,64.59 165.17,57.02 159.69,57.02 157.58,59.13 157.02,59.13 156.77,58.87 155.99,58.87 155.86,59 155.48,59 155.36,58.87 155.09,58.87 154.79,59.18 154.79,59.41 154.54,59.65 154.32,59.65 154.07,59.9 154.07,60.12 153.82,60.37 153.6,60.37 153.41,60.55 153.41,60.85 153.54,60.98 153.54,61.36 153.41,61.48 153.41,61.69 153.58,61.86 v1(153.83,61.86)
  BOTTOM w0.112: UV3.P4 v1(185.42,67.47)
  BOTTOM w0.114: UV2.D17 v1(153.83,61.86)
FBA_WCK23_N: length 41.7
  ART06 w0.114: v1(185.42,66.67) 185.16,66.67 185.05,66.78 184.89,66.78 182.48,64.37 172.83,64.37 165.26,56.8 159.6,56.8 157.49,58.91 157.11,58.91 156.86,58.66 155,58.66 153.2,60.47 153.2,61.78 153.83,62.41 v1(153.83,62.61)
  BOTTOM w0.102: v1(153.83,62.61) 153.8,62.61 UV2.D16
  BOTTOM w0.112: v1(185.42,66.67) UV3.P5
FBA_WCK45: length 25.8
  ART03 w0.114: v1(177.38,82.04) 177.2,82.04 177.03,82.2 177.03,82.58 176.79,82.82 174.39,82.82 173.48,81.91 173.48,78.61 166.94,72.07 160.39,72.07 160.25,72.21 160.25,72.44 v1(160.44,72.63)
  BOTTOM w0.102: v1(160.44,72.63) 160.44,72.55 UV2.T24
  BOTTOM w0.114: v1(177.38,82.04) 177.01,81.67 UV4.P4
FBA_WCK45_N: length 25.8
  ART03 w0.114: v1(176.61,82.04) 176.82,82.24 176.82,82.49 176.7,82.61 174.48,82.61 173.7,81.82 173.7,78.52 167.03,71.85 160.3,71.85 160.03,72.12 160.03,72.49 159.89,72.63 v1(159.64,72.63)
  BOTTOM w0.102: v1(159.64,72.63) 160,72.99 UV2.U24
  BOTTOM w0.114: UV4.P5 v1(176.61,82.04)
FBA_WCK67: length 34.5
  ART03 w0.114: v1(185.41,82.04) 185.41,82.05 185.23,82.24 185.23,83.02 182.84,85.4 173.03,85.4 170.31,82.68 170.31,79.7 165.97,75.37 162.67,75.37 161.38,74.08 160.6,74.08 v1(160.44,74.24)
  BOTTOM w0.102: UV2.V24 160.26,74.05 v1(160.44,74.24)
  BOTTOM w0.114: v1(185.41,82.04) 185.01,81.64 UV4.D4
FBA_WCK67_N: length 34.5
  ART03 w0.114: v1(160.44,73.44) 160.44,73.73 160.57,73.86 161.47,73.86 162.76,75.15 166.06,75.15 170.52,79.61 170.52,82.59 173.12,85.19 182.75,85.19 185.01,82.93 185.01,82.44 v1(184.61,82.04)
  BOTTOM w0.102: UV2.V25 160.66,73.66 160.66,73.66 v1(160.44,73.44)
  BOTTOM w0.114: UV4.D5 185.01,82.44 v1(184.61,82.04)
FBA_WE_H: length 35.1
  BOTTOM w0.165: UV2.M26 161.82,68.87 162.24,68.45 164.59,68.45 164.67,68.53 165.6,68.53 167.93,70.85 v3(167.93,73.94) 167.93,76.22 172.59,80.89 172.59,83.04 173.82,84.27 177.93,84.27 178.43,84.78 181.74,84.78 182.24,85.29 182.24,87.67 UV4.G12
FBA_WE_L: length 31.4
  BOTTOM w0.165: UV2.D26 162.03,62.61 162.88,62.61 163.32,62.17 163.5,62.17 166.04,59.64 166.36,59.64 166.52,59.8 166.52,59.98 166.69,60.14 167.02,60.14 167.18,59.98 167.18,59.8 167.35,59.64 167.68,59.64 167.84,59.8 167.84,59.98 168.01,60.14 168.34,60.14 168.5,59.98 168.5,59.83 168.67,59.66 169,59.66 169.16,59.83 169.16,59.98 169.33,60.14 v3(170.38,60.14) 171.45,60.14 171.96,60.65 171.96,64.34 173.17,65.55 180.9,65.55 182.24,64.21 182.24,61.85 182.61,61.48 UV3.L12
FBVDDQ_PWR_EN: length 57.2
  ART03 w0.089: v1(172.06,48.11) 172.06,45.06 172.38,44.74 172.38,36.42 v1(171.28,35.33)
  ART05 w0.102: v1(139.96,56.59) 139.96,53.66 141.48,52.14 144.02,52.14 145.03,51.13 147.19,51.13 147.78,50.54 157.94,50.54 162.43,46.05 170,46.05 v1(172.06,48.11)
  BOTTOM w0.102: v1(139.96,56.59) RV44.2 138.63,55.96 DV9.3 ; QV22.1 172.06,48.11 v1(172.06,48.11) 172.39,48.11 v3(172.82,47.67)
  BOTTOM w0.254: PR1101.1 v1(171.28,35.33)
FBVDDQ_PWR_EN_N: length 4.7
  BOTTOM w0.102: v3(168.76,50.31) 168.81,50.37 170.94,50.37 171.11,50.54 QV22.3
  BOTTOM w0.203: QV22.3 170.95,51.19 RV77.1 170.86,52.12 QV10.1
FLASH_SPI_CLK: length 151.3
  TOP w0.102: RO8.1 132.08,14.12 v1(132.13,14.17) ; RF3.2 135.63,25.68 135.63,25.14 v2(136.45,24.33) v3(136.45,23.75) ; v2(72.4,62.34) 72.01,61.95 RU44.2
  ART05 w0.102: v1(130.55,34.62) 130,34.62 129.33,35.28 128.5,35.28 127.94,35.84 127.94,38.81 125.4,41.35 118.34,41.35 115.54,38.55 107.95,38.55 106.45,37.06 102.66,37.06 102.51,36.9 96.67,36.9 95.53,38.05 86.84,38.05 86.15,38.73 83.41,38.73 82.65,37.97 70.76,37.97 68.51,40.22 68.51,41.25 68.41,41.35 68.2,41.35 68.1,41.25 68.1,40.82 68,40.71 67.26,40.71 67,40.97 67,41.22 66.87,41.36 66.87,41.5 67.45,42.08 67.45,42.23 67.3,42.37 67.16,42.37 66.58,41.79 66.44,41.79 66.29,41.93 66.29,42.08 66.62,42.4 66.62,42.55 66.47,42.69 66.33,42.69 66,42.36 65.86,42.36 64.11,44.12 64.11,48.99 63.8,49.3 63.8,50.59 63.57,50.82 63.57,52.3 63.12,52.75 63.12,53.72 62.15,54.68 62.15,54.95 62.25,55.05 62.94,55.05 63.04,55.16 63.04,55.36 62.94,55.46 62.25,55.46 62.15,55.56 62.15,55.76 62.25,55.87 62.94,55.87 63.04,55.97 63.04,56.17 62.94,56.27 62.25,56.27 62.15,56.37 62.15,56.58 62.25,56.68 62.94,56.68 63.04,56.78 63.04,56.98 62.94,57.09 62.25,57.09 62.15,57.19 62.15,57.87 62.25,57.97 62.96,57.97 63.07,58.07 63.07,58.28 62.96,58.38 62.25,58.38 62.15,58.48 62.15,59.66 63.78,61.29 63.78,62.23 65.33,63.78 65.76,63.78 66.09,64.11 68.15,64.11 68.58,64.54 70.28,64.54 71.37,63.45 71.63,63.45 71.88,63.19 71.88,62.86 v2(72.4,62.34)
  ART06 w0.102: v1(130.55,34.62) 131.01,34.16 131.01,33.4 133.73,30.68 133.73,28.01 135.55,26.2 135.55,25.23 v2(136.45,24.33) 138.48,22.3 138.48,16.96 137.44,15.92 137.31,15.92 136.5,15.11 133.07,15.11 v1(132.13,14.17)
  BOTTOM w0.102: UU1.DB42 72.4,62.34 v2(72.4,62.34)
FLASH_SPI_CLK_EC: length 2
  BOTTOM w0.102: RE37.2 138.3,24.33 138.68,23.95 UE2.6
FLASH_SPI_CLK_IC: length 10.4
  TOP w0.102: CLKO1.1 132.08,11.4 RO8.2 RO9.2 132.84,12.01 133.14,11.71 v1(133.4,11.71)
  BOTTOM w0.102: J3001.2 132.68,10.98 v1(133.4,11.71) 133.7,11.71 133.75,11.66 UO1.6
FLASH_SPI_CLK_TPM: length 1.8
  TOP w0.102: UF15.19 136.41,27.21 135.79,26.59 RF3.1
FLASH_SPI_CS0_N: length 150.6
  TOP w0.102: RO5.1 132.56,9.09 134.62,11.15 134.62,11.5 135.89,12.77 137.77,12.77 v3(137.82,12.82) 138.02,12.82 138.89,13.69 139.19,13.69 v2(139.6,13.28)
  ART05 w0.102: v2(72.4,63.07) 72.35,63.12 72.35,63.23 71.88,63.7 71.5,63.7 70.41,64.79 68.07,64.79 67.71,64.44 65.78,64.44 65.68,64.54 65.12,64.54 63.53,62.95 63.53,61.4 61.92,59.79 61.92,54.61 62.89,53.64 62.89,52.7 63.37,52.22 63.37,50.75 63.6,50.52 63.6,49.2 63.9,48.89 63.9,44.02 66.39,41.53 66.39,41.07 69.98,37.49 78.66,37.49 80.24,35.91 94.69,35.91 96.52,34.08 101.57,34.08 102,34.52 108.58,34.52 109.57,35.51 110.36,35.51 111.25,36.4 116.38,36.4 116.83,36.84 116.83,37.98 119.12,40.28 124.71,40.28 125.91,39.09 125.91,35.96 127.91,33.96 129.13,33.96 130.05,33.04 136.17,33.04 v2(136.8,33.68)
  ART06 w0.102: v2(136.8,33.68) 136.8,33.45 139.22,31.04 139.22,29.38 141.3,27.3 141.3,14.98 v2(139.6,13.28)
  BOTTOM w0.102: UU1.DB43 72.36,62.96 v2(72.4,63.07)
FLASH_SPI_CS0_N_EC: length 4.3
  TOP w0.102: v3(140.51,16.84) 140.36,16.69 RE32.2 ; RE32.2 140.36,15.16 v1(140.59,14.93) ; RE32.2 RE30.1
  BOTTOM w0.102: v1(140.59,14.93) 140.84,14.93 141.22,15.31 UE2.1
FLASH_SPI_CS0_N_IC: length 7.5
  TOP w0.102: CSO1.1 130.12,9.85 130.68,9.85 RO10.2 RO5.2 RO2.1 130.28,7.92 v1(130.28,7.82)
  BOTTOM w0.102: J3001.5 v1(130.28,7.82) 130.28,8.61 129.77,9.12 UO1.1
FLASH_SPI_CS2_N: length 115.5
  TOP w0.102: v1(130.94,36.9) 130.94,35.96 v3(130.81,35.84) ; RF2.2 137.51,25.47 v2(137.31,25.27)
  ART05 w0.102: v1(130.94,36.9) 130.48,37.36 130.48,39.82 130.27,40.03 129.18,40.03 126.19,43.03 117.32,43.03 115.26,40.97 111.53,40.97 110.59,41.91 101.39,41.91 101.19,41.7 96.85,41.7 96.26,41.12 96.26,40.71 96.01,40.46 91.59,40.46 91.08,39.95 87.98,39.95 87.48,40.46 79.86,40.46 79.6,40.21 77.52,40.21 76.71,41.02 71.52,41.02 69.57,42.97 69.57,43.96 69.39,44.14 66.17,44.14 65.35,44.96 65.35,50.14 65.76,50.54 65.76,50.87 65.23,51.41 65.23,51.81 65.12,51.92 65.12,52.32 64.16,53.29 64.16,59.26 65.96,61.06 66.37,61.06 66.55,61.24 70.05,61.24 70.52,61.71 v2(71.49,61.71)
  ART06 w0.102: v2(137.31,25.27) 134.21,28.37 134.21,31.47 133.81,31.87 133.81,33.91 132.64,35.07 131.32,35.07 130.94,35.46 v1(130.94,36.9)
  BOTTOM w0.102: UU1.DB41 v2(71.49,61.71)
FLASH_SPI_CS2_N_TPM: length 3
  TOP w0.102: UF15.20 136.91,26.95 136.35,26.39 CF12.2 RE457.2 RF2.1
FLASH_SPI_HOLD_N_EC: length 2
  BOTTOM w0.102: RE28.1 139.95,24.33 UE2.7
FLASH_SPI_IO2: length 179.5
  TOP w0.102: v3(56.49,87.55) v2(56.89,87.96) ; v1(131.19,13.54) 131.32,13.41 RO6.1
  ART05 w0.102: v2(129.67,36.9) 129.26,37.31 129.26,38.86 125.8,42.31 117.75,42.31 115.39,39.95 110.84,39.95 109.88,40.92 107.29,40.92 106.83,40.46 106.83,39.95 106.73,39.85 106.42,39.85 106.32,39.95 106.32,40.31 106.22,40.41 106.02,40.41 105.92,40.31 105.92,39.8 105.81,39.7 105.56,39.7 105.46,39.8 105.46,40.31 105.36,40.41 104.95,40.41 104.85,40.31 104.85,39.19 104.49,38.83 103.53,38.83 103.33,39.04 103.33,40.56 103.19,40.69 103.05,40.69 102.92,40.56 102.92,39.47 102.84,39.39 102.61,39.39 102.51,39.49 102.51,40.51 102.41,40.61 102.16,40.61 102.06,40.51 102.06,39.34 101.95,39.24 101.39,39.24 101.14,39.49 101.14,40.51 101.04,40.61 99.46,40.61 99.26,40.41 99.26,39.55 99.01,39.29 97.29,39.29 97.19,39.39 97.19,39.6 97.09,39.7 96.89,39.7 96.79,39.6 96.79,39.39 96.68,39.29 96.48,39.29 96.38,39.39 96.38,39.6 96.28,39.7 96.07,39.7 95.97,39.6 95.97,39.39 95.87,39.29 95.67,39.29 95.57,39.39 95.57,39.6 95.47,39.7 95.27,39.7 95.16,39.6 95.16,39.39 95.06,39.29 94.86,39.29 94.76,39.39 94.76,39.6 94.66,39.7 94.45,39.7 94.35,39.6 94.35,39.39 94.25,39.29 94.05,39.29 93.95,39.39 93.95,39.6 93.84,39.7 93.64,39.7 93.54,39.6 93.54,39.39 93.44,39.29 92.25,39.29 92.17,39.22 87.53,39.22 86.97,39.77 82.29,39.77 81.66,39.14 72.79,39.14 68.3,43.63 65.96,43.63 64.95,44.65 64.95,49.48 64.62,49.81 64.62,51.03 64.31,51.33 64.31,52.83 63.96,53.19 63.96,59.41 65.78,61.24 65.78,61.8 66.04,62.05 69.09,62.05 69.48,61.66 69.89,61.66 v2(70.57,62.34)
  ART06 w0.102: v1(131.19,13.54) 131.19,14.02 132.54,15.36 136.19,15.36 138,17.17 138,22.07 134.97,25.09 134.97,26.01 133.22,27.76 133.22,29.69 129.67,33.25 v2(129.67,36.9) ; v2(70.57,62.34) 70.57,62.34 70.2,62.71 70.2,64.44 69.72,64.92 67.94,64.92 67.16,65.71 65.81,65.71 64.26,67.26 62.71,67.26 58.8,71.17 58.8,74.09 56.59,76.3 56.59,77.26 56.06,77.8 56.06,83.87 55.78,84.15 55.78,87.02 56.72,87.96 v2(56.89,87.96)
  BOTTOM w0.102: RU61.2 RU53.1 57.1,88.16 v2(56.89,87.96) ; v2(70.57,62.34) UU1.DF42
FLASH_SPI_IO2_IC: length 4.3
  TOP w0.102: IOO1.1 129.23,12.57 v1(130.15,11.66) 130.2,11.66 RO3.1 RO6.2
  BOTTOM w0.102: UO1.3 v1(130.15,11.66)
FLASH_SPI_IO3: length 178.4
  TOP w0.102: v2(139.04,13.29) 139.09,13.24 v3(139.09,12.52) 139.09,12.32 138.83,12.06 137.21,12.06 RO7.1 ; RU52.1 RU60.2 58.21,87.96 58.21,87.55 v2(57.71,87.04)
  ART05 w0.102: v2(134.36,35.33) 134.36,36.14 132.28,38.22 132.28,41.58 131.95,41.91 129.51,41.91 129.39,41.78 129.39,41.37 129.28,41.27 129.03,41.27 128.93,41.37 128.93,41.81 128.83,41.91 128.29,41.91 126.44,43.76 116.84,43.76 114.86,41.78 111.71,41.78 111.17,42.31 101.12,42.31 100.91,42.11 96.49,42.11 96.06,41.68 87.42,41.68 86.92,41.17 79.45,41.17 79.14,40.87 77.93,40.87 77.26,41.53 73.2,41.53 72.74,41.98 71.42,41.98 70,43.41 70,45.54 69.39,46.15 69.39,47.27 69.14,47.52 68.73,47.52 67.61,48.64 67.61,50.01 67.41,50.21 66.14,50.21 66.02,50.34 66.02,52.29 65.76,52.55 65.58,52.55 65.48,52.65 65.48,53.01 65.25,53.24 64.64,53.24 64.51,53.36 64.51,53.57 64.62,53.67 65.28,53.67 65.38,53.77 65.38,53.97 65.28,54.07 64.46,54.07 64.36,54.18 64.36,55.6 64.62,55.85 65.38,55.85 65.48,55.95 65.48,56.16 65.38,56.26 64.51,56.26 64.36,56.41 64.36,57.63 64.46,57.73 66.8,57.73 66.9,57.83 66.9,58.04 66.8,58.14 64.72,58.14 64.56,58.29 64.56,58.44 64.67,58.54 66.3,58.54 66.4,58.65 66.4,58.79 66.24,58.95 65.3,58.95 65.2,59.05 65.2,59.79 65.99,60.58 66.34,60.58 66.8,61.03 69.95,61.03 70.33,60.65 70.74,60.65 71.22,61.13 v2(71.48,61.13)
  ART06 w0.102: v2(134.36,35.33) 134.77,35.33 135.99,34.11 135.99,33.65 138.86,30.78 138.86,29.23 140.94,27.15 140.94,15.92 140.16,15.14 140.16,14.65 139.04,13.54 v2(139.04,13.29) ; v2(71.48,61.13) 71.13,61.48 71.13,64.32 69.9,65.55 69.39,65.55 67.82,67.13 66.67,67.13 64.43,69.38 64.43,72.3 62.23,74.5 60.6,74.5 56.77,78.33 56.77,84.17 56.49,84.45 56.49,85.77 57.28,86.56 57.28,86.61 v2(57.71,87.04)
  BOTTOM w0.102: UU1.DD41 v2(71.48,61.13)
FLASH_SPI_IO3_IC: length 6.8
  TOP w0.102: RO7.2 RO4.1 136.35,11.76 135.94,11.76 IOO2.1 134.54,10.36 v1(134.41,10.36) 134.41,10.34 v3(132.74,8.66)
  BOTTOM w0.102: v1(134.41,10.36) 134.44,10.36 134.47,10.39 UO1.7
FLASH_SPI_MISO: length 148.6
  TOP w0.102: RF5.2 140.84,27.25 v2(140.59,27) 140.59,26.46 v3(140.71,26.34) ; v2(138.99,14.91) 137.82,13.74 136.35,13.74 v3(136.19,13.59) 136.13,13.53 135.63,13.53 133.96,11.86 133.96,11.4 132.74,10.18 131.82,10.18 131.65,10.36 RO11.1
  ART05 w0.102: v2(70.57,62.94) 70.57,62.87 70.41,62.71 70.25,62.71 70.1,62.56 70.1,62.3 69.85,62.05 69.49,62.05 69.29,62.25 69.29,62.51 68.88,62.91 66.29,62.91 65.43,62.05 65.43,61.44 63.75,59.76 63.75,53.08 64.08,52.75 64.08,51.23 64.41,50.9 64.41,49.73 64.74,49.4 64.74,44.52 65.89,43.38 68.2,43.38 72.67,38.91 81.89,38.91 82.5,39.52 86.87,39.52 87.4,38.99 92.43,38.99 92.5,39.06 99.3,39.06 99.66,39.42 99.66,40.23 99.76,40.33 99.96,40.33 100.06,40.23 100.06,39.42 100.16,39.32 100.37,39.32 100.47,39.42 100.47,40.23 100.57,40.33 100.77,40.33 100.88,40.23 100.88,39.3 101.19,38.99 102.41,38.99 102.87,38.53 105.71,38.53 106.7,39.52 107.79,39.52 107.89,39.62 107.89,40.41 107.99,40.51 108.2,40.51 108.29,40.42 108.29,39.62 108.4,39.52 108.6,39.52 108.7,39.62 108.7,40.23 108.83,40.36 108.98,40.36 109.11,40.23 109.11,39.62 109.21,39.52 109.41,39.52 109.51,39.62 109.51,40.21 109.62,40.31 109.82,40.31 109.92,40.21 109.92,39.62 110.02,39.52 115.36,39.52 117.93,42.09 125.7,42.09 129.03,38.76 129.03,37.03 130.02,36.04 132.03,36.04 133.09,34.97 133.81,34.97 v1(134.16,34.62)
  ART06 w0.102: v2(138.99,14.91) 140.59,16.51 v2(140.59,27) 139.83,27.76 136.62,27.76 134.87,29.51 134.87,33.91 v1(134.16,34.62)
  BOTTOM w0.102: v2(70.57,62.94) 70.5,62.94 UU1.DF43
FLASH_SPI_MISO_EC: length 3
  TOP w0.102: v2(139.74,14.89) 139.32,15.31 RE458.1 RE35.1
  BOTTOM w0.102: UE2.2 139.95,15.06 139.79,14.89 v2(139.74,14.89)
FLASH_SPI_MISO_IC: length 7.8
  TOP w0.102: MISOO1.1 129.64,10.89 v1(130.17,10.36) RO11.2 RO13.2
  BOTTOM w0.102: UO1.2 130.15,10.39 v1(130.17,10.36) 131.08,9.46 J3001.4
FLASH_SPI_MISO_TPM: length 3.6
  TOP w0.102: v3(140.87,29.23) 140.84,29.21 RF5.1 140.21,28.27 139.44,27.51 139.06,27.51 138.91,27.66 UF15.24
FLASH_SPI_MOSI: length 178.1
  TOP w0.102: v1(133.6,14.17) 133.4,13.97 133.4,13.13 133.3,13.03 RO12.1 ; RF4.2 138.17,25.47 138.3,25.35 v1(138.3,25.27)
  ART05 w0.102: v2(71.49,62.98) 71.16,62.98 70.81,63.32 70.25,63.32 69.9,62.96 69.11,62.96 68.96,63.12 66.14,63.12 65.1,62.08 65.1,61.67 63.55,60.12 63.55,52.96 63.88,52.63 63.88,51.15 64.21,50.82 64.21,49.6 64.51,49.3 64.51,44.37 65.71,43.18 68.07,43.18 69.51,41.73 69.51,41.59 69.03,41.11 69.03,40.97 69.18,40.82 69.32,40.82 69.8,41.3 69.94,41.3 70.13,41.11 70.13,40.97 69.38,40.21 69.38,40.07 69.52,39.92 69.66,39.92 70.42,40.68 70.56,40.68 70.71,40.54 70.71,40.4 69.95,39.64 69.95,39.49 70.09,39.35 70.24,39.35 71,40.11 71.14,40.11 71.28,39.96 71.28,39.82 70.53,39.06 70.53,38.92 70.67,38.78 70.81,38.78 71.57,39.53 71.71,39.53 72.57,38.68 82.12,38.68 82.7,39.27 86.76,39.27 87.27,38.76 92.58,38.76 92.66,38.83 99.52,38.83 99.67,38.68 99.67,37.63 99.77,37.53 100.18,37.53 100.28,37.63 100.28,38.66 100.38,38.76 102.06,38.76 102.26,38.55 102.26,37.82 102.41,37.67 102.64,37.67 102.82,37.84 102.82,38.07 102.94,38.2 106.5,38.2 107.57,39.27 115.47,39.27 118.06,41.86 125.6,41.86 128.8,38.66 128.8,36.88 130.05,35.63 v1(131.52,35.63)
  ART06 w0.102: v1(56.89,85.54) 56.89,85.21 57.28,84.83 57.28,84.38 57.02,84.12 57.02,78.43 60.68,74.78 62.3,74.78 64.72,72.36 64.72,69.47 66.8,67.38 67.87,67.38 69.44,65.81 70.15,65.81 71.42,64.54 71.42,63.83 71.49,63.76 v2(71.49,62.98) ; v1(133.6,14.17) 134.06,14.63 136.83,14.63 137.51,15.31 137.97,15.31 139.37,16.71 139.37,23.39 138.3,24.46 v1(138.3,25.27) 138.3,25.3 134.44,29.16 134.44,31.7 134.21,31.93 134.21,33.86 132.74,35.33 131.82,35.33 v1(131.52,35.63)
  BOTTOM w0.102: v3(56.23,85.21) 56.56,85.54 v1(56.89,85.54) RU57.2 57.15,86.05 57.66,86.56 ; v2(71.49,62.98) UU1.DD43
FLASH_SPI_MOSI_EC: length 2
  BOTTOM w0.102: UE2.5 137.41,23.7 137.79,24.08 RE34.1
FLASH_SPI_MOSI_IC: length 13.6
  TOP w0.102: RO14.2 RO12.2 134.16,12.82 v1(134.36,13.03) 134.44,13.1 MOSIO1.1
  BOTTOM w0.102: J3001.3 131.88,11 133.91,13.03 v1(134.36,13.03) ; v1(134.36,13.03) 134.47,12.93 UO1.5 ; v1(134.36,13.03) 134.36,14.75 v3(133.91,15.21)
FLASH_SPI_MOSI_TPM: length 1.9
  TOP w0.102: 138.17,26.36 137.41,27.13 UF15.21
FLASH_SPI_WP_N_EC: length 2.8
  TOP w0.102: v2(137.72,14.91) 137.92,15.11 RE29.1
  BOTTOM w0.102: UE2.3 138.68,15.31 138.28,14.91 v2(137.72,14.91)
GPD11: length 5.7
  TOP w0.102: TPU23.1 71.09,65.4 v2(69.75,66.75)
  BOTTOM w0.076: UU1.DF48 70.07,65.27 70.2,65.68 70.2,65.94 69.75,66.39 v2(69.75,66.75)
GPIO3_TPM: length 3.5
  TOP w0.102: v3(135.28,35.94) 136.04,35.18 136.04,34.62 TPF1.1 136.4,34.26 136.4,32.93 UF15.6
GPIO4_TPM: length 2.6
  TOP w0.102: UF15.13 133.52,30.18 TPF2.1
GPIO9: length 15
  TOP w0.102: v1(146.32,63.4) 145.92,63 145.92,62.18 146.18,61.92 TPE6.1 146.18,60.65 144.55,59.03 144.55,57.27 145.67,56.15 145.67,54.3 145.92,54.05 145.92,53.03 145.59,52.7 RV147.1 145.81,52.44 146.15,52.09 146.15,51.18 v3(146.21,51.12)
  BOTTOM w0.102: UV2.F8 v1(146.32,63.4)
GPJ6: length 4.7
  TOP w0.076: 158.9,18.72 159.36,18.26 160.07,18.26 160.33,17.99 160.72,17.99 UE1.F2
  TOP w0.102: RE125.1 157.55,20.19 157.73,20.01 157.73,19.91 158.06,19.58 158.16,19.58 158.9,18.84 158.9,18.72
GPP_D10: length 28.8
  TOP w0.102: RU11.1 RU16.2 v2(55.88,75.13)
  ART06 w0.102: v2(67,58.78) 67.55,58.78 67.94,59.18 67.94,59.94 68.17,60.17 69.24,60.17 69.34,60.27 69.34,61.03 69.59,61.29 69.59,61.85 69.24,62.2 69.24,62.76 68.73,63.27 68.73,63.98 68.37,64.34 65.94,64.34 64.97,65.3 64.36,65.3 64.26,65.4 64.26,65.63 63.32,66.57 62.46,66.57 56.59,72.44 56.59,73.99 55.88,74.7 v2(55.88,75.13)
  BOTTOM w0.102: v3(55.22,75.77) 55.85,75.13 v2(55.88,75.13) ; v2(67,58.78) 67.03,58.78 UU1.DL34
GPP_D12: length 11
  BOTTOM w0.102: RU10.1 57.76,57.45 58.7,57.45 58.93,57.22 RU15.2 59.66,57.1 v3(59.89,57.33) 60.42,57.86 62.48,57.86 62.61,57.99 65.02,57.99 65.14,58.1 65.61,58.1 65.86,57.86 66.97,57.86 UU1.DL33
GPP_E1: length 6
  BOTTOM w0.076: UU1.DT18 64.58,50.19 63.29,50.19 63.12,50.37 62.5,50.37 62.43,50.44 61.54,50.44 61.49,50.39 60.98,50.39
  BOTTOM w0.102: 60.98,50.39 60.83,50.24 TP179.1
GPP_E2: length 5.4
  BOTTOM w0.076: UU1.DW18 63.54,50.54 62.56,50.54 62.49,50.61 61.36,50.61 61.34,50.58
  BOTTOM w0.102: TP178.1 58.86,50.68 59.5,50.68 59.6,50.58 61.34,50.58
GPP_E3: length 4.1
  BOTTOM w0.102: TP185.1 60.54,47.41 62.95,47.41 63.12,47.57 63.56,47.57 UU1.DV11
GPP_E7: length 1.3
  TOP w0.102: TP186.1 65.71,47.01 v2(65.71,46.96)
  BOTTOM w0.102: UU1.DT11 65.45,47.22 v2(65.71,46.96)
GPP_E8: length 3.2
  TOP w0.102: TP180.1 64.27,50.33 65.01,50.33 v2(65.4,50.72)
  BOTTOM w0.102: UU1.DU16 64.89,50.16 65.07,50.16 65.4,50.49 v2(65.4,50.72)
GPP_E12: length 7.2
  BOTTOM w0.076: 60.96,50.77 62.71,50.77 62.76,50.72 63.29,50.72 arc(63.4,50.74) 63.5,50.78 63.95,50.78 UU1.DU18
  BOTTOM w0.102: 60.96,50.77 59.79,50.77 59.68,50.88 58.17,50.88 TP181.1
GPP_E13: length 3.2
  TOP w0.102: TP182.1 65.15,49.96 65.81,50.62 66.24,50.62 66.37,50.75 v2(66.37,50.75)
  BOTTOM w0.102: v2(66.37,50.75) 66.12,50.75 UU1.DT16
GPP_E21: length 1.6
  TOP w0.102: v2(66.4,49.76) 66.44,49.8 RU14.2 RU9.1
  BOTTOM w0.102: UU1.DP17 66.05,50.14 66.4,49.78 v2(66.4,49.76)
GPPC_B0_CORE_VID0_R: length 55.2
  ART05 w0.102: v1(49.02,58.75) 49.43,58.34 49.43,57.78 49.93,57.27 49.93,54.04 49.07,53.18 49.07,51.58 49.27,51.38 49.27,50.97 49.82,50.42 50.46,50.42 51.28,49.6 51.28,47.71 50.7,47.12 50.7,45.57 52.25,44.02 52.25,35.6 61.34,26.52 v2(71.93,26.52)
  BOTTOM w0.102: PD904.1 50,60.34 49.02,59.36 v1(49.02,58.75) ; PU501.18 73.79,26.36 PR504.2 PR511.2 PR502.2 72.36,26.52 v2(71.93,26.52) 71.46,26.52 PR528.2
GPPC_B0_CORE_VID_0: length 46.9
  ART03 w0.089: v2(77.91,60.28) 78.36,59.83 78.36,55.95 71.95,49.55 71.32,49.55 69.11,47.34 65.58,47.34 64.77,46.53 64.77,42.62 65.17,42.21 65.17,40 64.51,39.34 64.51,33.6 66.04,32.08 68.71,32.08 v2(69.47,31.32)
  BOTTOM w0.076: UU1.CL38 77.56,60.28 v2(77.91,60.28)
  BOTTOM w0.102: PR528.1 70.57,28.18 69.47,29.28 v3(69.47,30.35) v2(69.47,31.32)
GPPC_B1_CORE_VID1_R: length 56.4
  ART05 w0.102: v1(48.97,58.14) 48.97,57.83 49.73,57.07 49.73,54.12 48.87,53.26 48.87,51.5 49.07,51.3 49.07,50.88 49.74,50.21 50.38,50.21 51.08,49.51 51.08,47.79 49.73,46.44 49.73,46 52.04,43.69 52.04,35.45 61.2,26.29 68.91,26.29 v2(70.48,24.71)
  BOTTOM w0.102: PU501.17 73.77,25.96 PR503.2 PR508.2 PR501.2 72.21,25.85 72.08,25.73 PR529.2 71.36,25.66 70.48,24.79 v2(70.48,24.71) ; v1(48.97,58.14) 48.64,58.47 48.64,59.48 48.73,59.57 PD904.2
GPPC_B1_CORE_VID_1: length 49.8
  ART03 w0.089: v2(78.77,60.43) 78.41,60.78 77.6,60.78 77.47,60.65 77.47,58.19 78.18,57.48 78.18,56.03 71.88,49.73 71.24,49.73 69.04,47.52 65.35,47.52 64.51,46.68 64.51,42.49 64.97,42.03 64.97,40.1 64.29,39.42 64.29,33.56 66.02,31.82 68.27,31.82 v2(68.81,31.29)
  BOTTOM w0.076: UU1.CJ38 78.62,60.43 v2(78.77,60.43)
  BOTTOM w0.102: PR529.1 70.1,26.2 70.1,26.87 69.98,27 v3(69.98,27.94) 68.81,29.11 v2(68.81,31.29)
GPPC_B2_VRALERT_N: length 1.3
  TOP w0.279: 75.56,60.02 75.57,60.02 v2(76.09,60.54)
  BOTTOM w0.279: UU1.CN38 76.46,60.16 v2(76.09,60.54)
GPPC_B18_GSPI0_MOSI: length 29.9
  BOTTOM w0.102: UU1.CF48 79.65,65.46 79.65,67.59 79.41,67.83 78.41,67.83 72.69,73.54 66.91,73.54 v3(65.95,74.51) 64.12,76.34 61.02,76.34 59.43,77.92 59.43,78.56 RU117.2 59.56,79.19 59.56,79.96 RU114.1
GPPC_B23_SML1_ALERT_N: length 35.2
  TOP w0.102: v2(76.96,67.38) 74.67,67.38 68.55,73.51 66.42,73.51 63.19,76.73 60.04,76.73 59.48,77.29 59.48,80.1 59.84,80.46 v3(59.84,82.8) 59.84,84.55 59.56,84.83 59.56,86.18 59.94,86.56 58.42,86.56
  BOTTOM w0.076: v2(76.96,67.38) 76.96,67.13 77.15,66.94 77.15,66.84 77.24,66.75 77.24,65.68 77.29,65.32 UU1.CL48
GPPC_B_14_SPKR: length 249.2
  TOP w0.102: v1(177.78,34.44) 177.76,34.44 177.68,34.36 RA36.2
  ART03 w0.089: v1(177.78,34.44) 177.78,34.6 180.34,37.16 180.34,38.05 184.4,42.11 184.4,47.06 183.89,47.57 183.89,48.84 184.91,49.86 186.05,49.86 189.61,53.41 189.61,55.32 190.68,56.39 190.68,92.48 188.72,94.43 184.91,94.43 183.64,95.7 170.94,95.7 168.02,92.78 148.59,92.78 v1(147.06,94.31)
  ART06 w0.102: v1(147.06,94.31) 146.43,94.94 127.51,94.94 125.4,97.05 62.49,97.05 57.61,92.16 57.61,91.21 58.62,90.19 v2(58.62,89.99)
  BOTTOM w0.102: v2(58.62,89.99) 59.08,89.99 59.18,89.89 v3(59.18,89.68) 59.18,89.41 59,89.23 59,86.1 58.8,85.9 58.8,85.29 58.98,85.11 59.28,85.11 59.69,84.71 59.69,82.88 58.16,81.35 58.16,80.72 RU112.1 58.23,80.02 58.23,79.13 RU113.2 58.67,78.69 58.67,77.8 61.19,75.28 62.05,75.28 62.43,75.66 64.25,75.66 66.56,73.35 72.61,73.35 78.63,67.34 78.63,66.76 79.02,66.37 79.02,64.95 78.74,64.66 UU1.CH47
GPPC_C2_SMBALERT_N: length 1.7
  TOP w0.102: v2(66.4,54.34) 66.48,54.43 RU48.1
  BOTTOM w0.102: UU1.DL24 66.83,54.34 v2(66.4,54.34)
GPPC_C5_SML0ALERT_N: length 1.6
  TOP w0.102: RU49.1 65.25,52.42 v2(65.54,52.13)
  BOTTOM w0.102: UU1.DP22 66.05,52.63 v2(65.54,52.13)
GPSI1_CLK: length 6.4
  BOTTOM w0.076: 77.87,66.65 77.73,66.5 77.73,64.96 77.47,64.71 UU1.CL47
  BOTTOM w0.102: 77.87,66.65 77.87,67.13 76.22,68.78 75.18,68.78 TPU10.1
GPSI1_MISO: length 1.8
  TOP w0.102: v2(78.74,63.32) 78.61,63.19 TPU12.1
  BOTTOM w0.102: UU1.CK46 78.11,63.95 v2(78.74,63.32)
GPSI1_MOSI: length 6
  BOTTOM w0.102: TPU11.1 75.92,69.06 76.22,69.06 78.13,67.16 78.13,66.62 78.48,66.27 78.48,65.35 78.11,64.97 UU1.CK47
GPU_EVENT_N: length 142.2
  TOP w0.102: v1(127.63,48.08) 128.4,48.08 v3(129.29,47.18) 129.29,46.56 128.88,46.15 128.88,31.16 v2(129.23,30.81) ; v2(143.36,51.76) 143.59,51.52 CV196.1 143.82,51.88 143.82,51.89 QV5.3 143.82,52.65 143.91,52.75 RV40.1
  ART03 w0.089: v1(127.63,48.08) 129.67,50.11 137.03,50.11 138.17,48.97 139.83,48.97 141.86,51 142.59,51 v2(143.36,51.76) ; v2(62.99,54.43) 63.52,53.9 63.52,50.85 63.88,50.49 63.88,48.33 62.76,47.22 62.76,45.44 61.99,44.66 61.99,41.39 61.47,40.88 61.47,39.06 61.92,38.61 61.92,32.08 65.57,28.43 73.75,28.43 73.86,28.32 75.79,28.32 77.39,29.92 84.35,29.92 85.29,28.98 95.04,28.98 95.3,28.72 110.33,28.72 110.44,28.61 114.59,28.61 115.6,29.61 128.04,29.61 v2(129.23,30.81)
  BOTTOM w0.076: UU1.DV24 63.63,54.05 63.37,54.05 v2(62.99,54.43)
  BOTTOM w0.102: RU111.1 57.4,52.65 57.66,52.4 59.09,52.4 60.66,53.97 61.77,53.97 62.23,54.43 v2(62.99,54.43)
GPU_EVENT_N_R: length 11.3
  TOP w0.102: v1(144.71,61.79) 144.78,61.72 144.78,60.14 144.14,59.51 144.14,57.1 144.78,56.46 144.78,54.3 144.65,54.18 144.65,53.19 RV40.2 144.42,52.46 QV5.2 145.06,52.43 RV35.1
  BOTTOM w0.102: UV2.D6 v1(144.71,61.79)
GPU_PEX_RST_HOLD_N: length 5.6
  BOTTOM w0.102: UV2.B7 145.54,60.22 145.54,59.64 145.92,59.26 145.92,58.37 144.68,57.12 RV37.1
GPU_PG_Q: length 187.6
  ART06 w0.102: v1(138.62,51.45) 137.29,50.11 133.73,50.11 133.09,50.75 133.09,55.95 132.66,56.39 132.66,58.67 131.57,59.76 131.57,62.56 128.65,65.48 128.65,76.15 130.05,77.54 130.05,78.43 129.67,78.81 129.67,80.34 129.26,80.74 129.26,85.01 128.04,86.23 128.04,87.1 127.73,87.41 127.73,90.7 127.89,90.85 127.89,91.64 127.18,92.35 127.18,94.75 125.08,96.85 62.58,96.85 59.18,93.45 59.18,89.99 58.82,89.63 58.37,89.63 58.27,89.53 55.73,89.53 55.17,88.97 47.6,88.97 45.57,86.94 41.55,86.94 39.75,85.14 39.75,79.17 45.79,73.12 47.65,73.12 48.97,71.8 48.97,63.32 49.96,62.33 49.96,60.86 51.51,59.31 54.68,59.31 55.92,58.07 v2(56.39,58.07)
  BOTTOM w0.102: v2(56.39,58.07) 56.6,57.86 RU116.2 ; RV61.2 v1(138.62,51.45)
GPU_PG_Q_R: length 2.9
  BOTTOM w0.102: RV61.1 RV56.1 CV192.2 135.9,52.61 DV11.3
GPU_PWREN: length 151
  TOP w0.102: DV4.1 DV2.1 ; DV2.1 129.22,85.63 v1(128.52,86.33) 128.79,86.6 RV4.1 ; DV2.1 131.17,85.63 DV1.2 ; v3(134.87,78.56) 134.84,78.59 DV5.2 131.03,78.59 130.68,78.94 v1(130.23,78.94) DV8.2 ; RU119.1 RU122.1 62.33,58.75 62.46,58.87 v2(62.51,58.87)
  ART03 w0.089: v1(128.04,94.19) 126.33,95.91 61.49,95.91 56.51,90.93 56.51,86.87 57.28,86.1 57.28,84.15 56.74,83.61 56.74,79.37 54.91,77.54 53.97,77.54 v2(53.85,77.42)
  ART06 w0.102: v1(128.04,94.19) 127.38,93.53 127.38,92.44 128.09,91.72 128.09,90.62 127.94,90.47 127.94,87.53 128.52,86.94 v1(128.52,86.33) 129.59,85.27 129.59,81.05 130.23,80.41 v1(130.23,78.94) ; v2(62.51,58.87) 61.49,59.89 57.45,59.89 56.82,60.53 53.85,60.53 49.88,64.49 49.88,70.28 53.13,73.53 53.13,76.71 v2(53.85,77.42)
  BOTTOM w0.102: UU1.DU36 64.23,58.67 62.71,58.67 v2(62.51,58.87)
GPU_PWREN_18AON: length 16.4
  TOP w0.254: CV28.1 130.97,87.34 131.06,87.25 v1(131.87,87.25) 131.98,87.14 RV5.1 ; CV28.1 129.38,87.34 RV142.2 128.8,87.34 RV4.2 128.78,87.35 RV6.1 ; CV28.1 129.92,87.34 v3(129.92,89.84) v1(129.92,92.48)
  ART06 w0.305: v1(136.55,86.18) 132.94,86.18 v1(131.87,87.25)
  BOTTOM w0.102: PR1206.1 129.72,92.48 v1(129.92,92.48)
  BOTTOM w0.305: QV14.1 136.66,86.3 v1(136.55,86.18)
GPU_PWROK: length 241.1
  TOP w0.102: DV7.2 127.48,80.16 v3(127.15,79.83) ; DV7.2 128.2,80.65 128.48,80.93 RV22.1 v2(128.01,81.28) ; DV7.2 129.33,80.16 130.05,79.45 130.68,79.45 131.11,79.02 v1(132.59,79.02)
  ART03 w0.089: v1(137.16,57.68) 137.16,57.6 136.52,56.97 136.52,55.57 135.76,54.81 v1(135.76,51.76)
  ART06 w0.102: v1(165.73,35.37) 164.46,36.64 164.46,43.08 156.7,50.85 147.47,50.85 147.14,51.18 147.14,52.96 146.76,53.34 146.35,53.34 145.41,52.4 140.97,52.4 139.95,53.41 138.05,53.41 136.4,51.76 v1(135.76,51.76) ; v1(137.16,57.68) 136.83,57.68 134.93,59.58 134.93,60.6 133.09,62.43 133.09,63.32 130.94,65.48 130.94,74.72 132.48,76.27 132.48,78.92 v1(132.59,79.02) ; v2(57.91,57.86) 57.17,57.86 56.59,58.44 56.06,58.44 54.89,59.61 51.59,59.61 50.16,61.03 50.16,62.66 49.27,63.55 49.27,71.96 47.85,73.38 45.83,73.38 39.95,79.25 39.95,84.94 41.7,86.69 45.62,86.69 47.7,88.77 55.12,88.77 55.32,88.57 57.71,88.57 57.96,88.31 58.82,88.31 59.03,88.52 59.03,89.43 59.56,89.96 59.56,93.55 62.66,96.64 124.99,96.64 126.97,94.66 126.97,91.23 126.87,91.13 126.87,88.52 127.43,87.96 127.43,87.37 127.84,86.97 127.84,82.04 128.01,81.86 v2(128.01,81.28)
  BOTTOM w0.102: RV43.2 139.61,55.09 137.89,55.09 137.67,55.32 137.67,57.17 v1(137.16,57.68) 137.06,57.58 QV23.1 ; RU115.2 v2(57.91,57.86) ; v1(135.76,51.76) 135.76,51.41 DV11.2 ; v1(165.73,35.37) 165.16,35.37 PR821.1 165.09,35.43 165.09,36.03 PR819.1
GPU_PWROK_R: length 6.8
  BOTTOM w0.102: RU116.1 57.76,58.21 58.7,58.21 58.93,57.99 RU115.1 59.66,57.86 59.92,58.11 62.23,58.11 62.47,58.35 UU1.DW34
H_VCCST_PWRGD: length 5
  BOTTOM w0.102: 78.48,40.21 79.37,41.09 79.37,42.24 79.68,42.54 UU1.CF2
  BOTTOM w0.254: RU164.2 v3(78.48,39.09) 78.48,40.21
HDA_BCLK: length 233.5
  TOP w0.102: UA2.58 171.07,32.43 v1(170.99,32.51) 170.94,32.56 CA31.1 ; RU127.1 56.82,84.15 55.88,85.09 v1(55.88,87.7)
  ART03 w0.089: v1(55.88,87.7) 55.42,88.16 55.42,90.6 61.39,96.57 131.09,96.57 134.57,93.09 134.57,91.36 134.92,91.01 136.27,91.01 138.68,88.59 151.51,88.59 152.78,89.86 157.48,89.86 159,88.34 160.65,88.34 164.08,91.77 168.37,91.77 171.3,94.69 183.64,94.69 184.55,93.77 187.98,93.77 189.94,91.82 189.94,57.05 188.59,55.7 188.59,53.92 186.05,51.38 181.86,51.38 180.85,52.4 173.58,52.4 171.45,50.26 171.45,45.74 170.83,45.12 170.83,44 171.4,43.43 171.4,37.49 170.81,36.9 170.81,34.87 171.3,34.39 171.3,32.81 v1(170.99,32.51)
  BOTTOM w0.102: v3(56.49,88.52) 55.88,87.91 v1(55.88,87.7)
HDA_BCLK_R: length 29.6
  TOP w0.102: v2(71.88,67.51) 71.88,69.42 68.3,73 65.61,73 63.85,74.75 60.7,74.75 58.8,76.65 v3(58.8,77.65) 58.8,79.04 58.23,79.61 58.23,81.67 58.04,81.86 58.04,82.6 58.16,82.73 CU19.1 58.16,83.39 57.91,83.64 RU127.2
  BOTTOM w0.076: 72.53,66.13 72.71,65.95 72.71,64.7 73.1,64.31 UU1.CY46
  BOTTOM w0.102: v2(71.88,67.51) 71.88,67 72.13,66.75 72.13,66.52 72.53,66.13
HDA_RST_N: length 272.2
  TOP w0.102: v2(58.57,89.28) 58.32,89.53 56.64,89.53 55.42,88.31 55.42,84.35 v3(56.89,82.88) 56.89,81.73 ; v1(184.66,14.55) 184.4,14.81 RA246.1 ; UA2.2 169.31,30.57 168.65,31.22 v1(168.65,31.72) 168.65,31.75 168.5,31.9 CA64.1 ; v1(165.73,28.01) 166.06,28.34 166.06,29.49 RA248.1
  ART03 w0.089: v1(165.73,28.01) 166.24,28.52 168.02,28.52 169.54,27 169.54,26.24 171.07,24.71 171.07,23.95 172.9,22.12 173.66,22.12 174.24,21.54 174.24,14.65 174.98,13.92 176.27,13.92 176.78,14.42 176.78,15.19 177.42,15.82 178.1,15.82 179.88,14.04 183.26,14.04 183.77,14.55 v1(184.66,14.55) ; v2(58.57,89.28) 59.47,90.17 59.47,92.81 61.8,95.14 124.33,95.14 127.18,92.29 127.72,92.29 128.54,91.48 128.79,91.48 130.38,89.89 131.42,89.89 131.7,89.61 134.69,89.61 136.98,87.32 144.02,87.32 144.65,86.69 152.65,86.69 153.29,87.32 161.16,87.32 164.59,90.75 168.68,90.75 171.6,93.67 183.61,93.67 184.22,93.06 187.3,93.06 189.2,91.16 189.2,57.63 185.37,53.79 184.15,53.79 183.46,53.11 172.36,53.11 170.69,51.44 170.69,46.17 170.15,45.64 170.15,35.99 170.05,35.89 170.05,33.47 169.8,33.22 169.8,32.33 169.16,31.7 168.68,31.7 v1(168.65,31.72)
  BOTTOM w0.102: v1(168.65,31.72) 168.1,31.16 166.85,31.16 165.73,30.05 v1(165.73,28.01)
HDA_RST_N_R: length 27
  TOP w0.102: v2(71.44,67.92) 71.44,68.72 69.09,71.07 67.56,71.07 67.18,71.45 67.18,71.75 66.15,72.78 65.14,72.78 63.7,74.22 60.86,74.22 59.38,75.69 59.13,75.69 v3(58.56,76.26) 58.21,76.6 58.21,78.66 58.04,78.84 58.04,80.97 57.78,81.23 CU21.1 RU133.2
  BOTTOM w0.102: v2(71.44,67.92) 71.44,67.08 71.88,66.64 71.88,65.99 72.21,65.66 72.21,64.75 UU1.DA47
HDA_SDI: length 253.6
  TOP w0.102: RA13.1 169.77,33.63 v1(169.42,33.98) 169.8,34.36 CA23.1 170.13,34.41 170.43,34.72 v3(170.43,35.79) ; v2(73.91,63.32) 73.75,63.48 72.23,63.48 71.94,63.19
  ART03 w0.089: v1(169.42,33.98) 168.91,34.49 168.91,35.63 169.77,36.5 169.77,46.4 170.2,46.84 170.2,51.53 172.18,53.52 182.78,53.52 184.45,55.19 186.05,55.19 188.82,57.96 188.82,90.78 186.94,92.66 184.07,92.66 183.56,93.16 171.7,93.16 168.78,90.24 164.79,90.24 161.36,86.81 157.91,86.81 157.27,86.18 156.46,86.18 155.45,85.16 144.85,85.16 143.46,86.56 136.73,86.56 134.36,88.92 131.44,88.92 131.11,89.25 130.21,89.25 128.55,90.9 127.35,90.9 126.97,91.29 126.97,91.6 124.05,94.52 62.11,94.52 60.2,92.61 v2(60.2,92.28)
  ART06 w0.102: v2(60.2,92.28) 60.45,92.02 60.45,89.23 60.15,88.92 60.15,87.8 58.8,86.45 58.8,81.23 59.26,80.77 59.26,77.59 60.53,76.32 61.82,76.32 65.5,72.64 65.5,71.35 67.18,69.67 67.18,69.16 69.11,67.23 69.87,67.23 73.79,63.32 v2(73.91,63.32)
  BOTTOM w0.102: UU1.CV45 73.73,63.5 v2(73.91,63.32)
HDA_SDI_IC: length 1.6
  TOP w0.102: UA2.60 170.27,31.83 169.77,32.33 RA13.2
HDA_SDO: length 223.1
  TOP w0.102: CA25.1 169.11,32.74 v1(169.37,32.48) 169.37,31.07 169.47,30.97 UA2.1
  ART03 w0.089: v2(58.57,88.72) 59.66,89.81 59.66,92.68 61.91,94.93 124.27,94.93 127.1,92.1 127.64,92.1 128.46,91.29 128.71,91.29 130.31,89.68 131.29,89.68 131.62,89.35 134.59,89.35 136.88,87.07 143.89,87.07 144.52,86.43 152.91,86.43 153.57,87.09 161.31,87.09 164.72,90.5 168.76,90.5 171.68,93.42 183.59,93.42 184.15,92.86 187.12,92.86 189.01,90.97 189.01,57.77 186.18,54.94 184.53,54.94 182.9,53.31 172.28,53.31 170.43,51.47 170.43,46.43 169.96,45.96 169.96,36.31 169.8,36.14 169.8,33.6 169.54,33.35 169.54,32.66 v1(169.37,32.48)
  BOTTOM w0.102: RU131.1 v3(58.42,85.42) 58.42,86.33 58.8,86.71 58.8,88.49 v2(58.57,88.72)
HDA_SDO_R: length 30.3
  TOP w0.102: RU118.1 CU20.1 v1(59.18,83.13) 59.18,82.19 58.77,81.79 v3(58.77,81.33) 58.77,81.15 59.28,80.64 59.28,76.68 60.7,75.26 64.06,75.26 66.06,73.25 68.43,73.25 72.39,69.29 v2(72.39,67)
  BOTTOM w0.076: 72.39,66.88 72.39,66.52 72.87,66.04 72.87,65.04 UU1.CY47
  BOTTOM w0.102: v1(59.18,83.13) CU20.1 RU118.1 ; 72.39,66.88 v2(72.39,67)
HDA_SYNC: length 233.7
  TOP w0.102: v2(57.81,89.94) 57.61,89.74 56.54,89.74 55.22,88.41 55.22,84.25 56.26,83.21 56.26,80.64 v3(56.61,80.29) 56.89,80.01 RU129.1 ; UA2.59 170.67,32.04 v1(170.28,32.43) 170.28,32.89 CA24.1
  ART03 w0.089: v1(170.28,32.43) 170.28,35.35 170.34,35.42 170.34,45.32 170.98,45.96 170.98,51.44 172.44,52.91 181.35,52.91 182.37,51.89 183.13,51.89 184.53,53.29 185.55,53.29 189.58,57.33 189.58,91.54 187.63,93.49 184.38,93.49 183.69,94.18 171.47,94.18 168.55,91.26 164.34,91.26 160.91,87.83 158.77,87.83 157.25,89.35 154.18,89.35 152.78,87.96 138.56,87.96 135.76,90.75 134.77,90.75 133.86,91.67 133.3,91.67 132.54,92.43 131.37,92.43 130.99,92.05 128.77,92.05 127.13,93.7 127.13,94.05 125.66,95.52 61.64,95.52 59.08,92.96 59.08,92.33 57.81,91.06 v2(57.81,89.94)
HDA_SYNC_R: length 24.5
  TOP w0.102: v2(69.34,70.05) 68.71,70.69 66.44,70.69 65.61,71.52 65.61,71.83 63.61,73.82 60.87,73.82 59.85,74.84 59.47,74.84 v3(59.18,75.13) 59.03,75.13 57.86,76.3 57.86,76.83 56.89,77.8 CU18.1 RU129.2
  BOTTOM w0.102: 73.73,65.79 73.81,65.87 73.81,66.83 71.81,68.83 69.9,68.83 69.31,69.42 69.31,70.03 v2(69.34,70.05)
HDMI_CLK_CONN_DN: length 3.1
  TOP w0.076: RI25.1 18.43,55.15 18.06,55.15 CI117.1 17.8,55.15 17.73,55.15 17.52,55.36 17.52,55.67 17.28,55.92 16.97,55.92 ESDI13.1 16.75,55.92 16.51,55.92 RI162.2
HDMI_CLK_CONN_DN_R: length 4.1
  TOP w0.076: RI162.1 15.69,55.92 15.22,55.92 14.93,56.21 14.93,56.93 14.24,57.62 13.43,57.62 JI1.12
HDMI_CLK_CONN_DP: length 3.1
  TOP w0.076: RI163.2 16.49,55.68 16.75,55.68 ESDI14.1 16.98,55.68 17.18,55.68 17.28,55.57 17.28,55.26 17.63,54.91 17.8,54.91 CI117.2 18.06,54.91 18.48,54.91 RI26.1
HDMI_CLK_CONN_DP_R: length 4.1
  TOP w0.076: RI163.1 15.71,55.68 15.12,55.68 14.69,56.11 14.69,56.83 14.14,57.38 13.43,57.38 JI1.10
HDMI_CLK_DN: length 2.2
  TOP w0.076: UI2.13 20.69,55.23 20.61,55.15 19.36,55.15 RI25.2
HDMI_CLK_DP: length 2.2
  TOP w0.076: UI2.14 20.69,54.83 20.61,54.91 19.31,54.91 RI26.2
HDMI_CLK_LV_DN: length 1.9
  TOP w0.102: UI2.48 27.57,55.23 27.66,55.14 28.94,55.14 CI67.1
HDMI_CLK_LV_DP: length 1.9
  TOP w0.102: UI2.47 27.58,54.83 27.67,54.92 28.94,54.92 CI68.1
HDMI_DDC_SCL: length 18.8
  TOP w0.102: RI61.2 23.35,59.27 23.35,59.48 23.12,59.71 21.18,59.71 20.7,59.23 20.7,58.69 20.33,58.32 19.99,58.32 RI105.1 19.81,59.1 19.39,59.53 v3(19.31,59.53) 18.4,59.53 18,59.12 ESDI2.1 18,58.44 17.78,58.21 16.69,58.21 v1(16.51,58.39)
  ART03 w0.089: JI1.15 12.32,60.32 12.32,61.29 12.83,61.8 13.54,61.8 14.35,60.98 14.35,59.76 15.72,58.39 v1(16.51,58.39)
HDMI_DDC_SCL_8409A: length 2.9
  TOP w0.102: RI61.1 23.37,58.49 23.37,57.7 23.95,57.12 23.95,56.64 24.06,56.53 UI2.7
HDMI_DDC_SDA: length 13
  TOP w0.102: JI1.16 13.37,60 v3(14.78,58.6) 15.39,57.99 17.91,57.99 18,57.89 ESDI4.1 19.71,57.48 19.81,57.58 RI106.1 20.04,58.09 20.42,58.09 20.93,58.6 20.93,59.14 21.28,59.48 23.02,59.48 23.12,59.38 23.12,59.27 RI60.2
HDMI_DDC_SDA_8409A: length 2.9
  TOP w0.102: UI2.8 23.66,56.55 23.72,56.61 23.72,57.02 23.14,57.6 23.14,58.47 RI60.1
HDMI_HPD: length 18.8
  TOP w0.102: UI2.21 v2(20.5,52.03)
  ART06 w0.102: v2(20.5,52.03) 20.5,52.09 19.81,52.78 19.81,58.37 v1(17.27,60.91)
  BOTTOM w0.102: v1(17.27,60.91) 17.52,61.16 RI40.2 17.52,62.08 ESDI3.1 17.2,62.41 v3(16.36,62.41) 12.4,62.41 JI1.19
HDMI_ID_8409A: length 2.1
  TOP w0.102: RI152.1 24.26,48.55 24.86,49.15 UI2.32
HDMI_PDB_8409A: length 2.6
  TOP w0.102: RI155.1 RI153.1 25.78,57.22 25.26,56.7 UI2.4
HDMI_TX0_CONN_DN: length 2.7
  TOP w0.076: RI156.2 16.39,54.04 16.78,54.04 ESDI11.1 17,54.04 17.71,54.04 18.1,53.65 18.43,53.65 RI11.1
HDMI_TX0_CONN_DN_R: length 9.3
  TOP w0.076: RI156.1 15.63,54 15.28,54 v2(15.15,54.13)
  BOTTOM w0.076: JI1.9 11.88,56.12 12.16,56.12 12.38,55.9 12.38,52.68 12.73,52.32 13.69,52.32 14.07,52.7 14.07,53.62 14.37,53.92 14.95,53.92 v2(15.15,54.13)
HDMI_TX0_CONN_DP: length 2.8
  TOP w0.076: RI157.2 16.46,53.8 16.76,53.8 16.87,53.69 ESDI12.1 17,53.8 17.61,53.8 18,53.41 18.48,53.41 RI12.1
HDMI_TX0_CONN_DP_R: length 9.3
  TOP w0.076: v2(15.15,53.54) 15.37,53.76 15.63,53.76 RI157.1
  BOTTOM w0.076: JI1.7 11.88,55.88 12.06,55.88 12.14,55.8 12.14,52.58 12.63,52.08 13.79,52.08 14.31,52.6 14.31,53.52 14.47,53.68 15.02,53.68 v2(15.15,53.54)
HDMI_TX0_DN: length 2.3
  TOP w0.076: UI2.16 20.69,54.03 20.61,53.95 20.16,53.95 19.86,53.65 19.36,53.65 RI11.2
HDMI_TX0_DP: length 2.3
  TOP w0.076: UI2.17 20.69,53.63 20.61,53.71 20.26,53.71 19.96,53.41 19.31,53.41 RI12.2
HDMI_TX0_LV_DN: length 1.9
  TOP w0.102: UI2.45 27.57,54.03 27.67,53.94 28.94,53.94 CI65.1
HDMI_TX0_LV_DP: length 1.9
  TOP w0.102: CI66.1 28.94,53.72 27.66,53.72 27.57,53.63 UI2.44
HDMI_TX1_CONN_DN: length 2.5
  TOP w0.076: RI158.2 16.57,52.11 16.93,52.11 17.05,52.22 ESDI7.1 17.16,52.13 17.75,52.13 17.88,52.25 18.43,52.25 CHKI6.2
HDMI_TX1_CONN_DN_R: length 5.1
  TOP w0.076: JI1.6 13.43,54.62 13.89,54.62 14.4,54.11 14.4,52.45 14.76,52.09 15.77,52.09 RI158.1
HDMI_TX1_CONN_DP: length 2.5
  TOP w0.076: RI159.2 16.59,51.87 16.93,51.87 17.05,51.76 ESDI8.1 17.2,51.89 17.85,51.89 17.98,52.01 18.48,52.01 CHKI6.1
HDMI_TX1_CONN_DP_R: length 5.1
  TOP w0.076: RI159.1 15.78,51.85 14.66,51.85 14.16,52.35 14.16,54.01 13.79,54.38 13.43,54.38 JI1.4
HDMI_TX1_DN: length 2.4
  TOP w0.076: UI2.19 20.69,52.83 20.61,52.75 20.21,52.75 19.71,52.25 19.36,52.25 CHKI6.3
HDMI_TX1_DP: length 2.4
  TOP w0.076: CHKI6.4 19.31,52.01 19.81,52.01 20.31,52.51 20.61,52.51 20.69,52.43 UI2.20
HDMI_TX1_LV_DN: length 1.9
  TOP w0.102: CI63.1 28.94,52.74 27.7,52.74 27.6,52.83 UI2.42
HDMI_TX1_LV_DP: length 1.9
  TOP w0.102: UI2.41 27.59,52.43 27.68,52.52 28.94,52.52 CI64.1
HDMI_TX2_CONN_DN: length 3.2
  TOP w0.076: RI160.2 16.11,50.51 16.24,50.51 16.41,50.67 ESDI9.1 16.55,50.56 17.47,50.56 17.79,50.87 18.43,50.87 CHKI5.2
HDMI_TX2_CONN_DN_R: length 5.2
  TOP w0.076: RI160.1 15.21,50.54 14.65,50.54 12.08,53.12 11.88,53.12 JI1.3
HDMI_TX2_CONN_DP: length 3.1
  TOP w0.076: RI24.1 18.48,50.63 17.89,50.63 17.57,50.31 16.54,50.31 ESDI10.1 16.41,50.21 16.28,50.34 16.05,50.34 RI161.2
HDMI_TX2_CONN_DP_R: length 5.2
  TOP w0.076: RI161.1 15.28,50.3 14.55,50.3 11.98,52.88 11.88,52.88 JI1.1
HDMI_TX2_DN: length 2.5
  TOP w0.076: CHKI5.3 19.36,50.87 19.67,50.87 20.35,51.55 20.61,51.55 20.69,51.63 UI2.22
HDMI_TX2_DP: length 2.5
  TOP w0.076: UI2.23 20.69,51.23 20.61,51.31 20.45,51.31 19.77,50.63 19.31,50.63 RI24.2
HDMI_TX2_LV_DN: length 2.2
  TOP w0.102: CI61.1 28.94,50.98 28.76,50.98 28.2,51.54 27.65,51.54 27.56,51.63 UI2.39
HDMI_TX2_LV_DP: length 2.2
  TOP w0.102: UI2.38 27.59,51.23 27.68,51.32 28.12,51.32 28.67,50.77 28.94,50.77 CI62.1
HGNDA: length 4.2
  TOP w0.102: v3(185.67,37.36) v1(184.72,37.36)
  BOTTOM w0.254: JDB1.30 184.38,37.7 v1(184.72,37.36) 184.56,37.2 JDB1.31 ; JDB1.32 184.64,36.7 v1(184.68,36.74)
  vias: v1(181.74,26.18)
HGNDA_C: length 3.2
  TOP w0.203: UA2.35 178.5,26.97 179.23,26.24 SHE2.1
HGNDB: length 30.7
  TOP w0.508: QA1.6 v1(181.88,14.82)
  BOTTOM w0.254: JDB1.36 184.69,34.7 v1(184.76,34.76) ; JDB1.34 184.36,35.7 v1(184.71,35.36) 184.55,35.2 JDB1.35
  BOTTOM w0.508: v1(184.71,35.36) 186.2,35.36 187.7,33.86 187.7,25.35 186.43,24.08 v3(186.43,23.26) 186.43,19.38 186.82,19 186.82,17.6 185.04,15.82 184.66,15.82 183.66,14.82 v1(181.88,14.82)
  vias: v1(181.66,27.48)
HGNDB_C: length 3.1
  TOP w0.203: SHE5.1 v3(178.1,28.22) 177.95,28.06 177.18,28.06 177.07,28.17 UA2.38
HPD_P1: length 134.6
  TOP w0.102: 73.53,60.02 73.53,60.3 v2(73.3,60.53) ; v1(37.97,31.82) v3(35.81,31.82) 34.92,31.82 32.13,34.62 v2(31.32,34.62)
  ART03 w0.089: v2(73.3,60.53) 73.79,61.01 73.79,61.8 73.94,61.95 74.27,61.95 74.57,62.25 74.57,63.7 74.67,63.8 74.67,64.26 73.81,65.12 73.81,67.49 70.38,70.91 69.01,70.91 68.63,70.53 65.96,70.53 64.84,71.65 64.84,72.15 63.22,73.77 57.62,73.77 57.29,73.44 52.93,73.44 52.26,72.77 51.35,72.77 50.59,73.53 46.68,73.53 45.68,74.53 42.02,74.53 41.01,75.54 36.39,75.54 35.91,76.02 34.8,76.02 32.33,78.48 27.17,78.48 25.86,77.17 25.86,75.59 26.62,74.82 26.62,73.15 28.47,71.3 28.47,70.58 27.73,69.85 27.73,65.91 28.24,65.4 28.24,63.32 27.86,62.94 27.86,62.41 28.5,61.77 28.5,57.76 28.85,57.4 28.85,50.77 27.96,49.88 27.96,47.83 28.07,47.72 28.07,44.96 29.89,43.13 32.38,43.13 34.16,41.35 34.16,34.74 34.03,34.62 v2(31.32,34.62)
  BOTTOM w0.102: UU1.CV39 73.59,60.81 v2(73.3,60.53) ; v1(37.97,31.82) 39.04,32.89 39.83,32.89 40.13,33.2 v3(40.28,33.2) 40.43,33.04 40.43,32.28 41.02,31.7 42.49,31.7 42.67,31.87 42.67,32.46 42.54,32.59 RT23.2 42.09,32.81 42.09,33.53 42.39,33.83 43.53,33.83 43.96,34.26 UT1.18
HPOUT_JD_EC: length 5.2
  TOP w0.076: 158.34,15.67 v3(158.9,15.67) 159,15.67 159.83,16.49 161.07,16.49 161.16,16.59 161.19,16.63 161.2,16.64 161.39,16.84 161.88,16.84 UE1.H4
  TOP w0.102: 158.34,15.67 158.24,15.57 157.53,15.57 RE455.2
HPOUT_L: length 12.3
  TOP w0.203: UA2.33 177.11,26.17 177.29,25.98 177.97,25.98 v1(178.15,26.17)
  TOP w0.254: RA23.1 v1(180.13,31.52) CA72.2 179.51,31.3 179.12,30.91 RA20.2
  ART03 w0.254: v1(180.13,31.52) 179.96,31.34 177.77,31.34 177.16,30.74 177.16,29.53 178.19,28.5 178.19,26.2 v1(178.15,26.17)
HPOUT_L_CON: length 6.4
  TOP w0.254: v1(182.32,33.96) 182.83,33.96 v3(183.54,33.25) 183.54,32.18 183.34,31.98 182.52,31.98 182.27,31.72 CA78.1 RA23.2
  BOTTOM w0.254: v1(182.32,33.96) 182.42,33.96 182.47,33.91 182.88,33.91 183.09,33.7 JDB1.38
HPOUT_R: length 11.6
  TOP w0.203: v1(177.59,26.52) 177.54,26.57 UA2.34
  TOP w0.254: RA24.1 180.21,32.33 v1(180.13,32.41) 180.08,32.46 CA73.2
  ART03 w0.254: v1(180.13,32.41) 179.4,32.41 178.97,31.98 177.52,31.98 176.54,31 176.54,28.31 177.59,27.25 v1(177.59,26.52)
HPOUT_R_CON: length 5.3
  TOP w0.254: RA24.2 182.22,32.33 CA79.1 182.27,32.53 181.76,33.04 v1(181.3,33.04) v3(181.3,33.65)
  BOTTOM w0.254: JDB1.39 183.08,33.2 182.83,33.45 181.71,33.45 v1(181.3,33.04)
HW_ID0: length 14.4
  ART06 w0.102: v2(65.67,55.09) 65.34,55.42 61.72,55.42 61.39,55.09 55.95,55.09 v2(54.23,56.82)
  BOTTOM w0.102: UU1.DP27 66.03,54.74 v2(65.67,55.09) ; RU92.2 RU93.1 54.35,56.56 54.35,56.69 v2(54.23,56.82)
HW_ID1: length 1.8
  TOP w0.102: RU94.2 RU95.1 64.67,56.59 v2(64.84,56.77)
  BOTTOM w0.102: UU1.DU30 64.56,56.38 64.84,56.66 v2(64.84,56.77)
HW_ID2: length 5.1
  TOP w0.102: RU96.2 RU97.1 62.89,56.46 63.14,56.21 65.02,56.21 65.53,56.72 v2(65.58,56.72)
  BOTTOM w0.102: v2(65.58,56.72) 65.25,56.38 UU1.DT30
HW_ID3: length 8.5
  BOTTOM w0.102: RU98.2 57.66,55.06 58.67,55.06 58.93,54.81 RU99.1 59.31,54.68 59.82,55.19 60.96,55.19 61.85,56.08 64.54,56.08 UU1.DT29
HW_ID4: length 7.6
  BOTTOM w0.102: RU102.2 57.78,56.08 58.8,56.08 58.93,56.21 RU100.1 59.51,56.46 v3(59.94,56.03) 60.78,56.03 61.47,56.72 63.58,56.72 UU1.DV30
HW_ID5: length 8.2
  BOTTOM w0.102: UU1.DU29 63.95,55.45 62.36,55.45 61.47,54.56 60.45,54.56 59.18,53.29 RU106.1 58.93,53.49 58.82,53.59 57.99,53.59 57.78,53.79 RU105.2
HW_ID6: length 6.7
  BOTTOM w0.102: UU1.DW30 61.77,56.38 60.83,55.45 RU108.1 58.93,55.67 58.77,55.83 57.78,55.83 RU107.2
HW_ID7: length 7.3
  BOTTOM w0.102: RU109.2 57.66,54.3 58.16,53.79 58.67,53.79 58.93,54.05 RU110.1 59.43,54.18 v3(59.89,54.63) 60.07,54.81 61.09,54.81 62.01,55.73 UU1.DW29
I2C_ADDR_8409A: length 2.3
  TOP w0.102: RI151.1 23.75,48.57 23.82,48.64 24.06,48.64 24.46,49.04 UI2.31
I2C_PD_INT_N: length 5.4
  TOP w0.102: UT2.A10 23.79,20.69 23.37,20.27 22.86,20.27 22.58,19.99 21.69,19.99 20.19,18.49 RT46.1
I2C_PD_SCL: length 2.7
  TOP w0.102: UT2.C9 v2(23.77,21.94)
  BOTTOM w0.102: v3(23.01,22.32) 23.39,22.32 v2(23.77,21.94) 23.49,21.66 RT35.1 CT27.1
I2C_PD_SDA: length 3.4
  TOP w0.102: UT2.E7 24.42,22.59 v2(24.42,21.94)
  BOTTOM w0.102: v2(24.42,21.94) 24.89,21.48 CT26.1 RT34.1 25.7,21.59 v3(25.7,22.3)
I2C_PD_SOC_INT_N: length 139.2
  TOP w0.102: RU218.1 v1(59.94,85.54) 59.94,85.32 v3(60.25,85.01) ; RT126.2 49.53,38.05 49.2,38.38 v1(48.97,38.38) ; RU151.2 77.54,61.54 v2(77.82,61.82)
  ART03 w0.089: v2(77.82,61.82) 77.85,61.85 77.85,62.48 75.08,65.25 75.08,66.97 70.48,71.57 68.73,71.57 68.35,71.19 66.05,71.19 65.66,71.59 65.66,72.15 63.46,74.34 57.38,74.34 57.05,74.01 52.69,74.01 52.31,73.63 v1(52.02,73.63) ; v2(41.27,37.03) 47.88,37.03 48.97,38.12 v1(48.97,38.38)
  ART05 w0.102: v1(52.02,73.63) 47.55,69.16 46.23,69.16 43.94,66.88 43.94,64.13 41.98,62.18 39.24,62.18 38.76,61.69 33.68,61.69 32.87,60.88 32.87,59.1 31.01,57.25 31.01,56.61 29.56,55.17 29.56,51.53 32.51,48.59 32.51,41.98 33.63,40.87 33.63,39.22 34.8,38.05 40.26,38.05 v2(41.27,37.03)
  ART06 w0.102: v1(59.94,85.54) 60.07,85.42 60.07,80.59 60.32,80.34 60.32,77.39 60.86,76.86 62,76.86 67.05,71.8 67.05,71.07 68.76,69.36 68.76,68.45 69.31,67.89 70.86,67.89 74.17,64.59 74.42,64.59 75.56,63.45 75.56,62.3 76.58,61.29 77.29,61.29 v2(77.82,61.82)
  BOTTOM w0.102: UT1.5 48.87,38.04 48.97,38.14 v1(48.97,38.38)
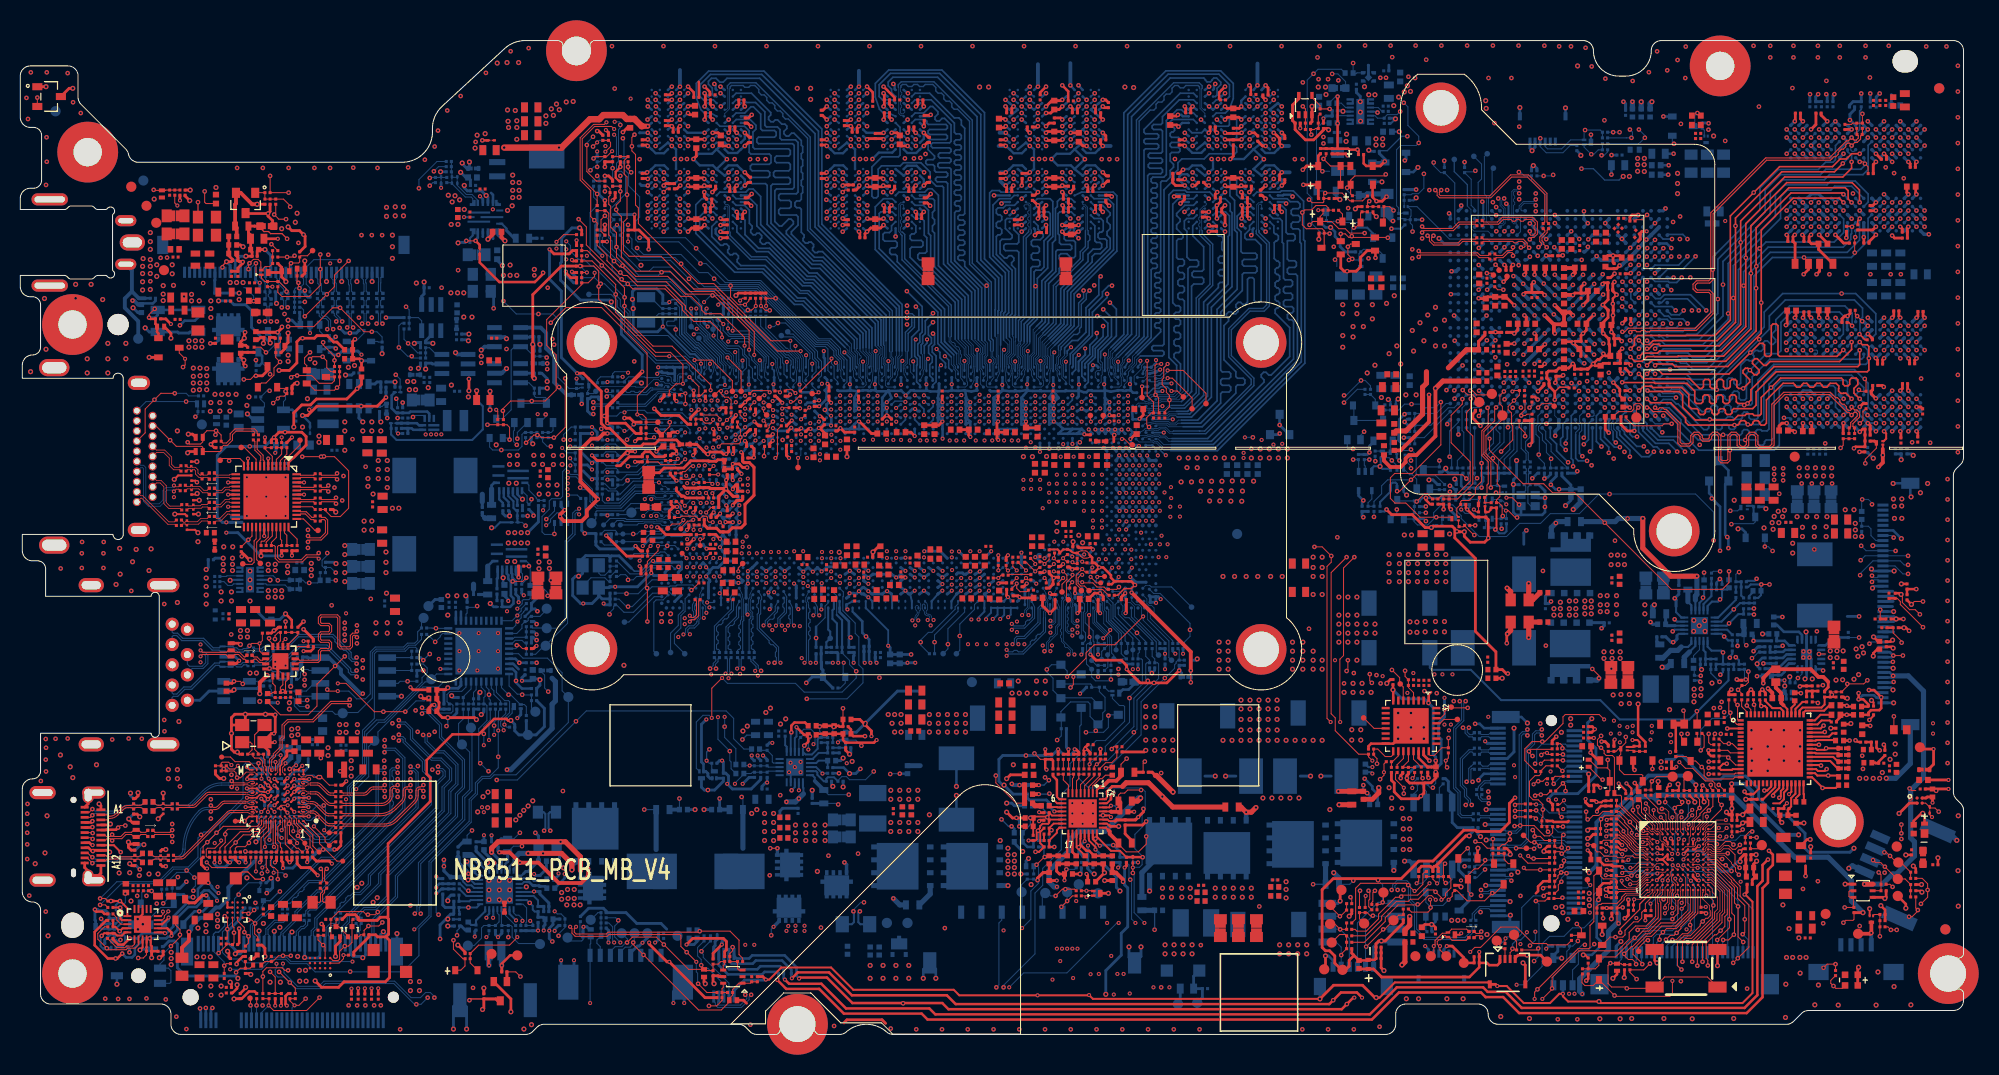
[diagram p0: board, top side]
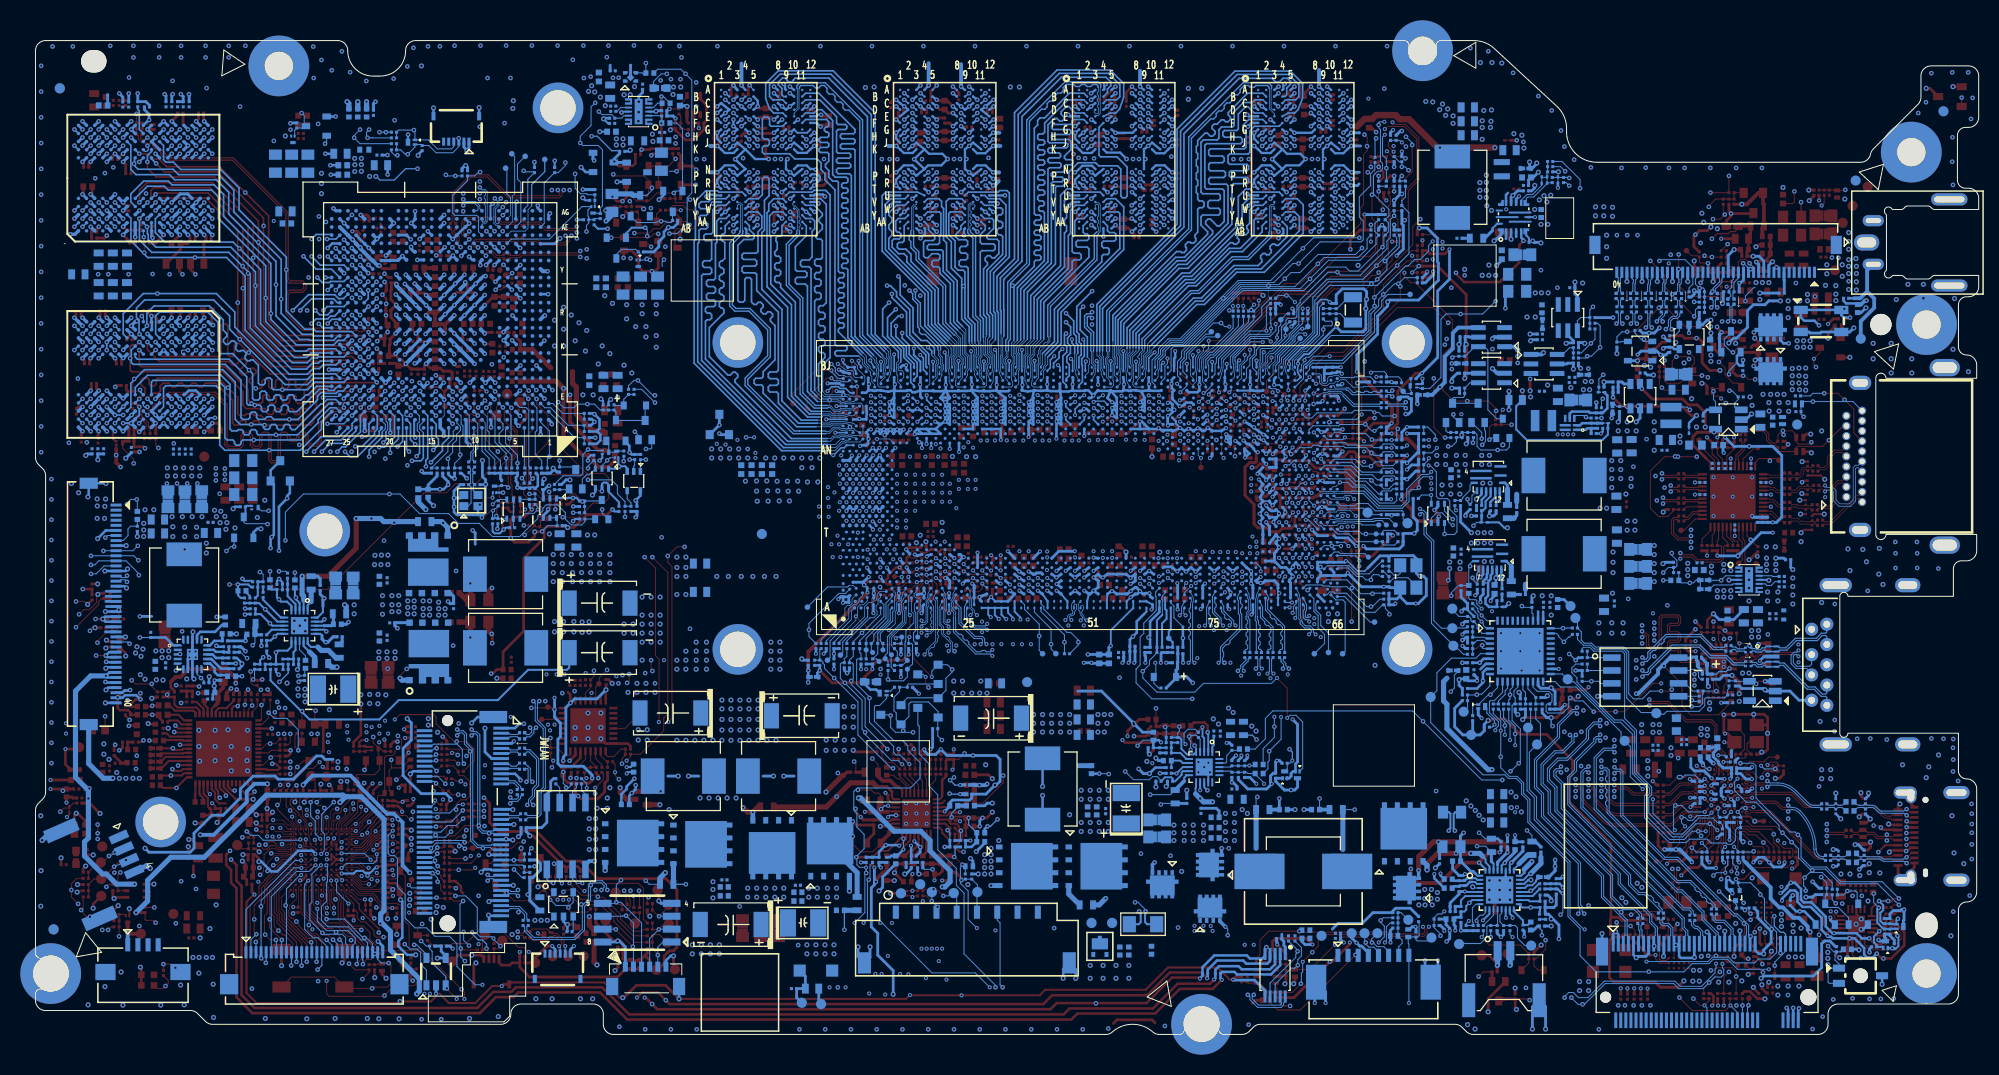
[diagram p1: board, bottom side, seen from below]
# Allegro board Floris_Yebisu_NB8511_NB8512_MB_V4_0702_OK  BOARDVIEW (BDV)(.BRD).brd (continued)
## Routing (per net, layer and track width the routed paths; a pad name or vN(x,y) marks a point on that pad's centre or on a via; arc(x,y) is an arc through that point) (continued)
I2C_PD_SOC_INT_N_R: length 1
  TOP w0.102: v2(77,60.66) 77.38,61.03 RU151.1
  BOTTOM w0.076: v2(77,60.66) 77.16,60.81 UU1.CL39
I2CB_SCL: length 6.3
  BOTTOM w0.076: 147.03,59.51 147.11,59.59 147.11,60.9 UV2.C9
  BOTTOM w0.102: 147.03,59.51 146.91,59.39 146.91,57.68 145.79,56.56 RV28.2
I2CB_SDA: length 6.2
  BOTTOM w0.102: RV30.2 v3(145.24,56.82) 145.24,57.3 146.33,58.4 146.33,60.97 UV2.C8
I2CC_SCL: length 4.3
  BOTTOM w0.102: UV2.A9 147.62,57.52 146.91,56.82 RV33.2
I2CC_SDA: length 5.3
  BOTTOM w0.076: 147.3,59.05 147.3,60.3 UV2.B9
  BOTTOM w0.102: RV36.2 146.35,56.72 147.3,57.66 147.3,59.05
ILIM_HI1: length 1.7
  TOP w0.102: RB46.1 26.16,34.77 26.4,35.01 UB6.16
ILIM_LO1: length 1.7
  TOP w0.102: UB6.15 25.9,34.49 25.65,34.24 RB45.1
ILIM_SEL1: length 222.6
  TOP w0.102: UB6.4 27.1,37.97 27.38,38.25 RB50.1 RB48.1 v2(27.94,38.78) ; RE123.2 v1(171.24,19.43)
  ART03 w0.089: v2(27.94,38.78) 28.45,38.28 28.45,37.61 28.19,37.36 28.19,36.7 26.26,34.77 22.55,34.77 18.95,31.16 18.95,28.63 17.87,27.55 17.87,27.07 17.23,26.42 17.23,25.14 16.55,24.46 v1(15.75,24.46) ; v1(170.31,4.52) 171.32,5.53 171.32,15.57 170.69,16.2 170.69,18.87 v1(171.24,19.43)
  ART06 w0.102: v1(170.31,4.52) 167.77,1.98 153.54,1.98 151.38,4.14 144.82,4.14 144.44,4.52 116.95,4.52 114.59,2.16 93.85,2.16 91.56,4.44 73.51,4.44 71.78,2.72 57.48,2.72 56.69,3.5 48.64,3.5 46.3,1.17 21.51,1.17 18.34,4.34 18.34,5.1 15.62,7.82 15.62,15.44 16.13,15.95 16.13,24.08 v1(15.75,24.46)
IMVP9_SET1: length 2.6
  TOP w0.102: PU601.8 103.37,24.59 102.87,25.09 PR620.2 PR616.1
IMVP9_SET2: length 2.4
  TOP w0.102: PU601.7 103.77,25.24 103.88,25.35 PR617.1 PR621.2
IMVP9_SET3: length 2.5
  TOP w0.102: PR622.2 PR618.1 104.39,25.22 104.17,25 PU601.6
IMVP9_VRON: length 5.6
  TOP w0.191: PU601.23 105.77,19.25 106.42,18.61 v2(106.47,18.61)
  BOTTOM w0.254: v2(106.47,18.61) 106.53,18.67 v3(107.8,18.67) 108.46,18.01 108.46,17.47 109.73,17.47
INPUT3VSEL: length 16.6
  BOTTOM w0.102: RU154.1 RU153.2 56.64,74.62 v3(57.24,74.02) 57.62,74.02 59.18,72.46 59.18,71.83 59.94,71.07 59.94,69.29 62.76,66.47 65.71,66.47 66.32,65.85 66.32,65.79
JSENSE_AB: length 53.9
  TOP w0.102: v2(156.36,15.69) 156.39,15.67 RE455.1 ; RA238.2 RA237.2 CA74.1 180.19,34.34 v1(180.19,34.57) 181.81,34.57 v3(182.17,34.92)
  ART03 w0.089: v2(156.36,15.69) 156.06,16 156.06,21.31 156.56,21.82 156.56,23.54 156.31,23.8 156.31,24.51 156.11,24.71 155.69,24.71 155.6,24.8 155.6,27 156.39,27.79 156.39,29.87 157.17,30.66 v2(157.17,30.93) ; v1(182.37,38.53) 182.27,38.43 182.27,37.36 180.19,35.28 v1(180.19,34.57)
  ART05 w0.089: v2(157.17,30.93) 157.3,31.06 171.72,31.06 174.12,33.46 174.12,33.86 175,34.74 175.64,34.74 175.77,34.62 177.16,34.62 177.67,35.13 178.26,35.13 178.56,35.43 179.93,35.43 180.19,35.18 v1(180.19,34.57)
  BOTTOM w0.102: v1(182.37,38.53) 182.54,38.7 JDB1.28
JSENSE_IC: length 4.9
  TOP w0.203: UA2.47 175.47,31.94 175.77,32.23 177.65,32.23 177.95,32.53 RA236.2 RA238.1 RA237.1
KB_BL_LED: length 27.8
  TOP w0.076: 163.04,12.07 163.27,12.29 163.27,13.21 163.04,13.43 163.04,13.84 163.22,14.02 163.22,14.83 162.85,15.21 162.85,15.51 162.97,15.64 UE1.K6
  TOP w0.102: 163.04,12.07 162.92,11.94 v2(162.92,11.94) ; RE13.1 184.19,10.61 v1(184.49,10.31) v3(185.06,10.31)
  ART06 w0.102: v2(162.92,11.94) 163.99,10.87 176.78,10.87 177.15,10.5 184.3,10.5 v1(184.49,10.31)
KB_CTL_FB: length 3.6
  TOP w0.381: TP154.1 182.47,9.93 v1(182.55,10.01) 182.56,10.03 QE2.3
  BOTTOM w0.381: JKBL1.1 v1(182.55,10.01)
LAN_WAKE_N: length 21.9
  BOTTOM w0.076: 69.87,67.13 70.16,66.84 70.16,66.23 70.38,66.01 70.38,65.65 70.33,65.48 70.33,65.08 UU1.DE47
  BOTTOM w0.102: 69.87,67.13 69.57,67.13 68.01,68.69 68.01,69.07 67.05,70.02 67.05,71.7 64.29,74.47 60.73,74.47 v3(59.4,75.8) 57.4,77.8 57.4,78.56 RU172.2
LDO_VDD_1P2: length 2.6
  TOP w0.203: UA2.51 173.87,31.89 173.58,32.18 172.8,32.18 172.11,32.87 CI103.1
LDO_VDD_1P6: length 1.5
  TOP w0.203: CA68.1 175,32.53 174.67,32.2 UA2.49
LED2_N: length 2.1
  TOP w0.102: v1(152.09,25.98) RW63.2
  BOTTOM w0.102: JW1.16 152.56,26.45 v1(152.09,25.98)
LED_CHG_FULL_N: length 62
  TOP w0.076: v2(163.76,15.21) 163.76,15.45 UE1.K7
  ART06 w0.102: v1(186.18,47.19) 185.67,46.68 185.67,44.93 189.05,41.55 189.05,19.97 186.3,17.22 174.31,17.22 171.77,14.68 168.02,14.68 167.89,14.81 164.17,14.81 v2(163.76,15.21)
  BOTTOM w0.102: v3(181.51,46.76) 181.95,47.2 JDB1.11 186.04,47.2 186.05,47.19 v1(186.18,47.19)
LED_CHG_N: length 68.7
  TOP w0.102: v2(162.2,12.49) 162.2,12.77 162.47,13.04 UE1.N5
  ART06 w0.102: v2(162.2,12.49) 162.63,12.92 163.19,12.92 163.65,13.38 164.97,13.38 165.07,13.28 166.75,13.28 167.64,12.39 172.08,12.39 174.5,14.81 176.1,14.81 176.76,14.15 185.21,14.15 189.66,18.6 189.66,43.2 187.25,45.62 187.25,46.76 186.33,47.68 v1(184.95,47.68)
  BOTTOM w0.102: v1(184.95,47.68) 184.93,47.7 JDB1.10 182.04,47.7 v3(181.56,48.18)
LED_PWR_ON: length 72.1
  TOP w0.076: UE1.J6 162.72,15.99 162.72,15.63 162.5,15.4 v2(162.5,15.18)
  TOP w0.102: RE456.1 v1(179.03,6.93) 178.2,6.93 v3(177.85,6.58)
  ART03 w0.076: v1(177.29,15.11) 178.58,13.82 178.58,7.38 v1(179.03,6.93)
  ART06 w0.102: v1(186.18,45.41) 186.18,45.13 189.25,42.06 189.25,19.83 186.38,16.96 179.14,16.96 v1(177.29,15.11) 176.32,16.08 173.73,16.08 171.83,14.17 168.02,14.17 167.6,14.59 163.09,14.59 v2(162.5,15.18)
  BOTTOM w0.102: v1(186.18,45.41) 185.67,45.41 184.89,46.2 JDB1.13
LED_PWR_STANDBY: length 67.3
  TOP w0.075: v1(162.06,13.32) 162.22,13.48 162.22,14.49 UE1.M5
  ART06 w0.102: v1(162.06,13.32) 162.83,14.09 166.7,14.09 167.89,12.9 171.96,12.9 174.24,15.19 176.08,15.19 176.84,14.42 178.69,14.42 179.58,15.31 186.07,15.31 189.46,18.7 189.46,42.77 186.18,46.05 v1(186.18,46.3)
  BOTTOM w0.102: v1(186.18,46.3) 185.8,46.3 185.4,46.7 JDB1.12 182.72,46.7 181.46,45.44 v3(181.46,45.29)
LID_INT_N: length 245.3
  TOP w0.076: UE1.B11 165.72,19.99 165.72,20.38 166.34,21 v2(166.34,21.48)
  TOP w0.102: RE53.2 15.24,81.99 v2(15.49,81.73) ; v1(28.57,67.26) 28.04,66.72 28.04,66.16 28.26,65.95 DX1.1
  ART03 w0.089: v2(166.34,21.48) 166.34,20.55 166.88,20.01 166.88,15.31 167.08,15.11 167.08,10.44 164.84,8.2 163.93,8.2 163.19,7.47 163.19,6.77 161.99,5.57 159.04,5.57 158.67,5.2 157.98,5.2 156.95,6.23 156.43,6.23 155.98,6.68 153.12,6.68 152.54,6.11 149.77,6.11 149.14,5.47 135.67,5.47 134.49,4.29 114.45,4.29 113.64,5.1 107.24,5.1 v2(106.37,5.97)
  ART05 w0.102: v2(106.37,5.97) 105.46,6.88 102.36,6.88 101.93,7.31 89.21,7.31 88.12,8.4 64.66,8.4 62.47,6.22 49.16,6.22 48.99,6.4 42.81,6.4 39.76,9.45 38.65,9.45 35.68,12.42 34.61,12.42 34.29,12.74 34.29,14.93 33.4,15.82 33.4,21.28 31.77,22.91 31.77,28.69 30.91,29.55 30.91,35.84 28.95,37.79 28.95,42.11 28.57,42.49 28.57,44.14 27.86,44.85 27.86,47.62 27.4,48.08 27.4,55.8 28.19,56.59 28.19,57.2 27.43,57.96 27.43,63.19 28.19,63.95 28.19,66.88 v1(28.57,67.26) 28.57,68.5 29.13,69.06 29.13,74.7 28.57,75.26 28.57,77.54 27.68,78.43 26.01,78.43 25.25,79.19 25.25,80.13 25.6,80.49 25.6,81.2 25.35,81.46 23.87,81.46 23.12,80.71 16.52,80.71 v2(15.49,81.73)
LID_OPEN_INT: length 21.9
  TOP w0.102: R16.1 RE53.1 C8.1 14.35,83.26 14.32,83.23 ESDE45.1 13.21,83.23 v1(13.16,83.28) ; MR1.2 v1(1.68,92.38)
  ART03 w0.089: v1(1.68,92.38) 1.68,92.35 3.3,90.73 3.3,85.29 5.31,83.28 v1(13.16,83.28)
M.2_BT_PCMCLK: length 146.5
  ART05 w0.102: v1(149.4,26.69) 148.79,26.69 148.23,27.25 144.07,27.25 143.05,26.24 135.32,26.24 133.42,28.14 130.88,28.14 129.41,29.61 114.91,29.61 113.92,28.62 110.72,28.62 109.83,29.51 95.65,29.51 94.05,31.11 76.3,31.11 75.36,30.17 73.25,30.17 71.55,31.87 65.86,31.87 59.61,38.12 59.61,44.63 58.77,45.46 58.77,47.67 56.82,49.63 56.82,51.99 56.41,52.4 56.41,53.92 56.89,54.4 56.89,61.01 57.02,61.14 57.02,64.34 61.59,68.91 64.56,68.91 67.13,71.47 67.13,71.9 v2(67.44,72.21)
  BOTTOM w0.102: v2(67.44,72.21) 68.1,72.87 v3(68.27,72.87) 69.06,72.87 RU135.1 ; JW1.8 152.57,28.45 152.4,28.62 150.06,28.62 149.55,28.12 149.55,26.85 v1(149.4,26.69)
M.2_BT_PCMIN: length 1.8
  TOP w0.102: RW14.1 v1(152.14,27.61)
  BOTTOM w0.102: JW1.12 152.3,27.45 v1(152.14,27.61)
M.2_BT_PCMOUT_CLKREQ: length 1.7
  TOP w0.102: v1(152.14,27.02) 152.12,27.05 RW13.2
  BOTTOM w0.102: v1(152.14,27.02) 152.17,27.02 152.24,26.95 JW1.14
M_A_CK_DDR0_DN: length 48.5
  PWR04 w0.14: v1(65.17,86.32) 65.33,86.48 65.33,86.73 65.62,87.03 66.66,87.03 67.1,86.59 67.1,85.88 66.88,85.65 66.88,78.2 67.02,78.06 69.4,78.06 69.54,78.2 69.54,79.46 69.84,79.75 70.62,79.75 70.91,79.46 70.91,78.2 71.05,78.06 72.5,78.06 78.85,71.71 86.35,71.71 86.99,71.07 87.29,71.07 v1(87.45,71.23)
  ART06 w0.14: v1(65.07,87.61) 65.33,87.35 65.33,86.48 v1(65.17,86.32) 65.33,86.16 65.33,85.26 v1(65.07,85.01)
  BOTTOM w0.076: UU1.BL48 87.3,65.32 87.25,65.68 87.25,65.94 87.51,66.2 87.51,67.35 87.56,67.4
  BOTTOM w0.14: v1(87.45,71.23) 87.61,71.07 87.96,71.07 88.19,70.84 88.19,70.18 88.19,69.75 87.56,69.12 87.56,67.4 ; UD1.J9 v1(65.07,87.61) ; UD1.P9 v1(65.07,85.01)
M_A_CK_DDR0_DP: length 48.6
  PWR04 w0.14: v1(65.75,86.32) 65.59,86.48 65.59,86.62 65.73,86.76 66.55,86.76 66.84,86.48 66.84,85.99 66.61,85.76 66.61,85.23 66.44,85.06 66.44,84.67 66.61,84.5 66.61,84.11 66.44,83.94 66.44,83.55 66.61,83.39 66.61,78.09 66.91,77.8 69.51,77.8 69.81,78.09 69.81,79.35 69.95,79.49 70.5,79.49 70.64,79.35 70.64,78.09 70.94,77.8 72.39,77.8 78.74,71.45 86.23,71.45 86.88,70.8 87.29,70.8 v1(87.45,70.64)
  ART06 w0.14: v1(65.86,87.61) 65.59,87.34 65.59,86.48 v1(65.75,86.32) 65.59,86.16 65.59,85.27 v1(65.86,85.01)
  BOTTOM w0.076: UU1.BL47 87.16,65.09 87.08,65.67 87.08,66 87.35,66.27 87.35,67.33 87.3,67.38 87.3,67.4
  BOTTOM w0.14: UD1.P8 v1(65.86,85.01) ; v1(87.45,70.64) 87.61,70.8 87.85,70.8 87.92,70.73 87.92,70.18 87.92,69.86 87.3,69.23 87.3,67.4 ; UD1.J8 v1(65.86,87.61)
M_A_CK_DDR1_DN: length 46
  PWR04 w0.14: v1(82.82,86.32) 82.98,86.48 82.98,86.73 83.28,87.03 84.41,87.03 84.82,86.62 84.82,86.02 84.53,85.73 84.53,82.93 84.96,82.5 86.23,82.5 86.87,81.86 86.87,79.58 87.36,79.08 87.87,79.08 88.3,78.65 88.5,78.65 89.27,79.42 89.69,79.42 90.24,78.87 90.24,78.45 89.47,77.68 89.47,77.48 89.87,77.08 90.06,77.08 90.84,77.85 91.25,77.85 91.81,77.3 91.81,76.88 91.03,76.11 91.03,75.92 91.43,75.52 91.63,75.52 92.21,76.1 92.63,76.1 93.18,75.55 93.18,75.13 92.6,74.55 92.6,74.35 93.85,73.1 93.85,66.09 92.33,64.56 91.67,64.56 89.67,62.56 89.31,62.56 v2(89.12,62.37)
  ART06 w0.14: v1(82.72,85.01) 82.98,85.26 82.98,86.16 v1(82.82,86.32) 82.98,86.48 82.98,87.35 v1(82.72,87.61)
  BOTTOM w0.14: UD2.P9 v1(82.72,85.01) ; UD2.J9 v1(82.72,87.61) ; UU1.BF42 v2(89.12,62.37)
M_A_CK_DDR1_DP: length 46
  PWR04 w0.14: v2(89.12,63.02) 89.31,62.83 89.56,62.83 91.56,64.83 92.22,64.83 92.44,65.06 92.44,65.34 92.7,65.59 92.98,65.59 93.58,66.2 93.58,66.67 93.39,66.86 93.39,67.23 93.58,67.42 93.58,67.66 93.39,67.85 93.39,68.22 93.58,68.41 93.58,68.78 93.39,68.97 93.39,69.34 93.58,69.53 93.58,69.89 93.39,70.08 93.39,70.45 93.58,70.64 93.58,72.99 92.33,74.24 92.33,74.66 92.91,75.24 92.91,75.44 92.52,75.83 92.32,75.83 91.74,75.25 91.32,75.25 90.77,75.81 90.77,76.22 91.54,77 91.54,77.19 91.14,77.59 90.95,77.59 90.17,76.82 89.76,76.82 89.2,77.37 89.2,77.79 89.98,78.56 89.98,78.76 89.58,79.15 89.38,79.15 88.61,78.38 88.19,78.38 87.76,78.81 87.25,78.81 86.6,79.47 86.6,80.68 86.41,80.87 86.41,81.23 86.6,81.43 86.6,81.75 86.12,82.23 84.85,82.23 84.26,82.82 84.26,83.45 84.05,83.66 84.05,84 84.26,84.22 84.26,84.56 84.05,84.78 84.05,85.12 84.26,85.34 84.26,85.84 84.55,86.13 84.55,86.51 84.3,86.76 83.39,86.76 83.25,86.62 83.25,86.48 v1(83.4,86.32)
  ART06 w0.14: v1(83.51,85.01) 83.25,85.27 83.25,86.16 v1(83.4,86.32) 83.25,86.48 83.25,87.34 v1(83.51,87.61)
  BOTTOM w0.14: UD2.J8 v1(83.51,87.61) ; UD2.P8 v1(83.51,85.01) ; UU1.BF43 v2(89.12,63.02)
M_A_DQ_0[0]: length 25.8
  BOTTOM w0.076: 81.56,68.01 81.81,67.76 81.81,67.28 82.23,66.86 82.23,65.66 82.26,65.62 82.38,65.5 UU1.CA48
  BOTTOM w0.165: UD1.Y4 68.35,81.11 67.47,81.11 67,80.64 67,79.25 70.76,75.49 73.3,75.49 76.48,72.31 77.26,72.31 81.56,68.01
M_A_DQ_0[1]: length 28.3
  BOTTOM w0.076: 81.34,67.76 81.63,67.46 81.63,67.21 82.06,66.78 82.06,65.59 82.17,65.43 82.17,64.88 82.28,64.68 UU1.CA47
  BOTTOM w0.165: 81.34,67.76 77.11,71.98 76.35,71.98 73.18,75.16 70.46,75.16 66.62,78.99 66.62,81.81 67.22,82.41 68.35,82.41 UD1.V4
M_A_DQ_0[2]: length 23.6
  BOTTOM w0.076: UU1.CA49 82.4,65.87 82.4,66.95 81.99,67.36 81.99,68.07 81.71,68.35
  BOTTOM w0.165: 81.71,68.35 77.44,72.62 76.66,72.62 73.45,75.82 71.07,75.82 70.7,76.18 70.7,76.41 70.83,76.54 70.83,76.77 70.59,77 70.36,77 70.24,76.88 70,76.88 69.77,77.11 69.77,77.35 69.89,77.47 69.89,77.7 69.66,77.94 69.42,77.94 69.3,77.81 69.07,77.81 68.2,78.69 68.2,79.66 UD1.AA4
M_A_DQ_0[3]: length 24.3
  BOTTOM w0.076: 83.41,67.76 83.41,67.33 83.82,66.93 83.82,65.95 83.82,65.87 UU1.BV49
  BOTTOM w0.165: UD1.V2 70.6,81.76 71.43,81.76 71.91,81.28 71.91,79.98 72.18,79.7 72.18,79.47 72.04,79.32 72.04,79.09 72.27,78.86 72.5,78.86 72.65,79 72.89,79 73.12,78.77 73.12,78.54 72.97,78.39 72.97,78.15 73.2,77.92 73.44,77.92 73.59,78.07 73.82,78.07 77.46,74.43 78.27,74.43 83.41,69.29 83.41,67.76
M_A_DQ_0[4]: length 23.8
  BOTTOM w0.076: UU1.CA45 83.2,63.84 83.42,64.06 83.42,64.29 83.35,64.42 83.35,66.05 83.49,66.19 83.49,66.75 82.82,67.42 82.82,67.61
  BOTTOM w0.165: 82.82,67.61 82.82,68.94 77.94,73.82 77.15,73.82 73.79,77.19 72.62,77.19 70.67,79.13 70.67,79.73 UD1.AA2
M_A_DQ_0[5]: length 23.5
  BOTTOM w0.076: UU1.BV47 83.59,64.66 83.51,64.85 83.51,65.96 83.65,66.1 83.65,66.84 83.11,67.38 83.11,67.71
  BOTTOM w0.165: UD1.Y2 70.6,80.46 71.3,80.46 71.47,80.29 71.47,78.86 72.82,77.52 73.91,77.52 77.32,74.11 78.13,74.11 83.11,69.13 83.11,67.71
M_A_DQ_0[6]: length 28.9
  BOTTOM w0.076: 84,67.66 84,67.26 84.15,67.1 84.15,65.86 84.06,64.95 84.06,64.49 UU1.BV45
  BOTTOM w0.165: 84,67.66 84,69.67 78.59,75.08 77.8,75.08 73.02,79.86 73.02,82.62 72.29,83.36 71.85,83.36 71.55,83.06 69,83.06 UD1.U4
M_A_DQ_0[7]: length 24.7
  BOTTOM w0.076: 83.72,67.69 83.72,67.28 83.99,67.01 83.99,65.87 83.93,65.33 UU1.BV48
  BOTTOM w0.165: UD1.U2 70.6,82.41 72,82.41 72.64,81.76 72.64,79.73 77.62,74.75 78.43,74.75 83.72,69.47 83.72,67.69
M_A_DQ_1[0]: length 31.3
  ART06 w0.076: 81.9,63.46 82.22,63.14 82.22,62.86 81.83,62.47 v2(81.83,62.38)
  ART06 w0.14: v1(65.06,80.46) 65.56,79.96 66.29,79.96 67.31,78.94 67.53,78.94 67.95,79.36 68.16,79.36 68.38,79.14 68.38,78.93 67.96,78.51 67.96,78.29 68.32,77.92 69.29,77.92 74.54,72.68 74.54,72.46 74.33,72.26 74.33,72.04 74.55,71.83 74.77,71.83 74.97,72.03 75.18,72.03 75.4,71.81 75.4,71.6 75.2,71.39 75.2,71.18 75.41,70.96 75.63,70.96 75.83,71.17 76.05,71.17 76.26,70.95 76.26,70.74 76.06,70.53 76.06,70.32 76.27,70.1 76.49,70.1 76.69,70.31 76.91,70.31 78.87,68.35 78.87,67.21 81.43,64.64 81.43,63.93 81.9,63.46
  BOTTOM w0.076: UU1.CC42 81.82,62.35 v2(81.83,62.38)
  BOTTOM w0.165: UD1.Y9 v1(65.06,80.46)
M_A_DQ_1[1]: length 31.7
  ART06 w0.076: 82.22,63.96 82.22,63.55 82.4,63.37 82.4,62.79 82.19,62.58 82.19,61.46
  ART06 w0.089: 82.19,61.46 v2(81.8,61.07)
  ART06 w0.14: v1(65.06,81.76) 65.54,82.24 66.04,82.24 66.42,81.86 66.42,81.48 66.93,80.97 69.21,80.97 69.47,80.72 69.47,78.43 80.01,67.89 80.01,67.23 80.87,66.37 80.87,65.81 82.22,64.46 82.22,63.96
  BOTTOM w0.076: v2(81.8,61.07) 81.73,61.03 UU1.CC39
  BOTTOM w0.165: UD1.V9 v1(65.06,81.76)
M_A_DQ_1[2]: length 31
  ART06 w0.14: v1(65.06,79.81) 65.29,79.58 66.14,79.58 68.57,77.15 68.78,77.15 68.96,77.33 69.18,77.33 69.39,77.11 69.39,76.89 69.22,76.72 69.22,76.5 69.43,76.28 69.65,76.28 69.82,76.46 70.04,76.46 70.26,76.25 70.26,76.03 70.08,75.85 70.08,75.64 70.29,75.42 70.51,75.42 70.69,75.6 70.9,75.6 71.12,75.39 71.12,75.17 70.94,74.99 70.94,74.78 71.15,74.56 71.37,74.56 71.55,74.74 71.76,74.74 71.98,74.52 71.98,74.31 71.8,74.13 71.8,73.91 72.02,73.7 72.23,73.7 72.41,73.88 72.63,73.88 72.84,73.66 72.84,73.45 72.66,73.27 72.66,73.05 72.88,72.84 73.09,72.84 73.27,73.02 73.49,73.02 73.91,72.59 73.91,71.96 76.33,69.54 77.09,69.54 77.47,69.16 77.47,68.91 77.37,68.81 77.37,68.36 77.69,68.04 77.9,68.04 78.08,68.21 78.29,68.21 78.51,67.99 78.51,67.78 78.33,67.6 78.33,67.39 81.15,64.57 81.15,63.83 81.86,63.11 v2(81.86,63)
  BOTTOM w0.076: UU1.CC43 81.86,63 81.88,62.99 81.88,63 v2(81.86,63)
  BOTTOM w0.165: UD1.AA9 v1(65.06,79.81)
M_A_DQ_1[3]: length 33.8
  ART06 w0.14: v2(80.89,60.44) 80.8,60.53 79.86,60.53 78.89,61.49 78.59,61.49 78.38,61.69 78.38,62 74.78,65.61 74.04,65.61 73.53,66.11 73.53,66.7 61.09,79.14 61.09,82.12 61.39,82.42 62.67,82.42 v1(62.69,82.41)
  BOTTOM w0.076: UU1.CE38 v2(80.89,60.44)
  BOTTOM w0.165: UD1.U11 v1(62.69,82.41)
M_A_DQ_1[4]: length 32.9
  ART06 w0.076: 82.47,63.96 82.47,63.6 82.57,63.5 82.57,62.71 82.37,62.51 82.37,61.01 82.14,60.78 v2(81.8,60.44)
  ART06 w0.14: 82.47,63.96 82.47,64.64 81.25,65.86 81.25,66.37 80.4,67.22 80.4,68.13 69.85,78.69 69.85,80.85 69.39,81.3 67.1,81.3 66.8,81.61 66.8,81.99 66.17,82.62 65.27,82.62 v1(65.06,82.41)
  BOTTOM w0.076: v2(81.8,60.44) 81.65,60.34 81.64,60.34 UU1.CC38
  BOTTOM w0.165: UD1.U9 v1(65.06,82.41)
M_A_DQ_1[5]: length 33.3
  ART06 w0.14: v2(80.89,61.07) 80.39,61.57 80.39,62.41 79.86,62.94 78.2,62.94 77.52,63.62 77.52,64.18 76.22,65.48 75.36,65.48 71.12,69.72 71.12,70.3 68.32,73.1 67.69,73.1 61.47,79.32 61.47,81.99 61.64,82.17 62.28,82.17 v1(62.69,81.76)
  BOTTOM w0.076: UU1.CE39 v2(80.89,61.07)
  BOTTOM w0.165: UD1.V11 v1(62.69,81.76)
M_A_DQ_1[6]: length 32.4
  ART06 w0.14: v1(62.69,80.46) 62.23,80 62.23,79.02 64.65,76.6 65.04,76.6 65.4,76.95 65.61,76.95 65.83,76.74 65.83,76.52 65.54,76.23 65.54,76.01 65.75,75.8 65.97,75.8 66.26,76.09 66.47,76.09 66.69,75.88 66.69,75.66 66.4,75.37 66.4,75.15 66.61,74.94 66.83,74.94 67.12,75.23 67.34,75.23 67.55,75.01 67.55,74.8 67.26,74.51 67.26,74.29 67.48,74.07 67.69,74.07 67.98,74.37 68.2,74.37 68.58,73.99 68.58,73.35 71.5,70.43 71.5,69.82 75.46,65.86 76.35,65.86 78.46,63.75 79.47,63.75 v2(80.84,62.37)
  BOTTOM w0.076: v2(80.84,62.37) 80.82,62.31 UU1.CE42
  BOTTOM w0.165: UD1.Y11 v1(62.69,80.46)
M_A_DQ_1[7]: length 27.8
  ART06 w0.14: v2(80.86,63) 80.63,63 80.06,63.57 80.06,64.31 79.73,64.64 78.05,64.64 75.99,66.7 75.11,66.7 71.88,69.92 71.88,70.69 69.34,73.23 69.34,73.86 65.66,77.54 64.16,77.54 62.69,79.01 v1(62.69,79.81)
  BOTTOM w0.076: UU1.CE43 80.84,62.95 v2(80.86,63)
  BOTTOM w0.165: UD1.AA11 v1(62.69,79.81)
M_A_DQ_2[0]: length 43.2
  BOTTOM w0.076: UU1.BT48 84.8,65.32 84.75,65.68 84.75,66.89 84.88,67.03 84.88,67.65 84.61,67.93
  BOTTOM w0.165: 84.61,67.93 84.61,70.27 78.95,75.93 78.09,75.93 74.04,79.98 74.04,83.68 74.2,83.84 75.78,83.84 75.94,84.01 75.94,84.34 75.78,84.5 74.46,84.5 74.29,84.67 74.29,84.99 74.46,85.15 75.78,85.15 75.94,85.32 75.94,85.79 75.78,85.96 74.59,85.96 74.42,86.12 74.42,86.45 74.59,86.62 75.78,86.62 75.94,86.78 75.94,87.16 75.78,87.32 72.43,87.32 72.26,87.49 72.26,88.97 72.55,89.27 72.55,89.65 71.98,90.22 70.61,90.22 UD1.F2
M_A_DQ_2[1]: length 43.3
  BOTTOM w0.076: UU1.BT47 84.98,64.74 85.21,64.97 85.21,65.99 85.1,66.11 85.1,66.67 85.23,66.79 85.23,67.9 85.14,67.99
  BOTTOM w0.165: 85.14,67.99 85.14,70.69 79.2,76.63 78.33,76.63 76.05,78.91 76.05,79.15 76.71,79.8 76.71,80.63 76.54,80.8 74.97,80.8 74.8,80.96 74.8,81.3 74.97,81.46 75.86,81.46 76.02,81.63 76.02,82.07 75.86,82.24 74.97,82.24 74.8,82.4 74.8,82.73 74.97,82.9 76.54,82.9 76.71,83.06 76.71,87.96 76.45,88.21 75.09,88.21 74.93,88.38 74.93,89.23 74.67,89.48 73.6,89.48 73.43,89.65 73.43,90.98 72.52,91.89 71.63,91.89 71.36,92.16 70.6,92.16 UD1.C2
M_A_DQ_2[2]: length 43.8
  BOTTOM w0.076: UU1.BT49 84.94,65.83 84.94,66.75 85.06,66.88 85.06,67.77 84.88,67.95
  BOTTOM w0.165: UD1.E2 70.6,90.86 71.45,90.86 72.07,91.47 72.3,91.47 73.02,90.75 73.02,89.3 73.19,89.13 74.38,89.13 74.55,88.97 74.55,88.64 74.38,88.47 72.81,88.47 72.64,88.31 72.64,88 72.81,87.83 76.16,87.83 76.33,87.67 76.33,83.53 76.16,83.37 74.59,83.37 74.42,83.2 74.42,80.16 74.86,79.72 75.1,79.72 75.78,80.4 76.01,80.4 76.25,80.16 76.25,79.93 75.55,79.24 75.55,78.95 78.22,76.29 79.06,76.29 84.88,70.47 84.88,67.95
M_A_DQ_2[3]: length 41.6
  BOTTOM w0.076: UU1.BN49 86.24,65.92 86.32,66 86.32,66.84 86.41,66.93 86.41,67.39
  BOTTOM w0.165: 86.41,67.39 86.41,71.59 78.38,79.62 78.38,88.82 72.92,94.28 69.71,94.28 69.32,93.9 68.99,93.9 68.61,94.28 68.17,94.28 67.87,93.98 67.87,93.7 68.25,93.32 68.25,92.67 68.44,92.48 UD1.B4
M_A_DQ_2[4]: length 42.7
  BOTTOM w0.076: UU1.BT45 84.68,64.14 84.68,64.98 84.58,65.67 84.58,67.03 84.71,67.16 84.71,67.54 84.33,67.92
  BOTTOM w0.165: 84.33,67.92 84.33,70.08 78.86,75.54 78,75.54 73.66,79.88 73.66,83.73 73.49,83.89 72.17,83.89 72.01,84.06 72.01,84.34 72.17,84.51 73.75,84.51 73.91,84.67 73.91,85 73.75,85.17 72.17,85.17 72.01,85.33 72.01,85.63 72.17,85.8 73.87,85.8 74.04,85.96 74.04,86.65 73.87,86.81 72.05,86.81 71.88,86.98 71.88,89.1 71.42,89.56 69,89.56 UD1.F4
M_A_DQ_2[5]: length 48
  BOTTOM w0.076: UU1.BN47 86.54,65.06 86.54,65.34 86.65,65.62 86.65,66.66 86.97,66.98 86.97,67.39
  BOTTOM w0.165: 86.97,67.39 86.97,71.98 79.06,79.89 79.06,89.28 73.35,94.99 67.89,94.99 66.67,93.77 66.67,92.35 67.12,91.2 67.46,90.86 68.1,90.86 UD1.E4
M_A_DQ_2[6]: length 42
  BOTTOM w0.076: UU1.BN45 85.49,63.84 85.33,64 85.33,64.42 85.38,64.47 85.38,66.06 85.27,66.17 85.27,66.6 85.39,66.72 85.39,68.4
  BOTTOM w0.165: 85.39,68.4 85.39,70.91 79.11,77.19 78.7,77.19 78.61,77.1 78.37,77.1 78.14,77.33 78.14,77.56 78.24,77.66 78.24,77.89 78,78.13 77.77,78.13 77.67,78.03 77.44,78.03 77.21,78.26 77.21,78.5 77.3,78.59 77.3,78.83 77.03,79.1 77.03,81.36 76.86,81.52 76.57,81.52 76.4,81.69 76.4,82.02 76.57,82.18 76.86,82.18 77.03,82.35 77.03,82.88 77.16,83.02 77.16,83.59 77.03,83.73 77.03,84.2 77.16,84.34 77.16,84.91 77.03,85.05 77.03,85.52 77.16,85.66 77.16,86.23 77.03,86.37 77.03,86.84 77.16,86.98 77.16,87.55 77.03,87.69 77.03,88.14 76.3,88.87 76.07,88.87 75.78,88.58 75.55,88.58 75.32,88.81 75.32,89.05 75.6,89.33 75.6,89.57 75.41,89.76 75.11,89.76 74.69,90.18 74.45,90.18 74.27,89.99 74.04,89.99 73.8,90.23 73.8,90.46 74.01,90.67 74.01,90.9 72.11,92.81 70.6,92.81 UD1.B2
M_A_DQ_2[7]: length 44.8
  BOTTOM w0.076: UU1.BN48 86.24,65.19 86.49,65.71 86.49,66.75 86.69,66.95 86.69,67.39
  BOTTOM w0.165: 86.69,67.39 86.69,71.79 78.72,79.76 78.72,89.07 73.12,94.66 68.07,94.66 67.05,93.64 67.05,92.48 67.38,92.16 68.35,92.16 UD1.C4
M_A_DQ_3[0]: length 56.9
  ART06 w0.14: v2(84.55,62.34) 84.55,62.42 85.19,63.07 85.19,65.07 84.83,65.43 84.83,67.51 83.69,68.65 83.69,70.43 77.12,77 76.99,77 76.83,77.15 76.83,77.46 76.99,77.61 77.24,77.61 77.39,77.76 77.39,78.07 77.24,78.22 76.78,78.22 76.63,78.37 76.63,78.68 76.78,78.83 77.24,78.83 77.39,78.98 77.39,79.29 77.24,79.44 76.78,79.44 76.63,79.59 76.63,79.9 76.78,80.05 77.24,80.05 77.39,80.2 77.39,80.51 77.24,80.66 76.78,80.66 76.63,80.81 76.63,81.12 76.78,81.27 77.24,81.27 77.39,81.42 77.39,81.73 77.24,81.88 76.78,81.88 76.63,82.03 76.63,82.34 76.78,82.49 77.24,82.49 77.39,82.64 77.39,89.79 72.01,95.17 63.9,95.17 62.23,93.49 62.23,92.59 v1(62.66,92.16)
  BOTTOM w0.076: UU1.BV42 84.43,62.28 v2(84.55,62.34)
  BOTTOM w0.165: UD1.C11 v1(62.66,92.16)
M_A_DQ_3[1]: length 56.4
  ART06 w0.14: v1(62.66,90.86) 62.51,91.01 61.8,91.01 61.47,91.33 61.47,93.24 63.73,95.5 72.16,95.5 77.75,89.91 77.75,77.01 84.07,70.69 84.07,68.7 85.22,67.56 85.22,65.91 85.57,65.55 85.57,63.01 85.06,62.51 85.06,61.59 v2(84.55,61.07)
  BOTTOM w0.076: v2(84.55,61.07) 84.42,61 UU1.BV39
  BOTTOM w0.165: UD1.E11 v1(62.66,90.86)
M_A_DQ_3[2]: length 55.3
  ART06 w0.14: v1(62.66,92.81) 62.66,93.47 64.03,94.84 71.83,94.84 76.33,90.35 76.33,89.84 76.48,89.69 76.88,89.69 77.04,89.54 77.04,89.23 76.88,89.08 76.48,89.08 76.33,88.93 76.33,88.62 76.48,88.47 76.88,88.47 77.04,88.32 77.04,88.02 76.88,87.86 76.48,87.86 76.33,87.71 76.33,87.41 76.48,87.25 76.88,87.25 77.04,87.1 77.04,86.8 76.88,86.64 76.48,86.64 76.33,86.49 76.33,86.19 76.48,86.03 76.88,86.03 77.04,85.88 77.04,85.58 76.88,85.42 76.48,85.42 76.33,85.27 76.33,84.97 76.48,84.81 76.88,84.81 77.04,84.66 77.04,84.36 76.88,84.21 76.48,84.21 76.33,84.05 76.33,83.75 76.48,83.6 76.88,83.6 77.04,83.44 77.04,83.14 76.88,82.99 76.48,82.99 76.33,82.83 76.33,77.16 83.31,70.18 83.31,68.55 83.84,68.02 83.84,67.28 84.53,66.6 84.53,65.35 84.91,64.97 84.91,63.34 v2(84.55,62.98)
  BOTTOM w0.076: UU1.BV43 v2(84.55,62.98)
  BOTTOM w0.165: UD1.B11 v1(62.66,92.81)
M_A_DQ_3[3]: length 56
  ART06 w0.076: 82.73,63.98 82.73,63.6 82.75,63.57 82.75,62.84 83.08,62.51 83.08,61.14 83.31,60.91 83.31,60.78 83.63,60.46 v2(83.63,60.44)
  ART06 w0.14: v1(65.06,90.21) 65.28,89.99 66.04,89.99 66.29,89.74 66.29,88.11 66.44,87.96 66.9,87.96 67.05,88.11 67.05,89.2 67.21,89.35 68.62,89.35 68.77,89.2 68.77,87.96 68.92,87.81 69.23,87.81 69.38,87.96 69.38,89.2 69.53,89.35 71.63,89.35 71.98,89 71.98,88.62 73.07,87.53 73.89,87.53 74.04,87.37 74.04,84.86 73.81,84.63 72.87,84.63 72.26,84.02 72.26,83.77 71.63,83.13 71.32,83.13 71.16,82.98 71.16,81.86 71.01,81.71 70.71,81.71 70.55,81.86 70.55,82.98 70.4,83.13 69.49,83.13 69.29,82.93 69.29,82.14 70.23,81.2 70.23,79.45 80.9,68.78 80.9,67.08 81.58,66.39 81.58,65.94 82.73,64.79 82.73,63.98
  BOTTOM w0.076: UU1.BW38 v2(83.63,60.44)
  BOTTOM w0.165: UD1.F9 v1(65.06,90.21)
M_A_DQ_3[4]: length 60.5
  ART06 w0.14: v2(84.55,60.44) 85.09,59.89 85.57,59.89 85.93,60.25 85.93,63.19 86.05,63.32 86.05,67.21 84.45,68.81 84.45,70.94 78.08,77.32 78.08,90.09 72.34,95.83 63.55,95.83 61.11,93.39 61.11,91.21 61.69,90.62 62.24,90.62 v1(62.66,90.21)
  BOTTOM w0.076: v2(84.55,60.44) 84.46,60.38 UU1.BV38
  BOTTOM w0.165: UD1.F11 v1(62.66,90.21)
M_A_DQ_3[5]: length 57
  ART06 w0.076: v2(83.63,61.07) 83.63,61.09 83.28,61.44 83.28,62.56 82.98,62.86 82.98,63.95
  ART06 w0.14: 82.98,63.95 82.98,64.97 81.94,66.01 81.94,67.23 81.28,67.89 81.28,69.03 70.61,79.7 70.61,80.52 70.76,80.67 72.49,80.67 72.64,80.83 72.64,83.89 73.02,84.27 74.17,84.27 74.37,84.48 74.37,87.81 74.22,87.96 73.3,87.96 73.15,88.11 73.15,88.41 73.3,88.57 74.22,88.57 74.37,88.72 74.37,89.08 73.79,89.66 73.57,89.66 72.92,89.01 72.71,89.01 72.49,89.22 72.49,89.44 73.14,90.09 73.14,90.3 72.31,91.13 71.88,91.13 71.68,90.93 71.68,89.89 71.52,89.74 71.27,89.74 71.12,89.89 71.12,90.9 70.96,91.06 70.66,91.06 70.51,90.9 70.51,89.89 70.35,89.74 69.56,89.74 69.4,89.89 69.4,90.29 69.25,90.45 68.95,90.45 68.79,90.29 68.79,89.89 68.64,89.74 66.8,89.74 66.17,90.37 65.53,90.37 65.06,90.84 v1(65.06,90.86)
  BOTTOM w0.076: UU1.BW39 v2(83.63,61.07)
  BOTTOM w0.165: UD1.E9 v1(65.06,90.86)
M_A_DQ_3[6]: length 56.6
  ART06 w0.076: 83.23,63.95 83.23,62.86 83.63,62.47 v2(83.63,62.34)
  ART06 w0.14: 83.23,63.95 83.23,65.15 82.32,66.06 82.32,67.31 81.66,67.97 81.66,69.29 72.47,78.48 72.47,78.69 72.99,79.21 72.99,79.43 72.78,79.64 72.56,79.64 72.04,79.12 71.82,79.12 71.09,79.86 71.09,80.08 71.25,80.23 72.87,80.23 73.02,80.39 73.02,82.55 73.18,82.7 74.57,82.7 74.72,82.85 74.72,83.16 74.57,83.31 73.18,83.31 73.02,83.46 73.02,83.74 73.18,83.89 74.51,83.89 74.75,84.14 74.75,89.25 71.98,92.02 70.35,92.02 70.12,91.79 70.12,90.88 69.97,90.73 69.66,90.73 69.51,90.88 69.51,91.84 69.33,92.02 67.16,92.02 67,91.87 67,90.78 66.85,90.62 66.55,90.62 66.39,90.78 66.39,91.87 66.24,92.02 65.2,92.02 v1(65.06,92.16)
  BOTTOM w0.076: v2(83.63,62.34) UU1.BW42
  BOTTOM w0.165: UD1.C9 v1(65.06,92.16)
M_A_DQ_3[7]: length 56.7
  ART06 w0.14: v1(65.06,92.81) 65.51,92.35 66.17,92.35 66.32,92.5 66.32,93.14 66.47,93.29 66.78,93.29 66.93,93.14 66.93,92.5 67.08,92.35 67.78,92.35 67.94,92.5 67.94,93.14 68.09,93.29 68.39,93.29 68.55,93.14 68.55,92.5 68.7,92.35 69.34,92.35 69.49,92.5 69.49,93.14 69.64,93.29 69.95,93.29 70.1,93.14 70.1,92.5 70.25,92.35 70.56,92.35 70.71,92.5 70.71,93.14 70.86,93.29 71.17,93.29 71.32,93.14 71.32,92.5 71.47,92.35 72.08,92.35 75.11,89.33 75.11,82.54 74.86,82.29 73.56,82.29 73.4,82.14 73.4,81.9 73.56,81.75 74.95,81.75 75.11,81.59 75.11,81.29 74.95,81.14 73.56,81.14 73.4,80.98 73.4,80.68 73.56,80.53 74.95,80.53 75.11,80.38 75.11,80.07 74.95,79.92 73.56,79.92 73.4,79.77 73.4,78.18 82.04,69.54 82.04,68.17 82.68,67.54 82.68,66.19 83.49,65.38 83.49,63.52 83.63,63.38 v2(83.63,62.98)
  BOTTOM w0.076: v2(83.63,62.98) 83.59,62.99 UU1.BW43
  BOTTOM w0.165: UD1.B9 v1(65.06,92.81)
M_A_DQ_4[0]: length 20.8
  BOTTOM w0.076: 92.07,67 92.07,66.04 92.24,65.87 92.24,65.64 92.49,65.4 UU1.AY48
  BOTTOM w0.165: 92.07,67 90.83,68.25 90.83,71.37 84.71,77.49 84.71,80.94 84.87,81.11 86,81.11 UD2.Y4
M_A_DQ_4[1]: length 23
  BOTTOM w0.076: UU1.AY47 92.25,64.72 92.25,65.4 92.08,65.57 92.08,65.8 91.82,66.06 91.82,66.8
  BOTTOM w0.165: UD2.V4 86,82.41 85.13,82.41 84.32,81.6 84.32,77.4 90.5,71.22 90.5,68.12 91.82,66.8
M_A_DQ_4[2]: length 19.9
  BOTTOM w0.076: 92.35,67.13 92.35,66.06 92.49,65.93 UU1.AY49
  BOTTOM w0.165: UD2.AA4 85.93,79.73 85.93,79.27 85.72,79.07 85.25,79.07 85.09,78.9 85.09,78.39 85.25,78.23 86.32,78.23 86.49,78.06 86.49,77.73 86.32,77.57 85.91,77.57 85.75,77.4 85.75,77.07 85.91,76.91 86.32,76.91 86.49,76.74 86.49,76.2 91.16,71.52 91.16,68.32 92.35,67.13
M_A_DQ_4[3]: length 25.2
  BOTTOM w0.076: UU1.AU45 94.07,64.46 94.07,64.95 94.16,65.86 94.16,66.95 93.98,67.13 93.98,67.97 93.5,68.45 93.5,68.63
  BOTTOM w0.165: UD2.U4 86.65,83.06 89.2,83.06 89.53,83.39 89.91,83.39 90.55,82.75 90.55,75.8 93.5,72.85 93.5,68.63
M_A_DQ_4[4]: length 22.2
  BOTTOM w0.076: 92.2,68.57 92.2,68.53 93.09,67.64 93.09,67 93.47,66.62 93.47,66.24 93.35,66.12 93.35,64.42 93.43,64.29 93.43,64.04 93.23,63.84 UU1.AY45
  BOTTOM w0.165: UD2.AA2 88.33,79.73 88.33,79.11 88.16,78.94 87.93,78.94 87.76,78.78 87.76,78.46 87.93,78.29 88.86,78.29 89.03,78.13 89.03,77.8 88.86,77.63 87.92,77.63 87.76,77.47 87.76,76.63 92.2,72.19 92.2,68.57
M_A_DQ_4[5]: length 20.6
  BOTTOM w0.076: UU1.AU47 93.6,64.66 93.52,64.85 93.52,66.05 93.63,66.17 93.63,66.71 93.27,67.08 93.27,67.77 92.52,68.51 92.52,68.58
  BOTTOM w0.165: 92.52,68.58 92.52,72.33 89.41,75.44 89.41,76.21 89.24,76.38 88.68,76.38 88.52,76.54 88.52,76.87 88.68,77.04 89.24,77.04 89.41,77.2 89.41,78.56 89.15,78.81 89.15,80.21 88.91,80.46 88.25,80.46 UD2.Y2
M_A_DQ_4[6]: length 21.6
  BOTTOM w0.076: 93.17,68.63 93.17,68.5 93.77,67.89 93.77,67.08 93.99,66.86 93.99,65.87 93.94,65.33 UU1.AU48
  BOTTOM w0.165: 93.17,68.63 93.17,72.7 90.17,75.7 90.17,79.02 89.96,79.22 89.96,79.73 90.17,79.93 90.17,80.34 89.96,80.54 89.96,81.05 90.17,81.25 90.17,82.24 90,82.41 88.25,82.41 UD2.U2
M_A_DQ_4[7]: length 19.2
  BOTTOM w0.076: 92.85,68.58 92.85,68.49 93.52,67.82 93.52,67.08 93.81,66.79 93.81,66 93.75,65.94 UU1.AU49
  BOTTOM w0.165: 92.85,68.58 92.85,72.48 89.79,75.54 89.79,78.78 89.57,78.99 89.57,81.26 89.08,81.76 88.25,81.76 UD2.V2
M_A_DQ_5[0]: length 30.3
  ART06 w0.089: 92.61,63.9 92.61,63.77 93.2,63.18 93.2,62.9 92.81,62.51 v2(92.81,62.36)
  ART06 w0.14: 92.61,63.9 92.61,64.36 91.36,65.61 90.6,65.61 90.32,65.89 90.32,66.9 89.99,67.23 89.99,67.94 90.45,68.4 90.45,69.47 90.27,69.64 89.86,69.64 88.9,70.61 88.9,72.74 89.05,72.89 90.14,72.89 90.3,73.04 90.3,73.35 90.14,73.5 89.05,73.5 88.9,73.65 88.9,74.24 86.39,76.75 86.18,76.75 85.95,76.52 85.73,76.52 85.52,76.74 85.52,76.95 86,77.43 86,77.65 85.78,77.87 85.57,77.87 85.08,77.38 84.87,77.38 84.65,77.6 84.65,77.81 85.2,78.36 85.2,78.58 83.82,79.96 83.21,79.96 v1(82.71,80.46)
  BOTTOM w0.076: UU1.AY42 v2(92.81,62.36)
  BOTTOM w0.165: UD2.Y9 v1(82.71,80.46)
M_A_DQ_5[1]: length 29.8
  ART06 w0.075: v2(92.78,60.44) 93.34,60.99 93.34,62.52 93.57,62.75 93.57,63.01
  ART06 w0.089: 93.12,63.98 93.12,63.78 93.57,63.33 93.57,63.01
  ART06 w0.14: v1(82.71,82.41) 82.93,82.62 83.69,82.62 85.27,81.05 85.93,81.05 86.32,80.66 86.32,79.27 86.99,78.59 86.99,78.18 87.64,77.54 87.64,77.16 87.88,76.91 88.26,76.91 88.5,76.67 88.5,76.29 88.74,76.05 89.12,76.05 89.36,75.81 89.36,75.43 89.6,75.19 89.98,75.19 91.18,73.99 91.18,67.64 91.67,67.16 91.67,66.04 93.12,64.59 93.12,63.98
  BOTTOM w0.076: UU1.AY38 v2(92.78,60.44)
  BOTTOM w0.165: UD2.U9 v1(82.71,82.41)
M_A_DQ_5[2]: length 27.2
  ART06 w0.14: v1(82.71,79.81) 82.94,79.58 83.69,79.58 84.07,79.19 84.07,78.88 83.92,78.72 83.59,78.72 83.44,78.57 83.44,78.27 83.59,78.12 83.92,78.12 84.07,77.96 84.07,77.54 85.8,75.81 86.02,75.81 86.25,76.04 86.46,76.04 86.68,75.83 86.68,75.61 86.45,75.38 86.45,75.17 86.66,74.95 86.88,74.95 87.11,75.18 87.32,75.18 87.54,74.97 87.54,74.75 87.34,74.55 87.34,74.33 87.55,74.11 88.24,74.11 88.39,73.96 88.39,73.66 88.24,73.51 88.03,73.51 87.88,73.36 87.88,73.05 88.03,72.9 88.24,72.9 88.39,72.75 88.39,72.46 87.88,71.96 87.88,70.66 89.81,68.73 89.81,68.27 89.66,68.12 89.66,67.05 89.99,66.72 89.99,65.73 90.5,65.22 91.31,65.22 92.3,64.23 92.3,63.68 92.81,63.16 v2(92.81,63.04)
  BOTTOM w0.076: UU1.AY43 92.79,62.98 v2(92.81,63.04)
  BOTTOM w0.165: UD2.AA9 v1(82.71,79.81)
M_A_DQ_5[3]: length 29.1
  ART06 w0.14: v2(91.87,61.07) 91.44,61.5 91.44,62.41 91.11,62.74 90.45,62.74 89.76,63.42 88.54,63.42 86.61,65.35 86.61,68.12 85.34,69.39 85.34,71.57 79.12,77.8 79.12,81.35 79.37,81.61 80.19,81.61 v1(80.34,81.76)
  BOTTOM w0.076: v2(91.87,61.07) 91.69,60.97 UU1.BB39
  BOTTOM w0.165: UD2.V11 v1(80.34,81.76)
M_A_DQ_5[4]: length 30.7
  ART06 w0.075: v2(92.78,61.07) 93.17,61.46 93.17,62.58 93.38,62.8 93.38,63.05
  ART06 w0.089: 92.86,63.93 92.86,63.79 93.38,63.26 93.38,63.05
  ART06 w0.14: 92.86,63.93 92.86,64.47 91.26,66.06 91.26,66.22 90.8,66.67 90.8,71.56 90.65,71.71 89.46,71.71 89.3,71.86 89.3,72.17 89.46,72.32 90.65,72.32 90.8,72.47 90.8,73.78 90.6,73.99 89.79,73.99 86.61,77.16 86.61,77.72 84.48,79.86 84.48,81.43 83.67,82.24 83.2,82.24 v1(82.71,81.76)
  BOTTOM w0.076: UU1.AY39 v2(92.78,61.07)
  BOTTOM w0.165: UD2.V9 v1(82.71,81.76)
M_A_DQ_5[5]: length 32.5
  ART06 w0.14: v2(91.87,60.44) 91.45,60.02 87.76,60.02 86.82,60.96 86.82,63.35 86.33,63.83 86.33,67.79 84.96,69.16 84.96,71.32 78.74,77.54 78.74,81.48 79.12,81.86 79.79,81.86 v1(80.34,82.41)
  BOTTOM w0.076: UU1.BB38 91.67,60.32 v2(91.87,60.44)
  BOTTOM w0.165: UD2.U11 v1(80.34,82.41)
M_A_DQ_5[6]: length 29.1
  ART06 w0.14: v2(91.83,62.38) 91.22,62.99 90.55,62.99 89.86,63.68 89.05,63.68 87.37,65.35 87.37,67.84 85.72,69.49 85.72,71.83 82.29,75.26 82.29,75.48 82.64,75.84 82.64,76.05 82.43,76.27 82.21,76.27 81.86,75.91 81.64,75.91 81.43,76.13 81.43,76.34 81.78,76.7 81.78,76.91 81.57,77.13 81.35,77.13 80.99,76.77 80.78,76.77 80.56,76.99 80.56,77.2 80.92,77.56 80.92,77.77 80.7,77.99 80.49,77.99 80.13,77.63 79.92,77.63 79.63,77.92 79.63,79.74 v1(80.34,80.46)
  BOTTOM w0.076: v2(91.83,62.38) 91.8,62.31 UU1.BB42
  BOTTOM w0.165: UD2.Y11 v1(80.34,80.46)
M_A_DQ_5[7]: length 27
  ART06 w0.14: v2(91.86,62.98) 91.59,63.24 91.03,63.24 89.61,64.67 89.08,64.67 87.68,66.06 87.68,68.02 86.1,69.59 86.1,73.23 85.71,73.62 85.5,73.62 85.14,73.26 84.93,73.26 84.71,73.47 84.71,73.69 85.07,74.05 85.07,74.26 84.85,74.48 84.64,74.48 84.28,74.12 84.07,74.12 83.85,74.34 83.85,74.55 84.21,74.91 84.21,75.12 83.99,75.34 83.77,75.34 83.42,74.98 83.2,74.98 82.99,75.2 82.99,75.41 83.34,75.77 83.34,75.99 80.34,78.99 v1(80.34,79.81)
  BOTTOM w0.076: v2(91.86,62.98) 91.86,62.97 UU1.BB43
  BOTTOM w0.165: UD2.AA11 v1(80.34,79.81)
M_A_DQ_6[0]: length 40
  BOTTOM w0.076: UU1.AR48 94.89,65.5 94.77,65.62 94.74,65.66 94.74,67.07 94.89,67.22 94.89,67.74 94.16,68.48 94.16,68.63
  BOTTOM w0.165: UD2.F2 88.26,90.22 89.24,90.22 89.41,90.05 89.41,89.87 89.55,89.73 91.29,89.73 91.44,89.58 91.44,89.38 91.29,89.23 89.68,89.23 89.53,89.09 89.53,88.88 89.68,88.74 91.29,88.74 91.44,88.59 91.44,88.39 91.29,88.24 89.7,88.24 89.53,88.08 89.53,87.25 90.17,86.61 90.17,86.4 90.02,86.26 89.45,86.26 89.3,86.11 89.3,85.91 89.45,85.76 90.02,85.76 90.17,85.62 90.17,85.18 90.31,85.03 91.32,85.03 91.46,84.89 91.46,84.68 91.32,84.54 90.41,84.54 90.27,84.39 90.27,84.24 90.43,84.07 91.3,84.07 91.46,83.91 91.46,76.05 94.16,73.35 94.16,68.63
M_A_DQ_6[1]: length 40.1
  BOTTOM w0.076: UU1.AR47 94.99,64.74 95.22,64.97 95.22,65.99 95.07,66.15 95.07,66.85 95.22,67 95.22,68.04 94.82,68.45
  BOTTOM w0.165: UD2.C2 88.25,92.16 89.83,92.16 92.12,89.86 92.12,88.96 92.29,88.8 92.66,88.8 92.81,88.64 92.81,88.36 92.66,88.21 92.27,88.21 92.12,88.07 92.12,87.86 92.27,87.72 92.66,87.72 92.81,87.57 92.81,87.36 92.66,87.22 92.27,87.22 92.12,87.07 92.12,86.87 92.27,86.72 92.66,86.72 92.81,86.58 92.81,86.37 92.66,86.23 92.27,86.23 92.12,86.08 92.12,85.88 92.27,85.73 92.66,85.73 92.81,85.59 92.81,85.38 92.66,85.24 92.27,85.24 92.12,85.09 92.12,84.89 92.27,84.74 92.66,84.74 92.81,84.6 92.81,84.39 92.66,84.25 92.27,84.25 92.12,84.1 92.12,83.9 92.27,83.75 92.66,83.75 92.81,83.61 92.81,83.4 92.66,83.26 92.27,83.26 92.12,83.11 92.12,82.91 92.27,82.76 92.66,82.76 92.81,82.62 92.81,82.36 92.64,82.19 92.31,82.19 92.15,82.03 92.15,81.84 92.29,81.7 92.56,81.7 92.71,81.55 92.71,81.32 92.56,81.18 92.29,81.18 92.15,81.03 92.15,76.29 94.82,73.62 94.82,68.45
M_A_DQ_6[2]: length 39.4
  BOTTOM w0.076: UU1.AR49 94.9,65.87 94.9,67 95.06,67.16 95.06,67.9 94.49,68.48
  BOTTOM w0.165: 94.49,68.48 94.49,73.51 91.79,76.2 91.79,85.31 91.65,85.46 90.64,85.46 90.5,85.6 90.5,85.81 90.64,85.95 91.65,85.95 91.79,86.1 91.79,86.29 91.65,86.43 90.69,86.43 90.55,86.58 90.55,86.78 90.69,86.93 91.65,86.93 91.79,87.07 91.79,87.28 91.65,87.42 89.98,87.42 89.84,87.57 89.84,87.77 89.98,87.92 91.65,87.92 91.79,88.06 91.79,89.68 91.15,90.33 90.91,90.33 90.65,90.07 90.38,90.07 90.22,90.23 90.22,90.47 90.5,90.75 90.5,90.98 89.98,91.5 89.75,91.5 89.1,90.86 88.25,90.86 UD2.E2
M_A_DQ_6[3]: length 39.6
  BOTTOM w0.076: UU1.AM45 95.39,63.84 95.27,63.95 95.27,64.39 95.39,64.5 95.39,66.06 95.24,66.22 95.24,66.78 95.41,66.96 95.41,68.16 95.15,68.43
  BOTTOM w0.165: UD2.B2 88.25,92.81 89.69,92.81 92.12,90.37 92.58,90.37 92.82,90.14 92.82,89.68 93.14,89.35 93.14,80.94 93,80.79 92.62,80.79 92.48,80.65 92.48,80.44 92.62,80.3 93,80.3 93.14,80.15 93.14,79.95 93,79.8 92.62,79.8 92.48,79.66 92.48,79.45 92.62,79.31 93,79.31 93.14,79.16 93.14,78.96 93,78.81 92.62,78.81 92.48,78.67 92.48,78.46 92.62,78.32 93,78.32 93.14,78.17 93.14,77.97 93,77.82 92.62,77.82 92.48,77.67 92.48,77.47 92.62,77.32 93,77.32 93.14,77.18 93.14,76.97 93,76.83 92.62,76.83 92.48,76.68 92.48,76.48 92.62,76.33 93,76.33 93.14,76.19 93.14,75.74 95.15,73.74 95.15,68.43
M_A_DQ_6[4]: length 42.5
  BOTTOM w0.076: UU1.AR45 94.68,64.14 94.68,65.43 94.57,65.59 94.57,67.14 94.71,67.28 94.71,67.66 93.83,68.55
  BOTTOM w0.165: UD2.F4 86.76,89.44 86.76,86.7 86.6,86.54 84.99,86.54 83.99,85.54 83.99,82.66 84.16,82.5 84.44,82.5 84.61,82.66 84.61,85.32 84.94,85.65 86.79,85.65 87.09,85.95 88.82,85.95 89.74,85.04 89.74,84.25 90.35,83.64 90.93,83.64 91.06,83.51 91.06,75.97 93.83,73.2 93.83,68.55
M_A_DQ_6[5]: length 44.8
  BOTTOM w0.076: 96.69,67.97 96.69,67.68 96.66,67.65 96.66,65.86 96.6,65.22 UU1.AM47
  BOTTOM w0.165: UD2.E4 85.65,90.86 85.11,90.86 84.73,91.24 84.33,92.43 84.33,93.77 85.65,95.1 90.9,95.1 95.1,90.9 95.1,76.48 96.82,74.75 96.82,71.32 96.69,71.18 96.69,67.97
M_A_DQ_6[6]: length 41.7
  BOTTOM w0.076: 96.42,69.14 96.42,66.98 96.5,66.91 96.5,65.87 96.44,65.33 UU1.AM48
  BOTTOM w0.165: 96.42,69.14 96.42,71.33 96.49,71.4 96.49,74.6 94.73,76.36 94.73,90.71 90.68,94.76 85.82,94.76 84.7,93.64 84.7,92.48 85.03,92.16 86,92.16 UD2.C4
M_A_DQ_6[7]: length 37.9
  BOTTOM w0.076: 96.14,68.88 96.14,68.83 96.26,68.71 96.26,66.88 96.33,66.8 96.33,66.1 96.25,66.02 UU1.AM49
  BOTTOM w0.165: 96.14,68.88 96.14,71.45 96.16,71.47 96.16,74.44 94.36,76.25 94.36,90.5 90.47,94.38 86.07,94.38 85.6,93.91 85.6,93.55 85.93,93.22 85.93,92.88 UD2.B4
M_A_DQ_7[0]: length 54.2
  ART06 w0.089: v2(94.61,62.47) 94.23,62.85 94.23,63.6 93.95,63.88 93.95,64.28
  ART06 w0.14: v1(82.71,92.16) 82.85,92.02 83.82,92.02 83.97,91.87 83.97,90.95 84.22,90.7 86.3,90.7 86.45,90.55 86.45,90.27 86.61,90.12 86.91,90.12 87.06,90.27 87.06,90.55 87.62,91.11 88.24,91.11 88.52,90.83 89.2,90.83 89.48,91.11 90.78,91.11 90.93,90.95 90.93,90.7 90.78,90.55 90.32,90.55 90.17,90.39 90.17,90.09 90.32,89.94 90.78,89.94 90.96,89.76 90.96,80.52 90.8,80.37 88.52,80.37 88.36,80.21 88.36,79.91 88.52,79.76 90.78,79.76 90.93,79.6 90.93,79.3 90.78,79.15 88.64,79.15 88.49,79 88.49,78.69 88.64,78.54 90.78,78.54 90.93,78.39 90.93,78.09 90.78,77.93 89.94,77.93 89.79,77.78 89.79,77.48 89.94,77.32 90.78,77.32 90.93,77.17 90.93,76.45 92.58,74.8 92.58,67.89 92.73,67.74 92.73,66.24 93.95,65.02 93.95,64.28
  BOTTOM w0.076: UU1.AT42 94.2,62.23 94.6,62.44 v2(94.61,62.47)
  BOTTOM w0.165: UD2.C9 v1(82.71,92.16)
M_A_DQ_7[1]: length 54.2
  ART06 w0.089: 93.63,64.03 93.63,63.88 94.01,63.5 94.01,62.79 94.25,62.56 94.25,61.49 v2(94.66,61.07)
  ART06 w0.14: v1(82.71,90.86) 82.71,90.84 83.18,90.37 84,90.37 84.63,89.74 87.73,89.74 88.38,90.38 89.34,90.38 90.65,89.08 90.65,88.24 90.35,87.93 90.35,87.63 90.65,87.32 90.65,87.02 90.35,86.71 90.35,86.41 90.65,86.1 90.65,85.8 90.35,85.5 90.35,85.19 90.65,84.89 90.65,84.58 90.35,84.28 90.35,83.97 90.65,83.67 90.65,83.36 90.35,83.06 90.35,82.29 90.19,82.14 89.53,82.14 89.38,82.29 89.38,82.75 89.23,82.9 88.84,82.9 88.68,82.75 88.68,82.29 88.53,82.14 88.23,82.14 88.07,82.29 88.07,82.75 87.92,82.9 86.89,82.9 86.74,82.75 86.74,81.71 86.89,81.56 89.3,81.56 89.56,81.3 90.45,81.3 90.65,81.1 90.65,80.85 90.5,80.69 88.11,80.69 87.96,80.54 87.96,78.79 92.2,74.54 92.2,67.76 92.4,67.56 92.4,66.14 93.63,64.91 93.63,64.03
  BOTTOM w0.076: UU1.AT39 94.2,60.8 v2(94.66,61.07)
  BOTTOM w0.165: UD2.E9 v1(82.71,90.86)
M_A_DQ_7[2]: length 53
  ART06 w0.14: v1(80.31,92.81) 80.31,93.57 81.81,95.07 89.56,95.07 92.58,92.05 92.58,86.52 92.73,86.36 93.11,86.36 93.27,86.21 93.27,85.91 93.11,85.75 92.73,85.75 92.58,85.6 92.58,85.3 92.73,85.14 93.11,85.14 93.27,84.99 93.27,84.69 93.11,84.53 92.73,84.53 92.58,84.38 92.58,84.08 92.73,83.93 93.11,83.93 93.27,83.77 93.27,83.47 93.11,83.32 92.73,83.32 92.58,83.16 92.58,82.86 92.73,82.71 93.11,82.71 93.27,82.55 93.27,82.25 93.11,82.1 92.73,82.1 92.58,81.94 92.58,81.69 92.73,81.54 93.11,81.54 93.27,81.39 93.27,81.12 93.11,80.97 92.73,80.97 92.58,80.81 92.58,80.54 92.73,80.39 93.11,80.39 93.27,80.23 93.27,79.99 93.11,79.84 92.73,79.84 92.58,79.69 92.58,79.38 92.73,79.23 93.11,79.23 93.27,79.08 93.27,77.75 93.47,77.54 94.23,77.54 94.49,77.29 94.49,68.02 94.89,67.61 94.89,66.14 95.53,65.51 v2(95.53,62.98)
  BOTTOM w0.076: UU1.AR43 v2(95.53,62.98)
  BOTTOM w0.165: UD2.B11 v1(80.31,92.81)
M_A_DQ_7[3]: length 55.7
  ART06 w0.089: 93.37,64.01 93.37,63.85 93.81,63.41 93.81,62.74 94.07,62.49 94.07,60.98 v2(94.61,60.44)
  ART06 w0.14: 93.37,64.01 93.37,64.81 92.07,66.11 92.07,67.38 91.82,67.64 91.82,74.37 87.53,78.66 87.53,79.04 86.92,79.65 86.92,80.87 86.33,81.46 86.33,84.6 86.49,84.76 86.79,84.76 86.99,84.55 86.99,83.44 87.15,83.28 89.38,83.28 89.99,83.89 89.99,89.28 89.15,90.12 88.69,90.12 87.93,89.35 87.23,89.35 87.08,89.2 87.08,87.73 86.93,87.58 86.62,87.58 86.47,87.73 86.47,89.2 86.32,89.35 84.88,89.35 84.68,89.15 84.68,87.02 84.5,86.84 84.12,86.84 83.97,86.99 83.97,89.81 83.79,89.99 82.93,89.99 v1(82.71,90.21)
  BOTTOM w0.076: v2(94.61,60.44) 94.44,60.33 UU1.AT38
  BOTTOM w0.165: UD2.F9 v1(82.71,90.21)
M_A_DQ_7[4]: length 56.2
  ART06 w0.076: 96.29,63.83 96.29,63.55 96.4,63.44 96.4,62.86 96.07,62.53 96.07,60.98 v2(95.53,60.44)
  ART06 w0.14: 96.29,63.83 96.29,66.98 96.01,67.26 96.01,68.15 95.63,68.53 95.63,77.72 94.23,79.12 94.23,91.9 90.14,95.98 81.28,95.98 78.76,93.47 78.76,91.18 79.32,90.62 79.9,90.62 v1(80.31,90.21)
  BOTTOM w0.076: UU1.AR38 v2(95.53,60.44)
  BOTTOM w0.165: UD2.F11 v1(80.31,90.21)
M_A_DQ_7[5]: length 53.6
  ART06 w0.076: 96.05,63.81 96.05,63.41 96.1,63.36 96.1,62.8 95.89,62.6 95.89,61.44 v2(95.53,61.07)
  ART06 w0.14: 96.05,63.81 96.05,66.59 95.63,67 95.63,68.02 95.25,68.4 95.25,77.59 93.9,78.94 93.9,91.72 89.94,95.68 81.48,95.68 79.12,93.32 79.12,91.33 79.45,91.01 80.16,91.01 v1(80.31,90.86)
  BOTTOM w0.076: UU1.AR39 v2(95.53,61.07)
  BOTTOM w0.165: UD2.E11 v1(80.31,90.86)
M_A_DQ_7[6]: length 53.5
  ART06 w0.076: v2(95.52,62.35) 95.52,62.46 95.89,62.84 95.89,63.26 95.78,63.37 95.78,63.52
  ART06 w0.14: v1(80.31,92.16) 79.89,92.58 79.63,92.58 79.47,92.74 79.47,93.21 81.63,95.37 89.74,95.37 93.57,91.54 93.57,91.25 93.42,91.1 93.04,91.1 92.89,90.94 92.89,90.64 93.04,90.49 93.42,90.49 93.57,90.33 93.57,90.03 93.42,89.88 93.04,89.88 92.89,89.72 92.89,89.42 93.04,89.27 93.42,89.27 93.57,89.11 93.57,88.81 93.42,88.66 93.04,88.66 92.89,88.51 92.89,88.2 93.04,88.05 93.42,88.05 93.57,87.9 93.57,87.59 93.42,87.44 93.04,87.44 92.89,87.29 92.89,86.98 93.04,86.83 93.42,86.83 93.57,86.68 93.57,78.71 94.87,77.42 94.87,68.15 95.22,67.79 95.22,66.24 95.78,65.68 95.78,63.52
  BOTTOM w0.076: UU1.AR42 v2(95.52,62.35)
  BOTTOM w0.165: UD2.C11 v1(80.31,92.16)
M_A_DQ_7[7]: length 54.3
  ART06 w0.14: v2(94.61,63.08) 94.71,63.18 94.71,64.89 93.85,65.76 93.85,66.44 93.09,67.21 93.09,74.85 91.31,76.63 91.31,91.44 90.8,91.95 90.41,91.95 90.26,91.79 90.26,91.64 90.11,91.49 89.8,91.49 89.65,91.64 89.65,91.79 89.5,91.95 88.11,91.95 87.96,92.1 87.96,92.38 88.11,92.53 89.46,92.53 89.61,92.68 89.61,92.99 89.46,93.14 88.06,93.14 87.91,93.29 87.91,93.47 87.76,93.62 87.25,93.62 87.09,93.47 87.09,92.73 86.94,92.58 86.49,92.58 86.33,92.73 86.33,93.11 86.23,93.22 85.75,93.22 85.62,93.09 85.62,92.12 85.77,91.97 86.94,91.97 87.09,91.82 87.09,91.23 86.94,91.08 84.83,91.08 84.68,91.23 84.68,93.39 84.53,93.55 84.22,93.55 84.07,93.39 84.07,92.5 83.92,92.35 83.17,92.35 v1(82.71,92.81)
  BOTTOM w0.076: v2(94.61,63.08) 94.21,62.89 UU1.AT43
  BOTTOM w0.165: UD2.B9 v1(82.71,92.81)
M_A_DQS_0_DN: length 24.7
  BOTTOM w0.076: 82.52,67.66 82.52,67.64 82.48,67.59 82.48,67.43 82.75,67.16 82.75,67.04 82.83,66.96 82.85,66.96 82.93,66.88 82.93,66.73 82.85,66.65 82.83,66.65 82.75,66.58 82.75,66.19 82.88,66.06 82.88,64.9 82.98,64.79 83.09,64.79 UU1.BY47 ; 70.01,79.1 70.01,79.12 69.96,79.17 69.96,81.67 69.78,81.84 69.55,81.84 69.47,81.92 UD1.V3
  BOTTOM w0.14: 82.52,67.66 82.52,68.57 77.76,73.34 76.97,73.34 73.63,76.68 72.11,76.68 70.01,78.78 70.01,79.1
M_A_DQS_0_DP: length 24.9
  BOTTOM w0.076: 69.74,79.1 69.74,79.12 69.79,79.17 69.79,81.6 69.71,81.67 69.55,81.67 69.47,81.6 UD1.W3 ; 82.26,67.66 82.26,67.64 82.31,67.58 82.31,67.36 82.59,67.09 82.59,66.12 82.71,65.99 82.71,64.81 82.93,64.59 UU1.BY46
  BOTTOM w0.14: 69.74,79.1 69.74,78.67 72,76.41 73.52,76.41 76.86,73.07 77.65,73.07 82.26,68.46 82.26,67.66
M_A_DQS_1_DN: length 31.2
  ART06 w0.076: v2(81.8,61.71) 81.65,61.71 81.43,61.93 81.43,63.18 80.81,63.79 80.81,63.86 80.8,63.87
  ART06 w0.14: 80.8,63.87 80.66,64.01 80.66,64.57 79.74,65.49 78.21,65.49 76.21,67.5 75.32,67.5 72.65,70.16 72.65,71.07 72.13,71.59 72.13,72.43 65.99,78.57 65,78.57 64.6,78.97 64.6,81.28 64.23,81.65 63.57,81.65 v1(63.46,81.76)
  BOTTOM w0.076: UU1.CC41 v2(81.8,61.71)
  BOTTOM w0.14: UD1.V10 v1(63.46,81.76)
M_A_DQS_1_DP: length 31.1
  ART06 w0.076: 80.61,63.68 80.63,63.67 80.7,63.67 81.26,63.11 81.26,61.78 81.18,61.71 v2(80.89,61.71)
  ART06 w0.14: 80.61,63.68 80.4,63.9 80.4,64.46 79.63,65.22 78.1,65.22 76.1,67.23 75.21,67.23 72.39,70.05 72.39,70.96 71.87,71.48 71.87,72.32 65.88,78.31 64.89,78.31 64.34,78.86 64.34,79.94 64.11,80.17 64.11,80.5 64.34,80.73 64.34,81.17 64.12,81.38 63.73,81.38 v1(63.46,81.11)
  BOTTOM w0.076: UU1.CE41 v2(80.89,61.71)
  BOTTOM w0.14: UD1.W10 v1(63.46,81.11)
M_A_DQS_2_DN: length 41
  BOTTOM w0.076: 85.74,67.37 85.74,67.35 85.79,67.3 85.79,66.77 85.97,66.58 85.97,66.19 85.84,66.06 85.84,64.89 85.77,64.81 UU1.BR47 ; UD1.E3 69.47,90.8 69.96,91.29 69.96,93.24 70.01,93.29 70.01,93.31
  BOTTOM w0.14: 70.01,93.31 70.01,93.43 70.15,93.57 71.28,93.57 71.46,93.39 71.84,93.39 72.02,93.57 72.44,93.57 72.83,93.18 72.83,92.9 73.09,92.64 73.37,92.64 73.62,92.39 73.62,92.11 73.88,91.85 74.16,91.85 74.42,91.6 74.42,91.32 74.67,91.06 74.95,91.06 75.21,90.81 75.21,90.53 75.46,90.27 75.74,90.27 77.64,88.37 77.64,79.33 85.74,71.24 85.74,67.37
M_A_DQS_2_DP: length 41.1
  BOTTOM w0.076: 69.74,93.31 69.74,93.29 69.79,93.24 69.79,91.35 69.62,91.18 UD1.D3 ; 86,67.37 86,67.35 85.95,67.3 85.95,66.83 86.13,66.65 86.13,66.12 86.01,65.99 86.01,64.82 85.82,64.63 UU1.BR46
  BOTTOM w0.14: 69.74,93.31 69.74,93.54 70.04,93.84 72.55,93.84 77.91,88.48 77.91,79.44 86,71.35 86,67.37
M_A_DQS_3_DN: length 54.2
  ART06 w0.076: 84,64.58 84,64.56 83.95,64.51 83.95,63.81 84.16,63.59 84.16,61.8 84.25,61.71 v2(84.55,61.71)
  ART06 w0.14: v1(64.26,90.86) 64.17,90.94 63.53,90.94 63.13,91.34 63.13,93.33 64.25,94.45 71.51,94.45 75.88,90.07 75.88,79.35 75.58,79.05 74.41,79.05 74.28,78.92 74.28,78.37 74.41,78.24 75.58,78.24 75.88,77.94 75.88,76.86 82.81,69.93 82.81,68.43 83.37,67.87 83.37,67.19 84,66.57 84,64.58
  BOTTOM w0.076: UU1.BV41 v2(84.55,61.71)
  BOTTOM w0.14: UD1.E10 v1(64.26,90.86)
M_A_DQS_3_DP: length 54.2
  ART06 w0.076: v2(83.63,61.71) 83.92,61.71 84,61.78 84,63.52 83.78,63.74 83.78,64.51 83.73,64.56 83.73,64.58
  ART06 w0.14: v1(64.26,91.51) 63.96,91.21 63.64,91.21 63.4,91.45 63.4,92.05 63.57,92.23 63.57,92.61 63.4,92.78 63.4,93.22 64.36,94.18 64.68,94.18 64.94,93.93 65.24,93.93 65.5,94.18 65.8,94.18 66.06,93.93 66.36,93.93 66.61,94.18 66.92,94.18 67.17,93.93 67.48,93.93 67.73,94.18 69.73,94.18 69.91,94 70.29,94 70.46,94.18 71.4,94.18 72.08,93.5 72.08,93.25 72.35,92.98 72.6,92.98 72.87,92.71 72.87,92.46 73.14,92.19 73.39,92.19 75.61,89.96 75.61,79.46 75.47,79.32 74.3,79.32 74.01,79.03 74.01,78.26 74.3,77.97 75.47,77.97 75.61,77.83 75.61,76.75 82.55,69.82 82.55,68.32 83.11,67.76 83.11,67.08 83.73,66.46 83.73,64.58
  BOTTOM w0.076: UU1.BW41 v2(83.63,61.71)
  BOTTOM w0.14: UD1.D10 v1(64.26,91.51)
M_A_DQS_4_DN: length 20.9
  BOTTOM w0.076: UD2.V3 87.05,82 86.82,82 86.64,81.83 86.64,79.16 86.81,79 86.81,78.92 86.82,78.91 ; 91.55,68.83 91.55,68.81 91.6,68.76 91.6,68.31 92.57,67.35 92.57,66.15 92.72,65.99 92.72,64.75 92.86,64.61 UU1.AV46
  BOTTOM w0.14: 91.55,68.83 91.55,71.79 86.96,76.38 86.96,78.77 86.82,78.91
M_A_DQS_4_DP: length 20.9
  BOTTOM w0.076: UD2.W3 87.13,81.76 87.05,81.84 86.88,81.84 86.81,81.76 86.81,80.7 86.92,80.6 86.92,80.37 86.81,80.27 86.81,80.03 86.92,79.92 86.92,79.69 86.81,79.59 86.81,79.23 86.93,79.11 87,79.11 87.01,79.1 ; 91.82,68.83 91.77,68.77 91.77,68.38 91.91,68.24 92.05,68.24 92.2,68.1 92.2,67.95 92.34,67.81 92.48,67.81 92.63,67.67 92.63,67.52 92.73,67.41 92.73,67.1 92.84,67 92.84,66.8 92.73,66.7 92.73,66.22 92.89,66.06 92.89,64.89 92.96,64.81 UU1.AV47
  BOTTOM w0.14: 91.82,68.83 91.82,71.9 87.23,76.49 87.23,78.88 87.01,79.1
M_A_DQS_5_DN: length 27.2
  ART06 w0.076: v2(92.78,61.71) 92.53,61.71 92.41,61.83 92.41,63.17 91.86,63.71 91.46,63.71 91.31,63.86 91.31,63.94 91.29,63.95
  ART06 w0.14: v1(81.11,81.76) 81.3,81.57 81.89,81.57 82.26,81.21 82.26,78.49 86.88,73.87 86.88,69.93 87.38,69.43 88.37,69.43 89.04,68.76 89.04,66.2 91.29,63.95
  BOTTOM w0.076: v2(92.78,61.71) 92.78,61.71 UU1.AY41
  BOTTOM w0.14: UD2.V10 v1(81.11,81.76)
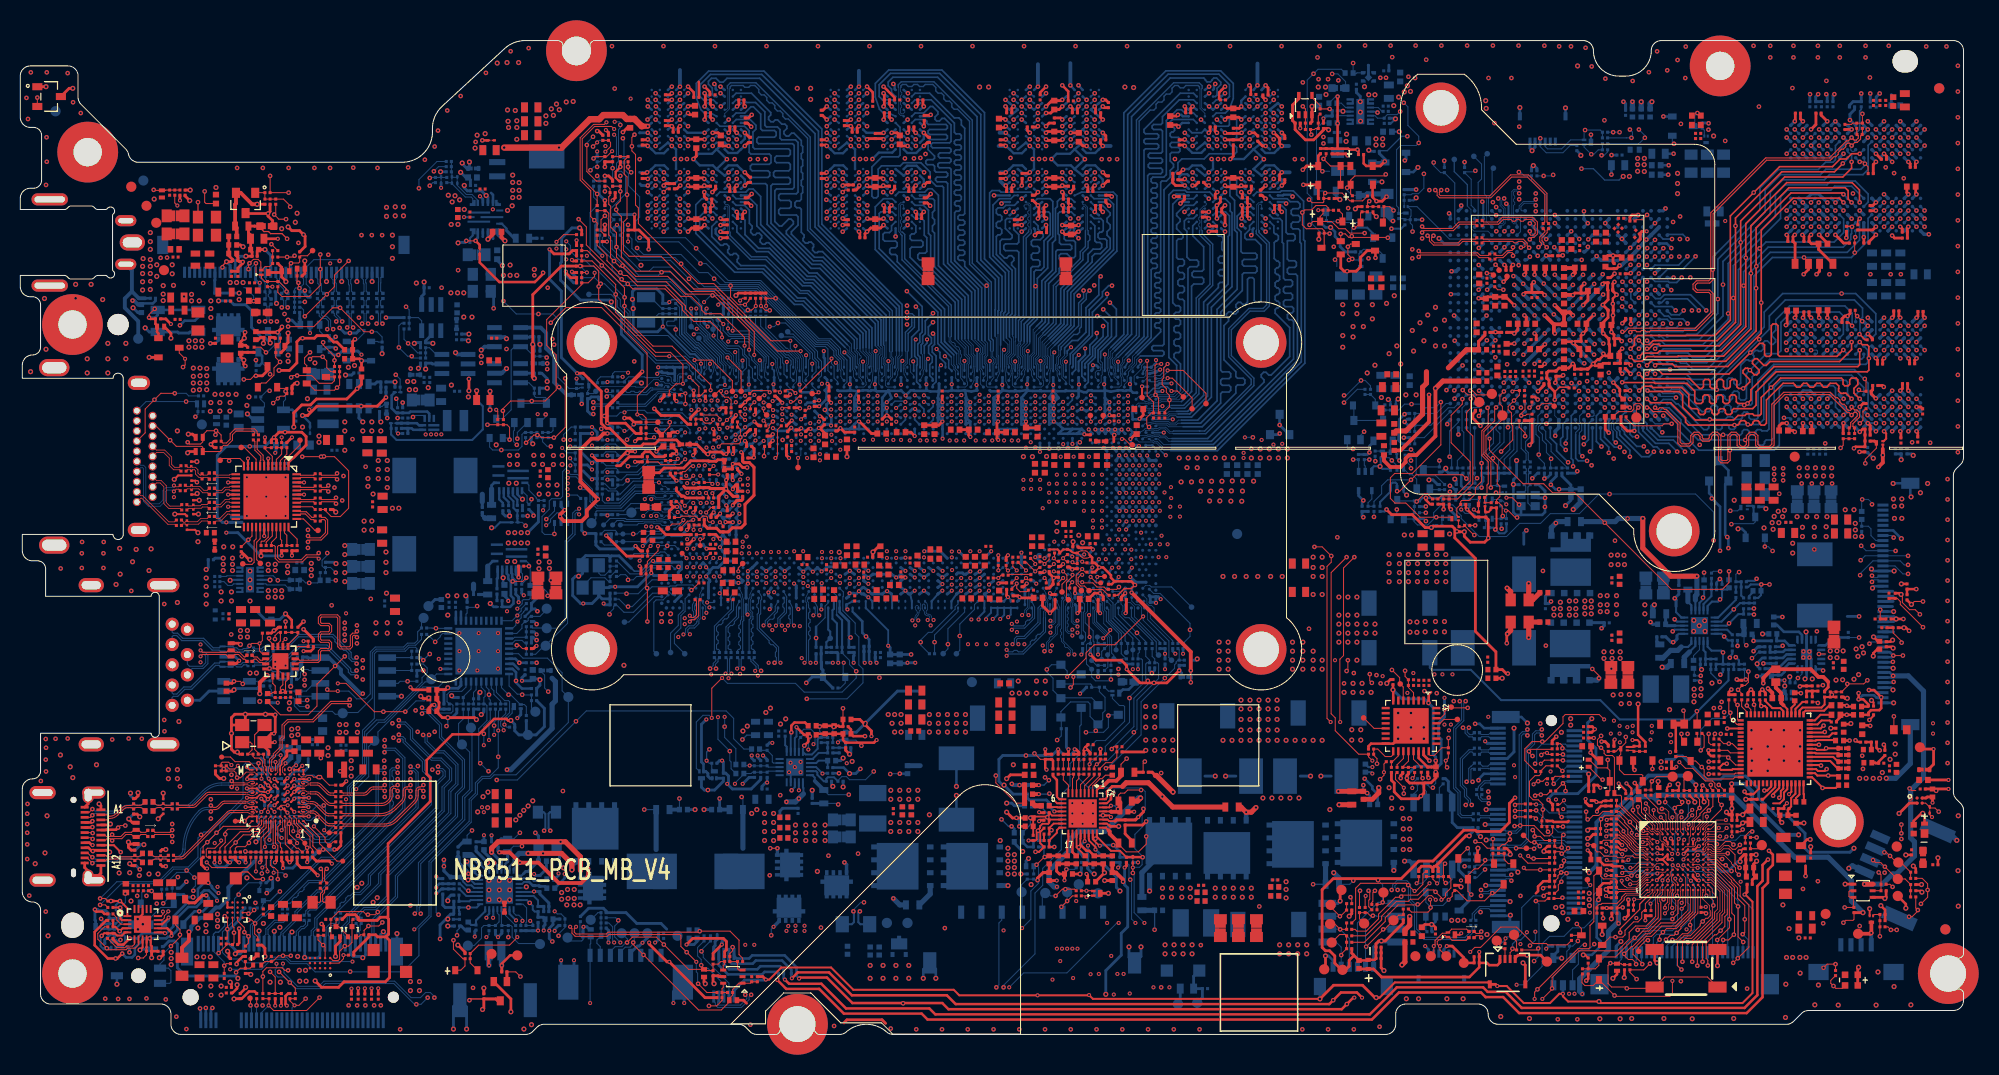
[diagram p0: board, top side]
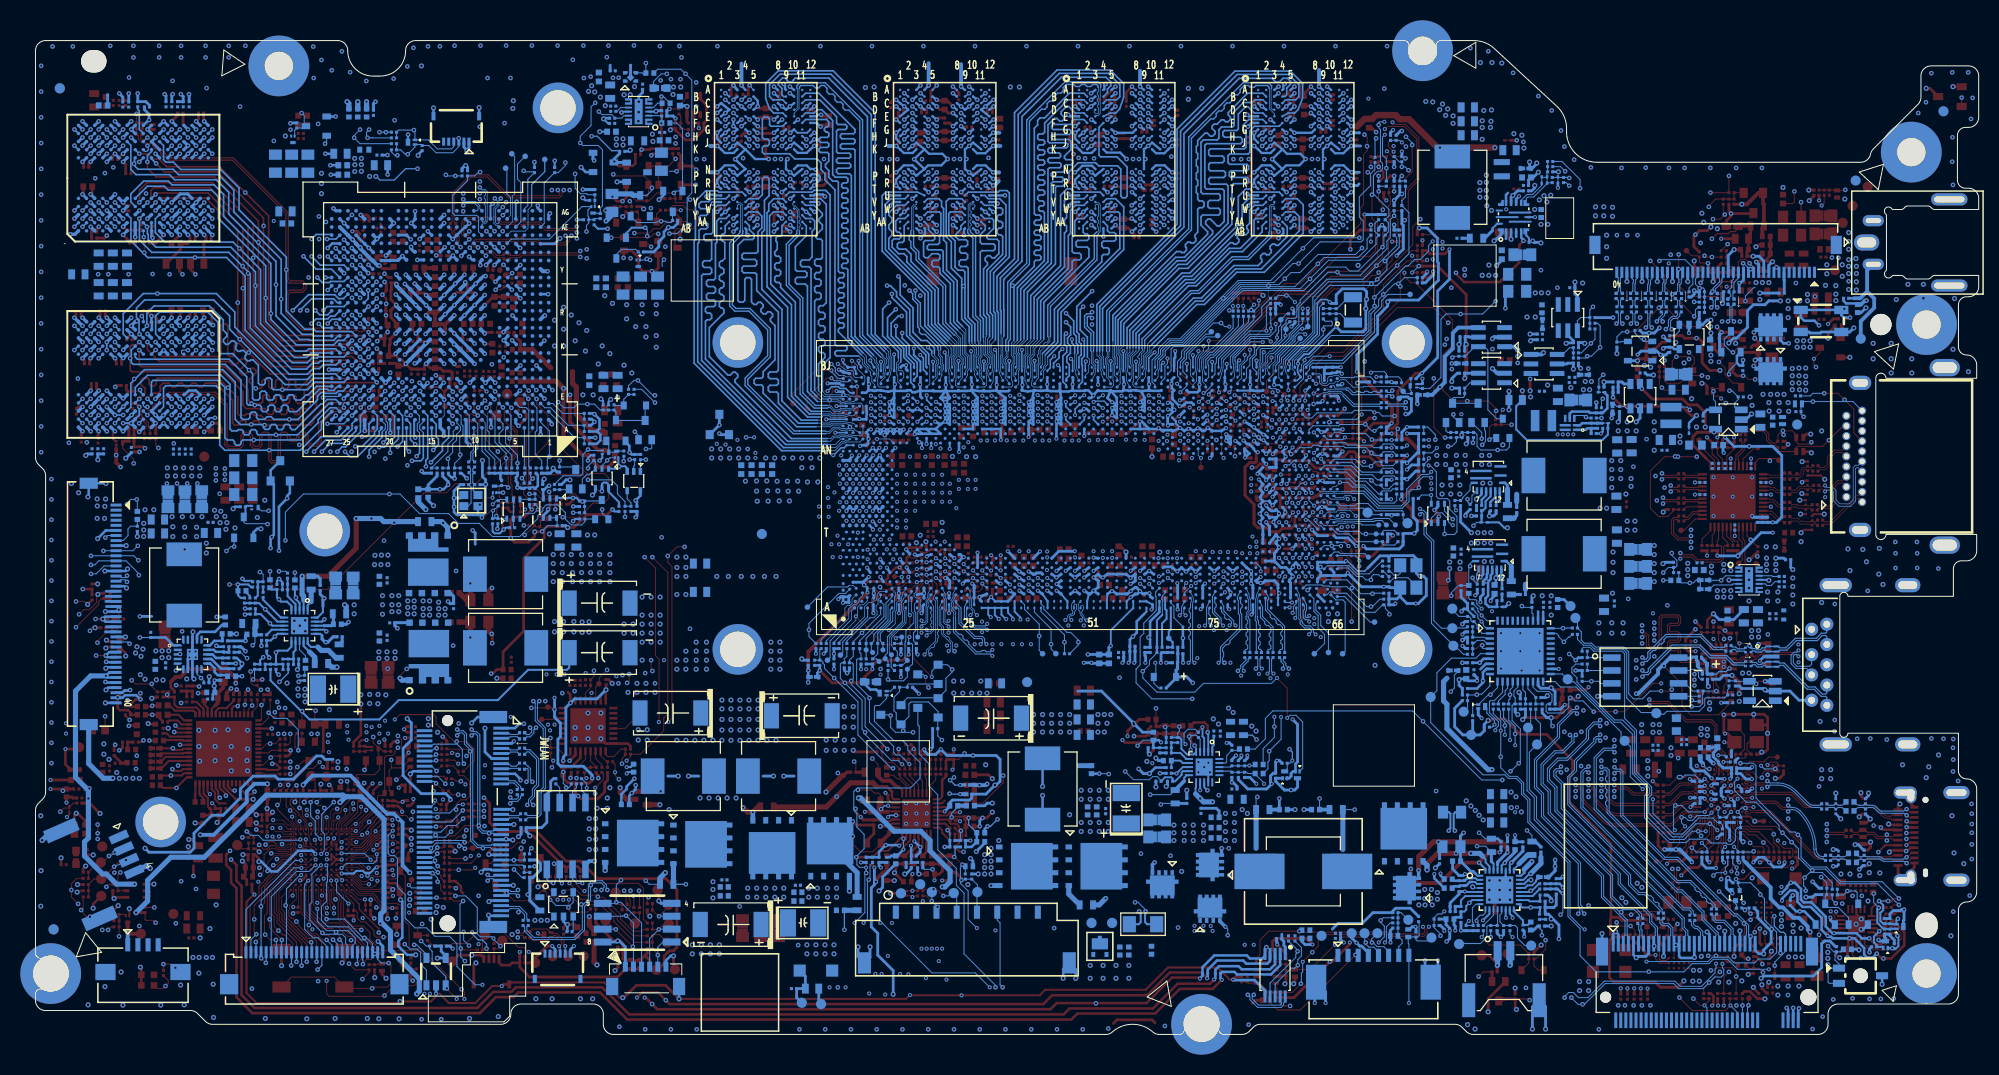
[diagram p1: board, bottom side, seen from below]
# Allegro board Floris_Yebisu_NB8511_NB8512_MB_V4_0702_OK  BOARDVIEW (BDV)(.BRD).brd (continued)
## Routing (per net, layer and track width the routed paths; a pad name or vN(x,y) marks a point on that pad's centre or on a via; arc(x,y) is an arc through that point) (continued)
M_A_DQS_5_DP: length 27.2
  ART06 w0.076: v2(91.87,61.71) 92.16,61.71 92.24,61.78 92.24,63.1 91.79,63.55 91.39,63.55 91.19,63.75 91.12,63.75 91.1,63.76
  ART06 w0.14: v1(81.11,81.11) 81.31,81.31 81.78,81.31 81.99,81.1 81.99,80.59 81.79,80.38 81.79,80.03 81.99,79.82 81.99,79.47 81.79,79.27 81.79,78.91 81.99,78.71 81.99,78.38 86.61,73.76 86.61,69.82 87.27,69.16 88.26,69.16 88.77,68.65 88.77,66.09 91.1,63.76
  BOTTOM w0.076: v2(91.87,61.71) UU1.BB41
  BOTTOM w0.14: UD2.W10 v1(81.11,81.11)
M_A_DQS_6_DN: length 39.6
  BOTTOM w0.076: 95.96,67.43 95.96,67.41 95.91,67.36 95.91,66.85 96.15,66.61 96.15,66.22 96.02,66.09 96.02,64.75 95.86,64.6 UU1.AN46 ; UD2.E3 87.05,90.61 86.83,90.61 86.64,90.8 86.64,93.34 86.59,93.39 86.59,93.41
  BOTTOM w0.14: 95.96,67.43 95.96,68.45 95.77,68.64 95.77,74.17 93.89,76.05 93.89,90.15 92.62,91.42 90.1,93.94 86.89,93.94 86.59,93.64 86.59,93.41
M_A_DQS_6_DP: length 39.5
  BOTTOM w0.076: 86.86,93.41 86.86,93.39 86.81,93.34 86.81,92.99 86.94,92.86 86.94,92.69 86.81,92.55 86.81,92.36 86.94,92.23 86.94,92.05 86.81,91.92 86.81,91.71 86.89,91.63 86.89,91.41 86.81,91.33 86.81,90.87 86.9,90.78 87.07,90.78 87.24,90.94 87.24,91.07 UD2.D3 ; 95.69,67.43 95.69,67.41 95.74,67.36 95.74,66.79 95.98,66.54 95.98,66.29 95.85,66.16 95.85,64.89 95.77,64.81 UU1.AN47
  BOTTOM w0.14: 86.86,93.41 86.86,93.53 87,93.67 87.37,93.67 87.58,93.47 87.93,93.47 88.13,93.67 88.49,93.67 88.69,93.47 89.05,93.47 89.25,93.67 89.99,93.67 90.29,93.37 90.29,93.04 90.52,92.81 90.85,92.81 91.08,92.58 91.08,92.25 91.31,92.02 91.64,92.02 91.87,91.79 91.87,91.46 92.1,91.23 92.43,91.23 93.62,90.04 93.62,75.94 95.5,74.06 95.5,68.53 95.69,68.34 95.69,67.43
M_A_DQS_7_DN: length 50.6
  ART06 w0.076: v2(95.52,61.7) 95.3,61.7 95.18,61.82 95.18,61.88 95.18,63.29 95.23,63.35 95.23,63.36
  ART06 w0.14: v1(81.91,90.86) 81.62,90.86 81.53,90.94 81.08,90.94 80.78,91.24 80.78,93.38 81.98,94.57 89.28,94.57 92.09,91.77 92.09,78.96 92.22,78.83 92.42,78.83 92.72,78.53 92.72,77.83 92.42,77.53 92.22,77.53 92.09,77.4 92.09,76.93 92.22,76.79 93.57,76.79 93.86,76.5 93.86,67.41 94.58,66.7 94.58,65.94 95.23,65.29 95.23,63.57 95.23,63.36
  BOTTOM w0.076: UU1.AR41 v2(95.52,61.7)
  BOTTOM w0.14: UD2.E10 v1(81.91,90.86)
M_A_DQS_7_DP: length 50.6
  ART06 w0.076: 94.96,63.36 94.96,63.35 95.01,63.29 95.01,61.88 95.01,61.77 94.94,61.7 v2(94.66,61.69)
  ART06 w0.14: 94.96,63.36 94.96,65.18 94.31,65.83 94.31,66.59 93.6,67.3 93.6,76.39 93.46,76.53 92.11,76.53 91.82,76.82 91.82,77.51 92.11,77.8 92.31,77.8 92.45,77.94 92.45,78.42 92.31,78.56 92.11,78.56 91.82,78.85 91.82,91.66 90.73,92.76 90.5,92.76 90.22,93.04 90.22,93.26 89.94,93.55 89.71,93.55 89.43,93.83 89.43,94.05 89.17,94.31 87.08,94.31 86.85,94.08 86.52,94.08 86.29,94.31 85.81,94.31 85.61,94.1 85.25,94.1 85.05,94.31 84.69,94.31 84.49,94.1 84.13,94.1 83.93,94.31 83.57,94.31 83.37,94.1 83.01,94.1 82.81,94.31 82.09,94.31 81.05,93.27 81.05,93 81.28,92.77 81.28,92.44 81.05,92.21 81.05,91.35 81.19,91.21 81.61,91.21 v1(81.91,91.51)
  BOTTOM w0.076: UU1.AT41 94.61,61.71 v2(94.66,61.69)
  BOTTOM w0.14: UD2.D10 v1(81.91,91.51)
M_A_LP4_CAA0: length 54.1
  PWR04 w0.14: v1(90.02,71.12) 90.02,72.62 87.63,75 82.55,75 76.58,80.97 76.58,82.76 76.44,82.9 74.81,82.9 74.67,83.04 74.67,83.32 74.81,83.46 76.44,83.46 76.58,83.6 76.58,83.85 76.44,83.99 74.31,83.99 74.17,84.13 74.17,84.41 74.31,84.55 76.44,84.55 76.58,84.69 76.58,84.97 76.44,85.11 74.31,85.11 74.17,85.25 74.17,85.53 74.31,85.67 76.44,85.67 76.58,85.81 76.58,86.17 76.44,86.31 v1(73.51,86.31)
  ART06 w0.152: v1(70.66,84.36) 71.56,84.36 v1(73.51,86.31) 71.55,88.26 v1(70.66,88.26)
  BOTTOM w0.076: UU1.BG48 88.74,65.34 88.99,65.66 88.99,67.01 88.85,67.16
  BOTTOM w0.165: UD1.R2 v1(70.66,84.36) ; UD1.H2 v1(70.66,88.26) ; 88.85,67.16 88.85,67.99 89,68.15 89,68.86 89.25,69.11 89.25,70.36 v1(90.02,71.12)
M_A_LP4_CAA1: length 52.1
  PWR04 w0.14: v1(72.74,86.31) 73.53,85.52 73.53,83.39 74.98,81.94 75.17,81.94 75.55,82.31 75.75,82.31 75.94,82.12 75.94,81.92 75.57,81.54 75.57,81.35 77.77,79.15 77.77,78.95 77.01,78.2 77.01,78 77.21,77.8 77.41,77.8 78.16,78.56 78.36,78.56 78.56,78.36 78.56,78.16 77.8,77.41 77.8,77.21 78,77.01 78.2,77.01 78.95,77.77 79.15,77.77 79.35,77.57 79.35,77.37 78.59,76.61 78.59,76.42 78.79,76.22 78.99,76.22 79.74,76.97 79.94,76.97 80.14,76.78 80.14,76.58 79.38,75.82 79.38,75.63 79.58,75.43 79.78,75.43 80.53,76.18 80.73,76.18 80.93,75.99 80.93,75.79 80.17,75.03 80.17,74.84 80.37,74.64 80.57,74.64 81.33,75.39 81.52,75.39 82.37,74.55 87.45,74.55 89.51,72.49 89.51,70.74 v1(90.02,70.23)
  ART06 w0.152: v1(70.67,87.61) 71.34,86.94 72.11,86.94 v1(72.74,86.31) 72.08,85.65 71.31,85.65 v1(70.67,85.01)
  BOTTOM w0.102: 70.65,85 70.66,85.01 v1(70.67,85.01)
  BOTTOM w0.165: 70.65,85 UD1.P2 ; UU1.BE47 89.98,64.67 89.7,64.96 89.7,66.05 89.94,66.29 89.94,66.82 89.58,67.18 89.58,67.89 89.86,68.17 89.86,68.68 89.56,68.98 89.56,69.77 v1(90.02,70.23) ; v1(70.67,87.61) 70.66,87.61 UD1.J2
M_A_LP4_CAA2: length 51.6
  PWR04 w0.14: 64.26,85.91 64.53,85.91 64.64,85.8 64.64,84.78 v1(65.06,84.36) ; 64.26,85.91 64.13,85.79 64.13,84.66 64.44,84.35 64.44,79.17 66.7,76.91 72.41,76.91 78.51,70.81 83.43,70.81 83.57,70.67 83.57,70.32 83.71,70.18 83.99,70.18 84.13,70.32 84.13,70.67 84.27,70.81 84.55,70.81 84.69,70.67 84.69,70.32 84.83,70.18 85.11,70.18 85.25,70.32 85.25,70.67 85.39,70.81 85.85,70.81 87.35,69.31 87.73,69.31 87.87,69.45 87.87,70.04 88.01,70.18 88.29,70.18 88.43,70.04 88.43,69.45 88.57,69.31 89.25,69.31 89.46,69.11 v1(90.02,69.11) ; 64.26,85.91 64.07,86.1 64.07,86.62 64.67,87.23 64.67,87.77 64.77,87.87 64.77,87.97 v1(65.06,88.26)
  BOTTOM w0.165: v1(90.02,69.11) 90.17,68.96 90.17,68.04 89.94,67.82 89.94,67.28 90.32,66.9 90.32,64.36 89.98,64.02 UU1.BE45 ; UD1.H9 v1(65.06,88.26) ; UD1.R9 v1(65.06,84.36)
M_A_LP4_CAA3: length 52.2
  PWR04 w0.14: v1(63.46,84.36) 63.07,84.74 63.07,85.75 63.32,86 ; 63.32,86 63.89,85.44 63.89,79.16 64.76,78.29 64.76,78.09 64.52,77.86 64.52,77.66 64.72,77.46 64.92,77.46 65.16,77.7 65.35,77.7 65.55,77.5 65.55,77.3 65.32,77.07 65.32,76.87 65.51,76.67 65.71,76.67 65.95,76.91 66.14,76.91 66.6,76.45 72.26,76.45 79.17,69.54 79.7,69.54 79.84,69.68 79.84,70.17 79.97,70.3 80.25,70.3 80.39,70.17 80.39,69.68 80.53,69.54 80.81,69.54 80.95,69.68 80.95,70.17 81.09,70.3 81.37,70.3 81.51,70.17 81.51,69.68 81.65,69.54 82.04,69.54 82.18,69.68 82.18,70.17 82.32,70.3 82.6,70.3 82.74,70.17 82.74,69.68 82.88,69.54 86.49,69.54 87.12,68.91 89.05,68.91 v2(89.43,68.53) ; 63.32,86 63.32,87.32 v1(64.26,88.26)
  BOTTOM w0.076: 89.16,67.15 89.16,65.61 89.05,65.43 89.05,65.1 UU1.BG47
  BOTTOM w0.165: v2(89.43,68.53) 89.43,68.17 89.16,67.9 89.16,67.15 ; UD1.H10 v1(64.26,88.26) ; UD1.R10 v1(63.46,84.36)
M_A_LP4_CAA4: length 52.7
  PWR04 w0.14: 62.1,86.18 62.23,86.05 62.23,84.79 v1(62.66,84.36) ; 62.1,86.18 63.06,87.14 63.06,87.86 v1(62.66,88.26) ; 62.1,86.18 61.59,86.18 61.42,86 61.42,80.21 65.61,76.02 72.01,76.02 78.92,69.11 86.35,69.11 86.49,68.97 86.49,68.03 86.62,67.89 86.87,67.89 87.01,68.03 87.01,68.39 87.15,68.53 87.43,68.53 87.57,68.39 87.57,68.03 87.71,67.89 88.9,67.89 89.03,68.02 89.03,68.39 88.89,68.53 v2(88.31,68.53)
  BOTTOM w0.165: UD1.H11 v1(62.66,88.26) ; UU1.BG45 88.74,64.01 88.4,64.35 88.4,65.97 88.47,66.04 88.47,66.62 88.21,66.88 88.21,68.43 v2(88.31,68.53) ; UD1.R11 v1(62.66,84.36)
M_A_LP4_CAA5: length 48.7
  PWR04 w0.14: v1(61.09,86.31) 61.09,79.91 65.43,75.56 68.31,75.56 68.49,75.38 68.87,75.38 69.05,75.56 69.43,75.56 69.61,75.38 69.99,75.38 70.17,75.56 70.55,75.56 70.73,75.38 71.11,75.38 71.28,75.56 71.83,75.56 78.61,68.78 85.09,68.78 86.28,67.59 v2(90.37,67.59)
  ART06 w0.152: v1(62.66,87.61) 62.12,87.07 61.85,87.07 v1(61.09,86.31) 61.77,85.62 62.05,85.62 v1(62.66,85.01)
  BOTTOM w0.165: UD1.P11 v1(62.66,85.01) ; UU1.BB49 91.25,66.18 90.7,66.72 90.7,67.26 v2(90.37,67.59) ; UD1.J11 v1(62.66,87.61)
M_A_LP4_CAB0: length 49.2
  PWR04 w0.14: v2(86.42,61.04) 86.86,60.6 88.03,60.6 89.48,59.15 93.29,59.15 93.5,59.36 96.04,59.36 96.95,60.27 96.95,63.27 97.74,64.06 97.74,76.96 92.94,81.76 92.94,83.67 89.79,86.81 v1(89.28,86.81)
  ART06 w0.152: v1(88.31,88.26) 89.11,88.26 89.53,87.83 89.53,87.07 v1(89.28,86.81) 89.28,86.33 88.73,85.28 88.73,84.78 v1(88.31,84.36)
  BOTTOM w0.165: UU1.BM39 v2(86.42,61.04) ; UD2.R2 v1(88.31,84.36) ; UD2.H2 v1(88.31,88.26)
M_A_LP4_CAB1: length 48.1
  PWR04 w0.14: v1(88.77,86.43) 88.9,86.31 89.66,86.31 92.31,83.65 92.31,81.75 97.28,76.78 97.28,74.75 97.14,74.61 97.04,74.61 96.9,74.47 96.9,74.19 97.04,74.05 97.14,74.05 97.28,73.91 97.28,73.63 97.14,73.49 97.04,73.49 96.9,73.35 96.9,73.07 97.04,72.93 97.14,72.93 97.28,72.79 97.28,72.51 97.14,72.37 97.04,72.37 96.9,72.23 96.9,71.95 97.04,71.81 97.14,71.81 97.28,71.67 97.28,71.39 97.14,71.25 97.04,71.25 96.9,71.11 96.9,70.83 97.04,70.69 97.14,70.69 97.28,70.55 97.28,70.28 97.14,70.14 97.04,70.14 96.9,70 96.9,69.72 97.04,69.58 97.14,69.58 97.28,69.44 97.28,68.02 97.43,67.87 97.43,66.77 97.15,66.49 97.15,64.97 95.98,63.8 95.98,60.14 95.5,59.66 93.34,59.66 93.13,59.45 90.16,59.45 88.64,60.96 88.64,61.85 v2(88.21,62.29)
  ART06 w0.152: v1(88.32,85.01) 88.32,85.28 88.17,85.43 88.03,85.43 87.88,85.58 87.88,85.8 88.03,85.95 88.54,85.95 88.77,86.18 v1(88.77,86.43) 88.77,87.16 v1(88.32,87.61)
  BOTTOM w0.102: 88.3,85 88.31,85.01 v1(88.32,85.01)
  BOTTOM w0.165: UD2.P2 88.3,85 ; v1(88.32,87.61) 88.31,87.61 UD2.J2 ; UU1.BJ42 v2(88.21,62.29)
M_A_LP4_CAB2: length 46.7
  PWR04 w0.14: 81.91,85.8 82.17,85.8 82.29,85.93 82.56,85.93 82.7,85.79 82.7,85.57 82.29,85.16 82.29,84.6 82.54,84.36 v1(82.71,84.36) ; 81.91,85.8 81.79,85.67 81.79,84.53 82.09,84.22 82.09,78.19 82.23,78.05 82.58,78.05 82.72,78.19 82.72,78.55 82.86,78.69 83.14,78.69 83.28,78.55 83.28,78.19 83.42,78.05 83.82,78.05 83.96,78.19 83.96,79.56 84.1,79.7 84.37,79.7 84.51,79.56 84.51,78.19 84.65,78.05 84.98,78.05 85.12,78.19 85.12,79.18 85.26,79.32 85.54,79.32 85.68,79.18 85.68,78.19 85.82,78.05 87.49,78.05 87.76,77.79 87.76,77.3 87.89,77.16 88.52,77.16 92.84,72.84 92.84,67.26 92.56,66.98 92.56,66.37 89.69,63.5 88.7,63.5 v2(88.22,63.02) ; 81.91,85.8 81.74,85.98 81.74,86.51 82.31,87.09 82.31,87.86 v1(82.71,88.26)
  BOTTOM w0.165: UD2.H9 v1(82.71,88.26) ; UD2.R9 v1(82.71,84.36) ; UU1.BG43 v2(88.22,63.02)
M_A_LP4_CAB3: length 50.5
  PWR04 w0.14: v1(81.91,88.26) 81.28,87.62 81.28,86.43 81.02,86.18 ; v2(87.27,61.76) 87.27,61.85 86.89,62.23 86.89,63.17 87.51,63.79 87.71,63.79 87.93,63.57 88.13,63.57 88.33,63.76 88.33,63.96 88.1,64.18 88.1,64.38 88.26,64.54 90.32,64.54 92.2,66.42 92.2,68.13 92.45,68.39 92.45,68.69 92.2,68.95 92.2,69.25 92.45,69.51 92.45,69.81 92.2,70.06 92.2,70.37 92.45,70.62 92.45,70.93 92.2,71.18 92.2,71.49 92.45,71.74 92.45,72.05 92.2,72.3 92.2,72.88 88.42,76.65 87.38,76.65 87.24,76.79 87.24,77.4 87.1,77.54 86.86,77.54 86.72,77.4 86.72,76.79 86.58,76.65 86.3,76.65 86.16,76.79 86.16,77.4 86.02,77.54 85.74,77.54 85.6,77.4 85.6,76.79 85.46,76.65 85.18,76.65 85.04,76.79 85.04,77.4 84.9,77.54 84.62,77.54 84.48,77.4 84.48,76.79 84.34,76.65 84.06,76.65 83.92,76.79 83.92,77.4 83.78,77.54 83.5,77.54 83.36,77.4 83.36,76.79 83.22,76.65 82.94,76.65 82.8,76.79 82.8,77.4 82.66,77.54 82.04,77.54 81.54,78.04 81.54,85.66 81.02,86.18 ; 81.02,86.18 80.43,86.18 80.29,86.04 80.29,85.65 80.72,85.21 80.72,84.74 v1(81.11,84.36)
  BOTTOM w0.165: UD2.H10 v1(81.91,88.26) ; UU1.BM41 v2(87.27,61.76) ; UD2.R10 v1(81.11,84.36)
M_A_LP4_CAB4: length 49.7
  PWR04 w0.14: v1(80.31,88.26) 80.77,87.8 80.77,87.07 79.86,86.15 ; v1(80.31,84.36) 80.06,84.36 79.92,84.5 79.92,85.28 79.78,85.42 79.54,85.42 79.47,85.48 79.47,85.69 79.57,85.79 79.79,85.79 79.91,85.9 79.91,86.1 79.86,86.15 ; 79.86,86.15 79.23,86.15 78.99,85.91 78.99,85.42 78.89,85.32 78.12,85.32 77.98,85.18 77.98,84.9 78.12,84.76 78.85,84.76 78.99,84.62 78.99,84.26 78.85,84.12 78.12,84.12 77.98,83.98 77.98,83.7 78.12,83.56 78.85,83.56 78.99,83.42 78.99,83.14 78.85,83 78.12,83 77.98,82.86 77.98,82.58 78.12,82.44 78.85,82.44 78.99,82.3 78.99,82.02 78.85,81.88 78.12,81.88 77.98,81.74 77.98,81.47 78.12,81.33 78.85,81.33 78.99,81.19 78.99,79.98 82.73,76.25 88.14,76.25 91.87,72.51 91.87,66.49 90.24,64.87 88.22,64.87 v2(86.38,63.02)
  BOTTOM w0.14: UU1.BM43 v2(86.38,63.02)
  BOTTOM w0.165: UD2.R11 v1(80.31,84.36) ; UD2.H11 v1(80.31,88.26)
M_A_LP4_CAB5: length 51.2
  PWR04 w0.102: v2(88.21,61.05) 87.86,61.39 87.09,61.39 86.74,61.74 86.74,62.08 86.5,62.32
  PWR04 w0.14: 86.5,62.32 85.93,62.89 85.93,63.78 87.42,65.28 89.51,65.28 90.65,66.42 91.31,66.42 91.57,66.67 91.57,69.9 91.43,70.04 90.82,70.04 90.68,70.18 90.68,70.46 90.82,70.6 91.43,70.6 91.57,70.74 91.57,71.02 91.43,71.16 90.82,71.16 90.68,71.3 90.68,71.58 90.82,71.72 91.43,71.72 91.57,71.86 91.57,72.13 87.88,75.82 82.5,75.82 77.47,80.85 77.47,86.42 77.61,86.56 77.9,86.56 78.04,86.42 78.04,86.07 78.18,85.93 78.46,85.93 78.6,86.07 78.6,86.42 78.74,86.56 v1(79.63,86.56)
  ART06 w0.152: v1(80.32,85.01) 80.32,86.15 80.17,86.31 79.88,86.31 v1(79.63,86.56) 80.31,87.25 v1(80.31,87.61)
  BOTTOM w0.165: UU1.BG38 88.21,60.63 v2(88.21,61.05) ; UD2.P11 80.33,85 v1(80.32,85.01) ; UD2.J11 v1(80.31,87.61)
M_A_LP4_CKE_A0: length 47.1
  PWR04 w0.14: v1(70.46,86.31) 71.06,85.7 71.37,85.7 72.64,84.43 72.64,81.35 72.88,81.11 73.08,81.11 73.58,81.61 73.78,81.61 73.98,81.41 73.98,81.22 73.35,80.59 73.35,80.39 73.55,80.19 73.75,80.19 74.37,80.82 74.57,80.82 74.77,80.62 74.77,80.43 74.14,79.8 74.14,79.6 74.34,79.4 74.54,79.4 75.16,80.03 75.36,80.03 75.56,79.83 75.56,79.64 74.93,79.01 74.93,78.81 75.13,78.61 75.33,78.61 76.02,79.31 76.21,79.31 76.41,79.11 76.41,78.91 75.72,78.22 75.72,78.02 80.45,73.29 v1(87.44,73.29)
  ART06 w0.152: v1(68.29,85.01) 69.05,85.77 69.92,85.77 v1(70.46,86.31) 69.9,86.87 69.03,86.87 v1(68.29,87.61)
  BOTTOM w0.165: UD1.P4 68.29,84.98 v1(68.29,85.01) ; UU1.BG49 88.74,66.78 88.52,67 88.52,68.07 88.72,68.27 88.72,69.03 88.95,69.26 88.95,71.78 v1(87.44,73.29) ; UD1.J4 v1(68.29,87.61)
M_A_LP4_CKE_A1: length 50.3
  PWR04 w0.14: v1(67.46,85.01) 67.46,85.57 67.69,85.8 67.69,86.31 67.46,86.54 67.46,86.76 67.59,86.89 ; 67.59,86.89 67.38,87.09 67.16,87.09 66.77,87.48 66.77,87.68 66.98,87.89 67.18,87.89 v1(67.46,87.61) ; 67.59,86.89 67.99,86.89 68.2,86.69 68.2,85.54 67.89,85.24 67.89,84.55 67.86,84.52 67.86,83.98 68.2,83.64 68.45,83.64 68.76,83.33 68.76,81.94 70.1,80.59 70.99,80.59 72.2,79.38 72.4,79.38 72.65,79.63 72.85,79.63 73.04,79.43 73.04,79.23 72.8,78.98 72.8,78.79 72.99,78.59 73.19,78.59 73.44,78.84 73.64,78.84 73.83,78.64 73.83,78.44 73.59,78.19 73.59,78 73.78,77.8 73.98,77.8 74.23,78.05 74.43,78.05 74.62,77.85 74.62,77.65 74.38,77.4 74.38,77.21 74.57,77.01 74.77,77.01 75.02,77.26 75.22,77.26 75.41,77.06 75.41,76.86 75.17,76.61 75.17,76.42 75.37,76.22 75.56,76.22 75.81,76.46 76.01,76.46 76.2,76.27 76.2,76.07 75.96,75.82 75.96,75.63 76.16,75.43 76.35,75.43 76.6,75.67 76.8,75.67 76.99,75.48 76.99,75.28 76.75,75.03 76.75,74.83 76.95,74.64 77.14,74.64 77.39,74.88 77.59,74.88 77.79,74.69 77.79,74.49 77.54,74.24 77.54,74.04 77.74,73.85 77.93,73.85 78.18,74.09 78.38,74.09 78.58,73.9 78.58,73.7 78.33,73.45 78.33,73.25 79.25,72.34 87.76,72.34 v1(88.33,71.77)
  BOTTOM w0.076: 87.91,66.77 87.7,66.57 87.7,66.09 87.78,66.01 87.78,65.33 88.11,64.99 UU1.BJ47
  BOTTOM w0.165: UD1.P5 v1(67.46,85.01) ; UD1.J5 v1(67.46,87.61) ; v1(88.33,71.77) 88.62,71.47 88.62,69.47 87.91,68.76 87.91,66.77
M_A_LP4_CKE_B0: length 47.3
  PWR04 w0.14: v2(90.04,61.07) 90.04,60.57 90.61,59.99 92.89,59.99 93.32,60.42 93.32,62.51 96.11,65.3 96.11,66.65 95.76,67 95.76,76.65 94.53,77.88 94.33,77.88 94.02,77.57 93.83,77.57 93.63,77.77 93.63,77.96 93.94,78.28 93.94,78.47 93.74,78.67 93.54,78.67 93.23,78.36 93.03,78.36 92.84,78.56 92.84,78.76 93.15,79.07 93.15,79.26 92.95,79.46 92.75,79.46 92.51,79.21 92.31,79.21 92.11,79.41 92.11,79.61 92.36,79.86 92.36,80.05 92.16,80.25 91.96,80.25 91.72,80 91.52,80 91.32,80.2 91.32,80.4 91.57,80.65 91.57,80.84 91.21,81.2 91.21,83.51 90.56,84.16 90.36,84.16 89.91,83.71 89.72,83.71 89.52,83.91 89.52,84.11 89.97,84.56 89.97,84.75 89.25,85.47 87.83,85.47 87.25,86.05 v1(87.25,86.38)
  ART06 w0.152: v1(85.94,85.01) 87.25,86.31 v1(87.25,86.38) 86.02,87.61 v1(85.94,87.61)
  BOTTOM w0.165: UD2.P4 85.94,84.98 v1(85.94,85.01) ; v2(90.04,61.07) 90.04,61.07 90.04,60.62 UU1.BF38 ; UD2.J4 v1(85.94,87.61)
M_A_LP4_CKE_B1: length 47
  PWR04 w0.14: 85.24,86.89 85.04,87.09 84.81,87.09 84.42,87.48 84.42,87.68 84.64,87.89 84.83,87.89 v1(85.11,87.61) ; 85.24,86.89 85.11,86.76 85.11,86.54 85.34,86.31 85.34,85.8 85.11,85.57 v1(85.11,85.01) ; 85.24,86.89 85.65,86.89 85.85,86.69 85.85,85.57 85.54,85.26 85.54,84.55 85.51,84.52 85.51,83.67 85.72,83.46 86.13,83.46 86.74,82.85 88.38,82.85 88.52,82.71 88.52,82.38 88.38,82.24 88.02,82.24 87.88,82.1 87.88,81.73 88.02,81.59 89.27,81.59 89.53,81.33 89.53,80.72 89.41,80.59 88.26,80.59 88.14,80.46 88.14,80.06 88.24,79.96 90.17,79.96 93.72,76.4 93.72,74.89 93.86,74.75 94.09,74.75 94.23,74.89 94.23,76.13 94.37,76.27 94.65,76.27 94.79,76.13 94.79,66.16 92.3,63.68 91.23,63.68 90.04,62.48 v2(90.04,62.37)
  BOTTOM w0.165: UD2.P5 v1(85.11,85.01) ; UD2.J5 v1(85.11,87.61) ; v2(90.04,62.37) 90.04,61.91 UU1.BF41
M_A_LP4_CS_A_R0_N: length 52.5
  PWR04 w0.102: 85.06,61.74 85.06,61.59 85.24,61.41 86.74,61.41 87.12,61.03 v2(87.3,61.03)
  PWR04 w0.14: 68.71,86.05 68.71,84.07 68.6,83.97 68.41,83.97 68.26,84.12 v1(68.26,84.36) ; 68.71,86.05 68.95,86.05 69.14,85.86 69.14,83.84 71.25,81.73 71.45,81.73 80.47,72.72 88.14,72.72 88.77,72.08 88.77,70.46 89.71,69.52 90.24,69.52 90.78,68.98 90.78,67.46 90.42,67.1 89.43,67.1 88.29,65.96 86.99,65.96 85.06,64.03 85.06,61.74 ; 68.71,86.05 68.58,86.18 68.58,86.92 68.96,87.3 68.96,87.83 68.53,88.26 v1(68.29,88.26)
  BOTTOM w0.165: UD1.H4 v1(68.29,88.26) ; v2(87.3,61.03) 87.3,60.62 UU1.BM38 ; UD1.R4 v1(68.26,84.36)
M_A_LP4_CS_A_R1_N: length 51.2
  PWR04 w0.14: 69.59,86.94 70.69,86.94 73.12,84.5 73.12,83.16 77.12,79.17 77.12,78.97 76.36,78.21 76.36,78.02 80.52,73.86 87.63,73.86 89.1,72.39 89.1,70.51 89.84,69.77 90.45,69.77 91.11,69.11 91.11,67.33 89.33,65.55 87.22,65.55 85.55,63.88 85.55,62.86 86.38,62.03 v2(86.38,61.77) ; 69.59,86.94 69.29,86.64 69.29,86.14 69.42,86.01 69.42,84.8 v1(69.86,84.36) ; 69.59,86.94 69.34,87.2 69.34,87.96 68.99,88.3 68.99,88.5 69.21,88.71 69.4,88.71 v1(69.86,88.26)
  BOTTOM w0.165: UU1.BM42 v2(86.38,61.77) ; UD1.H3 v1(69.86,88.26) ; UD1.R3 v1(69.86,84.36)
M_A_LP4_CS_B_R0_N: length 43.3
  PWR04 w0.102: 89.03,61.92 88.67,62.28 88.67,62.46 88.47,62.66 87.58,62.66 v2(87.29,62.37)
  PWR04 w0.14: 86.54,85.54 86.74,85.54 86.87,85.42 86.87,83.64 87.25,83.26 88.64,83.26 89.53,82.37 89.79,82.37 90.42,81.73 90.42,80.34 93.72,77.04 94.74,77.04 95.25,76.53 95.25,67 95.1,66.85 95.1,65.96 92.53,63.4 91.39,63.4 90.55,62.56 90.55,62.33 90.14,61.92 89.03,61.92 ; 86.54,85.54 86.36,85.36 86.36,84.94 86.43,84.86 86.43,84.02 86.23,83.82 86.03,83.82 85.91,83.94 v1(85.91,84.36) ; 86.54,85.54 86.38,85.7 86.38,87.81 v1(85.94,88.26)
  BOTTOM w0.127: v2(87.29,62.37) 87.21,62.45 86.26,62.45 UU1.BP42
  BOTTOM w0.165: UD2.R4 v1(85.91,84.36) ; UD2.H4 v1(85.94,88.26)
M_A_LP4_CS_B_R1_N: length 45.7
  PWR04 w0.14: v1(87.51,84.36) 87.11,84.76 87.11,85.57 86.74,86.33 86.74,86.56 86.99,86.81 ; v1(87.51,88.26) 86.99,87.74 86.99,86.81 ; 86.99,86.81 86.99,86.81 87.5,86.81 87.65,86.66 87.65,86.15 88.01,85.8 89.53,85.8 91.69,83.64 91.69,81.73 96.26,77.16 96.26,67.26 96.47,67.05 96.47,64.84 95.07,63.45 95.07,60.25 94.79,59.97 93.27,59.97 93.01,59.71 90.48,59.71 v2(89.12,61.07)
  BOTTOM w0.165: UU1.BG42 89.12,61.66 v2(89.12,61.07) ; UD2.H3 v1(87.51,88.26) ; UD2.R3 v1(87.51,84.36)
M_B_CK_DDR0_DN: length 37.3
  PWR04 w0.14: v1(100.47,86.32) 100.63,86.48 100.63,86.73 100.93,87.03 101.97,87.03 102.47,86.52 102.47,85.82 102.18,85.52 102.18,78.08 102.32,77.94 105,77.94 105.29,77.64 105.29,76.95 105,76.65 102.89,76.65 102.75,76.51 102.75,75.95 102.89,75.81 105,75.81 105.29,75.52 105.29,73.51 v1(105.45,73.35)
  ART06 w0.14: v1(100.38,87.61) 100.63,87.35 100.63,86.48 v1(100.47,86.32) 100.63,86.16 100.63,85.26 100.38,85.01 v1(100.36,85.01)
  BOTTOM w0.076: 102.65,67.53 102.65,67.51 102.6,67.46 102.6,66.94 102.39,66.72 102.39,66.09 102.25,65.95 102.25,65.64 102.49,65.4 UU1.Y48
  BOTTOM w0.14: 102.65,67.53 102.65,67.78 103.9,69.02 104.26,69.02 104.47,69.24 104.47,69.6 104.65,69.77 104.65,72.01 105.14,72.5 105.14,73.04 v1(105.45,73.35) ; UD3.P9 100.36,84.99 100.36,85.01 v1(100.36,85.01) ; UD3.J9 v1(100.38,87.61)
M_B_CK_DDR0_DP: length 37.2
  PWR04 w0.14: v1(104.87,73.35) 105.03,73.51 105.03,75.41 104.89,75.54 102.78,75.54 102.49,75.84 102.49,76.62 102.78,76.92 104.89,76.92 105.03,77.06 105.03,77.53 104.89,77.67 102.21,77.67 101.92,77.97 101.92,82.22 101.7,82.44 101.7,82.78 101.92,83 101.92,83.34 101.7,83.56 101.7,83.9 101.92,84.12 101.92,84.46 101.7,84.67 101.7,85.02 101.92,85.23 101.92,85.63 102.21,85.93 102.21,86.41 101.86,86.76 101.04,86.76 100.9,86.62 100.9,86.48 v1(101.06,86.32)
  ART06 w0.14: v1(101.17,85.01) 100.9,85.27 100.9,86.16 v1(101.06,86.32) 100.9,86.48 100.9,87.34 v1(101.17,87.61)
  BOTTOM w0.076: 102.39,67.53 102.39,67.51 102.44,67.46 102.44,67.01 102.22,66.79 102.22,66.16 102.08,66.02 102.08,65.57 102.26,65.4 102.26,65.02 UU1.Y47
  BOTTOM w0.14: UD3.J8 v1(101.17,87.61) ; 102.39,67.53 102.39,67.89 104.38,69.88 104.38,72.12 104.87,72.61 v1(104.87,73.35) ; UD3.P8 v1(101.17,85.01)
M_B_CK_DDR1_DN: length 46.7
  PWR04 w0.14: v2(105.59,63.02) 105.76,62.85 105.9,62.85 106.03,62.98 106.03,63.3 105.87,63.46 105.87,63.86 106.03,64.02 106.03,64.42 105.87,64.58 105.87,64.98 106.03,65.14 106.03,65.36 106.36,65.7 106.78,65.7 106.93,65.55 107.13,65.55 107.53,65.94 107.53,66.14 107.38,66.29 107.38,66.71 108.26,67.59 108.68,67.59 108.89,67.38 109.09,67.38 109.49,67.78 109.49,67.97 109.27,68.19 109.27,68.61 109.82,69.16 110.24,69.16 110.9,68.5 111.1,68.5 111.49,68.89 111.49,69.09 110.83,69.75 110.83,70.17 111.39,70.72 111.8,70.72 112.46,70.06 112.66,70.06 113.06,70.46 113.06,70.65 112.4,71.31 112.4,71.73 112.95,72.28 113.37,72.28 113.96,71.69 114.16,71.69 114.56,72.08 114.56,72.28 113.96,72.88 113.96,73.29 114.51,73.85 114.93,73.85 115.59,73.19 115.79,73.19 116.18,73.58 116.18,73.78 115.52,74.44 115.52,74.86 117.36,76.69 117.36,76.89 116.98,77.26 116.98,77.68 117.53,78.23 117.95,78.23 118.33,77.86 118.52,77.86 119.25,78.59 119.25,85.42 119.01,85.66 118.79,85.66 v1(118.13,86.32)
  ART06 w0.14: v1(118.02,85.01) 118.03,85.01 118.28,85.26 118.28,86.16 v1(118.13,86.32) 118.28,86.48 118.28,87.35 v1(118.03,87.61)
  BOTTOM w0.14: UU1.M43 v2(105.59,63.02) ; UD4.P9 118.02,85 v1(118.02,85.01) ; UD4.J9 v1(118.03,87.61)
M_B_CK_DDR1_DP: length 46.7
  PWR04 w0.14: v1(118.71,86.32) 118.71,86.11 118.9,85.93 119.12,85.93 119.52,85.53 119.52,78.47 118.63,77.59 118.21,77.59 117.84,77.97 117.64,77.97 117.24,77.57 117.24,77.37 117.62,77 117.62,76.58 115.79,74.75 115.79,74.55 116.45,73.89 116.45,73.47 115.9,72.92 115.48,72.92 114.82,73.58 114.62,73.58 114.23,73.18 114.23,72.99 114.82,72.39 114.82,71.97 114.27,71.42 113.85,71.42 113.26,72.02 113.06,72.02 112.66,71.62 112.66,71.42 113.32,70.76 113.32,70.35 112.77,69.79 112.35,69.79 111.69,70.45 111.5,70.45 111.1,70.06 111.1,69.86 111.76,69.2 111.76,68.78 111.21,68.23 110.79,68.23 110.13,68.89 109.93,68.89 109.54,68.5 109.54,68.3 109.75,68.08 109.75,67.66 109.2,67.11 108.78,67.11 108.57,67.33 108.37,67.33 107.64,66.6 107.64,66.4 107.79,66.25 107.79,65.83 107.24,65.28 106.82,65.28 106.67,65.43 106.47,65.43 106.29,65.25 106.29,62.87 106,62.57 105.71,62.57 v2(105.59,62.45)
  ART06 w0.14: v1(118.82,87.61) 118.55,87.34 118.55,86.48 v1(118.71,86.32) 118.55,86.16 118.55,85.27 v1(118.82,85.01)
  BOTTOM w0.14: UU1.M42 105.62,62.36 v2(105.59,62.45) ; UD4.P8 v1(118.82,85.01) ; UD4.J8 v1(118.82,87.61)
M_B_DQ_0[0]: length 20.6
  BOTTOM w0.076: 97.25,68.68 97.59,68.35 97.59,67.26 97.23,66.91 97.23,65.86 97.31,65.32 UU1.AK48
  BOTTOM w0.165: UD3.U11 98.02,82.73 97.7,82.41 96.56,82.41 95.93,81.79 95.93,76.78 97.48,75.23 97.48,71.17 97.25,70.94 97.25,68.68
M_B_DQ_0[1]: length 24.9
  BOTTOM w0.076: UU1.AK45 97.19,64.41 97.19,64.93 97.06,65.85 97.06,66.99 97.41,67.33 97.41,68.04 96.98,68.48
  BOTTOM w0.165: UD3.U9 99.65,83.06 96.72,83.06 96.57,83.21 95.83,83.21 95.6,82.98 95.6,76.65 97.15,75.11 97.15,71.27 96.98,71.09 96.98,68.48
M_B_DQ_0[2]: length 20.4
  BOTTOM w0.076: 97.56,68.78 97.76,68.58 97.76,67.17 97.39,66.8 97.39,66.08 97.49,65.98 UU1.AK49
  BOTTOM w0.165: 97.56,68.78 97.56,70.81 97.81,71.07 97.81,75.36 96.26,76.91 96.26,78.68 96.43,78.84 96.63,78.84 96.8,79.01 96.8,79.34 96.63,79.5 96.43,79.5 96.26,79.67 96.26,80 96.43,80.16 96.63,80.16 96.8,80.33 96.8,80.66 96.63,80.82 96.43,80.82 96.26,80.99 96.26,81.34 96.43,81.51 96.95,81.51 97.2,81.76 98.05,81.76 UD3.V11
M_B_DQ_0[3]: length 21.1
  BOTTOM w0.076: 99.57,68.29 99.57,68.12 99.01,67.56 99.01,67.14 99.17,66.98 99.17,65.61 99.06,65.43 99.06,65.1 UU1.AG47
  BOTTOM w0.165: UD3.V9 100.3,82.41 101.56,82.41 101.84,82.13 101.84,78.67 101.33,78.16 101.33,75.57 100.3,74.55 100.3,70.53 99.57,69.8 99.57,68.29
M_B_DQ_0[4]: length 20.4
  BOTTOM w0.076: 97.86,69 97.86,68.86 97.94,68.78 97.94,67.1 97.58,66.74 97.58,66.17 97.75,66 97.75,65.66 97.7,65.44 97.73,65.18 97.72,65.02 UU1.AK47
  BOTTOM w0.165: 97.86,69 97.86,70.69 98.14,70.97 98.14,75.49 97.77,75.86 97.77,76.1 97.99,76.32 97.99,76.55 97.76,76.79 97.52,76.79 97.3,76.56 97.07,76.56 96.63,77 96.63,78.22 96.82,78.41 97.66,78.41 97.82,78.57 97.82,78.81 97.15,79.47 97.15,80.29 97.32,80.46 98.05,80.46 UD3.Y11
M_B_DQ_0[5]: length 20.4
  BOTTOM w0.076: UU1.AG45 98.03,63.84 97.84,64.03 97.84,64.59 97.9,65.19 97.86,65.43 97.92,65.65 97.92,66.09 97.75,66.26 97.75,66.64 98.09,66.99 98.09,67 98.12,67.03 98.12,68.35 98.17,68.4 98.17,68.73
  BOTTOM w0.165: UD3.AA11 97.98,79.73 97.98,79.36 98.47,78.86 98.47,78.11 98.31,77.95 97.17,77.95 97,77.78 97,77.45 97.17,77.29 98.31,77.29 98.47,77.12 98.47,70.86 98.17,70.56 98.17,68.73
M_B_DQ_0[6]: length 19.2
  BOTTOM w0.076: UU1.AG48 98.75,65.34 99,65.66 99,66.9 98.83,67.07 98.83,67.69 99.31,68.17 99.31,68.29
  BOTTOM w0.165: UD3.Y9 100.3,81.11 101.41,81.11 101.58,80.94 101.58,78.87 100.96,78.25 100.96,75.66 100.66,75.36 100.15,75.36 99.99,75.19 99.99,70.62 99.31,69.95 99.31,68.29
M_B_DQ_0[7]: length 18.7
  BOTTOM w0.076: 99.01,68.29 99.01,68.17 98.66,67.82 98.66,66.97 98.83,66.8 98.83,65.86 UU1.AG49
  BOTTOM w0.165: 99.01,68.29 99.01,70.05 99.67,70.71 99.67,75.55 99.83,75.71 100.39,75.71 100.56,75.88 100.56,76.22 100.39,76.38 99.88,76.38 99.72,76.55 99.72,76.88 99.88,77.04 100.34,77.04 100.51,77.21 100.51,77.54 100.34,77.7 99.88,77.7 99.72,77.87 99.72,78.2 99.88,78.36 100.6,78.36 100.89,78.65 100.89,78.89 100.38,79.4 100.38,79.73 UD3.AA9
M_B_DQ_1[0]: length 35.2
  ART06 w0.089: v2(98.27,60.44) 98.81,60.98 98.81,62.48 99.06,62.73 99.06,63.45 98.91,63.6 98.91,63.83
  ART06 w0.14: v1(100.36,90.86) 100.85,90.37 101.6,90.37 102.21,89.76 102.21,87.59 102.36,87.44 102.36,87.44 102.61,87.18 102.61,85.67 102.23,85.29 102.23,82.83 102.49,82.57 102.49,82.22 102.23,81.96 102.23,81.57 102.49,81.32 102.49,80.96 102.23,80.71 102.23,78.94 101.32,78.03 101.32,67.69 100.2,66.57 100.2,65.78 98.91,64.49 98.91,63.83
  BOTTOM w0.076: v2(98.27,60.44) 98.21,60.4 UU1.AJ38
  BOTTOM w0.165: UD3.E9 v1(100.36,90.86)
M_B_DQ_1[1]: length 38.9
  ART06 w0.076: 96.91,65.22 96.91,64.61 97.2,64.31 97.2,63.62 96.84,63.26 96.84,62.76 97,62.6 97,61.43 v2(97.36,61.07)
  ART06 w0.14: 96.91,65.22 96.91,66.68 97.46,67.23 97.46,68.35 96.65,69.16 96.65,78.18 95.02,79.8 95.02,91.46 96.77,93.22 98.5,93.22 99.56,92.16 v1(99.56,92.16)
  BOTTOM w0.076: v2(97.36,61.07) 97.26,61.02 UU1.AL39
  BOTTOM w0.165: UD3.C9 v1(99.56,92.16)
M_B_DQ_1[2]: length 33.6
  ART06 w0.089: 98.65,63.73 98.65,63.47 98.8,63.32 98.8,62.73 98.63,62.56 98.63,61.43 v2(98.27,61.07)
  ART06 w0.14: v1(100.36,90.21) 100.58,89.99 101.47,89.99 101.85,89.61 101.85,87.45 102.23,87.07 102.23,85.8 101.73,85.29 101.73,82.83 101.47,82.57 101.47,82.22 101.73,81.96 101.73,81.45 101.47,81.2 101.47,80.84 101.73,80.59 101.73,78.94 100.91,78.13 100.91,67.66 99.92,66.67 99.92,65.94 98.65,64.67 98.65,63.73
  BOTTOM w0.076: UU1.AJ39 98.17,61.02 v2(98.27,61.07)
  BOTTOM w0.165: UD3.F9 v1(100.36,90.21)
M_B_DQ_1[3]: length 36.9
  ART06 w0.076: v2(97.36,62.98) 97.55,63.17 97.55,64.63 97.43,64.74 97.43,65.16
  ART06 w0.14: 97.43,65.16 97.43,66.29 98.17,67.03 98.17,69.64 98.02,69.79 97.56,69.79 97.41,69.94 97.41,70.25 97.56,70.4 98.02,70.4 98.17,70.55 98.17,70.85 98.02,71.01 97.56,71.01 97.41,71.16 97.41,71.58 97.56,71.73 97.89,71.73 98.04,71.89 98.04,72.19 97.89,72.34 97.56,72.34 97.41,72.5 97.41,72.8 97.56,72.95 97.89,72.95 98.04,73.11 98.04,77.8 95.63,80.21 95.63,91.21 97,92.58 97.54,92.58 v1(97.96,92.16)
  BOTTOM w0.076: UU1.AL43 v2(97.36,62.98)
  BOTTOM w0.165: UD3.C11 v1(97.96,92.16)
M_B_DQ_1[4]: length 39.4
  ART06 w0.076: v2(97.36,60.44) 96.83,60.96 96.83,62.53 96.65,62.71 96.65,63.5 96.49,63.65 96.49,64.3 96.59,64.4
  ART06 w0.14: v1(99.56,92.81) 98.83,93.55 96.65,93.55 94.69,91.59 94.69,79.63 96.26,78.05 96.26,68.78 96.59,68.45 96.59,64.4
  BOTTOM w0.076: v2(97.36,60.44) 97.24,60.37 UU1.AL38
  BOTTOM w0.165: UD3.B9 v1(99.56,92.81)
M_B_DQ_1[5]: length 35.4
  ART06 w0.089: v2(98.27,62.39) 98.27,62.46 98.63,62.82 98.63,63.24 98.4,63.47 98.4,63.73
  ART06 w0.14: v1(97.96,90.21) 98.89,89.29 98.89,87.38 99.04,87.23 99.29,87.23 99.44,87.08 99.44,86.77 99.29,86.62 99.04,86.62 98.89,86.47 98.89,86.16 99.04,86.01 99.29,86.01 99.44,85.86 99.44,85.55 99.29,85.4 99.04,85.4 98.89,85.25 98.89,84.27 99.19,83.97 99.19,83 99.03,82.85 97.93,82.85 97.78,82.7 97.78,82.12 97.93,81.96 99.69,81.96 99.85,81.81 99.85,79.93 100.58,79.19 100.58,78.56 100.28,78.25 100.28,67.38 99.62,66.72 99.62,66.01 98.4,64.79 98.4,63.73
  BOTTOM w0.076: v2(98.27,62.39) 98.25,62.33 98.21,62.31 UU1.AJ42
  BOTTOM w0.165: UD3.E11 v1(97.96,90.21)
M_B_DQ_1[6]: length 37.3
  ART06 w0.076: v2(97.36,62.34) 97.36,62.47 97,62.83 97,63.17 97.38,63.55 97.38,64.44 97.17,64.65 97.17,65.22
  ART06 w0.14: 97.17,65.22 97.17,66.46 97.81,67.1 97.81,68.63 97.03,69.42 97.03,73.5 97.18,73.65 97.43,73.65 97.58,73.8 97.58,74.11 97.43,74.26 97.18,74.26 97.03,74.41 97.03,74.72 97.18,74.87 97.43,74.87 97.58,75.02 97.58,75.33 97.43,75.48 97.18,75.48 97.03,75.63 97.03,75.94 97.18,76.09 97.43,76.09 97.58,76.24 97.58,76.55 97.43,76.7 97.18,76.7 97.03,76.85 97.03,78.31 95.32,80.01 95.32,91.34 96.87,92.89 97.89,92.89 v1(97.96,92.81)
  BOTTOM w0.076: UU1.AL42 97.25,62.29 v2(97.36,62.34)
  BOTTOM w0.165: UD3.B11 v1(97.96,92.81)
M_B_DQ_1[7]: length 35.8
  ART06 w0.14: v2(98.27,62.98) 98.14,63.1 98.14,64.95 99.36,66.16 99.36,66.82 99.9,67.36 99.9,68 99.74,68.15 99.59,68.15 99.44,68.31 99.44,68.61 99.59,68.76 99.74,68.76 99.9,68.92 99.9,69.22 99.74,69.37 99.59,69.37 99.44,69.52 99.44,69.83 99.59,69.98 99.74,69.98 99.9,70.13 99.9,70.44 99.74,70.59 99.59,70.59 99.44,70.74 99.44,71.18 99.59,71.33 99.72,71.33 99.87,71.48 99.87,71.79 99.72,71.94 99.59,71.94 99.44,72.09 99.44,72.4 99.59,72.55 99.72,72.55 99.87,72.7 99.87,73.01 99.72,73.16 99.59,73.16 99.44,73.31 99.44,73.62 99.59,73.77 99.72,73.77 99.87,73.92 99.87,74.23 99.72,74.38 99.59,74.38 99.44,74.53 99.44,74.84 99.59,74.99 99.72,74.99 99.87,75.14 99.87,75.45 99.72,75.6 99.59,75.6 99.44,75.75 99.44,76.06 99.59,76.21 99.72,76.21 99.87,76.36 99.87,76.67 99.72,76.82 99.59,76.82 99.44,76.97 99.44,77.36 99.59,77.51 99.74,77.51 99.9,77.66 99.9,77.97 99.74,78.12 99.59,78.12 99.44,78.27 99.44,81.4 99.26,81.58 97.53,81.58 97.38,81.73 97.38,83.07 97.56,83.26 98.19,83.26 98.35,83.41 98.35,84.07 98.49,84.21 98.49,89.04 v1(97.96,89.56)
  BOTTOM w0.076: UU1.AJ43 v2(98.27,62.98)
  BOTTOM w0.165: UD3.F11 v1(97.96,89.56)
M_B_DQ_2[0]: length 20.8
  BOTTOM w0.076: 101.66,68.39 101.14,67.88 101.14,66.9 101.32,66.73 101.32,66.04 101.25,65.97 UU1.AB49
  BOTTOM w0.165: 101.66,68.39 103.27,70.01 103.27,73.28 107.49,77.49 107.49,78.5 107.19,78.81 107.19,79.16 107.49,79.47 107.49,79.82 107.19,80.13 107.19,80.48 107.49,80.79 107.49,81 106.73,81.76 105.9,81.76 UD3.V2
M_B_DQ_2[1]: length 22.1
  BOTTOM w0.076: UU1.AB48 101.5,65.68 101.5,66.78 101.34,66.94 101.34,67.66 101.84,68.16
  BOTTOM w0.165: UD3.U2 105.9,82.41 107.28,82.41 107.82,81.86 107.82,77.37 103.6,73.15 103.6,69.92 101.84,68.16
M_B_DQ_2[2]: length 19.9
  BOTTOM w0.076: UU1.AE49 99.92,65.86 99.92,66.75 100.22,67.05 100.22,68.95 100.72,69.45
  BOTTOM w0.165: UD3.AA4 103.58,79.73 103.58,79.35 102.96,78.73 102.96,78.45 103.13,78.28 103.9,78.28 104.06,78.12 104.06,76.75 103.9,76.59 103.62,76.59 103.22,76.98 102.63,76.98 102.46,76.82 102.46,76.5 102.63,76.33 103.08,76.33 103.25,76.17 103.25,75.86 103.08,75.7 102.63,75.7 102.46,75.53 102.46,75.08 101.42,74.04 101.42,70.15 100.72,69.45
M_B_DQ_2[3]: length 20.8
  BOTTOM w0.076: 100.22,69.82 99.89,69.49 99.89,67.22 99.56,66.9 99.56,65.63 99.58,65.62 99.72,65.42 99.72,65.03 99.8,64.89 UU1.AE47
  BOTTOM w0.165: UD3.V4 103.65,82.41 102.55,82.41 102.28,82.14 102.28,81.63 102.09,81.44 102.09,78.34 101.8,78.05 101.8,75.36 100.75,74.31 100.75,70.35 100.22,69.82
M_B_DQ_2[4]: length 21.2
  BOTTOM w0.076: 100.48,69.64 100.05,69.22 100.05,67.15 99.73,66.83 99.73,65.71 99.9,65.45 UU1.AE48
  BOTTOM w0.165: 100.48,69.64 101.09,70.25 101.09,74.19 102.13,75.23 102.13,77.2 102.3,77.37 103.58,77.37 103.7,77.48 103.7,77.73 103.53,77.9 102.65,77.9 102.49,78.06 102.49,78.81 102.35,78.95 102.35,80.94 102.52,81.11 103.65,81.11 UD3.Y4
M_B_DQ_2[5]: length 21.3
  BOTTOM w0.076: UU1.AB47 101.1,64.66 101.05,64.78 101.03,64.92 101.03,66 101.15,66.13 101.15,66.66 100.96,66.85 100.96,68.07 101.5,68.6
  BOTTOM w0.165: 101.5,68.6 102.94,70.05 102.94,73.4 105.71,76.17 105.71,76.71 105.99,76.98 106.53,76.98 107.16,77.62 107.16,78.28 107,78.44 106.46,78.44 106.3,78.61 106.3,78.94 106.46,79.1 106.64,79.1 106.81,79.27 106.81,80.21 106.56,80.46 105.9,80.46 UD3.Y2
M_B_DQ_2[6]: length 26.1
  BOTTOM w0.076: UU1.AB45 101.54,64.36 101.54,65.18 101.66,65.66 101.66,66.94 101.6,67 101.6,67.54 102,67.94
  BOTTOM w0.165: 102,67.94 103.93,69.87 103.93,73.02 108.15,77.24 108.15,82.7 107.79,83.06 104.67,83.06 UD3.U4
M_B_DQ_2[7]: length 20.7
  BOTTOM w0.076: 101.37,68.86 100.78,68.26 100.78,66.78 100.99,66.57 100.99,66.24 100.86,66.11 100.86,64.5 100.91,64.42 100.91,64.03 100.72,63.84 UU1.AE45
  BOTTOM w0.165: UD3.AA2 105.98,79.73 105.98,78.26 106.14,78.1 106.49,78.1 106.65,77.93 106.65,77.6 106.49,77.44 105.81,77.44 105.31,76.93 105.31,76.22 102.61,73.53 102.61,70.1 101.37,68.86
M_B_DQ_3[0]: length 46.5
  ART06 w0.14: v1(104.36,92.81) 105.1,93.55 107.57,93.55 112.09,89.02 112.09,73.3 106.55,67.76 106.55,64.59 105.2,63.24 105.2,61.57 104.21,60.58 104.21,60.27 103.91,59.97 101.49,59.97 v2(101.02,60.44)
  BOTTOM w0.076: UU1.AD38 100.57,60.16 v2(101.02,60.44)
  BOTTOM w0.165: UD3.B4 v1(104.36,92.81)
M_B_DQ_3[1]: length 44.5
  ART06 w0.14: v1(104.36,92.16) 105.42,93.22 107.39,93.22 111.73,88.87 111.73,73.43 106.17,67.87 106.17,64.72 104.01,62.56 103.55,62.56 103.3,62.81 101.85,62.81 101.55,62.51 101.55,61.6 v2(101.02,61.07)
  BOTTOM w0.076: v2(101.02,61.07) 100.95,61.04 UU1.AD39
  BOTTOM w0.165: UD3.C4 v1(104.36,92.16)
M_B_DQ_3[2]: length 45.2
  ART06 w0.089: v2(100.1,61.07) 99.73,61.45 99.73,62.57 99.56,62.73 99.56,63.44 100.05,63.93 100.05,64.08
  ART06 w0.14: 100.05,64.08 100.05,64.67 102.46,67.08 102.46,72.95 102.8,73.28 102.8,73.5 102.51,73.79 102.51,74.01 102.72,74.22 102.94,74.22 103.23,73.93 103.44,73.93 105.79,76.27 105.79,76.84 105.64,76.99 103.02,76.99 102.87,77.14 102.87,77.45 103.02,77.6 105.64,77.6 105.79,77.75 105.79,78.03 105.64,78.19 105.05,78.19 104.9,78.34 104.9,78.64 105.05,78.79 105.64,78.79 105.79,78.95 105.79,79.25 105.64,79.4 105.05,79.4 104.9,79.56 104.9,79.86 105.05,80.01 105.64,80.01 105.79,80.17 105.79,80.46 105.54,80.72 104.9,80.72 104.52,81.1 104.52,85.16 104.9,85.54 105.28,85.54 105.79,86.05 105.79,86.69 105.36,87.12 105,87.12 104.7,87.42 104.7,89.08 v1(103.56,90.21)
  BOTTOM w0.076: UU1.AE39 v2(100.1,61.07)
  BOTTOM w0.165: UD3.E4 v1(103.56,90.21)
M_B_DQ_3[3]: length 45.3
  ART06 w0.14: v1(105.96,90.21) 105.96,90.2 106.42,89.74 107.12,89.74 109.73,87.12 109.73,80.11 109.57,79.95 107.08,79.95 106.93,79.8 106.93,79.5 107.08,79.35 109.37,79.35 109.52,79.19 109.52,78.89 109.37,78.74 107.08,78.74 106.93,78.58 106.93,78.28 107.08,78.13 109.37,78.13 109.52,77.97 109.52,77.7 109.37,77.54 107.08,77.54 106.93,77.39 106.93,76.15 103.2,72.42 103.2,66.98 100.63,64.41 100.63,63.88 100.1,63.35 v2(100.1,62.98)
  BOTTOM w0.076: UU1.AE43 v2(100.1,62.98)
  BOTTOM w0.165: UD3.E2 v1(105.96,90.21)
M_B_DQ_3[4]: length 44.7
  ART06 w0.089: 99.74,64.03 99.74,63.9 99.38,63.54 99.38,62.66 99.55,62.49 99.55,60.99 v2(100.1,60.44)
  ART06 w0.14: 99.74,64.03 99.74,64.79 101.6,66.65 101.6,67.46 101.85,67.71 101.85,74.24 102.38,74.77 103.6,74.77 103.76,74.92 103.76,75.23 103.6,75.38 102.39,75.38 102.23,75.53 102.23,75.82 102.39,75.98 104.87,75.98 105.03,76.13 105.03,76.43 104.87,76.59 102.64,76.59 102.49,76.74 102.49,78.06 102.64,78.22 103.73,78.22 103.88,78.37 103.88,78.67 103.73,78.82 103.4,78.82 103.25,78.98 103.25,79.28 103.4,79.43 103.73,79.43 103.88,79.59 103.88,79.8 103.73,79.96 103.27,79.96 103.12,80.11 103.12,80.82 103.27,80.97 103.88,80.97 104.14,81.23 104.14,85.29 104.65,85.8 105.15,85.8 105.43,86.07 105.43,86.54 105.18,86.79 104.72,86.79 104.39,87.12 104.39,88.73 v1(103.56,89.56)
  BOTTOM w0.076: UU1.AE38 v2(100.1,60.44)
  BOTTOM w0.165: UD3.F4 v1(103.56,89.56)
M_B_DQ_3[5]: length 44
  ART06 w0.14: v1(105.96,92.16) 106.39,92.58 107.01,92.58 107.91,91.68 107.91,91.3 108.15,91.06 108.53,91.06 108.77,90.82 108.77,90.44 109.01,90.2 109.39,90.2 111,88.59 111,76.25 110.37,75.62 110.37,75.41 110.65,75.13 110.65,74.91 110.44,74.7 110.22,74.7 109.94,74.98 109.72,74.98 109.51,74.76 109.51,74.55 109.79,74.27 109.79,74.05 109.57,73.84 109.36,73.84 109.08,74.11 108.86,74.11 108.65,73.9 108.65,73.68 108.93,73.4 108.93,73.19 108.71,72.97 108.5,72.97 108.22,73.25 108,73.25 107.74,72.99 107.74,72.78 108.13,72.38 108.13,72.17 105.41,69.44 105.41,66.88 104.41,65.88 104.41,65.66 105.08,64.99 105.08,64.77 104.87,64.56 104.65,64.56 103.98,65.23 103.76,65.23 102.11,63.57 101.83,63.57 101.23,62.98 v2(101.02,62.98)
  BOTTOM w0.076: UU1.AD43 100.66,62.76 100.76,62.85 100.9,62.92 v2(101.02,62.98)
  BOTTOM w0.165: UD3.C2 v1(105.96,92.16)
M_B_DQ_3[6]: length 43.6
  ART06 w0.14: v1(105.96,92.81) 106.04,92.89 107.21,92.89 111.38,88.72 111.38,74.55 110.21,73.38 110.21,73.16 110.31,73.06 110.31,72.85 110.1,72.63 109.88,72.63 109.78,72.73 109.56,72.73 109.26,72.43 109.26,72.21 109.32,72.15 109.32,71.93 109.11,71.72 108.89,71.72 108.83,71.78 108.61,71.78 108.4,71.56 108.4,71.35 108.46,71.29 108.46,71.07 108.24,70.85 108.03,70.85 107.96,70.92 107.75,70.92 107.53,70.7 107.53,70.49 107.79,70.23 107.79,70.02 105.79,68.02 105.79,66.62 105.15,65.99 105.15,65.73 105.77,65.12 105.77,64.9 104.44,63.57 104.13,63.57 103.98,63.73 103.98,64.18 103.83,64.34 103.52,64.34 103.37,64.18 103.37,63.44 103.12,63.19 101.87,63.19 v2(101.02,62.34)
  BOTTOM w0.076: UU1.AD42 100.94,62.31 v2(101.02,62.34)
  BOTTOM w0.165: UD3.B2 v1(105.96,92.81)
M_B_DQ_3[7]: length 44.8
  ART06 w0.089: 100.3,64.11 100.3,63.88 99.74,63.31 99.74,62.83 100.1,62.46 v2(100.1,62.34)
  ART06 w0.14: 100.3,64.11 100.3,64.49 102.84,67.03 102.84,72.69 106.42,76.27 106.42,80.28 106.58,80.43 109.19,80.43 109.35,80.59 109.35,80.89 109.19,81.04 108.1,81.04 107.95,81.2 107.95,81.5 108.1,81.65 109.19,81.65 109.35,81.8 109.35,82.11 109.19,82.26 108.23,82.26 108.08,82.41 108.08,82.72 108.23,82.87 109.19,82.87 109.35,83.02 109.35,83.33 109.19,83.48 107.95,83.48 107.8,83.63 107.8,83.94 107.95,84.09 109.19,84.09 109.35,84.24 109.35,84.55 109.19,84.7 108.46,84.7 108.3,84.85 108.3,85.16 108.46,85.31 109.19,85.31 109.35,85.46 109.35,86.97 106.96,89.35 106.17,89.35 v1(105.96,89.56)
  BOTTOM w0.076: UU1.AE42 v2(100.1,62.34)
  BOTTOM w0.165: UD3.F2 v1(105.96,89.56)
M_B_DQ_4[0]: length 41.6
  BOTTOM w0.076: UU1.J48 107.48,65.27 107.36,65.71 107.36,66.66 107.49,66.79 107.49,67.31 107.76,67.58
  BOTTOM w0.165: UD4.C9 117.96,92.16 118.93,92.16 119.26,92.48 119.26,93.64 118.21,94.69 113.21,94.69 109.22,90.7 109.22,69.03 107.76,67.58
M_B_DQ_4[1]: length 39.2
  BOTTOM w0.076: UU1.J45 108.41,63.84 108.58,64.01 108.58,64.79 108.49,64.99 108.49,65.15 108.53,65.41 108.53,65.58 108.48,65.67 108.48,66 108.7,66.32 108.7,66.69 109.02,67
  BOTTOM w0.165: UD4.B11 115.71,92.81 114.4,92.81 110.83,89.24 110.83,88.96 110.97,88.81 112.12,88.81 112.27,88.67 112.27,88.46 112.12,88.32 110.97,88.32 110.83,88.17 110.83,87.97 110.97,87.82 112.12,87.82 112.27,87.68 112.27,87.47 112.12,87.33 110.97,87.33 110.83,87.18 110.83,68.81 109.02,67
M_B_DQ_4[2]: length 38.4
  BOTTOM w0.076: UU1.J49 107.54,65.86 107.54,66.59 107.69,66.74 107.69,67.13 107.96,67.4
  BOTTOM w0.165: 107.96,67.4 109.6,69.03 109.6,90.5 113.41,94.31 116.72,94.31 116.88,94.14 116.88,94.09 117.05,93.93 117.38,93.93 117.54,94.09 117.54,94.14 117.71,94.31 117.98,94.31 118.4,93.89 118.4,93.66 118.03,93.29 118.03,92.65 117.87,92.48 UD4.B9
M_B_DQ_4[3]: length 39.2
  BOTTOM w0.076: 109.19,66.82 108.87,66.5 108.87,66.27 108.64,65.95 108.64,65.71 108.69,65.62 108.69,65.39 108.65,65.14 108.65,65.06 108.89,64.54 UU1.G47
  BOTTOM w0.165: 109.19,66.82 111.19,68.82 111.19,84.68 111.38,84.87 112.48,84.87 112.65,85.03 112.65,85.27 112.5,85.41 111.4,85.41 111.25,85.56 111.25,85.76 111.4,85.91 112.5,85.91 112.65,86.05 112.65,86.26 112.5,86.4 111.4,86.4 111.25,86.55 111.25,86.75 111.4,86.9 112.5,86.9 112.65,87.04 112.65,89.08 112.5,89.23 111.78,89.23 111.63,89.37 111.63,89.58 111.78,89.72 112.5,89.72 112.65,89.87 112.65,90.5 114.31,92.16 115.71,92.16 UD4.C11
M_B_DQ_4[4]: length 44.7
  BOTTOM w0.076: UU1.J47 107.32,65.1 107.32,65.24 107.2,65.69 107.2,66.75 107.31,66.87 107.31,67.5 107.56,67.75
  BOTTOM w0.165: UD4.E9 117.96,90.86 118.84,90.86 119.25,91.26 119.63,92.28 119.63,93.77 118.39,95.02 112.99,95.02 108.84,90.87 108.84,69.03 107.56,67.75
M_B_DQ_4[5]: length 40.1
  BOTTOM w0.076: 110.21,67.03 109.9,66.72 109.9,66.19 109.55,65.83 109.55,65.58 109.29,65.33 109.29,65.01 109.17,64.89 109.17,64.36 108.89,64.08 UU1.G45
  BOTTOM w0.165: UD4.F11 115.7,90.22 113.64,90.22 113.41,89.99 113.41,89.63 113.55,89.48 113.7,89.48 113.84,89.34 113.84,89.13 113.7,88.99 113.55,88.99 113.41,88.84 113.41,88.6 113.55,88.45 114.23,88.45 114.37,88.31 114.37,88.1 114.23,87.96 113.55,87.96 113.41,87.81 113.41,87.61 113.55,87.46 114.23,87.46 114.37,87.32 114.37,87.11 114.23,86.97 113.55,86.97 113.41,86.82 113.41,86.13 113.74,85.8 113.74,85.52 113.41,85.19 113.41,84.53 113.03,84.15 112.6,84.15 112.47,84.02 112.47,75.26 112.32,75.11 112.03,75.11 111.89,74.97 111.89,74.76 112.03,74.62 112.32,74.62 112.47,74.47 112.47,74.27 112.32,74.12 112.03,74.12 111.89,73.98 111.89,73.77 112.03,73.63 112.32,73.63 112.47,73.48 112.47,73.28 112.32,73.13 112.03,73.13 111.89,72.99 111.89,72.78 112.03,72.64 112.32,72.64 112.47,72.49 112.47,72.29 112.32,72.14 112.03,72.14 111.89,72 111.89,71.79 112.03,71.65 112.32,71.65 112.47,71.5 112.47,71.3 112.32,71.15 112.03,71.15 111.89,71.01 111.89,70.8 112.03,70.66 112.32,70.66 112.47,70.51 112.47,70.31 112.32,70.16 112.03,70.16 111.89,70.02 111.89,69.81 112.03,69.67 112.32,69.67 112.47,69.52 112.47,69.29 110.21,67.03
M_B_DQ_4[6]: length 38.9
  BOTTOM w0.076: 110.03,67.21 109.7,66.88 109.7,66.24 109.35,65.89 109.35,65.71 108.94,65.3 UU1.G48
  BOTTOM w0.165: 110.03,67.21 111.53,68.71 111.53,75.39 111.67,75.54 111.99,75.54 112.14,75.68 112.14,75.89 111.99,76.03 111.67,76.03 111.53,76.18 111.53,76.38 111.67,76.53 111.99,76.53 112.14,76.67 112.14,76.88 111.99,77.02 111.67,77.02 111.53,77.17 111.53,77.37 111.67,77.52 111.99,77.52 112.14,77.66 112.14,77.87 111.99,78.01 111.67,78.01 111.53,78.16 111.53,78.36 111.67,78.51 111.99,78.51 112.14,78.65 112.14,78.86 111.99,79 111.67,79 111.53,79.15 111.53,79.35 111.67,79.5 111.99,79.5 112.14,79.64 112.14,79.85 111.99,79.99 111.67,79.99 111.53,80.14 111.53,80.34 111.67,80.49 111.99,80.49 112.14,80.63 112.14,80.84 111.99,80.99 111.67,80.99 111.53,81.13 111.53,81.34 111.67,81.48 111.99,81.48 112.14,81.63 112.14,81.83 111.99,81.98 111.67,81.98 111.53,82.12 111.53,82.33 111.67,82.47 111.99,82.47 112.14,82.62 112.14,82.82 111.99,82.97 111.67,82.97 111.53,83.11 111.53,83.32 111.67,83.46 111.99,83.46 112.14,83.61 112.14,83.81 111.99,83.96 111.67,83.96 111.53,84.1 111.53,84.36 111.69,84.53 112.77,84.53 113.03,84.78 113.03,90.12 114.09,91.18 114.53,91.18 114.85,90.86 115.71,90.86 UD4.E11
M_B_DQ_4[7]: length 39.5
  BOTTOM w0.076: UU1.E48 109.73,65.74 110.11,66.11 110.11,66.55 110.46,66.9
  BOTTOM w0.165: 110.46,66.9 112.63,66.9 112.8,67.07 112.8,67.28 112.65,67.42 111.75,67.42 111.61,67.57 111.61,67.78 111.75,67.92 112.65,67.92 112.8,68.07 112.8,83.28 113.79,84.27 113.79,84.88 114.17,85.27 114.17,85.95 114.55,86.33 116.76,86.33 117.27,86.84 119.8,86.84 119.96,87.01 119.96,87.45 119.8,87.62 119.44,87.62 119.28,87.79 119.28,88.12 119.44,88.28 119.8,88.28 119.96,88.45 119.96,90.28 119.8,90.45 119.42,90.45 119.25,90.28 119.25,89.68 119.12,89.56 117.96,89.56 UD4.F9
M_B_DQ_5[0]: length 45.4
  ART06 w0.089: v2(108.34,60.44) 107.78,60.99 107.78,62.49 107.31,62.96 107.31,63.45
  ART06 w0.14: 107.31,63.45 107.31,64.46 107.06,64.72 107.06,66.57 107.49,67 107.49,67.43 112.88,72.82 112.88,88.85 114.15,90.12 115.06,90.12 116.25,91.31 116.25,91.82 116.79,92.35 119,92.35 119.81,93.16 123.26,93.16 v1(123.62,92.81)
  BOTTOM w0.075: v2(108.34,60.44) 108.34,60.43 108.33,60.43 UU1.J38
  BOTTOM w0.165: UD4.B2 v1(123.62,92.81)
M_B_DQ_5[1]: length 40.2
  ART06 w0.14: v2(109.23,61.07) 110.97,62.81 113.54,62.81 114.3,63.57 114.3,68.53 127,81.23 127,86.51 126.41,87.09 126.41,87.5 124.56,89.35 123.82,89.35 v1(123.62,89.56)
  BOTTOM w0.165: v2(109.23,61.07) 109.22,61.05 UU1.G39 ; UD4.F2 v1(123.62,89.56)
M_B_DQ_5[2]: length 41.6
  ART06 w0.14: v2(109.25,60.44) 111.25,62.43 113.66,62.43 114.68,63.45 114.68,68.27 127.38,80.97 127.38,86.61 126.77,87.22 126.77,87.6 124.64,89.74 124.09,89.74 v1(123.62,90.21)
  BOTTOM w0.075: v2(109.25,60.44) 109.05,60.32 UU1.G38
  BOTTOM w0.165: UD4.E2 v1(123.62,90.21)
M_B_DQ_5[3]: length 41.1
  ART06 w0.14: v1(122.02,89.56) 122.12,89.45 122.12,87.45 122.38,87.2 122.81,87.2 123.44,86.56 123.44,85.93 123.06,85.54 122.55,85.54 122.3,85.29 122.3,81.92 122.45,81.77 122.91,81.77 123.06,81.61 123.06,81.31 122.91,81.16 122.45,81.16 122.3,81 122.3,77.32 122.15,77.16 121.82,77.16 121.66,77.32 121.66,78.15 121.51,78.31 121.18,78.31 121.03,78.15 121.03,76.02 113.79,68.78 113.79,65.53 113.36,65.1 112.39,65.1 111.81,64.51 111.81,64.3 112.16,63.94 112.16,63.73 111.95,63.51 111.73,63.51 111.38,63.87 111.16,63.87 110.62,63.32 110.23,63.32 109.26,62.34 v2(109.25,62.34)
  BOTTOM w0.075: v2(109.25,62.34) 109.08,62.26 UU1.G42
  BOTTOM w0.165: UD4.F4 v1(122.02,89.56)
M_B_DQ_5[4]: length 43.7
  ART06 w0.089: v2(108.34,61.07) 107.96,61.45 107.96,62.57 107.66,62.86 107.66,63.32
  ART06 w0.14: 107.66,63.32 107.66,64.65 107.44,64.88 107.44,66.49 108.08,67.13 108.08,67.38 113.26,72.57 113.26,87.93 114.83,89.51 115.09,89.51 116.66,91.08 116.66,91.67 116.97,91.97 119.12,91.97 119.99,92.83 122.94,92.83 v1(123.62,92.16)
  BOTTOM w0.075: v2(108.34,61.07) 108.2,60.99 UU1.J39
  BOTTOM w0.165: UD4.C2 v1(123.62,92.16)
M_B_DQ_5[5]: length 40.9
  ART06 w0.089: 107.97,63.45 107.97,62.81 108.34,62.44 v2(108.34,62.34)
  ART06 w0.14: v1(122.02,92.16) 121.59,92.58 121,92.58 120.8,92.38 120.04,92.38 119.49,91.83 119.49,91.5 119.05,91.06 117.88,91.06 117.22,90.4 117.22,89.89 116.2,88.87 116.2,80.97 115.06,79.83 115.06,75.73 115.21,75.58 115.92,75.58 116.08,75.42 116.08,75.12 115.92,74.97 115.21,74.97 115.06,74.81 115.06,73.73 107.82,66.49 107.82,65.1 107.97,64.94 107.97,63.45
  BOTTOM w0.075: UU1.J42 108.17,62.26 v2(108.34,62.34)
  BOTTOM w0.165: UD4.B4 v1(122.02,92.16)
M_B_DQ_5[6]: length 41.9
  ART06 w0.14: v2(109.25,62.98) 109.85,63.58 109.85,63.7 110.63,64.48 110.63,64.7 110.47,64.86 110.47,65.08 110.68,65.29 110.9,65.29 111.06,65.13 111.28,65.13 111.61,65.45 111.61,66.75 111.73,66.88 111.99,66.88 112.14,67.03 112.14,67.99 112.29,68.15 112.6,68.15 112.75,67.99 112.75,66.65 112.9,66.49 113.26,66.49 113.41,66.65 113.41,69.03 120.52,76.15 120.52,79.07 120.9,79.45 121.79,79.45 121.94,79.6 121.94,80.78 121.79,80.93 121.69,80.93 121.54,81.08 121.54,81.39 121.69,81.54 121.79,81.54 121.94,81.69 121.94,82 121.79,82.15 121.69,82.15 121.54,82.3 121.54,82.61 121.69,82.76 121.79,82.76 121.94,82.91 121.94,83.22 121.79,83.37 121.69,83.37 121.54,83.52 121.54,83.83 121.69,83.98 121.79,83.98 121.94,84.13 121.94,85.57 122.17,85.8 122.81,85.8 123.06,86.05 123.06,86.56 122.81,86.81 122.27,86.81 121.71,87.37 121.71,89.2 121.22,89.7 v1(121.22,90.21)
  BOTTOM w0.089: UU1.G43 v2(109.25,62.98)
  BOTTOM w0.165: v1(121.22,90.21) UD4.E4
M_B_DQ_5[7]: length 41.7
  ART06 w0.089: 108.84,65.35 108.34,64.85 v2(108.34,62.98)
  ART06 w0.14: 108.84,65.35 108.84,66.88 116.61,74.65 116.61,76.28 116.46,76.43 115.85,76.43 115.7,76.59 115.7,76.89 115.85,77.04 116.46,77.04 116.61,77.19 116.61,77.62 116.46,77.77 115.72,77.77 115.57,77.92 115.57,78.23 115.72,78.38 116.46,78.38 116.61,78.53 116.61,78.84 116.46,78.99 115.72,78.99 115.57,79.14 115.57,79.45 115.72,79.6 116.46,79.6 116.61,79.75 116.61,81.28 116.58,81.3 116.58,88.87 117.52,89.81 117.52,90.29 117.9,90.68 119.07,90.68 119.81,91.41 119.81,91.67 120.06,91.92 120.98,91.92 v1(121.22,92.16)
  BOTTOM w0.089: UU1.J43 v2(108.34,62.98)
  BOTTOM w0.165: v1(121.22,92.16) UD4.C4
M_B_DQ_6[0]: length 28.4
  BOTTOM w0.076: UU1.B43 111.62,62.91 113.86,62.91 114.43,63.47
  BOTTOM w0.165: 114.43,63.47 114.43,66.11 113.79,66.75 113.79,67.07 113.96,67.24 114.26,67.24 114.43,67.4 114.43,67.73 114.26,67.9 113.96,67.9 113.79,68.06 113.79,68.39 113.96,68.56 114.26,68.56 114.43,68.72 114.43,69.05 114.26,69.22 113.96,69.22 113.79,69.38 113.79,69.71 113.96,69.88 114.26,69.88 114.43,70.04 114.43,70.37 114.26,70.54 113.96,70.54 113.79,70.7 113.79,71.03 113.96,71.2 114.26,71.2 114.43,71.36 114.43,71.69 114.26,71.86 113.96,71.86 113.66,72.15 113.66,81.86 114.21,82.41 115.71,82.41 UD4.U11
M_B_DQ_6[1]: length 28.8
  BOTTOM w0.076: 114.04,63.42 113.7,63.07 111.48,63.07 111.34,62.94 110.35,62.94 UU1.D43
  BOTTOM w0.165: 114.04,63.42 114.04,65.99 113.28,66.75 113.28,82.79 113.73,83.23 114.88,83.23 115.06,83.06 117.31,83.06 UD4.U9
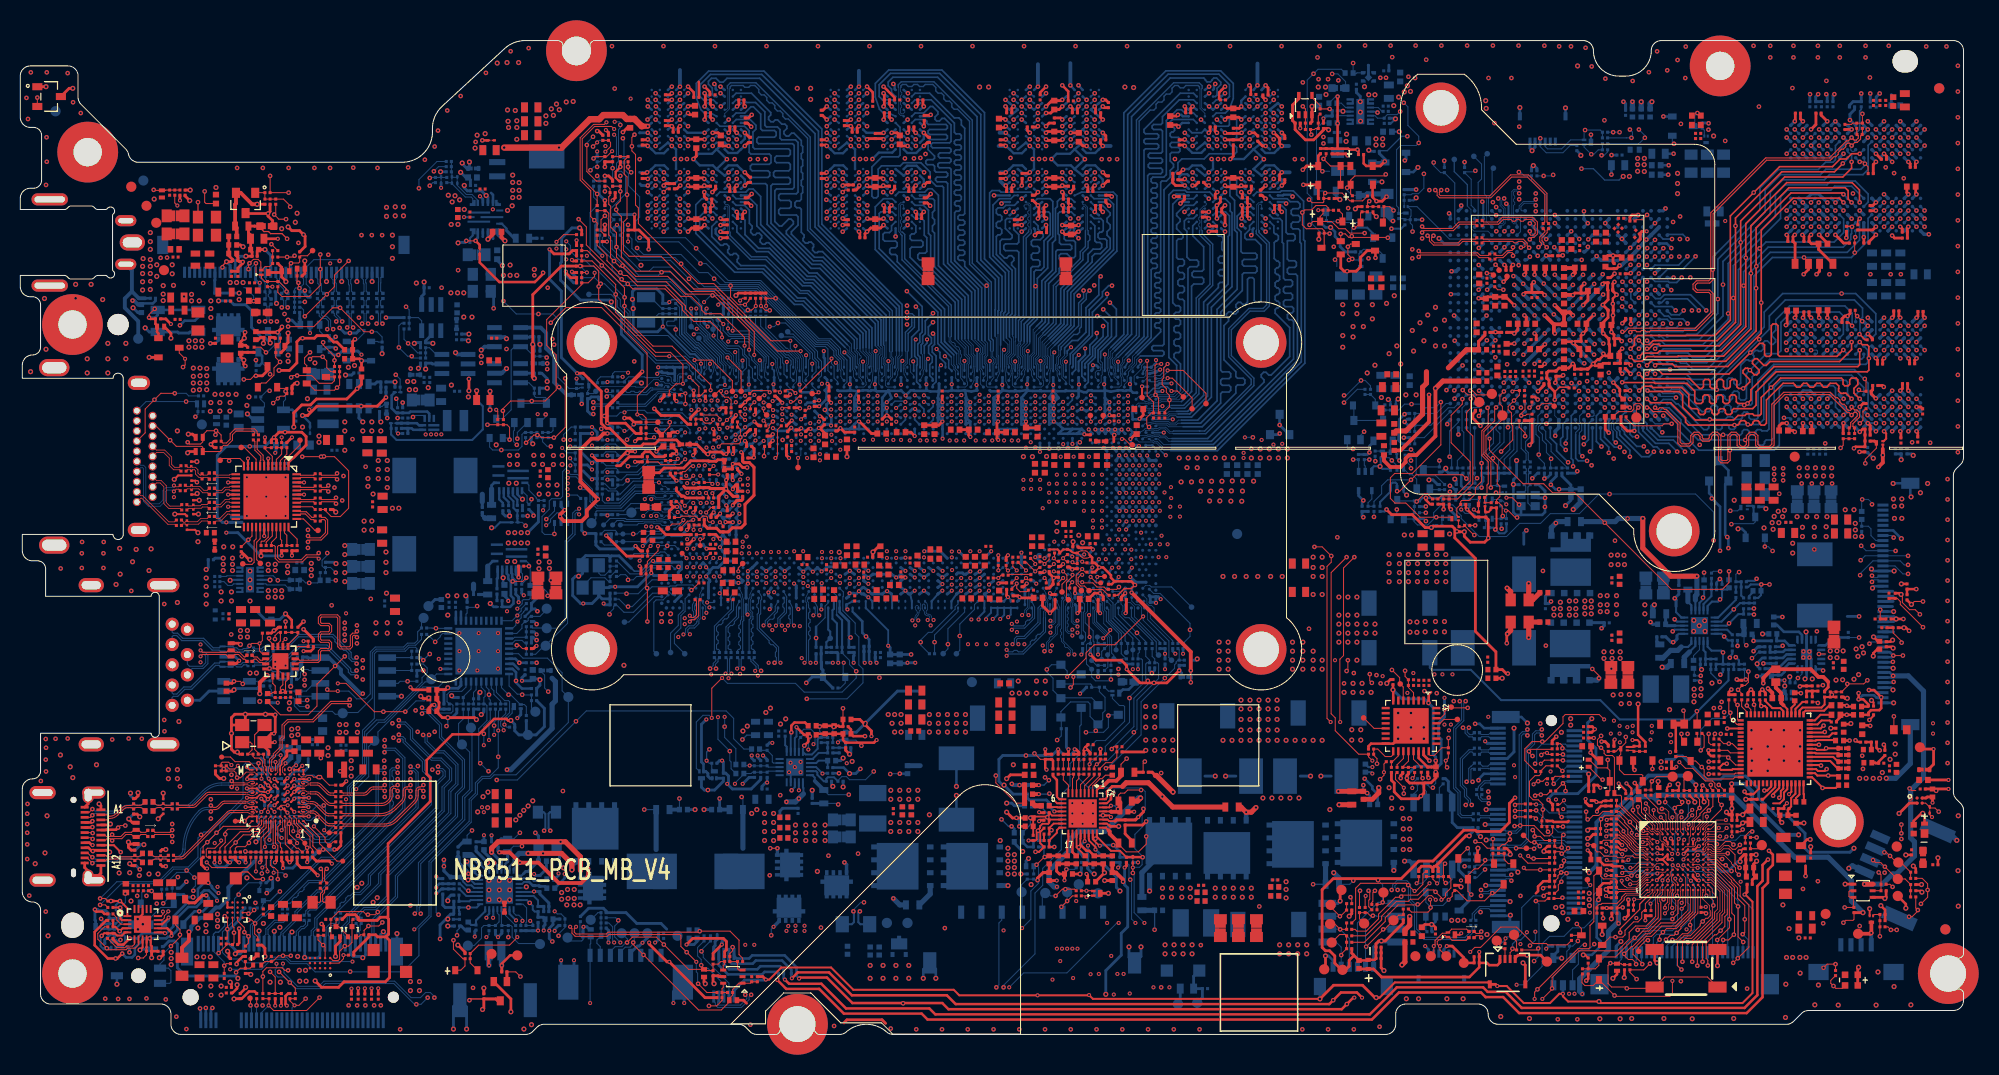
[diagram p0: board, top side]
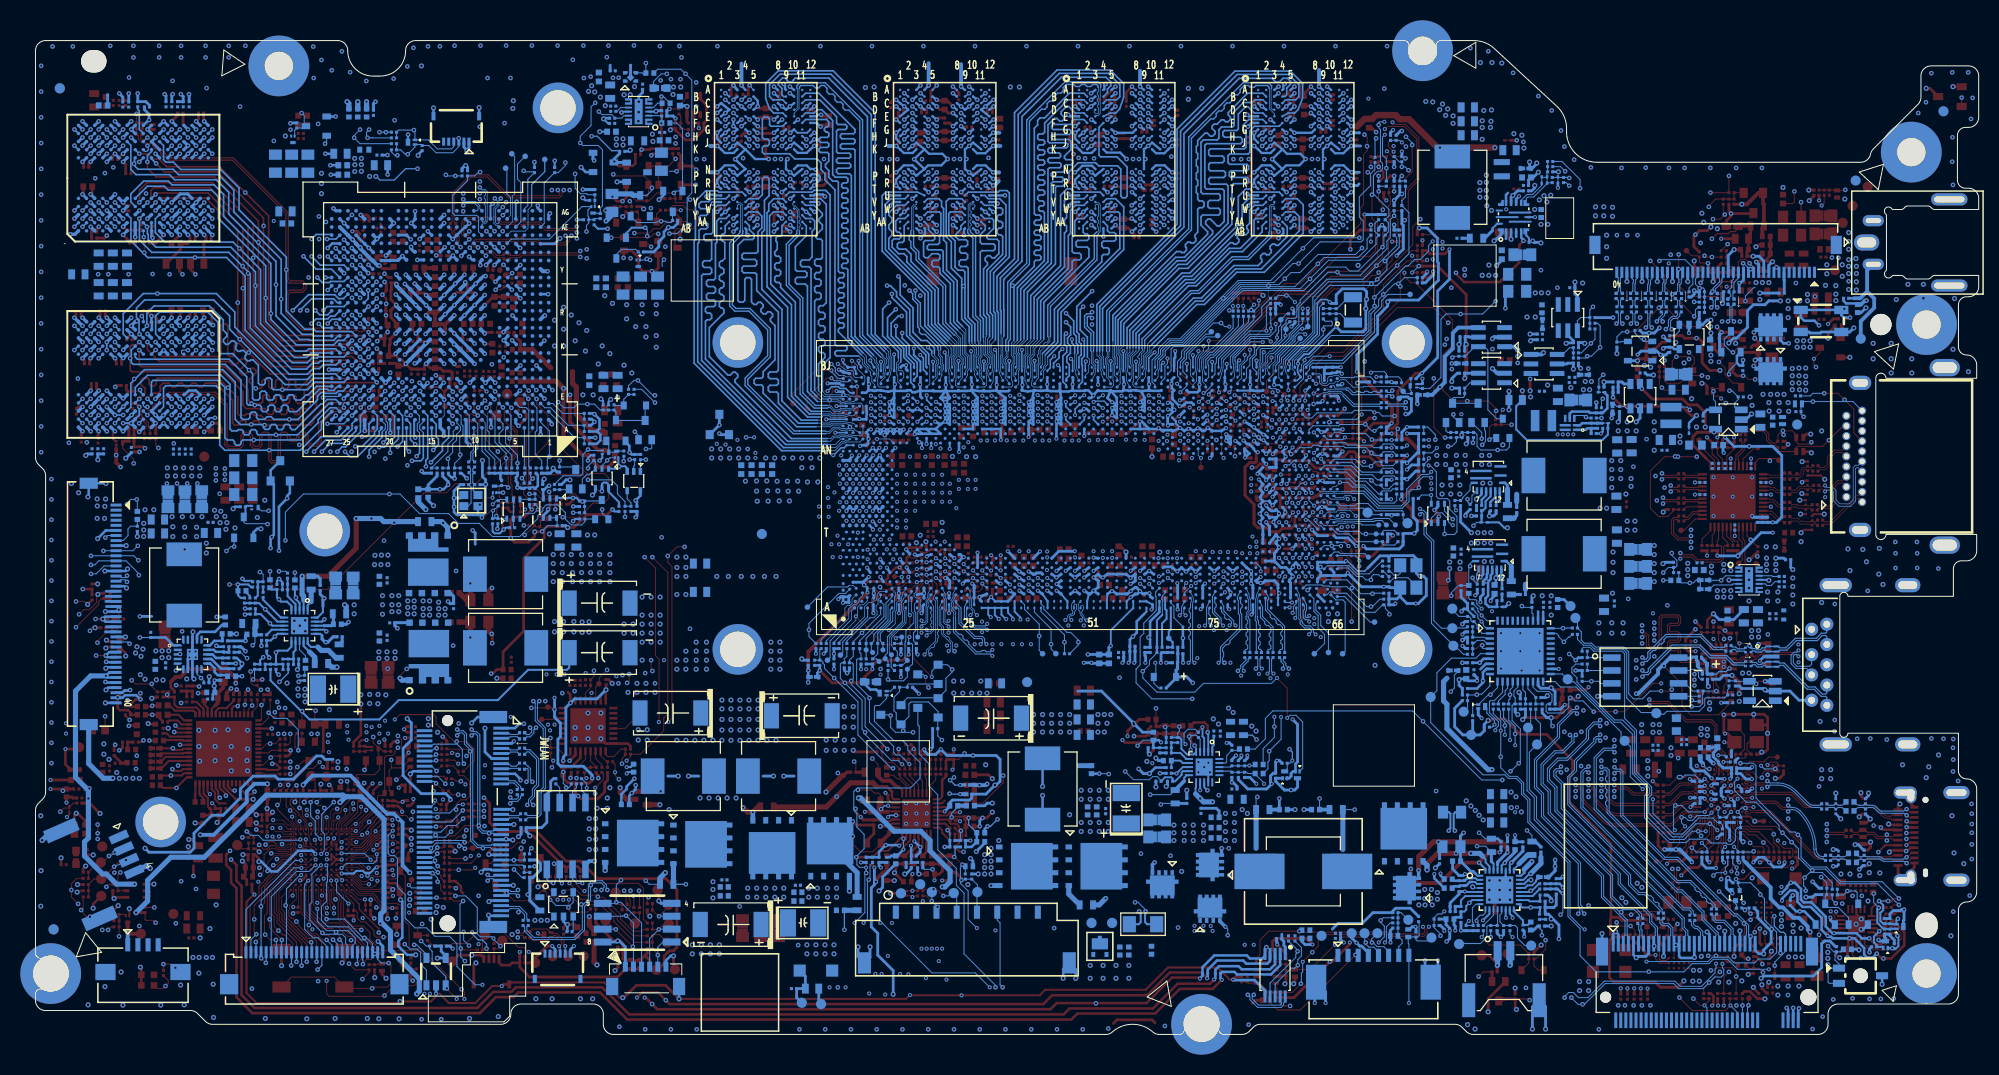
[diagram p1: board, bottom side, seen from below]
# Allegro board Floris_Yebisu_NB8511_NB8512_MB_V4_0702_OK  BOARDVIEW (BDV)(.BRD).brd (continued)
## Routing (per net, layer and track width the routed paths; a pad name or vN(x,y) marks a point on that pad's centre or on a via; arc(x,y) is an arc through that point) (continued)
M_B_DQ_6[2]: length 27.3
  BOTTOM w0.076: 114.81,63.52 114.03,62.74 112.11,62.74 UU1.A43
  BOTTOM w0.165: UD4.V11 115.71,81.76 114.85,81.76 114.04,80.95 114.04,80.74 114.38,80.4 114.38,80.17 114.04,79.83 114.04,79.45 114.68,78.81 114.68,78.59 114.51,78.43 114.21,78.43 114.04,78.26 114.04,76.61 114.21,76.45 114.64,76.45 114.81,76.28 114.81,75.95 114.64,75.79 114.34,75.79 114.17,75.62 114.17,75.29 114.34,75.13 114.64,75.13 114.81,74.96 114.81,74.63 114.64,74.46 114.34,74.46 114.17,74.3 114.17,73.97 114.34,73.8 114.64,73.8 114.81,73.64 114.81,73.31 114.64,73.14 114.34,73.14 114.17,72.98 114.17,72.65 114.34,72.48 114.64,72.48 114.81,72.32 114.81,63.52
M_B_DQ_6[3]: length 29.9
  BOTTOM w0.076: 114.09,60.88 113.97,61.01 113.38,61.01 113.24,60.87 111.96,60.87 111.45,61.01 110.99,61.01 UU1.C40
  BOTTOM w0.165: 114.09,60.88 115.52,60.88 117.47,62.84 117.47,71.7 119.51,73.73 119.51,81.02 119.33,81.2 119.33,81.91 118.83,82.41 117.96,82.41 UD4.V9
M_B_DQ_6[4]: length 25
  BOTTOM w0.076: UU1.C43 110.87,62.45 111.31,62.34 111.6,62.38 111.82,62.38 111.92,62.33 112.15,62.33 112.5,62.58 114.27,62.58 114.59,62.9
  BOTTOM w0.165: 114.59,62.9 115.16,63.47 115.16,75.51 115.35,75.7 116.04,75.7 116.2,75.87 116.2,76.2 116.04,76.36 115.35,76.36 115.06,76.65 115.06,79.19 114.81,79.45 114.81,80.21 115.05,80.46 115.71,80.46 UD4.Y11
M_B_DQ_6[5]: length 27
  BOTTOM w0.076: UU1.D40 110.04,62.04 110.26,62.25 110.97,62.25 111.29,62.17 111.61,62.22 111.78,62.22 111.88,62.17 112.21,62.16 112.53,62.39 114.51,62.39
  BOTTOM w0.165: UD4.AA11 115.63,79.73 115.63,78.75 116.71,77.67 116.71,75.42 116.55,75.26 115.73,75.26 115.57,75.09 115.57,74.82 115.73,74.65 116.55,74.65 116.71,74.49 116.71,74.16 116.55,73.99 115.73,73.99 115.52,73.78 115.52,63.4 114.51,62.39
M_B_DQ_6[6]: length 27.2
  BOTTOM w0.076: UU1.B40 111.48,61.17 111.98,61.03 113.15,61.03 113.31,61.19 114.2,61.19
  BOTTOM w0.165: 114.2,61.19 115.34,61.19 117.09,62.94 117.09,71.96 119.12,73.99 119.12,78.69 119.25,78.81 119.25,80.72 118.86,81.11 117.96,81.11 UD4.Y9
M_B_DQ_6[7]: length 25.9
  BOTTOM w0.076: UU1.A40 112.1,61.2 113.06,61.2 113.31,61.44 114.04,61.44
  BOTTOM w0.165: 114.04,61.44 115.14,61.44 116.71,63.01 116.71,72.21 118.16,73.66 118.16,73.98 118.32,74.15 118.58,74.15 118.74,74.31 118.74,74.64 118.58,74.81 118.32,74.81 118.16,74.98 118.16,75.25 118.32,75.41 118.58,75.41 118.74,75.58 118.74,75.91 118.58,76.07 118.32,76.07 118.16,76.24 118.16,76.57 118.32,76.73 118.58,76.73 118.74,76.9 118.74,77.16 118.5,77.41 118.5,78.1 118.62,78.22 118.62,78.55 118.45,78.72 118.2,78.72 118.03,78.88 118.03,79.73 UD4.AA9
M_B_DQ_7[0]: length 40.5
  BOTTOM w0.076: 113.49,57.87 112.74,57.87 112.12,58.49 111.85,58.49 111.74,58.6 111.46,58.6 UU1.B35
  BOTTOM w0.165: UD4.U2 123.56,82.41 124.95,82.41 125.25,82.12 125.98,82.12 126.21,81.89 126.21,81.58 126.05,81.42 125.51,81.42 125.35,81.25 125.35,80.92 125.51,80.76 126.05,80.76 126.21,80.59 126.21,80.26 126.05,80.1 125.51,80.1 125.35,79.93 125.35,79.6 125.51,79.44 126.05,79.44 126.21,79.27 126.21,78.11 126.34,77.98 126.34,66.32 117.88,57.87 113.49,57.87
M_B_DQ_7[1]: length 42.3
  BOTTOM w0.076: UU1.D35 110.34,58.42 111.68,58.42 111.78,58.32 112.06,58.32 112.81,57.56 113.46,57.56
  BOTTOM w0.165: UD4.U4 121.96,83.06 124.26,83.06 124.38,83.18 125.55,83.18 126.57,82.17 126.57,78.36 126.69,78.23 126.69,66.19 118.06,57.56 113.46,57.56
M_B_DQ_7[2]: length 37.9
  BOTTOM w0.076: UU1.A35 112.22,58.72 112.75,58.18 113.51,58.18
  BOTTOM w0.165: UD4.V2 123.56,81.76 124.39,81.76 124.84,81.3 124.84,79.1 125,78.93 125.56,78.93 125.73,78.77 125.73,78.44 125.56,78.27 125,78.27 124.97,78.23 124.97,76.46 125.13,76.29 125.69,76.29 125.86,76.13 125.86,75.8 125.69,75.63 125.13,75.63 124.97,75.47 124.97,75.14 125.13,74.97 125.79,74.97 125.96,74.81 125.96,66.47 117.67,58.18 113.51,58.18
M_B_DQ_7[3]: length 37.1
  BOTTOM w0.076: 113.59,58.76 113.22,58.76 112.98,59 112.45,59 112.33,59.12 111.87,59.12 111.64,59.07 111.45,59.12 111.19,59.12 111.04,59.05 110.21,59.05 110.04,59.22 UU1.D38
  BOTTOM w0.165: UD4.AA2 123.63,79.73 123.63,79.07 123.8,78.9 123.91,78.9 124.08,78.74 124.08,78.41 123.91,78.24 123.83,78.24 123.67,78.08 123.67,76.52 123.92,76.26 124.04,76.26 124.2,76.09 124.2,75.76 124.04,75.6 123.92,75.6 123.76,75.43 123.76,75.1 123.92,74.94 124.04,74.94 124.2,74.77 124.2,74.44 124.04,74.28 123.92,74.28 123.76,74.11 123.76,73.78 123.92,73.62 124.04,73.62 124.2,73.45 124.2,73.12 124.04,72.96 123.92,72.96 123.76,72.79 123.76,72.46 123.92,72.3 124.04,72.3 124.2,72.13 124.2,71.8 124.04,71.64 123.92,71.64 123.76,71.47 123.76,71.13 125.19,69.7 125.19,66.85 123.36,65.02 123.13,65.02 122.86,65.29 122.62,65.29 122.39,65.06 122.39,64.83 122.66,64.55 122.66,64.32 117.1,58.76 113.59,58.76
M_B_DQ_7[4]: length 38.1
  BOTTOM w0.076: UU1.C35 110.86,58.89 111.08,58.89 111.22,58.95 111.43,58.95 111.63,58.9 111.89,58.95 112.27,58.95 112.38,58.84 112.91,58.84 113.26,58.49 113.56,58.49
  BOTTOM w0.165: 113.56,58.49 117.47,58.49 125.58,66.6 125.58,70.31 125.41,70.47 125.13,70.47 124.97,70.64 124.97,70.97 125.13,71.13 125.41,71.13 125.58,71.3 125.58,71.6 125.41,71.77 124.75,71.77 124.59,71.93 124.59,72.26 124.75,72.43 125.31,72.43 125.47,72.59 125.47,72.92 125.31,73.09 124.75,73.09 124.59,73.25 124.59,73.58 124.75,73.75 125.31,73.75 125.47,73.91 125.47,74.24 125.31,74.41 124.75,74.41 124.59,74.57 124.59,77.98 124.46,78.11 124.46,80.21 124.21,80.46 123.56,80.46 UD4.Y2
M_B_DQ_7[5]: length 35.8
  BOTTOM w0.076: 114.53,60.58 114.22,60.58 113.93,60.29 113.4,60.29 113.25,60.44 111.97,60.44 110.95,60.26 UU1.C38
  BOTTOM w0.165: UD4.V4 121.31,82.41 120.36,82.41 119.96,82.8 119.96,84.36 119.8,84.53 119.47,84.53 119.3,84.36 119.3,82.7 119.76,82.24 119.76,79.32 120.01,79.07 120.01,73.48 118.03,71.5 118.03,62.48 116.13,60.58 114.53,60.58
M_B_DQ_7[6]: length 37.8
  BOTTOM w0.076: UU1.B38 111.53,60.19 111.99,60.27 113.16,60.27 113.32,60.1 114,60.1 114.17,60.27 114.53,60.27
  BOTTOM w0.165: 114.53,60.27 116.41,60.27 118.39,62.25 118.39,63.18 118.55,63.35 119.21,63.35 119.38,63.51 119.38,63.84 119.21,64.01 118.55,64.01 118.39,64.17 118.39,64.5 118.55,64.67 119.21,64.67 119.38,64.83 119.38,65.16 119.21,65.33 118.55,65.33 118.39,65.49 118.39,71.22 120.52,73.35 120.52,74.94 120.69,75.1 121.8,75.1 121.97,75.27 121.97,75.6 121.8,75.76 120.69,75.76 120.52,75.93 120.52,76.26 120.69,76.42 121.8,76.42 121.97,76.59 121.97,76.87 121.8,77.04 120.56,77.04 120.39,77.2 120.39,79.14 120.01,79.52 120.01,80.69 120.43,81.11 121.31,81.11 UD4.Y4
M_B_DQ_7[7]: length 38.1
  BOTTOM w0.076: 114.68,59.92 113.25,59.92 113.08,60.09 112.09,60.09 UU1.A38
  BOTTOM w0.165: 114.68,59.92 116.56,59.92 119.89,63.24 119.89,63.88 120.05,64.04 120.61,64.04 120.78,64.21 120.78,64.54 120.61,64.7 120.05,64.7 119.89,64.87 119.89,65.35 118.72,66.52 118.72,69.9 119.17,70.35 119.17,70.58 118.95,70.79 118.95,71.02 119.19,71.26 119.42,71.26 119.63,71.05 119.87,71.05 120.1,71.28 120.1,71.51 119.89,71.72 119.89,71.96 120.12,72.19 120.36,72.19 120.57,71.98 120.8,71.98 121.03,72.21 121.03,74.46 121.2,74.62 121.53,74.62 121.69,74.46 121.69,72.37 121.86,72.21 122.21,72.21 122.38,72.37 122.38,77.81 121.8,78.38 120.94,78.38 120.78,78.55 120.78,78.89 121.24,79.36 121.24,79.74 UD4.AA4
M_B_DQS_0_DN: length 19
  BOTTOM w0.076: 99.71,79.3 99.71,79.32 99.66,79.37 99.66,81.8 99.49,81.98 99.28,81.98 UD3.V10 ; 98.72,68.42 98.72,68.4 98.66,68.35 98.66,68.07 98.47,67.88 98.47,66.87 98.64,66.7 98.64,66.11 98.51,65.99 98.51,65.73 98.57,65.48 98.5,65.15 98.52,65.07 98.52,64.81 98.3,64.59 UU1.AH46
  BOTTOM w0.14: 98.72,68.42 98.72,70.29 99.2,70.78 99.2,78.53 99.71,79.04 99.71,79.3
M_B_DQS_0_DP: length 19
  BOTTOM w0.076: UU1.AH47 98.26,64.81 98.33,64.89 98.33,65.16 98.4,65.48 98.35,65.71 98.35,66.05 98.47,66.18 98.47,66.63 98.31,66.8 98.31,67.95 98.5,68.14 98.5,68.35 98.45,68.4 98.45,68.42 ; 99.45,79.3 99.45,79.32 99.5,79.37 99.5,79.63 99.36,79.77 99.36,79.91 99.5,80.05 99.5,80.24 99.36,80.38 99.36,80.52 99.5,80.65 99.5,80.85 99.36,80.99 99.36,81.13 99.5,81.26 99.5,81.73 99.42,81.81 99.07,81.81 99,81.73 99,81.61 UD3.W10
  BOTTOM w0.14: 99.45,79.3 99.45,79.15 98.94,78.64 98.94,70.89 98.45,70.4 98.45,68.42
M_B_DQS_1_DN: length 34.6
  ART06 w0.076: v2(98.27,61.71) 97.97,61.71 97.9,61.78 97.9,65.31 98.09,65.5 98.16,65.5 98.17,65.51
  ART06 w0.14: 98.17,65.51 98.92,66.26 98.92,78.19 96.37,80.75 96.37,82.12 96.77,82.52 96.77,83.39 96.57,83.59 96.57,86.76 96.72,86.91 96.72,87.37 96.57,87.52 96.57,87.88 96.72,88.03 96.72,88.49 96.57,88.64 96.57,89 96.72,89.15 96.72,89.61 96.57,89.76 96.57,90.29 97.1,90.83 98.46,90.83 98.53,90.9 98.73,90.9 v1(98.76,90.86)
  BOTTOM w0.076: v2(98.27,61.71) UU1.AJ41
  BOTTOM w0.14: UD3.E10 v1(98.76,90.86)
M_B_DQS_1_DP: length 34.6
  ART06 w0.076: 97.99,65.7 97.97,65.69 97.97,65.62 97.73,65.38 97.73,62 97.44,61.71 v2(97.36,61.71)
  ART06 w0.14: v1(98.76,91.51) 98.35,91.1 96.99,91.1 96.3,90.41 96.3,83.48 96.51,83.28 96.51,82.63 96.1,82.23 96.1,80.64 98.66,78.08 98.66,66.37 97.99,65.7
  BOTTOM w0.076: UU1.AL41 v2(97.36,61.71)
  BOTTOM w0.14: UD3.D10 v1(98.76,91.51)
M_B_DQS_2_DN: length 20.1
  BOTTOM w0.076: 105.31,79.25 105.31,79.27 105.26,79.32 105.26,81.57 105.03,81.8 104.86,81.8 104.78,81.87 UD3.V3 ; 101.04,68.97 101.03,68.95 100.96,68.95 100.58,68.58 100.58,66.88 100.26,66.56 100.26,66.19 100.39,66.06 100.39,64.89 100.47,64.81 UU1.AC47
  BOTTOM w0.14: 105.31,79.25 105.31,78.91 105.48,78.74 105.48,78.36 105.31,78.18 105.31,77.58 104.8,77.07 104.8,76.38 102.16,73.73 102.16,70.08 101.04,68.97
M_B_DQS_2_DP: length 20.1
  BOTTOM w0.076: 105.05,79.25 105.05,79.27 105.1,79.32 105.1,81.5 104.96,81.63 104.86,81.63 104.78,81.56 UD3.W3 ; 100.86,69.16 100.86,69.08 100.42,68.65 100.42,66.94 100.1,66.63 100.1,66.12 100.23,65.99 100.23,64.75 100.42,64.56 UU1.AC46
  BOTTOM w0.14: 105.05,79.25 105.05,77.69 104.54,77.18 104.54,76.49 101.89,73.84 101.89,70.19 100.86,69.16
M_B_DQS_3_DN: length 44.1
  ART06 w0.076: v2(100.1,61.71) 100.4,61.71 100.48,61.78 100.48,63.19 100.79,63.51 100.79,63.58 100.8,63.59
  ART06 w0.14: 100.8,63.59 101.06,63.85 101.06,64.19 101.75,64.87 102.28,64.87 102.65,65.24 102.65,65.57 102.88,65.8 103.21,65.8 103.68,66.27 103.68,67.21 104.34,67.87 104.34,68.27 103.88,68.73 103.88,69.5 104.17,69.79 104.76,69.79 104.9,69.93 104.9,70.49 104.76,70.63 104.17,70.63 103.88,70.92 103.88,71.83 104.39,72.34 105.05,72.34 105.78,71.61 105.98,71.61 106.37,72.01 106.37,72.21 105.9,72.68 105.9,73.08 108.04,75.22 108.04,75.42 107.77,75.69 107.77,76.1 108.32,76.64 108.72,76.64 108.99,76.37 109.19,76.37 110.23,77.42 110.23,87.73 109.54,88.42 109.29,88.42 109.02,88.69 109.02,88.94 108.75,89.21 108.5,89.21 108.23,89.48 108.23,89.73 107.96,90 107.71,90 107.44,90.27 107.44,90.52 107.21,90.75 105.27,90.75 v1(105.16,90.86)
  BOTTOM w0.076: UU1.AE41 v2(100.1,61.71)
  BOTTOM w0.14: UD3.E3 v1(105.16,90.86)
M_B_DQS_3_DP: length 44
  ART06 w0.076: 100.99,63.41 100.98,63.39 100.91,63.39 100.64,63.12 100.64,61.94 100.87,61.71 v2(101.02,61.71)
  ART06 w0.14: 100.99,63.41 101.33,63.74 101.33,64.08 101.86,64.6 102.39,64.6 103.95,66.16 103.95,67.1 104.61,67.76 104.61,68.38 104.15,68.84 104.15,69.39 104.28,69.52 104.87,69.52 105.17,69.82 105.17,70.6 104.87,70.9 104.28,70.9 104.15,71.03 104.15,71.72 104.5,72.07 104.94,72.07 105.67,71.35 106.09,71.35 106.64,71.9 106.64,72.32 106.17,72.79 106.17,72.97 108.31,75.11 108.31,75.53 108.04,75.8 108.04,75.99 108.43,76.38 108.61,76.38 108.88,76.11 109.3,76.11 110.5,77.31 110.5,87.84 107.32,91.02 105.65,91.02 v1(105.16,91.51)
  BOTTOM w0.076: v2(101.02,61.71) UU1.AD41
  BOTTOM w0.14: UD3.D3 v1(105.16,91.51)
M_B_DQS_4_DN: length 38
  BOTTOM w0.076: 108.28,66.78 108.27,66.77 108.2,66.77 107.89,66.46 107.89,66.2 108.04,66.05 108.04,65.71 107.99,65.48 108.06,65.16 108.06,64.89 108.13,64.81 UU1.H47 ; UD4.E10 116.83,90.83 116.35,91.31 116.35,93.24 116.3,93.29 116.3,93.31
  BOTTOM w0.14: 116.3,93.31 116.3,93.43 116.16,93.57 114.96,93.57 114.73,93.34 114.4,93.34 114.17,93.57 113.86,93.57 113.59,93.3 113.59,92.94 113.38,92.73 113.02,92.73 112.8,92.51 112.8,92.15 112.59,91.93 112.23,91.93 112.01,91.72 112.01,91.36 111.8,91.14 111.44,91.14 110.35,90.06 110.35,68.85 108.28,66.78
M_B_DQS_4_DP: length 37.9
  BOTTOM w0.076: UU1.H46 108.27,64.4 107.87,64.79 107.87,65.07 107.89,65.15 107.82,65.48 107.88,65.73 107.88,65.98 107.73,66.13 107.73,66.53 108.08,66.89 108.08,66.96 108.09,66.97 ; UD4.D10 116.71,91.18 116.51,91.38 116.51,93.24 116.57,93.29 116.57,93.31
  BOTTOM w0.14: 116.57,93.31 116.57,93.54 116.27,93.84 113.75,93.84 110.08,90.17 110.08,68.96 108.09,66.97
M_B_DQS_5_DN: length 41.6
  ART06 w0.076: v2(109.25,61.71) 108.95,61.71 108.88,61.78 108.88,64.25 109.29,64.66 109.36,64.66 109.38,64.68
  ART06 w0.14: 109.38,64.68 110.03,65.33 110.03,66.8 119.62,76.39 119.62,77.13 119.33,77.41 117.99,77.41 117.85,77.55 117.85,78.11 117.99,78.25 119.33,78.25 119.62,78.54 119.62,85 120.04,85.42 120.04,86.94 119.62,87.36 119.62,88.87 119.84,89.08 119.84,89.43 119.62,89.64 119.62,90.13 120.3,90.8 120.59,90.8 120.77,90.62 121.15,90.62 121.33,90.8 121.71,90.8 121.88,90.62 122.27,90.62 122.44,90.8 122.76,90.8 v1(122.82,90.86)
  BOTTOM w0.089: v2(109.25,61.71) UU1.G41
  BOTTOM w0.14: UD4.E3 v1(122.82,90.86)
M_B_DQS_5_DP: length 41.6
  ART06 w0.076: v2(108.34,61.71) 108.57,61.71 108.71,61.85 108.71,64.32 109.17,64.78 109.17,64.85 109.19,64.86
  ART06 w0.14: 109.19,64.86 109.76,65.44 109.76,66.91 119.35,76.5 119.35,77.02 119.22,77.15 117.88,77.15 117.59,77.44 117.59,78.22 117.88,78.52 119.22,78.52 119.35,78.65 119.35,85.11 119.77,85.53 119.77,86.83 119.35,87.25 119.35,90.24 120.19,91.07 122.38,91.07 v1(122.82,91.51)
  BOTTOM w0.089: UU1.J41 v2(108.34,61.71)
  BOTTOM w0.14: UD4.D3 v1(122.82,91.51)
M_B_DQS_6_DN: length 26.3
  BOTTOM w0.076: UU1.C42 111.02,61.82 111.1,61.74 111.36,61.74 111.69,61.68 111.92,61.73 112.26,61.73 112.41,61.58 112.81,61.58 113.21,61.97 113.47,61.97 113.52,62.02 113.54,62.02 ; UD4.V10 116.97,81.95 116.97,81.81 116.84,81.68 116.71,81.68 116.35,81.32 116.35,80.64 116.23,80.52 116.23,80.34 116.35,80.21 116.35,80.03 116.23,79.91 116.23,79.73 116.35,79.6 116.35,79.31 116.3,79.26 116.3,79.24
  BOTTOM w0.14: 116.3,79.24 116.3,78.85 117.33,77.81 117.33,73.98 115.97,72.62 115.97,63.27 114.73,62.02 113.54,62.02
M_B_DQS_6_DP: length 26.3
  BOTTOM w0.076: 113.54,61.76 113.52,61.76 113.47,61.81 113.27,61.81 112.88,61.41 112.34,61.41 112.19,61.57 111.94,61.57 111.69,61.51 111.36,61.58 111.28,61.56 111,61.56 110.83,61.73 UU1.D42 ; 116.57,79.24 116.57,79.26 116.51,79.31 116.51,81.25 116.69,81.43 UD4.W10
  BOTTOM w0.14: 113.54,61.76 114.84,61.76 116.24,63.16 116.24,72.51 117.6,73.86 117.6,77.92 116.57,78.96 116.57,79.24
M_B_DQS_7_DN: length 35.4
  BOTTOM w0.076: 113.73,59.5 113.71,59.5 113.66,59.45 113.39,59.45 112.97,59.88 112.37,59.88 112.17,59.74 111.88,59.74 111.82,59.77 111.6,59.77 111.35,59.73 110.93,59.73 110.77,59.56 UU1.D36 ; 121.9,79.27 121.9,79.29 121.95,79.34 121.95,81.83 122.12,82 122.35,82 UD4.V3
  BOTTOM w0.14: 113.73,59.5 116.81,59.5 121.4,64.09 121.4,64.6 119.17,66.82 119.17,69.59 121.17,71.59 122.57,71.59 122.92,71.94 122.92,77.94 121.9,78.96 121.9,79.27
M_B_DQS_7_DP: length 35.4
  BOTTOM w0.076: UU1.C36 110.95,59.41 110.95,59.52 111,59.56 111.36,59.56 111.61,59.61 111.78,59.6 111.84,59.57 112.22,59.57 112.42,59.71 112.9,59.71 113.33,59.29 113.66,59.29 113.71,59.24 113.73,59.24 ; UD4.W3 122.43,81.76 122.36,81.84 122.19,81.84 122.11,81.76 122.11,79.34 122.17,79.29 122.17,79.27
  BOTTOM w0.14: 113.73,59.24 116.92,59.24 121.66,63.98 121.66,64.71 119.44,66.94 119.44,69.48 121.28,71.32 122.68,71.32 123.19,71.83 123.19,78.05 122.17,79.07 122.17,79.27
M_B_LP4_CAA0: length 37.7
  PWR04 w0.14: v1(108.18,86.31) 108.43,86.05 109.46,86.05 109.6,85.91 109.6,85.56 109.46,85.42 109.23,85.42 109.09,85.28 109.09,84.89 109.23,84.75 109.46,84.75 109.6,84.61 109.6,84.34 109.46,84.2 109.23,84.2 109.09,84.06 109.09,79.03 109.23,78.89 109.59,78.89 109.73,78.75 109.73,78.47 109.59,78.33 109.23,78.33 109.09,78.2 109.09,77.92 109.23,77.78 109.59,77.78 109.73,77.64 109.73,77.36 109.59,77.22 109.23,77.22 109.09,77.08 109.09,76.8 109.23,76.66 109.59,76.66 109.73,76.52 109.73,76.24 109.59,76.1 109.23,76.1 109.09,75.96 109.09,75.68 109.23,75.54 109.59,75.54 109.73,75.4 109.73,75.12 109.59,74.98 109.23,74.98 109.09,74.84 109.09,74.56 109.23,74.42 109.59,74.42 109.73,74.28 109.73,74 109.59,73.86 109.23,73.86 109.09,73.72 109.09,73.45 109.23,73.31 109.59,73.31 109.73,73.17 109.73,72.89 109.59,72.75 109.23,72.75 109.09,72.61 109.09,71.93 107.01,69.85 v1(106.79,69.85)
  ART06 w0.152: v1(105.96,88.26) 106.76,88.26 108.18,86.84 v1(108.18,86.31) 107.25,84.85 106.93,84.53 v1(105.96,84.36)
  BOTTOM w0.165: UD3.R2 v1(105.96,84.36) ; UD3.H2 v1(105.96,88.26) ; v1(106.79,69.85) 106.79,68.82 105.76,67.79 105.76,66.9 105,66.14 UU1.R49
M_B_LP4_CAA1: length 37.6
  PWR04 w0.14: v1(107.41,86.31) 107.92,86.81 109.85,86.81 110.23,86.43 110.23,83.66 110.09,83.52 109.74,83.52 109.6,83.38 109.6,83.1 109.74,82.96 110.09,82.96 110.23,82.82 110.23,82.54 110.09,82.4 109.74,82.4 109.6,82.26 109.6,81.98 109.74,81.85 110.09,81.85 110.23,81.71 110.23,81.43 110.09,81.29 109.74,81.29 109.6,81.15 109.6,80.87 109.74,80.73 110.09,80.73 110.23,80.59 110.23,80.31 110.09,80.17 109.74,80.17 109.6,80.03 109.6,79.75 109.74,79.61 110.09,79.61 110.23,79.47 110.23,72.57 106.83,69.16 v1(106.17,69.16)
  ART06 w0.152: v1(105.98,85.01) 105.98,85.65 106.23,85.9 106.45,85.9 106.81,85.54 107.06,85.54 107.41,85.9 v1(107.41,86.31) 106.78,86.94 106.64,86.94 v1(105.98,87.61)
  BOTTOM w0.102: v1(105.98,85.01) 105.96,85.01 105.95,85
  BOTTOM w0.165: UU1.R47 105,64.61 104.7,64.92 104.7,66.27 105.48,67.05 105.48,67.97 106.17,68.65 v1(106.17,69.16) ; v1(105.98,87.61) 105.97,87.61 UD3.J2 ; 105.95,85 UD3.P2
M_B_LP4_CAA2: length 38.7
  PWR04 w0.14: 99.96,85.5 99.31,86.15 99.31,86.69 99.96,87.34 99.96,87.86 v1(100.36,88.26) ; 99.96,85.5 99.96,84 100.07,83.89 100.07,83.41 99.69,83.03 99.69,80.46 100.07,80.08 100.07,79.58 100.58,79.07 101.08,79.07 101.22,78.93 101.22,77.49 101.08,77.35 99.96,77.35 99.82,77.21 99.82,76.93 99.96,76.79 101.08,76.79 101.22,76.65 101.22,75.38 102.81,73.79 103.01,73.79 103.38,74.16 103.58,74.16 103.78,73.97 103.78,73.77 103.4,73.39 103.4,73.2 104.16,72.44 106.6,72.44 v1(107.19,73.02) ; 99.96,85.5 100.38,85.92 100.97,85.92 101.11,85.78 101.11,85.56 100.77,85.22 100.77,84.76 v1(100.36,84.36)
  BOTTOM w0.165: UD3.R9 v1(100.36,84.36) ; UD3.H9 v1(100.36,88.26) ; v1(107.19,73.02) 107.19,72.67 105.74,71.22 105.74,68.91 103.83,67 103.83,65.86 UU1.U49
M_B_LP4_CAA3: length 36.3
  PWR04 w0.14: 98.8,85.93 99.06,85.93 99.32,85.66 99.32,85.43 99.16,85.27 99.16,84.76 v1(99.56,84.36) ; 98.8,85.93 98.8,87.5 v1(99.56,88.26) ; 98.8,85.93 98.68,85.8 98.68,84.53 99.19,84.01 99.19,80.33 99.3,80.22 99.3,78.54 99.44,78.4 99.93,78.4 100.07,78.26 100.07,77.98 99.93,77.84 99.44,77.84 99.3,77.71 99.3,76.67 103.99,71.98 107.29,71.98 v1(107.47,72.16)
  BOTTOM w0.076: 106.55,66.7 106.55,66.39 106.74,66.2 106.74,65.73 106.71,65.6 106.7,65.3 106.7,65.05 106.6,64.95 106.6,64.34 106.31,64.04 UU1.M45
  BOTTOM w0.165: UD3.R10 99.56,84.33 v1(99.56,84.36) ; v1(107.47,72.16) 108.1,71.52 108.1,68.88 106.55,67.33 106.55,66.7 ; UD3.H10 v1(99.56,88.26)
M_B_LP4_CAA4: length 35.9
  PWR04 w0.14: v1(106.81,71.5) 103.83,71.5 98.8,76.53 98.8,78.43 98.3,78.94 98.3,80.72 98.42,80.85 98.42,81.61 96.65,83.39 96.65,85.16 97.47,85.99 97.85,85.99 ; v1(97.96,84.36) 98.28,84.36 98.42,84.5 98.42,85.67 98.3,85.8 98.04,85.8 97.85,85.99 ; 97.85,85.99 98.42,86.56 98.42,87.8 v1(97.96,88.26)
  BOTTOM w0.076: UU1.M47 106.02,64.78 106.02,65.28 106.2,65.45 106.32,65.45 106.46,65.45 106.54,65.52 106.54,65.63 106.58,65.75 106.58,66.04 106.3,66.32
  BOTTOM w0.165: UD3.H11 v1(97.96,88.26) ; v1(106.81,71.5) 107.62,70.69 107.62,68.81 106.3,67.49 106.3,66.32 ; UD3.R11 v1(97.96,84.36)
M_B_LP4_CAA5: length 36.8
  PWR04 w0.14: v1(106.22,70.84) 103.86,70.84 98.3,76.4 98.3,78.18 97.31,79.16 97.31,79.36 97.69,79.73 97.69,79.93 97.49,80.13 97.29,80.13 96.92,79.75 96.72,79.75 96.26,80.21 96.26,82.24 96.52,82.5 96.52,82.88 96.14,83.26 96.14,85.42 97.15,86.43 v1(97.66,86.43)
  ART06 w0.152: v1(97.96,85.01) 97.96,85.37 97.79,85.54 97.31,85.54 97.15,85.7 97.15,85.93 v1(97.66,86.43) 97.66,87.3 v1(97.96,87.61)
  BOTTOM w0.165: UD3.P11 v1(97.96,85.01) ; UD3.J11 v1(97.96,87.61) ; UU1.R45 105,63.98 105.33,64.31 105.33,66.09 106.02,66.77 106.02,67.64 107.26,68.88 107.26,70.13 106.55,70.84 v1(106.22,70.84)
M_B_LP4_CAB0: length 54.1
  PWR04 w0.14: v2(102.85,61.72) 102.54,61.41 102.54,60.12 103.15,59.51 103.81,59.51 104.57,58.75 107.69,58.75 108.1,59.15 110.39,59.15 113.41,62.18 121.72,77.22 122.84,78.34 123.03,78.34 123.18,78.19 123.38,78.19 123.58,78.39 123.58,78.59 123.43,78.73 123.43,78.93 123.63,79.13 123.82,79.13 123.97,78.98 124.17,78.98 124.37,79.18 124.37,79.38 124.22,79.52 124.22,79.72 124.42,79.92 124.62,79.92 124.76,79.77 124.96,79.77 125.16,79.97 125.16,80.17 125.01,80.31 125.01,80.51 125.96,81.46 125.96,86.05 v1(125.7,86.31)
  ART06 w0.152: v1(123.62,88.26) 123.22,87.86 123.22,87.29 123.72,86.79 125.22,86.79 v1(125.7,86.31) 125.27,85.87 123.9,85.87 123.22,85.2 123.22,84.75 v1(123.62,84.36)
  BOTTOM w0.165: UU1.Y41 v2(102.85,61.72) ; UD4.H2 v1(123.62,88.26) ; UD4.R2 v1(123.62,84.36)
M_B_LP4_CAB1: length 53.5
  PWR04 w0.14: v1(126.46,86.31) 126.46,80.39 121.2,75.13 114.09,62.35 110.01,58.27 104.37,58.27 103.5,59.13 103,59.13 102.31,59.81 102.31,61.83 v2(102.85,62.37)
  ART06 w0.152: v1(123.63,85.01) 124.04,85.42 125.98,85.42 126.46,85.9 v1(126.46,86.31) 125.58,87.2 123.82,87.2 123.63,87.39 v1(123.63,87.61)
  BOTTOM w0.102: v1(123.63,85.01) 123.62,85.01 123.61,85
  BOTTOM w0.165: v1(123.63,87.61) 123.62,87.61 UD4.J2 ; 123.61,85 UD4.P2 ; UU1.Y42 v2(102.85,62.37)
M_B_LP4_CAB2: length 51.3
  PWR04 w0.14: 117.3,85.82 117.93,85.82 118.42,85.34 118.42,84.76 v1(118.02,84.36) ; 117.3,85.82 117.3,85.52 117.62,85.2 117.62,81.92 117.62,78.83 117.48,78.69 116.93,78.69 116.79,78.83 116.79,81.34 116.65,81.48 116.34,81.48 116.2,81.34 116.2,80.75 116.06,80.61 114.44,80.61 114.3,80.47 114.3,80.19 114.44,80.05 116.06,80.05 116.2,79.91 116.2,79.66 116.06,79.52 114.44,79.52 114.3,79.38 114.3,79.1 114.44,78.96 116.06,78.96 116.2,78.82 116.2,76.22 107.49,67.51 106.68,67.51 105.03,65.86 105.03,65.36 104.89,65.22 104.53,65.22 104.39,65.08 104.39,64.8 104.53,64.66 104.89,64.66 105.03,64.52 105.03,63.27 104.16,62.41 104.16,62.33 104.01,62.18 104.01,62.02 v2(103.79,61.8) ; 117.3,85.82 117.07,86.05 117.07,86.66 117.62,87.21 117.62,87.86 v1(118.02,88.26)
  BOTTOM w0.165: UD4.R9 v1(118.02,84.36) ; UU1.V41 v2(103.79,61.8) ; UD4.H9 v1(118.02,88.26)
M_B_LP4_CAB3: length 52.1
  PWR04 w0.14: v1(117.22,84.36) 116.72,84.36 116.58,84.5 116.58,85.29 116.79,85.49 116.79,85.79 116.65,85.93 116.21,85.93 ; v2(103.63,67.76) 104.01,67.38 104.01,66.18 104.15,66.04 104.7,66.04 105.09,66.43 105.09,66.79 105.31,67.01 105.67,67.01 106.53,67.87 107.29,67.87 113.92,74.5 113.92,75.54 114.06,75.68 115.05,75.68 115.19,75.81 115.19,76.09 115.05,76.23 114.06,76.23 113.92,76.37 113.92,76.65 114.06,76.79 115.56,76.79 115.7,76.93 115.7,77.21 115.56,77.35 114.06,77.35 113.92,77.49 113.92,77.77 114.06,77.91 115.56,77.91 115.7,78.05 115.7,78.33 115.56,78.47 114.06,78.47 113.79,78.74 113.79,80.72 115.06,81.99 116.57,81.99 116.71,82.13 116.71,82.42 116.57,82.56 114.56,82.56 114.43,82.7 114.43,82.98 114.56,83.12 116.57,83.12 116.71,83.26 116.71,83.51 116.08,84.15 116.08,85.8 116.21,85.93 ; 116.21,85.93 116.21,86.46 116.76,87.8 v1(117.22,88.26)
  BOTTOM w0.076: 103.25,67.12 103.25,66.95 102.77,66.47 102.77,66.19 102.89,66.06 102.89,64.89 102.97,64.81 UU1.V47
  BOTTOM w0.165: UD4.R10 117.21,84.33 v1(117.22,84.36) ; 103.25,67.12 103.25,67.38 v2(103.63,67.76) ; UD4.H10 v1(117.22,88.26)
M_B_LP4_CAB4: length 48.2
  PWR04 w0.102: 103.5,62.18 103.5,62.02 103.43,61.95 103.43,61.65 103.5,61.58 103.5,61.52 103.59,61.43 103.91,61.43 104.12,61.22 104.12,61.18 104.16,61.14 104.16,60.93 103.76,60.53 v2(103.76,60.42)
  PWR04 w0.14: 115.19,86.42 114.79,86.81 113.03,86.81 111.38,85.16 111.38,84.78 111.52,84.64 112.25,84.64 112.39,84.5 112.39,84.22 112.25,84.08 111.52,84.08 111.38,83.94 111.38,83.64 111.52,83.5 112.38,83.5 112.52,83.36 112.52,83.09 112.38,82.95 111.52,82.95 111.38,82.81 111.38,82.53 111.52,82.39 112.38,82.39 112.52,82.25 112.52,81.97 112.38,81.83 111.52,81.83 111.38,81.69 111.38,73.1 106.68,68.4 103.38,68.4 103,68.02 103,67.38 103.63,66.75 103.63,64.21 104.39,63.45 104.39,63.07 103.5,62.18 ; 115.19,86.42 115.19,84.79 v1(115.62,84.36) ; 115.19,86.42 116.02,87.25 116.02,87.86 v1(115.62,88.26)
  BOTTOM w0.165: UD4.H11 v1(115.62,88.26) ; UD4.R11 v1(115.62,84.36) ; UU1.T38 v2(103.76,60.42)
M_B_LP4_CAB5: length 46.7
  PWR04 w0.14: v2(104.39,67) 104.39,67.89 104.58,68.08 106.23,68.08 106.3,68.15 106.93,68.15 112.26,73.48 112.26,73.67 111.95,73.98 111.95,74.18 112.15,74.38 112.35,74.38 112.66,74.07 112.86,74.07 113.28,74.5 113.28,74.97 113.14,75.11 112.15,75.11 112.01,75.25 112.01,75.53 112.15,75.67 113.14,75.67 113.28,75.81 113.28,76.08 113.14,76.22 112.15,76.22 112.01,76.36 112.01,76.64 112.15,76.78 113.14,76.78 113.28,76.92 113.28,77.2 113.14,77.34 112.15,77.34 112.01,77.48 112.01,77.76 112.15,77.9 113.14,77.9 113.28,78.04 113.28,78.32 113.14,78.46 112.15,78.46 112.01,78.6 112.01,78.88 112.15,79.02 113.14,79.02 113.28,79.16 113.28,79.44 113.14,79.58 112.15,79.58 112.01,79.72 112.01,80 112.15,80.14 113.14,80.14 113.28,80.28 113.28,80.62 113.14,80.76 112.15,80.76 112.01,80.9 112.01,81.18 112.15,81.32 113.14,81.32 113.28,81.46 113.28,85.72 v1(113.88,86.32)
  ART06 w0.152: v1(115.62,85.01) 114.95,85.67 114.53,85.67 v1(113.88,86.32) 114.63,87.07 115.08,87.07 v1(115.62,87.61)
  BOTTOM w0.165: v2(104.39,67) 104.09,66.7 104.09,65.55 103.76,65.22 UU1.U48 ; UD4.P11 v1(115.62,85.01) ; UD4.J11 v1(115.62,87.61)
M_B_LP4_CKE_A0: length 37.9
  PWR04 w0.14: 103.92,85.53 103.59,85.21 v1(103.59,85.01) ; 103.92,85.53 104.27,85.19 104.27,83.14 104.4,83 106.04,83 106.17,82.88 106.17,81.99 106.04,81.86 105.62,81.86 105.48,81.72 105.48,80.86 105.67,80.67 107.53,80.67 107.67,80.53 107.67,79.43 107.53,79.29 105.93,79.29 105.79,79.15 105.79,78.87 105.93,78.73 107.53,78.73 107.67,78.59 107.67,78.28 107.53,78.14 106.56,78.14 106.42,78 106.42,77.72 106.56,77.58 107.53,77.58 107.67,77.44 v1(107.67,73.84) ; 103.92,85.53 103.5,85.95 103.5,86.31 103.31,86.5 103.31,87.33 v1(103.59,87.61)
  BOTTOM w0.076: UU1.U45 103.45,64.14 103.45,66.01 103.55,66.11
  BOTTOM w0.165: UD3.P4 103.6,84.98 v1(103.59,85.01) ; v1(107.67,73.84) 107.34,73.84 106.73,73.23 106.73,72.77 105.42,71.46 105.42,68.97 103.55,67.1 103.55,66.11 ; UD3.J4 v1(103.59,87.61)
M_B_LP4_CKE_A1: length 38.6
  PWR04 w0.14: 103,86.05 102.76,85.82 v1(102.76,85.01) ; 103,86.05 103.11,86.05 103.25,85.91 103.25,85.23 103.16,85.14 103.16,84.19 103.25,84.11 103.25,83.31 103.16,83.22 103.16,82.84 104.9,81.1 104.9,80.43 105.07,80.26 106.79,80.26 106.93,80.12 106.93,79.84 106.79,79.7 105.29,79.7 105.15,79.56 105.15,78.81 105.92,78.05 105.92,77.3 106.06,77.16 107.05,77.16 107.19,77.02 107.19,76.74 107.05,76.6 106.06,76.6 105.92,76.46 105.92,76.18 106.06,76.04 107.05,76.04 107.19,75.9 107.19,75.62 107.05,75.48 106.06,75.48 105.92,75.34 105.92,74.89 106.06,74.75 v1(106.55,74.75) ; 103,86.05 102.87,86.18 102.87,86.69 102.2,87.35 102.2,87.55 102.42,87.76 102.61,87.76 v1(102.76,87.61)
  BOTTOM w0.076: UU1.V46 103.13,64.36 102.73,64.75 102.73,65.97 102.6,66.1 102.6,66.56 103,66.95 103,67.12
  BOTTOM w0.165: UD3.J5 v1(102.76,87.61) ; 103,67.12 103,67.69 103.73,68.43 104.29,68.43 105.1,69.24 105.1,71.65 106.37,72.92 106.37,74.57 v1(106.55,74.75) ; UD3.P5 v1(102.76,85.01)
M_B_LP4_CKE_B0: length 41.2
  PWR04 w0.14: v1(121.87,86.41) 122.3,85.98 122.3,81.61 122.02,81.33 122.02,80.03 120.9,78.92 120.9,77.8 117.85,74.75 117.85,72.97 114.35,69.47 114.35,69.27 114.79,68.83 114.79,68.63 114.59,68.44 114.39,68.44 113.95,68.87 113.75,68.87 113.56,68.67 113.56,68.48 113.99,68.04 113.99,67.84 113.8,67.64 113.6,67.64 113.16,68.08 112.96,68.08 112.77,67.88 112.77,67.69 113.2,67.25 113.2,67.05 113.01,66.85 112.81,66.85 112.37,67.29 112.17,67.29 111.63,66.75 111.63,65.86 110.36,64.59 109.09,64.59 107.03,62.53 107.03,62.25 v2(106.51,61.72)
  ART06 w0.152: v1(121.25,87.61) 121.25,87.03 v1(121.87,86.41) 121.25,85.79 v1(121.25,85.01)
  BOTTOM w0.165: v1(121.25,85.01) 121.25,84.98 UD4.P4 ; UU1.M41 v2(106.51,61.72) ; v1(121.25,87.61) UD4.J4
M_B_LP4_CKE_B1: length 43.9
  PWR04 w0.102: 106.04,62.18 105.94,62.08 104.97,62.08 v2(104.68,62.37)
  PWR04 w0.14: 120.22,86.38 120.03,86.38 119.89,86.24 119.89,84.71 120.01,84.58 120.01,82.78 120.15,82.64 121.14,82.64 121.28,82.5 121.28,82.3 121.14,82.16 120.15,82.16 120.01,82.02 120.01,81.49 120.15,81.35 121.14,81.35 121.28,81.21 121.28,81.01 121.14,80.87 120.15,80.87 120.01,80.73 120.01,78.25 116.93,75.17 116.93,73.19 116.01,72.27 115.63,72.27 115.43,72.07 115.43,71.69 114.5,70.76 114.15,70.76 113.93,70.54 113.93,70.19 112.95,69.21 112.57,69.21 112.37,69.01 112.37,68.63 110.92,67.18 110.16,67.18 109.71,66.74 109.71,65.75 109.57,65.61 109.02,65.61 108.71,65.92 108.52,65.92 108.32,65.72 108.32,65.52 108.53,65.31 108.53,65.12 108.33,64.92 108.13,64.92 107.92,65.13 107.72,65.13 107.53,64.93 107.53,64.73 107.74,64.52 107.74,64.33 106.58,63.17 106.58,62.71 106.04,62.18 ; 120.22,86.38 120.42,86.58 v1(120.42,87.61) ; 120.22,86.38 120.42,86.18 v1(120.42,85.01)
  BOTTOM w0.165: UD4.P5 v1(120.42,85.01) ; UD4.J5 v1(120.42,87.61) ; UU1.P43 v2(104.68,62.37)
M_B_LP4_CS_A_R0_N: length 40.5
  PWR04 w0.14: v2(103.76,63.02) 102.74,64.04 102.74,68.27 103.33,68.86 104.21,68.86 105.28,69.92 106.3,69.92 106.68,70.3 107.03,70.3 108.58,71.85 108.58,85.16 107.9,85.85 106.22,85.85 105.28,86.79 104.7,86.79 v1(104.21,86.31)
  ART06 w0.152: v1(103.56,84.36) 103.56,84.37 103.18,84.75 103.18,85.27 v1(104.21,86.31) 104.06,86.46 103.17,86.46 103.02,86.61 103.02,87.01 103.17,87.16 103.9,87.16 104.09,87.35 104.09,88.11 103.93,88.26 v1(103.59,88.26)
  BOTTOM w0.165: UD3.R4 v1(103.56,84.36) ; UU1.V42 103.76,62.56 v2(103.76,63.02) ; UD3.H4 v1(103.59,88.26)
M_B_LP4_CS_A_R1_N: length 38.5
  PWR04 w0.102: v2(103.76,61.07) 103.52,61.07 103.22,61.36 103.22,62.84
  PWR04 w0.14: v1(105.17,88.26) 103.81,86.56 103.81,86.13 104.09,85.85 104.42,85.85 ; 103.22,62.84 102.36,63.7 102.36,68.4 103.1,69.14 103.73,69.14 104.98,70.38 106.35,70.38 108.08,72.11 108.08,84.33 106.96,85.44 105.51,85.44 105.1,85.85 104.42,85.85 ; 104.42,85.85 104.34,85.77 104.34,85.52 104.65,85.21 104.65,84.88 v1(105.16,84.36)
  BOTTOM w0.165: UD3.R3 v1(105.16,84.36) ; UU1.V39 v2(103.76,61.07) ; UD3.H3 v1(105.17,88.26)
M_B_LP4_CS_B_R0_N: length 44.3
  PWR04 w0.14: v2(102.92,61.07) 103.33,60.67 103.33,60.2 103.5,60.02 104.01,60.02 104.27,60.27 104.27,60.58 104.6,60.91 105.66,60.91 106.04,61.29 106.04,61.8 106.81,62.56 106.81,62.86 109.04,65.1 109.94,65.1 110.08,65.24 110.08,66.6 110.36,66.88 111.12,66.88 117.35,73.1 117.35,75.03 120.44,78.13 120.44,78.97 121.66,80.19 121.66,81.48 121.92,81.73 121.92,83.25 121.78,83.39 121.68,83.39 121.54,83.53 121.54,83.81 121.68,83.95 121.78,83.95 121.92,84.09 121.92,85.79 121.3,86.41 ; 121.3,86.41 120.99,86.41 120.85,86.27 120.85,84.73 v1(121.22,84.36) ; 121.3,86.41 121.66,86.78 121.66,87.84 v1(121.25,88.26)
  BOTTOM w0.165: v1(121.22,84.36) UD4.R4 ; v1(121.25,88.26) UD4.H4 ; UU1.Y39 v2(102.92,61.07)
M_B_LP4_CS_B_R1_N: length 43.2
  PWR04 w0.14: 123.59,86.26 123.87,86.26 124.92,85.21 124.92,83.31 122.35,80.74 122.35,79.83 121.55,78.04 113.93,65.54 113.28,65.1 112.9,65.1 112.46,64.65 109.73,60.58 109.73,60.32 109.45,60.04 105.05,60.04 v2(104.68,60.42) ; 123.59,86.26 123.22,86.63 123.22,87.86 v1(122.82,88.26) ; 123.59,86.26 123.22,85.88 123.22,84.76 v1(122.82,84.36)
  BOTTOM w0.165: UD4.H3 v1(122.82,88.26) ; UU1.T39 v2(104.68,60.42) ; UD4.R3 v1(122.82,84.36)
MBP0_N: length 3.7
  TOP w0.102: TPU73.1 104.65,43.89 104.14,44.4 104.14,45.29 104.73,45.88 v2(104.73,45.89) 105.03,45.59 RU214.1
  BOTTOM w0.102: UU1.T9 v2(104.73,45.89)
MBP1_N: length 5.2
  TOP w0.102: v2(104.73,45.32) 104.61,45.32 104.33,45.03 104.33,44.48 104.59,44.22 104.95,44.22 TPU74.1 105.51,43.86 106.63,43.86 106.63,43.86 106.75,43.86 107.31,43.3 RU213.1
  BOTTOM w0.102: v2(104.73,45.32) 104.64,45.27 UU1.T7
MBP2_N: length 1.1
  TOP w0.102: v2(104.73,46.62) 104.84,46.5 RU216.1
  BOTTOM w0.102: UU1.T10 104.32,46.73 v2(104.73,46.62)
MBP3_N: length 4.5
  TOP w0.102: v2(104.73,44.59) 104.8,44.52 105.79,44.52 106.2,44.12 106.88,44.12 107.11,43.89 RU215.1 108.13,43.89 v3(108.35,44.12)
  BOTTOM w0.102: UU1.T6 v2(104.73,44.59)
MEM_VREF: length 55.1
  TOP w0.102: RV48.2 144.02,61.15 v1(143.86,60.99)
  TOP w0.203: 183.69,57.73 QV21.1
  TOP w0.381: 183.69,57.73 v3(183.69,57.12) 183.69,56.39 v1(183.26,55.95)
  ART05 w0.381: v1(143.86,60.99) 146.81,58.04 146.81,56.08 148.84,54.05 150.37,54.05 151.76,52.65 151.76,51.64 152.27,51.13 157.86,51.13 162.43,46.56 165.61,46.56 168.15,49.1 173.23,49.1 174.62,50.49 174.62,51.38 176.15,52.91 180.21,52.91 v1(183.26,55.95)
  BOTTOM w0.254: UV2.C5 v1(143.86,60.99)
MICBIAS_B: length 2.4
  TOP w0.203: RA20.1 178.46,30.96 177.65,30.96 177.25,30.57 UA2.44
MIPI60_CFG_STB0_DN: length 1.1
  TOP w0.102: RU212.2 103.5,44.35 v2(103.75,44.59)
  BOTTOM w0.102: v2(103.75,44.59) UU1.V6
MIPI60_CFG_STB0_DP: length 3.3
  TOP w0.102: TPU29.1 103.17,43.08 103.17,44.55 103.77,45.15 v2(103.77,45.32)
  BOTTOM w0.102: UU1.V7 103.66,45.27 103.76,45.32 v2(103.77,45.32)
MIPI60_CFG_STB1_DN: length 1.3
  TOP w0.102: v2(102.85,45.01) 102.36,44.52 RU217.2
  BOTTOM w0.076: v2(102.85,45.01) 102.68,44.9 UU1.Y6
MIPI60_CFG_STB1_DP: length 2.9
  TOP w0.102: TPU31.1 102.74,44.4 103.22,44.88 103.22,45.28 v2(102.85,45.66)
  BOTTOM w0.076: UU1.Y7 102.68,45.55 v2(102.85,45.66)
MIPI60_CPU_JTAG_TCLK: length 8.2
  BOTTOM w0.076: 105.03,40.59 105.03,41.48 105.26,41.71 UU1.P3
  BOTTOM w0.102: 105.03,40.59 105.81,39.8 105.81,38.78 105.89,38.71 105.89,37.11 TP1.1 106.14,36.4 RU22.1 RU20.1
MIPI60_CPU_JTAG_TDI: length 6.9
  BOTTOM w0.076: 107.11,41.68 106.92,41.87 106.92,43.14 106.86,43.2 106.86,43.56 107.17,43.88 UU1.K5
  BOTTOM w0.102: TP2.1 RU25.1 108.33,38.81 108.33,39.54 107.11,40.76 107.11,41.68
MIPI60_CPU_JTAG_TDO: length 7.4
  BOTTOM w0.102: RU27.2 TP3.1 RU29.1 109.73,39.06 107.77,41.02 107.77,42.54 107.17,43.14 UU1.K3
MIPI60_CPU_JTAG_TMS: length 12.2
  TOP w0.102: v2(105.46,39.19) 105.41,39.24 v2(105.41,41.35)
  BOTTOM w0.076: v2(105.41,41.35) 105.54,41.48 105.54,42.75 105.54,42.76 105.54,43.24 105.26,43.53 UU1.P4
  BOTTOM w0.102: v2(105.46,39.19) 105.54,39.11 RU30.2 105.28,38.55 105.15,38.43 105.15,36.52 TP4.1 105.66,35.25 106.04,34.87 107.44,34.87 v3(107.57,35) RU31.1
MIPI60_CPU_JTAG_TRST_N: length 5.9
  BOTTOM w0.076: RU33.1 107.24,38.35 107.24,39.12 105.79,40.57 105.79,42.02 105.83,42.06
  BOTTOM w0.102: TP5.1 106.65,37.77 RU33.1
MIPI60_PCH_JTAG_TCLK: length 5.5
  BOTTOM w0.076: TP7.1 104.65,41.67 104.39,41.92 104.39,42.9 104.54,43.05 104.82,43.05 105,43.23 105,43.46 104.7,43.76 UU1.R5
MIPI60_PCH_JTAG_TDI: length 6.6
  BOTTOM w0.102: TP8.1 108.71,37.03 RU23.1 108.58,37.54 RU25.2 108.58,39.56 107.35,40.79 107.35,41.88 107.17,42.06
MIPI60_PCH_JTAG_TDO: length 5.9
  BOTTOM w0.076: 107.57,40.84 107.57,42.31 UU1.K2
  BOTTOM w0.102: TP9.1 109.22,37.79 RU29.2 108.96,38.81 108.96,39.44 107.57,40.84
MIPI60_PCH_JTAG_TMS: length 8
  BOTTOM w0.076: UU1.N3 105.83,43.22 106.04,43 arc(106.07,42.87) 106.14,42.75 106.24,42.65 106.24,41.79 106.14,41.69 106.14,40.77
  BOTTOM w0.102: 106.14,40.77 106.14,40.7 107.63,39.22 107.63,37.6 107.85,37.39 TP10.1 107.57,36.78 RU31.2
MIPI60_PCH_JTAG_TRST_N: length 7.9
  TOP w0.102: v2(106.81,39.06) 107.49,39.75 v2(107.49,39.88)
  BOTTOM w0.076: v2(107.49,39.88) 106.86,40.51 106.86,41.68 106.75,41.78 106.75,42.54 106.55,42.75 106.39,42.75 106.3,42.83 arc(106.23,42.93) 106.21,43.06 106.21,43.22 106.14,43.28 106.14,43.53 105.83,43.85 UU1.N5
  BOTTOM w0.102: v2(106.81,39.06) 106.68,39.19 TP6.1 106.22,38.63 RU34.1 RU33.2
MIPI60_PCH_JTAGX: length 7.8
  BOTTOM w0.076: UU1.N2 106.08,42.45 106.08,41.91 105.95,41.79 105.95,40.64 107.44,39.15 107.44,37.64 TP11.1
  BOTTOM w0.102: TP11.1 107.26,37.41 107.26,36.22 RU20.2
MIPI60_PRDY_N: length 1.7
  TOP w0.102: TP12.1 106.15,44.52 v2(105.56,45.11)
  BOTTOM w0.102: v2(105.56,45.11) 105.43,44.64 UU1.P6
MIPI60_PREQ_N: length 1.2
  TOP w0.102: TP13.1 106.26,45.16 v2(106.22,45.11)
  BOTTOM w0.102: UU1.M6 106.08,44.64 v2(106.22,45.11)
NTCN: length 2.3
  TOP w0.381: PR650.1 v2(100.46,23.7)
  BOTTOM w0.127: v2(100.46,23.7) 101.45,23.7 v3(101.5,23.75)
  BOTTOM w0.381: PR653.2 v2(100.46,23.7)
NTCP: length 2.3
  TOP w0.381: PR651.1 v2(100.46,24.58)
  BOTTOM w0.127: v2(100.46,24.58) 100.96,24.58 v3(101.45,25.07)
  BOTTOM w0.305: PR652.2 100.43,24.61 v2(100.46,24.58)
NVJTAG_SEL: length 10.3
  BOTTOM w0.102: UV2.AD9 147.95,79.15 147.95,80.59 148.13,80.77 150.29,80.77 150.49,80.97 150.49,82.75 149.04,84.2 RV64.1 148.33,84.66 147.95,85.04 v3(147.8,85.04)
OVERT_N: length 11.3
  TOP w0.102: QV2.2 141.68,51.19 141.68,51.88 CV33.1 142.06,52.55 142.16,52.65 142.87,52.65 143.51,53.29 143.51,53.92 144.12,54.53 v1(144.12,56.33)
  BOTTOM w0.102: UV2.A6 145.29,59.66 145.29,58.29 144.12,57.12 v1(144.12,56.33) RV29.1
OVT_N: length 31.1
  TOP w0.102: v1(140.1,62.35) 140.1,58.14 137.29,55.32 135.56,55.32 135.13,54.89 135.13,52.85 135.58,52.4 136.65,52.4 138.05,51 v3(139.65,51) 141.06,51 QV2.3
  BOTTOM w0.102: v1(140.1,62.35) 139.55,61.8 138.56,61.8 138.2,62.15 v3(137.21,62.15) 136.52,62.15 135.94,61.57 RV49.1 RV248.1 RV250.1 134.4,61.39 QV7.3 134.36,60.54 DV14.3 131.53,61.93 DV16.1
PCBEEP: length 1.9
  TOP w0.203: CA15.1 175.77,32.79 175.07,32.1 UA2.48
PCH_DMIC1_CLK0: length 60.1
  TOP w0.102: CU15.1 70.1,60.99 v2(69.7,60.59) 69.29,60.18 RU136.2 ; v1(27.05,76.78) 26.92,76.65 v3(26.31,76.65) RX898.1
  ART03 w0.089: v2(69.7,60.59) 69.7,60.78 70.46,61.54 70.71,61.54 71.12,61.95 71.12,64.44 67.97,67.59 60.83,67.59 59.28,69.14 59.28,70.08 58.05,71.31 54.93,71.31 53.19,69.57 46.89,69.57 45.21,71.24 39.37,71.24 37.97,72.64 30.71,72.64 29.16,74.19 29.16,76.25 28.62,76.78 v1(27.05,76.78)
PCH_DMIC1_DATA0: length 68.7
  TOP w0.102: v2(68.87,58.87) 68.62,58.62 CU14.1 ; RX899.1 25.4,73.17 25.8,72.77 28.5,72.77 29.59,73.86 v3(29.59,75.46) v1(29.59,76.91)
  ART03 w0.089: v1(29.59,76.91) 29.37,76.69 29.37,74.28 30.8,72.86 38.06,72.86 39.46,71.46 45.3,71.46 46.98,69.78 53.1,69.78 54.84,71.52 58.14,71.52 59.5,70.17 59.5,69.23 60.92,67.8 68.06,67.8 71.33,64.53 71.33,63.66 71.84,63.16 71.84,60.45 71.62,60.23 69.48,60.23 69.34,60.09 69.34,59.56 68.87,59.09 v2(68.87,58.87)
  BOTTOM w0.102: v2(68.87,58.87) 69.3,58.45 UU1.DG34
PCH_DMIC2_CLK1: length 152.1
  TOP w0.102: v2(68.88,57.96) 69.16,58.24 70.86,58.24 71.02,58.39 v3(71.02,58.87) 71.02,59.69 70.81,59.89 RU138.1 CU16.1
  ART03 w0.089: v1(155.95,86.69) 155.45,86.18 144.27,86.18 143.64,86.81 136.8,86.81 134.49,89.13 131.54,89.13 131.19,89.48 130.25,89.48 128.63,91.09 128.38,91.09 127.56,91.91 127,91.91 124.21,94.71 61.99,94.71 59.85,92.56 59.85,87.96 58.8,86.92 58.8,81.84 58.44,81.48 58.44,79.35 57.2,78.1 57.2,77.75 56.23,76.78 v2(55.88,76.78)
  ART06 w0.102: v2(55.88,76.78) 55.88,76.48 57.02,75.33 57.02,72.44 62.58,66.88 63.47,66.88 64.79,65.55 65.28,65.55 65.48,65.35 67.16,65.35 67.87,64.64 69.59,64.64 70,64.23 70,62.61 70.05,62.56 70.05,61.08 70.25,60.88 70.25,59.81 69.7,59.26 69.39,59.26 69.24,59.1 69.24,58.34 68.88,57.99 v2(68.88,57.96)
  BOTTOM w0.102: v1(155.95,86.69) 156.21,86.69 156.55,87.03 RX915.1
PCH_DMIC2_DATA1: length 148.6
  TOP w0.102: CU17.1 70.99,61.09 v2(71.49,60.59)
  ART03 w0.089: v2(57.71,87.6) 57.71,88.01 58.16,88.47 58.16,90.8 59.28,91.91 59.28,92.89 61.72,95.33 125.57,95.33 126.93,93.96 126.93,93.62 128.69,91.86 130.62,91.86 131.11,91.36 132.48,91.36 133.5,90.35 134.87,90.35 135.46,89.76 136.22,89.76 138.21,87.77 155.9,87.77 v1(157.1,88.96)
  ART06 w0.102: v2(57.71,87.6) 57.55,87.45 56.72,87.45 56.13,86.87 56.13,84.3 56.41,84.02 56.41,77.95 57,77.37 57,76.45 59.33,74.11 62.08,74.11 63.42,72.77 63.42,72.11 64.2,71.33 64.2,69.1 66.42,66.88 67.05,66.88 67.61,66.32 67.61,65.96 68.35,65.22 69.77,65.22 70.93,64.07 70.93,61.15 v2(71.49,60.59)
  BOTTOM w0.102: v2(71.49,60.59) 71.46,60.58 UU1.DD39 ; RX916.1 v1(157.1,88.96) v3(157.72,88.96)
PCH_GPU_RST_N: length 163.4
  ART03 w0.089: v1(128.98,94.19) 127.07,96.1 61.41,96.1 56.28,90.97 56.28,86.71 56.47,86.53 56.47,79.4 54.91,77.85 53.39,77.85 53.03,77.49 v2(52.88,77.49)
  ART06 w0.102: v2(52.88,77.49) 52.88,73.58 49.58,70.28 49.58,64.28 53.57,60.3 56.61,60.3 57.4,59.51 57.4,59.13 v2(57.91,58.62) ; v1(128.98,94.19) 129.41,93.76 129.41,91.32 129.03,90.94 129.03,90.22 128.14,89.33 128.14,87.63 130.55,85.21 130.55,80.74 130.68,80.62 130.68,78.56 131.32,77.92 131.32,77.29 129.16,75.13 129.16,65.73 132.08,62.81 132.08,61.92 133.6,60.4 133.6,57.23 v1(133.05,56.68)
  BOTTOM w0.102: RU121.2 v2(57.91,58.62) CU13.2 57.4,59.61 v3(57.3,59.71) ; v1(133.05,56.68) RV143.2 132.55,56.14 132.65,56.05 UV1.2
PCH_GPU_RST_N_R: length 6.1
  BOTTOM w0.102: UU1.DV36 63.54,59.38 62.99,59.38 62.86,59.26 60.45,59.26 v3(59.84,58.65) 59.82,58.62 RU121.1 RU120.1
PCH_POPI_RCOMP: length 8.3
  BOTTOM w0.102: v3(58.11,41.42) 58.11,41.58 58.52,41.98 58.52,42.21 RU28.2 58.8,42.36 59.54,41.63 60.48,41.63 62.36,43.51 63.5,43.51 63.63,43.63 64.01,43.63 64.31,43.33 UU1.DU3
PCH_PWROK: length 239.3
  TOP w0.102: v1(156.06,25.12) 155.96,25.12 DL2.2 ; RE452.2 169.65,19.99 v1(169.87,20.21) ; RU175.1 67.1,62.99 CU38.1 66.93,63.88 v2(66,64.81)
  ART03 w0.089: v2(66,64.81) 64.07,64.81 63.96,64.69 61.26,64.69 60.15,65.81 58.21,65.81 57.35,64.95 56.23,64.95 54.25,62.96 54.25,60.47 55.01,59.71 55.01,54.48 54.81,54.28 54.81,52.88 54.1,52.17 54.1,51.03 51.92,48.84 51.92,47.42 51.61,47.11 51.61,43.05 50.52,41.96 50.52,36.37 50.82,36.07 50.82,29.72 46.53,25.42 45.9,25.42 39.19,18.72 39.19,13.51 40.33,12.37 40.33,6.93 43.74,3.53 46.84,3.53 47.47,4.16 70.03,4.16 70.97,5.1 72.69,5.1 73.2,4.59 90.07,4.59 90.47,4.19 98.65,4.19 102.13,7.67 104.72,7.67 105.31,8.25 107.95,8.25 108.41,7.8 110.49,7.8 110.84,7.44 115.87,7.44 116.79,6.53 132.33,6.53 133.65,7.85 134.92,7.85 135.51,8.43 137.64,8.43 138.33,7.74 145.69,7.74 148.44,10.49 148.84,10.49 148.99,10.34 148.99,9.89 149.13,9.75 152.12,9.75 153.77,11.4 153.77,14.25 153.87,14.35 155.75,14.35 156.15,14.75 156.62,14.75 157.17,15.3 157.17,19.02 156.82,19.38 156.82,23.8 156.56,24.05 156.56,24.81 156.26,25.12 v1(156.06,25.12)
  ART05 w0.102: v1(169.87,20.21) 169.6,19.94 166.06,19.94 164.84,21.16 164.21,21.16 164.08,21.03 163.57,21.03 163.37,21.23 163.37,22.68 162.38,23.67 158.01,23.67 156.56,25.12 v1(156.06,25.12)
  BOTTOM w0.102: v2(66,64.81) 66.32,64.49 UU1.DN47
PCH_SMB1_CLK: length 27.5
  TOP w0.102: v2(68.26,54.28) 68.11,54.43 RU35.1
  ART06 w0.102: v2(54.25,56.11) 56.01,54.35 61.44,54.35 62.15,55.06 65.02,55.06 65.35,54.73 66.75,54.73 67.2,54.28 v2(68.26,54.28)
  BOTTOM w0.102: v2(54.25,56.11) 54.1,56.11 53.49,55.5 53.49,53.06 53.26,52.83 52.4,52.83 52.17,52.6 52.17,51.79 51.46,51.08 51.46,49.55 51.71,49.3 52.63,49.3 v3(52.68,49.35) 52.68,50.26 52.69,50.27 QU1.3 ; UU1.DK27 68,54.55 v2(68.26,54.28)
PCH_SMB1_DATA: length 14.7
  ART06 w0.102: v2(65.79,53.39) 63.07,53.39 62.84,53.16 54.04,53.16 v2(54.01,53.19)
  BOTTOM w0.102: v2(65.79,53.39) 66.05,53.65 UU1.DP24 ; RU36.1 54.94,53.19 v2(54.01,53.19) 53.99,53.16 QU1.6
PCH_WLAN_OFF_N: length 254.6
  TOP w0.102: v1(150.19,14.42) 150.32,14.55 RW6.1
  ART03 w0.089: v2(73.91,69.8) 72.79,69.8 69.77,72.82 65.52,72.82 63.62,74.72 57.23,74.72 56.9,74.39 47.22,74.39 46.1,75.51 42.29,75.51 40.56,77.24 36.24,77.24 v1(34.67,78.81)
  ART05 w0.102: v1(34.67,78.81) 34.67,76.83 36.73,74.78 36.73,66.9 33.91,64.08 29.08,64.08 27.89,62.89 27.89,62.35 28.7,61.54 28.7,56.33 28.34,55.98 28.34,50.47 28.8,50.01 28.8,47.29 28.29,46.78 28.29,45.06 29.08,44.27 29.08,42.75 29.46,42.36 29.46,38.05 32,35.51 32,34.44 34.08,32.36 34.08,15.9 36.32,13.66 36.32,12.36 38.82,9.85 40,9.85 42.41,7.44 49.91,7.44 50.67,6.68 62.36,6.68 65.1,9.42 72.88,9.42 73.49,8.81 88.29,8.81 89.02,8.07 104.62,8.07 106.22,6.47 106.68,6.47 107.54,5.61 109.52,5.61 110.72,6.8 128.65,6.8 130.15,8.3 142,8.3 142.53,7.77 144.6,7.77 145.67,8.84 145.67,12.65 147.44,14.42 v1(150.19,14.42)
  BOTTOM w0.102: 78.74,65.79 78.74,66.32 78.36,66.7 78.36,67.28 75.48,70.15 v3(74.72,70.15) 74.37,69.8 v2(73.91,69.8)
PCIE13_CRX_DTX_N: length 81.2
  ART06 w0.102: v2(79.97,45.66) 79.9,45.59 79.71,45.59 79.61,45.68 79.61,46.04 79.26,46.39 78.7,46.39 78.03,47.06 71.27,47.06 70.17,45.96 70.17,44.17 68.87,42.88 68.87,41.66 67.91,40.7 66.96,40.7 66.66,41 66.66,41.51 66.04,42.12 62.27,42.12 61.44,41.29 54.77,41.29 51.42,37.93 48.17,37.93 47.61,37.37 43.38,37.37 40.13,34.13 40.13,32.26 39.98,32.11 39.74,32.11 v1(39.62,32.22)
  BOTTOM w0.076: UU1.CG7 79.8,45.55 v2(79.97,45.66)
  BOTTOM w0.102: v1(39.62,32.22) 39.81,32.04 40.09,32.04 41.55,30.58 41.55,29.36 43.81,27.1 43.81,24.33 43.13,23.64 43.13,21.49 37.21,15.57 37.21,13.54 34.89,11.22 34.89,9.79 35.05,9.63 JSSD1.5
PCIE13_CRX_DTX_P: length 81.2
  ART06 w0.102: v2(79.97,45.01) 79.97,45.17 79.8,45.34 79.61,45.34 79.4,45.55 79.4,45.95 79.17,46.17 78.61,46.17 77.94,46.85 71.36,46.85 70.38,45.87 70.38,44.08 69.09,42.79 69.09,41.57 68,40.49 66.87,40.49 66.44,40.91 66.44,41.42 65.95,41.91 62.36,41.91 61.52,41.07 54.86,41.07 51.51,37.72 48.26,37.72 47.7,37.16 43.47,37.16 40.35,34.04 40.35,32.17 40.07,31.89 39.87,31.89 v1(39.62,31.64)
  BOTTOM w0.076: UU1.CG6 79.8,44.9 v2(79.97,45.01)
  BOTTOM w0.102: v1(39.62,31.64) 39.81,31.82 40,31.82 41.34,30.49 41.34,29.27 43.6,27.01 43.6,24.42 42.91,23.73 42.91,21.58 36.99,15.66 36.99,13.63 34.67,11.31 34.67,9.75 34.55,9.63 JSSD1.7
PCIE13_CTX_DRX_N: length 67.4
  ART06 w0.102: v1(40.31,29.53) 40.14,29.7 40.14,30.06 40.32,30.23 40.52,30.23 40.71,30.42 40.71,30.62 40.89,30.81 41.09,30.81 41.28,30.99 41.28,31.2 41.47,31.38 41.67,31.38 41.86,31.57 41.86,31.77 45.55,35.47 47.94,35.47 48.5,36.03 53.91,36.03 54.47,35.47 57.95,35.47 60.46,37.98 65.44,37.98 66.69,39.23 68.53,39.23 70.19,40.89 70.19,42.02 71.84,43.67 73.24,43.67 73.5,43.94 74.24,43.94 74.34,43.84 v2(74.34,43.61)
  BOTTOM w0.102: v1(40.31,29.53) 40.13,29.35 40.13,28.9 41.06,27.98 41.82,27.98 43.17,26.63 43.17,24.65 42.47,23.95 42.47,21.79 36.32,15.64 36.32,13.54 35.09,12.3 33.97,12.3 33.48,11.81 33.48,11.61 CN2.1 ; UU1.CT3 74.6,43.36 v2(74.34,43.61)
PCIE13_CTX_DRX_N_C: length 2.1
  BOTTOM w0.102: CN2.2 33.63,10.89 33.53,10.79 33.53,10.28 33.42,10.18 33.42,9.73 33.55,9.6 JSSD1.11
PCIE13_CTX_DRX_P: length 67.4
  ART06 w0.102: v2(74.48,44.46) 74.18,44.15 73.41,44.15 73.15,43.89 71.75,43.89 69.98,42.11 69.98,40.98 68.44,39.44 66.6,39.44 65.35,38.2 60.37,38.2 57.86,35.68 54.56,35.68 54,36.24 48.41,36.24 47.85,35.68 45.46,35.68 39.93,30.15 39.93,29.73 v1(39.73,29.53)
  BOTTOM w0.102: v1(39.73,29.53) 39.91,29.35 39.91,28.81 40.97,27.76 41.73,27.76 42.95,26.54 42.95,24.74 42.25,24.04 42.25,21.88 36.1,15.73 36.1,13.63 35,12.52 33.88,12.52 33.26,11.9 33.26,11.59 CN3.1 ; UU1.CT5 74.73,44.21 v2(74.48,44.46)
PCIE13_CTX_DRX_P_C: length 2.2
  BOTTOM w0.102: CN3.2 33.12,10.89 33.31,10.7 33.31,10.37 33.21,10.27 33.21,9.71 33.05,9.55 JSSD1.13
PCIE14_CRX_DTX_N: length 86
  ART06 w0.102: v1(37.34,30.99) 37.51,30.81 38,30.81 38.12,30.93 38.41,30.93 38.53,30.81 38.82,30.81 38.94,30.93 39.22,30.93 39.34,30.81 39.7,30.81 41.51,32.62 41.51,34.5 42.26,35.24 43.27,35.24 44.77,36.74 47.99,36.74 48.55,37.3 52.03,37.3 55.38,40.65 59.92,40.65 60.51,40.07 68.17,40.07 69.43,41.33 69.43,42.6 71.18,44.35 71.18,46.06 71.41,46.29 77.48,46.29 77.81,45.96 77.81,45.43 78.07,45.17 78.37,45.17 78.48,45.29 78.78,45.29 78.89,45.17 79.25,45.17 79.79,44.64 79.97,44.64 80.17,44.44 80.17,44.26 80.27,44.16 81.1,44.16 81.21,44.27 81.21,44.53 81.09,44.66 80.98,44.66 v2(80.85,44.52)
  BOTTOM w0.076: v2(80.85,44.52) 80.65,44.52 UU1.CE6
  BOTTOM w0.102: v1(37.34,30.99) 37.52,30.81 38,30.81 38.7,30.11 38.7,29.19 40.64,27.25 41.53,27.25 42.54,26.24 42.54,25.04 41.81,24.31 41.81,22.02 35.56,15.77 35.56,14.81 32.46,11.71 32.46,11.05 31.9,10.49 31.9,9.78 32.05,9.63 JSSD1.17
PCIE14_CRX_DTX_P: length 86.1
  ART06 w0.102: v1(37.34,30.41) 37.53,30.6 39.79,30.6 41.73,32.53 41.73,34.41 42.35,35.02 43.36,35.02 44.85,36.52 48.08,36.52 48.64,37.08 52.12,37.08 55.47,40.43 59.83,40.43 60.42,39.85 68.26,39.85 69.64,41.24 69.64,42.51 71.4,44.26 71.4,45.97 71.5,46.07 77.39,46.07 77.6,45.87 77.6,45.34 77.98,44.96 79.16,44.96 80.18,43.94 81.18,43.94 81.43,44.19 81.43,44.62 81.18,44.87 81.15,44.87 v2(80.85,45.17)
  BOTTOM w0.076: UU1.CE7 80.65,45.17 v2(80.85,45.17)
  BOTTOM w0.102: v1(37.34,30.41) 37.52,30.59 37.91,30.59 38.48,30.02 38.48,29.11 40.55,27.04 41.44,27.04 42.33,26.15 42.33,25.13 41.59,24.39 41.59,22.11 35.34,15.86 35.34,14.9 32.24,11.8 32.24,11.14 31.68,10.58 31.68,9.71 31.55,9.58 JSSD1.19
PCIE14_CTX_DRX_N: length 61.3
  ART06 w0.102: v2(73.3,40.33) 73.45,40.18 73.45,39.69 69.94,36.18 69.3,36.18 68.62,35.49 68.62,35.34 68.03,34.76 62.52,34.76 60.18,32.42 47.86,32.42 41.68,26.24 41.37,26.24 v1(41.2,26.42)
  BOTTOM w0.102: CN8.1 31.44,12.11 31.44,12.27 32.96,13.79 33.58,13.79 34.54,14.75 34.54,15.64 41.17,22.27 41.17,24.69 41.91,25.42 41.91,25.96 41.65,26.22 41.4,26.22 v1(41.2,26.42) ; UU1.CT2 74.46,42.2 74.46,41.77 73.47,40.78 73.47,40.5 v2(73.3,40.33)
PCIE14_CTX_DRX_N_C: length 3.4
  BOTTOM w0.102: JSSD1.23 30.55,9.6 30.38,9.78 30.38,10.44 30.67,10.73 31.18,10.73 31.44,11 31.44,11.3 CN8.2
PCIE14_CTX_DRX_P: length 61.3
  ART06 w0.102: v1(41.2,25.84) 41.39,26.03 41.77,26.03 47.95,32.2 60.27,32.2 62.61,34.54 68.12,34.54 68.83,35.25 68.83,35.41 69.39,35.96 70.03,35.96 71.62,37.55 71.79,37.55 71.99,37.76 71.99,37.92 72.2,38.13 72.37,38.13 72.57,38.33 72.57,38.5 72.77,38.7 72.94,38.7 73.14,38.9 73.14,39.07 73.67,39.6 73.67,40.11 v2(73.89,40.33)
  BOTTOM w0.102: UU1.CT1 74.67,42 74.67,41.68 74.36,41.37 74.36,41.09 74.21,40.94 73.94,40.94 73.69,40.69 73.69,40.53 v2(73.89,40.33) ; CN9.1 31.23,12.1 31.23,12.36 31.54,12.67 31.54,12.89 31.68,13.03 31.9,13.03 32.09,13.23 32.09,13.43 32.34,13.67 32.54,13.67 32.87,14 33.49,14 34.33,14.84 34.33,15.73 40.96,22.36 40.96,24.78 41.69,25.51 41.69,25.87 41.57,26 41.36,26 v1(41.2,25.84)
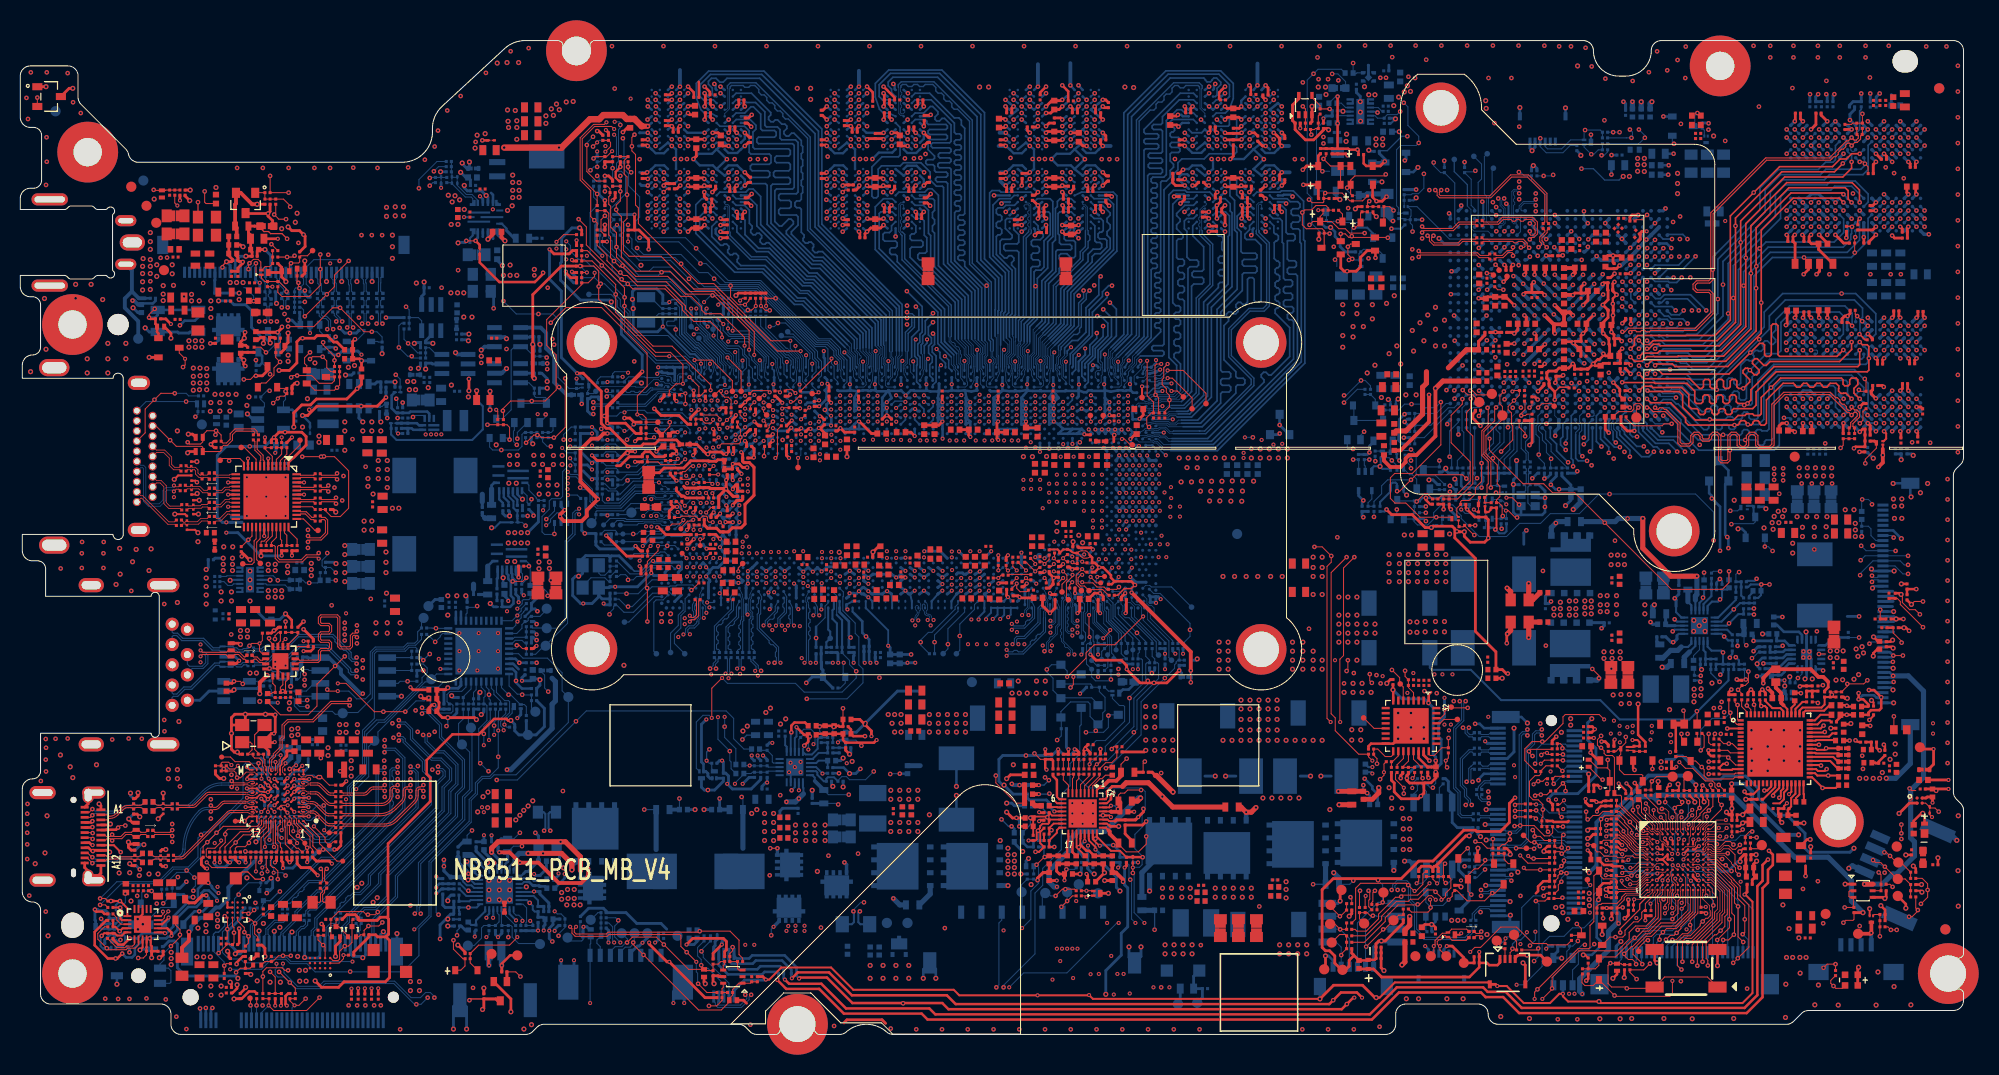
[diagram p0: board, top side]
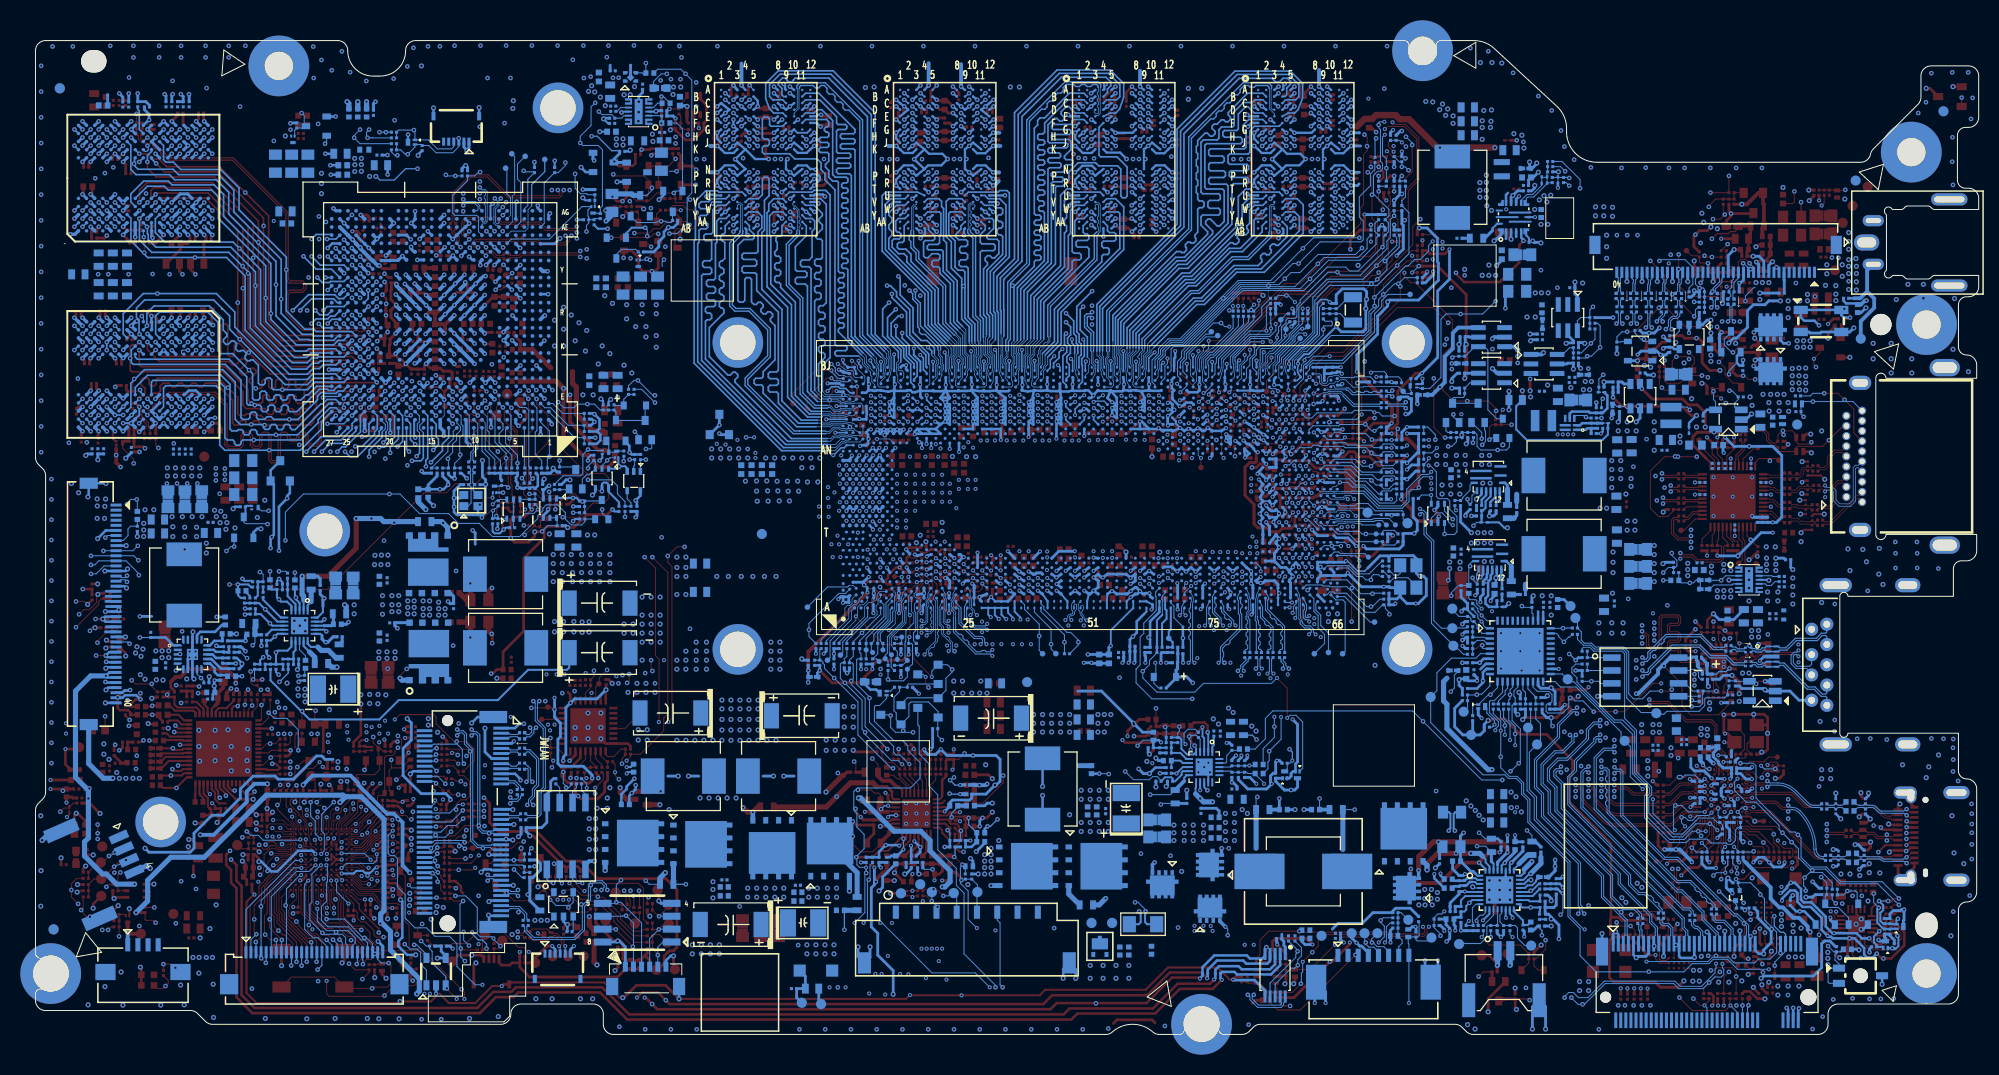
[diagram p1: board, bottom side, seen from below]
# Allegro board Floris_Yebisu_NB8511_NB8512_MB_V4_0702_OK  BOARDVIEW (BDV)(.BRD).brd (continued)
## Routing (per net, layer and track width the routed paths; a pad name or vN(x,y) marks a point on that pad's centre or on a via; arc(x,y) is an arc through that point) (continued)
PCIE14_CTX_DRX_P_C: length 3.3
  BOTTOM w0.102: CN9.2 31.23,11.31 31.23,11.08 31.09,10.94 30.58,10.94 30.16,10.53 30.16,9.71 30.05,9.6 JSSD1.25
PCIE15_CRX_DTX_N: length 82
  ART06 w0.102: v1(37.34,29.56) 37.52,29.37 39.22,29.37 39.48,29.11 40.77,29.11 42.63,30.97 42.63,31.96 45.74,35.06 48.14,35.06 48.7,35.62 52.35,35.62 52.91,35.06 58.89,35.06 61.4,37.58 65.7,37.58 66.94,38.82 68.72,38.82 70.52,40.63 70.52,41.91 71.75,43.14 77.91,43.14 78.05,43.28 78.31,43.28 78.45,43.14 78.72,43.14 78.86,43.28 79.13,43.28 79.26,43.14 79.53,43.14 79.67,43.28 79.94,43.28 80.08,43.14 80.34,43.14 80.48,43.28 80.75,43.28 80.89,43.14 81.93,43.14 82.14,43.35 82.14,44.33 82.04,44.43 v2(81.81,44.43)
  BOTTOM w0.102: UU1.CC5 v2(81.81,44.43) ; v1(37.34,29.56) 37.52,29.37 37.74,29.37 37.97,29.14 37.97,28.9 39.88,27 39.88,26.07 40.54,25.41 40.54,22.65 29.26,11.38 29.26,10.49 28.9,10.13 28.9,9.78 29.05,9.63 JSSD1.29
PCIE15_CRX_DTX_P: length 82.1
  ART06 w0.102: v1(37.34,28.97) 37.52,29.16 39.13,29.16 39.39,28.89 40.86,28.89 42.85,30.88 42.85,31.87 45.83,34.85 48.23,34.85 48.79,35.41 52.26,35.41 52.82,34.85 58.98,34.85 61.49,37.36 65.78,37.36 67.03,38.61 68.81,38.61 70.74,40.54 70.74,41.82 71.84,42.92 82.02,42.92 82.36,43.26 82.36,44.46 v2(81.81,45.01)
  BOTTOM w0.102: v1(37.34,28.97) 37.52,29.16 37.65,29.16 37.76,29.06 37.76,28.81 39.66,26.91 39.66,25.98 40.32,25.32 40.32,22.74 40.13,22.55 29.04,11.47 29.04,10.58 28.69,10.22 28.69,9.76 28.55,9.63 JSSD1.31 ; UU1.CC6 v2(81.81,45.01)
PCIE15_CTX_DRX_N: length 67.7
  ART06 w0.102: v1(38.49,26.42) 38.49,26.34 38.59,26.24 38.85,26.24 39.16,25.93 39.95,25.93 40.49,25.38 41.7,25.38 48.11,31.8 60.53,31.8 62.81,34.07 68.27,34.07 68.93,34.73 70.17,34.73 70.57,35.14 71.21,35.14 71.79,35.72 71.79,36.71 72.4,37.31 72.4,37.52 72.58,37.71 72.79,37.71 72.97,37.89 72.97,38.1 73.16,38.28 73.37,38.28 73.55,38.46 73.55,38.67 73.73,38.86 73.94,38.86 74.12,39.04 74.12,39.25 74.31,39.43 74.52,39.43 74.76,39.67 74.76,40.08 v2(74.53,40.31)
  BOTTOM w0.102: v1(38.49,26.42) 38.67,26.24 38.86,26.24 39.24,25.85 39.24,22.35 29.16,12.27 28.56,12.27 28.37,12.08 28.37,11.89 CN10.1 ; v2(74.53,40.31) 74.71,40.5 74.71,41.03 75.35,41.67 75.35,42.03 75.21,42.17 75.21,42.43 75.35,42.57 75.35,42.98 UU1.CR3
PCIE15_CTX_DRX_N_C: length 2.9
  BOTTOM w0.102: CN10.2 28.34,11.1 28.34,10.79 27.99,10.44 27.79,10.44 27.43,10.08 27.43,9.73 27.55,9.61 JSSD1.35
PCIE15_CTX_DRX_P: length 67.8
  ART06 w0.102: v2(75.11,40.31) 74.97,40.17 74.97,39.58 72.01,36.62 72.01,35.63 71.3,34.92 70.66,34.92 70.25,34.52 69.02,34.52 68.36,33.86 62.9,33.86 60.62,31.58 48.2,31.58 41.79,25.17 40.4,25.17 39.86,25.71 39.07,25.71 38.76,26.03 38.59,26.03 38.49,25.92 v1(38.49,25.84)
  BOTTOM w0.102: CN11.1 28.15,11.92 28.15,12.17 28.47,12.49 29.07,12.49 39.03,22.44 39.03,25.77 38.77,26.02 38.67,26.02 v1(38.49,25.84) ; UU1.CR4 75.59,43.13 75.59,42.9 75.56,42.87 75.56,41.58 74.93,40.94 74.93,40.5 v2(75.11,40.31)
PCIE15_CTX_DRX_P_C: length 2.9
  BOTTOM w0.102: JSSD1.37 27.05,9.6 27.21,9.76 27.21,10.17 27.7,10.65 27.9,10.65 28.13,10.88 28.13,11.15 28.03,11.25 CN11.2
PCIE16_SATA_CRX_DTX_N: length 83.4
  ART06 w0.102: v2(82.71,45.01) 82.84,44.88 83.06,44.88 83.28,44.65 83.28,43.25 82.32,42.29 71.96,42.29 71.36,41.68 71.36,40.27 69.07,37.98 67.32,37.98 66.06,36.73 61.75,36.73 59.25,34.22 47,34.22 45.77,32.99 45.08,32.99 43.55,31.46 43.55,30.69 41.13,28.27 36.83,28.27 36.58,28.02 36.11,28.02 v1(35.92,27.83)
  BOTTOM w0.102: 82.27,44.73 v2(82.71,45.01) ; JSSD1.43 25.55,9.67 25.7,9.83 25.7,10.03 27.09,11.42 27.09,12.1 29.25,14.26 29.68,14.26 37.72,22.3 37.72,27.2 36.9,28.01 36.11,28.01 v1(35.92,27.83)
PCIE16_SATA_CRX_DTX_P: length 83.4
  ART06 w0.102: v2(82.71,44.43) 82.71,44.56 82.81,44.66 82.97,44.66 83.07,44.56 83.07,43.34 82.23,42.5 71.87,42.5 71.14,41.77 71.14,40.36 68.98,38.2 67.23,38.2 65.97,36.94 61.66,36.94 59.16,34.44 46.91,34.44 45.68,33.21 44.99,33.21 43.33,31.54 43.33,30.77 41.04,28.48 39.02,28.48 38.88,28.62 38.62,28.62 38.48,28.48 38.21,28.48 38.07,28.62 37.8,28.62 37.66,28.48 36.74,28.48 36.49,28.24 36.1,28.24 v1(35.92,28.41)
  BOTTOM w0.102: v1(35.92,28.41) 36.11,28.23 36.99,28.23 37.93,27.29 37.93,22.21 29.77,14.04 29.34,14.04 27.3,12.01 27.3,11.33 25.92,9.94 25.92,9.71 26.05,9.58 JSSD1.41 ; 82.27,44.08 v2(82.71,44.43)
PCIE16_SATA_CTX_DRX_N: length 68.8
  ART06 w0.102: v1(37.22,25.8) 37.41,25.99 37.75,25.99 37.97,26.21 37.97,26.62 38.23,26.87 39.56,26.87 39.69,26.74 39.99,26.74 40.12,26.87 40.37,26.87 40.5,26.74 40.81,26.74 40.93,26.87 41.73,26.87 47.69,32.83 59.89,32.83 62.36,35.3 66.67,35.3 67.12,35.75 67.35,35.75 67.56,35.96 67.56,36.19 67.96,36.59 69.67,36.59 72.86,39.78 72.86,40.57 73.14,40.85 75.8,40.85 75.93,40.73 75.93,40.53 v2(75.72,40.32)
  BOTTOM w0.102: CN12.1 26.21,12.52 26.21,12.7 26.46,12.94 26.63,12.94 26.83,13.14 26.83,13.32 27.03,13.52 27.21,13.52 27.41,13.71 27.41,13.89 27.6,14.09 27.78,14.09 27.98,14.29 27.98,14.47 28.48,14.97 29.78,14.97 36.66,21.85 36.66,22.51 36.8,22.65 36.8,22.92 36.66,23.06 36.66,23.32 36.8,23.46 36.8,23.73 36.66,23.87 36.66,24.14 36.8,24.28 36.8,24.54 36.66,24.68 36.66,24.95 36.8,25.09 36.8,25.35 36.66,25.49 36.66,25.97 36.77,26.07 36.94,26.07 v1(37.22,25.8) ; v2(75.72,40.32) 75.93,40.53 75.93,40.9 75.79,41.04 75.79,41.3 75.93,41.44 75.93,41.98 UU1.CP1
PCIE16_SATA_CTX_DRX_N_C: length 4.2
  BOTTOM w0.102: JSSD1.47 24.55,9.76 24.43,9.88 24.43,10.34 25.14,11.05 25.96,11.05 26.21,11.3 26.21,11.71 CN12.2
PCIE16_SATA_CTX_DRX_P: length 68.8
  ART06 w0.102: v1(37.22,26.38) 37.39,26.2 37.66,26.2 37.76,26.3 37.76,26.71 38.14,27.09 41.64,27.09 47.6,33.04 59.8,33.04 62.27,35.52 66.58,35.52 67.87,36.8 69.58,36.8 72.64,39.87 72.64,40.66 73.05,41.07 75.89,41.07 76.15,40.82 76.15,40.47 v2(76.3,40.32)
  BOTTOM w0.102: v1(37.22,26.38) 37.12,26.29 36.68,26.29 36.45,26.06 36.45,21.94 29.69,15.19 28.39,15.19 26,12.79 26,12.51 CN13.1 ; v2(76.3,40.32) 76.15,40.47 76.15,42.11 UU1.CP2
PCIE16_SATA_CTX_DRX_P_C: length 4.3
  BOTTOM w0.102: JSSD1.49 24.05,9.7 24.22,9.87 24.22,10.42 25.05,11.26 25.87,11.26 26,11.39 26,11.72 CN13.2
PCIE_CLKREQ_VGA_N: length 153.9
  TOP w0.102: v2(52.88,78.15) 53.59,78.86 RU103.1
  ART03 w0.089: v2(52.88,78.15) 52.98,78.15 53.52,78.69 55.04,78.69 55.99,79.64 55.99,86.29 54.86,87.42 54.86,90.85 61.05,97.04 133.72,97.04 135.18,95.58 135.18,92.58 135.89,91.87 v1(136.45,91.87)
  ART06 w0.102: v2(67.67,57.87) 67.29,57.87 66.04,59.13 66.04,59.51 65.15,60.4 64.44,60.4 62.51,62.33 59.79,62.33 58.19,63.93 54.91,63.93 54.3,64.54 54.3,64.95 51.76,67.49 51.76,70.74 54.79,73.76 54.79,77.11 54.1,77.8 53.34,77.8 52.98,78.15 v2(52.88,78.15)
  BOTTOM w0.102: v1(136.45,91.87) 136.85,91.46 136.85,89.63 137.92,88.57 v3(137.92,87.91) 137.67,87.65 136.14,87.65 135.74,87.25 135.74,81.71 135.95,81.5 RV13.2 136.25,80.95 136.29,80.99 QV1.3 ; UU1.DK33 68,57.48 v2(67.67,57.87)
PCIE_CRX_C_GTX_N0: length 2.9
  TOP w0.102: CV7.2 145.58,76.6 146.25,76.6 146.74,77.09 147.12,77.09 147.22,76.99 v1(147.22,76.78)
  BOTTOM w0.102: UV2.AB9 v1(147.22,76.78)
PCIE_CRX_C_GTX_N1: length 5.8
  TOP w0.102: CV9.2 144.31,78.2 147.2,78.2 147.34,78.05 147.6,78.05 147.75,78.2 148.14,78.2 148.4,77.94 148.4,77.7 148.3,77.6 v1(148,77.6)
  BOTTOM w0.102: UV2.AC10 v1(148,77.6)
PCIE_CRX_C_GTX_N2: length 8.6
  TOP w0.102: v1(148.87,78.4) 149.06,78.59 149.29,78.59 149.62,78.92 149.62,80.12 149.16,80.58 146.16,80.58 145.69,80.11 144.32,80.11 CV14.2
  BOTTOM w0.102: UV2.AC11 v1(148.87,78.4)
PCIE_CRX_C_GTX_N3: length 2.9
  TOP w0.102: v1(150.54,77.62) 150.26,77.91 150.26,78.09 150.07,78.27 150.07,78.55 150.58,79.05 150.58,79.3 CV27.2
  BOTTOM w0.102: UV2.AB12 v1(150.54,77.62)
PCIE_CRX_C_GTX_P0: length 2.9
  TOP w0.102: v1(147.22,77.62) 147.22,77.41 147.12,77.31 146.65,77.31 146.16,76.81 145.58,76.81 CV6.2
  BOTTOM w0.102: UV2.AC9 v1(147.22,77.62)
PCIE_CRX_C_GTX_P1: length 5.8
  TOP w0.102: CV8.2 144.31,78.41 148.23,78.41 148.62,78.03 148.62,77.77 v1(148.81,77.57)
  BOTTOM w0.102: UV2.AB10 v1(148.81,77.57)
PCIE_CRX_C_GTX_P2: length 8.5
  TOP w0.102: v1(148.87,79.2) 148.87,78.91 148.97,78.81 149.2,78.81 149.41,79.01 149.41,79.32 149.3,79.42 149.3,79.72 149.41,79.83 149.41,80.03 149.07,80.36 148.41,80.36 148.23,80.19 148,80.19 147.82,80.36 147.59,80.36 147.41,80.19 147.19,80.19 147.01,80.36 146.25,80.36 145.78,79.89 144.32,79.89 CV13.2
  BOTTOM w0.102: UV2.AD11 v1(148.87,79.2)
PCIE_CRX_C_GTX_P3: length 2.9
  TOP w0.102: v1(149.73,77.63) 149.82,77.63 150.04,77.85 150.04,78 149.86,78.18 149.86,78.64 150.36,79.14 150.36,79.28 CV26.2
  BOTTOM w0.102: UV2.AC12 150.1,78 v1(149.73,77.63)
PCIE_CRX_GTX_N0: length 100.3
  TOP w0.102: CV7.1 144.78,76.6 143.89,76.6 143.64,76.85 138.1,76.85 v1(137.92,76.67)
  ART03 w0.102: v1(137.92,76.67) 138.11,76.86 138.36,76.86 138.47,76.76 138.47,76.49 138.35,76.37 138.35,76.08 138.47,75.97 138.47,75.67 138.35,75.56 138.35,75.27 138.47,75.15 138.47,74.79 138.14,74.46 137.96,74.46 137.76,74.26 137.76,74.09 137.57,73.89 137.39,73.89 137.19,73.69 137.19,73.51 136.99,73.31 136.81,73.31 136.61,73.11 136.61,72.94 129.83,66.15 129.83,61.69 128.32,60.17 128.32,55.75 122.14,49.58 116.48,49.58 113.61,46.71 111.61,46.71 109.55,44.65 106.42,44.65 105.92,44.14 100.66,44.14 100.28,43.76 96.21,43.76 95.83,43.38 86.1,43.38 85.99,43.27 85.79,43.27 85.6,43.08 85.6,42.88 85.42,42.69 85.21,42.69 85.03,42.51 85.03,42.3 84.84,42.12 84.64,42.12 84.45,41.93 84.45,41.73 84.26,41.54 83.96,41.54 83.84,41.65 83.55,41.65 83.44,41.54 83.14,41.54 83.03,41.65 82.74,41.65 82.62,41.54 82.33,41.54 82.22,41.65 81.92,41.65 81.81,41.54 80.27,41.54 80.21,41.48 79.64,40.9 78.14,40.9 77.5,41.54 75.95,41.54 75.84,41.65 75.55,41.65 75.43,41.54 75.14,41.54 75.02,41.65 74.73,41.65 74.62,41.54 73.19,41.54 72.9,41.83 72.9,42 72.7,42.2 72.52,42.2 72.39,42.34 72.39,42.7 72.52,42.82 72.52,43.1 72.39,43.23 72.39,43.51 72.52,43.64 72.52,43.92 72.39,44.04 72.39,44.36 72.49,44.46 v2(72.65,44.46)
  BOTTOM w0.102: v2(72.65,44.46) 72.38,44.73 UU1.DA6
PCIE_CRX_GTX_N1: length 100.4
  TOP w0.102: v1(138.79,78.76) 138.97,78.57 138.97,78.24 139.38,77.84 141.9,77.84 142.26,78.2 143.51,78.2 CV9.1
  ART03 w0.076: v2(73.57,45.11) 73.81,44.87 73.96,44.87 74.13,44.69 74.13,44.28 74.02,44.17 73.92,44.08 73.71,43.94 73.57,43.94 73.43,43.81 73.43,43.77 73.42,43.76
  ART03 w0.102: v1(138.79,78.76) 138.99,78.56 138.99,78.2 138.86,78.08 137.06,78.08 133.18,74.2 131.73,74.2 129.07,71.54 129.07,61.8 127.7,60.43 127.7,56.01 121.89,50.2 116.22,50.2 113.85,47.83 110.36,47.83 109.98,47.44 105.66,47.44 105.05,48.05 100.18,48.05 98.64,46.52 83.53,46.52 83.07,46.06 83.07,43.55 82.12,42.59 73.99,42.59 73.32,43.27 73.32,43.66 73.42,43.76
  BOTTOM w0.102: UU1.CY7 73.29,45.38 v2(73.57,45.11)
PCIE_CRX_GTX_N2: length 97.5
  TOP w0.102: CV14.1 143.52,80.11 141.88,80.11 141.25,79.47 138.44,79.47 v1(138.26,79.66)
  ART03 w0.076: v2(74.48,45.67) 74.68,45.47 74.86,45.47 75.03,45.3 75.03,44.08 75.05,44.06 75.05,44.04
  ART03 w0.102: 75.05,44.04 75.05,43.89 75.73,43.22 80.05,43.22 81.21,44.38 81.21,45.96 81.77,46.52 82.08,46.52 84.02,48.46 99.77,48.46 100.48,49.17 103.07,49.17 103.76,49.86 104.65,49.86 106.08,48.42 109.51,48.42 110.14,49.06 111.54,49.06 112.44,49.96 115.1,49.96 115.97,50.82 121.63,50.82 127.07,56.27 127.07,60.69 128.31,61.92 128.31,71.79 131.99,75.47 133.18,75.47 137.16,79.45 138.05,79.45 v1(138.26,79.66)
  BOTTOM w0.102: v2(74.48,45.67) 74.32,45.67 UU1.CV7
PCIE_CRX_GTX_N3: length 108.8
  TOP w0.102: CV27.1 150.57,80.12 150.57,82.93 148.74,84.76 146.99,84.76 144.94,82.71 140.05,82.71 139.95,82.81 139.95,83.07 v1(140.14,83.26)
  ART03 w0.102: v1(140.14,83.26) 139.95,83.07 139.95,82.88 135.29,78.22 134.07,78.22 127.76,71.9 127.76,61.95 126.53,60.72 126.53,56.3 121.46,51.23 115.8,51.23 114.97,50.4 112.3,50.4 111.8,49.9 110.07,49.9 109.33,49.16 107.88,49.16 107.69,49.35 105.61,49.35 104.05,50.91 101.81,50.91 99.87,48.97 83.72,48.97 81.05,46.3 80.06,46.3 79.61,45.86 79.61,44.13 79.11,43.62 76.23,43.62 v2(75.4,44.46)
  BOTTOM w0.076: v2(75.4,44.46) 75.23,44.56 UU1.CT6
PCIE_CRX_GTX_P0: length 100.4
  TOP w0.102: CV6.1 144.78,76.81 143.98,76.81 143.73,77.07 138.1,77.07 v1(137.92,77.25)
  ART03 w0.102: v1(137.92,77.25) 138.1,77.07 138.45,77.07 138.68,76.85 138.68,74.7 130.05,66.06 130.05,61.6 128.53,60.08 128.53,55.66 122.23,49.36 116.57,49.36 113.7,46.49 111.7,46.49 109.64,44.43 106.51,44.43 106.01,43.93 100.75,43.93 100.37,43.55 96.3,43.55 95.92,43.16 86.19,43.16 84.35,41.32 80.36,41.32 79.73,40.69 78.05,40.69 77.41,41.32 73.1,41.32 72.17,42.25 72.17,44.56 72.65,45.04 v2(72.65,45.11)
  BOTTOM w0.102: UU1.DA7 72.38,45.38 v2(72.65,45.11)
PCIE_CRX_GTX_P1: length 100.5
  TOP w0.102: v1(139.37,78.76) 139.19,78.57 139.19,78.33 139.47,78.05 141.81,78.05 142.17,78.41 143.51,78.41 CV8.1
  ART03 w0.076: 73.26,43.91 73.28,43.93 73.31,43.93 73.5,44.11 73.66,44.11 73.82,44.21 73.9,44.28 73.97,44.35 73.97,44.62 73.89,44.7 73.76,44.7 v2(73.57,44.51)
  ART03 w0.102: 73.26,43.91 73.1,43.75 73.1,43.18 73.9,42.38 82.21,42.38 83.28,43.46 83.28,45.97 83.62,46.3 98.73,46.3 100.27,47.84 104.96,47.84 105.57,47.23 110.07,47.23 110.45,47.61 113.94,47.61 116.31,49.99 121.98,49.99 127.91,55.92 127.91,60.34 129.28,61.71 129.28,71.45 131.82,73.99 133.27,73.99 137.15,77.86 138.95,77.86 139.2,78.11 139.2,78.59 v1(139.37,78.76)
  BOTTOM w0.102: v2(73.57,44.51) 73.34,44.73 UU1.CY6
PCIE_CRX_GTX_P2: length 97.6
  TOP w0.102: v1(138.26,79.07) 138.44,79.26 141.34,79.26 141.97,79.89 143.52,79.89 CV13.1
  ART03 w0.076: 74.84,44.04 74.84,44.06 74.86,44.08 74.86,45.23 74.79,45.3 74.68,45.3 v2(74.48,45.11)
  ART03 w0.102: v1(138.26,79.07) 138.1,79.23 137.25,79.23 133.27,75.26 132.08,75.26 128.52,71.7 128.52,61.83 127.29,60.6 127.29,56.18 121.72,50.61 116.06,50.61 115.19,49.74 112.53,49.74 111.63,48.84 110.23,48.84 109.6,48.21 105.99,48.21 104.56,49.64 103.85,49.64 103.16,48.96 100.57,48.96 99.86,48.24 84.11,48.24 82.17,46.3 81.86,46.3 81.43,45.87 81.43,44.3 80.14,43 75.64,43 74.84,43.8 74.84,44.04
  BOTTOM w0.102: UU1.CV6 74.11,44.73 v2(74.48,45.11)
PCIE_CRX_GTX_P3: length 108.9
  TOP w0.102: CV26.1 150.36,80.12 150.36,82.84 148.65,84.54 147.08,84.54 145.03,82.5 139.96,82.5 139.74,82.72 139.74,83.07 v1(139.55,83.26)
  ART03 w0.102: v2(75.4,45.11) 75.82,44.69 75.82,44.34 76.32,43.84 79.02,43.84 79.4,44.22 79.4,45.95 79.97,46.52 80.96,46.52 83.63,49.18 99.78,49.18 101.73,51.13 104.14,51.13 105.7,49.57 107.78,49.57 107.97,49.38 109.24,49.38 109.98,50.11 111.71,50.11 112.21,50.62 114.88,50.62 115.71,51.45 121.37,51.45 126.31,56.39 126.31,60.81 127.54,62.04 127.54,71.99 133.98,78.43 135.2,78.43 139.74,82.97 139.74,83.07 v1(139.55,83.26)
  BOTTOM w0.076: UU1.CT7 75.23,45.21 v2(75.4,45.11)
PCIE_CTX_GRX_N0: length 107.4
  ART03 w0.102: v1(145.56,81.58) 145.25,81.28 144.96,81.28 144.54,81.7 142.71,81.7 140.84,79.83 140.84,77.85 139.7,76.71 139.7,73.88 131.19,65.37 131.19,61.14 129.58,59.53 129.58,55.15 122.21,47.79 116.75,47.79 114.46,45.5 112.1,45.5 109.6,43 100.53,43 100.28,42.75 96.85,42.75 96.43,42.33 86.4,42.33 84.66,40.59 80.36,40.59 79.74,39.96 78.02,39.96 77.08,40.9 72.6,40.9 68.22,36.52 68.22,36.26 v1(68.03,36.07)
  BOTTOM w0.102: v1(68.03,36.07) 68.34,36.38 68.34,36.59 68.6,36.85 68.6,37.01 CU27.2 ; v1(145.56,81.58) 145.92,81.21 UV2.AG7
PCIE_CTX_GRX_N0_C: length 6.8
  BOTTOM w0.102: CU27.1 68.45,40.26 70.13,41.94 70.13,42.82 70.02,42.93 70.02,43.08 UU1.DE4
PCIE_CTX_GRX_N1: length 111.3
  ART03 w0.102: v2(70.14,35.58) 69.96,35.77 69.96,36.5 70.1,36.65 70.28,36.65 70.49,36.86 70.49,37.04 72.43,38.97 80.3,38.97 81.02,39.7 85.09,39.7 86.74,41.35 97.05,41.35 97.6,41.89 109.76,41.89 112.62,44.75 115.08,44.75 117.27,46.94 122.86,46.94 130.41,54.49 130.41,59.18 132.08,60.85 132.08,65.07 140.68,73.67 140.68,76.44 141.69,77.45 141.69,79.49 143.05,80.85 144.35,80.85 145.11,80.08 145.79,80.08 146.18,80.46 146.18,82.26 v1(146.35,82.43)
  BOTTOM w0.076: v1(146.35,82.43) 146.11,82.2 146.11,81.8 146.44,81.47 146.44,79.99 146.26,79.81 146.13,79.81 UV2.AE7
  BOTTOM w0.102: CU29.2 69.96,37.01 69.96,35.77 v2(70.14,35.58)
PCIE_CTX_GRX_N1_C: length 5.4
  BOTTOM w0.102: CU29.1 70.1,37.92 70.05,37.97 69.91,37.97 69.81,38.07 69.81,38.31 69.98,38.48 69.98,38.72 69.81,38.88 69.81,39.12 69.98,39.29 69.98,39.53 69.81,39.7 69.81,40.09 70.04,40.32 70.24,40.32 70.42,40.5 70.42,40.71 70.85,41.13 70.85,41.99 UU1.DD1
PCIE_CTX_GRX_N2: length 115.5
  ART03 w0.102: v2(70.7,36.07) 70.88,36.26 70.88,36.62 72.83,38.57 81.29,38.57 81.91,39.19 85.44,39.19 86.17,39.91 96.66,39.91 97.38,39.19 102.36,39.19 102.84,38.71 104.14,38.71 104.68,39.25 104.68,39.66 106.21,41.18 109.76,41.18 112.19,43.61 114.73,43.61 117.64,46.52 123.28,46.52 130.82,54.06 130.82,59.01 132.75,60.94 132.75,63.79 140.21,71.25 140.21,71.43 140.41,71.62 140.59,71.62 140.78,71.82 140.78,72 140.98,72.2 141.16,72.2 141.6,72.64 141.6,73.63 141.48,73.76 141.48,74.04 141.6,74.16 141.6,74.44 141.48,74.57 141.48,74.85 141.6,74.98 141.6,76.33 142.28,77 142.28,78.6 142.96,79.28 144.49,79.28 144.96,78.81 147.45,78.81 147.57,78.94 147.57,79.53 147.45,79.66 147.45,79.94 147.57,80.07 147.57,80.35 147.45,80.47 147.45,80.75 147.57,80.88 147.57,81.46 148.33,82.22 148.33,83.03 148.2,83.16 148.06,83.16 v1(147.83,82.94)
  BOTTOM w0.076: v1(147.83,82.94) 147.59,83.17 147.39,83.17 147.27,83.05 147.27,82.78 147.39,82.65 147.39,82.48 147.27,82.35 147.27,82.17 147.39,82.04 147.39,81.87 147.27,81.74 147.27,80.19 147.36,80.1 147.54,80.1 147.62,80.17 UV2.AF9
  BOTTOM w0.102: v2(70.7,36.07) 70.88,36.26 70.88,37.01 CU23.1
PCIE_CTX_GRX_N2_C: length 6.4
  BOTTOM w0.076: 71.14,41.18 71.14,41.2 71.16,41.22 71.16,42.86 70.99,43.27 UU1.DD3
  BOTTOM w0.102: CU23.2 70.74,37.87 70.84,37.97 70.93,37.97 71.03,38.07 71.03,38.28 70.86,38.45 70.86,38.69 71.03,38.86 71.03,39.1 70.86,39.26 70.86,39.5 71.03,39.67 71.03,39.91 70.86,40.07 70.86,40.32 71.03,40.48 71.03,40.8 71.14,40.91 71.14,41.18
PCIE_CTX_GRX_N3: length 111.7
  ART03 w0.102: v1(149.46,81.75) 149.36,81.85 149.22,81.85 148.42,81.06 148.42,78.34 148.09,78.01 145.38,78.01 142.59,75.23 142.59,71.16 141.13,69.71 140.68,69.71 135.81,64.84 135.13,64.84 133.69,63.41 133.69,58.67 132.59,57.56 132.59,54.3 123.92,45.64 118.13,45.64 115.24,42.75 113.1,42.75 110.68,40.33 107.31,40.33 106.17,39.19 106.17,39.01 105.01,37.86 102.68,37.86 101.99,37.17 98.23,37.17 97.78,36.71 97.04,36.71 95.76,38 95.76,38.63 95.41,38.97 87.16,38.97 85.91,37.73 77.53,37.73 77.45,37.64 77.12,37.64 77.03,37.73 76.7,37.73 76.56,37.59 76.29,37.59 76.15,37.73 75.88,37.73 75.74,37.59 75.48,37.59 75.34,37.73 75.01,37.73 74.92,37.64 74.59,37.64 74.5,37.73 73.98,37.73 72.9,36.65 72.9,36.02 v1(73.06,35.85)
  BOTTOM w0.089: v1(149.46,81.75) 149.26,81.96 148.32,81.96 148,81.64 148,81.3 148.09,81.21 UV2.AG10
  BOTTOM w0.102: CU25.1 72.27,37.04 72.27,36.9 72.78,36.38 72.78,36.13 v1(73.06,35.85)
PCIE_CTX_GRX_N3_C: length 6.5
  BOTTOM w0.076: UU1.DA3 72.17,43.27 72.12,43.15 72.12,43.01 72.02,42.91 72,42.86 72,41.86 72.24,41.63 72.24,41.25 72.26,41.23 72.26,41.21
  BOTTOM w0.102: 72.26,41.21 72.26,40.97 72.1,40.8 72.1,40.54 72.26,40.38 72.26,40.14 72.1,39.97 72.1,39.73 72.26,39.56 72.26,39.32 72.1,39.16 72.1,38.92 72.26,38.75 72.26,38.51 72.1,38.34 72.1,38.07 72.2,37.97 72.29,37.97 72.39,37.87 CU25.2
PCIE_CTX_GRX_P0: length 107.4
  ART03 w0.102: v1(68.62,36.07) 68.43,36.26 68.43,36.43 68.63,36.63 68.79,36.63 69,36.84 69,36.99 69.21,37.2 69.36,37.2 69.57,37.42 69.57,37.57 69.78,37.78 69.94,37.78 70.15,37.99 70.15,38.14 70.36,38.35 70.51,38.35 70.72,38.56 70.72,38.72 72.69,40.69 76.99,40.69 77.93,39.75 79.83,39.75 80.45,40.37 84.75,40.37 86.49,42.11 96.52,42.11 96.94,42.53 100.37,42.53 100.62,42.78 109.69,42.78 112.19,45.29 114.55,45.29 116.84,47.57 122.3,47.57 129.79,55.06 129.79,59.44 131.41,61.05 131.41,65.28 139.91,73.79 139.91,76.62 141.06,77.76 141.06,79.74 142.8,81.48 144.45,81.48 144.87,81.06 145.27,81.06 145.32,81.01 145.33,81.01 v1(145.56,80.78)
  BOTTOM w0.102: CU28.2 68.81,37.01 68.81,36.76 68.56,36.5 68.56,36.13 v1(68.62,36.07) ; v1(145.56,80.78) 145.14,81.2 UV2.AG6
PCIE_CTX_GRX_P0_C: length 6.8
  BOTTOM w0.102: CU28.1 68.96,37.87 68.86,37.97 68.73,37.97 68.67,38.03 68.67,38.42 68.83,38.59 68.83,38.83 68.67,38.99 68.67,39.23 68.83,39.4 68.83,39.64 68.67,39.81 68.67,40.17 68.9,40.41 69.11,40.41 69.29,40.59 69.29,40.79 69.48,40.98 69.68,40.98 69.87,41.17 69.87,41.37 70.35,41.85 UU1.DE3
PCIE_CTX_GRX_P1: length 111.2
  ART03 w0.102: v2(69.56,35.58) 69.74,35.77 69.74,36.59 72.34,39.19 80.21,39.19 80.93,39.91 85,39.91 86.65,41.56 96.96,41.56 97.51,42.11 109.67,42.11 112.53,44.97 115,44.97 117.18,47.15 122.77,47.15 130.2,54.58 130.2,59.27 131.86,60.94 131.86,65.16 140.46,73.76 140.46,76.53 141.48,77.54 141.48,79.58 142.96,81.06 144.44,81.06 145.2,80.3 145.7,80.3 145.96,80.55 145.96,82.24 v1(145.76,82.43)
  BOTTOM w0.076: UV2.AF7 145.94,80.05 146.01,79.97 146.19,79.97 146.28,80.06 146.28,81.4 145.95,81.73 145.95,82.25 v1(145.76,82.43)
  BOTTOM w0.102: v2(69.56,35.58) 69.74,35.77 69.74,37.01 CU30.2
PCIE_CTX_GRX_P1_C: length 5.5
  BOTTOM w0.102: CU30.1 69.59,40.18 70.63,41.22 70.63,42.14 UU1.DD2
PCIE_CTX_GRX_P2: length 115.5
  ART03 w0.102: v1(71.28,36.07) 71.1,36.26 71.1,36.53 72.92,38.35 81.38,38.35 82,38.97 85.53,38.97 86.26,39.7 96.57,39.7 97.29,38.97 102.27,38.97 102.75,38.49 104.23,38.49 104.9,39.16 104.9,39.57 106.3,40.97 109.85,40.97 112.28,43.39 114.82,43.39 117.73,46.3 123.37,46.3 131.04,53.97 131.04,58.92 132.97,60.86 132.97,63.7 141.82,72.55 141.82,76.24 142.49,76.91 142.49,78.51 143.05,79.07 144.4,79.07 144.87,78.6 147.53,78.6 147.79,78.85 147.79,81.37 148.55,82.13 148.55,83.12 148.29,83.38 147.97,83.38 v1(147.83,83.52)
  BOTTOM w0.076: v1(147.83,83.52) 147.64,83.33 147.32,83.33 147.1,83.12 147.1,80.12 147.29,79.93 147.54,79.93 147.62,79.86 UV2.AE9
  BOTTOM w0.102: v1(71.28,36.07) 71.1,36.26 71.1,37.01 CU24.1
PCIE_CTX_GRX_P2_C: length 6.5
  BOTTOM w0.076: UU1.DD5 71.21,43.38 71.21,43.18 71.33,42.89 71.33,41.22 71.35,41.2 71.35,41.18
  BOTTOM w0.102: CU24.2 71.25,40.71 71.35,40.82 71.35,41.18
PCIE_CTX_GRX_P3: length 111.8
  ART03 w0.102: v2(72.48,35.85) 72.68,36.05 72.68,36.74 73.89,37.95 85.82,37.95 87.07,39.19 95.5,39.19 95.97,38.72 95.97,38.08 97.13,36.93 97.69,36.93 98.14,37.39 101.9,37.39 102.59,38.07 104.93,38.07 105.95,39.1 105.95,39.28 107.22,40.55 110.6,40.55 113.01,42.96 115.15,42.96 118.04,45.86 123.84,45.86 132.37,54.39 132.37,57.65 133.48,58.76 133.48,63.5 135.04,65.06 135.72,65.06 140.59,69.92 141.04,69.92 142.37,71.25 142.37,75.32 145.29,78.23 148,78.23 148.21,78.43 148.21,81.15 149.2,82.14 149.26,82.14 v1(149.46,82.34)
  BOTTOM w0.089: v1(149.46,82.34) 149.26,82.13 148.25,82.13 147.83,81.71 147.83,81.43 UV2.AG9
  BOTTOM w0.102: v2(72.48,35.85) 72.57,35.94 72.57,36.29 72.05,36.81 72.05,36.98 CU26.1
PCIE_CTX_GRX_P3_C: length 6.6
  BOTTOM w0.076: 72.05,41.21 72.05,41.23 72.07,41.25 72.07,41.56 71.84,41.79 71.84,42.89 71.86,42.95 71.86,42.98 71.96,43.08 71.96,43.38 UU1.DA5
  BOTTOM w0.102: CU26.2 71.88,40.89 72.05,41.06 72.05,41.21
PCIE_RCOMP_N: length 4.9
  TOP w0.102: RU142.2 66.91,42.73 66.91,41.29 66.51,40.89 66.21,40.89 v2(66.03,40.71)
  BOTTOM w0.102: UU1.DN1 66.51,42.25 66.51,41.89 66.62,41.78 66.62,41.12 66.39,40.89 66.13,40.89 66.03,40.79 v2(66.03,40.71)
PCIE_RCOMP_P: length 4.9
  TOP w0.102: v2(66.03,41.29) 66.21,41.11 66.42,41.11 66.69,41.38 66.69,42.73 RU142.1
  BOTTOM w0.102: v2(66.03,41.29) 66.03,41.21 66.13,41.11 66.3,41.11 66.41,41.21 66.41,41.69 66.29,41.81 66.29,42.36 UU1.DN3
PCIE_REFCLK_GFX_DN: length 103.6
  ART03 w0.076: 77.6,45.97 77.6,45.95 77.62,45.92 77.62,44.7 77.74,44.52 v2(77.67,44.22)
  ART03 w0.102: 77.6,45.97 77.6,47.04 80.5,49.95 99.53,49.95 101.34,51.76 104.27,51.76 104.79,51.24 112.58,51.24 112.99,51.65 114.9,51.65 115.39,52.14 121.08,52.14 125.61,56.68 125.61,61.1 126.78,62.27 126.78,72.63 135,80.85 135.96,80.85 136.69,81.57 136.69,83.3 137.37,83.98 145.76,83.98 147.18,82.56 147.18,81.52 147.01,81.35 147.01,79.37 v1(147.17,79.2)
  BOTTOM w0.076: UU1.CJ3 78.33,43.56 v2(77.67,44.22)
  BOTTOM w0.089: UV2.AD8 146.79,78.81 v1(147.17,79.2)
PCIE_REFCLK_GFX_DP: length 103.6
  ART03 w0.076: v2(78.15,44.52) 77.89,44.58 77.79,44.75 77.79,45.92 77.81,45.95 77.81,45.97
  ART03 w0.102: v1(146.37,79.2) 146.69,79.2 146.79,79.3 146.79,81.44 146.96,81.61 146.96,82.47 146.34,83.1 146.13,83.1 145.95,83.28 145.95,83.49 145.67,83.77 145.23,83.77 145.13,83.67 144.82,83.67 144.72,83.77 144.42,83.77 144.32,83.67 144.01,83.67 143.91,83.77 143.61,83.77 143.5,83.67 143.2,83.67 143.1,83.77 142.79,83.77 142.69,83.67 142.39,83.67 142.28,83.77 137.46,83.77 136.9,83.21 136.9,81.48 136.05,80.63 135.09,80.63 127,72.54 127,62.18 125.83,61.01 125.83,56.59 121.17,51.93 115.48,51.93 114.99,51.44 113.08,51.44 112.67,51.03 104.7,51.03 104.18,51.55 101.43,51.55 99.62,49.73 80.59,49.73 80.41,49.55 80.41,49.37 80.21,49.17 80.04,49.17 79.84,48.98 79.84,48.8 79.64,48.6 79.46,48.6 79.26,48.4 79.26,48.22 79.06,48.02 78.89,48.02 78.56,47.69 78.56,47.52 78.36,47.32 78.18,47.32 77.81,46.95 77.81,46.68 77.95,46.54 77.95,46.27 77.81,46.13 77.81,45.97
  BOTTOM w0.076: UU1.CJ5 78.33,44.35 v2(78.15,44.52)
  BOTTOM w0.089: UV2.AE8 v1(146.37,79.2)
PCIE_REFCLK_SSD_DN: length 76.7
  ART06 w0.102: v1(35.92,25.76) 36.11,25.95 36.44,25.95 36.66,26.17 36.66,27.09 37.15,27.57 41.43,27.57 44.26,30.39 44.26,31.18 45.36,32.28 46.1,32.28 47.34,33.53 59.56,33.53 62.05,36.01 66.37,36.01 67.64,37.28 69.37,37.28 72.06,39.97 72.06,40.59 72.83,41.36 76.23,41.36 76.95,40.64 78.41,40.64 78.66,40.89 78.66,41.18 v2(78.8,41.32)
  BOTTOM w0.102: UU1.CJ2 78.62,42.14 78.62,41.51 v2(78.8,41.32) ; JSSD1.53 23.05,9.69 22.91,9.83 22.91,10.69 23.87,11.66 24.15,11.66 29.25,16.75 29.75,17.26 31.02,17.26 35.3,21.54 35.3,25.84 35.41,25.95 35.74,25.95 v1(35.92,25.76)
PCIE_REFCLK_SSD_DP: length 76.6
  ART06 w0.102: v2(78.22,41.32) 78.44,41.1 78.44,40.98 78.32,40.85 77.81,40.85 77.67,40.99 77.4,40.99 77.26,40.85 77.04,40.85 76.94,40.96 76.94,41.17 76.74,41.36 76.53,41.36 76.32,41.58 75.99,41.58 75.9,41.67 75.57,41.67 75.48,41.58 75.15,41.58 75.06,41.67 74.73,41.67 74.64,41.58 73.68,41.58 73.59,41.67 73.26,41.67 73.18,41.58 72.75,41.58 72.51,41.35 72.39,41.35 72.15,41.11 72.15,40.99 71.84,40.68 71.84,40.06 69.28,37.5 67.55,37.5 66.28,36.23 61.96,36.23 59.47,33.74 47.25,33.74 46.01,32.5 45.27,32.5 44.04,31.26 44.04,30.48 41.35,27.79 37.06,27.79 36.45,27.18 36.45,26.26 36.35,26.17 36.1,26.17 v1(35.92,26.35)
  BOTTOM w0.102: v2(78.22,41.32) 78.4,41.51 78.4,41.99 UU1.CJ1 ; JSSD1.55 22.55,9.67 22.69,9.81 22.69,10.78 23.78,11.87 24.06,11.87 29.66,17.47 30.93,17.47 35.09,21.63 35.09,25.93 35.32,26.16 35.74,26.16 v1(35.92,26.35)
PCIE_REFCLK_WLAN_DN: length 107.4
  ART03 w0.102: v1(150.06,29.49) 149.82,29.73 149.41,29.73 149.16,29.98 149.16,30.85 146.76,33.25 144.88,33.25 143.83,34.3 141.49,34.3 140.65,35.14 140.65,35.82 138.05,38.43 136.78,38.43 135.63,39.57 135.63,41.3 132.79,44.14 117.73,44.14 115.46,41.88 113.3,41.88 110.78,39.35 109.03,39.35 106.14,36.46 98.99,36.46 98.52,35.99 96.77,35.99 94.94,37.82 87.02,37.82 86.23,37.03 81.98,37.03 81.88,36.93 81.58,36.93 81.48,37.03 79.98,37.03 79.85,36.9 79.57,36.9 79.44,37.03 79.16,37.03 79.04,36.9 78.76,36.9 78.63,37.03 77.9,37.03 77.8,36.93 77.8,36.79 v2(77.93,36.65)
  BOTTOM w0.076: 77.75,42.32 77.75,42.34 77.72,42.36 77.72,42.62 77.63,42.71 77.63,42.89 UU1.CK3
  BOTTOM w0.102: JW1.49 146.55,18.2 146.79,18.44 148.08,18.44 148.74,19.1 148.74,28.04 149.35,28.65 149.35,29.54 149.54,29.73 149.82,29.73 v1(150.06,29.49) ; v2(77.93,36.65) 77.75,36.83 77.75,38.87 77.9,39.02 77.9,39.28 77.75,39.43 77.75,39.68 77.9,39.84 77.9,40.09 77.75,40.24 77.75,40.5 77.9,40.65 77.9,40.9 77.75,41.06 77.75,41.55 77.87,41.67 77.87,41.95 77.75,42.08 77.75,42.32
PCIE_REFCLK_WLAN_DP: length 107.5
  ART03 w0.102: v2(77.35,36.65) 77.58,36.88 77.58,37.02 77.81,37.25 86.14,37.25 86.93,38.03 95.03,38.03 96.86,36.21 98.44,36.21 98.91,36.68 106.05,36.68 108.94,39.57 110.69,39.57 113.22,42.1 115.37,42.1 117.64,44.36 132.88,44.36 135.85,41.39 135.85,39.66 136.87,38.64 138.14,38.64 140.87,35.91 140.87,35.23 141.58,34.52 143.92,34.52 144.97,33.46 146.85,33.46 149.38,30.94 149.38,30.07 149.5,29.94 149.93,29.94 v1(150.06,30.07)
  BOTTOM w0.076: UU1.CK4 77.47,43.08 77.47,42.64 77.56,42.55 77.56,42.36 77.53,42.34 77.53,42.32
  BOTTOM w0.102: 77.53,42.32 77.53,36.83 v2(77.35,36.65) ; v1(150.06,30.07) 149.93,29.94 149.45,29.94 149.13,29.63 149.13,28.74 148.52,28.13 148.52,19.19 147.99,18.66 146.7,18.66 146.65,18.7 JW1.47
PCIE_SSD1_WAKE_N: length 2.2
  TOP w0.102: v1(22.71,2.87) 22.71,3.53 TP176.1
  BOTTOM w0.102: JSSD1.54 22.8,2.77 v1(22.71,2.87)
PCIE_SSD_CLKREQ1: length 110.1
  TOP w0.102: RN3.1 23.32,2.87 v1(23.3,2.86)
  ART03 w0.089: v1(44.65,4.59) 44.55,4.7 44.35,4.7 40.94,8.1 40.94,12.62 39.85,13.71 39.85,18.54 45.77,24.46 47.29,24.46 51.92,29.08 51.92,35.28 51.53,35.66 51.53,41.15 52.83,42.44 52.83,48.89 54.76,50.82 54.76,51.99 55.42,52.65 55.42,53.62 55.67,53.87 55.67,59.97 54.86,60.78 54.86,62.56 56.23,63.93 59.03,63.93 59.59,63.37 v2(59.59,61.34)
  ART06 w0.102: v1(23.3,2.86) 23.75,2.41 41.81,2.41 43.99,4.59 v1(44.65,4.59)
  BOTTOM w0.102: UU1.DN40 66.33,60.78 65.78,60.78 65.28,61.29 61.82,61.29 61.57,61.54 59.89,61.54 59.69,61.34 v2(59.59,61.34) 59.18,61.34 58.82,60.98 v3(57.61,60.98) ; JSSD1.52 v1(23.3,2.86)
PCIE_WLAN_CLK_REQ_N: length 128.2
  TOP w0.102: QW2.2 141.82,17.44 v1(142.75,18.36)
  ART05 w0.102: v2(59.59,59.51) 59.56,59.48 59.56,55.98 60.07,55.47 60.07,50.11 61.8,48.38 61.8,45.36 62.33,44.83 62.33,42.59 62.81,42.11 62.81,39.11 67.64,34.29 94.41,34.29 96.67,32.03 101.88,32.03 102.41,32.56 109.14,32.56 110.31,33.73 110.92,33.73 111.48,34.29 125.52,34.29 127.35,32.46 128.53,32.46 129.11,31.87 133.04,31.87 134.21,30.71 140.31,30.71 v2(140.46,30.55)
  ART06 w0.102: v1(142.75,18.36) 142.14,18.97 142.14,27.66 140.31,29.49 140.31,30.4 v2(140.46,30.55)
  BOTTOM w0.102: RU101.1 59.13,59.89 59.51,59.51 v2(59.59,59.51) 59.84,59.51 v3(60.5,60.17) 60.53,60.14 62.99,60.14 63.12,60.02 65.66,60.02 66.05,59.63 UU1.DP36 ; v1(142.75,18.36) 142.92,18.18 RW12.1
PCIE_WLAN_CLK_REQ_N_C: length 7.4
  TOP w0.102: v1(144.47,17.19) 144.47,17.04 143.76,16.33 143.41,16.33 142.77,15.69 QW2.3 142.77,14.12 v3(143.1,13.79)
  BOTTOM w0.102: RW12.2 RW9.1 143.43,17.2 144.47,17.2 v1(144.47,17.19) 144.48,17.2 JW1.53
PCIE_WLAN_RX_DN: length 126.3
  ART03 w0.102: v1(148.64,29.49) 148.45,29.67 148.2,29.67 147.86,30.01 147.86,30.52 146.14,32.24 140.19,32.24 138.97,33.46 138.97,34.15 137.77,35.35 137.77,36.37 137.2,36.94 136.1,36.94 134.05,39 134.05,40.65 132.87,41.83 126.13,41.83 125.55,42.42 118.03,42.42 116.08,40.46 113.79,40.46 111.16,37.83 109.38,37.83 107.57,36.02 107.57,35.63 106.59,34.66 102.2,34.66 101.74,34.2 97.85,34.2 97.43,34.62 96.21,34.62 95.4,35.43 73.96,35.43 73.06,34.53 68.23,34.53 67.09,35.67 67.09,37.07 67.75,37.73 67.75,38.47 71.18,41.89 71.18,45.96 71.68,46.45 75.56,46.45 76.17,45.84 76.17,45.59 76.86,44.91 77.03,44.91 v2(77.23,45.11)
  BOTTOM w0.102: v2(77.23,45.11) 76.95,45.38 UU1.CM7 ; v1(148.64,29.49) 148.49,29.64 148.23,29.64 148.04,29.45 148.04,20.3 147.58,19.84 146.51,19.84 146.37,19.7 JW1.43
PCIE_WLAN_RX_DP: length 126.2
  ART03 w0.102: v1(148.64,30.07) 148.45,29.89 148.29,29.89 148.08,30.1 148.08,30.61 146.23,32.46 140.28,32.46 139.19,33.55 139.19,34.24 137.98,35.44 137.98,36.46 137.29,37.16 136.19,37.16 134.26,39.09 134.26,40.74 132.95,42.05 126.22,42.05 125.64,42.63 117.94,42.63 115.99,40.68 113.7,40.68 111.07,38.05 109.29,38.05 107.35,36.11 107.35,35.72 106.5,34.87 102.11,34.87 101.65,34.41 97.94,34.41 97.52,34.83 96.3,34.83 95.49,35.65 73.87,35.65 72.97,34.74 68.32,34.74 67.31,35.76 67.31,36.98 67.97,37.64 67.97,38.38 71.4,41.81 71.4,42.64 71.55,42.79 71.55,43.04 71.4,43.19 71.4,43.45 71.55,43.6 71.55,43.85 71.4,44.01 71.4,45.87 71.77,46.24 72.19,46.24 72.3,46.12 72.59,46.12 72.71,46.24 73,46.24 73.11,46.12 73.4,46.12 73.52,46.24 73.81,46.24 73.93,46.12 74.22,46.12 74.33,46.24 74.62,46.24 74.74,46.12 75.03,46.12 75.14,46.24 75.47,46.24 75.96,45.76 75.96,45.5 76.76,44.7 76.77,44.69 77.05,44.69 v2(77.23,44.51)
  BOTTOM w0.102: v1(148.64,30.07) 148.42,29.86 148.14,29.86 147.83,29.54 147.83,20.39 147.49,20.06 146.51,20.06 146.37,20.2 JW1.41 ; v2(77.23,44.51) 77,44.73 UU1.CM6
PCIE_WLAN_TX_DN: length 99.9
  ART03 w0.102: v1(141.97,32.87) 142.15,33.05 142.15,33.39 141.95,33.59 141.18,33.59 140.22,34.55 139.51,34.55 138.63,35.43 138.63,36.4 137.36,37.67 136.4,37.67 134.87,39.19 134.87,40.97 133.37,42.47 126.64,42.47 126.02,43.09 117.74,43.09 115.75,41.09 113.54,41.09 111.03,38.59 109.26,38.59 106.41,35.75 99.35,35.75 98.89,35.29 96.48,35.29 94.66,37.11 87.32,37.11 86.27,36.05 74.81,36.05 74.59,36.28 74.59,36.45 v1(74.39,36.65)
  BOTTOM w0.102: v1(141.97,32.87) 142.15,32.68 142.15,31.02 141.36,30.24 141.36,24.27 141.79,23.83 141.79,21.7 142.12,21.37 143.09,21.37 CW9.1 ; UU1.CY3 72.82,42.91 72.81,42.89 72.81,42.54 72.64,42.38 72.64,42.14 72.81,41.97 72.81,41.57 72.68,41.44 72.68,39.99 73.85,38.82 73.85,38.62 74.04,38.43 74.24,38.43 74.57,38.1 74.57,37.78 74.47,37.67 74.47,37.27 74.57,37.17 74.57,36.83 v1(74.39,36.65)
PCIE_WLAN_TX_DN_C: length 2.1
  BOTTOM w0.102: JW1.37 145.04,21.2 144.88,21.36 144.02,21.36 CW9.2
PCIE_WLAN_TX_DP: length 99.9
  ART03 w0.102: v1(142.55,32.87) 142.37,33.05 142.37,33.47 142.03,33.8 141.27,33.8 140.31,34.77 139.6,34.77 138.85,35.52 138.85,36.48 137.45,37.88 136.49,37.88 135.09,39.28 135.09,41.06 133.46,42.68 126.73,42.68 126.11,43.3 117.65,43.3 115.66,41.31 113.45,41.31 110.94,38.81 109.17,38.81 106.33,35.96 99.26,35.96 98.8,35.51 96.57,35.51 94.75,37.32 87.23,37.32 86.18,36.27 74.9,36.27 74.8,36.37 74.8,36.48 v2(74.97,36.65)
  BOTTOM w0.102: CW10.1 143.13,21.59 142.21,21.59 142.01,21.79 142.01,23.92 141.58,24.36 141.58,30.15 142.37,30.93 142.37,32.68 v1(142.55,32.87) ; UU1.CY4 73.11,43.16 73.11,42.89 73.02,42.8 73.02,41.48 72.9,41.35 72.9,40.08 74.79,38.19 74.79,36.83 v2(74.97,36.65)
PCIE_WLAN_TX_DP_C: length 2
  BOTTOM w0.102: CW10.2 144,21.57 144.94,21.57 145.07,21.7 JW1.35
PCIE_WLAN_WAKE_N_R: length 3.5
  BOTTOM w0.102: RW69.1 RW68.2 143.46,16.51 RW57.2 143.43,16.56 143.57,16.7 JW1.55
PECI_EC: length 4
  TOP w0.076: 159.19,20.44 159.92,19.72 160.45,19.72 UE1.B1
  TOP w0.102: 159.19,20.44 158.75,20.89 v3(158.75,20.95) 157.71,21.99 RE103.1
PECI_SOC: length 106.4
  TOP w0.102: v1(154.43,21.97) 154.43,21.36 v3(154.58,21.21) 154.73,21.21 155.12,21.59 155.67,21.59 156.08,21.99 RE103.2
  ART03 w0.089: v1(154.43,21.97) 153.52,22.88 153.52,23.7 152.73,24.48 152.73,24.99 152.4,25.32 150.62,25.32 149.81,26.13 149.35,26.13 148.08,27.4 147.32,27.4 145.39,29.33 144.02,29.33 143.61,28.93 139.49,28.93 138.78,29.64 137.11,29.64 136.45,30.3 136.45,31.87 135.68,32.64 135.18,32.64 133.65,34.16 129.33,34.16 128.78,34.72 116.58,34.72 115.47,33.6 110.54,33.6 108.91,31.98 106.73,31.98 106.07,31.32 96.65,31.32 96.29,31.67 95.71,31.67 94.21,33.16 77.64,33.16 v1(77.57,33.09)
  BOTTOM w0.102: UU1.CD5 81.18,43.64 81.18,43.2 81.13,43.15 81.13,41.78 82.34,40.56 82.34,39.55 82.7,39.19 82.7,36.45 83.11,36.04 83.11,34.67 81.53,33.09 v1(77.57,33.09)
PEX_TERMP: length 2
  TOP w0.102: RV21.2 159.38,80.34 159.97,80.34 v1(160.44,80.81)
  BOTTOM w0.102: UV2.AF25 v1(160.44,80.81)
PLT_RST_N: length 256.1
  TOP w0.102: RW21.1 148.69,16.89 v2(147.93,17.65) ; v1(26.41,6.32) 26.07,6.32 25.82,6.58 24.28,6.58 23.92,6.22 v3(23.92,5.71) RN8.2 ; v1(130.81,47.06) 129.28,45.54 129.28,31.62 129.69,31.21 129.69,29.94 132,27.63 RF7.2 132.97,27.38 v2(133.35,27) ; v2(23.24,16.08) RT66.1 ; v1(127.33,88.72) 127.25,88.8 RU167.2 127.63,89.23 127.73,89.33 RU161.1 CU34.1 128.01,90.57 RU163.2
  ART03 w0.089: v1(127.33,88.72) 127.63,88.41 127.63,78.18 128.14,77.67 v1(129.54,77.67) ; v2(147.93,17.65) 147.78,17.65 146.26,19.17 146.26,21.01 145.96,21.31 145.96,23.58 144.07,25.47 142.03,25.47 140.41,23.85 134.82,23.85 134.49,24.18 134.49,24.71 134.11,25.09 134.11,26.24 v2(133.35,27)
  ART06 w0.102: v2(133.35,27) 134.11,26.24 134.11,24.84 134.49,24.46 134.49,23.31 135,22.81 136.65,22.81 137.59,21.87 137.59,17.34 135.92,15.67 131.8,15.67 127.84,11.71 112.98,11.71 111.83,12.85 109.12,12.85 107.44,14.52 106.84,14.52 105.99,15.36 103.72,15.36 102.42,14.07 101.89,14.07 101.05,13.23 93.56,13.23 92.92,12.6 81.86,12.6 81.1,11.83 72.98,11.83 72.8,11.66 57.57,11.66 57.14,12.09 53.39,12.09 52.07,13.41 50.8,13.41 50.42,13.79 48,13.79 47.75,13.54 47.75,13.03 47.34,12.62 41.1,12.62 40.84,12.88 39.57,12.88 39.27,13.18 36.12,13.18 35.46,12.52 33.7,12.52 31.39,14.83 28.07,14.83 26.11,16.79 26.11,17.19 25.83,17.47 23.54,17.47 23.24,17.17 v2(23.24,16.08) 23.24,15.24 27.43,11.05 27.43,9.27 26.16,8 26.16,7.57 26.41,7.31 v1(26.41,6.32) ; v1(129.54,77.67) 128.14,76.27 128.14,65.22 130.05,63.32 130.05,59.89 131.85,58.09 131.85,57.08 v1(131.45,56.68) 130.91,56.14 130.91,47.17 v1(130.81,47.06)
  BOTTOM w0.102: UV1.1 132,56.66 CV24.1 v1(131.45,56.68)
PLT_RST_N_SSD: length 8.8
  TOP w0.102: RN8.1 RN31.1 24.53,2.9 v2(24.49,2.86) 24.99,2.36 28.24,2.36 v3(29.51,3.63)
  BOTTOM w0.102: JSSD1.50 23.8,2.17 v2(24.49,2.86)
PLT_RST_SOC_N: length 106
  TOP w0.102: v1(126.49,91.51) 126.74,91.26 UU2.2 RU165.2 RU167.1 ; v2(75.94,68.4) 74.04,68.4 68.4,74.04 66.88,74.04 60.96,79.96 60.96,81.51 60.68,81.79 60.68,86.76 60.32,87.12 v3(60.32,87.58) 60.32,88.47 v1(60.58,88.72)
  ART03 w0.089: v1(126.49,91.51) 123.88,94.12 62.27,94.12 60.7,92.56 60.7,88.85 v1(60.58,88.72)
  BOTTOM w0.076: 76.2,67.38 76.79,66.8 76.79,66.64 76.85,66.58 UU1.CM49
  BOTTOM w0.102: 76.2,67.38 75.94,67.64 v2(75.94,68.4)
PLT_RST_VGA_N: length 81.2
  TOP w0.102: v1(143.49,50.2) RV138.2
  ART03 w0.089: v1(130.96,81.48) 132.1,82.62 135.25,82.62 137.29,84.66 v1(150.24,84.66) 150.24,81.35 149.35,80.46 149.35,77.54 148.97,77.16 146.3,77.16 145.86,77.6 v1(145.53,77.6)
  ART06 w0.102: v1(143.49,50.2) 142.94,50.75 140.74,50.75 138.96,52.52 137.92,52.52 136.43,51.03 v1(133.51,51.03) 133.51,56.39 v1(133.64,56.53) 133.86,56.74 133.86,60.53 132.33,62.05 132.33,62.94 129.41,65.86 129.41,74.75 131.57,76.91 131.57,78.89 130.96,79.5 v1(130.96,81.48)
  BOTTOM w0.089: UV2.AC7 v1(145.53,77.6)
  BOTTOM w0.102: v1(133.64,56.53) 133.62,56.55 RV50.2 ; RV3.2 v1(133.51,51.03) ; CV195.2 v1(150.24,84.66) 151.08,84.66 v3(151.18,84.76)
PM_AC_PRESENT: length 161.9
  TOP w0.076: UE1.N1 160.35,14.24 159.84,13.74 158.44,13.74 158.19,13.48
  TOP w0.102: 158.19,13.48 158.19,13.28 157.48,12.57 RE114.2 ; RE114.2 RE109.2 157.48,11.1 v3(157.63,10.94) ; RE114.2 157.71,12.47 157.76,12.52 v1(158.04,12.52)
  ART05 w0.102: v2(70.51,67.28) 70.43,67.36 69.82,67.36 68.17,65.71 64.84,65.71 62.08,62.94 62.08,61.21 61.24,60.37 61.24,55.02 62.7,53.56 62.7,52.62 63.18,52.14 63.18,50.63 63.4,50.42 63.4,49.11 63.71,48.79 63.71,43.67 65.17,42.21 65.17,40.13 65.3,40 66.04,40 69.03,37.01 72.82,37.01 73.84,35.99 79.65,35.99 80.08,35.56 94.6,35.56 96.96,33.2 101.29,33.2 102.26,34.16 108.86,34.16 109.73,35.02 110.39,35.02 111.38,36.01 112.27,36.01 112.9,35.38 125.98,35.38 127.81,33.55 129.03,33.55 129.79,32.79 134.37,32.79 134.52,32.64 139.09,32.64 139.77,31.95 144.02,31.95 144.19,32.13 151.6,32.13 152.25,31.48 152.25,30.44 153.21,29.48 153.21,25.9 155.36,23.75 156.56,23.75 158.57,21.74 158.57,19 160.02,17.55 160.02,15.47 159.71,15.16 159.71,13.18 159.05,12.52 v1(158.04,12.52)
  BOTTOM w0.076: UU1.DE46 70.85,64.42 70.85,64.78 70.83,65.23 70.85,65.47 70.8,65.84 70.8,66.1 70.61,66.29 70.61,66.37
  BOTTOM w0.102: 70.61,66.37 70.61,67.18 v2(70.51,67.28)
PM_BATLOW_N: length 21.3
  BOTTOM w0.076: 68.48,66.62 68.56,66.54 68.56,66.09 68.48,65.83 68.48,65.78 68.55,65.5 UU1.DH48
  BOTTOM w0.102: RU170.2 57.15,77.65 58.37,76.43 58.37,75.41 v3(59.31,74.47) 59.56,74.22 64.13,74.22 65.67,72.68 65.67,69.25 66.71,68.21 66.89,68.21 68.48,66.62
PM_PWRBTN_R_N: length 137.5
  TOP w0.076: 165.31,21.72 165.31,21.52 164.89,21.1 164.89,20.55 164.72,20.37 164.72,19.56 164.59,19.43 164.59,18.86 UE1.D9
  TOP w0.102: 165.31,21.72 165.31,22.03 v1(165.62,22.33) 165.62,23.18 RE110.2 ; v2(73.3,61.73) 73.3,61.39 TPU16.1
  ART05 w0.102: v1(165.62,22.33) 165.62,23.18 165.28,23.51 165.03,23.51 164.34,24.2 160.53,24.2 159.38,25.35 157.61,25.35 157.17,25.78 156.11,25.78 153.97,27.91 153.97,31.52 152.45,33.04 144.17,33.04 143.76,33.45 140.82,33.45 140.05,34.21 139.49,34.21 134.69,39.01 134.69,41.4 132.08,44.02 129.31,44.02 128.67,44.65 127.38,44.65 126.19,45.84 116.58,45.84 114.7,43.96 111.61,43.96 110.79,43.15 100.61,43.15 100.28,43.48 96.65,43.48 95.83,42.67 84.91,42.67 84.68,42.44 82.83,42.44 82.4,42.87 80.59,42.87 80.26,43.2 72.08,43.2 71.4,43.89 71.4,45.92 70.19,47.13 70.19,49.01 72.24,51.06 72.24,55.45 71.88,55.8 71.88,61.29 72.32,61.73 v2(73.3,61.73)
  BOTTOM w0.102: UU1.CY42 73.25,61.73 v2(73.3,61.73)
PM_SYSRST_N: length 1.5
  TOP w0.102: v2(67.65,51.47) 68.14,51.97 RU171.2
  BOTTOM w0.102: UU1.DK19 67.97,51.08 67.65,51.4 v2(67.65,51.47)
PORTB_L: length 2.4
  TOP w0.203: CA72.1 177.54,31.52 176.99,30.97 UA2.45
PORTB_R: length 3.2
  TOP w0.203: UA2.46 175.87,31.72 176.08,31.93 177.9,31.93 178.43,32.46 CA73.1
PORTD_A: length 8.7
  TOP w0.203: v1(177.97,29.82) 177.91,29.77 UA2.42
  TOP w0.254: v1(183.39,28.01) 183.32,28.01 183.07,28.27 RA241.1
  ART03 w0.254: v1(177.97,29.82) 178.33,29.46 181.94,29.46 v1(183.39,28.01)
PORTD_B: length 9
  TOP w0.203: v1(177.85,30.45) 177.56,30.17 UA2.43
  TOP w0.254: RA240.1 183.89,28.47 v1(183.79,28.57)
  ART03 w0.254: v1(177.85,30.45) 178.1,30.71 179.32,30.71 179.88,30.15 181.91,30.15 183.49,28.57 v1(183.79,28.57)
POST_DEBUG_CLK: length 27.9
  TOP w0.076: UE1.A4 161.97,20.73 161.08,21.61
  TOP w0.102: RW73.1 150.49,13.92 v1(150.24,13.66) ; v2(146.48,9.47) 146.43,9.42 RP14.1 ; v2(161.08,22.12) 161.08,21.61
  ART06 w0.102: v1(150.24,13.66) 151.08,14.5 151.08,15.62 151.49,16.03 151.49,16.78 151.72,17.02 152.2,17.02 152.91,17.72 152.91,19.43 154.29,20.81 155.21,20.81 156.22,21.82 160.78,21.82 v2(161.08,22.12)
  BOTTOM w0.102: v1(150.24,13.66) 149.22,13.66 148.08,12.52 148.08,9.93 147.78,9.62 146.63,9.62 v2(146.48,9.47) 146.48,9.4 v3(145.79,8.71)
POST_DEBUG_CLK_R: length 2.4
  TOP w0.102: TPP13.1 145.62,8.84 146,8.46 RP14.2 146.43,7.44 JP2.2
POST_DEBUG_DATA: length 28.5
  TOP w0.076: UE1.A3 161.47,20.72 160.27,21.92 160.27,21.99 160.27,22 v2(160.27,22.22)
  TOP w0.102: v1(149.71,8.48) 149.55,8.33 RP15.1 ; RW74.1 150.62,13.41 150.37,13.15 v1(149.48,13.15)
  ART06 w0.102: v2(160.27,22.22) 160.27,22.17 160.17,22.07 156.11,22.07 155.05,21.02 154.19,21.02 152.7,19.53 152.7,17.81 152.11,17.22 151.63,17.22 151.23,16.82 151.23,16.18 149.48,14.42 v1(149.48,13.15)
  BOTTOM w0.102: v3(149.3,7.24) 149.71,7.64 v1(149.71,8.48) 149.78,8.56 149.78,12.85 v1(149.48,13.15)
POST_DEBUG_DATA_R: length 3
  TOP w0.102: JP2.3 146.93,8.07 147.19,8.33 RP15.2 147.57,9.17 147.32,9.42 TPP14.1
PP_TPM: length 3.3
  TOP w0.102: UF15.4 137.41,33.71 136.9,34.21 RF9.1 RF10.2 136.57,35.3 v3(136.57,35.86)
PRE_8409A: length 2.4
  TOP w0.102: RI104.2 21.82,48.11 v3(22.49,48.78) 22.86,49.14 UI2.27
PROCHOT_EC_N: length 2.3
  TOP w0.102: v3(153.51,10.9) 153.96,10.45 QE4.3 RE92.1
PROCHOT_SOC_N: length 6.4
  BOTTOM w0.076: UU1.C3 111.11,42.94 111.11,42.51 111.32,42.31 111.57,42.31 111.82,42.06 111.82,41.29
  BOTTOM w0.102: RU19.2 114.17,38.94 111.82,41.29
PROCPWRGD: length 4.6
  BOTTOM w0.203: RU160.2 CU32.1 79.5,38.68 TPU24.1 79.88,39.72 79.68,39.93 UU1.CF1
PSI_VGA: length 31.2
  ART06 w0.102: v1(143.67,54.85) 148.04,54.85 148.97,53.92 149.6,53.92 149.99,53.54 149.99,51.36 150.09,51.25 156.97,51.25 162.18,46.05 167.26,46.05 v1(167.64,45.67)
  BOTTOM w0.102: v1(167.64,45.67) 166.97,45.67 PR835.2 ; RV42.1 143.41,55.12 v1(143.67,54.85) 143.47,54.65 RV34.1
PSI_VGA_R: length 4
  BOTTOM w0.102: RV42.2 143.44,55.88 UV2.A4
PWR_BUTTON_N: length 29.1
  TOP w0.102: v1(160.73,6.98) 160.12,6.37 RE451.1 158.75,6.12 v3(159.41,5.46) ; RE2.1 RE1.2 160.83,24.71 160.91,24.79 v1(160.91,24.96) 161.37,25.42 PBTE1.1
  ART03 w0.089: v1(160.91,24.96) 163.32,22.55 163.32,20.65 164.59,19.38 164.59,18.74 164.84,18.49 164.84,15.81 164.34,15.3 164.34,11.76 163.32,10.74 162.18,10.74 160.98,9.55 160.98,7.95 160.73,7.69 v1(160.73,6.98)
PWR_BUTTON_N_KB: length 17.9
  TOP w0.102: SW5.1 166.4,5.66 162.17,5.66 SW5.2 161.05,4.54 v3(158.44,4.54) 158.31,4.68 156.94,4.68 156.59,5.03 156.59,6.8 v1(156.82,7.03) 156.87,6.98 ESDE44.1 157.89,6.98 157.99,6.88 CE373.1 RE451.2
  BOTTOM w0.102: JE7.27 157.9,7.4 157.53,7.03 v1(156.82,7.03)
PWR_LEVEL: length 10.7
  TOP w0.102: v1(145.55,61.83) 145.41,61.69 145.41,60.51 144.35,59.44 144.35,57.18 145.03,56.5 v1(145.03,53.92)
  BOTTOM w0.102: UV2.D7 v1(145.55,61.83) ; QV24.3 145.9,54.07 145.84,54.13 RV31.1 145.24,54.13 v1(145.03,53.92)
REMOTE1+: length 170.9
  TOP w0.254: v2(74.65,5.38) 75.54,4.49 78.79,4.49 81.23,2.05 88.9,2.05 89.48,1.47 133.3,1.47 135.97,4.14 144.06,4.14 144.52,3.68 146.25,3.68 147.83,2.11 170.26,2.11 171.83,3.67 171.83,14.42 172.36,14.96 172.36,16.23 172.85,16.71 172.85,17.73 v1(172.46,18.11)
  ART06 w0.254: v1(168.46,47.95) 168.46,47.82 169.92,46.35 169.92,43 167.28,40.36 167.28,37.77 168.78,36.27 168.78,34.87 165.99,32.08 165.99,29.41 166.24,29.16 166.88,29.16 167.56,28.47 167.56,26.44 168.58,25.42 168.83,25.42 169.29,24.97 169.29,23.29 169.9,22.68 170.69,22.68 172.46,20.9 v1(172.46,18.11)
  BOTTOM w0.254: US1.2 68.89,6.82 69.8,5.92 73.15,5.92 73.4,6.17 74.62,6.17 CS2.1 74.78,5.51 v2(74.65,5.38) ; QS1.3 168.46,55.62 QS1.1 168.15,54.26 168.15,49.25 v3(168.35,49.04) 168.46,48.93 v1(168.46,47.95)
REMOTE1-: length 167.1
  TOP w0.254: v2(75.41,5.41) 75.82,5 79,5 81.44,2.56 89.66,2.56 90.24,1.98 133.09,1.98 135.76,4.65 144.27,4.65 144.71,4.2 146.49,4.2 148.08,2.61 170.05,2.61 171.32,3.88 171.32,14.64 171.83,15.14 171.83,16.71 v1(172.36,17.24)
  ART06 w0.254: v1(167.64,47.7) 169.42,45.92 169.42,43.25 166.77,40.61 166.77,37.51 168.27,36.01 168.27,35.13 165.48,32.33 165.48,29.03 165.86,28.65 166.62,28.65 167.05,28.22 167.05,26.18 168.27,24.97 168.27,24.2 168.78,23.7 168.78,23.06 169.67,22.17 170.43,22.17 171.83,20.77 171.83,17.85 172.34,17.35 172.34,17.27 v1(172.36,17.24)
  BOTTOM w0.254: v1(167.64,47.7) 167.64,52.04 v3(166.83,52.85) 166.83,53.11 166.56,53.37 QS1.2 ; v2(75.41,5.41) 75.28,5.53 CS2.2 75.28,6.37 74.93,6.73 73,6.73 72.69,6.42 69.9,6.42 69.39,6.93 US1.3
REMOTE2+: length 204.5
  TOP w0.254: v2(132.33,3.63) 131.82,4.14 130.25,4.14 v3(129.49,3.38) 129.11,2.99 92.25,2.99 91.38,3.86 82.02,3.86 79.76,6.12 76.68,6.12 v2(76.1,5.53)
  ART05 w0.254: v2(162.81,28.83) 163.02,29.03 168.02,29.03 169.29,27.76 169.29,26.32 171.45,24.16 171.45,22.93 172.21,22.17 172.21,21.03 173.48,19.76 173.48,16.33 172.21,15.06 172.21,8.2 166.24,2.23 146.68,2.23 144.78,4.14 132.84,4.14 v2(132.33,3.63)
  ART06 w0.254: v2(162.81,28.83) 162.61,28.83 162.38,28.6 160.53,28.6 160.02,29.11 160.02,30.93 160.65,31.57 160.65,33.93 159.99,34.59 145.51,34.59 140.98,39.13 135.95,39.13 135.13,39.95 135.13,42.47 131.04,46.56 130.55,46.56 130.3,46.81 130.3,57.18 127.59,59.89 124.41,59.89 v1(124.2,60.09)
  BOTTOM w0.254: v2(76.1,5.53) 76.1,5.56 76.05,5.61 CS17.1 76.05,6.37 75.13,7.29 72.54,7.29 72.24,6.98 70.14,6.98 69.89,7.24 US1.4
  BOTTOM w0.279: QS2.3 v1(124.2,60.09) QS2.1
REMOTE2-: length 200.7
  TOP w0.254: v2(131.57,3.63) 131.47,3.63 v3(130.83,2.99) 130.33,2.49 91.54,2.49 90.93,3.1 82.07,3.1 79.55,5.61 76.91,5.61 v2(76.81,5.51)
  ART05 w0.254: v2(131.57,3.63) 132.59,4.65 144.99,4.65 146.89,2.74 165.99,2.74 171.7,8.46 171.7,15.31 172.97,16.58 172.97,19.5 171.7,20.77 171.7,21.92 170.94,22.68 170.94,23.95 168.78,26.11 168.78,27.51 167.77,28.52 163.47,28.52 162.79,27.84 v2(162.71,27.84)
  ART06 w0.254: v2(162.71,27.84) 162.69,27.84 162.43,28.09 160.15,28.09 159.51,28.72 159.51,31.32 160.15,31.95 160.15,33.7 159.76,34.08 145.21,34.08 140.71,38.58 135.74,38.58 134.62,39.7 134.62,42.26 130.83,46.05 130.34,46.05 129.79,46.6 129.79,56.97 127.38,59.38 124.33,59.38 v1(124.2,59.26)
  BOTTOM w0.254: v2(76.81,5.51) 76.81,5.53 76.55,5.79 CS17.2 76.55,6.63 75.39,7.8 72.18,7.8 71.88,7.49 70.64,7.49 70.39,7.74 US1.5
  BOTTOM w0.279: QS2.2 124.09,59.14 v1(124.2,59.26)
RESETB_8409A: length 2.4
  TOP w0.102: UI2.35 26.06,49.45 26.29,49.22 RI154.1 CI120.1
RETIMER_FORCE_PWR: length 156.1
  TOP w0.102: v2(19.81,19.12) 19.81,18.97 19.2,18.36 18.46,18.36 18.34,18.23 18.34,17.57 18.44,17.47 RT36.2 ; v3(30.27,34.01) 30.43,33.86 v2(31.32,33.86)
  ART03 w0.089: v2(19.81,19.12) 19.94,19.25 19.94,23.68 19.66,23.95 19.66,25.41 20.45,26.19 20.45,26.68 20.74,26.97 23.09,26.97 23.24,27.12 24.76,27.12 25.53,27.89 27.28,27.89 31.32,31.93 v2(31.32,33.86) 30.96,34.21 30.96,35.2 32.76,37.01 32.76,37.31 33.22,37.77 33.53,37.77 33.91,38.15 33.91,41.22 32.26,42.87 29.87,42.87 27.86,44.88 27.86,47.6 27.77,47.69 27.77,49.96 28.62,50.81 28.62,57.27 28.29,57.6 28.29,61.62 27.63,62.28 27.63,63.12 27.99,63.47 27.99,65.28 27.53,65.73 27.53,71.96 25.79,73.7 25.79,75.13 25.66,75.26 25.66,77.25 27.1,78.69 32.64,78.69 35.05,76.27 35.94,76.27 36.49,75.73 41.09,75.73 42.07,74.75 45.82,74.75 46.81,73.76 50.72,73.76 51.51,72.97 52.19,72.97 52.85,73.63 57.21,73.63 57.54,73.96 63.3,73.96 65.02,72.24 65.02,71.72 65.98,70.76 68.55,70.76 68.91,71.12 70.43,71.12 74.52,67.03 74.52,64.87 75.33,64.06 75.33,62.66 75.56,62.43 75.56,61.57 v2(75.15,61.16)
  BOTTOM w0.102: UU1.CR39 75.27,61.16 v2(75.15,61.16) ; TPT21.1 39.57,40.87 RT10.2 39.19,39.7 39.19,38.87 38.9,38.58 38.18,38.58 37.8,38.2 35.01,38.2 34.52,37.71 34.52,33.58 34.03,33.09 33.17,33.09 32.41,33.86 v2(31.32,33.86)
RIPQ_N_SOC: length 184.4
  TOP w0.102: v3(134.11,25.17) 134.49,25.55 v2(134.49,25.85) 134.49,26.67 RF6.2
  ART05 w0.102: v1(60.83,77.54) 60.83,76.2 53.86,69.23 53.86,66.1 54.35,65.61 54.35,63.52 54.86,63.01 54.86,58.04 53.87,57.05 53.87,55.98 53.49,55.6 53.49,53.06 54.05,52.5 54.05,45.26 53.8,45.01 53.8,36.85 61.24,29.41 76.38,29.41 77.47,30.5 84.73,30.5 85.95,29.28 95.12,29.28 96.44,27.96 98.35,27.96 101.19,25.12 101.19,18.31 104.14,15.36 105.81,15.36 106.68,14.5 107.49,14.5 108.62,13.37 112.02,13.37 113,12.39 126.87,12.39 130.15,15.67 136.15,15.67 137.92,17.44 137.92,22.17 134.49,25.6 v2(134.49,25.85)
  BOTTOM w0.076: UU1.CC48 81.14,65.5 81.02,65.62 80.99,65.66 80.99,66.48 80.85,66.62
  BOTTOM w0.102: 80.85,66.62 80.47,67 80.47,67.43 79.69,68.21 78.58,68.21 72.85,73.94 69.01,73.94 v3(68.43,74.52) 67.82,75.12 66.94,75.12 65.16,76.91 61.47,76.91 v1(60.83,77.54)
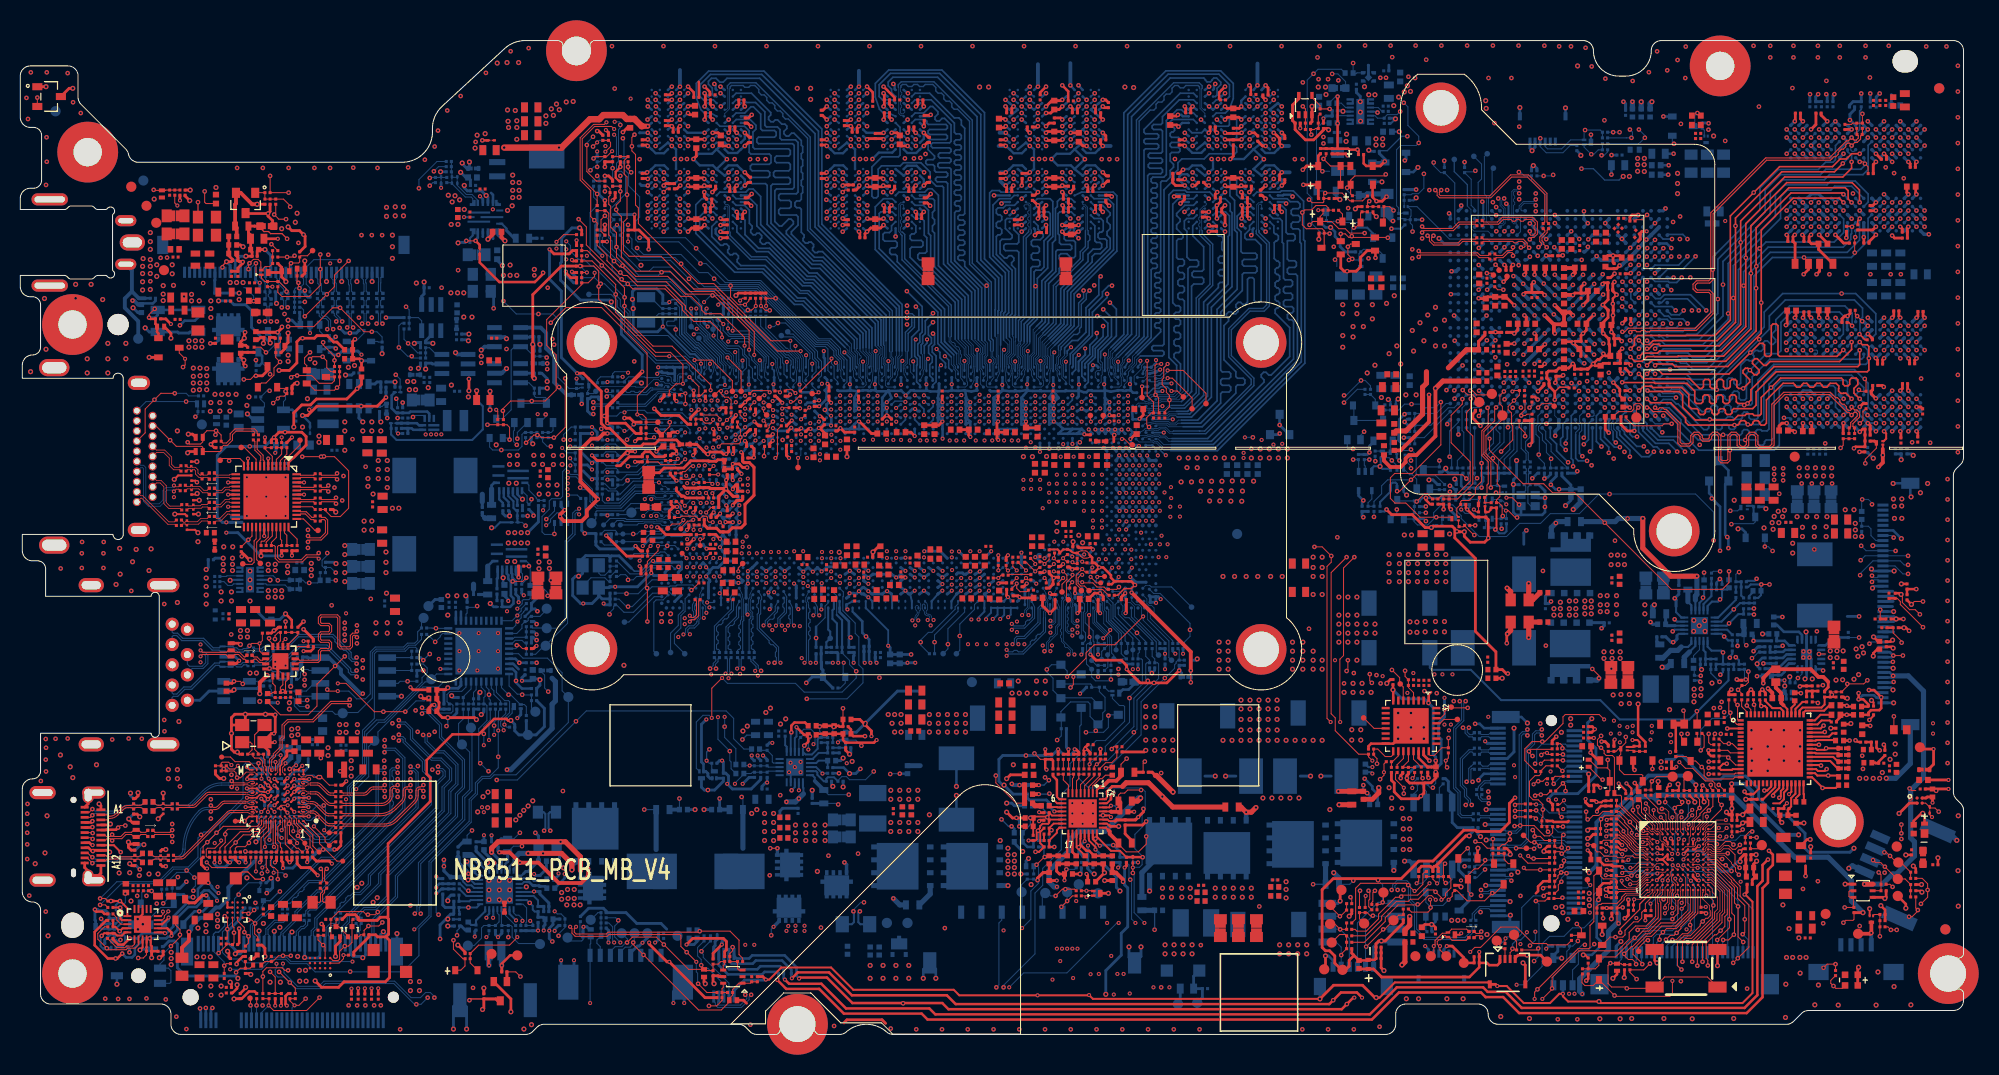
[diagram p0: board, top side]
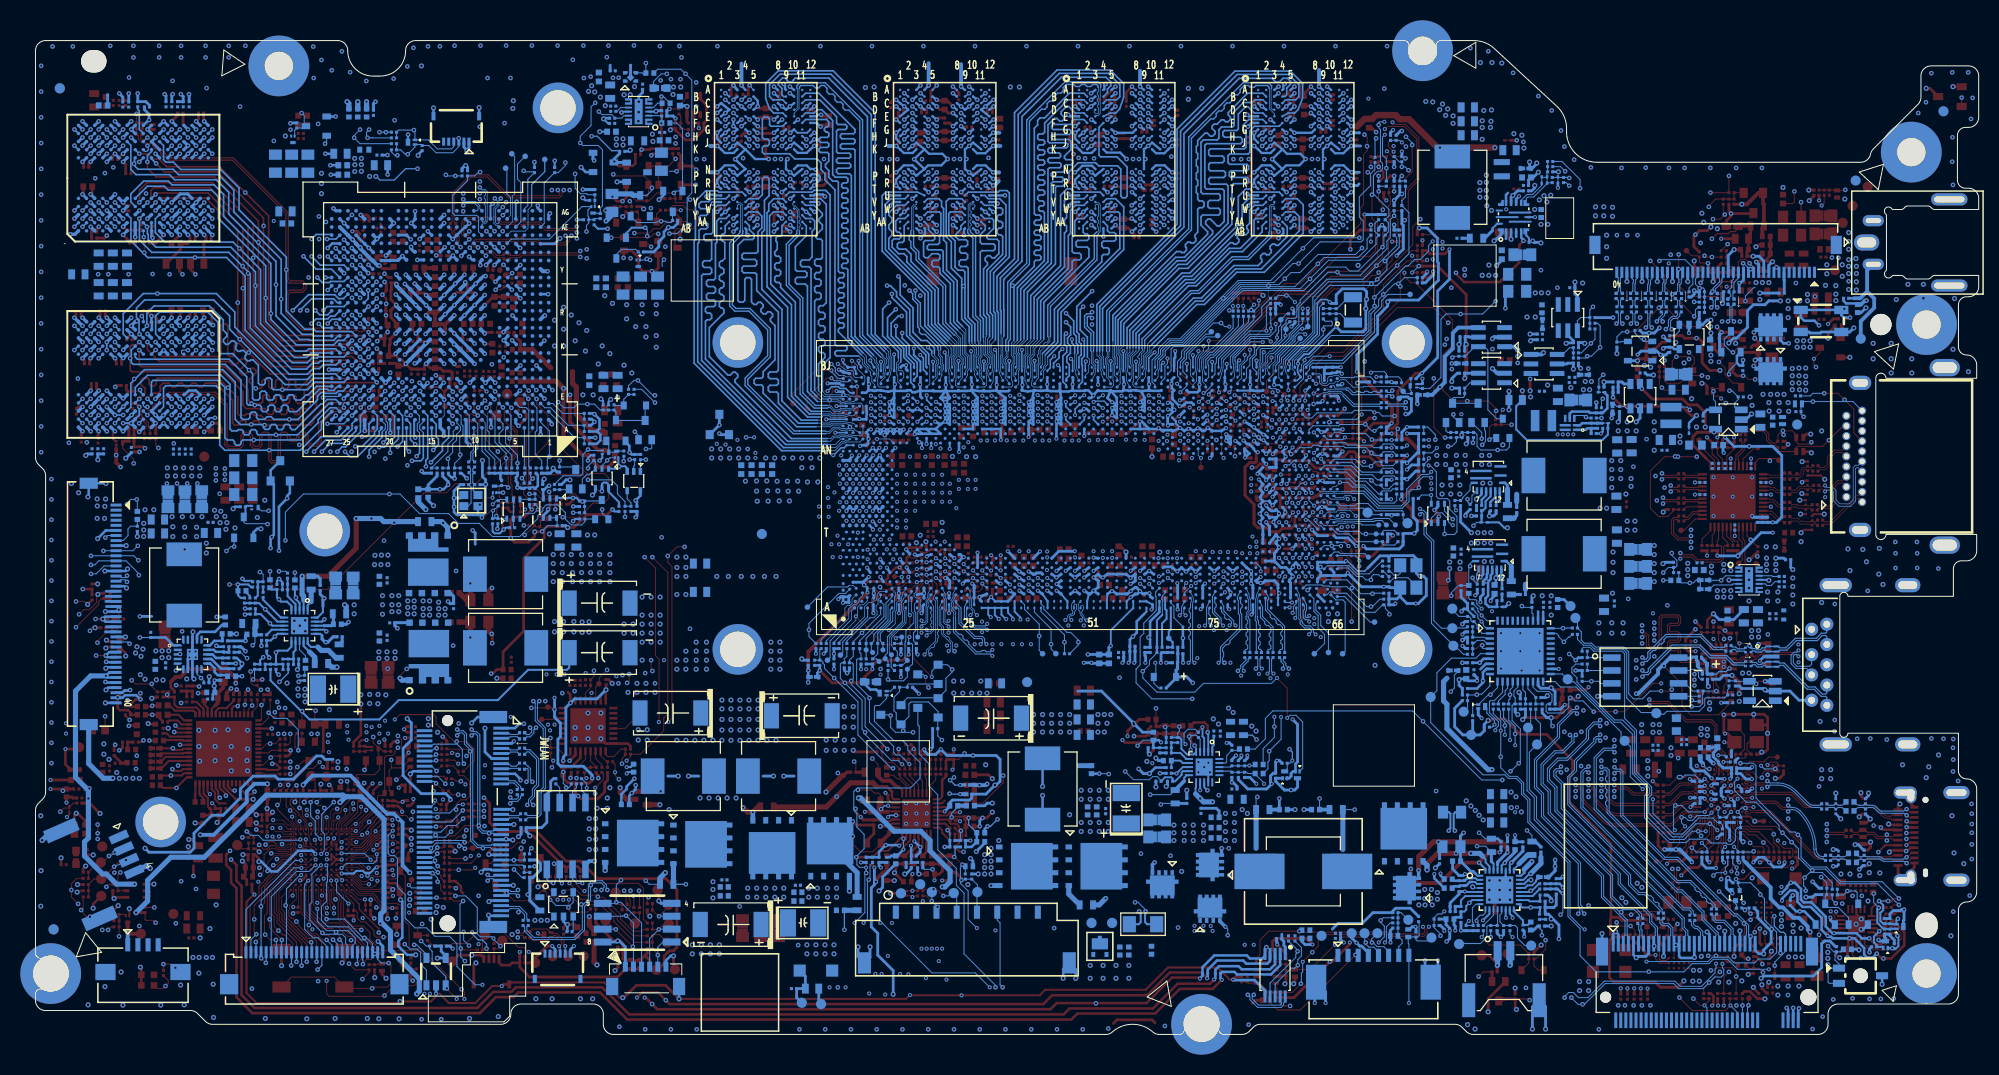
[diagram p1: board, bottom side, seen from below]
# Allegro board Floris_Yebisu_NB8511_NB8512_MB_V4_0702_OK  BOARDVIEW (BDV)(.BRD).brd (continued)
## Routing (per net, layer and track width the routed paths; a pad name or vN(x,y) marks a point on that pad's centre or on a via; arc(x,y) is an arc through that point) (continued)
RIPQ_N_TPM: length 1.9
  TOP w0.102: RE447.2 RF6.1 135.33,26.9 135.91,27.48 UF15.18
ROM_SCLK: length 6.8
  BOTTOM w0.102: UV2.C12 149.67,60.99 149.67,60.2 149.48,60.01 149.48,59.17 149.81,58.84 149.81,57.23 v3(149.76,57.17) 149.76,56.87 150.32,56.31 RV127.1 RV124.2
ROM_SI: length 6
  BOTTOM w0.102: RV123.2 RV126.1 150.92,56.72 v3(150.98,56.77) 150.98,56.92 150.51,57.38 150.51,58.21 150.12,58.6 150.12,59.17 149.74,59.55 149.74,59.95 150.1,60.3 UV2.B12
ROM_SO: length 5.6
  BOTTOM w0.102: RV122.2 RV125.1 150.98,57.48 150.98,58.19 150.45,58.71 150.45,59.46 UV2.A12
RSMRST_N_EC: length 267.3
  TOP w0.076: 159.66,20.65 159.89,20.42 160.3,20.42 UE1.A1
  TOP w0.102: v3(155.91,29.44) 155.55,29.08 155.55,28.52 155.8,28.27 v1(155.9,28.27) 156.21,27.96 156.21,27.71 156.41,27.51 157.02,27.51 157.22,27.31 DL3.2 157.43,23.58 157.82,23.58 157.92,23.48 157.92,22.59 159.66,20.85 159.66,20.65
  ART03 w0.089: v1(155.9,28.27) 155.14,27.51 155.14,24.48 156.31,23.31 156.31,21.87 155.8,21.36 155.8,16.94 155.24,16.38 154.53,16.38 152.3,14.15 151.84,14.15 149.55,11.86 149.25,11.86 147.37,9.98 146.4,9.98 145.13,8.71 141.68,8.71 141.27,8.3 138.33,8.3 137.77,8.86 135.28,8.86 134.72,8.3 133.2,8.3 131.82,6.93 117.4,6.93 115.95,8.38 112.49,8.38 112.32,8.2 109.07,8.2 108.61,8.66 105.05,8.66 104.47,8.07 101.88,8.07 98.91,5.1 97.43,5.1 v1(96.98,4.65) 96.47,5.15 95.65,5.15 95.5,5 73.4,5 72.9,5.51 70.76,5.51 69.82,4.57 46.76,4.57 46.23,4.04 44.3,4.04 40.74,7.59 40.74,12.52 39.62,13.64 39.62,18.59 45.69,24.66 47.14,24.66 51.71,29.23 51.71,35.18 51.33,35.56 51.33,41.3 52.63,42.59 52.63,48.99 54.56,50.92 54.56,52.07 55.22,52.73 55.22,53.72 55.47,53.97 55.47,59.87 54.66,60.68 54.66,62.71 56.39,64.44 57.45,64.44 58.27,65.25 v2(59.94,65.25)
  ART05 w0.102: v2(59.94,65.25) 59.99,65.25 60.45,65.71 60.5,65.71 62.43,67.64 65.02,67.64 v2(66.42,69.03)
  BOTTOM w0.102: QU6.3 104.63,30.54 104.49,30.4 104.49,27.66 103.53,26.69 103.53,24.51 102.66,23.64 102.66,18.21 100.84,16.38 100.84,14.7 100.07,13.94 100.07,7.95 96.98,4.85 v1(96.98,4.65) ; v2(59.94,65.25) 59.87,65.25 59.76,65.35 58.62,65.35 58.42,65.15 RU176.1 57.22,64.84 56.92,64.54 CU39.1 ; UU1.DG49 69.34,65.96 68.97,66.33 68.97,66.84 67.44,68.37 67.44,68.78 67.05,69.16 66.55,69.16 v2(66.42,69.03)
RT_TCP0_I2C0_SCL: length 90
  TOP w0.102: RT39.2 24.26,16.46 24.38,16.33 v2(24.38,16.08)
  ART03 w0.089: v2(24.38,16.08) 24.38,16.96 26.69,19.28 26.97,19.28 28.64,20.94 29.2,20.94 33.32,25.07 33.32,27.66 32.76,28.22 32.76,31.16 33.07,31.47 33.42,31.47 36.92,34.96 36.92,41.01 33.46,44.46 33.46,50.86 33.83,51.23 33.83,55.9 36.83,58.9 36.83,59.46 37.2,59.83 38.8,59.83 40.8,61.83 44.77,61.83 46.23,60.37 49.07,60.37 51.94,57.5 51.94,55.8 52.66,55.08 53.81,55.08 v2(54,54.89)
  BOTTOM w0.076: 61.85,53.34 61.87,53.34 61.9,53.38 62.74,53.38 62.77,53.35 63.39,53.35 63.52,53.4 63.65,53.4 63.79,53.35 64.09,53.35 64.17,53.38 64.35,53.38 64.42,53.35 64.65,53.35 UU1.DT23
  BOTTOM w0.102: v2(54,54.89) 54.1,54.99 54.81,54.99 55.22,54.58 v3(55.22,53.92) 55.42,53.72 55.98,53.72 56.18,53.52 56.18,52.55 56.84,51.89 59.25,51.89 60.7,53.34 61.85,53.34
RT_TCP0_I2C0_SDA: length 90.5
  ART03 w0.089: v2(54,55.47) 54,55.43 53.86,55.29 52.75,55.29 52.16,55.89 52.16,57.59 49.16,60.59 46.32,60.59 44.85,62.05 40.71,62.05 38.71,60.04 37.11,60.04 36.61,59.55 36.61,58.99 33.62,55.99 33.62,51.37 33.25,51 33.25,44.37 36.7,40.92 36.7,35.05 33.34,31.68 32.98,31.68 32.55,31.25 32.55,28.13 33.11,27.57 33.11,25.16 29.11,21.16 28.55,21.16 26.88,19.49 26.6,19.49 24.17,17.05 24.17,16.75 v2(23.87,16.46)
  BOTTOM w0.076: 61.85,53.57 61.87,53.57 61.9,53.54 62.8,53.54 62.83,53.51 63.35,53.51 63.49,53.57 63.69,53.57 63.82,53.51 64.06,53.51 64.13,53.54 64.38,53.54 64.46,53.51 64.96,53.51 UU1.DT24
  BOTTOM w0.102: v2(54,55.47) 54.25,55.22 54.96,55.22 56.41,53.76 56.41,52.64 56.94,52.12 59.15,52.12 60.61,53.57 61.85,53.57 ; RT40.2 24.26,16.84 v2(23.87,16.46) 23.87,15.92 v3(23.82,15.87)
RTC_RST_N: length 12.2
  BOTTOM w0.076: UU1.DT47 65.02,64.75 65.02,64.29 64.72,63.98 64.25,63.98 64.02,64.21 63.6,64.21 63.45,64.36 63.15,64.36 62.94,64.56 62.46,64.56 61.72,63.83 60.7,63.83 60.65,63.88 57.22,63.88
  BOTTOM w0.102: 57.22,63.88 TPU8.1 56.54,63.19 55.95,63.19 55.95,63.45 56.07,63.56 QU2.3 56.01,64.02 56.01,64.67
RTC_VCC: length 4.1
  TOP w0.254: v1(47.49,6.8) 47.49,6.97 48.31,7.8 TP188.1
  TOP w0.305: RU174.1 v1(47.49,6.8)
  BOTTOM w0.508: JRTCU1.1 47.45,6.84 v1(47.49,6.8)
SATA1_DEVSLP: length 135.4
  TOP w0.102: RN4.2 27.13,4.57 v3(26.58,5.11) v1(25.53,6.17)
  ART03 w0.102: v2(30.57,76.03) 30.57,76.01 32.97,73.61 38.2,73.61 39.91,71.89 45.43,71.89 46.63,70.69 53.57,70.69 54.67,71.78 58.56,71.78 59.97,70.38 59.97,69.44 61.34,68.07 69.57,68.07 v2(69.82,68.32)
  ART06 w0.102: v1(25.53,6.17) 24.89,6.8 24.89,7.59 26.24,8.94 26.24,11.63 22.83,15.03 22.83,22.27 23.24,22.68 23.24,26.36 22.17,27.43 20.78,27.43 20.19,28.01 20.19,30.55 21.97,32.33 21.97,36.01 23.11,37.16 23.11,42.87 22.1,43.89 22.1,48.59 21.84,48.84 21.84,59 23.82,60.98 23.82,67.21 23.49,67.54 23.49,69.67 23.06,70.1 23.06,71.51 24.52,72.97 25.53,72.97 27.56,75 29.54,75 v2(30.57,76.03)
  BOTTOM w0.076: 73.56,66.38 73.56,66.19 73.49,66.13 73.49,65.78 73.54,65.33 UU1.CV48
  BOTTOM w0.102: v2(69.82,68.32) 70.13,68.63 71.74,68.63 73.56,66.81 73.56,66.38
SATA1_DEVSLP_CON: length 4.3
  TOP w0.102: v3(28.14,3.53) 27.48,2.87 v2(27.05,2.87) 26.59,3.32 RN5.2 RN4.1
  BOTTOM w0.102: v2(27.05,2.87) 26.8,2.62 JSSD1.38
SCANIN0: length 10.1
  TOP w0.076: 168.55,14.3 166.86,15.99 166.22,15.99 UE1.J12
  TOP w0.102: v1(167.36,9.32) 168.56,10.52 v3(168.56,11.35) 168.56,14.29 168.55,14.3
  BOTTOM w0.102: v1(167.36,9.32) 167.4,9.28 JE7.8
SCANIN1: length 10.3
  TOP w0.076: 168.55,14.65 166.96,16.24 UE1.J13
  TOP w0.102: 168.55,14.65 168.8,14.41 168.8,11.97 169.06,11.71 169.06,9.9 v3(169,9.84) 168.48,9.32 v1(167.94,9.32)
  BOTTOM w0.102: JE7.7 167.9,9.28 v1(167.94,9.32)
SCANIN2: length 11.8
  TOP w0.076: v2(164.03,16.68) UE1.J9
  BOTTOM w0.102: JE7.6 168.4,13.59 165.91,16.07 164.67,16.07 164.06,16.68 v2(164.03,16.68)
SCANIN3: length 14.4
  TOP w0.076: 166.77,16.99 166.22,16.99 165.97,16.75 UE1.H12
  TOP w0.102: 166.77,16.99 167.28,16.99 169.02,15.25 169.02,15.2 169.62,14.6 169.62,13.64 170.48,12.77 170.48,8.61 v3(169.39,7.51) v1(168.93,7.06)
  BOTTOM w0.102: v1(168.93,7.06) 168.9,7.09 JE7.5
SCANIN4: length 11.5
  TOP w0.076: UE1.H9 164.73,16.48 165.37,16.48 v2(165.43,16.43)
  BOTTOM w0.102: v2(165.43,16.43) 166.17,16.43 169.4,13.2 JE7.4
SCANIN5: length 11.8
  TOP w0.076: UE1.H10 165.13,16.74 165.15,16.77 165.58,16.77 165.86,16.49 167.07,16.49 168.55,15.01
  TOP w0.102: 168.55,15.01 169.06,14.5 169.06,12.98 v3(169.42,12.62) 169.42,9.62 v1(169.92,9.12)
  BOTTOM w0.102: v1(169.92,9.12) 169.9,9.09 JE7.3
SCANIN6: length 10.9
  TOP w0.102: UE1.H13 167.22,16.74 168.78,15.19 168.78,15.05 169.37,14.47 169.37,13.43 170.08,12.72 v3(170.08,11.35) 170.08,10.08 v1(169.87,9.88)
  BOTTOM w0.102: v1(169.87,9.88) 170.4,9.35 JE7.2
SCANIN7: length 12.8
  TOP w0.076: UE1.G9 164.73,16.99 165.1,16.99 165.26,17.15 v2(165.45,17.15)
  BOTTOM w0.102: JE7.1 170.9,12.31 166.05,17.15 v2(165.45,17.15)
SCANOUT0: length 10.2
  TOP w0.076: UE1.M8 163.71,14.49 163.71,14.11 163.75,14.07 163.75,13.43 163.65,13.33
  TOP w0.102: 163.65,13.33 163.5,13.18 163.5,11.94 v1(162.94,11.38)
  BOTTOM w0.102: JE7.26 158.4,8.93 159.09,9.62 159.43,9.62 161.19,11.38 v1(162.94,11.38)
SCANOUT1: length 12.8
  TOP w0.076: v2(162.96,16.69) 163.32,16.33 163.39,16.33 UE1.J7
  BOTTOM w0.102: JE7.25 158.9,9.01 159.21,9.32 159.51,9.32 160.81,10.61 162.81,10.61 163.45,11.25 163.45,12.62 162.94,13.13 162.94,14.96 162.86,15.03 162.86,16.58 v2(162.96,16.69)
SCANOUT2: length 13
  TOP w0.076: UE1.N9 164.47,12.25 164.29,12.07
  TOP w0.102: v1(159.36,6.93) 159.36,7.03 159,7.39 158.6,7.39 158.18,7.8 v3(158.18,7.95) 158.9,8.66 159,8.66 160.27,9.93 160.73,9.93 161.8,11 163.22,11 164.29,12.07
  BOTTOM w0.102: v1(159.36,6.93) 159.36,7.34 159.4,7.38 JE7.24
SCANOUT3: length 13
  TOP w0.076: UE1.M9 164.72,14.49 164.72,12.14 164.64,12.07
  TOP w0.102: v1(159.97,6.93) 159.97,6.98 159.05,7.9 159.05,8.38 160.35,9.67 160.88,9.67 161.9,10.69 163.27,10.69 164.64,12.07
  BOTTOM w0.102: v1(159.97,6.93) 159.9,7 JE7.23
SCANOUT4: length 10.8
  TOP w0.075: UE1.K8 164.22,15.49 164.22,15.35
  TOP w0.076: 164.22,15.35 164.22,12.75
  TOP w0.102: v2(163.85,12.39) 163.87,12.39 164.22,12.75
  BOTTOM w0.102: JE7.22 160.4,8.73 160.12,9.01 160.12,9.52 160.83,10.23 162.94,10.23 163.85,11.15 v2(163.85,12.39)
SCANOUT5: length 12.3
  TOP w0.076: v2(163.5,16.69) 163.52,16.69 163.96,16.24 UE1.J8
  BOTTOM w0.102: JE7.21 160.9,8.81 161.06,8.97 161.06,9.55 161.39,9.88 163.22,9.88 164.59,11.25 164.59,12.82 164.39,13.03 164.39,15.82 163.52,16.69 v2(163.5,16.69)
SCANOUT6: length 8.2
  TOP w0.076: 164.95,12.07 164.97,12.09 UE1.N10
  TOP w0.102: v1(161.67,9.34) 161.67,9.75 v3(162,10.09) 162.35,10.44 163.32,10.44 164.95,12.07
  BOTTOM w0.102: v1(161.67,9.34) 161.4,9.08 JE7.20
SCANOUT7: length 8.3
  TOP w0.076: 165.22,12.07 165.22,14.49 UE1.M10
  TOP w0.102: 165.22,12.07 165.22,12.05 163.78,10.61 163.78,10.44 v3(163.35,10.01) 163.12,9.78 162.74,9.78 v1(162.3,9.34)
  BOTTOM w0.102: v1(162.3,9.34) 161.9,8.94 161.9,8.1 JE7.19
SCANOUT8: length 8
  TOP w0.076: UE1.N11 165.45,14.23 165.45,12.07
  TOP w0.102: 165.45,12.07 165.45,11.96 164.69,11.2 v3(164.69,10.79) 164.79,10.69 164.79,10.28 164.44,9.93 163.93,9.93 163.32,9.32 v1(162.94,9.32)
  BOTTOM w0.102: JE7.18 162.4,8.78 v1(162.94,9.32)
SCANOUT9: length 9.1
  TOP w0.076: v2(164.76,15.16) 164.47,15.44 UE1.K9
  BOTTOM w0.102: JE7.17 162.9,8.67 163.76,9.54 164.27,9.54 165.1,10.36 165.1,14.82 v2(164.76,15.16)
SCANOUT10: length 12
  TOP w0.076: UE1.N12 165.97,14.03 165.92,13.98 165.92,13.37 166.6,12.7 166.6,12.29 166.67,12.21 166.67,12.07
  TOP w0.102: 166.67,12.07 166.67,11.7 166.42,11.45 166.24,11.45 v3(165.93,11.14) 165.68,10.89 165.68,10.72 164.69,9.73 164.08,9.73 163.43,9.08 163.43,6.79 v1(163.83,6.4)
  BOTTOM w0.102: v1(163.83,6.4) 163.4,6.83 JE7.16
SCANOUT11: length 9.9
  TOP w0.076: 166.87,12.07 166.87,12.62 v3(166.98,12.72) 166.98,13.18 166.64,13.52 166.64,14.07 UE1.N13
  TOP w0.102: v1(163.93,7.17) 163.93,9.19 164.21,9.47 164.83,9.47 166.87,11.51 166.87,12.07
  BOTTOM w0.102: v1(163.93,7.17) 163.9,7.2 JE7.15
SCANOUT12: length 8.4
  TOP w0.076: 167.1,12.07 167.38,12.35 167.38,13.54 166.87,14.05 166.87,14.35 UE1.M13
  TOP w0.102: 167.1,12.07 167.1,11.41 164.78,9.09 v1(164.46,9.09)
  BOTTOM w0.102: JE7.14 164.4,9.03 v1(164.46,9.09)
SCANOUT13: length 11.1
  TOP w0.076: 167.34,11.92 167.64,12.21 167.64,14.08 166.73,14.99 166.22,14.99 UE1.L12
  TOP w0.102: 167.34,11.92 167.34,11.29 164.89,8.85 v1(164.89,7.17)
  BOTTOM w0.102: JE7.13 164.9,7.18 v1(164.89,7.17)
SCANOUT14: length 11.6
  TOP w0.076: UE1.L13 166.77,15.24 167.89,14.12 167.89,12.16 167.61,11.88
  TOP w0.102: 167.61,11.88 167.61,11.22 165.4,9.01 v1(165.4,6.78)
  BOTTOM w0.102: JE7.12 165.4,8.1 v1(165.4,6.78)
SCANOUT15: length 11.6
  TOP w0.076: 168.1,12.27 168.1,14.18 166.78,15.49 166.22,15.49 UE1.K12
  TOP w0.102: 168.1,12.27 168.1,12.01 167.83,11.75 167.83,11.04 165.91,9.12 v1(165.91,7.17)
  BOTTOM w0.102: JE7.11 165.9,7.18 v1(165.91,7.17)
SCANOUT16: length 12.3
  TOP w0.076: UE1.K13 166.8,15.74 168.35,14.2 168.35,12.37
  TOP w0.102: 168.35,12.37 168.35,11.86 168.11,11.62 168.11,10.66 v3(167.69,10.24) 167.28,9.83 167.11,9.83 166.27,8.98 166.27,7.49 166.43,7.32 v1(166.43,6.79)
  BOTTOM w0.102: JE7.10 166.4,6.83 v1(166.43,6.79)
SCANOUT17: length 9
  TOP w0.076: v2(165.45,15.72) 164.97,16.2 UE1.J10
  BOTTOM w0.102: JE7.9 166.9,14.38 165.56,15.72 v2(165.45,15.72)
SCL_TPM: length 3.8
  TOP w0.102: v3(142.75,32.2) 141.2,32.2 TPF4.1 140.87,32.28 140.49,31.9 140.49,31.6 140.07,31.18 UF15.30
SD3_RCOMP: length 1
  TOP w0.102: RU134.2 78.69,62.43 v2(78.78,62.53)
  BOTTOM w0.203: v2(78.78,62.53) 78.4,62.66 UU1.CJ43
SDA_TPM: length 2.2
  TOP w0.102: UF15.29 140.02,30.68 140.41,31.06 TPF3.1
SET1_HR1: length 1
  TOP w0.102: PR616.2 PR609.1
SET1_HR2: length 1
  TOP w0.102: PR620.1 PR624.2
SET2_HR1: length 1
  TOP w0.102: PR617.2 PR610.1
SET2_HR2: length 1
  TOP w0.102: PR621.1 PR625.2
SET3_HR1: length 1
  TOP w0.102: PR611.1 PR618.2
SET3_HR2: length 1
  TOP w0.102: PR622.1 PR626.2
SKTOCC_N: length 5.8
  BOTTOM w0.076: UU1.C5 110.99,44.27 111.36,44.27
  BOTTOM w0.102: TPU40.1 113.53,44.12 111.55,44.12 111.4,44.27 111.36,44.27
SLP_A_N: length 5.1
  BOTTOM w0.076: 68.77,66.41 68.77,66.2 69.03,65.94 69.03,64.76 UU1.DH47
  BOTTOM w0.102: 68.77,66.41 68.77,66.69 66.93,68.53 TPU17.1
SLP_LAN_N: length 15.1
  BOTTOM w0.102: TPU22.1 58.27,72.97 58.88,72.36 58.88,71.75 59.59,71.04 59.59,69.26 62.66,66.19 65.71,66.19 65.99,65.91 65.99,65.55 66.32,65.22 UU1.DN48
SLP_S0_N: length 270
  TOP w0.102: PR917.1 47.65,61.34 47.6,61.39 v1(47.6,61.49) 47.6,61.69 48.36,62.46 v3(50.44,62.46) 51.76,62.46 52.86,63.55 52.86,67 51.92,67.94 51.92,70.48 55.37,73.94 RU169.2 56.01,74.11 56.64,74.75 v2(56.64,75.11) ; RE115.2 167.13,24.41 167.13,24.76 166.9,24.99 166.19,24.99 164.95,26.24 164.23,26.24 v2(163.62,26.85)
  ART03 w0.089: v2(163.62,26.85) 162.96,26.85 162.33,27.48 162.33,30.22 161.19,31.37 157.02,31.37 156.77,31.11 156.77,30.71 155.75,29.69 154.94,29.69 154.07,28.83 154.07,24.99 156.06,23.01 156.06,21.92 155.6,21.46 155.6,17.24 155.14,16.79 154.38,16.79 152.14,14.55 151.69,14.55 149.65,12.52 149.35,12.52 147.27,10.44 146.25,10.44 144.94,9.13 142.39,9.13 142.25,9.27 135.08,9.27 134.57,8.76 132.94,8.76 131.52,7.34 117.9,7.34 v1(116.43,8.81) ; v2(56.64,75.11) 63.78,75.11 65.68,73.2 69.64,73.2 72.66,70.18 74.04,70.18 74.42,69.8 74.42,68.91 75.44,67.89 v2(76.45,67.89)
  ART05 w0.102: v1(47.6,61.49) 47.6,61.39 47.19,60.98 45.51,60.98 44.83,61.67 39.5,61.67 39.11,61.29 34.03,61.29 33.32,60.58 33.32,58.03 29.97,54.67 29.97,52.02 33.02,48.97 33.02,42.24 34.16,41.09 34.16,39.44 35.05,38.55 40.61,38.55 42.06,37.11 42.06,35.28 41.53,34.74 41.53,28.22 45.12,24.64 51.03,24.64 52.32,23.35 64.41,23.35 66.1,21.66 71.07,21.66 72.29,22.88 74.38,22.88 74.76,22.5 79.33,22.5 82.62,19.21 82.62,13.7 85.43,10.89 97.79,10.89 98.55,10.13 110.89,10.13 111.66,9.37 115.82,9.37 116.38,8.81 v1(116.43,8.81)
  BOTTOM w0.076: 76.45,67.76 76.45,67.38 76.96,66.88 76.96,66.75 77.07,66.63 77.07,65.67 77.16,65.09 77.16,64.39 77.47,64.08 UU1.CL45
  BOTTOM w0.102: 76.45,67.76 v2(76.45,67.89)
SLP_S0_N_EC: length 4.8
  TOP w0.076: 166.75,21.16 165.97,20.38 UE1.A12
  TOP w0.102: 166.75,21.16 167.79,22.2 v3(167.79,22.63) 167.49,22.93 RE115.1 167.74,23.54 167.77,23.57 RE459.1
SLP_S3_N: length 218.3
  TOP w0.102: v1(53.74,64.69) 53.74,59.87 52.73,58.85 v1(52.63,58.85) 51.41,58.85 51.15,59.1 v3(51,59.1) 50.65,59.1 v1(49.88,58.34) ; v2(156.46,17.19) 156.56,17.09 RE462.1
  ART03 w0.089: v1(60.55,66.37) 58.21,66.37 57.45,65.61 54.66,65.61 v1(53.74,64.69) 53.64,64.69 53.44,64.89 51.36,64.89 50.09,66.16 47.09,66.16 46.48,65.55 41.04,65.55 40.33,66.27 37.08,66.27 34.21,63.4 34.21,57.91 32.92,56.61 32.92,51.84 31.3,50.23 31.3,47.33 30.68,46.71 30.68,45.21 v1(31.11,44.78)
  ART05 w0.102: v2(66.71,69.58) 66.43,69.58 64.79,67.94 61.92,67.94 60.7,66.72 60.7,66.52 v1(60.55,66.37) 60.35,66.37 58.95,64.97 58.95,62.79 57.83,61.67 57.83,60.78 57.55,60.5 57.55,54.48 58.34,53.69 58.34,49.72 59.41,48.65 59.41,45.82 60.25,44.98 60.25,38.67 66.33,32.59 74.67,32.59 75.08,32.18 79.14,32.18 79.55,32.59 93.72,32.59 96.04,30.27 110.29,30.27 110.72,30.71 112.29,30.71 113.08,31.49 125.41,31.49 126.65,30.25 129.74,30.25 130.5,29.49 133.09,29.49 134.87,27.71 143.18,27.71 143.43,27.96 149.21,27.96 150.37,26.8 150.37,25.68 150.82,25.22 151.48,25.22 151.69,25.02 151.69,24.61 153.57,22.73 154.63,22.73 155.04,22.32 155.04,21.77 155.85,20.95 155.85,18.82 156.23,18.44 156.79,18.44 156.97,18.26 156.97,17.7 v2(156.46,17.19)
  BOTTOM w0.076: 69.16,66.74 69.16,66.39 69.59,65.96 69.59,65.06 69.97,64.68 UU1.DF47
  BOTTOM w0.102: PR913.1 v1(31.11,44.78) ; PR916.1 49.83,58.39 v1(49.88,58.34) ; RU178.1 TPU13.1 66.39,69.57 66.7,69.57 v2(66.71,69.58) 66.9,69.58 67.63,68.86 67.63,68.46 69.16,66.93 69.16,66.74 ; PR918.1 v1(52.63,58.85)
SLP_S3_N_EC: length 4.3
  TOP w0.102: RE462.2 158.49,17.09 158.6,17.19 v2(158.6,17.22) ; UE1.F4 161.57,17.74 v2(161.46,17.86)
  BOTTOM w0.102: v2(161.46,17.86) 159.21,17.86 158.6,17.24 v2(158.6,17.22)
SLP_S4_N: length 197.1
  TOP w0.102: v1(55.07,80.39) 55.83,79.63 55.83,77.85 59.43,74.24 59.68,74.24 v3(59.91,74.01) 60.4,73.52 63.59,73.52 65.3,71.8 65.3,71.42 66.42,70.3 68.04,70.3 69.21,69.14 v2(69.21,68.73) ; RE461.1 156.56,21.26 v2(156.46,21.16)
  ART03 w0.089: v1(55.07,80.39) 55.07,80.03 54.2,79.17 52.32,79.17 50.65,77.49 42.92,77.49 39.32,81.1 v1(39.32,83.44)
  ART05 w0.102: v2(156.46,21.16) 156.46,22.99 155.91,23.54 155.28,23.54 153.01,25.81 153.01,29.4 152.05,30.36 152.05,31.4 151.52,31.93 144.3,31.93 144.12,31.75 139.65,31.75 139.01,32.38 134.47,32.38 134.26,32.58 129.69,32.58 128.93,33.35 127.73,33.35 125.9,35.18 110.95,35.18 110.51,34.74 109.83,34.74 109.04,33.96 102.39,33.96 101.39,32.97 96.9,32.97 94.51,35.35 79.91,35.35 79.55,35.71 73.84,35.71 72.74,36.81 66.64,36.81 64.39,39.06 64.39,39.37 64.9,39.88 64.9,41.93 63.5,43.33 63.5,48.69 63.19,48.99 63.19,50.21 62.94,50.47 62.25,50.47 61.8,50.92 61.8,51.74 61.01,52.52 61.01,58.87 60.46,59.42 60.46,61.77 61.29,62.6 61.29,63.35 62.46,64.51 63.36,64.51 65.73,66.88 67.44,66.88 69.21,68.65 v2(69.21,68.73)
  BOTTOM w0.089: RU179.1 68.25,71.07 TPU14.1
  BOTTOM w0.102: TPU14.1 68.83,69.97 69.06,69.75 69.06,69.19 69.21,69.03 v2(69.21,68.73) 69.21,68.43 69.75,67.89 70.86,67.89 71.25,67.51 71.25,67 71.63,66.62 71.63,65.73 71.23,65.34 UU1.DC48 ; v1(39.32,83.44) 39.32,84.3 41.1,86.08 PR708.1
SLP_S4_N_EC: length 4.5
  TOP w0.076: UE1.D1 160.34,18.62 159.69,18.62 159.33,18.97
  TOP w0.102: RE461.2 157.53,21.26 158.54,20.24 158.54,19.76 159.33,18.97
SLP_S5_N: length 98.5
  TOP w0.102: RT42.2 20.64,26.17 21.14,26.17 v2(21.46,26.49) ; TPU15.1 68.88,63.45 v2(69.11,63.45) 69.11,63.19 69.47,62.84 69.82,62.84 70.1,62.56 RU180.1
  ART03 w0.089: v2(69.11,63.45) 69.11,64.18 68.45,64.84 66.55,64.84 66.17,65.22 64.84,65.22 63.29,66.77 58.27,66.77 57.3,65.81 54.38,65.81 53.72,65.15 51.46,65.15 50.24,66.37 46.63,66.37 46.02,65.76 41.3,65.76 40.59,66.47 36.88,66.47 33.15,62.74 33.15,57.88 32.28,57.02 32.28,51.81 30.8,50.33 30.8,47.4 30.22,46.83 30.22,44.63 30.96,43.89 32.76,43.89 35.53,41.12 35.53,34.54 33.01,32.01 32.32,32.01 27.3,27 27.02,27 26.36,26.34 22.91,26.34 22.55,25.98 21.97,25.98 v2(21.46,26.49)
  BOTTOM w0.102: v2(21.46,26.49) 21.16,26.18 v3(20.06,26.18) ; UU1.DF45 69.81,63.68 69.35,63.68 v2(69.11,63.45)
SLP_SUS_N: length 55.9
  TOP w0.102: TPU18.1 70.23,64.46 68.2,66.49 v2(66.5,66.49)
  ART05 w0.102: v2(53.85,78.2) 53.47,77.82 53.47,75.74 47.09,69.36 46.07,69.36 43.74,67.03 43.74,64.39 41.93,62.58 38.48,62.58 37.54,63.52 37.54,64.54 v1(37.03,65.05)
  BOTTOM w0.089: v2(66.5,66.49) 66.5,66.34 66.79,66.05 66.79,65.56 UU1.DM49
  BOTTOM w0.102: PR414.1 37.46,63.33 PR415.2 37.46,64.62 v1(37.03,65.05) ; v2(53.85,78.2) 54.25,77.8 54.25,77.24 55.07,76.43 55.62,76.43 56.28,75.77 56.51,75.77 v3(59.6,72.68) 59.6,71.79 60.15,71.24 60.15,69.37 60.6,68.92 63.87,68.92 66.01,66.77 66.34,66.77 66.5,66.62 v2(66.5,66.49)
SLP_WLAN_N: length 143.9
  TOP w0.102: v1(143.51,19.02) 143.61,18.92 144.12,18.92 144.68,18.36 RW26.1 v3(145.24,19.28)
  ART05 w0.102: v2(68.37,68.91) 66.83,67.36 62.76,67.36 60.37,64.97 60.37,62.74 59.08,61.44 59.08,55.75 59.59,55.24 59.59,49.91 61.03,48.46 61.03,47.55 60.73,47.24 60.73,45.97 61.31,45.39 61.31,42.92 62.3,41.93 62.3,38.86 67.36,33.8 94.36,33.8 96.62,31.54 102.08,31.54 102.61,32.08 109.35,32.08 110.51,33.25 111.17,33.25 111.73,33.8 125.27,33.8 127.46,31.62 132.54,31.62 134.36,29.79 140.71,29.79 v2(140.9,29.98)
  ART06 w0.102: v2(140.9,29.98) 140.9,29.58 144.37,26.11 144.37,24.71 143.71,24.05 143.71,19.94 143.46,19.68 143.46,19.07 v1(143.51,19.02)
  BOTTOM w0.076: UU1.DE49 70.6,66.05 70.36,66.29 70.36,66.93 69.9,67.38 69.7,67.38 69.57,67.51
  BOTTOM w0.102: 69.57,67.51 68.37,68.7 v2(68.37,68.91) 68.37,69.49 TPU20.1 68.32,69.9 RU177.1
SM_BAT_CLK: length 139.8
  TOP w0.076: UE1.B3 161.35,19.74 161.1,19.99 160.87,19.99 160.72,20.14 160.72,20.35 160.31,20.76 v2(160.07,20.76) 160.07,20.85 159.05,21.87
  TOP w0.102: PR163.1 PC155.1 159.05,23.09 v3(159.05,22.12) 159.05,21.87 ; PR135.1 v2(105.15,14.17) 105.8,14.17 PESD106.2
  ART06 w0.102: v2(45.97,9.6) 46.45,10.08 47.19,10.08 47.37,10.26 47.37,10.56 48.94,12.14 51.03,12.14 52.32,10.84 53.44,10.84 54.05,10.23 56.29,10.23 56.52,10.46 72.92,10.46 73.68,9.7 81.95,9.7 82.71,10.46 89.18,10.46 90.07,11.35 103,11.35 104.52,12.87 104.52,13.69 104.77,13.94 104.93,13.94 v2(105.15,14.17) 105.36,13.97 105.6,13.97 105.87,13.71 105.87,11.62 107.84,9.65 128.79,9.65 129.76,8.68 132.24,8.68 133.51,9.95 141.57,9.95 142.37,9.15 144.77,9.15 145.7,10.08 148.03,10.08 148.41,9.7 151.59,9.7 153.16,11.27 153.16,14.39 153.95,15.18 153.95,16.17 154.54,16.76 155.35,16.76 155.4,16.81 156.74,16.81 157,17.07 157,18.9 157.48,19.38 157.48,20.31 157.87,20.7 159.78,20.7 159.83,20.65 159.95,20.65 v2(160.07,20.76)
  BOTTOM w0.102: PR161.1 46.23,9.85 v2(45.97,9.6)
SM_BAT_DATA: length 138.7
  TOP w0.076: UE1.B2 160.84,19.74 160.59,19.99 160.14,19.99 v2(160.07,20.06) 159.94,20.06 159.41,20.6 159.41,20.83 158.64,21.6 158.61,21.6
  TOP w0.102: PESD106.1 105.31,13.69 v2(105.16,13.54) 105.04,13.66 PR129.1 ; 158.61,21.6 157.68,22.53 PC105.1 PR134.1
  ART06 w0.102: v1(48.13,9.6) 47.6,10.13 47.6,10.47 49.04,11.91 50.93,11.91 52.23,10.61 53.35,10.61 53.95,10.01 56.39,10.01 56.61,10.23 72.83,10.23 73.59,9.47 82.04,9.47 82.8,10.23 89.28,10.23 90.17,11.12 103.1,11.12 104.75,12.77 104.75,13.59 104.87,13.71 104.99,13.71 v2(105.16,13.54) 105.36,13.74 105.51,13.75 105.57,13.68 105.57,11.59 107.74,9.42 128.7,9.42 129.67,8.46 132.33,8.46 133.6,9.73 141.48,9.73 142.28,8.93 144.87,8.93 145.79,9.85 147.93,9.85 148.32,9.47 151.69,9.47 153.39,11.17 153.39,14.3 154.18,15.09 154.18,16.08 154.63,16.53 155.45,16.53 155.5,16.58 156.84,16.58 157.22,16.97 157.22,18.74 157.71,19.23 157.71,20.22 157.96,20.47 159.69,20.47 160.07,20.09 v2(160.07,20.06)
  BOTTOM w0.102: PR130.1 v1(48.13,9.6)
SM_BATT_SCL: length 5.5
  TOP w0.102: v1(102.11,13.66) 102.77,14.32 v3(103.07,14.32) 103.99,14.32 PR135.2
  BOTTOM w0.102: PJ101.4 100.79,13.65 PTP101.1 101.34,13.94 101.62,13.66 v1(102.11,13.66)
SM_BATT_SDA: length 4.1
  TOP w0.102: v3(102.68,12.58) v1(103.25,13.15) 103.76,13.66 PR129.2
  BOTTOM w0.102: PTP103.1 v1(103.25,13.15) 102.79,12.7 PJ101.3
SM_INTRUDER_N: length 20.7
  TOP w0.102: RU156.1 CU31.1 56.39,76.27 58.72,73.94 v3(58.72,72.97) 58.72,71.19 62.66,67.26 64.13,67.26 65.35,66.04 v2(65.35,64.16) 64.67,64.16 64.01,63.5 RU225.1
  BOTTOM w0.102: v2(65.35,64.16) 65.35,64.17 UU1.DR47
SMB_EC_SCLK: length 261.4
  TOP w0.076: v2(159.17,13.32) 159.18,13.33 159.81,13.33 160.48,13.99 160.63,13.99 160.72,14.09 160.72,14.49 UE1.M2
  TOP w0.102: RE113.1 CE375.1 159.1,13.26 v2(159.17,13.32)
  ART03 w0.089: v1(72.08,3.91) 71.93,3.76 71.93,3.22 70.97,2.26 49.43,2.26 48.65,1.48 43.83,1.48 37.59,7.72 37.59,18.77 49.88,31.06 49.88,35.58 49.64,35.82 49.64,42.56 50.09,43 50.09,43.41 49.18,44.31 48.7,44.31 48.32,44.69 48.32,45.5 50.68,47.86 50.68,49.97 51.25,50.54 51.49,50.54 51.7,50.76 51.83,50.76 v1(51.88,50.81) ; v2(159.17,13.32) 159.18,13.33 159.18,13.47 159.15,13.5 159.15,14.35 159.26,14.45 159.26,15.11 159.1,15.26 159.1,15.87 159.61,16.38 159.61,17.9 160.37,18.67 160.37,19.25 159.1,20.52 159.1,23.34 159.87,24.1 159.87,27.05 161.36,28.55 161.36,29.87 160.91,30.33 v2(160.91,30.43)
  ART05 w0.102: v1(72.08,3.91) 72.82,3.91 72.97,3.76 78.61,3.76 81.02,1.34 85.04,1.34 85.35,1.04 117.8,1.04 119.45,2.69 129.61,2.69 132.13,5.2 145.87,5.2 146.91,4.16 151.45,4.16 155.23,7.94 v1(155.23,8.91)
  ART06 w0.102: v2(142.11,51.76) 142.62,51.25 145.85,51.25 146.99,50.11 156.21,50.11 159.54,46.78 159.54,37.57 161.92,35.18 161.92,30.77 161.43,30.27 161.06,30.27 v2(160.91,30.43) ; v2(159.17,13.32) 159.18,13.3 159.18,12.19 158.88,11.88 158.88,11.38 158.24,10.74 157.73,10.74 156.34,9.34 155.67,9.34 v1(155.23,8.91)
  BOTTOM w0.102: QV3.3 143.34,51.38 142.49,51.38 v2(142.11,51.76) 142.11,52 RV24.1 ; v1(155.23,8.91) 154.73,8.4 154,8.4 153.67,8.07 153.67,6.93 153.09,6.36 US4.1 ; US1.10 68.39,3.26 68.56,3.09 68.56,2.9 68.79,2.66 71.12,2.66 71.88,3.43 71.88,3.71 v1(72.08,3.91) ; v1(51.88,50.81) 52.69,51.62 QU1.4
SMB_EC_SCLK3_R: length 9.4
  TOP w0.076: v2(165.53,19.23) 165.21,18.91 165.21,18.64 165.07,18.5 164.23,18.5 UE1.E8
  TOP w0.102: RE3.2 RE123.1 170.13,19.58 170.56,20.01 v1(170.81,20.01)
  BOTTOM w0.102: v1(170.81,20.01) 170.43,19.63 169.67,19.63 169.19,19.15 165.61,19.15 v2(165.53,19.23)
SMB_EC_SDATA: length 257.8
  TOP w0.076: UE1.C1 160.39,19.33 159.76,19.33 159.71,19.27 159.34,19.27 158.93,19.68 v2(158.93,19.89)
  TOP w0.102: v2(158.93,19.89) 158.93,20.22 158.24,20.9 158.24,21.05 157.73,21.56 156.23,21.56 v3(155.9,21.23) 155.85,21.18 RE112.1 CE374.1
  ART03 w0.089: v2(158.93,19.89) 158.93,19.94 158.89,19.97 158.89,23.43 159.65,24.19 159.65,27.14 161.15,28.64 161.15,29.55 v2(160.91,29.79) ; v2(51.86,50.21) 51.78,50.21 51.66,50.33 51.34,50.33 50.9,49.88 50.9,47.77 48.53,45.41 48.53,44.78 48.79,44.52 49.27,44.52 50.3,43.5 50.3,42.91 49.86,42.47 49.86,35.91 50.1,35.67 50.1,30.97 37.81,18.68 37.81,7.81 43.92,1.7 48.56,1.7 49.34,2.47 70.88,2.47 71.72,3.31 71.72,3.69 v1(71.5,3.91)
  ART05 w0.102: v1(71.5,3.91) 71.93,4.34 72.82,4.34 73.18,3.99 78.71,3.99 81.12,1.57 85.14,1.57 85.44,1.27 117.7,1.27 119.35,2.92 129.52,2.92 132.03,5.43 145.97,5.43 147.01,4.39 151.36,4.39 155,8.04 155,8.33 154.5,8.84 v1(154.3,8.84)
  ART06 w0.102: v2(160.91,29.79) 161.16,30.05 161.53,30.05 162.15,30.67 162.15,35.28 159.76,37.67 159.76,46.88 156.3,50.34 147.09,50.34 146.05,51.38 146.05,51.89 146.43,52.27 v2(146.56,52.27) ; v2(158.93,19.89) 158.93,19.81 158.9,19.78 158.9,18.01 159.26,17.65 159.26,15.97 159,15.72 159,15.31 159.21,15.11 159.21,14.5 158.39,13.69 158.09,13.69 157.48,13.08 157.48,11.38 156.59,10.49 155.95,10.49 v1(154.3,8.84)
  BOTTOM w0.102: v1(71.5,3.91) 71.65,3.76 71.65,3.52 71.02,2.89 68.89,2.89 68.78,2.99 68.78,3.18 68.89,3.28 US1.9 ; US4.5 153.09,7.88 154.05,8.84 v1(154.3,8.84) ; v2(146.56,52.27) 146.2,52.63 RV26.1 145.88,52.75 QV3.6 ; QU1.1 53.99,50.91 53.47,51.43 52.93,51.43 52.3,50.8 52.3,50.54 51.97,50.21 v2(51.86,50.21)
SMB_EC_SDATA3_R: length 5.4
  TOP w0.102: RE4.2 164.08,23.39 164.51,22.96 v1(164.51,22.91) ; UE1.D7 163.47,19.2 v2(163.56,19.28)
  BOTTOM w0.102: v1(164.51,22.91) 164.51,21.51 164.06,21.05 164.06,19.78 v2(163.56,19.28)
SMB_TYPEC_SCLK: length 159.6
  TOP w0.076: UE1.B4 161.97,19.86 161.72,20.11 161.72,20.72 160.66,21.79
  TOP w0.102: v2(160.32,22.78) 160.32,22.73 160.66,22.4 160.66,21.79
  ART06 w0.102: v2(160.32,22.78) 160.25,22.86 158.93,22.86 158.8,22.73 155.91,22.73 155.73,22.55 155.15,22.55 154.86,22.27 154.86,21.71 154.72,21.56 154.01,21.56 151.31,18.86 151.31,17.57 150.67,16.94 150.67,16.33 148.87,14.53 148.87,13.94 147.45,12.52 146.49,12.52 146.11,12.14 137.48,12.14 137,12.62 129.54,12.62 128.14,11.22 112.72,11.22 111.57,12.37 108.23,12.37 105.71,14.88 103.92,14.88 101.15,12.11 85.37,12.11 84.61,11.35 73.18,11.35 73,11.17 57.37,11.17 56.94,11.61 52.7,11.61 51.45,12.85 48.59,12.85 47.85,12.11 40.89,12.11 40.64,12.37 39.27,12.37 38.91,12.01 v1(38.91,11.91)
  BOTTOM w0.102: v1(38.91,11.91) 39.11,12.11 39.11,12.62 39.27,12.77 39.27,16.93 43.61,21.28 43.61,23.43 44.32,24.15 44.32,27.84 TPT17.1 43.23,28.93 43.23,30.66 43.69,31.11 RT12.1
SMB_TYPEC_SDATA: length 156.7
  TOP w0.076: UE1.A2 160.97,20.58 160.27,21.28 160.09,21.28 159.71,21.66
  TOP w0.102: 159.71,21.66 159.54,21.84 v2(159.54,22.45)
  ART06 w0.102: v1(39.5,11.91) 39.72,12.14 40.54,12.14 40.8,11.88 47.95,11.88 48.68,12.62 51.36,12.62 52.6,11.38 56.84,11.38 57.28,10.94 73.1,10.94 73.28,11.12 84.71,11.12 85.47,11.88 101.24,11.88 104.01,14.65 105.62,14.65 108.13,12.14 111.48,12.14 112.62,11 128.24,11 129.63,12.39 136.9,12.39 137.39,11.91 146.2,11.91 146.58,12.29 147.55,12.29 149.1,13.84 149.1,14.43 150.9,16.24 150.9,16.84 151.53,17.48 151.53,18.77 154.1,21.33 154.81,21.33 155.09,21.61 155.09,22.17 155.24,22.32 155.85,22.32 156.03,22.5 159.48,22.5 v2(159.54,22.45)
  BOTTOM w0.102: RT11.1 44.19,30.5 TPT16.1 44.55,30.15 44.55,24.05 43.84,23.34 43.84,21.18 39.5,16.84 39.5,12.68 39.34,12.53 39.34,12.03 39.46,11.91 v1(39.5,11.91)
SMBUS_CLK0: length 80.8
  TOP w0.102: v1(25.4,15.31) 25.4,16.13 25.07,16.46 24.9,16.46 24.66,16.69 24.66,17.14 24.76,17.24 RT37.2 ; RU41.1 67.87,53.15 v2(67.62,53.39)
  ART03 w0.089: v2(53.97,53.77) 53.84,53.9 53.71,53.9 53.59,53.78 53.59,53.06 53.19,52.65 51.66,52.65 50.77,51.76 46.28,51.76 45.68,51.17 37.5,51.17 34.63,48.3 34.63,44.36 38.19,40.8 38.19,35.32 33.88,31.01 33.88,29.44 33.83,29.38 33.83,24 30.68,20.85 30.1,20.85 27.2,17.95 27.2,16.66 26.24,15.69 25.78,15.69 v1(25.4,15.31)
  ART06 w0.102: v2(67.62,53.39) 67.73,53.39 67.83,53.49 67.83,53.56 67.84,53.62 67.7,53.76 62.75,53.76 62.63,53.64 54.97,53.64 54.72,53.9 54.1,53.9 v2(53.97,53.77)
  BOTTOM w0.102: v2(67.62,53.39) 68,53.77 UU1.DK24
SMBUS_DAT0: length 81.8
  TOP w0.102: RU42.1 68.37,53.25 v2(68.26,53.37)
  ART03 w0.089: v2(24.99,15.95) 25.03,15.91 26.15,15.91 26.99,16.75 26.99,18.04 30.01,21.07 30.59,21.07 33.62,24.09 33.62,29.47 33.67,29.53 33.67,31.1 37.97,35.41 37.97,40.71 34.42,44.27 34.42,48.39 37.41,51.38 45.59,51.38 46.19,51.98 50.53,51.98 51.42,52.87 53.1,52.87 53.38,53.15 53.38,53.87 53.64,54.14 53.81,54.14 v2(54,54.33)
  ART06 w0.102: v2(54,54.33) 54.2,54.12 54.81,54.12 55.07,53.87 62.54,53.87 62.66,53.99 67.79,53.99 68.07,53.71 68.06,53.56 68.06,53.48 68.16,53.37 v2(68.26,53.37)
  BOTTOM w0.102: UU1.DJ24 68.65,53.76 v2(68.26,53.37) ; v3(26.16,15.67) 25.88,15.95 v2(24.99,15.95) 24.99,16.48 24.76,16.71 RT38.2
SNDW_RCOMP: length 1.7
  TOP w0.102: RU137.1 73.66,59.64 73.86,59.84 73.86,60.07 v1(74.23,60.44)
  BOTTOM w0.089: v1(74.23,60.44) UU1.CV38
SNK_PS_ACK: length 32.7
  TOP w0.102: UT6.A2 31.44,7.03 31.88,7.47 v2(31.88,7.82) RT98.1
  ART03 w0.089: v2(31.88,7.82) 31.88,11.33 36.57,16.02 36.57,18.74 42.82,24.99 42.82,25.83 45.51,28.52 v2(45.72,28.52)
  BOTTOM w0.102: v2(45.72,28.52) v3(45.72,29.64) 45.72,30.36 46.35,31 RT13.2
SOC_BT_PCMCLK: length 8.9
  BOTTOM w0.102: 74.97,65.79 74.97,66.64 70.71,70.9 70.71,71.73 RU135.2
SOC_SCI_N: length 193.5
  TOP w0.102: RE87.1 154.02,5.91 154.02,5.11 154.31,4.82 155.12,4.82 DE5.2 v3(157.23,3.84) 157.31,3.76 162.69,3.76 162.94,4.01 v2(162.94,5.28) ; RU32.1 v2(59.94,78.18)
  ART05 w0.102: v2(162.94,5.28) 162.94,6.8 165.35,9.22 165.35,10.03 171.7,16.38 171.7,19.76 170.69,20.77 170.69,21.77 169.44,23.01 166.96,23.01 165.89,24.08 165.1,24.08 162.69,26.49 162.69,26.87 161.67,27.89 161.67,30.43 161.29,30.81 157.61,30.81 157.35,30.55 156.02,30.55 155.7,30.87 155.7,31.21 153.15,33.75 140.87,33.75 140.1,34.52 139.55,34.52 135.02,39.04 135.02,41.5 131.6,44.93 130.2,44.93 128.67,46.45 115.9,46.45 114.07,44.63 107.85,44.63 107.39,44.17 100.68,44.17 100.4,43.89 96.47,43.89 95.58,43 84.78,43 84.48,42.69 83.06,42.69 82.65,43.1 80.77,43.1 80.31,43.56 75.59,43.56 75.18,43.96 72.54,43.96 72.29,44.22 72.29,45.84 72.06,46.07 71.55,46.07 70.38,47.24 70.38,48.93 72.59,51.14 72.59,56.28 74.67,58.37 74.67,58.75 75.14,59.22 v2(75.14,60.58)
  ART06 w0.102: v2(75.14,60.58) 75,60.58 74.67,60.91 74.67,63.07 73.91,63.83 73.91,64.46 70.74,67.64 69.09,67.64 67.44,69.29 67.44,69.8 65.76,71.47 65.76,72.77 61.95,76.58 60.65,76.58 59.94,77.29 v2(59.94,78.18)
  BOTTOM w0.102: UU1.CR38 75.56,60.16 v2(75.14,60.58)
SPI1_CLK: length 7.6
  BOTTOM w0.102: UU1.DV16 63.73,49.84 63.24,49.35 62.1,49.35 61.34,48.59 TP183.1 RU62.2 58.8,48.36 58.7,48.26 57.61,48.26 RU55.1
SPI1_CS0_N: length 6.6
  BOTTOM w0.102: UU1.DW16 63.03,49.6 61.09,49.6 60.83,49.35 v3(60.45,49.35) TP184.1 RU63.2 58.8,49.58 58.67,49.71 57.63,49.71 RU56.1
SPKL_N1: length 39.6
  TOP w0.102: v3(187.65,42.69) 186.8,42.69 v4(186.51,42.4)
  TOP w0.203: UA2.24 173.47,24.3 172.87,23.7 v1(172.87,23.54)
  TOP w0.254: v4(186.51,42.4) 186.08,42.83 RA243.1
  ART03 w0.508: 173.36,24.05 172.9,23.58 172.9,23.57 v1(172.87,23.54)
  ART03 w0.762: 173.36,24.05 173.75,24.44 175.58,24.44 176.43,23.59 186.38,23.59 187.96,25.17 187.96,40.96 v4(186.51,42.4)
  BOTTOM w0.279: JDB1.21 184.65,42.2 ; JDB1.20 184.71,42.7
SPKL_P1: length 41.3
  TOP w0.102: v3(187.35,41.42) 186.89,41.88 186.33,41.88 185.62,42.59 185.62,43.26 v4(185.49,43.39)
  TOP w0.203: UA2.22 172.67,24.44 172.29,24.05 v1(172.01,24.05)
  TOP w0.254: RA242.1 185.38,43.51 v4(185.49,43.39)
  ART03 w0.508: v1(172.01,24.05) 172.06,24.05 172.59,24.59
  ART03 w0.762: 172.59,24.59 173.75,25.74 176.21,25.74 177.44,24.51 185.34,24.51 186.69,25.85 186.69,40.96 185.49,42.15 v4(185.49,43.39)
  BOTTOM w0.279: JDB1.18 184.68,43.7 ; JDB1.19 184.7,43.2
SPKR_N1: length 35
  TOP w0.203: UA2.25 173.87,24.24 173.63,24 173.63,23.49 v1(173.48,23.34)
  TOP w0.254: v3(185.72,40.97) v4(185.01,40.97) RA244.1
  ART06 w0.508: v1(173.48,23.34) 173.48,23.95 173.78,24.25
  ART06 w0.762: v4(185.01,40.97) 184.91,40.87 184.91,39.7 185.93,38.68 185.93,25.98 184.4,24.46 173.99,24.46 173.78,24.25
  BOTTOM w0.254: JDB1.24 184.74,40.7 v4(185.01,40.97) 184.78,41.2 JDB1.23
SPKR_P1: length 33.6
  TOP w0.203: v2(174.45,23.7) 174.67,23.92 UA2.27
  TOP w0.254: RA245.1 v4(185.77,40.1) 185.98,40.1 v3(186.28,39.8)
  ART06 w0.508: v2(174.45,23.7) 174.75,23.39
  ART06 w0.762: 174.75,23.39 177.04,23.39 177.24,23.59 185.44,23.59 187.45,25.6 187.45,38.43 v4(185.77,40.1)
  BOTTOM w0.279: JDB1.25 184.67,40.2 ; JDB1.26 184.75,39.7
SRC_PS_FLT_N: length 38.8
  TOP w0.102: UT5.A4 22.29,11.52 v1(22.5,11.3) 22.81,11.3 v3(23.16,10.94) 23.11,10.89 23.11,9.93 23.42,9.62 RT95.1
  ART03 w0.089: v1(22.5,11.3) 22.73,11.53 29.49,11.53 36,18.04 36,18.76 42.42,25.18 42.42,26.08 45.87,29.54 v2(46.73,29.54)
  BOTTOM w0.102: v2(46.73,29.54) v3(46.73,30.45) 46.73,30.8 47.17,31.23 47.17,31.87 RT15.2
SRC_PS_FO: length 43.3
  TOP w0.102: UT5.C4 20.93,10.69 21.08,10.54 v1(21.08,10.03) 21.08,9.01 RT94.1 20.67,8.86 20.61,8.93 RT92.2 20.32,8.79 v3(19.56,8.02)
  ART03 w0.089: v2(46.23,29.03) 45.69,29.03 42.63,25.97 42.63,25.11 36.25,18.73 36.25,16.26 31.27,11.28 27.25,11.28 25.58,9.6 21.51,9.6 v1(21.08,10.03)
  BOTTOM w0.102: v2(46.23,29.03) 46.23,30.58 46.86,31.22 RT14.2
SRC_PS_FO_OVP_TRIP: length 2.9
  BOTTOM w0.102: UT1.14 45.96,34.25 46.23,33.98 v3(46.23,33.5) 46.23,33.09 46.35,32.97 RT13.1 RT14.1
SRTC_RST_N: length 21.6
  TOP w0.102: CU11.1 RU89.1 55.93,77.29 59.59,73.63 v3(59.59,71.83) 59.59,70.69 62.41,67.87 64.29,67.87 68.08,64.07 v2(68.08,63.52)
  BOTTOM w0.102: v2(68.08,63.52) 68.1,63.54 UU1.DK46
SSD1_DET: length 157.1
  TOP w0.102: RN37.1 20.32,6.98 v1(20.11,6.78) RN11.1 ; 76.96,62.94 76.83,62.94 76.27,62.38 v2(75.99,62.38)
  ART03 w0.089: v2(19.18,18.87) 19.18,19.31 19.75,19.89 19.75,23.6 19.47,23.87 19.47,25.49 20.25,26.27 20.25,26.76 20.66,27.16 23.01,27.16 23.16,27.32 24.68,27.32 25.46,28.09 26.95,28.09 30.77,31.91 30.77,35.37 32.51,37.11 32.51,37.41 33.17,38.07 33.46,38.07 33.65,38.26 33.65,41.09 32.13,42.62 29.84,42.62 27.63,44.83 27.63,47.5 27.58,47.55 27.58,50.04 28.4,50.85 28.4,57.02 27.94,57.48 27.94,59.2 27.38,59.76 27.38,63.35 27.73,63.7 27.73,65.16 27.32,65.58 27.32,71.89 25.6,73.61 25.6,75.05 25.47,75.18 25.47,77.39 27,78.92 32.92,78.92 35.11,76.72 35.88,76.72 36.52,76.07 41.15,76.07 42.21,75.01 46.01,75.01 47.03,73.99 50.8,73.99 51.61,73.17 52.12,73.17 52.77,73.82 57.13,73.82 57.46,74.15 63.38,74.15 65.48,72.06 65.48,71.52 66.06,70.94 68.48,70.94 68.86,71.32 70.48,71.32 74.8,67 74.8,65 75.56,64.23 75.56,62.68 75.87,62.38 v2(75.99,62.38)
  ART06 w0.102: v2(19.18,18.87) 19.18,18.74 20.06,17.85 20.06,16.08 20.19,15.95 20.19,8.71 19.94,8.46 19.94,7.57 20.11,7.39 v1(20.11,6.78)
  BOTTOM w0.102: JSSD1.69 19.05,8.2 20.11,7.13 v1(20.11,6.78) ; UU1.CR43 v2(75.99,62.38)
  BOTTOM w0.127: JSSD1.69 19.05,9.88 19.25,10.08 19.56,10.08 20.17,10.69 v3(20.17,11.66)
SSD1_DET_R: length 7.2
  TOP w0.102: RU126.1 80.01,66.49 v2(80.01,66.65)
  BOTTOM w0.102: UU1.CE46 80.61,64.37 80.26,64.72 80.26,65.9 80.01,66.15 v2(80.01,66.65)
SSD_RST_N: length 153.1
  TOP w0.102: RN33.2 RN30.1 ; RN33.2 RN31.2 ; RN33.2 25.14,5.66 v1(24.64,6.17)
  ART03 w0.102: v2(68.25,52.42) 68.25,52.45 68.71,52.91 68.71,53.67 69.21,54.18 69.21,57.48 69.24,57.5 69.24,59.03 69.57,59.36 70.1,59.36 70.25,59.51 71.68,59.51 72.04,59.87 72.04,63.53 72.26,63.75 72.26,64.89 71.6,65.55 71.6,66.75 70.18,68.17 70.18,68.53 70.03,68.68 69.67,68.68 69.34,68.35 61.47,68.35 60.22,69.59 60.22,70.89 58.47,72.64 58.15,72.64 58.11,72.6 53.4,72.6 52.45,71.65 47.14,71.65 45.26,73.53 41.8,73.53 40.7,74.63 35.83,74.63 35.71,74.75 32.38,74.75 30.38,76.76 v1(30.38,76.88)
  ART06 w0.102: v1(30.38,76.88) 30.38,76.68 29.08,75.38 25.53,75.38 22.86,72.72 22.86,69.92 23.29,69.49 23.29,67.38 23.62,67.05 23.62,61.16 21.59,59.13 21.59,48.71 21.84,48.46 21.84,43.76 22.1,43.51 22.1,42.62 22.91,41.81 22.91,37.24 21.77,36.1 21.77,32.57 19.98,30.78 19.98,27.76 20.51,27.23 22.09,27.23 22.99,26.33 22.99,22.81 22.6,22.43 22.6,16.33 21.89,15.62 21.89,14.75 23.11,13.54 23.49,13.54 26.03,11 26.03,9.09 24.64,7.69 v1(24.64,6.17)
  BOTTOM w0.102: v2(68.25,52.42) 68,52.67 UU1.DK22
STATUS_N_U1: length 207
  TOP w0.102: v3(22.6,38.33) 22.83,38.55 v2(23.59,38.55) ; UB6.9 23.87,37.54 23.59,37.82 v2(23.59,38.55) ; RE94.1 166.37,24.15 165.96,24.56 v1(165.91,24.56) 165.91,24.46 165.81,24.36 RE127.1 ; v2(23.59,38.55) 23.87,38.83 RB49.1
  ART03 w0.089: v1(165.91,24.56) 166.01,24.56 167.76,22.81 168.91,22.81 169.23,22.49 169.23,20 170.38,18.85 170.38,15.49 170.69,15.19 170.69,6.82 167.49,3.63 156.48,3.63 155.57,4.55 150.39,4.55 149.74,3.9 148.88,3.9 148.15,3.17 145.13,3.17 144.35,3.95 136.37,3.95 133.57,1.15 110.63,1.15 v2(107.85,3.93)
  ART05 w0.102: v2(23.59,38.55) 24.55,38.55 27.18,35.93 27.18,34.24 27.68,33.73 28.32,33.73 29,33.04 29,22.25 30.61,20.65 30.61,17.85 31.11,17.35 31.11,16.33 30.73,15.95 30.73,11.92 35.04,7.62 38.63,7.62 42.29,3.96 64,3.96 65.77,5.73 67.38,5.73 68.22,6.58 80.49,6.58 82.42,4.65 92.14,4.65 92.62,5.13 100.61,5.13 101.37,4.37 107.36,4.37 107.8,3.93 v2(107.85,3.93)
STATUS_N_U1_R: length 4
  TOP w0.076: UE1.A10 164.97,20.37 165.08,20.48 165.08,21.03
  TOP w0.102: 166.52,22.63 165.66,21.77 165.66,21.61 165.08,21.03
  TOP w0.127: 166.52,22.63 166.52,23.09 166.37,23.24 RE94.2
STRAP0: length 4.5
  BOTTOM w0.102: UV2.D1 140.63,62.21 139.65,61.24 RV110.2 RV113.1
STRAP1: length 5.8
  BOTTOM w0.102: UV2.D2 141.42,61.8 140.84,61.8 139.11,60.07 RV114.1 RV111.2
STRAP2: length 12.8
  TOP w0.102: v1(143.05,62.68) 143.05,61.76 142.64,61.35 142.64,59.62 143.25,59 143.25,54.3 141.75,52.8 RV115.1 RV112.2
  BOTTOM w0.102: UV2.E4 v1(143.05,62.68)
STRAP3: length 16.5
  TOP w0.102: v3(137.72,52.55) 138.48,53.31 138.76,53.31 RV119.1 RV116.2 140.13,53.11 141.55,53.11 143,54.56 143,56.46 141.12,58.35 141.12,61.06 142.22,62.16 v1(142.22,62.65)
  BOTTOM w0.102: v1(142.22,62.65) 142.64,63.06 UV2.E3
STRAP4: length 7.4
  BOTTOM w0.102: RV117.2 RV120.1 141.73,56.59 142.37,57.22 142.37,59.38 142.19,59.55 142.19,61.77 UV2.D3
STRAP5: length 5.2
  BOTTOM w0.102: RV118.2 RV121.1 138.47,58.85 UV2.C1
SUS_CLK: length 6.1
  BOTTOM w0.076: 69.97,65.79 69.97,65.85 69.39,66.43 69.39,67 69.34,67.05
  BOTTOM w0.102: RU84.1 66.67,70.13 67.82,68.99 67.82,68.58 69.34,67.05
SUS_CLK_WLAN: length 149.1
  TOP w0.102: v3(149.16,20.15) 149.35,19.96 v1(149.35,19.53) 149.91,19.53 150.32,19.12 RW8.1
  ART05 w0.102: v2(66.67,71.57) 64.29,69.19 61.47,69.19 56.03,63.75 56.03,54.23 56.21,54.05 56.21,52.25 56.61,51.84 56.61,49.53 58.57,47.57 58.57,45.36 59.41,44.52 59.41,37.95 65.68,31.67 71.37,31.67 73.12,29.92 75.49,29.92 76.48,30.91 85.04,30.91 85.7,30.25 94.54,30.25 95.53,29.26 109.68,29.26 110.51,28.42 114.02,28.42 115.01,29.41 129.31,29.41 130.81,27.91 133.32,27.91 135.2,26.03 143.15,26.03 144.17,27.05 147.57,27.05 v2(151.46,23.16)
  ART06 w0.102: v2(151.46,23.16) 151.46,22.91 150.16,21.61 150.16,21.1 149.35,20.29 v1(149.35,19.53)
  BOTTOM w0.102: RU84.2 v2(66.67,71.57)
SUSCLK_WLAN: length 4.1
  TOP w0.102: v3(152.19,19.68) 152.02,19.5 v1(152.02,18.42) 151.99,18.4 151.5,18.4 CW8.1 RW8.2
  BOTTOM w0.102: v1(152.02,18.42) 152.02,18.4 152.46,17.96 153.28,17.96 JW1.50
SWD_CLK_CCG5_I2C_CFG_EC: length 5.1
  BOTTOM w0.102: TPT4.1 51.92,41.88 51.26,41.22 RT2.2 50.29,41.22 50.09,41.02 50.09,40.82 49.99,40.71 RT4.1 49.48,40.41 49.48,40.05 48.97,39.54 UT1.2
SYS_PEX_RST_MON_N: length 16.6
  TOP w0.102: v1(142.62,54.81) 142.24,55.19 137.67,55.19 v1(137.16,54.68) 136.04,53.57 v3(135.79,53.57)
  BOTTOM w0.102: RV251.1 142.82,55.32 142.82,55.01 v1(142.62,54.81) 142.91,54.52 RV38.1 ; UV1.4 133.3,52.8 132.92,52.43 RV2.1 RV3.1 133.51,52.56 134.26,53.31 134.26,54.1 134.85,54.68 v1(137.16,54.68)
SYS_PEX_RST_MON_N_R: length 7.3
  BOTTOM w0.102: RV251.2 143,56 143,61.54 143.28,61.82 143.89,61.82 UV2.D5
SYS_PWROK: length 134
  TOP w0.076: UE1.G1 160.27,17.24 160.09,17.42 159.21,17.42
  TOP w0.102: CU36.1 66.09,51.92 v2(65.66,51.49) 65.47,51.49 65.17,51.79 65.17,52.12 64.74,52.55 RU173.1 ; 159.21,17.42 159.03,17.6 158.34,17.6 158.16,17.42 157.55,17.42 157.4,17.57 156.23,17.57 155.8,18.01 155.5,18.01 155.34,18.16 155.34,18.46 TPE105.1 155.09,18.72 v1(154.58,18.72)
  ART03 w0.089: v1(154.58,18.72) 153.06,20.24 153.06,23.44 152.3,24.2 150.37,24.2 149.4,25.17 148.84,25.17 147.85,26.16 147.09,26.16 145.13,28.12 136.14,28.12 134.97,29.28 134.97,31.32 133.4,32.89 126.34,32.89 125.32,33.91 116.94,33.91 115.82,32.79 110.84,32.79 108.56,30.5 96.11,30.5 95.78,30.83 95.43,30.83 93.89,32.37 84.72,32.37 84.53,32.18 75.33,32.18 74.06,30.91 72.64,30.91 72.29,31.26 70.61,31.26 69.59,30.25 66.65,30.25 63.68,33.22 63.68,39.62 64.55,40.5 64.55,41.69 64.01,42.24 64.01,46.81 65.02,47.83 65.02,50.85 v2(65.66,51.49)
  BOTTOM w0.102: UU1.DP19 65.67,51.45 65.67,51.46 65.66,51.47 v2(65.66,51.49)
TBT_LSX0_RXD: length 144.7
  TOP w0.076: UT2.L7 25.4,25.87 25.4,26.59 25.53,26.72 25.53,27.07 25.68,27.23 v2(25.68,27.53)
  TOP w0.102: RU13.2 65.07,50.98 65.2,51.1 66.62,51.1 RU8.1 67.28,51.1 67.66,51.1 67.77,51 67.77,50.67 67.92,50.51 v2(68.29,50.51)
  ART03 w0.089: v2(25.68,27.53) 27.23,27.53 31.75,32.05 31.75,33.5 32.61,34.36 34.16,34.36 34.45,34.65 34.45,41.44 32.51,43.38 29.97,43.38 28.29,45.06 28.29,47.32 29.08,48.11 29.08,57.53 28.73,57.88 28.73,65.25 27.96,66.01 27.96,69.75 28.7,70.48 28.7,72.18 28.17,72.72 27.86,72.72 26.83,73.75 26.83,74.91 26.07,75.68 26.07,76.74 26.97,77.65 32.28,77.65 34.42,75.51 35.78,75.51 36.23,75.07 40.88,75.07 41.88,74.06 45.46,74.06 46.45,73.07 50.34,73.07 51.05,72.36 52.42,72.36 53.1,73.04 57.46,73.04 57.79,73.37 63.06,73.37 63.55,72.87 63.55,72.17 65.57,70.15 68.83,70.15 69.09,70.41 69.85,70.41 72.77,67.49 72.77,66.85 72.54,66.62 72.54,66.04 72.95,65.63 72.95,59.76 72.74,59.56 72.31,59.56 72.06,59.31 72.06,57.93 72.9,57.1 72.9,51.64 71.12,49.86 68.58,49.86 68.29,50.14 v2(68.29,50.51)
  BOTTOM w0.102: RT33.2 25.04,27.53 v2(25.68,27.53) ; UU1.DK17 68.29,50.46 v2(68.29,50.51)
TBT_LSX0_TXD: length 140
  TOP w0.102: UT2.M7 25.17,26.1 v2(25.17,26.87)
  ART03 w0.089: v2(25.17,26.87) 25.78,26.87 26.21,27.3 27.3,27.3 32,32 32,33.25 32.74,33.98 34.29,33.98 34.66,34.36 34.66,41.61 32.64,43.63 30.86,43.63 29.74,44.75 29.74,46.02 29,46.76 29,47.67 29.31,47.98 29.31,57.63 28.95,57.99 28.95,65.33 28.18,66.1 28.18,69.66 28.95,70.43 28.95,72.41 28.4,72.97 27.91,72.97 27.05,73.84 27.05,75 26.29,75.77 26.29,76.65 26.92,77.29 32.13,77.29 34.29,75.13 35.65,75.13 35.93,74.85 40.79,74.85 41.83,73.81 45.34,73.81 46.33,72.82 50.19,72.82 50.9,72.11 52.58,72.11 53.29,72.82 58.01,72.82 58.06,72.86 58.58,72.86 60.45,70.99 60.45,69.72 61.57,68.6 67.13,68.6 68.22,69.7 69.06,69.7 69.77,68.98 70.53,68.98 71.02,68.5 71.02,67.84 71.88,66.98 71.88,65.81 72.57,65.12 72.57,63.75 72.77,63.55 72.77,59.97 72.57,59.76 72.26,59.76 71.88,59.38 71.88,57.86 72.72,57.02 72.72,51.71 71.12,50.11 68.86,50.11 68.64,50.33 68.64,50.68 68.45,50.87 67.94,50.87 67.69,50.62 67.69,50.39 v2(67.05,49.76)
  BOTTOM w0.102: v2(67.05,49.76) 67.35,50.05 UU1.DL17 ; RT32.2 v2(25.17,26.87)
TC_RETIMER_FORCE_PWR: length 7.8
  TOP w0.076: 23.56,20.74 23.56,21.27 UT2.B10
  TOP w0.102: RT36.1 RT51.1 RT52.2 19.68,18.39 20.22,18.92 v3(20.22,19.73) 20.22,19.99 20.47,20.24 22.45,20.24 22.73,20.52 23.34,20.52 23.56,20.74
TCH_EN_EC: length 197.9
  TOP w0.076: UE1.N2 160.97,14.04 160.59,13.66
  TOP w0.102: v1(28.57,66.6) 28.8,66.82 v3(29.82,66.82) 30.22,66.42 30.22,65.76 30.63,65.35 RX922.1
  TOP w0.127: v1(157.8,10.04) 157.8,10.42 159.71,12.34 159.71,12.85 160.53,13.66 160.59,13.66
  ART03 w0.089: v1(157.8,10.04) 157.48,10.36 154.46,10.36 152.55,8.46 151.51,8.46 151.13,8.07 149.46,8.07 149.03,8.51 148.18,8.51 146.78,7.11 138.05,7.11 137.42,7.74 135.83,7.74 135.25,7.16 134.1,7.16 132.82,5.88 115.84,5.88 114.92,6.8 110.51,6.8 110.18,7.13 107.44,7.13 106.78,7.8 105.81,7.8 105.26,7.24 v2(102.56,7.24)
  ART05 w0.102: v2(102.56,7.24) 102.21,7.59 89.22,7.59 88.2,8.61 73.41,8.61 72.8,9.22 65.18,9.22 62.41,6.45 50.61,6.45 49.82,7.24 42.29,7.24 39.88,9.65 38.74,9.65 36.07,12.32 36.07,13.54 33.83,15.77 33.83,32.28 31.75,34.36 31.75,35.38 29.21,37.92 29.21,42.24 28.83,42.62 28.83,44.19 28.07,44.96 28.07,47.72 27.61,48.18 27.61,55.62 28.45,56.46 28.45,61.41 27.66,62.2 27.66,63.04 28.57,63.95 v1(28.57,66.6)
TCH_EN_SOC: length 73.2
  TOP w0.102: v3(29.87,68.25) 29.87,67.99 30.99,66.88 v1(30.99,66.47) RX923.1
  ART03 w0.089: v1(33.65,78.81) 35.51,76.96 40.57,76.96 42.3,75.24 46.05,75.24 47.08,74.2 56.98,74.2 57.31,74.53 63.54,74.53 65.48,72.59 69.72,72.59 75.18,67.13 75.44,67.13 78.4,64.16 v2(79.06,64.16)
  ART05 w0.102: v1(33.65,78.81) 33.65,77.16 36.47,74.34 36.47,67.89 36.14,67.56 32.64,67.56 31.54,66.47 v1(30.99,66.47)
  BOTTOM w0.102: UU1.CH45 v2(79.06,64.16)
TCP0_ATEST_N: length 3.9
  TOP w0.102: TPT8.1 28.85,18.59 28.85,19.65 UT2.A2
TCP0_ATEST_P: length 5.9
  TOP w0.102: TPT7.1 31.24,17.09 29.51,18.82 29.51,19.45 UT2.A1
TCP0_AUX_DN: length 96
  TOP w0.076: 24.79,26.81 24.79,26.79 24.77,26.77 24.77,26.59 arc(24.79,26.49) 24.85,26.4 24.86,26.39 arc(24.92,26.3) 24.94,26.19 24.94,26.03 arc(24.93,25.99) 24.9,25.95 24.89,25.93 arc(24.86,25.91) 24.82,25.91 24.81,25.91 arc(24.77,25.91) 24.74,25.93 24.74,25.94 arc(24.72,25.97) 24.71,26.01 UT2.M8
  TOP w0.102: 24.79,26.81 24.79,27.05 25.17,27.43 25.17,27.58 25.83,28.24 25.83,29.06 26.03,29.26 26.03,30.43 26.43,30.82 28.89,30.82 30.69,32.62 32.31,32.62 v1(32.49,32.44)
  ART06 w0.102: v2(92.8,44.36) 92.8,44.47 92.69,44.57 92.55,44.57 92.44,44.46 92.44,40.92 90.23,38.71 85.06,38.71 84.78,38.43 82.42,38.43 81.38,37.39 80.24,37.39 79.75,36.9 79.75,36.01 77.9,34.16 76.91,34.16 73.84,31.09 71.52,31.09 69.92,29.49 64.79,29.49 63.45,28.14 50.93,28.14 47.17,24.38 45.9,24.38 43.19,21.66 42.09,21.66 41.3,20.88 37.46,20.88 35.18,23.15 35.18,31.29 33.84,32.63 32.68,32.63 v1(32.49,32.44)
  BOTTOM w0.076: UU1.AY5 92.34,44.08 v2(92.8,44.36)
TCP0_AUX_DP: length 96.3
  TOP w0.076: 24.58,26.81 24.58,26.79 24.6,26.77 24.6,26.54 arc(24.59,26.47) 24.55,26.41 24.54,26.4 arc(24.5,26.34) 24.48,26.27 24.48,26.01 arc(24.51,25.87) 24.59,25.76 UT2.L8
  TOP w0.102: v1(32.49,33.02) 32.31,32.84 30.61,32.84 28.8,31.04 26.34,31.04 25.82,30.52 25.82,29.35 25.61,29.14 25.61,28.33 24.95,27.67 24.95,27.52 24.58,27.14 24.58,26.81
  ART06 w0.102: v1(32.49,33.02) 32.67,32.85 33.93,32.85 35.39,31.38 35.39,23.24 37.54,21.09 41.21,21.09 42,21.88 43.1,21.88 45.81,24.6 47.08,24.6 50.84,28.36 63.36,28.36 64.7,29.7 69.83,29.7 71.44,31.3 73.75,31.3 76.82,34.38 77.81,34.38 79.54,36.1 79.54,36.99 80.16,37.6 81.29,37.6 82.33,38.64 84.69,38.64 84.97,38.92 90.14,38.92 92.22,41.01 92.22,44.55 92.46,44.79 92.69,44.79 92.8,44.89 v2(92.8,45.01)
  BOTTOM w0.076: UU1.AY6 92.34,44.73 v2(92.8,45.01)
TCP0_CC1_CONN: length 18.3
  TOP w0.102: v3(10.36,20.6) 9.85,20.6 v1(9.65,20.39)
  TOP w0.203: UT7.4 10.09,10.47 v1(9.8,10.18) 9.37,10.61 RT114.2 RT111.2
  TOP w0.254: JT1.A5 8.45,20.16 8.48,20.19 9.45,20.19 v1(9.65,20.39)
  ART05 w0.381: v1(9.8,10.18) 9.02,10.97 9.02,17.35 9.37,17.7 9.37,18.46 9.65,18.74 v1(9.65,20.39)
  BOTTOM w0.203: v1(9.8,10.18) 10.34,9.65 10.34,9.09 10.06,8.81 CT79.1 9.53,8.63 ESDT6.2
TCP0_CC1_PD: length 67.8
  TOP w0.203: UT7.12 14.5,10.47
  TOP w0.254: RT111.1 8.48,11.25 7.34,10.11 7.34,8.79 8.63,7.49 v3(9.4,7.49) 9.57,7.49 v1(10.06,7.97) ; v2(14.91,9.73) 14.91,10.06 14.5,10.47
  ART03 w0.254: 40.41,26.87 39.11,25.58 39.11,22.93
  ART03 w0.381: 40.41,26.87 40.79,27.25 42.21,27.25 48.89,33.93 v1(48.89,34.87) ; v2(19.4,13.18) 19.86,13.18 20.22,13.54 23.37,13.54 24.18,12.72 29.21,12.72 33.07,16.58 33.07,16.89 39.11,22.93
  BOTTOM w0.254: v1(10.06,7.97) 10.44,7.59 11.02,7.59 11.3,7.87 11.3,8.53 12.24,9.47 v3(12.75,9.47) 14.4,9.47 14.55,9.62 14.81,9.62 v2(14.91,9.73) 15.49,10.31 15.49,11.5 16.56,12.57 17.37,12.57 17.88,13.08 17.88,13.94 18.13,14.2 18.59,14.2 19.4,13.38 v2(19.4,13.18) ; CT16.1 49.48,34.11 48.89,34.69 v1(48.89,34.87) 48.89,35.71 48.56,36.04 UT1.9
TCP0_CC2_CONN: length 16.6
  TOP w0.203: v1(8.02,9.73) 8.28,9.98 RT116.2 RT112.2 9.32,9.98 9.55,9.75 10.03,9.75 10.35,10.07 UT7.5
  TOP w0.254: v2(7.14,18.67) 7.06,18.67 6.82,18.91 JT1.B5
  ART06 w0.381: v1(8.02,9.73) 8.02,10.49 7.42,11.09 7.42,11.63 7.9,12.11 7.97,12.11 8.74,12.88 8.74,17.19 8.24,17.69 8.24,17.79 7.36,18.67 v2(7.14,18.67)
  BOTTOM w0.203: v1(8.02,9.73) 7.92,9.62 7.92,8.71 8.18,8.46 CT80.1 8.61,8.46 8.68,8.52 ESDT6.1
TCP0_CC2_PD: length 60.2
  TOP w0.203: UT7.11 14.18,10.07 v2(14.27,9.98)
  TOP w0.254: RT112.1 9.14,9.37 9.65,8.86 10.18,8.86 v1(10.79,9.47)
  ART03 w0.254: 37.84,22.63 37.84,26.85 38.66,27.66
  ART03 w0.381: 38.66,27.66 39.14,28.14 41.02,28.14 47.7,34.82 47.7,35.13 v1(49.22,36.65) ; 37.84,22.63 32.45,17.23 32.45,16.82 28.85,13.23 24.48,13.23 23.67,14.04 19.66,14.04 v2(19.56,13.94)
  BOTTOM w0.254: CT17.1 v1(49.22,36.65) 48.83,37.04 UT1.7 ; v1(10.79,9.47) 11.53,9.47 12.04,9.98 v2(14.27,9.98) 14.43,9.98 15.09,10.64 15.09,11.61 16.51,13.03 17.27,13.03 17.52,13.28 17.52,14.35 18.13,14.96 v3(18.54,14.96) 18.91,14.59 18.91,14.46 19.43,13.94 v2(19.56,13.94)
TCP0_RESET_N: length 4.3
  TOP w0.076: UT2.L11 23.1,25.87 22.29,25.87
  TOP w0.102: 22.29,25.87 21.74,25.32 v3(21.38,25.32) 21.28,25.42 21.28,25.78 21.08,25.98 RT42.1 RT41.1
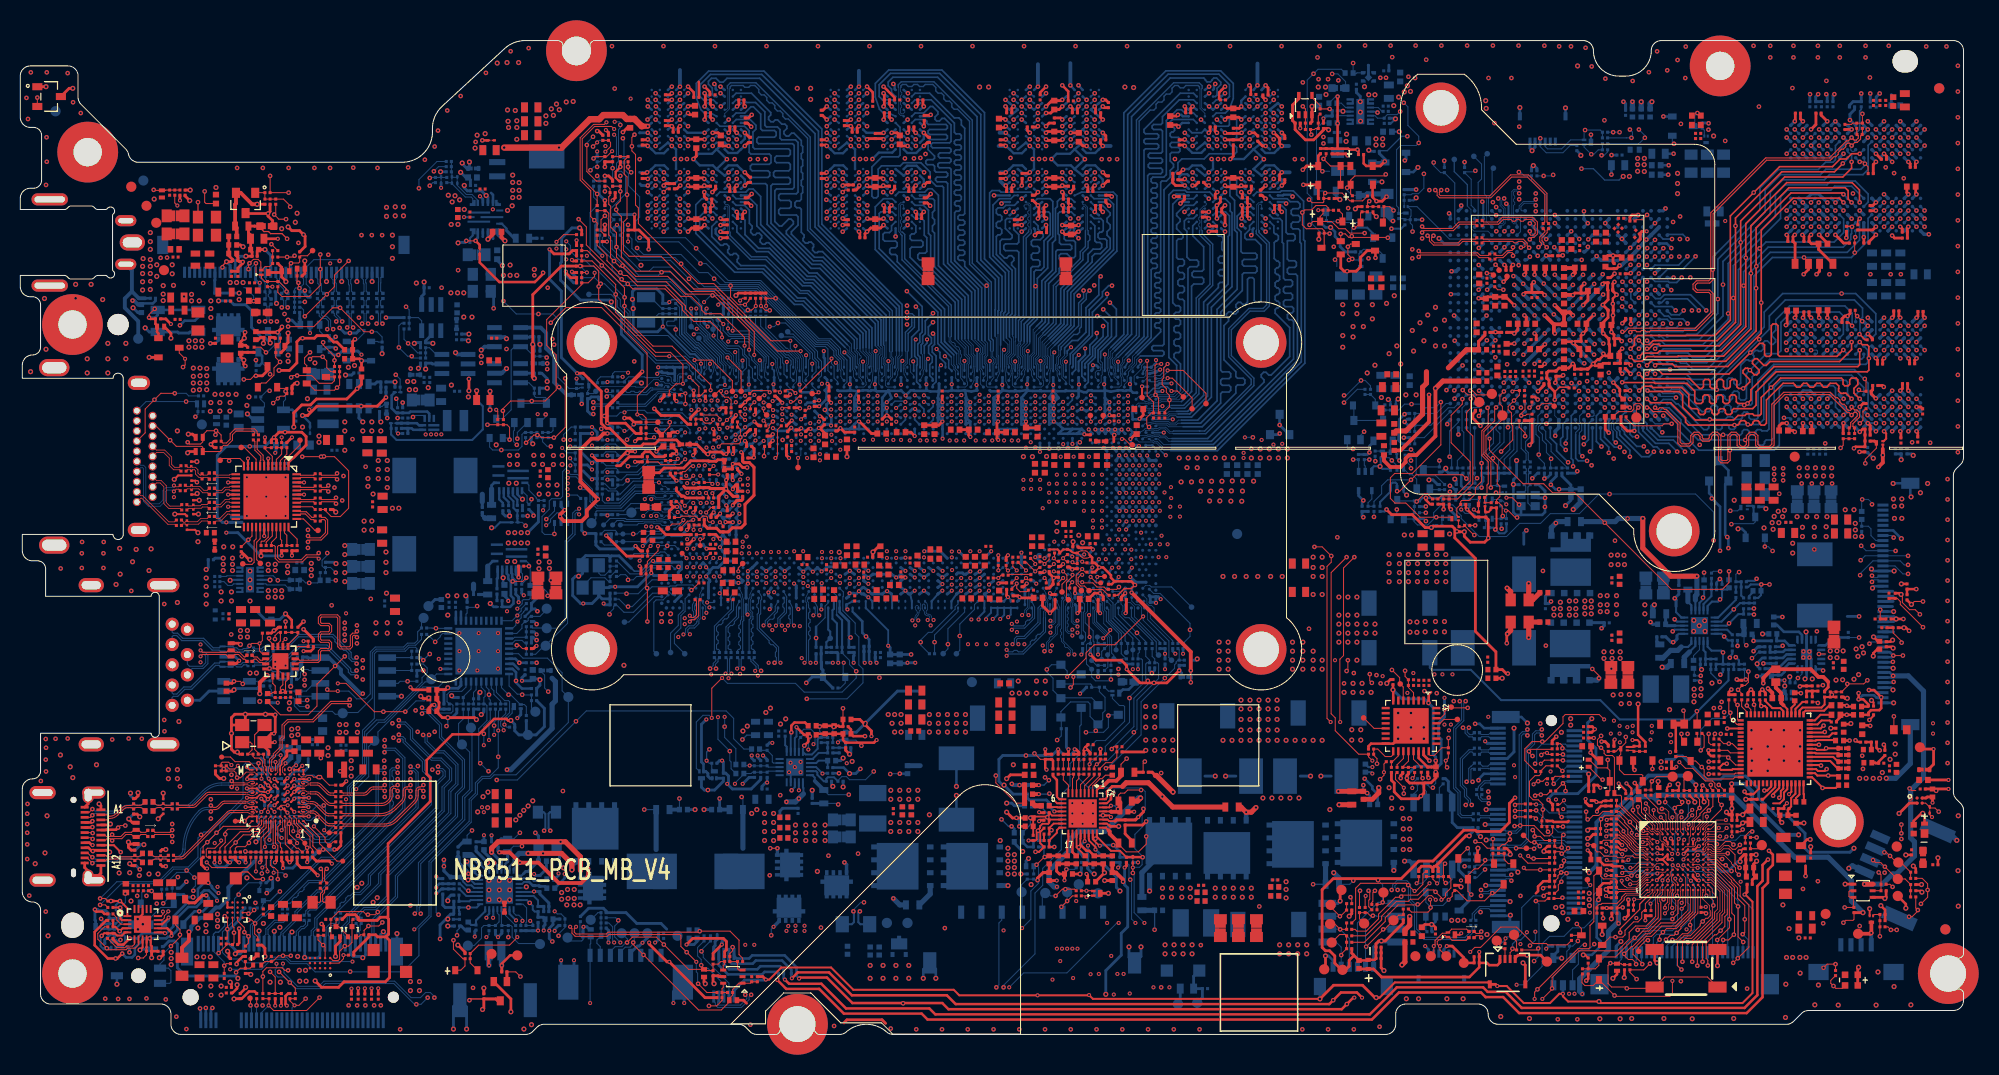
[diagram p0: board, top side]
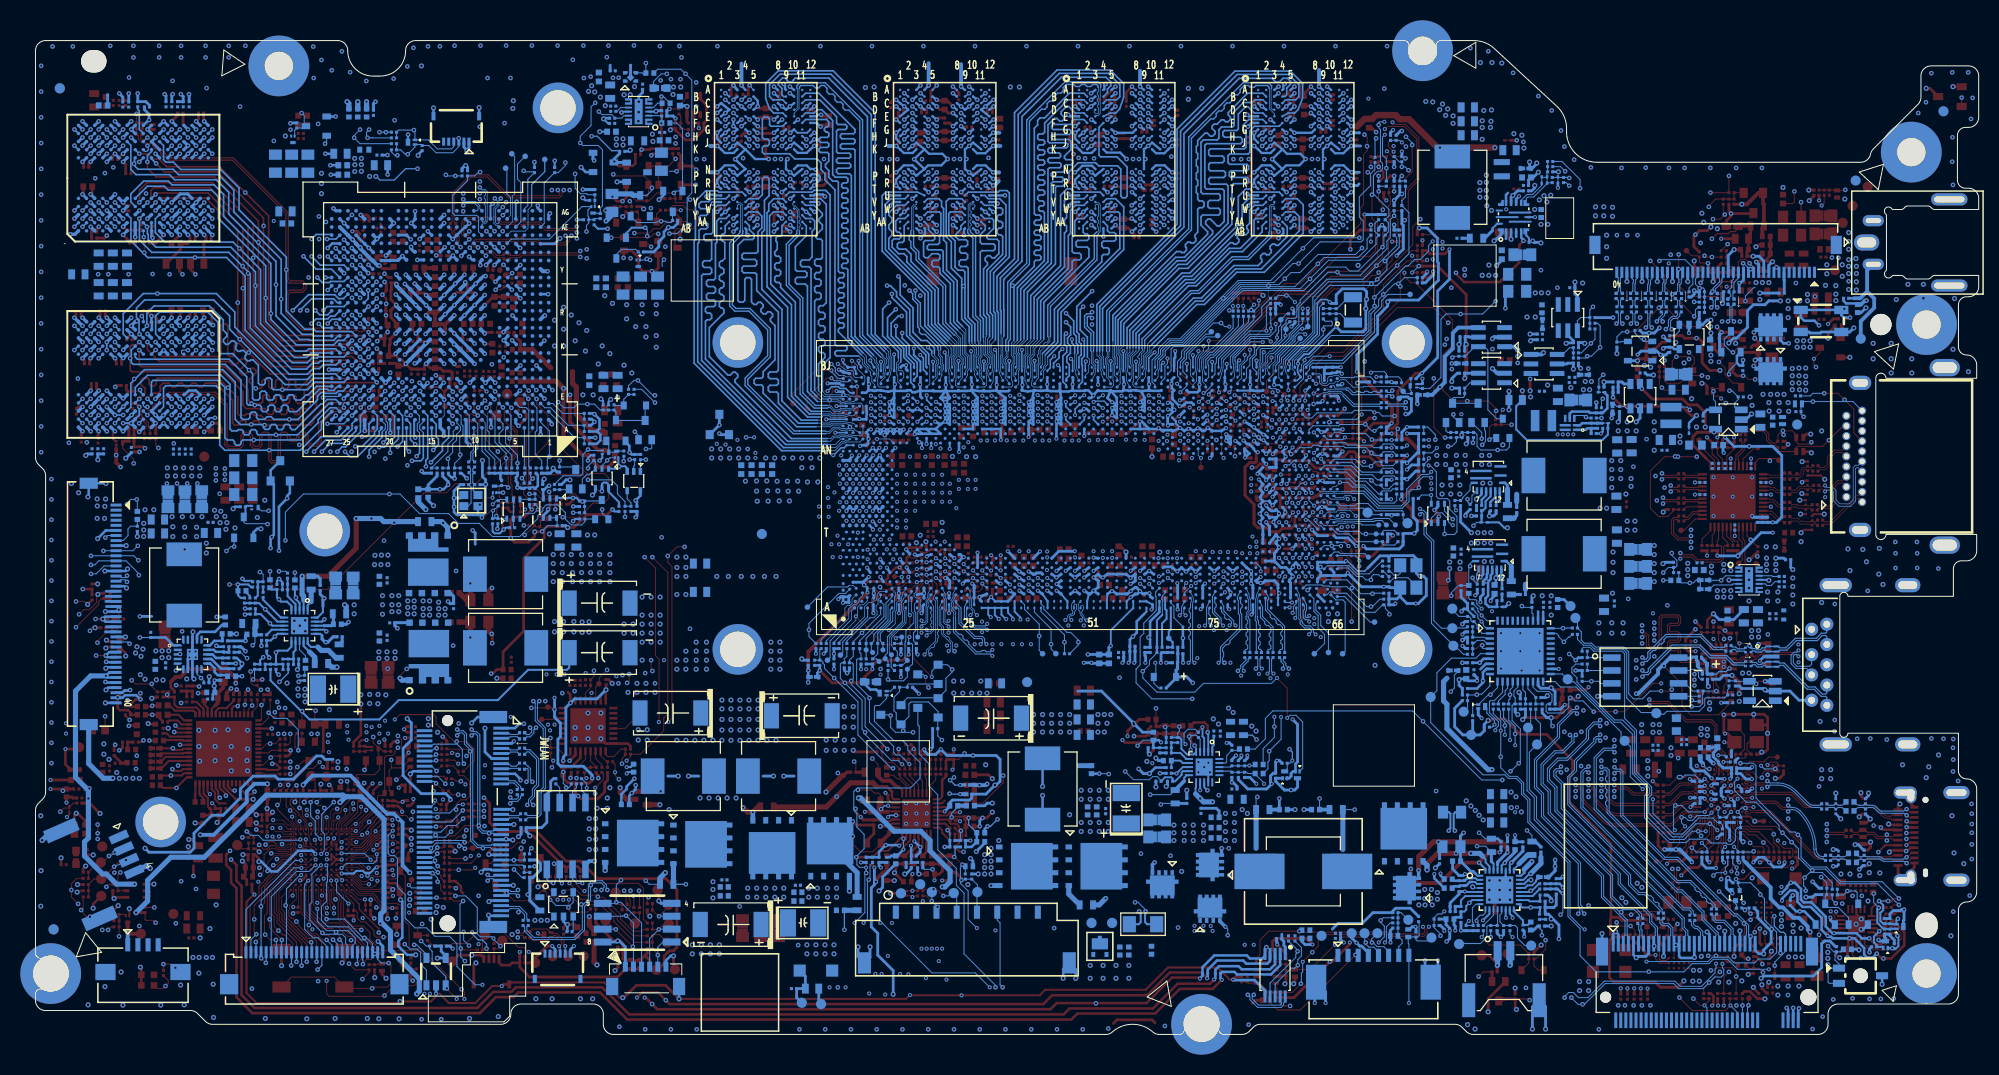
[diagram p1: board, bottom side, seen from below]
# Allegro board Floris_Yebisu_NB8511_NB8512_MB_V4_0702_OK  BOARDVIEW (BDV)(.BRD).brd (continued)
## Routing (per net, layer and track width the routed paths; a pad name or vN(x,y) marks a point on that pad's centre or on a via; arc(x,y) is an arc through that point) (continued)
TCP0_RT_TX0_DN: length 8.5
  TOP w0.076: 22.16,23.67 22.17,23.67 22.2,23.69 22.43,23.69 arc(22.5,23.68) 22.56,23.64 22.57,23.63 arc(22.63,23.59) 22.7,23.57 22.95,23.57 arc(23.09,23.6) 23.21,23.68 UT2.G11
  TOP w0.102: RT27.1 15.57,22.32 arc(15.65,22.36) 15.73,22.38 17.02,22.38 arc(17.21,22.42) 17.37,22.53 18.43,23.58 arc(18.52,23.65) 18.63,23.67 22.16,23.67
TCP0_RT_TX0_DN_C: length 2.2
  TOP w0.102: CT69.1 13.28,22.23 arc(13.44,22.34) 13.64,22.38 13.81,22.38 arc(13.91,22.36) 14,22.3 ESDT3.1 14.19,22.3 arc(14.28,22.36) 14.38,22.38 14.84,22.38 RT27.2
TCP0_RT_TX0_DN_CONN: length 5
  TOP w0.102: JT1.A3 8.51,21.16 arc(8.54,21.16) 8.58,21.19 8.66,21.27 arc(8.69,21.29) 8.73,21.3 8.83,21.3 arc(9.25,21.38) 9.61,21.62 10.15,22.17 arc(10.37,22.31) 10.63,22.36 10.91,22.36 arc(11.04,22.34) 11.15,22.26 RT131.1 arc(11.34,22.34) 11.53,22.38 11.78,22.38 arc(11.95,22.35) 12.1,22.25 CT69.2
TCP0_RT_TX0_DP: length 8.5
  TOP w0.076: 22.16,23.88 22.17,23.88 22.2,23.86 22.38,23.86 arc(22.48,23.88) 22.57,23.94 22.58,23.95 arc(22.67,24.01) 22.77,24.03 22.93,24.03 arc(22.98,24.02) 23.02,23.99 23.03,23.98 arc(23.05,23.95) 23.06,23.91 23.06,23.9 arc(23.05,23.86) 23.04,23.83 23.03,23.83 arc(23,23.81) 22.96,23.8 UT2.G12
  TOP w0.102: 22.16,23.88 18.63,23.88 arc(18.44,23.84) 18.27,23.73 17.22,22.68 arc(17.13,22.62) 17.02,22.6 15.73,22.6 arc(15.65,22.61) 15.57,22.66 RT26.1
TCP0_RT_TX0_DP_C: length 2.2
  TOP w0.102: CT68.1 13.28,22.75 arc(13.44,22.64) 13.64,22.6 13.81,22.6 arc(13.91,22.62) 14,22.68 ESDT2.1 14.19,22.68 arc(14.28,22.62) 14.38,22.6 14.84,22.6 RT26.2
TCP0_RT_TX0_DP_CONN: length 5
  TOP w0.102: CT68.2 12.1,22.73 arc(11.95,22.63) 11.78,22.6 11.53,22.6 arc(11.34,22.64) RT132.1 11.09,22.66 arc(11,22.6) 10.89,22.58 10.63,22.58 arc(10.29,22.51) 10,22.32 9.46,21.78 arc(9.17,21.58) 8.83,21.51 8.73,21.51 arc(8.69,21.52) 8.66,21.54 8.58,21.63 arc(8.54,21.65) 8.51,21.66 JT1.A2
TCP0_RT_TX1_DN: length 11.9
  TOP w0.076: UT2.E11 23.21,23 arc(23.09,23.08) 22.95,23.1 22.7,23.1 arc(22.63,23.09) 22.57,23.05 22.56,23.04 arc(22.5,23) 22.43,22.98 22.2,22.98 22.17,23.01 22.16,23.01
  TOP w0.102: v1(18.79,22.57) 18.89,22.47 arc(18.99,22.41) 19.1,22.39 19.22,22.39 arc(19.33,22.41) 19.43,22.47 19.81,22.86 arc(19.98,22.97) 20.17,23.01 22.16,23.01
  BOTTOM w0.102: RT31.1 15.21,17.56 arc(15.26,17.53) 15.32,17.52 15.34,17.52 arc(15.59,17.57) 15.8,17.71 arc(15.98,17.97) 16.04,18.27 arc(16.44,20.31) 17.6,22.05 17.62,22.06 arc(17.98,22.3) 18.4,22.39 18.49,22.39 arc(18.6,22.41) 18.69,22.47 v1(18.79,22.57)
TCP0_RT_TX1_DN_C: length 2
  BOTTOM w0.102: CT71.1 13.03,17.67 arc(13.19,17.56) 13.39,17.52 13.66,17.52 arc(13.72,17.53) 13.78,17.57 ESDT9.1 13.91,17.57 arc(13.96,17.53) 14.03,17.52 14.36,17.52 arc(14.45,17.53) 14.52,17.58 RT31.2
TCP0_RT_TX1_DN_CONN: length 6.3
  TOP w0.102: v1(7.11,17.47) 7.06,17.47 6.63,17.91 JT1.B3
  BOTTOM w0.102: v1(7.11,17.47) 7.21,17.37 arc(7.3,17.31) 7.42,17.29 9.35,17.29 arc(9.41,17.3) 9.46,17.34 9.53,17.41 arc(9.66,17.49) 9.8,17.52 10.95,17.52 arc(11.14,17.56) RT133.1 arc(11.45,17.54) 11.63,17.5 arc(11.91,17.6) CT71.2
TCP0_RT_TX1_DP: length 11.9
  TOP w0.076: UT2.E12 22.96,22.88 arc(23,22.87) 23.03,22.85 23.04,22.84 arc(23.05,22.81) 23.06,22.78 23.06,22.76 arc(23.05,22.73) 23.03,22.7 23.02,22.68 arc(22.98,22.66) 22.93,22.65 22.77,22.65 arc(22.67,22.67) 22.58,22.73 22.57,22.74 arc(22.48,22.8) 22.38,22.82 22.2,22.82 22.17,22.79 22.16,22.79
  TOP w0.102: 22.16,22.79 20.17,22.79 arc(20.06,22.77) 19.97,22.71 19.58,22.32 arc(19.41,22.21) 19.22,22.17 19.1,22.17 arc(18.99,22.15) 18.89,22.09 v1(18.79,21.99)
  BOTTOM w0.102: v1(18.79,21.99) 18.69,22.09 arc(18.6,22.15) 18.49,22.17 18.4,22.17 arc(18.06,22.1) 17.77,21.91 17.75,21.89 arc(16.64,20.23) 16.25,18.27 arc(16.18,17.89) 15.96,17.56 arc(15.67,17.37) 15.34,17.3 15.33,17.3 arc(15.26,17.29) 15.2,17.25 RT30.1
TCP0_RT_TX1_DP_C: length 2
  BOTTOM w0.102: CT70.1 13.03,17.15 arc(13.19,17.26) 13.39,17.3 13.66,17.3 arc(13.72,17.29) 13.78,17.25 ESDT8.1 13.91,17.25 arc(13.96,17.29) 14.03,17.3 14.36,17.3 arc(14.45,17.28) 14.52,17.24 RT30.2
TCP0_RT_TX1_DP_CONN: length 6.3
  TOP w0.102: v1(7.11,16.89) 6.59,17.41 JT1.B2
  BOTTOM w0.102: v1(7.11,16.89) 7.21,16.99 arc(7.3,17.05) 7.42,17.07 9.35,17.07 arc(9.49,17.1) 9.61,17.18 9.69,17.25 arc(9.74,17.29) 9.8,17.3 10.95,17.3 arc(11.14,17.26) RT134.1 arc(11.45,17.25) 11.63,17.28 11.68,17.28 arc(11.93,17.19) CT70.2
TCP0_RT_TXRX0_DN: length 8.9
  TOP w0.076: 22.05,24.59 22.07,24.59 22.06,24.6 22.08,24.62 22.41,24.62 arc(22.49,24.6) 22.56,24.56 22.57,24.55 arc(22.63,24.51) 22.7,24.49 22.95,24.49 arc(23.09,24.52) 23.21,24.6 UT2.J11
  TOP w0.102: v1(20.85,24.4) 21.04,24.59 22.05,24.59
  BOTTOM w0.102: v1(20.85,24.4) 20.75,24.5 arc(20.65,24.57) 20.54,24.59 19.86,24.59 arc(18.95,24.41) 18.17,23.89 16.96,22.67 arc(16.64,22.46) 16.25,22.38 15.73,22.38 arc(15.65,22.36) 15.57,22.32 RT25.1
TCP0_RT_TXRX0_DN_C: length 2.2
  BOTTOM w0.102: RT25.2 14.9,22.32 arc(14.83,22.36) 14.74,22.38 14.27,22.38 ESDT5.1 14,22.3 arc(13.91,22.36) 13.81,22.38 13.64,22.38 arc(13.44,22.34) 13.28,22.23 CT63.1
TCP0_RT_TXRX0_DN_CONN: length 6.5
  TOP w0.102: JT1.B10 6.9,21.41 v1(7.11,21.61)
  BOTTOM w0.102: v1(7.11,21.61) 7.22,21.72 arc(7.32,21.79) 7.44,21.81 9.59,21.81 arc(9.78,21.85) 9.94,21.96 10.28,22.3 arc(10.38,22.36) 10.49,22.38 10.77,22.38 arc(10.98,22.34) RT115.1 11.25,22.32 arc(11.33,22.36) 11.41,22.38 11.76,22.38 arc(11.95,22.34) 12.12,22.23 CT63.2
TCP0_RT_TXRX0_DP: length 9
  TOP w0.076: 22.05,24.81 22.07,24.81 22.1,24.78 22.39,24.78 arc(22.49,24.8) 22.57,24.86 22.58,24.87 arc(22.67,24.93) 22.77,24.95 22.93,24.95 arc(23,24.94) 23.06,24.9 arc(23.08,24.87) 23.09,24.83 23.09,24.82 arc(23.08,24.79) 23.06,24.76 arc(23.06,24.76) 23.06,24.75 23.05,24.75 arc(23.02,24.73) 22.98,24.72 UT2.J12
  TOP w0.102: 22.05,24.81 21.03,24.81 v1(20.85,24.99)
  BOTTOM w0.102: v1(20.85,24.99) 20.75,24.89 arc(20.65,24.83) 20.54,24.8 19.86,24.8 arc(18.87,24.61) 18.02,24.04 16.81,22.83 arc(16.55,22.66) 16.25,22.6 15.73,22.6 arc(15.65,22.61) 15.57,22.66 RT24.1
TCP0_RT_TXRX0_DP_C: length 2.2
  BOTTOM w0.102: RT24.2 14.9,22.66 arc(14.83,22.61) 14.74,22.6 14.27,22.6 ESDT4.1 14,22.68 arc(13.91,22.62) 13.81,22.6 13.64,22.6 arc(13.44,22.64) 13.28,22.75 CT62.1
TCP0_RT_TXRX0_DP_CONN: length 6.6
  TOP w0.102: JT1.B11 6.79,21.91 v1(7.11,22.22)
  BOTTOM w0.102: CT62.2 12.12,22.75 arc(11.95,22.64) 11.76,22.6 11.41,22.6 arc(11.33,22.61) 11.25,22.66 RT113.1 arc(10.98,22.63) 10.77,22.6 10.49,22.6 arc(10.29,22.56) 10.13,22.45 9.79,22.11 arc(9.7,22.05) 9.59,22.03 7.44,22.03 arc(7.32,22.05) 7.22,22.12 v1(7.11,22.22)
TCP0_RT_TXRX1_DN: length 10.2
  TOP w0.076: 21.92,22.09 21.94,22.09 21.97,22.06 22.43,22.06 arc(22.5,22.08) 22.56,22.12 22.57,22.13 arc(22.63,22.17) 22.7,22.18 22.95,22.18 arc(23.09,22.16) 23.21,22.08 UT2.C11
  TOP w0.102: RT29.1 15.19,17.58 arc(15.26,17.53) 15.35,17.52 15.87,17.52 arc(15.98,17.54) 16.08,17.6 20.42,21.94 arc(20.58,22.05) 20.78,22.09 21.92,22.09
TCP0_RT_TXRX1_DN_C: length 2
  TOP w0.102: RT29.2 14.52,17.58 arc(14.45,17.53) 14.36,17.52 14.03,17.52 arc(13.96,17.53) 13.91,17.57 ESDT11.1 13.78,17.57 arc(13.72,17.53) 13.66,17.52 13.39,17.52 arc(13.19,17.56) 13.03,17.67 CT65.1
TCP0_RT_TXRX1_DN_CONN: length 4.4
  TOP w0.102: JT1.A10 8.39,17.66 arc(8.45,17.64) 8.5,17.61 8.56,17.55 arc(8.59,17.52) 8.63,17.52 10.95,17.52 arc(11.14,17.56) RT119.1 11.39,17.58 arc(11.45,17.53) 11.53,17.52 arc(11.7,17.55) 11.84,17.65 CT65.2
TCP0_RT_TXRX1_DP: length 10.3
  TOP w0.076: 21.92,21.87 21.94,21.87 21.97,21.9 22.38,21.9 arc(22.48,21.88) 22.57,21.82 22.58,21.81 arc(22.67,21.75) 22.77,21.73 22.93,21.73 arc(22.99,21.74) 23.03,21.77 23.04,21.78 arc(23.06,21.81) 23.07,21.84 23.07,21.86 arc(23.06,21.89) 23.04,21.92 23.04,21.93 arc(23,21.95) 22.97,21.96 UT2.C12
  TOP w0.102: 21.92,21.87 20.78,21.87 arc(20.66,21.85) 20.57,21.79 16.23,17.45 arc(16.07,17.34) 15.87,17.3 15.35,17.3 arc(15.26,17.28) 15.19,17.24 RT28.1
TCP0_RT_TXRX1_DP_C: length 2
  TOP w0.102: CT64.1 13.03,17.15 arc(13.19,17.26) 13.39,17.3 13.66,17.3 arc(13.72,17.29) 13.78,17.25 ESDT10.1 13.91,17.25 arc(13.96,17.29) 14.03,17.3 14.36,17.3 arc(14.45,17.28) 14.52,17.24 RT28.2
TCP0_RT_TXRX1_DP_CONN: length 4.4
  TOP w0.102: CT64.2 11.84,17.17 arc(11.7,17.27) 11.53,17.3 arc(11.45,17.29) 11.39,17.24 RT118.1 arc(11.14,17.26) 10.95,17.3 8.66,17.3 arc(8.59,17.29) 8.54,17.25 8.5,17.21 arc(8.44,17.17) 8.37,17.16 JT1.A11
TCP0_SBU1: length 41.3
  TOP w0.102: RT120.1 8.38,13.41 v1(7.87,13.41) ; UT2.M10 23.49,26.39 v1(23.49,26.74) ; v2(14.07,12.11) 14.07,11.86 13.88,11.67 UT7.15
  ART06 w0.102: v1(7.87,13.41) 7.49,13.41 6.75,12.67 6.75,10.94 7.16,10.53 7.16,8.63 7.66,8.13 8.59,8.13 9.1,8.63 11.13,8.63 14.07,11.57 v2(14.07,12.11)
  BOTTOM w0.102: v1(23.49,26.74) 22.22,26.74 21.97,26.49 21.97,23.31 18.62,19.96 18.11,19.96 v3(17.83,19.68) 17.52,19.38 17.52,17.47 16.56,16.51 15.03,16.51 13.59,15.06 9.52,15.06 v1(7.87,13.41)
TCP0_SBU1_CONN: length 17.6
  TOP w0.203: v1(9.9,17.98) 9.23,18.66 JT1.A8 ; RT120.2 v1(9.83,13.15) 9.85,13.15 10.56,12.45 UT7.1
  ART06 w0.254: v1(7.97,11.4) 9.24,12.67 9.24,17.32 v1(9.9,17.98)
  BOTTOM w0.102: v1(9.83,13.15) v3(8.94,13.15)
  BOTTOM w0.203: v1(7.97,11.4) 8.11,11.27 ESDT7.2 8.45,10.87 8.51,10.92 RT122.2 CT72.1 9.42,10.92 9.7,11.2 9.7,11.99 9.42,12.27 9.42,12.75 v1(9.83,13.15)
TCP0_SBU2: length 40.5
  TOP w0.102: UT2.L10 v2(23.79,25.22) ; v2(14.6,12.14) 14.6,12.09 14.21,11.69 14.21,11.49 13.99,11.27 UT7.14 ; v1(7.87,12.77) 8.38,12.77 RT121.1
  ART06 w0.102: v1(7.87,12.77) 7.24,12.77 6.96,12.49 6.96,11.02 7.36,10.61 7.36,8.71 7.75,8.33 8.51,8.33 9.02,8.84 11.05,8.84 13.71,11.5 13.71,12.39 13.84,12.52 14.22,12.52 v2(14.6,12.14)
  BOTTOM w0.102: v1(7.87,12.77) 9.95,14.86 13.67,14.86 15.12,16.3 16.64,16.3 17.78,17.44 17.78,18.31 v3(19.35,19.89) 19.69,20.22 19.69,20.62 21.98,22.91 22.93,22.91 24.08,24.05 24.08,24.93 v2(23.79,25.22)
TCP0_SBU2_CONN: length 21.5
  TOP w0.203: RT121.2 9.68,12.52 9.7,12.49 v1(9.85,12.49) 9.88,12.47 9.88,11.4 10.01,11.27 UT7.2
  TOP w0.254: v1(7.11,20.44) 7.07,20.41 JT1.B8
  ART06 w0.254: v1(9.85,12.49) 10.31,12.95 10.31,14.27 10.26,14.32 10.26,17.5 10.41,17.65 10.41,18.01 11.22,18.82 11.22,19.59 9.54,21.28 8.25,21.28 7.41,20.44 v1(7.11,20.44)
  BOTTOM w0.102: v1(9.85,12.49) 10.36,13 v3(10.36,13.89)
  BOTTOM w0.203: v1(9.85,12.49) 10.01,12.34 10.01,11.02 9.37,10.39 CT73.1 RT123.2 8.73,10.42 ESDT7.1
TCP0_THERMDA: length 4
  TOP w0.102: UT2.M11 23.33,26.15 22.58,26.9 21.18,26.9 20.72,27.35 TPT6.1
TCP0_TX0_C_DN: length 4.2
  TOP w0.076: UT2.J2 27.59,24.6 arc(27.7,24.52) 27.84,24.49 28.1,24.49 arc(28.17,24.51) 28.23,24.55 28.24,24.56 arc(28.3,24.6) 28.37,24.61 28.6,24.61 28.62,24.59 28.64,24.59
  TOP w0.102: 28.64,24.59 29.29,24.59 arc(29.4,24.57) 29.49,24.5 30.26,23.74 arc(30.42,23.63) 30.62,23.59 30.87,23.59 arc(30.96,23.57) 31.03,23.52 CT18.2
TCP0_TX0_C_DP: length 4.2
  TOP w0.076: 28.64,24.8 28.62,24.8 28.6,24.78 28.42,24.78 arc(28.32,24.8) 28.23,24.86 28.22,24.87 arc(28.13,24.93) 28.02,24.95 27.86,24.95 arc(27.81,24.94) 27.76,24.91 27.75,24.9 arc(27.73,24.87) 27.72,24.83 27.72,24.82 arc(27.73,24.78) 27.75,24.75 arc(27.79,24.73) 27.84,24.72 UT2.J1
  TOP w0.102: CT19.2 31.03,23.87 arc(30.96,23.82) 30.87,23.8 30.62,23.8 arc(30.51,23.83) 30.41,23.89 29.65,24.65 arc(29.48,24.76) 29.29,24.8 28.64,24.8
TCP0_TX0_DN: length 73.7
  TOP w0.102: v1(35.95,24.01) 35.85,24.11 arc(35.75,24.17) 35.64,24.19 34.83,24.19 arc(34.72,24.17) 34.62,24.11 34.25,23.74 arc(34.09,23.63) 33.89,23.59 31.86,23.59 arc(31.77,23.57) 31.7,23.52 CT18.1
  ART06 w0.102: v1(35.95,24.01) 36.06,24.12 arc(36.14,24.18) 36.24,24.2 36.27,24.2 arc(36.34,24.17) 36.37,24.1 36.37,23.34 arc(36.44,23) 36.63,22.72 37.58,21.77 arc(37.85,21.59) 38.16,21.52 40.41,21.52 arc(40.71,21.58) 40.97,21.76 41.3,22.09 arc(41.59,22.28) 41.93,22.35 42.26,22.35 arc(42.85,22.47) 43.35,22.8 45.67,25.12 arc(45.84,25.23) 46.03,25.27 arc(46.49,25.36) 46.88,25.62 47.8,26.54 arc(47.94,26.64) 48.1,26.67 48.11,26.67 arc(48.41,26.73) 48.66,26.9 50.49,28.72 arc(50.61,28.8) 50.75,28.83 61.56,28.83 arc(62.58,29.03) 63.44,29.61 arc(64.07,30.03) 64.81,30.17 68.37,30.17 arc(69.18,30.33) 69.87,30.8 70.5,31.43 arc(70.91,31.7) 71.4,31.8 72.27,31.8 arc(72.73,31.89) 73.12,32.15 74.12,32.88 76.29,35.06 arc(76.84,35.43) 77.5,35.56 arc(78.22,35.7) 78.83,36.11 arc(79.01,36.37) 79.07,36.68 79.07,37.09 arc(79.11,37.29) 79.22,37.46 79.58,37.82 arc(80.08,38.16) 80.68,38.28 arc(81.08,38.35) 81.41,38.58 81.67,38.84 arc(82.29,39.25) 83.01,39.39 88.82,39.39 arc(89.7,39.57) 90.44,40.06 90.62,40.24 arc(91.28,41.23) 91.51,42.4 91.51,44.42 arc(91.56,44.53) 91.68,44.58 91.77,44.58 arc(91.84,44.55) 91.87,44.48 v2(91.87,44.36)
  BOTTOM w0.076: UU1.BB5 v2(91.87,44.36)
TCP0_TX0_DP: length 73.7
  TOP w0.102: v1(35.95,24.59) 35.85,24.49 arc(35.75,24.43) 35.64,24.41 34.83,24.41 arc(34.63,24.37) 34.47,24.26 34.1,23.89 arc(34.01,23.83) 33.89,23.8 31.86,23.8 arc(31.77,23.82) 31.7,23.87 CT19.1
  ART06 w0.102: v2(91.87,45.01) 91.87,44.99 arc(91.81,44.85) 91.68,44.8 arc(91.41,44.69) 91.3,44.42 91.3,42.4 arc(91.08,41.31) 90.46,40.39 90.29,40.22 arc(89.61,39.77) 88.82,39.61 83.01,39.61 arc(82.2,39.45) 81.52,38.99 81.26,38.73 arc(80.99,38.55) 80.68,38.49 arc(80,38.36) 79.42,37.97 79.07,37.62 arc(78.91,37.38) 78.85,37.09 78.85,36.68 arc(78.81,36.45) 78.68,36.26 arc(78.14,35.9) 77.5,35.77 arc(76.76,35.63) 76.14,35.21 73.97,33.05 73.05,32.37 73.03,32.37 72.97,32.3 arc(72.65,32.09) 72.27,32.01 71.4,32.01 arc(70.83,31.9) 70.35,31.58 69.72,30.95 arc(69.1,30.53) 68.37,30.39 64.81,30.39 arc(63.98,30.22) 63.29,29.76 arc(62.49,29.23) 61.56,29.04 50.75,29.04 arc(50.52,29) 50.33,28.87 48.51,27.05 arc(48.33,26.93) 48.11,26.88 48.1,26.88 arc(47.86,26.83) 47.65,26.7 46.73,25.78 arc(46.41,25.56) 46.03,25.49 arc(45.76,25.43) 45.52,25.27 43.2,22.95 arc(42.77,22.67) 42.26,22.57 41.93,22.57 arc(41.51,22.48) 41.15,22.24 40.82,21.91 arc(40.63,21.78) 40.41,21.74 38.16,21.74 arc(37.93,21.79) 37.73,21.92 36.78,22.87 arc(36.64,23.09) 36.59,23.34 36.59,24.1 arc(36.49,24.32) 36.27,24.41 36.12,24.41 v1(35.95,24.59)
  BOTTOM w0.076: UU1.BB6 91.7,44.9 v2(91.87,45.01)
TCP0_TX1_C_DN: length 4.3
  TOP w0.076: UT2.C2 27.59,21.84 arc(27.7,21.76) 27.84,21.73 28.1,21.73 arc(28.17,21.75) 28.23,21.79 28.24,21.8 arc(28.3,21.84) 28.37,21.85 28.6,21.85 28.62,21.83 28.64,21.83
  TOP w0.102: 28.64,21.83 28.87,21.83 arc(28.98,21.81) 29.08,21.74 30.11,20.71 arc(30.27,20.61) 30.45,20.57 arc(30.55,20.57) 30.65,20.56 30.9,20.56 arc(30.94,20.56) 30.98,20.53 CT23.2
TCP0_TX1_C_DP: length 4.3
  TOP w0.076: 28.64,22.04 28.62,22.04 28.6,22.02 28.42,22.02 arc(28.32,22.04) 28.23,22.1 28.22,22.11 arc(28.13,22.17) 28.02,22.19 27.86,22.19 arc(27.79,22.17) 27.74,22.14 arc(27.72,22.11) 27.71,22.07 27.71,22.06 arc(27.72,22.02) 27.73,21.99 arc(27.77,21.97) 27.82,21.96 UT2.C1
  TOP w0.102: 28.64,22.04 28.87,22.04 arc(29.07,22) 29.23,21.89 29.76,21.37 30.26,20.86 arc(30.35,20.8) 30.45,20.78 30.83,20.78 arc(30.98,20.82) CT22.2
TCP0_TX1_DN: length 76.9
  TOP w0.102: v1(39.76,24.01) 39.66,24.11 arc(39.56,24.17) 39.45,24.19 39.38,24.19 arc(39.28,24.15) 39.24,24.06 39.24,23.54 arc(39.17,23.17) 38.96,22.85 37.16,21.06 arc(36.59,20.67) 35.91,20.54 31.86,20.54 arc(31.77,20.52) 31.7,20.47 CT23.1
  ART06 w0.102: v1(39.76,24.01) 39.86,24.11 arc(39.95,24.17) 40.06,24.19 40.23,24.19 arc(40.41,24.23) 40.56,24.32 40.62,24.39 arc(40.7,24.44) 40.79,24.46 41.77,24.46 arc(42.07,24.52) 42.32,24.69 45.21,27.57 arc(45.29,27.64) 45.38,27.68 45.5,27.73 arc(45.8,27.79) 46.05,27.96 47.17,29.08 arc(47.31,29.18) 47.47,29.21 arc(47.75,29.26) 47.99,29.43 48.86,30.29 arc(49.52,30.73) 50.29,30.88 60.64,30.88 arc(61.4,31.04) 62.05,31.47 62.16,31.58 arc(63.9,32.74) 65.94,33.14 68.43,33.14 arc(68.77,33.2) 69.07,33.38 69.07,33.38 69.13,33.44 arc(69.54,33.71) 70.02,33.8 70.45,33.8 arc(71.21,33.96) 71.85,34.39 arc(72.25,34.65) 72.72,34.74 arc(73,34.8) 73.24,34.96 73.49,35.21 arc(73.73,35.77) 73.5,36.33 arc(73.5,36.34) 73.49,36.34 arc(73.49,36.34) 73.49,36.34 arc(73.43,36.44) 73.4,36.56 73.4,36.74 arc(73.45,36.98) 73.59,37.18 73.87,37.46 arc(73.94,37.51) 74.02,37.52 74.04,37.52 arc(74.12,37.54) 74.19,37.59 74.25,37.65 arc(74.3,37.72) 74.32,37.8 74.32,37.82 arc(74.33,37.9) 74.38,37.97 74.44,38.04 arc(74.51,38.08) 74.59,38.1 74.61,38.1 arc(74.69,38.12) 74.76,38.16 74.83,38.23 arc(74.88,38.3) 74.89,38.38 74.89,38.48 75.17,38.76 arc(75.81,39.19) 76.57,39.34 arc(76.8,39.39) 76.99,39.52 arc(77.33,39.74) 77.73,39.82 78.14,39.82 arc(78.58,39.91) 78.94,40.16 79.06,40.27 arc(80.22,41.05) 81.6,41.32 81.76,41.32 arc(83.1,41.59) 84.23,42.35 84.86,42.98 arc(85.06,43.27) 85.13,43.61 85.13,44.09 arc(85.19,44.38) 85.35,44.64 85.48,44.76 arc(85.55,44.81) 85.63,44.82 85.65,44.82 arc(85.74,44.84) 85.81,44.89 85.87,44.95 arc(85.91,45.02) 85.93,45.1 85.93,45.12 arc(85.95,45.21) 86,45.28 86.57,45.85 arc(86.93,46.09) 87.35,46.17 87.47,46.17 arc(87.53,46.16) 87.58,46.13 87.59,46.12 arc(87.64,46.08) 87.7,46.07 87.88,46.07 arc(87.93,46.08) 87.98,46.12 88,46.13 arc(88.05,46.16) 88.1,46.17 89.07,46.17 arc(89.13,46.16) 89.18,46.13 89.19,46.12 arc(89.24,46.08) 89.3,46.07 89.48,46.07 arc(89.53,46.08) 89.58,46.12 89.6,46.13 arc(89.65,46.16) 89.7,46.17 90.1,46.17 arc(90.18,46.16) 90.24,46.12 90.25,46.1 arc(90.32,46.06) 90.39,46.05 90.51,46.05 arc(90.58,46.06) 90.65,46.1 90.66,46.12 arc(90.72,46.16) 90.8,46.17 91.11,46.17 arc(91.19,46.16) 91.25,46.12 91.26,46.1 arc(91.33,46.06) 91.4,46.05 91.52,46.05 arc(91.59,46.06) 91.66,46.1 91.67,46.12 arc(91.73,46.16) 91.81,46.17 92.48,46.17 arc(92.55,46.16) 92.61,46.12 92.63,46.1 arc(92.69,46.06) 92.76,46.05 92.88,46.05 arc(92.96,46.06) 93.02,46.1 93.03,46.12 arc(93.1,46.16) 93.17,46.17 93.42,46.17 arc(93.67,46.12) 93.88,45.98 93.97,45.9 arc(94.03,45.8) 94.05,45.68 94.05,44.96 arc(94.04,44.89) 94,44.84 94,44.83 arc(93.95,44.8) 93.89,44.78 93.8,44.78 arc(93.73,44.81) 93.7,44.89 v2(93.7,45.01)
  BOTTOM w0.076: UU1.AV6 v2(93.7,45.01)
TCP0_TX1_DP: length 76.9
  TOP w0.102: v1(39.76,24.59) 39.66,24.49 arc(39.56,24.43) 39.45,24.41 39.38,24.41 arc(39.13,24.3) 39.03,24.06 39.03,23.54 arc(38.97,23.25) 38.8,23 37.01,21.21 arc(36.51,20.87) 35.91,20.76 31.86,20.76 arc(31.77,20.77) 31.7,20.82 CT22.1
  ART06 w0.102: v1(39.76,24.59) 39.86,24.49 arc(39.95,24.43) 40.06,24.41 40.23,24.41 arc(40.33,24.43) 40.4,24.48 40.47,24.54 arc(40.61,24.64) 40.79,24.67 41.77,24.67 arc(41.99,24.72) 42.17,24.84 45.13,27.8 arc(45.3,27.91) 45.5,27.95 arc(45.71,27.99) 45.9,28.12 47.02,29.24 arc(47.22,29.38) 47.47,29.42 arc(47.67,29.46) 47.84,29.58 48.71,30.44 arc(49.43,30.93) 50.29,31.1 60.64,31.1 arc(61.32,31.23) 61.9,31.62 62.01,31.73 arc(63.81,32.94) 65.94,33.36 68.43,33.36 arc(68.69,33.41) 68.93,33.54 68.94,33.55 arc(68.96,33.57) 68.97,33.58 68.98,33.59 arc(69.46,33.91) 70.02,34.02 70.45,34.02 arc(71.13,34.16) 71.7,34.54 arc(72.17,34.85) 72.72,34.96 arc(72.92,35) 73.09,35.12 73.34,35.37 arc(73.51,35.77) 73.34,36.18 73.34,36.19 arc(73.34,36.19) 73.34,36.19 arc(73.23,36.36) 73.19,36.56 73.19,36.74 arc(73.25,37.06) 73.43,37.33 75.02,38.91 arc(75.73,39.39) 76.57,39.56 arc(76.71,39.59) 76.84,39.67 arc(77.25,39.94) 77.73,40.04 78.14,40.04 arc(78.49,40.11) 78.79,40.31 78.9,40.42 arc(80.14,41.25) 81.6,41.54 81.76,41.54 arc(83.02,41.79) 84.08,42.5 84.71,43.13 arc(84.86,43.35) 84.91,43.61 84.91,44.09 arc(84.99,44.47) 85.2,44.79 86.42,46 arc(86.84,46.29) 87.35,46.39 93.42,46.39 arc(93.75,46.32) 94.04,46.14 94.12,46.05 arc(94.23,45.88) 94.27,45.68 94.27,44.96 arc(94.24,44.81) 94.16,44.68 94.15,44.67 arc(94.03,44.6) 93.89,44.57 arc(93.76,44.51) 93.7,44.37 v2(93.7,44.36)
  BOTTOM w0.076: v2(93.7,44.36) 93.53,44.25 UU1.AV5
TCP0_TXRX0_C_DN: length 4.3
  TOP w0.076: UT2.G2 27.59,23.92 arc(27.7,24) 27.84,24.02 28.1,24.02 arc(28.17,24.01) 28.23,23.97 28.24,23.96 arc(28.3,23.92) 28.37,23.9 28.6,23.9 28.62,23.93 28.64,23.93
  TOP w0.102: CT21.2 31.03,22.85 arc(30.96,22.8) 30.87,22.79 30.62,22.79 arc(30.51,22.81) 30.41,22.87 29.5,23.78 arc(29.34,23.89) 29.14,23.93 28.64,23.93
TCP0_TXRX0_C_DP: length 4.2
  TOP w0.076: UT2.G1 27.84,23.8 arc(27.8,23.79) 27.77,23.77 27.76,23.76 arc(27.74,23.73) 27.74,23.7 27.74,23.68 arc(27.74,23.65) 27.76,23.62 27.78,23.6 arc(27.82,23.58) 27.86,23.57 28.02,23.57 arc(28.13,23.59) 28.22,23.65 28.23,23.66 arc(28.32,23.72) 28.42,23.74 28.6,23.74 28.62,23.71 28.64,23.71
  TOP w0.102: 28.64,23.71 29.14,23.71 arc(29.26,23.69) 29.35,23.63 30.26,22.72 arc(30.42,22.61) 30.62,22.57 30.87,22.57 arc(30.96,22.55) 31.03,22.51 CT20.2
TCP0_TXRX0_DN: length 69.3
  TOP w0.102: CT21.1 31.7,22.85 arc(31.77,22.8) 31.86,22.79 35.64,22.79 arc(35.92,22.84) 36.16,23 36.32,23.16 arc(36.42,23.32) 36.46,23.5 36.46,24.08 arc(36.58,24.36) 36.85,24.48 37.06,24.48 arc(37.07,24.48) 37.09,24.48 37.13,24.51 v1(37.22,24.59)
  ART06 w0.102: v2(88.56,40.83) 88.51,40.89 arc(88.48,40.93) 88.47,40.99 88.47,41.21 arc(88.36,41.46) 88.11,41.56 87.13,41.56 arc(86.22,41.38) 85.44,40.86 85.38,40.8 85.38,40.8 arc(84.83,40.46) 84.19,40.35 82.77,40.35 arc(80.96,39.98) 79.42,38.96 arc(79.1,38.74) 78.72,38.67 arc(78.24,38.57) 77.83,38.3 77.76,38.23 arc(77.66,38.16) 77.53,38.14 arc(77.23,38.07) 76.96,37.9 76.65,37.59 arc(76.46,37.3) 76.39,36.95 76.39,36.83 arc(76.32,36.48) 76.12,36.19 73.66,33.72 arc(73.48,33.61) 73.27,33.56 arc(73.03,33.51) 72.82,33.38 arc(72.07,32.88) 71.19,32.7 70.89,32.7 arc(70.3,32.58) 69.8,32.25 arc(69.51,32.06) 69.17,31.99 68.32,31.99 arc(67.73,31.87) 67.22,31.53 arc(66.94,31.34) 66.61,31.28 64.78,31.28 arc(63.9,31.1) 63.15,30.6 arc(62.18,29.96) 61.04,29.73 50.69,29.73 arc(50.13,29.62) 49.65,29.3 48.05,27.7 arc(47.94,27.62) 47.8,27.59 arc(47.58,27.55) 47.4,27.43 46.75,26.78 arc(46.59,26.67) 46.39,26.63 46.28,26.63 arc(45.93,26.56) 45.64,26.37 42.91,23.64 arc(42.52,23.37) 42.04,23.28 41.93,23.28 arc(41.25,23.14) 40.67,22.75 40.52,22.6 arc(40.25,22.42) 39.94,22.36 38.81,22.36 arc(38.7,22.38) 38.6,22.45 38.17,22.88 arc(38.05,23.06) 38.01,23.27 38.01,24.03 arc(37.9,24.3) 37.63,24.41 37.52,24.41 arc(37.41,24.43) 37.32,24.49 v1(37.22,24.59)
  BOTTOM w0.076: v2(88.56,40.83) 88.47,40.93 arc(88.42,41) 88.41,41.08 88.41,41.13 arc(88.42,41.18) 88.45,41.23 88.52,41.3 arc(88.6,41.42) 88.63,41.57 88.63,41.6 arc(88.65,41.71) 88.72,41.8 88.74,41.82 arc(88.79,41.91) 88.81,42.01 88.81,42.32 arc(88.78,42.47) 88.7,42.59 UU1.BH2
TCP0_TXRX0_DP: length 69.3
  TOP w0.102: CT20.1 31.7,22.51 arc(31.77,22.55) 31.86,22.57 35.64,22.57 arc(36,22.64) 36.31,22.85 36.47,23.01 arc(36.62,23.23) 36.68,23.5 36.68,24.08 arc(36.73,24.21) 36.85,24.26 36.96,24.26 v1(37.22,24.01)
  ART06 w0.102: v2(87.98,40.83) 88.14,40.96 arc(88.22,41.06) 88.25,41.19 88.25,41.21 arc(88.21,41.31) 88.11,41.35 87.13,41.35 arc(86.3,41.18) 85.59,40.71 85.53,40.65 85.53,40.65 arc(85.53,40.65) 85.52,40.64 arc(84.9,40.26) 84.19,40.13 82.77,40.13 arc(81.04,39.79) 79.57,38.81 arc(79.18,38.54) 78.72,38.45 arc(78.32,38.37) 77.98,38.15 77.91,38.08 arc(77.74,37.96) 77.53,37.92 arc(77.31,37.87) 77.12,37.75 76.8,37.43 arc(76.66,37.21) 76.6,36.95 76.6,36.83 arc(76.52,36.4) 76.27,36.03 73.81,33.57 arc(73.57,33.41) 73.27,33.35 arc(73.11,33.32) 72.98,33.22 arc(72.16,32.68) 71.19,32.48 70.89,32.48 arc(70.38,32.38) 69.95,32.09 arc(69.59,31.86) 69.17,31.77 68.32,31.77 arc(67.81,31.67) 67.37,31.38 arc(67.02,31.14) 66.61,31.06 64.78,31.06 arc(63.98,30.9) 63.3,30.45 arc(62.26,29.76) 61.04,29.51 50.69,29.51 arc(50.21,29.42) 49.8,29.14 49.41,28.75 arc(49.38,28.7) 49.36,28.64 49.36,28.62 arc(49.35,28.57) 49.32,28.52 49.19,28.39 arc(49.14,28.36) 49.09,28.35 49.07,28.35 arc(49.01,28.33) 48.96,28.3 48.83,28.17 arc(48.8,28.13) 48.79,28.07 48.79,28.05 arc(48.78,27.99) 48.75,27.94 48.62,27.82 arc(48.57,27.78) 48.51,27.77 48.49,27.77 arc(48.43,27.76) 48.39,27.73 48.21,27.55 arc(48.02,27.42) 47.8,27.38 arc(47.67,27.35) 47.56,27.28 46.9,26.62 arc(46.67,26.47) 46.39,26.41 46.28,26.41 arc(46.02,26.36) 45.8,26.22 43.07,23.48 arc(42.6,23.17) 42.04,23.06 41.93,23.06 arc(41.33,22.94) 40.82,22.6 40.67,22.45 arc(40.33,22.23) 39.94,22.15 38.81,22.15 arc(38.61,22.18) 38.45,22.3 38.02,22.73 arc(37.85,22.98) 37.79,23.27 37.79,24.03 arc(37.74,24.14) 37.63,24.19 37.52,24.19 arc(37.41,24.17) 37.32,24.11 v1(37.22,24.01)
  BOTTOM w0.076: v2(87.98,40.83) 88.06,40.83 arc(88.12,40.84) 88.17,40.88 88.19,40.89 arc(88.23,40.95) 88.24,41.02 88.24,41.13 arc(88.26,41.24) 88.33,41.35 88.4,41.42 arc(88.45,41.49) 88.47,41.57 88.47,41.61 arc(88.44,41.72) 88.38,41.81 88.36,41.84 arc(88.29,41.94) 88.26,42.07 88.26,42.12 arc(88.31,42.24) 88.44,42.29 88.46,42.29 arc(88.55,42.25) 88.58,42.17 UU1.BH1
TCP0_TXRX1_C_DN: length 4.3
  TOP w0.076: UT2.E2 27.59,22.76 arc(27.7,22.68) 27.84,22.65 28.1,22.65 arc(28.17,22.67) 28.23,22.71 28.24,22.72 arc(28.3,22.76) 28.37,22.77 28.6,22.77 28.62,22.75 28.64,22.75
  TOP w0.102: CT25.2 31.03,21.49 arc(30.96,21.54) 30.87,21.56 30.4,21.56 arc(30.2,21.59) 30.04,21.7 29.15,22.59 arc(28.98,22.71) 28.78,22.75 28.64,22.75
TCP0_TXRX1_C_DP: length 4.3
  TOP w0.076: 28.64,22.96 28.62,22.96 28.6,22.94 28.42,22.94 arc(28.32,22.96) 28.23,23.02 28.22,23.03 arc(28.13,23.09) 28.02,23.11 27.86,23.11 arc(27.82,23.1) 27.78,23.07 27.76,23.06 arc(27.74,23.03) 27.74,22.99 27.74,22.98 arc(27.74,22.94) 27.76,22.91 27.77,22.91 arc(27.8,22.89) 27.84,22.88 UT2.E1
  TOP w0.102: CT24.2 31.03,21.84 arc(30.96,21.79) 30.87,21.77 30.4,21.77 arc(30.28,21.79) 30.19,21.86 29.3,22.75 arc(29.06,22.91) 28.78,22.96 28.64,22.96
TCP0_TXRX1_DN: length 71.3
  TOP w0.102: CT25.1 31.7,21.49 arc(31.77,21.54) 31.86,21.56 35.45,21.56 arc(36.32,21.73) 37.05,22.22 37.7,22.86 arc(37.9,23.17) 37.98,23.54 37.98,24.06 arc(38.02,24.15) 38.11,24.19 38.18,24.19 arc(38.29,24.17) 38.39,24.11 v1(38.49,24.01)
  ART06 w0.102: v2(89.49,40.87) 89.67,41.05 arc(89.72,41.12) 89.74,41.21 89.74,41.27 arc(89.73,41.32) 89.7,41.36 89.16,41.9 arc(89.07,41.96) 88.95,41.98 86.51,41.98 arc(85.67,41.82) 84.95,41.34 arc(84.29,40.89) 83.51,40.74 82.16,40.74 arc(80.64,40.44) 79.35,39.58 arc(78.87,39.25) 78.3,39.14 78.15,39.14 arc(77.64,39.04) 77.2,38.74 77.19,38.74 76.39,38.11 arc(76.38,38.1) 76.37,38.09 76.16,37.88 arc(75.92,37.53) 75.84,37.12 arc(75.74,36.61) 75.46,36.19 73.6,34.33 arc(73.3,34.13) 72.95,34.06 arc(72.64,34) 72.38,33.82 arc(71.66,33.34) 70.8,33.17 70.45,33.17 arc(69.87,33.05) 69.38,32.73 arc(69.08,32.53) 68.73,32.46 66.2,32.46 arc(64.43,32.11) 62.93,31.1 arc(61.93,30.43) 60.75,30.2 50.63,30.2 arc(49.87,30.05) 49.23,29.62 48.04,28.43 arc(47.86,28.31) 47.64,28.27 47.48,28.2 46.64,27.36 arc(46.35,27.17) 46.01,27.1 arc(45.73,27.04) 45.5,26.89 42.72,24.11 arc(42.32,23.84) 41.85,23.75 41.41,23.75 arc(41.01,23.67) 40.67,23.44 40.19,22.96 arc(39.99,22.83) 39.76,22.78 39.55,22.78 arc(39.19,22.93) 39.04,23.29 39.04,24.1 arc(39.01,24.17) 38.94,24.2 38.8,24.2 arc(38.69,24.17) 38.59,24.11 v1(38.49,24.01)
  BOTTOM w0.076: UU1.BF1 89.23,42.3 arc(89.22,42.35) 89.19,42.4 89.16,42.43 arc(89.1,42.45) 89.04,42.43 89.02,42.41 arc(88.99,42.36) 88.98,42.31 88.98,42.04 arc(89,41.91) 89.07,41.81 89.1,41.78 arc(89.16,41.7) 89.18,41.6 89.18,41.54 89.22,41.43 89.29,41.37 arc(89.39,41.3) 89.51,41.27 89.61,41.27 arc(89.67,41.25) 89.7,41.18 89.7,41.17 arc(89.68,41.08) 89.63,41.01 v2(89.49,40.87)
TCP0_TXRX1_DP: length 71.4
  TOP w0.102: v1(38.49,24.59) 38.39,24.49 arc(38.29,24.43) 38.18,24.41 38.11,24.41 arc(37.86,24.31) 37.76,24.06 37.76,23.54 arc(37.71,23.26) 37.54,23.01 36.9,22.37 arc(36.24,21.93) 35.45,21.77 31.86,21.77 arc(31.77,21.79) 31.7,21.84 CT24.1
  ART06 w0.102: v2(90.07,40.87) 89.99,40.95 arc(89.96,40.99) 89.95,41.04 89.95,41.27 arc(89.93,41.4) 89.85,41.51 89.31,42.05 arc(89.15,42.16) 88.95,42.2 86.51,42.2 arc(85.58,42.01) 84.8,41.49 arc(84.2,41.09) 83.51,40.96 82.16,40.96 arc(80.56,40.64) 79.2,39.73 arc(78.79,39.45) 78.3,39.35 78.15,39.35 arc(77.56,39.24) 77.05,38.9 76.26,38.28 arc(76.24,38.26) 76.21,38.24 76.01,38.03 arc(75.73,37.61) 75.63,37.12 arc(75.54,36.7) 75.31,36.34 73.44,34.48 arc(73.22,34.33) 72.95,34.27 arc(72.56,34.2) 72.23,33.98 arc(71.57,33.54) 70.8,33.39 70.45,33.39 arc(69.79,33.25) 69.23,32.88 arc(69,32.73) 68.73,32.67 66.2,32.67 arc(64.35,32.31) 62.78,31.26 arc(61.84,30.63) 60.75,30.41 50.63,30.41 arc(49.79,30.25) 49.08,29.77 47.89,28.59 arc(47.78,28.51) 47.64,28.48 arc(47.47,28.45) 47.33,28.35 46.48,27.51 arc(46.27,27.37) 46.01,27.32 arc(45.65,27.24) 45.35,27.04 42.57,24.26 arc(42.24,24.04) 41.85,23.96 41.41,23.96 arc(40.93,23.87) 40.52,23.59 40.03,23.11 arc(39.91,23.03) 39.76,23 39.55,23 arc(39.34,23.08) 39.25,23.29 39.25,24.1 arc(39.16,24.32) 38.94,24.41 38.92,24.41 arc(38.68,24.46) v1(38.49,24.59)
  BOTTOM w0.076: v2(90.07,40.87) 89.93,41.01 arc(89.88,41.08) 89.86,41.18 89.86,41.18 arc(89.79,41.36) 89.61,41.44 89.51,41.44 arc(89.45,41.45) 89.4,41.48 89.36,41.53 89.34,41.57 89.34,41.67 arc(89.36,41.74) 89.4,41.8 89.41,41.81 arc(89.45,41.87) 89.46,41.94 89.46,42.32 arc(89.43,42.47) 89.35,42.59 UU1.BF2
TCP_RETIMER_PERST_N: length 146.2
  TOP w0.102: RT60.1 22.73,16.84 22.35,16.46 18.9,16.46 v2(18.39,16.96) ; RU158.1 57.28,79.19 57.28,80.34 v1(57.66,80.72)
  ART03 w0.089: v2(18.39,16.96) 18.39,19.08 19.35,20.05 19.35,23.44 19.08,23.71 19.08,25.65 19.86,26.43 19.86,26.92 20.35,27.4 22.5,27.4 22.81,27.71 24.46,27.71 25.22,28.47 25.32,28.47 26.01,29.16 26.01,30.55 26.26,30.81 28.45,30.81 30.38,32.74 30.38,36.29 31.8,37.72 32.31,37.72 32.83,38.24 32.83,41.36 32.08,42.11 29.79,42.11 27.23,44.68 27.23,47.27 27.19,47.31 27.19,50.2 27.61,50.62 27.61,56.28 27.3,56.59 27.3,58.95 26.54,59.71 26.54,60.14 26.99,60.59 26.99,63.71 26.87,63.83 26.87,71.78 25.42,73.23 25.42,74.72 25.03,75.12 25.03,77.5 26.97,79.45 39.29,79.45 42.31,76.43 52.02,76.43 52.63,77.04 54.03,77.04 54.14,77.15 55.18,77.15 57.25,79.22 57.25,80.31 v1(57.66,80.72)
  BOTTOM w0.076: 70.86,66.49 70.86,66.29 70.96,66.19 70.96,65.85 71.02,65.48 70.99,65.22 71.02,64.69 UU1.DC47
  BOTTOM w0.102: RU159.2 v1(57.66,80.72) 58.04,80.34 58.04,78.56 58.37,78.23 58.37,77.47 60.96,74.88 62.96,74.88 v3(63.24,75.16) 64.18,75.16 66.93,72.41 66.93,72.18 67.24,71.86 67.24,70.79 67.42,70.61 68.15,70.61 68.32,70.43 68.32,70.18 68.76,69.75 68.76,68.6 69.72,67.64 70.76,67.64 70.86,67.54 70.86,66.49
TCP_RETIMER_PERST_N_R: length 5.4
  TOP w0.076: 24.48,20.67 24.48,21.27 UT2.B8
  TOP w0.102: 24.48,20.67 24.48,20.11 23.75,19.38 RT55.2 RT66.2 RT60.2 RT54.1
TCP_SMBUS_SCL: length 4.2
  TOP w0.102: RT39.1 RT37.1 RT47.1 25.4,18.11 25.4,18.62 25.17,18.85 UT2.A7
TCP_SMBUS_SDA: length 4.8
  TOP w0.076: 24.94,20.6 24.94,20.6 24.94,21.27 UT2.B7
  TOP w0.102: 24.94,20.6 24.94,18.57 v2(25.02,18.49)
  BOTTOM w0.102: v2(25.02,18.49) 25.27,18.23 RT48.1 RT38.1 RT40.1
TCRCOMP_DN: length 5.5
  BOTTOM w0.102: UU1.AY1 92.48,41.71 90.17,39.39 v3(90.17,38.68) RU5.1
TCRCOMP_DP: length 7.3
  BOTTOM w0.102: RU5.2 88.8,38.4 v3(88.8,38.68) 88.8,38.88 89.56,39.65 89.91,39.65 92.2,41.93 92.2,42.16 92.48,42.45 UU1.AY2
THERMTRIP_SOC_N: length 26.8
  TOP w0.102: v2(110.74,41.22) 107.95,38.43 105.92,38.43 105.1,37.61 105.1,37.11 v2(103.25,35.25)
  BOTTOM w0.076: UU1.E3 109.62,42.73 109.99,42.36 110.34,42.36 110.58,42.12 110.58,41.39 v2(110.74,41.22) 110.74,40.84 111.75,39.84
  BOTTOM w0.102: v2(103.25,35.25) 103.25,35.84 QU5.2 101.71,36.46 v3(101.24,35.99) 101.24,35.74 101.85,35.13 101.85,33.93 QU6.2 102.67,33.2 105.66,33.2 106.29,32.57 QU4.2 ; 111.75,39.84 112.9,38.68 RU21.1
TOUCHPAD_EN: length 126.5
  TOP w0.076: 161.29,12.77 161.29,13.79 161.47,13.97 UE1.N3
  TOP w0.102: 161.29,12.77 161.29,11.63 160.35,10.69 159.31,10.69 158.68,10.06 158.68,9.4 157.53,8.25 153.72,8.25 151.08,5.61 v3(151.08,4.54) 151.08,4.47 v2(150.11,3.5)
  ART06 w0.102: v2(56.2,3.1) 56.88,2.41 71.88,2.41 73.71,4.24 91.48,4.24 93.76,1.95 114.67,1.95 116.97,4.25 144.42,4.25 144.79,3.88 149.73,3.88 v2(150.11,3.5)
  BOTTOM w0.102: v2(56.2,3.1) JE4.8 56.2,8.9 56.26,8.96 ESDE4.1 55.5,9.6 CE55.1 ; CE55.1 55.34,9.6 55.19,9.75 55.19,11.07 RE69.2 ; CE55.1 55.5,9.34 55.37,9.22 54.3,9.22 TP150.1
TOUCHPAD_I2C_CLK: length 72
  TOP w0.102: RE61.1 71.25,7.52 70.89,7.87 70.89,9.29 70,10.18 v3(67,10.18) 66.9,10.08 57.97,10.08 57.79,9.9 54.82,9.9 54.64,10.08 54.64,10.44 v2(54.81,10.61)
  ART03 w0.089: v2(54.81,10.61) 54.62,10.81 54.62,11.14 50.29,15.47 50.29,16.58 51.05,17.35 51.05,20.19 60.83,29.97 60.83,37.92 60.33,38.42 60.33,42.02 60.75,42.44 60.75,45.62 60.3,46.07 60.3,48.49 60.6,48.79 60.6,51.49 61.5,52.39 61.83,52.39 v2(62.23,52.79)
  BOTTOM w0.076: v2(62.23,52.79) 62.23,52.91 62.3,52.98 62.43,52.98 62.62,52.79 63.91,52.79 UU1.DU23
TOUCHPAD_I2C_CLK_C: length 16.4
  TOP w0.102: QE3.4 69.33,6.79 69.47,6.93 RE62.2 69.09,7.19 68.83,6.93 CE44.1 RE55.2 67.56,6.3 ESDE6.1 65.92,6.42 v3(63.47,8.86) 62.74,9.6 60.37,9.6 v1(59.84,9.07)
  BOTTOM w0.102: TP143.1 59.89,9.4 59.89,9.12 v1(59.84,9.07) 59.74,9.07 59.33,8.66 58.67,8.66 58.2,8.19 JE4.6
TOUCHPAD_I2C_SDA: length 71.2
  TOP w0.102: v2(66.67,7.16) v3(65.72,8.11) 65.15,8.68 65.15,9.75 65.05,9.85 58.06,9.85 57.88,9.67 54.72,9.67 54.41,9.99 54.41,10.43 v2(54.23,10.61) ; RE63.1 67.71,4.14 v1(66.85,5)
  ART03 w0.089: v2(54.23,10.61) 54.4,10.79 54.4,11.05 50.07,15.38 50.07,16.67 50.84,17.44 50.84,20.28 60.62,30.06 60.62,37.83 60.11,38.33 60.11,42.1 60.54,42.53 60.54,45.53 60.09,45.98 60.09,48.58 60.39,48.88 60.39,51.58 v2(61.59,52.79)
  BOTTOM w0.076: UU1.DW23 63.43,52.95 62.69,52.95 62.49,53.15 61.95,53.15 v2(61.59,52.79)
  BOTTOM w0.102: v1(66.85,5) 66.8,5.05 66.8,6.04 66.67,6.17 v2(66.67,7.16)
TOUCHPAD_I2C_SDA_C: length 19.8
  TOP w0.102: CE45.1 RE56.2 71.99,5.05 QE3.1 70.86,5.05 70.25,4.44 RE64.2 70.25,3.88 69.93,3.56 ESDE7.1 69.93,3.2 69.14,2.41 66.9,2.41 v3(61.47,7.85) 60.45,8.86 v1(60.45,9.07)
  BOTTOM w0.102: TP142.1 60.55,9.95 60.55,9.17 v1(60.45,9.07) 60.45,8.91 60.15,8.61 59.66,8.61 59.2,8.14 JE4.5
TOUCHPAD_INT_C: length 5.8
  BOTTOM w0.102: JE4.7 57.2,8.66 56.87,8.99 56.87,9.31 ESDE5.1 57.28,10.48 CE54.1 RE67.1 RE454.1 RE65.2 56.97,12.01 TP149.1
TOUCHPAD_INT_N: length 160.7
  ART03 w0.089: v1(61.09,78.56) 58.93,78.56 57.66,77.29 57.3,77.29 56.44,76.43 55.07,76.43 54.66,76.02 49.68,76.02 49.07,75.41 46.94,75.41 46.38,75.97 42.21,75.97 39.88,78.31 36.19,78.31 v1(35.69,78.81)
  ART05 w0.102: v1(35.69,78.81) 35.69,76.2 37.01,74.88 37.01,66.82 33.88,63.7 29.97,63.7 28.95,62.68 28.95,56.3 28.55,55.89 28.55,50.65 29,50.19 29,46.73 29.34,46.4 29.34,42.87 29.67,42.54 29.67,38.22 32.26,35.63 32.26,34.54 34.39,32.41 34.39,15.97 36.73,13.64 36.73,12.24 38.09,10.87 39.9,10.87 40.59,10.18 40.59,9.57 42.52,7.64 49.99,7.64 50.76,6.88 56.39,6.88 v2(58.57,9.07)
  BOTTOM w0.102: RE67.2 58.04,11 58.42,10.61 58.42,9.22 v2(58.57,9.07) ; UU1.CC45 81.24,64.04 81.53,64.34 81.53,66.49 80.9,67.13 80.9,67.64 79.94,68.59 78.77,68.59 73.02,74.34 69.82,74.34 v3(66.65,77.51) 65.61,78.56 v1(61.09,78.56)
TOUCHPAD_INT_N_EC: length 119.2
  TOP w0.076: UE1.M12 166.22,14.49 166.22,13.76 v2(166.29,13.69)
  ART05 w0.102: v2(154.8,12.01) 155.19,12.01 156.21,13.03 156.59,13.03 157.76,11.86 160.88,11.86 161.75,11 163.59,11 v2(166.29,13.69)
  ART06 w0.102: v2(154.8,12.01) 154.3,11.52 154.3,11.06 151.34,8.1 149.52,8.1 149.13,8.49 141.82,8.49 141.37,8.05 132.78,8.05 131.41,6.68 108.08,6.68 105.54,9.22 83.06,9.22 82.52,8.68 73.21,8.68 72.68,9.22 63.5,9.22 62.96,8.68 59.56,8.68 v2(59.18,9.07)
  BOTTOM w0.102: v2(59.18,9.07) 58.62,9.62 58.62,10.69 58.98,11.05 v3(58.98,11.25) 58.72,11.5 RE454.2
TP_+V_D4CH0_CA_VREF: length 4.4
  TOP w0.102: TPU2.1 114.12,63.45 v2(113.54,63.45)
  BOTTOM w0.152: UU1.C44 111.29,63.26 111.74,63.7 112.3,63.7 112.47,63.87 113.11,63.87 v2(113.54,63.45)
TP_+V_D4CH1_CA_VREF: length 1.3
  TOP w0.102: v2(106.51,60.42) 106.81,60.72 TPU1.1
  BOTTOM w0.102: UU1.M38 v2(106.51,60.42)
TP_+V_LPCH0_DQ_VREF: length 1.7
  TOP w0.203: v2(110.63,63.9) TPU3.1
  BOTTOM w0.203: UU1.B45 110.65,63.88 v2(110.63,63.9)
TP_DDR_VTT_CTRL: length 1.2
  TOP w0.102: v2(105.59,60.42) 105.54,60.48 TPU4.1
  BOTTOM w0.102: UU1.M39 v2(105.59,60.42)
TP_PWR_ON: length 231.8
  TOP w0.076: UE1.B10 165.22,19.99 165.22,20.39 165.61,20.77 v2(165.61,21.03)
  TOP w0.102: v1(26.41,69.8) 28.95,69.8 30.81,71.65 v3(31.54,71.65) 33.91,69.29 v1(34.67,69.29)
  ART03 w0.089: v2(165.61,21.03) 165.61,20.75 166.67,19.68 166.67,15.14 166.83,14.98 166.83,10.82 164.59,8.58 164.01,8.58 162.9,7.47 162.9,6.75 161.91,5.76 158.71,5.76 158.05,6.42 156.51,6.42 156.06,6.87 153.04,6.87 152.46,6.3 149.69,6.3 149.06,5.66 135.58,5.66 134.41,4.49 115.34,4.49 114.53,5.31 107.54,5.31 106.53,6.32 104.6,6.32 v2(103.83,5.56)
  ART05 w0.102: v2(103.83,5.56) 102.82,5.56 102.36,6.02 101.68,6.02 101.2,6.5 88.87,6.5 87.78,7.59 67.69,7.59 66.85,6.75 65.35,6.75 63.96,5.36 48.88,5.36 48.65,5.59 42.31,5.59 39.27,8.63 35.62,8.63 32,12.25 32,15.31 32.38,15.69 32.38,20.77 30.76,22.39 30.76,28.46 30.1,29.12 30.1,35.13 27.56,37.67 27.56,43.89 26.9,44.55 26.9,46.4 26.29,47.01 26.29,47.52 26.54,47.77 26.54,56.59 24.66,58.47 24.66,62.58 25.4,63.32 25.4,64.69 26.9,66.19 26.9,69.31 v1(26.41,69.8)
  BOTTOM w0.102: UX2.4 35.24,68.33 35.3,68.27 RX919.2 35.69,68.78 35.18,69.29 v1(34.67,69.29)
TS_EN: length 23.2
  TOP w0.102: TPU72.1 28.32,76.78 27.68,76.78 RX921.2 27.56,76.17 27.46,76.07 26.72,76.07 v1(26.7,76.05) 26.54,75.88 ESDX2.1 ; v3(26.72,64.79) 26.9,64.97 v1(27.3,64.97) 28.73,64.97 29.49,64.21 30.73,64.21 30.99,64.46 RX105.2 DX1.3
  ART05 w0.102: v1(26.7,76.05) 26.7,75.48 28.75,73.43 28.75,70.86 27.91,70.03 27.91,65.58 v1(27.3,64.97)
  BOTTOM w0.102: JX1.22 v1(26.7,76.05)
TYPEC_I2C_INT_EC: length 172.6
  TOP w0.076: UE1.E5 v2(162.91,17.8)
  ART03 w0.089: v1(46.18,25.96) 45.86,25.96 38.8,18.9 38.8,13.35 39.93,12.21 39.93,11.15 39.32,10.54 39.32,7.39 43.58,3.12 47.04,3.12 47.67,3.76 70.18,3.76 71.12,4.7 72.49,4.7 73,4.19 89.8,4.19 90.22,3.77 98.79,3.77 101.39,6.37 103.17,6.37 103.78,6.98 105.41,6.98 105.97,7.54 106.73,7.54 107.34,6.93 109.98,6.93 110.3,6.61 114.84,6.61 115.76,5.69 132.9,5.69 134.18,6.97 135.33,6.97 135.91,7.55 137.21,7.55 137.84,6.92 146.86,6.92 148.2,8.25 148.94,8.25 149.31,7.88 151.21,7.88 151.53,8.21 152.7,8.21 154.02,9.54 155.53,9.54 156.55,8.52 159.15,8.52 161.46,10.84 161.46,13.58 162.86,14.98 162.86,15.53 162.56,15.83 162.56,17.45 v2(162.91,17.8)
  BOTTOM w0.102: RT17.1 RT16.2 ; RT17.1 45.87,32.59 46.02,32.43 46.02,30.95 45.21,30.14 45.21,26.9 v3(45.36,26.74) 46.15,25.96 v1(46.18,25.96) ; RT17.1 45.72,33.22 45.85,33.35 45.85,33.86 45.46,34.24 UT1.15
TYPEC_PD_CSN: length 44.6
  TOP w0.102: v1(29.64,16.33) 29.8,16.17 29.8,15.14 29.59,14.93
  ART03 w0.102: v2(49.02,41.31) 48.13,40.42 43.27,40.42 40.64,37.79 40.64,33.86 41.44,33.06 41.44,32.01 40.65,31.23 37.98,31.23 37.48,31.73 36.79,31.73 35.29,30.24 35.29,28.76 35.23,28.7 35.23,21.87 30.83,17.47 30.48,17.47 29.84,16.84 29.84,16.53 v1(29.64,16.33)
  BOTTOM w0.102: UT1.40 48.5,40.79 v2(49.02,41.31) 49.02,41.37 49.4,41.76 49.4,41.98 CT14.1
TYPEC_PD_CSP: length 44.2
  TOP w0.102: 30.22,14.93 30.01,15.14 30.01,16.12 v1(30.22,16.33)
  ART03 w0.102: v1(30.22,16.33) 30.06,16.49 30.06,16.75 30.57,17.26 30.92,17.26 35.44,21.78 35.44,28.61 35.51,28.67 35.51,30.15 36.88,31.52 37.39,31.52 37.89,31.01 40.74,31.01 41.65,31.93 41.65,33.14 40.85,33.94 40.85,37.7 41.24,38.09 41.39,38.09 41.6,38.3 41.6,38.45 41.81,38.66 41.96,38.66 42.18,38.87 42.18,39.03 42.39,39.24 42.54,39.24 42.75,39.45 42.75,39.6 43.36,40.21 44.86,40.21 44.96,40.1 45.26,40.1 45.37,40.21 45.67,40.21 45.77,40.1 46.08,40.1 46.18,40.21 46.48,40.21 46.58,40.1 46.89,40.1 46.99,40.21 47.3,40.21 47.4,40.1 47.7,40.1 47.8,40.21 48.22,40.21 48.73,40.71 v2(49.03,40.71)
  BOTTOM w0.102: UT1.1 48.55,40.04 48.87,40.36 48.87,40.55 v2(49.03,40.71) 49.4,41.08 49.4,41.4 49.66,41.65 49.66,41.7 CT15.1
TYPEC_PD_RETIMER_CLK: length 32.1
  BOTTOM w0.102: RT35.2 RT128.2 23.75,20.39 24,20.14 24,19.12 24.38,18.74 24.76,18.74 24.89,18.87 26.39,18.87 26.77,19.25 28.52,19.25 28.85,18.92 30.53,18.92 32.97,21.36 32.97,23.54 32.66,23.85 32.66,24.23 34.16,25.73 34.16,29.61 35.33,30.78 35.94,30.78 39.93,34.77 40.28,34.77 TPT19.1 41.06,35.54 UT1.21
TYPEC_PD_RETIMER_DAT: length 28.1
  ART05 w0.102: v2(33.13,24.19) v2(32.13,23.19)
  BOTTOM w0.102: RT127.2 25.27,20.65 RT34.2 25.78,20.9 26.21,21.33 27.63,21.33 29.21,19.76 30.1,19.76 32.13,21.79 v2(32.13,23.19) ; v2(33.13,24.19) 34.36,25.42 34.36,28.39 TPT18.1 35.27,29.3 35.27,29.82 39.71,34.26 41.25,34.26 41.78,34.79 UT1.20
TYPEC_PD_SCLK: length 3.2
  BOTTOM w0.102: RT21.2 RT12.2 CT10.1 43.69,33.3 44.46,34.07 UT1.17
TYPEC_PD_SDA: length 2.8
  BOTTOM w0.102: UT1.16 44.96,33.99 44.7,33.73 CT11.1 RT19.2 RT11.2
TYPEC_PD_SOC_CLK: length 30
  ART06 w0.102: v2(55.12,51.28) 55.33,51.49 55.75,51.49 56.46,52.19 62.86,52.19 63.43,52.77 66.74,52.77 v2(67.1,52.4)
  BOTTOM w0.102: UU1.DN22 66.7,52.81 v2(67.1,52.4) ; RT8.1 50.82,37.49 51.35,38.02 51.51,38.02 TPT15.1 51.81,38.38 53.97,40.54 53.97,48.56 54.71,49.3 54.71,51.31 54.86,51.46 55.01,51.46 55.12,51.36 v2(55.12,51.28)
TYPEC_PD_SOC_CLK_R: length 3.1
  BOTTOM w0.102: RT8.2 RT22.2 CT13.1 49.73,38.61 49.48,38.86 48.82,38.86 48.5,38.54 UT1.4
TYPEC_PD_SOC_DAT: length 28.7
  ART06 w0.102: v2(55.12,51.84) 55.23,51.72 55.66,51.72 56.36,52.42 62.76,52.42 63.33,52.99 66.59,52.99 v2(66.99,53.39)
  BOTTOM w0.102: v2(66.99,53.39) 67.35,53.04 UU1.DL22 ; RT7.1 50.54,40.08 51.89,40.08 TPT14.1 52.98,40.05 53.74,40.82 53.74,48.66 54.48,49.39 54.48,51.41 54.76,51.69 55.01,51.69 55.12,51.79 v2(55.12,51.84)
TYPEC_PD_SOC_DAT_R: length 2.8
  BOTTOM w0.102: UT1.3 48.62,39.04 48.74,39.16 CT12.1 RT20.2 RT7.2
TYPEC_PRESENT: length 159.6
  TOP w0.076: UE1.F9 164.47,17.72 164.03,17.28 v2(164.03,17.25)
  TOP w0.102: v1(26.68,7.76) v3(25.91,7.76) 25.46,7.76 24.89,7.19 RT105.1 24.11,7.19 QT3.2
  ART06 w0.102: v2(164.03,17.25) 164.46,17.69 164.46,18.11 164.08,18.49 162.43,18.49 161.87,19.05 161.87,19.17 161.42,19.63 159.99,19.63 159.38,20.24 158.65,20.24 158.49,20.09 158.49,18.87 158.67,18.69 158.67,17.83 158.16,17.32 158.16,16.91 158.39,16.69 158.39,15.77 158.14,15.52 157.68,15.52 157.03,14.87 157.03,13.73 156.46,13.15 156.26,13.15 155.62,12.52 155.62,11.88 150.32,6.58 138.81,6.58 137.54,7.85 132.87,7.85 131.49,6.47 116.07,6.47 113.84,4.24 111.17,4.24 110.31,5.1 105.41,5.1 102.72,7.8 101.55,7.8 100.94,8.4 83.24,8.4 82.68,7.85 65.94,7.85 63.88,5.79 50.16,5.79 48.26,7.69 34.92,7.69 34.01,8.61 27.53,8.61 v1(26.68,7.76)
TYPEC_PWR_EN: length 170.1
  TOP w0.076: 168.86,16.74 168.76,16.84 168.76,16.96 168.03,17.68 166.74,17.68 166.68,17.74 UE1.F13
  TOP w0.102: v3(35.25,12.07) 34.99,11.81 v1(34.29,11.81) 34.14,11.81 33.83,12.11 31.39,12.11 RT106.2 30.63,9.74 QT5.1 ; v1(169.49,15.75) 169.16,16.08 169.16,16.43 168.86,16.74
  ART03 w0.089: v1(34.29,11.81) 34.29,10.41 36.7,8 36.7,5.13 40.84,0.99 48.87,0.99 49.66,1.78 71.91,1.78 73.63,3.5 89.13,3.5 89.71,2.92 105.2,2.92 106.67,4.39 108.41,4.39 111.33,1.47 133.62,1.47 136.29,4.14 144.43,4.14 145.21,3.36 148.07,3.36 148.8,4.09 149.64,4.09 150.29,4.74 155.64,4.74 156.53,3.85 167.35,3.85 170.43,6.93 170.43,14.81 v1(169.49,15.75)
TYPEC_PWR_LIMIT: length 186.9
  TOP w0.102: RE453.1 166.72,24.25 v1(166.72,24.61)
  ART05 w0.102: v1(166.72,24.61) 167.69,23.64 169.14,23.64 171.09,21.69 171.09,20.7 171.96,19.83 171.96,16.23 165.66,9.93 165.66,8.81 164.39,7.54 164.39,5.86 v1(163.78,5.26)
  ART06 w0.102: v1(163.78,5.26) 163.78,5.46 163.17,6.07 135.84,6.07 134.97,6.93 133.75,6.93 132.74,5.92 116.38,5.92 114.15,3.68 108.66,3.68 107.9,4.44 103.48,4.44 100.07,7.85 83.51,7.85 82.85,7.19 67.51,7.19 65.48,5.15 48.77,5.15 47.55,6.37 44.19,6.37 43.53,7.03 32.92,7.03 v2(32.76,7.19)
  BOTTOM w0.102: v2(32.76,7.19) 26.69,7.19 26.26,7.62 24.69,7.62 24.13,7.06 22.1,7.06 21.72,7.44 20.57,7.44 19.94,8.07 19.94,10.11 21.13,11.3 21.13,13.38 v3(21.54,13.79) 21.54,13.99 22.5,14.96 RT97.2 23.72,14.65 23.58,14.51 QT2.1
TYPEC_PWR_LIMIT_R: length 4
  TOP w0.076: UE1.A11 165.47,20.39 165.96,20.88 165.96,21.7 166.04,21.78
  TOP w0.102: 166.04,21.78 166.12,21.87 166.32,21.87 v3(166.53,22.08) 166.93,22.48 RE453.2
U42_L_U43E_Z: length 6.7
  BOTTOM w0.076: UU1.D4 110.09,43.27 110.43,42.93 110.43,42.66 110.68,42.41 110.98,42.41 111.25,42.14 111.28,42.14 111.44,41.98 111.44,41.03 113.54,38.94
  BOTTOM w0.102: RU211.2 113.66,38.81 113.54,38.94
UART2_RXD: length 7.2
  BOTTOM w0.076: UU1.DT22 64.96,52.46 64.64,52.78 64.42,52.78 64.21,52.56 64.21,52.35 64.06,52.2 63.31,52.2 62.99,51.89 61.47,51.89
  BOTTOM w0.102: RP12.2 60.07,51.25 TPP11.1 60.7,51.89 61.47,51.89
UART2_TXD: length 8.3
  BOTTOM w0.102: UU1.DW22 62.95,52.14 61.52,52.14 61.31,52.35 60.22,52.35 59.51,51.64 56.87,51.64 56.77,51.53 RP13.2 56.77,50.85 TPP10.1
UART_BT_WAKE_N: length 4
  TOP w0.102: v1(151.23,24.71) 151.13,24.81 RW71.2 151.36,25.45 RW72.1
  BOTTOM w0.102: v1(151.23,24.71) 151.97,25.45 JW1.20
UART_BT_WAKE_N_SOC: length 113
  TOP w0.102: v2(149.25,24.66) 149.55,24.97 v3(149.71,24.97) 150.16,24.97 150.42,25.22 RW71.1
  ART05 w0.102: v2(67.56,59.76) 67.56,58.34 67.31,58.09 67.31,57.27 67.92,56.66 67.92,54.79 67.77,54.63 67.77,54.23 68.17,53.82 68.68,53.82 69.09,53.41 69.09,52.02 69.59,51.51 69.59,51.13 69.91,50.81 69.91,50.28 69.81,50.18 69.81,46.54 70.41,45.95 70.41,44.09 71.87,42.63 79.87,42.63 80.08,42.42 82.04,42.42 82.52,41.93 85.24,41.93 85.47,42.16 95.88,42.16 96.24,42.52 100.68,42.52 100.89,42.72 111.38,42.72 112.01,43.36 115.24,43.36 116.28,44.4 126.82,44.4 127.18,44.04 128.4,44.04 129.79,42.64 132.38,42.64 134.11,40.92 134.11,38.15 137.18,35.07 137.92,35.07 139.34,33.65 v1(139.7,33.65)
  ART06 w0.102: v2(149.25,24.66) 147.17,24.66 146.35,25.47 146.35,29.23 143.81,31.77 140.71,31.77 139.7,32.79 v1(139.7,33.65)
  BOTTOM w0.076: UU1.DL38 67.56,60.01 v2(67.56,59.76)
UART_RX_P1: length 2.1
  BOTTOM w0.102: RT10.1 40.61,40.08 40.64,40.05 v3(40.99,40.05) 41,40.04 UT1.30
UART_TX_P1: length 2.8
  BOTTOM w0.102: UT1.29 41.65,39.54 41.43,39.32 41.43,39.22 v3(40.92,38.71) 40.45,39.18 40.35,39.18 RT9.1
USB2_COMP: length 9.3
  BOTTOM w0.102: UU1.DN5 66.33,44.32 64.77,44.32 64.67,44.22 64.08,44.22 64.01,44.14 62.31,44.14 60.35,42.19 v3(59.94,42.19) 59.79,42.19 59.05,42.92 RU141.1
USB2_OTG_ID: length 2.3
  TOP w0.102: v3(66.19,43.81) 66.22,43.81 RU147.2 66.93,45.04 v2(67.04,45.16)
  BOTTOM w0.102: UU1.DL6 67.35,44.85 v2(67.04,45.16)
USB2_P1_DN: length 68.6
  TOP w0.102: v1(33.2,39.17) 33.02,39.35 32.87,39.35 32.76,39.25 32.76,38.24 32.54,38.01 31.54,38.01 31.31,38.24 31.31,41.06 31.21,41.16 29.72,41.16 29.61,41.06 29.61,40.63 29.72,40.53 30.48,40.53 30.71,40.3 30.71,39.72 30.48,39.49 29.72,39.49 29.61,39.39 29.61,38.98 29.72,38.88 30.48,38.88 30.71,38.65 30.71,38.07 30.48,37.84 29.72,37.84 29.61,37.74 29.61,36.91 29.39,36.68 27.52,36.68 27.37,36.54 UB6.2
  ART06 w0.102: v1(33.2,39.17) 33.39,39.36 34.17,39.36 34.53,39 34.53,36.73 34.76,36.5 35.34,36.5 35.57,36.73 35.57,38.71 35.67,38.81 36.08,38.81 36.18,38.71 36.18,37.33 36.41,37.11 36.99,37.11 37.22,37.33 37.22,38.71 37.32,38.81 37.95,38.81 38.17,39.04 38.17,40.22 38.31,40.36 38.68,40.36 38.78,40.26 38.78,39.77 39.01,39.55 39.59,39.55 39.82,39.77 39.82,40.26 39.92,40.36 40.61,40.36 41.02,39.95 47.15,39.95 48.64,41.44 48.64,42.29 48.74,42.39 48.74,43.42 49,43.69 50.73,43.69 51.24,44.19 52.5,44.19 54.1,45.79 54.1,46.58 54.75,47.23 57.92,47.23 60.66,44.49 65.95,44.49 66.17,44.71 66.17,44.94 v2(66.39,45.16)
  BOTTOM w0.102: v2(66.39,45.16) 66.7,45.46 UU1.DN8
USB2_P1_DN_R: length 1.6
  TOP w0.102: UB6.11 23.98,36.54 23.84,36.68 23.59,36.68 23.26,37.01 23.08,37.01 CHKB25.2
USB2_P1_DP: length 68.5
  TOP w0.102: UB6.3 27.39,37.04 27.54,36.9 29.3,36.9 29.4,37 29.4,37.83 29.63,38.05 30.39,38.05 30.49,38.16 30.49,38.56 30.39,38.66 29.63,38.66 29.4,38.89 29.4,39.48 29.63,39.71 30.39,39.71 30.49,39.81 30.49,40.21 30.39,40.31 29.63,40.31 29.4,40.54 29.4,41.15 29.63,41.37 31.3,41.37 31.52,41.15 31.52,38.33 31.63,38.23 32.45,38.23 32.55,38.33 32.55,39.34 32.78,39.57 33.02,39.57 v1(33.2,39.75)
  ART06 w0.102: v1(33.2,39.75) 33.38,39.58 34.26,39.58 34.74,39.09 34.74,36.81 34.85,36.71 35.25,36.71 35.35,36.81 35.35,38.8 35.58,39.02 36.17,39.02 36.4,38.8 36.4,37.42 36.5,37.32 36.9,37.32 37.01,37.42 37.01,38.8 37.23,39.02 37.86,39.02 37.96,39.13 37.96,40.31 38.22,40.57 38.77,40.57 39,40.35 39,39.86 39.1,39.76 39.5,39.76 39.6,39.86 39.6,40.35 39.83,40.57 40.7,40.57 41.11,40.17 47.06,40.17 48.42,41.53 48.42,42.38 48.52,42.48 48.52,43.51 48.91,43.9 50.64,43.9 51.15,44.41 52.41,44.41 53.88,45.88 53.88,46.67 54.66,47.44 58.01,47.44 60.75,44.71 63.12,44.71 63.24,44.83 63.52,44.83 63.64,44.71 63.93,44.71 64.05,44.83 64.34,44.83 64.46,44.71 64.74,44.71 64.86,44.83 65.15,44.83 65.27,44.71 65.86,44.71 65.96,44.8 65.96,44.95 v2(65.75,45.16)
  BOTTOM w0.102: v2(65.75,45.16) 66.05,45.45 UU1.DP8
USB2_P1_DP_R: length 1.6
  TOP w0.102: UB6.10 24.01,37.04 23.87,36.9 23.68,36.9 23.35,37.22 23.03,37.22 CHKB25.1
USB2_P3_TYPEC_DN: length 77.2
  TOP w0.102: v1(14.98,19.57) 14.84,19.71 13.28,19.71 RT124.1
  ART03 w0.102: v1(14.98,19.57) 14.8,19.75 14.43,19.75 14.13,20.05 14.13,20.81 14.73,21.41 16,21.41 17.38,22.79 17.38,24.62 17.7,24.94 17.7,26.22 18.35,26.87 18.35,27.36 19.49,28.5 19.49,31 22.77,34.27 25.61,34.27 26.2,33.69 28.36,33.69 28.74,34.07 28.74,37.07 31.5,39.83 31.81,39.83 v1(32,40.01)
  ART06 w0.102: v2(65.75,47.9) 65.75,47.82 64.07,46.14 61.76,46.14 61.4,45.78 60.92,45.78 58.56,48.14 53.86,48.14 52.67,46.95 52.67,45.68 52.11,45.12 50.82,45.12 50.31,44.61 48.4,44.61 46.82,43.04 46.82,42.27 45.43,40.88 41.74,40.88 41.31,41.31 33.19,41.31 32.55,40.67 32.55,39.93 32.45,39.84 32.18,39.84 v1(32,40.01)
  BOTTOM w0.102: v2(65.75,47.9) 66.05,48.19 UU1.DP13
USB2_P3_TYPEC_DN_CON: length 10.8
  TOP w0.102: RT124.2 12.37,19.71 11.89,19.71 11.65,19.47 ESDT12.1 11.21,19.47 10.96,19.71 10.42,19.71 10.01,19.3 9.24,19.3 v1(9.06,19.12) 8.88,19.3 8.55,19.3 8.41,19.16 JT1.A7 ; JT1.B7 6.41,19.91 6.99,19.91 7.03,19.86 v1(7.14,19.86)
  ART06 w0.102: v1(9.06,19.12) 9.37,19.43 9.52,19.43 9.66,19.29 9.66,18.93 9.38,18.65 8.34,18.65 7.57,19.42 7.57,19.94 7.47,20.04 7.32,20.04 v1(7.14,19.86)
USB2_P3_TYPEC_DP: length 77.2
  TOP w0.102: v1(14.98,20.15) 14.76,19.93 13.28,19.93 LT2.1
  ART03 w0.102: v1(32,39.43) 31.81,39.61 31.59,39.61 28.95,36.98 28.95,33.98 28.45,33.47 26.11,33.47 25.52,34.06 22.86,34.06 19.71,30.91 19.71,28.41 18.57,27.27 18.57,26.78 17.92,26.13 17.92,24.85 17.59,24.53 17.59,22.7 16.09,21.19 14.82,21.19 14.35,20.72 14.35,20.14 14.52,19.97 14.8,19.97 v1(14.98,20.15)
  ART06 w0.102: v2(66.39,47.9) 65.93,47.44 65.68,47.44 64.16,45.92 61.85,45.92 61.49,45.57 60.83,45.57 58.47,47.93 53.95,47.93 52.88,46.86 52.88,45.59 52.2,44.9 50.91,44.9 50.4,44.4 48.49,44.4 47.04,42.95 47.04,42.18 45.52,40.66 41.65,40.66 41.22,41.09 33.28,41.09 32.76,40.58 32.76,39.84 32.54,39.62 32.19,39.62 v1(32,39.43)
  BOTTOM w0.102: v2(66.39,47.9) 66.7,48.21 UU1.DN13
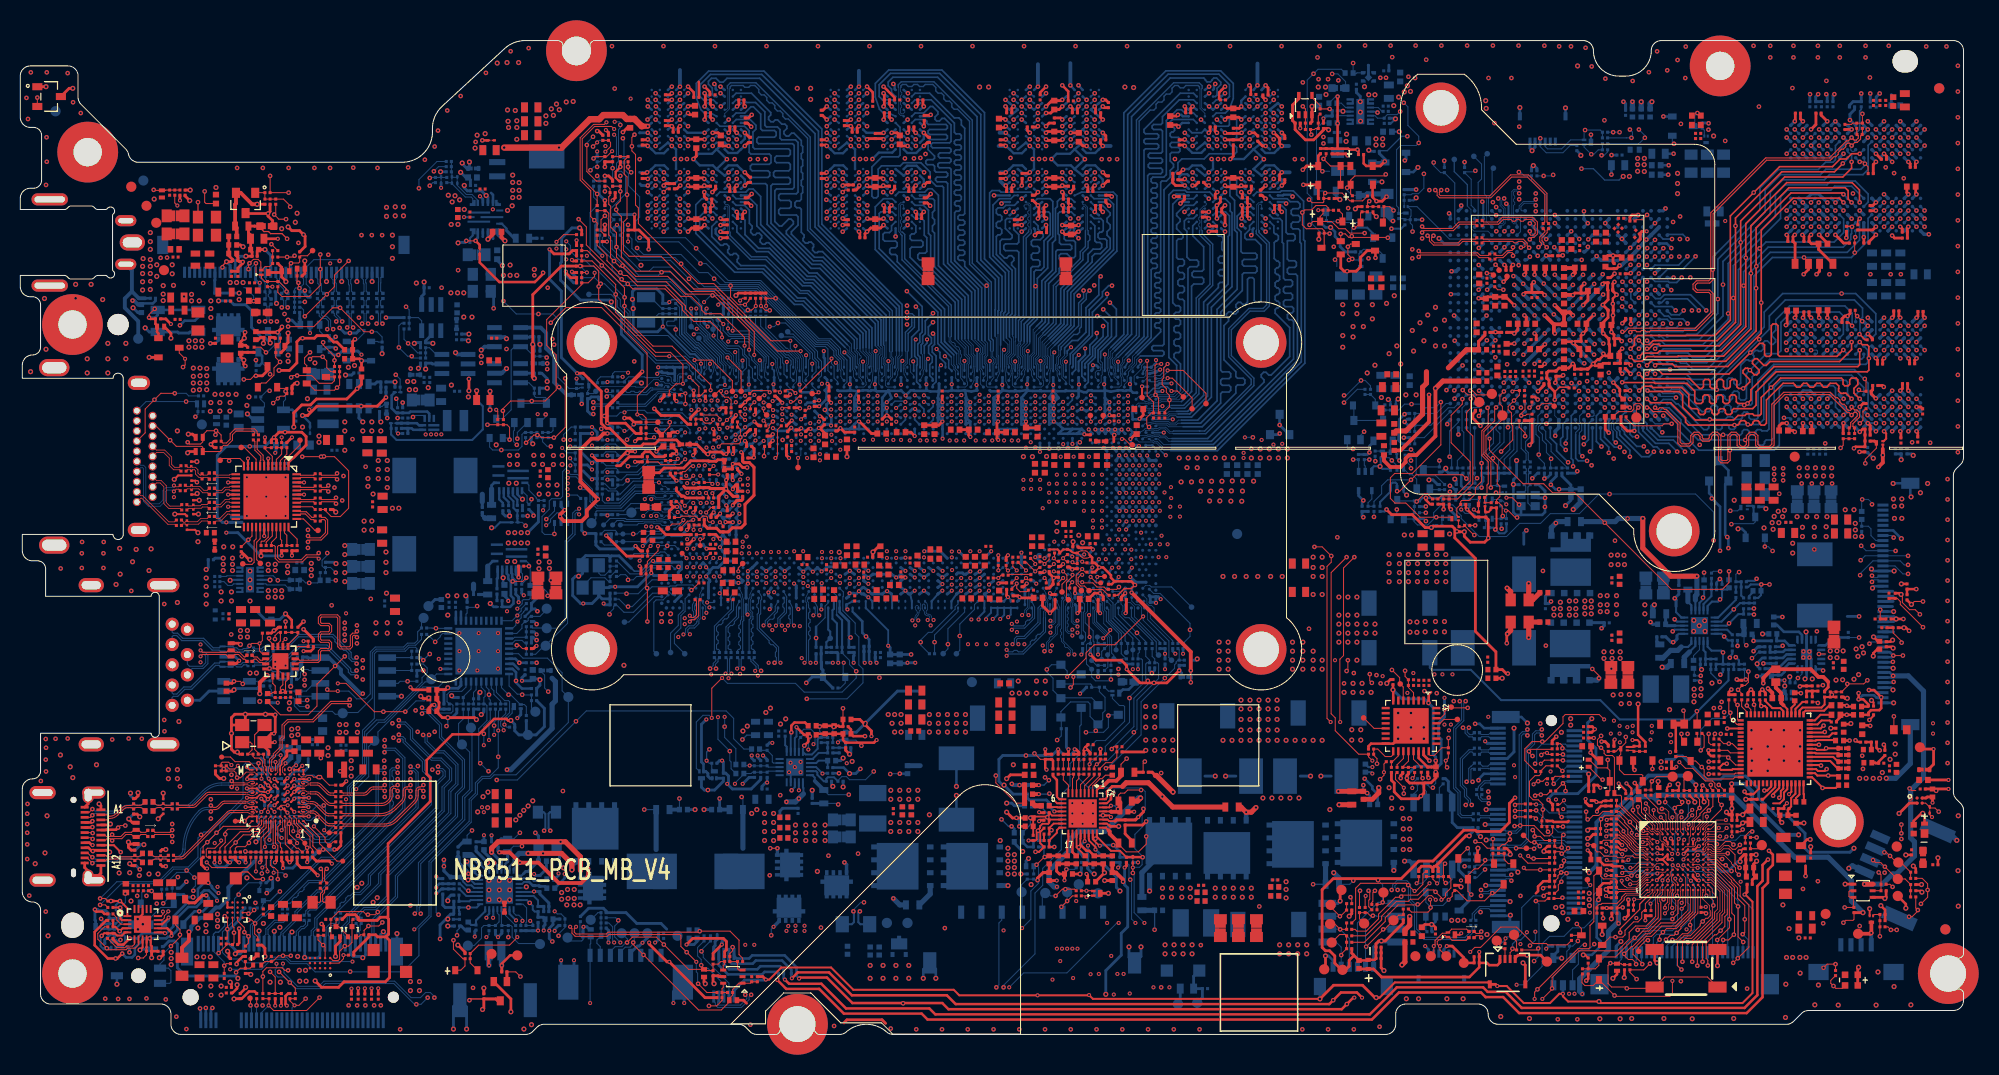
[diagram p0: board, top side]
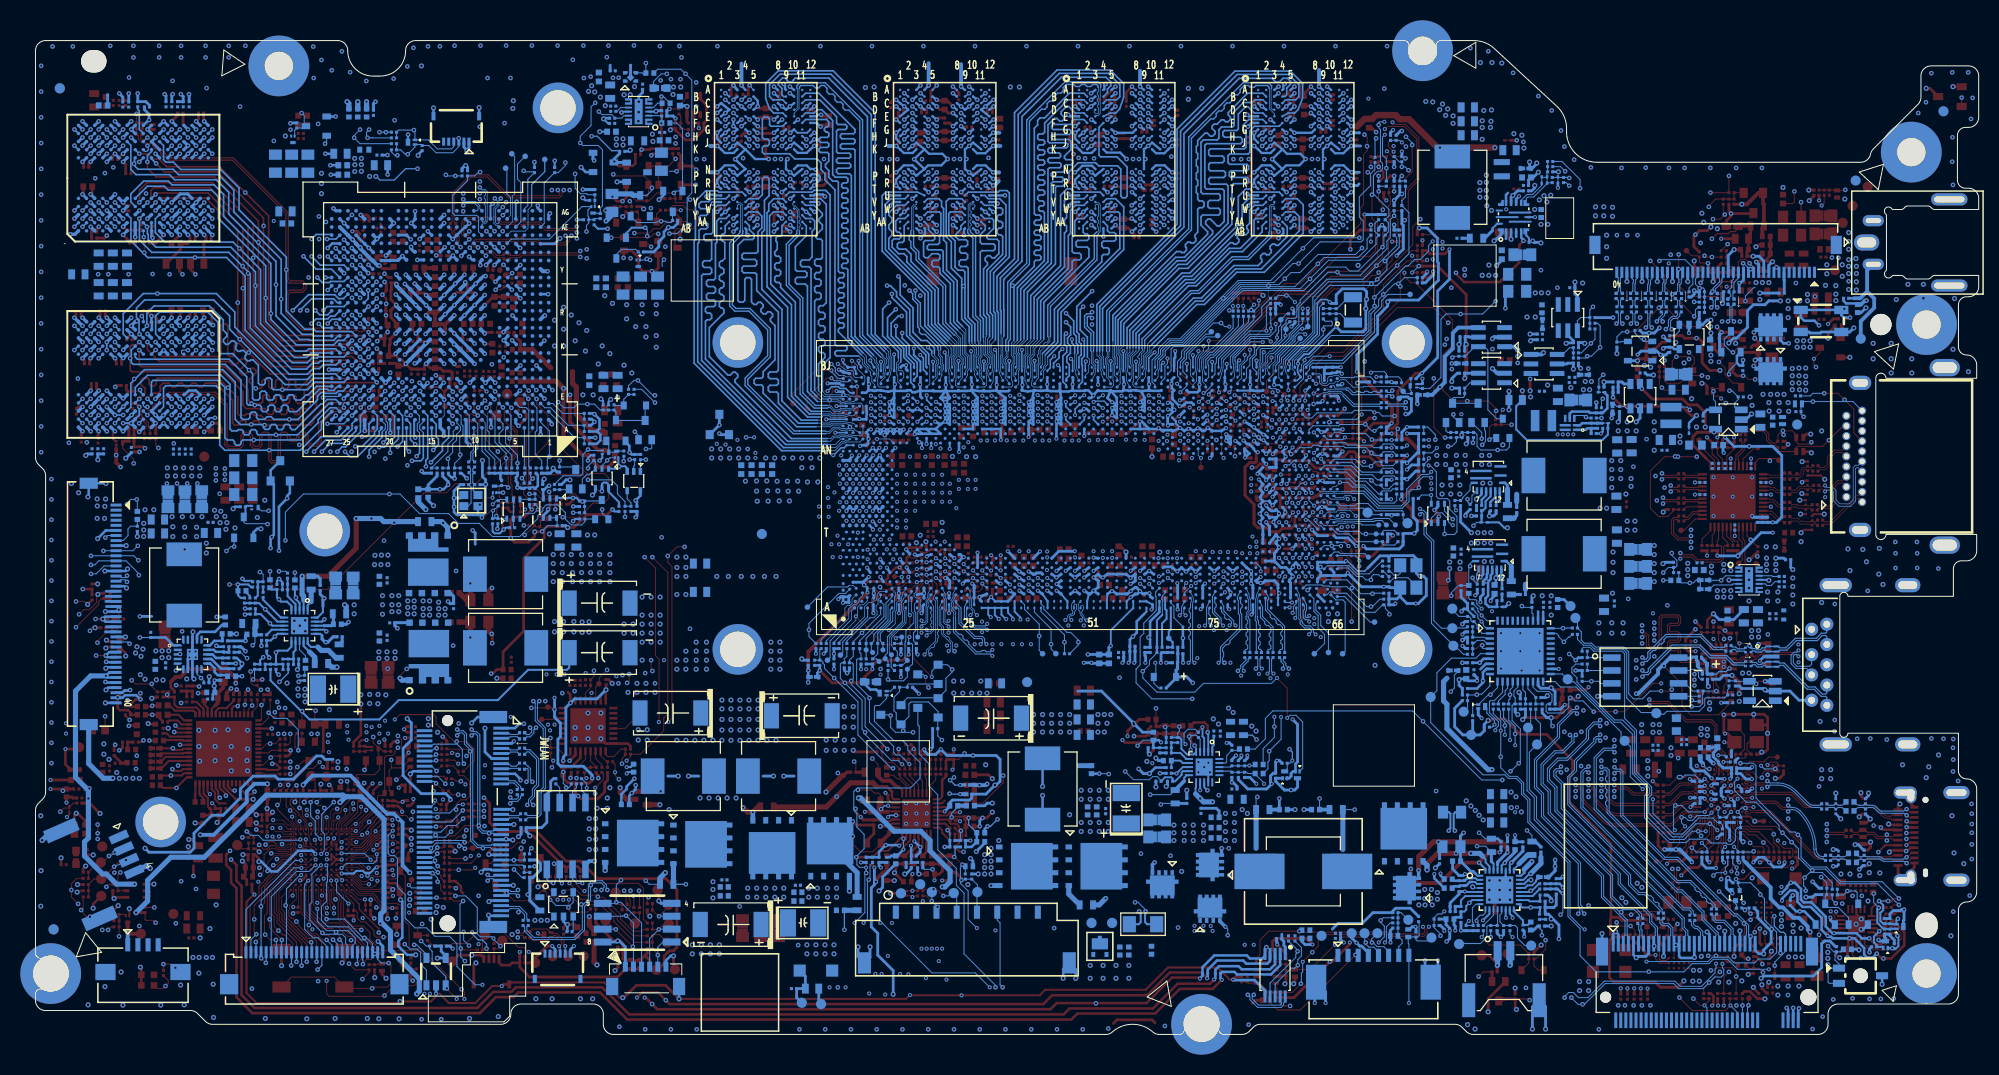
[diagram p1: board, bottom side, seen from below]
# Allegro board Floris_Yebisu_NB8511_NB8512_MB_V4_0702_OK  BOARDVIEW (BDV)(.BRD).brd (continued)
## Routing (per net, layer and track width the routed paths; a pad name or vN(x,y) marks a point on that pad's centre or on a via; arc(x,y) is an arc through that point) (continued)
USB2_P3_TYPEC_DP_CON: length 10.9
  TOP w0.102: JT1.A6 8.36,19.66 8.5,19.51 8.87,19.51 v1(9.06,19.7) 9.24,19.52 9.92,19.52 10.33,19.93 10.96,19.93 11.21,20.17 ESDT13.1 11.65,20.17 11.89,19.93 12.37,19.93 LT2.4 ; v1(7.14,19.28) 7.01,19.41 JT1.B6
  ART06 w0.102: v1(7.14,19.28) 7.42,19.28 8.25,18.44 9.47,18.44 9.88,18.84 9.88,19.38 9.61,19.65 9.12,19.65 v1(9.06,19.7)
USB2_P4_DN: length 158.2
  ART03 w0.102: v1(182.62,45.23) 182.82,45.04 183.15,45.04 183.49,44.69 183.49,42.29 180.14,38.94 178.94,38.94 177.54,37.54 177.54,36.9 176.53,35.89 174.37,35.89 173.57,35.09 173.57,31.84 170.67,28.94 166.28,28.94 165.66,29.56 165.66,30.05 164.35,31.35 162.21,31.35 161.78,31.79 156.07,31.79 155.71,31.43 155.71,30.92 155.27,30.48 154.86,30.48 153.11,28.72 147.83,28.72 145.87,30.68 144.35,30.68 143.42,31.61 139.84,31.61 137.86,33.59 137.86,34.22 136.69,35.39 136.69,35.95 136.37,36.27 135.89,36.27 134.14,38.02 129,38.02 125.66,41.36 117.99,41.36 116.46,39.82 114.04,39.82 110.83,36.61 110.83,35.67 110.49,35.33 109.55,35.33 108.24,34.02 102.88,34.02 101.85,32.99 97.48,32.99 96.68,33.79 96.15,33.79 95.13,34.81 74.36,34.81 73.45,33.91 67.92,33.91 66.42,35.4 66.42,37.41 67.09,38.08 67.09,39.3 69.38,41.59 69.38,45.73 68.57,46.54 68.57,46.77 v2(68.35,46.99)
  BOTTOM w0.102: v2(68.35,46.99) 68,46.63 UU1.DK10 ; JDB1.15 183.3,45.2 183.14,45.04 182.81,45.04 v1(182.62,45.23)
USB2_P4_DP: length 158.2
  ART03 w0.102: v2(69,46.99) 68.79,46.77 68.79,46.62 69.59,45.82 69.59,45.41 69.7,45.31 69.7,45 69.59,44.9 69.59,41.5 69.26,41.16 69.26,40.98 69.06,40.79 68.88,40.79 68.68,40.59 68.68,40.41 68.48,40.21 68.3,40.21 68.11,40.01 68.11,39.84 67.91,39.64 67.73,39.64 67.31,39.22 67.31,38 66.64,37.32 66.64,35.49 68.01,34.12 73.37,34.12 74.27,35.02 95.22,35.02 96.24,34.01 96.77,34.01 97.57,33.21 101.76,33.21 102.79,34.24 108.15,34.24 109.46,35.54 110.4,35.54 110.62,35.76 110.62,36.7 113.95,40.04 116.37,40.04 117.9,41.58 125.75,41.58 129.09,38.24 134.22,38.24 135.98,36.48 136.46,36.48 136.9,36.04 136.9,35.48 138.07,34.31 138.07,33.68 139.93,31.82 143.51,31.82 144.44,30.9 145.96,30.9 147.92,28.94 153.02,28.94 154.77,30.69 155.18,30.69 155.5,31.01 155.5,31.52 155.98,32 161.87,32 162.3,31.57 164.44,31.57 165.87,30.13 165.87,29.65 166.37,29.16 170.58,29.16 173.35,31.93 173.35,35.18 174.28,36.1 176.44,36.1 177.33,36.99 177.33,37.63 178.85,39.15 180.05,39.15 180.96,40.06 180.96,40.24 181.16,40.44 181.33,40.44 181.53,40.64 181.53,40.81 181.73,41.01 181.91,41.01 182.11,41.21 182.11,41.39 182.3,41.59 182.48,41.59 182.68,41.79 182.68,41.96 182.88,42.16 183.06,42.16 183.28,42.38 183.28,42.8 183.13,42.95 183.13,43.21 183.28,43.35 183.28,43.61 183.13,43.76 183.13,44.02 183.28,44.16 183.28,44.61 183.06,44.82 182.82,44.82 v1(182.62,44.63)
  BOTTOM w0.102: JDB1.16 183.36,44.7 183.23,44.83 182.83,44.83 v1(182.62,44.63) ; UU1.DJ10 68.65,46.63 v2(69,46.99)
USB2_P5_DN_FP: length 6.4
  TOP w0.102: TP146.1 140.01,8.34 v2(140.01,8.71) 139.92,8.71 139.75,8.89 139.75,9.17 139.92,9.34 140.08,9.34 140.21,9.47 140.21,9.63 140.34,9.76 140.52,9.76 140.69,9.6 ESD1.1 140.89,9.6 141.22,9.27 142.59,9.27 142.87,9.55
  BOTTOM w0.102: v2(140.01,8.71) 140.01,8.7 139.9,8.59 J1.4
USB2_P5_DP_FP: length 6.4
  TOP w0.102: 142.87,10.16 142.64,10.39 141.17,10.39 140.84,10.05 ESD1.2 140.69,10.05 140.61,9.98 140.25,9.98 139.77,9.5 139.53,9.26 139.53,8.84 v2(139.41,8.71) 139.41,8.01 TP147.1
  BOTTOM w0.102: v2(139.41,8.71) 139.41,7.98 J1.5
USB2_P5_FP_DN: length 135.1
  TOP w0.102: v1(144.09,9.56) 143.9,9.74 143.58,9.74 R19.2
  ART03 w0.102: v1(144.09,9.56) 143.9,9.74 143.58,9.74 143.36,9.97 143.36,10.49 144.08,11.21 147.15,11.21 148.74,12.8 148.74,14.81 151.34,17.41 154.7,17.41 155.03,17.74 155.03,21.02 154.87,21.17 154.87,23.28 153.3,24.85 153.3,25.69 152.6,26.39 150.92,26.39 149.36,27.95 147.64,27.95 145.69,29.89 143.66,29.89 143.1,29.33 140.21,29.33 135.82,33.72 135.82,34.43 134.06,36.19 129.97,36.19 128.9,35.13 115.97,35.13 114.87,34.02 110.1,34.02 108.6,32.52 106.06,32.52 105.27,31.73 96.86,31.73 96.38,32.22 95.92,32.22 94.57,33.56 75.2,33.56 74.26,32.62 66.76,32.62 64.93,34.45 64.93,38.08 65.62,38.77 65.62,39.23 v2(65.4,39.44)
  BOTTOM w0.076: UU1.DL5 67.01,43.38 67.01,43.18 66.89,42.89 66.89,41.04 66.76,40.91 66.76,40.77 66.75,40.76 66.75,40.74 66.71,40.7 66.71,40.69
  BOTTOM w0.102: v2(65.4,39.44) 65.62,39.66 65.62,39.99 65.92,40.29 66.41,40.29 66.71,40.6 66.71,40.69
USB2_P5_FP_DP: length 135
  TOP w0.102: R20.2 143.58,9.96 143.9,9.96 v1(144.09,10.14)
  ART03 w0.102: v1(144.09,10.14) 143.9,9.96 143.67,9.96 143.57,10.06 143.57,10.4 144.17,11 144.6,11 144.73,10.87 145,10.87 145.13,11 145.41,11 145.54,10.87 145.82,10.87 145.94,11 146.22,11 146.35,10.87 146.63,10.87 146.76,11 147.24,11 148.96,12.71 148.96,14.72 151.43,17.19 154.79,17.19 155.24,17.65 155.24,21.1 155.09,21.26 155.09,23.37 153.52,24.94 153.52,25.78 152.69,26.6 151.01,26.6 149.45,28.17 147.72,28.17 145.78,30.11 143.57,30.11 143.01,29.55 140.3,29.55 136.04,33.8 136.04,34.52 134.15,36.41 129.88,36.41 128.81,35.34 115.89,35.34 114.78,34.24 110.01,34.24 108.52,32.74 105.97,32.74 105.18,31.95 96.95,31.95 96.47,32.43 96.01,32.43 94.66,33.78 75.11,33.78 74.17,32.84 66.85,32.84 66.44,33.25 66.44,33.45 66.25,33.64 66.05,33.64 65.87,33.83 65.87,34.03 65.68,34.21 65.48,34.21 65.15,34.54 65.15,34.85 65.28,34.98 65.28,35.26 65.15,35.39 65.15,35.67 65.28,35.79 65.28,36.07 65.15,36.2 65.15,36.48 65.28,36.61 65.28,36.89 65.15,37.01 65.15,37.29 65.28,37.42 65.28,37.7 65.15,37.83 65.15,38 65.83,38.68 65.83,39.25 v2(66.04,39.46)
  BOTTOM w0.076: 66.93,40.69 66.93,40.84 67.06,40.97 67.06,42.86 67.23,43.27 UU1.DL3
  BOTTOM w0.102: 66.93,40.69 66.93,40.51 66.5,40.08 66.01,40.08 65.83,39.9 65.83,39.67 v2(66.04,39.46)
USB2_P9_TS_DN: length 76.5
  ART06 w0.102: v2(67.66,41.58) 67.77,41.48 67.91,41.48 68.37,41.94 68.37,42.55 68.22,42.71 68.22,42.96 68.37,43.11 68.37,43.72 69.37,44.71 69.37,45.33 69.21,45.48 69.21,45.74 69.37,45.89 69.37,46.14 69.21,46.29 69.21,46.55 69.37,46.7 69.37,47.22 69.14,47.44 68.71,47.44 67.61,48.54 67.61,48.87 67.3,49.18 65.43,49.18 65.19,49.43 64.96,49.43 64.84,49.3 64.56,49.3 64.43,49.43 64.15,49.43 64.03,49.3 63.75,49.3 63.62,49.43 60.87,49.43 60.1,50.2 57.03,50.2 56.72,49.88 52.65,49.88 52.26,49.49 50.71,49.49 48.65,51.55 48.65,52.61 47.29,53.96 47.29,57.02 47.38,57.11 47.38,58.66 44.21,61.83 43.14,61.83 40.09,64.88 38.01,64.88 37.58,65.31 37.58,67.31 37.81,67.54 39.11,67.54 39.36,67.78 39.36,71.66 37.67,73.35 31.62,73.35 30.91,72.64 30.58,72.64 30.45,72.51 30.17,72.51 30.04,72.64 29.76,72.64 29.64,72.51 29.36,72.51 29.23,72.64 28.95,72.64 28.82,72.51 28.55,72.51 28.42,72.64 27.73,72.64 27.53,72.44 27.08,72.44 26.95,72.31 26.67,72.31 26.55,72.44 26.27,72.44 26.11,72.28 26.11,71.95 v1(26.38,71.69)
  BOTTOM w0.102: v1(26.38,71.69) 26.19,71.87 26.19,72.37 RX4.1 ; v2(67.66,41.58) 67.6,41.64 67.6,42.2 67.31,42.49 UU1.DL2
USB2_P9_TS_DN_R: length 2.5
  BOTTOM w0.102: JX1.20 25.7,74.65 25.56,74.51 25.56,74.22 26.19,73.58 26.19,73.27 RX4.2
USB2_P9_TS_DP: length 76.5
  ART06 w0.102: v2(67.41,41.07) 67.56,41.22 67.96,41.22 68.59,41.85 68.59,43.63 69.58,44.62 69.58,47.3 69.23,47.66 68.79,47.66 67.83,48.63 67.83,48.96 67.38,49.4 65.52,49.4 65.28,49.64 60.96,49.64 60.19,50.42 56.94,50.42 56.63,50.1 52.56,50.1 52.17,49.71 50.8,49.71 48.87,51.64 48.87,52.7 47.51,54.05 47.51,56.93 47.6,57.02 47.6,58.75 44.3,62.05 43.23,62.05 40.18,65.1 38.1,65.1 37.79,65.4 37.79,67.22 37.89,67.32 39.2,67.32 39.57,67.69 39.57,71.75 37.76,73.57 31.53,73.57 30.82,72.86 27.65,72.86 27.44,72.65 26.18,72.65 25.89,72.37 25.89,71.79 v1(25.79,71.69)
  BOTTOM w0.102: v1(25.79,71.69) 25.98,71.87 25.98,72.37 RX5.1 ; v2(67.41,41.07) 67.31,41.17 UU1.DL1
USB2_P9_TS_DP_R: length 2.5
  BOTTOM w0.102: RX5.2 25.98,73.27 25.98,73.49 25.34,74.13 25.34,74.49 25.2,74.63 JX1.19
USB2_P10_BT_DN: length 101.9
  ART03 w0.102: v1(142.29,30.25) 142.49,30.45 142.49,30.54 142.05,30.99 139.57,30.99 137.22,33.33 137.22,33.92 133.81,37.34 128.6,37.34 125.31,40.62 118.15,40.62 116.35,38.83 114.57,38.83 113.54,37.79 113.54,37.28 112.36,36.1 112.36,35.47 111.59,34.71 109.82,34.71 108.34,33.23 105.55,33.23 104.68,32.37 97.19,32.37 96.53,33.03 96.02,33.03 94.87,34.19 74.75,34.19 73.85,33.28 67.55,33.28 65.78,35.05 65.78,37.79 66.46,38.47 66.46,43.42 65.47,44.41 65.16,44.71 65.16,45.4 65.75,45.99 v2(65.75,46.07)
  BOTTOM w0.102: CHKW1.4 143.21,29.34 142.87,29.34 142.49,29.72 142.49,30.05 v1(142.29,30.25) ; UU1.DP10 66.05,46.36 v2(65.75,46.07)
USB2_P10_BT_DN_WIFI: length 2
  BOTTOM w0.102: JW1.5 144.99,29.2 144.83,29.36 144.13,29.36 CHKW1.1
USB2_P10_BT_DP: length 101.9
  ART03 w0.102: v1(142.87,30.25) 142.71,30.41 142.71,30.63 142.14,31.2 139.66,31.2 137.44,33.42 137.44,34.01 133.89,37.55 128.69,37.55 125.4,40.84 118.06,40.84 116.26,39.04 114.48,39.04 113.32,37.88 113.32,37.37 112.14,36.19 112.14,35.56 111.5,34.92 109.73,34.92 108.25,33.45 105.46,33.45 104.59,32.59 97.28,32.59 96.62,33.25 96.11,33.25 94.96,34.4 74.66,34.4 73.76,33.5 67.64,33.5 66,35.14 66,37.7 66.67,38.38 66.67,43.51 65.38,44.8 65.38,45.31 65.76,45.69 66.01,45.69 v2(66.39,46.07)
  BOTTOM w0.102: v2(66.39,46.07) 66.7,46.38 UU1.DN10 ; CHKW1.3 143.21,29.56 142.96,29.56 142.71,29.81 142.71,30.08 v1(142.87,30.25)
USB2_P10_BT_DP_WIFI: length 1.9
  BOTTOM w0.102: JW1.3 144.94,29.7 144.82,29.58 144.09,29.58 CHKW1.2
USB2_VBUSSENSE: length 1.2
  TOP w0.102: RU146.2 67.64,47.01 v2(67.64,46.99)
  BOTTOM w0.102: UU1.DL11 67.35,47.28 v2(67.64,46.99)
USB2P0_OC_N: length 3.7
  BOTTOM w0.102: JDB1.8 183.01,48.7 182.52,49.19 182.52,49.86 182.27,50.11 CB413.2 RB373.2
USB3_P1_RX_DN: length 53.1
  ART06 w0.114: v1(33.17,35.28) 33.37,35.48 36.42,35.48 39.93,38.99 47.35,38.99 48.29,39.93 49.41,39.93 50.58,41.09 51.53,41.09 53.34,42.9 57.91,42.9 58.14,42.67 60.63,42.67 61.54,43.58 67.63,43.58 68.79,44.74 68.79,44.96 v2(68.98,45.16)
  BOTTOM w0.114: v2(68.98,45.16) 68.65,45.5 UU1.DJ8 ; CHKB26.1 23.1,36.42 24.22,36.42 24.93,37.13 26.52,37.13 27.56,38.17 30.15,38.17 32.36,35.97 32.36,35.72 32.61,35.47 32.98,35.47 v1(33.17,35.28)
USB3_P1_RX_DP: length 53.1
  ART06 w0.114: v2(68.4,45.16) 68.57,44.99 68.57,44.83 67.54,43.8 61.45,43.8 60.54,42.89 58.23,42.89 58,43.11 53.25,43.11 51.45,41.31 50.49,41.31 49.32,40.14 48.2,40.14 47.26,39.2 39.84,39.2 36.9,36.27 36.72,36.27 36.49,36.03 36.49,35.85 36.33,35.7 35.6,35.7 35.46,35.84 35.14,35.84 35,35.7 34.68,35.7 34.54,35.84 34.22,35.84 34.08,35.7 33.36,35.7 v1(33.17,35.89)
  BOTTOM w0.114: UU1.DJ6 68.65,44.91 v2(68.4,45.16) ; v1(33.17,35.89) 32.98,35.7 32.7,35.7 32.59,35.81 32.59,36.07 30.25,38.4 27.46,38.4 26.42,37.36 24.84,37.36 24.13,36.65 23.13,36.65 CHKB26.2
USB3_P1_TX_DN: length 53
  ART06 w0.114: v1(33.17,36.56) 32.97,36.76 32.81,36.76 32.71,36.66 32.71,34.92 33.15,34.49 34.23,34.49 34.38,34.64 34.69,34.64 34.84,34.49 35.14,34.49 35.3,34.64 35.6,34.64 35.75,34.49 36.41,34.49 40.33,38.4 47.65,38.4 48.56,39.32 49.66,39.32 50.37,40.03 51.92,40.03 53.95,42.06 60.87,42.06 61.81,43 66.47,43 67.14,42.33 67.63,42.33 67.74,42.44 v2(67.74,42.59)
  BOTTOM w0.114: CB392.1 25.09,37.95 26.19,37.95 27.46,39.22 30.76,39.22 31.03,38.94 31.03,38.74 31.25,38.52 31.46,38.52 31.68,38.3 31.68,38.09 31.9,37.87 32.1,37.87 32.41,37.56 32.41,37.08 32.71,36.78 32.95,36.78 v1(33.17,36.56) ; UU1.DJ2 68.32,42.59 v2(67.74,42.59)
USB3_P1_TX_DN_C: length 1.6
  BOTTOM w0.114: CHKB27.1 23.1,37.79 23.87,37.79 24.05,37.97 24.26,37.97 CB392.2
USB3_P1_TX_DP: length 53
  ART06 w0.114: v1(33.17,37.17) 32.98,36.98 32.73,36.98 32.5,36.75 32.5,34.83 33.06,34.27 36.5,34.27 40.41,38.19 47.74,38.19 48.65,39.1 49.74,39.1 50.46,39.81 52.01,39.81 54.04,41.84 60.96,41.84 61.9,42.78 66.38,42.78 67.05,42.11 v2(67.97,42.11)
  BOTTOM w0.114: v2(67.97,42.11) 68.38,42.11 UU1.DJ1 ; v1(33.17,37.17) 33.01,37.01 32.81,37.01 32.64,37.18 32.64,37.66 30.85,39.44 27.36,39.44 26.09,38.17 25.12,38.17 CB394.1
USB3_P1_TX_DP_C: length 1.6
  BOTTOM w0.114: CB394.2 24.28,38.2 23.96,38.2 23.78,38.02 23.13,38.02 CHKB27.2
USB3_RXN1_R: length 9.9
  BOTTOM w0.114: CHKB26.4 22.33,36.45 22.05,36.45 21.84,36.24 21.36,36.24 21.21,36.39 21.05,36.39 20.92,36.26 ESDB34.5 ESDB34.6 19.74,36.26 19.61,36.39 19.27,36.39 16.91,34.03 16.23,34.03 15.53,33.34 15.09,33.34 14.98,33.22 JB8.5
USB3_RXP1_R: length 9.9
  BOTTOM w0.114: CHKB26.3 22.36,36.68 21.95,36.68 21.74,36.47 21.46,36.47 21.3,36.62 21.08,36.62 20.95,36.76 ESDB34.4 ESDB34.7 19.77,36.76 19.63,36.62 19.17,36.62 16.81,34.26 16.13,34.26 15.44,33.57 15.09,33.57 14.98,33.68 JB8.6
USB3_TXN1_R: length 9.2
  BOTTOM w0.114: JB8.8 14.98,39.22 15.09,39.34 15.42,39.34 15.92,38.83 17.99,38.83 18.93,37.9 19.61,37.9 19.74,37.76 ESDB34.9 ESDB34.2 20.92,37.76 21.05,37.9 21.26,37.9 21.45,37.7 21.98,37.7 22.1,37.82 22.33,37.82 CHKB27.4
USB3_TXP1_R: length 9.2
  BOTTOM w0.114: JB8.9 14.98,39.68 15.09,39.57 15.52,39.57 16.02,39.06 18.08,39.06 19.02,38.12 19.63,38.12 19.77,38.26 ESDB34.10 ESDB34.1 20.95,38.26 21.08,38.12 21.35,38.12 21.54,37.93 21.89,37.93 22,38.05 22.36,38.05 CHKB27.3
USB_OC0: length 53.3
  TOP w0.102: RU150.2 RU145.1 61.87,47.88 v2(62.16,48.16) ; RB51.1 24.41,32.76 25.65,31.52 28.4,31.52 29.26,32.38 29.26,34.54 v3(31.05,36.33) v1(32,37.28)
  ART06 w0.102: v1(32,37.28) 31.46,37.83 31.46,41.38 32.14,42.06 44.39,42.06 46.53,44.2 46.53,44.86 47.41,45.74 48.82,45.74 50.39,47.32 51.81,47.32 53.33,48.83 59.4,48.83 60.42,47.8 61.8,47.8 v2(62.16,48.16)
  BOTTOM w0.102: v2(62.16,48.16) 62.52,48.52 UU1.DW14
USB_OC0_CH_R: length 2.5
  TOP w0.102: UB6.13 24.9,34.61 25.14,34.36 CB38.2 24.89,33.73 24.78,33.61 RB51.2
USB_OC1_N: length 1.3
  TOP w0.102: v2(75.14,61.72) 75.22,61.8 RU7.1
  BOTTOM w0.102: UU1.CR41 75.36,61.72 v2(75.14,61.72)
USB_OC2: length 39.2
  TOP w0.102: v3(56.54,86.38) 56.72,86.56 57.83,86.56 v2(58.37,87.09) ; TPU7.1 74.24,61.59 v2(74.24,61.57)
  ART06 w0.102: v2(58.37,87.09) 58.16,86.89 58.16,84.5 57.28,83.61 57.28,81.94 58.09,81.13 58.09,78.71 58.52,78.28 58.52,77.54 61.03,75.03 62.43,75.03 65,72.46 65,69.57 66.86,67.7 67.88,67.7 69.52,66.06 70.39,66.06 72.77,63.69 72.77,61.67 73.15,61.29 73.96,61.29 v2(74.24,61.57)
  BOTTOM w0.102: UU1.CT41 74.59,61.57 v2(74.24,61.57)
USB_OC3: length 226.3
  ART03 w0.089: v1(182.62,52.27) 183.13,52.27 184.4,53.54 185.4,53.54 189.39,57.53 189.39,91.35 187.48,93.27 184.3,93.27 183.64,93.93 171.55,93.93 168.63,91.01 164.46,91.01 161.03,87.58 138.12,87.58 136.17,89.53 135.38,89.53 134.87,90.04 133.17,90.04 132.71,90.5 130.25,90.5 129.08,91.67 128.62,91.67 126.49,93.79 v1(126.49,93.88)
  ART06 w0.102: v2(74.21,62.45) 73.99,62.67 73.16,62.67 73.02,62.81 73.02,63.7 70.41,66.32 69.57,66.32 67.99,67.89 67.05,67.89 65.28,69.67 65.28,72.54 62.46,75.36 61.11,75.36 58.9,77.57 58.9,78.43 58.44,78.89 58.44,81.46 58.04,81.86 58.04,82.75 v1(57.66,83.13) 57.66,83.49 58.42,84.25 58.42,86.54 59.89,88.01 59.89,89.05 60.2,89.35 60.2,91.06 59.82,91.44 59.82,93.51 62.74,96.44 124.48,96.44 126.49,94.43 v1(126.49,93.88)
  BOTTOM w0.102: v1(182.62,52.27) 182.62,52.4 182.27,52.75 v3(181.66,52.75) 181.61,52.7 RB373.1 ; UU1.CT43 74.39,62.45 v2(74.21,62.45) ; RU144.1 v1(57.66,83.13)
USB_P7_CAM_N: length 86.8
  ART06 w0.102: v2(66.34,46.99) 66.53,46.99 66.63,47.09 66.63,47.46 66.83,47.66 66.83,48.07 66.64,48.26 65.29,48.26 65.14,48.11 64.88,48.11 64.73,48.26 64.48,48.26 64.33,48.11 64.07,48.11 63.92,48.26 63.45,48.26 63.09,48.61 60.53,48.61 59.56,49.58 57.48,49.58 57.15,49.25 52.98,49.25 51.53,47.8 49.91,47.8 49.32,47.22 47.9,47.22 45.67,44.98 45.67,43.99 44.22,42.54 35.71,42.54 34.92,43.33 34.92,48.26 35.23,48.56 35.23,50.82 33.12,52.93 33.12,62.57 36.87,66.31 36.87,67.98 37.79,68.91 37.79,71.63 36.83,72.59 32.19,72.59 31.04,71.45 27.43,71.45 26.95,70.97 26.35,70.97 26.23,70.84 25.95,70.84 25.82,70.97 25.54,70.97 25.41,70.84 25.14,70.84 25.01,70.97 24.71,70.97 24.51,70.76 24.51,70.52 v1(24.73,70.3)
  BOTTOM w0.102: UU1.DP11 66.05,47.28 v2(66.34,46.99) ; CHKX5.2 24.54,71.81 24.54,70.49 v1(24.73,70.3)
USB_P7_CAM_P: length 86.9
  ART06 w0.102: v2(66.99,46.99) 66.84,47.13 66.84,47.37 67.04,47.57 67.04,48.16 66.73,48.47 63.54,48.47 63.18,48.83 60.62,48.83 59.65,49.79 57.39,49.79 57.06,49.46 52.89,49.46 51.45,48.02 49.82,48.02 49.24,47.43 47.81,47.43 45.45,45.07 45.45,44.08 44.13,42.76 35.8,42.76 35.14,43.42 35.14,48.17 35.44,48.47 35.44,50.91 33.34,53.02 33.34,62.48 37.08,66.22 37.08,67.89 38.01,68.82 38.01,71.71 36.92,72.81 32.1,72.81 30.96,71.66 27.34,71.66 26.86,71.18 24.62,71.18 24.29,70.85 24.29,70.46 v1(24.14,70.3)
  BOTTOM w0.102: v2(66.99,46.99) 66.7,47.28 UU1.DN11 ; v1(24.14,70.3) 24.32,70.49 24.32,71.81 CHKX5.1
USBP6_DN_CONN: length 9.4
  TOP w0.102: v2(17.78,37.28) 17.96,37.47 20.26,37.47 20.45,37.28 EDB5.1 20.95,37.28 21.14,37.47 21.53,37.47 21.99,37.01 22.13,37.01 CHKB25.3
  BOTTOM w0.102: JB8.2 16.48,36.51 16.68,36.31 17.94,36.31 18.29,36.65 18.29,37.32 18.13,37.47 17.96,37.47 v2(17.78,37.28)
USBP6_DP_CONN: length 9.4
  TOP w0.102: v2(17.78,37.87) 17.96,37.68 20.34,37.68 20.53,37.87 EDB3.1 21,37.87 21.19,37.68 21.62,37.68 22.08,37.22 22.18,37.22 CHKB25.4
  BOTTOM w0.102: v2(17.78,37.87) 17.96,37.68 18.22,37.68 18.5,37.41 18.5,36.56 18.03,36.09 16.96,36.09 16.48,35.61 JB8.3
VCORE: length 4.3
  TOP w0.076: v2(161.96,15.19) 161.96,15.23 UE1.K5
  TOP w0.102: CE43.1 160.83,12.85 v2(160.78,12.9)
  BOTTOM w0.102: v2(161.96,15.19) 161.96,14.08 v2(160.78,12.9)
VGA__CORE_LG1: length 17.7
  ART03 w0.508: v1(150.96,42.69) 152.55,44.28 160.46,44.28 163.16,41.59 v1(163.16,40.94)
  BOTTOM w0.203: PU802.19 163.39,40.71 v1(163.16,40.94)
  BOTTOM w0.305: v1(150.96,42.69) 150.76,42.49 PC864.1 150.42,43.2 150.73,43.52 151,43.52
VGA_CORE1_IN:
  vias: v3(157.27,48.69) v4(156.89,47.27) v4(156.89,46.33) v4(157.53,47.27) v4(157.58,46.33) v4(158.16,47.24) v4(158.21,46.33)
VGA_CORE2_IN:
  vias: v3(156.92,36.07) v4(156.19,37.73) v4(156.19,37.08) v4(156.99,37.73) v4(156.99,37.08) v4(157.79,37.73) v4(157.79,37.08)
VGA_CORE_BOOT1: length 2.2
  BOTTOM w0.203: PU802.1 164.81,42.33 164.46,42.67
  BOTTOM w0.508: PR815.1 164.46,42.67
VGA_CORE_BOOT1_R: length 1.7
  BOTTOM w0.305: PC818.1 163.57,44.93 163.83,45.18 PR815.2
VGA_CORE_BOOT2: length 4
  BOTTOM w0.203: PU802.15 164.81,38.54 164.48,38.21 163.81,38.21
  BOTTOM w0.508: 163.81,38.21 163.47,37.87 162.75,37.87 162.03,37.14 PR849.1
VGA_CORE_BOOT2_R: length 0.9
  BOTTOM w0.305: PC856.1 161.4,38.76 PR849.2
VGA_CORE_EN: length 2.4
  BOTTOM w0.203: PU802.3 165.61,42.55 165.96,42.9 v3(165.96,43.08) 166.06,43.18 PR820.2
VGA_CORE_LG2: length 10.4
  ART03 w0.508: v1(162.97,39.74) 162.66,40.05 v1(155.95,40.05)
  BOTTOM w0.203: PU802.17 163.13,39.91 v1(162.97,39.74)
  BOTTOM w0.305: PQ802.8 156.19,40.6 PC865.1 156.21,40.31 v1(155.95,40.05)
VGA_CORE_PGOOD: length 2.2
  BOTTOM w0.102: PU802.13 165.61,37.93 165.02,37.35 PR819.2
VGA_CORE_PHASE1: length 20.3
  TOP w0.508: v1(146.63,44.02) 146.99,43.66 PR833.2
  ART03 w0.508: v1(150.17,45.71) 150.57,45.31 160.86,45.31 v1(163.17,43)
  BOTTOM w0.203: 163.3,42.22 163.3,41.64 163.83,41.11 PU802.20
  BOTTOM w0.279: 148.28,48.33 148.28,49.45 v3(148.54,49.71) ; v1(163.17,43) 163.57,43.41 PC818.2
  BOTTOM w0.305: v1(163.17,43) 163.3,42.87 163.3,42.22
VGA_CORE_PHASE2: length 18
  TOP w0.279: v3(146.61,38.58) 146.61,39.44 v1(146.66,39.49)
  TOP w0.508: PR850.2 146.99,39.82 v1(146.66,39.49)
  ART03 w0.508: v1(150.46,38.34) 150.95,38.83 159.61,38.83 159.76,38.68 v1(163.02,38.68)
  BOTTOM w0.203: PU802.16 164.1,39.5 163.56,39.5 163.39,39.33
  BOTTOM w0.305: PC856.2 162.28,39.21 162.81,38.68 v1(163.02,38.68) 163.08,38.68 163.39,38.99 163.39,39.33
VGA_CORE_PSI: length 3.5
  BOTTOM w0.203: PU802.4 166.01,42.44 166.79,43.22 PC827.1 PR822.2 166.79,44.98 PR835.1
VGA_CORE_PVCC: length 2.9
  BOTTOM w0.203: 163.2,40.31 PU802.18
  BOTTOM w0.305: 163.2,40.31 162.41,40.31 PC824.1 162.27,41.42 PR816.1
VGA_CORE_PWM_VID: length 35.6
  TOP w0.102: v1(168.52,45.67) 168.52,44.55 167.86,43.89 162.84,43.89 v3(156.27,50.46) 153.31,53.41 151.13,53.41 150.24,54.3 148.21,54.3 144.91,57.6 v2(144.91,58.75)
  BOTTOM w0.102: PR823.1 v1(168.52,45.67) ; v2(144.91,58.75) 144.75,58.9 144.75,61.03 UV2.C6
VGA_CORE_REFADJ: length 3
  BOTTOM w0.203: PU802.6 167.45,41.11 169.2,42.86 PR830.2
VGA_CORE_REFADJ_R: length 0.5
  BOTTOM w0.203: PR829.1 PR830.1
VGA_CORE_REFADJ_R2: length 3.4
  BOTTOM w0.102: v3(169.52,45.59) 169.42,45.59 169.2,45.38 PR829.2
  BOTTOM w0.203: PR829.2 169.72,44.64 PR825.1 169.72,44.12 PC867.1 169.73,43.28 PR826.2
VGA_CORE_REFIN: length 4.7
  BOTTOM w0.203: PU802.7 167.78,40.71 v3(169,41.92) 169.61,42.53 PR826.1 PR839.2 PC868.1
VGA_CORE_REFIN_R: length 0.9
  BOTTOM w0.203: PR839.1 170.51,43.23 170.89,43.61 PR828.2
VGA_CORE_RGND: length 14.5
  TOP w0.102: v1(171.7,44.37) v3(172.51,44.37)
  ART06 w0.305: v1(171.7,44.37) 171.7,41.94 171.16,41.41 v1(170.98,41.41) 170.98,41.32 168.91,39.24 v1(168.04,39.24)
  BOTTOM w0.203: PC867.2 170.41,44.11 170.67,44.37 v1(171.7,44.37) 171.68,44.35 PR828.1 171.68,43.32 171.4,43.04 PC868.2 ; PU802.10 167.78,39.51 v1(168.04,39.24) 168.43,38.85 PR836.1 168.85,38.85 PR837.2 ; v1(170.98,41.41) 170.94,41.45 PC844.1
VGA_CORE_SNB1: length 3
  TOP w0.508: PC830.2 149.16,42.85 PR833.1 v3(148.77,44.47)
VGA_CORE_SNB2: length 2.6
  TOP w0.508: v3(148.77,39.14) PR850.1 PC855.2
VGA_CORE_SS: length 3.4
  BOTTOM w0.203: PC823.1 166.72,37.02 PR859.1 PC887.1 ; PC823.1 PR852.2 ; PC823.1 166.2,37.7 166.01,37.89 PU802.12
VGA_CORE_TON: length 1.9
  BOTTOM w0.203: PU802.9 168.35,39.91 PR818.1
VGA_CORE_TON_R: length 2.9
  BOTTOM w0.102: v3(170.23,38.38) 170.01,38.6 PC825.1
  BOTTOM w0.305: PR818.2 169.97,39.41 PC825.1
  BOTTOM w0.508: PC825.1 170.01,40.07 169.94,40.14 PR817.1
VGA_CORE_UG1: length 19.1
  TOP w0.508: v4(160.02,50.87) 160.02,47.95 162.79,45.18 v1(165.35,45.18)
  BOTTOM w0.203: 165.21,42.83 PU802.2
  BOTTOM w0.508: v1(165.35,45.18) 165.35,43.38 165.21,43.23 165.21,42.83 ; v4(160.02,50.87) v3(158.52,50.87) 157.61,50.87 157.3,50.57 PR814.1
VGA_CORE_UG1_R: length 2.6
  BOTTOM w0.508: 151,49.19 151,49.98 v3(151.45,50.43) 151.59,50.57 PR814.2
VGA_CORE_UG2: length 2.7
  BOTTOM w0.203: PU802.14 165.21,38.3 164.62,37.72
  BOTTOM w0.508: 164.62,37.72 164.11,37.2 PR848.1
VGA_CORE_UG2_R: length 9.9
  TOP w0.102: v1(155.7,35.13) 155.7,35.38 v3(155.04,36.04)
  ART03 w0.508: v1(155.7,35.13) 156.79,36.21 v4(161.93,36.21)
  BOTTOM w0.508: PQ802.1 155.51,34.93 v1(155.7,35.13) ; PR848.2 162.43,36.21 v4(161.93,36.21)
VGA_CORE_VID: length 3.8
  BOTTOM w0.203: PU802.5 166.41,42.24 166.84,42.68 167.43,42.68 167.64,42.88 v3(167.64,42.9) 167.84,43.1 PC828.1 168.35,43.87 PR823.2
VGA_CORE_VREF: length 3.9
  BOTTOM w0.203: PU802.8 168.3,40.31 v3(168.53,40.54) 169.44,41.45 PC844.2 PR824.2
VGA_CORE_VREF_R: length 4.7
  ART06 w0.254: v1(171.24,44.93) 171.01,44.69 171.01,42.03 v1(170.98,42)
  BOTTOM w0.203: PR825.2 170.32,44.73 171.04,44.73 v1(171.24,44.93) ; v1(170.98,42) 170.96,41.98 PR824.1
VGA_CORE_VSNS: length 6.3
  BOTTOM w0.203: PR861.1 168.99,36.51 168.99,36.51 ; 167.93,36.51 PR860.2 PR827.1 168.99,36.51 ; 167.93,36.51 PC887.2 167.23,36.49 PC863.2 ; 167.93,36.51 v3(167.93,37.67) 167.75,37.84 166.8,37.84 166.41,38.24 PU802.11 ; 168.99,36.51 PR838.2
VGA_SMB_CK2: length 18.1
  ART05 w0.102: v1(148,61.81) 147.59,61.4 147.36,61.4 147.19,61.23 146.74,61.23 145.67,62.3 143.89,62.3 143,61.41 143,56.27 142.21,55.48 142.21,53.79 142.7,53.31 v1(142.93,53.31)
  BOTTOM w0.102: v1(142.93,53.31) 142.88,53.26 142.44,53.26 RV19.1 142.38,52.78 RV24.2 142.92,52.77 CV193.1 143.85,52.76 QV3.4 ; v1(148,61.81) 147.62,62.19 UV2.D9
VGA_SMB_DA2: length 24
  TOP w0.102: v3(147.62,50.98) 147.44,50.98 146.76,51.65 v2(146.52,51.65)
  ART05 w0.102: v1(147.19,61.8) 147.19,61.56 147.09,61.46 146.83,61.46 145.76,62.53 143.79,62.53 142.77,61.51 142.77,56.36 141.98,55.57 141.98,53.61 142.82,52.78 145.39,52.78 v2(146.52,51.65)
  BOTTOM w0.102: v1(147.19,61.8) 146.78,62.21 UV2.D8 ; RV26.2 146.27,51.85 146.32,51.85 v2(146.52,51.65) 146.57,51.6 RV20.1 CV194.1 146.03,50.85 QV3.1
VR_PSYS: length 3
  TOP w0.191: PU601.9 102.48,23.19 102.23,23.44 102.23,23.57
  TOP w0.254: PR660.2 101.85,25.47 102.23,25.09 102.23,23.57
VR_READY: length 5.7
  TOP w0.191: 109.09,17.47 108.46,18.11 107.57,18.11 106.17,19.5 PU601.24
  TOP w0.254: v3(110.69,17.47) 110.68,17.49 PR659.2 109.1,17.49 109.09,17.47
VR_SVID_ALERT_N: length 2.3
  TOP w0.102: PU601.3 105.37,24.4 106.42,25.45 PR657.2
VR_SVID_DATA: length 2.3
  TOP w0.102: PU601.4 104.97,24.53 105.92,25.47 PR656.2
VR_SVID_VCLK: length 2.2
  TOP w0.102: PR649.2 105.41,25.47 104.57,24.64 PU601.5
VREFP: length 2.6
  TOP w0.203: CA69.1 178.98,29.03 177.14,29.03 177.07,28.97 UA2.40
VTT_EN: length 3.7
  BOTTOM w0.102: PU701.10 44.62,82.43 44.47,82.57 43.89,82.57 42.57,83.89 PR707.2 42.07,83.98 PR702.2
WAKE_PCH_N: length 152.4
  TOP w0.102: v2(64.01,66.88) 62.66,66.88 57.05,72.49 v3(57.05,73.76) 57.05,75.28 56.56,75.77 RU155.1
  ART05 w0.102: v2(141.1,30.55) 141.1,30.73 140.61,31.21 134.57,31.21 133.6,32.18 129.49,32.18 128.73,32.94 127.56,32.94 125.73,34.77 111.25,34.77 110.69,34.21 110.03,34.21 108.86,33.04 102.16,33.04 101.62,32.51 96.72,32.51 94.46,34.77 67.84,34.77 63.7,38.91 63.7,41.96 62.81,42.85 62.81,47.27 62.53,47.55 62.53,48.59 62.33,48.79 62.07,48.79 60.55,50.31 60.55,55.67 60.04,56.18 60.04,62.02 60.68,62.66 60.68,64.28 61.26,64.87 61.49,64.87 61.83,65.21 61.83,65.57 63.14,66.88 v2(64.01,66.88)
  ART06 w0.102: v1(142.44,16.58) 143.25,16.58 145.18,18.51 145.18,19.33 144.07,20.44 144.07,24 144.68,24.61 144.68,26.29 141.68,29.28 141.68,29.97 v2(141.1,30.55)
  BOTTOM w0.102: v1(142.44,16.58) 142.49,16.53 RW57.1 ; UU1.DL45 67.43,63.84 66.6,64.67 66.6,65.94 66.42,66.11 66.34,66.11 65.58,66.88 v2(64.01,66.88)
WAKE_PCIE_N_SOC: length 163.1
  TOP w0.102: v2(68.98,60.63) 68.98,60.78 68.68,61.08 67.23,61.08 RU229.1
  ART05 w0.102: v2(68.98,60.63) 68.98,60.58 69.34,60.22 69.34,59.46 69.49,59.31 69.8,59.31 70.1,59 70.1,58.39 70.71,57.78 70.71,55.09 70.64,55.01 70.64,54.07 71.3,53.41 71.3,50.38 70,49.09 70,47.01 71.19,45.82 71.19,43.69 71.93,42.95 79.96,42.95 80.26,42.64 82.17,42.64 82.62,42.19 84.99,42.19 85.27,42.47 95.91,42.47 96.16,42.72 100.58,42.72 100.81,42.95 111,42.95 111.66,43.61 114.98,43.61 116.1,44.73 126.9,44.73 127.25,44.37 128.47,44.37 129.23,43.61 131.98,43.61 134.34,41.25 134.34,38.68 v2(137.39,35.63)
  ART06 w0.102: v1(144.46,16.27) 145.49,17.29 145.49,29.18 143.66,31.01 140.21,31.01 137.67,33.55 137.67,34.16 137.39,34.44 v2(137.39,35.63) ; v1(59.43,88.36) 59.13,88.06 57.66,88.06 57.38,88.34 55.9,88.34 55.42,87.86 55.42,83.97 55.7,83.69 55.7,78.99 55.37,78.66 55.37,74.5 55.88,73.99 55.88,72.46 62.05,66.29 63.19,66.29 63.88,65.61 63.88,64.31 66.14,62.05 69.04,62.05 69.34,61.74 69.34,61.39 68.98,61.03 v2(68.98,60.63)
  BOTTOM w0.102: v1(59.43,88.36) 59.43,88.31 59.54,88.21 RU130.2 ; v1(144.46,16.27) 143.66,15.47 RW68.1
WAKE_PCIE_N_SOC_H2: length 3.1
  TOP w0.102: RU50.1 RU58.2 67.13,60.68 RU229.2 67.54,60.27 68.12,60.27 68.32,60.47 v2(68.32,60.62)
  BOTTOM w0.102: UU1.DJ38 v2(68.32,60.62)
WAKE_PCIE_N_SOC_R: length 34.9
  BOTTOM w0.102: UU1.CC49 81.24,66.51 80.69,67.05 80.69,67.51 79.8,68.4 78.68,68.4 72.94,74.14 69.52,74.14 67.64,76.02 v3(67.08,76.02) 64.95,78.15 60.91,78.15 60.7,78.36 60.7,80.21 61.09,80.59 61.09,82.6 59.99,83.69 59.99,84.86 59.56,85.29 59.56,85.95 RU130.1
WLAN_COEX1: length 6.2
  TOP w0.102: v3(147.52,18.36) TPW1.1 149.25,18.36 v1(149.3,18.31)
  BOTTOM w0.102: JW1.48 152.55,18.45 152.13,18.88 149.87,18.88 v1(149.3,18.31)
WLAN_COEX2: length 6.1
  TOP w0.102: TPW2.1 148.94,18.95 v1(149.32,18.95) 149.48,18.95 v3(149.86,18.56)
  BOTTOM w0.102: v1(149.32,18.95) 149.5,19.12 152.29,19.12 152.46,18.95 JW1.46
WLAN_COEX3: length 3.4
  TOP w0.102: RW64.2 150.57,20.09 v1(150.67,19.99)
  BOTTOM w0.102: v1(150.67,19.99) 151.21,19.45 JW1.44
WLAN_OFF_N_WIFI: length 3.8
  TOP w0.102: v3(152.5,15.9) 152.42,15.97 v1(151.97,15.97) 151.65,15.66 151.65,15.43 RW59.1 RW6.2
  BOTTOM w0.102: v1(151.97,15.97) 152.44,16.45 JW1.56
WLAN_RST_N: length 113
  TOP w0.102: v2(148.72,17.6) 148.97,17.35 v3(149.25,17.35) 150.72,17.35 RW22.1
  ART05 w0.102: v2(67.7,52.43) 67.7,52.16 68.02,51.84 68.02,51.2 67.89,51.08 67.89,50.29 68.07,50.11 68.58,50.11 69.62,49.07 69.62,46.38 70.2,45.79 70.2,43.89 71.8,42.29 79.65,42.29 80.47,41.48 86.76,41.48 87.25,41.96 95.98,41.96 96.34,42.31 100.79,42.31 100.99,42.52 111.28,42.52 111.61,42.19 114.65,42.19 116.58,44.12 126.64,44.12 126.97,43.79 127.84,43.79 127.96,43.66 127.96,43 128.67,42.29 132.13,42.29 133.2,41.22 133.2,38.48 136.95,34.72 137.62,34.72 v1(138.48,33.86)
  ART06 w0.102: v1(138.48,33.86) 138.48,33.3 140.51,31.26 143.71,31.26 145.84,29.13 145.84,18.82 146.45,18.21 148.11,18.21 v2(148.72,17.6)
  BOTTOM w0.102: UU1.DL21 67.35,52.08 v2(67.7,52.43)
WLAN_RST_R_N: length 4.2
  TOP w0.102: v3(152.65,18.36) 152.12,17.83 v1(152.02,17.83) 152.02,17.83 151.83,18.02 151.35,18.02 CW15.1 RW22.2 RW21.2
  BOTTOM w0.102: JW1.52 152.37,17.45 152.02,17.8 v1(152.02,17.83)
XCLK_BIASREF: length 6.6
  BOTTOM w0.102: RU88.2 59.74,43.51 v3(59.79,43.46) 60.94,43.46 62.31,44.83 64.33,44.83 UU1.DU6
XRES_PD: length 5.6
  BOTTOM w0.102: UT1.10 48.21,34.36 49.02,33.55 49.45,33.55 v3(49.5,33.5) 49.53,33.47 CT9.1 RT18.2 50.42,32.2 TPT3.1
XTAL_32K_SOC_IN: length 8.4
  BOTTOM w0.076: UU1.DL48 67.45,65.37 67.71,65.63 67.71,65.95 67.67,66 67.67,66.52 66.67,67.51 66.5,67.51 66.39,67.62 66.37,67.62
  BOTTOM w0.102: 66.37,67.62 65.02,68.96 65.02,71.7 RU82.1
XTAL_32K_SOC_OUT: length 7.7
  BOTTOM w0.076: 67.45,65.79 67.49,65.82 67.49,66.44 66.6,67.33 66.29,67.33
  BOTTOM w0.102: 66.29,67.33 64.64,68.98 v3(64.64,69.52) 64.64,69.82 64.59,69.87 63.85,69.87 63.75,69.97 63.75,70.23 63.85,70.33 64.46,70.33 64.64,70.51 RU83.1
XTAL_38P4M_SOC_IN: length 5.4
  BOTTOM w0.102: RU85.1 59,45.16 59.18,45.34 59.69,45.34 59.89,45.13 59.89,44.88 v3(59.94,44.83) 60.45,44.83 60.78,45.16 61.34,45.16 62.18,46 63.17,46 UU1.DW8
XTAL_38P4M_SOC_OUT: length 6.8
  BOTTOM w0.102: UU1.DU8 64.24,46.23 62.12,46.23 61.31,45.41 60.12,45.41 58.85,46.68 RU86.1
XTAL_IN: length 4.8
  BOTTOM w0.102: YV1.1 149,52.09 148.69,52.4 148.69,53.98 CV47.1 148.74,54.39 148.74,55.24 RV62.1 148.74,55.55 148.74,55.77 RV58.1
XTAL_OUT: length 3.3
  BOTTOM w0.102: YV1.3 148.47,53.65 148.47,54.06 CV48.2 148.52,54.41 148.52,55.26 RV62.2 148.52,55.53 148.52,55.76 RV59.2
XTAL_TCP0_25MHZ_IN: length 5.6
  TOP w0.076: 23.87,26.46 24.02,26.32 24.02,25.87 UT2.L9
  TOP w0.102: 23.87,26.46 23.87,26.95 23.57,27.25 23.11,27.25 22.96,27.4 RT67.1 CT28.1 22.86,28.06 22.86,28.65 22.69,28.82 XT1.1
XTAL_TCP0_25MHZ_OUT: length 5.6
  TOP w0.102: UT2.M9 24.25,26.37 24.13,26.49 24.13,27.1 24,27.23 24,27.63 RT67.2 23.47,27.76 23.11,28.12 23.11,29.54 XT1.3
XTALOUT: length 3.3
  TOP w0.102: RV55.2 148.4,62.4 148.4,61.61 148.03,61.24 v1(148.03,61.03) 148.46,61.03 148.59,61.16 RV60.1
  BOTTOM w0.102: UV2.C10 v1(148.03,61.03)
XTALSSIN: length 2.6
  TOP w0.102: RV57.2 147.83,59.89 148.42,59.3 v1(148.42,58.99)
  BOTTOM w0.102: UV2.A10 v1(148.42,58.99)
ZQ0_CHA_0: length 1.5
  TOP w0.254: RD3.1 68.02,92.93 v1(67.49,93.46)
  BOTTOM w0.229: UD1.A5 v1(67.49,93.46)
ZQ0_CHA_1: length 2.3
  TOP w0.254: RD5.1 86.23,92.37 v1(85.14,93.46)
  BOTTOM w0.229: UD2.A5 v1(85.14,93.46)
ZQ0_CHB_0: length 2.4
  TOP w0.254: v1(102.76,93.58) 103.35,93 RD7.1
  BOTTOM w0.102: UD3.A5 v1(102.76,93.58)
ZQ0_CHB_1: length 1.6
  TOP w0.254: v1(121.22,93.58) 121.36,93.44 RD9.1
  BOTTOM w0.102: UD4.A5 v1(121.22,93.58)
ZQ1_CHA_0: length 1.8
  TOP w0.254: RD4.1 66.42,92.9 v1(65.86,93.46)
  BOTTOM w0.102: UD1.A8 v1(65.86,93.46)
ZQ1_CHA_1: length 2.2
  TOP w0.254: RD6.1 84.07,92.9 v1(83.51,93.46)
  BOTTOM w0.102: UD2.A8 v1(83.51,93.46)
ZQ1_CHB_0: length 1.5
  TOP w0.254: RD8.1 100.58,92.87 v1(101.17,93.46)
  BOTTOM w0.102: UD3.A8 v1(101.17,93.46)
ZQ1_CHB_1: length 2.1
  TOP w0.254: RD10.1 118.24,92.28 118.24,92.88 v1(118.82,93.46)
  BOTTOM w0.229: UD4.A8 v1(118.82,93.46)
N22527524: length 4.8
  BOTTOM w0.102: QV1.1 136.48,81.63 CV30.1 RV7.1 137.18,82.8 137.29,82.9 137.89,82.9 138.43,83.44 v3(138.43,84.86)
N22528692: length 2.8
  BOTTOM w0.102: RV17.2 144.52,50.1 QV3.2 QV3.5
N22791316: length 2.6
  TOP w0.102: v3(143.41,49.25) 143.36,49.25 142.45,50.15 RV138.1 142.31,50.05 141.92,50.05 CV32.1 141.83,50.14 QV2.1
N22799047:
  vias: v3(168.15,88.11)
N24199060: length 2.1
  TOP w0.102: v3(179.53,57.83) 179.78,58.09 CV120.1 179.79,58.75 RV104.2 RV107.2
N24199064: length 2.6
  TOP w0.102: v1(181.33,63.55) 181.47,63.42 RV97.2 182.03,64.52 v3(181.91,64.64)
  BOTTOM w0.165: UV3.J10 181.33,63.4 v1(181.33,63.55)
N24199148: length 2
  TOP w0.102: v3(181.66,70.33) 181.66,70.34 v1(181.16,70.83) 180.97,71.03 RV96.2
  BOTTOM w0.107: v1(181.16,70.83) 180.99,70.66 180.99,70.3 UV3.J1
N24199191: length 2.3
  TOP w0.102: v1(181.43,60.26) 181.74,60.56 181.74,61.41 182.02,61.7 RV99.1
  BOTTOM w0.165: UV3.J13 v1(181.43,60.26)
N24199421: length 2.7
  TOP w0.102: v3(181.68,90.78) RV109.2 RV106.2 180.71,89.86 180.59,89.74 CV121.1
N24199628: length 2.2
  TOP w0.102: v3(180.92,77.09) RV141.2 180.92,78.57 v1(180.97,78.62)
  BOTTOM w0.102: v1(180.97,78.62) 181.01,78.66 UV4.J1
N24199642: length 2.3
  TOP w0.102: RV98.2 182.24,85.54 v3(181.93,85.86) 181.75,86.04 v1(181.41,86.04)
  BOTTOM w0.165: UV4.J10 v1(181.41,86.04)
N24200206: length 3.2
  TOP w0.102: v3(181.96,56.31) 181.96,56.72 183.05,57.81 QV21.3
  TOP w0.279: RV102.1 182.87,58.51 QV21.3
N26347975: length 3.5
  TOP w0.102: QE3.3 70.89,6.35 70.74,6.5 RE61.2 RE62.1 RE58.2 69.98,7.97 70.25,8.25 v3(70.25,8.61)
N26347977: length 3.8
  TOP w0.102: v3(67.92,2.82) 68.68,2.82 69.21,3.35 RE57.2 RE63.2 ; QE3.6 69.33,4.64 69.21,4.52 RE63.2 ; RE63.2 RE64.1
N26542555: length 2.5
  TOP w0.102: RU174.2 48.87,6.17 v3(49.32,5.71)
  TOP w0.305: RU174.2 DU2.1
N27472427: length 2.6
  TOP w0.102: UU2.4 127.39,92.39 128.19,91.59 RU163.1 v3(129.13,91.26)
N28124431: length 6.4
  BOTTOM w0.279: v3(77.52,34.67) 78.1,35.25 DU1.2 79.16,35.13 RU166.2 ; RU164.1 CU35.1 78.99,36.68 RU162.2
  BOTTOM w0.305: DU1.2 79.16,35.92 79.02,36.07 RU162.2
N28274141: length 1.5
  BOTTOM w0.127: v3(71.22,29.08) 71.65,29.51 PR505.1
N28274396: length 0.6
  BOTTOM w0.254: PC508.2 PR523.1
N28274400: length 1.6
  BOTTOM w0.102: PC507.2 80.14,30.22 v3(80.24,30.33)
  BOTTOM w0.191: PC507.2 PR522.1
N28274553: length 1.6
  BOTTOM w0.191: PR509.2 75.44,28.52 75.59,28.37 PU501.1
N28605202: length 6.2
  TOP w0.102: PR635.1 98.22,22.81 96.21,24.81 v3(96.21,25.52)
  TOP w0.508: PR651.2 PR650.2 PR635.1
N28625550: length 1.5
  BOTTOM w0.102: v3(100.38,20.09) 100.43,20.04 PR664.1
  BOTTOM w0.254: PR664.1 PR634.1
N28767371: length 1.2
  BOTTOM w0.102: QV10.3 169.37,51.64 v3(168.65,51.64)
N28895297: length 2.9
  BOTTOM w0.165: RV100.1 181.56,91.22 181.41,91.06 181.41,89.24 UV4.J13
N29341240: length 2.9
  BOTTOM w0.102: PU903.6 41.02,67.05 40.36,67.71 PC976.1 PR920.2 PR904.2
N29341288: length 4.6
  BOTTOM w0.102: v3(38.05,71.75) 38.35,71.45 PC978.1 ; PC978.1 PR909.2 PR921.2 ; PC978.1 39.27,70.69 39.59,70.37 PU906.6
N29343591: length 4.5
  BOTTOM w0.279: PQ902.3 67.18,24.38 67.46,24.1 v3(67.82,24.1) 68.48,24.1 69.34,24.97 PR902.1 PQ901.1
N29655416: length 4.2
  TOP w0.102: v1(48.26,58.65) 48.26,59.87 48,60.12 PR917.2 PR906.2 v3(46.07,60.12)
  BOTTOM w0.102: v1(48.26,58.65) 48.09,58.81 PD907.1
N29997405: length 7.6
  BOTTOM w0.102: UV2.AE2 141.48,79.97 141.48,83.96 CV35.2 140.08,84.98 139.39,85.67 v3(139.39,85.98)
N31870830: length 2.8
  BOTTOM w0.102: RV50.1 134.32,57.52 QV8.3 134.44,57.41 QV23.3 135.11,58.29 QV7.1
N32026426: length 3
  TOP w0.279: RV6.2 128.01,86.63 DV2.2 126.86,85.63 v3(126.49,85.27)
N32026428: length 3.2
  TOP w0.254: DV1.1 132.74,85.64 132.49,85.89 RV5.2
  TOP w0.279: DV1.1 134.13,85.64 v3(134.57,86.08)
N32026933: length 3.7
  BOTTOM w0.203: RV32.1 134.11,52.5 135.13,53.52 QV4.6 135.13,54.21 135.33,54.41 135.63,54.41 135.78,54.27 QV4.5
N32027968: length 1.3
  TOP w0.102: DV7.1 130.4,80.89 RV23.2
N32028000: length 2.8
  TOP w0.279: v3(126.54,83.78) DV4.2 128.01,82.46 RV11.2
N32150852: length 1.5
  BOTTOM w0.102: RV43.1 CV37.1 139.1,53.72 DV9.1
N32261981: length 0.8
  BOTTOM w0.102: 129.84,75.71 129.84,76.22 v3(129.67,76.4)
N32264097: length 4.5
  BOTTOM w0.102: v3(130.86,83.49) 130.86,83.23 131.35,82.74 QV18.3
  BOTTOM w0.508: QV18.3 132.7,82.74 132.84,82.88 RV82.1
N32655790: length 2.4
  TOP w0.102: TPV5.1 151.03,62.2 150.08,62.2 v1(149.7,61.82)
  BOTTOM w0.102: UV2.D12 v1(149.7,61.82)
N32655853: length 1.2
  TOP w0.076: RV65.1 149.09,62.05 v1(148.85,61.81)
  BOTTOM w0.254: UV2.D11 v1(148.85,61.81)
N32655965: length 5.3
  BOTTOM w0.102: v3(143.51,85.16) 143.41,85.06 142.52,85.06 RV63.1 143.1,84.32 143.1,81.75 143.44,81.41 UV2.AG4
N32656019: length 9.8
  BOTTOM w0.076: 142.72,81.69 143.07,81.33 143.07,79.5 143.37,79.21 144.74,79.21 UV2.AD6
  BOTTOM w0.124: TPV4.1 141.43,85.08 142.72,83.78 142.72,81.69
N32656021: length 5.3
  BOTTOM w0.076: UV2.AF6 144.8,80.75 144.8,81.97
  BOTTOM w0.102: 144.8,81.97 144.8,82.52 145.16,82.88 145.16,85.29 TPV3.1
N32656023: length 7.6
  BOTTOM w0.076: 144.4,82.88 144.62,82.65 144.62,80.13 UV2.AE6
  BOTTOM w0.102: TPV2.1 144.4,86.56 144.4,82.88
N32656025: length 7.6
  BOTTOM w0.102: TPV1.1 144.12,85.82 144.12,84.35 143.78,84.01 143.78,80.12 UV2.AE5
N32684902: length 1.1
  TOP w0.254: v1(158.76,63.49) 158.75,63.48 RV94.1
  BOTTOM w0.254: UV2.F22 158.34,63.91 v1(158.76,63.49)
N32684905: length 1.2
  TOP w0.254: RV95.1 158.67,66.17 v1(158.83,66)
  BOTTOM w0.254: v1(158.83,66) 158.44,66.39 UV2.J22
N32687502: length 1.8
  TOP w0.305: RV53.1 145.47,69.23 v1(145.5,69.26) 145.53,69.23 CV45.1
  BOTTOM w0.305: UV2.N6 145.08,69.67 v1(145.5,69.26)
N32687710: length 22.1
  TOP w0.279: v1(149.69,63.42) 150.27,64.01 CV46.1
  TOP w0.381: RV52.1 136.13,57.59 138.94,60.4 v1(138.94,63.07)
  ART05 w0.381: v1(149.69,63.42) 148.48,63.42 148.08,63.83 148.08,64.46 147.45,65.1 139.95,65.1 138.94,64.08 v1(138.94,63.07)
  BOTTOM w0.305: UV2.F11 v1(149.69,63.42)
N32710606: length 5.5
  TOP w0.102: RV67.1 157.62,61.41 158.9,61.41 159,61.52 159,61.54 159.13,61.67 159.13,62.05 159.28,62.2 159.74,62.2 160.02,61.92 160.02,61.32 160.15,61.2 160.25,61.2 v1(160.44,61.01)
  BOTTOM w0.254: UV2.C24 160.44,61.01 v1(160.44,61.01)
N32710608: length 1.2
  TOP w0.254: v1(158.74,61.81) 158.69,61.86 RV66.1
  BOTTOM w0.254: v1(158.74,61.81) 158.34,62.21 UV2.D22
N32710622: length 7.2
  TOP w0.102: RV68.1 158.37,60.78 159.13,60.02 161.92,60.02 162.12,60.21 v1(162.86,60.21)
  BOTTOM w0.127: UV2.B25 161.24,60.21 v1(162.86,60.21)
N32724071: length 3
  TOP w0.102: TPE7.1 145.03,63.07 143.64,63.07 143.22,63.48 v1(143,63.48)
  BOTTOM w0.102: UV2.F4 v1(143,63.48)
N32724132: length 1.6
  TOP w0.102: v1(159.58,61.82) 159.38,61.62 TPE9.1
  BOTTOM w0.165: UV2.D23 v1(159.58,61.82)
N33004911: length 3.2
  BOTTOM w0.102: QV6.5 QV6.6 140.21,50.88 RV46.1 141.12,50.16 v3(141.68,49.6)
N33087941: length 1.6
  TOP w0.102: RV89.2 145.72,73.43 v1(146.27,73.43)
  BOTTOM w0.102: UV2.V7 145.88,73.82 v1(146.27,73.43)
N33091607: length 0.7
  BOTTOM w0.102: 129.13,85.11 v3(128.42,85.11)
N33196202: length 4.6
  BOTTOM w0.102: UV2.B10 148.03,60.23 148.03,57.78 148.51,57.3 148.51,56.63 RV59.1
N33196257: length 5.5
  BOTTOM w0.102: UV2.C11 148.87,61.03 148.87,58.87 148.46,58.47 148.46,57.64 148.72,57.38 148.72,56.65 RV58.2
N33504961: length 5.3
  TOP w0.102: RV10.2 131.2,82.87 DV3.2 131.2,84.24 131.62,84.66 134.52,84.66 v3(134.67,84.81)
N33775058: length 10.7
  TOP w0.102: QW3.3 145.45,13.94 v3(145.18,13.94) 144.42,13.18 142.7,13.18 141.68,14.2 RW23.1 141.22,13.94 141.22,13.64 v2(140.87,13.28)
  BOTTOM w0.102: UW1.4 138.62,13.04 138.94,12.72 140.31,12.72 v2(140.87,13.28)
N33775085: length 1.1
  TOP w0.102: RW26.2 145.24,16.96 QW3.2
N33775093: length 2.2
  TOP w0.102: QW3.1 146.75,16.85 146.35,17.24 RW25.2 RW27.2
N36191271: length 2.9
  TOP w0.102: v3(183.41,9.67) RE13.2 RE138.1 CE9.1 182.86,11.83 QE2.1
N37658617: length 5.6
  BOTTOM w0.102: US4.3 151.19,5.73 152.53,7.06 152.53,8.2 152.78,8.46 152.78,8.71 153.11,8.71 v3(153.62,9.22)
N37868722: length 7
  BOTTOM w0.102: RS1.1 66.8,8.58 66.8,7.74 67.16,7.39 v3(67.16,6.83) 67.46,6.53 67.82,6.53 69.39,4.95 US1.8
N37868745: length 7
  BOTTOM w0.102: US1.7 69.89,5.06 67.36,7.59 67.36,7.9 67.18,8.07 v3(67.18,8.2) 67.18,8.33 RS2.1
N38294621: length 4.5
  TOP w0.102: v3(26.62,81.61) 26.62,81.71 25.96,82.37 RX926.1 CX886.1 CX885.2 RX902.1 23.19,83 QX42.1
N38294628: length 4.7
  TOP w0.279: QX42.3 22.27,80.95 v3(24.43,80.95) ; v3(24.43,80.95) 24.43,80.69 24.89,80.24 SHX9.1 ; v3(24.43,80.95) 24.64,81.15 CX886.2
N38297214: length 15
  TOP w0.254: UF15.8 135.41,33.95 v4(135.38,33.98) CF11.1 ; 138.81,26.36 137.91,27.26 UF15.22
  TOP w0.279: 138.81,26.36 139.19,26.36 139.2,26.38 RF11.2 139.62,26.97 v1(139.6,27)
  BOTTOM w0.279: v4(135.38,33.98) 136.27,33.09 138.48,33.09 v3(138.89,32.69) 139.34,32.23 139.34,27.61 139.6,27.35 v1(139.6,27)
N38298094: length 4.2
  TOP w0.102: v3(133.81,26.69) 133.81,27.2 133.48,27.53 RF7.1 CF10.2 133.88,28.14 134.62,27.4 135.2,27.4 135.41,27.61 UF15.17
N38347014: length 1.8
  BOTTOM w0.102: RX908.1 29.97,68.91 29.52,69.35 UX1.3
N38465677: length 2.2
  TOP w0.102: v3(18.18,83.13) 18.18,82.06 18.32,81.93 PC135.1
N39299522: length 3.9
  TOP w0.076: 158.72,18.64 159.28,18.08 159.99,18.08 160.33,17.74 UE1.F1
  TOP w0.102: 158.72,18.64 158.7,18.67 158.7,18.77 158.09,19.38 157.99,19.38 157.71,19.66 RE98.2
N39375181: length 3
  BOTTOM w0.102: v3(24.59,63.47) 24.33,63.47 RI145.2 23.72,62.61 24.08,62.25 24.08,61.9 23.77,61.59 UI1.3
N39375197: length 3.5
  BOTTOM w0.102: UI1.4 25.96,62.41 26.16,62.61 v3(26.16,63.42)
  BOTTOM w0.254: UI1.4 26.82,61.59 27.18,61.24 RI34.2
N39375277: length 9.5
  TOP w0.102: v1(15.24,63.22) 13.87,63.22 v3(13.23,62.59) 12.32,61.67 12.32,59.32 JI1.13
  BOTTOM w0.102: RI144.1 16.61,62.96 16.36,63.22 v1(15.24,63.22)
N39472168: length 3
  TOP w0.203: CA58.1 179.21,25.52 v3(178.31,25.52) 177.24,25.52 177,25.77 UA2.32
N39472180: length 3.4
  TOP w0.203: CA59.1 179.06,24.31 v3(177.75,24.31) 177.75,24.33 176.71,25.37 UA2.31
N39472192: length 2
  TOP w0.203: UA2.29 175.47,23.66 175.12,23.3 CA60.1
N39472194: length 1.8
  TOP w0.203: UA2.30 175.87,23.72 175.91,23.68 CA60.2
N39472299: length 3.6
  TOP w0.203: 173.91,32.45 174.27,32.09 UA2.50
  TOP w0.381: FBA1.2 173.14,34.19 173.67,33.66 CA8.1 173.67,32.7 173.91,32.45
N39472656: length 2.2
  TOP w0.254: CA16.1 RA4.2 CA15.2 ; CA16.1 RA3.1 ; CA16.1 RA36.1
N39502644: length 2.8
  BOTTOM w0.102: RV245.2 RV244.2 133.64,62.63 DV16.2 134.53,62.02 RV250.2
N39574877: length 6.5
  BOTTOM w0.102: v3(15.54,15.52) 14.98,14.96 PR1013.1 CL33.1 15.14,13.64 QL8.3 15.14,12.82 14.83,12.52 13.84,12.52 12.84,11.51 QL7.1
N39574885: length 3.9
  BOTTOM w0.102: QL7.3 11.99,12.99 11.99,13.99 12.14,14.15 v3(12.95,14.15) 13.33,13.76 RL46.2 RL47.2
N39761277: length 2.3
  BOTTOM w0.102: v3(129.39,94.71) 129.94,94.71 130.71,93.95 130.71,93.29
N39761295: length 2
  BOTTOM w0.102: PR1202.2 129.87,90.55 PR1201.1 129.92,90.6 PU1201.3
N39761303: length 1.5
  BOTTOM w0.102: PR1206.2 130.29,91.83 130.72,91.4 PU1201.5
N39761317: length 1.4
  BOTTOM w0.102: PC1209.1 134.3,91.02 133.92,91.4 PU1201.10
N39761321: length 3.3
  BOTTOM w0.102: v3(136.09,91.01) 135.79,90.7 134.82,90.7 134.52,90.4 PC1210.1 133.86,90.35 133.61,90.6 PU1201.12
N39868508: length 7.9
  TOP w0.102: QL9.3 157.85,28.28 158.34,28.78 v3(158.34,29.33) ; QL9.3 157.85,27.62 157.72,27.49 QL4.1 157.72,26.1 158.19,25.63 159.92,25.63 160.02,25.52 QL6.3 ; QL9.3 157.64,28.18 157.38,27.91 RL45.2 CL32.1
N39868516: length 1.8
  TOP w0.102: QL9.1 159.05,28.01 RL2.2 CL1.1 RL1.1
N39869128: length 2.3
  BOTTOM w0.102: RX920.1 33.91,69.16 33.08,68.33 UX2.3
N39869300: length 4.7
  TOP w0.279: v3(33.01,68.56) 32.78,68.32 RX924.1 RX897.2 33.47,66.62 v4(33.65,66.43) RX925.1
  BOTTOM w0.279: UX2.5 v4(33.65,66.43)
N39890653: length 1.5
  BOTTOM w0.102: PR1150.1 171.44,37.71 170.84,37.11 v3(170.79,37.11)
  BOTTOM w0.254: PR1150.1 171.56,37.69 PC1150.2
N40069304: length 2.7
  TOP w0.102: LEDE2.1 179.68,4.54 179.06,4.54 v3(178.82,4.78) 178.56,5.04 178.56,5.33 RE456.2
N40080399: length 5.6
  TOP w0.102: DX1.2 28.38,64.19 29.06,63.52 30.99,63.52 v3(31.24,63.78) 31.49,64.03 RX105.1 RX922.2 RX923.2
N40120205: length 8.4
  TOP w0.102: RW63.1 150.47,26.49 149.96,25.98 RW66.2 149.96,25.68 149.81,25.52 149.4,25.52 148.84,24.97 148.84,23.49 149.2,23.14 149.71,23.14 150.16,22.68 v3(150.16,22.17) 150.16,21.46 150.06,21.36 RW67.1 RW64.1
N40277661: length 10.3
  TOP w0.102: v1(14.86,8.71) 15.75,9.6 v3(15.75,9.83) 15.75,10.36 15.3,10.8 QL10.1
  BOTTOM w0.102: SW4.2 14.74,5.04 14.86,5.15 14.86,6.3 14.62,6.54 SW4.1 13.78,6.95 14.17,7.34 14.17,7.85 14.02,8 PR6157.1 ; PR6157.1 14.3,8.15 v1(14.86,8.71) ; PR6157.1 13.6,8.15 RL454.2
N40277712: length 3.1
  TOP w0.305: v1(18.34,13.71) 17.96,13.71 17.22,12.98 16.62,12.98 QL10.3
  BOTTOM w0.254: RL455.2 18.59,13.46 v1(18.34,13.71)
N40346045: length 2.7
  TOP w0.102: DV6.1 134.49,80.16 RV18.1 135.06,81.63 v3(135.43,81.25)
N40380306: length 2.1
  BOTTOM w0.127: v3(167.59,34.77) 166.72,35.63 PC863.1
  BOTTOM w0.203: PC863.1 PR859.2
N40380331: length 1.6
  BOTTOM w0.102: v3(170.18,35) 170.05,35.13 PC888.1
  BOTTOM w0.203: PR861.2 170.03,35.98 PC888.1
N40381802: length 2.1
  BOTTOM w0.102: v3(131.45,95.78) PR1203.2 131.45,94.72 131.73,94.72 131.83,94.82 PU1202.3
N40385596: length 1.3
  BOTTOM w0.279: PR126.2 53.17,18.23 PC124.2
  vias: v3(53.52,24)
N40407372: length 10.1
  ART03 w0.203: v2(53.69,15.82) 53.34,15.47 52.78,15.47 51.74,16.51 51.74,19.94 51.66,20.01 v1(51.66,20.09)
  BOTTOM w0.203: v1(51.66,20.09) 51.66,20.11 51.78,20.23 51.78,21.75 51.61,21.92 PR106.3
  BOTTOM w0.254: PR107.2 53.69,15.4 v2(53.69,15.82)
N40407375: length 7.7
  ART03 w0.203: v2(53.08,15.87) 52.88,15.87 52.14,16.61 52.14,19.96 v1(52.27,20.09)
  BOTTOM w0.203: v1(52.27,20.09) 52.27,20.17 52.1,20.33 52.1,21.77 52.25,21.92 PR106.4
  BOTTOM w0.254: v2(53.08,15.87) 53.08,15.68 PR108.2
N40602816: length 1.5
  BOTTOM w0.102: UW1.3 138.62,10.24 RW70.2
N40716824: length 4.7
  TOP w0.102: v3(187.65,40.15) 185.42,42.39 185.42,42.69 185.11,43 RA242.2
  TOP w0.254: RA242.2 CA38.1
N40854310: length 1.7
  TOP w0.254: CA70.1 182.95,26.79 183.01,26.74 CA80.1 183.28,26.9 RA240.2
N40854356: length 1.3
  TOP w0.254: CA81.1 RA241.2 CA71.1
N40860467: length 1.5
  TOP w0.254: v3(186.99,43.91) CA75.1 RA243.2
N40860733: length 1.5
  TOP w0.102: CA76.1 v3(183.44,41.88)
  TOP w0.254: RA244.2 CA76.1
N40860762: length 2.4
  TOP w0.102: RA245.2 184.71,39.6 185.55,38.76 v3(185.55,38.63)
  TOP w0.254: RA245.2 CA77.1
N40897573: length 6.4
  TOP w0.102: UT2.A12 22.35,20.52 20.01,20.52 v3(18.45,18.96) 18.03,18.54 RT45.2
N40898959: length 4.3
  BOTTOM w0.127: v3(24.59,36.09) 24.89,35.79 25.6,35.79 25.86,35.53 RT73.2
  BOTTOM w0.305: RT73.2 RT68.2 26.8,35.58 26.8,36.46 DT1.2 26.8,36.58 27.33,37.11 RT130.1
N40901167: length 3.6
  TOP w0.102: UT7.6 11.26,8.9 11.07,8.71 10.46,8.71 10.31,8.56 9.52,8.56 RT116.1
N40901169: length 7
  TOP w0.102: RT114.1 8.3,10.61 7.64,9.95 7.64,9.4 v3(8.53,8.51) 8.68,8.35 10.44,8.35 10.59,8.51 11.33,8.51 11.66,8.84 UT7.7
N40901256: length 2
  TOP w0.102: CT66.1 9.52,11.5 9.52,11.28 9.93,10.87 UT7.3
N40901274: length 2.5
  TOP w0.102: RT117.1 12.44,7.85 12.14,7.54 v3(11.63,7.54)
  TOP w0.203: UT7.9 12.46,8.6 12.44,8.58 RT117.1
N40903466: length 2.7
  TOP w0.102: UT5.A3 22.4,12.02 v1(22.5,11.91) 22.71,11.91 v3(23.06,12.27)
  BOTTOM w0.102: RT93.2 RT96.2 22.65,12.06 v1(22.5,11.91)
N40903472: length 2.8
  BOTTOM w0.102: QT2.3 23.98,12.88 23.87,12.77 RT93.1
  BOTTOM w0.127: QT2.3 24.64,13.19 25.55,14.09 v3(25.6,14.09)
N40903516: length 5.8
  TOP w0.102: UT6.A3 30.59,7.53 30.83,7.29 31.34,7.29 31.49,7.44 31.49,8.2 v3(32,8.71) 32.36,8.71 32.71,9.07 QT4.3 32.71,11.25 RT102.1
N40903561: length 3.2
  TOP w0.127: v3(23.92,15.31) 23.16,15.31 22.45,16.02 21.89,16.02 CT57.2
N40903738: length 3.1
  TOP w0.102: RT99.1 RT103.2 29.36,9.32 v3(29.87,8.81) 30.06,8.62 UT6.B3
N40903809: length 2.4
  TOP w0.102: QT4.1 32.31,9.72 31.4,10.63 QT5.3 31.14,11.25 RT135.1
N40903829: length 2.1
  TOP w0.102: CT61.1 20.42,9.59 v3(20.42,10.39) 20.43,10.4 UT5.D4
N40903856: length 2.6
  TOP w0.102: RT104.1 22.65,6.53 QT3.1 ; RT104.1 RT100.2 ; RT104.1 21.69,6.53 v3(21.28,6.12)
N40906352: length 1.2
  TOP w0.203: UT2.J6 v2(25.07,25.19)
  BOTTOM w0.254: RT78.2 25.1,25.22 v2(25.07,25.19)
N40907251: length 1.1
  TOP w0.102: RU4.1 69.31,50.19 v2(69,50.51)
  BOTTOM w0.102: v2(69,50.51) 68.65,50.16 UU1.DJ17
N40908692: length 1.3
  TOP w0.102: TPU6.1 73.19,63.03 v2(73.39,63.03)
  BOTTOM w0.102: v2(73.39,63.03) 72.89,62.82 UU1.CY43
N40937500: length 3.3
  BOTTOM w0.102: RU83.2 RU81.1 CU7.1 62.96,71.07 62.1,70.2 YU1.1
N40937502: length 3.4
  BOTTOM w0.102: YU1.2 62.15,72.7 63.27,71.57 CU6.1 RU82.2
N40940127: length 3.3
  BOTTOM w0.102: RU86.2 CU9.1 RU87.2 58.04,45.67 57.66,45.29 57.25,45.29 57.06,45.48 YU2.1
N40940131: length 4.7
  BOTTOM w0.102: YU2.3 55.46,44.21 56.28,45.03 57.66,45.03 58.04,44.65 CU8.1 RU87.1 58.19,45.16 58.7,45.67 RU85.2
N40949670: length 1
  TOP w0.102: v2(69.73,59.84) 69.79,59.89 RU138.2
  BOTTOM w0.102: UU1.DF38 70.12,60.16 v2(69.73,59.84)
N40950306: length 1.1
  TOP w0.102: RU136.1 68.78,59.89 v2(68.97,59.7)
  BOTTOM w0.102: v2(68.97,59.7) UU1.DG36
N40973835: length 46.4
  ART03 w0.203: v1(97.79,24.71) 97.79,24.46 97.41,24.08 96.82,24.08 96.01,24.88 96.01,26.87 96.75,27.61 99.92,27.61 100.42,27.1 109.37,27.1 109.75,26.72 114.66,26.72 115.9,27.96 131.11,27.96 132.86,26.21 133.2,26.21 v2(133.35,26.36)
  BOTTOM w0.203: PRT602.2 132.95,26.36 v2(133.35,26.36)
  BOTTOM w0.381: v1(97.79,24.71) 97.92,24.58 v3(98.55,24.58) 99.01,24.58 99.03,24.61 PR652.1
N40976884: length 2.4
  TOP w0.381: PR642.2 PR640.1 108.06,15.96 108.76,15.26 v3(108.76,15.06)
N40976890: length 2.4
  TOP w0.254: PR647.2 PR645.1
  TOP w0.305: v3(100.33,15.21) 100.33,15.42 100.87,15.96 PR645.1
N40993976: length 2.2
  BOTTOM w0.102: PU902.10 21.04,44.43 20.88,44.27 20.47,44.27 20.09,44.65 PC912.1
N40993990: length 4
  BOTTOM w0.102: 29.59,45.54 29.58,45.53 PR913.2 29.32,44.52 v3(28.5,44.52) 28.14,44.52 27.86,44.8 PR915.1 PR911.1
N40994072: length 2
  BOTTOM w0.102: PU902.12 20.39,45.23 20.32,45.16 PC914.1
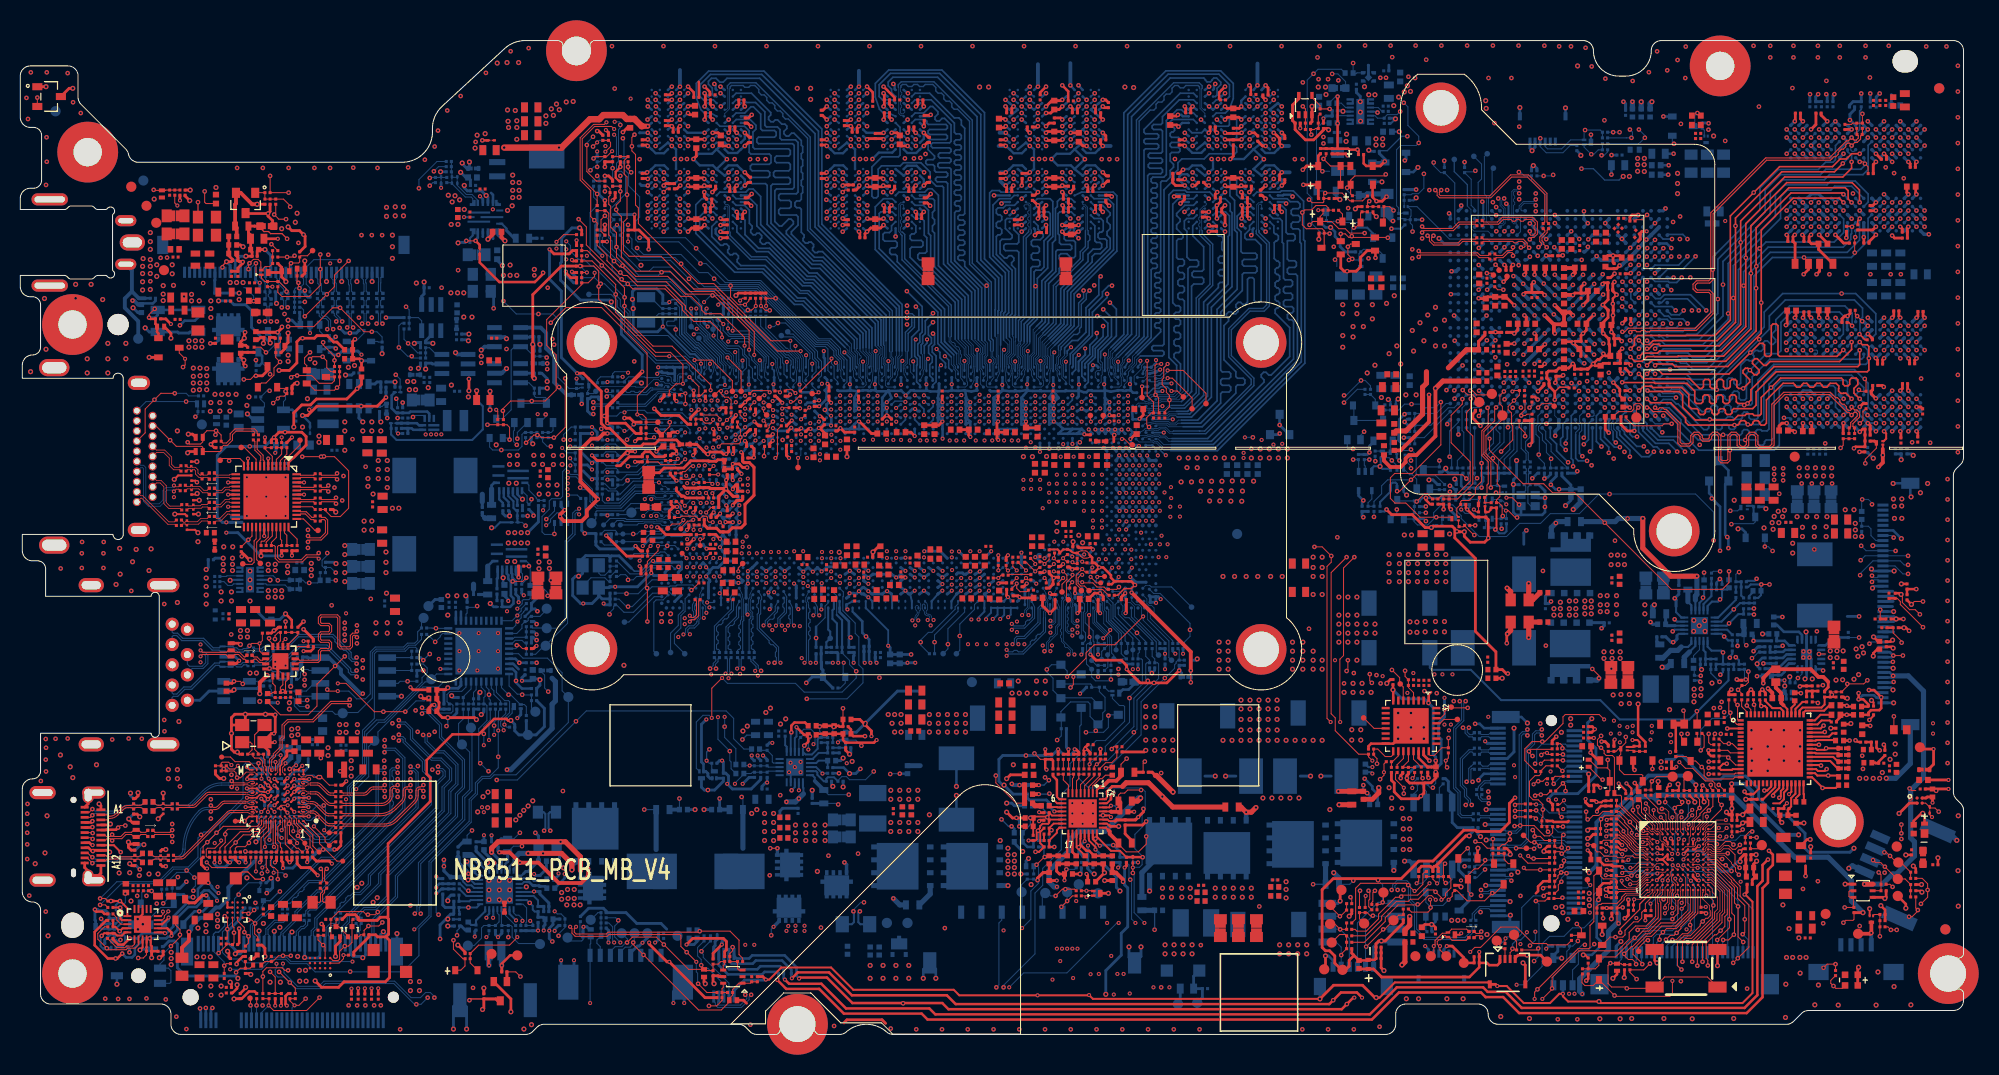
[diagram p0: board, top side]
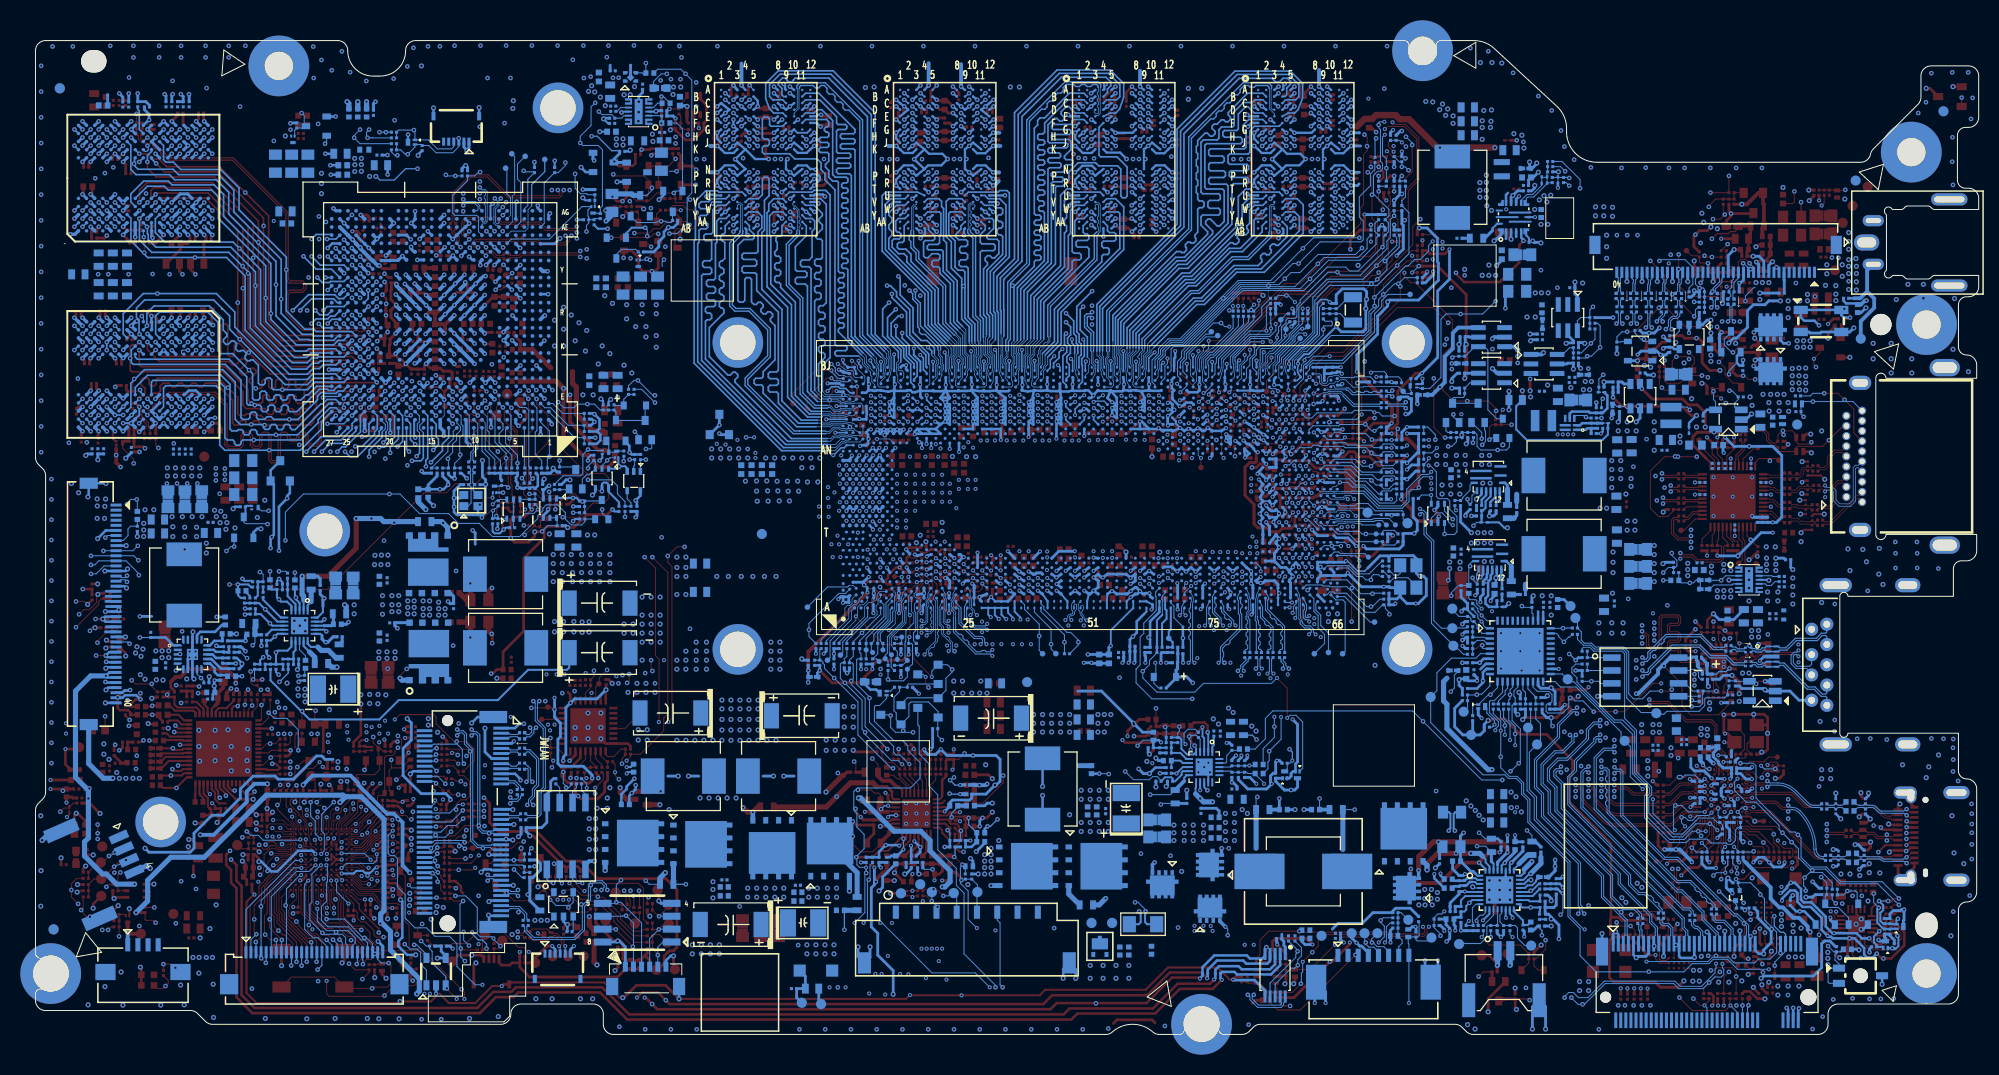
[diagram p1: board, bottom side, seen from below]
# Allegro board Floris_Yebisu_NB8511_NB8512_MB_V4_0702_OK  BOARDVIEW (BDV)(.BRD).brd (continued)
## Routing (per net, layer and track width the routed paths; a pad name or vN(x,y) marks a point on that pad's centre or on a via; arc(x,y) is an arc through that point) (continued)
N41005148: length 0.6
  TOP w0.191: PR662.2 PC608.1
N41005333: length 1.6
  BOTTOM w0.127: v3(101.04,17.5) 100.96,17.57 PR663.2
  BOTTOM w0.254: PR663.2 PC609.1
N41026409:
  vias: v3(64.92,46.1)
N41030628: length 3.5
  TOP w0.279: SHU5.1 70.2,55.75 CU45.1 70.23,56.21 v2(70.27,56.25) 70.89,56.25 71.25,55.9 v3(71.68,55.9)
  BOTTOM w0.254: v2(70.27,56.25) 70.6,56.58 UU1.DE31
N41033122: length 5.7
  TOP w0.102: PR205.2 v1(50.16,46.17)
  BOTTOM w0.102: PU201.6 49.92,46.67 50.16,46.43 v1(50.16,46.17) 50.29,46.05 PR202.2 50.3,44.27 PC216.1 51.31,44.27 52.02,43.56 v3(52.02,43.25)
N41095610: length 3.1
  TOP w0.102: v2(108.66,58.72) 108.89,58.72 109.47,58.14 TPU30.1
  BOTTOM w0.075: v2(108.66,58.72) 107.41,58.72 UU1.L34
N41104686: length 5.4
  BOTTOM w0.102: UU1.AV1 93.13,41.65 91.49,40 v3(91.49,38.48) 91.49,38.02 TPU32.1
N41104706: length 6
  BOTTOM w0.102: UU1.AT2 94.11,42.38 94.11,41.91 92.66,40.46 v3(92.66,39.29) 92.66,37.87 TPU33.1
N41104726: length 6.8
  BOTTOM w0.102: TPU37.1 64.51,38.55 64.51,39.44 65.15,40.08 65.15,41.3 65.57,41.72 65.57,42.96 UU1.DP3
N41104746: length 5.6
  BOTTOM w0.102: TPU39.1 64.13,39.57 64.9,40.33 64.9,41.35 65.38,41.83 65.38,42.5 UU1.DT2
N41108249: length 7.3
  TOP w0.102: v2(113.16,65.48) 114.68,65.48 116.94,63.22 TPU25.1
  BOTTOM w0.102: UU1.A47 112.48,64.68 113.16,65.35 v2(113.16,65.48)
N41108283: length 6.3
  TOP w0.102: TPU26.1 115.57,62.76 113.61,64.72 v2(113.16,64.72)
  BOTTOM w0.102: UU1.B47 111.51,64.36 112.14,64.36 112.24,64.46 112.9,64.46 v2(113.16,64.72)
N41108311: length 6.3
  BOTTOM w0.076: 110.88,42.06 111.19,41.75 111.19,40.9
  BOTTOM w0.102: 111.19,40.9 113.28,38.81 113.28,37.16 TPU28.1
N41108321: length 5.8
  BOTTOM w0.102: 109.58,42.06 109.58,41.16 112.04,38.71 112.04,37.64 TPU27.1
N41108351: length 2
  TOP w0.102: v2(76.71,56.84) TPU34.1
  BOTTOM w0.076: v2(76.71,56.84) 76.98,57.12 UU1.CM33
N41108361: length 2.4
  TOP w0.102: v2(70.81,45.67) 70.81,46 TPU35.1
  BOTTOM w0.102: UU1.DB10 71.29,46.49 70.81,46.02 v2(70.81,45.67)
N41108391: length 4.7
  BOTTOM w0.102: UU1.DW3 62.52,43.17 60.02,40.66 TPU36.1
N41108401: length 6.9
  BOTTOM w0.102: TPU38.1 62.48,37.79 62.48,42.62 62.71,42.85 63.4,42.85 63.41,42.86 UU1.DV3
N41320762: length 2.2
  TOP w0.102: RI33.2 27.3,48.84 26.46,49.69 UI2.36
N41326466: length 3.2
  TOP w0.102: TPI3.1 27.58,58.14 26.06,56.61 UI2.2
N41327429: length 2.6
  TOP w0.102: TPI5.1 22.1,57.88 23.26,56.73 UI2.9
N41327451: length 3
  TOP w0.102: UI2.12 22.06,56.4 21.66,56.79 19.89,56.79 TPI6.1
N41327606: length 2.6
  TOP w0.102: UI2.37 27.93,50.83 29.06,49.71 TPI7.1
N41327626: length 3.9
  TOP w0.102: TPI8.1 23.32,46.81 23.32,48.54 23.66,48.88 UI2.29
N41327646: length 4.8
  TOP w0.102: UI2.28 23.26,48.86 23.06,48.66 23.06,46.56 22.86,46.35 21.99,46.35 TPI9.1
N41360860: length 3.3
  TOP w0.102: v1(151.99,15.06) 151.69,14.75 151.69,14.25 151.36,13.92 RW73.2
  BOTTOM w0.102: v1(151.99,15.06) 151.99,15.42 152.53,15.95 JW1.58
N41360887: length 2.1
  TOP w0.102: 151.26,13.41 152.02,13.41 v1(152.09,13.48)
  BOTTOM w0.102: v1(152.09,13.48) 152.13,13.45 JW1.68
N41385128: length 1.9
  TOP w0.102: RT89.1 30.01,14.21 30.01,13.98 29.82,13.8 29.82,13.13 29.93,13.03 RT88.3
N41385208: length 1.9
  TOP w0.102: RT90.1 29.8,14.22 29.8,14.07 29.61,13.88 29.61,13.13 29.51,13.03 RT88.4
N41494285: length 2.8
  TOP w0.102: v3(21.94,34.57) 21.69,34.82 v1(21.08,34.82)
  TOP w0.279: v1(21.08,34.82) 20.89,34.63 RT81.2
  BOTTOM w0.381: UT4.3 v1(21.08,34.82)
N41496626: length 4.2
  TOP w0.102: PR185.1 23.72,67.76 v1(24.23,67.26)
  BOTTOM w0.102: v1(24.23,67.26) 24.36,67.26 25.09,67.99 25.09,68.55 24.43,69.21 PQ112.3
N41496656: length 2.2
  TOP w0.279: v3(22.17,69.24) 22.1,69.16 v4(22.1,68.65) 21.74,68.3 PC151.1 22.24,67.96 PR141.2
N41496684: length 8.9
  TOP w0.279: v3(22.2,65.91) 22.05,66.06 v4(22.05,66.49) 21.74,66.8 PC151.2 21.83,67.26 PR141.1 PR185.2 ; PC180.2 v1(18.74,68.15)
  ART06 w0.279: v4(22.05,66.49) 21.08,67.46 19.43,67.46 v1(18.74,68.15)
  BOTTOM w0.254: PQ111.4 19.55,68.44 PC180.2 v1(18.74,68.15)
  BOTTOM w0.356: PQ110.4 21.99,66.55 v4(22.05,66.49)
N41496697: length 22.7
  ART05 w0.254: v1(23.24,66.49) 22.55,67.18 13.92,67.18 11.68,69.42 11.68,71.85 11.17,72.36 v1(11.07,72.36)
  BOTTOM w0.102: v3(24.64,65.1) 24.64,65.43 23.85,66.22
  BOTTOM w0.254: PC182.1 12.05,72.08 13.08,72.08 13.33,72.34 PR187.2 ; PQ112.2 23.85,66.91 23.85,66.22 23.6,65.96 PR188.2 23.26,66.47 v1(23.24,66.49)
  BOTTOM w0.381: PC182.1 11.62,71.97 11.22,72.36 v1(11.07,72.36)
N41496710: length 5
  TOP w0.305: PC153.1 23.3,69.24 PR168.2 PR186.1 v1(25.37,69.24) 25.8,69.67 v3(25.8,69.77)
  BOTTOM w0.305: PQ112.1 25.55,67.44 25.55,69.06 v1(25.37,69.24)
N41922986: length 2.7
  TOP w0.102: QA1.5 CA82.1 RA246.2 183.51,15.75 v3(183.28,15.97)
N41923012: length 3.3
  TOP w0.102: v3(179.93,12.52) RA247.2 180.79,12.58 QA1.3 180.45,13.52 180.35,13.62 180.35,14.07 180.45,14.17 QA1.2
N41976979: length 7.1
  BOTTOM w0.102: PD907.2 46.29,57.92 46.58,57.63 v3(47.45,57.63) 49.12,57.63 49.48,57.99 49.48,59.15 49.68,59.36 PR916.2 PC916.1 PR910.2
N41981897: length 1.9
  BOTTOM w0.102: PD906.1 52.54,59.54 52.36,59.36 PR918.2 PR919.2
N41989686: length 16.9
  BOTTOM w0.102: QU5.1 105.56,34.56 105.66,34.46 CU168.1 RU224.1 106.42,33.8 106.98,33.25 106.98,31.93 106.75,31.7 106.75,31.04 QU4.1 105.51,31.35 105.51,32.59 105.31,32.79 103.58,32.79 102.63,31.84 QU6.1 102.66,31.22 RU232.2 102.66,29.44 v3(102.26,29.03)
N42059324: length 11.5
  TOP w0.279: v4(27.84,61.03) 28.34,61.03 29.26,61.95 v3(33.63,61.95) 35.2,61.95 v1(36.07,62.81)
  BOTTOM w0.229: v4(27.84,61.03) 28.57,60.3 PSH402.1
  BOTTOM w0.279: PR412.2 PC412.2 v1(36.07,62.81)
N42101806: length 2.4
  TOP w0.102: v2(154.84,14.73) 154.79,14.78 154.71,14.78 154.56,14.93 TPW3.1
  BOTTOM w0.102: JW1.64 154.56,14.45 v2(154.84,14.73)
N42165106: length 2
  TOP w0.102: v3(189.2,21.97) 188.85,22.32 188.4,22.32 PR930.2 187.92,22.81 PU910.B2
N42348537: length 2.9
  TOP w0.102: v3(43.99,78.25) v1(44.91,78.25)
  TOP w0.254: PSH708.2 45.31,77.85 v1(44.91,78.25)
  BOTTOM w0.254: v1(44.91,78.25) 44.91,78.36 45.12,78.57 PU701.5
N42351508: length 2.1
  BOTTOM w0.102: PR703.1 PR707.1 42.57,85.01 PR712.1 PR709.2 PR708.2
N42409129: length 10.3
  BOTTOM w0.381: PU904.4 51.33,69.7 51.86,69.16 51.86,67.64 52.65,66.85 52.65,64.31 v3(53.13,63.83) 53.9,63.07 PSH903.1
N42672218: length 0.9
  BOTTOM w0.102: RU224.2 107.32,33.85 QU7.2
N42735417: length 0.8
  TOP w0.102: RA248.2 165.35,29.59 165.39,29.55 DA2.1
N399470060: length 1.3
  TOP w0.102: TPV8.1 145.84,75.55 v1(145.5,75.9)
  BOTTOM w0.102: UV2.Y6 v1(145.5,75.9)
N399470061: length 1.3
  TOP w0.102: TPV7.1 145.09,75.07 v1(144.64,75.07)
  BOTTOM w0.102: UV2.W6 v1(144.64,75.07)
N399470062: length 1.3
  TOP w0.279: v1(146.29,74.22) 146.63,74.56 TPV6.1
  BOTTOM w0.279: v1(146.29,74.22) 145.88,74.63 UV2.W7

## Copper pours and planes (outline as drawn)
1.35VGS_IN on TOP: 178.29,39.12 179.85,39.12 180.36,38.61 180.36,36.62 180.23,36.49 178.2,36.49 177.96,36.72 177.96,38.8
1.35VGS_IN on BOTTOM: 177.23,38.05 180.21,38.05 180.36,37.89 180.36,36.68 180.18,36.5 178.11,36.5 178,36.39 177.41,36.39 177.22,36.58 177.22,38.03
1.35VGS_PHASE on BOTTOM: 176.5,38.53 176.5,39.88 176.27,40.1 174.8,40.1 174.45,40.46 174.45,42.14 174.85,42.54 180.44,42.54 180.54,42.44 180.54,39.55 180.49,39.49 178.51,39.49 177.75,38.73 177.34,38.73 177.13,38.52 176.95,38.52 176.94,38.52 176.94,39.34 176.75,39.34 176.75,38.53 176.74,38.52 176.51,38.52
+1.0VGS on TOP: 163.07,81.21 159.06,77.2 158.62,77.2 158.49,77.07 158.49,76.27 158.37,76.15 157.61,76.15 157.48,76.02 157.48,75.38 157.56,75.3 161.28,75.3 162.48,76.5 162.54,76.5 165.56,79.52 165.56,87.75 165.35,87.96 165.35,89.08 165.2,89.23 165.2,91.01 163.55,92.66 147.95,92.66 146.22,94.39 138.07,94.39 137.78,94.1 136.14,94.1 134.72,92.68 134.72,89.53 136.7,87.55 137.19,87.25 143.31,87.25 145.55,89.48 161.42,89.48 163.07,87.83
+1.0VGS on BOTTOM: 162.46,79.86 161.61,79.86 161.49,79.73 161.49,79.42 161.5,79.4 161.5,79.04 161.56,78.97 165.01,78.97 165.24,79.21 166.51,79.21 166.75,79.45 166.75,81.71 168.65,83.62 168.65,85.54 168.59,85.61 163.39,85.61 162.94,85.16 162.94,80.34
+1.0VGS on BOTTOM: 133.35,93.24 133.14,93.44 133.14,94 133.35,94.21 133.65,94.21 133.96,93.9 135.43,93.9 135.79,94.26 136.45,94.26 137.46,93.24 137.46,92.68 137.36,92.58 136.45,92.58 135.94,93.09 134.16,93.09 134.01,93.24
+1.0VGS on ART05: 143.66,94.56 137.36,94.56 135.74,92.94 135.74,90.29 135.76,90.27 135.76,89.51 136.45,88.82 144.47,88.82 145.59,89.94 145.59,92.63
+1.35VGS on TOP: outline of 125 points within 151.67,53.39 189.61,91.77
+1.35VGS on BOTTOM: 150.72,64.17 151.01,64.17 151.51,63.67 151.84,63.67 151.94,63.76 151.94,63.97 151.81,64.09 151.81,64.39 152.02,64.6 152.3,64.6 152.59,64.31 153.34,64.31 153.62,64.59 153.95,64.59 154.35,64.18 155.23,64.18 155.34,64.07 155.6,64.07 156.13,64.59 156.48,64.59 157.4,63.67 157.7,63.67 157.78,63.75 157.78,64 157.67,64.11 157.67,64.52 157.73,64.59 157.73,64.84 157.64,64.94 157.64,65.3 158.04,65.7 158.04,67.34 158.59,67.9 158.59,68.16 157.64,69.12 157.64,69.41 157.8,69.57 157.8,69.75 157.67,69.88 157.67,71.18 157.84,71.35 157.84,72.2 157.64,72.4 157.64,72.69 157.72,72.76 157.72,73.09 157.66,73.15 157.66,73.6 157.79,73.74 157.79,73.96 157.67,74.07 157.67,74.36 157.87,74.56 157.87,75.32 157.73,75.45 157.14,75.45 156.76,75.08 156.76,66.44 155.73,65.4 151.05,65.4 150.53,64.88 150.53,64.36
+1.35VGS on BOTTOM: outline of 104 points within 171.58,52.52 189.4,92.16 ; 1 cut-out
+1.35VGS on BOTTOM: 179.84,88.16 179.98,88.3 179.98,91.49 179.87,91.6 175.39,91.6 175.28,91.5 175.28,91.49 175.28,89.61 175.39,89.5 177.63,89.5 178.92,88.21 179.18,88.21 179.22,88.24 179.57,88.24 179.66,88.16
+1.35VGS on ART03: 164.17,63.07 164.17,68.42 161.85,70.74 159.43,70.74 159.19,70.98 159.19,74.69 158.66,75.23 157.08,75.23 156.57,74.72 156.57,67.05 155.05,65.52 151.13,65.52 150.87,65.27 150.87,61.03 151.13,60.78 161.88,60.78
+1.35VGS on PWR04: 148.24,49.81 144.46,53.58 144.46,64.85 145.11,65.49 155.49,65.49 156.71,66.71 156.71,75.17 156.84,75.3 157.52,75.3 157.54,75.29 158.17,75.29 159.11,74.35 159.11,72.19 160.22,71.08 161.59,71.08 162.12,70.55 162.12,66.97 163.52,65.57 163.52,63.36 162.23,62.07 162.23,61.62 161.39,60.78 158.63,60.78 158.04,60.19 153,60.19 151.63,58.81 151.63,55.18 155.28,51.54 157.5,51.54 161.68,47.36 164.03,47.36 166.88,50.21 166.88,50.75 172.19,56.06 174.04,56.06 175.5,54.6 179.76,54.6 179.96,54.41 179.96,46.62 179.07,45.73 169.21,45.73 168.72,45.23 162,45.23 157.43,49.81
+1.35VGS on ART06: 179.07,90.5 187.45,90.5 188.21,89.74 188.21,59.64 186.69,58.11 184.78,58.11 183.77,59.13 179.58,59.13 178.94,59.76 178.94,62.94 179.32,63.32 182.75,63.32 186.05,66.62 186.05,67.64 185.8,67.89 179.83,67.89 179.58,68.15 179.58,68.65 179.83,68.91 179.83,80.97 179.2,81.61 179.2,87.32 178.69,87.83 178.69,90.12
+1.35VGS_OUT on TOP: 174.5,52.79 174.5,46.24 174.6,46.15 178.92,46.15 179.27,46.5 179.27,52.75 179.07,52.96 174.67,52.96
+1.35VGS_OUT on BOTTOM: 175.24,46.15 178.92,46.15 179.27,46.5 179.27,52.32 179.2,52.4 174.62,52.4 174.49,52.26 174.49,46.91
+V1P0S_VCCST on TOP: 113.16,38.05 109.64,38.05 109.34,37.75 109.34,36.12 110.04,35.42 113.23,35.42 113.41,35.6 113.41,37.79
+V1P0S_VCCST on BOTTOM: 109.57,36.23 110.3,36.23 110.4,36.13 110.4,34.38 110.37,34.35 109.52,34.35 109.43,34.45 109.43,36.09
+V1P0S_VCCST on PWR04: 79.63,37.23 79.8,37.41 84.02,37.41 84.12,37.31 84.12,35.68 83.92,35.48 80.01,35.48 79.63,35.86
+V1P0S_VCCST on ART05: 83.56,36.4 86.87,36.4 87.37,36.9 88.39,36.9 88.77,36.52 94.97,36.52 96.02,35.47 103.59,35.47 103.88,35.76 107.19,35.76 108.71,37.28 113.16,37.28 113.28,37.41 113.28,38.17 113.16,38.3 108.08,38.3 106.68,36.9 102.87,36.9 102.47,36.51 96.77,36.51 95.43,37.85 83.49,37.85 83.44,37.79 83.44,36.52
+V1P1U_VDDQ on TOP: 50.85,88.01 50.59,88.26 50.59,92.4 52.63,94.43 124.46,94.43 125.69,93.2 125.69,88.81 125.98,88.52 125.98,77.29 124.2,75.51 65.73,75.51 61.21,80.03 61.21,81.61 60.96,81.86 60.96,88.92 61.16,89.13 61.67,89.13 61.77,89.23 61.77,90.24 61.01,91.01 57.15,91.01 56.89,90.75 55.98,90.75 53.24,88.01 ; 1 cut-out
+V1P1U_VDDQ on BOTTOM: 45.11,73.94 40.28,73.94 40.18,73.84 40.18,70.89 40.43,70.63 42.21,70.63 42.42,70.84 42.42,71.4 42.67,71.65 44.91,71.65 45.16,71.9 45.16,73.89
+V1P1U_VDDQ on BOTTOM: 56.41,93.77 59.61,96.97 123.7,96.97 126.16,94.51 126.16,87.1 126.27,86.99 126.27,84.27 126.03,84.03 125.42,84.03 124.98,84.47 124.98,85.3 124.54,85.73 124.54,86.96 124.98,87.39 124.98,93.38 122.8,95.56 112.43,95.56 107.98,91.11 107.98,87.02 107.82,86.86 107.4,86.86 107.29,86.98 107.29,95.23 106.96,95.56 97.21,95.56 96.79,95.14 96.79,84.13 96.65,83.99 96,83.99 95.91,84.09 95.91,91.57 91.63,95.85 84.86,95.85 83.52,94.51 79.09,94.51 78.29,93.71 78.29,93.03 78.3,93.02 78.3,92.05 78.11,91.86 77.61,91.86 73.72,95.75 67.64,95.75 66.54,94.65 63.33,94.65 61.31,92.62 61.31,87.18 61.66,86.83 61.66,85.66 61.32,85.31 61.32,83.68 61.19,83.55 60.54,83.55 60.21,83.88 60.21,84.31 59.84,84.68 59.84,89.08 59.85,89.08 59.85,89.81 59.08,90.58 58.54,90.58 58.52,90.6 57.45,90.6 55.42,88.57 55.42,86.03 54.51,85.11 50.09,85.11 49.83,85.37 49.83,87.3 50.54,88.01 50.54,92.9 51.41,93.77
+V1P1U_VDDQ on ART05: 55.41,90.23 50.38,85.2 50.38,79.31 43.84,72.77 42.52,72.77 42.16,73.12 42.16,80.92 45.78,84.54 45.78,87.46 51,92.68 55.15,92.68 55.41,92.43
+V1P2_HDMI on TOP: 29.08,59.76 30.48,59.76 30.61,59.64 30.61,57.73 30.48,57.6 29.08,57.6 28.95,57.73 28.95,59.64
+V1P2_HDMI on BOTTOM: 134.62,94.76 134.62,95.17 134.57,95.22 133.4,95.22 133.3,95.12 133.3,94.71 133.6,94.41 133.75,94.41 134.06,94.1 134.77,94.1 134.92,94.26 134.92,94.46
+V1P2_HDMI on BOTTOM: 31.47,59.87 30.86,59.26 30.86,57.05 30.38,56.56 29.28,56.56 28.14,57.71 28.14,59.1 28.45,59.41 29,59.41 29.21,59.62 29.21,60.58 29.29,60.66 31.4,60.66 31.47,60.59
+V1P2_HDMI on PWR04: 58.53,97.13 132.88,97.13 135.14,94.86 135.14,94.23 134.81,93.9 132.64,93.9 130.24,96.3 59.29,96.3 57.15,94.16 52.05,94.16 52.04,94.17 50.52,94.17 50.47,94.22 49.13,94.22 44.45,89.54 44.45,87.76 41.25,84.55 41.25,71.91 39.64,70.3 28.67,70.3 25.87,67.5 25.87,66.08 30.43,61.52 30.43,58.8 29.72,58.09 28.94,58.09 28.33,58.7 28.33,60.28 28.09,60.52 23.29,60.52 23.06,60.75 23.06,71.15 25.02,73.11 37.16,73.11 38.92,74.87 38.92,84.68 43.17,88.93 43.17,89.48 48.82,95.12 51.6,95.12 51.61,95.11 56.52,95.11
+V1P2S_HDMI on BOTTOM: 25.84,58.56 25.78,58.49 25.78,57.48 25.58,57.27 24.71,57.27 24.64,57.35 20.19,57.35 19.94,57.1 19.94,53.03 20.06,52.91 21.03,52.91 21.15,53.02 21.15,55.88 21.45,56.19 26.94,56.19 27.37,55.76 27.37,51.42 25.86,49.9 25.83,49.88 23.83,49.88 23.75,49.79 23.75,48.33 23.86,48.22 26.47,48.22 29.34,51.09 29.34,56.02 27.68,57.68 27.68,58.49 27.62,58.56
+V1P8_V3P3_AON on TOP: 149.41,63.67 149.24,63.67 148.74,63.17 148.74,62.96 148.59,62.81 148.21,62.81 148.17,62.85 148.17,63.28 148.21,63.32 148.21,64.06 148.64,64.49 148.94,64.49 149.1,64.64 149.1,64.98 149.18,65.07 149.65,65.07 149.78,65.2 149.78,65.32 149.89,65.43 150.23,65.43 150.24,65.41 150.24,64.5
+V1P8_V3P3_AON on TOP: 130.48,87.79 132.32,87.79 134.48,89.95 134.48,92.39 134.48,92.39 134.48,93.08 134.16,93.39 131.11,93.39 130.33,92.61 130.33,87.94
+V1P8_V3P3_AON on BOTTOM: 131.52,90.29 131.57,90.24 131.57,88.97 131.95,88.59 131.95,87.7 131.82,87.58 131.29,87.58 130.71,86.99 130.71,86.41 130.6,86.31 129.28,86.31 129.16,86.43 129.16,87.45 129.28,87.58 129.54,87.58 129.79,87.83 129.79,88.47 129.92,88.59 129.92,89.1 130.3,89.48 130.3,90.24 130.35,90.29 ; 1 cut-out
+V1P8_V3P3_AON on BOTTOM: 134.52,91.36 134.31,91.36 134.01,91.67 133.81,91.67 133.77,91.7 132.84,91.7 132.79,91.76 132.79,92.38 132.69,92.48 132.69,92.83 132.79,92.94 133.7,92.94 133.71,92.94 133.91,92.94 133.96,92.94 134.21,92.68 134.21,91.97 134.36,91.82 134.52,91.82 134.57,91.77 134.57,91.41
+V1P8_V3P3_AON on ART03: 148.27,65.42 148.33,65.48 150.24,65.48 150.37,65.35 150.37,56.59 151.14,55.82 151.14,54.82 151.26,54.7 151.26,54.05 151.13,53.92 148.37,53.92 146.4,55.88 146.4,57.11 146.39,57.12 146.39,57.71 143.38,60.73 143.38,63.72 142.97,64.13 139.51,64.13 138.91,63.53 138.91,62.39 139.56,61.75 139.56,60.48 143.3,56.73 143.3,55.49 144.48,54.31 144.48,52.05 145.79,50.73 145.79,49.73 145.54,49.48 144.65,49.48 142.75,51.38 139.57,51.38 139.44,51.51 139.44,52.65 139.46,52.67 139.46,53.63 138.77,54.32 138.77,56.33 138.79,56.35 138.3,56.84 138.3,58.65 136.28,60.67 136.28,62.57 137.16,63.45 137.16,64.59 138.02,65.45 143.48,65.45 143.51,65.42
+V1P8_V3P3_MAIN on TOP: 148.24,76.18 155.32,76.18 155.7,76.56 155.7,76.8 156.21,77.3 158.94,77.3 159.1,77.47 159.21,77.59 159.21,78.26 160.29,79.34 160.97,79.34 162.17,80.55 162.82,81.19 162.82,86.55 160.65,88.72 147.86,88.72 147.85,88.71 145.84,88.71 144,86.87 137.1,86.87 135.26,88.72 133.7,88.72 133.3,88.31 133.3,87.12 134.87,85.54 134.87,80.08 135,79.96 136.27,79.96 140,83.68 145.25,83.68 146.61,85.04 150.4,85.04 152.73,82.71 156.36,82.71 157.99,81.08 157.99,79.67 156.75,78.44 155.2,78.44 155.07,78.31 155.07,77.58 154.81,77.32 154.15,77.32 154.05,77.42 153.59,77.42 153.21,77.8 151.23,77.8 150.69,77.26 148.73,77.26 148.72,77.24 148.03,77.24 146.94,76.15 146.94,75.26 147.06,75.13 147.95,75.13 148.08,75.26 148.08,76.02
+V1P8_V3P3_MAIN on BOTTOM: 132.82,90.3 133.55,90.3 133.55,90.29 133.75,90.09 134.11,90.09 134.16,90.04 134.64,90.04 134.69,89.99 134.69,87.62 134.51,87.45 133.4,87.45 133.25,87.6 132.68,87.6 132.62,87.66 132.62,89.09 132.81,89.28 132.81,90.29
+V1P8_V3P3_MAIN on BOTTOM: 154.15,76.82 146.72,76.82 146.68,76.78 146.68,75.77 146.94,75.51 156.95,75.51 161.69,80.24 162.59,80.24 162.69,80.34 162.69,80.72 162.56,80.85 161.42,80.85 161.29,80.97 161.29,87.58 161.16,87.7 159.51,87.7 159.38,87.58 159.38,86.81 159.26,86.69 159.26,84.27 156.97,81.99 156.97,79.64
+V1P8_V3P3_MAIN on ART05: 133.65,88.77 133.4,88.52 133.4,86.69 134.82,85.27 148.84,85.27 149.3,84.81 160.58,84.81 160.73,84.96 160.73,87.35 159.61,88.47 135.48,88.47 135.18,88.77
+V1P8A on TOP: 45.01,63.93 44.09,63.93 43.89,63.73 43.89,62 44.04,61.85 45.31,61.85 45.46,62 45.46,63.47
+V1P8A on TOP: 61.82,52.53 60.99,52.53 59.27,50.81 57.78,50.81 57.54,51.05 57.54,51.35 59.13,52.95 59.13,56.02 58.87,56.28 56.82,56.28 56.56,56.54 55.96,56.54 55.82,56.39 55.82,54.55 57.2,53.17 57.2,52.25 56.48,51.53 56.48,50.49 57.15,49.82 59.77,49.82 61.42,51.47 61.8,51.47 61.93,51.6 61.93,52.41
+V1P8A on BOTTOM: 43.31,59.48 43.31,61.82 43.18,61.95 43.18,64.13 42.57,64.74 42.57,66.32 42.77,66.52 44.96,66.52 45.06,66.42 45.06,66.01 45.57,65.5 45.57,62.2 44.96,61.59 44.96,59.92 44.45,59.41 43.38,59.41
+V1P8A on BOTTOM: 129.67,93.83 127.95,93.83 127.91,93.8 127.71,93.6 127.71,92.22 127.81,92.12 128.47,92.12 128.47,92.13 128.62,92.28 129.13,92.28 129.74,92.89 129.74,93.77
+V1P8A on PWR04: 57.33,94.04 59.38,96.09 127.84,96.09 129.73,94.19 129.73,92.77 128.94,91.99 126.66,91.99 124.13,94.51 62.12,94.51 59.17,91.56 53.54,91.56 47.34,85.36 47.34,77.42 47.07,77.15 47.07,72.29 47.5,71.87 47.5,67.99 47.52,67.97 47.52,65.58 48,65.1 48.05,65.1 51.36,61.8 53.69,61.8 55.98,59.51 56.39,59.51 56.77,59.13 56.77,54.7 56.57,54.49 56.25,54.49 56.06,54.68 54.61,54.68 54.07,55.22 50.83,55.22 49.49,56.56 48.01,56.56 45.69,58.88 45.69,60.56 41.41,64.84 41.41,84.46 44.67,87.73 44.67,89.25 49.46,94.04
+V1P8U on TOP: 46.58,86.64 46.73,86.48 47.95,86.48 48.26,86.79 48.26,88.11 48.03,88.34 46.71,88.34 46.63,88.26 46.63,87.75 46.58,87.7
+V1P8U on BOTTOM: 47.83,87.91 46.58,87.91 46.43,87.75 46.43,86.61 46.12,86.31 46.12,85.72 46.23,85.62 47.8,85.62 47.95,85.77 47.95,87.78
+V1P8U on GND02: 63.5,83.51 64.9,83.51 65.66,82.75 68.45,82.75 68.83,83.13 71.12,83.13 71.63,82.62 79.88,82.62 80.39,83.13 83.06,83.13 83.31,82.88 88.77,82.88 89.15,82.5 97.15,82.5 98.55,83.89 98.93,83.89 99.95,82.88 104.27,82.88 104.52,83.13 106.81,83.13 107.57,82.37 113.79,82.37 115.44,84.02 116.2,84.02 117.35,82.88 123.32,82.88 123.95,82.24 125.6,82.24 125.98,82.62 125.98,89.23 124.71,90.5 124.08,90.5 123.32,89.74 114.81,89.74 114.55,89.99 107.57,89.99 107.06,90.5 106.04,90.5 105.41,89.86 97.92,89.86 97.28,90.5 89.79,90.5 89.15,89.86 84.15,89.86 84.02,89.74 81.63,89.74 81.51,89.86 80.39,89.86 79.75,90.5 71.37,90.5 70.74,89.86 62.99,89.86 62.36,90.5 61.47,90.5 61.34,90.37 61.34,83.26 61.72,82.88 62.86,82.88
+V3.3DX_RT_TCP1 on BOTTOM: 20.75,33.22 20.88,33.09 20.88,32.84 21.44,32.28 26.11,32.28 26.57,31.82 27.13,31.82 27.33,31.62 30.27,31.62 30.33,31.57 30.33,30.81 30.22,30.71 19.53,30.71 18.92,31.32 18.92,33.09 19.05,33.22
+V3P3_DISPLAY on TOP: 24.08,71.62 26.35,71.62 26.72,71.24 26.72,70.34 26.55,70.17 25.83,70.17 25.38,70.62 24.13,70.62 24.03,70.72 24.03,71.57
+V3P3_DISPLAY_CONN on TOP: 22.6,70.56 23.49,70.56 23.62,70.69 23.62,71.45 23.24,71.83 22.99,71.83 22.86,71.96 22.86,73.61 22.73,73.73 22.73,74.62 22.48,74.88 20.57,74.88 20.56,74.86 20.48,74.86 20.42,74.8 20.42,74.04 20.57,73.89 21.99,73.89 22.1,73.78 22.1,71.7 22.35,71.45 22.35,70.81
+V3P3_DISPLAY_CONN on BOTTOM: 22.22,74.32 22.22,73.61 22.1,73.48 19.68,73.48 19.56,73.61 19.56,75.61 19.59,75.65 20.32,75.65 20.36,75.61 20.36,74.56 20.37,74.55 20.37,74.45 20.42,74.44 22.1,74.44
+V3P3_DVDD_IO on TOP: 165,31.06 165.91,31.06 166.01,30.96 168.4,30.96 169.11,30.25 169.11,30.15 168.91,29.94 168.45,29.94 168.35,29.84 168.35,29.44 168.3,29.39 167.99,29.39 167.94,29.44 167.94,29.89 167.89,29.94 167.43,29.94 167.33,30.05 165.05,30.05 164.89,30.2 164.89,30.96
+V3P3_MIC_DB on BOTTOM: 158.62,90.79 158.68,90.73 161.03,90.73 161.05,90.71 161.05,89.75 160.91,89.61 153.8,89.61 151.84,87.65 151.28,87.65 151.23,87.7 151.23,88.47 153.55,90.79
+V3P3_TOUCH on BOTTOM: 63.29,10.34 63.56,10.6 66.22,10.6 66.22,10.6 66.22,9.14 64.23,7.16 62.95,7.16 62.94,7.17 62.94,8.81 63.29,9.17
+V3P3_TPM on TOP: 139.09,33.45 139.57,32.97 141.15,32.97 141.48,33.3 143.46,33.3 145.03,34.87 145.03,36.8 144.98,36.85 144.42,36.85 142.19,34.62 139.34,34.62 139.29,34.57 137.21,34.57 137.16,34.52 137.16,34.36 138.07,33.45
+V3P3_TS on TOP: 32.21,66.95 31.72,66.95 31.62,66.85 31.62,66.35 31.85,66.11 31.85,65.93 32.28,65.5 33.07,65.5 33.23,65.67 33.23,66.1 33.17,66.16 32.41,66.16 32.26,66.32 32.26,66.9
+V3P3_TS on BOTTOM: 26.74,79.8 20.8,79.8 19.02,78.03 19.02,74.67 19.07,74.62 19.33,74.62 19.35,74.65 19.35,75.82 19.49,75.96 19.57,75.96 21.79,78.18 24.89,78.18 25.17,77.9 26.82,77.9 26.95,78.03 26.95,79.6
+V3P3_TS on BOTTOM: 31.81,66.74 32.79,66.74 33.27,66.27 33.27,65.76 33.15,65.63 32.69,65.63 32.61,65.55 32.05,65.55 31.68,65.92 31.68,66.61 31.81,66.74
+V3P3_TS on ART05: 26.06,81.86 25.86,81.66 25.86,80.08 25.5,79.73 25.5,79.3 26.08,78.71 27.53,78.71 28.7,77.54 28.7,75.46 29.34,74.83 29.34,69.01 28.88,68.55 28.88,66.7 29.34,66.24 29.34,65 29.69,64.64 32.33,64.64 33.32,65.63 33.32,66.32 33.02,66.62 31.09,66.62 30.83,66.88 30.83,67.79 30.94,67.89 33.2,67.89 33.7,68.4 33.7,69.87 33.11,70.47 33.11,74.43 32.1,75.44 32.1,80.87 31.11,81.86
+V3P3_WLAN on TOP: 146.14,10.71 145.67,10.23 144.02,10.23 143.46,10.79 140.76,10.79 140.46,11.1 140.46,12.16 141.17,12.88 144.88,12.88 146.18,14.17 149.43,14.17 149.6,13.99 149.6,13.41 149.86,13.15 152.02,13.15 152.3,13.43 152.3,14.91 152.55,15.16 152.55,28.47 151.94,29.08 151.94,29.49 151.79,29.64 151.79,29.9 152.58,30.7 152.58,31.25 152.73,31.39 153.98,31.39 154.28,31.09 154.28,14.75 153.82,14.3 153.82,12.82 153.62,12.63 153.62,11.04 151.81,9.22 150.49,9.22 150.48,9.23 149.66,9.23 148.18,10.71
+V3P3_WLAN on BOTTOM: 151.43,12.93 152.04,12.93 152.4,12.57 154.02,12.57 154.07,12.52 154.07,11.45 153.72,11.1 152.5,11.1 151.18,12.42 151.18,12.67
+V3P3_WLAN on BOTTOM: 140.21,11.15 140.21,12.16 140.56,12.52 142.39,12.52 142.64,12.27 142.64,11.05 142.49,10.89 140.46,10.89
+V3P3_WLAN on BOTTOM: 154.07,29.28 154.13,29.33 154.13,30.96 153.69,31.39 152.42,31.39 151.94,30.91 151.94,30.5 151.69,30.25 151.69,29.64 152.04,29.28
+V3P3_WLAN on ART05: 147.59,14.12 152.6,14.12 152.88,13.84 152.88,10.07 152.14,9.33 150.42,9.33 147.38,12.37 147.38,13.91
+V3P3A on TOP: 24.41,42.49 26.46,42.49 27.12,41.84 34.24,41.84 34.54,42.14 34.54,48.46 34.29,48.71 31.75,48.71 31.49,48.46 31.49,44.76 31.27,44.53 24.5,44.53 24.13,44.15 24.13,42.77
+V3P3A on TOP: 62.72,56.02 60.51,56.02 59.41,54.92 59.41,53 57.71,51.3 57.71,51.06 57.81,50.96 58.51,50.96 60.66,53.11 60.66,54.45 61.21,55 62.78,55 62.85,55.06 62.85,55.89
+V3P3A on BOTTOM: 21.97,33.86 21.84,33.73 21.84,32.59 21.97,32.46 24.26,32.46 24.38,32.59 24.38,33.73 24.26,33.86
+V3P3A on BOTTOM: 142.39,13.33 142.19,13.13 141.43,13.13 141.27,13.28 141.27,13.38 141.07,13.59 140.31,13.59 140.21,13.69 140.21,14.45 140.26,14.5 141.07,14.5 141.98,15.42 142.09,15.42 142.39,15.11
+V3P3A on BOTTOM: 28.57,68.02 29.08,67.51 29.08,67 29.34,66.75 29.34,64.46 29.21,64.34 27.94,64.34 26.03,66.24 26.03,67.88 26.17,68.02
+V3P3A on BOTTOM: 24.42,41.49 24.33,41.58 24.33,42.14 23.26,43.2 23.26,44.12 23.32,44.17 24.13,44.17 24.23,44.07 25.86,44.07 26.03,43.89 26.03,43.51 26.16,43.38 27.68,43.38 28.37,44.07 30.97,44.07 31.47,44.57 31.47,48.72 31.72,48.97 33.02,48.97 33.27,48.71 33.27,43.15 31.61,41.49
+V3P3A on ART03: 25.94,44.07 27.72,42.28 27.72,36.6 26.25,35.13 24.13,35.13 24,35.25 24,36.72 25.15,37.87 25.15,40.85 24.08,41.92 24.08,43.91 24.23,44.07
+V3P3A on PWR04: outline of 91 points within 26.2,14.09 169.26,69.45
+V3P3A on ART05: 25.93,44.21 23.17,44.21 23.02,44.06 23.02,39.31 22.54,38.83 22.54,33.02 23.13,32.43 24.69,32.43 25.34,33.07 25.34,36.42 23.38,38.37 23.38,38.74 26.16,41.51 26.16,43.98
+V3P3A_EC on PWR04: 143.81,25.61 162.97,25.61 165.17,23.41 169.61,23.41 173.3,19.73 173.3,15.68 172.46,14.85 158.84,14.85 157.05,13.06 154.22,13.06 150.49,16.79 144.51,16.79 142.73,18.57 142.73,24.53
+V3P3A_PCH on TOP: 61.24,54.4 65.4,54.4 65.45,54.36 65.45,53.93 65.39,53.87 64.72,53.87 64.72,53.87 64.63,53.87 64.63,53.86 64.52,53.86 63.9,53.24 61.33,53.24 61.14,53.44 61.14,54.3
+V3P3A_PCH on PWR04: 60.58,84.78 60.58,81.1 60.45,80.97 60.45,72.84 69,64.29 76.54,64.29 77.25,63.59 77.25,60.95 76.32,60.03 74.24,60.03 73.94,59.73 73.94,52.34 70.24,48.65 70.24,44.62 69.68,44.06 62.52,44.06 60.51,46.06 60.51,46.48 60.32,46.67 60.32,48.65 60.82,49.15 62.45,49.15 63.16,49.85 63.16,51.28 63.01,51.43 61.25,51.43 61.04,51.64 61.04,53.94 58.37,56.61 58.37,60.47 57.29,61.55 57.26,61.55 52.7,66.11 52.7,81.07 57.45,85.82 58.16,85.82 58.82,85.16 60.2,85.16
+V3P3A_PCH on ART06: 70.76,53.62 70.76,55.46 71.63,56.34 72.2,56.34 72.73,56.87 72.73,58.71 72.65,58.79 70.57,58.79 68.4,56.62 68.4,53.63 68.66,53.37 70.51,53.37
+V3P3A_VDDD_PD on BOTTOM: 41.15,42.36 41.88,42.36 42.01,42.24 43.43,42.24 43.69,41.98 43.69,41.48 43.56,41.35 43.18,41.35 43.05,41.22 43.05,40.46 42.92,40.33 41.5,40.33 41.08,40.75 41.08,42.3
+V3P3S_SSD1 on TOP: 21.89,3.19 21.89,3.63 21.79,3.73 20.57,3.73 20.52,3.78 20.52,4.85 20.37,5 20.37,5.66 20.32,5.71 19.76,5.71 19.2,6.27 16.61,6.27 16.56,6.32 15.24,6.32 15.09,6.17 15.09,3.17 16.02,2.24 19.04,2.24 19.75,2.95 21.66,2.95
+V3P3S_SSD1 on TOP: 35.84,3.65 32.17,3.65 32.05,3.52 32.05,2.54 32.14,2.45 35.81,2.45 35.96,2.59 35.96,3.53
+V3P3S_SSD1 on BOTTOM: 19.1,2.97 17.78,2.97 17.32,2.51 17.32,1.04 17.63,0.73 18.95,0.73 19,0.78 19,2.36 19.2,2.56 19.2,2.87
+V3P3S_SSD1 on BOTTOM: 31.6,2.46 31.6,0.63 31.65,0.58 33.42,0.58 33.48,0.63 33.48,2.31 33.58,2.41 35.05,2.41 35.1,2.36 35.1,0.68 35.2,0.58 36.62,0.58 36.78,0.73 36.78,2.66 35.91,3.53 32.66,3.53
+V3P3S_SSD1 on ART03: 17.57,5.35 23.1,5.35 23.51,4.95 29.12,4.95 29.52,5.35 35.75,5.35 35.98,5.12 35.98,1.97 35.9,1.89 17.79,1.89 17.34,2.34 17.34,5.12
+V3P3SX on TOP: 16.66,8.46 14.68,8.46 14.53,8.3 14.53,6.78 14.68,6.63 15.19,6.63 15.34,6.78 16.61,6.78 16.71,6.88 16.71,8.4
+V3P3SX on TOP: 162.3,32.33 163.02,32.33 163.22,32.13 163.22,31.93 162.1,30.81 162.1,29.94 162.41,29.64 162.41,27.68 162.51,27.58 162.51,26.06 162.43,25.98 161.66,25.98 161.56,26.08 161.56,27.56 161.24,27.89 161.24,31.26
+V3P3SX on TOP: 72.43,9.12 72.56,8.98 72.56,6.75 72.33,6.52 72.33,5.6 72.24,5.51 71.78,5.51 71.75,5.48 70.8,5.48 70.78,5.46 68.83,5.46 68.68,5.61 68.68,5.92 68.73,5.97 70.05,5.97 70.08,5.94 71.62,5.94 71.73,6.04 71.73,7.51 71.22,8.02 71.22,8.96 71.37,9.12
+V3P3SX on TOP: 19.94,48.33 21.18,48.33 21.33,48.18 21.33,47.62 21.08,47.37 19,47.37 18.86,47.5 18.86,47.9 18.92,47.95 19.56,47.95
+V3P3SX on BOTTOM: 131.67,94.1 131.57,94 131.57,93.6 131.67,93.49 132.08,93.49 132.43,93.14 132.69,93.14 132.94,93.39 132.94,93.8 132.54,94.21 132.18,94.21 132.08,94.1
+V3P3SX on BOTTOM: 22.05,44.17 21.18,44.17 21.03,44.02 20.42,44.02 20.01,44.42 19.61,44.42 19.56,44.37 19.56,42.63 19.7,42.49 21.99,42.49 22.1,42.59 22.1,44.12
+V3P3SX on BOTTOM: 66.54,10.73 71.42,10.73 72.74,9.41 72.74,8.56 72.54,8.35 71.37,8.35 69.95,9.78 68.38,9.78 68.17,9.56 67.2,9.56 67.14,9.62 67.14,9.87 67.01,10 66.5,10 66.48,10.02 66.48,10.67
+V3P3SX on BOTTOM: 155.12,20.93 156.77,22.58 156.77,23.34 158.75,25.32 159.76,25.32 160.37,25.93 162.35,25.93 162.46,26.03 162.46,27.35 162.22,27.59 158.02,27.59 154.43,24 154.43,22.38 154.23,22.18 154.23,19.91 154.41,19.72 154.93,19.72 155.12,19.92
+V3P3SX on ART03: 16.07,28.34 14.23,26.5 14.23,24.86 14.38,24.71 16.62,24.71 17.02,25.12 17.02,26.48 17.67,27.12 17.67,27.52 19.14,28.99 19.14,32.04 20.7,33.6 20.7,33.91 21.07,34.27 21.38,34.27 21.78,34.68 21.78,37.97 21.43,38.32 21.42,38.32 21.21,38.53 21.21,40.16 23.83,42.79 23.83,43.93 23.83,43.93 23.83,46.31 25.53,48.01 25.53,55.49 25.53,56.75 25.1,57.18 25.1,57.72 24.48,58.34 24.48,59.89 25.53,60.93 25.53,64.46 25.82,64.75 25.82,65.5 23.98,67.35 23.98,78.58 25.99,80.59 27.33,80.59 27.64,80.9 27.64,82.37 26.87,83.13 22.02,83.13 19.62,80.73 19.62,57.77 22,55.38 22,50 21.25,49.26 18.91,49.26 17.2,47.56 17.2,39.81 18.16,38.85 18.16,36.89 17.34,36.07 17.34,32.66 16.07,31.39
+V3P3SX on ART05: 16.84,4.7 20.4,1.14 50.9,1.14 51.28,1.51 68.5,1.51 71.47,4.49 72.94,4.49 73.3,4.13 78.69,4.13 80.97,1.85 117.29,1.85 119.53,4.09 130.45,4.09 131.82,5.46 149.97,5.46 150.32,5.81 150.32,6.58 150.09,6.8 142.07,6.8 141.37,7.51 131.58,7.51 129.94,5.86 117.24,5.86 115.36,3.99 107.86,3.99 107.64,4.2 82.37,4.2 80.19,6.38 69.45,6.38 66.71,3.64 42.82,3.64 41.9,2.71 36.86,2.71 35.56,4.01 22.7,4.01 18.41,8.3 18.41,14.39 16.51,16.29 16.51,25.98 15.62,26.87 13.33,26.87 12.03,25.57 12.03,6.76 14.1,4.7
+V3P3SX_HDMI on TOP: 18.92,49.86 19.38,49.86 20.47,50.95 21.69,50.95 21.72,50.92 21.72,49.55 20.75,48.59 19.56,48.59 19.41,48.44 18.94,48.44 18.87,48.51 18.87,49.81
+V5P0_AVDD5 on TOP: 179.58,30.1 181.05,30.1 181.2,29.94 183.23,29.94 183.95,30.66 185.06,30.66 185.21,30.5 185.21,29.54 184.86,29.18 181.33,29.18 181.07,29.44 178.51,29.44 178.46,29.49 178.46,29.59 178.71,29.84 179.32,29.84
+V5P0_FPS on TOP: 137.82,10.03 139.75,10.03 139.75,9.62 138.74,8.61 138.43,8.61 138.17,8.35 138.17,7.39 137.92,7.13 137.31,7.13 137.06,7.39 137.06,10.23 137.11,10.28 137.56,10.28
+V5P0A on TOP: 44.7,86.33 43.46,86.33 43.2,86.08 43.2,85.72 43.36,85.57 44.19,85.57 45.64,84.12 45.64,82.45 45.72,82.37 46.33,82.37 46.45,82.5 46.45,84.58
+V5P0A on TOP: 99.3,26.98 97.79,26.98 97.58,26.78 97.58,26.39 97.79,26.18 99.34,26.18 99.36,26.2 99.36,26.92
+V5P0A on TOP: 30.99,12.16 31.19,12.37 33.53,12.37 33.78,12.62 34.85,12.62 35.53,13.31 35.53,14.22 34.44,15.31 31.04,15.31 30.76,15.03 30.76,14.07 30.61,13.92 30.35,13.92 30.1,13.66 30.1,13.28 30.22,13.15 30.35,13.15 30.35,12.9 30.22,12.9 30.1,12.77 30.1,12.27 30.2,12.16
+V5P0A on TOP: 28.45,33.6 28.32,33.47 27.18,33.47 27.05,33.6 26.54,33.6 26.49,33.65 26.49,34.26 26.72,34.49 26.72,36.17 26.77,36.22 28.37,36.22 28.45,36.14
+V5P0A on TOP: 185.8,29.28 188.72,29.28 188.85,29.41 188.85,30.81 188.72,30.93 185.8,30.93 185.67,30.81 185.67,29.41
+V5P0A on TOP: 37.21,57.35 37.21,52.52 37.08,52.4 33.78,52.4 33.21,52.4 33.14,52.47 33.14,57.19 33.7,57.75 36.81,57.75
+V5P0A on BOTTOM: 37.97,62.74 37.97,63.7 38.1,63.83 39.22,63.83 39.27,63.78 39.27,63.37 39.2,63.3 39.2,61.89 39.1,61.8 38.19,61.8 38.09,61.89 38.1,61.9 38.1,62.61
+V5P0A on BOTTOM: 39.24,52.65 39.11,52.52 33.65,52.52 33.53,52.65 33.53,57.6 33.65,57.73 38.99,57.73 39.24,57.48
+V5P0A on BOTTOM: 44.45,86.33 43.43,86.33 43.25,86.15 43.25,85.72 43.89,85.09 44.4,85.09 44.45,85.14 44.45,85.8 44.54,85.89 44.54,86.24
+V5P0A on BOTTOM: 183.13,52.76 183.13,50.58 183.17,50.55 185.66,50.55 185.89,50.78 185.89,52.91 185.65,53.16 183.53,53.16
+V5P0A on BOTTOM: 72.8,23.66 72.12,23.66 71.86,23.4 71.86,21.6 71.94,21.52 72.65,21.52 72.82,21.68 72.82,23.64
+V5P0A on BOTTOM: 26.16,46.76 26.01,46.61 23.52,46.61 23.21,46.3 23.21,45.64 23.42,45.44 25.25,45.44 25.45,45.23 27.23,45.23 27.43,45.44 27.43,46.66 27.33,46.76
+V5P0A on BOTTOM: 52.11,36.23 52.57,36.23 52.94,35.85 52.94,34.72 52.77,34.55 52.16,34.55 52.04,34.67 52.04,36.16
+V5P0A on PWR04: 65.95,10.02 56.53,10.02 55.29,8.78 50.3,8.78 49.2,9.88 44.35,9.88 42.52,11.71 41.38,11.71 41.27,11.81 41.27,11.85 40.95,12.18 36.7,12.18 36.69,12.18 33.86,12.18 22.43,23.62 22.43,45.31 22.44,45.32 22.44,51.58 28.64,57.79 29.78,57.79 30.68,58.69 36.38,58.69 37.03,58.04 37.03,54.34 31.03,48.34 31.03,29.64 34.01,26.66 50.28,26.66 53.49,23.44 70.17,23.44 70.18,23.46 71.89,23.46 72.87,22.48 72.87,20.14 73.18,19.84 89.3,19.84 94.09,15.05 94.11,15.05 94.73,14.43 98.83,14.43 99.44,15.05 119.37,15.05 120.06,15.74 134.1,15.74 136,13.83 142.32,13.83 144.23,15.74 150.63,15.74 154.19,12.18 154.61,12.18 154.84,12.41 157.16,12.41 159.06,14.31 166.83,14.31 166.83,14.3 174.13,14.3 176.39,16.57 180.8,16.57 187.2,22.97 187.2,49.35 186.03,50.52 184.55,50.52 184.35,50.72 184.35,53.41 184.61,53.67 188.16,53.67 189.84,51.99 189.84,10.94 187.15,8.26 89.7,8.26 87.85,10.11 81.56,10.11 81.46,10.01 65.97,10.01 ; 1 cut-out
+V5P0A on ART05: 40.77,83.89 40.77,83.51 39.29,82.04 39.29,80.24 38.58,79.52 38.58,64.97 37.95,64.34 37.95,63.42 38.2,63.17 40.71,63.17 41.78,64.23 41.78,81.76 44.84,84.82 44.84,86.14 44.68,86.31 43.18,86.31
+V5P0A on ART06: 40.26,62.93 39.23,63.96 35.44,63.96 33.78,62.3 33.78,53.79 34.59,52.99 39.93,52.99 40.26,53.31
+V5P0A_FAN on TOP: 184.81,18.01 188.28,18.01 188.48,18.21 188.48,19.75 188.14,20.09 185.42,20.09 184.5,19.17 184.5,18.31
+V5P0A_FAN on BOTTOM: 182.98,20.55 185.37,20.55 185.82,20.09 185.82,18.87 185.57,18.62 184.4,18.62 182.37,19.48 182.45,20.01
+V5P0A_LX on BOTTOM: 47.76,56.78 47.76,54.97 47.73,54.93 46.35,54.93 45.85,54.43 45.85,53.29 45.72,53.16 42.67,53.16 42.54,53.29 42.54,56.79 42.69,56.93 47.61,56.93
+V5P0A_TYPEC on TOP: 21.79,12.47 21.89,12.37 23.16,12.37 23.37,12.16 25.19,12.16 25.4,12.37 29.18,12.37 29.34,12.52 29.34,14.04 29.26,14.12 29.26,14.2 28.8,14.65 22.3,14.65 21.79,14.15
+V5P0A_USB_AOU1 on TOP: 15.95,40.66 15.95,39.55 16.76,38.73 20.01,38.73 20.22,38.94 23.01,38.94 23.11,39.04 23.11,39.44 23.62,39.95 24.76,39.95 25.14,40.33 25.14,40.97 25.02,41.09 23.59,41.09 23.52,41.17 16.46,41.17
+V5P0A_USB_AOU1 on TOP: 22.58,36.14 24.38,36.14 24.51,36.01 24.51,35.89 24.38,35.76 24,35.76 23.48,35.24 22.55,35.24 22.33,35.46 22.33,35.89
+V5P0A_USB_AOU1 on BOTTOM: 15.95,40.66 15.95,39.7 16.36,39.29 17.83,39.29 18.24,38.88 23.67,38.88 23.82,39.04 23.82,40.05 23.67,40.21 23.67,41.02 23.52,41.17 16.46,41.17
+V5P0A_USB_AOU1 on ART03: 21.46,40.08 21.46,38.88 22.27,38.07 22.27,35.23 22.41,35.09 23.39,35.09 23.77,35.48 23.77,36.93 24.59,37.74 24.59,40.26 24.26,40.59 21.97,40.59
+V5P0SX on TOP: 175,12.86 175.77,12.1 175.77,11.39 175.53,11.15 174.39,11.15 174.04,10.8 174.04,9.84 175.05,8.83 184.32,8.83 188.56,13.07 188.56,14.82 187.3,16.08 187.3,17.19 187.35,17.25 188.52,17.25 188.79,16.99 188.79,16.43 189.84,15.37 189.84,12.21 184.81,7.19 173.48,7.19 172.35,8.32 172.35,14.22 172.55,14.42 174.88,14.42 175,14.3
+V5P0SX on BOTTOM: 20.11,45.49 22.05,45.49 22.1,45.54 22.1,47.06 21.84,47.32 19.91,47.32 19.56,46.96 19.56,45.69 19.61,45.64 19.96,45.64
+V5P0SX on BOTTOM: 27.63,60.63 25.25,60.63 25.07,60.45 25.07,59.43 25.25,59.26 27.94,59.26 28.07,59.38 28.07,60.2
+V5P0SX on PWR04: 80.36,2.56 79.37,3.56 36.5,3.56 36.47,3.6 34.8,3.6 34.79,3.6 31,3.6 30.19,4.41 30.19,8.2 25.82,12.57 23.37,12.57 22.84,13.09 22.84,15.48 21.88,16.45 19.49,16.45 17.88,18.06 17.88,59.74 18.32,60.18 28.01,60.18 28.11,60.07 28.11,57.65 22.25,51.79 22.25,23.43 33.74,11.93 40.59,11.93 41.4,11.12 42.83,11.12 44.51,9.44 49.29,9.44 50.13,8.6 55.5,8.6 56.82,9.92 87.71,9.92 89.5,8.12 176.15,8.12 176.67,7.6 176.67,5.14 175.51,3.99 155.4,3.99 155.39,4 135.65,4 134.21,2.56 ; 1 cut-out
+V5P0SX_AUD on TOP: 173.18,17.9 174.8,17.9 175.11,17.6 176.91,17.6 177.04,17.47 177.04,16.58 176.91,16.46 175,16.46 174.88,16.33 174.88,15.19 174.8,15.11 173.48,15.11 173.12,15.47 173.12,17.85
+V5P0SX_HDMI on BOTTOM: 23.98,60.12 22.59,60.12 22.28,60.42 18.95,60.42 18.49,60.88 16.97,60.88 15.8,62.05 12.75,62.05 12.49,61.8 12.49,60.7 12.8,60.4 13.21,60.4 16,57.6 18.61,57.6 19.99,58.98 23.75,58.98 24.08,59.31 24.08,60.02
+V5P0SX_KB_BL on TOP: 176.39,12.23 176.39,9.37 176.43,9.33 178.47,9.33 178.67,9.53 178.67,12.13 178.42,12.38 176.54,12.38
+V5P0SX_KB_BL on BOTTOM: 181.81,8.21 181.81,11.18 181.02,11.97 178.01,11.97 177.48,11.44 177.48,8.41 177.73,8.16 179.7,8.16 179.8,8.26 179.8,10.15 180.03,10.39 181.1,10.39 181.29,10.19 181.29,8.22 181.33,8.18 181.78,8.18
+VBAT on BOTTOM: 95.38,13.28 92.4,13.28 90.79,11.67 83.12,11.67 83.12,8.56 83.31,8.36 95.44,8.36 95.6,8.52 95.6,13.06 ; 1 cut-out
+VBAT_R on BOTTOM: 82,15.25 78.56,15.25 78.44,15.13 78.44,8.55 78.64,8.35 81.99,8.35 82.04,8.4 82.04,9.32 81.73,9.63 81.73,11.66 81.46,11.93 81.46,12.67 82.21,13.41 82.21,15.05
+VBATA_BKLT_IN on TOP: 17.08,73.3 15.85,73.3 15.63,73.07 15.63,70.34 15.71,70.25 18.09,70.25 18.21,70.37 18.21,72.16
+VBATA_BKLT_IN on BOTTOM: 15.87,75.8 15.96,75.89 17.75,75.89 17.91,75.73 17.91,72.1 17.83,72.02 15.99,72.02 15.87,72.14
+VBUS_TYPEC on TOP: 30.17,7.19 27.48,7.19 27.33,7.03 27.33,5.04 27.42,4.95 28.57,4.95 28.7,5.09 28.7,6.68 28.9,6.88 30.17,6.88 30.22,6.93 30.22,7.13
+VBUS_TYPEC on TOP: 20.27,12.36 20.22,12.42 18.16,12.42 18.03,12.55 18.03,13.18 18.44,13.59 18.44,13.94 18.24,14.15 17.68,14.15 17.3,14.53 9.55,14.53 9.14,14.93 9.14,16.08 9.27,16.2 14.5,16.2 14.98,16.69 17.47,16.69 17.96,16.2 19.48,16.2 20.11,15.57 20.11,13.84 20.58,13.38 20.58,12.84 20.65,12.77 20.65,12.77 20.75,12.67 20.98,12.67 21.03,12.62 21.03,12.42 20.98,12.36
+VBUS_TYPEC on PWR04: 6.86,21.51 6.86,21.31 6.55,21 6.55,17.14 7.06,16.63 7.11,16.63 8.89,14.86 8.89,6.65 11.28,4.26 14.44,4.26 16.59,2.11 28.86,2.11 29.18,2.43 29.18,6.69 29.12,6.75 22.22,6.75 21.74,7.24 17.14,7.24 15.39,8.98 15.39,16.43 13.25,18.57 13.25,22.8 12.91,23.14 9.02,23.14 7.86,21.98 7.33,21.98
+VBUS_TYPEC1_P1 on TOP: 41.84,25.69 41.84,27.87 42.14,28.17 48.47,28.17 50.91,25.74 50.91,21.34 49.83,20.27 47.89,20.27 47.8,20.35 47.8,24.23 47.48,24.56 45.7,24.56 44.9,23.76 44.9,22.61 44.42,22.13 44.42,17.87 42.7,16.16 40.88,16.16 40.59,15.87 40.59,13.84 41.65,12.78 41.65,3.63 41.1,3.08 38.75,3.08 37.18,4.65 37.18,12.52 36.8,12.91 36.8,18.7 40.86,22.76 40.86,24.72
+VBUS_TYPEC1_P1 on TOP: 18.59,62.91 18.77,62.73 21.72,62.73 21.78,62.8 21.78,64.09 21.28,64.59 21.28,67.22 21.23,67.27 16.77,67.27 16.66,67.16 16.66,63.01 16.76,62.91
+VBUS_TYPEC1_P1 on BOTTOM: 16.66,65.81 16.66,63.42 16.86,63.22 17.12,63.22 17.22,63.32 18.64,63.32 19.15,62.81 21.89,62.81 22.25,63.17 22.25,65.76 21.99,66.01 16.86,66.01
+VBUS_TYPEC1_P1 on BOTTOM: 50.97,24.49 51.56,23.9 51.56,21.28 51.55,21.27 50.98,21.27 50.81,21.1 50.81,20.53 50.55,20.27 47.89,20.27 47.8,20.35 47.8,24.46 47.83,24.49
+VBUS_TYPEC1_P1 on BOTTOM: 113.77,6.96 111.89,6.96 108.38,3.45 106.22,3.45 105.86,3.82 105.86,3.86 105.67,4.05 96.34,4.05 95.56,4.83 83.61,4.83 82.79,5.65 77.51,5.65 77.07,5.21 73.99,5.21 73.57,4.86 72.43,3.72 72.49,3.72 72.35,3.58 72.35,3.59 71.27,2.51 68.12,2.51 68.02,2.61 53.49,2.61 52.69,3.41 52.69,5.69 51.9,6.49 46.1,6.49 45.31,7.28 39.34,7.28 37.83,5.77 37.83,4.71 38.56,3.99 39.32,3.99 39.73,4.4 40.23,4.4 41.12,5.3 51.02,5.3 51.14,5.18 51.14,1.54 51.42,1.26 72.22,1.26 74.85,3.89 78.69,3.89 80.88,1.7 109.07,1.7 111.28,3.91 113.78,3.91 113.9,4.02 113.9,6.83
+VBUS_TYPEC1_P1 on ART05: 16.13,66.24 21.59,66.24 22.22,65.61 22.22,57.4 21.88,57.06 21.88,47.89 22.22,47.55 22.22,18.26 22.84,17.64 22.84,17.55 24.78,15.61 29.08,15.61 30.43,14.27 30.43,11.97 35,7.4 39.15,7.4 40,6.55 40,4.05 39.91,3.96 37.82,3.96 36.87,4.9 32.73,4.9 32.12,4.29 23.85,4.29 23.83,4.31 23.14,4.31 18.88,8.57 18.88,14.38 16.89,16.37 16.89,54.94 15.62,56.21 15.62,65.73
+VBUS_TYPEC1_P1 on ART06: 23.21,5.58 23.9,5.58 24.03,5.46 26.98,5.46 27.38,5.86 28.11,5.86 28.6,6.35 33.91,6.35 34.35,6.79 39.68,6.79 39.76,6.71 39.76,4.19 39.58,4.02 37.69,4.02 37.69,4.04 37.49,4.24 35.86,4.24 35.56,3.93 31.75,3.93 31.27,3.45 25.66,3.45 25.43,3.68 24.61,3.68 23.04,5.26 23.04,5.41
+VBUS_TYPEC_PP_HV on TOP: 28.95,6.68 31.21,6.68 31.49,6.96 33.41,6.96 33.43,6.98 33.62,6.98 33.88,7.24 33.88,8.56 34.29,8.96 35.47,8.96 35.51,8.92 35.51,5.62 35.43,5.53 31.51,5.53 31,5.03 29.72,5.03 28.83,5.92 28.83,6.55
+VCC0P9_SVR_TCP1_PHASE on TOP: 29.97,27 30.73,27 30.86,26.87 30.86,25.35 30.73,25.22 30.48,25.22 30.1,25.6 29.08,25.6 28.85,25.83 27.76,25.83 27.68,25.91 27.68,26.11 27.79,26.21 28.04,26.21 28.45,26.62 29.59,26.62
+VCC0V9_SVR_TCP1 on TOP: 31.75,25.22 33.83,25.22 34.34,25.73 34.34,26.64 34.9,27.2 34.9,27.96 34.72,28.14 30.99,28.14 30.86,28.01 30.86,27.25 31.11,27 31.49,27 31.62,26.87 31.62,25.35
+VCC0V9_SVR_TCP1 on BOTTOM: 31.24,28.14 33.27,28.14 33.4,28.01 33.4,25.91 32.71,25.22 31.38,25.22 31.11,25.48 31.11,28.01
+VCC0V9_SVR_TCP1 on ART03: 30.99,27.25 29.34,25.6 27.81,25.6 27.18,24.97 26.41,24.97 25.53,25.85 23.37,25.85 23.11,25.6 23.11,23.31 23.75,22.68 24.76,22.68 24.89,22.81 25.14,22.81 25.4,22.55 25.4,21.79 26.29,20.9 27.18,20.9 27.81,21.54 29.23,21.54 32.92,25.22 32.92,27.1 32.76,27.25
+VCC1P05_OUT_FET on TOP: 48.26,65.4 48.36,65.5 48.36,68.86 48.21,69.01 46.89,69.01 46.84,68.96 46.84,65.86 47.29,65.4
+VCC1P8A on TOP: 86.67,46.64 86.61,46.59 86.61,45.48 86.65,45.45 89.3,45.45 89.36,45.52 89.36,46.02 88.74,46.64
+VCC1P8A on BOTTOM: 37.95,65.2 37.95,64.23 38.1,64.08 38.96,64.08 39.06,64.18 39.06,64.49 38.91,64.64 38.76,64.64 38.71,64.69 38.71,65.3 38.66,65.35 38.1,65.35
+VCC1P8A on PWR04: 89.23,46.02 86.17,46.02 84.86,44.7 84.86,42.37 84.06,41.58 81.8,41.58 80.56,40.35 70.87,40.35 67.93,43.29 62.53,43.29 59.91,45.9 59.91,48.89 60.12,49.11 60.12,52.93 58.85,54.2 53.72,54.2 53.18,54.74 50.91,54.74 49.74,55.9 47.86,55.9 45.38,58.38 45.38,59.8 45.36,59.81 45.36,60.27 40.79,64.84 38.05,64.84 37.95,64.74 37.95,63.57 43.34,58.18 43.34,57.07 48.57,51.83 50.93,51.83 50.94,51.83 51.07,51.83 52.69,50.2 56.24,50.2 57.64,51.6 58.1,51.6 58.28,51.42 58.28,42.74 63,38.03 63.01,38.03 63.57,37.47 78.82,37.47 79.37,38.03 85.49,38.03 85.49,38.02 88.81,38.02 89.42,38.63 89.42,41.59 88.8,42.21 88.8,45.2 88.97,45.38 89.24,45.38 89.34,45.48 89.34,45.9
+VCC3P3_LDO_OUT on TOP: 161.9,23.86 161.23,23.86 161.15,23.78 160.67,23.78 160.64,23.74 160.64,23.45 160.79,23.3 160.81,23.3 161.53,22.58 161.8,22.58 161.95,22.73 161.95,23.81
+VCC3V3_SX_TCP1 on TOP: 27.68,28.14 29.72,28.14 30.1,28.52 30.53,28.52 30.65,28.4 30.65,27.29 30.61,27.25 29.84,27.25 29.46,26.87 27.18,26.87 26.64,26.34 26.64,25.99 26.59,25.93 26.05,25.93 25.99,25.99 25.99,26.23 26.29,26.53 26.29,27 26.8,27.51 27.43,27.51 27.56,27.63 27.56,28.01
+VCC3V3_SX_TCP1 on BOTTOM: 30.73,30.2 30.73,27.3 30.3,26.87 28.07,26.87 27.94,27 27.94,27.76 27.84,27.86 27.23,27.86 27.18,27.91 27.18,28.55 27.19,28.56 28,28.56 28.4,28.17 29.06,28.17 29.21,28.32 29.21,30.4 29.31,30.5 30.43,30.5
+VCCA_CLKLDO_1P8 on TOP: 62.79,46.56 65.15,46.56 65.4,46.81 65.4,48.84 65.24,49.01 63.74,49.01 63.65,49.1 61.29,49.1 61.21,49.02 61.21,48.13 61.21,48.13 61.36,47.98 61.67,47.98 61.82,48.13 61.82,48.28 61.97,48.44 63.14,48.44 63.29,48.28 63.29,47.67 62.7,47.08 62.7,46.64
+VCCFPGM on TOP: 101.23,57.69 101.38,57.54 106.31,57.54 106.42,57.65 106.42,58.69 106.36,58.75 101.69,58.75 101.23,58.29
+VCCFPGM on BOTTOM: 101.99,58.91 104.85,58.91 104.97,58.78 104.97,57.71 104.79,57.52 101.39,57.52 101.25,57.66 101.25,58.17
+VCCIN on TOP: outline of 102 points within 74.85,28.78 128.65,59.38 ; 1 cut-out
+VCCIN on BOTTOM: 116.66,41.93 113.66,44.93 113.66,49.37 112.56,50.48 110.33,50.48 109.88,50.93 109,50.93 108.51,50.44 107.83,50.44 106.99,49.6 104,49.6 103.53,49.13 103.53,48.08 103.03,47.58 100.82,47.58 100.72,47.68 100.72,48.83 101.01,49.12 102.75,49.12 103,49.37 103,51.51 102.81,51.69 100.75,51.69 100.38,52.06 100.38,55.13 101.63,56.38 105.57,56.38 106.42,57.22 107.63,57.22 107.76,57.1 107.76,56.44 107.96,56.24 116.17,56.24 116.81,55.61 124.97,55.61 125.44,55.13 125.44,49.64 125.45,49.63 125.45,48.64 126.09,48 126.09,42.66 128.65,40.1 128.65,28.91 128.52,28.78 127.04,28.78 126.58,28.32 126.58,23.3 126.34,23.06 120.36,23.06 119.61,23.8 119.61,28.26 119.08,28.79 116.93,28.79 116.66,29.06
+VCCIN on BOTTOM: 74.6,59.29 84.21,59.29 84.33,59.18 84.33,58.49 84.22,58.39 82.4,58.39 81.48,57.48 74.23,57.48 74.15,57.56 74.15,58.85
+VCCIN on BOTTOM: 78.11,46.22 78.29,46.22 78.48,46.41 78.85,46.41 78.95,46.31 79.21,46.31 79.36,46.46 79.66,46.46 79.84,46.28 80.09,46.28 80.22,46.41 80.65,46.41 80.78,46.28 80.96,46.28 81.14,46.1 81.14,45.98 81.24,45.88 81.47,45.88 81.54,45.95 81.54,46.05 81.64,46.16 81.97,46.16 82.56,45.57 82.86,45.57 83.04,45.75 83.37,45.75 83.55,45.57 83.83,45.57 84.01,45.75 85.2,45.75 85.35,45.6 85.58,45.6 85.78,45.8 85.99,45.8 86.56,46.37 86.56,47.63 86.4,47.79 78.37,47.79 78.24,47.67 78.24,46.78 77.99,46.52 77.99,46.35
+VCCIN on PWR04: 105.13,56.84 113.42,56.84 114,56.26 126.83,56.26 127.44,55.66 127.44,52.58 129.84,50.17 129.84,28.87 128.98,28.01 116.01,28.01 114.35,29.68 101.29,29.68 100.6,30.36 100.6,41.6 101.38,42.38 105.06,42.38 105.99,43.31 105.99,48.72 104.76,49.95 103.79,49.95 103.09,49.26 103.09,48.51 102.83,48.25 101.02,48.25 96.9,52.37 74.4,52.37 74.17,52.6 74.17,59.09 74.46,59.39 84.32,59.39 85.5,58.21 98.46,58.21 98.87,57.8 104.16,57.8
+VCCIN on ART05: 76.59,59.38 86.67,59.38 89.03,57.01 122.21,57.01 122.9,56.32 122.9,49.17 121.97,48.24 106.16,48.24 105.6,48.8 105.6,51.21 105.36,51.45 74.4,51.45 74.17,51.68 74.17,56.96
+VCCIN on ART06: 85.47,58.3 84.73,59.05 80.51,59.05 80.13,59.42 74.94,59.42 74.71,59.2 74.71,51.24 78.19,47.76 78.19,47.39 78.82,46.76 80.39,46.76 81.72,45.43 84.79,45.43 86.15,46.79 94.5,46.79 99.88,41.41 104.6,41.41 104.99,41.02 108.81,41.02 109.14,41.35 109.14,47.41 107.94,48.61 107.94,50.6 108.39,51.05 109.54,51.05 112.55,48.03 112.55,42 111.33,40.78 111.33,23.74 112.58,22.49 128.35,22.49 128.83,22.98 128.83,41.53 126.04,44.32 126.04,53.96 124.98,55.03 120.96,55.03 119.81,56.17 119.81,59.23 119.46,59.58 109.79,59.58 108.51,58.3
+VCCIN_AUX on TOP: 105.66,48.28 105.64,48.26 104.65,48.26 104.44,48.46 103.63,48.46 103.5,48.59 103.5,50.6 103.56,50.66 104.32,50.66 105.66,49.31 ; 4 cut-outs
+VCCIN_AUX on TOP: outline of 92 points within 68.48,29.63 100.06,49.5
+VCCIN_AUX on BOTTOM: 91.26,46.27 91.26,45.83 91.39,45.69 94.77,45.69 94.88,45.8 94.88,47.6 94.69,47.79 91.39,47.79 91.19,47.6 91.19,46.33
+VCCIN_AUX on BOTTOM: 103.7,47.67 105.23,47.67 105.67,48.11 105.67,48.87 105.66,48.88 105.66,49.2 105.33,49.53 104.06,49.53 103.66,49.13 103.66,47.72 103.7,47.67
+VCCIN_AUX on BOTTOM: 95.58,42.27 98.36,42.27 98.47,42.17 98.47,41.69 96.78,40 96.78,29.58 95.84,28.63 95.84,26.08 95.63,25.88 88.68,25.88 88.54,26.02 88.54,35.84 89.13,36.43 92.09,36.43 93.02,37.36 93.02,40.52 93.72,41.22 94.53,41.22
+VCCIN_AUX on BOTTOM: 70.49,46.33 77.42,46.33 77.86,46.78 77.86,47.72 77.77,47.82 70.95,47.82 70.95,47.82 69.88,47.82 69.8,47.73 69.8,47.03
+VCCIN_AUX on PWR04: 74.11,51.95 70.54,48.38 70.54,42.19 71.55,41.17 71.88,41.17 72.39,41.68 79.3,41.68 79.5,41.47 80.06,41.47 81.26,42.67 84.02,42.67 84.54,43.19 84.54,45.34 85.6,46.41 91.09,46.41 91.49,46.01 91.49,43.02 92.26,42.24 92.26,36.39 88.98,33.11 88.98,30.07 89.51,29.54 98.85,29.54 100.28,30.97 100.28,41.88 101.32,42.91 104.62,42.91 105.5,43.79 105.5,48.71 104.63,49.58 103.94,49.58 103.51,49.15 103.51,48.46 102.93,47.87 100.98,47.87 96.9,51.95
+VCCIN_AUX on ART05: 71.83,46.05 91.06,46.05 91.57,45.54 99.06,45.54 100.96,47.44 104.56,47.44 105.14,48.02 105.14,50.82 104.8,51.15 74.38,51.15 74.38,51.15 73.34,51.15 70.84,48.65 70.84,47.04
+VCCIN_AUX_VCC on BOTTOM: 75.29,25.66 74.23,25.66 74.12,25.56 74.12,24.86 74.12,24.77 73.76,24.41 73.56,24.41 73.51,24.36 73.51,22.73 73.61,22.63 74.42,22.63 75.39,23.59 75.39,24.13 75.69,24.43 75.69,25.26 75.67,25.28 75.37,25.28 75.29,25.36 75.29,25.66
+VCCIN_VIN on TOP: 123.65,11.68 122.76,10.79 116.66,10.79 116.58,10.87 116.58,15.22 116.9,15.53 123.61,15.53 123.65,15.49
+VCCIN_VIN on BOTTOM: 127.63,21.17 122.66,21.17 121.5,20 116.72,20 116.61,19.89 116.61,9.65 116.67,9.59 123.29,9.59 123.56,9.86 123.56,15.51 123.92,15.88 127.54,15.88 127.7,16.04 127.7,21.1
+VCCIO_OUT on TOP: 99.52,45.46 100.2,45.46 100.43,45.69 100.66,45.69 100.71,45.64 100.71,45.08 100.81,44.98 100.81,43.86 100.58,43.63 99.77,43.63 99.77,43.96 99.9,44.09 99.9,45.11 99.82,45.18 99.52,45.18
+VCCIO_OUT on ART03: 106.68,46.68 104.65,46.68 104.52,46.81 104.52,47.32 104.27,47.57 100.71,47.57 100.33,47.19 100.33,45.41 100.46,45.29 106.68,45.29 106.93,45.54 106.93,46.3 106.68,46.56
+VCCPRIM_1P8 on TOP: 63.55,52.55 63.73,52.36 63.73,50.35 63.59,50.21 62.67,50.21 62.57,50.11 62.57,49.9 62.68,49.79 62.68,49.35 62.63,49.3 62.63,49.3 61.06,49.3 60.93,49.43 60.93,50.63 61.22,50.91 61.58,50.91 61.74,51.08 61.74,51.13 62.02,51.42 62.21,51.42 62.36,51.57 62.36,52.43 62.48,52.55
+VCCPRIM_1P8 on ART03: 71.64,59.36 69.96,59.36 69.72,59.12 69.72,54.45 69.09,53.82 69.09,53.49 69.1,53.48 69.1,52.94 68.77,52.61 68.77,50.44 68.95,50.26 71,50.26 72.34,51.6 72.34,57.03 71.74,57.63 71.74,59.26
+VCCPRIM_1P8 on ART06: 70.57,52.83 68.77,52.83 66.89,50.95 61.93,50.95 61.43,50.44 61.43,49.95 61.53,49.85 67.44,49.85 67.79,49.5 70.5,49.5 70.71,49.71 70.71,52.69
+VCCSFR_OC on TOP: 80.83,60.02 80.83,61.93 80.66,62.09 80.66,62.56 80.53,62.68 80.01,62.68 79.58,62.69 79.27,62.38 79.27,62.13 79.09,61.95 79.09,61.35 79.4,61.04 79.41,61.04 79.5,60.95 79.5,60.95 79.63,60.82 79.63,60.27 80.01,59.89 80.64,59.89 80.77,60.02
+VCCSFR_OC on BOTTOM: 42.82,71.45 44.55,71.45 44.85,71.14 44.85,70.53 44.6,70.28 42.77,70.28 42.67,70.38 42.67,71.3
